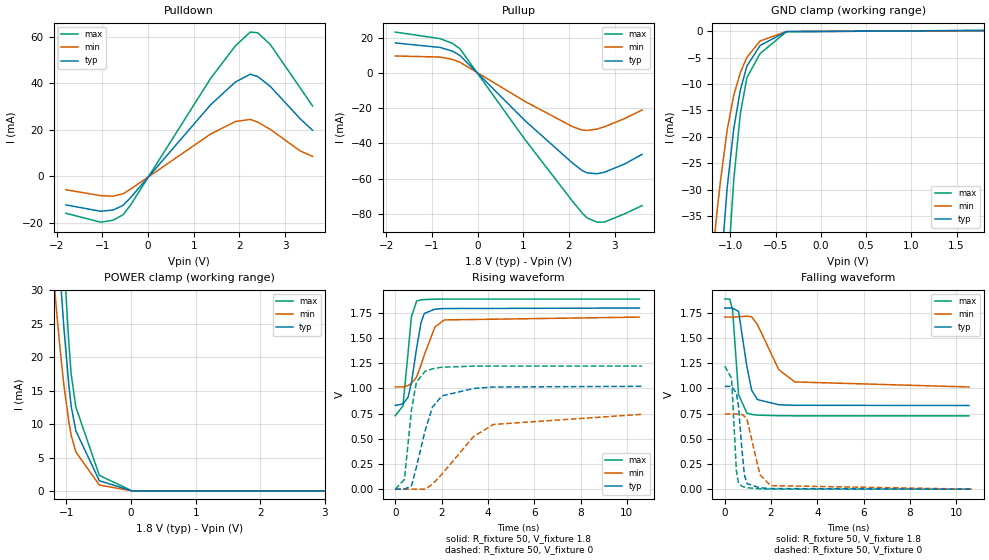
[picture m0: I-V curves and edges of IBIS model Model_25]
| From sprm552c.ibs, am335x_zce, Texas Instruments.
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| Model based on original model for BC1833DV50BPBFBP18LL_SSDHV
|   Sub model BC50B_V_PD_ON_5P_1P8
[model]   Model_25
|[Description]  [1.8V-I/O-PD-NORMAL, IND, 5%]
|   NORMAL,Weak internal pull-down,Industrial temperature range
|   (-40C to 125C, 25C nominal),5% power supply tolerance
|[Input Load]   PD
|[Output Drive] NORMAL
|Voltage   1.8V
|Mode   I/O
Model_type   I/O
Polarity   Non-Inverting
Enable   Active-Low
Vinl =  0.63
Vinh =  1.17
Cref =  15pF
Rref =  100.0000M
Vref =  0V
Vmeas =  0.9
C_comp   2.005358p   1.984241p   2.061175p
[Model Spec]
Vinl   0.63   0.5985   0.6615
Vinh   1.17   1.1115   1.2285
[Temperature Range]   25   125   -40
[Voltage Range]   1.8   1.71   1.89
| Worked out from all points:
|   slope of the pulldown table from 0 to 0.27 V, typ, clamps not added: 42.1 ohm
|   slope of the pullup table from 0 to 0.27 V, typ, clamps not added: 37.7 ohm
|   GND clamp passes 1 mA (typ) near -0.56 V on its own axis
|   POWER clamp passes 1 mA (typ) near -0.44 V on its own axis
|   rising waveform, R_fixture 50, V_fixture 1.8: 20-80 % time 395ps typ, 627ps min, 258ps max; typ from 0.832 V to 1.8 V
|   rising waveform, R_fixture 50, V_fixture 0: 20-80 % time 713ps typ, 1.77ns min, 337ps max; typ from 0 V to 1.02 V
|   falling waveform, R_fixture 50, V_fixture 1.8: 20-80 % time 386ps typ, 902ps min, 196ps max; typ from 1.8 V to 0.831 V
|   falling waveform, R_fixture 50, V_fixture 0: 20-80 % time 219ps typ, 405ps min, 146ps max; typ from 1.02 V to 0 V
[POWER_clamp]
-1.8V     154.2mA    109.7mA    213.5mA
-1.255V   57.34mA    38.41mA    81.27mA
-1.145V   39.68mA    26.05mA    56.64mA
-1.109V   34.21mA    22.34mA    48.88mA
-1.073V   28.97mA    18.84mA    41.38mA
-1.036V   23.97mA    15.54mA    34.15mA
-963.6mV  15.93mA    10.41mA    22.28mA
-927.3mV  12.7mA     8.361mA    17.51mA
-854.5mV  8.993mA    5.831mA    12.55mA
-490.9mV  1.518mA    881.5uA    2.323mA
18.18mV   0A         0A         0A
3.6V      0A         0A         0A
[Pulldown]
-1.8V     -12.34mA   -5.814mA   -15.95mA
-1.036V   -15.1mA    -8.371mA   -19.79mA
-763.6mV  -14.53mA   -8.588mA   -18.92mA
-545.5mV  -12.52mA   -7.542mA   -16.54mA
-381.8mV  -9.184mA   -5.536mA   -12.37mA
1.364V    30.65mA    18.1mA     41.95mA
1.909V    40.55mA    23.56mA    56.09mA
2.236V    43.94mA    24.46mA    62.06mA
2.4V      42.91mA    23.3mA     61.77mA
2.673V    38.72mA    20.2mA     56.76mA
3.327V    24.78mA    10.92mA    38.1mA
3.6V      19.79mA    8.54mA     30.25mA
[Pullup]
-1.8V     16.98mA    9.596mA    23.14mA
-818.2mV  14.42mA    8.972mA    19.42mA
-545.5mV  12.31mA    7.608mA    16.73mA
-381.8mV  9.817mA    6mA        13.58mA
1.036V    -27.01mA   -16.12mA   -37.74mA
2.073V    -50.99mA   -30.42mA   -72.57mA
2.291V    -55.4mA    -32.43mA   -79.49mA
2.4V      -56.69mA   -32.64mA   -82.28mA
2.618V    -57.2mA    -31.85mA   -84.68mA
2.782V    -56.31mA   -30.51mA   -84.57mA
3.218V    -51.71mA   -25.94mA   -79.96mA
3.6V      -46.22mA   -21.01mA   -75.3mA
[GND_clamp]
-1.8V     -258.3mA   -163.5mA   -409.7mA
-1.255V   -85.36mA   -52.4mA    -138.2mA
-1.218V   -74.87mA   -45.89mA   -121.3mA
-1.145V   -54.71mA   -33.55mA   -88.64mA
-1.109V   -45.65mA   -28.13mA   -73.71mA
-1.036V   -29.56mA   -18.62mA   -47.04mA
-963.6mV  -18.42mA   -12.15mA   -28.08mA
-890.9mV  -11.14mA   -7.842mA   -15.61mA
-818.2mV  -6.603mA   -4.95mA    -8.797mA
-672.7mV  -2.723mA   -1.864mA   -4.246mA
-381.8mV  -91.28uA   -77.78uA   -131.6uA
1.8V      101.9uA    59.08uA    150.8uA
[Ramp]
dV/dt_f 0.58661569/0.38804052n 0.42291055/0.91015207n 0.70087579/0.19761426n
dV/dt_r  0.6165227/0.71500223n 0.45171033/1.7983811n  0.7377871/0.33786098n
R_load = 50
[Rising Waveform]
R_fixture = 50
V_fixture = 1.8
V_fixture_min = 1.71
V_fixture_max = 1.89
0s        831.8mV    1.015V     729.1mV
329.1ps   845.7mV    1.015V     825.6mV
549.9ps   911.3mV    1.028V     1.35V
693.1ps   1.051V     1.049V     1.709V
918.4ps   1.397V     1.113V     1.867V
1.114ns   1.655V     1.233V     1.879V
1.252ns   1.744V     1.333V     1.882V
1.715ns   1.787V     1.611V     1.886V
2.116ns   1.793V     1.68V      1.887V
10.54ns   1.798V     1.708V     1.887V
[Rising Waveform]
R_fixture = 50
V_fixture = 0
V_fixture_min = 0
V_fixture_max = 0
0s        0V         0V         0V
393.3ps   0V         0V         96.87mV
700.1ps   34.49mV    0V         787.8mV
911.9ps   219.3mV    0V         1.064V
1.286ns   579.4mV    0V         1.17V
1.604ns   814mV      49.06mV    1.195V
2.013ns   926.1mV    149mV      1.211V
3.375ns   999.3mV    521.4mV    1.221V
4.229ns   1.014V     642.5mV    1.222V
10.65ns   1.021V     743mV      1.222V
[Falling Waveform]
R_fixture = 50
V_fixture = 1.8
V_fixture_min = 1.71
V_fixture_max = 1.89
0s        1.798V     1.709V     1.888V
215.8ps   1.798V     1.709V     1.888V
339.2ps   1.798V     1.709V     1.781V
597.2ps   1.765V     1.711V     939.9mV
955ps     1.219V     1.719V     756.3mV
1.159ns   984.5mV    1.712V     742.4mV
1.41ns    890mV      1.636V     735.5mV
2.332ns   838.2mV    1.187V     729.6mV
3.023ns   833.1mV    1.065V     728.5mV
10.54ns   830.9mV    1.015V     728.2mV
[Falling Waveform]
R_fixture = 50
V_fixture = 0
V_fixture_min = 0
V_fixture_max = 0
0s        1.021V     746.2mV    1.222V
296.1ps   1.021V     746.2mV    1.1V
502.9ps   954.9mV    746.2mV    183.6mV
592.6ps   825.1mV    746.2mV    62.68mV
743.2ps   391.4mV    740.8mV    29.14mV
848.4ps   140.6mV    724.6mV    20.23mV
964.9ps   54.51mV    689.3mV    14.64mV
1.518ns   13.33mV    144.2mV    2.753mV
1.984ns   6.194mV    35.12mV    0V
10.65ns   0V         0V         0V
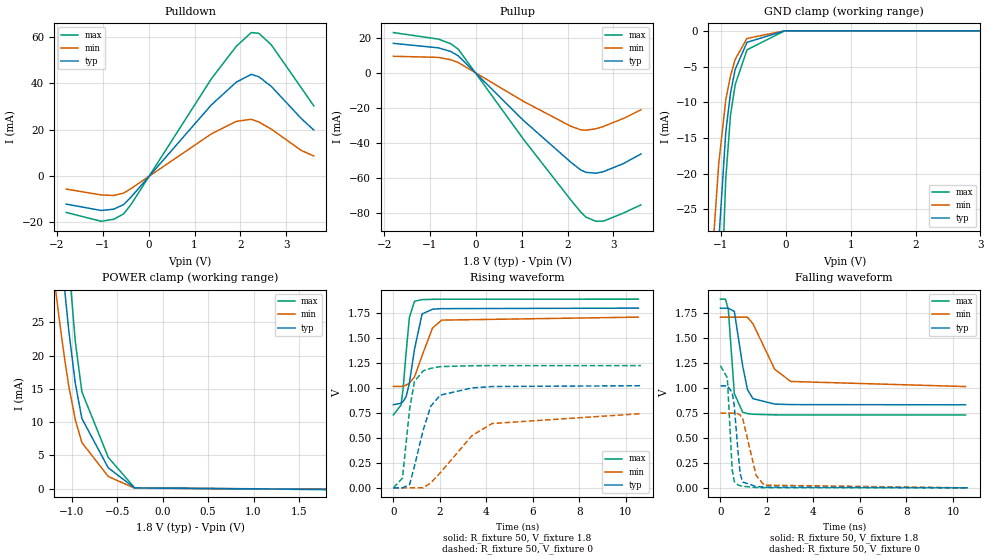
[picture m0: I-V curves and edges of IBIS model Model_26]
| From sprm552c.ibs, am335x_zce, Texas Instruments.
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| Model based on original model for BC1833DV50BPBFBP18LL_SSDHV
|   Sub model BC50B_V_PU_ON_5P_1P8
[model]   Model_26
|[Description]  [1.8V-I/O-PU-NORMAL, IND, 5%]
|   NORMAL,Weak internal pull-up,Industrial temperature range (-40C
|   to 125C, 25C nominal),5% power supply tolerance
|[Input Load]   PU
|[Output Drive] NORMAL
|Voltage   1.8V
|Mode   I/O
Model_type   I/O
Polarity   Non-Inverting
Enable   Active-Low
Vinl =  0.63
Vinh =  1.17
Cref =  15pF
Rref =  100.0000M
Vref =  0V
Vmeas =  0.9
C_comp   2.005358p   1.984241p   2.061175p
[Model Spec]
Vinl   0.63   0.5985   0.6615
Vinh   1.17   1.1115   1.2285
[Temperature Range]   25   125   -40
[Voltage Range]   1.8   1.71   1.89
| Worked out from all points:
|   slope of the pulldown table from 0 to 0.27 V, typ, clamps not added: 42.1 ohm
|   slope of the pullup table from 0 to 0.27 V, typ, clamps not added: 37.7 ohm
|   GND clamp passes 1 mA (typ) near -0.55 V on its own axis
|   POWER clamp passes 1 mA (typ) near -0.45 V on its own axis
|   rising waveform, R_fixture 50, V_fixture 1.8: 20-80 % time 395ps typ, 626ps min, 258ps max; typ from 0.834 V to 1.8 V
|   rising waveform, R_fixture 50, V_fixture 0: 20-80 % time 712ps typ, 1.77ns min, 336ps max; typ from 0.003 V to 1.02 V
|   falling waveform, R_fixture 50, V_fixture 1.8: 20-80 % time 386ps typ, 901ps min, 197ps max; typ from 1.8 V to 0.833 V
|   falling waveform, R_fixture 50, V_fixture 0: 20-80 % time 219ps typ, 395ps min, 146ps max; typ from 1.02 V to 0.002 V
[POWER_clamp]
-1.8V     154.2mA    109.7mA    213.4mA
-1.255V   57.27mA    38.37mA    81.14mA
-1.218V   51.28mA    34.14mA    72.81mA
-1.145V   39.6mA     26.02mA    56.5mA
-1.109V   34.13mA    22.3mA     48.74mA
-1.073V   28.89mA    18.8mA     41.24mA
-1.036V   23.89mA    15.5mA     34.01mA
-963.6mV  15.85mA    10.37mA    22.14mA
-890.9mV  10.56mA    6.932mA    14.57mA
-600mV    3.124mA    1.833mA    4.694mA
-309.1mV  105.7uA    71.68uA    124.2uA
1.8V      -99.94uA   -59.13uA   -145.1uA
[Pulldown]
-1.8V     -12.34mA   -5.814mA   -15.95mA
-1.036V   -15.1mA    -8.371mA   -19.79mA
-763.6mV  -14.53mA   -8.588mA   -18.92mA
-545.5mV  -12.52mA   -7.542mA   -16.54mA
-381.8mV  -9.184mA   -5.536mA   -12.37mA
1.364V    30.65mA    18.1mA     41.96mA
1.909V    40.55mA    23.56mA    56.09mA
2.236V    43.94mA    24.46mA    62.06mA
2.4V      42.91mA    23.3mA     61.77mA
2.673V    38.72mA    20.2mA     56.76mA
3.327V    24.78mA    10.92mA    38.1mA
3.6V      19.79mA    8.54mA     30.25mA
[Pullup]
-1.8V     16.98mA    9.596mA    23.14mA
-818.2mV  14.42mA    8.972mA    19.42mA
-545.5mV  12.31mA    7.608mA    16.73mA
-381.8mV  9.818mA    6mA        13.58mA
1.036V    -27.01mA   -16.12mA   -37.74mA
2.073V    -50.99mA   -30.42mA   -72.57mA
2.291V    -55.4mA    -32.43mA   -79.49mA
2.4V      -56.69mA   -32.64mA   -82.28mA
2.618V    -57.2mA    -31.85mA   -84.68mA
2.782V    -56.32mA   -30.51mA   -84.57mA
3.218V    -51.71mA   -25.94mA   -79.96mA
3.6V      -46.22mA   -21.01mA   -75.3mA
[GND_clamp]
-1.8V     -258.3mA   -163.5mA   -409.7mA
-1.255V   -85.38mA   -52.41mA   -138.2mA
-1.218V   -74.89mA   -45.91mA   -121.4mA
-1.145V   -54.74mA   -33.56mA   -88.68mA
-1.109V   -45.68mA   -28.15mA   -73.77mA
-1.036V   -29.6mA    -18.64mA   -47.12mA
-927.3mV  -14.18mA   -9.665mA   -20.7mA
-854.5mV  -8.721mA   -6.319mA   -11.82mA
-781.8mV  -5.401mA   -3.998mA   -7.533mA
-600mV    -1.607mA   -1.064mA   -2.664mA
-18.18mV  0A         0A         0A
3.6V      0A         0A         0A
[Ramp]
dV/dt_f 0.58648027/0.38861835n 0.42281124/0.91065008n 0.70069145/0.19805751n
dV/dt_r 0.61648384/0.71429874n 0.45165558/1.7976721n 0.73771723/0.33721891n
R_load = 50
[Rising Waveform]
R_fixture = 50
V_fixture = 1.8
V_fixture_min = 1.71
V_fixture_max = 1.89
0s        834.2mV    1.017V     732.2mV
329.1ps   848.3mV    1.017V     829.1mV
413ps     863.8mV    1.018V     977.4mV
548.7ps   913.6mV    1.03V      1.351V
689.9ps   1.05V      1.05V      1.707V
910.9ps   1.389V     1.112V     1.869V
1.237ns   1.742V     1.325V     1.885V
1.685ns   1.789V     1.601V     1.888V
2.079ns   1.795V     1.68V      1.889V
10.54ns   1.8V       1.71V      1.89V
[Rising Waveform]
R_fixture = 50
V_fixture = 0
V_fixture_min = 0
V_fixture_max = 0
0s        2.767mV    2.62mV     3.366mV
393.3ps   2.767mV    2.62mV     100.2mV
699.8ps   37.11mV    2.62mV     791.6mV
907.8ps   218.6mV    2.62mV     1.065V
1.281ns   578.4mV    2.662mV    1.173V
1.61ns    820mV      52.76mV    1.198V
2.021ns   930.1mV    153.8mV    1.215V
3.39ns    1.002V     526.9mV    1.224V
4.245ns   1.016V     645.7mV    1.225V
10.65ns   1.024V     744.6mV    1.225V
[Falling Waveform]
R_fixture = 50
V_fixture = 1.8
V_fixture_min = 1.71
V_fixture_max = 1.89
0s        1.8V       1.71V      1.891V
215.8ps   1.8V       1.71V      1.891V
339.2ps   1.8V       1.71V      1.784V
596.9ps   1.768V     1.71V      945mV
954.3ps   1.224V     1.71V      759.5mV
1.16ns    986.7mV    1.71V      745.4mV
1.398ns   894.9mV    1.645V     738.7mV
2.33ns    840.7mV    1.19V      732.7mV
3.019ns   835.5mV    1.067V     731.6mV
10.54ns   833.3mV    1.016V     731.3mV
[Falling Waveform]
R_fixture = 50
V_fixture = 0
V_fixture_min = 0
V_fixture_max = 0
0s        1.023V     749.7mV    1.224V
296.1ps   1.023V     749.7mV    1.103V
503.8ps   956.7mV    749.7mV    184.4mV
593.4ps   826.1mV    749.7mV    65.49mV
745ps     389.8mV    745.1mV    31.92mV
848.9ps   143mV      729.1mV    23.11mV
954.2ps   60.62mV    698.3mV    17.93mV
1.533ns   15.32mV    127.9mV    5.479mV
1.876ns   10.03mV    29.18mV    3.788mV
10.65ns   2.268mV    2.044mV    2.885mV
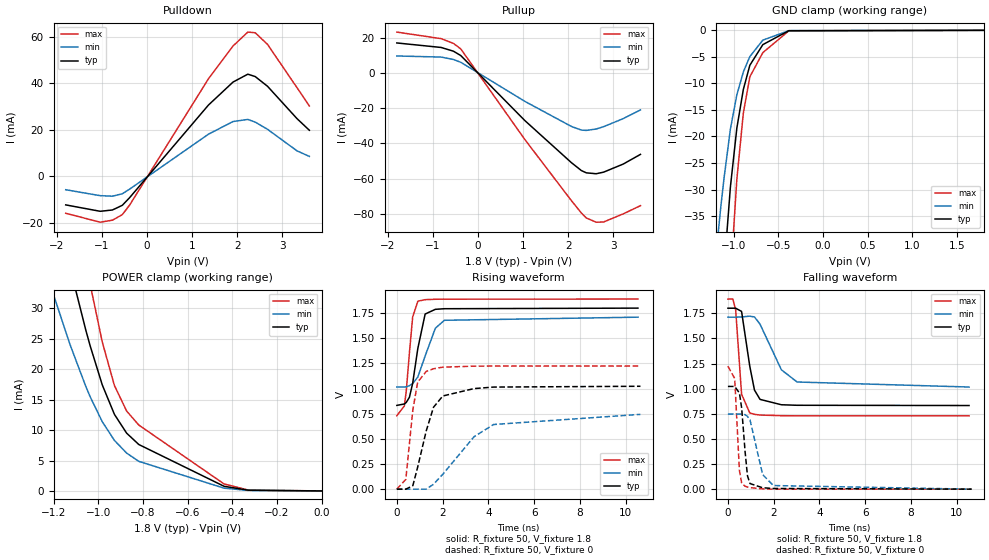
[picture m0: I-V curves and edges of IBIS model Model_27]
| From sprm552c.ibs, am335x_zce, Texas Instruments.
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| Model based on original model for BC1833DV50BPBFBP18LL_SSDHV
|   Sub model BC50B_V_PUPDOFF_5P_1P8
[model]   Model_27
|[Description]  [1.8V-I/O-PI-NORMAL, IND, 5%]
|   NORMAL,Weak pull up/down disabled,Industrial temperature range
|   (-40C to 125C, 25C nominal),5% power supply tolerance
|[Input Load]   PI
|[Output Drive] NORMAL
|Voltage   1.8V
|Mode   I/O
Model_type   I/O
Polarity   Non-Inverting
Enable   Active-Low
Vinl =  0.63
Vinh =  1.17
Cref =  15pF
Rref =  100.0000M
Vref =  0V
Vmeas =  0.9
C_comp   2.005358p   1.984241p   2.061175p
[Model Spec]
Vinl   0.63   0.5985   0.6615
Vinh   1.17   1.1115   1.2285
[Temperature Range]   25   125   -40
[Voltage Range]   1.8   1.71   1.89
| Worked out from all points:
|   slope of the pulldown table from 0 to 0.27 V, typ, clamps not added: 42.1 ohm
|   slope of the pullup table from 0 to 0.27 V, typ, clamps not added: 37.7 ohm
|   GND clamp passes 1 mA (typ) near -0.56 V on its own axis
|   POWER clamp passes 1 mA (typ) near -0.46 V on its own axis
|   rising waveform, R_fixture 50, V_fixture 1.8: 20-80 % time 396ps typ, 627ps min, 258ps max; typ from 0.833 V to 1.8 V
|   rising waveform, R_fixture 50, V_fixture 0: 20-80 % time 714ps typ, 1.77ns min, 337ps max; typ from 0 V to 1.02 V
|   falling waveform, R_fixture 50, V_fixture 1.8: 20-80 % time 387ps typ, 903ps min, 197ps max; typ from 1.8 V to 0.832 V
|   falling waveform, R_fixture 50, V_fixture 0: 20-80 % time 219ps typ, 406ps min, 146ps max; typ from 1.02 V to 0 V
[POWER_clamp]
-1.8V     154.2mA    109.6mA    213.3mA
-1.236V   54.24mA    36.24mA    76.93mA
-1.127V   36.83mA    24.14mA    52.57mA
-1.055V   26.36mA    17.13mA    37.58mA
-1.036V   23.85mA    15.48mA    33.96mA
-981.8mV  17.43mA    11.38mA    24.48mA
-927.3mV  12.58mA    8.299mA    17.32mA
-872.7mV  9.497mA    6.221mA    13.13mA
-818.2mV  7.629mA    4.86mA     10.83mA
-436.4mV  761.6uA    453.7uA    1.147mA
-327.3mV  115.1uA    79.02uA    133.5uA
0V        19.19nA    133nA      229.6nA
[Pulldown]
-1.8V     -12.34mA   -5.814mA   -15.95mA
-1.036V   -15.1mA    -8.371mA   -19.79mA
-763.6mV  -14.53mA   -8.588mA   -18.92mA
-545.5mV  -12.52mA   -7.542mA   -16.54mA
-381.8mV  -9.184mA   -5.536mA   -12.37mA
1.364V    30.65mA    18.1mA     41.96mA
1.909V    40.55mA    23.56mA    56.09mA
2.236V    43.94mA    24.46mA    62.06mA
2.4V      42.91mA    23.3mA     61.77mA
2.673V    38.72mA    20.2mA     56.76mA
3.327V    24.78mA    10.92mA    38.1mA
3.6V      19.79mA    8.54mA     30.25mA
[Pullup]
-1.8V     16.98mA    9.596mA    23.14mA
-818.2mV  14.42mA    8.972mA    19.42mA
-545.5mV  12.31mA    7.608mA    16.73mA
-381.8mV  9.818mA    6mA        13.58mA
1.036V    -27.01mA   -16.12mA   -37.74mA
2.073V    -50.99mA   -30.42mA   -72.58mA
2.291V    -55.4mA    -32.43mA   -79.49mA
2.4V      -56.69mA   -32.63mA   -82.28mA
2.618V    -57.2mA    -31.85mA   -84.68mA
2.782V    -56.31mA   -30.51mA   -84.57mA
3.218V    -51.71mA   -25.94mA   -79.96mA
3.6V      -46.22mA   -21.01mA   -75.3mA
[GND_clamp]
-1.8V     -258.3mA   -163.5mA   -409.7mA
-1.255V   -85.35mA   -52.4mA    -138.2mA
-1.218V   -74.87mA   -45.89mA   -121.3mA
-1.145V   -54.71mA   -33.55mA   -88.63mA
-1.109V   -45.64mA   -28.13mA   -73.71mA
-1.036V   -29.55mA   -18.62mA   -47.03mA
-963.6mV  -18.42mA   -12.14mA   -28.07mA
-890.9mV  -11.13mA   -7.836mA   -15.58mA
-818.2mV  -6.581mA   -4.941mA   -8.76mA
-672.7mV  -2.695mA   -1.849mA   -4.206mA
-381.8mV  -68.52uA   -64.5uA    -99.4uA
1.8V      19.19nA    313.7nA    215.2nA
[Ramp]
dV/dt_f 0.58726163/0.38922827n 0.42325164/0.9115308n 0.70180492/0.19847768n
dV/dt_r 0.61731887/0.71592513n 0.45216623/1.8000264n 0.73890303/0.3384294n
R_load = 50
[Rising Waveform]
R_fixture = 50
V_fixture = 1.8
V_fixture_min = 1.71
V_fixture_max = 1.89
0s        832.9mV    1.016V     730.4mV
329.1ps   846.9mV    1.016V     827mV
413ps     862.4mV    1.017V     975mV
550.6ps   913.1mV    1.029V     1.354V
693.3ps   1.053V     1.05V      1.712V
918.4ps   1.399V     1.115V     1.869V
1.238ns   1.741V     1.324V     1.884V
1.685ns   1.788V     1.6V       1.888V
2.079ns   1.794V     1.679V     1.889V
10.54ns   1.8V       1.71V      1.89V
[Rising Waveform]
R_fixture = 50
V_fixture = 0
V_fixture_min = 0
V_fixture_max = 0
0s        0V         0V         0V
393.3ps   0V         0V         96.88mV
700.1ps   34.49mV    0V         788.2mV
911.7ps   219.2mV    0V         1.064V
1.285ns   578.6mV    0V         1.171V
1.604ns   814.4mV    49mV       1.197V
2.011ns   926.6mV    148.6mV    1.213V
3.375ns   1V         521.6mV    1.223V
4.229ns   1.015V     642.9mV    1.224V
10.65ns   1.023V     743.7mV    1.224V
[Falling Waveform]
R_fixture = 50
V_fixture = 1.8
V_fixture_min = 1.71
V_fixture_max = 1.89
0s        1.8V       1.711V     1.891V
215.8ps   1.8V       1.711V     1.891V
339.2ps   1.8V       1.711V     1.784V
596.9ps   1.768V     1.713V     944.6mV
954.3ps   1.224V     1.721V     758.5mV
1.16ns    986.3mV    1.713V     744.2mV
1.404ns   893.1mV    1.641V     737.2mV
2.335ns   839.7mV    1.188V     730.9mV
3.023ns   834.5mV    1.066V     729.7mV
10.54ns   832mV      1.016V     729.5mV
[Falling Waveform]
R_fixture = 50
V_fixture = 0
V_fixture_min = 0
V_fixture_max = 0
0s        1.022V     747mV      1.223V
296.1ps   1.022V     747mV      1.102V
502.9ps   956.3mV    747mV      185.6mV
601.3ps   806.3mV    747mV      60.63mV
748.2ps   378.9mV    741.1mV    29.71mV
854.1ps   133.7mV    724.2mV    20.81mV
964.5ps   55.81mV    690.3mV    15.42mV
1.518ns   13.98mV    145.4mV    3.052mV
1.983ns   6.703mV    36.01mV    0V
10.65ns   0V         0V         0V
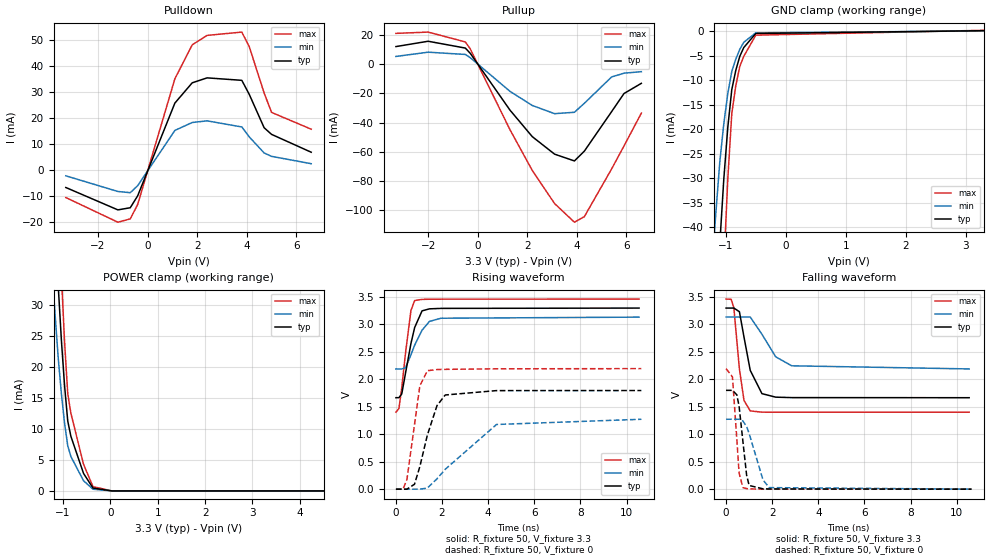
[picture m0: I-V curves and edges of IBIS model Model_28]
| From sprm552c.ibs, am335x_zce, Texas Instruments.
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| Model based on original model for BC1833DV50BPBFBP18LL_SSDHV
|   Sub model BC50B_V_PD_ON_5P_3P3
[model]   Model_28
|[Description]  [3.3V-I/O-PD-NORMAL, IND, 5%]
|   NORMAL,Weak internal pull-down,Industrial temperature range
|   (-40C to 125C, 25C nominal),5% power supply tolerance
|[Input Load]   PD
|[Output Drive] NORMAL
|Voltage   3.3V
|Mode   I/O
Model_type   I/O
Polarity   Non-Inverting
Enable   Active-Low
Vinl =  0.8V
Vinh =  2V
Cref =  15pF
Rref =  100.0000M
Vref =  0V
Vmeas =  1.65
C_comp   1.841028p   1.649962p   1.857641p
[Model Spec]
Vinl   0.8V   0.8V   0.8V
Vinh   2V   2V   2V
[Temperature Range]   25   125   -40
[Voltage Range]   3.3   3.135   3.465
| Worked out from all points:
|   slope of the pulldown table from 0 to 0.495 V, typ, clamps not added: 41.2 ohm
|   slope of the pullup table from 0 to 0.495 V, typ, clamps not added: 40 ohm
|   GND clamp passes 1 mA (typ) near -0.55 V on its own axis
|   POWER clamp passes 1 mA (typ) near -0.44 V on its own axis
|   rising waveform, R_fixture 50, V_fixture 3.3: 20-80 % time 461ps typ, 618ps min, 342ps max; typ from 1.67 V to 3.3 V
|   rising waveform, R_fixture 50, V_fixture 0: 20-80 % time 691ps typ, 1.76ns min, 392ps max; typ from 0 V to 1.8 V
|   falling waveform, R_fixture 50, V_fixture 3.3: 20-80 % time 462ps typ, 810ps min, 276ps max; typ from 3.3 V to 1.67 V
|   falling waveform, R_fixture 50, V_fixture 0: 20-80 % time 273ps typ, 532ps min, 196ps max; typ from 1.8 V to 0 V
[POWER_clamp]
-3.3V     437.1mA    430.8mA    590.9mA
-1.233V   54mA       35.95mA    76.74mA
-1.167V   43.32mA    28.48mA    61.85mA
-1.1V     33.01mA    21.39mA    47.35mA
-1.033V   24.22mA    15.63mA    34.6mA
-966.7mV  16.98mA    10.93mA    24.05mA
-900mV    11.29mA    7.299mA    15.71mA
-833.3mV  8.816mA    5.551mA    12.53mA
-566.7mV  2.833mA    1.651mA    4.306mA
-366.7mV  458.2uA    275.4uA    687.8uA
33.33mV   0A         0A         0A
6.6V      0A         0A         0A
[Pulldown]
-3.3V     -6.622mA   -2.126mA   -10.49mA
-1.2V     -15.24mA   -8.16mA    -19.98mA
-700mV    -14.42mA   -8.625mA   -18.71mA
-400mV    -9.821mA   -5.925mA   -13.15mA
1.1V      25.87mA    15.35mA    35.22mA
1.8V      33.67mA    18.39mA    48.29mA
2.4V      35.57mA    19.03mA    51.92mA
3.8V      34.62mA    16.67mA    53.19mA
4.1V      29.22mA    12.85mA    47.57mA
4.7V      16.38mA    6.671mA    29.75mA
5V        13.82mA    5.359mA    22.28mA
6.6V      6.944mA    2.531mA    15.81mA
[Pullup]
-3.3V     12.22mA    5.435mA    21.29mA
-2V       15.88mA    8.364mA    22.18mA
-500mV    11.19mA    6.809mA    15.42mA
-300mV    7.546mA    4.55mA     10.58mA
1.3V      -31.44mA   -18.55mA   -44.91mA
2.2V      -49.69mA   -28.25mA   -72.91mA
3.1V      -61.73mA   -33.9mA    -95.7mA
3.9V      -66.39mA   -32.95mA   -108.5mA
4.3V      -59.67mA   -26.77mA   -104.7mA
5.4V      -32.51mA   -8.662mA   -71.91mA
5.9V      -20.05mA   -6.072mA   -56.09mA
6.6V      -13.04mA   -5.016mA   -33.52mA
[GND_clamp]
-3.3V     -759.3mA   -612.7mA   -1.187A
-1.233V   -79.58mA   -48.75mA   -128.9mA
-1.167V   -61.06mA   -37.35mA   -98.95mA
-1.1V     -43.51mA   -26.72mA   -70.29mA
-1.033V   -30.2mA    -18.91mA   -48.08mA
-966.7mV  -19.68mA   -12.74mA   -30.27mA
-900mV    -11.93mA   -8.219mA   -16.86mA
-833.3mV  -8mA       -5.694mA   -11.13mA
-766.7mV  -5.133mA   -3.707mA   -7.22mA
-700mV    -3.33mA    -2.257mA   -5.131mA
-500mV    -463.9uA   -330.7uA   -807.4uA
3.3V      108.6uA    60.34uA    188uA
[Ramp]
dV/dt_f  0.9827697/0.46300896n  0.5700889/0.81423835n  1.2394706/0.2764349n
dV/dt_r  1.0808784/0.69221329n 0.76688601/1.7669954n  1.3212386/0.3933506n
R_load = 50
[Rising Waveform]
R_fixture = 50
V_fixture = 3.3
V_fixture_min = 3.135
V_fixture_max = 3.465
0s        1.666V     2.189V     1.402V
131.1ps   1.666V     2.189V     1.471V
252.3ps   1.733V     2.189V     1.845V
418.6ps   2.119V     2.213V     2.489V
652.8ps   2.656V     2.45V      3.258V
812.1ps   2.944V     2.622V     3.436V
1.132ns   3.247V     2.895V     3.456V
1.454ns   3.284V     3.055V     3.459V
1.95ns    3.292V     3.113V     3.46V
10.54ns   3.298V     3.133V     3.462V
[Rising Waveform]
R_fixture = 50
V_fixture = 0
V_fixture_min = 0
V_fixture_max = 0
0s        0V         0V         0V
306.4ps   0V         0V         0V
475.9ps   0V         0V         174.6mV
805.5ps   89.41mV    0V         1.174V
1.036ns   409.6mV    0V         1.88V
1.362ns   983.7mV    19.95mV    2.157V
1.781ns   1.522V     188.9mV    2.179V
2.137ns   1.715V     362mV      2.182V
4.361ns   1.795V     1.178V     2.192V
10.64ns   1.796V     1.273V     2.195V
[Falling Waveform]
R_fixture = 50
V_fixture = 3.3
V_fixture_min = 3.135
V_fixture_max = 3.465
0s        3.297V     3.134V     3.461V
221.2ps   3.297V     3.134V     3.457V
337.9ps   3.297V     3.134V     3.303V
579.4ps   3.231V     3.134V     2.19V
777.3ps   2.771V     3.134V     1.617V
1.049ns   2.163V     3.134V     1.425V
1.556ns   1.739V     2.82V      1.402V
2.154ns   1.675V     2.409V     1.401V
2.847ns   1.667V     2.246V     1.401V
10.54ns   1.665V     2.189V     1.401V
[Falling Waveform]
R_fixture = 50
V_fixture = 0
V_fixture_min = 0
V_fixture_max = 0
0s        1.799V     1.273V     2.195V
278ps     1.799V     1.273V     2.043V
467ps     1.718V     1.273V     910mV
565.7ps   1.51V      1.273V     291.3mV
733.4ps   858.8mV    1.239V     27.32mV
892ps     253.5mV    1.141V     9.691mV
1.001ns   67.36mV    1.014V     5.057mV
1.601ns   6.327mV    168.9mV    0V
1.871ns   4.231mV    28.19mV    0V
10.64ns   0V         0V         0V
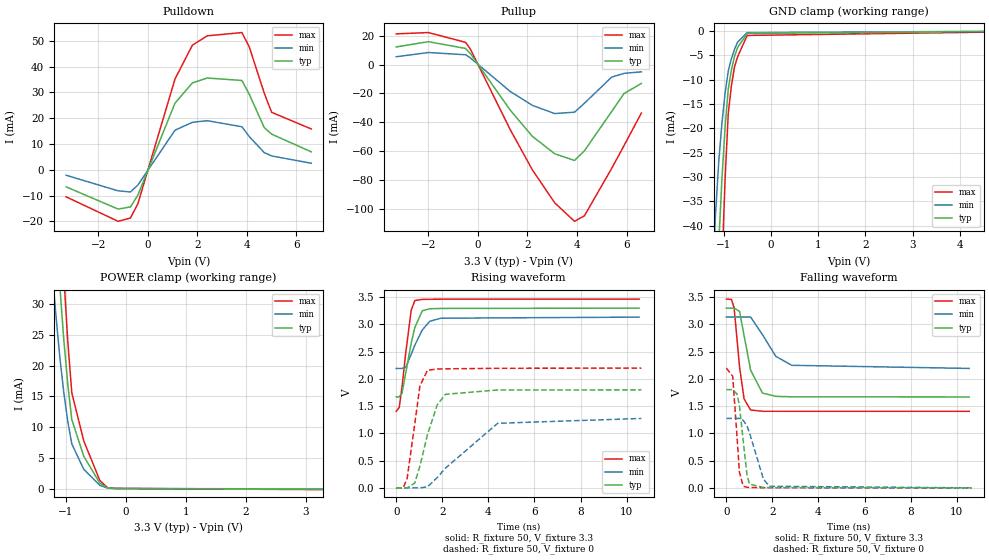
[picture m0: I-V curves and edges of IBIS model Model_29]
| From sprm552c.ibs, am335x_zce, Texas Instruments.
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| Model based on original model for BC1833DV50BPBFBP18LL_SSDHV
|   Sub model BC50B_V_PU_ON_5P_3P3
[model]   Model_29
|[Description]  [3.3V-I/O-PU-NORMAL, IND, 5%]
|   NORMAL,Weak internal pull-up,Industrial temperature range (-40C
|   to 125C, 25C nominal),5% power supply tolerance
|[Input Load]   PU
|[Output Drive] NORMAL
|Voltage   3.3V
|Mode   I/O
Model_type   I/O
Polarity   Non-Inverting
Enable   Active-Low
Vinl =  0.8V
Vinh =  2V
Cref =  15pF
Rref =  100.0000M
Vref =  0V
Vmeas =  1.65
C_comp   1.841028p   1.649962p   1.857641p
[Model Spec]
Vinl   0.8V   0.8V   0.8V
Vinh   2V   2V   2V
[Temperature Range]   25   125   -40
[Voltage Range]   3.3   3.135   3.465
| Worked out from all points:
|   slope of the pulldown table from 0 to 0.495 V, typ, clamps not added: 41.2 ohm
|   slope of the pullup table from 0 to 0.495 V, typ, clamps not added: 40 ohm
|   GND clamp passes 1 mA (typ) near -0.54 V on its own axis
|   POWER clamp passes 1 mA (typ) near -0.44 V on its own axis
|   rising waveform, R_fixture 50, V_fixture 3.3: 20-80 % time 460ps typ, 616ps min, 341ps max; typ from 1.67 V to 3.3 V
|   rising waveform, R_fixture 50, V_fixture 0: 20-80 % time 690ps typ, 1.76ns min, 392ps max; typ from 0.003 V to 1.8 V
|   falling waveform, R_fixture 50, V_fixture 3.3: 20-80 % time 463ps typ, 809ps min, 277ps max; typ from 3.3 V to 1.67 V
|   falling waveform, R_fixture 50, V_fixture 0: 20-80 % time 273ps typ, 533ps min, 196ps max; typ from 1.8 V to 0.002 V
[POWER_clamp]
-3.3V     437.1mA    430.8mA    590.9mA
-1.233V   53.96mA    35.93mA    76.64mA
-1.167V   43.27mA    28.46mA    61.75mA
-1.1V     32.96mA    21.36mA    47.25mA
-1.033V   24.17mA    15.61mA    34.49mA
-966.7mV  16.93mA    10.91mA    23.94mA
-900mV    11.23mA    7.269mA    15.59mA
-700mV    5.251mA    3.127mA    7.757mA
-433.3mV  893.2uA    531.5uA    1.34mA
-300mV    89.78uA    61.22uA    102uA
-166.7mV  17.36uA    10.91uA    23.37uA
3.3V      -100.3uA   -54.59uA   -173.1uA
[Pulldown]
-3.3V     -6.622mA   -2.126mA   -10.49mA
-1.2V     -15.24mA   -8.16mA    -19.98mA
-700mV    -14.42mA   -8.625mA   -18.71mA
-400mV    -9.821mA   -5.925mA   -13.15mA
1.1V      25.87mA    15.35mA    35.22mA
1.8V      33.67mA    18.39mA    48.29mA
2.4V      35.57mA    19.03mA    51.92mA
3.8V      34.62mA    16.67mA    53.19mA
4.1V      29.22mA    12.85mA    47.57mA
4.7V      16.38mA    6.671mA    29.75mA
5V        13.82mA    5.359mA    22.28mA
6.6V      6.944mA    2.531mA    15.81mA
[Pullup]
-3.3V     12.22mA    5.435mA    21.29mA
-2V       15.88mA    8.364mA    22.18mA
-500mV    11.19mA    6.809mA    15.42mA
-300mV    7.546mA    4.55mA     10.58mA
1.3V      -31.44mA   -18.55mA   -44.91mA
2.2V      -49.69mA   -28.25mA   -72.91mA
3.1V      -61.73mA   -33.9mA    -95.7mA
3.9V      -66.39mA   -32.95mA   -108.5mA
4.3V      -59.67mA   -26.77mA   -104.7mA
5.4V      -32.51mA   -8.662mA   -71.91mA
5.9V      -20.05mA   -6.072mA   -56.09mA
6.6V      -13.04mA   -5.016mA   -33.52mA
[GND_clamp]
-3.3V     -759.3mA   -612.7mA   -1.187A
-1.233V   -79.59mA   -48.75mA   -128.9mA
-1.167V   -61.07mA   -37.36mA   -98.97mA
-1.1V     -43.52mA   -26.73mA   -70.32mA
-1.033V   -30.22mA   -18.91mA   -48.13mA
-966.7mV  -19.71mA   -12.75mA   -30.35mA
-900mV    -11.97mA   -8.233mA   -16.96mA
-833.3mV  -8.054mA   -5.715mA   -11.24mA
-766.7mV  -5.195mA   -3.734mA   -7.343mA
-700mV    -3.396mA   -2.289mA   -5.259mA
-500mV    -540.4uA   -369.3uA   -948.8uA
6.6V      0A         0A         0A
[Ramp]
dV/dt_f 0.98117427/0.46331286n 0.56886158/0.8127625n  1.2383379/0.27717956n
dV/dt_r  1.0815937/0.69195258n 0.76748483/1.7675069n  1.3217618/0.39318679n
R_load = 50
[Rising Waveform]
R_fixture = 50
V_fixture = 3.3
V_fixture_min = 3.135
V_fixture_max = 3.465
0s        1.671V     2.193V     1.407V
131.1ps   1.671V     2.193V     1.477V
252.3ps   1.739V     2.193V     1.853V
418.1ps   2.124V     2.217V     2.495V
650.7ps   2.658V     2.452V     3.26V
808.3ps   2.945V     2.621V     3.44V
1.128ns   3.25V      2.896V     3.46V
1.453ns   3.288V     3.058V     3.462V
1.938ns   3.294V     3.115V     3.464V
10.54ns   3.3V       3.135V     3.465V
[Rising Waveform]
R_fixture = 50
V_fixture = 0
V_fixture_min = 0
V_fixture_max = 0
0s        2.898mV    2.506mV    3.526mV
306.4ps   2.898mV    2.506mV    3.526mV
475.9ps   2.898mV    2.506mV    178.2mV
801.2ps   88.78mV    2.506mV    1.164V
1.031ns   404.8mV    2.506mV    1.875V
1.354ns   975mV      20.34mV    2.159V
1.782ns   1.527V     191.6mV    2.183V
2.138ns   1.719V     364.8mV    2.186V
4.404ns   1.798V     1.187V     2.196V
10.64ns   1.8V       1.276V     2.2V
[Falling Waveform]
R_fixture = 50
V_fixture = 3.3
V_fixture_min = 3.135
V_fixture_max = 3.465
0s        3.299V     3.136V     3.464V
221.2ps   3.299V     3.136V     3.46V
337.8ps   3.299V     3.136V     3.306V
575ps     3.238V     3.136V     2.215V
771ps     2.793V     3.136V     1.634V
1.053ns   2.162V     3.136V     1.43V
1.568ns   1.741V     2.812V     1.407V
2.149ns   1.68V      2.414V     1.407V
2.84ns    1.672V     2.25V      1.406V
10.54ns   1.67V      2.193V     1.406V
[Falling Waveform]
R_fixture = 50
V_fixture = 0
V_fixture_min = 0
V_fixture_max = 0
0s        1.803V     1.276V     2.199V
278.1ps   1.803V     1.276V     2.048V
465ps     1.724V     1.276V     930.1mV
567.7ps   1.508V     1.276V     288mV
733.9ps   861.6mV    1.241V     31.65mV
893.3ps   254.4mV    1.143V     13.82mV
1.002ns   70.56mV    1.017V     9.121mV
1.605ns   9.234mV    167.8mV    3.92mV
1.865ns   7.106mV    31.25mV    3.612mV
10.64ns   2.247mV    2.033mV    3.273mV
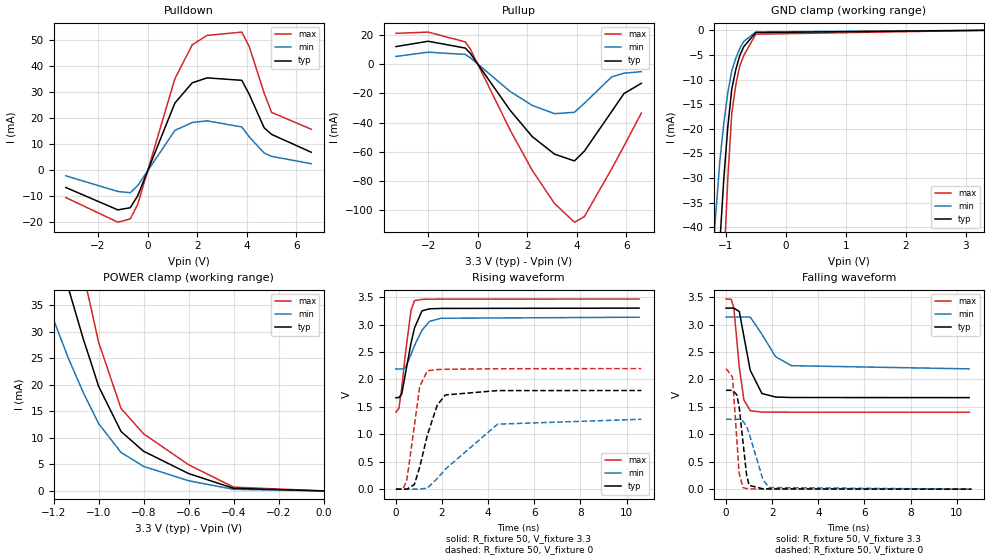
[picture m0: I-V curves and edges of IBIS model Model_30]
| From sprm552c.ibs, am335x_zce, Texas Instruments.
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| Model based on original model for BC1833DV50BPBFBP18LL_SSDHV
|   Sub model BC50B_V_PUPDOFF_5P_3P3
[model]   Model_30
|[Description]  [3.3V-I/O-PI-NORMAL, IND, 5%]
|   NORMAL,Weak pull up/down disabled,Industrial temperature range
|   (-40C to 125C, 25C nominal),5% power supply tolerance
|[Input Load]   PI
|[Output Drive] NORMAL
|Voltage   3.3V
|Mode   I/O
Model_type   I/O
Polarity   Non-Inverting
Enable   Active-Low
Vinl =  0.8V
Vinh =  2V
Cref =  15pF
Rref =  100.0000M
Vref =  0V
Vmeas =  1.65
C_comp   1.841028p   1.649962p   1.857641p
[Model Spec]
Vinl   0.8V   0.8V   0.8V
Vinh   2V   2V   2V
[Temperature Range]   25   125   -40
[Voltage Range]   3.3   3.135   3.465
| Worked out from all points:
|   slope of the pulldown table from 0 to 0.495 V, typ, clamps not added: 41.2 ohm
|   slope of the pullup table from 0 to 0.495 V, typ, clamps not added: 40 ohm
|   GND clamp passes 1 mA (typ) near -0.55 V on its own axis
|   POWER clamp passes 1 mA (typ) near -0.44 V on its own axis
|   rising waveform, R_fixture 50, V_fixture 3.3: 20-80 % time 461ps typ, 617ps min, 342ps max; typ from 1.67 V to 3.3 V
|   rising waveform, R_fixture 50, V_fixture 0: 20-80 % time 692ps typ, 1.76ns min, 392ps max; typ from 0 V to 1.8 V
|   falling waveform, R_fixture 50, V_fixture 3.3: 20-80 % time 463ps typ, 810ps min, 277ps max; typ from 3.3 V to 1.67 V
|   falling waveform, R_fixture 50, V_fixture 0: 20-80 % time 273ps typ, 533ps min, 196ps max; typ from 1.8 V to 0 V
[POWER_clamp]
-3.3V     437.1mA    430.8mA    590.9mA
-1.267V   59.46mA    39.85mA    84.25mA
-1.233V   53.93mA    35.92mA    76.61mA
-1.133V   38.09mA    24.9mA     54.46mA
-1.067V   28.54mA    18.47mA    40.83mA
-1.033V   24.14mA    15.59mA    34.45mA
-1V       19.75mA    12.71mA    28.07mA
-900mV    11.21mA    7.255mA    15.55mA
-800mV    7.487mA    4.63mA     10.78mA
-600mV    3.284mA    1.921mA    4.946mA
-400mV    494.5uA    304.1uA    718.2uA
0V        4.588uA    2.33uA     8.157uA
[Pulldown]
-3.3V     -6.622mA   -2.126mA   -10.49mA
-1.2V     -15.24mA   -8.16mA    -19.98mA
-700mV    -14.42mA   -8.625mA   -18.71mA
-400mV    -9.821mA   -5.925mA   -13.15mA
1.1V      25.87mA    15.35mA    35.22mA
1.8V      33.67mA    18.39mA    48.29mA
2.4V      35.57mA    19.03mA    51.92mA
3.8V      34.62mA    16.67mA    53.19mA
4.1V      29.22mA    12.85mA    47.57mA
4.7V      16.38mA    6.671mA    29.75mA
5V        13.82mA    5.359mA    22.28mA
6.6V      6.944mA    2.531mA    15.81mA
[Pullup]
-3.3V     12.22mA    5.435mA    21.29mA
-2V       15.88mA    8.364mA    22.18mA
-500mV    11.19mA    6.809mA    15.42mA
-300mV    7.546mA    4.55mA     10.58mA
1.3V      -31.44mA   -18.55mA   -44.91mA
2.2V      -49.69mA   -28.25mA   -72.91mA
3.1V      -61.73mA   -33.9mA    -95.7mA
3.9V      -66.39mA   -32.95mA   -108.5mA
4.3V      -59.67mA   -26.77mA   -104.7mA
5.4V      -32.51mA   -8.662mA   -71.91mA
5.9V      -20.05mA   -6.072mA   -56.09mA
6.6V      -13.04mA   -5.016mA   -33.52mA
[GND_clamp]
-3.3V     -759.3mA   -612.7mA   -1.187A
-1.233V   -79.57mA   -48.75mA   -128.9mA
-1.167V   -61.05mA   -37.35mA   -98.94mA
-1.1V     -43.5mA    -26.72mA   -70.28mA
-1.033V   -30.2mA    -18.91mA   -48.08mA
-966.7mV  -19.68mA   -12.74mA   -30.27mA
-900mV    -11.93mA   -8.216mA   -16.85mA
-833.3mV  -7.988mA   -5.69mA    -11.11mA
-766.7mV  -5.117mA   -3.701mA   -7.196mA
-700mV    -3.311mA   -2.248mA   -5.105mA
-500mV    -444.3uA   -319.5uA   -780.8uA
3.3V      4.588uA    4.848uA    6.316uA
[Ramp]
dV/dt_f 0.98264585/0.46419371n 0.56959382/0.81428n   1.2401638/0.27756877n
dV/dt_r  1.0820134/0.69294145n 0.76754947/1.7683231n  1.3228035/0.39374199n
R_load = 50
[Rising Waveform]
R_fixture = 50
V_fixture = 3.3
V_fixture_min = 3.135
V_fixture_max = 3.465
0s        1.668V     2.191V     1.404V
131.1ps   1.668V     2.191V     1.474V
252.3ps   1.736V     2.191V     1.848V
418.4ps   2.122V     2.216V     2.492V
652.2ps   2.658V     2.452V     3.261V
807.6ps   2.941V     2.62V      3.438V
1.131ns   3.25V      2.897V     3.459V
1.454ns   3.287V     3.057V     3.462V
1.948ns   3.294V     3.115V     3.464V
10.54ns   3.3V       3.134V     3.465V
[Rising Waveform]
R_fixture = 50
V_fixture = 0
V_fixture_min = 0
V_fixture_max = 0
0s        0V         0V         0V
306.4ps   0V         0V         0V
475.9ps   0V         0V         174.6mV
801.2ps   86.2mV     0V         1.159V
1.032ns   403.1mV    0V         1.872V
1.363ns   985.8mV    20.16mV    2.158V
1.79ns    1.531V     193.7mV    2.181V
2.142ns   1.717V     364.2mV    2.185V
4.409ns   1.797V     1.185V     2.195V
10.64ns   1.798V     1.274V     2.198V
[Falling Waveform]
R_fixture = 50
V_fixture = 3.3
V_fixture_min = 3.135
V_fixture_max = 3.465
0s        3.299V     3.136V     3.464V
221.2ps   3.299V     3.136V     3.46V
337.8ps   3.299V     3.136V     3.306V
575ps     3.238V     3.136V     2.214V
775.1ps   2.781V     3.136V     1.626V
1.049ns   2.166V     3.136V     1.429V
1.556ns   1.743V     2.822V     1.404V
2.149ns   1.679V     2.413V     1.404V
2.84ns    1.67V      2.25V      1.403V
10.54ns   1.668V     2.192V     1.403V
[Falling Waveform]
R_fixture = 50
V_fixture = 0
V_fixture_min = 0
V_fixture_max = 0
0s        1.801V     1.274V     2.197V
278.1ps   1.801V     1.274V     2.046V
466.2ps   1.721V     1.274V     919mV
565.4ps   1.513V     1.274V     295.7mV
733.4ps   861.2mV    1.24V      29.27mV
892.8ps   253.4mV    1.142V     11.17mV
1.001ns   69.16mV    1.016V     6.355mV
1.599ns   7.374mV    173.1mV    0V
1.867ns   5.111mV    29.58mV    0V
10.64ns   0V         0V         0V
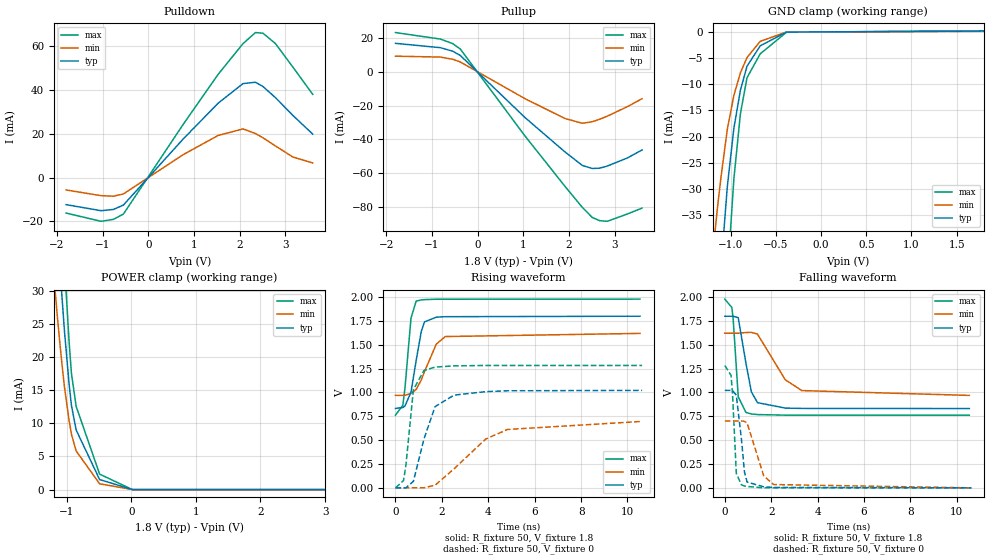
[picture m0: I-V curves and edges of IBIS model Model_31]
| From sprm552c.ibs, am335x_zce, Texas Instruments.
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| Model based on original model for BC1833DV50BPBFBP18LL_SSDHV
|   Sub model BC50B_V_PD_ON_10P_1P8
[model]   Model_31
|[Description]  [1.8V-I/O-PD-NORMAL, IND, 10%]
|   NORMAL,Weak internal pull-down,Industrial temperature range
|   (-40C to 125C, 25C nominal),10% power supply tolerance
|[Input Load]   PD
|[Output Drive] NORMAL
|Voltage   1.8V
|Mode   I/O
Model_type   I/O
Polarity   Non-Inverting
Enable   Active-Low
Vinl =  0.63
Vinh =  1.17
Cref =  15pF
Rref =  100.0000M
Vref =  0V
Vmeas =  0.9
C_comp   2.061175p   1.986339p   2.06195p
[Model Spec]
Vinl   0.63   0.567   0.693
Vinh   1.17   1.053   1.287
[Temperature Range]   25   125   -40
[Voltage Range]   1.8   1.62   1.98
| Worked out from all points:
|   slope of the pulldown table from 0 to 0.27 V, typ, clamps not added: 42.1 ohm
|   slope of the pullup table from 0 to 0.27 V, typ, clamps not added: 37.7 ohm
|   GND clamp passes 1 mA (typ) near -0.56 V on its own axis
|   POWER clamp passes 1 mA (typ) near -0.44 V on its own axis
|   rising waveform, R_fixture 50, V_fixture 1.8: 20-80 % time 396ps typ, 661ps min, 254ps max; typ from 0.832 V to 1.8 V
|   rising waveform, R_fixture 50, V_fixture 0: 20-80 % time 713ps typ, 1.93ns min, 313ps max; typ from 0 V to 1.02 V
|   falling waveform, R_fixture 50, V_fixture 1.8: 20-80 % time 386ps typ, 1ns min, 184ps max; typ from 1.8 V to 0.831 V
|   falling waveform, R_fixture 50, V_fixture 0: 20-80 % time 219ps typ, 427ps min, 142ps max; typ from 1.02 V to 0 V
[POWER_clamp]
-1.8V     154.2mA    109.7mA    213.5mA
-1.255V   57.34mA    38.4mA     81.27mA
-1.145V   39.68mA    26.05mA    56.64mA
-1.109V   34.21mA    22.34mA    48.88mA
-1.073V   28.97mA    18.83mA    41.38mA
-1.036V   23.97mA    15.54mA    34.15mA
-963.6mV  15.93mA    10.41mA    22.29mA
-927.3mV  12.7mA     8.357mA    17.52mA
-854.5mV  8.993mA    5.826mA    12.56mA
-490.9mV  1.518mA    876.6uA    2.331mA
18.18mV   0A         0A         0A
3.6V      0A         0A         0A
[Pulldown]
-1.8V     -12.34mA   -5.658mA   -16.19mA
-1.036V   -15.1mA    -8.245mA   -19.93mA
-763.6mV  -14.53mA   -8.482mA   -19.03mA
-545.5mV  -12.52mA   -7.458mA   -16.62mA
763.6mV   17.59mA    10.45mA    24.25mA
1.527V    33.86mA    19.17mA    47mA
2.073V    42.83mA    22.17mA    61.04mA
2.345V    43.43mA    20.07mA    66.07mA
2.509V    41.51mA    18.14mA    65.79mA
2.782V    36.44mA    14.42mA    61.08mA
3.164V    28.34mA    9.368mA    50.37mA
3.6V      19.79mA    6.648mA    37.91mA
[Pullup]
-1.8V     16.98mA    9.373mA    23.37mA
-818.2mV  14.42mA    8.845mA    19.53mA
-545.5mV  12.31mA    7.518mA    16.8mA
-381.8mV  9.817mA    5.934mA    13.63mA
1.036V    -27.01mA   -15.83mA   -37.94mA
1.909V    -47.35mA   -27.56mA   -67.71mA
2.291V    -55.4mA    -30.4mA    -80.26mA
2.509V    -57.21mA   -29.5mA    -86.26mA
2.673V    -57.02mA   -28.01mA   -88.15mA
2.836V    -55.79mA   -26.21mA   -88.52mA
3.273V    -51.04mA   -20.62mA   -84.23mA
3.6V      -46.22mA   -15.84mA   -80.68mA
[GND_clamp]
-1.8V     -258.3mA   -163.5mA   -409.7mA
-1.255V   -85.36mA   -52.4mA    -138.2mA
-1.218V   -74.87mA   -45.89mA   -121.3mA
-1.145V   -54.71mA   -33.55mA   -88.64mA
-1.109V   -45.65mA   -28.13mA   -73.71mA
-1.036V   -29.56mA   -18.62mA   -47.04mA
-963.6mV  -18.42mA   -12.15mA   -28.08mA
-890.9mV  -11.14mA   -7.842mA   -15.61mA
-818.2mV  -6.603mA   -4.949mA   -8.798mA
-672.7mV  -2.723mA   -1.863mA   -4.246mA
-381.8mV  -91.28uA   -77.52uA   -131.7uA
1.8V      101.9uA    59.34uA    152.6uA
[Ramp]
dV/dt_f 0.58661578/0.38804278n 0.39638832/1.0109925n 0.73531589/0.18527817n
dV/dt_r 0.61652374/0.71500447n 0.42465136/1.9737596n 0.77403027/0.31432708n
R_load = 50
[Rising Waveform]
R_fixture = 50
V_fixture = 1.8
V_fixture_min = 1.62
V_fixture_max = 1.98
0s        831.7mV    969mV      762mV
316ps     842.3mV    969mV      864.7mV
407.8ps   857.1mV    969mV      1.043V
668.1ps   1.002V     988.1mV    1.778V
890.2ps   1.333V     1.031V     1.956V
1.113ns   1.64V      1.131V     1.969V
1.252ns   1.739V     1.219V     1.972V
1.76ns    1.788V     1.506V     1.976V
2.147ns   1.793V     1.585V     1.976V
10.54ns   1.798V     1.618V     1.977V
[Rising Waveform]
R_fixture = 50
V_fixture = 0
V_fixture_min = 0
V_fixture_max = 0
0s        0V         0V         0V
346.2ps   0V         0V         77.12mV
446ps     0V         0V         230.4mV
772.4ps   68.57mV    0V         1.029V
1.225ns   511.2mV    0V         1.229V
1.708ns   851.7mV    27.58mV    1.265V
2.528ns   971.6mV    200.6mV    1.278V
3.886ns   1.008V     511.1mV    1.282V
4.827ns   1.017V     611.6mV    1.282V
10.63ns   1.021V     696.1mV    1.282V
[Falling Waveform]
R_fixture = 50
V_fixture = 1.8
V_fixture_min = 1.62
V_fixture_max = 1.98
0s        1.798V     1.62V      1.977V
301.1ps   1.798V     1.62V      1.89V
360.3ps   1.798V     1.62V      1.767V
577.5ps   1.782V     1.62V      954.9mV
909.6ps   1.307V     1.627V     790mV
1.144ns   1.006V     1.629V     774.2mV
1.407ns   892.9mV    1.611V     767.7mV
2.606ns   835.4mV    1.132V     761.7mV
3.32ns    832.3mV    1.019V     761.1mV
10.54ns   830.9mV    968.4mV    761mV
[Falling Waveform]
R_fixture = 50
V_fixture = 0
V_fixture_min = 0
V_fixture_max = 0
0s        1.021V     700.9mV    1.282V
266.5ps   1.021V     700.9mV    1.179V
329.9ps   1.021V     700.9mV    992.8mV
495.4ps   970.3mV    700.9mV    151.3mV
717.4ps   506.4mV    700.9mV    30.98mV
846.3ps   166.9mV    696.3mV    19.96mV
959.9ps   60.51mV    680mV      14.72mV
1.679ns   10.62mV    123.5mV    0V
2.108ns   4.767mV    34.55mV    0V
10.63ns   0V         0V         0V
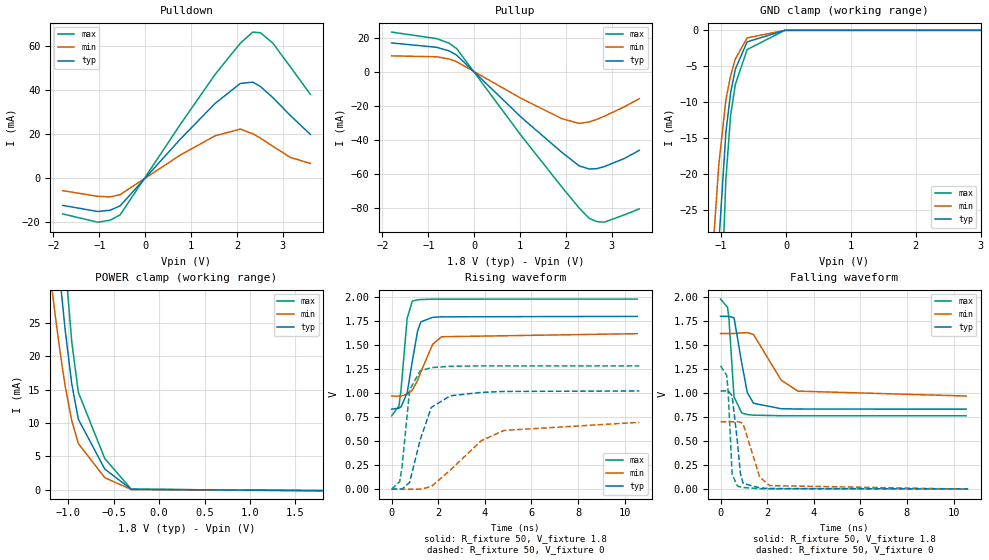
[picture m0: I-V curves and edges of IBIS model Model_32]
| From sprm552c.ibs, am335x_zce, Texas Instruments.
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| Model based on original model for BC1833DV50BPBFBP18LL_SSDHV
|   Sub model BC50B_V_PU_ON_10P_1P8
[model]   Model_32
|[Description]  [1.8V-I/O-PU-NORMAL, IND, 10%]
|   NORMAL,Weak internal pull-up,Industrial temperature range (-40C
|   to 125C, 25C nominal),10% power supply tolerance
|[Input Load]   PU
|[Output Drive] NORMAL
|Voltage   1.8V
|Mode   I/O
Model_type   I/O
Polarity   Non-Inverting
Enable   Active-Low
Vinl =  0.63
Vinh =  1.17
Cref =  15pF
Rref =  100.0000M
Vref =  0V
Vmeas =  0.9
C_comp   2.061175p   1.986339p   2.06195p
[Model Spec]
Vinl   0.63   0.567   0.693
Vinh   1.17   1.053   1.287
[Temperature Range]   25   125   -40
[Voltage Range]   1.8   1.62   1.98
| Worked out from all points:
|   slope of the pulldown table from 0 to 0.27 V, typ, clamps not added: 42.1 ohm
|   slope of the pullup table from 0 to 0.27 V, typ, clamps not added: 37.7 ohm
|   GND clamp passes 1 mA (typ) near -0.55 V on its own axis
|   POWER clamp passes 1 mA (typ) near -0.45 V on its own axis
|   rising waveform, R_fixture 50, V_fixture 1.8: 20-80 % time 395ps typ, 660ps min, 254ps max; typ from 0.834 V to 1.8 V
|   rising waveform, R_fixture 50, V_fixture 0: 20-80 % time 712ps typ, 1.93ns min, 312ps max; typ from 0.003 V to 1.02 V
|   falling waveform, R_fixture 50, V_fixture 1.8: 20-80 % time 386ps typ, 1ns min, 184ps max; typ from 1.8 V to 0.833 V
|   falling waveform, R_fixture 50, V_fixture 0: 20-80 % time 219ps typ, 430ps min, 142ps max; typ from 1.02 V to 0.002 V
[POWER_clamp]
-1.8V     154.2mA    109.7mA    213.3mA
-1.255V   57.27mA    38.38mA    81.13mA
-1.218V   51.28mA    34.15mA    72.8mA
-1.145V   39.6mA     26.02mA    56.49mA
-1.109V   34.13mA    22.31mA    48.73mA
-1.073V   28.89mA    18.8mA     41.23mA
-1.036V   23.89mA    15.51mA    34mA
-963.6mV  15.85mA    10.37mA    22.13mA
-890.9mV  10.56mA    6.934mA    14.57mA
-600mV    3.124mA    1.834mA    4.693mA
-309.1mV  105.7uA    71.53uA    124.5uA
1.8V      -99.94uA   -59.59uA   -146.8uA
[Pulldown]
-1.8V     -12.34mA   -5.658mA   -16.19mA
-1.036V   -15.1mA    -8.245mA   -19.94mA
-763.6mV  -14.53mA   -8.482mA   -19.03mA
-545.5mV  -12.52mA   -7.458mA   -16.62mA
763.6mV   17.59mA    10.43mA    24.25mA
1.527V    33.86mA    19.17mA    47mA
2.073V    42.83mA    22.17mA    61.04mA
2.345V    43.43mA    20.07mA    66.07mA
2.509V    41.51mA    18.14mA    65.79mA
2.782V    36.44mA    14.42mA    61.08mA
3.164V    28.34mA    9.368mA    50.37mA
3.6V      19.79mA    6.648mA    37.91mA
[Pullup]
-1.8V     16.98mA    9.373mA    23.37mA
-818.2mV  14.42mA    8.845mA    19.53mA
-545.5mV  12.31mA    7.518mA    16.8mA
-381.8mV  9.818mA    5.934mA    13.63mA
1.036V    -27.01mA   -15.83mA   -37.93mA
1.909V    -47.35mA   -27.56mA   -67.71mA
2.291V    -55.4mA    -30.4mA    -80.26mA
2.509V    -57.21mA   -29.5mA    -86.26mA
2.673V    -57.02mA   -28.01mA   -88.15mA
2.836V    -55.79mA   -26.21mA   -88.52mA
3.273V    -51.04mA   -20.62mA   -84.23mA
3.6V      -46.22mA   -15.84mA   -80.68mA
[GND_clamp]
-1.8V     -258.3mA   -163.5mA   -409.7mA
-1.255V   -85.38mA   -52.41mA   -138.2mA
-1.218V   -74.89mA   -45.9mA    -121.4mA
-1.145V   -54.74mA   -33.56mA   -88.69mA
-1.109V   -45.68mA   -28.14mA   -73.78mA
-1.036V   -29.6mA    -18.64mA   -47.14mA
-927.3mV  -14.18mA   -9.66mA    -20.72mA
-854.5mV  -8.721mA   -6.314mA   -11.83mA
-781.8mV  -5.401mA   -3.992mA   -7.544mA
-600mV    -1.607mA   -1.058mA   -2.674mA
-18.18mV  0A         0A         0A
3.6V      0A         0A         0A
[Ramp]
dV/dt_f 0.58648037/0.38862065n 0.39630022/1.011634n  0.73512162/0.18567021n
dV/dt_r 0.61648385/0.71430933n 0.42454297/1.9725709n 0.77395833/0.31377307n
R_load = 50
[Rising Waveform]
R_fixture = 50
V_fixture = 1.8
V_fixture_min = 1.62
V_fixture_max = 1.98
0s        834.2mV    970.7mV    765.2mV
316ps     844.9mV    970.7mV    868.4mV
407.8ps   859.8mV    970.7mV    1.047V
668ps     1.005V     989.9mV    1.782V
890.2ps   1.337V     1.033V     1.959V
1.113ns   1.644V     1.133V     1.972V
1.252ns   1.743V     1.221V     1.975V
1.76ns    1.79V      1.509V     1.979V
2.143ns   1.795V     1.588V     1.979V
10.54ns   1.8V       1.62V      1.98V
[Rising Waveform]
R_fixture = 50
V_fixture = 0
V_fixture_min = 0
V_fixture_max = 0
0s        2.797mV    2.27mV     2.927mV
346.5ps   2.797mV    2.27mV     80.72mV
446.8ps   2.797mV    2.27mV     236mV
772.8ps   71.85mV    2.27mV     1.034V
1.221ns   511.3mV    2.27mV     1.232V
1.702ns   852.4mV    28.89mV    1.267V
2.512ns   973.3mV    198.8mV    1.281V
3.852ns   1.009V     507.3mV    1.285V
4.826ns   1.019V     613.4mV    1.285V
10.63ns   1.024V     697.8mV    1.285V
[Falling Waveform]
R_fixture = 50
V_fixture = 1.8
V_fixture_min = 1.62
V_fixture_max = 1.98
0s        1.8V       1.621V     1.98V
301.1ps   1.8V       1.621V     1.894V
360.3ps   1.8V       1.621V     1.77V
576.9ps   1.785V     1.621V     960.4mV
909.4ps   1.311V     1.628V     793.3mV
1.147ns   1.007V     1.63V      777.2mV
1.411ns   894.9mV    1.612V     770.8mV
2.599ns   837.9mV    1.136V     765mV
3.319ns   834.7mV    1.021V     764.4mV
10.54ns   833.3mV    970.1mV    764.3mV
[Falling Waveform]
R_fixture = 50
V_fixture = 0
V_fixture_min = 0
V_fixture_max = 0
0s        1.023V     702.5mV    1.285V
266.5ps   1.023V     702.5mV    1.182V
330ps     1.023V     702.5mV    996.1mV
495.8ps   972.5mV    702.5mV    153.8mV
722.2ps   495.2mV    702.5mV    33.52mV
850.4ps   162.8mV    697.5mV    22.77mV
967.6ps   60.53mV    680mV      17.46mV
1.679ns   12.9mV     126.1mV    4.683mV
2.108ns   7.005mV    37.17mV    3.486mV
10.63ns   2.268mV    0V         3.044mV
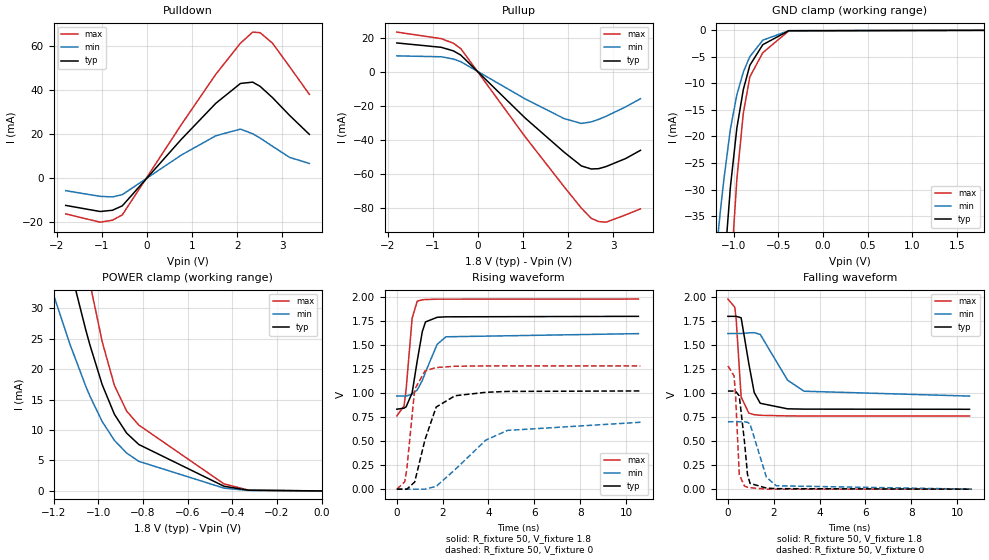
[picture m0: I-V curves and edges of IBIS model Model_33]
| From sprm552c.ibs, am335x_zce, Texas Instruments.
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| Model based on original model for BC1833DV50BPBFBP18LL_SSDHV
|   Sub model BC50B_V_PUPDOFF_10P_1P8
[model]   Model_33
|[Description]  [1.8V-I/O-PI-NORMAL, IND, 10%]
|   NORMAL,Weak pull up/down disabled,Industrial temperature range
|   (-40C to 125C, 25C nominal),10% power supply tolerance
|[Input Load]   PI
|[Output Drive] NORMAL
|Voltage   1.8V
|Mode   I/O
Model_type   I/O
Polarity   Non-Inverting
Enable   Active-Low
Vinl =  0.63
Vinh =  1.17
Cref =  15pF
Rref =  100.0000M
Vref =  0V
Vmeas =  0.9
C_comp   2.061175p   1.986339p   2.06195p
[Model Spec]
Vinl   0.63   0.567   0.693
Vinh   1.17   1.053   1.287
[Temperature Range]   25   125   -40
[Voltage Range]   1.8   1.62   1.98
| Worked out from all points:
|   slope of the pulldown table from 0 to 0.27 V, typ, clamps not added: 42.1 ohm
|   slope of the pullup table from 0 to 0.27 V, typ, clamps not added: 37.7 ohm
|   GND clamp passes 1 mA (typ) near -0.56 V on its own axis
|   POWER clamp passes 1 mA (typ) near -0.46 V on its own axis
|   rising waveform, R_fixture 50, V_fixture 1.8: 20-80 % time 396ps typ, 661ps min, 254ps max; typ from 0.833 V to 1.8 V
|   rising waveform, R_fixture 50, V_fixture 0: 20-80 % time 714ps typ, 1.93ns min, 314ps max; typ from 0 V to 1.02 V
|   falling waveform, R_fixture 50, V_fixture 1.8: 20-80 % time 387ps typ, 1ns min, 185ps max; typ from 1.8 V to 0.832 V
|   falling waveform, R_fixture 50, V_fixture 0: 20-80 % time 219ps typ, 428ps min, 142ps max; typ from 1.02 V to 0 V
[POWER_clamp]
-1.8V     154.2mA    109.7mA    213.3mA
-1.236V   54.24mA    36.25mA    76.91mA
-1.127V   36.83mA    24.15mA    52.56mA
-1.055V   26.36mA    17.14mA    37.57mA
-1.036V   23.85mA    15.49mA    33.95mA
-981.8mV  17.43mA    11.38mA    24.47mA
-927.3mV  12.58mA    8.302mA    17.32mA
-872.7mV  9.497mA    6.223mA    13.12mA
-818.2mV  7.629mA    4.862mA    10.82mA
-436.4mV  761.6uA    453.8uA    1.147mA
-327.3mV  115.1uA    79.01uA    133.6uA
0V        19.19nA    119.5nA    352.1nA
[Pulldown]
-1.8V     -12.34mA   -5.658mA   -16.19mA
-1.036V   -15.1mA    -8.245mA   -19.93mA
-763.6mV  -14.53mA   -8.482mA   -19.03mA
-545.5mV  -12.52mA   -7.458mA   -16.62mA
763.6mV   17.59mA    10.45mA    24.25mA
1.527V    33.86mA    19.17mA    47mA
2.073V    42.83mA    22.17mA    61.04mA
2.345V    43.43mA    20.07mA    66.07mA
2.509V    41.51mA    18.14mA    65.79mA
2.782V    36.44mA    14.42mA    61.08mA
3.164V    28.34mA    9.368mA    50.37mA
3.6V      19.79mA    6.648mA    37.91mA
[Pullup]
-1.8V     16.98mA    9.373mA    23.37mA
-818.2mV  14.42mA    8.845mA    19.53mA
-545.5mV  12.31mA    7.518mA    16.8mA
-381.8mV  9.818mA    5.934mA    13.63mA
1.036V    -27.01mA   -15.83mA   -37.94mA
1.909V    -47.35mA   -27.56mA   -67.71mA
2.291V    -55.4mA    -30.4mA    -80.26mA
2.509V    -57.21mA   -29.5mA    -86.26mA
2.673V    -57.02mA   -28.01mA   -88.15mA
2.836V    -55.79mA   -26.21mA   -88.52mA
3.273V    -51.04mA   -20.62mA   -84.23mA
3.6V      -46.22mA   -15.84mA   -80.68mA
[GND_clamp]
-1.8V     -258.3mA   -163.5mA   -409.7mA
-1.255V   -85.35mA   -52.4mA    -138.2mA
-1.218V   -74.87mA   -45.89mA   -121.3mA
-1.145V   -54.71mA   -33.55mA   -88.63mA
-1.109V   -45.64mA   -28.13mA   -73.71mA
-1.036V   -29.55mA   -18.62mA   -47.03mA
-963.6mV  -18.42mA   -12.14mA   -28.07mA
-890.9mV  -11.13mA   -7.836mA   -15.58mA
-818.2mV  -6.581mA   -4.941mA   -8.76mA
-672.7mV  -2.695mA   -1.849mA   -4.207mA
-381.8mV  -68.52uA   -64.39uA   -99.44uA
1.8V      19.19nA    2.616uA    309.8nA
[Ramp]
dV/dt_f 0.58726172/0.38923057n 0.39670756/1.0127404n 0.73629545/0.18607861n
dV/dt_r 0.61731976/0.71592437n 0.42507457/1.9754461n  0.7752052/0.31487132n
R_load = 50
[Rising Waveform]
R_fixture = 50
V_fixture = 1.8
V_fixture_min = 1.62
V_fixture_max = 1.98
0s        832.9mV    970mV      763.3mV
316ps     843.6mV    970mV      866.2mV
407.8ps   858.4mV    970mV      1.045V
668ps     1.003V     989.2mV    1.78V
890.2ps   1.335V     1.033V     1.958V
1.113ns   1.642V     1.132V     1.972V
1.252ns   1.742V     1.22V      1.975V
1.759ns   1.79V      1.508V     1.979V
2.143ns   1.795V     1.587V     1.979V
10.54ns   1.8V       1.62V      1.98V
[Rising Waveform]
R_fixture = 50
V_fixture = 0
V_fixture_min = 0
V_fixture_max = 0
0s        0V         0V         0V
346.2ps   0V         0V         77.13mV
438.2ps   0V         0V         213.1mV
780.3ps   74.58mV    0V         1.04V
1.23ns    516.1mV    0V         1.231V
1.717ns   855.2mV    28.8mV     1.267V
2.54ns    973.1mV    203.5mV    1.28V
3.886ns   1.009V     511.4mV    1.284V
4.828ns   1.018V     612mV      1.284V
10.63ns   1.023V     696.7mV    1.284V
[Falling Waveform]
R_fixture = 50
V_fixture = 1.8
V_fixture_min = 1.62
V_fixture_max = 1.98
0s        1.8V       1.621V     1.98V
301.1ps   1.8V       1.621V     1.894V
360.3ps   1.8V       1.621V     1.77V
576.8ps   1.785V     1.621V     960.1mV
912.2ps   1.307V     1.628V     791.9mV
1.147ns   1.007V     1.63V      775.9mV
1.411ns   894.4mV    1.612V     769.3mV
2.599ns   837mV      1.136V     763.1mV
3.319ns   833.6mV    1.02V      762.4mV
10.54ns   832mV      969.5mV    762.3mV
[Falling Waveform]
R_fixture = 50
V_fixture = 0
V_fixture_min = 0
V_fixture_max = 0
0s        1.022V     701.6mV    1.284V
266.5ps   1.022V     701.6mV    1.181V
330ps     1.022V     701.6mV    995mV
495.9ps   971.4mV    701.6mV    152.1mV
720.9ps   497.6mV    701.6mV    31.75mV
854.2ps   154.3mV    696.3mV    20.45mV
964.2ps   60.18mV    679.8mV    15.34mV
1.679ns   11.21mV    124.5mV    0V
2.108ns   5.21mV     35.35mV    0V
10.63ns   0V         0V         0V
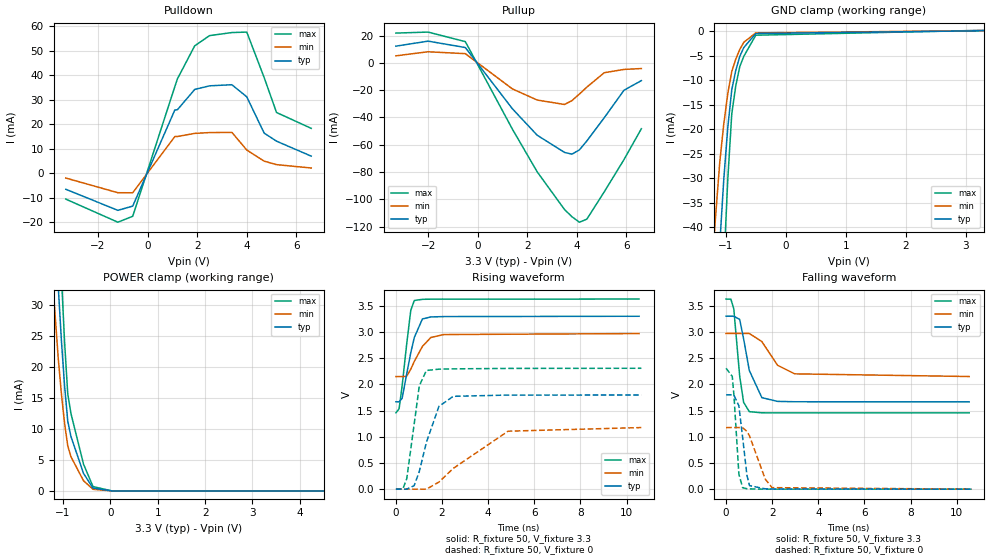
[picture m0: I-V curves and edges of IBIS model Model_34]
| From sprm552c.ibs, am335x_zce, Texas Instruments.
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| Model based on original model for BC1833DV50BPBFBP18LL_SSDHV
|   Sub model BC50B_V_PD_ON_10P_3P3
[model]   Model_34
|[Description]  [3.3V-I/O-PD-NORMAL, IND, 10%]
|   NORMAL,Weak internal pull-down,Industrial temperature range
|   (-40C to 125C, 25C nominal),10% power supply tolerance
|[Input Load]   PD
|[Output Drive] NORMAL
|Voltage   3.3V
|Mode   I/O
Model_type   I/O
Polarity   Non-Inverting
Enable   Active-Low
Vinl =  0.8V
Vinh =  2V
Cref =  15pF
Rref =  100.0000M
Vref =  0V
Vmeas =  1.65
C_comp   1.841028p   1.702526p   1.921952p
[Model Spec]
Vinl   0.8V   0.8V   0.8V
Vinh   2V   2V   2V
[Temperature Range]   25   125   -40
[Voltage Range]   3.3   2.97   3.63
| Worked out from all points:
|   slope of the pulldown table from 0 to 0.495 V, typ, clamps not added: 41.2 ohm
|   slope of the pullup table from 0 to 0.495 V, typ, clamps not added: 40 ohm
|   GND clamp passes 1 mA (typ) near -0.55 V on its own axis
|   POWER clamp passes 1 mA (typ) near -0.44 V on its own axis
|   rising waveform, R_fixture 50, V_fixture 3.3: 20-80 % time 461ps typ, 617ps min, 332ps max; typ from 1.67 V to 3.3 V
|   rising waveform, R_fixture 50, V_fixture 0: 20-80 % time 691ps typ, 1.86ns min, 386ps max; typ from 0 V to 1.8 V
|   falling waveform, R_fixture 50, V_fixture 3.3: 20-80 % time 462ps typ, 800ps min, 264ps max; typ from 3.3 V to 1.67 V
|   falling waveform, R_fixture 50, V_fixture 0: 20-80 % time 273ps typ, 570ps min, 190ps max; typ from 1.8 V to 0 V
[POWER_clamp]
-3.3V     437.1mA    413.2mA    590.8mA
-1.233V   54mA       35.96mA    76.75mA
-1.167V   43.32mA    28.48mA    61.85mA
-1.1V     33.01mA    21.39mA    47.35mA
-1.033V   24.22mA    15.63mA    34.6mA
-966.7mV  16.98mA    10.93mA    24.06mA
-900mV    11.29mA    7.296mA    15.71mA
-833.3mV  8.816mA    5.547mA    12.54mA
-566.7mV  2.833mA    1.645mA    4.322mA
-366.7mV  458.2uA    268.6uA    705.7uA
33.33mV   0A         0A         0A
6.6V      0A         0A         0A
[Pulldown]
-3.3V     -6.622mA   -2.021mA   -10.65mA
-1.2V     -15.24mA   -8.032mA   -20.09mA
-600mV    -13.5mA    -8.05mA    -17.67mA
1.1V      25.87mA    14.97mA    35.44mA
1.2V      25.89mA    14.97mA    38.5mA
1.9V      34.23mA    16.24mA    52.08mA
2.5V      35.71mA    16.58mA    56.26mA
3.4V      36.16mA    16.66mA    57.51mA
4V        31.21mA    9.437mA    57.7mA
4.7V      16.38mA    4.891mA    39.13mA
5.2V      13.06mA    3.458mA    24.8mA
6.6V      6.944mA    2.091mA    18.31mA
[Pullup]
-3.3V     12.22mA    5.124mA    21.79mA
-2V       15.88mA    8.101mA    22.51mA
-500mV    11.19mA    6.71mA     15.51mA
1.4V      -33.67mA   -19.12mA   -48.63mA
2.4V      -53.04mA   -27.26mA   -79.87mA
3.5V      -65.59mA   -30.5mA    -107.4mA
3.8V      -66.88mA   -27.67mA   -112.7mA
4.1V      -63.77mA   -22.88mA   -116.7mA
4.4V      -57.22mA   -17.81mA   -114.5mA
5.1V      -40.3mA    -7.267mA   -94.57mA
5.9V      -20.05mA   -4.823mA   -70.85mA
6.6V      -13.04mA   -4.182mA   -48.28mA
[GND_clamp]
-3.3V     -759.3mA   -592.9mA   -1.187A
-1.233V   -79.58mA   -48.75mA   -128.9mA
-1.167V   -61.06mA   -37.35mA   -98.95mA
-1.1V     -43.51mA   -26.72mA   -70.29mA
-1.033V   -30.2mA    -18.91mA   -48.09mA
-966.7mV  -19.68mA   -12.74mA   -30.28mA
-900mV    -11.93mA   -8.218mA   -16.86mA
-833.3mV  -8mA       -5.694mA   -11.13mA
-766.7mV  -5.133mA   -3.707mA   -7.221mA
-700mV    -3.33mA    -2.257mA   -5.131mA
-500mV    -463.9uA   -330.4uA   -807.7uA
3.3V      108.6uA    142.7uA    198.5uA
[Ramp]
dV/dt_f 0.98276977/0.46300853n 0.49602348/0.8054585n  1.3060174/0.26420663n
dV/dt_r  1.0808788/0.69218116n  0.7081959/1.8687097n  1.3875648/0.38704994n
R_load = 50
[Rising Waveform]
R_fixture = 50
V_fixture = 3.3
V_fixture_min = 2.97
V_fixture_max = 3.63
0s        1.666V     2.147V     1.456V
138ps     1.666V     2.147V     1.534V
268ps     1.732V     2.147V     1.965V
468.1ps   2.199V     2.154V     2.775V
644.9ps   2.605V     2.29V      3.413V
797.9ps   2.895V     2.438V     3.599V
1.149ns   3.247V     2.723V     3.621V
1.514ns   3.285V     2.893V     3.624V
2.078ns   3.292V     2.949V     3.625V
10.54ns   3.298V     2.968V     3.626V
[Rising Waveform]
R_fixture = 50
V_fixture = 0
V_fixture_min = 0
V_fixture_max = 0
0s        0V         0V         0V
300ps     0V         0V         3.304mV
470.7ps   0V         0V         202.7mV
791.3ps   67.95mV    0V         1.242V
1.013ns   336.7mV    0V         1.971V
1.321ns   892.5mV    0V         2.264V
1.864ns   1.579V     135.4mV    2.289V
2.487ns   1.771V     396.8mV    2.295V
4.862ns   1.795V     1.106V     2.303V
10.64ns   1.796V     1.175V     2.306V
[Falling Waveform]
R_fixture = 50
V_fixture = 3.3
V_fixture_min = 2.97
V_fixture_max = 3.63
0s        3.298V     2.969V     3.625V
210.4ps   3.298V     2.969V     3.622V
335.9ps   3.298V     2.969V     3.438V
590.5ps   3.237V     2.969V     2.159V
761.4ps   2.867V     2.969V     1.657V
1.008ns   2.264V     2.969V     1.478V
1.553ns   1.745V     2.814V     1.456V
2.232ns   1.674V     2.363V     1.455V
2.975ns   1.667V     2.199V     1.455V
10.54ns   1.665V     2.148V     1.455V
[Falling Waveform]
R_fixture = 50
V_fixture = 0
V_fixture_min = 0
V_fixture_max = 0
0s        1.799V     1.175V     2.305V
268.9ps   1.799V     1.175V     2.151V
340.8ps   1.793V     1.175V     1.799V
555.8ps   1.589V     1.175V     286.1mV
719.7ps   983.6mV    1.171V     28.02mV
905.5ps   263.5mV    1.102V     8.447mV
1.018ns   67.36mV    1.015V     5.379mV
1.701ns   6.493mV    189.9mV    0V
1.996ns   3.425mV    28.94mV    0V
10.64ns   0V         0V         0V
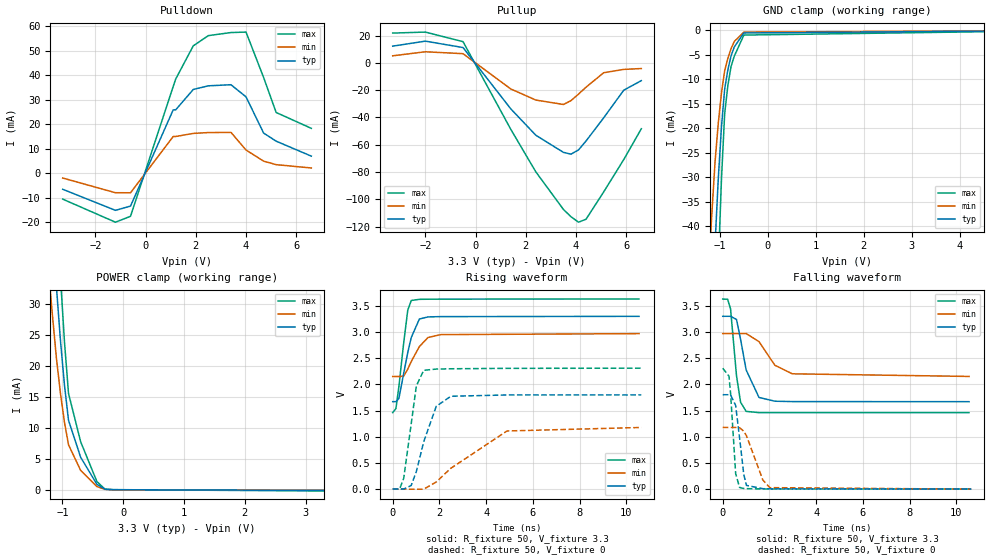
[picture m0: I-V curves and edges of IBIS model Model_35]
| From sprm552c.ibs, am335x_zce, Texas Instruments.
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| Model based on original model for BC1833DV50BPBFBP18LL_SSDHV
|   Sub model BC50B_V_PU_ON_10P_3P3
[model]   Model_35
|[Description]  [3.3V-I/O-PU-NORMAL, IND, 10%]
|   NORMAL,Weak internal pull-up,Industrial temperature range (-40C
|   to 125C, 25C nominal),10% power supply tolerance
|[Input Load]   PU
|[Output Drive] NORMAL
|Voltage   3.3V
|Mode   I/O
Model_type   I/O
Polarity   Non-Inverting
Enable   Active-Low
Vinl =  0.8V
Vinh =  2V
Cref =  15pF
Rref =  100.0000M
Vref =  0V
Vmeas =  1.65
C_comp   1.841028p   1.702526p   1.921952p
[Model Spec]
Vinl   0.8V   0.8V   0.8V
Vinh   2V   2V   2V
[Temperature Range]   25   125   -40
[Voltage Range]   3.3   2.97   3.63
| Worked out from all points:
|   slope of the pulldown table from 0 to 0.495 V, typ, clamps not added: 41.2 ohm
|   slope of the pullup table from 0 to 0.495 V, typ, clamps not added: 40 ohm
|   GND clamp passes 1 mA (typ) near -0.54 V on its own axis
|   POWER clamp passes 1 mA (typ) near -0.44 V on its own axis
|   rising waveform, R_fixture 50, V_fixture 3.3: 20-80 % time 460ps typ, 615ps min, 332ps max; typ from 1.67 V to 3.3 V
|   rising waveform, R_fixture 50, V_fixture 0: 20-80 % time 690ps typ, 1.86ns min, 386ps max; typ from 0.003 V to 1.8 V
|   falling waveform, R_fixture 50, V_fixture 3.3: 20-80 % time 463ps typ, 799ps min, 264ps max; typ from 3.3 V to 1.67 V
|   falling waveform, R_fixture 50, V_fixture 0: 20-80 % time 273ps typ, 572ps min, 191ps max; typ from 1.8 V to 0.002 V
[POWER_clamp]
-3.3V     437.1mA    413.2mA    590.8mA
-1.233V   53.96mA    35.94mA    76.63mA
-1.167V   43.27mA    28.47mA    61.73mA
-1.1V     32.96mA    21.37mA    47.23mA
-1.033V   24.17mA    15.61mA    34.48mA
-966.7mV  16.93mA    10.91mA    23.92mA
-900mV    11.23mA    7.273mA    15.58mA
-700mV    5.251mA    3.128mA    7.754mA
-433.3mV  893.2uA    531.1uA    1.34mA
-300mV    89.78uA    60.73uA    103.5uA
-166.7mV  17.36uA    10.48uA    24.7uA
3.3V      -100.3uA   -78.85uA   -188.3uA
[Pulldown]
-3.3V     -6.622mA   -2.021mA   -10.65mA
-1.2V     -15.24mA   -8.032mA   -20.09mA
-600mV    -13.5mA    -8.05mA    -17.67mA
1.1V      25.87mA    14.97mA    35.44mA
1.2V      25.9mA     14.98mA    38.5mA
1.9V      34.23mA    16.24mA    52.08mA
2.5V      35.71mA    16.58mA    56.26mA
3.4V      36.16mA    16.66mA    57.51mA
4V        31.2mA     9.437mA    57.7mA
4.7V      16.38mA    4.891mA    39.13mA
5.2V      13.06mA    3.458mA    24.8mA
6.6V      6.944mA    2.091mA    18.31mA
[Pullup]
-3.3V     12.22mA    5.124mA    21.79mA
-2V       15.88mA    8.101mA    22.51mA
-500mV    11.19mA    6.71mA     15.51mA
1.4V      -33.67mA   -19.12mA   -48.63mA
2.4V      -53.04mA   -27.26mA   -79.87mA
3.5V      -65.59mA   -30.5mA    -107.4mA
3.8V      -66.88mA   -27.67mA   -112.7mA
4.1V      -63.77mA   -22.88mA   -116.7mA
4.4V      -57.22mA   -17.81mA   -114.5mA
5.1V      -40.3mA    -7.267mA   -94.57mA
5.9V      -20.05mA   -4.823mA   -70.85mA
6.6V      -13.04mA   -4.182mA   -48.28mA
[GND_clamp]
-3.3V     -759.3mA   -592.9mA   -1.187A
-1.233V   -79.59mA   -48.75mA   -128.9mA
-1.167V   -61.07mA   -37.35mA   -98.98mA
-1.1V     -43.52mA   -26.72mA   -70.33mA
-1.033V   -30.22mA   -18.91mA   -48.15mA
-966.7mV  -19.71mA   -12.75mA   -30.37mA
-900mV    -11.97mA   -8.228mA   -16.98mA
-833.3mV  -8.054mA   -5.709mA   -11.26mA
-766.7mV  -5.195mA   -3.727mA   -7.362mA
-700mV    -3.396mA   -2.282mA   -5.277mA
-500mV    -540.4uA   -362.2uA   -967.3uA
6.6V      0A         0A         0A
[Ramp]
dV/dt_f 0.98117443/0.46331747n 0.49490279/0.80370825n  1.3049598/0.26489397n
dV/dt_r  1.0815938/0.69195668n 0.70882532/1.8695428n  1.3880273/0.3868746n
R_load = 50
[Rising Waveform]
R_fixture = 50
V_fixture = 3.3
V_fixture_min = 2.97
V_fixture_max = 3.63
0s        1.671V     2.151V     1.461V
138ps     1.671V     2.151V     1.54V
264.5ps   1.732V     2.151V     1.959V
468.4ps   2.206V     2.157V     2.785V
643.8ps   2.609V     2.292V     3.418V
793.9ps   2.895V     2.438V     3.603V
1.141ns   3.249V     2.722V     3.625V
1.51ns    3.289V     2.896V     3.627V
2.055ns   3.295V     2.951V     3.629V
10.54ns   3.3V       2.97V      3.63V
[Rising Waveform]
R_fixture = 50
V_fixture = 0
V_fixture_min = 0
V_fixture_max = 0
0s        2.876mV    0V         2.885mV
300ps     2.876mV    0V         6.961mV
470.7ps   2.876mV    0V         206.7mV
787.9ps   68.31mV    0V         1.235V
1.011ns   336mV      0V         1.971V
1.327ns   905.2mV    0V         2.27V
1.863ns   1.582V     137mV      2.293V
2.488ns   1.774V     399.1mV    2.299V
4.89ns    1.799V     1.111V     2.307V
10.64ns   1.8V       1.178V     2.31V
[Falling Waveform]
R_fixture = 50
V_fixture = 3.3
V_fixture_min = 2.97
V_fixture_max = 3.63
0s        3.3V       2.971V     3.629V
210ps     3.3V       2.971V     3.626V
335.8ps   3.3V       2.971V     3.442V
590.3ps   3.24V      2.971V     2.166V
765.2ps   2.859V     2.971V     1.659V
1.004ns   2.275V     2.971V     1.485V
1.553ns   1.751V     2.816V     1.461V
2.234ns   1.679V     2.365V     1.461V
2.979ns   1.672V     2.202V     1.461V
10.54ns   1.67V      2.152V     1.461V
[Falling Waveform]
R_fixture = 50
V_fixture = 0
V_fixture_min = 0
V_fixture_max = 0
0s        1.803V     1.178V     2.309V
268.9ps   1.803V     1.178V     2.156V
337.5ps   1.798V     1.178V     1.826V
554.9ps   1.596V     1.178V     296.2mV
720.3ps   985.8mV    1.173V     32.61mV
900.6ps   283.1mV    1.108V     13.16mV
1.018ns   71.17mV    1.018V     9.701mV
1.717ns   9.108mV    176.3mV    4.069mV
2.014ns   6.093mV    29.03mV    3.846mV
10.64ns   2.247mV    0V         3.602mV
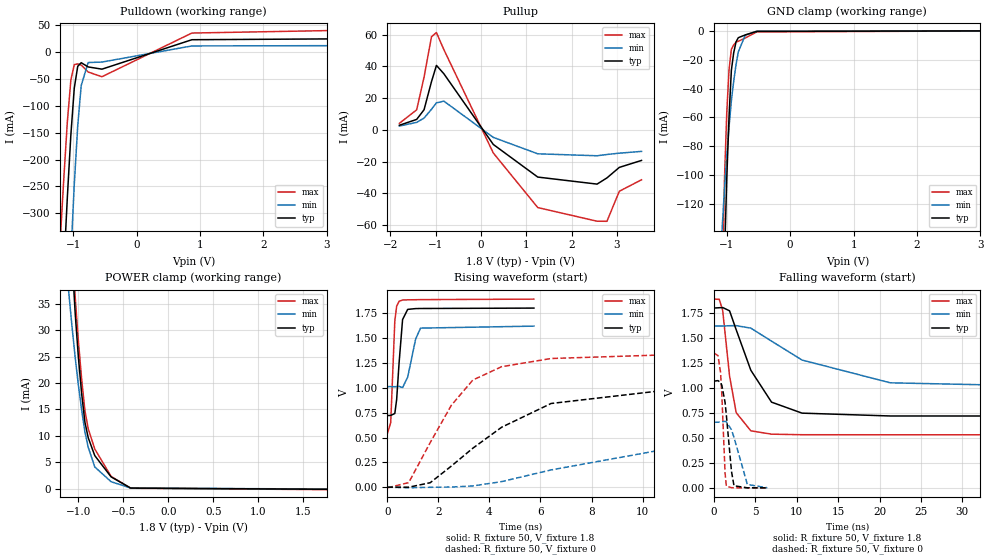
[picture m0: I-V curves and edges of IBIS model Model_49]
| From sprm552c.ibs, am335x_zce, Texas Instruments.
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| Model based on original model for OQ18SMART1FBPB_SSBHH
|   Sub model SBHH_HS00L01_PU1_1P8
[model]   Model_49
|[Description]  [1.8V-3-STATE-PU-S00:L01]
|   S00, L01,Weak internal pull-up, ,
|[Input Load]   PU
|[Output Drive] S00:L01
|Voltage   1.8V
|Mode   3-STATE
Model_type   3-state
Polarity   Non-Inverting
Enable   Active-Low
Cref =  15pF
Rref =  100.0000M
Vref =  0V
Vmeas =  0.9
C_comp   1.240965p   1.099743p   1.401226p
[Temperature Range]   25   125   -40
[Voltage Range]   1.8   1.62   1.89
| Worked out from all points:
|   slope of the pulldown table from 0 to 0.27 V, typ, clamps not added: 24.3 ohm
|   slope of the pullup table from 0 to 0.27 V, typ, clamps not added: 29.7 ohm
|   GND clamp passes 1 mA (typ) near -0.60 V on its own axis
|   POWER clamp passes 1 mA (typ) near -0.56 V on its own axis
|   rising waveform, R_fixture 50, V_fixture 1.8: 20-80 % time 171ps typ, 302ps min, 116ps max; typ from 0.72 V to 1.8 V
|   rising waveform, R_fixture 50, V_fixture 0: 20-80 % time 4.08ns typ, 9.5ns min, 2.05ns max; typ from 0.002 V to 1.07 V
|   falling waveform, R_fixture 50, V_fixture 1.8: 20-80 % time 3.38ns typ, 8.82ns min, 1.26ns max; typ from 1.8 V to 0.72 V
|   falling waveform, R_fixture 50, V_fixture 0: 20-80 % time 711ps typ, 1.21ns min, 410ps max; typ from 1.07 V to 0.002 V
[POWER_clamp]
-1.8V     360mA      189.8mA    409.4mA
-1.109V   56.23mA    37.39mA    59.78mA
-1.073V   44.23mA    30.96mA    47.33mA
-1.036V   33.16mA    24.83mA    36.25mA
-1V       24.78mA    19.56mA    27.84mA
-963.6mV  17.91mA    14.85mA    20.66mA
-927.3mV  12.54mA    10.7mA     14.72mA
-890.9mV  9.653mA    7.862mA    11.35mA
-818.2mV  6.273mA    4.126mA    7.524mA
-636.4mV  2.249mA    1.34mA     2.341mA
-418.2mV  128.7uA    129uA      104.8uA
1.764V    -96.73uA   -46.46uA   -163.5uA
[Pulldown]
-1.8V     -1.72A     -2.612A    -1.411A
-1.2V     -528.3mA   -845.3mA   -342.5mA
-1.145V   -396.8mA   -683.8mA   -231.2mA
-1.091V   -269.6mA   -527.2mA   -129mA
-1.036V   -154.1mA   -379.3mA   -51.85mA
-981.8mV  -66.54mA   -245.9mA   -22.8mA
-927.3mV  -26.05mA   -136.4mA   -21.6mA
-872.7mV  -19.36mA   -62.04mA   -23.73mA
-763.6mV  -27.2mA    -19.06mA   -36.72mA
-545.5mV  -31.39mA   -18.17mA   -45.46mA
872.7mV   23.46mA    11.88mA    35.92mA
3.545V    25.35mA    12.51mA    41.59mA
[Pullup]
-1.8V     2.903mA    2.423mA    4.111mA
-1.418V   6.594mA    4.711mA    12.64mA
-1.255V   12.69mA    7.42mA     33.23mA
-1.091V   30.4mA     13mA       58.71mA
-981.8mV  40.64mA    17.02mA    61.32mA
-818.2mV  35.38mA    18.12mA    50.59mA
272.7mV   -9.179mA   -4.728mA   -14.55mA
1.255V    -29.75mA   -15.09mA   -48.97mA
2.564V    -34.18mA   -16.32mA   -57.57mA
2.782V    -30.27mA   -15.51mA   -57.62mA
3.055V    -23.64mA   -14.69mA   -38.68mA
3.545V    -19.26mA   -13.56mA   -31.45mA
[GND_clamp]
-1.8V     -2.816A    -1.188A    -3.154A
-1.073V   -234.2mA   -137.3mA   -187.2mA
-1.036V   -158.1mA   -109.8mA   -103.1mA
-1V       -102.5mA   -86.97mA   -56.83mA
-963.6mV  -58.95mA   -66.55mA   -26.74mA
-927.3mV  -27.37mA   -48.49mA   -12.79mA
-890.9mV  -15.31mA   -35.02mA   -9.789mA
-854.5mV  -7.771mA   -23.73mA   -7.932mA
-818.2mV  -4.769mA   -14.63mA   -7.221mA
-709.1mV  -2.849mA   -3.058mA   -5.011mA
-527.3mV  -395.6uA   -259.7uA   -751.2uA
3.6V      0A         0A         0A
[Ramp]
dV/dt_f  0.6511569/3.384107n   0.3681818/8.889107n   0.8173119/1.258397n
dV/dt_r  0.6491532/4.093613n   0.3996933/9.575957n   0.8201219/2.050467n
R_load = 50
[Rising Waveform]
R_fixture = 50
V_fixture = 1.8
V_fixture_min = 1.62
V_fixture_max = 1.89
0s        720.1mV    1.011V     534.6mV
136ps     721.5mV    1.011V     650.4mV
296ps     741.2mV    1.01V      1.671V
368ps     882mV      1.011V     1.818V
464ps     1.252V     1.013V     1.868V
600ps     1.684V     1.001V     1.88V
800ps     1.786V     1.106V     1.882V
1.112ns   1.794V     1.489V     1.883V
1.304ns   1.795V     1.598V     1.884V
5.744ns   1.799V     1.618V     1.889V
[Rising Waveform]
R_fixture = 50
V_fixture = 0
V_fixture_min = 0
V_fixture_max = 0
0s        1.516mV    1.093mV    -5.369mV
840ps     1.212mV    -4.363mV   47.32mV
1.68ns    46.01mV    116.1uV    448.2mV
2.512ns   213.8mV    2.988mV    824.4mV
3.352ns   392.9mV    13.61mV    1.077V
4.48ns    603.2mV    57.42mV    1.211V
6.416ns   841.6mV    174.6mV    1.293V
12.64ns   1.026V     463.4mV    1.344V
20.97ns   1.062V     596.9mV    1.35V
61.08ns   1.069V     657.1mV    1.35V
[Falling Waveform]
R_fixture = 50
V_fixture = 1.8
V_fixture_min = 1.62
V_fixture_max = 1.89
0s        1.8V       1.62V      1.889V
624ps     1.803V     1.62V      1.887V
1.04ns    1.805V     1.62V      1.776V
1.872ns   1.772V     1.623V     1.121V
2.672ns   1.583V     1.624V     753.7mV
4.44ns    1.178V     1.599V     572.2mV
6.944ns   858.9mV    1.469V     538.6mV
10.63ns   748.9mV    1.28V      533mV
21.3ns    720.5mV    1.052V     532.6mV
44.27ns   720mV      1.012V     532.6mV
[Falling Waveform]
R_fixture = 50
V_fixture = 0
V_fixture_min = 0
V_fixture_max = 0
0s        1.069V     658.6mV    1.35V
472ps     1.074V     658.5mV    1.324V
784ps     1.056V     659.5mV    1.157V
936ps     1.027V     662.2mV    939.4mV
1.328ns   856.9mV    666.9mV    151.8mV
1.48ns    733.1mV    661.7mV    19.78mV
2.104ns   166.3mV    583mV      3.165mV
2.408ns   22.55mV    506.2mV    2.557mV
4.024ns   2.243mV    35.26mV    1.941mV
6.44ns    1.667mV    2.598mV    1.81mV
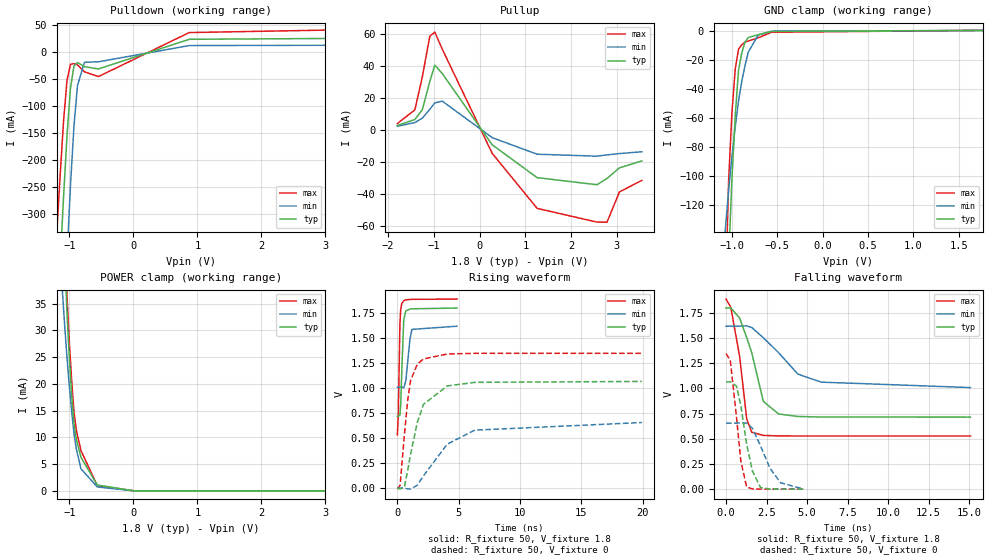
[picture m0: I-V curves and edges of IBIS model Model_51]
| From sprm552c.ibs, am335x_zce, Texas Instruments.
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| Model based on original model for OQ18SMART1FBPB_SSBHH
|   Sub model SBHH_HS01L10_PD1_1P8
[model]   Model_51
|[Description]  [1.8V-3-STATE-PD-S01:L10]
|   S01, L10,Weak internal pull-down, ,
|[Input Load]   PD
|[Output Drive] S01:L10
|Voltage   1.8V
|Mode   3-STATE
Model_type   3-state
Polarity   Non-Inverting
Enable   Active-Low
Cref =  15pF
Rref =  100.0000M
Vref =  0V
Vmeas =  0.9
C_comp   1.240965p   1.099743p   1.401226p
[Temperature Range]   25   125   -40
[Voltage Range]   1.8   1.62   1.89
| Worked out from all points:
|   slope of the pulldown table from 0 to 0.27 V, typ, clamps not added: 24.3 ohm
|   slope of the pullup table from 0 to 0.27 V, typ, clamps not added: 29.7 ohm
|   GND clamp passes 1 mA (typ) near -0.60 V on its own axis
|   POWER clamp passes 1 mA (typ) near -0.55 V on its own axis
|   rising waveform, R_fixture 50, V_fixture 1.8: 20-80 % time 170ps typ, 298ps min, 118ps max; typ from 0.716 V to 1.8 V
|   rising waveform, R_fixture 50, V_fixture 0: 20-80 % time 1.3ns typ, 2.91ns min, 689ps max; typ from 0 V to 1.06 V
|   falling waveform, R_fixture 50, V_fixture 1.8: 20-80 % time 1.09ns typ, 2.21ns min, 677ps max; typ from 1.8 V to 0.716 V
|   falling waveform, R_fixture 50, V_fixture 0: 20-80 % time 679ps typ, 1.12ns min, 498ps max; typ from 1.06 V to 0 V
[POWER_clamp]
-1.8V     360mA      189.8mA    409.4mA
-1.109V   56.22mA    37.38mA    59.76mA
-1.073V   44.22mA    30.95mA    47.31mA
-1.036V   33.15mA    24.83mA    36.24mA
-1V       24.78mA    19.56mA    27.83mA
-963.6mV  17.91mA    14.85mA    20.66mA
-927.3mV  12.54mA    10.7mA     14.72mA
-890.9mV  9.653mA    7.864mA    11.36mA
-818.2mV  6.28mA     4.131mA    7.54mA
-563.6mV  1.102mA    739.4uA    992.8uA
18.18mV   0A         0A         0A
3.6V      0A         0A         0A
[Pulldown]
-1.8V     -1.72A     -2.612A    -1.411A
-1.2V     -528.3mA   -845.3mA   -342.5mA
-1.145V   -396.8mA   -683.8mA   -231.2mA
-1.091V   -269.6mA   -527.2mA   -129mA
-1.036V   -154.1mA   -379.3mA   -51.85mA
-981.8mV  -66.54mA   -245.9mA   -22.8mA
-927.3mV  -26.05mA   -136.4mA   -21.6mA
-872.7mV  -19.36mA   -62.04mA   -23.73mA
-763.6mV  -27.2mA    -19.06mA   -36.72mA
-545.5mV  -31.39mA   -18.17mA   -45.46mA
872.7mV   23.46mA    11.88mA    35.92mA
3.545V    25.35mA    12.51mA    41.59mA
[Pullup]
-1.8V     2.903mA    2.423mA    4.111mA
-1.418V   6.594mA    4.711mA    12.64mA
-1.255V   12.69mA    7.42mA     33.23mA
-1.091V   30.4mA     13mA       58.71mA
-981.8mV  40.64mA    17.02mA    61.32mA
-818.2mV  35.38mA    18.12mA    50.59mA
272.7mV   -9.18mA    -4.728mA   -14.55mA
1.255V    -29.75mA   -15.09mA   -48.97mA
2.564V    -34.18mA   -16.32mA   -57.57mA
2.782V    -30.27mA   -15.51mA   -57.62mA
3.055V    -23.64mA   -14.69mA   -38.68mA
3.545V    -19.26mA   -13.56mA   -31.45mA
[GND_clamp]
-1.8V     -2.816A    -1.188A    -3.154A
-1.073V   -234.2mA   -137.3mA   -187.2mA
-1.036V   -158.1mA   -109.8mA   -103.1mA
-1V       -102.5mA   -86.97mA   -56.82mA
-963.6mV  -58.95mA   -66.55mA   -26.72mA
-927.3mV  -27.37mA   -48.49mA   -12.78mA
-890.9mV  -15.3mA    -35.02mA   -9.769mA
-854.5mV  -7.767mA   -23.73mA   -7.908mA
-818.2mV  -4.764mA   -14.63mA   -7.195mA
-709.1mV  -2.84mA    -3.059mA   -4.978mA
-563.6mV  -632.1uA   -435.2uA   -1.184mA
1.764V    97.78uA    55.01uA    156.4uA
[Ramp]
dV/dt_f  0.6516079/1.090402n   0.3683201/2.228018n   0.8181833/0.6790387n
dV/dt_r  0.6495269/1.304952n   0.3998648/2.938727n   0.8210111/0.6900853n
R_load = 50
[Rising Waveform]
R_fixture = 50
V_fixture = 1.8
V_fixture_min = 1.62
V_fixture_max = 1.89
0s        715.6mV    1.007V     531.2mV
72ps      717.2mV    1.007V     722.8mV
208ps     728mV      1.007V     1.639V
272ps     836.6mV    1.008V     1.787V
368ps     1.198V     1.009V     1.847V
520ps     1.681V     999mV      1.872V
688ps     1.77V      1.073V     1.88V
1.024ns   1.788V     1.486V     1.884V
1.184ns   1.791V     1.585V     1.885V
4.864ns   1.798V     1.617V     1.888V
[Rising Waveform]
R_fixture = 50
V_fixture = 0
V_fixture_min = 0
V_fixture_max = 0
0s        72.76uV    127.1uV    -11.21mV
224ps     -9.443mV   -95.44uV   26.94mV
576ps     12.38mV    -2.901mV   537.1mV
848ps     179.4mV    -8.004mV   883.8mV
1.072ns   334mV      -10.41mV   1.071V
1.624ns   653.6mV    27.58mV    1.238V
2.128ns   836.1mV    121.7mV    1.29V
4.064ns   1.02V      438.9mV    1.339V
6.32ns    1.056V     578.6mV    1.346V
19.93ns   1.065V     654.4mV    1.346V
[Falling Waveform]
R_fixture = 50
V_fixture = 1.8
V_fixture_min = 1.62
V_fixture_max = 1.89
0s        1.798V     1.618V     1.888V
296ps     1.8V       1.619V     1.808V
840ps     1.7V       1.619V     1.32V
1.28ns    1.505V     1.621V     696.9mV
1.584ns   1.358V     1.606V     565.5mV
2.304ns   872mV      1.504V     534mV
3.248ns   746.7mV    1.355V     528.8mV
4.432ns   722mV      1.143V     528.2mV
5.872ns   716.6mV    1.063V     528.2mV
15.09ns   715.5mV    1.009V     528.2mV
[Falling Waveform]
R_fixture = 50
V_fixture = 0
V_fixture_min = 0
V_fixture_max = 0
0s        1.065V     655.9mV    1.347V
264ps     1.067V     656.1mV    1.28V
648ps     1.023V     656.1mV    714.8mV
920ps     827.4mV    658.8mV    275.4mV
1.272ns   449.1mV    656.3mV    22.44mV
1.632ns   179.6mV    605.9mV    1.621mV
2.136ns   15.29mV    427.3mV    189.2uV
2.712ns   1.326mV    209mV      20.03uV
3.368ns   283.9uV    63.61mV    2.309uV
4.776ns   39.02uV    1.646mV    104.9nV
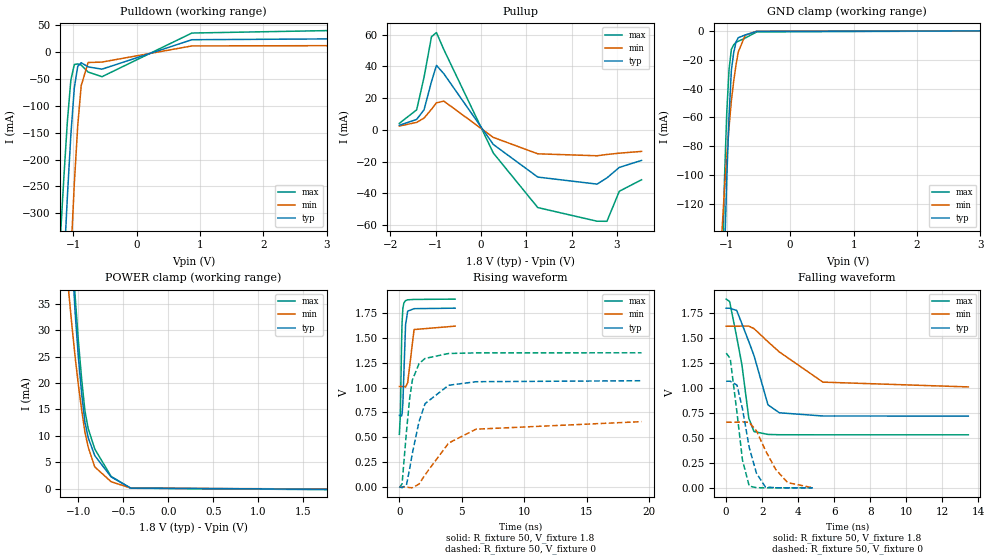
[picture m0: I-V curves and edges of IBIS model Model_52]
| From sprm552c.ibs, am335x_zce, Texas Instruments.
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| Model based on original model for OQ18SMART1FBPB_SSBHH
|   Sub model SBHH_HS11L11_PU1_1P8
[model]   Model_52
|[Description]  [1.8V-3-STATE-PU-S11:L11]
|   S11, L11,Weak internal pull-up, ,
|[Input Load]   PU
|[Output Drive] S11:L11
|Voltage   1.8V
|Mode   3-STATE
Model_type   3-state
Polarity   Non-Inverting
Enable   Active-Low
Cref =  15pF
Rref =  100.0000M
Vref =  0V
Vmeas =  0.9
C_comp   1.240965p   1.099743p   1.401226p
[Temperature Range]   25   125   -40
[Voltage Range]   1.8   1.62   1.89
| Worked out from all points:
|   slope of the pulldown table from 0 to 0.27 V, typ, clamps not added: 24.3 ohm
|   slope of the pullup table from 0 to 0.27 V, typ, clamps not added: 29.7 ohm
|   GND clamp passes 1 mA (typ) near -0.60 V on its own axis
|   POWER clamp passes 1 mA (typ) near -0.56 V on its own axis
|   rising waveform, R_fixture 50, V_fixture 1.8: 20-80 % time 168ps typ, 292ps min, 116ps max; typ from 0.72 V to 1.8 V
|   rising waveform, R_fixture 50, V_fixture 0: 20-80 % time 1.26ns typ, 2.83ns min, 668ps max; typ from 0.001 V to 1.07 V
|   falling waveform, R_fixture 50, V_fixture 1.8: 20-80 % time 1.12ns typ, 2.1ns min, 703ps max; typ from 1.8 V to 0.72 V
|   falling waveform, R_fixture 50, V_fixture 0: 20-80 % time 710ps typ, 1.16ns min, 519ps max; typ from 1.07 V to 0.001 V
[POWER_clamp]
-1.8V     360mA      189.8mA    409.4mA
-1.109V   56.23mA    37.39mA    59.78mA
-1.073V   44.23mA    30.96mA    47.33mA
-1.036V   33.16mA    24.83mA    36.25mA
-1V       24.78mA    19.56mA    27.84mA
-963.6mV  17.91mA    14.85mA    20.66mA
-927.3mV  12.54mA    10.7mA     14.72mA
-890.9mV  9.653mA    7.862mA    11.35mA
-818.2mV  6.273mA    4.126mA    7.524mA
-636.4mV  2.249mA    1.34mA     2.341mA
-418.2mV  128.7uA    129uA      104.8uA
1.764V    -96.73uA   -46.46uA   -163.5uA
[Pulldown]
-1.8V     -1.72A     -2.612A    -1.411A
-1.2V     -528.3mA   -845.3mA   -342.5mA
-1.145V   -396.8mA   -683.8mA   -231.2mA
-1.091V   -269.6mA   -527.2mA   -129mA
-1.036V   -154.1mA   -379.3mA   -51.85mA
-981.8mV  -66.54mA   -245.9mA   -22.8mA
-927.3mV  -26.05mA   -136.4mA   -21.6mA
-872.7mV  -19.36mA   -62.04mA   -23.73mA
-763.6mV  -27.2mA    -19.06mA   -36.72mA
-545.5mV  -31.39mA   -18.17mA   -45.46mA
872.7mV   23.46mA    11.88mA    35.92mA
3.545V    25.35mA    12.51mA    41.59mA
[Pullup]
-1.8V     2.903mA    2.423mA    4.111mA
-1.418V   6.594mA    4.711mA    12.64mA
-1.255V   12.69mA    7.42mA     33.23mA
-1.091V   30.4mA     13mA       58.71mA
-981.8mV  40.64mA    17.02mA    61.32mA
-818.2mV  35.38mA    18.12mA    50.59mA
272.7mV   -9.179mA   -4.728mA   -14.55mA
1.255V    -29.75mA   -15.09mA   -48.97mA
2.564V    -34.18mA   -16.32mA   -57.57mA
2.782V    -30.27mA   -15.51mA   -57.62mA
3.055V    -23.64mA   -14.69mA   -38.68mA
3.545V    -19.26mA   -13.56mA   -31.45mA
[GND_clamp]
-1.8V     -2.816A    -1.188A    -3.154A
-1.073V   -234.2mA   -137.3mA   -187.2mA
-1.036V   -158.1mA   -109.8mA   -103.1mA
-1V       -102.5mA   -86.97mA   -56.83mA
-963.6mV  -58.95mA   -66.55mA   -26.74mA
-927.3mV  -27.37mA   -48.49mA   -12.79mA
-890.9mV  -15.31mA   -35.02mA   -9.789mA
-854.5mV  -7.771mA   -23.73mA   -7.932mA
-818.2mV  -4.769mA   -14.63mA   -7.221mA
-709.1mV  -2.849mA   -3.058mA   -5.011mA
-527.3mV  -395.6uA   -259.7uA   -751.2uA
3.6V      0A         0A         0A
[Ramp]
dV/dt_f  0.6500365/1.124644n   0.3670724/2.115673n   0.8168397/0.7051882n
dV/dt_r  0.6492746/1.2639n   0.4002291/2.848392n   0.8195286/0.669243n
R_load = 50
[Rising Waveform]
R_fixture = 50
V_fixture = 1.8
V_fixture_min = 1.62
V_fixture_max = 1.89
0s        720mV      1.011V     529.8mV
80ps      721.5mV    1.011V     731.1mV
176ps     714.8mV    1.011V     1.446V
216ps     731.9mV    1.011V     1.653V
280ps     841.3mV    1.011V     1.798V
360ps     1.139V     1.012V     1.851V
496ps     1.632V     1.005V     1.875V
664ps     1.769V     1.048V     1.883V
1.176ns   1.794V     1.584V     1.887V
4.464ns   1.799V     1.618V     1.89V
[Rising Waveform]
R_fixture = 50
V_fixture = 0
V_fixture_min = 0
V_fixture_max = 0
0s        1.41mV     1.09mV     -9.186mV
216ps     -7.65mV    874.6uV    31.38mV
568ps     18.96mV    -1.49mV    557.5mV
824ps     184.3mV    -6.739mV   891.6mV
1.04ns    338.4mV    -8.206mV   1.076V
1.576ns   658.8mV    29.5mV     1.242V
2.056ns   838.1mV    122.3mV    1.293V
3.936ns   1.023V     441mV      1.343V
6.128ns   1.059V     581.2mV    1.349V
19.38ns   1.069V     657.1mV    1.35V
[Falling Waveform]
R_fixture = 50
V_fixture = 1.8
V_fixture_min = 1.62
V_fixture_max = 1.89
0s        1.8V       1.62V      1.891V
192ps     1.8V       1.62V      1.867V
584ps     1.778V     1.62V      1.512V
872ps     1.645V     1.621V     1.235V
1.256ns   1.466V     1.621V     697.9mV
1.544ns   1.326V     1.596V     564.9mV
2.32ns    832.7mV    1.464V     536.3mV
2.952ns   753.1mV    1.362V     533.3mV
5.368ns   721mV      1.06V      532.6mV
13.44ns   720mV      1.012V     532.6mV
[Falling Waveform]
R_fixture = 50
V_fixture = 0
V_fixture_min = 0
V_fixture_max = 0
0s        1.069V     658.6mV    1.35V
224ps     1.069V     658.8mV    1.298V
600ps     1.03V      658.7mV    754.2mV
904ps     792.7mV    661.2mV    279.2mV
1.28ns    405mV      657mV      18.8mV
1.68ns    147.8mV    572.8mV    3.066mV
2.176ns   10.89mV    377.2mV    1.921mV
2.744ns   2.599mV    186.9mV    1.787mV
3.416ns   1.629mV    53.34mV    1.774mV
4.8ns     1.422mV    2.597mV    1.773mV
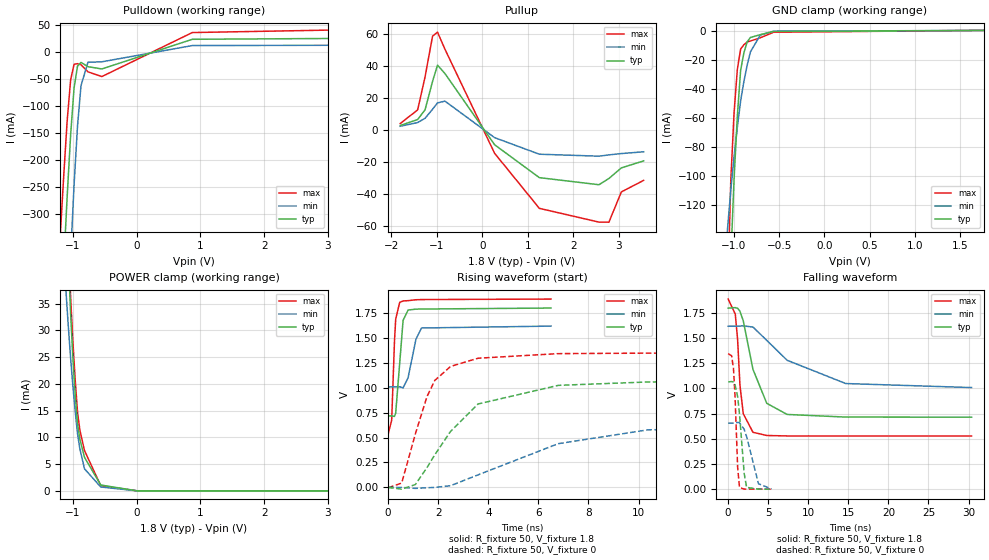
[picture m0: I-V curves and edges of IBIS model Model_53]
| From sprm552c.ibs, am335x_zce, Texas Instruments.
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| Model based on original model for OQ18SMART1FBPB_SSBHH
|   Sub model SBHH_HS00L11_PD1_1P8
[model]   Model_53
|[Description]  [1.8V-3-STATE-PD-S00:L11]
|   S00, L11,Weak internal pull-down, ,
|[Input Load]   PD
|[Output Drive] S00:L11
|Voltage   1.8V
|Mode   3-STATE
Model_type   3-state
Polarity   Non-Inverting
Enable   Active-Low
Cref =  15pF
Rref =  100.0000M
Vref =  0V
Vmeas =  0.9
C_comp   1.240965p   1.099743p   1.401226p
[Temperature Range]   25   125   -40
[Voltage Range]   1.8   1.62   1.89
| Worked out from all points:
|   slope of the pulldown table from 0 to 0.27 V, typ, clamps not added: 24.3 ohm
|   slope of the pullup table from 0 to 0.27 V, typ, clamps not added: 29.7 ohm
|   GND clamp passes 1 mA (typ) near -0.60 V on its own axis
|   POWER clamp passes 1 mA (typ) near -0.55 V on its own axis
|   rising waveform, R_fixture 50, V_fixture 1.8: 20-80 % time 172ps typ, 305ps min, 117ps max; typ from 0.716 V to 1.8 V
|   rising waveform, R_fixture 50, V_fixture 0: 20-80 % time 2.11ns typ, 4.83ns min, 1.08ns max; typ from 0 V to 1.06 V
|   falling waveform, R_fixture 50, V_fixture 1.8: 20-80 % time 2.08ns typ, 5.92ns min, 725ps max; typ from 1.8 V to 0.716 V
|   falling waveform, R_fixture 50, V_fixture 0: 20-80 % time 642ps typ, 1.17ns min, 381ps max; typ from 1.06 V to 0 V
[POWER_clamp]
-1.8V     360mA      189.8mA    409.4mA
-1.109V   56.22mA    37.38mA    59.76mA
-1.073V   44.22mA    30.95mA    47.31mA
-1.036V   33.15mA    24.83mA    36.24mA
-1V       24.78mA    19.56mA    27.83mA
-963.6mV  17.91mA    14.85mA    20.66mA
-927.3mV  12.54mA    10.7mA     14.72mA
-890.9mV  9.653mA    7.864mA    11.36mA
-818.2mV  6.28mA     4.131mA    7.54mA
-563.6mV  1.102mA    739.4uA    992.8uA
18.18mV   0A         0A         0A
3.6V      0A         0A         0A
[Pulldown]
-1.8V     -1.72A     -2.612A    -1.411A
-1.2V     -528.3mA   -845.3mA   -342.5mA
-1.145V   -396.8mA   -683.8mA   -231.2mA
-1.091V   -269.6mA   -527.2mA   -129mA
-1.036V   -154.1mA   -379.3mA   -51.85mA
-981.8mV  -66.54mA   -245.9mA   -22.8mA
-927.3mV  -26.05mA   -136.4mA   -21.6mA
-872.7mV  -19.36mA   -62.04mA   -23.73mA
-763.6mV  -27.2mA    -19.06mA   -36.72mA
-545.5mV  -31.39mA   -18.17mA   -45.46mA
872.7mV   23.46mA    11.88mA    35.92mA
3.545V    25.35mA    12.51mA    41.59mA
[Pullup]
-1.8V     2.903mA    2.423mA    4.111mA
-1.418V   6.594mA    4.711mA    12.64mA
-1.255V   12.69mA    7.42mA     33.23mA
-1.091V   30.4mA     13mA       58.71mA
-981.8mV  40.64mA    17.02mA    61.32mA
-818.2mV  35.38mA    18.12mA    50.59mA
272.7mV   -9.18mA    -4.728mA   -14.55mA
1.255V    -29.75mA   -15.09mA   -48.97mA
2.564V    -34.18mA   -16.32mA   -57.57mA
2.782V    -30.27mA   -15.51mA   -57.62mA
3.055V    -23.64mA   -14.69mA   -38.68mA
3.545V    -19.26mA   -13.56mA   -31.45mA
[GND_clamp]
-1.8V     -2.816A    -1.188A    -3.154A
-1.073V   -234.2mA   -137.3mA   -187.2mA
-1.036V   -158.1mA   -109.8mA   -103.1mA
-1V       -102.5mA   -86.97mA   -56.82mA
-963.6mV  -58.95mA   -66.55mA   -26.72mA
-927.3mV  -27.37mA   -48.49mA   -12.78mA
-890.9mV  -15.3mA    -35.02mA   -9.769mA
-854.5mV  -7.767mA   -23.73mA   -7.908mA
-818.2mV  -4.764mA   -14.63mA   -7.195mA
-709.1mV  -2.84mA    -3.059mA   -4.978mA
-563.6mV  -632.1uA   -435.2uA   -1.184mA
1.764V    97.78uA    55.01uA    156.4uA
[Ramp]
dV/dt_f  0.6523604/2.084058n   0.3691871/5.960818n   0.8184032/0.723861n
dV/dt_r  0.6505971/2.120816n   0.399992/4.872107n   0.8232723/1.082038n
R_load = 50
[Rising Waveform]
R_fixture = 50
V_fixture = 1.8
V_fixture_min = 1.62
V_fixture_max = 1.89
0s        715.7mV    1.007V     530.1mV
144ps     717.3mV    1.007V     673.4mV
256ps     711.8mV    1.007V     1.463V
304ps     744.2mV    1.007V     1.686V
464ps     1.245V     1.009V     1.855V
600ps     1.675V     997.8mV    1.869V
800ps     1.778V     1.1V       1.872V
1.112ns   1.787V     1.485V     1.881V
1.336ns   1.788V     1.598V     1.883V
6.504ns   1.798V     1.617V     1.888V
[Rising Waveform]
R_fixture = 50
V_fixture = 0
V_fixture_min = 0
V_fixture_max = 0
0s        -58.57uV   105uV      -3.805mV
544ps     -17.55mV   131.4uV    43.78mV
1.088ns   28.72mV    -9.774mV   534.9mV
1.552ns   198.1mV    -3.343mV   909.2mV
1.864ns   326.7mV    -435.1uV   1.072V
2.496ns   562.1mV    17.27mV    1.213V
3.592ns   836.3mV    125.9mV    1.295V
6.792ns   1.023V     438.5mV    1.341V
10.38ns   1.057V     577.4mV    1.346V
31.52ns   1.065V     654.4mV    1.346V
[Falling Waveform]
R_fixture = 50
V_fixture = 1.8
V_fixture_min = 1.62
V_fixture_max = 1.89
0s        1.798V     1.618V     1.888V
888ps     1.803V     1.618V     1.739V
1.176ns   1.797V     1.619V     1.491V
1.472ns   1.767V     1.62V      1.033V
1.888ns   1.672V     1.622V     749mV
3.096ns   1.19V      1.61V      564.8mV
4.816ns   852.7mV    1.478V     533.2mV
7.36ns    742.1mV    1.28V      528.5mV
14.68ns   715.9mV    1.049V     528.2mV
30.38ns   715.5mV    1.009V     528.2mV
[Falling Waveform]
R_fixture = 50
V_fixture = 0
V_fixture_min = 0
V_fixture_max = 0
0s        1.065V     655.9mV    1.346V
432ps     1.069V     655.9mV    1.325V
664ps     1.064V     655.9mV    1.199V
856ps     1.037V     657.7mV    932.4mV
1.184ns   920.4mV    663.1mV    214.4mV
1.416ns   745.3mV    659.5mV    16.81mV
2ns       155.7mV    594.1mV    851.2uV
2.304ns   17.87mV    522.3mV    361.8uV
3.784ns   400.6uV    53.8mV     44.09uV
5.424ns   131.7uV    1.634mV    9.454uV
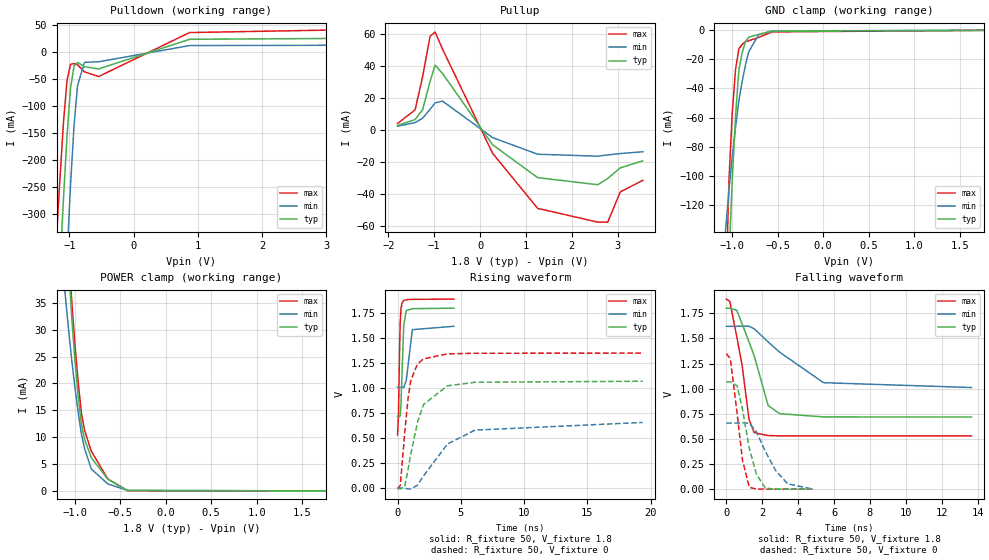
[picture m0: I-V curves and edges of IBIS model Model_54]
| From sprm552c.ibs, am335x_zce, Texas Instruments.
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| Model based on original model for OQ18SMART1FBPB_SSBHH
|   Sub model HH_HS11L10_PUPD0_1P8
[model]   Model_54
|[Description]  [1.8V-3-STATE-PI-S11:L10]
|   S11, L10,Weak pull up/down disabled, ,
|[Input Load]   PI
|[Output Drive] S11:L10
|Voltage   1.8V
|Mode   3-STATE
Model_type   3-state
Polarity   Non-Inverting
Enable   Active-Low
Cref =  15pF
Rref =  100.0000M
Vref =  0V
Vmeas =  0.9
C_comp   1.240965p   1.099743p   1.401226p
[Temperature Range]   25   125   -40
[Voltage Range]   1.8   1.62   1.89
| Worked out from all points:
|   slope of the pulldown table from 0 to 0.27 V, typ, clamps not added: 24.3 ohm
|   slope of the pullup table from 0 to 0.27 V, typ, clamps not added: 29.7 ohm
|   GND clamp passes 1 mA (typ) near -0.60 V on its own axis
|   POWER clamp passes 1 mA (typ) near -0.56 V on its own axis
|   rising waveform, R_fixture 50, V_fixture 1.8: 20-80 % time 169ps typ, 294ps min, 117ps max; typ from 0.718 V to 1.8 V
|   rising waveform, R_fixture 50, V_fixture 0: 20-80 % time 1.26ns typ, 2.83ns min, 670ps max; typ from 0 V to 1.07 V
|   falling waveform, R_fixture 50, V_fixture 1.8: 20-80 % time 1.12ns typ, 2.12ns min, 706ps max; typ from 1.8 V to 0.718 V
|   falling waveform, R_fixture 50, V_fixture 0: 20-80 % time 714ps typ, 1.17ns min, 523ps max; typ from 1.07 V to 0 V
[POWER_clamp]
-1.8V     360mA      189.8mA    409.4mA
-1.109V   56.16mA    37.36mA    59.65mA
-1.073V   44.16mA    30.93mA    47.2mA
-1.036V   33.09mA    24.8mA     36.11mA
-1V       24.71mA    19.53mA    27.71mA
-963.6mV  17.83mA    14.82mA    20.53mA
-927.3mV  12.46mA    10.66mA    14.59mA
-890.9mV  9.571mA    7.827mA    11.23mA
-818.2mV  6.195mA    4.088mA    7.402mA
-636.4mV  2.183mA    1.306mA    2.238mA
-418.2mV  83.85uA    105.2uA    35.14uA
1.764V    -1.213nA   -79.04nA   -1.357nA
[Pulldown]
-1.8V     -1.72A     -2.612A    -1.411A
-1.2V     -528.3mA   -845.3mA   -342.5mA
-1.145V   -396.8mA   -683.8mA   -231.2mA
-1.091V   -269.6mA   -527.2mA   -129mA
-1.036V   -154.1mA   -379.3mA   -51.86mA
-981.8mV  -66.54mA   -245.9mA   -22.8mA
-927.3mV  -26.05mA   -136.4mA   -21.6mA
-872.7mV  -19.36mA   -62.04mA   -23.73mA
-763.6mV  -27.2mA    -19.06mA   -36.72mA
-545.5mV  -31.39mA   -18.17mA   -45.46mA
872.7mV   23.46mA    11.88mA    35.92mA
3.545V    25.35mA    12.51mA    41.59mA
[Pullup]
-1.8V     2.903mA    2.423mA    4.111mA
-1.418V   6.594mA    4.711mA    12.64mA
-1.255V   12.68mA    7.42mA     33.22mA
-1.091V   30.4mA     13mA       58.7mA
-981.8mV  40.64mA    17.02mA    61.32mA
-818.2mV  35.38mA    18.12mA    50.59mA
272.7mV   -9.18mA    -4.728mA   -14.55mA
1.255V    -29.75mA   -15.09mA   -48.97mA
2.564V    -34.18mA   -16.32mA   -57.57mA
2.782V    -30.27mA   -15.51mA   -57.62mA
3.055V    -23.64mA   -14.69mA   -38.68mA
3.545V    -19.26mA   -13.56mA   -31.45mA
[GND_clamp]
-1.8V     -2.816A    -1.188A    -3.154A
-1.073V   -234.1mA   -137.3mA   -187.2mA
-1.036V   -158.1mA   -109.8mA   -103mA
-1V       -102.5mA   -86.96mA   -56.78mA
-963.6mV  -58.91mA   -66.54mA   -26.67mA
-927.3mV  -27.33mA   -48.47mA   -12.72mA
-890.9mV  -15.25mA   -35mA      -9.693mA
-854.5mV  -7.712mA   -23.72mA   -7.821mA
-818.2mV  -4.703mA   -14.61mA   -7.099mA
-709.1mV  -2.775mA   -3.029mA   -4.882mA
-563.6mV  -570.1uA   -403.1uA   -1.092mA
1.764V    -22.35pA   583.3nA    2.874nA
[Ramp]
dV/dt_f  0.6514816/1.127528n   0.3678387/2.128606n   0.8185518/0.7080754n
dV/dt_r   0.650199/1.266845n   0.400461/2.851714n   0.8213877/0.6707932n
R_load = 50
[Rising Waveform]
R_fixture = 50
V_fixture = 1.8
V_fixture_min = 1.62
V_fixture_max = 1.89
0s        717.7mV    1.009V     532.3mV
72ps      719.2mV    1.009V     728.2mV
168ps     712.2mV    1.009V     1.439V
208ps     729.8mV    1.009V     1.646V
272ps     840.8mV    1.01V      1.795V
352ps     1.137V     1.011V     1.849V
488ps     1.63V      1.004V     1.875V
688ps     1.774V     1.076V     1.884V
1.168ns   1.794V     1.584V     1.887V
4.456ns   1.799V     1.618V     1.89V
[Rising Waveform]
R_fixture = 50
V_fixture = 0
V_fixture_min = 0
V_fixture_max = 0
0s        20.29uV    125.7uV    -11.09mV
216ps     -9.217mV   -91.19uV   27.37mV
568ps     16.57mV    -2.685mV   554.6mV
824ps     183.4mV    -7.777mV   888.7mV
1.04ns    337.3mV    -9.818mV   1.074V
1.576ns   656.9mV    28.88mV    1.24V
2.056ns   836.2mV    122.4mV    1.292V
3.936ns   1.022V     439.9mV    1.342V
6.128ns   1.058V     579.8mV    1.348V
19.38ns   1.068V     655.8mV    1.349V
[Falling Waveform]
R_fixture = 50
V_fixture = 1.8
V_fixture_min = 1.62
V_fixture_max = 1.89
0s        1.8V       1.62V      1.891V
192ps     1.8V       1.62V      1.868V
584ps     1.779V     1.62V      1.515V
880ps     1.644V     1.621V     1.231V
1.264ns   1.466V     1.621V     694.8mV
1.552ns   1.327V     1.596V     562.1mV
2.328ns   832.2mV    1.465V     533.5mV
2.968ns   751.1mV    1.363V     530.5mV
5.416ns   718.6mV    1.059V     529.8mV
13.66ns   717.6mV    1.011V     529.8mV
[Falling Waveform]
R_fixture = 50
V_fixture = 0
V_fixture_min = 0
V_fixture_max = 0
0s        1.067V     657.2mV    1.349V
224ps     1.068V     657.5mV    1.297V
600ps     1.028V     657.3mV    754.9mV
904ps     791.6mV    659.9mV    282.3mV
1.28ns    406.1mV    655mV      18.82mV
1.68ns    148.5mV    569.9mV    1.307mV
2.176ns   10.08mV    375.2mV    148.1uV
2.744ns   1.211mV    186.7mV    13.96uV
3.416ns   241uV      53.27mV    1.191uV
4.8ns     35uV       1.633mV    65.04nV
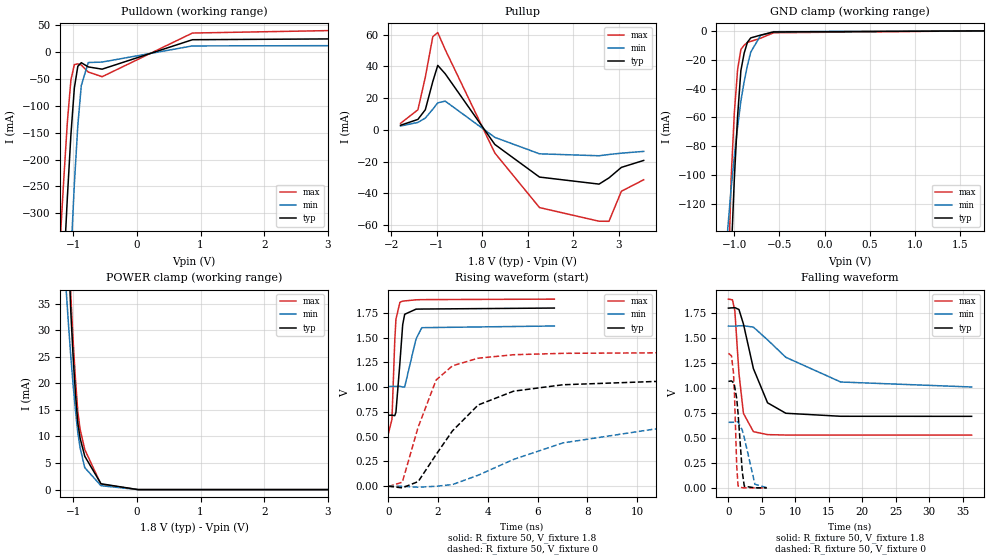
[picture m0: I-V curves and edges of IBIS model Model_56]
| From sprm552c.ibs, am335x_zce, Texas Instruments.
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| Model based on original model for OQ18SMART1FBPB_SSBHH
|   Sub model SBHH_HS00L10_PD1_1P8
[model]   Model_56
|[Description]  [1.8V-3-STATE-PD-S00:L10]
|   S00, L10,Weak internal pull-down, ,
|[Input Load]   PD
|[Output Drive] S00:L10
|Voltage   1.8V
|Mode   3-STATE
Model_type   3-state
Polarity   Non-Inverting
Enable   Active-Low
Cref =  15pF
Rref =  100.0000M
Vref =  0V
Vmeas =  0.9
C_comp   1.240965p   1.099743p   1.401226p
[Temperature Range]   25   125   -40
[Voltage Range]   1.8   1.62   1.89
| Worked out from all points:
|   slope of the pulldown table from 0 to 0.27 V, typ, clamps not added: 24.3 ohm
|   slope of the pullup table from 0 to 0.27 V, typ, clamps not added: 29.7 ohm
|   GND clamp passes 1 mA (typ) near -0.60 V on its own axis
|   POWER clamp passes 1 mA (typ) near -0.55 V on its own axis
|   rising waveform, R_fixture 50, V_fixture 1.8: 20-80 % time 172ps typ, 307ps min, 118ps max; typ from 0.716 V to 1.8 V
|   rising waveform, R_fixture 50, V_fixture 0: 20-80 % time 2.17ns typ, 4.97ns min, 1.1ns max; typ from 0 V to 1.06 V
|   falling waveform, R_fixture 50, V_fixture 1.8: 20-80 % time 2.7ns typ, 7.23ns min, 935ps max; typ from 1.8 V to 0.716 V
|   falling waveform, R_fixture 50, V_fixture 0: 20-80 % time 698ps typ, 1.22ns min, 394ps max; typ from 1.06 V to 0 V
[POWER_clamp]
-1.8V     360mA      189.8mA    409.4mA
-1.109V   56.22mA    37.38mA    59.76mA
-1.073V   44.22mA    30.95mA    47.31mA
-1.036V   33.15mA    24.83mA    36.24mA
-1V       24.78mA    19.56mA    27.83mA
-963.6mV  17.91mA    14.85mA    20.66mA
-927.3mV  12.54mA    10.7mA     14.72mA
-890.9mV  9.653mA    7.864mA    11.36mA
-818.2mV  6.28mA     4.131mA    7.54mA
-563.6mV  1.102mA    739.4uA    992.8uA
18.18mV   0A         0A         0A
3.6V      0A         0A         0A
[Pulldown]
-1.8V     -1.72A     -2.612A    -1.411A
-1.2V     -528.3mA   -845.3mA   -342.5mA
-1.145V   -396.8mA   -683.8mA   -231.2mA
-1.091V   -269.6mA   -527.2mA   -129mA
-1.036V   -154.1mA   -379.3mA   -51.85mA
-981.8mV  -66.54mA   -245.9mA   -22.8mA
-927.3mV  -26.05mA   -136.4mA   -21.6mA
-872.7mV  -19.36mA   -62.04mA   -23.73mA
-763.6mV  -27.2mA    -19.06mA   -36.72mA
-545.5mV  -31.39mA   -18.17mA   -45.46mA
872.7mV   23.46mA    11.88mA    35.92mA
3.545V    25.35mA    12.51mA    41.59mA
[Pullup]
-1.8V     2.903mA    2.423mA    4.111mA
-1.418V   6.594mA    4.711mA    12.64mA
-1.255V   12.69mA    7.42mA     33.23mA
-1.091V   30.4mA     13mA       58.71mA
-981.8mV  40.64mA    17.02mA    61.32mA
-818.2mV  35.38mA    18.12mA    50.59mA
272.7mV   -9.18mA    -4.728mA   -14.55mA
1.255V    -29.75mA   -15.09mA   -48.97mA
2.564V    -34.18mA   -16.32mA   -57.57mA
2.782V    -30.27mA   -15.51mA   -57.62mA
3.055V    -23.64mA   -14.69mA   -38.68mA
3.545V    -19.26mA   -13.56mA   -31.45mA
[GND_clamp]
-1.8V     -2.816A    -1.188A    -3.154A
-1.073V   -234.2mA   -137.3mA   -187.2mA
-1.036V   -158.1mA   -109.8mA   -103.1mA
-1V       -102.5mA   -86.97mA   -56.82mA
-963.6mV  -58.95mA   -66.55mA   -26.72mA
-927.3mV  -27.37mA   -48.49mA   -12.78mA
-890.9mV  -15.3mA    -35.02mA   -9.769mA
-854.5mV  -7.767mA   -23.73mA   -7.908mA
-818.2mV  -4.764mA   -14.63mA   -7.195mA
-709.1mV  -2.84mA    -3.059mA   -4.978mA
-563.6mV  -632.1uA   -435.2uA   -1.184mA
1.764V    97.78uA    55.01uA    156.4uA
[Ramp]
dV/dt_f  0.6525215/2.699249n   0.3692779/7.291983n   0.8186629/0.9305011n
dV/dt_r  0.6503966/2.181n   0.3998744/5.015367n   0.8230194/1.107344n
R_load = 50
[Rising Waveform]
R_fixture = 50
V_fixture = 1.8
V_fixture_min = 1.62
V_fixture_max = 1.89
0s        715.7mV    1.007V     530.2mV
144ps     717.3mV    1.007V     675mV
256ps     712mV      1.007V     1.461V
304ps     745.4mV    1.007V     1.685V
464ps     1.246V     1.009V     1.856V
576ps     1.63V      1V         1.868V
656ps     1.735V     1.003V     1.87V
1.112ns   1.787V     1.486V     1.881V
1.344ns   1.788V     1.6V       1.883V
6.672ns   1.798V     1.617V     1.888V
[Rising Waveform]
R_fixture = 50
V_fixture = 0
V_fixture_min = 0
V_fixture_max = 0
0s        -59.43uV   105.4uV    -3.93mV
560ps     -16.32mV   -308.9uV   41.17mV
1.2ns     47.19mV    -9.999mV   597.8mV
1.92ns    320.5mV    -225.1uV   1.072V
2.576ns   558.4mV    16.78mV    1.215V
3.608ns   819.7mV    111.1mV    1.292V
5.032ns   959.1mV    270.6mV    1.327V
7.016ns   1.024V     437.1mV    1.341V
10.7ns    1.057V     577.1mV    1.346V
32.32ns   1.065V     654.4mV    1.346V
[Falling Waveform]
R_fixture = 50
V_fixture = 1.8
V_fixture_min = 1.62
V_fixture_max = 1.89
0s        1.798V     1.618V     1.888V
608ps     1.801V     1.618V     1.881V
960ps     1.803V     1.618V     1.768V
1.568ns   1.784V     1.621V     1.146V
2.24ns    1.639V     1.622V     745.1mV
3.728ns   1.193V     1.608V     562.2mV
5.84ns    851mV      1.481V     532.5mV
8.568ns   746.3mV    1.306V     528.5mV
16.77ns   716.1mV    1.059V     528.2mV
36.31ns   715.5mV    1.009V     528.2mV
[Falling Waveform]
R_fixture = 50
V_fixture = 0
V_fixture_min = 0
V_fixture_max = 0
0s        1.065V     655.9mV    1.346V
448ps     1.07V      655.8mV    1.321V
752ps     1.052V     656.5mV    1.154V
904ps     1.023V     658.6mV    931.6mV
1.24ns    892.5mV    663mV      213.7mV
1.44ns    742.4mV    657.2mV    18.28mV
2.064ns   162mV      577.4mV    833.2uV
2.368ns   16.79mV    501.5mV    397.4uV
3.952ns   415.4uV    36.52mV    63.06uV
5.72ns    161.4uV    1.636mV    16uV
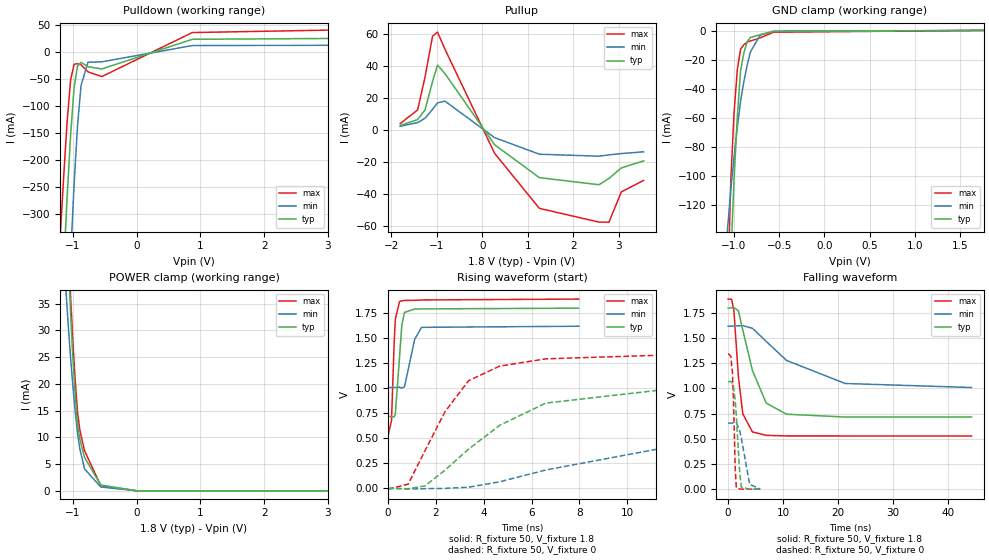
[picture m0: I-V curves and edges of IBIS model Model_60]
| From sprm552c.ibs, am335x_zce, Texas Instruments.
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| Model based on original model for OQ18SMART1FBPB_SSBHH
|   Sub model SBHH_HS00L01_PD1_1P8
[model]   Model_60
|[Description]  [1.8V-3-STATE-PD-S00:L01]
|   S00, L01,Weak internal pull-down, ,
|[Input Load]   PD
|[Output Drive] S00:L01
|Voltage   1.8V
|Mode   3-STATE
Model_type   3-state
Polarity   Non-Inverting
Enable   Active-Low
Cref =  15pF
Rref =  100.0000M
Vref =  0V
Vmeas =  0.9
C_comp   1.240965p   1.099743p   1.401226p
[Temperature Range]   25   125   -40
[Voltage Range]   1.8   1.62   1.89
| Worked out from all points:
|   slope of the pulldown table from 0 to 0.27 V, typ, clamps not added: 24.3 ohm
|   slope of the pullup table from 0 to 0.27 V, typ, clamps not added: 29.7 ohm
|   GND clamp passes 1 mA (typ) near -0.60 V on its own axis
|   POWER clamp passes 1 mA (typ) near -0.55 V on its own axis
|   rising waveform, R_fixture 50, V_fixture 1.8: 20-80 % time 172ps typ, 310ps min, 117ps max; typ from 0.716 V to 1.8 V
|   rising waveform, R_fixture 50, V_fixture 0: 20-80 % time 4.1ns typ, 9.51ns min, 2.06ns max; typ from 0 V to 1.06 V
|   falling waveform, R_fixture 50, V_fixture 1.8: 20-80 % time 3.37ns typ, 8.81ns min, 1.25ns max; typ from 1.8 V to 0.716 V
|   falling waveform, R_fixture 50, V_fixture 0: 20-80 % time 708ps typ, 1.2ns min, 409ps max; typ from 1.06 V to 0 V
[POWER_clamp]
-1.8V     360mA      189.8mA    409.4mA
-1.109V   56.22mA    37.38mA    59.76mA
-1.073V   44.22mA    30.95mA    47.31mA
-1.036V   33.15mA    24.83mA    36.24mA
-1V       24.78mA    19.56mA    27.83mA
-963.6mV  17.91mA    14.85mA    20.66mA
-927.3mV  12.54mA    10.7mA     14.72mA
-890.9mV  9.653mA    7.864mA    11.36mA
-818.2mV  6.28mA     4.131mA    7.54mA
-563.6mV  1.102mA    739.4uA    992.8uA
18.18mV   0A         0A         0A
3.6V      0A         0A         0A
[Pulldown]
-1.8V     -1.72A     -2.612A    -1.411A
-1.2V     -528.3mA   -845.3mA   -342.5mA
-1.145V   -396.8mA   -683.8mA   -231.2mA
-1.091V   -269.6mA   -527.2mA   -129mA
-1.036V   -154.1mA   -379.3mA   -51.85mA
-981.8mV  -66.54mA   -245.9mA   -22.8mA
-927.3mV  -26.05mA   -136.4mA   -21.6mA
-872.7mV  -19.36mA   -62.04mA   -23.73mA
-763.6mV  -27.2mA    -19.06mA   -36.72mA
-545.5mV  -31.39mA   -18.17mA   -45.46mA
872.7mV   23.46mA    11.88mA    35.92mA
3.545V    25.35mA    12.51mA    41.59mA
[Pullup]
-1.8V     2.903mA    2.423mA    4.111mA
-1.418V   6.594mA    4.711mA    12.64mA
-1.255V   12.69mA    7.42mA     33.23mA
-1.091V   30.4mA     13mA       58.71mA
-981.8mV  40.64mA    17.02mA    61.32mA
-818.2mV  35.38mA    18.12mA    50.59mA
272.7mV   -9.18mA    -4.728mA   -14.55mA
1.255V    -29.75mA   -15.09mA   -48.97mA
2.564V    -34.18mA   -16.32mA   -57.57mA
2.782V    -30.27mA   -15.51mA   -57.62mA
3.055V    -23.64mA   -14.69mA   -38.68mA
3.545V    -19.26mA   -13.56mA   -31.45mA
[GND_clamp]
-1.8V     -2.816A    -1.188A    -3.154A
-1.073V   -234.2mA   -137.3mA   -187.2mA
-1.036V   -158.1mA   -109.8mA   -103.1mA
-1V       -102.5mA   -86.97mA   -56.82mA
-963.6mV  -58.95mA   -66.55mA   -26.72mA
-927.3mV  -27.37mA   -48.49mA   -12.78mA
-890.9mV  -15.3mA    -35.02mA   -9.769mA
-854.5mV  -7.767mA   -23.73mA   -7.908mA
-818.2mV  -4.764mA   -14.63mA   -7.195mA
-709.1mV  -2.84mA    -3.059mA   -4.978mA
-563.6mV  -632.1uA   -435.2uA   -1.184mA
1.764V    97.78uA    55.01uA    156.4uA
[Ramp]
dV/dt_f  0.6526995/3.370388n   0.3693664/8.886454n   0.8187024/1.246644n
dV/dt_r  0.6492296/4.11059n   0.3992695/9.593531n   0.8214829/2.063188n
R_load = 50
[Rising Waveform]
R_fixture = 50
V_fixture = 1.8
V_fixture_min = 1.62
V_fixture_max = 1.89
0s        715.7mV    1.007V     530.2mV
144ps     717.4mV    1.007V     675.3mV
256ps     712.1mV    1.007V     1.461V
304ps     745.4mV    1.007V     1.688V
480ps     1.311V     1.009V     1.863V
576ps     1.631V     1V         1.871V
688ps     1.755V     1.014V     1.874V
1.112ns   1.789V     1.486V     1.876V
1.4ns     1.79V      1.606V     1.879V
7.976ns   1.797V     1.617V     1.888V
[Rising Waveform]
R_fixture = 50
V_fixture = 0
V_fixture_min = 0
V_fixture_max = 0
0s        244.8uV    127.9uV    -7.761mV
840ps     -3.458mV   -5.651mV   42.19mV
1.544ns   24.8mV     -2.907mV   376mV
2.384ns   182.3mV    116.9uV    765.5mV
3.368ns   392mV      11.92mV    1.074V
4.664ns   628.3mV    65.52mV    1.219V
6.6ns     850.8mV    183.8mV    1.292V
13.1ns    1.027V     473.6mV    1.341V
20.99ns   1.058V     594.3mV    1.346V
61.09ns   1.065V     654.4mV    1.346V
[Falling Waveform]
R_fixture = 50
V_fixture = 1.8
V_fixture_min = 1.62
V_fixture_max = 1.89
0s        1.798V     1.618V     1.887V
624ps     1.801V     1.618V     1.885V
1.04ns    1.803V     1.619V     1.773V
1.864ns   1.77V      1.622V     1.116V
2.664ns   1.579V     1.623V     747.3mV
4.416ns   1.177V     1.597V     567.8mV
6.92ns    854.4mV    1.467V     534.2mV
10.61ns   744.3mV    1.278V     528.6mV
21.28ns   716mV      1.049V     528.2mV
44.27ns   715.5mV    1.009V     528.2mV
[Falling Waveform]
R_fixture = 50
V_fixture = 0
V_fixture_min = 0
V_fixture_max = 0
0s        1.065V     655.9mV    1.346V
472ps     1.071V     655.8mV    1.32V
784ps     1.052V     656.8mV    1.151V
936ps     1.023V     659.5mV    930.8mV
1.288ns   877.8mV    664.7mV    207.7mV
1.48ns    726.2mV    659mV      15.22mV
2.096ns   165.6mV    581.6mV    861.3uV
2.4ns     19.16mV    505.1mV    427.8uV
3.912ns   478uV      47.99mV    100.2uV
5.84ns    181.4uV    1.637mV    31.21uV
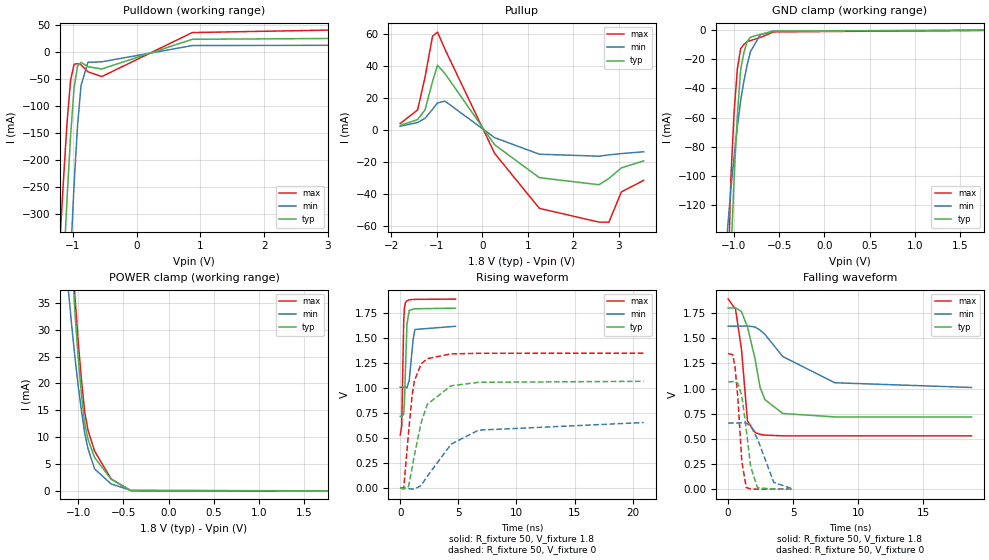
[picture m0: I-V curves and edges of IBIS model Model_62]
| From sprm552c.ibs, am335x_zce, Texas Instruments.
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| Model based on original model for OQ18SMART1FBPB_SSBHH
|   Sub model HH_HS10L00_PUPD0_1P8
[model]   Model_62
|[Description]  [1.8V-3-STATE-PI-S10:L00]
|   S10, L00,Weak pull up/down disabled, ,
|[Input Load]   PI
|[Output Drive] S10:L00
|Voltage   1.8V
|Mode   3-STATE
Model_type   3-state
Polarity   Non-Inverting
Enable   Active-Low
Cref =  15pF
Rref =  100.0000M
Vref =  0V
Vmeas =  0.9
C_comp   1.240965p   1.099743p   1.401226p
[Temperature Range]   25   125   -40
[Voltage Range]   1.8   1.62   1.89
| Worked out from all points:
|   slope of the pulldown table from 0 to 0.27 V, typ, clamps not added: 24.3 ohm
|   slope of the pullup table from 0 to 0.27 V, typ, clamps not added: 29.7 ohm
|   GND clamp passes 1 mA (typ) near -0.60 V on its own axis
|   POWER clamp passes 1 mA (typ) near -0.56 V on its own axis
|   rising waveform, R_fixture 50, V_fixture 1.8: 20-80 % time 172ps typ, 302ps min, 118ps max; typ from 0.718 V to 1.8 V
|   rising waveform, R_fixture 50, V_fixture 0: 20-80 % time 1.36ns typ, 3.05ns min, 715ps max; typ from 0 V to 1.07 V
|   falling waveform, R_fixture 50, V_fixture 1.8: 20-80 % time 1.1ns typ, 2.96ns min, 571ps max; typ from 1.8 V to 0.718 V
|   falling waveform, R_fixture 50, V_fixture 0: 20-80 % time 595ps typ, 1.04ns min, 412ps max; typ from 1.07 V to 0 V
[POWER_clamp]
-1.8V     360mA      189.8mA    409.4mA
-1.109V   56.16mA    37.36mA    59.65mA
-1.073V   44.16mA    30.93mA    47.2mA
-1.036V   33.09mA    24.8mA     36.11mA
-1V       24.71mA    19.53mA    27.71mA
-963.6mV  17.83mA    14.82mA    20.53mA
-927.3mV  12.46mA    10.66mA    14.59mA
-890.9mV  9.571mA    7.827mA    11.23mA
-818.2mV  6.195mA    4.088mA    7.402mA
-636.4mV  2.183mA    1.306mA    2.238mA
-418.2mV  83.85uA    105.2uA    35.14uA
1.764V    -1.213nA   -79.04nA   -1.357nA
[Pulldown]
-1.8V     -1.72A     -2.612A    -1.411A
-1.2V     -528.3mA   -845.3mA   -342.5mA
-1.145V   -396.8mA   -683.8mA   -231.2mA
-1.091V   -269.6mA   -527.2mA   -129mA
-1.036V   -154.1mA   -379.3mA   -51.86mA
-981.8mV  -66.54mA   -245.9mA   -22.8mA
-927.3mV  -26.05mA   -136.4mA   -21.6mA
-872.7mV  -19.36mA   -62.04mA   -23.73mA
-763.6mV  -27.2mA    -19.06mA   -36.72mA
-545.5mV  -31.39mA   -18.17mA   -45.46mA
872.7mV   23.46mA    11.88mA    35.92mA
3.545V    25.35mA    12.51mA    41.59mA
[Pullup]
-1.8V     2.903mA    2.423mA    4.111mA
-1.418V   6.594mA    4.711mA    12.64mA
-1.255V   12.68mA    7.42mA     33.22mA
-1.091V   30.4mA     13mA       58.7mA
-981.8mV  40.64mA    17.02mA    61.32mA
-818.2mV  35.38mA    18.12mA    50.59mA
272.7mV   -9.18mA    -4.728mA   -14.55mA
1.255V    -29.75mA   -15.09mA   -48.97mA
2.564V    -34.18mA   -16.32mA   -57.57mA
2.782V    -30.27mA   -15.51mA   -57.62mA
3.055V    -23.64mA   -14.69mA   -38.68mA
3.545V    -19.26mA   -13.56mA   -31.45mA
[GND_clamp]
-1.8V     -2.816A    -1.188A    -3.154A
-1.073V   -234.1mA   -137.3mA   -187.2mA
-1.036V   -158.1mA   -109.8mA   -103mA
-1V       -102.5mA   -86.96mA   -56.78mA
-963.6mV  -58.91mA   -66.54mA   -26.67mA
-927.3mV  -27.33mA   -48.47mA   -12.72mA
-890.9mV  -15.25mA   -35mA      -9.693mA
-854.5mV  -7.712mA   -23.72mA   -7.821mA
-818.2mV  -4.703mA   -14.61mA   -7.099mA
-709.1mV  -2.775mA   -3.029mA   -4.882mA
-563.6mV  -570.1uA   -403.1uA   -1.092mA
1.764V    -22.34pA   583.3nA    2.874nA
[Ramp]
dV/dt_f  0.6515392/1.103567n   0.3680899/2.983128n   0.8184389/0.5731588n
dV/dt_r  0.6513386/1.362011n   0.4008387/3.078163n   0.8234872/0.7180177n
R_load = 50
[Rising Waveform]
R_fixture = 50
V_fixture = 1.8
V_fixture_min = 1.62
V_fixture_max = 1.89
0s        717.8mV    1.009V     531.7mV
128ps     718.7mV    1.009V     618.9mV
296ps     737.6mV    1.009V     1.661V
360ps     856.6mV    1.01V      1.798V
440ps     1.152V     1.011V     1.852V
576ps     1.634V     1.002V     1.873V
768ps     1.774V     1.074V     1.883V
1.112ns   1.791V     1.489V     1.886V
1.264ns   1.793V     1.586V     1.887V
4.752ns   1.799V     1.618V     1.89V
[Rising Waveform]
R_fixture = 50
V_fixture = 0
V_fixture_min = 0
V_fixture_max = 0
0s        29.13uV    66.74uV    -433.4uV
304ps     -8.604mV   -106.7uV   4.729mV
712ps     17.41mV    -4.116mV   553.7mV
1.016ns   197.8mV    -8.66mV    919mV
1.216ns   329.6mV    -10.12mV   1.073V
1.8ns     655mV      26.45mV    1.242V
2.328ns   838.4mV    119mV      1.294V
4.368ns   1.023V     439.3mV    1.342V
6.728ns   1.058V     579.6mV    1.348V
20.94ns   1.068V     655.8mV    1.349V
[Falling Waveform]
R_fixture = 50
V_fixture = 1.8
V_fixture_min = 1.62
V_fixture_max = 1.89
0s        1.8V       1.62V      1.89V
568ps     1.803V     1.62V      1.789V
1.024ns   1.765V     1.621V     1.391V
1.488ns   1.613V     1.623V     677.2mV
2.072ns   1.293V     1.612V     563.4mV
2.456ns   1.012V     1.581V     545.1mV
2.824ns   891.3mV    1.54V      537.3mV
4.2ns     752.4mV    1.319V     530.4mV
8.2ns     718.3mV    1.058V     529.8mV
18.73ns   717.6mV    1.011V     529.8mV
[Falling Waveform]
R_fixture = 50
V_fixture = 0
V_fixture_min = 0
V_fixture_max = 0
0s        1.067V     657.3mV    1.349V
352ps     1.069V     657.4mV    1.336V
528ps     1.071V     657.2mV    1.218V
744ps     1.052V     657.6mV    913.3mV
1.048ns   931.3mV    660.5mV    279.2mV
1.392ns   594.6mV    657.1mV    15.96mV
1.736ns   221.1mV    626.5mV    1.766mV
2.256ns   14.22mV    500.4mV    233.5uV
3.512ns   354.1uV    67.45mV    8.689uV
5ns       62.09uV    1.641mV    745.9nV
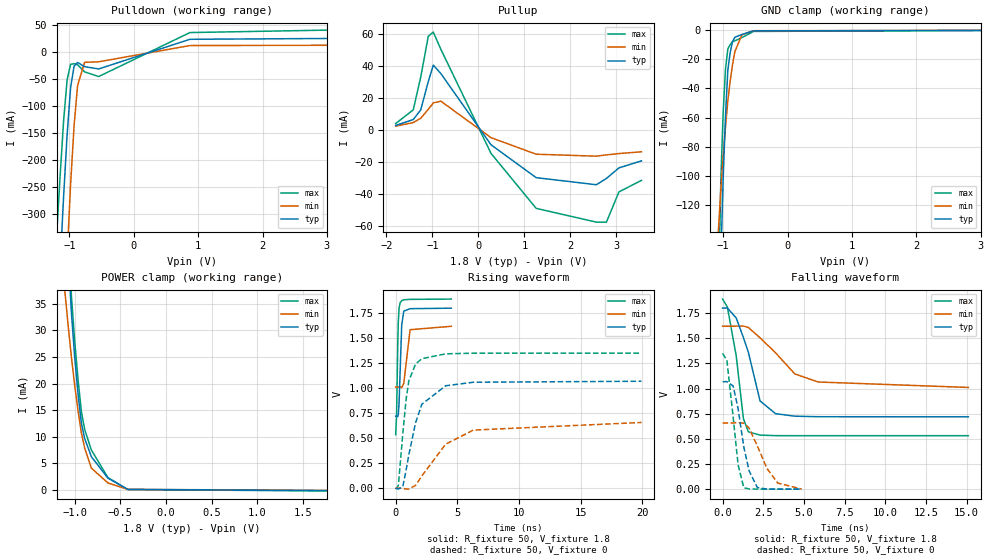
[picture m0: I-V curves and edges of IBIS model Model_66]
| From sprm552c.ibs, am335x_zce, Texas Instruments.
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| Model based on original model for OQ18SMART1FBPB_SSBHH
|   Sub model SBHH_HS01L10_PU1_1P8
[model]   Model_66
|[Description]  [1.8V-3-STATE-PU-S01:L10]
|   S01, L10,Weak internal pull-up, ,
|[Input Load]   PU
|[Output Drive] S01:L10
|Voltage   1.8V
|Mode   3-STATE
Model_type   3-state
Polarity   Non-Inverting
Enable   Active-Low
Cref =  15pF
Rref =  100.0000M
Vref =  0V
Vmeas =  0.9
C_comp   1.240965p   1.099743p   1.401226p
[Temperature Range]   25   125   -40
[Voltage Range]   1.8   1.62   1.89
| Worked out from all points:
|   slope of the pulldown table from 0 to 0.27 V, typ, clamps not added: 24.3 ohm
|   slope of the pullup table from 0 to 0.27 V, typ, clamps not added: 29.7 ohm
|   GND clamp passes 1 mA (typ) near -0.60 V on its own axis
|   POWER clamp passes 1 mA (typ) near -0.56 V on its own axis
|   rising waveform, R_fixture 50, V_fixture 1.8: 20-80 % time 169ps typ, 295ps min, 116ps max; typ from 0.72 V to 1.8 V
|   rising waveform, R_fixture 50, V_fixture 0: 20-80 % time 1.3ns typ, 2.91ns min, 686ps max; typ from 0.001 V to 1.07 V
|   falling waveform, R_fixture 50, V_fixture 1.8: 20-80 % time 1.09ns typ, 2.21ns min, 678ps max; typ from 1.8 V to 0.72 V
|   falling waveform, R_fixture 50, V_fixture 0: 20-80 % time 681ps typ, 1.12ns min, 499ps max; typ from 1.07 V to 0.001 V
[POWER_clamp]
-1.8V     360mA      189.8mA    409.4mA
-1.109V   56.23mA    37.39mA    59.78mA
-1.073V   44.23mA    30.96mA    47.33mA
-1.036V   33.16mA    24.83mA    36.25mA
-1V       24.78mA    19.56mA    27.84mA
-963.6mV  17.91mA    14.85mA    20.66mA
-927.3mV  12.54mA    10.7mA     14.72mA
-890.9mV  9.653mA    7.862mA    11.35mA
-818.2mV  6.273mA    4.126mA    7.524mA
-636.4mV  2.249mA    1.34mA     2.341mA
-418.2mV  128.7uA    129uA      104.8uA
1.764V    -96.73uA   -46.46uA   -163.5uA
[Pulldown]
-1.8V     -1.72A     -2.612A    -1.411A
-1.2V     -528.3mA   -845.3mA   -342.5mA
-1.145V   -396.8mA   -683.8mA   -231.2mA
-1.091V   -269.6mA   -527.2mA   -129mA
-1.036V   -154.1mA   -379.3mA   -51.85mA
-981.8mV  -66.54mA   -245.9mA   -22.8mA
-927.3mV  -26.05mA   -136.4mA   -21.6mA
-872.7mV  -19.36mA   -62.04mA   -23.73mA
-763.6mV  -27.2mA    -19.06mA   -36.72mA
-545.5mV  -31.39mA   -18.17mA   -45.46mA
872.7mV   23.46mA    11.88mA    35.92mA
3.545V    25.35mA    12.51mA    41.59mA
[Pullup]
-1.8V     2.903mA    2.423mA    4.111mA
-1.418V   6.594mA    4.711mA    12.64mA
-1.255V   12.69mA    7.42mA     33.23mA
-1.091V   30.4mA     13mA       58.71mA
-981.8mV  40.64mA    17.02mA    61.32mA
-818.2mV  35.38mA    18.12mA    50.59mA
272.7mV   -9.179mA   -4.728mA   -14.55mA
1.255V    -29.75mA   -15.09mA   -48.97mA
2.564V    -34.18mA   -16.32mA   -57.57mA
2.782V    -30.27mA   -15.51mA   -57.62mA
3.055V    -23.64mA   -14.69mA   -38.68mA
3.545V    -19.26mA   -13.56mA   -31.45mA
[GND_clamp]
-1.8V     -2.816A    -1.188A    -3.154A
-1.073V   -234.2mA   -137.3mA   -187.2mA
-1.036V   -158.1mA   -109.8mA   -103.1mA
-1V       -102.5mA   -86.97mA   -56.83mA
-963.6mV  -58.95mA   -66.55mA   -26.74mA
-927.3mV  -27.37mA   -48.49mA   -12.79mA
-890.9mV  -15.31mA   -35.02mA   -9.789mA
-854.5mV  -7.771mA   -23.73mA   -7.932mA
-818.2mV  -4.769mA   -14.63mA   -7.221mA
-709.1mV  -2.849mA   -3.058mA   -5.011mA
-527.3mV  -395.6uA   -259.7uA   -751.2uA
3.6V      0A         0A         0A
[Ramp]
dV/dt_f  0.6499665/1.093092n   0.3670268/2.232241n   0.8167434/0.6806234n
dV/dt_r  0.6496435/1.299567n   0.4003412/2.934147n   0.8201535/0.6868818n
R_load = 50
[Rising Waveform]
R_fixture = 50
V_fixture = 1.8
V_fixture_min = 1.62
V_fixture_max = 1.89
0s        720mV      1.011V     535.7mV
72ps      721.7mV    1.011V     729.8mV
168ps     714.8mV    1.011V     1.44V
208ps     732.7mV    1.011V     1.649V
272ps     842.3mV    1.011V     1.796V
352ps     1.137V     1.012V     1.851V
488ps     1.63V      1.005V     1.874V
656ps     1.769V     1.049V     1.883V
1.168ns   1.794V     1.584V     1.887V
4.512ns   1.799V     1.618V     1.89V
[Rising Waveform]
R_fixture = 50
V_fixture = 0
V_fixture_min = 0
V_fixture_max = 0
0s        1.461mV    1.092mV    -9.261mV
216ps     -7.617mV   867.7uV    25.89mV
576ps     16.79mV    -1.926mV   545.1mV
840ps     178.2mV    -6.762mV   883.5mV
1.064ns   333.6mV    -8.495mV   1.073V
1.616ns   655.5mV    28.71mV    1.242V
2.12ns    839.3mV    122.4mV    1.294V
4.056ns   1.024V     441mV      1.343V
6.312ns   1.059V     581.2mV    1.349V
19.93ns   1.069V     657.1mV    1.35V
[Falling Waveform]
R_fixture = 50
V_fixture = 1.8
V_fixture_min = 1.62
V_fixture_max = 1.89
0s        1.8V       1.62V      1.89V
296ps     1.801V     1.62V      1.811V
840ps     1.702V     1.621V     1.324V
1.28ns    1.508V     1.622V     702.8mV
1.584ns   1.362V     1.608V     570.7mV
2.304ns   877.6mV    1.505V     538.6mV
3.256ns   751.3mV    1.356V     533.2mV
4.44ns    726.5mV    1.146V     532.6mV
5.88ns    721.1mV    1.066V     532.6mV
15.1ns    720mV      1.012V     532.6mV
[Falling Waveform]
R_fixture = 50
V_fixture = 0
V_fixture_min = 0
V_fixture_max = 0
0s        1.069V     658.6mV    1.35V
264ps     1.07V      658.8mV    1.284V
648ps     1.027V     658.8mV    721.5mV
952ps     802.7mV    661.9mV    245.1mV
1.304ns   421.7mV    657.4mV    15.79mV
1.632ns   183mV      608.8mV    3.489mV
2.136ns   17.18mV    430.6mV    1.977mV
2.72ns    2.774mV    209.1mV    1.795mV
3.392ns   1.679mV    61.97mV    1.775mV
4.856ns   1.428mV    2.597mV    1.773mV
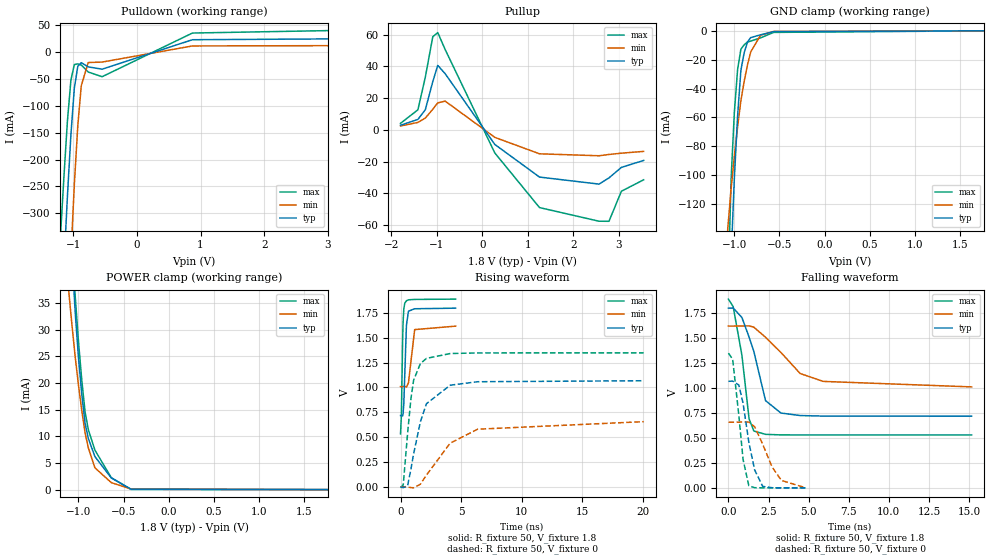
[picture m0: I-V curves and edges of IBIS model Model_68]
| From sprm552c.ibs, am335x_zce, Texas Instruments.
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| Model based on original model for OQ18SMART1FBPB_SSBHH
|   Sub model HH_HS01L01_PUPD0_1P8
[model]   Model_68
|[Description]  [1.8V-3-STATE-PI-S01:L01]
|   S01, L01,Weak pull up/down disabled, ,
|[Input Load]   PI
|[Output Drive] S01:L01
|Voltage   1.8V
|Mode   3-STATE
Model_type   3-state
Polarity   Non-Inverting
Enable   Active-Low
Cref =  15pF
Rref =  100.0000M
Vref =  0V
Vmeas =  0.9
C_comp   1.240965p   1.099743p   1.401226p
[Temperature Range]   25   125   -40
[Voltage Range]   1.8   1.62   1.89
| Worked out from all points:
|   slope of the pulldown table from 0 to 0.27 V, typ, clamps not added: 24.3 ohm
|   slope of the pullup table from 0 to 0.27 V, typ, clamps not added: 29.7 ohm
|   GND clamp passes 1 mA (typ) near -0.60 V on its own axis
|   POWER clamp passes 1 mA (typ) near -0.56 V on its own axis
|   rising waveform, R_fixture 50, V_fixture 1.8: 20-80 % time 169ps typ, 296ps min, 117ps max; typ from 0.718 V to 1.8 V
|   rising waveform, R_fixture 50, V_fixture 0: 20-80 % time 1.31ns typ, 2.93ns min, 691ps max; typ from 0 V to 1.07 V
|   falling waveform, R_fixture 50, V_fixture 1.8: 20-80 % time 1.08ns typ, 2.22ns min, 669ps max; typ from 1.8 V to 0.718 V
|   falling waveform, R_fixture 50, V_fixture 0: 20-80 % time 669ps typ, 1.1ns min, 490ps max; typ from 1.07 V to 0 V
[POWER_clamp]
-1.8V     360mA      189.8mA    409.4mA
-1.109V   56.16mA    37.36mA    59.65mA
-1.073V   44.16mA    30.93mA    47.2mA
-1.036V   33.09mA    24.8mA     36.11mA
-1V       24.71mA    19.53mA    27.71mA
-963.6mV  17.83mA    14.82mA    20.53mA
-927.3mV  12.46mA    10.66mA    14.59mA
-890.9mV  9.571mA    7.827mA    11.23mA
-818.2mV  6.195mA    4.088mA    7.402mA
-636.4mV  2.183mA    1.306mA    2.238mA
-418.2mV  83.85uA    105.2uA    35.14uA
1.764V    -1.213nA   -79.04nA   -1.357nA
[Pulldown]
-1.8V     -1.72A     -2.612A    -1.411A
-1.2V     -528.3mA   -845.3mA   -342.5mA
-1.145V   -396.8mA   -683.8mA   -231.2mA
-1.091V   -269.6mA   -527.2mA   -129mA
-1.036V   -154.1mA   -379.3mA   -51.86mA
-981.8mV  -66.54mA   -245.9mA   -22.8mA
-927.3mV  -26.05mA   -136.4mA   -21.6mA
-872.7mV  -19.36mA   -62.04mA   -23.73mA
-763.6mV  -27.2mA    -19.06mA   -36.72mA
-545.5mV  -31.39mA   -18.17mA   -45.46mA
872.7mV   23.46mA    11.88mA    35.92mA
3.545V    25.35mA    12.51mA    41.59mA
[Pullup]
-1.8V     2.903mA    2.423mA    4.111mA
-1.418V   6.594mA    4.711mA    12.64mA
-1.255V   12.68mA    7.42mA     33.22mA
-1.091V   30.4mA     13mA       58.7mA
-981.8mV  40.64mA    17.02mA    61.32mA
-818.2mV  35.38mA    18.12mA    50.59mA
272.7mV   -9.18mA    -4.728mA   -14.55mA
1.255V    -29.75mA   -15.09mA   -48.97mA
2.564V    -34.18mA   -16.32mA   -57.57mA
2.782V    -30.27mA   -15.51mA   -57.62mA
3.055V    -23.64mA   -14.69mA   -38.68mA
3.545V    -19.26mA   -13.56mA   -31.45mA
[GND_clamp]
-1.8V     -2.816A    -1.188A    -3.154A
-1.073V   -234.1mA   -137.3mA   -187.2mA
-1.036V   -158.1mA   -109.8mA   -103mA
-1V       -102.5mA   -86.96mA   -56.78mA
-963.6mV  -58.91mA   -66.54mA   -26.67mA
-927.3mV  -27.33mA   -48.47mA   -12.72mA
-890.9mV  -15.25mA   -35mA      -9.693mA
-854.5mV  -7.712mA   -23.72mA   -7.821mA
-818.2mV  -4.703mA   -14.61mA   -7.099mA
-709.1mV  -2.775mA   -3.029mA   -4.882mA
-563.6mV  -570.1uA   -403.1uA   -1.092mA
1.764V    -22.34pA   583.3nA    2.874nA
[Ramp]
dV/dt_f  0.6513095/1.083004n   0.3677232/2.242456n   0.8183488/0.6711868n
dV/dt_r  0.6511751/1.309891n   0.4008413/2.954045n   0.8230344/0.69226n
R_load = 50
[Rising Waveform]
R_fixture = 50
V_fixture = 1.8
V_fixture_min = 1.62
V_fixture_max = 1.89
0s        717.7mV    1.009V     533.1mV
72ps      719.3mV    1.009V     724.4mV
168ps     712.5mV    1.009V     1.434V
208ps     730.4mV    1.009V     1.644V
272ps     838.5mV    1.01V      1.793V
352ps     1.132V     1.011V     1.849V
488ps     1.627V     1.004V     1.873V
656ps     1.769V     1.048V     1.883V
1.168ns   1.793V     1.583V     1.887V
4.552ns   1.799V     1.618V     1.89V
[Rising Waveform]
R_fixture = 50
V_fixture = 0
V_fixture_min = 0
V_fixture_max = 0
0s        71.27uV    127.2uV    -11.1mV
224ps     -9.242mV   -96.64uV   19.97mV
584ps     11mV       -2.912mV   537.1mV
856ps     175.3mV    -8.163mV   884.1mV
1.08ns    330mV      -10.66mV   1.072V
1.64ns    654.6mV    25.95mV    1.241V
2.144ns   837.1mV    118.8mV    1.293V
4.104ns   1.023V     439.7mV    1.342V
6.376ns   1.058V     579.9mV    1.348V
20.08ns   1.068V     655.8mV    1.349V
[Falling Waveform]
R_fixture = 50
V_fixture = 1.8
V_fixture_min = 1.62
V_fixture_max = 1.89
0s        1.8V       1.62V      1.89V
296ps     1.801V     1.62V      1.815V
840ps     1.706V     1.621V     1.328V
1.288ns   1.509V     1.622V     690mV
1.584ns   1.366V     1.609V     569.1mV
2.312ns   873.9mV    1.508V     536mV
3.272ns   749.4mV    1.356V     530.4mV
4.472ns   724.2mV    1.145V     529.8mV
5.912ns   718.7mV    1.066V     529.8mV
15.16ns   717.6mV    1.011V     529.8mV
[Falling Waveform]
R_fixture = 50
V_fixture = 0
V_fixture_min = 0
V_fixture_max = 0
0s        1.067V     657.2mV    1.349V
264ps     1.069V     657.4mV    1.288V
648ps     1.03V      657.5mV    725.6mV
912ps     846.8mV    660.1mV    284.2mV
1.272ns   456.7mV    658.6mV    21.09mV
1.632ns   180.3mV    612.4mV    1.64mV
2.136ns   14.73mV    436.7mV    189.6uV
2.72ns    1.334mV    209.4mV    19.87uV
3.304ns   333.4uV    74.23mV    2.906uV
4.792ns   39.44uV    1.648mV    67.85nV
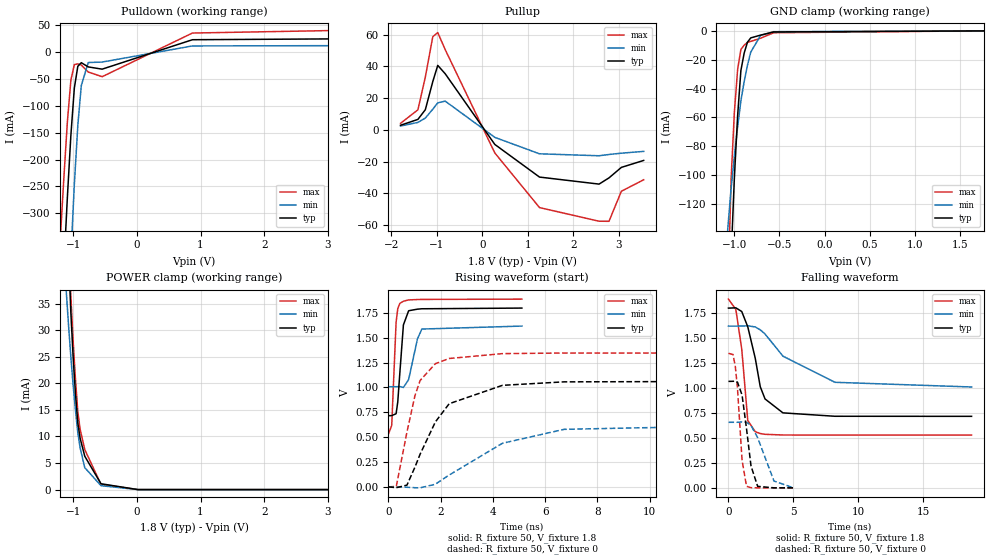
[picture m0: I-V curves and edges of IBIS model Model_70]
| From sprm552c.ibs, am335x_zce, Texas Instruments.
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| Model based on original model for OQ18SMART1FBPB_SSBHH
|   Sub model SBHH_HS10L00_PD1_1P8
[model]   Model_70
|[Description]  [1.8V-3-STATE-PD-S10:L00]
|   S10, L00,Weak internal pull-down, ,
|[Input Load]   PD
|[Output Drive] S10:L00
|Voltage   1.8V
|Mode   3-STATE
Model_type   3-state
Polarity   Non-Inverting
Enable   Active-Low
Cref =  15pF
Rref =  100.0000M
Vref =  0V
Vmeas =  0.9
C_comp   1.240965p   1.099743p   1.401226p
[Temperature Range]   25   125   -40
[Voltage Range]   1.8   1.62   1.89
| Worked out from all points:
|   slope of the pulldown table from 0 to 0.27 V, typ, clamps not added: 24.3 ohm
|   slope of the pullup table from 0 to 0.27 V, typ, clamps not added: 29.7 ohm
|   GND clamp passes 1 mA (typ) near -0.60 V on its own axis
|   POWER clamp passes 1 mA (typ) near -0.55 V on its own axis
|   rising waveform, R_fixture 50, V_fixture 1.8: 20-80 % time 172ps typ, 304ps min, 119ps max; typ from 0.716 V to 1.8 V
|   rising waveform, R_fixture 50, V_fixture 0: 20-80 % time 1.36ns typ, 3.05ns min, 717ps max; typ from 0 V to 1.06 V
|   falling waveform, R_fixture 50, V_fixture 1.8: 20-80 % time 1.1ns typ, 2.95ns min, 570ps max; typ from 1.8 V to 0.716 V
|   falling waveform, R_fixture 50, V_fixture 0: 20-80 % time 594ps typ, 1.04ns min, 411ps max; typ from 1.06 V to 0 V
[POWER_clamp]
-1.8V     360mA      189.8mA    409.4mA
-1.109V   56.22mA    37.38mA    59.76mA
-1.073V   44.22mA    30.95mA    47.31mA
-1.036V   33.15mA    24.83mA    36.24mA
-1V       24.78mA    19.56mA    27.83mA
-963.6mV  17.91mA    14.85mA    20.66mA
-927.3mV  12.54mA    10.7mA     14.72mA
-890.9mV  9.653mA    7.864mA    11.36mA
-818.2mV  6.28mA     4.131mA    7.54mA
-563.6mV  1.102mA    739.4uA    992.8uA
18.18mV   0A         0A         0A
3.6V      0A         0A         0A
[Pulldown]
-1.8V     -1.72A     -2.612A    -1.411A
-1.2V     -528.3mA   -845.3mA   -342.5mA
-1.145V   -396.8mA   -683.8mA   -231.2mA
-1.091V   -269.6mA   -527.2mA   -129mA
-1.036V   -154.1mA   -379.3mA   -51.85mA
-981.8mV  -66.54mA   -245.9mA   -22.8mA
-927.3mV  -26.05mA   -136.4mA   -21.6mA
-872.7mV  -19.36mA   -62.04mA   -23.73mA
-763.6mV  -27.2mA    -19.06mA   -36.72mA
-545.5mV  -31.39mA   -18.17mA   -45.46mA
872.7mV   23.46mA    11.88mA    35.92mA
3.545V    25.35mA    12.51mA    41.59mA
[Pullup]
-1.8V     2.903mA    2.423mA    4.111mA
-1.418V   6.594mA    4.711mA    12.64mA
-1.255V   12.69mA    7.42mA     33.23mA
-1.091V   30.4mA     13mA       58.71mA
-981.8mV  40.64mA    17.02mA    61.32mA
-818.2mV  35.38mA    18.12mA    50.59mA
272.7mV   -9.18mA    -4.728mA   -14.55mA
1.255V    -29.75mA   -15.09mA   -48.97mA
2.564V    -34.18mA   -16.32mA   -57.57mA
2.782V    -30.27mA   -15.51mA   -57.62mA
3.055V    -23.64mA   -14.69mA   -38.68mA
3.545V    -19.26mA   -13.56mA   -31.45mA
[GND_clamp]
-1.8V     -2.816A    -1.188A    -3.154A
-1.073V   -234.2mA   -137.3mA   -187.2mA
-1.036V   -158.1mA   -109.8mA   -103.1mA
-1V       -102.5mA   -86.97mA   -56.82mA
-963.6mV  -58.95mA   -66.55mA   -26.72mA
-927.3mV  -27.37mA   -48.49mA   -12.78mA
-890.9mV  -15.3mA    -35.02mA   -9.769mA
-854.5mV  -7.767mA   -23.73mA   -7.908mA
-818.2mV  -4.764mA   -14.63mA   -7.195mA
-709.1mV  -2.84mA    -3.059mA   -4.978mA
-563.6mV  -632.1uA   -435.2uA   -1.184mA
1.764V    97.78uA    55.01uA    156.4uA
[Ramp]
dV/dt_f  0.6517516/1.098596n   0.3686199/2.977707n   0.8181822/0.5720256n
dV/dt_r  0.6500072/1.364829n   0.4000087/3.079863n   0.8219744/0.7202411n
R_load = 50
[Rising Waveform]
R_fixture = 50
V_fixture = 1.8
V_fixture_min = 1.62
V_fixture_max = 1.89
0s        715.7mV    1.007V     530.1mV
128ps     716.6mV    1.007V     616.8mV
296ps     735.4mV    1.007V     1.656V
360ps     853.8mV    1.008V     1.792V
440ps     1.148V     1.009V     1.845V
576ps     1.629V     999.8mV    1.867V
776ps     1.771V     1.079V     1.88V
1.112ns   1.787V     1.486V     1.884V
1.28ns    1.791V     1.587V     1.885V
5.112ns   1.798V     1.617V     1.888V
[Rising Waveform]
R_fixture = 50
V_fixture = 0
V_fixture_min = 0
V_fixture_max = 0
0s        29.04uV    66.65uV    -433.9uV
304ps     -8.602mV   -106.8uV   4.828mV
712ps     17.46mV    -4.115mV   552mV
1.016ns   197.6mV    -8.654mV   915.8mV
1.216ns   328.9mV    -10.11mV   1.07V
1.8ns     653.1mV    26.45mV    1.239V
2.328ns   836.1mV    118.9mV    1.291V
4.368ns   1.021V     438.4mV    1.34V
6.728ns   1.056V     578.4mV    1.346V
20.94ns   1.065V     654.4mV    1.346V
[Falling Waveform]
R_fixture = 50
V_fixture = 1.8
V_fixture_min = 1.62
V_fixture_max = 1.89
0s        1.798V     1.618V     1.888V
568ps     1.801V     1.618V     1.786V
1.024ns   1.764V     1.619V     1.388V
1.488ns   1.611V     1.621V     673.7mV
2.064ns   1.296V     1.61V      561.9mV
2.448ns   1.012V     1.581V     543.5mV
2.816ns   889.4mV    1.539V     535.7mV
4.192ns   750.2mV    1.318V     528.8mV
8.192ns   716.2mV    1.056V     528.2mV
18.71ns   715.5mV    1.009V     528.2mV
[Falling Waveform]
R_fixture = 50
V_fixture = 0
V_fixture_min = 0
V_fixture_max = 0
0s        1.065V     655.9mV    1.346V
352ps     1.066V     656mV      1.334V
528ps     1.068V     655.9mV    1.215V
696ps     1.057V     656.1mV    995.9mV
1.048ns   928.7mV    659.2mV    276.3mV
1.392ns   591mV      655.7mV    15.34mV
1.736ns   219.1mV    625.1mV    1.707mV
2.248ns   15.01mV    501.5mV    235.5uV
3.504ns   350uV      68.36mV    8.828uV
4.968ns   63.21uV    1.643mV    783.5nV
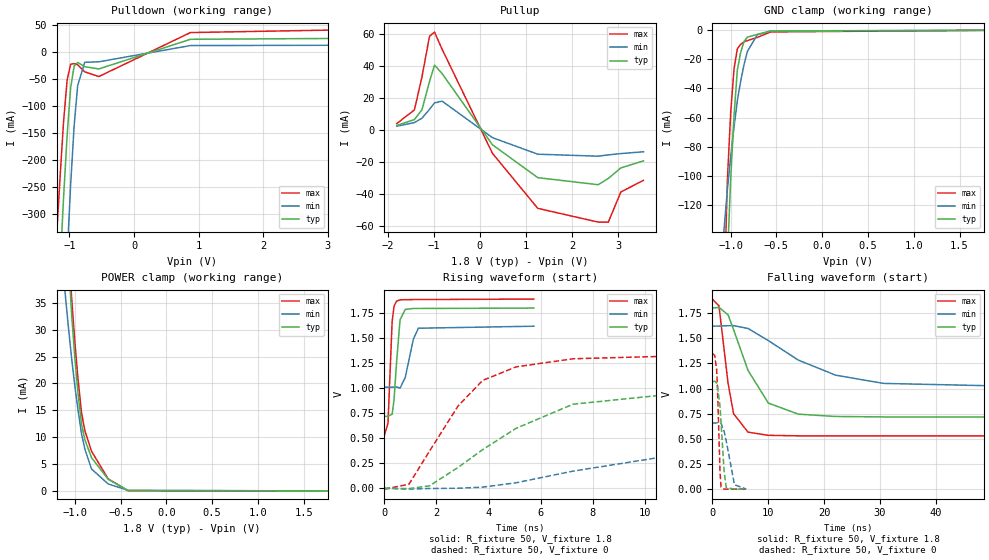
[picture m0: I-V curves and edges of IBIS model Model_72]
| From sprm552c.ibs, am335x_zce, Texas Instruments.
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| Model based on original model for OQ18SMART1FBPB_SSBHH
|   Sub model HH_HS00L00_PUPD0_1P8
[model]   Model_72
|[Description]  [1.8V-3-STATE-PI-S00:L00]
|   S00, L00,Weak pull up/down disabled, ,
|[Input Load]   PI
|[Output Drive] S00:L00
|Voltage   1.8V
|Mode   3-STATE
Model_type   3-state
Polarity   Non-Inverting
Enable   Active-Low
Cref =  15pF
Rref =  100.0000M
Vref =  0V
Vmeas =  0.9
C_comp   1.240965p   1.099743p   1.401226p
[Temperature Range]   25   125   -40
[Voltage Range]   1.8   1.62   1.89
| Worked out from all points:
|   slope of the pulldown table from 0 to 0.27 V, typ, clamps not added: 24.3 ohm
|   slope of the pullup table from 0 to 0.27 V, typ, clamps not added: 29.7 ohm
|   GND clamp passes 1 mA (typ) near -0.60 V on its own axis
|   POWER clamp passes 1 mA (typ) near -0.56 V on its own axis
|   rising waveform, R_fixture 50, V_fixture 1.8: 20-80 % time 172ps typ, 303ps min, 117ps max; typ from 0.718 V to 1.8 V
|   rising waveform, R_fixture 50, V_fixture 0: 20-80 % time 4.6ns typ, 10.7ns min, 2.29ns max; typ from 0.001 V to 1.07 V
|   falling waveform, R_fixture 50, V_fixture 1.8: 20-80 % time 4.9ns typ, 12.6ns min, 1.98ns max; typ from 1.8 V to 0.718 V
|   falling waveform, R_fixture 50, V_fixture 0: 20-80 % time 728ps typ, 1.23ns min, 442ps max; typ from 1.07 V to 0 V
[POWER_clamp]
-1.8V     360mA      189.8mA    409.4mA
-1.109V   56.16mA    37.36mA    59.65mA
-1.073V   44.16mA    30.93mA    47.2mA
-1.036V   33.09mA    24.8mA     36.11mA
-1V       24.71mA    19.53mA    27.71mA
-963.6mV  17.83mA    14.82mA    20.53mA
-927.3mV  12.46mA    10.66mA    14.59mA
-890.9mV  9.571mA    7.827mA    11.23mA
-818.2mV  6.195mA    4.088mA    7.402mA
-636.4mV  2.183mA    1.306mA    2.238mA
-418.2mV  83.85uA    105.2uA    35.14uA
1.764V    -1.213nA   -79.04nA   -1.357nA
[Pulldown]
-1.8V     -1.72A     -2.612A    -1.411A
-1.2V     -528.3mA   -845.3mA   -342.5mA
-1.145V   -396.8mA   -683.8mA   -231.2mA
-1.091V   -269.6mA   -527.2mA   -129mA
-1.036V   -154.1mA   -379.3mA   -51.86mA
-981.8mV  -66.54mA   -245.9mA   -22.8mA
-927.3mV  -26.05mA   -136.4mA   -21.6mA
-872.7mV  -19.36mA   -62.04mA   -23.73mA
-763.6mV  -27.2mA    -19.06mA   -36.72mA
-545.5mV  -31.39mA   -18.17mA   -45.46mA
872.7mV   23.46mA    11.88mA    35.92mA
3.545V    25.35mA    12.51mA    41.59mA
[Pullup]
-1.8V     2.903mA    2.423mA    4.111mA
-1.418V   6.594mA    4.711mA    12.64mA
-1.255V   12.68mA    7.42mA     33.22mA
-1.091V   30.4mA     13mA       58.7mA
-981.8mV  40.64mA    17.02mA    61.32mA
-818.2mV  35.38mA    18.12mA    50.59mA
272.7mV   -9.18mA    -4.728mA   -14.55mA
1.255V    -29.75mA   -15.09mA   -48.97mA
2.564V    -34.18mA   -16.32mA   -57.57mA
2.782V    -30.27mA   -15.51mA   -57.62mA
3.055V    -23.64mA   -14.69mA   -38.68mA
3.545V    -19.26mA   -13.56mA   -31.45mA
[GND_clamp]
-1.8V     -2.816A    -1.188A    -3.154A
-1.073V   -234.1mA   -137.3mA   -187.2mA
-1.036V   -158.1mA   -109.8mA   -103mA
-1V       -102.5mA   -86.96mA   -56.78mA
-963.6mV  -58.91mA   -66.54mA   -26.67mA
-927.3mV  -27.33mA   -48.47mA   -12.72mA
-890.9mV  -15.25mA   -35mA      -9.693mA
-854.5mV  -7.712mA   -23.72mA   -7.821mA
-818.2mV  -4.703mA   -14.61mA   -7.099mA
-709.1mV  -2.775mA   -3.029mA   -4.882mA
-563.6mV  -570.1uA   -403.1uA   -1.092mA
1.764V    -22.34pA   583.3nA    2.874nA
[Ramp]
dV/dt_f  0.6529391/4.911292n   0.3691418/12.68606n   0.8193858/1.986324n
dV/dt_r  0.6502119/4.615848n   0.3998409/10.80118n   0.8224416/2.294197n
R_load = 50
[Rising Waveform]
R_fixture = 50
V_fixture = 1.8
V_fixture_min = 1.62
V_fixture_max = 1.89
0s        717.8mV    1.009V     531.8mV
136ps     719.2mV    1.009V     648.3mV
296ps     739.8mV    1.009V     1.665V
368ps     881.4mV    1.01V      1.816V
464ps     1.25V      1.012V     1.868V
600ps     1.682V     1V         1.881V
800ps     1.786V     1.107V     1.883V
1.112ns   1.795V     1.489V     1.884V
1.304ns   1.795V     1.598V     1.884V
5.744ns   1.799V     1.618V     1.889V
[Rising Waveform]
R_fixture = 50
V_fixture = 0
V_fixture_min = 0
V_fixture_max = 0
0s        531.6uV    124.8uV    -8.341mV
944ps     -2.564mV   -7.279mV   41.36mV
1.728ns   24.35mV    -1.839mV   369.7mV
2.832ns   208.8mV    1.074mV    822.5mV
3.776ns   386.2mV    11.91mV    1.077V
5.056ns   598.4mV    55.41mV    1.212V
7.248ns   839.6mV    171.6mV    1.293V
14.3ns    1.026V     461.6mV    1.343V
23.62ns   1.061V     595.6mV    1.348V
68.25ns   1.067V     655.8mV    1.349V
[Falling Waveform]
R_fixture = 50
V_fixture = 1.8
V_fixture_min = 1.62
V_fixture_max = 1.89
0s        1.8V       1.62V      1.889V
1.184ns   1.806V     1.621V     1.822V
2.808ns   1.733V     1.624V     1.053V
3.8ns     1.585V     1.625V     749.3mV
6.376ns   1.181V     1.597V     566.9mV
10.02ns   855.5mV    1.476V     535mV
15.37ns   745.6mV    1.283V     530.1mV
22.05ns   722.3mV    1.133V     529.8mV
30.62ns   718.1mV    1.051V     529.8mV
63.2ns    717.6mV    1.011V     529.8mV
[Falling Waveform]
R_fixture = 50
V_fixture = 0
V_fixture_min = 0
V_fixture_max = 0
0s        1.068V     657.3mV    1.348V
432ps     1.072V     657.2mV    1.328V
760ps     1.055V     658mV      1.188V
920ps     1.024V     660.9mV    1.005V
1.376ns   816.6mV    663.2mV    167.5mV
1.56ns    654.9mV    652.9mV    19.77mV
2.112ns   169.1mV    574.5mV    1.282mV
2.488ns   16.04mV    476.2mV    527uV
3.96ns    685.1uV    43.54mV    169.8uV
6.072ns   248.8uV    1.631mV    67.25uV
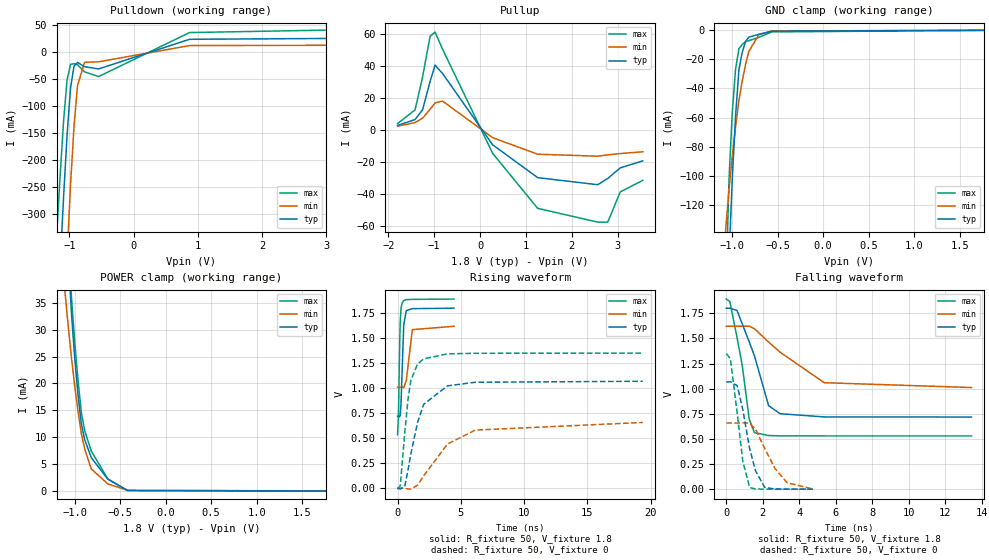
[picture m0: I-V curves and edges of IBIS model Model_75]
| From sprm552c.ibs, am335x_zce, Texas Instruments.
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| Model based on original model for OQ18SMART1FBPB_SSBHH
|   Sub model HH_HS11L11_PUPD0_1P8
[model]   Model_75
|[Description]  [1.8V-3-STATE-PI-S11:L11]
|   S11, L11,Weak pull up/down disabled, ,
|[Input Load]   PI
|[Output Drive] S11:L11
|Voltage   1.8V
|Mode   3-STATE
Model_type   3-state
Polarity   Non-Inverting
Enable   Active-Low
Cref =  15pF
Rref =  100.0000M
Vref =  0V
Vmeas =  0.9
C_comp   1.240965p   1.099743p   1.401226p
[Temperature Range]   25   125   -40
[Voltage Range]   1.8   1.62   1.89
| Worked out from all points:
|   slope of the pulldown table from 0 to 0.27 V, typ, clamps not added: 24.3 ohm
|   slope of the pullup table from 0 to 0.27 V, typ, clamps not added: 29.7 ohm
|   GND clamp passes 1 mA (typ) near -0.60 V on its own axis
|   POWER clamp passes 1 mA (typ) near -0.56 V on its own axis
|   rising waveform, R_fixture 50, V_fixture 1.8: 20-80 % time 168ps typ, 293ps min, 117ps max; typ from 0.718 V to 1.8 V
|   rising waveform, R_fixture 50, V_fixture 0: 20-80 % time 1.26ns typ, 2.83ns min, 670ps max; typ from 0 V to 1.07 V
|   falling waveform, R_fixture 50, V_fixture 1.8: 20-80 % time 1.12ns typ, 2.1ns min, 702ps max; typ from 1.8 V to 0.718 V
|   falling waveform, R_fixture 50, V_fixture 0: 20-80 % time 709ps typ, 1.16ns min, 518ps max; typ from 1.07 V to 0 V
[POWER_clamp]
-1.8V     360mA      189.8mA    409.4mA
-1.109V   56.16mA    37.36mA    59.65mA
-1.073V   44.16mA    30.93mA    47.2mA
-1.036V   33.09mA    24.8mA     36.11mA
-1V       24.71mA    19.53mA    27.71mA
-963.6mV  17.83mA    14.82mA    20.53mA
-927.3mV  12.46mA    10.66mA    14.59mA
-890.9mV  9.571mA    7.827mA    11.23mA
-818.2mV  6.195mA    4.088mA    7.402mA
-636.4mV  2.183mA    1.306mA    2.238mA
-418.2mV  83.85uA    105.2uA    35.14uA
1.764V    -1.213nA   -79.04nA   -1.357nA
[Pulldown]
-1.8V     -1.72A     -2.612A    -1.411A
-1.2V     -528.3mA   -845.3mA   -342.5mA
-1.145V   -396.8mA   -683.8mA   -231.2mA
-1.091V   -269.6mA   -527.2mA   -129mA
-1.036V   -154.1mA   -379.3mA   -51.86mA
-981.8mV  -66.54mA   -245.9mA   -22.8mA
-927.3mV  -26.05mA   -136.4mA   -21.6mA
-872.7mV  -19.36mA   -62.04mA   -23.73mA
-763.6mV  -27.2mA    -19.06mA   -36.72mA
-545.5mV  -31.39mA   -18.17mA   -45.46mA
872.7mV   23.46mA    11.88mA    35.92mA
3.545V    25.35mA    12.51mA    41.59mA
[Pullup]
-1.8V     2.903mA    2.423mA    4.111mA
-1.418V   6.594mA    4.711mA    12.64mA
-1.255V   12.68mA    7.42mA     33.22mA
-1.091V   30.4mA     13mA       58.7mA
-981.8mV  40.64mA    17.02mA    61.32mA
-818.2mV  35.38mA    18.12mA    50.59mA
272.7mV   -9.18mA    -4.728mA   -14.55mA
1.255V    -29.75mA   -15.09mA   -48.97mA
2.564V    -34.18mA   -16.32mA   -57.57mA
2.782V    -30.27mA   -15.51mA   -57.62mA
3.055V    -23.64mA   -14.69mA   -38.68mA
3.545V    -19.26mA   -13.56mA   -31.45mA
[GND_clamp]
-1.8V     -2.816A    -1.188A    -3.154A
-1.073V   -234.1mA   -137.3mA   -187.2mA
-1.036V   -158.1mA   -109.8mA   -103mA
-1V       -102.5mA   -86.96mA   -56.78mA
-963.6mV  -58.91mA   -66.54mA   -26.67mA
-927.3mV  -27.33mA   -48.47mA   -12.72mA
-890.9mV  -15.25mA   -35mA      -9.693mA
-854.5mV  -7.712mA   -23.72mA   -7.821mA
-818.2mV  -4.703mA   -14.61mA   -7.099mA
-709.1mV  -2.775mA   -3.029mA   -4.882mA
-563.6mV  -570.1uA   -403.1uA   -1.092mA
1.764V    -22.35pA   583.3nA    2.874nA
[Ramp]
dV/dt_f  0.6514556/1.124201n   0.3678248/2.115337n   0.818529/0.7048549n
dV/dt_r  0.6504374/1.266065n   0.4005687/2.851484n   0.8217685/0.6708961n
R_load = 50
[Rising Waveform]
R_fixture = 50
V_fixture = 1.8
V_fixture_min = 1.62
V_fixture_max = 1.89
0s        717.7mV    1.009V     532mV
72ps      719.1mV    1.009V     726.7mV
168ps     712.4mV    1.009V     1.441V
208ps     729.5mV    1.009V     1.647V
272ps     838.4mV    1.01V      1.795V
352ps     1.136V     1.011V     1.849V
488ps     1.63V      1.004V     1.875V
688ps     1.774V     1.074V     1.884V
1.168ns   1.794V     1.584V     1.887V
4.464ns   1.799V     1.618V     1.89V
[Rising Waveform]
R_fixture = 50
V_fixture = 0
V_fixture_min = 0
V_fixture_max = 0
0s        22.17uV    125.4uV    -11.1mV
216ps     -9.119mV   -90.2uV    24.66mV
568ps     14.57mV    -2.461mV   551.1mV
824ps     180mV      -7.899mV   886.1mV
1.04ns    334.2mV    -9.979mV   1.072V
1.576ns   654.9mV    27.28mV    1.24V
2.064ns   837.3mV    121.9mV    1.292V
3.944ns   1.022V     440mV      1.342V
6.136ns   1.058V     579.8mV    1.348V
19.38ns   1.068V     655.8mV    1.349V
[Falling Waveform]
R_fixture = 50
V_fixture = 1.8
V_fixture_min = 1.62
V_fixture_max = 1.89
0s        1.8V       1.62V      1.891V
192ps     1.8V       1.62V      1.867V
584ps     1.778V     1.62V      1.512V
872ps     1.645V     1.621V     1.233V
1.256ns   1.465V     1.621V     695.7mV
1.544ns   1.325V     1.596V     562mV
2.32ns    830.4mV    1.463V     533.4mV
2.952ns   750.7mV    1.362V     530.5mV
5.368ns   718.6mV    1.059V     529.8mV
13.45ns   717.6mV    1.011V     529.8mV
[Falling Waveform]
R_fixture = 50
V_fixture = 0
V_fixture_min = 0
V_fixture_max = 0
0s        1.067V     657.2mV    1.349V
224ps     1.068V     657.5mV    1.297V
600ps     1.029V     657.3mV    751.5mV
904ps     790.7mV    659.9mV    276.8mV
1.28ns    402.6mV    655.6mV    16.76mV
1.608ns   179.6mV    593.9mV    1.722mV
2.104ns   17.72mV    405.4mV    195uV
2.672ns   1.384mV    204.9mV    17.65uV
3.336ns   280.1uV    64.01mV    1.342uV
4.752ns   34.61uV    1.643mV    5.807nV
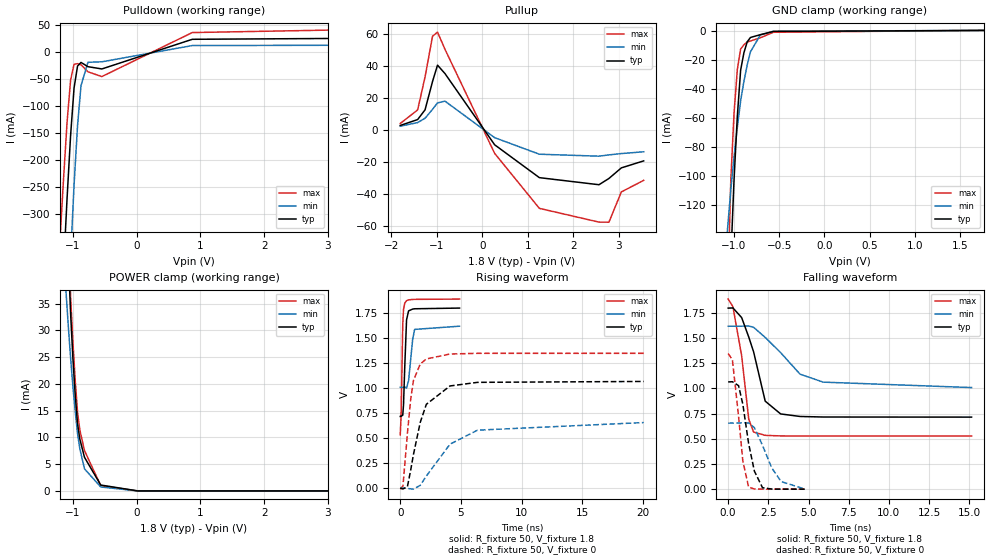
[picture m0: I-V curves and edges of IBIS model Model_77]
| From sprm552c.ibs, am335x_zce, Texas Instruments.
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| Model based on original model for OQ18SMART1FBPB_SSBHH
|   Sub model SBHH_HS01L01_PD1_1P8
[model]   Model_77
|[Description]  [1.8V-3-STATE-PD-S01:L01]
|   S01, L01,Weak internal pull-down, ,
|[Input Load]   PD
|[Output Drive] S01:L01
|Voltage   1.8V
|Mode   3-STATE
Model_type   3-state
Polarity   Non-Inverting
Enable   Active-Low
Cref =  15pF
Rref =  100.0000M
Vref =  0V
Vmeas =  0.9
C_comp   1.240965p   1.099743p   1.401226p
[Temperature Range]   25   125   -40
[Voltage Range]   1.8   1.62   1.89
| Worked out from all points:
|   slope of the pulldown table from 0 to 0.27 V, typ, clamps not added: 24.3 ohm
|   slope of the pullup table from 0 to 0.27 V, typ, clamps not added: 29.7 ohm
|   GND clamp passes 1 mA (typ) near -0.60 V on its own axis
|   POWER clamp passes 1 mA (typ) near -0.55 V on its own axis
|   rising waveform, R_fixture 50, V_fixture 1.8: 20-80 % time 170ps typ, 298ps min, 118ps max; typ from 0.716 V to 1.8 V
|   rising waveform, R_fixture 50, V_fixture 0: 20-80 % time 1.31ns typ, 2.93ns min, 693ps max; typ from 0 V to 1.06 V
|   falling waveform, R_fixture 50, V_fixture 1.8: 20-80 % time 1.08ns typ, 2.22ns min, 668ps max; typ from 1.8 V to 0.716 V
|   falling waveform, R_fixture 50, V_fixture 0: 20-80 % time 668ps typ, 1.1ns min, 489ps max; typ from 1.06 V to 0 V
[POWER_clamp]
-1.8V     360mA      189.8mA    409.4mA
-1.109V   56.22mA    37.38mA    59.76mA
-1.073V   44.22mA    30.95mA    47.31mA
-1.036V   33.15mA    24.83mA    36.24mA
-1V       24.78mA    19.56mA    27.83mA
-963.6mV  17.91mA    14.85mA    20.66mA
-927.3mV  12.54mA    10.7mA     14.72mA
-890.9mV  9.653mA    7.864mA    11.36mA
-818.2mV  6.28mA     4.131mA    7.54mA
-563.6mV  1.102mA    739.4uA    992.8uA
18.18mV   0A         0A         0A
3.6V      0A         0A         0A
[Pulldown]
-1.8V     -1.72A     -2.612A    -1.411A
-1.2V     -528.3mA   -845.3mA   -342.5mA
-1.145V   -396.8mA   -683.8mA   -231.2mA
-1.091V   -269.6mA   -527.2mA   -129mA
-1.036V   -154.1mA   -379.3mA   -51.85mA
-981.8mV  -66.54mA   -245.9mA   -22.8mA
-927.3mV  -26.05mA   -136.4mA   -21.6mA
-872.7mV  -19.36mA   -62.04mA   -23.73mA
-763.6mV  -27.2mA    -19.06mA   -36.72mA
-545.5mV  -31.39mA   -18.17mA   -45.46mA
872.7mV   23.46mA    11.88mA    35.92mA
3.545V    25.35mA    12.51mA    41.59mA
[Pullup]
-1.8V     2.903mA    2.423mA    4.111mA
-1.418V   6.594mA    4.711mA    12.64mA
-1.255V   12.69mA    7.42mA     33.23mA
-1.091V   30.4mA     13mA       58.71mA
-981.8mV  40.64mA    17.02mA    61.32mA
-818.2mV  35.38mA    18.12mA    50.59mA
272.7mV   -9.18mA    -4.728mA   -14.55mA
1.255V    -29.75mA   -15.09mA   -48.97mA
2.564V    -34.18mA   -16.32mA   -57.57mA
2.782V    -30.27mA   -15.51mA   -57.62mA
3.055V    -23.64mA   -14.69mA   -38.68mA
3.545V    -19.26mA   -13.56mA   -31.45mA
[GND_clamp]
-1.8V     -2.816A    -1.188A    -3.154A
-1.073V   -234.2mA   -137.3mA   -187.2mA
-1.036V   -158.1mA   -109.8mA   -103.1mA
-1V       -102.5mA   -86.97mA   -56.82mA
-963.6mV  -58.95mA   -66.55mA   -26.72mA
-927.3mV  -27.37mA   -48.49mA   -12.78mA
-890.9mV  -15.3mA    -35.02mA   -9.769mA
-854.5mV  -7.767mA   -23.73mA   -7.908mA
-818.2mV  -4.764mA   -14.63mA   -7.195mA
-709.1mV  -2.84mA    -3.059mA   -4.978mA
-563.6mV  -632.1uA   -435.2uA   -1.184mA
1.764V    97.78uA    55.01uA    156.4uA
[Ramp]
dV/dt_f  0.6515322/1.080995n   0.3682642/2.238455n   0.8181002/0.6698049n
dV/dt_r  0.6498438/1.312506n   0.4000114/2.954134n   0.8215221/0.6946024n
R_load = 50
[Rising Waveform]
R_fixture = 50
V_fixture = 1.8
V_fixture_min = 1.62
V_fixture_max = 1.89
0s        715.5mV    1.007V     531.4mV
72ps      717.2mV    1.007V     721.8mV
208ps     728.2mV    1.007V     1.639V
272ps     835.9mV    1.008V     1.786V
368ps     1.197V     1.009V     1.847V
520ps     1.68V      998.8mV    1.872V
688ps     1.77V      1.073V     1.88V
1.024ns   1.788V     1.485V     1.884V
1.184ns   1.791V     1.585V     1.885V
4.888ns   1.798V     1.617V     1.888V
[Rising Waveform]
R_fixture = 50
V_fixture = 0
V_fixture_min = 0
V_fixture_max = 0
0s        71.2uV     127.1uV    -11.1mV
224ps     -9.24mV    -96.74uV   20.06mV
592ps     14.11mV    -3.162mV   546.7mV
864ps     180.8mV    -8.222mV   889.3mV
1.088ns   334.6mV    -10.61mV   1.074V
1.648ns   656.4mV    27.06mV    1.239V
2.152ns   836.8mV    120.3mV    1.29V
4.104ns   1.02V      438.8mV    1.339V
6.368ns   1.056V     578.3mV    1.346V
20.06ns   1.065V     654.4mV    1.346V
[Falling Waveform]
R_fixture = 50
V_fixture = 1.8
V_fixture_min = 1.62
V_fixture_max = 1.89
0s        1.798V     1.618V     1.888V
296ps     1.8V       1.619V     1.812V
840ps     1.704V     1.619V     1.325V
1.28ns    1.511V     1.621V     694.7mV
1.584ns   1.363V     1.607V     566.7mV
2.304ns   874.1mV    1.507V     534.4mV
3.264ns   747.2mV    1.356V     528.8mV
4.472ns   722mV      1.142V     528.2mV
5.912ns   716.6mV    1.063V     528.2mV
15.14ns   715.5mV    1.009V     528.2mV
[Falling Waveform]
R_fixture = 50
V_fixture = 0
V_fixture_min = 0
V_fixture_max = 0
0s        1.065V     655.9mV    1.347V
264ps     1.067V     656.1mV    1.285V
648ps     1.028V     656.1mV    721.9mV
912ps     844.2mV    658.7mV    282mV
1.272ns   453.9mV    657.2mV    20.71mV
1.632ns   178.8mV    611mV      1.589mV
2.136ns   14.59mV    435.1mV    185.7uV
2.712ns   1.316mV    210.9mV    20.18uV
3.296ns   329.6uV    75.21mV    2.992uV
4.768ns   39.49uV    1.648mV    72.55nV
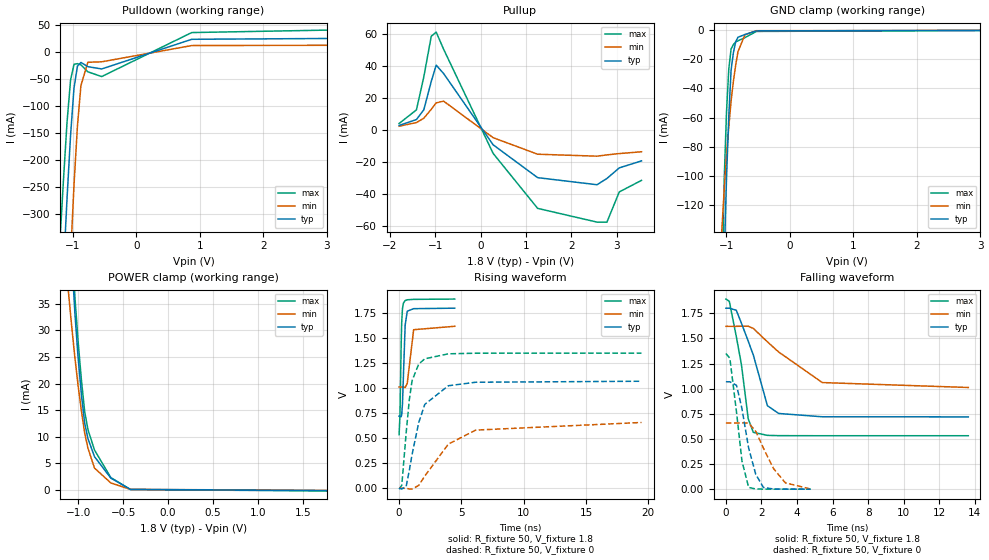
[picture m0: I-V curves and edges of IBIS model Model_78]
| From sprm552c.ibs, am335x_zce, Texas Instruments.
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| Model based on original model for OQ18SMART1FBPB_SSBHH
|   Sub model SBHH_HS11L01_PU1_1P8
[model]   Model_78
|[Description]  [1.8V-3-STATE-PU-S11:L01]
|   S11, L01,Weak internal pull-up, ,
|[Input Load]   PU
|[Output Drive] S11:L01
|Voltage   1.8V
|Mode   3-STATE
Model_type   3-state
Polarity   Non-Inverting
Enable   Active-Low
Cref =  15pF
Rref =  100.0000M
Vref =  0V
Vmeas =  0.9
C_comp   1.240965p   1.099743p   1.401226p
[Temperature Range]   25   125   -40
[Voltage Range]   1.8   1.62   1.89
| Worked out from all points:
|   slope of the pulldown table from 0 to 0.27 V, typ, clamps not added: 24.3 ohm
|   slope of the pullup table from 0 to 0.27 V, typ, clamps not added: 29.7 ohm
|   GND clamp passes 1 mA (typ) near -0.60 V on its own axis
|   POWER clamp passes 1 mA (typ) near -0.56 V on its own axis
|   rising waveform, R_fixture 50, V_fixture 1.8: 20-80 % time 168ps typ, 294ps min, 116ps max; typ from 0.72 V to 1.8 V
|   rising waveform, R_fixture 50, V_fixture 0: 20-80 % time 1.27ns typ, 2.83ns min, 670ps max; typ from 0.001 V to 1.07 V
|   falling waveform, R_fixture 50, V_fixture 1.8: 20-80 % time 1.11ns typ, 2.11ns min, 698ps max; typ from 1.8 V to 0.72 V
|   falling waveform, R_fixture 50, V_fixture 0: 20-80 % time 704ps typ, 1.15ns min, 515ps max; typ from 1.07 V to 0.001 V
[POWER_clamp]
-1.8V     360mA      189.8mA    409.4mA
-1.109V   56.23mA    37.39mA    59.78mA
-1.073V   44.23mA    30.96mA    47.33mA
-1.036V   33.16mA    24.83mA    36.25mA
-1V       24.78mA    19.56mA    27.84mA
-963.6mV  17.91mA    14.85mA    20.66mA
-927.3mV  12.54mA    10.7mA     14.72mA
-890.9mV  9.653mA    7.862mA    11.35mA
-818.2mV  6.273mA    4.126mA    7.524mA
-636.4mV  2.249mA    1.34mA     2.341mA
-418.2mV  128.7uA    129uA      104.8uA
1.764V    -96.73uA   -46.46uA   -163.5uA
[Pulldown]
-1.8V     -1.72A     -2.612A    -1.411A
-1.2V     -528.3mA   -845.3mA   -342.5mA
-1.145V   -396.8mA   -683.8mA   -231.2mA
-1.091V   -269.6mA   -527.2mA   -129mA
-1.036V   -154.1mA   -379.3mA   -51.85mA
-981.8mV  -66.54mA   -245.9mA   -22.8mA
-927.3mV  -26.05mA   -136.4mA   -21.6mA
-872.7mV  -19.36mA   -62.04mA   -23.73mA
-763.6mV  -27.2mA    -19.06mA   -36.72mA
-545.5mV  -31.39mA   -18.17mA   -45.46mA
872.7mV   23.46mA    11.88mA    35.92mA
3.545V    25.35mA    12.51mA    41.59mA
[Pullup]
-1.8V     2.903mA    2.423mA    4.111mA
-1.418V   6.594mA    4.711mA    12.64mA
-1.255V   12.69mA    7.42mA     33.23mA
-1.091V   30.4mA     13mA       58.71mA
-981.8mV  40.64mA    17.02mA    61.32mA
-818.2mV  35.38mA    18.12mA    50.59mA
272.7mV   -9.179mA   -4.728mA   -14.55mA
1.255V    -29.75mA   -15.09mA   -48.97mA
2.564V    -34.18mA   -16.32mA   -57.57mA
2.782V    -30.27mA   -15.51mA   -57.62mA
3.055V    -23.64mA   -14.69mA   -38.68mA
3.545V    -19.26mA   -13.56mA   -31.45mA
[GND_clamp]
-1.8V     -2.816A    -1.188A    -3.154A
-1.073V   -234.2mA   -137.3mA   -187.2mA
-1.036V   -158.1mA   -109.8mA   -103.1mA
-1V       -102.5mA   -86.97mA   -56.83mA
-963.6mV  -58.95mA   -66.55mA   -26.74mA
-927.3mV  -27.37mA   -48.49mA   -12.79mA
-890.9mV  -15.31mA   -35.02mA   -9.789mA
-854.5mV  -7.771mA   -23.73mA   -7.932mA
-818.2mV  -4.769mA   -14.63mA   -7.221mA
-709.1mV  -2.849mA   -3.058mA   -5.011mA
-527.3mV  -395.6uA   -259.7uA   -751.2uA
3.6V      0A         0A         0A
[Ramp]
dV/dt_f  0.6499967/1.118451n   0.3670422/2.119815n   0.8167892/0.7002342n
dV/dt_r  0.6493218/1.267411n   0.4002494/2.855724n   0.8196023/0.6709215n
R_load = 50
[Rising Waveform]
R_fixture = 50
V_fixture = 1.8
V_fixture_min = 1.62
V_fixture_max = 1.89
0s        720mV      1.011V     535.2mV
72ps      721.5mV    1.011V     731.4mV
168ps     714.8mV    1.011V     1.444V
208ps     732.5mV    1.011V     1.651V
272ps     842.7mV    1.011V     1.797V
352ps     1.139V     1.012V     1.85V
488ps     1.631V     1.005V     1.875V
656ps     1.769V     1.05V      1.883V
1.168ns   1.794V     1.584V     1.887V
4.464ns   1.799V     1.618V     1.89V
[Rising Waveform]
R_fixture = 50
V_fixture = 0
V_fixture_min = 0
V_fixture_max = 0
0s        1.407mV    1.09mV     -9.138mV
216ps     -7.59mV    872.7uV    29.46mV
568ps     17.72mV    -1.486mV   553.3mV
824ps     181.4mV    -6.732mV   887.7mV
1.04ns    335.3mV    -8.227mV   1.074V
1.576ns   655.9mV    28.48mV    1.241V
2.064ns   838.3mV    122.2mV    1.293V
3.952ns   1.024V     441.3mV    1.343V
6.144ns   1.059V     581mV      1.349V
19.45ns   1.069V     657.1mV    1.35V
[Falling Waveform]
R_fixture = 50
V_fixture = 1.8
V_fixture_min = 1.62
V_fixture_max = 1.89
0s        1.8V       1.62V      1.891V
192ps     1.8V       1.62V      1.869V
584ps     1.78V      1.62V      1.52V
872ps     1.652V     1.621V     1.242V
1.256ns   1.473V     1.621V     701.2mV
1.544ns   1.334V     1.599V     566.1mV
2.336ns   831.1mV    1.466V     536.3mV
2.968ns   753.9mV    1.365V     533.3mV
5.424ns   721mV      1.061V     532.6mV
13.64ns   720mV      1.012V     532.6mV
[Falling Waveform]
R_fixture = 50
V_fixture = 0
V_fixture_min = 0
V_fixture_max = 0
0s        1.069V     658.6mV    1.35V
224ps     1.069V     658.8mV    1.302V
600ps     1.033V     658.7mV    762.3mV
904ps     801.1mV    661.2mV    281.2mV
1.28ns    409.9mV    657.3mV    18.87mV
1.68ns    148.9mV    576.8mV    3.075mV
2.112ns   18.07mV    408.9mV    1.971mV
2.68ns    2.791mV    206.1mV    1.792mV
3.344ns   1.675mV    64.19mV    1.774mV
4.768ns   1.423mV    2.609mV    1.773mV
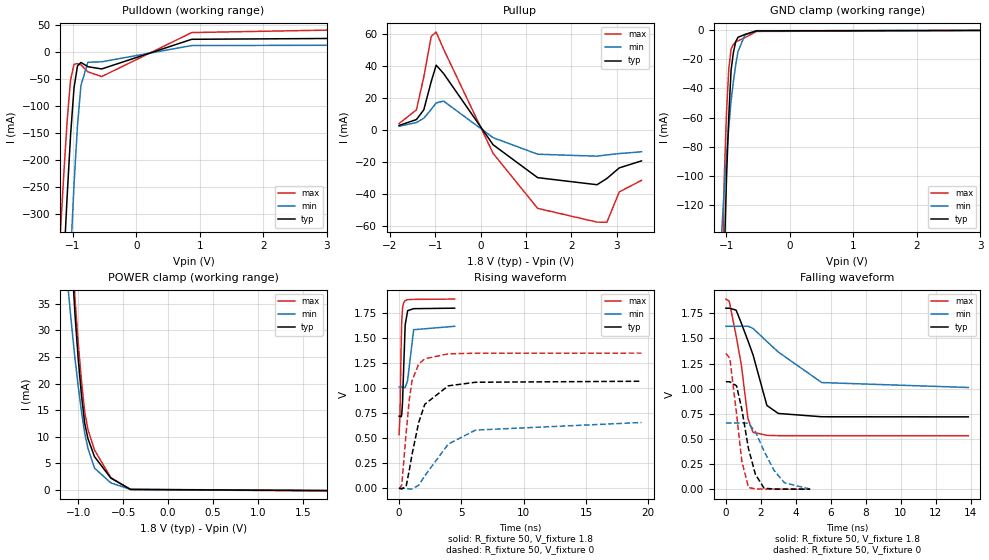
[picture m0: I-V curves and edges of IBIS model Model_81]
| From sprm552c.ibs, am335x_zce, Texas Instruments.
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| Model based on original model for OQ18SMART1FBPB_SSBHH
|   Sub model SBHH_HS11L00_PU1_1P8
[model]   Model_81
|[Description]  [1.8V-3-STATE-PU-S11:L00]
|   S11, L00,Weak internal pull-up, ,
|[Input Load]   PU
|[Output Drive] S11:L00
|Voltage   1.8V
|Mode   3-STATE
Model_type   3-state
Polarity   Non-Inverting
Enable   Active-Low
Cref =  15pF
Rref =  100.0000M
Vref =  0V
Vmeas =  0.9
C_comp   1.240965p   1.099743p   1.401226p
[Temperature Range]   25   125   -40
[Voltage Range]   1.8   1.62   1.89
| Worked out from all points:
|   slope of the pulldown table from 0 to 0.27 V, typ, clamps not added: 24.3 ohm
|   slope of the pullup table from 0 to 0.27 V, typ, clamps not added: 29.7 ohm
|   GND clamp passes 1 mA (typ) near -0.60 V on its own axis
|   POWER clamp passes 1 mA (typ) near -0.56 V on its own axis
|   rising waveform, R_fixture 50, V_fixture 1.8: 20-80 % time 169ps typ, 295ps min, 117ps max; typ from 0.72 V to 1.8 V
|   rising waveform, R_fixture 50, V_fixture 0: 20-80 % time 1.27ns typ, 2.84ns min, 670ps max; typ from 0.001 V to 1.07 V
|   falling waveform, R_fixture 50, V_fixture 1.8: 20-80 % time 1.12ns typ, 2.12ns min, 701ps max; typ from 1.8 V to 0.72 V
|   falling waveform, R_fixture 50, V_fixture 0: 20-80 % time 709ps typ, 1.16ns min, 518ps max; typ from 1.07 V to 0.001 V
[POWER_clamp]
-1.8V     360mA      189.8mA    409.4mA
-1.109V   56.23mA    37.39mA    59.78mA
-1.073V   44.23mA    30.96mA    47.33mA
-1.036V   33.16mA    24.83mA    36.25mA
-1V       24.78mA    19.56mA    27.84mA
-963.6mV  17.91mA    14.85mA    20.66mA
-927.3mV  12.54mA    10.7mA     14.72mA
-890.9mV  9.653mA    7.862mA    11.35mA
-818.2mV  6.273mA    4.126mA    7.524mA
-636.4mV  2.249mA    1.34mA     2.341mA
-418.2mV  128.7uA    129uA      104.8uA
1.764V    -96.73uA   -46.46uA   -163.5uA
[Pulldown]
-1.8V     -1.72A     -2.612A    -1.411A
-1.2V     -528.3mA   -845.3mA   -342.5mA
-1.145V   -396.8mA   -683.8mA   -231.2mA
-1.091V   -269.6mA   -527.2mA   -129mA
-1.036V   -154.1mA   -379.3mA   -51.85mA
-981.8mV  -66.54mA   -245.9mA   -22.8mA
-927.3mV  -26.05mA   -136.4mA   -21.6mA
-872.7mV  -19.36mA   -62.04mA   -23.73mA
-763.6mV  -27.2mA    -19.06mA   -36.72mA
-545.5mV  -31.39mA   -18.17mA   -45.46mA
872.7mV   23.46mA    11.88mA    35.92mA
3.545V    25.35mA    12.51mA    41.59mA
[Pullup]
-1.8V     2.903mA    2.423mA    4.111mA
-1.418V   6.594mA    4.711mA    12.64mA
-1.255V   12.69mA    7.42mA     33.23mA
-1.091V   30.4mA     13mA       58.71mA
-981.8mV  40.64mA    17.02mA    61.32mA
-818.2mV  35.38mA    18.12mA    50.59mA
272.7mV   -9.179mA   -4.728mA   -14.55mA
1.255V    -29.75mA   -15.09mA   -48.97mA
2.564V    -34.18mA   -16.32mA   -57.57mA
2.782V    -30.27mA   -15.51mA   -57.62mA
3.055V    -23.64mA   -14.69mA   -38.68mA
3.545V    -19.26mA   -13.56mA   -31.45mA
[GND_clamp]
-1.8V     -2.816A    -1.188A    -3.154A
-1.073V   -234.2mA   -137.3mA   -187.2mA
-1.036V   -158.1mA   -109.8mA   -103.1mA
-1V       -102.5mA   -86.97mA   -56.83mA
-963.6mV  -58.95mA   -66.55mA   -26.74mA
-927.3mV  -27.37mA   -48.49mA   -12.79mA
-890.9mV  -15.31mA   -35.02mA   -9.789mA
-854.5mV  -7.771mA   -23.73mA   -7.932mA
-818.2mV  -4.769mA   -14.63mA   -7.221mA
-709.1mV  -2.849mA   -3.058mA   -5.011mA
-527.3mV  -395.6uA   -259.7uA   -751.2uA
3.6V      0A         0A         0A
[Ramp]
dV/dt_f  0.6500189/1.121314n   0.3670576/2.134741n   0.8168113/0.7029603n
dV/dt_r  0.6491074/1.267747n   0.4001441/2.858085n   0.8192682/0.6711454n
R_load = 50
[Rising Waveform]
R_fixture = 50
V_fixture = 1.8
V_fixture_min = 1.62
V_fixture_max = 1.89
0s        720mV      1.011V     535.5mV
72ps      721.6mV    1.011V     733mV
168ps     714.6mV    1.011V     1.442V
208ps     732.8mV    1.011V     1.65V
272ps     845.2mV    1.011V     1.797V
352ps     1.141V     1.012V     1.85V
488ps     1.631V     1.005V     1.875V
688ps     1.774V     1.079V     1.884V
1.168ns   1.794V     1.584V     1.887V
4.456ns   1.799V     1.618V     1.89V
[Rising Waveform]
R_fixture = 50
V_fixture = 0
V_fixture_min = 0
V_fixture_max = 0
0s        1.405mV    1.091mV    -9.134mV
216ps     -7.694mV   871.7uV    32.11mV
568ps     19.67mV    -1.706mV   556.7mV
824ps     184.8mV    -6.612mV   890.2mV
1.04ns    338.4mV    -8.07mV    1.075V
1.576ns   657.8mV    30.06mV    1.241V
2.064ns   839.3mV    124.4mV    1.293V
3.944ns   1.023V     441.3mV    1.343V
6.136ns   1.059V     581mV      1.349V
19.45ns   1.069V     657.1mV    1.35V
[Falling Waveform]
R_fixture = 50
V_fixture = 1.8
V_fixture_min = 1.62
V_fixture_max = 1.89
0s        1.8V       1.62V      1.891V
192ps     1.8V       1.62V      1.87V
584ps     1.781V     1.62V      1.525V
880ps     1.652V     1.621V     1.24V
1.264ns   1.475V     1.621V     700.6mV
1.552ns   1.336V     1.599V     566.3mV
2.344ns   833.5mV    1.469V     536.4mV
2.992ns   754.1mV    1.365V     533.3mV
5.48ns    721mV      1.061V     532.6mV
13.86ns   720mV      1.012V     532.6mV
[Falling Waveform]
R_fixture = 50
V_fixture = 0
V_fixture_min = 0
V_fixture_max = 0
0s        1.069V     658.6mV    1.351V
224ps     1.069V     658.8mV    1.303V
608ps     1.029V     658.7mV    752.4mV
912ps     795.1mV    661.4mV    277.7mV
1.288ns   406.6mV    656.1mV    18.65mV
1.688ns   148.2mV    573mV      3.073mV
2.184ns   10.83mV    378.8mV    1.924mV
2.752ns   2.615mV    187.8mV    1.788mV
3.352ns   1.679mV    64.26mV    1.774mV
4.816ns   1.424mV    2.609mV    1.773mV
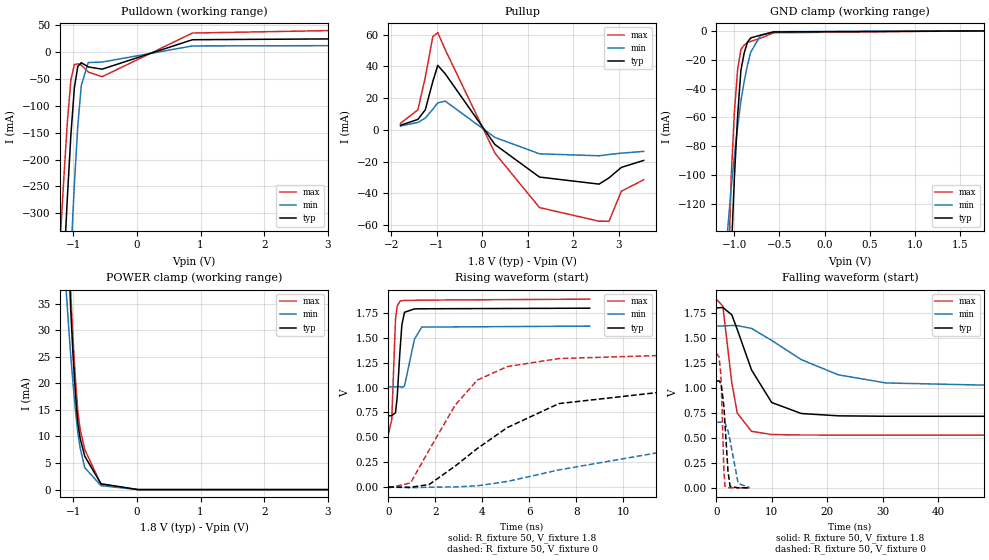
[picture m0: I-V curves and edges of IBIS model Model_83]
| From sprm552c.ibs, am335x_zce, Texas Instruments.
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| Model based on original model for OQ18SMART1FBPB_SSBHH
|   Sub model SBHH_HS00L00_PD1_1P8
[model]   Model_83
|[Description]  [1.8V-3-STATE-PD-S00:L00]
|   S00, L00,Weak internal pull-down, ,
|[Input Load]   PD
|[Output Drive] S00:L00
|Voltage   1.8V
|Mode   3-STATE
Model_type   3-state
Polarity   Non-Inverting
Enable   Active-Low
Cref =  15pF
Rref =  100.0000M
Vref =  0V
Vmeas =  0.9
C_comp   1.240965p   1.099743p   1.401226p
[Temperature Range]   25   125   -40
[Voltage Range]   1.8   1.62   1.89
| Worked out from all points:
|   slope of the pulldown table from 0 to 0.27 V, typ, clamps not added: 24.3 ohm
|   slope of the pullup table from 0 to 0.27 V, typ, clamps not added: 29.7 ohm
|   GND clamp passes 1 mA (typ) near -0.60 V on its own axis
|   POWER clamp passes 1 mA (typ) near -0.55 V on its own axis
|   rising waveform, R_fixture 50, V_fixture 1.8: 20-80 % time 173ps typ, 312ps min, 118ps max; typ from 0.716 V to 1.8 V
|   rising waveform, R_fixture 50, V_fixture 0: 20-80 % time 4.61ns typ, 10.7ns min, 2.3ns max; typ from 0.001 V to 1.06 V
|   falling waveform, R_fixture 50, V_fixture 1.8: 20-80 % time 4.9ns typ, 12.6ns min, 1.98ns max; typ from 1.8 V to 0.716 V
|   falling waveform, R_fixture 50, V_fixture 0: 20-80 % time 727ps typ, 1.23ns min, 441ps max; typ from 1.06 V to 0 V
[POWER_clamp]
-1.8V     360mA      189.8mA    409.4mA
-1.109V   56.22mA    37.38mA    59.76mA
-1.073V   44.22mA    30.95mA    47.31mA
-1.036V   33.15mA    24.83mA    36.24mA
-1V       24.78mA    19.56mA    27.83mA
-963.6mV  17.91mA    14.85mA    20.66mA
-927.3mV  12.54mA    10.7mA     14.72mA
-890.9mV  9.653mA    7.864mA    11.36mA
-818.2mV  6.28mA     4.131mA    7.54mA
-563.6mV  1.102mA    739.4uA    992.8uA
18.18mV   0A         0A         0A
3.6V      0A         0A         0A
[Pulldown]
-1.8V     -1.72A     -2.612A    -1.411A
-1.2V     -528.3mA   -845.3mA   -342.5mA
-1.145V   -396.8mA   -683.8mA   -231.2mA
-1.091V   -269.6mA   -527.2mA   -129mA
-1.036V   -154.1mA   -379.3mA   -51.85mA
-981.8mV  -66.54mA   -245.9mA   -22.8mA
-927.3mV  -26.05mA   -136.4mA   -21.6mA
-872.7mV  -19.36mA   -62.04mA   -23.73mA
-763.6mV  -27.2mA    -19.06mA   -36.72mA
-545.5mV  -31.39mA   -18.17mA   -45.46mA
872.7mV   23.46mA    11.88mA    35.92mA
3.545V    25.35mA    12.51mA    41.59mA
[Pullup]
-1.8V     2.903mA    2.423mA    4.111mA
-1.418V   6.594mA    4.711mA    12.64mA
-1.255V   12.69mA    7.42mA     33.23mA
-1.091V   30.4mA     13mA       58.71mA
-981.8mV  40.64mA    17.02mA    61.32mA
-818.2mV  35.38mA    18.12mA    50.59mA
272.7mV   -9.18mA    -4.728mA   -14.55mA
1.255V    -29.75mA   -15.09mA   -48.97mA
2.564V    -34.18mA   -16.32mA   -57.57mA
2.782V    -30.27mA   -15.51mA   -57.62mA
3.055V    -23.64mA   -14.69mA   -38.68mA
3.545V    -19.26mA   -13.56mA   -31.45mA
[GND_clamp]
-1.8V     -2.816A    -1.188A    -3.154A
-1.073V   -234.2mA   -137.3mA   -187.2mA
-1.036V   -158.1mA   -109.8mA   -103.1mA
-1V       -102.5mA   -86.97mA   -56.82mA
-963.6mV  -58.95mA   -66.55mA   -26.72mA
-927.3mV  -27.37mA   -48.49mA   -12.78mA
-890.9mV  -15.3mA    -35.02mA   -9.769mA
-854.5mV  -7.767mA   -23.73mA   -7.908mA
-818.2mV  -4.764mA   -14.63mA   -7.195mA
-709.1mV  -2.84mA    -3.059mA   -4.978mA
-563.6mV  -632.1uA   -435.2uA   -1.184mA
1.764V    97.78uA    55.01uA    156.4uA
[Ramp]
dV/dt_f  0.6529131/4.904962n   0.369366/12.68222n   0.8190077/1.984229n
dV/dt_r  0.6488842/4.630021n   0.399013/10.81121n   0.820932/2.30337n
R_load = 50
[Rising Waveform]
R_fixture = 50
V_fixture = 1.8
V_fixture_min = 1.62
V_fixture_max = 1.89
0s        715.7mV    1.007V     530.2mV
144ps     717.4mV    1.007V     677mV
304ps     746.7mV    1.007V     1.687V
376ps     903.3mV    1.008V     1.818V
488ps     1.344V     1.009V     1.865V
576ps     1.631V     999.9mV    1.872V
688ps     1.756V     1.015V     1.875V
1.112ns   1.79V      1.486V     1.876V
1.424ns   1.791V     1.607V     1.878V
8.576ns   1.797V     1.617V     1.888V
[Rising Waveform]
R_fixture = 50
V_fixture = 0
V_fixture_min = 0
V_fixture_max = 0
0s        531.5uV    124.7uV    -8.336mV
944ps     -2.527mV   -7.274mV   41.32mV
1.736ns   25.1mV     -1.799mV   371.5mV
2.84ns    209.6mV    1.113mV    821.6mV
3.784ns   386.1mV    12.05mV    1.074V
5.064ns   597.3mV    55.67mV    1.21V
7.264ns   838.4mV    172mV      1.291V
14.3ns    1.024V     460.6mV    1.341V
23.62ns   1.059V     594.2mV    1.346V
68.2ns    1.065V     654.4mV    1.346V
[Falling Waveform]
R_fixture = 50
V_fixture = 1.8
V_fixture_min = 1.62
V_fixture_max = 1.89
0s        1.798V     1.618V     1.887V
1.184ns   1.804V     1.619V     1.817V
2.8ns     1.73V      1.623V     1.05V
3.792ns   1.582V     1.622V     746.6mV
6.36ns    1.179V     1.594V     565.3mV
10ns      853.3mV    1.474V     533.4mV
15.34ns   743.3mV    1.282V     528.5mV
22.02ns   720.2mV    1.13V      528.2mV
30.6ns    716mV      1.049V     528.2mV
63.17ns   715.5mV    1.009V     528.2mV
[Falling Waveform]
R_fixture = 50
V_fixture = 0
V_fixture_min = 0
V_fixture_max = 0
0s        1.065V     655.9mV    1.346V
488ps     1.071V     655.7mV    1.312V
808ps     1.045V     657.3mV    1.143V
920ps     1.022V     659.6mV    999.8mV
1.368ns   819.2mV    662.1mV    174.2mV
1.56ns    651mV      651.6mV    17.68mV
2.112ns   166.7mV    573mV      1.23mV
2.488ns   14.96mV    474.5mV    519.8uV
3.952ns   676.4uV    43.93mV    169.9uV
6.032ns   251uV      1.639mV    68.49uV
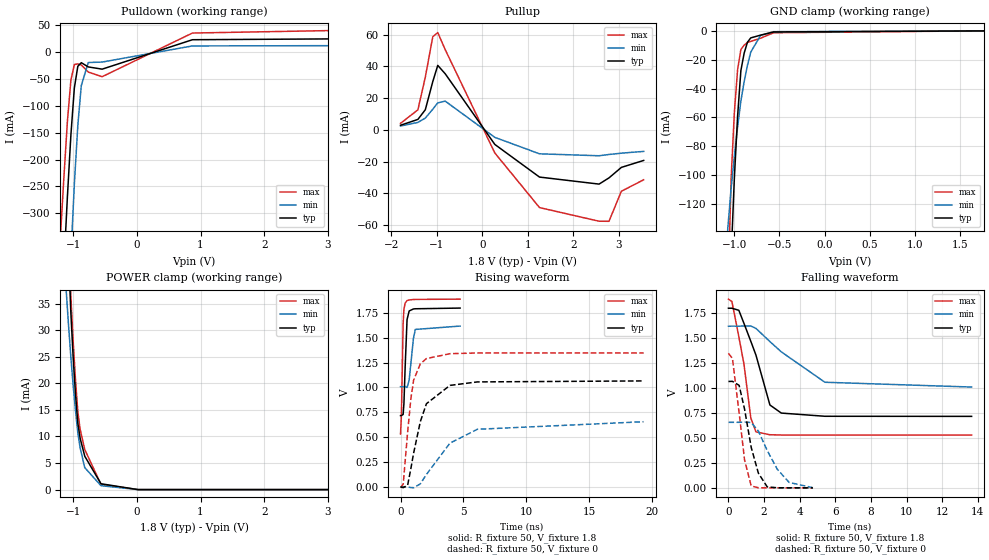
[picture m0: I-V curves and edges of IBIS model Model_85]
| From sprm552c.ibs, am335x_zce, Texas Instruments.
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| Model based on original model for OQ18SMART1FBPB_SSBHH
|   Sub model SBHH_HS11L10_PD1_1P8
[model]   Model_85
|[Description]  [1.8V-3-STATE-PD-S11:L10]
|   S11, L10,Weak internal pull-down, ,
|[Input Load]   PD
|[Output Drive] S11:L10
|Voltage   1.8V
|Mode   3-STATE
Model_type   3-state
Polarity   Non-Inverting
Enable   Active-Low
Cref =  15pF
Rref =  100.0000M
Vref =  0V
Vmeas =  0.9
C_comp   1.240965p   1.099743p   1.401226p
[Temperature Range]   25   125   -40
[Voltage Range]   1.8   1.62   1.89
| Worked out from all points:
|   slope of the pulldown table from 0 to 0.27 V, typ, clamps not added: 24.3 ohm
|   slope of the pullup table from 0 to 0.27 V, typ, clamps not added: 29.7 ohm
|   GND clamp passes 1 mA (typ) near -0.60 V on its own axis
|   POWER clamp passes 1 mA (typ) near -0.55 V on its own axis
|   rising waveform, R_fixture 50, V_fixture 1.8: 20-80 % time 170ps typ, 296ps min, 118ps max; typ from 0.716 V to 1.8 V
|   rising waveform, R_fixture 50, V_fixture 0: 20-80 % time 1.27ns typ, 2.83ns min, 672ps max; typ from 0 V to 1.06 V
|   falling waveform, R_fixture 50, V_fixture 1.8: 20-80 % time 1.12ns typ, 2.11ns min, 704ps max; typ from 1.8 V to 0.716 V
|   falling waveform, R_fixture 50, V_fixture 0: 20-80 % time 713ps typ, 1.17ns min, 522ps max; typ from 1.06 V to 0 V
[POWER_clamp]
-1.8V     360mA      189.8mA    409.4mA
-1.109V   56.22mA    37.38mA    59.76mA
-1.073V   44.22mA    30.95mA    47.31mA
-1.036V   33.15mA    24.83mA    36.24mA
-1V       24.78mA    19.56mA    27.83mA
-963.6mV  17.91mA    14.85mA    20.66mA
-927.3mV  12.54mA    10.7mA     14.72mA
-890.9mV  9.653mA    7.864mA    11.36mA
-818.2mV  6.28mA     4.131mA    7.54mA
-563.6mV  1.102mA    739.4uA    992.8uA
18.18mV   0A         0A         0A
3.6V      0A         0A         0A
[Pulldown]
-1.8V     -1.72A     -2.612A    -1.411A
-1.2V     -528.3mA   -845.3mA   -342.5mA
-1.145V   -396.8mA   -683.8mA   -231.2mA
-1.091V   -269.6mA   -527.2mA   -129mA
-1.036V   -154.1mA   -379.3mA   -51.85mA
-981.8mV  -66.54mA   -245.9mA   -22.8mA
-927.3mV  -26.05mA   -136.4mA   -21.6mA
-872.7mV  -19.36mA   -62.04mA   -23.73mA
-763.6mV  -27.2mA    -19.06mA   -36.72mA
-545.5mV  -31.39mA   -18.17mA   -45.46mA
872.7mV   23.46mA    11.88mA    35.92mA
3.545V    25.35mA    12.51mA    41.59mA
[Pullup]
-1.8V     2.903mA    2.423mA    4.111mA
-1.418V   6.594mA    4.711mA    12.64mA
-1.255V   12.69mA    7.42mA     33.23mA
-1.091V   30.4mA     13mA       58.71mA
-981.8mV  40.64mA    17.02mA    61.32mA
-818.2mV  35.38mA    18.12mA    50.59mA
272.7mV   -9.18mA    -4.728mA   -14.55mA
1.255V    -29.75mA   -15.09mA   -48.97mA
2.564V    -34.18mA   -16.32mA   -57.57mA
2.782V    -30.27mA   -15.51mA   -57.62mA
3.055V    -23.64mA   -14.69mA   -38.68mA
3.545V    -19.26mA   -13.56mA   -31.45mA
[GND_clamp]
-1.8V     -2.816A    -1.188A    -3.154A
-1.073V   -234.2mA   -137.3mA   -187.2mA
-1.036V   -158.1mA   -109.8mA   -103.1mA
-1V       -102.5mA   -86.97mA   -56.82mA
-963.6mV  -58.95mA   -66.55mA   -26.72mA
-927.3mV  -27.37mA   -48.49mA   -12.78mA
-890.9mV  -15.3mA    -35.02mA   -9.769mA
-854.5mV  -7.767mA   -23.73mA   -7.908mA
-818.2mV  -4.764mA   -14.63mA   -7.195mA
-709.1mV  -2.84mA    -3.059mA   -4.978mA
-563.6mV  -632.1uA   -435.2uA   -1.184mA
1.764V    97.78uA    55.01uA    156.4uA
[Ramp]
dV/dt_f  0.6517046/1.125619n   0.36838/2.126835n   0.8183031/0.7067854n
dV/dt_r  0.6488691/1.269419n   0.399631/2.853145n   0.8198795/0.6730091n
R_load = 50
[Rising Waveform]
R_fixture = 50
V_fixture = 1.8
V_fixture_min = 1.62
V_fixture_max = 1.89
0s        715.6mV    1.007V     530.6mV
72ps      717mV      1.007V     725.7mV
208ps     727.6mV    1.007V     1.641V
272ps     838.1mV    1.007V     1.788V
368ps     1.202V     1.008V     1.848V
520ps     1.682V     999.4mV    1.873V
688ps     1.769V     1.073V     1.88V
1.024ns   1.789V     1.488V     1.884V
1.176ns   1.791V     1.583V     1.885V
4.744ns   1.798V     1.617V     1.888V
[Rising Waveform]
R_fixture = 50
V_fixture = 0
V_fixture_min = 0
V_fixture_max = 0
0s        20.22uV    125.6uV    -11.09mV
216ps     -9.216mV   -91.29uV   27.44mV
568ps     16.62mV    -2.686mV   552.9mV
824ps     183.2mV    -7.773mV   885.7mV
1.04ns    336.6mV    -9.806mV   1.071V
1.576ns   655mV      28.88mV    1.237V
2.064ns   835.9mV    124mV      1.29V
3.936ns   1.02V      439mV      1.339V
6.12ns    1.055V     578.3mV    1.346V
19.36ns   1.065V     654.4mV    1.346V
[Falling Waveform]
R_fixture = 50
V_fixture = 1.8
V_fixture_min = 1.62
V_fixture_max = 1.89
0s        1.798V     1.618V     1.889V
192ps     1.798V     1.619V     1.866V
584ps     1.777V     1.618V     1.513V
872ps     1.646V     1.62V      1.237V
1.256ns   1.467V     1.62V      699.5mV
1.544ns   1.329V     1.596V     560.5mV
2.328ns   829.4mV    1.464V     531.8mV
2.968ns   748.6mV    1.361V     528.9mV
5.416ns   716.5mV    1.057V     528.2mV
13.65ns   715.5mV    1.009V     528.2mV
[Falling Waveform]
R_fixture = 50
V_fixture = 0
V_fixture_min = 0
V_fixture_max = 0
0s        1.065V     655.9mV    1.347V
224ps     1.066V     656.1mV    1.295V
600ps     1.026V     656mV      751.4mV
904ps     788.9mV    658.6mV    280.3mV
1.28ns    403.7mV    653.6mV    18.2mV
1.68ns    147.5mV    568.4mV    1.268mV
2.176ns   9.724mV    373.8mV    145.2uV
2.744ns   1.175mV    185.8mV    13.85uV
3.408ns   237.9uV    54.12mV    1.208uV
4.744ns   34.9uV     1.642mV    67.33nV
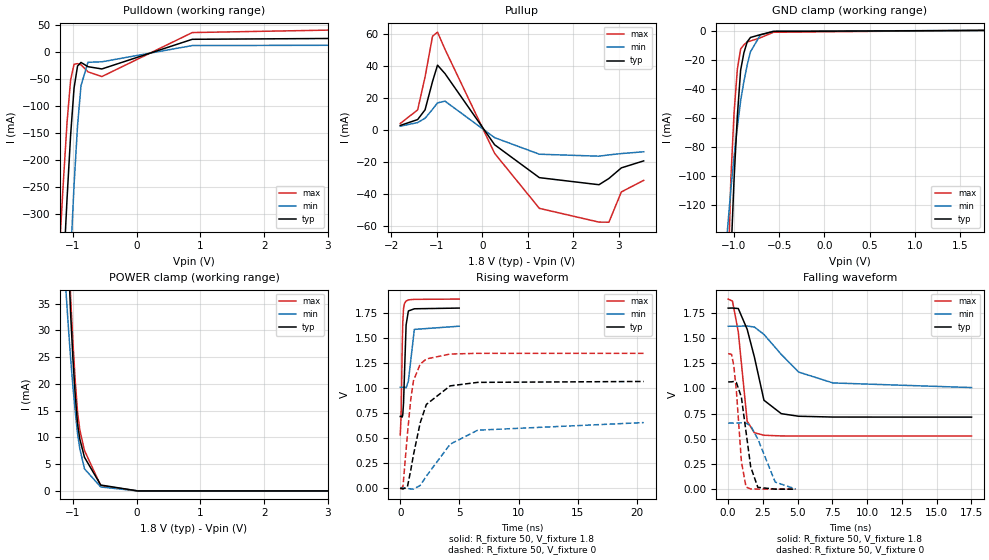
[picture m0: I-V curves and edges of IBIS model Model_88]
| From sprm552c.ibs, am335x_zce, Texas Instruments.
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| Model based on original model for OQ18SMART1FBPB_SSBHH
|   Sub model SBHH_HS10L10_PD1_1P8
[model]   Model_88
|[Description]  [1.8V-3-STATE-PD-S10:L10]
|   S10, L10,Weak internal pull-down, ,
|[Input Load]   PD
|[Output Drive] S10:L10
|Voltage   1.8V
|Mode   3-STATE
Model_type   3-state
Polarity   Non-Inverting
Enable   Active-Low
Cref =  15pF
Rref =  100.0000M
Vref =  0V
Vmeas =  0.9
C_comp   1.240965p   1.099743p   1.401226p
[Temperature Range]   25   125   -40
[Voltage Range]   1.8   1.62   1.89
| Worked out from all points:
|   slope of the pulldown table from 0 to 0.27 V, typ, clamps not added: 24.3 ohm
|   slope of the pullup table from 0 to 0.27 V, typ, clamps not added: 29.7 ohm
|   GND clamp passes 1 mA (typ) near -0.60 V on its own axis
|   POWER clamp passes 1 mA (typ) near -0.55 V on its own axis
|   rising waveform, R_fixture 50, V_fixture 1.8: 20-80 % time 172ps typ, 302ps min, 118ps max; typ from 0.716 V to 1.8 V
|   rising waveform, R_fixture 50, V_fixture 0: 20-80 % time 1.34ns typ, 3.01ns min, 709ps max; typ from 0 V to 1.06 V
|   falling waveform, R_fixture 50, V_fixture 1.8: 20-80 % time 1.04ns typ, 2.68ns min, 594ps max; typ from 1.8 V to 0.716 V
|   falling waveform, R_fixture 50, V_fixture 0: 20-80 % time 605ps typ, 1.04ns min, 430ps max; typ from 1.06 V to 0 V
[POWER_clamp]
-1.8V     360mA      189.8mA    409.4mA
-1.109V   56.22mA    37.38mA    59.76mA
-1.073V   44.22mA    30.95mA    47.31mA
-1.036V   33.15mA    24.83mA    36.24mA
-1V       24.78mA    19.56mA    27.83mA
-963.6mV  17.91mA    14.85mA    20.66mA
-927.3mV  12.54mA    10.7mA     14.72mA
-890.9mV  9.653mA    7.864mA    11.36mA
-818.2mV  6.28mA     4.131mA    7.54mA
-563.6mV  1.102mA    739.4uA    992.8uA
18.18mV   0A         0A         0A
3.6V      0A         0A         0A
[Pulldown]
-1.8V     -1.72A     -2.612A    -1.411A
-1.2V     -528.3mA   -845.3mA   -342.5mA
-1.145V   -396.8mA   -683.8mA   -231.2mA
-1.091V   -269.6mA   -527.2mA   -129mA
-1.036V   -154.1mA   -379.3mA   -51.85mA
-981.8mV  -66.54mA   -245.9mA   -22.8mA
-927.3mV  -26.05mA   -136.4mA   -21.6mA
-872.7mV  -19.36mA   -62.04mA   -23.73mA
-763.6mV  -27.2mA    -19.06mA   -36.72mA
-545.5mV  -31.39mA   -18.17mA   -45.46mA
872.7mV   23.46mA    11.88mA    35.92mA
3.545V    25.35mA    12.51mA    41.59mA
[Pullup]
-1.8V     2.903mA    2.423mA    4.111mA
-1.418V   6.594mA    4.711mA    12.64mA
-1.255V   12.69mA    7.42mA     33.23mA
-1.091V   30.4mA     13mA       58.71mA
-981.8mV  40.64mA    17.02mA    61.32mA
-818.2mV  35.38mA    18.12mA    50.59mA
272.7mV   -9.18mA    -4.728mA   -14.55mA
1.255V    -29.75mA   -15.09mA   -48.97mA
2.564V    -34.18mA   -16.32mA   -57.57mA
2.782V    -30.27mA   -15.51mA   -57.62mA
3.055V    -23.64mA   -14.69mA   -38.68mA
3.545V    -19.26mA   -13.56mA   -31.45mA
[GND_clamp]
-1.8V     -2.816A    -1.188A    -3.154A
-1.073V   -234.2mA   -137.3mA   -187.2mA
-1.036V   -158.1mA   -109.8mA   -103.1mA
-1V       -102.5mA   -86.97mA   -56.82mA
-963.6mV  -58.95mA   -66.55mA   -26.72mA
-927.3mV  -27.37mA   -48.49mA   -12.78mA
-890.9mV  -15.3mA    -35.02mA   -9.769mA
-854.5mV  -7.767mA   -23.73mA   -7.908mA
-818.2mV  -4.764mA   -14.63mA   -7.195mA
-709.1mV  -2.84mA    -3.059mA   -4.978mA
-563.6mV  -632.1uA   -435.2uA   -1.184mA
1.764V    97.78uA    55.01uA    156.4uA
[Ramp]
dV/dt_f   0.651717/1.04473n   0.368554/2.704587n   0.8181896/0.5961449n
dV/dt_r  0.6498626/1.34611n   0.3999595/3.035446n   0.8216817/0.7108189n
R_load = 50
[Rising Waveform]
R_fixture = 50
V_fixture = 1.8
V_fixture_min = 1.62
V_fixture_max = 1.89
0s        715.5mV    1.007V     531.5mV
72ps      717.4mV    1.007V     712.8mV
168ps     709.8mV    1.007V     1.412V
216ps     734.7mV    1.007V     1.658V
280ps     852.5mV    1.008V     1.793V
360ps     1.149V     1.009V     1.845V
496ps     1.63V      1V         1.868V
688ps     1.769V     1.07V      1.88V
1.192ns   1.791V     1.585V     1.885V
4.984ns   1.798V     1.617V     1.888V
[Rising Waveform]
R_fixture = 50
V_fixture = 0
V_fixture_min = 0
V_fixture_max = 0
0s        55.49uV    127.7uV    -10.62mV
232ps     -9.149mV   -100uV     17.76mV
608ps     13.76mV    -3.581mV   539.9mV
888ps     178.7mV    -8.167mV   886.1mV
1.12ns    333.7mV    -10.26mV   1.073V
1.688ns   652.8mV    26.75mV    1.239V
2.208ns   835.8mV    119.6mV    1.29V
4.216ns   1.021V     438.5mV    1.339V
6.544ns   1.056V     578.5mV    1.346V
20.57ns   1.065V     654.4mV    1.346V
[Falling Waveform]
R_fixture = 50
V_fixture = 1.8
V_fixture_min = 1.62
V_fixture_max = 1.89
0s        1.798V     1.618V     1.888V
312ps     1.799V     1.619V     1.867V
728ps     1.794V     1.618V     1.563V
1.368ns   1.588V     1.621V     675.3mV
1.888ns   1.312V     1.61V      560mV
2.576ns   883.2mV    1.537V     535.4mV
3.824ns   749.8mV    1.338V     528.8mV
5.072ns   724.2mV    1.163V     528.2mV
7.544ns   716.2mV    1.055V     528.2mV
17.52ns   715.5mV    1.009V     528.2mV
[Falling Waveform]
R_fixture = 50
V_fixture = 0
V_fixture_min = 0
V_fixture_max = 0
0s        1.065V     655.9mV    1.346V
240ps     1.066V     656.1mV    1.339V
400ps     1.069V     655.9mV    1.232V
592ps     1.059V     656mV      977.9mV
952ps     914.1mV    658.9mV    275.5mV
1.288ns   567.6mV    656.4mV    20.8mV
1.624ns   220.4mV    628mV      1.848mV
2.136ns   18.26mV    498.3mV    236.2uV
3.384ns   342uV      70.6mV     6.231uV
4.856ns   53.81uV    1.637mV    434.7nV
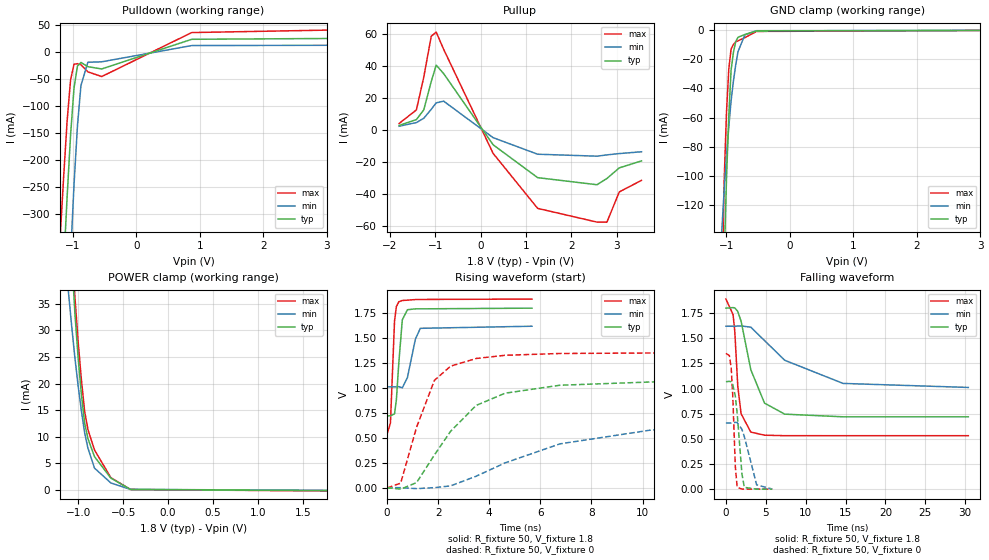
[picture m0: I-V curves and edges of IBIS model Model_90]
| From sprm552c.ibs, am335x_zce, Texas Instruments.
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| Model based on original model for OQ18SMART1FBPB_SSBHH
|   Sub model SBHH_HS00L11_PU1_1P8
[model]   Model_90
|[Description]  [1.8V-3-STATE-PU-S00:L11]
|   S00, L11,Weak internal pull-up, ,
|[Input Load]   PU
|[Output Drive] S00:L11
|Voltage   1.8V
|Mode   3-STATE
Model_type   3-state
Polarity   Non-Inverting
Enable   Active-Low
Cref =  15pF
Rref =  100.0000M
Vref =  0V
Vmeas =  0.9
C_comp   1.240965p   1.099743p   1.401226p
[Temperature Range]   25   125   -40
[Voltage Range]   1.8   1.62   1.89
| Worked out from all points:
|   slope of the pulldown table from 0 to 0.27 V, typ, clamps not added: 24.3 ohm
|   slope of the pullup table from 0 to 0.27 V, typ, clamps not added: 29.7 ohm
|   GND clamp passes 1 mA (typ) near -0.60 V on its own axis
|   POWER clamp passes 1 mA (typ) near -0.56 V on its own axis
|   rising waveform, R_fixture 50, V_fixture 1.8: 20-80 % time 170ps typ, 301ps min, 116ps max; typ from 0.72 V to 1.8 V
|   rising waveform, R_fixture 50, V_fixture 0: 20-80 % time 2.1ns typ, 4.82ns min, 1.07ns max; typ from 0.001 V to 1.07 V
|   falling waveform, R_fixture 50, V_fixture 1.8: 20-80 % time 2.1ns typ, 5.92ns min, 730ps max; typ from 1.8 V to 0.72 V
|   falling waveform, R_fixture 50, V_fixture 0: 20-80 % time 644ps typ, 1.17ns min, 382ps max; typ from 1.07 V to 0.002 V
[POWER_clamp]
-1.8V     360mA      189.8mA    409.4mA
-1.109V   56.23mA    37.39mA    59.78mA
-1.073V   44.23mA    30.96mA    47.33mA
-1.036V   33.16mA    24.83mA    36.25mA
-1V       24.78mA    19.56mA    27.84mA
-963.6mV  17.91mA    14.85mA    20.66mA
-927.3mV  12.54mA    10.7mA     14.72mA
-890.9mV  9.653mA    7.862mA    11.35mA
-818.2mV  6.273mA    4.126mA    7.524mA
-636.4mV  2.249mA    1.34mA     2.341mA
-418.2mV  128.7uA    129uA      104.8uA
1.764V    -96.73uA   -46.46uA   -163.5uA
[Pulldown]
-1.8V     -1.72A     -2.612A    -1.411A
-1.2V     -528.3mA   -845.3mA   -342.5mA
-1.145V   -396.8mA   -683.8mA   -231.2mA
-1.091V   -269.6mA   -527.2mA   -129mA
-1.036V   -154.1mA   -379.3mA   -51.85mA
-981.8mV  -66.54mA   -245.9mA   -22.8mA
-927.3mV  -26.05mA   -136.4mA   -21.6mA
-872.7mV  -19.36mA   -62.04mA   -23.73mA
-763.6mV  -27.2mA    -19.06mA   -36.72mA
-545.5mV  -31.39mA   -18.17mA   -45.46mA
872.7mV   23.46mA    11.88mA    35.92mA
3.545V    25.35mA    12.51mA    41.59mA
[Pullup]
-1.8V     2.903mA    2.423mA    4.111mA
-1.418V   6.594mA    4.711mA    12.64mA
-1.255V   12.69mA    7.42mA     33.23mA
-1.091V   30.4mA     13mA       58.71mA
-981.8mV  40.64mA    17.02mA    61.32mA
-818.2mV  35.38mA    18.12mA    50.59mA
272.7mV   -9.179mA   -4.728mA   -14.55mA
1.255V    -29.75mA   -15.09mA   -48.97mA
2.564V    -34.18mA   -16.32mA   -57.57mA
2.782V    -30.27mA   -15.51mA   -57.62mA
3.055V    -23.64mA   -14.69mA   -38.68mA
3.545V    -19.26mA   -13.56mA   -31.45mA
[GND_clamp]
-1.8V     -2.816A    -1.188A    -3.154A
-1.073V   -234.2mA   -137.3mA   -187.2mA
-1.036V   -158.1mA   -109.8mA   -103.1mA
-1V       -102.5mA   -86.97mA   -56.83mA
-963.6mV  -58.95mA   -66.55mA   -26.74mA
-927.3mV  -27.37mA   -48.49mA   -12.79mA
-890.9mV  -15.31mA   -35.02mA   -9.789mA
-854.5mV  -7.771mA   -23.73mA   -7.932mA
-818.2mV  -4.769mA   -14.63mA   -7.221mA
-709.1mV  -2.849mA   -3.058mA   -5.011mA
-527.3mV  -395.6uA   -259.7uA   -751.2uA
3.6V      0A         0A         0A
[Ramp]
dV/dt_f  0.6507616/2.0964n   0.3679481/5.965677n   0.8169867/0.7312189n
dV/dt_r  0.6505177/2.111557n   0.4004164/4.863319n   0.8219067/1.075858n
R_load = 50
[Rising Waveform]
R_fixture = 50
V_fixture = 1.8
V_fixture_min = 1.62
V_fixture_max = 1.89
0s        720.1mV    1.011V     534.5mV
136ps     721.5mV    1.011V     648.3mV
296ps     740.2mV    1.011V     1.67V
368ps     879.9mV    1.011V     1.814V
464ps     1.252V     1.013V     1.863V
600ps     1.682V     1.001V     1.876V
800ps     1.783V     1.104V     1.879V
1.112ns   1.792V     1.488V     1.885V
1.304ns   1.792V     1.597V     1.886V
5.672ns   1.799V     1.618V     1.89V
[Rising Waveform]
R_fixture = 50
V_fixture = 0
V_fixture_min = 0
V_fixture_max = 0
0s        1.329mV    1.07mV     -2.015mV
536ps     -13.76mV   1.275mV    46.46mV
1.16ns    52.33mV    -8.562mV   607.8mV
1.856ns   328.7mV    1.765mV    1.076V
2.488ns   565.3mV    19.07mV    1.218V
3.488ns   824.7mV    115.7mV    1.295V
4.624ns   947.6mV    249.7mV    1.327V
6.768ns   1.027V     440mV      1.345V
10.36ns   1.06V      579.7mV    1.35V
31.5ns    1.069V     657.1mV    1.35V
[Falling Waveform]
R_fixture = 50
V_fixture = 1.8
V_fixture_min = 1.62
V_fixture_max = 1.89
0s        1.8V       1.62V      1.89V
896ps     1.805V     1.62V      1.737V
1.112ns   1.802V     1.62V      1.572V
1.488ns   1.767V     1.622V     1.025V
1.904ns   1.67V      1.623V     750.7mV
3.12ns    1.189V     1.611V     568.8mV
4.84ns    856.4mV    1.478V     537.6mV
7.376ns   746.8mV    1.282V     532.9mV
14.69ns   720.4mV    1.052V     532.6mV
30.39ns   720mV      1.012V     532.6mV
[Falling Waveform]
R_fixture = 50
V_fixture = 0
V_fixture_min = 0
V_fixture_max = 0
0s        1.069V     658.6mV    1.35V
432ps     1.073V     658.6mV    1.329V
664ps     1.068V     658.6mV    1.204V
856ps     1.041V     660.4mV    940.4mV
1.184ns   925.3mV    665.8mV    221.7mV
1.416ns   752mV      662.2mV    20.18mV
2.008ns   155.7mV    595.6mV    2.852mV
2.312ns   19.73mV    523.5mV    2.276mV
3.856ns   1.938mV    44.44mV    1.833mV
5.808ns   1.549mV    2.597mV    1.782mV
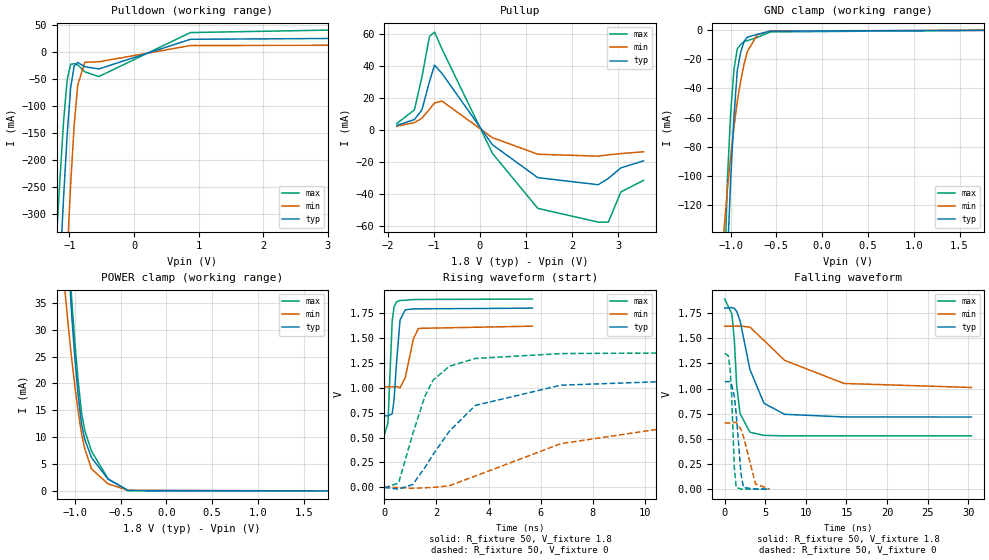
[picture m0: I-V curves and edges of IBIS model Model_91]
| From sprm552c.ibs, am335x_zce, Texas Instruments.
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| Model based on original model for OQ18SMART1FBPB_SSBHH
|   Sub model HH_HS00L11_PUPD0_1P8
[model]   Model_91
|[Description]  [1.8V-3-STATE-PI-S00:L11]
|   S00, L11,Weak pull up/down disabled, ,
|[Input Load]   PI
|[Output Drive] S00:L11
|Voltage   1.8V
|Mode   3-STATE
Model_type   3-state
Polarity   Non-Inverting
Enable   Active-Low
Cref =  15pF
Rref =  100.0000M
Vref =  0V
Vmeas =  0.9
C_comp   1.240965p   1.099743p   1.401226p
[Temperature Range]   25   125   -40
[Voltage Range]   1.8   1.62   1.89
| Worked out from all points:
|   slope of the pulldown table from 0 to 0.27 V, typ, clamps not added: 24.3 ohm
|   slope of the pullup table from 0 to 0.27 V, typ, clamps not added: 29.7 ohm
|   GND clamp passes 1 mA (typ) near -0.60 V on its own axis
|   POWER clamp passes 1 mA (typ) near -0.56 V on its own axis
|   rising waveform, R_fixture 50, V_fixture 1.8: 20-80 % time 171ps typ, 302ps min, 117ps max; typ from 0.718 V to 1.8 V
|   rising waveform, R_fixture 50, V_fixture 0: 20-80 % time 2.11ns typ, 4.82ns min, 1.07ns max; typ from 0 V to 1.07 V
|   falling waveform, R_fixture 50, V_fixture 1.8: 20-80 % time 2.09ns typ, 5.92ns min, 729ps max; typ from 1.8 V to 0.718 V
|   falling waveform, R_fixture 50, V_fixture 0: 20-80 % time 643ps typ, 1.17ns min, 382ps max; typ from 1.07 V to 0 V
[POWER_clamp]
-1.8V     360mA      189.8mA    409.4mA
-1.109V   56.16mA    37.36mA    59.65mA
-1.073V   44.16mA    30.93mA    47.2mA
-1.036V   33.09mA    24.8mA     36.11mA
-1V       24.71mA    19.53mA    27.71mA
-963.6mV  17.83mA    14.82mA    20.53mA
-927.3mV  12.46mA    10.66mA    14.59mA
-890.9mV  9.571mA    7.827mA    11.23mA
-818.2mV  6.195mA    4.088mA    7.402mA
-636.4mV  2.183mA    1.306mA    2.238mA
-418.2mV  83.85uA    105.2uA    35.14uA
1.764V    -1.213nA   -79.04nA   -1.357nA
[Pulldown]
-1.8V     -1.72A     -2.612A    -1.411A
-1.2V     -528.3mA   -845.3mA   -342.5mA
-1.145V   -396.8mA   -683.8mA   -231.2mA
-1.091V   -269.6mA   -527.2mA   -129mA
-1.036V   -154.1mA   -379.3mA   -51.86mA
-981.8mV  -66.54mA   -245.9mA   -22.8mA
-927.3mV  -26.05mA   -136.4mA   -21.6mA
-872.7mV  -19.36mA   -62.04mA   -23.73mA
-763.6mV  -27.2mA    -19.06mA   -36.72mA
-545.5mV  -31.39mA   -18.17mA   -45.46mA
872.7mV   23.46mA    11.88mA    35.92mA
3.545V    25.35mA    12.51mA    41.59mA
[Pullup]
-1.8V     2.903mA    2.423mA    4.111mA
-1.418V   6.594mA    4.711mA    12.64mA
-1.255V   12.68mA    7.42mA     33.22mA
-1.091V   30.4mA     13mA       58.7mA
-981.8mV  40.64mA    17.02mA    61.32mA
-818.2mV  35.38mA    18.12mA    50.59mA
272.7mV   -9.18mA    -4.728mA   -14.55mA
1.255V    -29.75mA   -15.09mA   -48.97mA
2.564V    -34.18mA   -16.32mA   -57.57mA
2.782V    -30.27mA   -15.51mA   -57.62mA
3.055V    -23.64mA   -14.69mA   -38.68mA
3.545V    -19.26mA   -13.56mA   -31.45mA
[GND_clamp]
-1.8V     -2.816A    -1.188A    -3.154A
-1.073V   -234.1mA   -137.3mA   -187.2mA
-1.036V   -158.1mA   -109.8mA   -103mA
-1V       -102.5mA   -86.96mA   -56.78mA
-963.6mV  -58.91mA   -66.54mA   -26.67mA
-927.3mV  -27.33mA   -48.47mA   -12.72mA
-890.9mV  -15.25mA   -35mA      -9.693mA
-854.5mV  -7.712mA   -23.72mA   -7.821mA
-818.2mV  -4.703mA   -14.61mA   -7.099mA
-709.1mV  -2.775mA   -3.029mA   -4.882mA
-563.6mV  -570.1uA   -403.1uA   -1.092mA
1.764V    -22.34pA   583.3nA    2.874nA
[Ramp]
dV/dt_f  0.6521826/2.092273n   0.3687018/5.964417n   0.8186761/0.7283263n
dV/dt_r  0.6519272/2.115817n   0.4008211/4.868605n   0.8247866/1.078351n
R_load = 50
[Rising Waveform]
R_fixture = 50
V_fixture = 1.8
V_fixture_min = 1.62
V_fixture_max = 1.89
0s        717.8mV    1.009V     531.7mV
136ps     719.1mV    1.009V     644.5mV
296ps     737.7mV    1.009V     1.665V
368ps     876.8mV    1.01V      1.812V
464ps     1.248V     1.012V     1.862V
600ps     1.68V      1V         1.876V
800ps     1.782V     1.103V     1.878V
1.112ns   1.791V     1.488V     1.885V
1.304ns   1.792V     1.596V     1.886V
5.688ns   1.799V     1.618V     1.89V
[Rising Waveform]
R_fixture = 50
V_fixture = 0
V_fixture_min = 0
V_fixture_max = 0
0s        -58.47uV   105.1uV    -3.804mV
544ps     -17.6mV    131.7uV    43.75mV
1.088ns   28.72mV    -9.782mV   537mV
1.552ns   198.6mV    -3.365mV   912.6mV
1.864ns   327.6mV    -449.9uV   1.075V
2.496ns   564mV      17.28mV    1.216V
3.496ns   823.1mV    114.5mV    1.294V
6.784ns   1.026V     439.1mV    1.343V
10.38ns   1.059V     578.7mV    1.348V
31.55ns   1.068V     655.8mV    1.349V
[Falling Waveform]
R_fixture = 50
V_fixture = 1.8
V_fixture_min = 1.62
V_fixture_max = 1.89
0s        1.8V       1.62V      1.89V
888ps     1.805V     1.62V      1.742V
1.184ns   1.798V     1.621V     1.486V
1.48ns    1.768V     1.622V     1.03V
1.896ns   1.673V     1.623V     750.1mV
3.112ns   1.189V     1.611V     566.1mV
4.832ns   854.6mV    1.479V     534.8mV
7.376ns   744.3mV    1.281V     530.1mV
14.69ns   718mV      1.051V     529.8mV
30.39ns   717.6mV    1.011V     529.8mV
[Falling Waveform]
R_fixture = 50
V_fixture = 0
V_fixture_min = 0
V_fixture_max = 0
0s        1.067V     657.3mV    1.349V
432ps     1.071V     657.3mV    1.328V
664ps     1.066V     657.3mV    1.202V
856ps     1.039V     659mV      937.5mV
1.184ns   923.3mV    664.5mV    217.9mV
1.416ns   749mV      660.9mV    17.58mV
2.008ns   152.3mV    594.1mV    853uV
2.312ns   17.31mV    521.7mV    360.1uV
3.8ns     401uV      51.68mV    43.43uV
5.512ns   127.9uV    1.626mV    8.861uV
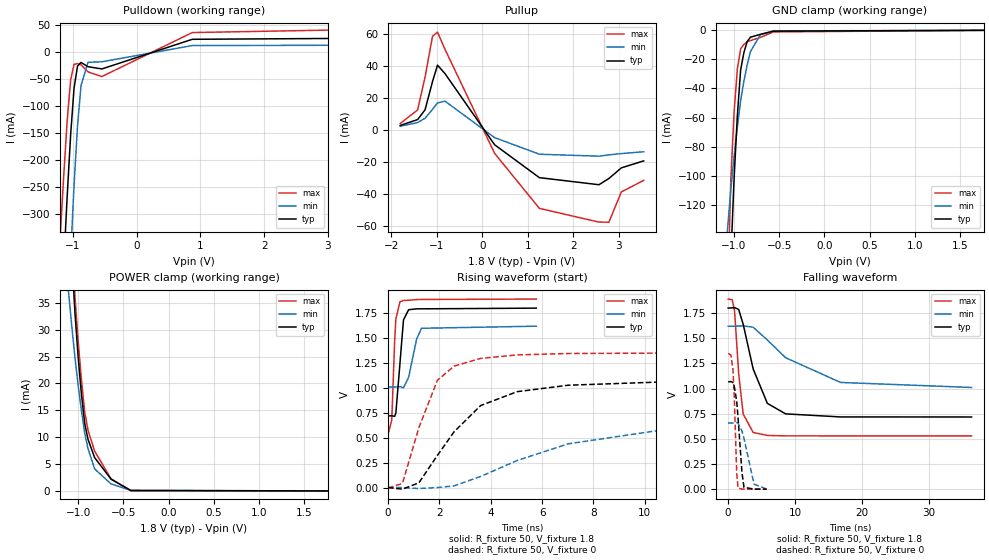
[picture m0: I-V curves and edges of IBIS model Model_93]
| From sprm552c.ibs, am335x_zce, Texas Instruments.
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| Model based on original model for OQ18SMART1FBPB_SSBHH
|   Sub model HH_HS00L10_PUPD0_1P8
[model]   Model_93
|[Description]  [1.8V-3-STATE-PI-S00:L10]
|   S00, L10,Weak pull up/down disabled, ,
|[Input Load]   PI
|[Output Drive] S00:L10
|Voltage   1.8V
|Mode   3-STATE
Model_type   3-state
Polarity   Non-Inverting
Enable   Active-Low
Cref =  15pF
Rref =  100.0000M
Vref =  0V
Vmeas =  0.9
C_comp   1.240965p   1.099743p   1.401226p
[Temperature Range]   25   125   -40
[Voltage Range]   1.8   1.62   1.89
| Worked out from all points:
|   slope of the pulldown table from 0 to 0.27 V, typ, clamps not added: 24.3 ohm
|   slope of the pullup table from 0 to 0.27 V, typ, clamps not added: 29.7 ohm
|   GND clamp passes 1 mA (typ) near -0.60 V on its own axis
|   POWER clamp passes 1 mA (typ) near -0.56 V on its own axis
|   rising waveform, R_fixture 50, V_fixture 1.8: 20-80 % time 171ps typ, 302ps min, 117ps max; typ from 0.718 V to 1.8 V
|   rising waveform, R_fixture 50, V_fixture 0: 20-80 % time 2.17ns typ, 4.97ns min, 1.1ns max; typ from 0 V to 1.07 V
|   falling waveform, R_fixture 50, V_fixture 1.8: 20-80 % time 2.71ns typ, 7.23ns min, 940ps max; typ from 1.8 V to 0.718 V
|   falling waveform, R_fixture 50, V_fixture 0: 20-80 % time 699ps typ, 1.22ns min, 394ps max; typ from 1.07 V to 0 V
[POWER_clamp]
-1.8V     360mA      189.8mA    409.4mA
-1.109V   56.16mA    37.36mA    59.65mA
-1.073V   44.16mA    30.93mA    47.2mA
-1.036V   33.09mA    24.8mA     36.11mA
-1V       24.71mA    19.53mA    27.71mA
-963.6mV  17.83mA    14.82mA    20.53mA
-927.3mV  12.46mA    10.66mA    14.59mA
-890.9mV  9.571mA    7.827mA    11.23mA
-818.2mV  6.195mA    4.088mA    7.402mA
-636.4mV  2.183mA    1.306mA    2.238mA
-418.2mV  83.85uA    105.2uA    35.14uA
1.764V    -1.213nA   -79.04nA   -1.357nA
[Pulldown]
-1.8V     -1.72A     -2.612A    -1.411A
-1.2V     -528.3mA   -845.3mA   -342.5mA
-1.145V   -396.8mA   -683.8mA   -231.2mA
-1.091V   -269.6mA   -527.2mA   -129mA
-1.036V   -154.1mA   -379.3mA   -51.86mA
-981.8mV  -66.54mA   -245.9mA   -22.8mA
-927.3mV  -26.05mA   -136.4mA   -21.6mA
-872.7mV  -19.36mA   -62.04mA   -23.73mA
-763.6mV  -27.2mA    -19.06mA   -36.72mA
-545.5mV  -31.39mA   -18.17mA   -45.46mA
872.7mV   23.46mA    11.88mA    35.92mA
3.545V    25.35mA    12.51mA    41.59mA
[Pullup]
-1.8V     2.903mA    2.423mA    4.111mA
-1.418V   6.594mA    4.711mA    12.64mA
-1.255V   12.68mA    7.42mA     33.22mA
-1.091V   30.4mA     13mA       58.7mA
-981.8mV  40.64mA    17.02mA    61.32mA
-818.2mV  35.38mA    18.12mA    50.59mA
272.7mV   -9.18mA    -4.728mA   -14.55mA
1.255V    -29.75mA   -15.09mA   -48.97mA
2.564V    -34.18mA   -16.32mA   -57.57mA
2.782V    -30.27mA   -15.51mA   -57.62mA
3.055V    -23.64mA   -14.69mA   -38.68mA
3.545V    -19.26mA   -13.56mA   -31.45mA
[GND_clamp]
-1.8V     -2.816A    -1.188A    -3.154A
-1.073V   -234.1mA   -137.3mA   -187.2mA
-1.036V   -158.1mA   -109.8mA   -103mA
-1V       -102.5mA   -86.96mA   -56.78mA
-963.6mV  -58.91mA   -66.54mA   -26.67mA
-927.3mV  -27.33mA   -48.47mA   -12.72mA
-890.9mV  -15.25mA   -35mA      -9.693mA
-854.5mV  -7.712mA   -23.72mA   -7.821mA
-818.2mV  -4.703mA   -14.61mA   -7.099mA
-709.1mV  -2.775mA   -3.029mA   -4.882mA
-563.6mV  -570.1uA   -403.1uA   -1.092mA
1.764V    -22.34pA   583.3nA    2.874nA
[Ramp]
dV/dt_f  0.6523811/2.706696n   0.3688294/7.293751n   0.8189524/0.9353702n
dV/dt_r  0.6517274/2.176217n   0.4007032/5.012941n   0.8245335/1.103873n
R_load = 50
[Rising Waveform]
R_fixture = 50
V_fixture = 1.8
V_fixture_min = 1.62
V_fixture_max = 1.89
0s        717.8mV    1.009V     531.8mV
144ps     719.4mV    1.009V     677.3mV
256ps     714.1mV    1.009V     1.465V
304ps     747.7mV    1.009V     1.691V
464ps     1.249V     1.012V     1.863V
600ps     1.68V      1V         1.876V
800ps     1.783V     1.105V     1.878V
1.112ns   1.792V     1.489V     1.885V
1.304ns   1.792V     1.597V     1.886V
5.776ns   1.799V     1.618V     1.89V
[Rising Waveform]
R_fixture = 50
V_fixture = 0
V_fixture_min = 0
V_fixture_max = 0
0s        -59.33uV   105.5uV    -3.93mV
560ps     -16.37mV   -308.6uV   41.14mV
1.2ns     47.23mV    -10.01mV   600.2mV
1.92ns    321.4mV    -238.7uV   1.075V
2.576ns   560.3mV    16.79mV    1.218V
3.608ns   822.2mV    111.3mV    1.295V
5.032ns   961.5mV    271.3mV    1.33V
7.016ns   1.026V     438.2mV    1.344V
10.71ns   1.059V     578.5mV    1.348V
32.34ns   1.068V     655.8mV    1.349V
[Falling Waveform]
R_fixture = 50
V_fixture = 1.8
V_fixture_min = 1.62
V_fixture_max = 1.89
0s        1.8V       1.62V      1.89V
608ps     1.803V     1.62V      1.883V
960ps     1.805V     1.62V      1.771V
1.568ns   1.787V     1.622V     1.152V
2.248ns   1.639V     1.624V     746.8mV
3.736ns   1.195V     1.61V      563.9mV
5.856ns   853mV      1.483V     534.1mV
8.584ns   748.6mV    1.307V     530.1mV
16.79ns   718.2mV    1.061V     529.8mV
36.37ns   717.6mV    1.011V     529.8mV
[Falling Waveform]
R_fixture = 50
V_fixture = 0
V_fixture_min = 0
V_fixture_max = 0
0s        1.067V     657.3mV    1.349V
400ps     1.07V      657.3mV    1.334V
704ps     1.061V     657.5mV    1.201V
904ps     1.025V     660mV      936.8mV
1.28ns    871mV      663.9mV    155.1mV
1.48ns    709.4mV    656.4mV    9.77mV
2.064ns   164.7mV    579mV      856uV
2.368ns   17.9mV     503.2mV    402.4uV
3.872ns   457.4uV    49.23mV    68.37uV
5.76ns    159uV      1.629mV    15.46uV
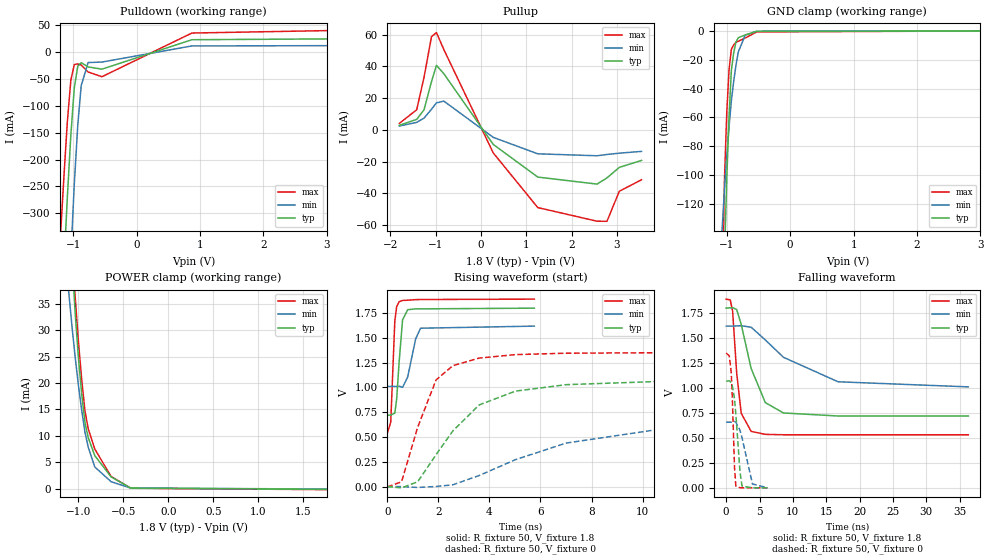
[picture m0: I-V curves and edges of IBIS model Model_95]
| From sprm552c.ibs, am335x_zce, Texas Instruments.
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| Model based on original model for OQ18SMART1FBPB_SSBHH
|   Sub model SBHH_HS00L10_PU1_1P8
[model]   Model_95
|[Description]  [1.8V-3-STATE-PU-S00:L10]
|   S00, L10,Weak internal pull-up, ,
|[Input Load]   PU
|[Output Drive] S00:L10
|Voltage   1.8V
|Mode   3-STATE
Model_type   3-state
Polarity   Non-Inverting
Enable   Active-Low
Cref =  15pF
Rref =  100.0000M
Vref =  0V
Vmeas =  0.9
C_comp   1.240965p   1.099743p   1.401226p
[Temperature Range]   25   125   -40
[Voltage Range]   1.8   1.62   1.89
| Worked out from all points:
|   slope of the pulldown table from 0 to 0.27 V, typ, clamps not added: 24.3 ohm
|   slope of the pullup table from 0 to 0.27 V, typ, clamps not added: 29.7 ohm
|   GND clamp passes 1 mA (typ) near -0.60 V on its own axis
|   POWER clamp passes 1 mA (typ) near -0.56 V on its own axis
|   rising waveform, R_fixture 50, V_fixture 1.8: 20-80 % time 171ps typ, 302ps min, 117ps max; typ from 0.72 V to 1.8 V
|   rising waveform, R_fixture 50, V_fixture 0: 20-80 % time 2.16ns typ, 4.96ns min, 1.1ns max; typ from 0.001 V to 1.07 V
|   falling waveform, R_fixture 50, V_fixture 1.8: 20-80 % time 2.71ns typ, 7.24ns min, 943ps max; typ from 1.8 V to 0.72 V
|   falling waveform, R_fixture 50, V_fixture 0: 20-80 % time 701ps typ, 1.22ns min, 395ps max; typ from 1.07 V to 0.002 V
[POWER_clamp]
-1.8V     360mA      189.8mA    409.4mA
-1.109V   56.23mA    37.39mA    59.78mA
-1.073V   44.23mA    30.96mA    47.33mA
-1.036V   33.16mA    24.83mA    36.25mA
-1V       24.78mA    19.56mA    27.84mA
-963.6mV  17.91mA    14.85mA    20.66mA
-927.3mV  12.54mA    10.7mA     14.72mA
-890.9mV  9.653mA    7.862mA    11.35mA
-818.2mV  6.273mA    4.126mA    7.524mA
-636.4mV  2.249mA    1.34mA     2.341mA
-418.2mV  128.7uA    129uA      104.8uA
1.764V    -96.73uA   -46.46uA   -163.5uA
[Pulldown]
-1.8V     -1.72A     -2.612A    -1.411A
-1.2V     -528.3mA   -845.3mA   -342.5mA
-1.145V   -396.8mA   -683.8mA   -231.2mA
-1.091V   -269.6mA   -527.2mA   -129mA
-1.036V   -154.1mA   -379.3mA   -51.85mA
-981.8mV  -66.54mA   -245.9mA   -22.8mA
-927.3mV  -26.05mA   -136.4mA   -21.6mA
-872.7mV  -19.36mA   -62.04mA   -23.73mA
-763.6mV  -27.2mA    -19.06mA   -36.72mA
-545.5mV  -31.39mA   -18.17mA   -45.46mA
872.7mV   23.46mA    11.88mA    35.92mA
3.545V    25.35mA    12.51mA    41.59mA
[Pullup]
-1.8V     2.903mA    2.423mA    4.111mA
-1.418V   6.594mA    4.711mA    12.64mA
-1.255V   12.69mA    7.42mA     33.23mA
-1.091V   30.4mA     13mA       58.71mA
-981.8mV  40.64mA    17.02mA    61.32mA
-818.2mV  35.38mA    18.12mA    50.59mA
272.7mV   -9.179mA   -4.728mA   -14.55mA
1.255V    -29.75mA   -15.09mA   -48.97mA
2.564V    -34.18mA   -16.32mA   -57.57mA
2.782V    -30.27mA   -15.51mA   -57.62mA
3.055V    -23.64mA   -14.69mA   -38.68mA
3.545V    -19.26mA   -13.56mA   -31.45mA
[GND_clamp]
-1.8V     -2.816A    -1.188A    -3.154A
-1.073V   -234.2mA   -137.3mA   -187.2mA
-1.036V   -158.1mA   -109.8mA   -103.1mA
-1V       -102.5mA   -86.97mA   -56.83mA
-963.6mV  -58.95mA   -66.55mA   -26.74mA
-927.3mV  -27.37mA   -48.49mA   -12.79mA
-890.9mV  -15.31mA   -35.02mA   -9.789mA
-854.5mV  -7.771mA   -23.73mA   -7.932mA
-818.2mV  -4.769mA   -14.63mA   -7.221mA
-709.1mV  -2.849mA   -3.058mA   -5.011mA
-527.3mV  -395.6uA   -259.7uA   -751.2uA
3.6V      0A         0A         0A
[Ramp]
dV/dt_f   0.65096/2.711299n   0.3680754/7.295202n   0.8172622/0.9395599n
dV/dt_r  0.6503146/2.171434n   0.4002966/5.00825n   0.8216514/1.101789n
R_load = 50
[Rising Waveform]
R_fixture = 50
V_fixture = 1.8
V_fixture_min = 1.62
V_fixture_max = 1.89
0s        720.1mV    1.011V     534.6mV
136ps     721.5mV    1.011V     649.8mV
296ps     741.3mV    1.01V      1.669V
368ps     882.2mV    1.011V     1.814V
464ps     1.253V     1.013V     1.864V
600ps     1.682V     1.001V     1.877V
800ps     1.783V     1.106V     1.879V
1.112ns   1.792V     1.489V     1.885V
1.304ns   1.792V     1.597V     1.886V
5.76ns    1.799V     1.618V     1.89V
[Rising Waveform]
R_fixture = 50
V_fixture = 0
V_fixture_min = 0
V_fixture_max = 0
0s        1.328mV    1.07mV     -2.139mV
560ps     -11.93mV   654.4uV    48.6mV
1.192ns   49.56mV    -7.983mV   599.8mV
1.912ns   322.6mV    1.98mV     1.076V
2.568ns   561.7mV    18.62mV    1.219V
3.6ns     823.9mV    112.6mV    1.296V
5.024ns   963.1mV    272.6mV    1.331V
7.008ns   1.028V     439.6mV    1.345V
10.7ns    1.061V     579.8mV    1.35V
32.3ns    1.069V     657.1mV    1.35V
[Falling Waveform]
R_fixture = 50
V_fixture = 1.8
V_fixture_min = 1.62
V_fixture_max = 1.89
0s        1.8V       1.62V      1.89V
616ps     1.803V     1.62V      1.882V
968ps     1.805V     1.62V      1.768V
1.576ns   1.786V     1.622V     1.149V
2.256ns   1.637V     1.624V     748.1mV
3.744ns   1.196V     1.609V     566.7mV
5.864ns   855mV      1.482V     536.9mV
8.592ns   750.9mV    1.308V     532.9mV
16.78ns   720.6mV    1.063V     532.6mV
36.32ns   720mV      1.012V     532.6mV
[Falling Waveform]
R_fixture = 50
V_fixture = 0
V_fixture_min = 0
V_fixture_max = 0
0s        1.069V     658.6mV    1.35V
456ps     1.073V     658.5mV    1.323V
752ps     1.056V     659.2mV    1.16V
904ps     1.027V     661.3mV    940.2mV
1.248ns   893.1mV    665.6mV    208.5mV
1.448ns   742mV      659.5mV    19.66mV
2.072ns   162.5mV    578.9mV    2.954mV
2.376ns   19.46mV    502.7mV    2.394mV
3.944ns   2.105mV    40.47mV    1.874mV
6.184ns   1.606mV    2.596mV    1.79mV
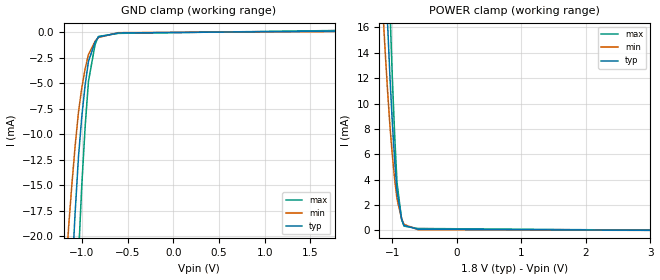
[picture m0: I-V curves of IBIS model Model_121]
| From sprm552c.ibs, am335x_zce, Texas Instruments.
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| Model based on original model for IQ18HYENPB_SSBHH
|   Sub model ENPB_SSBHH_PD_ON_1P8
[model]   Model_121
|[Description]  [1.8V-INPUT-PD-X]
|   Weak internal pull-down, ,
|[Input Load]   PD
|[Output Drive]
|Voltage   1.8V
|Mode   INPUT
Model_type   Input
Polarity   Non-Inverting
Vinl =  0.63
Vinh =  1.17
C_comp   0.9817759p   0.8451655p   1.124986p
[Model Spec]
Vinl   0.63   0.567   0.6615
Vinh   1.17   1.053   1.2285
[Temperature Range]   25   125   -40
[Voltage Range]   1.8   1.62   1.89
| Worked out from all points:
|   GND clamp passes 1 mA (typ) near -0.86 V on its own axis
|   POWER clamp passes 1 mA (typ) near -0.86 V on its own axis
[POWER_clamp]
-1.8V     125.4mA    90.82mA    173.9mA
-1.145V   25.45mA    17.22mA    36.75mA
-1.109V   20.77mA    14.02mA    30.04mA
-1.073V   16.31mA    11.01mA    23.6mA
-1.036V   12.08mA    8.211mA    17.41mA
-1V       8.561mA    5.963mA    12.11mA
-963.6mV  5.561mA    4.054mA    7.576mA
-927.3mV  3.082mA    2.484mA    3.8mA
-854.5mV  882.2uA    910.8uA    848uA
-818.2mV  394.4uA    481.1uA    343.2uA
-600mV    99.24uA    62.2uA     156.7uA
3.6V      0A         0A         0A
[GND_clamp]
-1.8V     -191.2mA   -126.8mA   -307.3mA
-1.145V   -30.73mA   -19.2mA    -53.51mA
-1.109V   -23.88mA   -14.96mA   -41.98mA
-1.073V   -17.69mA   -11.16mA   -31.45mA
-1.036V   -12.15mA   -7.796mA   -21.92mA
-1V       -8.264mA   -5.456mA   -14.96mA
-963.6mV  -5.172mA   -3.586mA   -9.262mA
-927.3mV  -2.87mA    -2.186mA   -4.822mA
-854.5mV  -961uA     -894.1uA   -1.196mA
-818.2mV  -479.5uA   -523.6uA   -426.9uA
-600mV    -82.87uA   -52.97uA   -121.2uA
1.764V    97.79uA    54.43uA    156.3uA
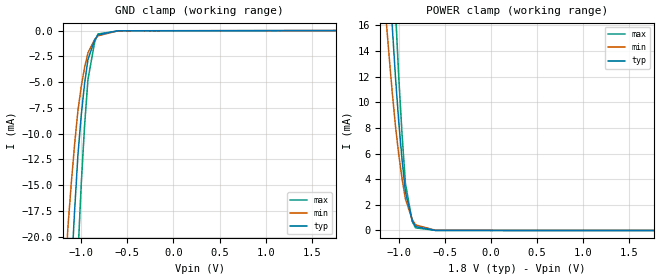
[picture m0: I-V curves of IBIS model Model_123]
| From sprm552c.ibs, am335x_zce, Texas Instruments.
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| Model based on original model for IQ18HYENPB_SSBHH
|   Sub model _SSBHH_PD_PU_OFF_1P8
[model]   Model_123
|[Description]  [1.8V-INPUT-PI-X]
|   Weak pull up/down disabled, ,
|[Input Load]   PI
|[Output Drive]
|Voltage   1.8V
|Mode   INPUT
Model_type   Input
Polarity   Non-Inverting
Vinl =  0.63
Vinh =  1.17
C_comp   0.9817759p   0.8451655p   1.124986p
[Model Spec]
Vinl   0.63   0.567   0.6615
Vinh   1.17   1.053   1.2285
[Temperature Range]   25   125   -40
[Voltage Range]   1.8   1.62   1.89
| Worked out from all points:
|   GND clamp passes 1 mA (typ) near -0.86 V on its own axis
|   POWER clamp passes 1 mA (typ) near -0.86 V on its own axis
[POWER_clamp]
-1.8V     125.4mA    90.81mA    173.8mA
-1.145V   25.41mA    17.2mA     36.65mA
-1.109V   20.72mA    14mA       29.94mA
-1.073V   16.25mA    10.99mA    23.48mA
-1.036V   12.02mA    8.186mA    17.29mA
-1V       8.489mA    5.935mA    11.99mA
-963.6mV  5.485mA    4.022mA    7.444mA
-927.3mV  3.001mA    2.449mA    3.666mA
-854.5mV  798.1uA    870uA      710.8uA
-818.2mV  309.1uA    437.6uA    204.4uA
-600mV    5.094uA    10.28uA    3.771uA
1.764V    -23.61pA   -18.02nA   -112.1pA
[GND_clamp]
-1.8V     -191.2mA   -126.8mA   -307.3mA
-1.145V   -30.71mA   -19.19mA   -53.48mA
-1.109V   -23.86mA   -14.96mA   -41.96mA
-1.073V   -17.66mA   -11.15mA   -31.42mA
-1.036V   -12.11mA   -7.787mA   -21.88mA
-1V       -8.229mA   -5.445mA   -14.92mA
-963.6mV  -5.132mA   -3.574mA   -9.211mA
-927.3mV  -2.825mA   -2.172mA   -4.761mA
-854.5mV  -904.9uA   -874.8uA   -1.109mA
-818.2mV  -418.1uA   -501.2uA   -332.1uA
-600mV    -19.58uA   -20.09uA   -28.61uA
1.764V    162.1pA    4.136nA    2.569nA
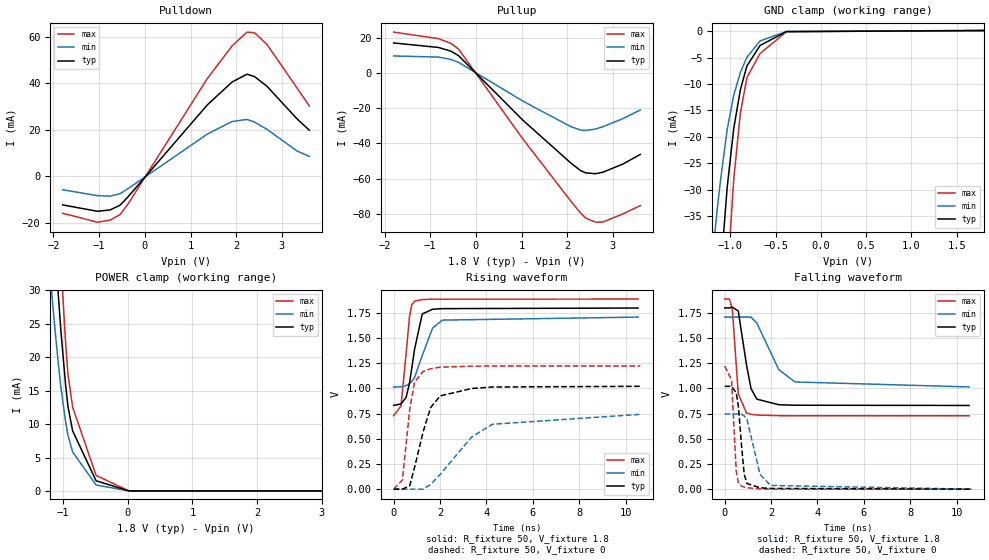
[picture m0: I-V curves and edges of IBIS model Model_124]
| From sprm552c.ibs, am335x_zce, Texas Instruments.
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| Model based on original model for BC1833DV50BPBFBP18LL_SSDLH
|   Sub model BC50B_H_PD_ON_5P_1P8
[model]   Model_124
|[Description]  [1.8V-I/O-WEAK_PD_ON-NORMAL, IND, 5%]
|   NORMAL,Weak internal pull-down,Industrial temperature range
|   (-40C to 125C, 25C nominal),5% power supply tolerance
|[Input Load]   WEAK_PD_ON
|[Output Drive] NORMAL
|Voltage   1.8V
|Mode   I/O
Model_type   I/O
Polarity   Non-Inverting
Enable   Active-Low
Vinl =  0.63
Vinh =  1.17
Cref =  15pF
Rref =  100.0000M
Vref =  0V
Vmeas =  0.9
C_comp   2.076488p   2.028274p   2.112293p
[Model Spec]
Vinl   0.63   0.5985   0.6615
Vinh   1.17   1.1115   1.2285
[Temperature Range]   25   125   -40
[Voltage Range]   1.8   1.71   1.89
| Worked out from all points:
|   slope of the pulldown table from 0 to 0.27 V, typ, clamps not added: 42.1 ohm
|   slope of the pullup table from 0 to 0.27 V, typ, clamps not added: 37.7 ohm
|   GND clamp passes 1 mA (typ) near -0.56 V on its own axis
|   POWER clamp passes 1 mA (typ) near -0.44 V on its own axis
|   rising waveform, R_fixture 50, V_fixture 1.8: 20-80 % time 398ps typ, 629ps min, 258ps max; typ from 0.832 V to 1.8 V
|   rising waveform, R_fixture 50, V_fixture 0: 20-80 % time 716ps typ, 1.77ns min, 340ps max; typ from 0 V to 1.02 V
|   falling waveform, R_fixture 50, V_fixture 1.8: 20-80 % time 386ps typ, 901ps min, 197ps max; typ from 1.8 V to 0.831 V
|   falling waveform, R_fixture 50, V_fixture 0: 20-80 % time 220ps typ, 409ps min, 147ps max; typ from 1.02 V to 0 V
[POWER_clamp]
-1.8V     154.2mA    109.7mA    213.5mA
-1.255V   57.34mA    38.41mA    81.27mA
-1.145V   39.68mA    26.05mA    56.64mA
-1.109V   34.21mA    22.34mA    48.88mA
-1.073V   28.97mA    18.84mA    41.38mA
-1.036V   23.97mA    15.54mA    34.15mA
-963.6mV  15.93mA    10.41mA    22.28mA
-927.3mV  12.7mA     8.361mA    17.51mA
-854.5mV  8.993mA    5.831mA    12.55mA
-490.9mV  1.518mA    881.5uA    2.323mA
18.18mV   0A         0A         0A
3.6V      0A         0A         0A
[Pulldown]
-1.8V     -12.34mA   -5.814mA   -15.95mA
-1.036V   -15.1mA    -8.371mA   -19.79mA
-763.6mV  -14.53mA   -8.588mA   -18.92mA
-545.5mV  -12.52mA   -7.542mA   -16.54mA
-381.8mV  -9.184mA   -5.536mA   -12.37mA
1.364V    30.65mA    18.1mA     41.95mA
1.909V    40.55mA    23.56mA    56.09mA
2.236V    43.94mA    24.46mA    62.06mA
2.4V      42.91mA    23.3mA     61.77mA
2.673V    38.72mA    20.2mA     56.76mA
3.327V    24.78mA    10.92mA    38.1mA
3.6V      19.79mA    8.54mA     30.25mA
[Pullup]
-1.8V     16.98mA    9.596mA    23.14mA
-818.2mV  14.42mA    8.972mA    19.42mA
-545.5mV  12.31mA    7.608mA    16.73mA
-381.8mV  9.817mA    6mA        13.58mA
1.036V    -27.01mA   -16.12mA   -37.74mA
2.073V    -50.99mA   -30.42mA   -72.57mA
2.291V    -55.4mA    -32.43mA   -79.49mA
2.4V      -56.69mA   -32.64mA   -82.28mA
2.618V    -57.2mA    -31.85mA   -84.68mA
2.782V    -56.31mA   -30.51mA   -84.57mA
3.218V    -51.71mA   -25.94mA   -79.96mA
3.6V      -46.22mA   -21.01mA   -75.3mA
[GND_clamp]
-1.8V     -258.3mA   -163.5mA   -409.7mA
-1.255V   -85.36mA   -52.4mA    -138.2mA
-1.218V   -74.87mA   -45.89mA   -121.3mA
-1.145V   -54.71mA   -33.55mA   -88.64mA
-1.109V   -45.65mA   -28.13mA   -73.71mA
-1.036V   -29.56mA   -18.62mA   -47.04mA
-963.6mV  -18.42mA   -12.15mA   -28.08mA
-890.9mV  -11.14mA   -7.842mA   -15.61mA
-818.2mV  -6.603mA   -4.95mA    -8.797mA
-672.7mV  -2.723mA   -1.864mA   -4.246mA
-381.8mV  -91.28uA   -77.78uA   -131.6uA
1.8V      101.9uA    59.08uA    150.8uA
[Ramp]
dV/dt_f 0.58661331/0.38842124n 0.42283999/0.9100058n 0.70088763/0.19779888n
dV/dt_r 0.61655985/0.71865516n 0.45176919/1.8009168n 0.73779729/0.34096125n
R_load = 50
[Rising Waveform]
R_fixture = 50
V_fixture = 1.8
V_fixture_min = 1.71
V_fixture_max = 1.89
0s        831.8mV    1.015V     729.2mV
318ps     846mV      1.016V     826.2mV
537.8ps   911.4mV    1.028V     1.348V
680.3ps   1.049V     1.048V     1.707V
780ps     1.199V     1.069V     1.83V
906.1ps   1.394V     1.112V     1.867V
1.234ns   1.739V     1.327V     1.882V
1.679ns   1.786V     1.599V     1.886V
2.097ns   1.792V     1.678V     1.886V
10.54ns   1.798V     1.708V     1.887V
[Rising Waveform]
R_fixture = 50
V_fixture = 0
V_fixture_min = 0
V_fixture_max = 0
0s        0V         0V         0V
378.3ps   0V         0V         91.67mV
692.4ps   34.24mV    0V         790.9mV
903.6ps   216.8mV    0V         1.063V
1.272ns   570.4mV    0V         1.169V
1.595ns   810.9mV    46.92mV    1.195V
2.01ns    926mV      147.8mV    1.211V
3.362ns   998.9mV    517.3mV    1.221V
4.256ns   1.014V     644.2mV    1.222V
10.64ns   1.021V     742.7mV    1.222V
[Falling Waveform]
R_fixture = 50
V_fixture = 1.8
V_fixture_min = 1.71
V_fixture_max = 1.89
0s        1.799V     1.708V     1.887V
206.5ps   1.799V     1.708V     1.887V
331.4ps   1.807V     1.708V     1.778V
585.1ps   1.768V     1.708V     946.6mV
937.8ps   1.237V     1.708V     757.3mV
1.136ns   998mV      1.708V     743.1mV
1.388ns   893.3mV    1.648V     735.7mV
2.332ns   838.2mV    1.187V     729.6mV
3.028ns   833.1mV    1.064V     728.5mV
10.54ns   830.9mV    1.015V     728.2mV
[Falling Waveform]
R_fixture = 50
V_fixture = 0
V_fixture_min = 0
V_fixture_max = 0
0s        1.021V     746.2mV    1.222V
294.8ps   1.021V     746.2mV    1.084V
495.8ps   957.9mV    746.2mV    183.2mV
591ps     821.4mV    746.2mV    60.83mV
735.2ps   407.4mV    742.6mV    29.46mV
842.6ps   146.9mV    727.5mV    20.29mV
956.9ps   56.82mV    695.2mV    14.76mV
1.525ns   13.26mV    146.6mV    2.712mV
1.975ns   7.389mV    36.98mV    0V
10.64ns   0V         0V         0V
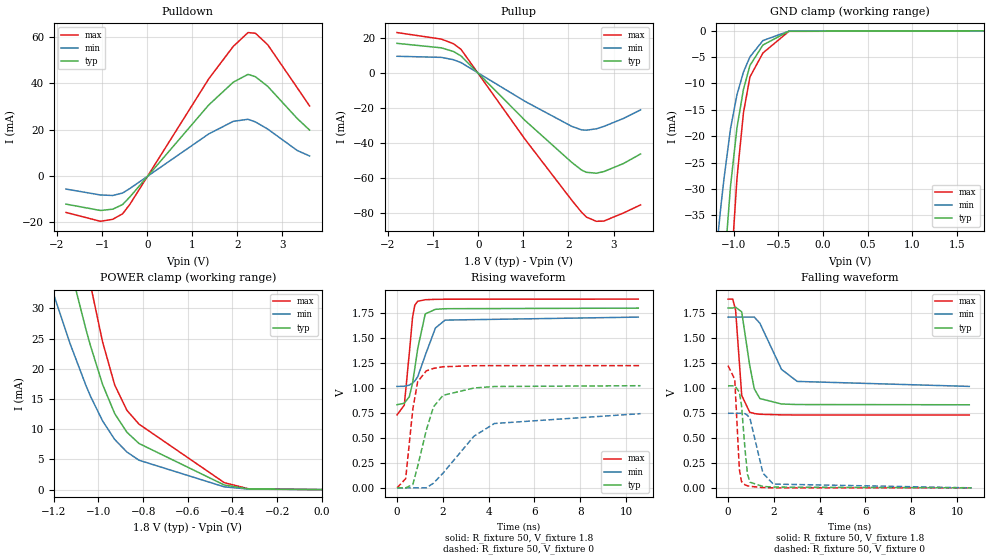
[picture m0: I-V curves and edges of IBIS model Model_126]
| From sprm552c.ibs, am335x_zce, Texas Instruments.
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| Model based on original model for BC1833DV50BPBFBP18LL_SSDLH
|   Sub model BC50B_H_PUPDOFF_5P_1P8
[model]   Model_126
|[Description]  [1.8V-I/O-WEAK_PUPDOFF-NORMAL, IND, 5%]
|   NORMAL,Weak pull up/down disabled,Industrial temperature range
|   (-40C to 125C, 25C nominal),5% power supply tolerance
|[Input Load]   WEAK_PUPDOFF
|[Output Drive] NORMAL
|Voltage   1.8V
|Mode   I/O
Model_type   I/O
Polarity   Non-Inverting
Enable   Active-Low
Vinl =  0.63
Vinh =  1.17
Cref =  15pF
Rref =  100.0000M
Vref =  0V
Vmeas =  0.9
C_comp   2.076488p   2.028274p   2.112293p
[Model Spec]
Vinl   0.63   0.5985   0.6615
Vinh   1.17   1.1115   1.2285
[Temperature Range]   25   125   -40
[Voltage Range]   1.8   1.71   1.89
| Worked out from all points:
|   slope of the pulldown table from 0 to 0.27 V, typ, clamps not added: 42.1 ohm
|   slope of the pullup table from 0 to 0.27 V, typ, clamps not added: 37.7 ohm
|   GND clamp passes 1 mA (typ) near -0.56 V on its own axis
|   POWER clamp passes 1 mA (typ) near -0.46 V on its own axis
|   rising waveform, R_fixture 50, V_fixture 1.8: 20-80 % time 398ps typ, 628ps min, 258ps max; typ from 0.833 V to 1.8 V
|   rising waveform, R_fixture 50, V_fixture 0: 20-80 % time 717ps typ, 1.77ns min, 340ps max; typ from 0 V to 1.02 V
|   falling waveform, R_fixture 50, V_fixture 1.8: 20-80 % time 387ps typ, 902ps min, 197ps max; typ from 1.8 V to 0.832 V
|   falling waveform, R_fixture 50, V_fixture 0: 20-80 % time 220ps typ, 410ps min, 147ps max; typ from 1.02 V to 0 V
[POWER_clamp]
-1.8V     154.2mA    109.6mA    213.3mA
-1.236V   54.24mA    36.24mA    76.93mA
-1.127V   36.83mA    24.14mA    52.57mA
-1.055V   26.36mA    17.13mA    37.58mA
-1.036V   23.85mA    15.48mA    33.96mA
-981.8mV  17.43mA    11.38mA    24.48mA
-927.3mV  12.58mA    8.299mA    17.32mA
-872.7mV  9.497mA    6.221mA    13.13mA
-818.2mV  7.629mA    4.86mA     10.83mA
-436.4mV  761.6uA    453.7uA    1.147mA
-327.3mV  115.1uA    79.02uA    133.5uA
0V        19.19nA    133nA      229.6nA
[Pulldown]
-1.8V     -12.34mA   -5.814mA   -15.95mA
-1.036V   -15.1mA    -8.371mA   -19.79mA
-763.6mV  -14.53mA   -8.588mA   -18.92mA
-545.5mV  -12.52mA   -7.542mA   -16.54mA
-381.8mV  -9.184mA   -5.536mA   -12.37mA
1.364V    30.65mA    18.1mA     41.96mA
1.909V    40.55mA    23.56mA    56.09mA
2.236V    43.94mA    24.46mA    62.06mA
2.4V      42.91mA    23.3mA     61.77mA
2.673V    38.72mA    20.2mA     56.76mA
3.327V    24.78mA    10.92mA    38.1mA
3.6V      19.79mA    8.54mA     30.25mA
[Pullup]
-1.8V     16.98mA    9.596mA    23.14mA
-818.2mV  14.42mA    8.972mA    19.42mA
-545.5mV  12.31mA    7.608mA    16.73mA
-381.8mV  9.818mA    6mA        13.58mA
1.036V    -27.01mA   -16.12mA   -37.74mA
2.073V    -50.99mA   -30.42mA   -72.58mA
2.291V    -55.4mA    -32.43mA   -79.49mA
2.4V      -56.69mA   -32.63mA   -82.28mA
2.618V    -57.2mA    -31.85mA   -84.68mA
2.782V    -56.31mA   -30.51mA   -84.57mA
3.218V    -51.71mA   -25.94mA   -79.96mA
3.6V      -46.22mA   -21.01mA   -75.3mA
[GND_clamp]
-1.8V     -258.3mA   -163.5mA   -409.7mA
-1.255V   -85.35mA   -52.4mA    -138.2mA
-1.218V   -74.87mA   -45.89mA   -121.3mA
-1.145V   -54.71mA   -33.55mA   -88.63mA
-1.109V   -45.64mA   -28.13mA   -73.71mA
-1.036V   -29.55mA   -18.62mA   -47.03mA
-963.6mV  -18.42mA   -12.14mA   -28.07mA
-890.9mV  -11.13mA   -7.836mA   -15.58mA
-818.2mV  -6.581mA   -4.941mA   -8.76mA
-672.7mV  -2.695mA   -1.849mA   -4.206mA
-381.8mV  -68.52uA   -64.5uA    -99.4uA
1.8V      19.19nA    313.7nA    215.2nA
[Ramp]
dV/dt_f 0.58725433/0.38964232n 0.42317647/0.91130497n 0.70181473/0.19867982n
dV/dt_r 0.61735584/0.719589n  0.45222506/1.802573n   0.7389132/0.34152056n
R_load = 50
[Rising Waveform]
R_fixture = 50
V_fixture = 1.8
V_fixture_min = 1.71
V_fixture_max = 1.89
0s        832.9mV    1.016V     730.4mV
318ps     847.2mV    1.017V     827.7mV
537.8ps   912.8mV    1.029V     1.35V
679.1ps   1.049V     1.049V     1.707V
776.5ps   1.195V     1.07V      1.829V
907.2ps   1.397V     1.114V     1.869V
1.234ns   1.742V     1.328V     1.884V
1.679ns   1.788V     1.601V     1.888V
2.098ns   1.794V     1.68V      1.889V
10.54ns   1.8V       1.71V      1.89V
[Rising Waveform]
R_fixture = 50
V_fixture = 0
V_fixture_min = 0
V_fixture_max = 0
0s        0V         0V         0V
378.3ps   0V         0V         91.68mV
692.4ps   34.24mV    0V         791.3mV
903.3ps   216.5mV    0V         1.064V
1.277ns   575.4mV    0V         1.171V
1.593ns   810.3mV    46.47mV    1.196V
2.01ns    926.7mV    147.7mV    1.213V
3.362ns   999.9mV    517.6mV    1.223V
4.256ns   1.015V     644.6mV    1.224V
10.64ns   1.023V     743.2mV    1.224V
[Falling Waveform]
R_fixture = 50
V_fixture = 1.8
V_fixture_min = 1.71
V_fixture_max = 1.89
0s        1.801V     1.71V      1.89V
206.5ps   1.801V     1.71V      1.89V
331.4ps   1.809V     1.71V      1.781V
598.9ps   1.762V     1.71V      925.4mV
946ps     1.228V     1.71V      758.5mV
1.15ns    990.7mV    1.71V      744.3mV
1.393ns   894.5mV    1.648V     737.2mV
2.339ns   839.7mV    1.186V     730.9mV
3.024ns   834.5mV    1.066V     729.7mV
10.54ns   832mV      1.016V     729.5mV
[Falling Waveform]
R_fixture = 50
V_fixture = 0
V_fixture_min = 0
V_fixture_max = 0
0s        1.022V     747mV      1.224V
294.8ps   1.022V     747mV      1.086V
495.8ps   959.3mV    747mV      185.3mV
588.9ps   828mV      747mV      63.26mV
744.5ps   382.6mV    742.5mV    29.54mV
851.4ps   134.9mV    726.4mV    20.69mV
961.8ps   56.5mV     694.1mV    15.35mV
1.525ns   13.91mV    147.8mV    3.013mV
1.975ns   7.886mV    37.88mV    0V
10.64ns   0V         0V         0V
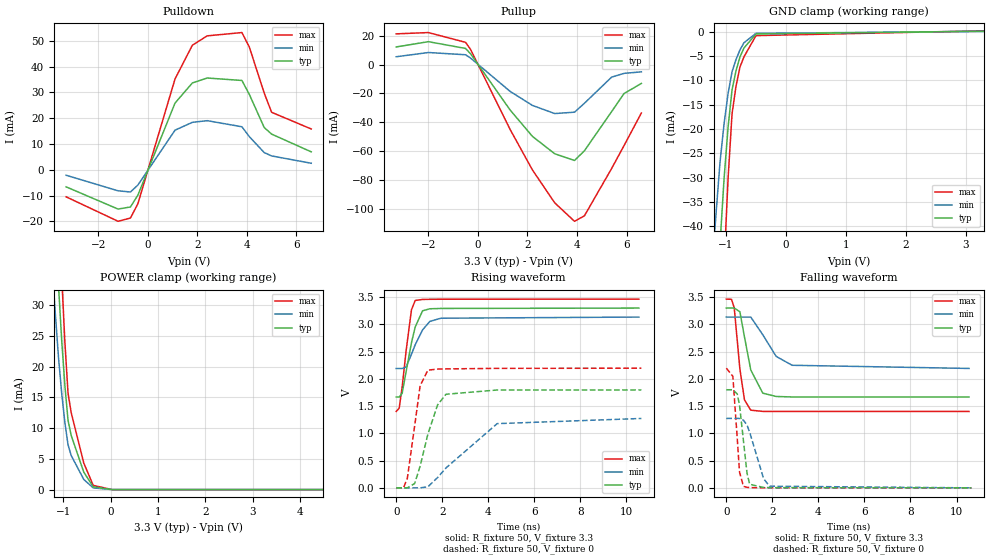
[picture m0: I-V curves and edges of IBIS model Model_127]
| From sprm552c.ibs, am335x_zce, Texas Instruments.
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| Model based on original model for BC1833DV50BPBFBP18LL_SSDLH
|   Sub model BC50B_H_PD_ON_5P_3P3
[model]   Model_127
|[Description]  [3.3V-I/O-WEAK_PD_ON-NORMAL, IND, 5%]
|   NORMAL,Weak internal pull-down,Industrial temperature range
|   (-40C to 125C, 25C nominal),5% power supply tolerance
|[Input Load]   WEAK_PD_ON
|[Output Drive] NORMAL
|Voltage   3.3V
|Mode   I/O
Model_type   I/O
Polarity   Non-Inverting
Enable   Active-Low
Vinl =  0.8V
Vinh =  2V
Cref =  15pF
Rref =  100.0000M
Vref =  0V
Vmeas =  1.65
C_comp   1.88955p   1.709236p   1.929482p
[Model Spec]
Vinl   0.8V   0.8V   0.8V
Vinh   2V   2V   2V
[Temperature Range]   25   125   -40
[Voltage Range]   3.3   3.135   3.465
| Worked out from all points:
|   slope of the pulldown table from 0 to 0.495 V, typ, clamps not added: 41.2 ohm
|   slope of the pullup table from 0 to 0.495 V, typ, clamps not added: 40 ohm
|   GND clamp passes 1 mA (typ) near -0.55 V on its own axis
|   POWER clamp passes 1 mA (typ) near -0.44 V on its own axis
|   rising waveform, R_fixture 50, V_fixture 3.3: 20-80 % time 464ps typ, 620ps min, 344ps max; typ from 1.67 V to 3.3 V
|   rising waveform, R_fixture 50, V_fixture 0: 20-80 % time 697ps typ, 1.76ns min, 393ps max; typ from 0 V to 1.8 V
|   falling waveform, R_fixture 50, V_fixture 3.3: 20-80 % time 466ps typ, 813ps min, 278ps max; typ from 3.3 V to 1.67 V
|   falling waveform, R_fixture 50, V_fixture 0: 20-80 % time 274ps typ, 532ps min, 196ps max; typ from 1.8 V to 0 V
[POWER_clamp]
-3.3V     437.1mA    430.8mA    590.9mA
-1.233V   54mA       35.95mA    76.74mA
-1.167V   43.32mA    28.48mA    61.85mA
-1.1V     33.01mA    21.39mA    47.35mA
-1.033V   24.22mA    15.63mA    34.6mA
-966.7mV  16.98mA    10.93mA    24.05mA
-900mV    11.29mA    7.299mA    15.71mA
-833.3mV  8.816mA    5.551mA    12.53mA
-566.7mV  2.833mA    1.651mA    4.306mA
-366.7mV  458.2uA    275.4uA    687.8uA
33.33mV   0A         0A         0A
6.6V      0A         0A         0A
[Pulldown]
-3.3V     -6.622mA   -2.126mA   -10.49mA
-1.2V     -15.24mA   -8.16mA    -19.98mA
-700mV    -14.42mA   -8.625mA   -18.71mA
-400mV    -9.821mA   -5.925mA   -13.15mA
1.1V      25.87mA    15.35mA    35.22mA
1.8V      33.67mA    18.39mA    48.29mA
2.4V      35.57mA    19.03mA    51.92mA
3.8V      34.62mA    16.67mA    53.19mA
4.1V      29.22mA    12.85mA    47.57mA
4.7V      16.38mA    6.671mA    29.75mA
5V        13.82mA    5.359mA    22.28mA
6.6V      6.944mA    2.531mA    15.81mA
[Pullup]
-3.3V     12.22mA    5.435mA    21.29mA
-2V       15.88mA    8.364mA    22.18mA
-500mV    11.19mA    6.809mA    15.42mA
-300mV    7.546mA    4.55mA     10.58mA
1.3V      -31.44mA   -18.55mA   -44.91mA
2.2V      -49.69mA   -28.25mA   -72.91mA
3.1V      -61.73mA   -33.9mA    -95.7mA
3.9V      -66.39mA   -32.95mA   -108.5mA
4.3V      -59.67mA   -26.77mA   -104.7mA
5.4V      -32.51mA   -8.662mA   -71.91mA
5.9V      -20.05mA   -6.072mA   -56.09mA
6.6V      -13.04mA   -5.016mA   -33.52mA
[GND_clamp]
-3.3V     -759.3mA   -612.7mA   -1.187A
-1.233V   -79.58mA   -48.75mA   -128.9mA
-1.167V   -61.06mA   -37.35mA   -98.95mA
-1.1V     -43.51mA   -26.72mA   -70.29mA
-1.033V   -30.2mA    -18.91mA   -48.08mA
-966.7mV  -19.68mA   -12.74mA   -30.27mA
-900mV    -11.93mA   -8.219mA   -16.86mA
-833.3mV  -8mA       -5.694mA   -11.13mA
-766.7mV  -5.133mA   -3.707mA   -7.22mA
-700mV    -3.33mA    -2.257mA   -5.131mA
-500mV    -463.9uA   -330.7uA   -807.4uA
3.3V      108.6uA    60.34uA    188uA
[Ramp]
dV/dt_f 0.98265995/0.46707892n 0.57005603/0.81798234n  1.2393724/0.27847773n
dV/dt_r   1.081086/0.69817509n 0.76711178/1.7713956n  1.3214884/0.3938549n
R_load = 50
[Rising Waveform]
R_fixture = 50
V_fixture = 3.3
V_fixture_min = 3.135
V_fixture_max = 3.465
0s        1.666V     2.189V     1.402V
130.4ps   1.666V     2.189V     1.462V
259ps     1.734V     2.189V     1.854V
431ps     2.134V     2.218V     2.516V
662.1ps   2.66V      2.45V      3.264V
824.8ps   2.951V     2.625V     3.438V
1.146ns   3.248V     2.898V     3.456V
1.46ns    3.285V     3.053V     3.459V
1.943ns   3.291V     3.112V     3.46V
10.54ns   3.298V     3.133V     3.462V
[Rising Waveform]
R_fixture = 50
V_fixture = 0
V_fixture_min = 0
V_fixture_max = 0
0s        0V         0V         0V
315.9ps   0V         0V         0V
482.1ps   0V         0V         172.4mV
803.3ps   80.07mV    0V         1.143V
1.039ns   398.6mV    0V         1.872V
1.375ns   984.7mV    19.62mV    2.159V
1.794ns   1.519V     187.2mV    2.179V
2.162ns   1.717V     365.2mV    2.182V
4.386ns   1.795V     1.178V     2.192V
10.65ns   1.796V     1.273V     2.195V
[Falling Waveform]
R_fixture = 50
V_fixture = 3.3
V_fixture_min = 3.135
V_fixture_max = 3.465
0s        3.297V     3.132V     3.461V
224.2ps   3.297V     3.132V     3.458V
343.3ps   3.297V     3.132V     3.302V
589.3ps   3.229V     3.132V     2.177V
789.2ps   2.765V     3.132V     1.612V
1.061ns   2.163V     3.132V     1.425V
1.582ns   1.737V     2.809V     1.402V
2.164ns   1.676V     2.411V     1.401V
2.857ns   1.667V     2.248V     1.401V
10.54ns   1.665V     2.19V      1.401V
[Falling Waveform]
R_fixture = 50
V_fixture = 0
V_fixture_min = 0
V_fixture_max = 0
0s        1.799V     1.273V     2.195V
282.9ps   1.799V     1.273V     2.045V
472.5ps   1.723V     1.273V     917.1mV
573.2ps   1.519V     1.273V     289.2mV
743.9ps   860.8mV    1.242V     26.98mV
900.1ps   264.2mV    1.15V      9.828mV
1.015ns   66.11mV    1.019V     5.629mV
1.618ns   6.996mV    169.1mV    0V
1.873ns   4.474mV    30.35mV    0V
10.65ns   0V         0V         0V
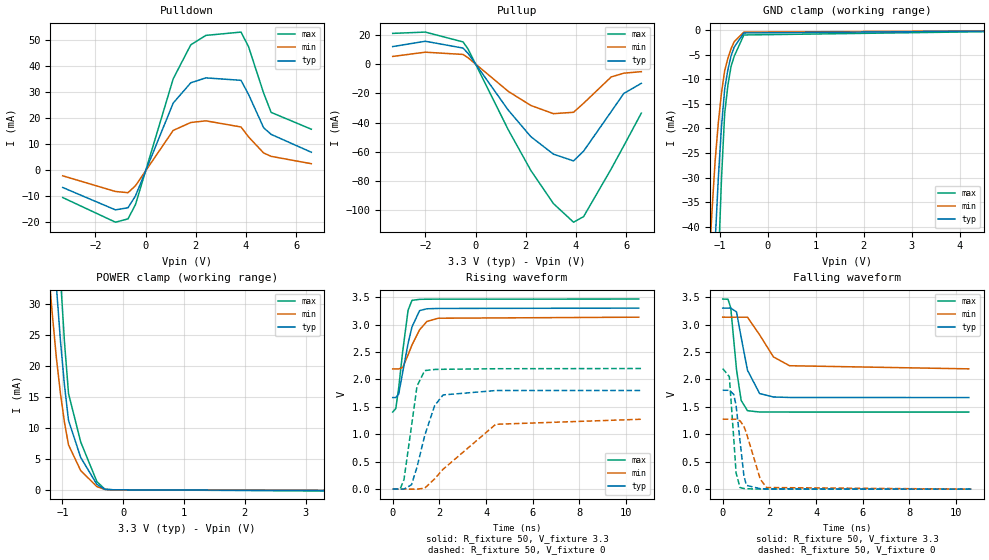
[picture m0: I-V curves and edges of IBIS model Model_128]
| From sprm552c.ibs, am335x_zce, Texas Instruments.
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| Model based on original model for BC1833DV50BPBFBP18LL_SSDLH
|   Sub model BC50B_H_PU_ON_5P_3P3
[model]   Model_128
|[Description]  [3.3V-I/O-WEAK_PU_ON-NORMAL, IND, 5%]
|   NORMAL,Weak internal pull-up,Industrial temperature range (-40C
|   to 125C, 25C nominal),5% power supply tolerance
|[Input Load]   WEAK_PU_ON
|[Output Drive] NORMAL
|Voltage   3.3V
|Mode   I/O
Model_type   I/O
Polarity   Non-Inverting
Enable   Active-Low
Vinl =  0.8V
Vinh =  2V
Cref =  15pF
Rref =  100.0000M
Vref =  0V
Vmeas =  1.65
C_comp   1.88955p   1.709236p   1.929482p
[Model Spec]
Vinl   0.8V   0.8V   0.8V
Vinh   2V   2V   2V
[Temperature Range]   25   125   -40
[Voltage Range]   3.3   3.135   3.465
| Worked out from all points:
|   slope of the pulldown table from 0 to 0.495 V, typ, clamps not added: 41.2 ohm
|   slope of the pullup table from 0 to 0.495 V, typ, clamps not added: 40 ohm
|   GND clamp passes 1 mA (typ) near -0.54 V on its own axis
|   POWER clamp passes 1 mA (typ) near -0.44 V on its own axis
|   rising waveform, R_fixture 50, V_fixture 3.3: 20-80 % time 462ps typ, 617ps min, 343ps max; typ from 1.67 V to 3.3 V
|   rising waveform, R_fixture 50, V_fixture 0: 20-80 % time 696ps typ, 1.76ns min, 392ps max; typ from 0.003 V to 1.8 V
|   falling waveform, R_fixture 50, V_fixture 3.3: 20-80 % time 467ps typ, 812ps min, 279ps max; typ from 3.3 V to 1.67 V
|   falling waveform, R_fixture 50, V_fixture 0: 20-80 % time 274ps typ, 532ps min, 197ps max; typ from 1.8 V to 0.002 V
[POWER_clamp]
-3.3V     437.1mA    430.8mA    590.9mA
-1.233V   53.96mA    35.93mA    76.64mA
-1.167V   43.27mA    28.46mA    61.75mA
-1.1V     32.96mA    21.36mA    47.25mA
-1.033V   24.17mA    15.61mA    34.49mA
-966.7mV  16.93mA    10.91mA    23.94mA
-900mV    11.23mA    7.269mA    15.59mA
-700mV    5.251mA    3.127mA    7.757mA
-433.3mV  893.2uA    531.5uA    1.34mA
-300mV    89.78uA    61.22uA    102uA
-166.7mV  17.36uA    10.91uA    23.37uA
3.3V      -100.3uA   -54.59uA   -173.1uA
[Pulldown]
-3.3V     -6.622mA   -2.126mA   -10.49mA
-1.2V     -15.24mA   -8.16mA    -19.98mA
-700mV    -14.42mA   -8.625mA   -18.71mA
-400mV    -9.821mA   -5.925mA   -13.15mA
1.1V      25.87mA    15.35mA    35.22mA
1.8V      33.67mA    18.39mA    48.29mA
2.4V      35.57mA    19.03mA    51.92mA
3.8V      34.62mA    16.67mA    53.19mA
4.1V      29.22mA    12.85mA    47.57mA
4.7V      16.38mA    6.671mA    29.75mA
5V        13.82mA    5.359mA    22.28mA
6.6V      6.944mA    2.531mA    15.81mA
[Pullup]
-3.3V     12.22mA    5.435mA    21.29mA
-2V       15.88mA    8.364mA    22.18mA
-500mV    11.19mA    6.809mA    15.42mA
-300mV    7.546mA    4.55mA     10.58mA
1.3V      -31.44mA   -18.55mA   -44.91mA
2.2V      -49.69mA   -28.25mA   -72.91mA
3.1V      -61.73mA   -33.9mA    -95.7mA
3.9V      -66.39mA   -32.95mA   -108.5mA
4.3V      -59.67mA   -26.77mA   -104.7mA
5.4V      -32.51mA   -8.662mA   -71.91mA
5.9V      -20.05mA   -6.072mA   -56.09mA
6.6V      -13.04mA   -5.016mA   -33.52mA
[GND_clamp]
-3.3V     -759.3mA   -612.7mA   -1.187A
-1.233V   -79.59mA   -48.75mA   -128.9mA
-1.167V   -61.07mA   -37.36mA   -98.97mA
-1.1V     -43.52mA   -26.73mA   -70.32mA
-1.033V   -30.22mA   -18.91mA   -48.13mA
-966.7mV  -19.71mA   -12.75mA   -30.35mA
-900mV    -11.97mA   -8.233mA   -16.96mA
-833.3mV  -8.054mA   -5.715mA   -11.24mA
-766.7mV  -5.195mA   -3.734mA   -7.343mA
-700mV    -3.396mA   -2.289mA   -5.259mA
-500mV    -540.4uA   -369.3uA   -948.8uA
6.6V      0A         0A         0A
[Ramp]
dV/dt_f 0.98106415/0.46736796n 0.56883051/0.81647778n  1.2382393/0.27921896n
dV/dt_r  1.0818009/0.69790544n 0.76775217/1.7722045n   1.322011/0.39369285n
R_load = 50
[Rising Waveform]
R_fixture = 50
V_fixture = 3.3
V_fixture_min = 3.135
V_fixture_max = 3.465
0s        1.671V     2.193V     1.407V
133.3ps   1.671V     2.193V     1.472V
257ps     1.736V     2.193V     1.851V
431.8ps   2.14V      2.222V     2.525V
659.9ps   2.66V      2.451V     3.264V
825.5ps   2.957V     2.628V     3.442V
1.15ns    3.254V     2.904V     3.46V
1.464ns   3.288V     3.057V     3.462V
1.951ns   3.294V     3.116V     3.464V
10.54ns   3.3V       3.135V     3.465V
[Rising Waveform]
R_fixture = 50
V_fixture = 0
V_fixture_min = 0
V_fixture_max = 0
0s        3.162mV    2.442mV    3.952mV
316.7ps   3.162mV    2.442mV    3.952mV
482.9ps   3.162mV    2.442mV    175.9mV
804.1ps   82.64mV    2.442mV    1.148V
1.041ns   403.7mV    2.442mV    1.879V
1.371ns   980.7mV    20.48mV    2.162V
1.796ns   1.524V     190.2mV    2.183V
2.158ns   1.719V     364.9mV    2.186V
4.413ns   1.799V     1.184V     2.196V
10.65ns   1.8V       1.276V     2.2V
[Falling Waveform]
R_fixture = 50
V_fixture = 3.3
V_fixture_min = 3.135
V_fixture_max = 3.465
0s        3.3V       3.134V     3.464V
225.1ps   3.3V       3.134V     3.461V
344ps     3.3V       3.134V     3.306V
591.7ps   3.23V      3.134V     2.177V
790.7ps   2.767V     3.134V     1.618V
1.061ns   2.168V     3.134V     1.431V
1.582ns   1.743V     2.812V     1.407V
2.172ns   1.681V     2.411V     1.407V
2.862ns   1.672V     2.25V      1.406V
10.54ns   1.67V      2.193V     1.406V
[Falling Waveform]
R_fixture = 50
V_fixture = 0
V_fixture_min = 0
V_fixture_max = 0
0s        1.803V     1.276V     2.199V
283.7ps   1.803V     1.276V     2.05V
472.3ps   1.728V     1.276V     929.9mV
573.6ps   1.525V     1.276V     296.7mV
743.1ps   872mV      1.245V     31.74mV
906.6ps   252.1mV    1.147V     13.69mV
1.013ns   71.9mV     1.026V     9.742mV
1.61ns    9.996mV    182.9mV    3.954mV
1.882ns   7.239mV    31.81mV    3.62mV
10.65ns   2.247mV    2.037mV    3.273mV
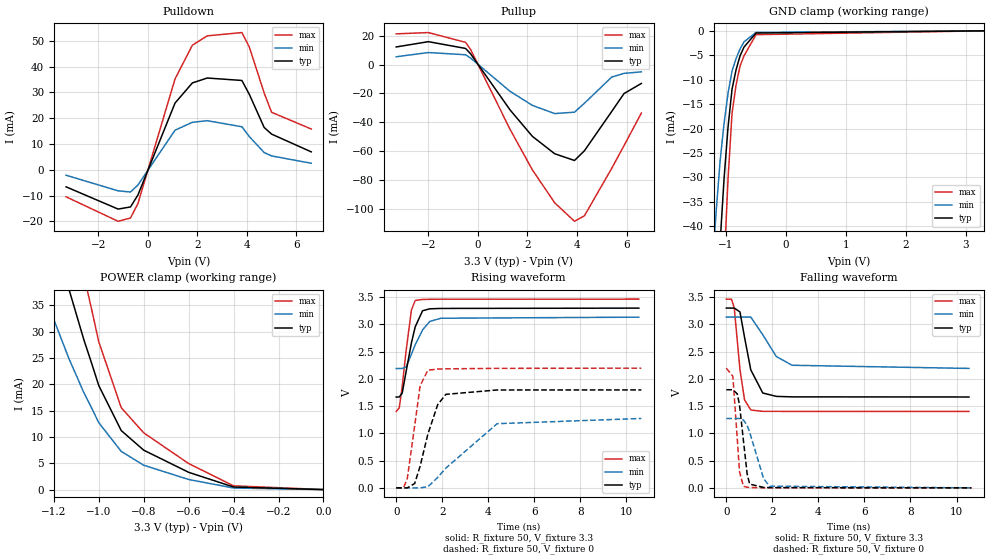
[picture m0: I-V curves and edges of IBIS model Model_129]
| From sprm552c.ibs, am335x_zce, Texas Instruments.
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| Model based on original model for BC1833DV50BPBFBP18LL_SSDLH
|   Sub model BC50B_H_PUPDOFF_5P_3P3
[model]   Model_129
|[Description]  [3.3V-I/O-WEAK_PUPDOFF-NORMAL, IND, 5%]
|   NORMAL,Weak pull up/down disabled,Industrial temperature range
|   (-40C to 125C, 25C nominal),5% power supply tolerance
|[Input Load]   WEAK_PUPDOFF
|[Output Drive] NORMAL
|Voltage   3.3V
|Mode   I/O
Model_type   I/O
Polarity   Non-Inverting
Enable   Active-Low
Vinl =  0.8V
Vinh =  2V
Cref =  15pF
Rref =  100.0000M
Vref =  0V
Vmeas =  1.65
C_comp   1.88955p   1.709236p   1.929482p
[Model Spec]
Vinl   0.8V   0.8V   0.8V
Vinh   2V   2V   2V
[Temperature Range]   25   125   -40
[Voltage Range]   3.3   3.135   3.465
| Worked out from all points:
|   slope of the pulldown table from 0 to 0.495 V, typ, clamps not added: 41.2 ohm
|   slope of the pullup table from 0 to 0.495 V, typ, clamps not added: 40 ohm
|   GND clamp passes 1 mA (typ) near -0.55 V on its own axis
|   POWER clamp passes 1 mA (typ) near -0.44 V on its own axis
|   rising waveform, R_fixture 50, V_fixture 3.3: 20-80 % time 463ps typ, 618ps min, 344ps max; typ from 1.67 V to 3.3 V
|   rising waveform, R_fixture 50, V_fixture 0: 20-80 % time 697ps typ, 1.77ns min, 393ps max; typ from 0 V to 1.8 V
|   falling waveform, R_fixture 50, V_fixture 3.3: 20-80 % time 468ps typ, 813ps min, 279ps max; typ from 3.3 V to 1.67 V
|   falling waveform, R_fixture 50, V_fixture 0: 20-80 % time 274ps typ, 533ps min, 197ps max; typ from 1.8 V to 0 V
[POWER_clamp]
-3.3V     437.1mA    430.8mA    590.9mA
-1.267V   59.46mA    39.85mA    84.25mA
-1.233V   53.93mA    35.92mA    76.61mA
-1.133V   38.09mA    24.9mA     54.46mA
-1.067V   28.54mA    18.47mA    40.83mA
-1.033V   24.14mA    15.59mA    34.45mA
-1V       19.75mA    12.71mA    28.07mA
-900mV    11.21mA    7.255mA    15.55mA
-800mV    7.487mA    4.63mA     10.78mA
-600mV    3.284mA    1.921mA    4.946mA
-400mV    494.5uA    304.1uA    718.2uA
0V        4.588uA    2.33uA     8.157uA
[Pulldown]
-3.3V     -6.622mA   -2.126mA   -10.49mA
-1.2V     -15.24mA   -8.16mA    -19.98mA
-700mV    -14.42mA   -8.625mA   -18.71mA
-400mV    -9.821mA   -5.925mA   -13.15mA
1.1V      25.87mA    15.35mA    35.22mA
1.8V      33.67mA    18.39mA    48.29mA
2.4V      35.57mA    19.03mA    51.92mA
3.8V      34.62mA    16.67mA    53.19mA
4.1V      29.22mA    12.85mA    47.57mA
4.7V      16.38mA    6.671mA    29.75mA
5V        13.82mA    5.359mA    22.28mA
6.6V      6.944mA    2.531mA    15.81mA
[Pullup]
-3.3V     12.22mA    5.435mA    21.29mA
-2V       15.88mA    8.364mA    22.18mA
-500mV    11.19mA    6.809mA    15.42mA
-300mV    7.546mA    4.55mA     10.58mA
1.3V      -31.44mA   -18.55mA   -44.91mA
2.2V      -49.69mA   -28.25mA   -72.91mA
3.1V      -61.73mA   -33.9mA    -95.7mA
3.9V      -66.39mA   -32.95mA   -108.5mA
4.3V      -59.67mA   -26.77mA   -104.7mA
5.4V      -32.51mA   -8.662mA   -71.91mA
5.9V      -20.05mA   -6.072mA   -56.09mA
6.6V      -13.04mA   -5.016mA   -33.52mA
[GND_clamp]
-3.3V     -759.3mA   -612.7mA   -1.187A
-1.233V   -79.57mA   -48.75mA   -128.9mA
-1.167V   -61.05mA   -37.35mA   -98.94mA
-1.1V     -43.5mA    -26.72mA   -70.28mA
-1.033V   -30.2mA    -18.91mA   -48.08mA
-966.7mV  -19.68mA   -12.74mA   -30.27mA
-900mV    -11.93mA   -8.216mA   -16.85mA
-833.3mV  -7.988mA   -5.69mA    -11.11mA
-766.7mV  -5.117mA   -3.701mA   -7.196mA
-700mV    -3.311mA   -2.248mA   -5.105mA
-500mV    -444.3uA   -319.5uA   -780.8uA
3.3V      4.588uA    4.848uA    6.316uA
[Ramp]
dV/dt_f 0.98253559/0.46829086n 0.56956259/0.81803926n  1.2400651/0.27961726n
dV/dt_r  1.0822206/0.6989037n 0.76777509/1.7728333n  1.3230535/0.39424641n
R_load = 50
[Rising Waveform]
R_fixture = 50
V_fixture = 3.3
V_fixture_min = 3.135
V_fixture_max = 3.465
0s        1.668V     2.191V     1.404V
133.4ps   1.668V     2.191V     1.47V
259ps     1.737V     2.191V     1.857V
433ps     2.142V     2.222V     2.527V
661.3ps   2.662V     2.452V     3.266V
825.5ps   2.956V     2.628V     3.441V
1.145ns   3.251V     2.9V       3.459V
1.457ns   3.287V     3.055V     3.462V
1.94ns    3.294V     3.114V     3.464V
10.54ns   3.3V       3.134V     3.465V
[Rising Waveform]
R_fixture = 50
V_fixture = 0
V_fixture_min = 0
V_fixture_max = 0
0s        0V         0V         0V
315.9ps   0V         0V         0V
482.1ps   0V         0V         172.4mV
803.3ps   80.07mV    0V         1.143V
1.039ns   398.6mV    0V         1.873V
1.375ns   984.6mV    19.6mV     2.16V
1.803ns   1.529V     192.1mV    2.181V
2.159ns   1.717V     363.8mV    2.185V
4.384ns   1.797V     1.178V     2.194V
10.65ns   1.798V     1.274V     2.198V
[Falling Waveform]
R_fixture = 50
V_fixture = 3.3
V_fixture_min = 3.135
V_fixture_max = 3.465
0s        3.3V       3.134V     3.464V
224.3ps   3.3V       3.134V     3.461V
343.3ps   3.3V       3.134V     3.306V
590.9ps   3.23V      3.134V     2.176V
789.7ps   2.767V     3.134V     1.617V
1.062ns   2.166V     3.134V     1.429V
1.583ns   1.741V     2.81V      1.404V
2.171ns   1.679V     2.411V     1.404V
2.857ns   1.67V      2.25V      1.403V
10.54ns   1.668V     2.192V     1.403V
[Falling Waveform]
R_fixture = 50
V_fixture = 0
V_fixture_min = 0
V_fixture_max = 0
0s        1.801V     1.274V     2.197V
282.9ps   1.801V     1.274V     2.048V
472.7ps   1.725V     1.274V     919.4mV
572.8ps   1.523V     1.274V     294.1mV
741.8ps   871.9mV    1.244V     29.38mV
904.2ps   254.4mV    1.147V     11.12mV
1.014ns   68.71mV    1.022V     6.942mV
1.62ns    7.992mV    169mV      0V
1.875ns   5.314mV    30.99mV    0V
10.65ns   0V         0V         0V
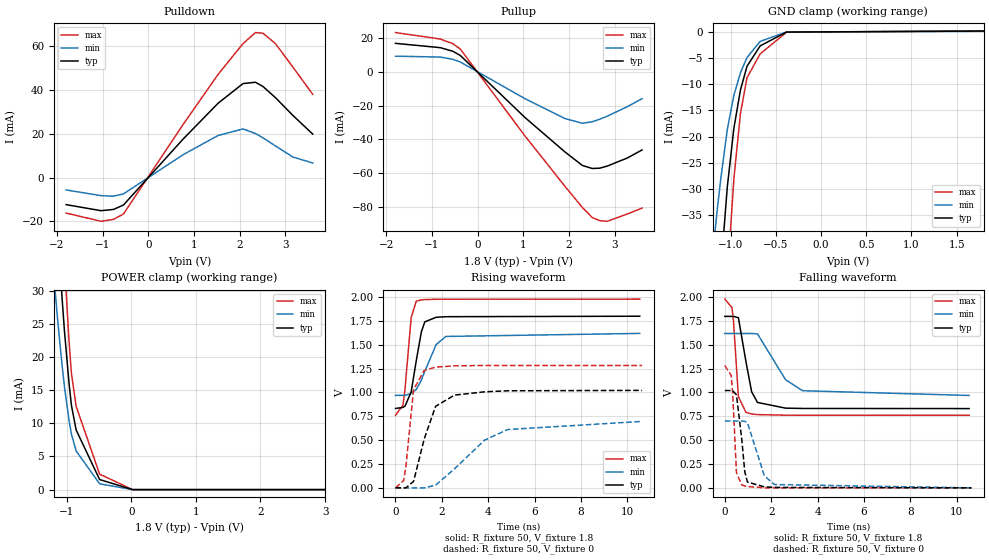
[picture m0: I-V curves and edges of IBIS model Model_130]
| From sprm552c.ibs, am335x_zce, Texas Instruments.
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| Model based on original model for BC1833DV50BPBFBP18LL_SSDLH
|   Sub model BC50B_H_PD_ON_10P_1P8
[model]   Model_130
|[Description]  [1.8V-I/O-WEAK_PD_ON-NORMAL, IND, 10%]
|   NORMAL,Weak internal pull-down,Industrial temperature range
|   (-40C to 125C, 25C nominal),10% power supply tolerance
|[Input Load]   WEAK_PD_ON
|[Output Drive] NORMAL
|Voltage   1.8V
|Mode   I/O
Model_type   I/O
Polarity   Non-Inverting
Enable   Active-Low
Vinl =  0.63
Vinh =  1.17
Cref =  15pF
Rref =  100.0000M
Vref =  0V
Vmeas =  0.9
C_comp   2.112293p   2.03043p   2.1213p
[Model Spec]
Vinl   0.63   0.567   0.693
Vinh   1.17   1.053   1.287
[Temperature Range]   25   125   -40
[Voltage Range]   1.8   1.62   1.98
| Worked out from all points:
|   slope of the pulldown table from 0 to 0.27 V, typ, clamps not added: 42.1 ohm
|   slope of the pullup table from 0 to 0.27 V, typ, clamps not added: 37.7 ohm
|   GND clamp passes 1 mA (typ) near -0.56 V on its own axis
|   POWER clamp passes 1 mA (typ) near -0.44 V on its own axis
|   rising waveform, R_fixture 50, V_fixture 1.8: 20-80 % time 398ps typ, 663ps min, 254ps max; typ from 0.832 V to 1.8 V
|   rising waveform, R_fixture 50, V_fixture 0: 20-80 % time 716ps typ, 1.93ns min, 316ps max; typ from 0 V to 1.02 V
|   falling waveform, R_fixture 50, V_fixture 1.8: 20-80 % time 386ps typ, 999ps min, 184ps max; typ from 1.8 V to 0.831 V
|   falling waveform, R_fixture 50, V_fixture 0: 20-80 % time 220ps typ, 431ps min, 143ps max; typ from 1.02 V to 0 V
[POWER_clamp]
-1.8V     154.2mA    109.7mA    213.5mA
-1.255V   57.34mA    38.4mA     81.27mA
-1.145V   39.68mA    26.05mA    56.64mA
-1.109V   34.21mA    22.34mA    48.88mA
-1.073V   28.97mA    18.83mA    41.38mA
-1.036V   23.97mA    15.54mA    34.15mA
-963.6mV  15.93mA    10.41mA    22.29mA
-927.3mV  12.7mA     8.357mA    17.52mA
-854.5mV  8.993mA    5.826mA    12.56mA
-490.9mV  1.518mA    876.6uA    2.331mA
18.18mV   0A         0A         0A
3.6V      0A         0A         0A
[Pulldown]
-1.8V     -12.34mA   -5.658mA   -16.19mA
-1.036V   -15.1mA    -8.245mA   -19.93mA
-763.6mV  -14.53mA   -8.482mA   -19.03mA
-545.5mV  -12.52mA   -7.458mA   -16.62mA
763.6mV   17.59mA    10.45mA    24.25mA
1.527V    33.86mA    19.17mA    47mA
2.073V    42.83mA    22.17mA    61.04mA
2.345V    43.43mA    20.07mA    66.07mA
2.509V    41.51mA    18.14mA    65.79mA
2.782V    36.44mA    14.42mA    61.08mA
3.164V    28.34mA    9.368mA    50.37mA
3.6V      19.79mA    6.648mA    37.91mA
[Pullup]
-1.8V     16.98mA    9.373mA    23.37mA
-818.2mV  14.42mA    8.845mA    19.53mA
-545.5mV  12.31mA    7.518mA    16.8mA
-381.8mV  9.817mA    5.934mA    13.63mA
1.036V    -27.01mA   -15.83mA   -37.94mA
1.909V    -47.35mA   -27.56mA   -67.71mA
2.291V    -55.4mA    -30.4mA    -80.26mA
2.509V    -57.21mA   -29.5mA    -86.26mA
2.673V    -57.02mA   -28.01mA   -88.15mA
2.836V    -55.79mA   -26.21mA   -88.52mA
3.273V    -51.04mA   -20.62mA   -84.23mA
3.6V      -46.22mA   -15.84mA   -80.68mA
[GND_clamp]
-1.8V     -258.3mA   -163.5mA   -409.7mA
-1.255V   -85.36mA   -52.4mA    -138.2mA
-1.218V   -74.87mA   -45.89mA   -121.3mA
-1.145V   -54.71mA   -33.55mA   -88.64mA
-1.109V   -45.65mA   -28.13mA   -73.71mA
-1.036V   -29.56mA   -18.62mA   -47.04mA
-963.6mV  -18.42mA   -12.15mA   -28.08mA
-890.9mV  -11.14mA   -7.842mA   -15.61mA
-818.2mV  -6.603mA   -4.949mA   -8.798mA
-672.7mV  -2.723mA   -1.863mA   -4.246mA
-381.8mV  -91.28uA   -77.52uA   -131.7uA
1.8V      101.9uA    59.34uA    152.6uA
[Ramp]
dV/dt_f 0.58661595/0.38845572n 0.39630329/1.0106703n 0.73533332/0.18564938n
dV/dt_r 0.61655876/0.71864717n 0.42473289/1.976743n  0.77403589/0.31704419n
R_load = 50
[Rising Waveform]
R_fixture = 50
V_fixture = 1.8
V_fixture_min = 1.62
V_fixture_max = 1.98
0s        831.8mV    969mV      762mV
322.7ps   842.7mV    969mV      866.4mV
413.1ps   857.3mV    969.4mV    1.043V
676.5ps   1.005V     988.3mV    1.784V
896.7ps   1.333V     1.031V     1.956V
1.117ns   1.635V     1.129V     1.969V
1.265ns   1.739V     1.221V     1.972V
1.756ns   1.787V     1.501V     1.976V
2.172ns   1.793V     1.586V     1.976V
10.54ns   1.798V     1.618V     1.977V
[Rising Waveform]
R_fixture = 50
V_fixture = 0
V_fixture_min = 0
V_fixture_max = 0
0s        0V         0V         0V
352.1ps   0V         0V         76.29mV
446.3ps   0V         0V         218.1mV
779.8ps   67.2mV     0V         1.028V
1.237ns   510mV      0V         1.229V
1.729ns   853.9mV    27.69mV    1.265V
2.546ns   971.7mV    199.5mV    1.278V
3.848ns   1.006V     500.3mV    1.282V
4.842ns   1.017V     611mV      1.282V
10.64ns   1.021V     696.2mV    1.282V
[Falling Waveform]
R_fixture = 50
V_fixture = 1.8
V_fixture_min = 1.62
V_fixture_max = 1.98
0s        1.797V     1.618V     1.978V
308.8ps   1.797V     1.618V     1.889V
373.3ps   1.797V     1.618V     1.749V
584.8ps   1.783V     1.618V     956.7mV
910ps     1.325V     1.618V     790.9mV
1.156ns   1.007V     1.618V     774mV
1.409ns   895.2mV    1.614V     767.8mV
2.617ns   835.5mV    1.134V     761.7mV
3.357ns   832.2mV    1.018V     761.1mV
10.54ns   830.9mV    968.4mV    761mV
[Falling Waveform]
R_fixture = 50
V_fixture = 0
V_fixture_min = 0
V_fixture_max = 0
0s        1.02V      700.8mV    1.282V
274.3ps   1.02V      700.8mV    1.178V
336.1ps   1.02V      700.8mV    1.003V
502.4ps   974.7mV    700.8mV    158.1mV
731.6ps   507.6mV    700.8mV    30.65mV
860.2ps   169.2mV    697.6mV    19.83mV
977ps     60.29mV    682mV      14.54mV
1.706ns   10.55mV    125.5mV    0V
2.142ns   4.824mV    34.7mV     0V
10.64ns   0V         0V         0V
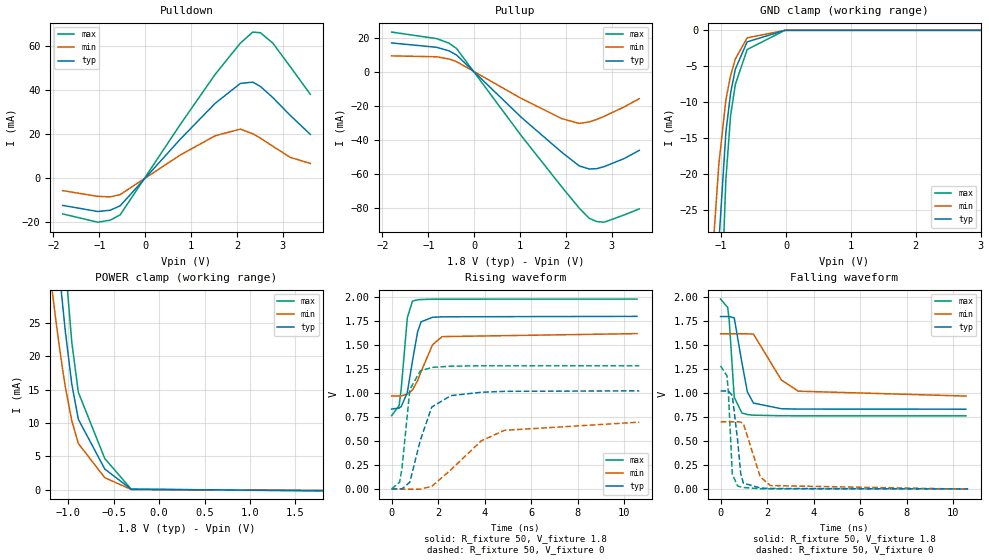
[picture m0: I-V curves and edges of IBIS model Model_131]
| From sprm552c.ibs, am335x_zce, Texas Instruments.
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| Model based on original model for BC1833DV50BPBFBP18LL_SSDLH
|   Sub model BC50B_H_PU_ON_10P_1P8
[model]   Model_131
|[Description]  [1.8V-I/O-WEAK_PU_ON-NORMAL, IND, 10%]
|   NORMAL,Weak internal pull-up,Industrial temperature range (-40C
|   to 125C, 25C nominal),10% power supply tolerance
|[Input Load]   WEAK_PU_ON
|[Output Drive] NORMAL
|Voltage   1.8V
|Mode   I/O
Model_type   I/O
Polarity   Non-Inverting
Enable   Active-Low
Vinl =  0.63
Vinh =  1.17
Cref =  15pF
Rref =  100.0000M
Vref =  0V
Vmeas =  0.9
C_comp   2.112293p   2.03043p   2.1213p
[Model Spec]
Vinl   0.63   0.567   0.693
Vinh   1.17   1.053   1.287
[Temperature Range]   25   125   -40
[Voltage Range]   1.8   1.62   1.98
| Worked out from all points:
|   slope of the pulldown table from 0 to 0.27 V, typ, clamps not added: 42.1 ohm
|   slope of the pullup table from 0 to 0.27 V, typ, clamps not added: 37.7 ohm
|   GND clamp passes 1 mA (typ) near -0.55 V on its own axis
|   POWER clamp passes 1 mA (typ) near -0.45 V on its own axis
|   rising waveform, R_fixture 50, V_fixture 1.8: 20-80 % time 397ps typ, 662ps min, 254ps max; typ from 0.834 V to 1.8 V
|   rising waveform, R_fixture 50, V_fixture 0: 20-80 % time 716ps typ, 1.94ns min, 315ps max; typ from 0.002 V to 1.02 V
|   falling waveform, R_fixture 50, V_fixture 1.8: 20-80 % time 387ps typ, 1ns min, 185ps max; typ from 1.8 V to 0.833 V
|   falling waveform, R_fixture 50, V_fixture 0: 20-80 % time 220ps typ, 433ps min, 143ps max; typ from 1.02 V to 0.002 V
[POWER_clamp]
-1.8V     154.2mA    109.7mA    213.3mA
-1.255V   57.27mA    38.38mA    81.13mA
-1.218V   51.28mA    34.15mA    72.8mA
-1.145V   39.6mA     26.02mA    56.49mA
-1.109V   34.13mA    22.31mA    48.73mA
-1.073V   28.89mA    18.8mA     41.23mA
-1.036V   23.89mA    15.51mA    34mA
-963.6mV  15.85mA    10.37mA    22.13mA
-890.9mV  10.56mA    6.934mA    14.57mA
-600mV    3.124mA    1.834mA    4.693mA
-309.1mV  105.7uA    71.53uA    124.5uA
1.8V      -99.94uA   -59.59uA   -146.8uA
[Pulldown]
-1.8V     -12.34mA   -5.658mA   -16.19mA
-1.036V   -15.1mA    -8.245mA   -19.94mA
-763.6mV  -14.53mA   -8.482mA   -19.03mA
-545.5mV  -12.52mA   -7.458mA   -16.62mA
763.6mV   17.59mA    10.45mA    24.25mA
1.527V    33.86mA    19.17mA    47mA
2.073V    42.83mA    22.17mA    61.04mA
2.345V    43.43mA    20.07mA    66.07mA
2.509V    41.51mA    18.14mA    65.79mA
2.782V    36.44mA    14.42mA    61.08mA
3.164V    28.34mA    9.368mA    50.37mA
3.6V      19.79mA    6.648mA    37.91mA
[Pullup]
-1.8V     16.98mA    9.373mA    23.37mA
-818.2mV  14.42mA    8.845mA    19.53mA
-545.5mV  12.31mA    7.518mA    16.8mA
-381.8mV  9.818mA    5.934mA    13.63mA
1.036V    -27.01mA   -15.83mA   -37.93mA
1.909V    -47.35mA   -27.56mA   -67.71mA
2.291V    -55.4mA    -30.4mA    -80.26mA
2.509V    -57.21mA   -29.5mA    -86.26mA
2.673V    -57.02mA   -28.01mA   -88.15mA
2.836V    -55.79mA   -26.21mA   -88.52mA
3.273V    -51.04mA   -20.62mA   -84.23mA
3.6V      -46.22mA   -15.84mA   -80.68mA
[GND_clamp]
-1.8V     -258.3mA   -163.5mA   -409.7mA
-1.255V   -85.38mA   -52.41mA   -138.2mA
-1.218V   -74.89mA   -45.9mA    -121.4mA
-1.145V   -54.74mA   -33.56mA   -88.69mA
-1.109V   -45.68mA   -28.14mA   -73.78mA
-1.036V   -29.6mA    -18.64mA   -47.14mA
-927.3mV  -14.18mA   -9.66mA    -20.72mA
-854.5mV  -8.721mA   -6.314mA   -11.83mA
-781.8mV  -5.401mA   -3.992mA   -7.544mA
-600mV    -1.607mA   -1.058mA   -2.674mA
-18.18mV  0A         0A         0A
3.6V      0A         0A         0A
[Ramp]
dV/dt_f 0.58647734/0.38898558n 0.39620589/1.0113235n 0.73513785/0.18604499n
dV/dt_r 0.61651775/0.71801853n 0.42461867/1.9757024n  0.7739627/0.31647946n
R_load = 50
[Rising Waveform]
R_fixture = 50
V_fixture = 1.8
V_fixture_min = 1.62
V_fixture_max = 1.98
0s        834.2mV    970.7mV    765.2mV
322.6ps   845.2mV    970.7mV    870.1mV
413ps     860mV      971.1mV    1.047V
674.1ps   1.006V     989.8mV    1.784V
896.6ps   1.337V     1.033V     1.959V
1.117ns   1.639V     1.131V     1.972V
1.264ns   1.743V     1.223V     1.975V
1.755ns   1.79V      1.503V     1.979V
2.173ns   1.795V     1.589V     1.979V
10.54ns   1.8V       1.62V      1.98V
[Rising Waveform]
R_fixture = 50
V_fixture = 0
V_fixture_min = 0
V_fixture_max = 0
0s        2.366mV    0V         3.342mV
345.9ps   2.366mV    0V         73.63mV
446.2ps   2.366mV    0V         222.1mV
783.7ps   73.22mV    0V         1.038V
1.228ns   505.2mV    0V         1.231V
1.724ns   855mV      29.21mV    1.268V
2.545ns   974.2mV    201.6mV    1.281V
3.851ns   1.009V     503.1mV    1.285V
4.841ns   1.019V     612.8mV    1.285V
10.64ns   1.024V     697.8mV    1.285V
[Falling Waveform]
R_fixture = 50
V_fixture = 1.8
V_fixture_min = 1.62
V_fixture_max = 1.98
0s        1.799V     1.619V     1.981V
308.6ps   1.799V     1.619V     1.892V
373.2ps   1.799V     1.619V     1.753V
586.4ps   1.785V     1.619V     958mV
915.5ps   1.32V      1.619V     793.6mV
1.152ns   1.013V     1.619V     777.4mV
1.414ns   896.8mV    1.615V     770.9mV
2.613ns   837.9mV    1.137V     765mV
3.341ns   834.7mV    1.021V     764.4mV
10.54ns   833.3mV    970.1mV    764.3mV
[Falling Waveform]
R_fixture = 50
V_fixture = 0
V_fixture_min = 0
V_fixture_max = 0
0s        1.023V     702.4mV    1.285V
274.3ps   1.023V     702.4mV    1.181V
336.1ps   1.023V     702.4mV    1.006V
504.2ps   976mV      702.4mV    156.8mV
731.8ps   509.9mV    702.4mV    33.73mV
863.9ps   165.5mV    698.9mV    22.67mV
978.2ps   62.56mV    683.4mV    17.51mV
1.706ns   12.81mV    127.7mV    4.651mV
2.142ns   7.057mV    37.23mV    3.471mV
10.64ns   2.268mV    0V         3.044mV
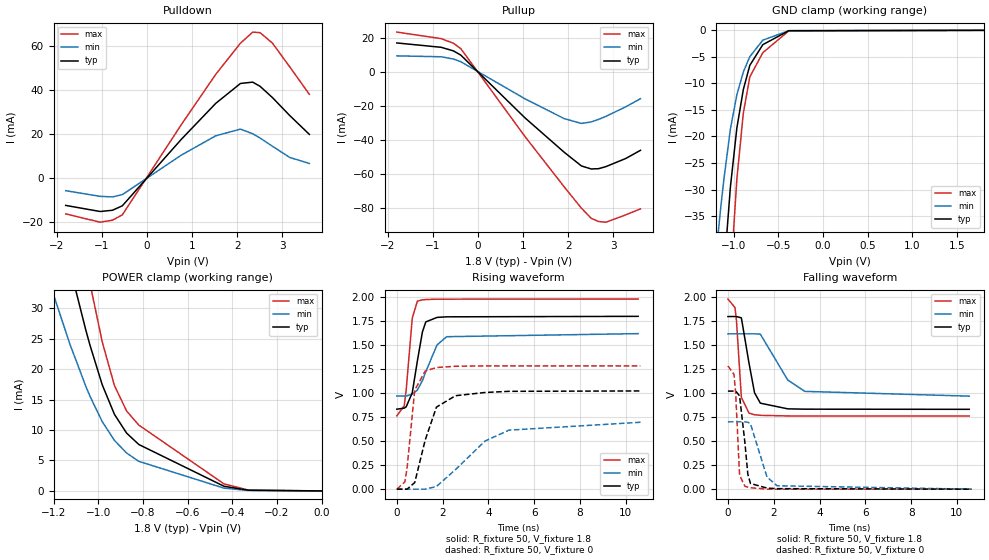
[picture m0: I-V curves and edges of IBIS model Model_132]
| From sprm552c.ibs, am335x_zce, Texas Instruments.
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| Model based on original model for BC1833DV50BPBFBP18LL_SSDLH
|   Sub model BC50B_H_PUPDOFF_10P_1P8
[model]   Model_132
|[Description]  [1.8V-I/O-WEAK_PUPDOFF-NORMAL, IND, 10%]
|   NORMAL,Weak pull up/down disabled,Industrial temperature range
|   (-40C to 125C, 25C nominal),10% power supply tolerance
|[Input Load]   WEAK_PUPDOFF
|[Output Drive] NORMAL
|Voltage   1.8V
|Mode   I/O
Model_type   I/O
Polarity   Non-Inverting
Enable   Active-Low
Vinl =  0.63
Vinh =  1.17
Cref =  15pF
Rref =  100.0000M
Vref =  0V
Vmeas =  0.9
C_comp   2.112293p   2.03043p   2.1213p
[Model Spec]
Vinl   0.63   0.567   0.693
Vinh   1.17   1.053   1.287
[Temperature Range]   25   125   -40
[Voltage Range]   1.8   1.62   1.98
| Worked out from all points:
|   slope of the pulldown table from 0 to 0.27 V, typ, clamps not added: 42.1 ohm
|   slope of the pullup table from 0 to 0.27 V, typ, clamps not added: 37.7 ohm
|   GND clamp passes 1 mA (typ) near -0.56 V on its own axis
|   POWER clamp passes 1 mA (typ) near -0.46 V on its own axis
|   rising waveform, R_fixture 50, V_fixture 1.8: 20-80 % time 398ps typ, 662ps min, 254ps max; typ from 0.833 V to 1.8 V
|   rising waveform, R_fixture 50, V_fixture 0: 20-80 % time 717ps typ, 1.93ns min, 316ps max; typ from 0 V to 1.02 V
|   falling waveform, R_fixture 50, V_fixture 1.8: 20-80 % time 387ps typ, 1ns min, 185ps max; typ from 1.8 V to 0.832 V
|   falling waveform, R_fixture 50, V_fixture 0: 20-80 % time 220ps typ, 431ps min, 143ps max; typ from 1.02 V to 0 V
[POWER_clamp]
-1.8V     154.2mA    109.7mA    213.3mA
-1.236V   54.24mA    36.25mA    76.91mA
-1.127V   36.83mA    24.15mA    52.56mA
-1.055V   26.36mA    17.14mA    37.57mA
-1.036V   23.85mA    15.49mA    33.95mA
-981.8mV  17.43mA    11.38mA    24.47mA
-927.3mV  12.58mA    8.302mA    17.32mA
-872.7mV  9.497mA    6.223mA    13.12mA
-818.2mV  7.629mA    4.862mA    10.82mA
-436.4mV  761.6uA    453.8uA    1.147mA
-327.3mV  115.1uA    79.01uA    133.6uA
0V        19.19nA    119.5nA    352.1nA
[Pulldown]
-1.8V     -12.34mA   -5.658mA   -16.19mA
-1.036V   -15.1mA    -8.245mA   -19.93mA
-763.6mV  -14.53mA   -8.482mA   -19.03mA
-545.5mV  -12.52mA   -7.458mA   -16.62mA
763.6mV   17.59mA    10.43mA    24.25mA
1.527V    33.86mA    19.17mA    47mA
2.073V    42.83mA    22.17mA    61.04mA
2.345V    43.43mA    20.07mA    66.07mA
2.509V    41.51mA    18.14mA    65.79mA
2.782V    36.44mA    14.42mA    61.08mA
3.164V    28.34mA    9.368mA    50.37mA
3.6V      19.79mA    6.648mA    37.91mA
[Pullup]
-1.8V     16.98mA    9.373mA    23.37mA
-818.2mV  14.42mA    8.845mA    19.53mA
-545.5mV  12.31mA    7.518mA    16.8mA
-381.8mV  9.818mA    5.934mA    13.63mA
1.036V    -27.01mA   -15.83mA   -37.94mA
1.909V    -47.35mA   -27.56mA   -67.71mA
2.291V    -55.4mA    -30.4mA    -80.26mA
2.509V    -57.21mA   -29.5mA    -86.26mA
2.673V    -57.02mA   -28.01mA   -88.15mA
2.836V    -55.79mA   -26.21mA   -88.52mA
3.273V    -51.04mA   -20.62mA   -84.23mA
3.6V      -46.22mA   -15.84mA   -80.68mA
[GND_clamp]
-1.8V     -258.3mA   -163.5mA   -409.7mA
-1.255V   -85.35mA   -52.4mA    -138.2mA
-1.218V   -74.87mA   -45.89mA   -121.3mA
-1.145V   -54.71mA   -33.55mA   -88.63mA
-1.109V   -45.64mA   -28.13mA   -73.71mA
-1.036V   -29.55mA   -18.62mA   -47.03mA
-963.6mV  -18.42mA   -12.14mA   -28.07mA
-890.9mV  -11.13mA   -7.836mA   -15.58mA
-818.2mV  -6.581mA   -4.941mA   -8.76mA
-672.7mV  -2.695mA   -1.849mA   -4.207mA
-381.8mV  -68.52uA   -64.39uA   -99.44uA
1.8V      19.19nA    2.616uA    309.8nA
[Ramp]
dV/dt_f 0.58725832/0.38963456n 0.39661289/1.0124709n 0.73631155/0.18645683n
dV/dt_r 0.61735473/0.71957153n 0.42515606/1.9784207n 0.77521081/0.31760074n
R_load = 50
[Rising Waveform]
R_fixture = 50
V_fixture = 1.8
V_fixture_min = 1.62
V_fixture_max = 1.98
0s        832.9mV    970mV      763.3mV
323.5ps   843.9mV    970mV      867.9mV
408.9ps   857.5mV    970.3mV    1.032V
675ps     1.004V     989.1mV    1.782V
897.5ps   1.335V     1.032V     1.958V
1.118ns   1.638V     1.13V      1.972V
1.265ns   1.742V     1.223V     1.975V
1.756ns   1.789V     1.502V     1.979V
2.174ns   1.795V     1.588V     1.979V
10.54ns   1.8V       1.62V      1.98V
[Rising Waveform]
R_fixture = 50
V_fixture = 0
V_fixture_min = 0
V_fixture_max = 0
0s        0V         0V         0V
352.9ps   0V         0V         76.3mV
447.1ps   0V         0V         218.2mV
782.3ps   68.45mV    0V         1.031V
1.238ns   510.2mV    0V         1.23V
1.73ns    854.3mV    27.62mV    1.267V
2.561ns   973.3mV    203.1mV    1.28V
3.849ns   1.007V     500.6mV    1.284V
4.894ns   1.019V     614.5mV    1.284V
10.64ns   1.023V     696.8mV    1.284V
[Falling Waveform]
R_fixture = 50
V_fixture = 1.8
V_fixture_min = 1.62
V_fixture_max = 1.98
0s        1.799V     1.619V     1.981V
309.5ps   1.799V     1.619V     1.892V
374.1ps   1.799V     1.619V     1.753V
587.3ps   1.785V     1.619V     957.6mV
920.4ps   1.314V     1.619V     792.1mV
1.162ns   1.005V     1.619V     775.7mV
1.416ns   896.2mV    1.615V     769.4mV
2.614ns   837mV      1.137V     763.1mV
3.358ns   833.6mV    1.019V     762.4mV
10.54ns   832mV      969.5mV    762.3mV
[Falling Waveform]
R_fixture = 50
V_fixture = 0
V_fixture_min = 0
V_fixture_max = 0
0s        1.022V     701.6mV    1.284V
267.1ps   1.022V     701.6mV    1.194V
337.4ps   1.022V     701.6mV    1.003V
507.9ps   973.3mV    701.6mV    148.7mV
736.5ps   497.2mV    701.6mV    31.36mV
869ps     156.5mV    697.7mV    20.33mV
984.5ps   59.17mV    681.4mV    15.07mV
1.707ns   11.13mV    126.4mV    0V
2.143ns   5.269mV    35.48mV    0V
10.64ns   0V         0V         0V
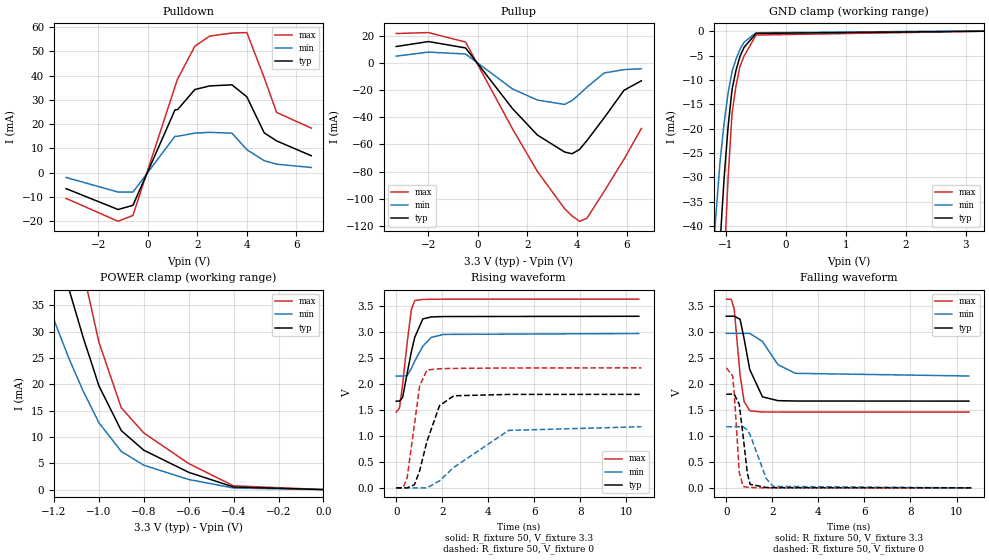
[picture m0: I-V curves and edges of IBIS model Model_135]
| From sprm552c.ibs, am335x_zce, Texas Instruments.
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| Model based on original model for BC1833DV50BPBFBP18LL_SSDLH
|   Sub model BC50B_H_PUPDOFF_10P_3P3
[model]   Model_135
|[Description]  [3.3V-I/O-WEAK_PUPDOFF-NORMAL, IND, 10%]
|   NORMAL,Weak pull up/down disabled,Industrial temperature range
|   (-40C to 125C, 25C nominal),10% power supply tolerance
|[Input Load]   WEAK_PUPDOFF
|[Output Drive] NORMAL
|Voltage   3.3V
|Mode   I/O
Model_type   I/O
Polarity   Non-Inverting
Enable   Active-Low
Vinl =  0.8V
Vinh =  2V
Cref =  15pF
Rref =  100.0000M
Vref =  0V
Vmeas =  1.65
C_comp   1.88955p   1.743536p   1.980111p
[Model Spec]
Vinl   0.8V   0.8V   0.8V
Vinh   2V   2V   2V
[Temperature Range]   25   125   -40
[Voltage Range]   3.3   2.97   3.63
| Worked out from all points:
|   slope of the pulldown table from 0 to 0.495 V, typ, clamps not added: 41.2 ohm
|   slope of the pullup table from 0 to 0.495 V, typ, clamps not added: 40 ohm
|   GND clamp passes 1 mA (typ) near -0.55 V on its own axis
|   POWER clamp passes 1 mA (typ) near -0.44 V on its own axis
|   rising waveform, R_fixture 50, V_fixture 3.3: 20-80 % time 463ps typ, 617ps min, 334ps max; typ from 1.67 V to 3.3 V
|   rising waveform, R_fixture 50, V_fixture 0: 20-80 % time 697ps typ, 1.87ns min, 386ps max; typ from 0 V to 1.8 V
|   falling waveform, R_fixture 50, V_fixture 3.3: 20-80 % time 468ps typ, 804ps min, 267ps max; typ from 3.3 V to 1.67 V
|   falling waveform, R_fixture 50, V_fixture 0: 20-80 % time 274ps typ, 570ps min, 191ps max; typ from 1.8 V to 0 V
[POWER_clamp]
-3.3V     437.1mA    413.2mA    590.8mA
-1.267V   59.46mA    39.86mA    84.25mA
-1.233V   53.93mA    35.93mA    76.6mA
-1.133V   38.09mA    24.91mA    54.45mA
-1.067V   28.54mA    18.48mA    40.82mA
-1.033V   24.14mA    15.6mA     34.44mA
-1V       19.75mA    12.72mA    28.06mA
-900mV    11.21mA    7.259mA    15.54mA
-800mV    7.487mA    4.633mA    10.77mA
-600mV    3.284mA    1.922mA    4.945mA
-400mV    494.5uA    303.8uA    719.2uA
0V        4.588uA    2.009uA    9.299uA
[Pulldown]
-3.3V     -6.622mA   -2.021mA   -10.65mA
-1.2V     -15.24mA   -8.032mA   -20.09mA
-600mV    -13.5mA    -8.05mA    -17.67mA
1.1V      25.87mA    14.97mA    35.44mA
1.2V      25.9mA     14.97mA    38.5mA
1.9V      34.23mA    16.24mA    52.08mA
2.5V      35.71mA    16.58mA    56.26mA
3.4V      36.16mA    16.23mA    57.51mA
4V        31.2mA     9.437mA    57.7mA
4.7V      16.38mA    4.891mA    39.13mA
5.2V      13.06mA    3.458mA    24.8mA
6.6V      6.944mA    2.091mA    18.31mA
[Pullup]
-3.3V     12.22mA    5.124mA    21.79mA
-2V       15.88mA    8.101mA    22.51mA
-500mV    11.19mA    6.71mA     15.51mA
1.4V      -33.67mA   -19.12mA   -48.63mA
2.4V      -53.04mA   -27.26mA   -79.87mA
3.5V      -65.59mA   -30.5mA    -107.4mA
3.8V      -66.88mA   -27.67mA   -112.7mA
4.1V      -63.77mA   -22.88mA   -116.7mA
4.4V      -57.22mA   -17.81mA   -114.5mA
5.1V      -40.3mA    -7.267mA   -94.57mA
5.9V      -20.05mA   -4.823mA   -70.85mA
6.6V      -13.04mA   -4.182mA   -48.28mA
[GND_clamp]
-3.3V     -759.3mA   -592.9mA   -1.187A
-1.233V   -79.57mA   -48.75mA   -128.9mA
-1.167V   -61.05mA   -37.35mA   -98.95mA
-1.1V     -43.5mA    -26.72mA   -70.29mA
-1.033V   -30.2mA    -18.9mA    -48.08mA
-966.7mV  -19.68mA   -12.74mA   -30.27mA
-900mV    -11.93mA   -8.215mA   -16.85mA
-833.3mV  -7.988mA   -5.689mA   -11.11mA
-766.7mV  -5.117mA   -3.7mA     -7.197mA
-700mV    -3.311mA   -2.248mA   -5.106mA
-500mV    -444.3uA   -319.3uA   -780.9uA
3.3V      4.588uA    93.88uA    5.606uA
[Ramp]
dV/dt_f 0.98253616/0.46828589n 0.49549526/0.80912849n   1.306759/0.26717999n
dV/dt_r  1.0822198/0.69887655n  0.7089986/1.874962n   1.3894948/0.38766844n
R_load = 50
[Rising Waveform]
R_fixture = 50
V_fixture = 3.3
V_fixture_min = 2.97
V_fixture_max = 3.63
0s        1.668V     2.15V      1.458V
141.1ps   1.668V     2.15V      1.532V
276.5ps   1.737V     2.15V      1.983V
474.2ps   2.199V     2.157V     2.779V
655.7ps   2.613V     2.292V     3.426V
808.6ps   2.901V     2.441V     3.604V
1.157ns   3.249V     2.724V     3.624V
1.525ns   3.288V     2.895V     3.627V
2.062ns   3.295V     2.951V     3.629V
10.54ns   3.3V       2.969V     3.63V
[Rising Waveform]
R_fixture = 50
V_fixture = 0
V_fixture_min = 0
V_fixture_max = 0
0s        0V         0V         0V
302.9ps   0V         0V         0V
475.5ps   0V         0V         196.7mV
793.1ps   61.67mV    0V         1.221V
1.015ns   321.5mV    0V         1.957V
1.335ns   894mV      0V         2.267V
1.881ns   1.58V      135.1mV    2.291V
2.5ns     1.771V     393.2mV    2.297V
4.883ns   1.797V     1.105V     2.306V
10.65ns   1.798V     1.176V     2.308V
[Falling Waveform]
R_fixture = 50
V_fixture = 3.3
V_fixture_min = 2.97
V_fixture_max = 3.63
0s        3.3V       2.97V      3.629V
214.6ps   3.3V       2.97V      3.626V
341.4ps   3.3V       2.97V      3.443V
597.1ps   3.242V     2.97V      2.171V
772.5ps   2.868V     2.97V      1.66V
1.016ns   2.277V     2.97V      1.483V
1.569ns   1.75V      2.816V     1.458V
2.245ns   1.677V     2.368V     1.458V
2.996ns   1.67V      2.202V     1.457V
10.54ns   1.668V     2.151V     1.457V
[Falling Waveform]
R_fixture = 50
V_fixture = 0
V_fixture_min = 0
V_fixture_max = 0
0s        1.801V     1.176V     2.308V
276.2ps   1.801V     1.176V     2.151V
346.1ps   1.798V     1.176V     1.812V
561.7ps   1.606V     1.176V     298.2mV
730.5ps   990.6mV    1.174V     29.84mV
913.6ps   279.8mV    1.111V     10.11mV
1.033ns   67.8mV     1.021V     7.074mV
1.732ns   7.371mV    179.2mV    0V
2.033ns   4.226mV    28.04mV    0V
10.65ns   0V         0V         0V
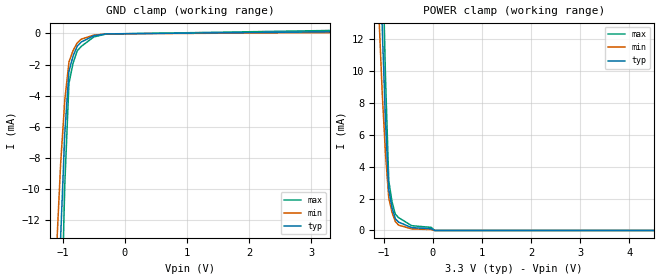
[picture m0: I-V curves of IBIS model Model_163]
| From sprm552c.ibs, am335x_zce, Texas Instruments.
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| Model based on original model for IQ1833DVTCKPBFBP18LL_SSDHH
|   Sub model IQ_SSDHH_PD_ON_5P_3P3
[model]   Model_163
|[Description]  [3.3V-INPUT-PD-X, IND, 5%]
|   Weak internal pull-down,Industrial temperature range (-40C to
|   125C, 25C nominal),5% power supply tolerance
|[Input Load]   PD
|[Output Drive]
|Voltage   3.3V
|Mode   INPUT
Model_type   Input
Polarity   Non-Inverting
Vinl =  0.8V
Vinh =  2V
C_comp   1.115166p   0.9969108p   1.462567p
[Model Spec]
Vinl   0.8V   0.8V   0.8V
Vinh   2V   2V   2V
[Temperature Range]   25   125   -40
[Voltage Range]   3.3   3.135   3.465
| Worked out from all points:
|   GND clamp passes 1 mA (typ) near -0.79 V on its own axis
|   POWER clamp passes 1 mA (typ) near -0.79 V on its own axis
[POWER_clamp]
-3.3V     372.1mA    388.5mA    506.4mA
-1.1V     20.15mA    13.5mA     29.25mA
-1.033V   12.75mA    8.643mA    18.36mA
-966.7mV  6.888mA    4.824mA    9.66mA
-900mV    2.553mA    2.049mA    3.133mA
-833.3mV  1.417mA    1.133mA    1.803mA
-766.7mV  741.6uA    562uA      1.028mA
-700mV    526.3uA    337.1uA    807.1uA
-433.3mV  180.1uA    100.4uA    302.7uA
-33.33mV  106.8uA    56.83uA    192.6uA
33.33mV   0A         0A         0A
6.6V      0A         0A         0A
[GND_clamp]
-3.3V     -586.5mA   -522.8mA   -870.7mA
-1.1V     -22.36mA   -13.96mA   -35.17mA
-1.033V   -13.08mA   -8.332mA   -20.39mA
-966.7mV  -6.437mA   -4.289mA   -9.733mA
-900mV    -2.44mA    -1.836mA   -3.204mA
-833.3mV  -1.448mA   -1.096mA   -1.908mA
-766.7mV  -816.1uA   -604.8uA   -1.115mA
-700mV    -544.2uA   -363.1uA   -825.5uA
-500mV    -150.1uA   -107.5uA   -223uA
-300mV    -26.95uA   -27.31uA   -36.29uA
3.3V      106.8uA    57uA       191.6uA
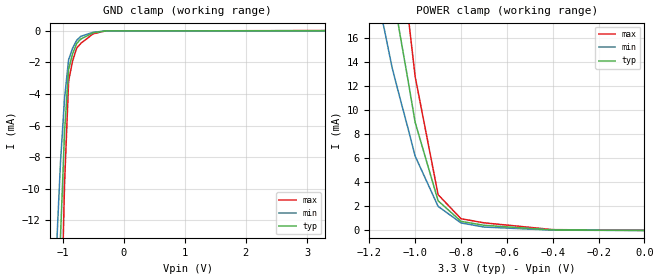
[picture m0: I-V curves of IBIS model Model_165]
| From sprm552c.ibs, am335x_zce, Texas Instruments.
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| Model based on original model for IQ1833DVTCKPBFBP18LL_SSDHH
|   Sub model IQ_SSDHH_PUPDOFF_5P_3P3
[model]   Model_165
|[Description]  [3.3V-INPUT-PI-X, IND, 5%]
|   Weak pull up/down disabled,Industrial temperature range (-40C to
|   125C, 25C nominal),5% power supply tolerance
|[Input Load]   PI
|[Output Drive]
|Voltage   3.3V
|Mode   INPUT
Model_type   Input
Polarity   Non-Inverting
Vinl =  0.8V
Vinh =  2V
C_comp   1.115166p   0.9969108p   1.462567p
[Model Spec]
Vinl   0.8V   0.8V   0.8V
Vinh   2V   2V   2V
[Temperature Range]   25   125   -40
[Voltage Range]   3.3   3.135   3.465
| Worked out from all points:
|   GND clamp passes 1 mA (typ) near -0.79 V on its own axis
|   POWER clamp passes 1 mA (typ) near -0.81 V on its own axis
[POWER_clamp]
-3.3V     372.1mA    388.5mA    506.4mA
-1.167V   28.96mA    19.64mA    41.69mA
-1.133V   24.52mA    16.55mA    35.4mA
-1.1V     20.07mA    13.47mA    29.1mA
-1.067V   16.37mA    11.04mA    23.66mA
-1.033V   12.67mA    8.604mA    18.22mA
-1V       8.974mA    6.172mA    12.77mA
-900mV    2.467mA    2.005mA    2.976mA
-800mV    758.8uA    627.7uA    975.2uA
-700mV    431.9uA    287.6uA    638.1uA
-400mV    45.5uA     27.56uA    71.51uA
0V        2.776uA    1.329uA    10.14uA
[GND_clamp]
-3.3V     -586.5mA   -522.8mA   -870.7mA
-1.1V     -22.35mA   -13.96mA   -35.17mA
-1.033V   -13.07mA   -8.33mA    -20.38mA
-966.7mV  -6.432mA   -4.287mA   -9.725mA
-900mV    -2.433mA   -1.833mA   -3.193mA
-833.3mV  -1.436mA   -1.091mA   -1.888mA
-766.7mV  -800.1uA   -598.2uA   -1.091mA
-700mV    -525.1uA   -354.1uA   -799.7uA
-500mV    -130.5uA   -96.22uA   -196.4uA
-300mV    -12.45uA   -18.78uA   -15.7uA
3.3V      2.776uA    1.506uA    9.929uA
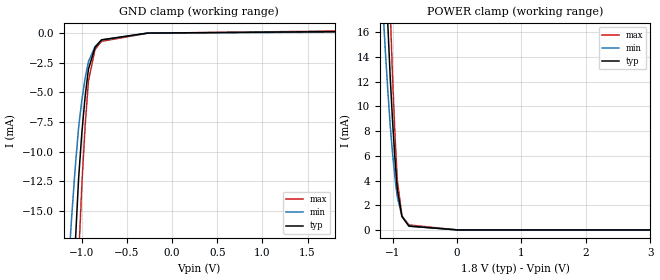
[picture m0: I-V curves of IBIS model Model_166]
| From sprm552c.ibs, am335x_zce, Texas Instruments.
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| Model based on original model for IQ1833DVTCKPBFBP18LL_SSDHH
|   Sub model IQ_SSDHH_PD_ON_10P_1P8
[model]   Model_166
|[Description]  [1.8V-INPUT-PD-X, IND, 10%]
|   Weak internal pull-down,Industrial temperature range (-40C to
|   125C, 25C nominal),10% power supply tolerance
|[Input Load]   PD
|[Output Drive]
|Voltage   1.8V
|Mode   INPUT
Model_type   Input
Polarity   Non-Inverting
Vinl =  0.63
Vinh =  1.17
C_comp   1.313442p   1.243821p   1.333527p
[Model Spec]
Vinl   0.63   0.567   0.693
Vinh   1.17   1.053   1.287
[Temperature Range]   25   125   -40
[Voltage Range]   1.8   1.62   1.98
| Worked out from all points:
|   GND clamp passes 1 mA (typ) near -0.84 V on its own axis
|   POWER clamp passes 1 mA (typ) near -0.85 V on its own axis
[POWER_clamp]
-1.8V     125.7mA    90.96mA    174.4mA
-1.145V   25.72mA    17.45mA    37.06mA
-1.109V   21.03mA    14.24mA    30.34mA
-1.073V   16.56mA    11.24mA    23.88mA
-1.036V   12.33mA    8.44mA     17.69mA
-1V       8.805mA    6.19mA     12.38mA
-963.6mV  5.801mA    4.276mA    7.842mA
-927.3mV  3.317mA    2.7mA      4.07mA
-854.5mV  1.094mA    1.101mA    1.124mA
-745.5mV  311.3uA    306.4uA    405.5uA
18.18mV   0A         0A         0A
3.6V      0A         0A         0A
[GND_clamp]
-1.8V     -190.2mA   -126mA     -287.6mA
-1.145V   -30.72mA   -19.26mA   -48.25mA
-1.109V   -23.91mA   -15.06mA   -37.51mA
-1.073V   -17.75mA   -11.3mA    -27.76mA
-1.036V   -12.25mA   -7.962mA   -18.99mA
-1V       -8.398mA   -5.649mA   -12.78mA
-963.6mV  -5.338mA   -3.804mA   -7.807mA
-927.3mV  -3.068mA   -2.426mA   -4.067mA
-854.5mV  -1.224mA   -1.16mA    -1.4mA
-781.8mV  -588.9uA   -602.1uA   -714.5uA
-272.7mV  -23.46uA   -23.05uA   -31.84uA
1.8V      101.9uA    56.84uA    152.6uA
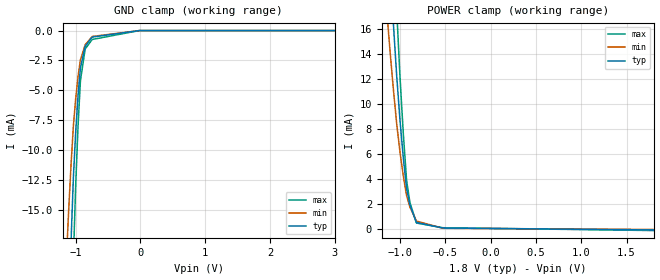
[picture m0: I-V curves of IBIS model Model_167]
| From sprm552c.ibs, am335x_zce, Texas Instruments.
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| Model based on original model for IQ1833DVTCKPBFBP18LL_SSDHH
|   Sub model IQ_SSDHH_PU_ON_10P_1P8
[model]   Model_167
|[Description]  [1.8V-INPUT-PU-X, IND, 10%]
|   Weak internal pull-up,Industrial temperature range (-40C to
|   125C, 25C nominal),10% power supply tolerance
|[Input Load]   PU
|[Output Drive]
|Voltage   1.8V
|Mode   INPUT
Model_type   Input
Polarity   Non-Inverting
Vinl =  0.63
Vinh =  1.17
C_comp   1.313442p   1.243821p   1.333527p
[Model Spec]
Vinl   0.63   0.567   0.693
Vinh   1.17   1.053   1.287
[Temperature Range]   25   125   -40
[Voltage Range]   1.8   1.62   1.98
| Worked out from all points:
|   GND clamp passes 1 mA (typ) near -0.83 V on its own axis
|   POWER clamp passes 1 mA (typ) near -0.85 V on its own axis
[POWER_clamp]
-1.8V     125.7mA    90.96mA    174.2mA
-1.145V   25.64mA    17.42mA    36.91mA
-1.109V   20.95mA    14.21mA    30.19mA
-1.073V   16.48mA    11.21mA    23.74mA
-1.036V   12.25mA    8.407mA    17.54mA
-1V       8.723mA    6.156mA    12.23mA
-963.6mV  5.718mA    4.241mA    7.69mA
-927.3mV  3.233mA    2.664mA    3.916mA
-890.9mV  1.918mA    1.746mA    2.122mA
-818.2mV  499.9uA    613.2uA    455.2uA
-527.3mV  56.53uA    33.9uA     79.5uA
1.8V      -99.93uA   -59.39uA   -146.8uA
[GND_clamp]
-1.8V     -190.2mA   -126mA     -287.6mA
-1.145V   -30.74mA   -19.27mA   -48.3mA
-1.109V   -23.94mA   -15.07mA   -37.57mA
-1.073V   -17.79mA   -11.31mA   -27.84mA
-1.036V   -12.29mA   -7.978mA   -19.09mA
-1V       -8.448mA   -5.667mA   -12.89mA
-963.6mV  -5.397mA   -3.825mA   -7.93mA
-927.3mV  -3.136mA   -2.451mA   -4.202mA
-854.5mV  -1.305mA   -1.193mA   -1.545mA
-745.5mV  -545.3uA   -493.3uA   -747.1uA
-18.18mV  0A         0A         0A
3.6V      0A         0A         0A
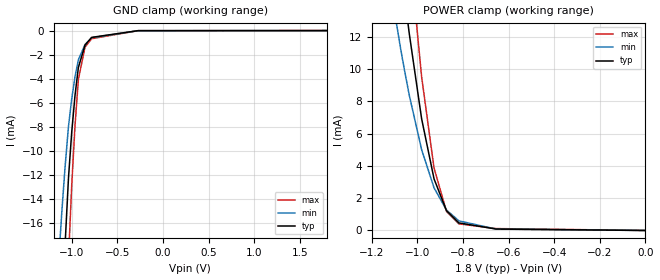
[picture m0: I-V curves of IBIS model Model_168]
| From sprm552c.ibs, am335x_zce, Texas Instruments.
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| Model based on original model for IQ1833DVTCKPBFBP18LL_SSDHH
|   Sub model IQ_SSDHH_PUPDOFF_10P_1P8
[model]   Model_168
|[Description]  [1.8V-INPUT-PI-X, IND, 10%]
|   Weak pull up/down disabled,Industrial temperature range (-40C to
|   125C, 25C nominal),10% power supply tolerance
|[Input Load]   PI
|[Output Drive]
|Voltage   1.8V
|Mode   INPUT
Model_type   Input
Polarity   Non-Inverting
Vinl =  0.63
Vinh =  1.17
C_comp   1.313442p   1.243821p   1.333527p
[Model Spec]
Vinl   0.63   0.567   0.693
Vinh   1.17   1.053   1.287
[Temperature Range]   25   125   -40
[Voltage Range]   1.8   1.62   1.98
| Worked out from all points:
|   GND clamp passes 1 mA (typ) near -0.84 V on its own axis
|   POWER clamp passes 1 mA (typ) near -0.86 V on its own axis
[POWER_clamp]
-1.8V     125.7mA    90.95mA    174.2mA
-1.127V   23.26mA    15.8mA     33.5mA
-1.073V   16.45mA    11.19mA    23.69mA
-1.055V   14.33mA    9.79mA     20.59mA
-1.036V   12.21mA    8.389mA    17.49mA
-1.018V   10.45mA    7.263mA    14.84mA
-981.8mV  6.927mA    5.011mA    9.53mA
-927.3mV  3.2mA      2.645mA    3.869mA
-872.7mV  1.228mA    1.268mA    1.178mA
-818.2mV  468.1uA    594.8uA    409.6uA
-654.5mV  88.28uA    84.32uA    116.8uA
0V        19.84nA    93.74nA    330.9nA
[GND_clamp]
-1.8V     -190.2mA   -126mA     -287.6mA
-1.145V   -30.71mA   -19.26mA   -48.24mA
-1.109V   -23.91mA   -15.06mA   -37.5mA
-1.073V   -17.75mA   -11.29mA   -27.75mA
-1.036V   -12.24mA   -7.958mA   -18.98mA
-1V       -8.39mA    -5.645mA   -12.77mA
-963.6mV  -5.329mA   -3.799mA   -7.793mA
-927.3mV  -3.057mA   -2.421mA   -4.049mA
-854.5mV  -1.206mA   -1.153mA   -1.368mA
-781.8mV  -563.5uA   -591.9uA   -675.2uA
-272.7mV  -6.512uA   -13.18uA   -7.456uA
1.8V      19.84nA    109.4nA    308nA
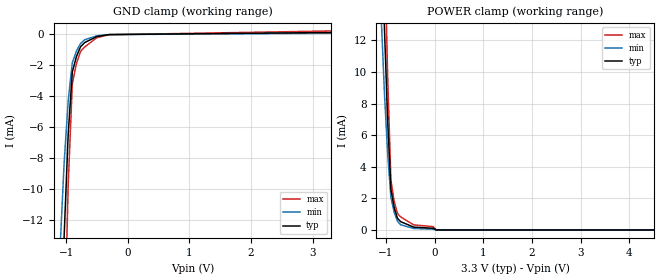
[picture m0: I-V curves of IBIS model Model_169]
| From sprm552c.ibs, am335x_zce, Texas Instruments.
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| Model based on original model for IQ1833DVTCKPBFBP18LL_SSDHH
|   Sub model IQ_SSDHH_PD_ON_10P_3P3
[model]   Model_169
|[Description]  [3.3V-INPUT-PD-X, IND, 10%]
|   Weak internal pull-down,Industrial temperature range (-40C to
|   125C, 25C nominal),10% power supply tolerance
|[Input Load]   PD
|[Output Drive]
|Voltage   3.3V
|Mode   INPUT
Model_type   Input
Polarity   Non-Inverting
Vinl =  0.8V
Vinh =  2V
C_comp   1.115166p   0.9908539p   1.211879p
[Model Spec]
Vinl   0.8V   0.8V   0.8V
Vinh   2V   2V   2V
[Temperature Range]   25   125   -40
[Voltage Range]   3.3   2.97   3.63
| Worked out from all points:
|   GND clamp passes 1 mA (typ) near -0.79 V on its own axis
|   POWER clamp passes 1 mA (typ) near -0.79 V on its own axis
[POWER_clamp]
-3.3V     372.1mA    370.8mA    506.4mA
-1.1V     20.15mA    13.5mA     29.27mA
-1.033V   12.75mA    8.635mA    18.39mA
-966.7mV  6.888mA    4.816mA    9.68mA
-900mV    2.553mA    2.041mA    3.153mA
-833.3mV  1.417mA    1.125mA    1.824mA
-766.7mV  741.6uA    554.2uA    1.049mA
-700mV    526.3uA    329.4uA    827.6uA
-433.3mV  180.1uA    93.5uA     322.4uA
-33.33mV  106.8uA    49.98uA    212.5uA
33.33mV   0A         0A         0A
6.6V      0A         0A         0A
[GND_clamp]
-3.3V     -586.5mA   -502.8mA   -870.7mA
-1.1V     -22.36mA   -13.96mA   -35.17mA
-1.033V   -13.08mA   -8.331mA   -20.39mA
-966.7mV  -6.437mA   -4.289mA   -9.734mA
-900mV    -2.44mA    -1.835mA   -3.206mA
-833.3mV  -1.448mA   -1.095mA   -1.909mA
-766.7mV  -816.1uA   -604.4uA   -1.116mA
-700mV    -544.2uA   -362.7uA   -826.1uA
-500mV    -150.1uA   -107.1uA   -223.3uA
-300mV    -26.95uA   -27.16uA   -36.41uA
3.3V      106.8uA    57.87uA    205.8uA
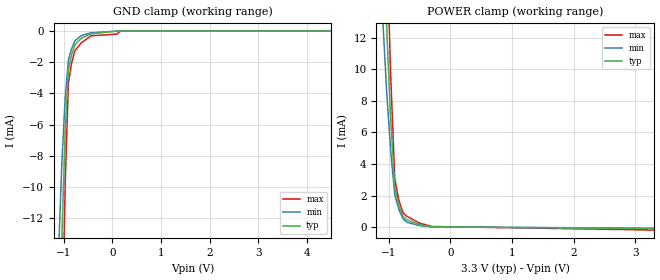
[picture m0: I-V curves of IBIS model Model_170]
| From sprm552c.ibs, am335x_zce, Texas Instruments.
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| Model based on original model for IQ1833DVTCKPBFBP18LL_SSDHH
|   Sub model IQ_SSDHH_PU_ON_10P_3P3
[model]   Model_170
|[Description]  [3.3V-INPUT-PU-X, IND, 10%]
|   Weak internal pull-up,Industrial temperature range (-40C to
|   125C, 25C nominal),10% power supply tolerance
|[Input Load]   PU
|[Output Drive]
|Voltage   3.3V
|Mode   INPUT
Model_type   Input
Polarity   Non-Inverting
Vinl =  0.8V
Vinh =  2V
C_comp   1.115166p   0.9908539p   1.211879p
[Model Spec]
Vinl   0.8V   0.8V   0.8V
Vinh   2V   2V   2V
[Temperature Range]   25   125   -40
[Voltage Range]   3.3   2.97   3.63
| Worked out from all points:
|   GND clamp passes 1 mA (typ) near -0.78 V on its own axis
|   POWER clamp passes 1 mA (typ) near -0.80 V on its own axis
[POWER_clamp]
-3.3V     372.1mA    370.8mA    506.4mA
-1.1V     20.1mA     13.48mA    29.15mA
-1.033V   12.7mA     8.616mA    18.26mA
-966.7mV  6.831mA    4.795mA    9.55mA
-900mV    2.493mA    2.018mA    3.017mA
-833.3mV  1.353mA    1.1mA      1.682mA
-766.7mV  674.6uA    527uA      902.2uA
-700mV    455.9uA    300.1uA    676.5uA
-500mV    162.9uA    94.19uA    256.6uA
-300mV    23.19uA    13.64uA    40.43uA
3.3V      -100.3uA   -71.77uA   -188.2uA
[GND_clamp]
-3.3V     -586.5mA   -502.8mA   -870.8mA
-1.1V     -22.37mA   -13.97mA   -35.21mA
-1.033V   -13.09mA   -8.337mA   -20.45mA
-966.7mV  -6.465mA   -4.296mA   -9.826mA
-900mV    -2.481mA   -1.845mA   -3.327mA
-833.3mV  -1.501mA   -1.111mA   -2.042mA
-766.7mV  -878uA     -624.8uA   -1.257mA
-633.3mV  -455.6uA   -282uA     -746.2uA
-433.3mV  -176.8uA   -107.8uA   -303.6uA
100mV     0A         0A         -191.2uA
166.7mV   0A         0A         0A
6.6V      0A         0A         0A
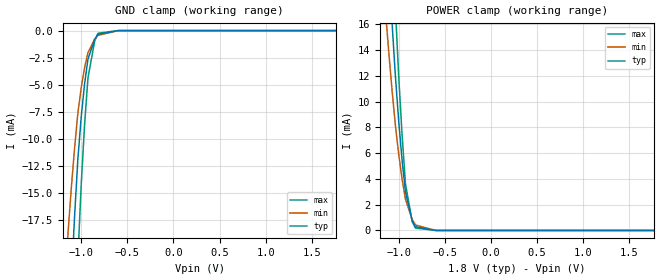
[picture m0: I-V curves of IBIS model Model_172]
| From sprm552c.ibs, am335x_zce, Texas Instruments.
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| Model based on original model for IQ18GLFHY_SSBHH
|   Sub model IQ18GLFHY_SSBHH
[model]   Model_172
|[Description]  [1.8V-INPUT-X-X]
|   , ,
|[Input Load]
|[Output Drive]
|Voltage   1.8V
|Mode   INPUT
Model_type   Input
Polarity   Non-Inverting
Vinl =  0.63
Vinh =  1.17
C_comp   1.035615p   0.8997247p   1.178454p
[Model Spec]
Vinl   0.63   0.567   0.6615
Vinh   1.17   1.053   1.2285
[Temperature Range]   25   125   -40
[Voltage Range]   1.8   1.62   1.89
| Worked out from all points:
|   GND clamp passes 1 mA (typ) near -0.86 V on its own axis
|   POWER clamp passes 1 mA (typ) near -0.86 V on its own axis
[POWER_clamp]
-1.8V     125.1mA    90.63mA    173.4mA
-1.145V   25.33mA    17.15mA    36.56mA
-1.109V   20.65mA    13.94mA    29.86mA
-1.073V   16.2mA     10.94mA    23.42mA
-1.036V   11.97mA    8.145mA    17.24mA
-1V       8.45mA     5.899mA    11.94mA
-963.6mV  5.452mA    3.992mA    7.408mA
-927.3mV  2.975mA    2.424mA    3.634mA
-854.5mV  779.1uA    853.1uA    686.6uA
-818.2mV  292.8uA    424.3uA    183.6uA
-600mV    1.304uA    7.605uA    175.4nA
1.764V    -20.05pA   -586.2pA   -149.6pA
[GND_clamp]
-1.8V     -189.8mA   -126.1mA   -302.4mA
-1.145V   -30.27mA   -18.93mA   -52.04mA
-1.109V   -23.46mA   -14.72mA   -40.7mA
-1.073V   -17.31mA   -10.94mA   -30.35mA
-1.036V   -11.81mA   -7.596mA   -20.99mA
-1V       -7.972mA   -5.278mA   -14.21mA
-963.6mV  -4.92mA    -3.43mA    -8.677mA
-927.3mV  -2.657mA   -2.051mA   -4.393mA
-854.5mV  -808.7uA   -794.4uA   -965uA
-818.2mV  -350.6uA   -438.9uA   -248.4uA
-600mV    -612.5nA   -5.16uA    -65.45nA
1.764V    15.58pA    1.6nA      229pA
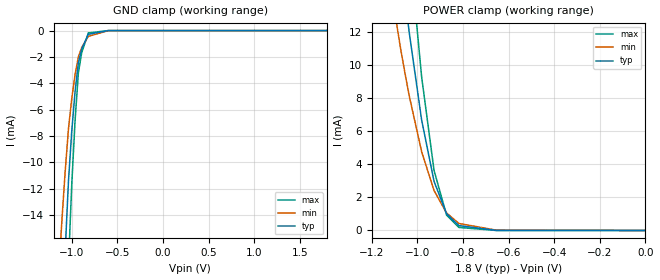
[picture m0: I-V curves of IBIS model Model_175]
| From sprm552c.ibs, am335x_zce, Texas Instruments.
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| Model based on original model for IHHV1833DVHYP18LL_SSDHH
|   Sub model IHHV_NORAML_10P_1P8
[model]   Model_175
|[Description]  [1.8V-INPUT-NORMAL-X, IND, 10%]
|   NORMAL,Industrial temperature range (-40C to 125C, 25C
|   nominal),10% power supply tolerance
|[Input Load]   NORMAL
|[Output Drive]
|Voltage   1.8V
|Mode   INPUT
Model_type   Input
Polarity   Non-Inverting
Vinl =  0.45
Vinh =  1.35
C_comp   0.8445658p   0.7268351p   0.9672201p
[Model Spec]
Vinl   0.45   0.45   0.45
Vinh   1.35   1.35   1.35
[Temperature Range]   25   125   -40
[Voltage Range]   1.8   1.62   1.98
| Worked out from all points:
|   GND clamp passes 1 mA (typ) near -0.87 V on its own axis
|   POWER clamp passes 1 mA (typ) near -0.87 V on its own axis
[POWER_clamp]
-1.8V     125.2mA    90.57mA    173.6mA
-1.127V   23mA       15.53mA    33.25mA
-1.073V   16.2mA     10.93mA    23.45mA
-1.055V   14.09mA    9.536mA    20.36mA
-1.036V   11.97mA    8.138mA    17.26mA
-1.018V   10.21mA    7.016mA    14.61mA
-981.8mV  6.693mA    4.772mA    9.305mA
-927.3mV  2.976mA    2.421mA    3.638mA
-872.7mV  1.022mA    1.067mA    939uA
-818.2mV  292.9uA    424.1uA    183.7uA
-654.5mV  5.109uA    21.1uA     1.004uA
0V        63.92pA    161.8pA    246pA
[GND_clamp]
-1.8V     -188.2mA   -124.9mA   -283.5mA
-1.145V   -29.69mA   -18.67mA   -46.57mA
-1.109V   -22.95mA   -14.5mA    -35.97mA
-1.073V   -16.85mA   -10.76mA   -26.36mA
-1.036V   -11.41mA   -7.446mA   -17.74mA
-1V       -7.622mA   -5.159mA   -11.67mA
-963.6mV  -4.626mA   -3.338mA   -6.817mA
-927.3mV  -2.419mA   -1.986mA   -3.194mA
-890.9mV  -1.398mA   -1.289mA   -1.668mA
-818.2mV  -282uA     -434uA     -178.9uA
-600mV    -574.5nA   -6.687uA   -68.67nA
1.8V      0A         0A         0A
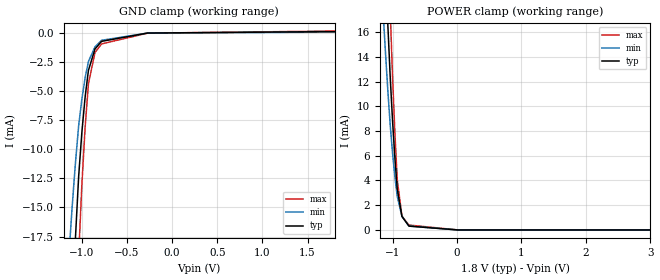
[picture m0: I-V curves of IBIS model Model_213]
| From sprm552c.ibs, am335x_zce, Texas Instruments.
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| Model based on original model for IC1833DVPBFBP18LL_SSDHH
|   Sub model IC_SSDHH_PD_ON_5P_1P8
[model]   Model_213
|[Description]  [1.8V-INPUT-PD-X, IND, 5%]
|   Weak internal pull-down,Industrial temperature range (-40C to
|   125C, 25C nominal),5% power supply tolerance
|[Input Load]   PD
|[Output Drive]
|Voltage   1.8V
|Mode   INPUT
Model_type   Input
Polarity   Non-Inverting
Vinl =  0.63
Vinh =  1.17
C_comp   1.250844p   1.183731p   2.048667p
[Model Spec]
Vinl   0.63   0.5985   0.6615
Vinh   1.17   1.1115   1.2285
[Temperature Range]   25   125   -40
[Voltage Range]   1.8   1.71   1.89
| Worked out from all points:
|   GND clamp passes 1 mA (typ) near -0.82 V on its own axis
|   POWER clamp passes 1 mA (typ) near -0.85 V on its own axis
[POWER_clamp]
-1.8V     125.7mA    90.97mA    174.4mA
-1.145V   25.72mA    17.46mA    37.04mA
-1.109V   21.03mA    14.25mA    30.33mA
-1.073V   16.56mA    11.25mA    23.87mA
-1.036V   12.33mA    8.449mA    17.68mA
-1V       8.806mA    6.198mA    12.37mA
-963.6mV  5.802mA    4.285mA    7.833mA
-927.3mV  3.318mA    2.708mA    4.06mA
-854.5mV  1.094mA    1.108mA    1.114mA
-745.5mV  311.8uA    313uA      396.1uA
18.18mV   0A         0A         0A
3.6V      0A         0A         0A
[GND_clamp]
-1.8V     -190.4mA   -126mA     -287.8mA
-1.145V   -30.84mA   -19.3mA    -48.44mA
-1.109V   -24.03mA   -15.1mA    -37.71mA
-1.073V   -17.88mA   -11.34mA   -27.96mA
-1.036V   -12.38mA   -8.004mA   -19.21mA
-1V       -8.538mA   -5.691mA   -13.03mA
-963.6mV  -5.487mA   -3.847mA   -8.079mA
-927.3mV  -3.226mA   -2.469mA   -4.369mA
-854.5mV  -1.391mA   -1.204mA   -1.695mA
-781.8mV  -738.1uA   -646.1uA   -955.4uA
-272.7mV  -23.59uA   -23.39uA   -31.84uA
1.8V      101.9uA    58.9uA     150.8uA
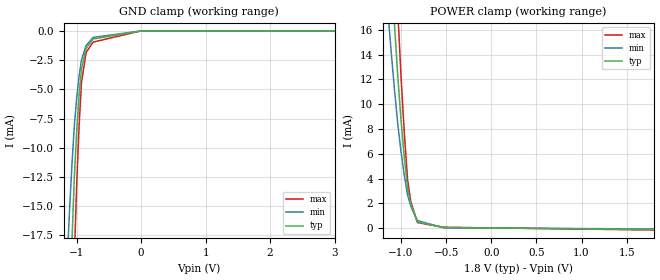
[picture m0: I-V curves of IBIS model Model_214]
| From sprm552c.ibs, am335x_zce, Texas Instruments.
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| Model based on original model for IC1833DVPBFBP18LL_SSDHH
|   Sub model IC_SSDHH_PU_ON_5P_1P8
[model]   Model_214
|[Description]  [1.8V-INPUT-PU-X, IND, 5%]
|   Weak internal pull-up,Industrial temperature range (-40C to
|   125C, 25C nominal),5% power supply tolerance
|[Input Load]   PU
|[Output Drive]
|Voltage   1.8V
|Mode   INPUT
Model_type   Input
Polarity   Non-Inverting
Vinl =  0.63
Vinh =  1.17
C_comp   1.250844p   1.183731p   2.048667p
[Model Spec]
Vinl   0.63   0.5985   0.6615
Vinh   1.17   1.1115   1.2285
[Temperature Range]   25   125   -40
[Voltage Range]   1.8   1.71   1.89
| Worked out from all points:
|   GND clamp passes 1 mA (typ) near -0.81 V on its own axis
|   POWER clamp passes 1 mA (typ) near -0.85 V on its own axis
[POWER_clamp]
-1.8V     125.7mA    90.96mA    174.2mA
-1.145V   25.64mA    17.42mA    36.91mA
-1.109V   20.95mA    14.21mA    30.19mA
-1.073V   16.49mA    11.21mA    23.74mA
-1.036V   12.25mA    8.409mA    17.54mA
-1V       8.723mA    6.157mA    12.23mA
-963.6mV  5.718mA    4.243mA    7.691mA
-927.3mV  3.233mA    2.665mA    3.917mA
-890.9mV  1.918mA    1.747mA    2.123mA
-818.2mV  500.5uA    614.2uA    455.8uA
-527.3mV  56.69uA    34.2uA     79.4uA
1.8V      -99.93uA   -59.09uA   -145.1uA
[GND_clamp]
-1.8V     -190.4mA   -126mA     -287.8mA
-1.145V   -30.86mA   -19.32mA   -48.48mA
-1.109V   -24.06mA   -15.12mA   -37.76mA
-1.073V   -17.91mA   -11.35mA   -28.03mA
-1.036V   -12.42mA   -8.023mA   -19.29mA
-1V       -8.587mA   -5.714mA   -13.12mA
-963.6mV  -5.546mA   -3.872mA   -8.191mA
-927.3mV  -3.294mA   -2.499mA   -4.493mA
-854.5mV  -1.472mA   -1.243mA   -1.83mA
-745.5mV  -677.6uA   -541.6uA   -947.1uA
-18.18mV  0A         0A         0A
3.6V      0A         0A         0A
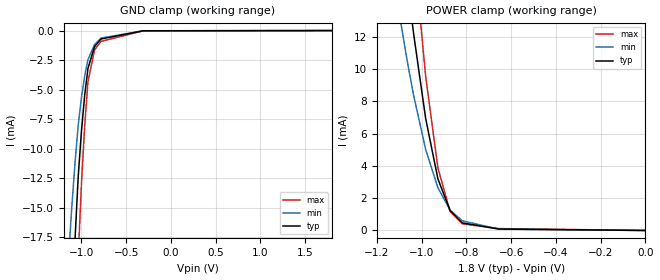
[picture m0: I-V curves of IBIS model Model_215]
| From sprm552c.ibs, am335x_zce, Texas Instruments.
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| Model based on original model for IC1833DVPBFBP18LL_SSDHH
|   Sub model IC_SSDHH_PUPDOFF_5P_1P8
[model]   Model_215
|[Description]  [1.8V-INPUT-PI-X, IND, 5%]
|   Weak pull up/down disabled,Industrial temperature range (-40C to
|   125C, 25C nominal),5% power supply tolerance
|[Input Load]   PI
|[Output Drive]
|Voltage   1.8V
|Mode   INPUT
Model_type   Input
Polarity   Non-Inverting
Vinl =  0.63
Vinh =  1.17
C_comp   1.250844p   1.183731p   2.048667p
[Model Spec]
Vinl   0.63   0.5985   0.6615
Vinh   1.17   1.1115   1.2285
[Temperature Range]   25   125   -40
[Voltage Range]   1.8   1.71   1.89
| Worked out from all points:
|   GND clamp passes 1 mA (typ) near -0.82 V on its own axis
|   POWER clamp passes 1 mA (typ) near -0.86 V on its own axis
[POWER_clamp]
-1.8V     125.7mA    90.95mA    174.2mA
-1.127V   23.26mA    15.8mA     33.5mA
-1.073V   16.45mA    11.19mA    23.69mA
-1.055V   14.33mA    9.791mA    20.59mA
-1.036V   12.22mA    8.39mA     17.49mA
-1.018V   10.45mA    7.264mA    14.84mA
-981.8mV  6.927mA    5.013mA    9.531mA
-927.3mV  3.2mA      2.646mA    3.87mA
-872.7mV  1.228mA    1.269mA    1.179mA
-818.2mV  468.6uA    595.5uA    410.6uA
-654.5mV  88.61uA    84.55uA    117.3uA
0V        18.96nA    131.4nA    228.5nA
[GND_clamp]
-1.8V     -190.4mA   -126mA     -287.8mA
-1.145V   -30.83mA   -19.3mA    -48.43mA
-1.109V   -24.03mA   -15.1mA    -37.7mA
-1.073V   -17.88mA   -11.33mA   -27.96mA
-1.036V   -12.37mA   -8mA       -19.2mA
-1V       -8.53mA    -5.688mA   -13.02mA
-963.6mV  -5.478mA   -3.842mA   -8.065mA
-927.3mV  -3.215mA   -2.464mA   -4.35mA
-854.5mV  -1.373mA   -1.197mA   -1.663mA
-781.8mV  -712.8uA   -635.6uA   -916.4uA
-309.1mV  -16.02uA   -21.61uA   -20.28uA
1.8V      18.96nA    136.3nA    214.7nA
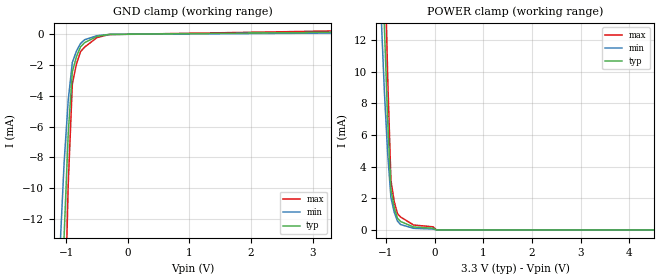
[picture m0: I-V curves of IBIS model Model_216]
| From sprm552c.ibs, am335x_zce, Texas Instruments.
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| Model based on original model for IC1833DVPBFBP18LL_SSDHH
|   Sub model IC_SSDHH_PD_ON_5P_3P3
[model]   Model_216
|[Description]  [3.3V-INPUT-PD-X, IND, 5%]
|   Weak internal pull-down,Industrial temperature range (-40C to
|   125C, 25C nominal),5% power supply tolerance
|[Input Load]   PD
|[Output Drive]
|Voltage   3.3V
|Mode   INPUT
Model_type   Input
Polarity   Non-Inverting
Vinl =  0.8V
Vinh =  2V
C_comp   1.052412p   0.9366192p   1.577996p
[Model Spec]
Vinl   0.8V   0.8V   0.8V
Vinh   2V   2V   2V
[Temperature Range]   25   125   -40
[Voltage Range]   3.3   3.135   3.465
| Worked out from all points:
|   GND clamp passes 1 mA (typ) near -0.78 V on its own axis
|   POWER clamp passes 1 mA (typ) near -0.79 V on its own axis
[POWER_clamp]
-3.3V     372.1mA    388.5mA    506.4mA
-1.1V     20.16mA    13.51mA    29.25mA
-1.033V   12.76mA    8.646mA    18.37mA
-966.7mV  6.895mA    4.827mA    9.669mA
-900mV    2.56mA     2.052mA    3.141mA
-833.3mV  1.424mA    1.136mA    1.812mA
-766.7mV  748.5uA    565.5uA    1.037mA
-700mV    533.2uA    340.6uA    815.6uA
-433.3mV  187.1uA    103.9uA    311uA
-33.33mV  112.3uA    59.37uA    198.3uA
33.33mV   0A         0A         0A
6.6V      0A         0A         0A
[GND_clamp]
-3.3V     -586.6mA   -522.8mA   -870.9mA
-1.1V     -22.4mA    -13.98mA   -35.23mA
-1.033V   -13.11mA   -8.346mA   -20.44mA
-966.7mV  -6.47mA    -4.303mA   -9.782mA
-900mV    -2.469mA   -1.848mA   -3.248mA
-833.3mV  -1.471mA   -1.107mA   -1.946mA
-766.7mV  -835.1uA   -615uA     -1.146mA
-700mV    -559.4uA   -372.1uA   -849uA
-500mV    -155.1uA   -110.7uA   -231.3uA
-300mV    -27.67uA   -27.56uA   -37.82uA
3.3V      112uA      60.1uA     195.2uA
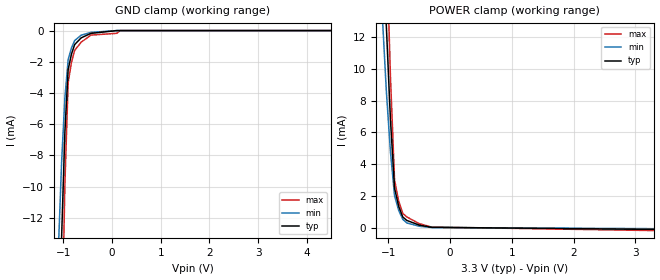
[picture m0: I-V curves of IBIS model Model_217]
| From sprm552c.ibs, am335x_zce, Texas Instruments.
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| Model based on original model for IC1833DVPBFBP18LL_SSDHH
|   Sub model IC_SSDHH_PU_ON_5P_3P3
[model]   Model_217
|[Description]  [3.3V-INPUT-PU-X, IND, 5%]
|   Weak internal pull-up,Industrial temperature range (-40C to
|   125C, 25C nominal),5% power supply tolerance
|[Input Load]   PU
|[Output Drive]
|Voltage   3.3V
|Mode   INPUT
Model_type   Input
Polarity   Non-Inverting
Vinl =  0.8V
Vinh =  2V
C_comp   1.052412p   0.9366192p   1.577996p
[Model Spec]
Vinl   0.8V   0.8V   0.8V
Vinh   2V   2V   2V
[Temperature Range]   25   125   -40
[Voltage Range]   3.3   3.135   3.465
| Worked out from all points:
|   GND clamp passes 1 mA (typ) near -0.78 V on its own axis
|   POWER clamp passes 1 mA (typ) near -0.80 V on its own axis
[POWER_clamp]
-3.3V     372.1mA    388.5mA    506.4mA
-1.1V     20.11mA    13.48mA    29.15mA
-1.033V   12.71mA    8.621mA    18.26mA
-966.7mV  6.838mA    4.8mA      9.554mA
-900mV    2.5mA      2.023mA    3.021mA
-833.3mV  1.36mA     1.105mA    1.687mA
-766.7mV  681.5uA    532uA      906.8uA
-700mV    462.9uA    305.1uA    681uA
-500mV    169.7uA    98.28uA    261.5uA
-300mV    30.53uA    17.74uA    45.58uA
3.3V      -101uA     -54.6uA    -174.5uA
[GND_clamp]
-3.3V     -586.6mA   -522.8mA   -870.9mA
-1.1V     -22.41mA   -13.98mA   -35.26mA
-1.033V   -13.13mA   -8.354mA   -20.49mA
-966.7mV  -6.497mA   -4.313mA   -9.856mA
-900mV    -2.509mA   -1.862mA   -3.351mA
-833.3mV  -1.525mA   -1.128mA   -2.06mA
-766.7mV  -897uA     -641.7uA   -1.269mA
-633.3mV  -467.6uA   -296.5uA   -745.8uA
-433.3mV  -179.4uA   -116.4uA   -289.6uA
100mV     0A         0A         -175uA
166.7mV   0A         0A         0A
6.6V      0A         0A         0A
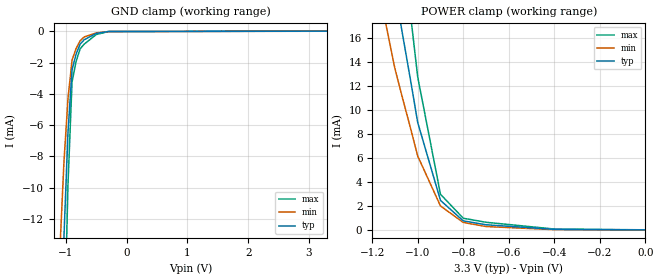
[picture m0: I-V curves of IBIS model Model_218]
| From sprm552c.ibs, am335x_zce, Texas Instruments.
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| Model based on original model for IC1833DVPBFBP18LL_SSDHH
|   Sub model IC_SSDHH_PUPDOFF_5P_3P3
[model]   Model_218
|[Description]  [3.3V-INPUT-PI-X, IND, 5%]
|   Weak pull up/down disabled,Industrial temperature range (-40C to
|   125C, 25C nominal),5% power supply tolerance
|[Input Load]   PI
|[Output Drive]
|Voltage   3.3V
|Mode   INPUT
Model_type   Input
Polarity   Non-Inverting
Vinl =  0.8V
Vinh =  2V
C_comp   1.052412p   0.9366192p   1.577996p
[Model Spec]
Vinl   0.8V   0.8V   0.8V
Vinh   2V   2V   2V
[Temperature Range]   25   125   -40
[Voltage Range]   3.3   3.135   3.465
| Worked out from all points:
|   GND clamp passes 1 mA (typ) near -0.79 V on its own axis
|   POWER clamp passes 1 mA (typ) near -0.81 V on its own axis
[POWER_clamp]
-3.3V     372.1mA    388.5mA    506.4mA
-1.167V   28.96mA    19.64mA    41.7mA
-1.133V   24.52mA    16.56mA    35.4mA
-1.1V     20.08mA    13.47mA    29.11mA
-1.067V   16.38mA    11.04mA    23.67mA
-1.033V   12.68mA    8.608mA    18.23mA
-1V       8.981mA    6.175mA    12.78mA
-900mV    2.474mA    2.009mA    2.985mA
-800mV    765.7uA    631.1uA    983.9uA
-700mV    438.8uA    291uA      646.6uA
-400mV    52.67uA    31.16uA    79.92uA
0V        7.989uA    3.726uA    15.44uA
[GND_clamp]
-3.3V     -586.6mA   -522.8mA   -870.9mA
-1.1V     -22.39mA   -13.98mA   -35.23mA
-1.033V   -13.11mA   -8.344mA   -20.44mA
-966.7mV  -6.465mA   -4.3mA     -9.774mA
-900mV    -2.462mA   -1.845mA   -3.237mA
-833.3mV  -1.46mA    -1.102mA   -1.926mA
-766.7mV  -819.1uA   -608.5uA   -1.122mA
-700mV    -540.3uA   -363.2uA   -823.3uA
-500mV    -135.4uA   -99.48uA   -204.6uA
-300mV    -13.18uA   -19.03uA   -17.22uA
3.3V      7.989uA    4.608uA    13.54uA
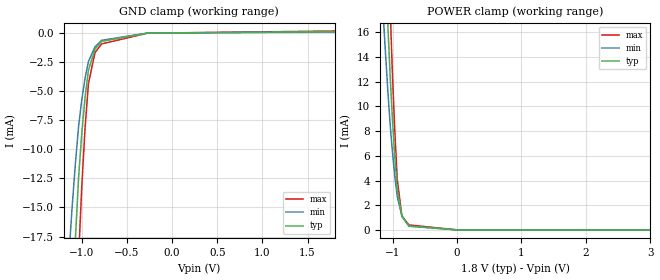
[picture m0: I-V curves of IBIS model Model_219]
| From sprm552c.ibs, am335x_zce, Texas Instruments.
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| Model based on original model for IC1833DVPBFBP18LL_SSDHH
|   Sub model IC_SSDHH_PD_ON_10P_1P8
[model]   Model_219
|[Description]  [1.8V-INPUT-PD-X, IND, 10%]
|   Weak internal pull-down,Industrial temperature range (-40C to
|   125C, 25C nominal),10% power supply tolerance
|[Input Load]   PD
|[Output Drive]
|Voltage   1.8V
|Mode   INPUT
Model_type   Input
Polarity   Non-Inverting
Vinl =  0.63
Vinh =  1.17
C_comp   1.250844p   1.18576p   1.277785p
[Model Spec]
Vinl   0.63   0.567   0.693
Vinh   1.17   1.053   1.287
[Temperature Range]   25   125   -40
[Voltage Range]   1.8   1.62   1.98
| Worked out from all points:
|   GND clamp passes 1 mA (typ) near -0.82 V on its own axis
|   POWER clamp passes 1 mA (typ) near -0.85 V on its own axis
[POWER_clamp]
-1.8V     125.7mA    90.96mA    174.4mA
-1.145V   25.72mA    17.45mA    37.06mA
-1.109V   21.03mA    14.24mA    30.34mA
-1.073V   16.56mA    11.24mA    23.88mA
-1.036V   12.33mA    8.44mA     17.69mA
-1V       8.806mA    6.19mA     12.38mA
-963.6mV  5.802mA    4.277mA    7.843mA
-927.3mV  3.318mA    2.701mA    4.071mA
-854.5mV  1.094mA    1.101mA    1.125mA
-745.5mV  311.8uA    306.6uA    406.4uA
18.18mV   0A         0A         0A
3.6V      0A         0A         0A
[GND_clamp]
-1.8V     -190.4mA   -126mA     -287.8mA
-1.145V   -30.84mA   -19.3mA    -48.44mA
-1.109V   -24.03mA   -15.1mA    -37.71mA
-1.073V   -17.88mA   -11.34mA   -27.96mA
-1.036V   -12.38mA   -8.003mA   -19.21mA
-1V       -8.538mA   -5.691mA   -13.03mA
-963.6mV  -5.487mA   -3.846mA   -8.08mA
-927.3mV  -3.226mA   -2.469mA   -4.369mA
-854.5mV  -1.391mA   -1.203mA   -1.695mA
-781.8mV  -738.1uA   -645.6uA   -956uA
-272.7mV  -23.59uA   -23.25uA   -31.96uA
1.8V      101.9uA    56.86uA    152.6uA
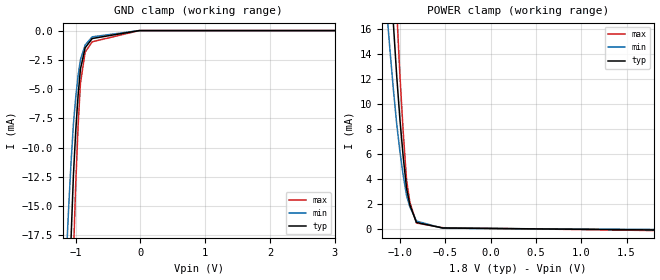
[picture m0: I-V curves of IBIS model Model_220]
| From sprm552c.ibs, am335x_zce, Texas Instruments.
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| Model based on original model for IC1833DVPBFBP18LL_SSDHH
|   Sub model IC_SSDHH_PU_ON_10P_1P8
[model]   Model_220
|[Description]  [1.8V-INPUT-PU-X, IND, 10%]
|   Weak internal pull-up,Industrial temperature range (-40C to
|   125C, 25C nominal),10% power supply tolerance
|[Input Load]   PU
|[Output Drive]
|Voltage   1.8V
|Mode   INPUT
Model_type   Input
Polarity   Non-Inverting
Vinl =  0.63
Vinh =  1.17
C_comp   1.250844p   1.18576p   1.277785p
[Model Spec]
Vinl   0.63   0.567   0.693
Vinh   1.17   1.053   1.287
[Temperature Range]   25   125   -40
[Voltage Range]   1.8   1.62   1.98
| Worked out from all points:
|   GND clamp passes 1 mA (typ) near -0.81 V on its own axis
|   POWER clamp passes 1 mA (typ) near -0.85 V on its own axis
[POWER_clamp]
-1.8V     125.7mA    90.96mA    174.2mA
-1.145V   25.64mA    17.42mA    36.91mA
-1.109V   20.95mA    14.21mA    30.19mA
-1.073V   16.49mA    11.21mA    23.74mA
-1.036V   12.25mA    8.408mA    17.54mA
-1V       8.723mA    6.156mA    12.23mA
-963.6mV  5.718mA    4.241mA    7.691mA
-927.3mV  3.233mA    2.664mA    3.917mA
-890.9mV  1.918mA    1.746mA    2.123mA
-818.2mV  500.5uA    613.3uA    456.2uA
-527.3mV  56.69uA    33.96uA    79.77uA
1.8V      -99.93uA   -59.41uA   -146.8uA
[GND_clamp]
-1.8V     -190.4mA   -126mA     -287.8mA
-1.145V   -30.86mA   -19.31mA   -48.49mA
-1.109V   -24.06mA   -15.12mA   -37.77mA
-1.073V   -17.91mA   -11.35mA   -28.04mA
-1.036V   -12.42mA   -8.019mA   -19.3mA
-1V       -8.587mA   -5.71mA    -13.14mA
-963.6mV  -5.546mA   -3.868mA   -8.202mA
-927.3mV  -3.294mA   -2.494mA   -4.504mA
-854.5mV  -1.472mA   -1.237mA   -1.841mA
-745.5mV  -677.6uA   -535.9uA   -957.4uA
-18.18mV  0A         0A         0A
3.6V      0A         0A         0A
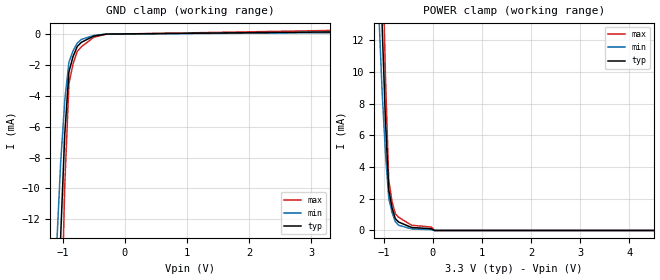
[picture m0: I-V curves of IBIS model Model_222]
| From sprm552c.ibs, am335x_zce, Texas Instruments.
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| Model based on original model for IC1833DVPBFBP18LL_SSDHH
|   Sub model IC_SSDHH_PD_ON_10P_3P3
[model]   Model_222
|[Description]  [3.3V-INPUT-PD-X, IND, 10%]
|   Weak internal pull-down,Industrial temperature range (-40C to
|   125C, 25C nominal),10% power supply tolerance
|[Input Load]   PD
|[Output Drive]
|Voltage   3.3V
|Mode   INPUT
Model_type   Input
Polarity   Non-Inverting
Vinl =  0.8V
Vinh =  2V
C_comp   1.052412p   0.9359002p   1.145133p
[Model Spec]
Vinl   0.8V   0.8V   0.8V
Vinh   2V   2V   2V
[Temperature Range]   25   125   -40
[Voltage Range]   3.3   2.97   3.63
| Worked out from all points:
|   GND clamp passes 1 mA (typ) near -0.78 V on its own axis
|   POWER clamp passes 1 mA (typ) near -0.79 V on its own axis
[POWER_clamp]
-3.3V     372.1mA    370.8mA    506.4mA
-1.1V     20.16mA    13.5mA     29.28mA
-1.033V   12.76mA    8.638mA    18.39mA
-966.7mV  6.895mA    4.819mA    9.689mA
-900mV    2.56mA     2.044mA    3.162mA
-833.3mV  1.424mA    1.128mA    1.832mA
-766.7mV  748.5uA    557.5uA    1.057mA
-700mV    533.2uA    332.6uA    835.6uA
-433.3mV  187.1uA    96.78uA    330uA
-33.33mV  112.3uA    52.27uA    217.2uA
33.33mV   0A         0A         0A
6.6V      0A         0A         0A
[GND_clamp]
-3.3V     -586.6mA   -502.8mA   -870.9mA
-1.1V     -22.4mA    -13.98mA   -35.24mA
-1.033V   -13.11mA   -8.345mA   -20.45mA
-966.7mV  -6.47mA    -4.302mA   -9.784mA
-900mV    -2.469mA   -1.847mA   -3.25mA
-833.3mV  -1.471mA   -1.106mA   -1.947mA
-766.7mV  -835.1uA   -614.6uA   -1.147mA
-700mV    -559.4uA   -371.7uA   -849.8uA
-500mV    -155.1uA   -110.3uA   -231.8uA
-300mV    -27.67uA   -27.36uA   -38.44uA
3.3V      112uA      61.24uA    206.8uA
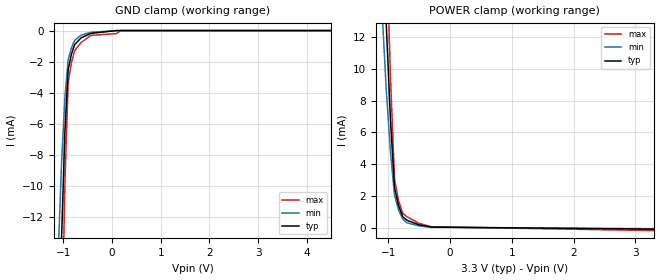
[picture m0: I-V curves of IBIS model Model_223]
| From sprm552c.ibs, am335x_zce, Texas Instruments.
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| Model based on original model for IC1833DVPBFBP18LL_SSDHH
|   Sub model IC_SSDHH_PU_ON_10P_3P3
[model]   Model_223
|[Description]  [3.3V-INPUT-PU-X, IND, 10%]
|   Weak internal pull-up,Industrial temperature range (-40C to
|   125C, 25C nominal),10% power supply tolerance
|[Input Load]   PU
|[Output Drive]
|Voltage   3.3V
|Mode   INPUT
Model_type   Input
Polarity   Non-Inverting
Vinl =  0.8V
Vinh =  2V
C_comp   1.052412p   0.9359002p   1.145133p
[Model Spec]
Vinl   0.8V   0.8V   0.8V
Vinh   2V   2V   2V
[Temperature Range]   25   125   -40
[Voltage Range]   3.3   2.97   3.63
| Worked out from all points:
|   GND clamp passes 1 mA (typ) near -0.78 V on its own axis
|   POWER clamp passes 1 mA (typ) near -0.80 V on its own axis
[POWER_clamp]
-3.3V     372.1mA    370.8mA    506.4mA
-1.1V     20.11mA    13.48mA    29.15mA
-1.033V   12.71mA    8.619mA    18.27mA
-966.7mV  6.838mA    4.798mA    9.558mA
-900mV    2.5mA      2.021mA    3.025mA
-833.3mV  1.36mA     1.103mA    1.691mA
-766.7mV  681.5uA    530.2uA    910.3uA
-700mV    462.9uA    303.4uA    684.4uA
-500mV    169.7uA    97.37uA    264.1uA
-300mV    30.53uA    16.96uA    48.13uA
3.3V      -101uA     -72.06uA   -190.1uA
[GND_clamp]
-3.3V     -586.6mA   -502.8mA   -870.9mA
-1.1V     -22.41mA   -13.98mA   -35.27mA
-1.033V   -13.13mA   -8.351mA   -20.51mA
-966.7mV  -6.497mA   -4.309mA   -9.876mA
-900mV    -2.509mA   -1.858mA   -3.371mA
-833.3mV  -1.525mA   -1.122mA   -2.08mA
-766.7mV  -897uA     -635uA     -1.289mA
-633.3mV  -467.6uA   -289.5uA   -764.7uA
-433.3mV  -179.4uA   -109.4uA   -308.5uA
100mV     0A         0A         -193.2uA
166.7mV   0A         0A         0A
6.6V      0A         0A         0A
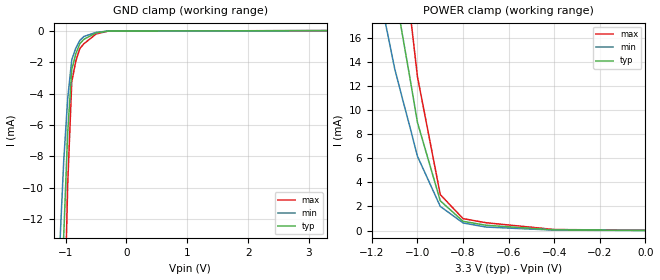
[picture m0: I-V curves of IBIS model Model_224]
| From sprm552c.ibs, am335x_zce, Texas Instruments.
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| Model based on original model for IC1833DVPBFBP18LL_SSDHH
|   Sub model IC_SSDHH_PUPDOFF_10P_3P3
[model]   Model_224
|[Description]  [3.3V-INPUT-PI-X, IND, 10%]
|   Weak pull up/down disabled,Industrial temperature range (-40C to
|   125C, 25C nominal),10% power supply tolerance
|[Input Load]   PI
|[Output Drive]
|Voltage   3.3V
|Mode   INPUT
Model_type   Input
Polarity   Non-Inverting
Vinl =  0.8V
Vinh =  2V
C_comp   1.052412p   0.9359002p   1.145133p
[Model Spec]
Vinl   0.8V   0.8V   0.8V
Vinh   2V   2V   2V
[Temperature Range]   25   125   -40
[Voltage Range]   3.3   2.97   3.63
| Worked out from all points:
|   GND clamp passes 1 mA (typ) near -0.79 V on its own axis
|   POWER clamp passes 1 mA (typ) near -0.81 V on its own axis
[POWER_clamp]
-3.3V     372.1mA    370.8mA    506.4mA
-1.167V   28.96mA    19.64mA    41.7mA
-1.133V   24.52mA    16.56mA    35.41mA
-1.1V     20.08mA    13.47mA    29.12mA
-1.067V   16.38mA    11.04mA    23.67mA
-1.033V   12.68mA    8.606mA    18.23mA
-1V       8.981mA    6.173mA    12.79mA
-900mV    2.474mA    2.007mA    2.988mA
-800mV    765.7uA    629.6uA    987.1uA
-700mV    438.8uA    289.6uA    649.6uA
-400mV    52.67uA    30.55uA    82.05uA
0V        7.989uA    3.113uA    17.77uA
[GND_clamp]
-3.3V     -586.6mA   -502.8mA   -870.9mA
-1.1V     -22.39mA   -13.97mA   -35.23mA
-1.033V   -13.11mA   -8.343mA   -20.44mA
-966.7mV  -6.465mA   -4.3mA     -9.776mA
-900mV    -2.462mA   -1.844mA   -3.238mA
-833.3mV  -1.46mA    -1.102mA   -1.928mA
-766.7mV  -819.1uA   -608.2uA   -1.123mA
-700mV    -540.3uA   -363uA     -823.8uA
-500mV    -135.4uA   -99.24uA   -205uA
-300mV    -13.18uA   -18.93uA   -17.74uA
3.3V      7.989uA    12.38uA    13.97uA
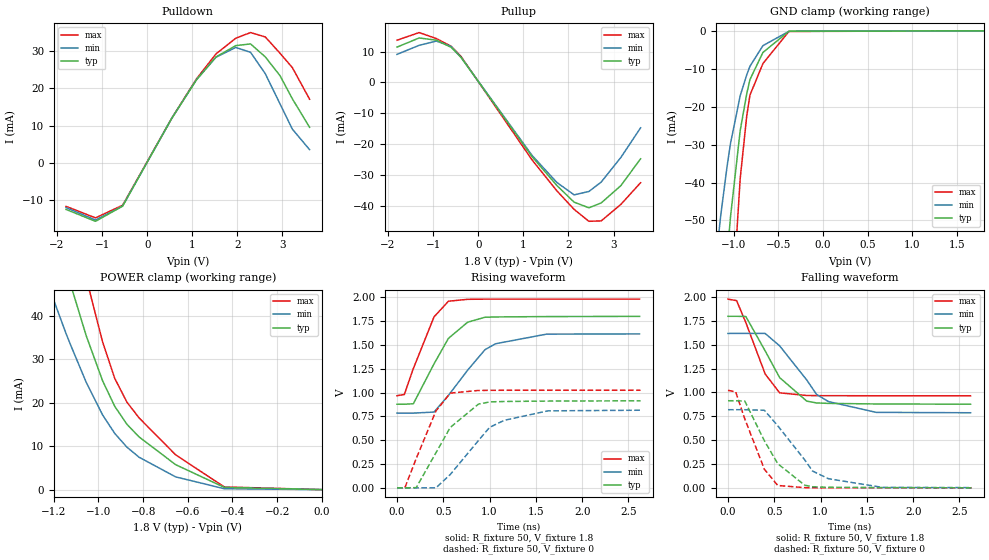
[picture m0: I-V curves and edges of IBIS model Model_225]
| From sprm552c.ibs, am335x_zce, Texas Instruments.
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| Model based on original model for BCSHTLTCSCDVPBFZ_SSDHV
|   Sub model SR11_8MA_10PER_1P8
[model]   Model_225
|[Description]  [1.8V-3-STATE-NOTERM-SR11:8MA, IND, 10%]
|   Slowest slew rate (SR[1:0] = "11"), 1.00 * RExt = 1.000 * Iout
|   (I[2:0] = "011"), 8mA nominal with Rext = 50R,ODT off (ODT[1:0]
|   = "00") CMOS mode,Industrial temperature range (-40C to 125C,
|   25C nominal),10% power supply tolerance
|[Input Load]   NOTERM
|[Output Drive] SR11:8MA
|Voltage   1.8V
|Mode   3-STATE
Model_type   3-state
Polarity   Non-Inverting
Enable   Active-Low
Cref =  15pF
Rref =  100.0000M
Vref =  0V
Vmeas =  0.9
C_comp   1.851324p   1.663768p   1.973575p
[Temperature Range]   25   125   -40
[Voltage Range]   1.8   1.62   1.98
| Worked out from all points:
|   slope of the pulldown table from 0 to 0.27 V, typ, clamps not added: 44.4 ohm
|   slope of the pullup table from 0 to 0.27 V, typ, clamps not added: 47 ohm
|   GND clamp passes 1 mA (typ) near -0.49 V on its own axis
|   POWER clamp passes 1 mA (typ) near -0.47 V on its own axis
|   rising waveform, R_fixture 50, V_fixture 1.8: 20-80 % time 320ps typ, 411ps min, 242ps max; typ from 0.877 V to 1.8 V
|   rising waveform, R_fixture 50, V_fixture 0: 20-80 % time 343ps typ, 419ps min, 259ps max; typ from 0 V to 0.913 V
|   falling waveform, R_fixture 50, V_fixture 1.8: 20-80 % time 337ps typ, 411ps min, 241ps max; typ from 1.8 V to 0.877 V
|   falling waveform, R_fixture 50, V_fixture 0: 20-80 % time 323ps typ, 397ps min, 238ps max; typ from 0.914 V to 0 V
[POWER_clamp]
-1.8V     194.9mA    137.1mA    262.8mA
-1.236V   68.49mA    48.51mA    92.67mA
-1.145V   50.76mA    35.86mA    69.65mA
-1.127V   47.56mA    33.54mA    65.34mA
-1.055V   35.4mA     24.69mA    48.69mA
-981.8mV  25.06mA    17.2mA     34.01mA
-927.3mV  19.17mA    12.93mA    25.61mA
-872.7mV  15.03mA    9.767mA    20.12mA
-818.2mV  12.12mA    7.45mA     16.5mA
-654.5mV  5.738mA    2.93mA     8.003mA
-436.4mV  508.2uA    199.4uA    613uA
0V        2.273nA    15.95nA    16.67nA
[Pulldown]
-1.8V     -12.51mA   -12.01mA   -11.68mA
-1.145V   -15.69mA   -15.35mA   -14.77mA
-545.5mV  -11.63mA   -11.6mA    -11.38mA
545.5mV   11.95mA    11.95mA    12mA
1.091V    22.23mA    22.28mA    22.49mA
1.527V    28.41mA    28.35mA    29.24mA
1.964V    31.44mA    30.94mA    33.42mA
2.291V    31.9mA     29.65mA    34.94mA
2.618V    28.42mA    23.91mA    33.77mA
2.945V    23.37mA    15.81mA    29.39mA
3.218V    17.19mA    9.044mA    25.55mA
3.6V      9.513mA    3.534mA    17.07mA
[Pullup]
-1.8V     11.43mA    9.077mA    13.67mA
-1.309V   14.4mA     12.01mA    16.15mA
-927.3mV  13.68mA    13.39mA    14.2mA
-600mV    11.36mA    11.67mA    11.72mA
-381.8mV  8.135mA    8.127mA    8.423mA
1.2V      -24.2mA    -23.8mA    -25.27mA
1.745V    -33.47mA   -32.48mA   -35.2mA
2.127V    -38.87mA   -36.49mA   -41.21mA
2.455V    -40.69mA   -35.39mA   -45.07mA
2.727V    -39.11mA   -32.35mA   -44.94mA
3.164V    -33.5mA    -24.34mA   -39.58mA
3.6V      -24.8mA    -14.75mA   -32.56mA
[GND_clamp]
-1.8V     -346.1mA   -209.3mA   -568.3mA
-1.327V   -149.7mA   -89.03mA   -250.9mA
-1.291V   -135.6mA   -80.47mA   -227.5mA
-1.145V   -82.35mA   -48.67mA   -137.7mA
-1.073V   -59.44mA   -35.55mA   -97.96mA
-1.036V   -49.1mA    -29.72mA   -79.9mA
-927.3mV  -26.31mA   -17.11mA   -38.99mA
-854.5mV  -16.67mA   -11.64mA   -22.56mA
-818.2mV  -12.86mA   -9.351mA   -16.98mA
-672.7mV  -5.705mA   -3.913mA   -8.624mA
-381.8mV  -120.4uA   -129uA     -167.4uA
1.8V      2.273nA    454nA      6.646nA
[Ramp]
dV/dt_f 0.55561205/0.33793227n 0.50361405/0.41285853n  0.6096418/0.24197304n
dV/dt_r 0.55057597/0.34548258n  0.4943015/0.42267756n 0.61576318/0.25968866n
R_load = 50
[Rising Waveform]
R_fixture = 50
V_fixture = 1.8
V_fixture_min = 1.62
V_fixture_max = 1.98
0s        877.3mV    784.2mV    966.6mV
79.1ps    877.3mV    784.2mV    979.6mV
176.6ps   882.1mV    784.2mV    1.253V
399.3ps   1.3V       795.2mV    1.793V
555.4ps   1.568V     969.3mV    1.958V
763.1ps   1.738V     1.235V     1.978V
950.9ps   1.79V      1.45V      1.98V
1.065ns   1.793V     1.512V     1.98V
1.617ns   1.797V     1.613V     1.98V
2.62ns    1.799V     1.615V     1.98V
[Rising Waveform]
R_fixture = 50
V_fixture = 0
V_fixture_min = 0
V_fixture_max = 0
0s        0V         0V         0V
84.2ps    0V         0V         0V
207.6ps   2.504mV    0V         307.6mV
420.6ps   367.7mV    0V         806.9mV
575.7ps   634.7mV    140.6mV    994mV
880ps     878.7mV    496.9mV    1.022V
1.001ns   901.9mV    635.7mV    1.023V
1.159ns   906.2mV    708.6mV    1.024V
1.63ns    910.4mV    807.9mV    1.024V
2.631ns   913.4mV    814.5mV    1.024V
[Falling Waveform]
R_fixture = 50
V_fixture = 1.8
V_fixture_min = 1.62
V_fixture_max = 1.98
0s        1.799V     1.619V     1.979V
93.2ps    1.799V     1.619V     1.963V
192.4ps   1.797V     1.619V     1.733V
401.5ps   1.436V     1.619V     1.194V
557.8ps   1.156V     1.489V     996.4mV
850.5ps   909.7mV    1.131V     968.5mV
956.7ps   890.3mV    979.6mV    967.1mV
1.085ns   885.8mV    904.7mV    966.6mV
1.601ns   879.7mV    791.6mV    965.7mV
2.62ns    877.2mV    787.5mV    965.6mV
[Falling Waveform]
R_fixture = 50
V_fixture = 0
V_fixture_min = 0
V_fixture_max = 0
0s        913.5mV    819.5mV    1.023V
82.9ps    913.5mV    819.5mV    1.006V
180.9ps   910.5mV    819.5mV    724.4mV
392.8ps   494.1mV    813.5mV    194.9mV
537.3ps   253.1mV    650.8mV    24.85mV
828.3ps   28.34mV    294.1mV    2.297mV
912.9ps   11.38mV    176.6mV    0V
1.084ns   6.509mV    96.09mV    0V
1.67ns    3.025mV    4.504mV    0V
2.631ns   0V         3.163mV    0V
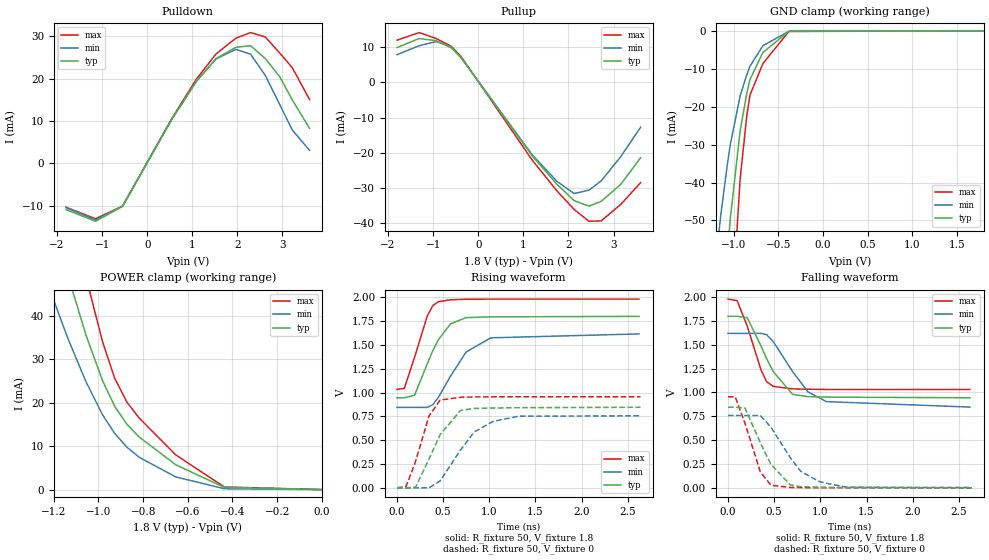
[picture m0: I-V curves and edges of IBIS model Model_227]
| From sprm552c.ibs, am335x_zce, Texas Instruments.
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| Model based on original model for BCSHTLTCSCDVPBFZ_SSDHV
|   Sub model SR10_7MA_10PER_1P8
[model]   Model_227
|[Description]  [1.8V-3-STATE-NOTERM-SR10:7MA, IND, 10%]
|   Fast slew rate (SR[1:0] = "10"), 1.14 * RExt = 0.875 * Iout
|   (I[2:0] = "010"), 7mA nominal with Rext = 50R,ODT off (ODT[1:0]
|   = "00") CMOS mode,Industrial temperature range (-40C to 125C,
|   25C nominal),10% power supply tolerance
|[Input Load]   NOTERM
|[Output Drive] SR10:7MA
|Voltage   1.8V
|Mode   3-STATE
Model_type   3-state
Polarity   Non-Inverting
Enable   Active-Low
Cref =  15pF
Rref =  100.0000M
Vref =  0V
Vmeas =  0.9
C_comp   1.851324p   1.663768p   1.973575p
[Temperature Range]   25   125   -40
[Voltage Range]   1.8   1.62   1.98
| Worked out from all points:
|   slope of the pulldown table from 0 to 0.27 V, typ, clamps not added: 51.1 ohm
|   slope of the pullup table from 0 to 0.27 V, typ, clamps not added: 54.4 ohm
|   GND clamp passes 1 mA (typ) near -0.49 V on its own axis
|   POWER clamp passes 1 mA (typ) near -0.47 V on its own axis
|   rising waveform, R_fixture 50, V_fixture 1.8: 20-80 % time 242ps typ, 306ps min, 177ps max; typ from 0.944 V to 1.8 V
|   rising waveform, R_fixture 50, V_fixture 0: 20-80 % time 257ps typ, 331ps min, 178ps max; typ from 0 V to 0.846 V
|   falling waveform, R_fixture 50, V_fixture 1.8: 20-80 % time 262ps typ, 332ps min, 189ps max; typ from 1.8 V to 0.944 V
|   falling waveform, R_fixture 50, V_fixture 0: 20-80 % time 258ps typ, 326ps min, 184ps max; typ from 0.846 V to 0 V
[POWER_clamp]
-1.8V     194.9mA    137.1mA    262.8mA
-1.236V   68.49mA    48.51mA    92.67mA
-1.145V   50.76mA    35.86mA    69.65mA
-1.127V   47.56mA    33.54mA    65.34mA
-1.055V   35.4mA     24.69mA    48.69mA
-981.8mV  25.06mA    17.2mA     34.01mA
-927.3mV  19.17mA    12.93mA    25.61mA
-872.7mV  15.03mA    9.767mA    20.12mA
-818.2mV  12.12mA    7.45mA     16.5mA
-654.5mV  5.738mA    2.93mA     8.003mA
-436.4mV  508.2uA    199.4uA    613uA
0V        2.273nA    15.95nA    16.67nA
[Pulldown]
-1.8V     -10.87mA   -10.42mA   -10.31mA
-1.145V   -13.64mA   -13.33mA   -13.03mA
-545.5mV  -10.12mA   -10.08mA   -10.04mA
545.5mV   10.39mA    10.38mA    10.59mA
1.091V    19.34mA    19.35mA    19.85mA
1.527V    24.71mA    24.62mA    25.8mA
1.964V    27.34mA    26.87mA    29.49mA
2.291V    27.74mA    25.74mA    30.83mA
2.618V    24.71mA    20.75mA    29.8mA
2.945V    20.32mA    13.73mA    25.93mA
3.218V    14.95mA    7.852mA    22.54mA
3.6V      8.27mA     3.068mA    15.06mA
[Pullup]
-1.8V     9.872mA    7.849mA    11.96mA
-1.309V   12.43mA    10.38mA    14.13mA
-927.3mV  11.82mA    11.58mA    12.42mA
-600mV    9.811mA    10.09mA    10.26mA
-381.8mV  7.028mA    7.03mA     7.372mA
1.2V      -20.91mA   -20.59mA   -22.11mA
1.745V    -28.92mA   -28.09mA   -30.81mA
2.127V    -33.58mA   -31.56mA   -36.06mA
2.455V    -35.14mA   -30.6mA    -39.44mA
2.727V    -33.77mA   -27.97mA   -39.32mA
3.164V    -28.92mA   -21.05mA   -34.62mA
3.6V      -21.41mA   -12.75mA   -28.48mA
[GND_clamp]
-1.8V     -346.1mA   -209.3mA   -568.3mA
-1.327V   -149.7mA   -89.03mA   -250.9mA
-1.291V   -135.6mA   -80.47mA   -227.5mA
-1.145V   -82.35mA   -48.67mA   -137.7mA
-1.073V   -59.44mA   -35.55mA   -97.96mA
-1.036V   -49.1mA    -29.72mA   -79.9mA
-927.3mV  -26.31mA   -17.11mA   -38.99mA
-854.5mV  -16.67mA   -11.64mA   -22.56mA
-818.2mV  -12.86mA   -9.351mA   -16.98mA
-672.7mV  -5.705mA   -3.913mA   -8.624mA
-381.8mV  -120.4uA   -129uA     -167.4uA
1.8V      2.273nA    454nA      6.646nA
[Ramp]
dV/dt_f 0.51515743/0.26330317n 0.46692682/0.33383948n   0.569435/0.18928896n
dV/dt_r 0.50927861/0.25769671n 0.45712894/0.33267481n 0.57447976/0.17799161n
R_load = 50
[Rising Waveform]
R_fixture = 50
V_fixture = 1.8
V_fixture_min = 1.62
V_fixture_max = 1.98
0s        944.4mV    844.3mV    1.033V
79.3ps    944.4mV    844.3mV    1.044V
190.1ps   971.6mV    844.3mV    1.37V
329.3ps   1.305V     844.6mV    1.807V
388.7ps   1.441V     872.5mV    1.913V
448.9ps   1.556V     951.1mV    1.953V
579.2ps   1.72V      1.171V     1.973V
747.3ps   1.786V     1.424V     1.979V
1.016ns   1.794V     1.574V     1.98V
2.62ns    1.799V     1.615V     1.98V
[Rising Waveform]
R_fixture = 50
V_fixture = 0
V_fixture_min = 0
V_fixture_max = 0
0s        0V         0V         0V
99.5ps    0V         0V         16.6mV
200.7ps   6.709mV    0V         276.5mV
345.6ps   301.2mV    0V         752mV
467.1ps   558mV      72.44mV    921.1mV
687.3ps   812.1mV    396.3mV    950mV
834.9ps   833.3mV    584.8mV    953.7mV
1.039ns   838.1mV    697.1mV    955.4mV
1.317ns   841mV      751.6mV    955.8mV
2.638ns   845.6mV    755.5mV    955.9mV
[Falling Waveform]
R_fixture = 50
V_fixture = 1.8
V_fixture_min = 1.62
V_fixture_max = 1.98
0s        1.799V     1.62V      1.979V
98.7ps    1.799V     1.62V      1.964V
208.3ps   1.783V     1.62V      1.696V
357.7ps   1.487V     1.62V      1.235V
419ps     1.354V     1.606V     1.112V
490.3ps   1.219V     1.533V     1.064V
699.8ps   980.9mV    1.219V     1.038V
865.1ps   956.5mV    1.007V     1.034V
1.066ns   951.6mV    904.2mV    1.032V
2.62ns    944.3mV    847.1mV    1.032V
[Falling Waveform]
R_fixture = 50
V_fixture = 0
V_fixture_min = 0
V_fixture_max = 0
0s        845.6mV    759mV      955.1mV
78ps      845.6mV    759mV      955.1mV
184.4ps   837mV      759mV      675.3mV
349.7ps   473.8mV    759mV      168mV
465.4ps   246.4mV    634.9mV    26.8mV
673.7ps   31.28mV    318.4mV    4.649mV
788.3ps   11.75mV    172.1mV    2.38mV
998.1ps   6.803mV    61.67mV    0V
1.286ns   4.633mV    6.817mV    0V
2.638ns   0V         4.502mV    0V
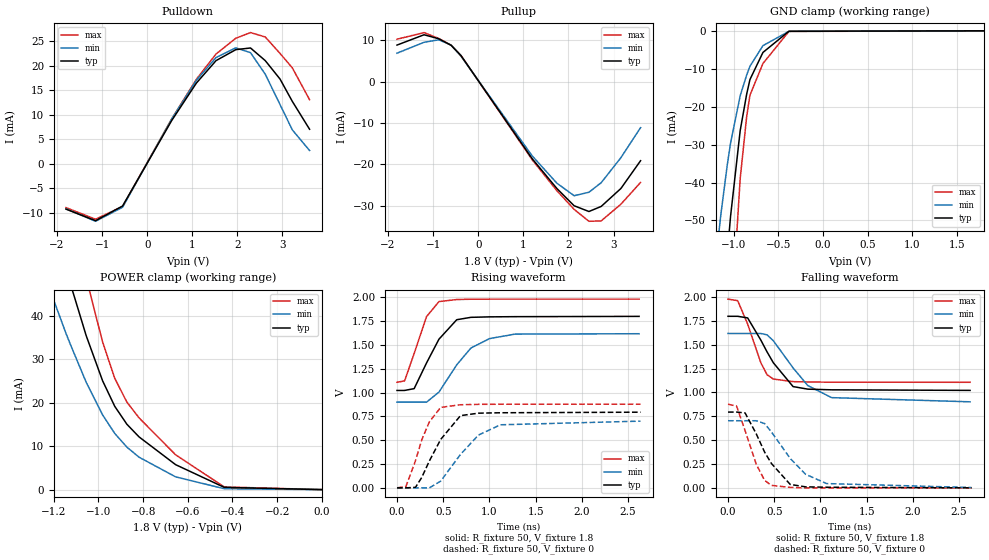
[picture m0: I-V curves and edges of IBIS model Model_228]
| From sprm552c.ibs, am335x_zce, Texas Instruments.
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| Model based on original model for BCSHTLTCSCDVPBFZ_SSDHV
|   Sub model SR10_6MA_10PER_1P8
[model]   Model_228
|[Description]  [1.8V-3-STATE-NOTERM-SR10:6MA, IND, 10%]
|   Fast slew rate (SR[1:0] = "10"), 1.33 * RExt = 0.750 * Iout
|   (I[2:0] = "001"), 6mA nominal with Rext = 50R,ODT off (ODT[1:0]
|   = "00") CMOS mode,Industrial temperature range (-40C to 125C,
|   25C nominal),10% power supply tolerance
|[Input Load]   NOTERM
|[Output Drive] SR10:6MA
|Voltage   1.8V
|Mode   3-STATE
Model_type   3-state
Polarity   Non-Inverting
Enable   Active-Low
Cref =  15pF
Rref =  100.0000M
Vref =  0V
Vmeas =  0.9
C_comp   1.851324p   1.663768p   1.973575p
[Temperature Range]   25   125   -40
[Voltage Range]   1.8   1.62   1.98
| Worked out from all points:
|   slope of the pulldown table from 0 to 0.27 V, typ, clamps not added: 60.1 ohm
|   slope of the pullup table from 0 to 0.27 V, typ, clamps not added: 60.8 ohm
|   GND clamp passes 1 mA (typ) near -0.49 V on its own axis
|   POWER clamp passes 1 mA (typ) near -0.47 V on its own axis
|   rising waveform, R_fixture 50, V_fixture 1.8: 20-80 % time 249ps typ, 330ps min, 178ps max; typ from 1.02 V to 1.8 V
|   rising waveform, R_fixture 50, V_fixture 0: 20-80 % time 263ps typ, 356ps min, 190ps max; typ from 0 V to 0.794 V
|   falling waveform, R_fixture 50, V_fixture 1.8: 20-80 % time 270ps typ, 359ps min, 189ps max; typ from 1.8 V to 1.02 V
|   falling waveform, R_fixture 50, V_fixture 0: 20-80 % time 266ps typ, 350ps min, 188ps max; typ from 0.794 V to 0 V
[POWER_clamp]
-1.8V     194.9mA    137.1mA    262.8mA
-1.236V   68.49mA    48.51mA    92.67mA
-1.145V   50.76mA    35.86mA    69.65mA
-1.127V   47.56mA    33.54mA    65.34mA
-1.055V   35.4mA     24.69mA    48.69mA
-981.8mV  25.06mA    17.2mA     34.01mA
-927.3mV  19.17mA    12.93mA    25.61mA
-872.7mV  15.03mA    9.767mA    20.12mA
-818.2mV  12.12mA    7.45mA     16.5mA
-654.5mV  5.738mA    2.93mA     8.003mA
-436.4mV  508.2uA    199.4uA    613uA
0V        2.273nA    15.95nA    16.67nA
[Pulldown]
-1.8V     -9.241mA   -9.161mA   -8.932mA
-1.145V   -11.6mA    -11.72mA   -11.3mA
-545.5mV  -8.602mA   -8.855mA   -8.702mA
545.5mV   8.836mA    9.123mA    9.182mA
1.091V    16.44mA    17.01mA    17.21mA
1.527V    21.01mA    21.64mA    22.36mA
1.964V    23.24mA    23.61mA    25.56mA
2.291V    23.58mA    22.62mA    26.72mA
2.618V    21mA       18.23mA    25.82mA
2.945V    17.26mA    12.06mA    22.47mA
3.218V    12.7mA     6.898mA    19.53mA
3.6V      7.029mA    2.696mA    13.05mA
[Pullup]
-1.8V     8.832mA    6.868mA    10.25mA
-1.2V     11.33mA    9.506mA    11.86mA
-872.7mV  10.35mA    10.11mA    10.42mA
-600mV    8.779mA    8.832mA    8.794mA
-381.8mV  6.289mA    6.153mA    6.32mA
1.2V      -18.71mA   -18.02mA   -18.96mA
1.745V    -25.88mA   -24.59mA   -26.41mA
2.127V    -30.05mA   -27.62mA   -30.92mA
2.455V    -31.44mA   -26.78mA   -33.81mA
2.727V    -30.21mA   -24.47mA   -33.71mA
3.164V    -25.87mA   -18.41mA   -29.67mA
3.6V      -19.15mA   -11.15mA   -24.41mA
[GND_clamp]
-1.8V     -346.1mA   -209.3mA   -568.3mA
-1.327V   -149.7mA   -89.03mA   -250.9mA
-1.291V   -135.6mA   -80.47mA   -227.5mA
-1.145V   -82.35mA   -48.67mA   -137.7mA
-1.073V   -59.44mA   -35.55mA   -97.96mA
-1.036V   -49.1mA    -29.72mA   -79.9mA
-927.3mV  -26.31mA   -17.11mA   -38.99mA
-854.5mV  -16.67mA   -11.64mA   -22.56mA
-818.2mV  -12.86mA   -9.351mA   -16.98mA
-672.7mV  -5.705mA   -3.913mA   -8.624mA
-381.8mV  -120.4uA   -129uA     -167.4uA
1.8V      2.273nA    454nA      6.646nA
[Ramp]
dV/dt_f 0.46820047/0.27171957n 0.43368679/0.36238562n  0.5240471/0.189045n
dV/dt_r 0.47824453/0.26449451n 0.42365487/0.35963101n 0.52733497/0.18994534n
R_load = 50
[Rising Waveform]
R_fixture = 50
V_fixture = 1.8
V_fixture_min = 1.62
V_fixture_max = 1.98
0s        1.022V     899.3mV    1.108V
81.9ps    1.022V     899.3mV    1.122V
185.5ps   1.041V     899.3mV    1.41V
319.9ps   1.311V     899.3mV    1.797V
454.2ps   1.56V      1.005V     1.954V
646.6ps   1.764V     1.291V     1.976V
799.9ps   1.789V     1.467V     1.979V
1.002ns   1.794V     1.566V     1.98V
1.277ns   1.796V     1.613V     1.98V
2.62ns    1.799V     1.617V     1.98V
[Rising Waveform]
R_fixture = 50
V_fixture = 0
V_fixture_min = 0
V_fixture_max = 0
0s        0V         0V         0V
96.8ps    0V         0V         15.2mV
200ps     5.397mV    0V         284.8mV
267.3ps   108.5mV    0V         503mV
350.5ps   282.7mV    0V         693mV
472.3ps   507.4mV    70.24mV    843.9mV
686.9ps   757.7mV    350.7mV    871.8mV
881.3ps   783.5mV    553.7mV    876mV
1.119ns   787.9mV    661.6mV    877.3mV
2.636ns   793.9mV    700mV      877.7mV
[Falling Waveform]
R_fixture = 50
V_fixture = 1.8
V_fixture_min = 1.62
V_fixture_max = 1.98
0s        1.799V     1.619V     1.979V
104.4ps   1.799V     1.619V     1.963V
212.4ps   1.782V     1.619V     1.718V
355.4ps   1.549V     1.619V     1.311V
423ps     1.425V     1.604V     1.186V
490.4ps   1.312V     1.543V     1.141V
704ps     1.062V     1.258V     1.114V
864ps     1.035V     1.072V     1.11V
1.122ns   1.028V     946.1mV    1.108V
2.62ns    1.022V     902.2mV    1.107V
[Falling Waveform]
R_fixture = 50
V_fixture = 0
V_fixture_min = 0
V_fixture_max = 0
0s        794.5mV    703.8mV    876.7mV
92.5ps    794.5mV    703.8mV    858.1mV
184.7ps   785.7mV    703.8mV    600.6mV
305.7ps   566.4mV    703.8mV    247.3mV
396.4ps   374.3mV    673.9mV    77.73mV
470.6ps   254.7mV    585.1mV    25.83mV
673ps     36.08mV    308.8mV    4.8mV
839.4ps   10.57mV    142.6mV    0V
1.067ns   6.554mV    44.94mV    0V
2.636ns   0V         3.587mV    0V
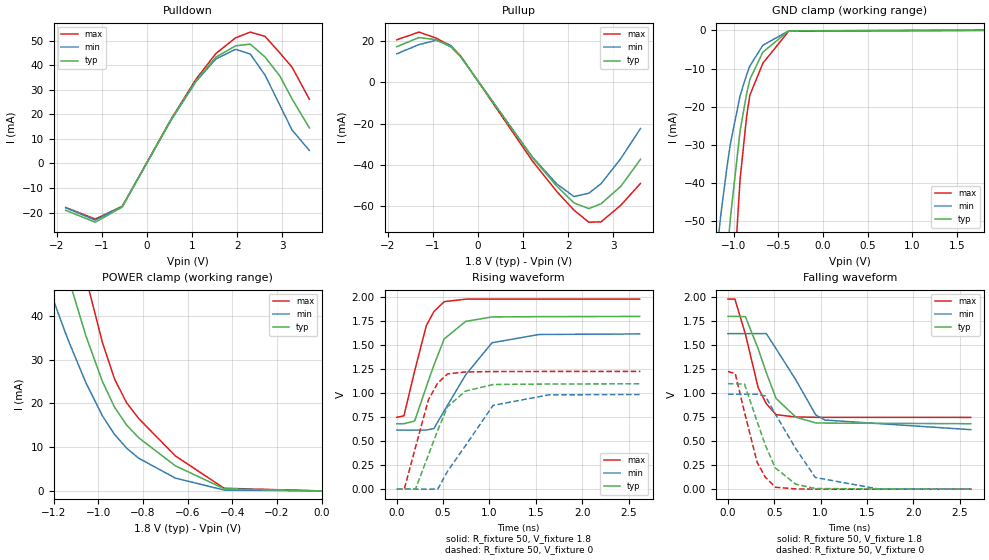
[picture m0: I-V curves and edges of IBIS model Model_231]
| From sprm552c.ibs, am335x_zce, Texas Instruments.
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| Model based on original model for BCSHTLTCSCDVPBFZ_SSDHV
|   Sub model SR11_12MA_10PER_1P8
[model]   Model_231
|[Description]  [1.8V-3-STATE-NOTERM-SR11:12MA, IND, 10%]
|   Slowest slew rate (SR[1:0] = "11"), 0.67 * RExt = 1.500 * Iout
|   (I[2:0] = "111"), 12mA nominal with Rext = 50R,ODT off (ODT[1:0]
|   = "00") CMOS mode,Industrial temperature range (-40C to 125C,
|   25C nominal),10% power supply tolerance
|[Input Load]   NOTERM
|[Output Drive] SR11:12MA
|Voltage   1.8V
|Mode   3-STATE
Model_type   3-state
Polarity   Non-Inverting
Enable   Active-Low
Cref =  15pF
Rref =  100.0000M
Vref =  0V
Vmeas =  0.9
C_comp   1.851324p   1.663768p   1.973575p
[Temperature Range]   25   125   -40
[Voltage Range]   1.8   1.62   1.98
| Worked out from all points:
|   slope of the pulldown table from 0 to 0.27 V, typ, clamps not added: 29.2 ohm
|   slope of the pullup table from 0 to 0.27 V, typ, clamps not added: 31.3 ohm
|   GND clamp passes 1 mA (typ) near -0.49 V on its own axis
|   POWER clamp passes 1 mA (typ) near -0.47 V on its own axis
|   rising waveform, R_fixture 50, V_fixture 1.8: 20-80 % time 253ps typ, 384ps min, 194ps max; typ from 0.682 V to 1.8 V
|   rising waveform, R_fixture 50, V_fixture 0: 20-80 % time 264ps typ, 383ps min, 215ps max; typ from 0 V to 1.1 V
|   falling waveform, R_fixture 50, V_fixture 1.8: 20-80 % time 258ps typ, 354ps min, 203ps max; typ from 1.8 V to 0.681 V
|   falling waveform, R_fixture 50, V_fixture 0: 20-80 % time 251ps typ, 389ps min, 196ps max; typ from 1.1 V to 0 V
[POWER_clamp]
-1.8V     194.9mA    137.1mA    262.8mA
-1.236V   68.49mA    48.51mA    92.67mA
-1.145V   50.76mA    35.86mA    69.65mA
-1.127V   47.56mA    33.54mA    65.34mA
-1.055V   35.4mA     24.69mA    48.69mA
-981.8mV  25.06mA    17.2mA     34.01mA
-927.3mV  19.17mA    12.93mA    25.61mA
-872.7mV  15.03mA    9.767mA    20.12mA
-818.2mV  12.12mA    7.45mA     16.5mA
-654.5mV  5.738mA    2.93mA     8.003mA
-436.4mV  508.2uA    199.4uA    613uA
0V        2.273nA    15.95nA    16.67nA
[Pulldown]
-1.8V     -19.04mA   -18.02mA   -17.88mA
-1.145V   -23.87mA   -23.03mA   -22.59mA
-545.5mV  -17.69mA   -17.39mA   -17.39mA
545.5mV   18.16mA    17.9mA     18.33mA
1.091V    33.8mA     33.39mA    34.37mA
1.527V    43.21mA    42.5mA     44.68mA
1.964V    47.83mA    46.41mA    51.1mA
2.291V    48.55mA    44.5mA     53.43mA
2.618V    43.28mA    35.9mA     51.68mA
2.945V    35.6mA     23.75mA    44.98mA
3.218V    26.2mA     13.58mA    39.11mA
3.6V      14.49mA    5.303mA    26.15mA
[Pullup]
-1.8V     17.15mA    13.74mA    20.51mA
-1.309V   21.6mA     18.18mA    24.22mA
-927.3mV  20.52mA    20.27mA    21.29mA
-600mV    17.03mA    17.65mA    17.57mA
-381.8mV  12.19mA    12.29mA    12.62mA
1.2V      -36.27mA   -35.99mA   -37.86mA
1.745V    -50.17mA   -49.12mA   -52.76mA
2.127V    -58.27mA   -55.22mA   -61.77mA
2.455V    -61.03mA   -53.58mA   -67.59mA
2.727V    -58.68mA   -48.99mA   -67.43mA
3.164V    -50.29mA   -36.88mA   -59.41mA
3.6V      -37.24mA   -22.35mA   -48.89mA
[GND_clamp]
-1.8V     -346.1mA   -209.3mA   -568.3mA
-1.327V   -149.7mA   -89.03mA   -250.9mA
-1.291V   -135.6mA   -80.47mA   -227.5mA
-1.145V   -82.35mA   -48.67mA   -137.7mA
-1.073V   -59.44mA   -35.55mA   -97.96mA
-1.036V   -49.1mA    -29.72mA   -79.9mA
-927.3mV  -26.31mA   -17.11mA   -38.99mA
-854.5mV  -16.67mA   -11.64mA   -22.56mA
-818.2mV  -12.86mA   -9.351mA   -16.98mA
-672.7mV  -5.705mA   -3.913mA   -8.624mA
-381.8mV  -120.4uA   -129uA     -167.4uA
1.8V      2.273nA    454nA      6.646nA
[Ramp]
dV/dt_f 0.67402644/0.25891513n 0.60590184/0.35543908n 0.74137451/0.20398073n
dV/dt_r 0.66213478/0.26504916n 0.59792513/0.39506211n 0.73754947/0.21508946n
R_load = 50
[Rising Waveform]
R_fixture = 50
V_fixture = 1.8
V_fixture_min = 1.62
V_fixture_max = 1.98
0s        681.6mV    615.9mV    748.2mV
77ps      681.6mV    615.9mV    764.5mV
192.4ps   709.6mV    615.9mV    1.231V
318.9ps   1.068V     615.9mV    1.705V
400.6ps   1.293V     631.7mV    1.85V
511.3ps   1.565V     815.9mV    1.953V
743.4ps   1.748V     1.191V     1.979V
1.027ns   1.794V     1.525V     1.98V
1.535ns   1.797V     1.611V     1.98V
2.62ns    1.799V     1.617V     1.98V
[Rising Waveform]
R_fixture = 50
V_fixture = 0
V_fixture_min = 0
V_fixture_max = 0
0s        0V         0V         0V
80.3ps    0V         0V         0V
202.3ps   3.199mV    0V         439.1mV
340ps     354.4mV    0V         928.7mV
441.2ps   611.4mV    0V         1.105V
546.8ps   858.5mV    185.1mV    1.2V
739.8ps   1.021V     451.9mV    1.221V
1.039ns   1.09V      872.7mV    1.225V
1.64ns    1.095V     982.4mV    1.226V
2.629ns   1.098V     985.9mV    1.226V
[Falling Waveform]
R_fixture = 50
V_fixture = 1.8
V_fixture_min = 1.62
V_fixture_max = 1.98
0s        1.799V     1.619V     1.979V
75.2ps    1.799V     1.619V     1.979V
189.2ps   1.796V     1.619V     1.612V
326.4ps   1.461V     1.619V     1.056V
414.3ps   1.213V     1.619V     889.3mV
519.8ps   943.9mV    1.462V     775.6mV
735.1ps   748.3mV    1.134V     751.3mV
948.5ps   690mV      771.3mV    748.1mV
1.049ns   687.8mV    719.5mV    747.7mV
2.62ns    681.3mV    619.4mV    747.2mV
[Falling Waveform]
R_fixture = 50
V_fixture = 0
V_fixture_min = 0
V_fixture_max = 0
0s        1.098V     988.6mV    1.225V
79.5ps    1.098V     988.6mV    1.203V
179.4ps   1.093V     988.6mV    797.7mV
315.6ps   702mV      988.6mV    278.5mV
403.8ps   457.9mV    969.4mV    125.1mV
511.3ps   221.4mV    781.6mV    20.47mV
730.7ps   52.19mV    425.3mV    2.548mV
942.4ps   6.824mV    121.7mV    0V
1.612ns   2.556mV    3.777mV    0V
2.629ns   0V         3.628mV    0V
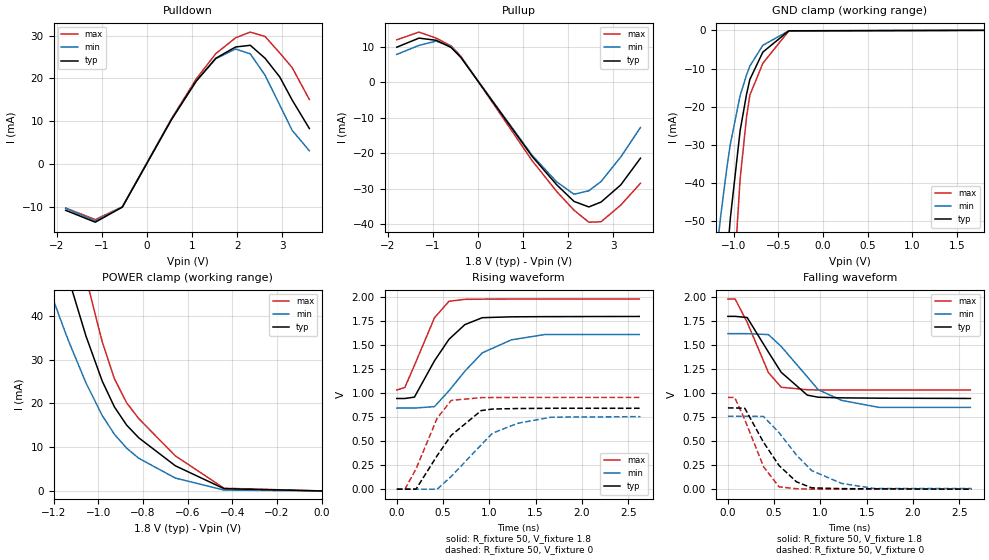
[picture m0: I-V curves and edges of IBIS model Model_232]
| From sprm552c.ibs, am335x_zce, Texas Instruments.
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| Model based on original model for BCSHTLTCSCDVPBFZ_SSDHV
|   Sub model SR11_7MA_10PER_1P8
[model]   Model_232
|[Description]  [1.8V-3-STATE-NOTERM-SR11:7MA, IND, 10%]
|   Slowest slew rate (SR[1:0] = "11"), 1.14 * RExt = 0.875 * Iout
|   (I[2:0] = "010"), 7mA nominal with Rext = 50R,ODT off (ODT[1:0]
|   = "00") CMOS mode,Industrial temperature range (-40C to 125C,
|   25C nominal),10% power supply tolerance
|[Input Load]   NOTERM
|[Output Drive] SR11:7MA
|Voltage   1.8V
|Mode   3-STATE
Model_type   3-state
Polarity   Non-Inverting
Enable   Active-Low
Cref =  15pF
Rref =  100.0000M
Vref =  0V
Vmeas =  0.9
C_comp   1.851324p   1.663768p   1.973575p
[Temperature Range]   25   125   -40
[Voltage Range]   1.8   1.62   1.98
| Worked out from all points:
|   slope of the pulldown table from 0 to 0.27 V, typ, clamps not added: 51.1 ohm
|   slope of the pullup table from 0 to 0.27 V, typ, clamps not added: 54.4 ohm
|   GND clamp passes 1 mA (typ) near -0.49 V on its own axis
|   POWER clamp passes 1 mA (typ) near -0.47 V on its own axis
|   rising waveform, R_fixture 50, V_fixture 1.8: 20-80 % time 351ps typ, 440ps min, 251ps max; typ from 0.944 V to 1.8 V
|   rising waveform, R_fixture 50, V_fixture 0: 20-80 % time 374ps typ, 470ps min, 253ps max; typ from 0 V to 0.843 V
|   falling waveform, R_fixture 50, V_fixture 1.8: 20-80 % time 356ps typ, 444ps min, 251ps max; typ from 1.8 V to 0.944 V
|   falling waveform, R_fixture 50, V_fixture 0: 20-80 % time 352ps typ, 429ps min, 247ps max; typ from 0.846 V to 0 V
[POWER_clamp]
-1.8V     194.9mA    137.1mA    262.8mA
-1.236V   68.49mA    48.51mA    92.67mA
-1.145V   50.76mA    35.86mA    69.65mA
-1.127V   47.56mA    33.54mA    65.34mA
-1.055V   35.4mA     24.69mA    48.69mA
-981.8mV  25.06mA    17.2mA     34.01mA
-927.3mV  19.17mA    12.93mA    25.61mA
-872.7mV  15.03mA    9.767mA    20.12mA
-818.2mV  12.12mA    7.45mA     16.5mA
-654.5mV  5.738mA    2.93mA     8.003mA
-436.4mV  508.2uA    199.4uA    613uA
0V        2.273nA    15.95nA    16.67nA
[Pulldown]
-1.8V     -10.87mA   -10.42mA   -10.31mA
-1.145V   -13.64mA   -13.33mA   -13.03mA
-545.5mV  -10.12mA   -10.08mA   -10.04mA
545.5mV   10.39mA    10.38mA    10.59mA
1.091V    19.34mA    19.35mA    19.85mA
1.527V    24.71mA    24.62mA    25.8mA
1.964V    27.34mA    26.87mA    29.49mA
2.291V    27.74mA    25.74mA    30.83mA
2.618V    24.71mA    20.75mA    29.8mA
2.945V    20.32mA    13.73mA    25.93mA
3.218V    14.95mA    7.852mA    22.54mA
3.6V      8.27mA     3.068mA    15.06mA
[Pullup]
-1.8V     9.872mA    7.849mA    11.96mA
-1.309V   12.43mA    10.38mA    14.13mA
-927.3mV  11.82mA    11.58mA    12.42mA
-600mV    9.811mA    10.09mA    10.26mA
-381.8mV  7.028mA    7.03mA     7.372mA
1.2V      -20.91mA   -20.59mA   -22.11mA
1.745V    -28.92mA   -28.09mA   -30.81mA
2.127V    -33.58mA   -31.56mA   -36.06mA
2.455V    -35.14mA   -30.6mA    -39.44mA
2.727V    -33.77mA   -27.97mA   -39.32mA
3.164V    -28.92mA   -21.05mA   -34.62mA
3.6V      -21.41mA   -12.75mA   -28.48mA
[GND_clamp]
-1.8V     -346.1mA   -209.3mA   -568.3mA
-1.327V   -149.7mA   -89.03mA   -250.9mA
-1.291V   -135.6mA   -80.47mA   -227.5mA
-1.145V   -82.35mA   -48.67mA   -137.7mA
-1.073V   -59.44mA   -35.55mA   -97.96mA
-1.036V   -49.1mA    -29.72mA   -79.9mA
-927.3mV  -26.31mA   -17.11mA   -38.99mA
-854.5mV  -16.67mA   -11.64mA   -22.56mA
-818.2mV  -12.86mA   -9.351mA   -16.98mA
-672.7mV  -5.705mA   -3.913mA   -8.624mA
-381.8mV  -120.4uA   -129uA     -167.4uA
1.8V      2.273nA    454nA      6.646nA
[Ramp]
dV/dt_f 0.51532893/0.35473106n  0.4672059/0.45222075n 0.56957022/0.25249562n
dV/dt_r 0.50961786/0.3766102n 0.45759785/0.47691896n 0.57467949/0.25502601n
R_load = 50
[Rising Waveform]
R_fixture = 50
V_fixture = 1.8
V_fixture_min = 1.62
V_fixture_max = 1.98
0s        944.4mV    844.4mV    1.033V
86.4ps    944.4mV    844.4mV    1.059V
190.2ps   958.5mV    844.4mV    1.289V
407ps     1.337V     859.8mV    1.785V
563.9ps   1.561V     1.025V     1.957V
735.7ps   1.714V     1.229V     1.977V
923.8ps   1.786V     1.42V      1.979V
1.237ns   1.795V     1.555V     1.98V
1.601ns   1.797V     1.611V     1.98V
2.62ns    1.799V     1.611V     1.98V
[Rising Waveform]
R_fixture = 50
V_fixture = 0
V_fixture_min = 0
V_fixture_max = 0
0s        0V         0V         0V
87.7ps    0V         0V         0V
207.3ps   0V         0V         210.7mV
437ps     351.1mV    0V         741.6mV
588.3ps   561.1mV    133.1mV    924.6mV
912.6ps   818.8mV    462.5mV    953.5mV
1.036ns   834.6mV    584.2mV    954.9mV
1.309ns   839.9mV    686.6mV    955.8mV
1.667ns   842.6mV    749.7mV    955.9mV
2.633ns   842.6mV    755.4mV    955.9mV
[Falling Waveform]
R_fixture = 50
V_fixture = 1.8
V_fixture_min = 1.62
V_fixture_max = 1.98
0s        1.799V     1.619V     1.979V
78.5ps    1.799V     1.619V     1.979V
207.7ps   1.787V     1.619V     1.738V
437.7ps   1.427V     1.609V     1.214V
575.4ps   1.217V     1.486V     1.061V
858.3ps   978.7mV    1.169V     1.035V
976.6ps   957.2mV    1.035V     1.033V
1.231ns   950.6mV    923.8mV    1.032V
1.634ns   947mV      851.2mV    1.032V
2.62ns    944.3mV    851.2mV    1.032V
[Falling Waveform]
R_fixture = 50
V_fixture = 0
V_fixture_min = 0
V_fixture_max = 0
0s        845.7mV    759.1mV    955mV
72.8ps    845.7mV    759.1mV    955mV
182.4ps   842.2mV    759.1mV    724.3mV
384.6ps   488.4mV    757.2mV    234.1mV
552.6ps   246.2mV    588.1mV    24.25mV
740.3ps   76.84mV    355.6mV    4.531mV
904.6ps   13.72mV    193.8mV    0V
1.229ns   5.487mV    59.66mV    0V
1.585ns   3.51mV     6.713mV    0V
2.633ns   0V         6.713mV    0V
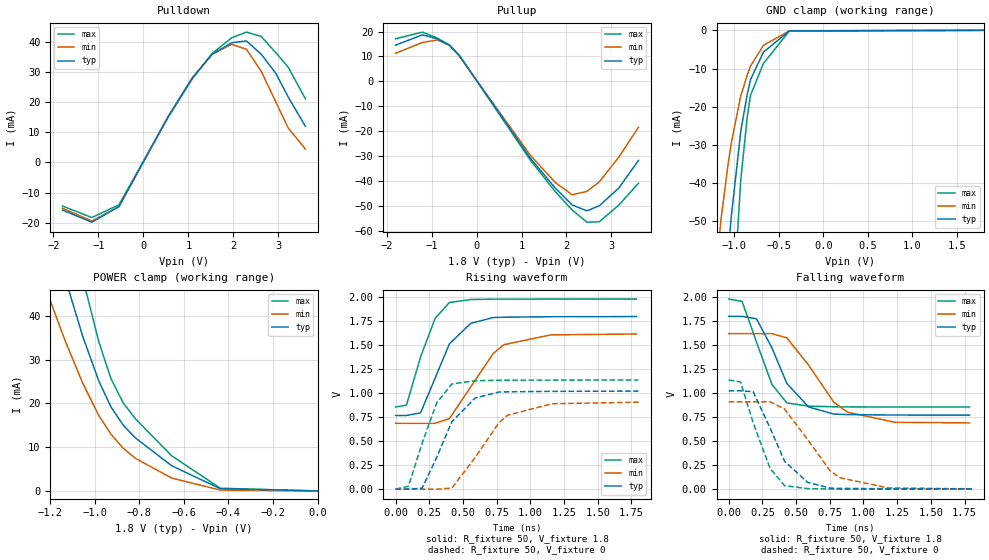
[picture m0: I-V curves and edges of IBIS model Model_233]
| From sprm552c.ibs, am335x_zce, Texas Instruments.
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| Model based on original model for BCSHTLTCSCDVPBFZ_SSDHV
|   Sub model SR10_10MA_10PER_1P8
[model]   Model_233
|[Description]  [1.8V-3-STATE-NOTERM-SR10:10MA, IND, 10%]
|   Fast slew rate (SR[1:0] = "10"), 0.80 * RExt = 1.250 * Iout
|   (I[2:0] = "101"), 10mA nominal with Rext = 50R,ODT off (ODT[1:0]
|   = "00") CMOS mode,Industrial temperature range (-40C to 125C,
|   25C nominal),10% power supply tolerance
|[Input Load]   NOTERM
|[Output Drive] SR10:10MA
|Voltage   1.8V
|Mode   3-STATE
Model_type   3-state
Polarity   Non-Inverting
Enable   Active-Low
Cref =  15pF
Rref =  100.0000M
Vref =  0V
Vmeas =  0.9
C_comp   1.851324p   1.663768p   1.973575p
[Temperature Range]   25   125   -40
[Voltage Range]   1.8   1.62   1.98
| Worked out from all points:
|   slope of the pulldown table from 0 to 0.27 V, typ, clamps not added: 35.3 ohm
|   slope of the pullup table from 0 to 0.27 V, typ, clamps not added: 36.9 ohm
|   GND clamp passes 1 mA (typ) near -0.49 V on its own axis
|   POWER clamp passes 1 mA (typ) near -0.47 V on its own axis
|   rising waveform, R_fixture 50, V_fixture 1.8: 20-80 % time 192ps typ, 266ps min, 156ps max; typ from 0.767 V to 1.8 V
|   rising waveform, R_fixture 50, V_fixture 0: 20-80 % time 208ps typ, 267ps min, 165ps max; typ from 0 V to 1.02 V
|   falling waveform, R_fixture 50, V_fixture 1.8: 20-80 % time 216ps typ, 278ps min, 166ps max; typ from 1.8 V to 0.77 V
|   falling waveform, R_fixture 50, V_fixture 0: 20-80 % time 205ps typ, 280ps min, 165ps max; typ from 1.02 V to 0.004 V
[POWER_clamp]
-1.8V     194.9mA    137.1mA    262.8mA
-1.236V   68.49mA    48.51mA    92.67mA
-1.145V   50.76mA    35.86mA    69.65mA
-1.127V   47.56mA    33.54mA    65.34mA
-1.055V   35.4mA     24.69mA    48.69mA
-981.8mV  25.06mA    17.2mA     34.01mA
-927.3mV  19.17mA    12.93mA    25.61mA
-872.7mV  15.03mA    9.767mA    20.12mA
-818.2mV  12.12mA    7.45mA     16.5mA
-654.5mV  5.738mA    2.93mA     8.003mA
-436.4mV  508.2uA    199.4uA    613uA
0V        2.273nA    15.95nA    16.67nA
[Pulldown]
-1.8V     -15.77mA   -15.17mA   -14.43mA
-1.145V   -19.78mA   -19.39mA   -18.25mA
-545.5mV  -14.66mA   -14.65mA   -14.05mA
545.5mV   15.06mA    15.08mA    14.82mA
1.091V    28.02mA    28.13mA    27.77mA
1.527V    35.81mA    35.8mA     36.1mA
1.964V    39.64mA    39.08mA    41.28mA
2.291V    40.23mA    37.46mA    43.16mA
2.618V    35.85mA    30.21mA    41.73mA
2.945V    29.48mA    19.99mA    36.31mA
3.218V    21.69mA    11.43mA    31.57mA
3.6V      12mA       4.465mA    21.1mA
[Pullup]
-1.8V     14.55mA    11.29mA    17.09mA
-1.2V     18.67mA    15.62mA    19.77mA
-872.7mV  17.03mA    16.61mA    17.36mA
-600mV    14.45mA    14.5mA     14.65mA
-381.8mV  10.35mA    10.1mA     10.52mA
1.2V      -30.78mA   -29.58mA   -31.57mA
1.745V    -42.59mA   -40.36mA   -43.98mA
2.127V    -49.46mA   -45.37mA   -51.49mA
2.455V    -51.78mA   -44mA      -56.34mA
2.727V    -49.78mA   -40.23mA   -56.19mA
3.164V    -42.65mA   -30.28mA   -49.49mA
3.6V      -31.58mA   -18.34mA   -40.72mA
[GND_clamp]
-1.8V     -346.1mA   -209.3mA   -568.3mA
-1.327V   -149.7mA   -89.03mA   -250.9mA
-1.291V   -135.6mA   -80.47mA   -227.5mA
-1.145V   -82.35mA   -48.67mA   -137.7mA
-1.073V   -59.44mA   -35.55mA   -97.96mA
-1.036V   -49.1mA    -29.72mA   -79.9mA
-927.3mV  -26.31mA   -17.11mA   -38.99mA
-854.5mV  -16.67mA   -11.64mA   -22.56mA
-818.2mV  -12.86mA   -9.351mA   -16.98mA
-672.7mV  -5.705mA   -3.913mA   -8.624mA
-381.8mV  -120.4uA   -129uA     -167.4uA
1.8V      2.273nA    454nA      6.646nA
[Ramp]
dV/dt_f 0.62165463/0.21773292n 0.56217342/0.27942897n 0.67608772/0.16663014n
dV/dt_r 0.61683792/0.20999883n 0.54771861/0.2669752n 0.68335849/0.1648639n
R_load = 50
[Rising Waveform]
R_fixture = 50
V_fixture = 1.8
V_fixture_min = 1.62
V_fixture_max = 1.98
0s        767.5mV    685.8mV    856mV
81ps      767.5mV    685.8mV    875mV
185.7ps   795.3mV    685.8mV    1.378V
293.5ps   1.156V     685.8mV    1.779V
399.5ps   1.514V     735.1mV    1.944V
558.1ps   1.727V     1.066V     1.975V
725.1ps   1.788V     1.414V     1.979V
803.8ps   1.791V     1.505V     1.979V
1.151ns   1.796V     1.607V     1.98V
1.787ns   1.798V     1.616V     1.98V
[Rising Waveform]
R_fixture = 50
V_fixture = 0
V_fixture_min = 0
V_fixture_max = 0
0s        0V         0V         0V
95.6ps    0V         0V         30.55mV
197.5ps   10.82mV    0V         478.8mV
305ps     330.7mV    0V         898.8mV
417.9ps   702.6mV    11.57mV    1.096V
589.6ps   949mV      327.9mV    1.129V
766.5ps   1.012V     690.7mV    1.134V
830.1ps   1.014V     770.1mV    1.135V
1.162ns   1.019V     889.9mV    1.136V
1.802ns   1.021V     905.5mV    1.137V
[Falling Waveform]
R_fixture = 50
V_fixture = 1.8
V_fixture_min = 1.62
V_fixture_max = 1.98
0s        1.799V     1.619V     1.979V
99.6ps    1.799V     1.619V     1.955V
206ps     1.774V     1.619V     1.533V
321.1ps   1.471V     1.619V     1.09V
431.6ps   1.1V       1.575V     898.1mV
592.9ps   856mV      1.291V     864mV
780.5ps   781.3mV    904.2mV    857.9mV
882.3ps   776.5mV    800.6mV    856.4mV
1.236ns   771.7mV    695.8mV    855.2mV
1.787ns   770.3mV    689.9mV    855mV
[Falling Waveform]
R_fixture = 50
V_fixture = 0
V_fixture_min = 0
V_fixture_max = 0
0s        1.024V     909.4mV    1.136V
88.2ps    1.024V     909.4mV    1.116V
181.9ps   1.015V     909.4mV    690.5mV
307.3ps   636mV      909.4mV    216mV
415ps     290.3mV    834.2mV    36.55mV
586.9ps   69.54mV    514.2mV    5.859mV
754.6ps   10.66mV    187.3mV    2.102mV
827ps     8.119mV    119mV      0V
1.181ns   4.579mV    13.05mV    0V
1.802ns   3.903mV    3.479mV    0V
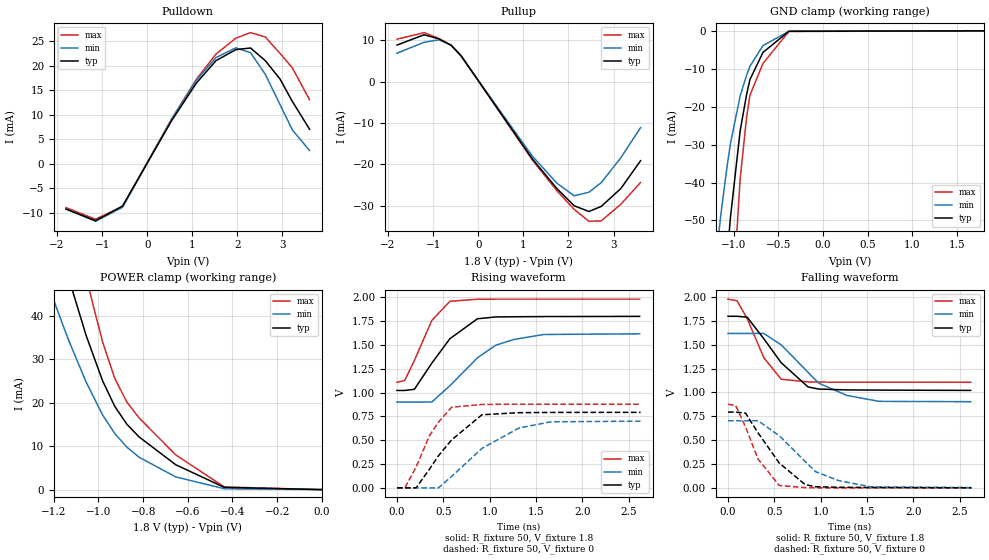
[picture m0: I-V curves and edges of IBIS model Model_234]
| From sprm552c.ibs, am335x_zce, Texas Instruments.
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| Model based on original model for BCSHTLTCSCDVPBFZ_SSDHV
|   Sub model SR11_6MA_10PER_1P8
[model]   Model_234
|[Description]  [1.8V-3-STATE-NOTERM-SR11:6MA, IND, 10%]
|   Slowest slew rate (SR[1:0] = "11"), 1.33 * RExt = 0.750 * Iout
|   (I[2:0] = "001"), 6mA nominal with Rext = 50R,ODT off (ODT[1:0]
|   = "00") CMOS mode,Industrial temperature range (-40C to 125C,
|   25C nominal),10% power supply tolerance
|[Input Load]   NOTERM
|[Output Drive] SR11:6MA
|Voltage   1.8V
|Mode   3-STATE
Model_type   3-state
Polarity   Non-Inverting
Enable   Active-Low
Cref =  15pF
Rref =  100.0000M
Vref =  0V
Vmeas =  0.9
C_comp   1.851324p   1.663768p   1.973575p
[Temperature Range]   25   125   -40
[Voltage Range]   1.8   1.62   1.98
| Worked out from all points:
|   slope of the pulldown table from 0 to 0.27 V, typ, clamps not added: 60.1 ohm
|   slope of the pullup table from 0 to 0.27 V, typ, clamps not added: 60.8 ohm
|   GND clamp passes 1 mA (typ) near -0.49 V on its own axis
|   POWER clamp passes 1 mA (typ) near -0.47 V on its own axis
|   rising waveform, R_fixture 50, V_fixture 1.8: 20-80 % time 360ps typ, 476ps min, 250ps max; typ from 1.02 V to 1.8 V
|   rising waveform, R_fixture 50, V_fixture 0: 20-80 % time 382ps typ, 515ps min, 274ps max; typ from 0 V to 0.792 V
|   falling waveform, R_fixture 50, V_fixture 1.8: 20-80 % time 368ps typ, 476ps min, 246ps max; typ from 1.8 V to 1.02 V
|   falling waveform, R_fixture 50, V_fixture 0: 20-80 % time 360ps typ, 478ps min, 252ps max; typ from 0.794 V to 0 V
[POWER_clamp]
-1.8V     194.9mA    137.1mA    262.8mA
-1.236V   68.49mA    48.51mA    92.67mA
-1.145V   50.76mA    35.86mA    69.65mA
-1.127V   47.56mA    33.54mA    65.34mA
-1.055V   35.4mA     24.69mA    48.69mA
-981.8mV  25.06mA    17.2mA     34.01mA
-927.3mV  19.17mA    12.93mA    25.61mA
-872.7mV  15.03mA    9.767mA    20.12mA
-818.2mV  12.12mA    7.45mA     16.5mA
-654.5mV  5.738mA    2.93mA     8.003mA
-436.4mV  508.2uA    199.4uA    613uA
0V        2.273nA    15.95nA    16.67nA
[Pulldown]
-1.8V     -9.241mA   -9.161mA   -8.932mA
-1.145V   -11.6mA    -11.72mA   -11.3mA
-545.5mV  -8.602mA   -8.855mA   -8.702mA
545.5mV   8.836mA    9.123mA    9.182mA
1.091V    16.44mA    17.01mA    17.21mA
1.527V    21.01mA    21.64mA    22.36mA
1.964V    23.24mA    23.61mA    25.56mA
2.291V    23.58mA    22.62mA    26.72mA
2.618V    21mA       18.23mA    25.82mA
2.945V    17.26mA    12.06mA    22.47mA
3.218V    12.7mA     6.898mA    19.53mA
3.6V      7.029mA    2.696mA    13.05mA
[Pullup]
-1.8V     8.832mA    6.868mA    10.25mA
-1.2V     11.33mA    9.506mA    11.86mA
-872.7mV  10.35mA    10.11mA    10.42mA
-600mV    8.779mA    8.832mA    8.794mA
-381.8mV  6.289mA    6.153mA    6.32mA
1.2V      -18.71mA   -18.02mA   -18.96mA
1.745V    -25.88mA   -24.59mA   -26.41mA
2.127V    -30.05mA   -27.62mA   -30.92mA
2.455V    -31.44mA   -26.78mA   -33.81mA
2.727V    -30.21mA   -24.47mA   -33.71mA
3.164V    -25.87mA   -18.41mA   -29.67mA
3.6V      -19.15mA   -11.15mA   -24.41mA
[GND_clamp]
-1.8V     -346.1mA   -209.3mA   -568.3mA
-1.327V   -149.7mA   -89.03mA   -250.9mA
-1.291V   -135.6mA   -80.47mA   -227.5mA
-1.145V   -82.35mA   -48.67mA   -137.7mA
-1.073V   -59.44mA   -35.55mA   -97.96mA
-1.036V   -49.1mA    -29.72mA   -79.9mA
-927.3mV  -26.31mA   -17.11mA   -38.99mA
-854.5mV  -16.67mA   -11.64mA   -22.56mA
-818.2mV  -12.86mA   -9.351mA   -16.98mA
-672.7mV  -5.705mA   -3.913mA   -8.624mA
-381.8mV  -120.4uA   -129uA     -167.4uA
1.8V      2.273nA    454nA      6.646nA
[Ramp]
dV/dt_f 0.46836108/0.36972062n 0.43392825/0.48185397n  0.5242108/0.24654864n
dV/dt_r  0.4785225/0.38486951n 0.42404972/0.51871726n 0.52751868/0.2747359n
R_load = 50
[Rising Waveform]
R_fixture = 50
V_fixture = 1.8
V_fixture_min = 1.62
V_fixture_max = 1.98
0s        1.022V     899.3mV    1.108V
84ps      1.022V     899.3mV    1.127V
187.2ps   1.034V     899.3mV    1.336V
376.4ps   1.309V     900.9mV    1.757V
570.5ps   1.564V     1.071V     1.957V
868.9ps   1.774V     1.365V     1.979V
1.065ns   1.793V     1.496V     1.98V
1.262ns   1.795V     1.557V     1.98V
1.584ns   1.797V     1.609V     1.98V
2.62ns    1.799V     1.616V     1.98V
[Rising Waveform]
R_fixture = 50
V_fixture = 0
V_fixture_min = 0
V_fixture_max = 0
0s        0V         0V         0V
84.5ps    0V         0V         0V
206.3ps   0V         0V         217.8mV
349.7ps   194.7mV    0V         546.1mV
447.4ps   336.3mV    0V         689mV
590.1ps   503.4mV    120mV      845.6mV
917.7ps   767.1mV    414.4mV    875.3mV
1.317ns   788.7mV    628mV      877.5mV
1.662ns   791.3mV    692.9mV    877.7mV
2.63ns    792.2mV    699.8mV    877.7mV
[Falling Waveform]
R_fixture = 50
V_fixture = 1.8
V_fixture_min = 1.62
V_fixture_max = 1.98
0s        1.799V     1.619V     1.979V
97.8ps    1.799V     1.619V     1.962V
206.3ps   1.79V      1.619V     1.776V
386.7ps   1.564V     1.619V     1.365V
574.1ps   1.312V     1.5V       1.139V
864.7ps   1.058V     1.211V     1.111V
978.8ps   1.036V     1.098V     1.109V
1.282ns   1.027V     970.1mV    1.108V
1.629ns   1.025V     907mV      1.108V
2.62ns    1.022V     903.5mV    1.107V
[Falling Waveform]
R_fixture = 50
V_fixture = 0
V_fixture_min = 0
V_fixture_max = 0
0s        794.5mV    703.9mV    876.7mV
83.4ps    794.5mV    703.9mV    862.8mV
189.1ps   783.9mV    703.9mV    639.1mV
324.7ps   576.4mV    703.9mV    301.2mV
553.4ps   260mV      546.2mV    25.01mV
833.5ps   34.11mV    276.3mV    2.633mV
944.4ps   12.04mV    170.4mV    0V
1.195ns   6.174mV    75.81mV    0V
1.546ns   3.938mV    9.901mV    0V
2.63ns    0V         3.716mV    0V
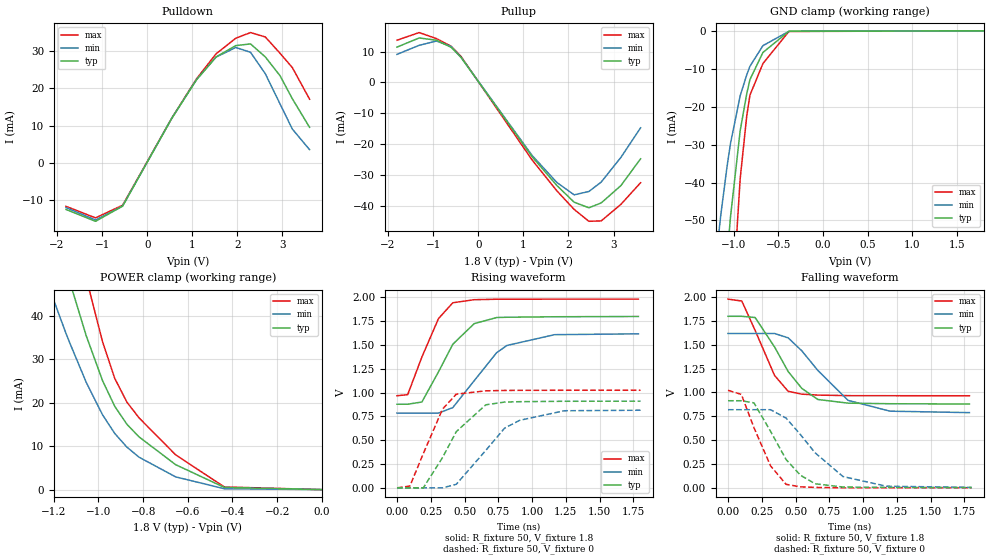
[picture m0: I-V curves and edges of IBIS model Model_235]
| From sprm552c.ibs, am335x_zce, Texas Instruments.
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| Model based on original model for BCSHTLTCSCDVPBFZ_SSDHV
|   Sub model SR10_8MA_10PER_1P8
[model]   Model_235
|[Description]  [1.8V-3-STATE-NOTERM-SR10:8MA, IND, 10%]
|   Fast slew rate (SR[1:0] = "10"), 1.00 * RExt = 1.000 * Iout
|   (I[2:0] = "011"), 8mA nominal with Rext = 50R,ODT off (ODT[1:0]
|   = "00") CMOS mode,Industrial temperature range (-40C to 125C,
|   25C nominal),10% power supply tolerance
|[Input Load]   NOTERM
|[Output Drive] SR10:8MA
|Voltage   1.8V
|Mode   3-STATE
Model_type   3-state
Polarity   Non-Inverting
Enable   Active-Low
Cref =  15pF
Rref =  100.0000M
Vref =  0V
Vmeas =  0.9
C_comp   1.851324p   1.663768p   1.973575p
[Temperature Range]   25   125   -40
[Voltage Range]   1.8   1.62   1.98
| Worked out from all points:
|   slope of the pulldown table from 0 to 0.27 V, typ, clamps not added: 44.4 ohm
|   slope of the pullup table from 0 to 0.27 V, typ, clamps not added: 47 ohm
|   GND clamp passes 1 mA (typ) near -0.49 V on its own axis
|   POWER clamp passes 1 mA (typ) near -0.47 V on its own axis
|   rising waveform, R_fixture 50, V_fixture 1.8: 20-80 % time 223ps typ, 287ps min, 171ps max; typ from 0.877 V to 1.8 V
|   rising waveform, R_fixture 50, V_fixture 0: 20-80 % time 233ps typ, 297ps min, 181ps max; typ from 0 V to 0.909 V
|   falling waveform, R_fixture 50, V_fixture 1.8: 20-80 % time 245ps typ, 306ps min, 181ps max; typ from 1.8 V to 0.879 V
|   falling waveform, R_fixture 50, V_fixture 0: 20-80 % time 239ps typ, 299ps min, 181ps max; typ from 0.914 V to 0.003 V
[POWER_clamp]
-1.8V     194.9mA    137.1mA    262.8mA
-1.236V   68.49mA    48.51mA    92.67mA
-1.145V   50.76mA    35.86mA    69.65mA
-1.127V   47.56mA    33.54mA    65.34mA
-1.055V   35.4mA     24.69mA    48.69mA
-981.8mV  25.06mA    17.2mA     34.01mA
-927.3mV  19.17mA    12.93mA    25.61mA
-872.7mV  15.03mA    9.767mA    20.12mA
-818.2mV  12.12mA    7.45mA     16.5mA
-654.5mV  5.738mA    2.93mA     8.003mA
-436.4mV  508.2uA    199.4uA    613uA
0V        2.273nA    15.95nA    16.67nA
[Pulldown]
-1.8V     -12.51mA   -12.01mA   -11.68mA
-1.145V   -15.69mA   -15.35mA   -14.77mA
-545.5mV  -11.63mA   -11.6mA    -11.38mA
545.5mV   11.95mA    11.95mA    12mA
1.091V    22.23mA    22.28mA    22.49mA
1.527V    28.41mA    28.35mA    29.24mA
1.964V    31.44mA    30.94mA    33.42mA
2.291V    31.9mA     29.65mA    34.94mA
2.618V    28.42mA    23.91mA    33.77mA
2.945V    23.37mA    15.81mA    29.39mA
3.218V    17.19mA    9.044mA    25.55mA
3.6V      9.513mA    3.534mA    17.07mA
[Pullup]
-1.8V     11.43mA    9.077mA    13.67mA
-1.309V   14.4mA     12.01mA    16.15mA
-927.3mV  13.68mA    13.39mA    14.2mA
-600mV    11.36mA    11.67mA    11.72mA
-381.8mV  8.135mA    8.127mA    8.423mA
1.2V      -24.2mA    -23.8mA    -25.27mA
1.745V    -33.47mA   -32.48mA   -35.2mA
2.127V    -38.87mA   -36.49mA   -41.21mA
2.455V    -40.69mA   -35.39mA   -45.07mA
2.727V    -39.11mA   -32.35mA   -44.94mA
3.164V    -33.5mA    -24.34mA   -39.58mA
3.6V      -24.8mA    -14.75mA   -32.56mA
[GND_clamp]
-1.8V     -346.1mA   -209.3mA   -568.3mA
-1.327V   -149.7mA   -89.03mA   -250.9mA
-1.291V   -135.6mA   -80.47mA   -227.5mA
-1.145V   -82.35mA   -48.67mA   -137.7mA
-1.073V   -59.44mA   -35.55mA   -97.96mA
-1.036V   -49.1mA    -29.72mA   -79.9mA
-927.3mV  -26.31mA   -17.11mA   -38.99mA
-854.5mV  -16.67mA   -11.64mA   -22.56mA
-818.2mV  -12.86mA   -9.351mA   -16.98mA
-672.7mV  -5.705mA   -3.913mA   -8.624mA
-381.8mV  -120.4uA   -129uA     -167.4uA
1.8V      2.273nA    454nA      6.646nA
[Ramp]
dV/dt_f 0.55522578/0.24618505n 0.50263847/0.30874562n 0.60941029/0.18077204n
dV/dt_r 0.54995642/0.23525898n 0.49302498/0.29816955n 0.61549038/0.18155172n
R_load = 50
[Rising Waveform]
R_fixture = 50
V_fixture = 1.8
V_fixture_min = 1.62
V_fixture_max = 1.98
0s        877.3mV    784.2mV    966.6mV
79ps      877.3mV    784.2mV    977.7mV
184.2ps   900.8mV    784.2mV    1.373V
307.1ps   1.217V     784.2mV    1.776V
413.2ps   1.507V     842.2mV    1.942V
571.3ps   1.723V     1.124V     1.974V
738.1ps   1.787V     1.419V     1.979V
814.2ps   1.79V      1.494V     1.979V
1.166ns   1.795V     1.607V     1.98V
1.787ns   1.798V     1.616V     1.98V
[Rising Waveform]
R_fixture = 50
V_fixture = 0
V_fixture_min = 0
V_fixture_max = 0
0s        0V         0V         0V
95.5ps    0V         0V         19.09mV
194.6ps   0V         0V         359.2mV
336.9ps   317.6mV    0V         826.1mV
438.9ps   590.1mV    37.51mV    983.1mV
657.1ps   871.3mV    393.2mV    1.018V
797.1ps   900.3mV    627.3mV    1.022V
908.4ps   904.1mV    708.7mV    1.023V
1.239ns   908.4mV    808.9mV    1.024V
1.803ns   909.2mV    814.5mV    1.024V
[Falling Waveform]
R_fixture = 50
V_fixture = 1.8
V_fixture_min = 1.62
V_fixture_max = 1.98
0s        1.799V     1.619V     1.979V
102.1ps   1.799V     1.619V     1.959V
200.7ps   1.786V     1.619V     1.651V
344.4ps   1.478V     1.619V     1.179V
445.3ps   1.22V      1.573V     1.012V
546.2ps   1.043V     1.437V     982.7mV
665.2ps   926.7mV    1.231V     972.7mV
889ps     888.2mV    917.3mV    967.1mV
1.199ns   882.1mV    804.1mV    966.3mV
1.787ns   879.2mV    788.8mV    965.7mV
[Falling Waveform]
R_fixture = 50
V_fixture = 0
V_fixture_min = 0
V_fixture_max = 0
0s        913.5mV    819.5mV    1.023V
98.6ps    913.5mV    819.5mV    980.1mV
192ps     891.1mV    819.5mV    631.1mV
315.3ps   592.5mV    819.5mV    229.8mV
430.2ps   296.6mV    731.5mV    36.65mV
535.7ps   132.7mV    559.3mV    10.85mV
644.3ps   43.07mV    368.1mV    4.896mV
851.3ps   8.647mV    118.4mV    0V
1.172ns   5.129mV    17.24mV    0V
1.803ns   3.27mV     5.156mV    0V
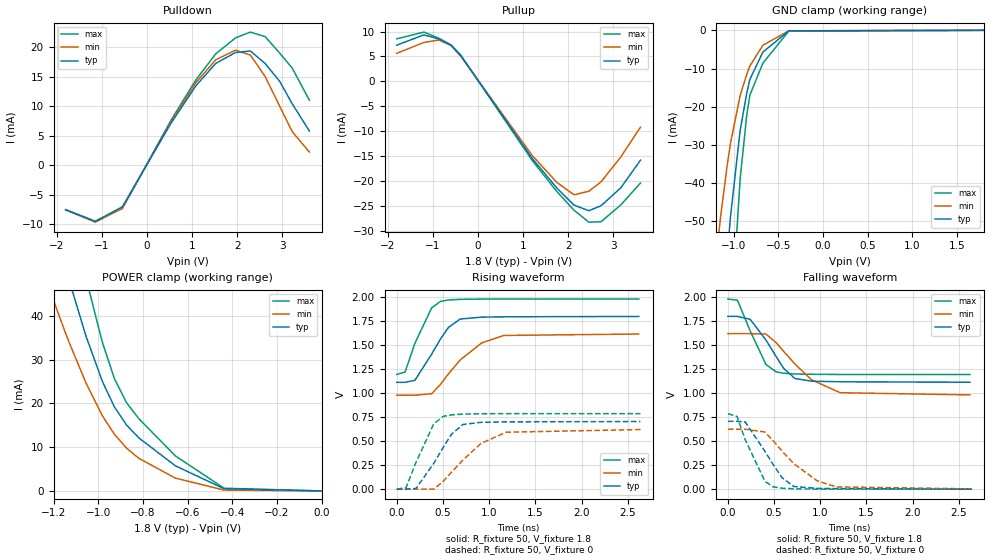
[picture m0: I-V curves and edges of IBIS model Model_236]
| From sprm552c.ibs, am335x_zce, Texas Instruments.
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| Model based on original model for BCSHTLTCSCDVPBFZ_SSDHV
|   Sub model SR10_5MA_10PER_1P8
[model]   Model_236
|[Description]  [1.8V-3-STATE-NOTERM-SR10:5MA, IND, 10%]
|   Fast slew rate (SR[1:0] = "10"), 1.60 * RExt = 0.625 * Iout
|   (I[2:0] = "000"), 5mA nominal with Rext = 50R,ODT off (ODT[1:0]
|   = "00") CMOS mode,Industrial temperature range (-40C to 125C,
|   25C nominal),10% power supply tolerance
|[Input Load]   NOTERM
|[Output Drive] SR10:5MA
|Voltage   1.8V
|Mode   3-STATE
Model_type   3-state
Polarity   Non-Inverting
Enable   Active-Low
Cref =  15pF
Rref =  100.0000M
Vref =  0V
Vmeas =  0.9
C_comp   1.851324p   1.663768p   1.973575p
[Temperature Range]   25   125   -40
[Voltage Range]   1.8   1.62   1.98
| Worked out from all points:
|   slope of the pulldown table from 0 to 0.27 V, typ, clamps not added: 72.9 ohm
|   slope of the pullup table from 0 to 0.27 V, typ, clamps not added: 73.8 ohm
|   GND clamp passes 1 mA (typ) near -0.49 V on its own axis
|   POWER clamp passes 1 mA (typ) near -0.47 V on its own axis
|   rising waveform, R_fixture 50, V_fixture 1.8: 20-80 % time 257ps typ, 374ps min, 198ps max; typ from 1.11 V to 1.8 V
|   rising waveform, R_fixture 50, V_fixture 0: 20-80 % time 266ps typ, 406ps min, 215ps max; typ from 0 V to 0.705 V
|   falling waveform, R_fixture 50, V_fixture 1.8: 20-80 % time 276ps typ, 406ps min, 210ps max; typ from 1.8 V to 1.11 V
|   falling waveform, R_fixture 50, V_fixture 0: 20-80 % time 274ps typ, 398ps min, 212ps max; typ from 0.707 V to 0 V
[POWER_clamp]
-1.8V     194.9mA    137.1mA    262.8mA
-1.236V   68.49mA    48.51mA    92.67mA
-1.145V   50.76mA    35.86mA    69.65mA
-1.127V   47.56mA    33.54mA    65.34mA
-1.055V   35.4mA     24.69mA    48.69mA
-981.8mV  25.06mA    17.2mA     34.01mA
-927.3mV  19.17mA    12.93mA    25.61mA
-872.7mV  15.03mA    9.767mA    20.12mA
-818.2mV  12.12mA    7.45mA     16.5mA
-654.5mV  5.738mA    2.93mA     8.003mA
-436.4mV  508.2uA    199.4uA    613uA
0V        2.273nA    15.95nA    16.67nA
[Pulldown]
-1.8V     -7.609mA   -7.58mA    -7.557mA
-1.145V   -9.551mA   -9.696mA   -9.558mA
-545.5mV  -7.085mA   -7.33mA    -7.364mA
545.5mV   7.279mA    7.552mA    7.771mA
1.091V    13.54mA    14.08mA    14.56mA
1.527V    17.3mA     17.91mA    18.93mA
1.964V    19.14mA    19.54mA    21.63mA
2.291V    19.41mA    18.72mA    22.61mA
2.618V    17.29mA    15.09mA    21.85mA
2.945V    14.21mA    9.977mA    19.01mA
3.218V    10.46mA    5.707mA    16.52mA
3.6V      5.787mA    2.231mA    11.04mA
[Pullup]
-1.8V     7.273mA    5.641mA    8.54mA
-1.2V     9.332mA    7.808mA    9.888mA
-872.7mV  8.52mA     8.305mA    8.682mA
-600mV    7.23mA     7.256mA    7.329mA
-381.8mV  5.181mA    5.056mA    5.268mA
1.2V      -15.41mA   -14.81mA   -15.8mA
1.745V    -21.31mA   -20.2mA    -22.02mA
2.127V    -24.75mA   -22.69mA   -25.77mA
2.455V    -25.89mA   -21.99mA   -28.18mA
2.727V    -24.88mA   -20.1mA    -28.09mA
3.164V    -21.3mA    -15.12mA   -24.72mA
3.6V      -15.77mA   -9.16mA    -20.34mA
[GND_clamp]
-1.8V     -346.1mA   -209.3mA   -568.3mA
-1.327V   -149.7mA   -89.03mA   -250.9mA
-1.291V   -135.6mA   -80.47mA   -227.5mA
-1.145V   -82.35mA   -48.67mA   -137.7mA
-1.073V   -59.44mA   -35.55mA   -97.96mA
-1.036V   -49.1mA    -29.72mA   -79.9mA
-927.3mV  -26.31mA   -17.11mA   -38.99mA
-854.5mV  -16.67mA   -11.64mA   -22.56mA
-818.2mV  -12.86mA   -9.351mA   -16.98mA
-672.7mV  -5.705mA   -3.913mA   -8.624mA
-381.8mV  -120.4uA   -129uA     -167.4uA
1.8V      2.273nA    454nA      6.646nA
[Ramp]
dV/dt_f 0.41354561/0.27672366n 0.38602695/0.409565n  0.47205584/0.21033162n
dV/dt_r 0.42533433/0.26789438n 0.37563772/0.40987177n 0.47288958/0.2154271n
R_load = 50
[Rising Waveform]
R_fixture = 50
V_fixture = 1.8
V_fixture_min = 1.62
V_fixture_max = 1.98
0s        1.113V     978.4mV    1.195V
89.8ps    1.113V     978.4mV    1.22V
196.1ps   1.134V     978.4mV    1.52V
377ps     1.406V     994.4mV    1.888V
473.4ps   1.565V     1.092V     1.956V
558.7ps   1.684V     1.2V       1.97V
685.8ps   1.772V     1.346V     1.977V
918.4ps   1.792V     1.523V     1.98V
1.16ns    1.795V     1.601V     1.98V
2.62ns    1.799V     1.616V     1.98V
[Rising Waveform]
R_fixture = 50
V_fixture = 0
V_fixture_min = 0
V_fixture_max = 0
0s        0V         0V         0V
99.7ps    0V         0V         15.83mV
207.8ps   7.598mV    0V         279.5mV
400.1ps   269.4mV    0V         680.9mV
503.8ps   437.7mV    83.04mV    758.8mV
593.2ps   573.7mV    178.3mV    773.9mV
716ps     674mV      303.1mV    781.5mV
911.7ps   696.2mV    476.9mV    785.4mV
1.184ns   700.7mV    593.3mV    786.6mV
2.638ns   704.5mV    620.9mV    786.9mV
[Falling Waveform]
R_fixture = 50
V_fixture = 1.8
V_fixture_min = 1.62
V_fixture_max = 1.98
0s        1.799V     1.619V     1.979V
103.6ps   1.799V     1.619V     1.967V
241.1ps   1.768V     1.619V     1.647V
411.4ps   1.553V     1.615V     1.299V
521.1ps   1.382V     1.526V     1.221V
605ps     1.256V     1.433V     1.207V
725.1ps   1.152V     1.303V     1.199V
905.7ps   1.124V     1.138V     1.196V
1.216ns   1.118V     1.004V     1.194V
2.62ns    1.113V     981.2mV    1.194V
[Falling Waveform]
R_fixture = 50
V_fixture = 0
V_fixture_min = 0
V_fixture_max = 0
0s        706.8mV    624.3mV    786mV
98.8ps    706.8mV    624.3mV    757.4mV
186.7ps   700.6mV    624.3mV    515.2mV
400.3ps   394.9mV    595.1mV    83.08mV
488.1ps   258.9mV    505.1mV    24.4mV
587.1ps   118mV      395.8mV    9.692mV
712.3ps   27.93mV    266.6mV    4.154mV
964.8ps   8.185mV    87.52mV    0V
1.174ns   5.917mV    23.45mV    0V
2.638ns   0V         3.068mV    0V
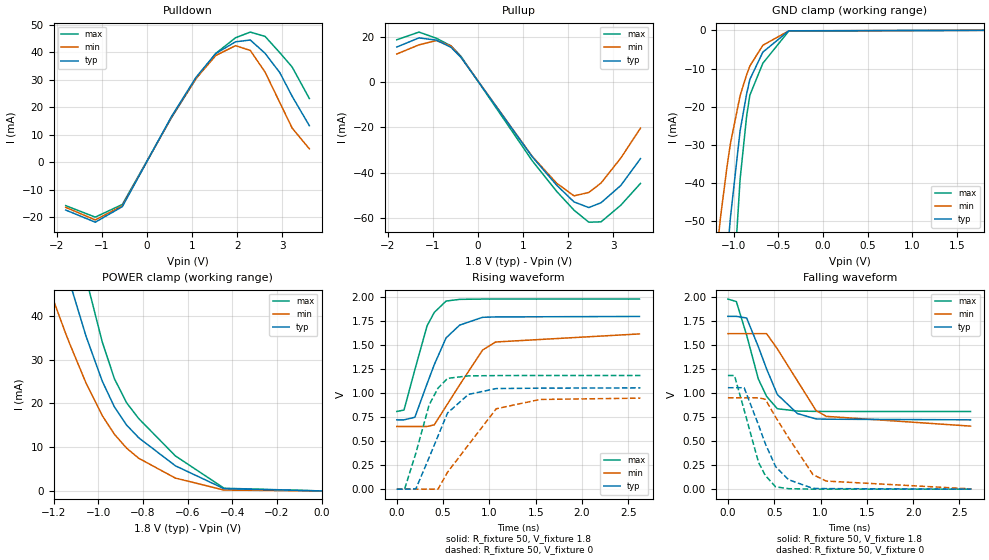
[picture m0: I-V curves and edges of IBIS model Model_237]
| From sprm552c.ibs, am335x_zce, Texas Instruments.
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| Model based on original model for BCSHTLTCSCDVPBFZ_SSDHV
|   Sub model SR11_11MA_10PER_1P8
[model]   Model_237
|[Description]  [1.8V-3-STATE-NOTERM-SR11:11MA, IND, 10%]
|   Slowest slew rate (SR[1:0] = "11"), 0.73 * RExt = 1.325 * Iout
|   (I[2:0] = "110"), 11mA nominal with Rext = 50R,ODT off (ODT[1:0]
|   = "00") CMOS mode,Industrial temperature range (-40C to 125C,
|   25C nominal),10% power supply tolerance
|[Input Load]   NOTERM
|[Output Drive] SR11:11MA
|Voltage   1.8V
|Mode   3-STATE
Model_type   3-state
Polarity   Non-Inverting
Enable   Active-Low
Cref =  15pF
Rref =  100.0000M
Vref =  0V
Vmeas =  0.9
C_comp   1.851324p   1.663768p   1.973575p
[Temperature Range]   25   125   -40
[Voltage Range]   1.8   1.62   1.98
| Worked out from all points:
|   slope of the pulldown table from 0 to 0.27 V, typ, clamps not added: 32 ohm
|   slope of the pullup table from 0 to 0.27 V, typ, clamps not added: 34.5 ohm
|   GND clamp passes 1 mA (typ) near -0.49 V on its own axis
|   POWER clamp passes 1 mA (typ) near -0.47 V on its own axis
|   rising waveform, R_fixture 50, V_fixture 1.8: 20-80 % time 264ps typ, 394ps min, 209ps max; typ from 0.722 V to 1.8 V
|   rising waveform, R_fixture 50, V_fixture 0: 20-80 % time 280ps typ, 395ps min, 222ps max; typ from 0 V to 1.05 V
|   falling waveform, R_fixture 50, V_fixture 1.8: 20-80 % time 269ps typ, 365ps min, 217ps max; typ from 1.8 V to 0.722 V
|   falling waveform, R_fixture 50, V_fixture 0: 20-80 % time 261ps typ, 395ps min, 211ps max; typ from 1.06 V to 0 V
[POWER_clamp]
-1.8V     194.9mA    137.1mA    262.8mA
-1.236V   68.49mA    48.51mA    92.67mA
-1.145V   50.76mA    35.86mA    69.65mA
-1.127V   47.56mA    33.54mA    65.34mA
-1.055V   35.4mA     24.69mA    48.69mA
-981.8mV  25.06mA    17.2mA     34.01mA
-927.3mV  19.17mA    12.93mA    25.61mA
-872.7mV  15.03mA    9.767mA    20.12mA
-818.2mV  12.12mA    7.45mA     16.5mA
-654.5mV  5.738mA    2.93mA     8.003mA
-436.4mV  508.2uA    199.4uA    613uA
0V        2.273nA    15.95nA    16.67nA
[Pulldown]
-1.8V     -17.41mA   -16.43mA   -15.81mA
-1.145V   -21.83mA   -21.01mA   -19.99mA
-545.5mV  -16.18mA   -15.87mA   -15.39mA
545.5mV   16.61mA    16.34mA    16.22mA
1.091V    30.91mA    30.47mA    30.41mA
1.527V    39.51mA    38.78mA    39.54mA
1.964V    43.74mA    42.34mA    45.21mA
2.291V    44.39mA    40.59mA    47.27mA
2.618V    39.56mA    32.74mA    45.71mA
2.945V    32.54mA    21.66mA    39.78mA
3.218V    23.95mA    12.39mA    34.58mA
3.6V      13.24mA    4.837mA    23.12mA
[Pullup]
-1.8V     15.59mA    12.51mA    18.8mA
-1.309V   19.63mA    16.55mA    22.2mA
-927.3mV  18.65mA    18.46mA    19.52mA
-600mV    15.48mA    16.08mA    16.11mA
-381.8mV  11.09mA    11.19mA    11.57mA
1.2V      -32.98mA   -32.79mA   -34.72mA
1.745V    -45.62mA   -44.74mA   -48.37mA
2.127V    -52.98mA   -50.3mA    -56.63mA
2.455V    -55.48mA   -48.79mA   -61.96mA
2.727V    -53.34mA   -44.61mA   -61.81mA
3.164V    -45.71mA   -33.58mA   -54.45mA
3.6V      -33.84mA   -20.34mA   -44.81mA
[GND_clamp]
-1.8V     -346.1mA   -209.3mA   -568.3mA
-1.327V   -149.7mA   -89.03mA   -250.9mA
-1.291V   -135.6mA   -80.47mA   -227.5mA
-1.145V   -82.35mA   -48.67mA   -137.7mA
-1.073V   -59.44mA   -35.55mA   -97.96mA
-1.036V   -49.1mA    -29.72mA   -79.9mA
-927.3mV  -26.31mA   -17.11mA   -38.99mA
-854.5mV  -16.67mA   -11.64mA   -22.56mA
-818.2mV  -12.86mA   -9.351mA   -16.98mA
-672.7mV  -5.705mA   -3.913mA   -8.624mA
-381.8mV  -120.4uA   -129uA     -167.4uA
1.8V      2.273nA    454nA      6.646nA
[Ramp]
dV/dt_f 0.64948398/0.27004967n 0.58346209/0.36447398n 0.70436213/0.21794224n
dV/dt_r 0.63643688/0.28121778n 0.57514668/0.40454785n 0.71210457/0.22278816n
R_load = 50
[Rising Waveform]
R_fixture = 50
V_fixture = 1.8
V_fixture_min = 1.62
V_fixture_max = 1.98
0s        722mV      652.9mV    809.4mV
77.7ps    722mV      652.9mV    823.9mV
195.3ps   749.3mV    652.9mV    1.246V
326.8ps   1.098V     652.9mV    1.701V
404.6ps   1.297V     670.4mV    1.841V
532.1ps   1.576V     863.9mV    1.959V
679.1ps   1.709V     1.087V     1.977V
926.4ps   1.79V      1.449V     1.98V
1.067ns   1.794V     1.533V     1.98V
2.62ns    1.799V     1.617V     1.98V
[Rising Waveform]
R_fixture = 50
V_fixture = 0
V_fixture_min = 0
V_fixture_max = 0
0s        0V         0V         0V
83.7ps    0V         0V         0V
205.1ps   2.34mV     0V         373.5mV
348.6ps   328.6mV    0V         876.8mV
444.6ps   553.4mV    0V         1.052V
547.6ps   793.1mV    175.9mV    1.154V
773ps     986.8mV    460.9mV    1.18V
1.074ns   1.048V     837.7mV    1.183V
1.546ns   1.052V     934.2mV    1.184V
2.631ns   1.055V     948.2mV    1.184V
[Falling Waveform]
R_fixture = 50
V_fixture = 1.8
V_fixture_min = 1.62
V_fixture_max = 1.98
0s        1.799V     1.619V     1.979V
91ps      1.799V     1.619V     1.953V
202.1ps   1.782V     1.619V     1.603V
328.8ps   1.482V     1.619V     1.146V
417.5ps   1.252V     1.619V     966.1mV
533.4ps   985.4mV    1.461V     837.5mV
751.4ps   786.9mV    1.126V     812.9mV
950.4ps   731.4mV    819.8mV    809.6mV
1.062ns   728.4mV    757.9mV    809mV
2.62ns    721.8mV    656.4mV    808.4mV
[Falling Waveform]
R_fixture = 50
V_fixture = 0
V_fixture_min = 0
V_fixture_max = 0
0s        1.056V     951.4mV    1.183V
71ps      1.056V     951.4mV    1.183V
175.4ps   1.056V     951.4mV    823.7mV
330.4ps   668mV      951.4mV    279.1mV
403.3ps   474.8mV    935.9mV    143.5mV
515.2ps   234.6mV    750.4mV    24.15mV
654.8ps   98.59mV    534.2mV    5.005mV
918.4ps   8.185mV    151.2mV    0V
1.061ns   5.603mV    84.34mV    0V
2.631ns   0V         2.591mV    0V
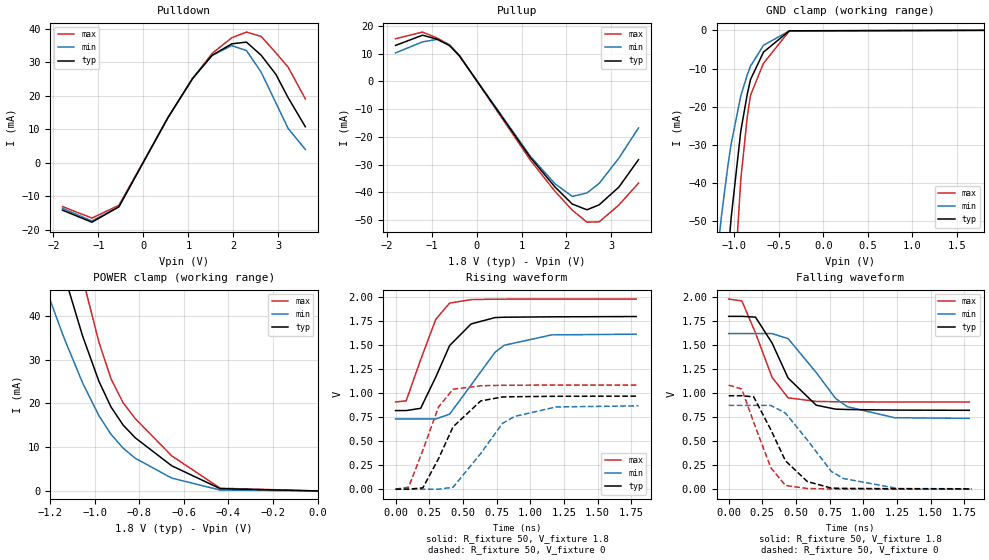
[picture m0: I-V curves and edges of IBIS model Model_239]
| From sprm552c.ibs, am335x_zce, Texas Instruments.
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| Model based on original model for BCSHTLTCSCDVPBFZ_SSDHV
|   Sub model SR10_9MA_10PER_1P8
[model]   Model_239
|[Description]  [1.8V-3-STATE-NOTERM-SR10:9MA, IND, 10%]
|   Fast slew rate (SR[1:0] = "10"), 0.88 * RExt = 1.125 * Iout
|   (I[2:0] = "100"), 9mA nominal with Rext = 50R,ODT off (ODT[1:0]
|   = "00") CMOS mode,Industrial temperature range (-40C to 125C,
|   25C nominal),10% power supply tolerance
|[Input Load]   NOTERM
|[Output Drive] SR10:9MA
|Voltage   1.8V
|Mode   3-STATE
Model_type   3-state
Polarity   Non-Inverting
Enable   Active-Low
Cref =  15pF
Rref =  100.0000M
Vref =  0V
Vmeas =  0.9
C_comp   1.851324p   1.663768p   1.973575p
[Temperature Range]   25   125   -40
[Voltage Range]   1.8   1.62   1.98
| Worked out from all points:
|   slope of the pulldown table from 0 to 0.27 V, typ, clamps not added: 39.3 ohm
|   slope of the pullup table from 0 to 0.27 V, typ, clamps not added: 41.3 ohm
|   GND clamp passes 1 mA (typ) near -0.49 V on its own axis
|   POWER clamp passes 1 mA (typ) near -0.47 V on its own axis
|   rising waveform, R_fixture 50, V_fixture 1.8: 20-80 % time 205ps typ, 275ps min, 162ps max; typ from 0.819 V to 1.8 V
|   rising waveform, R_fixture 50, V_fixture 0: 20-80 % time 221ps typ, 277ps min, 165ps max; typ from 0 V to 0.969 V
|   falling waveform, R_fixture 50, V_fixture 1.8: 20-80 % time 226ps typ, 293ps min, 175ps max; typ from 1.8 V to 0.821 V
|   falling waveform, R_fixture 50, V_fixture 0: 20-80 % time 220ps typ, 287ps min, 171ps max; typ from 0.973 V to 0.003 V
[POWER_clamp]
-1.8V     194.9mA    137.1mA    262.8mA
-1.236V   68.49mA    48.51mA    92.67mA
-1.145V   50.76mA    35.86mA    69.65mA
-1.127V   47.56mA    33.54mA    65.34mA
-1.055V   35.4mA     24.69mA    48.69mA
-981.8mV  25.06mA    17.2mA     34.01mA
-927.3mV  19.17mA    12.93mA    25.61mA
-872.7mV  15.03mA    9.767mA    20.12mA
-818.2mV  12.12mA    7.45mA     16.5mA
-654.5mV  5.738mA    2.93mA     8.003mA
-436.4mV  508.2uA    199.4uA    613uA
0V        2.273nA    15.95nA    16.67nA
[Pulldown]
-1.8V     -14.14mA   -13.59mA   -13.06mA
-1.145V   -17.74mA   -17.37mA   -16.51mA
-545.5mV  -13.15mA   -13.12mA   -12.71mA
545.5mV   13.5mA     13.52mA    13.41mA
1.091V    25.12mA    25.21mA    25.13mA
1.527V    32.11mA    32.07mA    32.67mA
1.964V    35.54mA    35.01mA    37.35mA
2.291V    36.06mA    33.55mA    39.05mA
2.618V    32.13mA    27.06mA    37.75mA
2.945V    26.42mA    17.9mA     32.85mA
3.218V    19.44mA    10.24mA    28.56mA
3.6V      10.76mA    3.999mA    19.09mA
[Pullup]
-1.8V     12.99mA    10.3mA     15.38mA
-1.2V     16.67mA    14.26mA    17.79mA
-872.7mV  15.21mA    15.17mA    15.62mA
-600mV    12.91mA    13.24mA    13.19mA
-381.8mV  9.242mA    9.222mA    9.473mA
1.2V      -27.49mA   -27.01mA   -28.42mA
1.745V    -38.03mA   -36.86mA   -39.59mA
2.127V    -44.16mA   -41.42mA   -46.35mA
2.455V    -46.24mA   -40.18mA   -50.71mA
2.727V    -44.44mA   -36.72mA   -50.57mA
3.164V    -38.07mA   -27.64mA   -44.53mA
3.6V      -28.19mA   -16.75mA   -36.64mA
[GND_clamp]
-1.8V     -346.1mA   -209.3mA   -568.3mA
-1.327V   -149.7mA   -89.03mA   -250.9mA
-1.291V   -135.6mA   -80.47mA   -227.5mA
-1.145V   -82.35mA   -48.67mA   -137.7mA
-1.073V   -59.44mA   -35.55mA   -97.96mA
-1.036V   -49.1mA    -29.72mA   -79.9mA
-927.3mV  -26.31mA   -17.11mA   -38.99mA
-854.5mV  -16.67mA   -11.64mA   -22.56mA
-818.2mV  -12.86mA   -9.351mA   -16.98mA
-672.7mV  -5.705mA   -3.913mA   -8.624mA
-381.8mV  -120.4uA   -129uA     -167.4uA
1.8V      2.273nA    454nA      6.646nA
[Ramp]
dV/dt_f 0.59054759/0.22782826n 0.53446276/0.29596672n 0.64468056/0.17582947n
dV/dt_r 0.58548182/0.22328266n 0.52524472/0.2777954n 0.65155097/0.16561989n
R_load = 50
[Rising Waveform]
R_fixture = 50
V_fixture = 1.8
V_fixture_min = 1.62
V_fixture_max = 1.98
0s        818.8mV    731.8mV    908mV
79.1ps    818.8mV    731.8mV    920.5mV
186.4ps   842mV      731.8mV    1.348V
299.1ps   1.169V     731.8mV    1.77V
401.7ps   1.496V     781.1mV    1.938V
561ps     1.721V     1.085V     1.974V
738.8ps   1.787V     1.426V     1.979V
807.4ps   1.791V     1.499V     1.979V
1.16ns    1.795V     1.607V     1.98V
1.787ns   1.798V     1.614V     1.98V
[Rising Waveform]
R_fixture = 50
V_fixture = 0
V_fixture_min = 0
V_fixture_max = 0
0s        0V         0V         0V
97.1ps    0V         0V         20.8mV
202.7ps   13.89mV    0V         404.5mV
319.1ps   317.4mV    0V         856.3mV
426.8ps   648.9mV    19.69mV    1.041V
632.2ps   918.9mV    370.5mV    1.077V
793ps     960.1mV    683.9mV    1.082V
883.9ps   963mV      757.6mV    1.083V
1.192ns   967.4mV    856.4mV    1.084V
1.804ns   968.9mV    867.7mV    1.084V
[Falling Waveform]
R_fixture = 50
V_fixture = 1.8
V_fixture_min = 1.62
V_fixture_max = 1.98
0s        1.799V     1.62V      1.979V
97.8ps    1.799V     1.62V      1.96V
199ps     1.791V     1.62V      1.627V
322ps     1.522V     1.62V      1.165V
441.4ps   1.157V     1.567V     950.8mV
650.2ps   874.2mV    1.214V     913.7mV
794ps     833.1mV    944mV      910mV
881.8ps   829.2mV    858.2mV    909mV
1.232ns   823mV      743.8mV    907.2mV
1.787ns   821.1mV    737mV      907.1mV
[Falling Waveform]
R_fixture = 50
V_fixture = 0
V_fixture_min = 0
V_fixture_max = 0
0s        972.5mV    872.1mV    1.083V
97ps      972.5mV    872.1mV    1.043V
185.7ps   960.9mV    872.1mV    696.1mV
312.1ps   621.8mV    872.1mV    225.8mV
421.4ps   295.7mV    792.3mV    38.46mV
584.1ps   79.33mV    512.2mV    6.773mV
762.2ps   11.26mV    184.5mV    2.247mV
852.7ps   8.13mV     110.4mV    0V
1.258ns   4.389mV    6.439mV    0V
1.804ns   2.877mV    4.132mV    0V
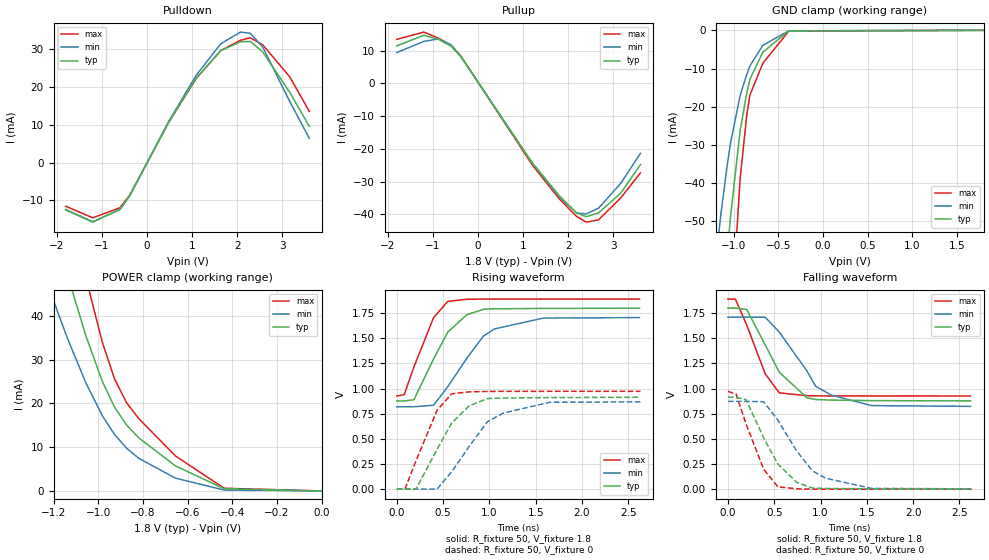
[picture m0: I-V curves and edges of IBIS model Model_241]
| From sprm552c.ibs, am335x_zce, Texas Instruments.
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| Model based on original model for BCSHTLTCSCDVPBFZ_SSDHV
|   Sub model SR11_8MA_5PER_1P8
[model]   Model_241
|[Description]  [1.8V-3-STATE-NOTERM-SR11:8MA, IND, 5%]
|   Slowest slew rate (SR[1:0] = "11"), 1.00 * RExt = 1.000 * Iout
|   (I[2:0] = "011"), 8mA nominal with Rext = 50R,ODT off (ODT[1:0]
|   = "00") CMOS mode,Industrial temperature range (-40C to 125C,
|   25C nominal),5% power supply tolerance
|[Input Load]   NOTERM
|[Output Drive] SR11:8MA
|Voltage   1.8V
|Mode   3-STATE
Model_type   3-state
Polarity   Non-Inverting
Enable   Active-Low
Cref =  15pF
Rref =  100.0000M
Vref =  0V
Vmeas =  0.9
C_comp   1.851324p   1.667199p   1.973575p
[Temperature Range]   25   125   -40
[Voltage Range]   1.8   1.71   1.89
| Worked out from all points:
|   slope of the pulldown table from 0 to 0.27 V, typ, clamps not added: 44.4 ohm
|   slope of the pullup table from 0 to 0.27 V, typ, clamps not added: 47 ohm
|   GND clamp passes 1 mA (typ) near -0.49 V on its own axis
|   POWER clamp passes 1 mA (typ) near -0.47 V on its own axis
|   rising waveform, R_fixture 50, V_fixture 1.8: 20-80 % time 319ps typ, 414ps min, 241ps max; typ from 0.877 V to 1.8 V
|   rising waveform, R_fixture 50, V_fixture 0: 20-80 % time 343ps typ, 417ps min, 259ps max; typ from 0 V to 0.913 V
|   falling waveform, R_fixture 50, V_fixture 1.8: 20-80 % time 337ps typ, 404ps min, 240ps max; typ from 1.8 V to 0.877 V
|   falling waveform, R_fixture 50, V_fixture 0: 20-80 % time 324ps typ, 395ps min, 238ps max; typ from 0.914 V to 0 V
[POWER_clamp]
-1.8V     194.9mA    137mA      262.9mA
-1.236V   68.49mA    48.49mA    92.7mA
-1.145V   50.76mA    35.84mA    69.67mA
-1.127V   47.56mA    33.52mA    65.35mA
-1.055V   35.4mA     24.68mA    48.7mA
-981.8mV  25.06mA    17.19mA    34.02mA
-927.3mV  19.17mA    12.92mA    25.62mA
-872.7mV  15.03mA    9.76mA     20.13mA
-818.2mV  12.12mA    7.445mA    16.51mA
-654.5mV  5.738mA    2.929mA    8.007mA
-436.4mV  508.2uA    199.4uA    613uA
0V        2.273nA    16.6nA     10.58nA
[Pulldown]
-1.8V     -12.51mA   -12.38mA   -11.51mA
-1.2V     -15.72mA   -15.57mA   -14.57mA
-600mV    -12.32mA   -12.45mA   -11.92mA
-381.8mV  -8.686mA   -8.794mA   -8.605mA
490.9mV   10.82mA    11.01mA    10.76mA
1.091V    22.23mA    22.98mA    22.12mA
1.636V    29.48mA    31.29mA    29.5mA
2.073V    31.82mA    34.37mA    32.21mA
2.291V    31.9mA     34.04mA    32.88mA
2.564V    29.16mA    30.5mA     31.05mA
3.164V    18.55mA    16.11mA    22.6mA
3.6V      9.513mA    6.35mA     13.45mA
[Pullup]
-1.8V     11.43mA    9.39mA     13.42mA
-1.2V     14.67mA    12.8mA     15.64mA
-872.7mV  13.39mA    13.55mA    13.76mA
-600mV    11.36mA    11.8mA     11.63mA
-381.8mV  8.135mA    8.218mA    8.363mA
1.2V      -24.2mA    -24.42mA   -24.89mA
1.8V      -34.31mA   -34.68mA   -35.27mA
2.182V    -39.52mA   -39.59mA   -40.61mA
2.4V      -40.73mA   -39.88mA   -42.4mA
2.673V    -39.55mA   -38.08mA   -41.67mA
3.164V    -33.5mA    -30.53mA   -34.96mA
3.6V      -24.8mA    -21.38mA   -27.34mA
[GND_clamp]
-1.8V     -346.1mA   -209.3mA   -568.3mA
-1.327V   -149.7mA   -89.03mA   -250.9mA
-1.291V   -135.6mA   -80.47mA   -227.5mA
-1.145V   -82.35mA   -48.67mA   -137.7mA
-1.073V   -59.44mA   -35.55mA   -97.96mA
-1.036V   -49.1mA    -29.72mA   -79.9mA
-927.3mV  -26.31mA   -17.11mA   -38.99mA
-854.5mV  -16.67mA   -11.64mA   -22.56mA
-818.2mV  -12.86mA   -9.351mA   -16.98mA
-672.7mV  -5.705mA   -3.913mA   -8.623mA
-381.8mV  -120.4uA   -129uA     -167.2uA
1.8V      2.273nA    51.44nA    6.654nA
[Ramp]
dV/dt_f 0.55561201/0.33799142n  0.5364774/0.40792544n 0.57945619/0.24153227n
dV/dt_r 0.55057634/0.34553504n 0.52614016/0.42161621n 0.58492851/0.25945573n
R_load = 50
[Rising Waveform]
R_fixture = 50
V_fixture = 1.8
V_fixture_min = 1.71
V_fixture_max = 1.89
0s        877.3mV    819.4mV    926.9mV
79.9ps    877.3mV    819.4mV    939mV
184.6ps   888.9mV    819.4mV    1.215V
397.4ps   1.296V     834.2mV    1.706V
550.3ps   1.561V     1.019V     1.867V
755.6ps   1.734V     1.301V     1.888V
936.6ps   1.789V     1.523V     1.89V
1.054ns   1.793V     1.593V     1.89V
1.583ns   1.797V     1.701V     1.89V
2.62ns    1.799V     1.706V     1.89V
[Rising Waveform]
R_fixture = 50
V_fixture = 0
V_fixture_min = 0
V_fixture_max = 0
0s        0V         0V         0V
87.3ps    0V         0V         0V
206.7ps   0V         0V         280.5mV
433.6ps   393.9mV    0V         783.1mV
592.2ps   657.9mV    172.1mV    948.4mV
783ps     830mV      427.3mV    967.7mV
978.7ps   900.5mV    670.9mV    971.4mV
1.15ns    906mV      756.4mV    972.3mV
1.652ns   910.6mV    863.9mV    972.6mV
2.631ns   913.4mV    868.1mV    972.7mV
[Falling Waveform]
R_fixture = 50
V_fixture = 1.8
V_fixture_min = 1.71
V_fixture_max = 1.89
0s        1.799V     1.709V     1.889V
80.7ps    1.799V     1.709V     1.889V
203.4ps   1.785V     1.709V     1.63V
402.5ps   1.434V     1.709V     1.146V
554.4ps   1.162V     1.561V     957.4mV
853.1ps   908.5mV    1.175V     928.8mV
947.1ps   890.9mV    1.023V     927.4mV
1.115ns   885.1mV    934.9mV    926.6mV
1.553ns   880mV      830.2mV    926.2mV
2.62ns    877.2mV    822.7mV    926mV
[Falling Waveform]
R_fixture = 50
V_fixture = 0
V_fixture_min = 0
V_fixture_max = 0
0s        913.5mV    872.6mV    971.7mV
88.3ps    913.5mV    872.6mV    944.3mV
195.3ps   889.2mV    872.6mV    649mV
385.3ps   510.9mV    868.9mV    199.3mV
538.6ps   250.8mV    686.6mV    23.58mV
742ps     67.86mV    380.4mV    3.712mV
911.8ps   11.46mV    182mV      0V
1.052ns   6.924mV    110mV      0V
1.55ns    3.494mV    7.546mV    0V
2.631ns   0V         3.423mV    0V
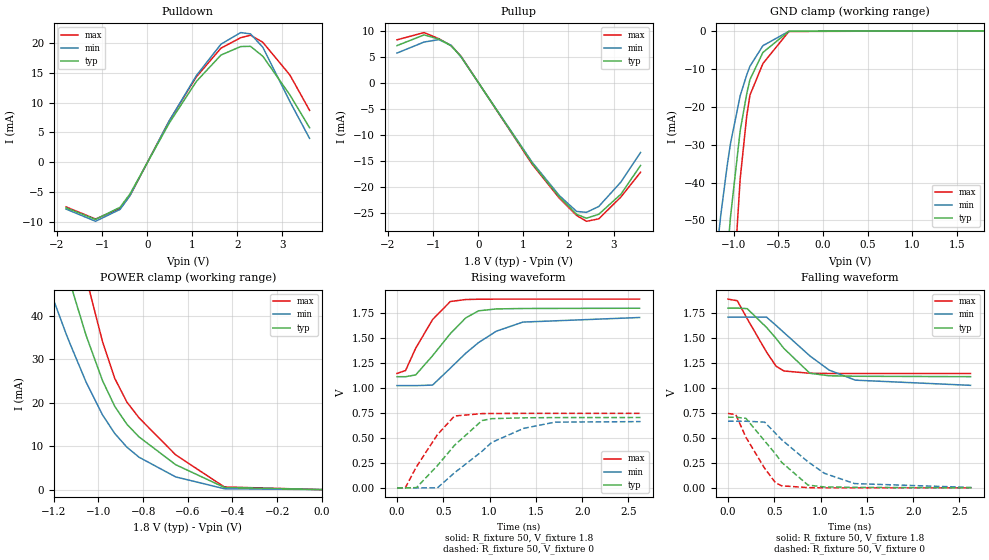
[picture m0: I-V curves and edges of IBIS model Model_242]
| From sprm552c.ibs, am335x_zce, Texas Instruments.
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| Model based on original model for BCSHTLTCSCDVPBFZ_SSDHV
|   Sub model SR11_5MA_5PER_1P8
[model]   Model_242
|[Description]  [1.8V-3-STATE-NOTERM-SR11:5MA, IND, 5%]
|   Slowest slew rate (SR[1:0] = "11"), 1.60 * RExt = 0.625 * Iout
|   (I[2:0] = "000"), 5mA nominal with Rext = 50R,ODT off (ODT[1:0]
|   = "00") CMOS mode,Industrial temperature range (-40C to 125C,
|   25C nominal),5% power supply tolerance
|[Input Load]   NOTERM
|[Output Drive] SR11:5MA
|Voltage   1.8V
|Mode   3-STATE
Model_type   3-state
Polarity   Non-Inverting
Enable   Active-Low
Cref =  15pF
Rref =  100.0000M
Vref =  0V
Vmeas =  0.9
C_comp   1.851324p   1.667199p   1.973575p
[Temperature Range]   25   125   -40
[Voltage Range]   1.8   1.71   1.89
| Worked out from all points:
|   slope of the pulldown table from 0 to 0.27 V, typ, clamps not added: 72.9 ohm
|   slope of the pullup table from 0 to 0.27 V, typ, clamps not added: 73.8 ohm
|   GND clamp passes 1 mA (typ) near -0.49 V on its own axis
|   POWER clamp passes 1 mA (typ) near -0.47 V on its own axis
|   rising waveform, R_fixture 50, V_fixture 1.8: 20-80 % time 377ps typ, 535ps min, 277ps max; typ from 1.11 V to 1.8 V
|   rising waveform, R_fixture 50, V_fixture 0: 20-80 % time 393ps typ, 591ps min, 309ps max; typ from 0 V to 0.705 V
|   falling waveform, R_fixture 50, V_fixture 1.8: 20-80 % time 368ps typ, 559ps min, 279ps max; typ from 1.8 V to 1.11 V
|   falling waveform, R_fixture 50, V_fixture 0: 20-80 % time 375ps typ, 535ps min, 281ps max; typ from 0.707 V to 0 V
[POWER_clamp]
-1.8V     194.9mA    137mA      262.9mA
-1.236V   68.49mA    48.49mA    92.7mA
-1.145V   50.76mA    35.84mA    69.67mA
-1.127V   47.56mA    33.52mA    65.35mA
-1.055V   35.4mA     24.68mA    48.7mA
-981.8mV  25.06mA    17.19mA    34.02mA
-927.3mV  19.17mA    12.92mA    25.62mA
-872.7mV  15.03mA    9.76mA     20.13mA
-818.2mV  12.12mA    7.445mA    16.51mA
-654.5mV  5.738mA    2.929mA    8.007mA
-436.4mV  508.2uA    199.4uA    613uA
0V        2.273nA    16.6nA     10.58nA
[Pulldown]
-1.8V     -7.609mA   -7.815mA   -7.446mA
-1.145V   -9.551mA   -9.863mA   -9.487mA
-600mV    -7.505mA   -7.866mA   -7.717mA
-381.8mV  -5.292mA   -5.559mA   -5.572mA
490.9mV   6.589mA    6.96mA     6.97mA
1.091V    13.54mA    14.52mA    14.32mA
1.636V    17.95mA    19.77mA    19.1mA
2.073V    19.37mA    21.71mA    20.85mA
2.291V    19.41mA    21.49mA    21.27mA
2.564V    17.74mA    19.25mA    20.08mA
3.164V    11.28mA    10.17mA    14.61mA
3.6V      5.787mA    4.008mA    8.697mA
[Pullup]
-1.8V     7.273mA    5.836mA    8.384mA
-1.2V     9.332mA    7.957mA    9.779mA
-872.7mV  8.52mA     8.421mA    8.6mA
-600mV    7.23mA     7.34mA     7.272mA
-381.8mV  5.181mA    5.112mA    5.231mA
1.2V      -15.41mA   -15.19mA   -15.57mA
1.8V      -21.85mA   -21.57mA   -22.06mA
2.182V    -25.16mA   -24.61mA   -25.39mA
2.4V      -25.92mA   -24.79mA   -26.51mA
2.673V    -25.16mA   -23.66mA   -26.04mA
3.164V    -21.3mA    -18.96mA   -21.84mA
3.6V      -15.77mA   -13.28mA   -17.07mA
[GND_clamp]
-1.8V     -346.1mA   -209.3mA   -568.3mA
-1.327V   -149.7mA   -89.03mA   -250.9mA
-1.291V   -135.6mA   -80.47mA   -227.5mA
-1.145V   -82.35mA   -48.67mA   -137.7mA
-1.073V   -59.44mA   -35.55mA   -97.96mA
-1.036V   -49.1mA    -29.72mA   -79.9mA
-927.3mV  -26.31mA   -17.11mA   -38.99mA
-854.5mV  -16.67mA   -11.64mA   -22.56mA
-818.2mV  -12.86mA   -9.351mA   -16.98mA
-672.7mV  -5.705mA   -3.913mA   -8.623mA
-381.8mV  -120.4uA   -129uA     -167.2uA
1.8V      2.273nA    51.44nA    6.654nA
[Ramp]
dV/dt_f 0.41366634/0.36832495n 0.41299696/0.56460614n 0.44792638/0.27934853n
dV/dt_r 0.42551259/0.39655788n 0.40142835/0.59227702n 0.44855619/0.30931456n
R_load = 50
[Rising Waveform]
R_fixture = 50
V_fixture = 1.8
V_fixture_min = 1.71
V_fixture_max = 1.89
0s        1.113V     1.024V     1.146V
92.5ps    1.113V     1.024V     1.175V
201.8ps   1.131V     1.024V     1.398V
384ps     1.323V     1.029V     1.685V
575.4ps   1.544V     1.198V     1.866V
742.2ps   1.702V     1.348V     1.886V
881.4ps   1.773V     1.455V     1.889V
1.073ns   1.792V     1.569V     1.89V
1.36ns    1.796V     1.66V      1.89V
2.62ns    1.799V     1.706V     1.89V
[Rising Waveform]
R_fixture = 50
V_fixture = 0
V_fixture_min = 0
V_fixture_max = 0
0s        0V         0V         0V
89.1ps    0V         0V         0V
210.6ps   2.297mV    0V         212.6mV
436.6ps   222.9mV    0V         532.8mV
621.4ps   426.3mV    151.1mV    719.8mV
918.1ps   673.9mV    366mV      743.5mV
1.022ns   692.9mV    454.6mV    744.7mV
1.365ns   701.3mV    594.9mV    745.9mV
1.707ns   703.7mV    658.3mV    746mV
2.631ns   704.6mV    663.3mV    746.1mV
[Falling Waveform]
R_fixture = 50
V_fixture = 1.8
V_fixture_min = 1.71
V_fixture_max = 1.89
0s        1.799V     1.709V     1.889V
100.5ps   1.799V     1.709V     1.873V
207ps     1.794V     1.709V     1.693V
415.7ps   1.606V     1.709V     1.36V
518.8ps   1.496V     1.626V     1.218V
603.3ps   1.396V     1.555V     1.17V
884ps     1.147V     1.321V     1.147V
1.092ns   1.122V     1.179V     1.145V
1.375ns   1.117V     1.078V     1.145V
2.62ns    1.113V     1.026V     1.145V
[Falling Waveform]
R_fixture = 50
V_fixture = 0
V_fixture_min = 0
V_fixture_max = 0
0s        706.9mV    666.9mV    745.1mV
84.1ps    706.9mV    666.9mV    733mV
193.6ps   695.8mV    666.9mV    505.8mV
395ps     470.2mV    657.9mV    196.9mV
512ps     340.6mV    546.8mV    52.32mV
580.2ps   254.7mV    481.2mV    20.3mV
864.6ps   27.57mV    260.3mV    2.352mV
1.042ns   9.049mV    145.3mV    0V
1.367ns   5.159mV    42.7mV     0V
2.631ns   0V         3.889mV    0V
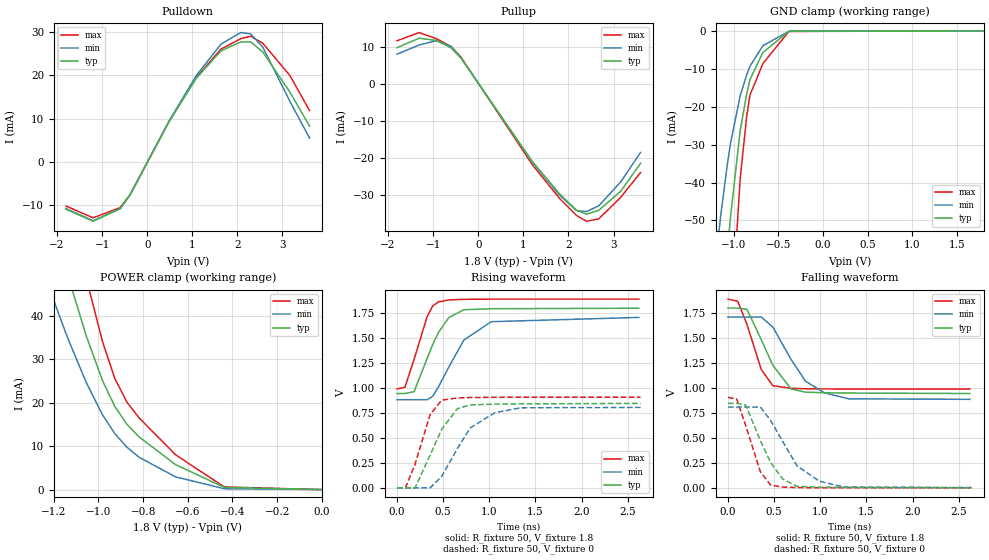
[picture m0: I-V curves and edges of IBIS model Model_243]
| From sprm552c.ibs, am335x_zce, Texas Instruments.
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| Model based on original model for BCSHTLTCSCDVPBFZ_SSDHV
|   Sub model SR10_7MA_5PER_1P8
[model]   Model_243
|[Description]  [1.8V-3-STATE-NOTERM-SR10:7MA, IND, 5%]
|   Fast slew rate (SR[1:0] = "10"), 1.14 * RExt = 0.875 * Iout
|   (I[2:0] = "010"), 7mA nominal with Rext = 50R,ODT off (ODT[1:0]
|   = "00") CMOS mode,Industrial temperature range (-40C to 125C,
|   25C nominal),5% power supply tolerance
|[Input Load]   NOTERM
|[Output Drive] SR10:7MA
|Voltage   1.8V
|Mode   3-STATE
Model_type   3-state
Polarity   Non-Inverting
Enable   Active-Low
Cref =  15pF
Rref =  100.0000M
Vref =  0V
Vmeas =  0.9
C_comp   1.851324p   1.667199p   1.973575p
[Temperature Range]   25   125   -40
[Voltage Range]   1.8   1.71   1.89
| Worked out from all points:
|   slope of the pulldown table from 0 to 0.27 V, typ, clamps not added: 51.1 ohm
|   slope of the pullup table from 0 to 0.27 V, typ, clamps not added: 54.4 ohm
|   GND clamp passes 1 mA (typ) near -0.49 V on its own axis
|   POWER clamp passes 1 mA (typ) near -0.47 V on its own axis
|   rising waveform, R_fixture 50, V_fixture 1.8: 20-80 % time 242ps typ, 310ps min, 177ps max; typ from 0.944 V to 1.8 V
|   rising waveform, R_fixture 50, V_fixture 0: 20-80 % time 257ps typ, 330ps min, 178ps max; typ from 0 V to 0.846 V
|   falling waveform, R_fixture 50, V_fixture 1.8: 20-80 % time 262ps typ, 330ps min, 189ps max; typ from 1.8 V to 0.944 V
|   falling waveform, R_fixture 50, V_fixture 0: 20-80 % time 258ps typ, 327ps min, 184ps max; typ from 0.846 V to 0 V
[POWER_clamp]
-1.8V     194.9mA    137mA      262.9mA
-1.236V   68.49mA    48.49mA    92.7mA
-1.145V   50.76mA    35.84mA    69.67mA
-1.127V   47.56mA    33.52mA    65.35mA
-1.055V   35.4mA     24.68mA    48.7mA
-981.8mV  25.06mA    17.19mA    34.02mA
-927.3mV  19.17mA    12.92mA    25.62mA
-872.7mV  15.03mA    9.76mA     20.13mA
-818.2mV  12.12mA    7.445mA    16.51mA
-654.5mV  5.738mA    2.929mA    8.007mA
-436.4mV  508.2uA    199.4uA    613uA
0V        2.273nA    16.6nA     10.58nA
[Pulldown]
-1.8V     -10.87mA   -10.75mA   -10.16mA
-1.2V     -13.67mA   -13.52mA   -12.86mA
-600mV    -10.72mA   -10.81mA   -10.52mA
-381.8mV  -7.555mA   -7.639mA   -7.594mA
490.9mV   9.408mA    9.565mA    9.5mA
1.091V    19.34mA    19.96mA    19.52mA
1.636V    25.64mA    27.18mA    26.04mA
2.073V    27.67mA    29.85mA    28.42mA
2.291V    27.74mA    29.56mA    29.01mA
2.564V    25.35mA    26.48mA    27.39mA
3.164V    16.12mA    13.99mA    19.94mA
3.6V      8.27mA     5.513mA    11.86mA
[Pullup]
-1.8V     9.872mA    8.121mA    11.74mA
-1.309V   12.43mA    10.6mA     13.96mA
-927.3mV  11.82mA    11.75mA    12.3mA
-600mV    9.811mA    10.21mA    10.18mA
-381.8mV  7.028mA    7.109mA    7.32mA
1.2V      -20.91mA   -21.13mA   -21.78mA
1.8V      -29.64mA   -30mA      -30.87mA
2.182V    -34.13mA   -34.24mA   -35.54mA
2.4V      -35.18mA   -34.49mA   -37.11mA
2.673V    -34.15mA   -32.93mA   -36.46mA
3.164V    -28.92mA   -26.39mA   -30.58mA
3.6V      -21.41mA   -18.48mA   -23.91mA
[GND_clamp]
-1.8V     -346.1mA   -209.3mA   -568.3mA
-1.327V   -149.7mA   -89.03mA   -250.9mA
-1.291V   -135.6mA   -80.47mA   -227.5mA
-1.145V   -82.35mA   -48.67mA   -137.7mA
-1.073V   -59.44mA   -35.55mA   -97.96mA
-1.036V   -49.1mA    -29.72mA   -79.9mA
-927.3mV  -26.31mA   -17.11mA   -38.99mA
-854.5mV  -16.67mA   -11.64mA   -22.56mA
-818.2mV  -12.86mA   -9.351mA   -16.98mA
-672.7mV  -5.705mA   -3.913mA   -8.623mA
-381.8mV  -120.4uA   -129uA     -167.2uA
1.8V      2.273nA    51.44nA    6.654nA
[Ramp]
dV/dt_f 0.51515773/0.26334461n 0.49806379/0.33234771n 0.54092151/0.18947232n
dV/dt_r 0.50927859/0.25773805n 0.48696777/0.33204236n 0.54545149/0.17811555n
R_load = 50
[Rising Waveform]
R_fixture = 50
V_fixture = 1.8
V_fixture_min = 1.71
V_fixture_max = 1.89
0s        944.4mV    882.6mV    990.4mV
85.8ps    944.4mV    882.6mV    1.008V
184.6ps   963.1mV    882.6mV    1.286V
325.9ps   1.295V     882.8mV    1.713V
385.9ps   1.434V     915.5mV    1.82V
449.6ps   1.556V     1.012V     1.863V
560.8ps   1.705V     1.209V     1.882V
724.6ps   1.784V     1.481V     1.888V
1.021ns   1.794V     1.664V     1.89V
2.62ns    1.799V     1.707V     1.89V
[Rising Waveform]
R_fixture = 50
V_fixture = 0
V_fixture_min = 0
V_fixture_max = 0
0s        0V         0V         0V
90.5ps    0V         0V         0V
195ps     0V         0V         234.9mV
358.1ps   326.8mV    0V         732.7mV
484.5ps   586.4mV    114.3mV    878.7mV
653.9ps   792.8mV    392.9mV    900.2mV
794.6ps   831mV      600.7mV    904.5mV
1.061ns   838.4mV    753.8mV    907mV
1.345ns   841.2mV    802.1mV    907.4mV
2.639ns   845.6mV    805.4mV    907.5mV
[Falling Waveform]
R_fixture = 50
V_fixture = 1.8
V_fixture_min = 1.71
V_fixture_max = 1.89
0s        1.799V     1.71V      1.889V
105.3ps   1.799V     1.71V      1.868V
204.8ps   1.788V     1.71V      1.638V
359.9ps   1.484V     1.71V      1.185V
486.3ps   1.226V     1.609V     1.022V
683.4ps   989.7mV    1.285V     996.6mV
839.2ps   957.8mV    1.068V     992.1mV
1.045ns   951.9mV    950.8mV    990.1mV
1.308ns   948.8mV    891.1mV    989.6mV
2.62ns    944.3mV    885.9mV    989.4mV
[Falling Waveform]
R_fixture = 50
V_fixture = 0
V_fixture_min = 0
V_fixture_max = 0
0s        845.6mV    808.8mV    906.7mV
95.1ps    845.6mV    808.8mV    887.3mV
190.5ps   829.3mV    808.8mV    627.8mV
350.8ps   472.9mV    808.8mV    160.5mV
461.1ps   254.3mV    674.7mV    27.65mV
593.4ps   87.87mV    463.2mV    7.748mV
747.5ps   14.99mV    219.7mV    2.908mV
989ps     6.909mV    66.89mV    0V
1.254ns   4.828mV    8.313mV    0V
2.639ns   0V         4.014mV    0V
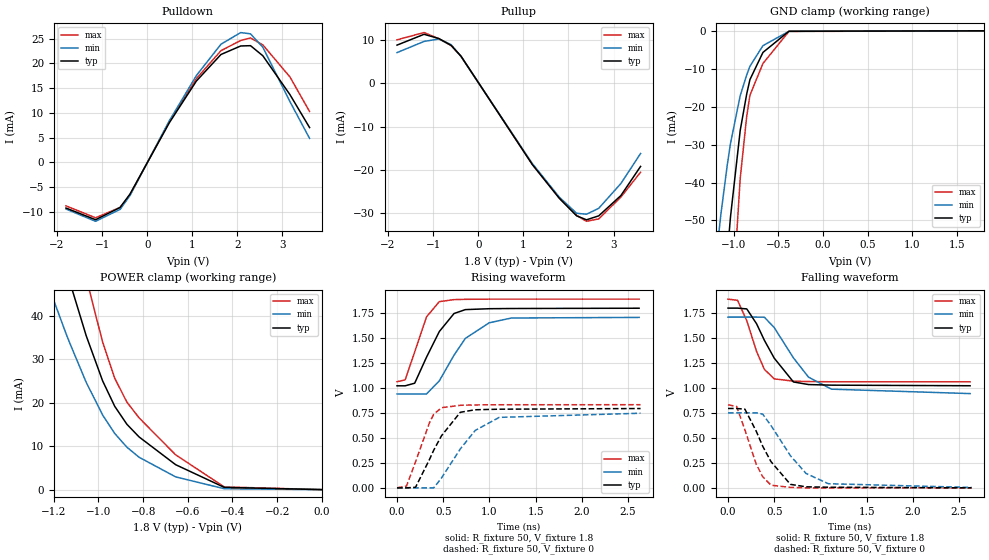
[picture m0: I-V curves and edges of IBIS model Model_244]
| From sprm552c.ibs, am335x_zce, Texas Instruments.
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| Model based on original model for BCSHTLTCSCDVPBFZ_SSDHV
|   Sub model SR10_6MA_5PER_1P8
[model]   Model_244
|[Description]  [1.8V-3-STATE-NOTERM-SR10:6MA, IND, 5%]
|   Fast slew rate (SR[1:0] = "10"), 1.33 * RExt = 0.750 * Iout
|   (I[2:0] = "001"), 6mA nominal with Rext = 50R,ODT off (ODT[1:0]
|   = "00") CMOS mode,Industrial temperature range (-40C to 125C,
|   25C nominal),5% power supply tolerance
|[Input Load]   NOTERM
|[Output Drive] SR10:6MA
|Voltage   1.8V
|Mode   3-STATE
Model_type   3-state
Polarity   Non-Inverting
Enable   Active-Low
Cref =  15pF
Rref =  100.0000M
Vref =  0V
Vmeas =  0.9
C_comp   1.851324p   1.667199p   1.973575p
[Temperature Range]   25   125   -40
[Voltage Range]   1.8   1.71   1.89
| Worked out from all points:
|   slope of the pulldown table from 0 to 0.27 V, typ, clamps not added: 60.1 ohm
|   slope of the pullup table from 0 to 0.27 V, typ, clamps not added: 60.8 ohm
|   GND clamp passes 1 mA (typ) near -0.49 V on its own axis
|   POWER clamp passes 1 mA (typ) near -0.47 V on its own axis
|   rising waveform, R_fixture 50, V_fixture 1.8: 20-80 % time 249ps typ, 329ps min, 177ps max; typ from 1.02 V to 1.8 V
|   rising waveform, R_fixture 50, V_fixture 0: 20-80 % time 264ps typ, 358ps min, 190ps max; typ from 0 V to 0.794 V
|   falling waveform, R_fixture 50, V_fixture 1.8: 20-80 % time 271ps typ, 357ps min, 189ps max; typ from 1.8 V to 1.02 V
|   falling waveform, R_fixture 50, V_fixture 0: 20-80 % time 267ps typ, 350ps min, 188ps max; typ from 0.794 V to 0 V
[POWER_clamp]
-1.8V     194.9mA    137mA      262.9mA
-1.236V   68.49mA    48.49mA    92.7mA
-1.145V   50.76mA    35.84mA    69.67mA
-1.127V   47.56mA    33.52mA    65.35mA
-1.055V   35.4mA     24.68mA    48.7mA
-981.8mV  25.06mA    17.19mA    34.02mA
-927.3mV  19.17mA    12.92mA    25.62mA
-872.7mV  15.03mA    9.76mA     20.13mA
-818.2mV  12.12mA    7.445mA    16.51mA
-654.5mV  5.738mA    2.929mA    8.007mA
-436.4mV  508.2uA    199.4uA    613uA
0V        2.273nA    16.6nA     10.58nA
[Pulldown]
-1.8V     -9.241mA   -9.444mA   -8.801mA
-1.145V   -11.6mA    -11.92mA   -11.21mA
-600mV    -9.112mA   -9.503mA   -9.119mA
-381.8mV  -6.424mA   -6.715mA   -6.584mA
490.9mV   7.999mA    8.408mA    8.235mA
1.091V    16.44mA    17.54mA    16.92mA
1.636V    21.8mA     23.88mA    22.57mA
2.073V    23.52mA    26.23mA    24.63mA
2.291V    23.58mA    25.97mA    25.14mA
2.564V    21.54mA    23.27mA    23.74mA
3.164V    13.7mA     12.29mA    17.27mA
3.6V      7.029mA    4.844mA    10.28mA
[Pullup]
-1.8V     8.832mA    7.105mA    10.06mA
-1.2V     11.33mA    9.687mA    11.73mA
-872.7mV  10.35mA    10.25mA    10.32mA
-600mV    8.779mA    8.934mA    8.725mA
-381.8mV  6.289mA    6.222mA    6.276mA
1.2V      -18.71mA   -18.49mA   -18.68mA
1.8V      -26.52mA   -26.26mA   -26.46mA
2.182V    -30.54mA   -29.96mA   -30.46mA
2.4V      -31.47mA   -30.18mA   -31.81mA
2.673V    -30.55mA   -28.81mA   -31.25mA
3.164V    -25.87mA   -23.09mA   -26.21mA
3.6V      -19.15mA   -16.17mA   -20.49mA
[GND_clamp]
-1.8V     -346.1mA   -209.3mA   -568.3mA
-1.327V   -149.7mA   -89.03mA   -250.9mA
-1.291V   -135.6mA   -80.47mA   -227.5mA
-1.145V   -82.35mA   -48.67mA   -137.7mA
-1.073V   -59.44mA   -35.55mA   -97.96mA
-1.036V   -49.1mA    -29.72mA   -79.9mA
-927.3mV  -26.31mA   -17.11mA   -38.99mA
-854.5mV  -16.67mA   -11.64mA   -22.56mA
-818.2mV  -12.86mA   -9.351mA   -16.98mA
-672.7mV  -5.705mA   -3.913mA   -8.623mA
-381.8mV  -120.4uA   -129uA     -167.2uA
1.8V      2.273nA    51.44nA    6.654nA
[Ramp]
dV/dt_f 0.46820065/0.27176358n 0.46310667/0.35962215n 0.49747855/0.18943493n
dV/dt_r 0.47824464/0.26453606n 0.45172579/0.35933057n  0.5003815/0.19002681n
R_load = 50
[Rising Waveform]
R_fixture = 50
V_fixture = 1.8
V_fixture_min = 1.71
V_fixture_max = 1.89
0s        1.022V     940.4mV    1.063V
88.3ps    1.022V     940.4mV    1.082V
191.4ps   1.048V     940.4mV    1.361V
319.1ps   1.308V     940.4mV    1.712V
457.5ps   1.565V     1.071V     1.865V
617.2ps   1.746V     1.329V     1.885V
739.9ps   1.785V     1.497V     1.888V
998ps     1.794V     1.653V     1.89V
1.238ns   1.796V     1.701V     1.89V
2.62ns    1.799V     1.707V     1.89V
[Rising Waveform]
R_fixture = 50
V_fixture = 0
V_fixture_min = 0
V_fixture_max = 0
0s        0V         0V         0V
102.9ps   0V         0V         19.15mV
200.7ps   5.939mV    0V         261.2mV
350.6ps   282.9mV    0V         650.6mV
397.6ps   377.8mV    0V         737.8mV
482ps     522.4mV    99.65mV    802.5mV
684.9ps   756.7mV    389.6mV    826.8mV
846ps     782.1mV    574.8mV    830.6mV
1.106ns   787.7mV    705.8mV    832.3mV
2.636ns   794.4mV    747.4mV    832.7mV
[Falling Waveform]
R_fixture = 50
V_fixture = 1.8
V_fixture_min = 1.71
V_fixture_max = 1.89
0s        1.799V     1.709V     1.889V
103.2ps   1.799V     1.709V     1.877V
203.2ps   1.791V     1.709V     1.673V
310ps     1.641V     1.709V     1.363V
393.6ps   1.477V     1.708V     1.186V
500.3ps   1.298V     1.604V     1.091V
707.9ps   1.06V      1.301V     1.068V
871.1ps   1.034V     1.108V     1.064V
1.12ns    1.028V     987.8mV    1.062V
2.62ns    1.022V     943.5mV    1.062V
[Falling Waveform]
R_fixture = 50
V_fixture = 0
V_fixture_min = 0
V_fixture_max = 0
0s        794.4mV    750.6mV    831.8mV
93.1ps    794.4mV    750.6mV    814.8mV
182.6ps   787.8mV    750.6mV    580.7mV
306ps     565.9mV    750.6mV    235.9mV
374.9ps   417.7mV    738.3mV    112.2mV
465.1ps   262.5mV    624.1mV    26.75mV
675.2ps   35.16mV    321.9mV    4.571mV
845.1ps   10.36mV    143.7mV    0V
1.087ns   6.373mV    41.42mV    0V
2.636ns   0V         4.018mV    0V
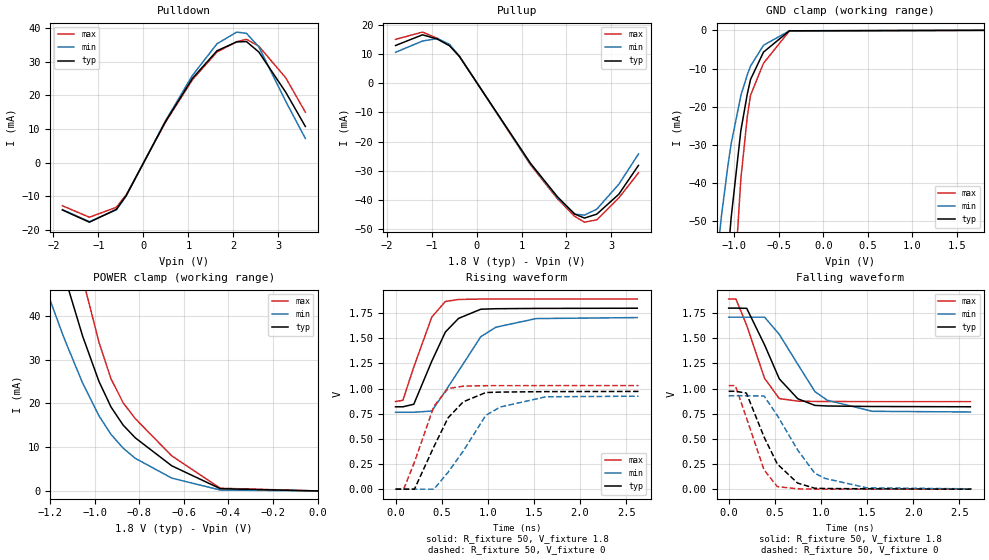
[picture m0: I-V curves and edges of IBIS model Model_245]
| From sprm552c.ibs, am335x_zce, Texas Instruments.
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| Model based on original model for BCSHTLTCSCDVPBFZ_SSDHV
|   Sub model SR11_9MA_5PER_1P8
[model]   Model_245
|[Description]  [1.8V-3-STATE-NOTERM-SR11:9MA, IND, 5%]
|   Slowest slew rate (SR[1:0] = "11"), 0.88 * RExt = 1.125 * Iout
|   (I[2:0] = "100"), 9mA nominal with Rext = 50R,ODT off (ODT[1:0]
|   = "00") CMOS mode,Industrial temperature range (-40C to 125C,
|   25C nominal),5% power supply tolerance
|[Input Load]   NOTERM
|[Output Drive] SR11:9MA
|Voltage   1.8V
|Mode   3-STATE
Model_type   3-state
Polarity   Non-Inverting
Enable   Active-Low
Cref =  15pF
Rref =  100.0000M
Vref =  0V
Vmeas =  0.9
C_comp   1.851324p   1.667199p   1.973575p
[Temperature Range]   25   125   -40
[Voltage Range]   1.8   1.71   1.89
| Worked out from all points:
|   slope of the pulldown table from 0 to 0.27 V, typ, clamps not added: 39.3 ohm
|   slope of the pullup table from 0 to 0.27 V, typ, clamps not added: 41.3 ohm
|   GND clamp passes 1 mA (typ) near -0.49 V on its own axis
|   POWER clamp passes 1 mA (typ) near -0.47 V on its own axis
|   rising waveform, R_fixture 50, V_fixture 1.8: 20-80 % time 291ps typ, 409ps min, 230ps max; typ from 0.819 V to 1.8 V
|   rising waveform, R_fixture 50, V_fixture 0: 20-80 % time 319ps typ, 402ps min, 238ps max; typ from 0 V to 0.972 V
|   falling waveform, R_fixture 50, V_fixture 1.8: 20-80 % time 309ps typ, 391ps min, 233ps max; typ from 1.8 V to 0.819 V
|   falling waveform, R_fixture 50, V_fixture 0: 20-80 % time 288ps typ, 400ps min, 226ps max; typ from 0.973 V to 0 V
[POWER_clamp]
-1.8V     194.9mA    137mA      262.9mA
-1.236V   68.49mA    48.49mA    92.7mA
-1.145V   50.76mA    35.84mA    69.67mA
-1.127V   47.56mA    33.52mA    65.35mA
-1.055V   35.4mA     24.68mA    48.7mA
-981.8mV  25.06mA    17.19mA    34.02mA
-927.3mV  19.17mA    12.92mA    25.62mA
-872.7mV  15.03mA    9.76mA     20.13mA
-818.2mV  12.12mA    7.445mA    16.51mA
-654.5mV  5.738mA    2.929mA    8.007mA
-436.4mV  508.2uA    199.4uA    613uA
0V        2.273nA    16.6nA     10.58nA
[Pulldown]
-1.8V     -14.14mA   -14.01mA   -12.87mA
-1.2V     -17.77mA   -17.62mA   -16.29mA
-600mV    -13.93mA   -14.08mA   -13.32mA
-381.8mV  -9.817mA   -9.949mA   -9.615mA
490.9mV   12.22mA    12.46mA    12.03mA
1.091V    25.12mA    25.99mA    24.71mA
1.636V    33.32mA    35.4mA     32.97mA
2.073V    35.97mA    38.89mA    36mA
2.291V    36.06mA    38.52mA    36.74mA
2.564V    32.97mA    34.52mA    34.71mA
3.164V    20.97mA    18.24mA    25.26mA
3.6V      10.76mA    7.187mA    15.03mA
[Pullup]
-1.8V     12.99mA    10.66mA    15.1mA
-1.2V     16.67mA    14.53mA    17.6mA
-872.7mV  15.21mA    15.38mA    15.47mA
-600mV    12.91mA    13.4mA     13.08mA
-381.8mV  9.242mA    9.325mA    9.406mA
1.2V      -27.49mA   -27.72mA   -27.99mA
1.8V      -38.98mA   -39.36mA   -39.67mA
2.182V    -44.9mA    -44.93mA   -45.68mA
2.4V      -46.28mA   -45.27mA   -47.7mA
2.673V    -44.94mA   -43.23mA   -46.89mA
3.164V    -38.07mA   -34.66mA   -39.34mA
3.6V      -28.19mA   -24.27mA   -30.76mA
[GND_clamp]
-1.8V     -346.1mA   -209.3mA   -568.3mA
-1.327V   -149.7mA   -89.03mA   -250.9mA
-1.291V   -135.6mA   -80.47mA   -227.5mA
-1.145V   -82.35mA   -48.67mA   -137.7mA
-1.073V   -59.44mA   -35.55mA   -97.96mA
-1.036V   -49.1mA    -29.72mA   -79.9mA
-927.3mV  -26.31mA   -17.11mA   -38.99mA
-854.5mV  -16.67mA   -11.64mA   -22.56mA
-818.2mV  -12.86mA   -9.351mA   -16.98mA
-672.7mV  -5.705mA   -3.913mA   -8.623mA
-381.8mV  -120.4uA   -129uA     -167.2uA
1.8V      2.273nA    51.44nA    6.654nA
[Ramp]
dV/dt_f 0.59100207/0.31189696n 0.56981247/0.38633851n 0.61322347/0.23418889n
dV/dt_r 0.58616031/0.32022973n 0.56002361/0.3967542n 0.61945873/0.23883391n
R_load = 50
[Rising Waveform]
R_fixture = 50
V_fixture = 1.8
V_fixture_min = 1.71
V_fixture_max = 1.89
0s        818.8mV    764.5mV    870.9mV
79.1ps    818.8mV    764.5mV    883.3mV
197.7ps   844.2mV    764.5mV    1.214V
392.6ps   1.272V     776.6mV    1.711V
539.9ps   1.562V     975.2mV    1.866V
683.1ps   1.698V     1.175V     1.886V
924ps     1.789V     1.516V     1.89V
1.087ns   1.794V     1.61V      1.89V
1.523ns   1.797V     1.696V     1.89V
2.62ns    1.799V     1.706V     1.89V
[Rising Waveform]
R_fixture = 50
V_fixture = 0
V_fixture_min = 0
V_fixture_max = 0
0s        0V         0V         0V
88.4ps    0V         0V         0V
204.7ps   0V         0V         268.5mV
416ps     422.9mV    0V         825.2mV
569.2ps   709.2mV    167.6mV    1.001V
733.9ps   868.6mV    378.7mV    1.024V
978.1ps   960.7mV    734mV      1.029V
1.135ns   965.1mV    816.6mV    1.029V
1.629ns   969.8mV    918.5mV    1.03V
2.633ns   971.7mV    924.3mV    1.03V
[Falling Waveform]
R_fixture = 50
V_fixture = 1.8
V_fixture_min = 1.71
V_fixture_max = 1.89
0s        1.799V     1.709V     1.889V
78.9ps    1.799V     1.709V     1.889V
195.5ps   1.797V     1.709V     1.627V
389.4ps   1.433V     1.709V     1.101V
548.7ps   1.096V     1.538V     900mV
749.2ps   898.2mV    1.241V     875mV
934.8ps   832.3mV    969.4mV    871.9mV
1.069ns   826.6mV    883.5mV    870.9mV
1.558ns   821.4mV    773.6mV    869.9mV
2.62ns    818.7mV    767.1mV    869.9mV
[Falling Waveform]
R_fixture = 50
V_fixture = 0
V_fixture_min = 0
V_fixture_max = 0
0s        972.6mV    927.7mV    1.029V
72.5ps    972.6mV    927.7mV    1.029V
191.8ps   955mV      927.7mV    710.4mV
383.6ps   518.5mV    926mV      191.3mV
527.1ps   250.2mV    732mV      25.1mV
747ps     60.27mV    390.7mV    3.27mV
932.3ps   9.262mV    158.7mV    0V
1.044ns   6.61mV     106.7mV    0V
1.497ns   3.533mV    13.09mV    0V
2.633ns   0V         3.373mV    0V
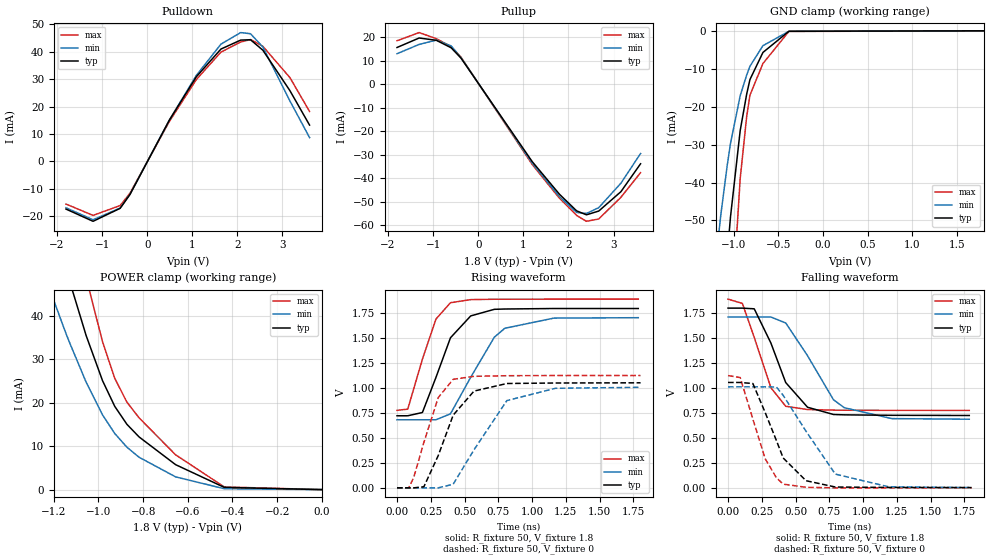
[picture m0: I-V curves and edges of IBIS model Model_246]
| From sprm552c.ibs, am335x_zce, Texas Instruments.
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| Model based on original model for BCSHTLTCSCDVPBFZ_SSDHV
|   Sub model SR10_11MA_5PER_1P8
[model]   Model_246
|[Description]  [1.8V-3-STATE-NOTERM-SR10:11MA, IND, 5%]
|   Fast slew rate (SR[1:0] = "10"), 0.73 * RExt = 1.325 * Iout
|   (I[2:0] = "110"), 11mA nominal with Rext = 50R,ODT off (ODT[1:0]
|   = "00") CMOS mode,Industrial temperature range (-40C to 125C,
|   25C nominal),5% power supply tolerance
|[Input Load]   NOTERM
|[Output Drive] SR10:11MA
|Voltage   1.8V
|Mode   3-STATE
Model_type   3-state
Polarity   Non-Inverting
Enable   Active-Low
Cref =  15pF
Rref =  100.0000M
Vref =  0V
Vmeas =  0.9
C_comp   1.851324p   1.667199p   1.973575p
[Temperature Range]   25   125   -40
[Voltage Range]   1.8   1.71   1.89
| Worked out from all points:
|   slope of the pulldown table from 0 to 0.27 V, typ, clamps not added: 32 ohm
|   slope of the pullup table from 0 to 0.27 V, typ, clamps not added: 34.5 ohm
|   GND clamp passes 1 mA (typ) near -0.49 V on its own axis
|   POWER clamp passes 1 mA (typ) near -0.47 V on its own axis
|   rising waveform, R_fixture 50, V_fixture 1.8: 20-80 % time 183ps typ, 262ps min, 147ps max; typ from 0.722 V to 1.8 V
|   rising waveform, R_fixture 50, V_fixture 0: 20-80 % time 197ps typ, 262ps min, 153ps max; typ from 0 V to 1.05 V
|   falling waveform, R_fixture 50, V_fixture 1.8: 20-80 % time 204ps typ, 268ps min, 161ps max; typ from 1.8 V to 0.724 V
|   falling waveform, R_fixture 50, V_fixture 0: 20-80 % time 196ps typ, 279ps min, 158ps max; typ from 1.05 V to 0.003 V
[POWER_clamp]
-1.8V     194.9mA    137mA      262.9mA
-1.236V   68.49mA    48.49mA    92.7mA
-1.145V   50.76mA    35.84mA    69.67mA
-1.127V   47.56mA    33.52mA    65.35mA
-1.055V   35.4mA     24.68mA    48.7mA
-981.8mV  25.06mA    17.19mA    34.02mA
-927.3mV  19.17mA    12.92mA    25.62mA
-872.7mV  15.03mA    9.76mA     20.13mA
-818.2mV  12.12mA    7.445mA    16.51mA
-654.5mV  5.738mA    2.929mA    8.007mA
-436.4mV  508.2uA    199.4uA    613uA
0V        2.273nA    16.6nA     10.58nA
[Pulldown]
-1.8V     -17.41mA   -16.94mA   -15.58mA
-1.2V     -21.87mA   -21.31mA   -19.71mA
-600mV    -17.14mA   -17.03mA   -16.12mA
-381.8mV  -12.08mA   -12.02mA   -11.63mA
490.9mV   15.04mA    15.06mA    14.55mA
1.091V    30.91mA    31.42mA    29.9mA
1.636V    41.01mA    42.8mA     39.9mA
2.073V    44.27mA    47.02mA    43.57mA
2.291V    44.39mA    46.59mA    44.48mA
2.564V    40.59mA    41.76mA    42.02mA
3.164V    25.83mA    22.07mA    30.59mA
3.6V      13.24mA    8.694mA    18.21mA
[Pullup]
-1.8V     15.59mA    12.95mA    18.46mA
-1.309V   19.63mA    16.9mA     21.94mA
-927.3mV  18.65mA    18.73mA    19.33mA
-600mV    15.48mA    16.26mA    15.99mA
-381.8mV  11.09mA    11.32mA    11.49mA
1.2V      -32.98mA   -33.64mA   -34.2mA
1.8V      -46.76mA   -47.78mA   -48.47mA
2.182V    -53.86mA   -54.55mA   -55.81mA
2.4V      -55.54mA   -54.98mA   -58.3mA
2.673V    -53.94mA   -52.5mA    -57.31mA
3.164V    -45.71mA   -42.11mA   -48.1mA
3.6V      -33.84mA   -29.49mA   -37.62mA
[GND_clamp]
-1.8V     -346.1mA   -209.3mA   -568.3mA
-1.327V   -149.7mA   -89.03mA   -250.9mA
-1.291V   -135.6mA   -80.47mA   -227.5mA
-1.145V   -82.35mA   -48.67mA   -137.7mA
-1.073V   -59.44mA   -35.55mA   -97.96mA
-1.036V   -49.1mA    -29.72mA   -79.9mA
-927.3mV  -26.31mA   -17.11mA   -38.99mA
-854.5mV  -16.67mA   -11.64mA   -22.56mA
-818.2mV  -12.86mA   -9.351mA   -16.98mA
-672.7mV  -5.705mA   -3.913mA   -8.623mA
-381.8mV  -120.4uA   -129uA     -167.2uA
1.8V      2.273nA    51.44nA    6.654nA
[Ramp]
dV/dt_f 0.64902301/0.20514601n 0.61937015/0.27017876n 0.66990517/0.1616526n
dV/dt_r 0.63564955/0.19804983n 0.60941804/0.26435511n 0.67686347/0.15312539n
R_load = 50
[Rising Waveform]
R_fixture = 50
V_fixture = 1.8
V_fixture_min = 1.71
V_fixture_max = 1.89
0s        722mV      681.8mV    776.3mV
79.6ps    722mV      681.8mV    788.3mV
188.2ps   754.7mV    681.8mV    1.289V
288.2ps   1.105V     681.8mV    1.69V
396ps     1.503V     741.5mV    1.854V
546.1ps   1.722V     1.108V     1.885V
721ps     1.788V     1.509V     1.889V
798.3ps   1.791V     1.598V     1.889V
1.162ns   1.796V     1.7V       1.89V
1.787ns   1.796V     1.704V     1.89V
[Rising Waveform]
R_fixture = 50
V_fixture = 0
V_fixture_min = 0
V_fixture_max = 0
0s        0V         0V         0V
86.8ps    0V         0V         0V
123.8ps   0V         0V         103.6mV
199.1ps   11.27mV    0V         455.9mV
305.2ps   323mV      0V         903.4mV
415.9ps   728mV      36.34mV    1.087V
570.3ps   969.2mV    381.4mV    1.117V
813.7ps   1.045V     873.9mV    1.123V
1.174ns   1.05V      997.1mV    1.125V
1.804ns   1.052V     1.007V     1.125V
[Falling Waveform]
R_fixture = 50
V_fixture = 1.8
V_fixture_min = 1.71
V_fixture_max = 1.89
0s        1.799V     1.71V      1.889V
106.3ps   1.799V     1.71V      1.846V
194.3ps   1.792V     1.71V      1.506V
317.8ps   1.449V     1.71V      1.002V
427.4ps   1.054V     1.65V      816.7mV
589.2ps   806.8mV    1.322V     783.7mV
781.1ps   734.4mV    881.7mV    778mV
861.4ps   730.8mV    802mV      777mV
1.213ns   726.3mV    693.1mV    775.5mV
1.787ns   724.3mV    687mV      775.4mV
[Falling Waveform]
R_fixture = 50
V_fixture = 0
V_fixture_min = 0
V_fixture_max = 0
0s        1.055V     1.011V     1.124V
90.3ps    1.055V     1.011V     1.104V
184.2ps   1.044V     1.011V     688.2mV
275.4ps   753.9mV    1.011V     291.2mV
357.6ps   476.7mV    1.01V      102.8mV
408.5ps   299.4mV    926mV      37.33mV
577.7ps   71.53mV    566.9mV    5.65mV
794.8ps   8.35mV     137.5mV    0V
1.192ns   4.253mV    9.837mV    0V
1.804ns   2.873mV    3.479mV    0V
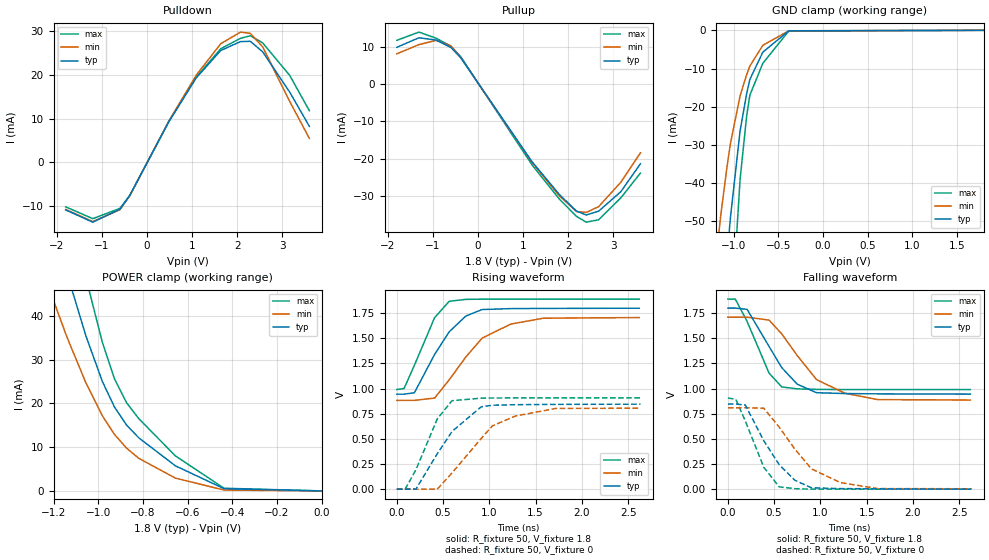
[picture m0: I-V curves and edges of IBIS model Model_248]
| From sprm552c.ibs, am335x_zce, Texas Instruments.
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| Model based on original model for BCSHTLTCSCDVPBFZ_SSDHV
|   Sub model SR11_7MA_5PER_1P8
[model]   Model_248
|[Description]  [1.8V-3-STATE-NOTERM-SR11:7MA, IND, 5%]
|   Slowest slew rate (SR[1:0] = "11"), 1.14 * RExt = 0.875 * Iout
|   (I[2:0] = "010"), 7mA nominal with Rext = 50R,ODT off (ODT[1:0]
|   = "00") CMOS mode,Industrial temperature range (-40C to 125C,
|   25C nominal),5% power supply tolerance
|[Input Load]   NOTERM
|[Output Drive] SR11:7MA
|Voltage   1.8V
|Mode   3-STATE
Model_type   3-state
Polarity   Non-Inverting
Enable   Active-Low
Cref =  15pF
Rref =  100.0000M
Vref =  0V
Vmeas =  0.9
C_comp   1.851324p   1.667199p   1.973575p
[Temperature Range]   25   125   -40
[Voltage Range]   1.8   1.71   1.89
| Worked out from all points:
|   slope of the pulldown table from 0 to 0.27 V, typ, clamps not added: 51.1 ohm
|   slope of the pullup table from 0 to 0.27 V, typ, clamps not added: 54.4 ohm
|   GND clamp passes 1 mA (typ) near -0.49 V on its own axis
|   POWER clamp passes 1 mA (typ) near -0.47 V on its own axis
|   rising waveform, R_fixture 50, V_fixture 1.8: 20-80 % time 350ps typ, 446ps min, 251ps max; typ from 0.944 V to 1.8 V
|   rising waveform, R_fixture 50, V_fixture 0: 20-80 % time 375ps typ, 469ps min, 253ps max; typ from 0 V to 0.845 V
|   falling waveform, R_fixture 50, V_fixture 1.8: 20-80 % time 353ps typ, 449ps min, 251ps max; typ from 1.8 V to 0.944 V
|   falling waveform, R_fixture 50, V_fixture 0: 20-80 % time 352ps typ, 435ps min, 246ps max; typ from 0.846 V to 0 V
[POWER_clamp]
-1.8V     194.9mA    137mA      262.9mA
-1.236V   68.49mA    48.49mA    92.7mA
-1.145V   50.76mA    35.84mA    69.67mA
-1.127V   47.56mA    33.52mA    65.35mA
-1.055V   35.4mA     24.68mA    48.7mA
-981.8mV  25.06mA    17.19mA    34.02mA
-927.3mV  19.17mA    12.92mA    25.62mA
-872.7mV  15.03mA    9.76mA     20.13mA
-818.2mV  12.12mA    7.445mA    16.51mA
-654.5mV  5.738mA    2.929mA    8.007mA
-436.4mV  508.2uA    199.4uA    613uA
0V        2.273nA    16.6nA     10.58nA
[Pulldown]
-1.8V     -10.87mA   -10.75mA   -10.16mA
-1.2V     -13.67mA   -13.52mA   -12.86mA
-600mV    -10.72mA   -10.81mA   -10.52mA
-381.8mV  -7.555mA   -7.639mA   -7.594mA
490.9mV   9.408mA    9.565mA    9.5mA
1.091V    19.34mA    19.96mA    19.52mA
1.636V    25.64mA    27.18mA    26.04mA
2.073V    27.67mA    29.85mA    28.42mA
2.291V    27.74mA    29.56mA    29.01mA
2.564V    25.35mA    26.48mA    27.39mA
3.164V    16.12mA    13.99mA    19.94mA
3.6V      8.27mA     5.513mA    11.86mA
[Pullup]
-1.8V     9.872mA    8.121mA    11.74mA
-1.309V   12.43mA    10.6mA     13.96mA
-927.3mV  11.82mA    11.75mA    12.3mA
-600mV    9.811mA    10.21mA    10.18mA
-381.8mV  7.028mA    7.109mA    7.32mA
1.2V      -20.91mA   -21.13mA   -21.78mA
1.8V      -29.64mA   -30mA      -30.87mA
2.182V    -34.13mA   -34.24mA   -35.54mA
2.4V      -35.18mA   -34.49mA   -37.11mA
2.673V    -34.15mA   -32.93mA   -36.46mA
3.164V    -28.92mA   -26.39mA   -30.58mA
3.6V      -21.41mA   -18.48mA   -23.91mA
[GND_clamp]
-1.8V     -346.1mA   -209.3mA   -568.3mA
-1.327V   -149.7mA   -89.03mA   -250.9mA
-1.291V   -135.6mA   -80.47mA   -227.5mA
-1.145V   -82.35mA   -48.67mA   -137.7mA
-1.073V   -59.44mA   -35.55mA   -97.96mA
-1.036V   -49.1mA    -29.72mA   -79.9mA
-927.3mV  -26.31mA   -17.11mA   -38.99mA
-854.5mV  -16.67mA   -11.64mA   -22.56mA
-818.2mV  -12.86mA   -9.351mA   -16.98mA
-672.7mV  -5.705mA   -3.913mA   -8.623mA
-381.8mV  -120.4uA   -129uA     -167.2uA
1.8V      2.273nA    51.44nA    6.654nA
[Ramp]
dV/dt_f 0.51532878/0.3547918n 0.49824081/0.45165173n 0.54107643/0.25170231n
dV/dt_r 0.50961724/0.37667564n 0.48751727/0.47563592n 0.54562862/0.25433132n
R_load = 50
[Rising Waveform]
R_fixture = 50
V_fixture = 1.8
V_fixture_min = 1.71
V_fixture_max = 1.89
0s        944.4mV    882.6mV    990.4mV
78.6ps    944.4mV    882.6mV    1.001V
189.8ps   958.7mV    882.6mV    1.231V
408.2ps   1.339V     905.7mV    1.705V
566.2ps   1.565V     1.087V     1.868V
745.7ps   1.721V     1.314V     1.887V
922.1ps   1.786V     1.502V     1.889V
1.231ns   1.795V     1.641V     1.89V
1.586ns   1.797V     1.7V       1.89V
2.62ns    1.799V     1.706V     1.89V
[Rising Waveform]
R_fixture = 50
V_fixture = 0
V_fixture_min = 0
V_fixture_max = 0
0s        0V         0V         0V
89.4ps    0V         0V         0V
206.2ps   0V         0V         191.6mV
437.4ps   352.5mV    0V         699.5mV
596.6ps   573.7mV    161.6mV    879.5mV
911.8ps   818.7mV    504mV      905mV
1.034ns   834.5mV    630mV      906.4mV
1.282ns   839.6mV    727.3mV    907.3mV
1.717ns   842.9mV    802.3mV    907.5mV
2.633ns   845.2mV    805.4mV    907.5mV
[Falling Waveform]
R_fixture = 50
V_fixture = 1.8
V_fixture_min = 1.71
V_fixture_max = 1.89
0s        1.799V     1.709V     1.889V
79.6ps    1.799V     1.709V     1.889V
207.2ps   1.787V     1.709V     1.667V
444.7ps   1.418V     1.68V      1.153V
581.5ps   1.208V     1.543V     1.016V
748.9ps   1.043V     1.328V     996.6mV
958.4ps   958.4mV    1.088V     991.3mV
1.264ns   950.2mV    953.2mV    989.7mV
1.62ns    947mV      890mV      989.5mV
2.62ns    944.3mV    885.5mV    989.4mV
[Falling Waveform]
R_fixture = 50
V_fixture = 0
V_fixture_min = 0
V_fixture_max = 0
0s        845.6mV    808.8mV    906.6mV
85.5ps    845.6mV    808.8mV    891.9mV
188ps     836.1mV    808.8mV    678.2mV
387.2ps   481.9mV    804.7mV    217.5mV
554.8ps   242.1mV    616.1mV    22.65mV
723.9ps   88.3mV     397.4mV    4.854mV
902.2ps   13.94mV    201.7mV    0V
1.217ns   5.568mV    64.99mV    0V
1.616ns   3.383mV    5.9mV      0V
2.633ns   0V         3.866mV    0V
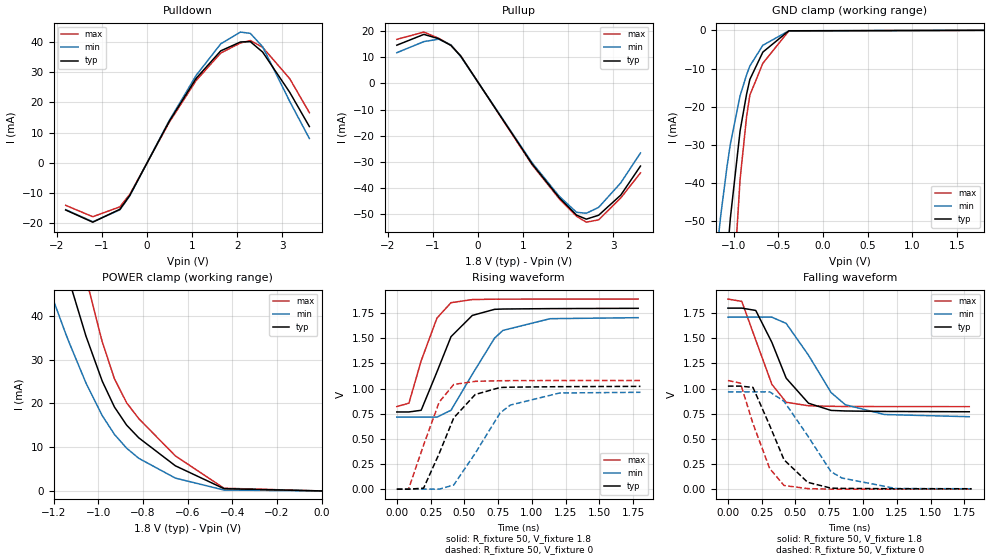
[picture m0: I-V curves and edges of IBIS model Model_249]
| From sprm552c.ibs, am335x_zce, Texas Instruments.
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| Model based on original model for BCSHTLTCSCDVPBFZ_SSDHV
|   Sub model SR10_10MA_5PER_1P8
[model]   Model_249
|[Description]  [1.8V-3-STATE-NOTERM-SR10:10MA, IND, 5%]
|   Fast slew rate (SR[1:0] = "10"), 0.80 * RExt = 1.250 * Iout
|   (I[2:0] = "101"), 10mA nominal with Rext = 50R,ODT off (ODT[1:0]
|   = "00") CMOS mode,Industrial temperature range (-40C to 125C,
|   25C nominal),5% power supply tolerance
|[Input Load]   NOTERM
|[Output Drive] SR10:10MA
|Voltage   1.8V
|Mode   3-STATE
Model_type   3-state
Polarity   Non-Inverting
Enable   Active-Low
Cref =  15pF
Rref =  100.0000M
Vref =  0V
Vmeas =  0.9
C_comp   1.851324p   1.667199p   1.973575p
[Temperature Range]   25   125   -40
[Voltage Range]   1.8   1.71   1.89
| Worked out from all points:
|   slope of the pulldown table from 0 to 0.27 V, typ, clamps not added: 35.3 ohm
|   slope of the pullup table from 0 to 0.27 V, typ, clamps not added: 36.9 ohm
|   GND clamp passes 1 mA (typ) near -0.49 V on its own axis
|   POWER clamp passes 1 mA (typ) near -0.47 V on its own axis
|   rising waveform, R_fixture 50, V_fixture 1.8: 20-80 % time 192ps typ, 267ps min, 155ps max; typ from 0.767 V to 1.8 V
|   rising waveform, R_fixture 50, V_fixture 0: 20-80 % time 209ps typ, 266ps min, 164ps max; typ from 0 V to 1.02 V
|   falling waveform, R_fixture 50, V_fixture 1.8: 20-80 % time 216ps typ, 277ps min, 166ps max; typ from 1.8 V to 0.769 V
|   falling waveform, R_fixture 50, V_fixture 0: 20-80 % time 205ps typ, 281ps min, 164ps max; typ from 1.02 V to 0.004 V
[POWER_clamp]
-1.8V     194.9mA    137mA      262.9mA
-1.236V   68.49mA    48.49mA    92.7mA
-1.145V   50.76mA    35.84mA    69.67mA
-1.127V   47.56mA    33.52mA    65.35mA
-1.055V   35.4mA     24.68mA    48.7mA
-981.8mV  25.06mA    17.19mA    34.02mA
-927.3mV  19.17mA    12.92mA    25.62mA
-872.7mV  15.03mA    9.76mA     20.13mA
-818.2mV  12.12mA    7.445mA    16.51mA
-654.5mV  5.738mA    2.929mA    8.007mA
-436.4mV  508.2uA    199.4uA    613uA
0V        2.273nA    16.6nA     10.58nA
[Pulldown]
-1.8V     -15.77mA   -15.64mA   -14.22mA
-1.2V     -19.82mA   -19.67mA   -18mA
-600mV    -15.53mA   -15.72mA   -14.72mA
-381.8mV  -10.95mA   -11.1mA    -10.62mA
490.9mV   13.63mA    13.9mA     13.29mA
1.091V    28.02mA    29.01mA    27.31mA
1.636V    37.17mA    39.51mA    36.44mA
2.073V    40.12mA    43.41mA    39.79mA
2.291V    40.23mA    43mA       40.61mA
2.564V    36.78mA    38.54mA    38.36mA
3.164V    23.4mA     20.37mA    27.93mA
3.6V      12mA       8.024mA    16.62mA
[Pullup]
-1.8V     14.55mA    11.68mA    16.78mA
-1.2V     18.67mA    15.92mA    19.55mA
-872.7mV  17.03mA    16.84mA    17.19mA
-600mV    14.45mA    14.67mA    14.53mA
-381.8mV  10.35mA    10.21mA    10.45mA
1.2V      -30.78mA   -30.35mA   -31.1mA
1.8V      -43.65mA   -43.1mA    -44.07mA
2.182V    -50.28mA   -49.21mA   -50.74mA
2.4V      -51.84mA   -49.59mA   -53mA
2.673V    -50.34mA   -47.35mA   -52.1mA
3.164V    -42.65mA   -37.97mA   -43.72mA
3.6V      -31.58mA   -26.59mA   -34.19mA
[GND_clamp]
-1.8V     -346.1mA   -209.3mA   -568.3mA
-1.327V   -149.7mA   -89.03mA   -250.9mA
-1.291V   -135.6mA   -80.47mA   -227.5mA
-1.145V   -82.35mA   -48.67mA   -137.7mA
-1.073V   -59.44mA   -35.55mA   -97.96mA
-1.036V   -49.1mA    -29.72mA   -79.9mA
-927.3mV  -26.31mA   -17.11mA   -38.99mA
-854.5mV  -16.67mA   -11.64mA   -22.56mA
-818.2mV  -12.86mA   -9.351mA   -16.98mA
-672.7mV  -5.705mA   -3.913mA   -8.623mA
-381.8mV  -120.4uA   -129uA     -167.2uA
1.8V      2.273nA    51.44nA    6.654nA
[Ramp]
dV/dt_f 0.62165498/0.21776281n 0.59817442/0.27746816n 0.64307379/0.16659714n
dV/dt_r 0.61683844/0.21002964n 0.58230182/0.2668494n 0.64967366/0.16468496n
R_load = 50
[Rising Waveform]
R_fixture = 50
V_fixture = 1.8
V_fixture_min = 1.71
V_fixture_max = 1.89
0s        767.5mV    716.3mV    820.9mV
89.6ps    767.5mV    716.3mV    854.9mV
180.3ps   784.4mV    716.3mV    1.276V
297.2ps   1.166V     716.3mV    1.701V
401.3ps   1.516V     784.4mV    1.854V
558.5ps   1.727V     1.141V     1.885V
723.9ps   1.788V     1.502V     1.889V
785.3ps   1.791V     1.578V     1.889V
1.135ns   1.795V     1.695V     1.89V
1.787ns   1.798V     1.705V     1.89V
[Rising Waveform]
R_fixture = 50
V_fixture = 0
V_fixture_min = 0
V_fixture_max = 0
0s        0V         0V         0V
86.6ps    0V         0V         0V
198.3ps   10.1mV     0V         438.7mV
313.6ps   353.7mV    0V         865.3mV
421.4ps   708.5mV    41.38mV    1.041V
580.4ps   941.1mV    356.4mV    1.072V
764.8ps   1.011V     757.4mV    1.078V
841.4ps   1.014V     836.5mV    1.079V
1.206ns   1.019V     956.4mV    1.08V
1.804ns   1.022V     963mV      1.08V
[Falling Waveform]
R_fixture = 50
V_fixture = 1.8
V_fixture_min = 1.71
V_fixture_max = 1.89
0s        1.799V     1.709V     1.889V
102.7ps   1.799V     1.709V     1.866V
206ps     1.776V     1.709V     1.482V
325.3ps   1.459V     1.709V     1.042V
431.4ps   1.103V     1.647V     863.5mV
596.6ps   853.9mV    1.331V     828.8mV
763.9ps   782.6mV    960mV      823.3mV
869.9ps   777mV      838.5mV    821.7mV
1.159ns   772.2mV    741.7mV    820.3mV
1.787ns   769.1mV    719.9mV    820mV
[Falling Waveform]
R_fixture = 50
V_fixture = 0
V_fixture_min = 0
V_fixture_max = 0
0s        1.024V     967.1mV    1.08V
92.7ps    1.024V     967.1mV    1.054V
185.4ps   1.011V     967.1mV    651.3mV
309.2ps   633.3mV    967.1mV    205.9mV
415.5ps   291.7mV    873.1mV    36.23mV
590.5ps   68.02mV    531.1mV    5.6mV
763.4ps   10.26mV    173.4mV    0V
844.7ps   7.774mV    110.2mV    0V
1.245ns   4.224mV    6.493mV    0V
1.804ns   4.224mV    4.006mV    0V
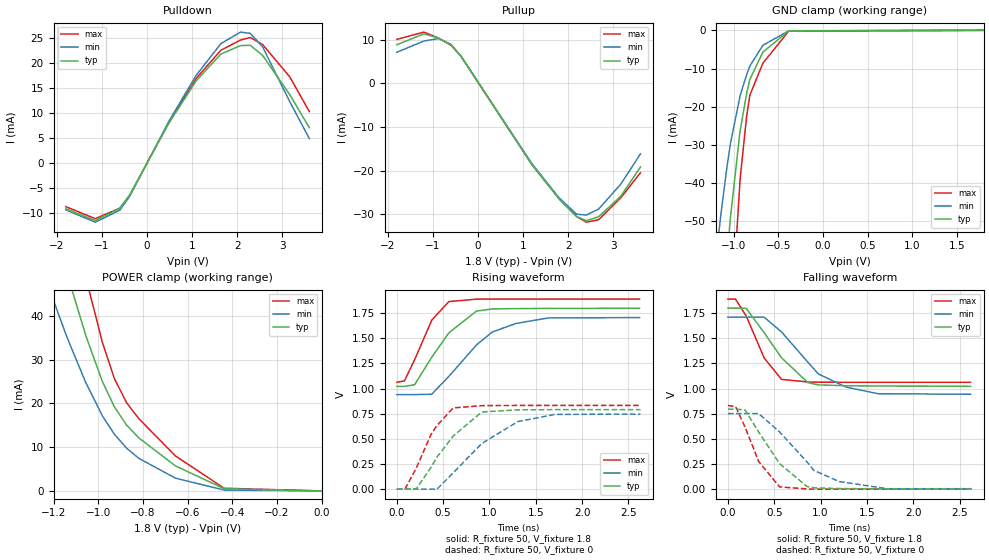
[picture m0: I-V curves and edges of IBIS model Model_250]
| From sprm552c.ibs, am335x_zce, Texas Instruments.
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| Model based on original model for BCSHTLTCSCDVPBFZ_SSDHV
|   Sub model SR11_6MA_5PER_1P8
[model]   Model_250
|[Description]  [1.8V-3-STATE-NOTERM-SR11:6MA, IND, 5%]
|   Slowest slew rate (SR[1:0] = "11"), 1.33 * RExt = 0.750 * Iout
|   (I[2:0] = "001"), 6mA nominal with Rext = 50R,ODT off (ODT[1:0]
|   = "00") CMOS mode,Industrial temperature range (-40C to 125C,
|   25C nominal),5% power supply tolerance
|[Input Load]   NOTERM
|[Output Drive] SR11:6MA
|Voltage   1.8V
|Mode   3-STATE
Model_type   3-state
Polarity   Non-Inverting
Enable   Active-Low
Cref =  15pF
Rref =  100.0000M
Vref =  0V
Vmeas =  0.9
C_comp   1.851324p   1.667199p   1.973575p
[Temperature Range]   25   125   -40
[Voltage Range]   1.8   1.71   1.89
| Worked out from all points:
|   slope of the pulldown table from 0 to 0.27 V, typ, clamps not added: 60.1 ohm
|   slope of the pullup table from 0 to 0.27 V, typ, clamps not added: 60.8 ohm
|   GND clamp passes 1 mA (typ) near -0.49 V on its own axis
|   POWER clamp passes 1 mA (typ) near -0.47 V on its own axis
|   rising waveform, R_fixture 50, V_fixture 1.8: 20-80 % time 360ps typ, 476ps min, 249ps max; typ from 1.02 V to 1.8 V
|   rising waveform, R_fixture 50, V_fixture 0: 20-80 % time 382ps typ, 514ps min, 273ps max; typ from 0 V to 0.791 V
|   falling waveform, R_fixture 50, V_fixture 1.8: 20-80 % time 367ps typ, 477ps min, 246ps max; typ from 1.8 V to 1.02 V
|   falling waveform, R_fixture 50, V_fixture 0: 20-80 % time 359ps typ, 477ps min, 251ps max; typ from 0.794 V to 0 V
[POWER_clamp]
-1.8V     194.9mA    137mA      262.9mA
-1.236V   68.49mA    48.49mA    92.7mA
-1.145V   50.76mA    35.84mA    69.67mA
-1.127V   47.56mA    33.52mA    65.35mA
-1.055V   35.4mA     24.68mA    48.7mA
-981.8mV  25.06mA    17.19mA    34.02mA
-927.3mV  19.17mA    12.92mA    25.62mA
-872.7mV  15.03mA    9.76mA     20.13mA
-818.2mV  12.12mA    7.445mA    16.51mA
-654.5mV  5.738mA    2.929mA    8.007mA
-436.4mV  508.2uA    199.4uA    613uA
0V        2.273nA    16.6nA     10.58nA
[Pulldown]
-1.8V     -9.241mA   -9.444mA   -8.801mA
-1.145V   -11.6mA    -11.92mA   -11.21mA
-600mV    -9.112mA   -9.503mA   -9.119mA
-381.8mV  -6.424mA   -6.715mA   -6.584mA
490.9mV   7.999mA    8.408mA    8.235mA
1.091V    16.44mA    17.54mA    16.92mA
1.636V    21.8mA     23.88mA    22.57mA
2.073V    23.52mA    26.23mA    24.63mA
2.291V    23.58mA    25.97mA    25.14mA
2.564V    21.54mA    23.27mA    23.74mA
3.164V    13.7mA     12.29mA    17.27mA
3.6V      7.029mA    4.844mA    10.28mA
[Pullup]
-1.8V     8.832mA    7.105mA    10.06mA
-1.2V     11.33mA    9.687mA    11.73mA
-872.7mV  10.35mA    10.25mA    10.32mA
-600mV    8.779mA    8.934mA    8.725mA
-381.8mV  6.289mA    6.222mA    6.276mA
1.2V      -18.71mA   -18.49mA   -18.68mA
1.8V      -26.52mA   -26.26mA   -26.46mA
2.182V    -30.54mA   -29.96mA   -30.46mA
2.4V      -31.47mA   -30.18mA   -31.81mA
2.673V    -30.55mA   -28.81mA   -31.25mA
3.164V    -25.87mA   -23.09mA   -26.21mA
3.6V      -19.15mA   -16.17mA   -20.49mA
[GND_clamp]
-1.8V     -346.1mA   -209.3mA   -568.3mA
-1.327V   -149.7mA   -89.03mA   -250.9mA
-1.291V   -135.6mA   -80.47mA   -227.5mA
-1.145V   -82.35mA   -48.67mA   -137.7mA
-1.073V   -59.44mA   -35.55mA   -97.96mA
-1.036V   -49.1mA    -29.72mA   -79.9mA
-927.3mV  -26.31mA   -17.11mA   -38.99mA
-854.5mV  -16.67mA   -11.64mA   -22.56mA
-818.2mV  -12.86mA   -9.351mA   -16.98mA
-672.7mV  -5.705mA   -3.913mA   -8.623mA
-381.8mV  -120.4uA   -129uA     -167.2uA
1.8V      2.273nA    51.44nA    6.654nA
[Ramp]
dV/dt_f   0.468361/0.36978137n 0.46325919/0.4797466n 0.49765847/0.2465133n
dV/dt_r 0.47852287/0.38493002n 0.45218566/0.5170422n 0.50054423/0.27422032n
R_load = 50
[Rising Waveform]
R_fixture = 50
V_fixture = 1.8
V_fixture_min = 1.71
V_fixture_max = 1.89
0s        1.022V     940.4mV    1.063V
81.9ps    1.022V     940.4mV    1.076V
191.8ps   1.038V     940.4mV    1.286V
377.3ps   1.312V     943.9mV    1.68V
561.3ps   1.554V     1.121V     1.865V
860.2ps   1.771V     1.434V     1.889V
1.03ns    1.792V     1.562V     1.89V
1.284ns   1.795V     1.647V     1.89V
1.632ns   1.797V     1.702V     1.89V
2.62ns    1.799V     1.706V     1.89V
[Rising Waveform]
R_fixture = 50
V_fixture = 0
V_fixture_min = 0
V_fixture_max = 0
0s        0V         0V         0V
87ps      0V         0V         0V
211.5ps   5.502mV    0V         211.6mV
367.3ps   213.9mV    0V         540.6mV
433.5ps   318.2mV    0V         633.6mV
608.5ps   528.1mV    161.8mV    807.3mV
917ps     767.1mV    454.2mV    830.4mV
1.306ns   788.6mV    671.6mV    832.5mV
1.706ns   790.5mV    743.2mV    832.7mV
2.63ns    790.5mV    746.7mV    832.7mV
[Falling Waveform]
R_fixture = 50
V_fixture = 1.8
V_fixture_min = 1.71
V_fixture_max = 1.89
0s        1.799V     1.709V     1.889V
81.2ps    1.799V     1.709V     1.889V
197.1ps   1.797V     1.709V     1.722V
391ps     1.555V     1.709V     1.304V
578.3ps   1.306V     1.563V     1.091V
863.9ps   1.058V     1.261V     1.065V
975.9ps   1.036V     1.145V     1.063V
1.273ns   1.028V     1.015V     1.062V
1.621ns   1.025V     948.4mV    1.062V
2.62ns    1.022V     943.2mV    1.062V
[Falling Waveform]
R_fixture = 50
V_fixture = 0
V_fixture_min = 0
V_fixture_max = 0
0s        794.5mV    750.8mV    831.7mV
83.4ps    794.5mV    750.8mV    818.7mV
184.7ps   787.9mV    750.8mV    617.4mV
332.2ps   567.4mV    750.8mV    274.3mV
557.2ps   253.8mV    569.7mV    22.8mV
854.5ps   25.68mV    269.7mV    2.242mV
926.7ps   13.35mV    187.4mV    0V
1.2ns     6.12mV     75.64mV    0V
1.718ns   3.203mV    4.867mV    0V
2.63ns    0V         4.82mV     0V
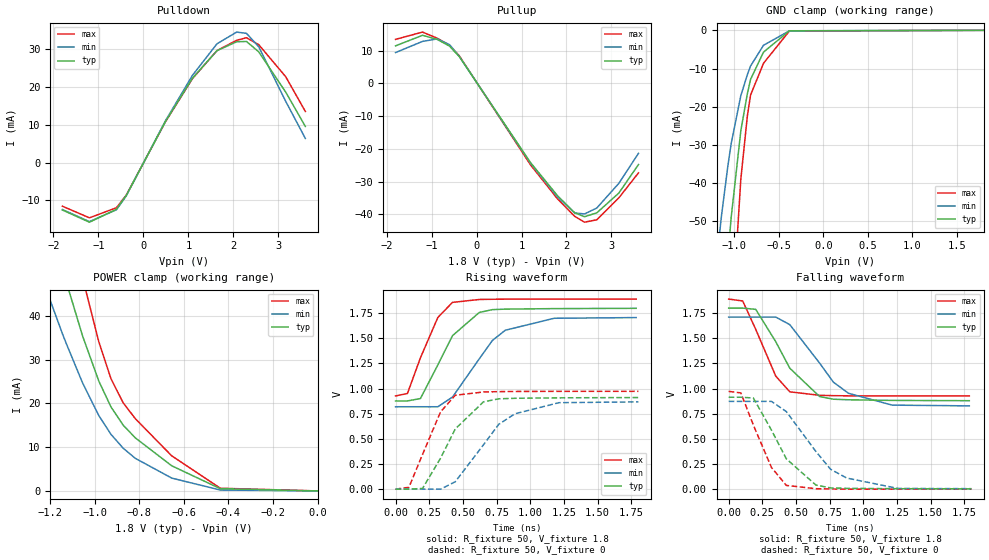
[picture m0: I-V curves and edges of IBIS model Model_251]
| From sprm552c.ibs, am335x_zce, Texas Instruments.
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| Model based on original model for BCSHTLTCSCDVPBFZ_SSDHV
|   Sub model SR10_8MA_5PER_1P8
[model]   Model_251
|[Description]  [1.8V-3-STATE-NOTERM-SR10:8MA, IND, 5%]
|   Fast slew rate (SR[1:0] = "10"), 1.00 * RExt = 1.000 * Iout
|   (I[2:0] = "011"), 8mA nominal with Rext = 50R,ODT off (ODT[1:0]
|   = "00") CMOS mode,Industrial temperature range (-40C to 125C,
|   25C nominal),5% power supply tolerance
|[Input Load]   NOTERM
|[Output Drive] SR10:8MA
|Voltage   1.8V
|Mode   3-STATE
Model_type   3-state
Polarity   Non-Inverting
Enable   Active-Low
Cref =  15pF
Rref =  100.0000M
Vref =  0V
Vmeas =  0.9
C_comp   1.851324p   1.667199p   1.973575p
[Temperature Range]   25   125   -40
[Voltage Range]   1.8   1.71   1.89
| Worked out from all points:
|   slope of the pulldown table from 0 to 0.27 V, typ, clamps not added: 44.4 ohm
|   slope of the pullup table from 0 to 0.27 V, typ, clamps not added: 47 ohm
|   GND clamp passes 1 mA (typ) near -0.49 V on its own axis
|   POWER clamp passes 1 mA (typ) near -0.47 V on its own axis
|   rising waveform, R_fixture 50, V_fixture 1.8: 20-80 % time 223ps typ, 288ps min, 171ps max; typ from 0.877 V to 1.8 V
|   rising waveform, R_fixture 50, V_fixture 0: 20-80 % time 234ps typ, 296ps min, 181ps max; typ from 0 V to 0.911 V
|   falling waveform, R_fixture 50, V_fixture 1.8: 20-80 % time 245ps typ, 302ps min, 181ps max; typ from 1.8 V to 0.879 V
|   falling waveform, R_fixture 50, V_fixture 0: 20-80 % time 240ps typ, 298ps min, 180ps max; typ from 0.914 V to 0.003 V
[POWER_clamp]
-1.8V     194.9mA    137mA      262.9mA
-1.236V   68.49mA    48.49mA    92.7mA
-1.145V   50.76mA    35.84mA    69.67mA
-1.127V   47.56mA    33.52mA    65.35mA
-1.055V   35.4mA     24.68mA    48.7mA
-981.8mV  25.06mA    17.19mA    34.02mA
-927.3mV  19.17mA    12.92mA    25.62mA
-872.7mV  15.03mA    9.76mA     20.13mA
-818.2mV  12.12mA    7.445mA    16.51mA
-654.5mV  5.738mA    2.929mA    8.007mA
-436.4mV  508.2uA    199.4uA    613uA
0V        2.273nA    16.6nA     10.58nA
[Pulldown]
-1.8V     -12.51mA   -12.38mA   -11.51mA
-1.2V     -15.72mA   -15.57mA   -14.57mA
-600mV    -12.32mA   -12.45mA   -11.92mA
-381.8mV  -8.686mA   -8.794mA   -8.605mA
490.9mV   10.82mA    11.01mA    10.76mA
1.091V    22.23mA    22.98mA    22.12mA
1.636V    29.48mA    31.29mA    29.5mA
2.073V    31.82mA    34.37mA    32.21mA
2.291V    31.9mA     34.04mA    32.88mA
2.564V    29.16mA    30.5mA     31.05mA
3.164V    18.55mA    16.11mA    22.6mA
3.6V      9.513mA    6.35mA     13.45mA
[Pullup]
-1.8V     11.43mA    9.39mA     13.42mA
-1.2V     14.67mA    12.8mA     15.64mA
-872.7mV  13.39mA    13.55mA    13.76mA
-600mV    11.36mA    11.8mA     11.63mA
-381.8mV  8.135mA    8.218mA    8.363mA
1.2V      -24.2mA    -24.42mA   -24.89mA
1.8V      -34.31mA   -34.68mA   -35.27mA
2.182V    -39.52mA   -39.59mA   -40.61mA
2.4V      -40.73mA   -39.88mA   -42.4mA
2.673V    -39.55mA   -38.08mA   -41.67mA
3.164V    -33.5mA    -30.53mA   -34.96mA
3.6V      -24.8mA    -21.38mA   -27.34mA
[GND_clamp]
-1.8V     -346.1mA   -209.3mA   -568.3mA
-1.327V   -149.7mA   -89.03mA   -250.9mA
-1.291V   -135.6mA   -80.47mA   -227.5mA
-1.145V   -82.35mA   -48.67mA   -137.7mA
-1.073V   -59.44mA   -35.55mA   -97.96mA
-1.036V   -49.1mA    -29.72mA   -79.9mA
-927.3mV  -26.31mA   -17.11mA   -38.99mA
-854.5mV  -16.67mA   -11.64mA   -22.56mA
-818.2mV  -12.86mA   -9.351mA   -16.98mA
-672.7mV  -5.705mA   -3.913mA   -8.623mA
-381.8mV  -120.4uA   -129uA     -167.2uA
1.8V      2.273nA    51.44nA    6.654nA
[Ramp]
dV/dt_f 0.55522611/0.24622488n 0.53560309/0.30766057n 0.57920009/0.18077981n
dV/dt_r 0.54995656/0.23529675n  0.5247575/0.29759031n 0.58468736/0.18133789n
R_load = 50
[Rising Waveform]
R_fixture = 50
V_fixture = 1.8
V_fixture_min = 1.71
V_fixture_max = 1.89
0s        877.3mV    819.4mV    926.9mV
88.4ps    877.3mV    819.4mV    951.4mV
184.8ps   901mV      819.4mV    1.306V
314ps     1.235V     819.4mV    1.707V
422.9ps   1.526V     915.8mV    1.857V
621.9ps   1.757V     1.296V     1.886V
719.6ps   1.785V     1.479V     1.888V
814.8ps   1.79V      1.58V      1.889V
1.178ns   1.795V     1.699V     1.89V
1.787ns   1.798V     1.706V     1.89V
[Rising Waveform]
R_fixture = 50
V_fixture = 0
V_fixture_min = 0
V_fixture_max = 0
0s        0V         0V         0V
99.4ps    0V         0V         18.89mV
200.3ps   7.169mV    0V         344.9mV
334ps     307.3mV    0V         767.8mV
443.4ps   598.6mV    73.77mV    933.8mV
653.1ps   868.4mV    441.3mV    966.1mV
766.5ps   898.2mV    645.1mV    969.7mV
887.2ps   903.5mV    749.8mV    971.4mV
1.213ns   908.1mV    859.8mV    972.5mV
1.804ns   910.9mV    867.8mV    972.6mV
[Falling Waveform]
R_fixture = 50
V_fixture = 1.8
V_fixture_min = 1.71
V_fixture_max = 1.89
0s        1.799V     1.71V      1.889V
104.1ps   1.799V     1.71V      1.87V
200.7ps   1.787V     1.71V      1.589V
349.4ps   1.466V     1.71V      1.124V
453.8ps   1.202V     1.635V     967.3mV
675ps     920.5mV    1.253V     932.7mV
777.8ps   893.8mV    1.063V     929.1mV
889.5ps   888.2mV    953.1mV    927.4mV
1.214ns   882mV      835.1mV    926.6mV
1.787ns   879.1mV    827.7mV    926mV
[Falling Waveform]
R_fixture = 50
V_fixture = 0
V_fixture_min = 0
V_fixture_max = 0
0s        913.5mV    872.5mV    971.8mV
90.5ps    913.5mV    872.5mV    956.4mV
183.2ps   905.8mV    872.5mV    637.3mV
317.6ps   587.1mV    872.5mV    216.4mV
428.3ps   301.2mV    770.8mV    37.03mV
647.8ps   40.92mV    374.4mV    4.656mV
757.1ps   12.57mV    197.5mV    2.426mV
876.4ps   8.132mV    110.7mV    0V
1.257ns   4.613mV    7.217mV    0V
1.804ns   3.395mV    4.903mV    0V
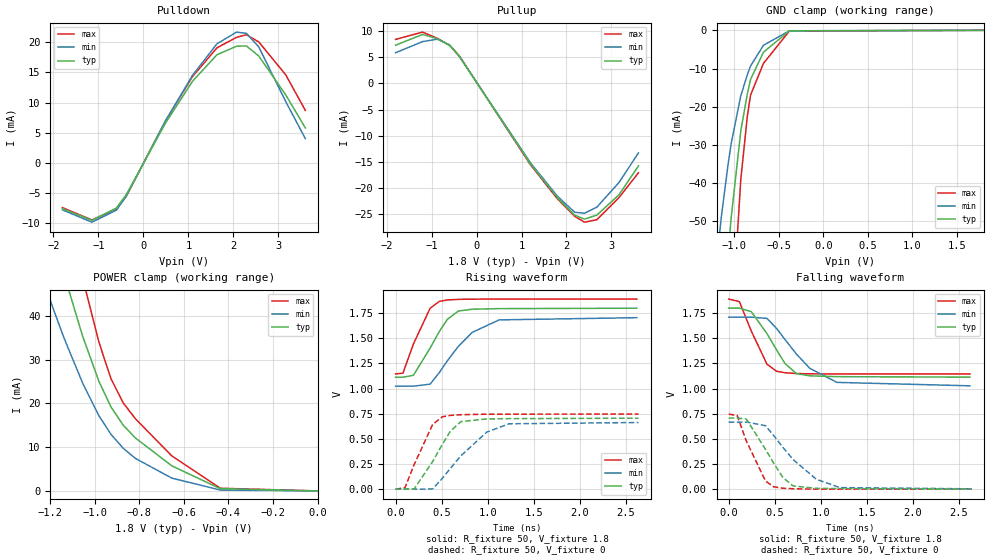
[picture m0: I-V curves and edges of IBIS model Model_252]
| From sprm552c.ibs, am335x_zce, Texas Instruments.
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| Model based on original model for BCSHTLTCSCDVPBFZ_SSDHV
|   Sub model SR10_5MA_5PER_1P8
[model]   Model_252
|[Description]  [1.8V-3-STATE-NOTERM-SR10:5MA, IND, 5%]
|   Fast slew rate (SR[1:0] = "10"), 1.60 * RExt = 0.625 * Iout
|   (I[2:0] = "000"), 5mA nominal with Rext = 50R,ODT off (ODT[1:0]
|   = "00") CMOS mode,Industrial temperature range (-40C to 125C,
|   25C nominal),5% power supply tolerance
|[Input Load]   NOTERM
|[Output Drive] SR10:5MA
|Voltage   1.8V
|Mode   3-STATE
Model_type   3-state
Polarity   Non-Inverting
Enable   Active-Low
Cref =  15pF
Rref =  100.0000M
Vref =  0V
Vmeas =  0.9
C_comp   1.851324p   1.667199p   1.973575p
[Temperature Range]   25   125   -40
[Voltage Range]   1.8   1.71   1.89
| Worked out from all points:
|   slope of the pulldown table from 0 to 0.27 V, typ, clamps not added: 72.9 ohm
|   slope of the pullup table from 0 to 0.27 V, typ, clamps not added: 73.8 ohm
|   GND clamp passes 1 mA (typ) near -0.49 V on its own axis
|   POWER clamp passes 1 mA (typ) near -0.47 V on its own axis
|   rising waveform, R_fixture 50, V_fixture 1.8: 20-80 % time 258ps typ, 375ps min, 197ps max; typ from 1.11 V to 1.8 V
|   rising waveform, R_fixture 50, V_fixture 0: 20-80 % time 267ps typ, 406ps min, 215ps max; typ from 0 V to 0.706 V
|   falling waveform, R_fixture 50, V_fixture 1.8: 20-80 % time 276ps typ, 406ps min, 210ps max; typ from 1.8 V to 1.11 V
|   falling waveform, R_fixture 50, V_fixture 0: 20-80 % time 274ps typ, 399ps min, 211ps max; typ from 0.707 V to 0 V
[POWER_clamp]
-1.8V     194.9mA    137mA      262.9mA
-1.236V   68.49mA    48.49mA    92.7mA
-1.145V   50.76mA    35.84mA    69.67mA
-1.127V   47.56mA    33.52mA    65.35mA
-1.055V   35.4mA     24.68mA    48.7mA
-981.8mV  25.06mA    17.19mA    34.02mA
-927.3mV  19.17mA    12.92mA    25.62mA
-872.7mV  15.03mA    9.76mA     20.13mA
-818.2mV  12.12mA    7.445mA    16.51mA
-654.5mV  5.738mA    2.929mA    8.007mA
-436.4mV  508.2uA    199.4uA    613uA
0V        2.273nA    16.6nA     10.58nA
[Pulldown]
-1.8V     -7.609mA   -7.815mA   -7.446mA
-1.145V   -9.551mA   -9.863mA   -9.487mA
-600mV    -7.505mA   -7.866mA   -7.717mA
-381.8mV  -5.292mA   -5.559mA   -5.572mA
490.9mV   6.589mA    6.96mA     6.97mA
1.091V    13.54mA    14.52mA    14.32mA
1.636V    17.95mA    19.77mA    19.1mA
2.073V    19.37mA    21.71mA    20.85mA
2.291V    19.41mA    21.49mA    21.27mA
2.564V    17.74mA    19.25mA    20.08mA
3.164V    11.28mA    10.17mA    14.61mA
3.6V      5.787mA    4.008mA    8.697mA
[Pullup]
-1.8V     7.273mA    5.836mA    8.384mA
-1.2V     9.332mA    7.957mA    9.779mA
-872.7mV  8.52mA     8.421mA    8.6mA
-600mV    7.23mA     7.34mA     7.272mA
-381.8mV  5.181mA    5.112mA    5.231mA
1.2V      -15.41mA   -15.19mA   -15.57mA
1.8V      -21.85mA   -21.57mA   -22.06mA
2.182V    -25.16mA   -24.61mA   -25.39mA
2.4V      -25.92mA   -24.79mA   -26.51mA
2.673V    -25.16mA   -23.66mA   -26.04mA
3.164V    -21.3mA    -18.96mA   -21.84mA
3.6V      -15.77mA   -13.28mA   -17.07mA
[GND_clamp]
-1.8V     -346.1mA   -209.3mA   -568.3mA
-1.327V   -149.7mA   -89.03mA   -250.9mA
-1.291V   -135.6mA   -80.47mA   -227.5mA
-1.145V   -82.35mA   -48.67mA   -137.7mA
-1.073V   -59.44mA   -35.55mA   -97.96mA
-1.036V   -49.1mA    -29.72mA   -79.9mA
-927.3mV  -26.31mA   -17.11mA   -38.99mA
-854.5mV  -16.67mA   -11.64mA   -22.56mA
-818.2mV  -12.86mA   -9.351mA   -16.98mA
-672.7mV  -5.705mA   -3.913mA   -8.623mA
-381.8mV  -120.4uA   -129uA     -167.2uA
1.8V      2.273nA    51.44nA    6.654nA
[Ramp]
dV/dt_f 0.41354576/0.27676229n 0.41291431/0.40991903n 0.44774482/0.21043547n
dV/dt_r 0.42533446/0.26793504n 0.40108135/0.4100088n 0.44838914/0.21524887n
R_load = 50
[Rising Waveform]
R_fixture = 50
V_fixture = 1.8
V_fixture_min = 1.71
V_fixture_max = 1.89
0s        1.113V     1.024V     1.146V
80.2ps    1.113V     1.024V     1.153V
193.8ps   1.132V     1.024V     1.443V
375.1ps   1.402V     1.044V     1.798V
475.7ps   1.568V     1.16V      1.867V
562.5ps   1.688V     1.276V     1.881V
681.1ps   1.771V     1.419V     1.887V
833.2ps   1.789V     1.559V     1.889V
1.125ns   1.795V     1.683V     1.89V
2.62ns    1.799V     1.705V     1.89V
[Rising Waveform]
R_fixture = 50
V_fixture = 0
V_fixture_min = 0
V_fixture_max = 0
0s        0V         0V         0V
102.5ps   0V         0V         14.61mV
203.5ps   4.42mV     0V         247.5mV
403ps     274.5mV    2.259mV    644.1mV
508.7ps   445.8mV    108.1mV    719.5mV
593.3ps   573.7mV    204mV      733.3mV
709.3ps   671.6mV    331.7mV    740.5mV
989.9ps   698.1mV    566.7mV    745.1mV
1.232ns   701.2mV    649.9mV    745.9mV
2.638ns   705.7mV    662.7mV    746.1mV
[Falling Waveform]
R_fixture = 50
V_fixture = 1.8
V_fixture_min = 1.71
V_fixture_max = 1.89
0s        1.799V     1.709V     1.889V
115.8ps   1.799V     1.709V     1.864V
245.7ps   1.764V     1.709V     1.571V
415.7ps   1.546V     1.697V     1.242V
518.4ps   1.387V     1.599V     1.172V
610.3ps   1.25V      1.489V     1.157V
736.1ps   1.148V     1.342V     1.149V
882.3ps   1.126V     1.2V       1.146V
1.176ns   1.118V     1.061V     1.145V
2.62ns    1.113V     1.027V     1.145V
[Falling Waveform]
R_fixture = 50
V_fixture = 0
V_fixture_min = 0
V_fixture_max = 0
0s        706.8mV    666.8mV    745.1mV
92.2ps    706.8mV    666.8mV    732.5mV
192.6ps   695.6mV    666.8mV    476.9mV
400.1ps   395.4mV    630.7mV    80.53mV
489.5ps   257.2mV    532mV      23.19mV
589.2ps   115.9mV    415mV      9.193mV
699.7ps   31.97mV    294.3mV    4.32mV
952.2ps   8.408mV    98.01mV    0V
1.21ns    5.65mV     15.39mV    0V
2.638ns   0V         3.53mV     0V
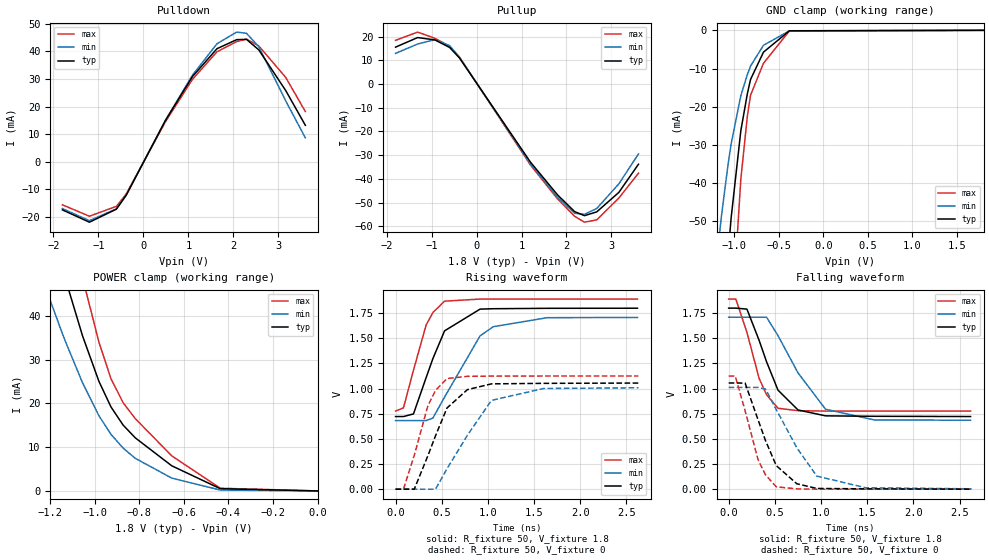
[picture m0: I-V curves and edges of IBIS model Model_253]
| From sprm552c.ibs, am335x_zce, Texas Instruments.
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| Model based on original model for BCSHTLTCSCDVPBFZ_SSDHV
|   Sub model SR11_11MA_5PER_1P8
[model]   Model_253
|[Description]  [1.8V-3-STATE-NOTERM-SR11:11MA, IND, 5%]
|   Slowest slew rate (SR[1:0] = "11"), 0.73 * RExt = 1.325 * Iout
|   (I[2:0] = "110"), 11mA nominal with Rext = 50R,ODT off (ODT[1:0]
|   = "00") CMOS mode,Industrial temperature range (-40C to 125C,
|   25C nominal),5% power supply tolerance
|[Input Load]   NOTERM
|[Output Drive] SR11:11MA
|Voltage   1.8V
|Mode   3-STATE
Model_type   3-state
Polarity   Non-Inverting
Enable   Active-Low
Cref =  15pF
Rref =  100.0000M
Vref =  0V
Vmeas =  0.9
C_comp   1.851324p   1.667199p   1.973575p
[Temperature Range]   25   125   -40
[Voltage Range]   1.8   1.71   1.89
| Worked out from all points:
|   slope of the pulldown table from 0 to 0.27 V, typ, clamps not added: 32 ohm
|   slope of the pullup table from 0 to 0.27 V, typ, clamps not added: 34.5 ohm
|   GND clamp passes 1 mA (typ) near -0.49 V on its own axis
|   POWER clamp passes 1 mA (typ) near -0.47 V on its own axis
|   rising waveform, R_fixture 50, V_fixture 1.8: 20-80 % time 265ps typ, 400ps min, 208ps max; typ from 0.722 V to 1.8 V
|   rising waveform, R_fixture 50, V_fixture 0: 20-80 % time 280ps typ, 398ps min, 221ps max; typ from 0 V to 1.05 V
|   falling waveform, R_fixture 50, V_fixture 1.8: 20-80 % time 270ps typ, 364ps min, 217ps max; typ from 1.8 V to 0.722 V
|   falling waveform, R_fixture 50, V_fixture 0: 20-80 % time 263ps typ, 398ps min, 212ps max; typ from 1.05 V to 0 V
[POWER_clamp]
-1.8V     194.9mA    137mA      262.9mA
-1.236V   68.49mA    48.49mA    92.7mA
-1.145V   50.76mA    35.84mA    69.67mA
-1.127V   47.56mA    33.52mA    65.35mA
-1.055V   35.4mA     24.68mA    48.7mA
-981.8mV  25.06mA    17.19mA    34.02mA
-927.3mV  19.17mA    12.92mA    25.62mA
-872.7mV  15.03mA    9.76mA     20.13mA
-818.2mV  12.12mA    7.445mA    16.51mA
-654.5mV  5.738mA    2.929mA    8.007mA
-436.4mV  508.2uA    199.4uA    613uA
0V        2.273nA    16.6nA     10.58nA
[Pulldown]
-1.8V     -17.41mA   -16.94mA   -15.58mA
-1.2V     -21.87mA   -21.31mA   -19.71mA
-600mV    -17.14mA   -17.03mA   -16.12mA
-381.8mV  -12.08mA   -12.02mA   -11.63mA
490.9mV   15.04mA    15.06mA    14.55mA
1.091V    30.91mA    31.42mA    29.9mA
1.636V    41.01mA    42.8mA     39.9mA
2.073V    44.27mA    47.02mA    43.57mA
2.291V    44.39mA    46.59mA    44.48mA
2.564V    40.59mA    41.76mA    42.02mA
3.164V    25.83mA    22.07mA    30.59mA
3.6V      13.24mA    8.694mA    18.21mA
[Pullup]
-1.8V     15.59mA    12.95mA    18.46mA
-1.309V   19.63mA    16.9mA     21.94mA
-927.3mV  18.65mA    18.73mA    19.33mA
-600mV    15.48mA    16.26mA    15.99mA
-381.8mV  11.09mA    11.32mA    11.49mA
1.2V      -32.98mA   -33.64mA   -34.2mA
1.8V      -46.76mA   -47.78mA   -48.47mA
2.182V    -53.86mA   -54.55mA   -55.81mA
2.4V      -55.54mA   -54.98mA   -58.3mA
2.673V    -53.94mA   -52.5mA    -57.31mA
3.164V    -45.71mA   -42.11mA   -48.1mA
3.6V      -33.84mA   -29.49mA   -37.62mA
[GND_clamp]
-1.8V     -346.1mA   -209.3mA   -568.3mA
-1.327V   -149.7mA   -89.03mA   -250.9mA
-1.291V   -135.6mA   -80.47mA   -227.5mA
-1.145V   -82.35mA   -48.67mA   -137.7mA
-1.073V   -59.44mA   -35.55mA   -97.96mA
-1.036V   -49.1mA    -29.72mA   -79.9mA
-927.3mV  -26.31mA   -17.11mA   -38.99mA
-854.5mV  -16.67mA   -11.64mA   -22.56mA
-818.2mV  -12.86mA   -9.351mA   -16.98mA
-672.7mV  -5.705mA   -3.913mA   -8.623mA
-381.8mV  -120.4uA   -129uA     -167.2uA
1.8V      2.273nA    51.44nA    6.654nA
[Ramp]
dV/dt_f 0.64948361/0.27009355n 0.62019697/0.36437834n 0.67021294/0.21742176n
dV/dt_r  0.6364372/0.28125901n 0.61103401/0.40955671n 0.67718262/0.22220442n
R_load = 50
[Rising Waveform]
R_fixture = 50
V_fixture = 1.8
V_fixture_min = 1.71
V_fixture_max = 1.89
0s        722mV      681.8mV    776.4mV
85.8ps    722mV      681.8mV    808.5mV
194.2ps   748mV      681.8mV    1.183V
330.5ps   1.107V     681.8mV    1.63V
404.4ps   1.298V     706.7mV    1.756V
530.9ps   1.574V     915.4mV    1.869V
915.3ps   1.79V      1.524V     1.89V
1.058ns   1.794V     1.615V     1.89V
1.642ns   1.798V     1.705V     1.89V
2.62ns    1.799V     1.707V     1.89V
[Rising Waveform]
R_fixture = 50
V_fixture = 0
V_fixture_min = 0
V_fixture_max = 0
0s        0V         0V         0V
85.7ps    0V         0V         0V
202.7ps   0V         0V         336.5mV
350.2ps   332.2mV    0V         830.1mV
432.5ps   530.1mV    0V         981.4mV
557.1ps   806.9mV    202.2mV    1.1V
777.9ps   989.4mV    535.5mV    1.122V
1.039ns   1.047V     882.9mV    1.124V
1.605ns   1.052V     1.001V     1.125V
2.631ns   1.055V     1.008V     1.125V
[Falling Waveform]
R_fixture = 50
V_fixture = 1.8
V_fixture_min = 1.71
V_fixture_max = 1.89
0s        1.799V     1.709V     1.889V
77.4ps    1.799V     1.709V     1.889V
197.9ps   1.789V     1.709V     1.557V
329.6ps   1.479V     1.709V     1.101V
409.9ps   1.267V     1.709V     938.8mV
534ps     984.1mV    1.526V     803.9mV
751.3ps   786.8mV    1.155V     779.8mV
1.049ns   728.6mV    794.3mV    776mV
1.576ns   724.2mV    688.1mV    775.4mV
2.62ns    721.8mV    684.9mV    775.4mV
[Falling Waveform]
R_fixture = 50
V_fixture = 0
V_fixture_min = 0
V_fixture_max = 0
0s        1.055V     1.011V     1.124V
71.3ps    1.055V     1.011V     1.124V
178.1ps   1.054V     1.011V     779.1mV
318.3ps   689.4mV    1.011V     292.5mV
398.9ps   483.1mV    994.9mV    142.2mV
515.5ps   233.9mV    791.1mV    23.31mV
738.2ps   53.83mV    410.9mV    2.789mV
954.5ps   7.119mV    129.9mV    0V
1.484ns   3.176mV    13.79mV    0V
2.631ns   0V         3.597mV    0V
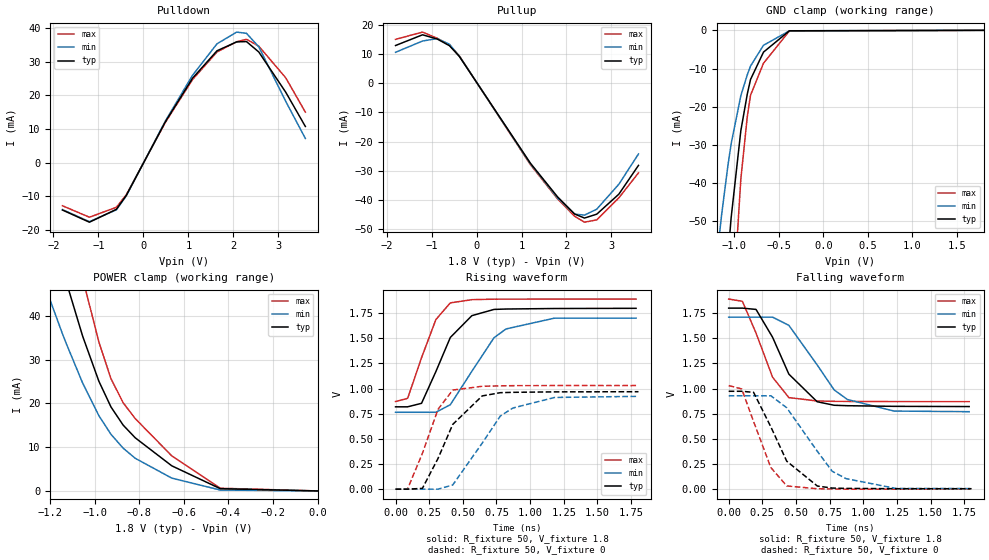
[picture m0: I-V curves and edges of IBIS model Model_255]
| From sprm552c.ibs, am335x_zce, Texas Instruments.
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| Model based on original model for BCSHTLTCSCDVPBFZ_SSDHV
|   Sub model SR10_9MA_5PER_1P8
[model]   Model_255
|[Description]  [1.8V-3-STATE-NOTERM-SR10:9MA, IND, 5%]
|   Fast slew rate (SR[1:0] = "10"), 0.88 * RExt = 1.125 * Iout
|   (I[2:0] = "100"), 9mA nominal with Rext = 50R,ODT off (ODT[1:0]
|   = "00") CMOS mode,Industrial temperature range (-40C to 125C,
|   25C nominal),5% power supply tolerance
|[Input Load]   NOTERM
|[Output Drive] SR10:9MA
|Voltage   1.8V
|Mode   3-STATE
Model_type   3-state
Polarity   Non-Inverting
Enable   Active-Low
Cref =  15pF
Rref =  100.0000M
Vref =  0V
Vmeas =  0.9
C_comp   1.851324p   1.667199p   1.973575p
[Temperature Range]   25   125   -40
[Voltage Range]   1.8   1.71   1.89
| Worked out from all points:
|   slope of the pulldown table from 0 to 0.27 V, typ, clamps not added: 39.3 ohm
|   slope of the pullup table from 0 to 0.27 V, typ, clamps not added: 41.3 ohm
|   GND clamp passes 1 mA (typ) near -0.49 V on its own axis
|   POWER clamp passes 1 mA (typ) near -0.47 V on its own axis
|   rising waveform, R_fixture 50, V_fixture 1.8: 20-80 % time 205ps typ, 274ps min, 161ps max; typ from 0.819 V to 1.8 V
|   rising waveform, R_fixture 50, V_fixture 0: 20-80 % time 221ps typ, 277ps min, 165ps max; typ from 0 V to 0.969 V
|   falling waveform, R_fixture 50, V_fixture 1.8: 20-80 % time 226ps typ, 290ps min, 175ps max; typ from 1.8 V to 0.821 V
|   falling waveform, R_fixture 50, V_fixture 0: 20-80 % time 219ps typ, 288ps min, 170ps max; typ from 0.973 V to 0.004 V
[POWER_clamp]
-1.8V     194.9mA    137mA      262.9mA
-1.236V   68.49mA    48.49mA    92.7mA
-1.145V   50.76mA    35.84mA    69.67mA
-1.127V   47.56mA    33.52mA    65.35mA
-1.055V   35.4mA     24.68mA    48.7mA
-981.8mV  25.06mA    17.19mA    34.02mA
-927.3mV  19.17mA    12.92mA    25.62mA
-872.7mV  15.03mA    9.76mA     20.13mA
-818.2mV  12.12mA    7.445mA    16.51mA
-654.5mV  5.738mA    2.929mA    8.007mA
-436.4mV  508.2uA    199.4uA    613uA
0V        2.273nA    16.6nA     10.58nA
[Pulldown]
-1.8V     -14.14mA   -14.01mA   -12.87mA
-1.2V     -17.77mA   -17.62mA   -16.29mA
-600mV    -13.93mA   -14.08mA   -13.32mA
-381.8mV  -9.817mA   -9.949mA   -9.615mA
490.9mV   12.22mA    12.46mA    12.03mA
1.091V    25.12mA    25.99mA    24.71mA
1.636V    33.32mA    35.4mA     32.97mA
2.073V    35.97mA    38.89mA    36mA
2.291V    36.06mA    38.52mA    36.74mA
2.564V    32.97mA    34.52mA    34.71mA
3.164V    20.97mA    18.24mA    25.26mA
3.6V      10.76mA    7.187mA    15.03mA
[Pullup]
-1.8V     12.99mA    10.66mA    15.1mA
-1.2V     16.67mA    14.53mA    17.6mA
-872.7mV  15.21mA    15.38mA    15.47mA
-600mV    12.91mA    13.4mA     13.08mA
-381.8mV  9.242mA    9.325mA    9.406mA
1.2V      -27.49mA   -27.72mA   -27.99mA
1.8V      -38.98mA   -39.36mA   -39.67mA
2.182V    -44.9mA    -44.93mA   -45.68mA
2.4V      -46.28mA   -45.27mA   -47.7mA
2.673V    -44.94mA   -43.23mA   -46.89mA
3.164V    -38.07mA   -34.66mA   -39.34mA
3.6V      -28.19mA   -24.27mA   -30.76mA
[GND_clamp]
-1.8V     -346.1mA   -209.3mA   -568.3mA
-1.327V   -149.7mA   -89.03mA   -250.9mA
-1.291V   -135.6mA   -80.47mA   -227.5mA
-1.145V   -82.35mA   -48.67mA   -137.7mA
-1.073V   -59.44mA   -35.55mA   -97.96mA
-1.036V   -49.1mA    -29.72mA   -79.9mA
-927.3mV  -26.31mA   -17.11mA   -38.99mA
-854.5mV  -16.67mA   -11.64mA   -22.56mA
-818.2mV  -12.86mA   -9.351mA   -16.98mA
-672.7mV  -5.705mA   -3.913mA   -8.623mA
-381.8mV  -120.4uA   -129uA     -167.2uA
1.8V      2.273nA    51.44nA    6.654nA
[Ramp]
dV/dt_f  0.5905478/0.22786447n 0.56878614/0.29348901n 0.61298459/0.17558351n
dV/dt_r 0.58548191/0.22331679n  0.5585707/0.27752503n  0.6192059/0.16530848n
R_load = 50
[Rising Waveform]
R_fixture = 50
V_fixture = 1.8
V_fixture_min = 1.71
V_fixture_max = 1.89
0s        818.8mV    764.4mV    870.8mV
90ps      818.8mV    764.4mV    903.2mV
193.1ps   853.5mV    764.4mV    1.307V
299.6ps   1.169V     764.4mV    1.686V
406.9ps   1.508V     839.6mV    1.852V
567ps     1.725V     1.172V     1.884V
731.6ps   1.787V     1.506V     1.889V
821.2ps   1.791V     1.593V     1.889V
1.18ns    1.796V     1.7V       1.89V
1.787ns   1.798V     1.7V       1.89V
[Rising Waveform]
R_fixture = 50
V_fixture = 0
V_fixture_min = 0
V_fixture_max = 0
0s        0V         0V         0V
88.7ps    0V         0V         0V
199.3ps   7.906mV    0V         355.8mV
315.7ps   305.7mV    0V         794.1mV
425ps     644mV      41.91mV    985.3mV
643.7ps   927mV      457.5mV    1.023V
778.8ps   959.3mV    727.3mV    1.027V
871.4ps   962.7mV    806.6mV    1.029V
1.182ns   967.3mV    911.8mV    1.03V
1.805ns   968.9mV    922.7mV    1.03V
[Falling Waveform]
R_fixture = 50
V_fixture = 1.8
V_fixture_min = 1.71
V_fixture_max = 1.89
0s        1.799V     1.709V     1.889V
101.9ps   1.799V     1.709V     1.867V
203.3ps   1.786V     1.709V     1.551V
326.4ps   1.509V     1.709V     1.112V
447.2ps   1.143V     1.628V     910mV
657.3ps   868.8mV    1.235V     876.3mV
783.5ps   833.8mV    986.7mV    872.7mV
882.2ps   829.3mV    890.8mV    871.9mV
1.229ns   823mV      776.2mV    870.1mV
1.787ns   820.8mV    769.8mV    869.9mV
[Falling Waveform]
R_fixture = 50
V_fixture = 0
V_fixture_min = 0
V_fixture_max = 0
0s        972.6mV    927.7mV    1.029V
97ps      972.6mV    927.7mV    996mV
185.2ps   962.2mV    927.7mV    671mV
313.4ps   618.9mV    927.7mV    214.8mV
431.5ps   277.8mV    808.8mV    32.09mV
658.8ps   30.95mV    375.8mV    4.007mV
769.6ps   10.88mV    177.6mV    2.094mV
871.8ps   7.775mV    105mV      0V
1.242ns   4.476mV    7.398mV    0V
1.805ns   4.476mV    5.889mV    0V
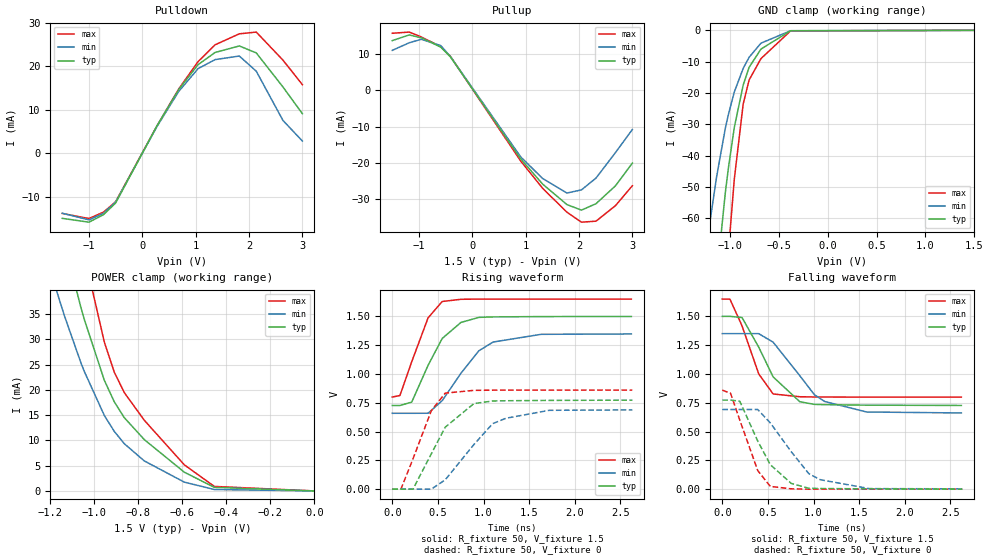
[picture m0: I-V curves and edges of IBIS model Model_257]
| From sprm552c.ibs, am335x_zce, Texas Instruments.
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| Model based on original model for BCSHTLTCSCDVPBFZ_SSDHV
|   Sub model SR11_8MA_10PER_1P5
[model]   Model_257
|[Description]  [1.5V-3-STATE-NOTERM-SR11:8MA, IND, 10%]
|   Slowest slew rate (SR[1:0] = "11"), 1.00 * RExt = 1.000 * Iout
|   (I[2:0] = "011"), 8mA nominal with Rext = 50R,ODT off (ODT[1:0]
|   = "00") CMOS mode,Industrial temperature range (-40C to 125C,
|   25C nominal),10% power supply tolerance
|[Input Load]   NOTERM
|[Output Drive] SR11:8MA
|Voltage   1.5V
|Mode   3-STATE
Model_type   3-state
Polarity   Non-Inverting
Enable   Active-Low
Cref =  15pF
Rref =  100.0000M
Vref =  0V
Vmeas =  0.75
C_comp   1.865048p   1.676829p   1.989968p
[Temperature Range]   25   125   -40
[Voltage Range]   1.5   1.35   1.65
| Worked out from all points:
|   slope of the pulldown table from 0 to 0.225 V, typ, clamps not added: 43 ohm
|   slope of the pullup table from 0 to 0.225 V, typ, clamps not added: 45 ohm
|   GND clamp passes 1 mA (typ) near -0.49 V on its own axis
|   POWER clamp passes 1 mA (typ) near -0.47 V on its own axis
|   rising waveform, R_fixture 50, V_fixture 1.5: 20-80 % time 291ps typ, 390ps min, 228ps max; typ from 0.726 V to 1.5 V
|   rising waveform, R_fixture 50, V_fixture 0: 20-80 % time 330ps typ, 412ps min, 246ps max; typ from 0 V to 0.773 V
|   falling waveform, R_fixture 50, V_fixture 1.5: 20-80 % time 320ps typ, 408ps min, 228ps max; typ from 1.5 V to 0.726 V
|   falling waveform, R_fixture 50, V_fixture 0: 20-80 % time 300ps typ, 389ps min, 228ps max; typ from 0.773 V to 0 V
[POWER_clamp]
-1.5V     126mA      88.79mA    168.7mA
-1.242V   69.8mA     49.45mA    94.34mA
-1.136V   49.16mA    34.72mA    67.51mA
-1.061V   36.35mA    25.4mA     50.03mA
-1.045V   33.92mA    23.63mA    46.66mA
-954.5mV  21.93mA    14.95mA    29.5mA
-909.1mV  17.64mA    11.79mA    23.52mA
-863.6mV  14.51mA    9.351mA    19.47mA
-772.7mV  10.16mA    5.94mA     13.99mA
-590.9mV  3.705mA    1.741mA    5.166mA
-454.5mV  710.5uA    279.1uA    892.1uA
0V        1.424nA    14.34nA    3.127nA
[Pulldown]
-1.5V     -14.94mA   -13.76mA   -13.81mA
-1V       -15.82mA   -15.28mA   -14.98mA
-727.3mV  -14.09mA   -13.78mA   -13.5mA
-500mV    -11.41mA   -11.18mA   -11.11mA
272.7mV   6.297mA    6.143mA    6.286mA
681.8mV   14.68mA    14.25mA    14.82mA
1.045V    20.42mA    19.5mA     21.11mA
1.364V    23.22mA    21.58mA    24.99mA
1.818V    24.72mA    22.4mA     27.51mA
2.136V    23.12mA    18.91mA    27.91mA
2.636V    15.29mA    7.59mA     21.46mA
3V        9.139mA    2.855mA    15.82mA
[Pullup]
-1.5V     13.59mA    10.91mA    15.61mA
-1.182V   15.15mA    13mA       15.93mA
-954.5mV  14.35mA    13.95mA    14.59mA
-590.9mV  11.8mA     12.22mA    11.93mA
-409.1mV  9.103mA    9.176mA    9.241mA
909.1mV   -18.93mA   -18.37mA   -19.52mA
1.318V    -25.81mA   -24.27mA   -26.97mA
1.773V    -31.43mA   -28.26mA   -33.52mA
2.045V    -32.96mA   -27.41mA   -36.27mA
2.318V    -31.2mA    -24.16mA   -35.99mA
2.682V    -26.3mA    -17.18mA   -31.75mA
3V        -20.05mA   -10.81mA   -26.25mA
[GND_clamp]
-1.5V     -219.3mA   -131.6mA   -364.3mA
-1.288V   -134.4mA   -79.74mA   -225.6mA
-1.258V   -122.9mA   -72.77mA   -206.3mA
-1.136V   -79.27mA   -46.88mA   -132.4mA
-1.045V   -51.5mA    -31.06mA   -84.11mA
-1.015V   -44.02mA   -26.9mA    -70.91mA
-954.5mV  -31.01mA   -19.7mA    -47.55mA
-863.6mV  -17.48mA   -12.16mA   -23.55mA
-803mV    -11.81mA   -8.597mA   -15.85mA
-681.8mV  -5.986mA   -4.096mA   -9.026mA
-378.8mV  -126.2uA   -131.8uA   -179.7uA
1.5V      1.424nA    207.1nA    1.498nA
[Ramp]
dV/dt_f 0.46642421/0.32239162n 0.41682387/0.41187152n  0.5118498/0.22909364n
dV/dt_r 0.46615487/0.33013842n  0.4172947/0.40687147n 0.51722816/0.24678649n
R_load = 50
[Rising Waveform]
R_fixture = 50
V_fixture = 1.5
V_fixture_min = 1.35
V_fixture_max = 1.65
0s        726.3mV    658.6mV    799.6mV
83.8ps    726.3mV    658.6mV    812.8mV
213ps     755.5mV    658.6mV    1.106V
392.4ps   1.075V     659mV      1.487V
547.1ps   1.308V     768.3mV    1.629V
752.4ps   1.447V     1.006V     1.648V
948.5ps   1.491V     1.201V     1.65V
1.105ns   1.495V     1.277V     1.65V
1.631ns   1.498V     1.344V     1.65V
2.62ns    1.499V     1.347V     1.65V
[Rising Waveform]
R_fixture = 50
V_fixture = 0
V_fixture_min = 0
V_fixture_max = 0
0s        0V         0V         0V
94.1ps    0V         0V         0V
226.4ps   0V         0V         262.3mV
427.1ps   305.6mV    0V         680.2mV
580.1ps   538mV      80.66mV    833.6mV
893.8ps   742.5mV    386.9mV    857.5mV
1.1ns     765.4mV    568.8mV    859.3mV
1.245ns   767.4mV    615.3mV    859.7mV
1.72ns    770.4mV    684.4mV    859.9mV
2.631ns   772.6mV    688mV      859.9mV
[Falling Waveform]
R_fixture = 50
V_fixture = 1.5
V_fixture_min = 1.35
V_fixture_max = 1.65
0s        1.499V     1.349V     1.649V
83.2ps    1.499V     1.349V     1.649V
216.2ps   1.489V     1.349V     1.417V
399.2ps   1.232V     1.349V     1V
557.3ps   973.8mV    1.275V     825.8mV
849.6ps   758.5mV    984.1mV    801.7mV
1.01ns    735.3mV    818.8mV    799.6mV
1.122ns   732.9mV    760.6mV    799.1mV
1.582ns   728.7mV    669.4mV    798.8mV
2.62ns    726.1mV    661mV      798.6mV
[Falling Waveform]
R_fixture = 50
V_fixture = 0
V_fixture_min = 0
V_fixture_max = 0
0s        772.7mV    691.2mV    858.9mV
90.7ps    772.7mV    691.2mV    832mV
191.5ps   763.1mV    691.2mV    599.4mV
388.3ps   417.8mV    691.2mV    161.4mV
526.2ps   212.4mV    574.9mV    23.8mV
756.4ps   49.54mV    324.2mV    2.896mV
948.7ps   7.833mV    133.9mV    0V
1.074ns   5.537mV    82.01mV    0V
1.612ns   2.728mV    4.853mV    0V
2.631ns   0V         3.074mV    0V
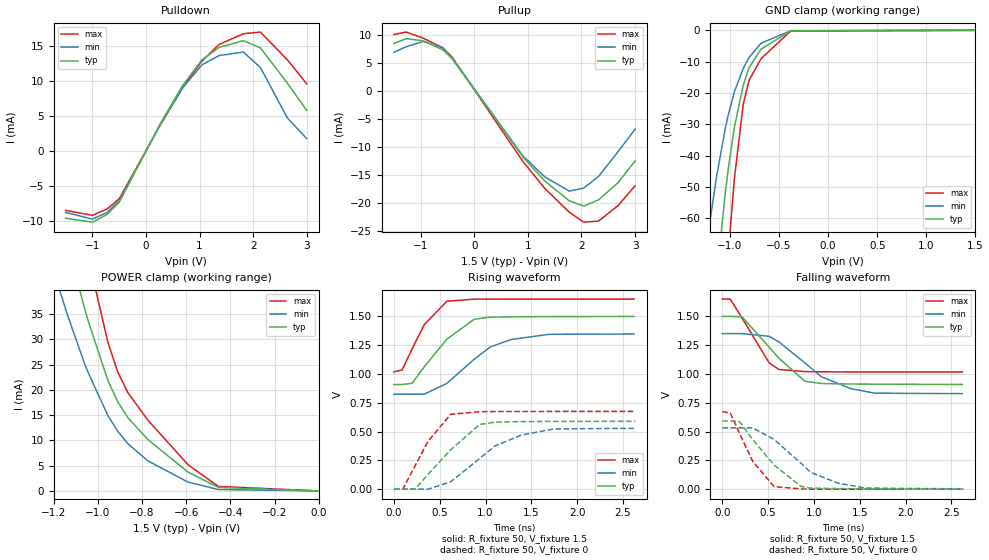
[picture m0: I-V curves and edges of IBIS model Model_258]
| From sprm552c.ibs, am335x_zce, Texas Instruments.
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| Model based on original model for BCSHTLTCSCDVPBFZ_SSDHV
|   Sub model SR11_5MA_10PER_1P5
[model]   Model_258
|[Description]  [1.5V-3-STATE-NOTERM-SR11:5MA, IND, 10%]
|   Slowest slew rate (SR[1:0] = "11"), 1.60 * RExt = 0.625 * Iout
|   (I[2:0] = "000"), 5mA nominal with Rext = 50R,ODT off (ODT[1:0]
|   = "00") CMOS mode,Industrial temperature range (-40C to 125C,
|   25C nominal),10% power supply tolerance
|[Input Load]   NOTERM
|[Output Drive] SR11:5MA
|Voltage   1.5V
|Mode   3-STATE
Model_type   3-state
Polarity   Non-Inverting
Enable   Active-Low
Cref =  15pF
Rref =  100.0000M
Vref =  0V
Vmeas =  0.75
C_comp   1.865048p   1.676829p   1.989968p
[Temperature Range]   25   125   -40
[Voltage Range]   1.5   1.35   1.65
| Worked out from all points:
|   slope of the pulldown table from 0 to 0.225 V, typ, clamps not added: 67.2 ohm
|   slope of the pullup table from 0 to 0.225 V, typ, clamps not added: 72 ohm
|   GND clamp passes 1 mA (typ) near -0.49 V on its own axis
|   POWER clamp passes 1 mA (typ) near -0.47 V on its own axis
|   rising waveform, R_fixture 50, V_fixture 1.5: 20-80 % time 376ps typ, 481ps min, 267ps max; typ from 0.908 V to 1.5 V
|   rising waveform, R_fixture 50, V_fixture 0: 20-80 % time 409ps typ, 534ps min, 291ps max; typ from 0 V to 0.589 V
|   falling waveform, R_fixture 50, V_fixture 1.5: 20-80 % time 390ps typ, 529ps min, 278ps max; typ from 1.5 V to 0.908 V
|   falling waveform, R_fixture 50, V_fixture 0: 20-80 % time 377ps typ, 486ps min, 269ps max; typ from 0.591 V to 0 V
[POWER_clamp]
-1.5V     126mA      88.79mA    168.7mA
-1.242V   69.8mA     49.45mA    94.34mA
-1.136V   49.16mA    34.72mA    67.51mA
-1.061V   36.35mA    25.4mA     50.03mA
-1.045V   33.92mA    23.63mA    46.66mA
-954.5mV  21.93mA    14.95mA    29.5mA
-909.1mV  17.64mA    11.79mA    23.52mA
-863.6mV  14.51mA    9.351mA    19.47mA
-772.7mV  10.16mA    5.94mA     13.99mA
-590.9mV  3.705mA    1.741mA    5.166mA
-454.5mV  710.5uA    279.1uA    892.1uA
0V        1.424nA    14.34nA    3.127nA
[Pulldown]
-1.5V     -9.559mA   -8.721mA   -8.435mA
-1V       -10.13mA   -9.69mA    -9.153mA
-727.3mV  -9.021mA   -8.741mA   -8.25mA
-500mV    -7.306mA   -7.092mA   -6.791mA
272.7mV   4.034mA    3.899mA    3.845mA
681.8mV   9.399mA    9.044mA    9.061mA
1.045V    13.08mA    12.37mA    12.91mA
1.364V    14.86mA    13.69mA    15.28mA
1.818V    15.82mA    14.2mA     16.81mA
2.136V    14.79mA    11.98mA    17.05mA
2.636V    9.781mA    4.81mA     13.11mA
3V        5.846mA    1.81mA     9.659mA
[Pullup]
-1.5V     8.494mA    6.914mA    10.1mA
-1.273V   9.331mA    7.894mA    10.52mA
-954.5mV  8.972mA    8.846mA    9.444mA
-590.9mV  7.379mA    7.751mA    7.725mA
-409.1mV  5.694mA    5.824mA    5.984mA
909.1mV   -11.84mA   -11.65mA   -12.64mA
1.318V    -16.14mA   -15.4mA    -17.46mA
1.773V    -19.65mA   -17.92mA   -21.7mA
2.045V    -20.6mA    -17.37mA   -23.48mA
2.318V    -19.49mA   -15.31mA   -23.28mA
2.682V    -16.43mA   -10.88mA   -20.53mA
3V        -12.52mA   -6.85mA    -16.98mA
[GND_clamp]
-1.5V     -219.3mA   -131.6mA   -364.3mA
-1.288V   -134.4mA   -79.74mA   -225.6mA
-1.258V   -122.9mA   -72.77mA   -206.3mA
-1.136V   -79.27mA   -46.88mA   -132.4mA
-1.045V   -51.5mA    -31.06mA   -84.11mA
-1.015V   -44.02mA   -26.9mA    -70.91mA
-954.5mV  -31.01mA   -19.7mA    -47.55mA
-863.6mV  -17.48mA   -12.16mA   -23.55mA
-803mV    -11.81mA   -8.597mA   -15.85mA
-681.8mV  -5.986mA   -4.096mA   -9.026mA
-378.8mV  -126.2uA   -131.8uA   -179.7uA
1.5V      1.424nA    207.1nA    1.498nA
[Ramp]
dV/dt_f 0.35665226/0.39279758n  0.3165705/0.53822428n 0.38037005/0.27920528n
dV/dt_r 0.35640593/0.41037818n 0.32019437/0.53916036n 0.40558555/0.29169217n
R_load = 50
[Rising Waveform]
R_fixture = 50
V_fixture = 1.5
V_fixture_min = 1.35
V_fixture_max = 1.65
0s        908.2mV    824mV      1.018V
88.5ps    908.2mV    824mV      1.034V
198ps     919mV      824mV      1.217V
329.3ps   1.06V      824mV      1.426V
576.8ps   1.301V     917.7mV    1.631V
876.4ps   1.475V     1.128V     1.649V
1.051ns   1.493V     1.234V     1.65V
1.279ns   1.496V     1.299V     1.65V
1.694ns   1.498V     1.344V     1.65V
2.62ns    1.499V     1.347V     1.65V
[Rising Waveform]
R_fixture = 50
V_fixture = 0
V_fixture_min = 0
V_fixture_max = 0
0s        0V         0V         0V
96.8ps    0V         0V         0V
231.2ps   0V         0V         203.5mV
372.7ps   129.9mV    0V         415.5mV
620.1ps   341.7mV    64.53mV    650.4mV
935.1ps   561.7mV    265.9mV    672.4mV
1.104ns   582.2mV    375.9mV    673.8mV
1.392ns   586.5mV    469.8mV    674.4mV
1.749ns   588.5mV    523.2mV    674.5mV
2.631ns   588.9mV    528.2mV    674.5mV
[Falling Waveform]
R_fixture = 50
V_fixture = 1.5
V_fixture_min = 1.35
V_fixture_max = 1.65
0s        1.499V     1.349V     1.649V
86.9ps    1.499V     1.349V     1.649V
215.8ps   1.495V     1.349V     1.485V
512.3ps   1.232V     1.326V     1.095V
618ps     1.136V     1.277V     1.038V
900.7ps   936.5mV    1.096V     1.02V
1.083ns   916.7mV    974.5mV    1.018V
1.405ns   911.9mV    871.4mV    1.017V
1.665ns   910.4mV    832.7mV    1.017V
2.62ns    908.1mV    828.4mV    1.017V
[Falling Waveform]
R_fixture = 50
V_fixture = 0
V_fixture_min = 0
V_fixture_max = 0
0s        591.1mV    531.7mV    673.5mV
87.4ps    591.1mV    531.7mV    660mV
189.3ps   585.7mV    531.7mV    483mV
332ps     431.2mV    531.7mV    241.9mV
566.4ps   208.3mV    431.1mV    21.6mV
859.8ps   23.23mV    224.5mV    2.216mV
964.6ps   9.723mV    145.6mV    0V
1.269ns   4.676mV    50.92mV    0V
1.571ns   3.22mV     9.005mV    0V
2.631ns   0V         3.002mV    0V
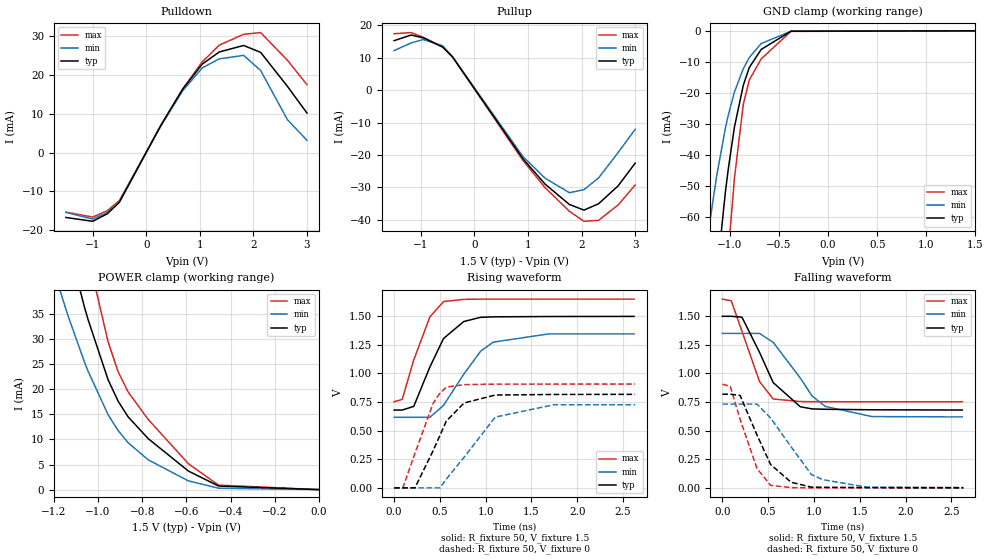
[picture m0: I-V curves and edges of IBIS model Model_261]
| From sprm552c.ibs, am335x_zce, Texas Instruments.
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| Model based on original model for BCSHTLTCSCDVPBFZ_SSDHV
|   Sub model SR11_9MA_10PER_1P5
[model]   Model_261
|[Description]  [1.5V-3-STATE-NOTERM-SR11:9MA, IND, 10%]
|   Slowest slew rate (SR[1:0] = "11"), 0.88 * RExt = 1.125 * Iout
|   (I[2:0] = "100"), 9mA nominal with Rext = 50R,ODT off (ODT[1:0]
|   = "00") CMOS mode,Industrial temperature range (-40C to 125C,
|   25C nominal),10% power supply tolerance
|[Input Load]   NOTERM
|[Output Drive] SR11:9MA
|Voltage   1.5V
|Mode   3-STATE
Model_type   3-state
Polarity   Non-Inverting
Enable   Active-Low
Cref =  15pF
Rref =  100.0000M
Vref =  0V
Vmeas =  0.75
C_comp   1.865048p   1.676829p   1.989968p
[Temperature Range]   25   125   -40
[Voltage Range]   1.5   1.35   1.65
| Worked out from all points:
|   slope of the pulldown table from 0 to 0.225 V, typ, clamps not added: 38.4 ohm
|   slope of the pullup table from 0 to 0.225 V, typ, clamps not added: 40.1 ohm
|   GND clamp passes 1 mA (typ) near -0.49 V on its own axis
|   POWER clamp passes 1 mA (typ) near -0.47 V on its own axis
|   rising waveform, R_fixture 50, V_fixture 1.5: 20-80 % time 278ps typ, 379ps min, 226ps max; typ from 0.68 V to 1.5 V
|   rising waveform, R_fixture 50, V_fixture 0: 20-80 % time 308ps typ, 389ps min, 242ps max; typ from 0 V to 0.818 V
|   falling waveform, R_fixture 50, V_fixture 1.5: 20-80 % time 306ps typ, 386ps min, 231ps max; typ from 1.5 V to 0.68 V
|   falling waveform, R_fixture 50, V_fixture 0: 20-80 % time 282ps typ, 381ps min, 225ps max; typ from 0.818 V to 0 V
[POWER_clamp]
-1.5V     126mA      88.79mA    168.7mA
-1.242V   69.8mA     49.45mA    94.34mA
-1.136V   49.16mA    34.72mA    67.51mA
-1.061V   36.35mA    25.4mA     50.03mA
-1.045V   33.92mA    23.63mA    46.66mA
-954.5mV  21.93mA    14.95mA    29.5mA
-909.1mV  17.64mA    11.79mA    23.52mA
-863.6mV  14.51mA    9.351mA    19.47mA
-772.7mV  10.16mA    5.94mA     13.99mA
-590.9mV  3.705mA    1.741mA    5.166mA
-454.5mV  710.5uA    279.1uA    892.1uA
0V        1.424nA    14.34nA    3.127nA
[Pulldown]
-1.5V     -16.73mA   -15.43mA   -15.34mA
-1V       -17.72mA   -17.14mA   -16.64mA
-727.3mV  -15.78mA   -15.46mA   -14.99mA
-500mV    -12.78mA   -12.54mA   -12.34mA
272.7mV   7.051mA    6.89mA     6.983mA
681.8mV   16.43mA    15.99mA    16.46mA
1.045V    22.87mA    21.88mA    23.45mA
1.364V    26mA       24.22mA    27.76mA
1.818V    27.68mA    25.13mA    30.56mA
2.136V    25.9mA     21.22mA    31.01mA
2.636V    17.13mA    8.517mA    23.85mA
3V        10.24mA    3.203mA    17.58mA
[Pullup]
-1.5V     15.3mA     12.24mA    17.45mA
-1.182V   17.04mA    14.59mA    17.8mA
-954.5mV  16.15mA    15.65mA    16.31mA
-590.9mV  13.28mA    13.71mA    13.34mA
-409.1mV  10.24mA    10.29mA    10.33mA
909.1mV   -21.29mA   -20.6mA    -21.82mA
1.318V    -29.04mA   -27.22mA   -30.13mA
1.773V    -35.35mA   -31.7mA    -37.46mA
2.045V    -37.08mA   -30.75mA   -40.54mA
2.318V    -35.11mA   -27.11mA   -40.23mA
2.682V    -29.59mA   -19.28mA   -35.49mA
3V        -22.57mA   -12.13mA   -29.35mA
[GND_clamp]
-1.5V     -219.3mA   -131.6mA   -364.3mA
-1.288V   -134.4mA   -79.74mA   -225.6mA
-1.258V   -122.9mA   -72.77mA   -206.3mA
-1.136V   -79.27mA   -46.88mA   -132.4mA
-1.045V   -51.5mA    -31.06mA   -84.11mA
-1.015V   -44.02mA   -26.9mA    -70.91mA
-954.5mV  -31.01mA   -19.7mA    -47.55mA
-863.6mV  -17.48mA   -12.16mA   -23.55mA
-803mV    -11.81mA   -8.597mA   -15.85mA
-681.8mV  -5.986mA   -4.096mA   -9.026mA
-378.8mV  -126.2uA   -131.8uA   -179.7uA
1.5V      1.424nA    207.1nA    1.498nA
[Ramp]
dV/dt_f 0.49433559/0.30744054n 0.44211495/0.38815234n 0.54031907/0.23092509n
dV/dt_r 0.49395046/0.30968147n 0.44192825/0.39087456n 0.54605791/0.24203492n
R_load = 50
[Rising Waveform]
R_fixture = 50
V_fixture = 1.5
V_fixture_min = 1.35
V_fixture_max = 1.65
0s        680.3mV    616.8mV    752.7mV
88.6ps    680.3mV    616.8mV    773.6mV
214.6ps   712.5mV    616.8mV    1.119V
390.5ps   1.057V     616.8mV    1.495V
540ps     1.306V     721.4mV    1.629V
760.1ps   1.454V     993.5mV    1.648V
943.9ps   1.491V     1.194V     1.65V
1.083ns   1.495V     1.274V     1.65V
1.688ns   1.498V     1.346V     1.65V
2.62ns    1.499V     1.346V     1.65V
[Rising Waveform]
R_fixture = 50
V_fixture = 0
V_fixture_min = 0
V_fixture_max = 0
0s        0V         0V         0V
95.3ps    0V         0V         0V
227.3ps   0V         0V         300.9mV
425.6ps   324.5mV    0V         738.5mV
501.9ps   460.5mV    0V         829.3mV
570.4ps   584.5mV    76.73mV    880.5mV
764.6ps   742.3mV    267.9mV    902.5mV
1.105ns   811.6mV    619mV      906.8mV
1.743ns   816.5mV    726.4mV    907mV
2.632ns   817.6mV    726.4mV    907.3mV
[Falling Waveform]
R_fixture = 50
V_fixture = 1.5
V_fixture_min = 1.35
V_fixture_max = 1.65
0s        1.499V     1.349V     1.649V
97.4ps    1.499V     1.349V     1.634V
214.3ps   1.491V     1.349V     1.368V
405.9ps   1.184V     1.349V     928.6mV
555.4ps   919.4mV    1.271V     776.6mV
851.4ps   708.7mV    959.7mV    754.2mV
979.3ps   689.8mV    803mV      753mV
1.124ns   686.7mV    711.4mV    752.8mV
1.634ns   682.1mV    622.8mV    751.9mV
2.62ns    680.1mV    619.7mV    751.8mV
[Falling Waveform]
R_fixture = 50
V_fixture = 0
V_fixture_min = 0
V_fixture_max = 0
0s        818.4mV    731.6mV    906.3mV
87.2ps    818.4mV    731.6mV    885.7mV
193.5ps   807.8mV    731.6mV    600.1mV
378.8ps   461.1mV    731.6mV    169.2mV
527.1ps   203.8mV    610.1mV    21.35mV
751.4ps   48.67mV    358mV      2.717mV
971.1ps   6.786mV    117.7mV    0V
1.096ns   5.087mV    71.88mV    0V
1.578ns   2.715mV    5.552mV    0V
2.632ns   0V         2.971mV    0V
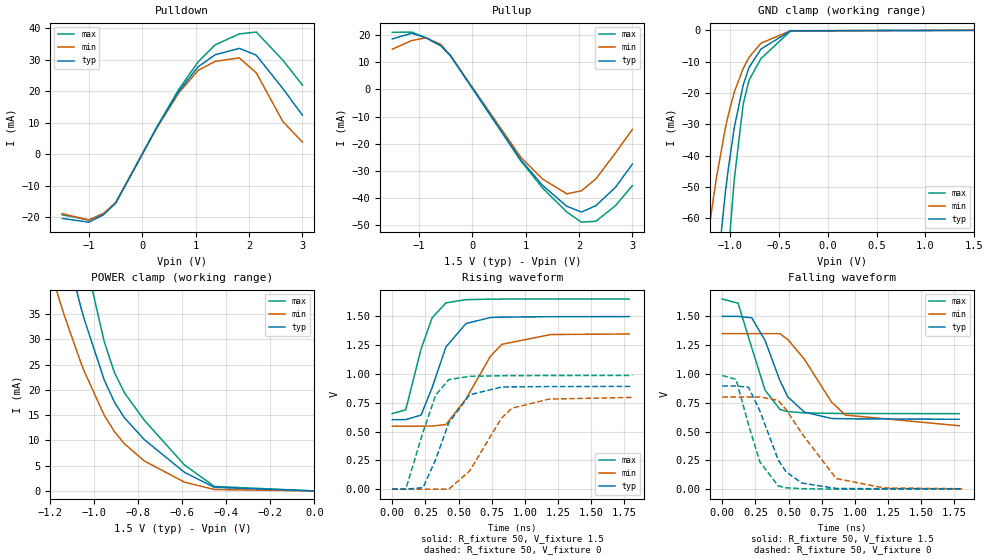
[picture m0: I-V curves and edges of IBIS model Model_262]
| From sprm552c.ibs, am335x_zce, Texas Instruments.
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| Model based on original model for BCSHTLTCSCDVPBFZ_SSDHV
|   Sub model SR10_11MA_10PER_1P5
[model]   Model_262
|[Description]  [1.5V-3-STATE-NOTERM-SR10:11MA, IND, 10%]
|   Fast slew rate (SR[1:0] = "10"), 0.73 * RExt = 1.325 * Iout
|   (I[2:0] = "110"), 11mA nominal with Rext = 50R,ODT off (ODT[1:0]
|   = "00") CMOS mode,Industrial temperature range (-40C to 125C,
|   25C nominal),10% power supply tolerance
|[Input Load]   NOTERM
|[Output Drive] SR10:11MA
|Voltage   1.5V
|Mode   3-STATE
Model_type   3-state
Polarity   Non-Inverting
Enable   Active-Low
Cref =  15pF
Rref =  100.0000M
Vref =  0V
Vmeas =  0.75
C_comp   1.865048p   1.676829p   1.989968p
[Temperature Range]   25   125   -40
[Voltage Range]   1.5   1.35   1.65
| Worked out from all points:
|   slope of the pulldown table from 0 to 0.225 V, typ, clamps not added: 31.7 ohm
|   slope of the pullup table from 0 to 0.225 V, typ, clamps not added: 32.8 ohm
|   GND clamp passes 1 mA (typ) near -0.49 V on its own axis
|   POWER clamp passes 1 mA (typ) near -0.47 V on its own axis
|   rising waveform, R_fixture 50, V_fixture 1.5: 20-80 % time 170ps typ, 245ps min, 141ps max; typ from 0.603 V to 1.5 V
|   rising waveform, R_fixture 50, V_fixture 0: 20-80 % time 185ps typ, 252ps min, 153ps max; typ from 0 V to 0.892 V
|   falling waveform, R_fixture 50, V_fixture 1.5: 20-80 % time 196ps typ, 274ps min, 154ps max; typ from 1.5 V to 0.606 V
|   falling waveform, R_fixture 50, V_fixture 0: 20-80 % time 188ps typ, 276ps min, 153ps max; typ from 0.895 V to 0.003 V
[POWER_clamp]
-1.5V     126mA      88.79mA    168.7mA
-1.242V   69.8mA     49.45mA    94.34mA
-1.136V   49.16mA    34.72mA    67.51mA
-1.061V   36.35mA    25.4mA     50.03mA
-1.045V   33.92mA    23.63mA    46.66mA
-954.5mV  21.93mA    14.95mA    29.5mA
-909.1mV  17.64mA    11.79mA    23.52mA
-863.6mV  14.51mA    9.351mA    19.47mA
-772.7mV  10.16mA    5.94mA     13.99mA
-590.9mV  3.705mA    1.741mA    5.166mA
-454.5mV  710.5uA    279.1uA    892.1uA
0V        1.424nA    14.34nA    3.127nA
[Pulldown]
-1.5V     -20.32mA   -18.79mA   -19.18mA
-1V       -21.51mA   -20.87mA   -20.79mA
-727.3mV  -19.16mA   -18.81mA   -18.74mA
-500mV    -15.51mA   -15.26mA   -15.42mA
272.7mV   8.558mA    8.384mA    8.723mA
681.8mV   19.95mA    19.45mA    20.56mA
1.045V    27.76mA    26.62mA    29.3mA
1.364V    31.57mA    29.48mA    34.69mA
1.818V    33.61mA    30.59mA    38.2mA
2.136V    31.45mA    25.84mA    38.77mA
2.636V    20.81mA    10.37mA    29.82mA
3V        12.44mA    3.9mA      21.98mA
[Pullup]
-1.5V     18.7mA     14.9mA     21.12mA
-1.136V   20.8mA     18.1mA     21.22mA
-863.6mV  19.07mA    19.09mA    19.07mA
-590.9mV  16.22mA    16.68mA    16.14mA
-409.1mV  12.51mA    12.52mA    12.49mA
909.1mV   -26.01mA   -25.07mA   -26.4mA
1.318V    -35.47mA   -33.13mA   -36.46mA
1.773V    -43.2mA    -38.59mA   -45.33mA
2.045V    -45.32mA   -37.44mA   -49.06mA
2.318V    -42.92mA   -33.02mA   -48.71mA
2.682V    -36.18mA   -23.48mA   -42.98mA
3V        -27.6mA    -14.77mA   -35.54mA
[GND_clamp]
-1.5V     -219.3mA   -131.6mA   -364.3mA
-1.288V   -134.4mA   -79.74mA   -225.6mA
-1.258V   -122.9mA   -72.77mA   -206.3mA
-1.136V   -79.27mA   -46.88mA   -132.4mA
-1.045V   -51.5mA    -31.06mA   -84.11mA
-1.015V   -44.02mA   -26.9mA    -70.91mA
-954.5mV  -31.01mA   -19.7mA    -47.55mA
-863.6mV  -17.48mA   -12.16mA   -23.55mA
-803mV    -11.81mA   -8.597mA   -15.85mA
-681.8mV  -5.986mA   -4.096mA   -9.026mA
-378.8mV  -126.2uA   -131.8uA   -179.7uA
1.5V      1.424nA    207.1nA    1.498nA
[Ramp]
dV/dt_f 0.54019538/0.19832414n 0.48389907/0.27544445n 0.59827145/0.15432078n
dV/dt_r 0.53992293/0.1871055n 0.48332895/0.25366792n 0.59423359/0.15324926n
R_load = 50
[Rising Waveform]
R_fixture = 50
V_fixture = 1.5
V_fixture_min = 1.35
V_fixture_max = 1.65
0s        603.4mV    547.1mV    656.1mV
101ps     603.4mV    547.1mV    687.6mV
217.4ps   643.1mV    547.1mV    1.217V
300.3ps   880.2mV    547.7mV    1.487V
404.4ps   1.234V     560.6mV    1.617V
556ps     1.438V     783.6mV    1.645V
742ps     1.49V      1.157V     1.649V
828.3ps   1.493V     1.258V     1.65V
1.196ns   1.497V     1.342V     1.65V
1.787ns   1.498V     1.347V     1.65V
[Rising Waveform]
R_fixture = 50
V_fixture = 0
V_fixture_min = 0
V_fixture_max = 0
0s        0V         0V         0V
101.6ps   0V         0V         0V
232.2ps   13.76mV    0V         496.6mV
327.4ps   257mV      0V         816.4mV
425.7ps   574.9mV    0V         951.3mV
583.2ps   819.2mV    157.1mV    979.1mV
823.2ps   885.9mV    616.2mV    984.7mV
902.4ps   887.5mV    702.3mV    985mV
1.182ns   890.6mV    782.1mV    986.7mV
1.811ns   891.7mV    796.3mV    987.1mV
[Falling Waveform]
R_fixture = 50
V_fixture = 1.5
V_fixture_min = 1.35
V_fixture_max = 1.65
0s        1.499V     1.349V     1.649V
119.1ps   1.499V     1.349V     1.613V
222ps     1.487V     1.349V     1.228V
322.2ps   1.291V     1.349V     860.2mV
435.1ps   940.6mV    1.349V     690.7mV
495ps     799.6mV    1.297V     672.8mV
619.4ps   668.3mV    1.127V     661.4mV
823.6ps   613.3mV    756.1mV    657.3mV
928.7ps   610.5mV    643mV      656.3mV
1.787ns   606.1mV    550.1mV    655.1mV
[Falling Waveform]
R_fixture = 50
V_fixture = 0
V_fixture_min = 0
V_fixture_max = 0
0s        894.9mV    799.5mV    986.3mV
104.3ps   894.9mV    799.5mV    951.7mV
198ps     884.2mV    799.5mV    558.7mV
283.3ps   679.7mV    799.5mV    238mV
421.6ps   254.8mV    770.4mV    27.84mV
481.2ps   150.6mV    691.3mV    11.96mV
599.7ps   53.23mV    483.9mV    4.257mV
858.5ps   6.416mV    92.9mV     0V
1.22ns    3.589mV    10.26mV    0V
1.811ns   3.113mV    4.057mV    0V
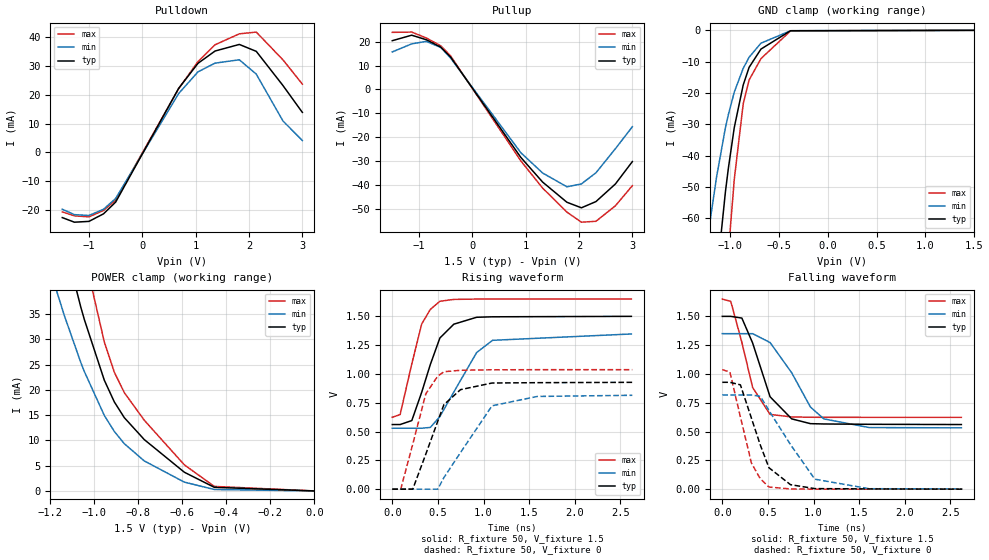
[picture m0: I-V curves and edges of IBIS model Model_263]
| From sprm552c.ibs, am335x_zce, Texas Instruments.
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| Model based on original model for BCSHTLTCSCDVPBFZ_SSDHV
|   Sub model SR11_12MA_10PER_1P5
[model]   Model_263
|[Description]  [1.5V-3-STATE-NOTERM-SR11:12MA, IND, 10%]
|   Slowest slew rate (SR[1:0] = "11"), 0.67 * RExt = 1.500 * Iout
|   (I[2:0] = "111"), 12mA nominal with Rext = 50R,ODT off (ODT[1:0]
|   = "00") CMOS mode,Industrial temperature range (-40C to 125C,
|   25C nominal),10% power supply tolerance
|[Input Load]   NOTERM
|[Output Drive] SR11:12MA
|Voltage   1.5V
|Mode   3-STATE
Model_type   3-state
Polarity   Non-Inverting
Enable   Active-Low
Cref =  15pF
Rref =  100.0000M
Vref =  0V
Vmeas =  0.75
C_comp   1.865048p   1.676829p   1.989968p
[Temperature Range]   25   125   -40
[Voltage Range]   1.5   1.35   1.65
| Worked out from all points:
|   slope of the pulldown table from 0 to 0.225 V, typ, clamps not added: 28.3 ohm
|   slope of the pullup table from 0 to 0.225 V, typ, clamps not added: 30.1 ohm
|   GND clamp passes 1 mA (typ) near -0.49 V on its own axis
|   POWER clamp passes 1 mA (typ) near -0.47 V on its own axis
|   rising waveform, R_fixture 50, V_fixture 1.5: 20-80 % time 238ps typ, 362ps min, 185ps max; typ from 0.561 V to 1.5 V
|   rising waveform, R_fixture 50, V_fixture 0: 20-80 % time 250ps typ, 378ps min, 199ps max; typ from 0 V to 0.927 V
|   falling waveform, R_fixture 50, V_fixture 1.5: 20-80 % time 245ps typ, 364ps min, 202ps max; typ from 1.5 V to 0.561 V
|   falling waveform, R_fixture 50, V_fixture 0: 20-80 % time 235ps typ, 386ps min, 188ps max; typ from 0.927 V to 0 V
[POWER_clamp]
-1.5V     126mA      88.79mA    168.7mA
-1.242V   69.8mA     49.45mA    94.34mA
-1.136V   49.16mA    34.72mA    67.51mA
-1.061V   36.35mA    25.4mA     50.03mA
-1.045V   33.92mA    23.63mA    46.66mA
-954.5mV  21.93mA    14.95mA    29.5mA
-909.1mV  17.64mA    11.79mA    23.52mA
-863.6mV  14.51mA    9.351mA    19.47mA
-772.7mV  10.16mA    5.94mA     13.99mA
-590.9mV  3.705mA    1.741mA    5.166mA
-454.5mV  710.5uA    279.1uA    892.1uA
0V        1.424nA    14.34nA    3.127nA
[Pulldown]
-1.5V     -22.72mA   -19.8mA    -20.72mA
-1.273V   -24.32mA   -21.69mA   -22.12mA
-1V       -24.04mA   -21.98mA   -22.46mA
-727.3mV  -21.41mA   -19.82mA   -20.23mA
-500mV    -17.33mA   -16.07mA   -16.65mA
681.8mV   22.29mA    20.49mA    22.2mA
1.045V    31.02mA    28.05mA    31.64mA
1.364V    35.28mA    31.06mA    37.46mA
1.818V    37.57mA    32.23mA    41.26mA
2.136V    35.16mA    27.23mA    41.87mA
2.636V    23.27mA    10.93mA    32.21mA
3V        13.9mA     4.109mA    23.75mA
[Pullup]
-1.5V     20.4mA     15.7mA     23.88mA
-1.136V   22.69mA    19.07mA    23.99mA
-863.6mV  20.8mA     20.11mA    21.55mA
-590.9mV  17.69mA    17.57mA    18.24mA
-409.1mV  13.64mA    13.19mA    14.12mA
909.1mV   -28.37mA   -26.41mA   -29.83mA
1.318V    -38.69mA   -34.9mA    -41.21mA
1.773V    -47.12mA   -40.66mA   -51.24mA
2.045V    -49.44mA   -39.45mA   -55.45mA
2.318V    -46.83mA   -34.79mA   -55.07mA
2.682V    -39.48mA   -24.74mA   -48.59mA
3V        -30.12mA   -15.56mA   -40.19mA
[GND_clamp]
-1.5V     -219.3mA   -131.6mA   -364.3mA
-1.288V   -134.4mA   -79.74mA   -225.6mA
-1.258V   -122.9mA   -72.77mA   -206.3mA
-1.136V   -79.27mA   -46.88mA   -132.4mA
-1.045V   -51.5mA    -31.06mA   -84.11mA
-1.015V   -44.02mA   -26.9mA    -70.91mA
-954.5mV  -31.01mA   -19.7mA    -47.55mA
-863.6mV  -17.48mA   -12.16mA   -23.55mA
-803mV    -11.81mA   -8.597mA   -15.85mA
-681.8mV  -5.986mA   -4.096mA   -9.026mA
-378.8mV  -126.2uA   -131.8uA   -179.7uA
1.5V      1.424nA    207.1nA    1.498nA
[Ramp]
dV/dt_f  0.5664649/0.24642468n 0.49563872/0.36386262n   0.61803/0.20253839n
dV/dt_r 0.55976735/0.25053292n 0.49455025/0.38680224n 0.62424717/0.19942691n
R_load = 50
[Rising Waveform]
R_fixture = 50
V_fixture = 1.5
V_fixture_min = 1.35
V_fixture_max = 1.65
0s        560.9mV    529mV      623.9mV
85.9ps    560.9mV    529mV      647.2mV
214ps     595.5mV    529mV      1.088V
323ps     842.8mV    529mV      1.435V
416.9ps   1.082V     535.9mV    1.56V
521.6ps   1.312V     630mV      1.631V
674.5ps   1.432V     843.4mV    1.647V
924.6ps   1.492V     1.186V     1.65V
1.099ns   1.496V     1.292V     1.65V
2.62ns    1.5V       1.347V     1.65V
[Rising Waveform]
R_fixture = 50
V_fixture = 0
V_fixture_min = 0
V_fixture_max = 0
0s        0V         0V         0V
92.6ps    0V         0V         0V
224.4ps   0V         0V         390.9mV
367.4ps   304.3mV    0V         827.3mV
498.5ps   589.8mV    0V         981.2mV
565.3ps   732.9mV    99.78mV    1.019V
747.9ps   863.8mV    317.9mV    1.032V
1.093ns   921.3mV    723.6mV    1.036V
1.588ns   924.3mV    804.7mV    1.037V
2.631ns   927.2mV    814.9mV    1.037V
[Falling Waveform]
R_fixture = 50
V_fixture = 1.5
V_fixture_min = 1.35
V_fixture_max = 1.65
0s        1.499V     1.349V     1.649V
93ps      1.499V     1.349V     1.629V
214.7ps   1.484V     1.349V     1.273V
332.5ps   1.268V     1.349V     881.9mV
523.7ps   801.5mV    1.272V     648.4mV
760.6ps   609.8mV    1.01V      626.4mV
965.6ps   568.3mV    712.8mV    623.9mV
1.113ns   565.5mV    609.5mV    623.2mV
1.61ns    562.7mV    534.4mV    622.9mV
2.62ns    560.6mV    531.7mV    622.9mV
[Falling Waveform]
R_fixture = 50
V_fixture = 0
V_fixture_min = 0
V_fixture_max = 0
0s        927mV      817.1mV    1.036V
83.4ps    927mV      817.1mV    1.017V
198.4ps   905mV      817.1mV    627.2mV
319.4ps   615.8mV    817.1mV    226.3mV
416.5ps   383.3mV    805.4mV    90.4mV
511.5ps   185.8mV    682mV      18.39mV
747.3ps   38.91mV    387mV      2.014mV
1.014ns   4.868mV    86.62mV    0V
1.61ns    2.18mV     3.877mV    0V
2.631ns   0V         2.594mV    0V
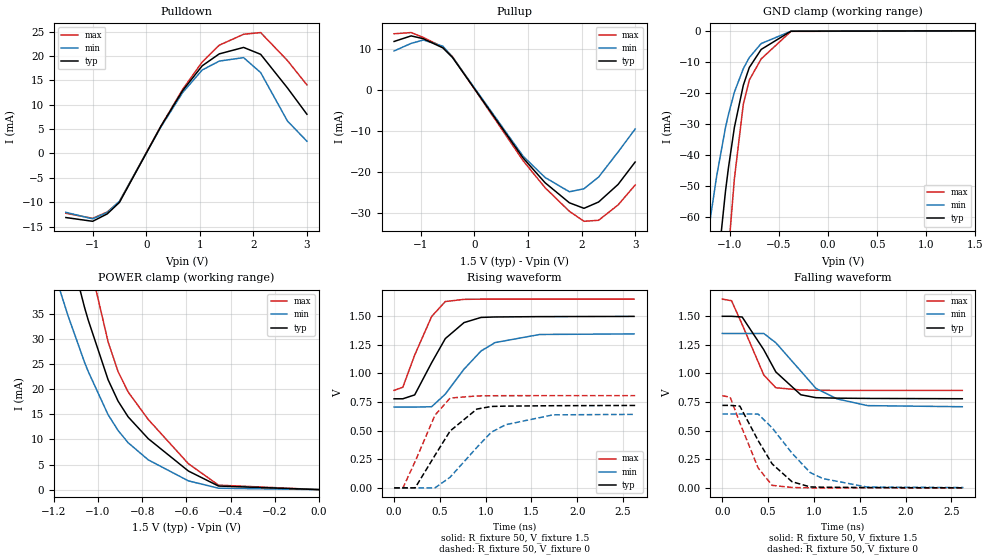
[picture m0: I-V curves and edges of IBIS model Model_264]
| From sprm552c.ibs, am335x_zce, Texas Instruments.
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| Model based on original model for BCSHTLTCSCDVPBFZ_SSDHV
|   Sub model SR11_7MA_10PER_1P5
[model]   Model_264
|[Description]  [1.5V-3-STATE-NOTERM-SR11:7MA, IND, 10%]
|   Slowest slew rate (SR[1:0] = "11"), 1.14 * RExt = 0.875 * Iout
|   (I[2:0] = "010"), 7mA nominal with Rext = 50R,ODT off (ODT[1:0]
|   = "00") CMOS mode,Industrial temperature range (-40C to 125C,
|   25C nominal),10% power supply tolerance
|[Input Load]   NOTERM
|[Output Drive] SR11:7MA
|Voltage   1.5V
|Mode   3-STATE
Model_type   3-state
Polarity   Non-Inverting
Enable   Active-Low
Cref =  15pF
Rref =  100.0000M
Vref =  0V
Vmeas =  0.75
C_comp   1.865048p   1.676829p   1.989968p
[Temperature Range]   25   125   -40
[Voltage Range]   1.5   1.35   1.65
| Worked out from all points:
|   slope of the pulldown table from 0 to 0.225 V, typ, clamps not added: 48.9 ohm
|   slope of the pullup table from 0 to 0.225 V, typ, clamps not added: 51.5 ohm
|   GND clamp passes 1 mA (typ) near -0.49 V on its own axis
|   POWER clamp passes 1 mA (typ) near -0.47 V on its own axis
|   rising waveform, R_fixture 50, V_fixture 1.5: 20-80 % time 319ps typ, 414ps min, 249ps max; typ from 0.779 V to 1.5 V
|   rising waveform, R_fixture 50, V_fixture 0: 20-80 % time 353ps typ, 445ps min, 265ps max; typ from 0 V to 0.72 V
|   falling waveform, R_fixture 50, V_fixture 1.5: 20-80 % time 330ps typ, 441ps min, 252ps max; typ from 1.5 V to 0.779 V
|   falling waveform, R_fixture 50, V_fixture 0: 20-80 % time 327ps typ, 411ps min, 246ps max; typ from 0.72 V to 0 V
[POWER_clamp]
-1.5V     126mA      88.79mA    168.7mA
-1.242V   69.8mA     49.45mA    94.34mA
-1.136V   49.16mA    34.72mA    67.51mA
-1.061V   36.35mA    25.4mA     50.03mA
-1.045V   33.92mA    23.63mA    46.66mA
-954.5mV  21.93mA    14.95mA    29.5mA
-909.1mV  17.64mA    11.79mA    23.52mA
-863.6mV  14.51mA    9.351mA    19.47mA
-772.7mV  10.16mA    5.94mA     13.99mA
-590.9mV  3.705mA    1.741mA    5.166mA
-454.5mV  710.5uA    279.1uA    892.1uA
0V        1.424nA    14.34nA    3.127nA
[Pulldown]
-1.5V     -13.15mA   -12.08mA   -12.27mA
-1V       -13.92mA   -13.42mA   -13.31mA
-727.3mV  -12.4mA    -12.1mA    -12mA
-500mV    -10.04mA   -9.816mA   -9.874mA
272.7mV   5.543mA    5.395mA    5.589mA
681.8mV   12.92mA    12.52mA    13.17mA
1.045V    17.98mA    17.12mA    18.77mA
1.364V    20.43mA    18.95mA    22.21mA
1.818V    21.75mA    19.66mA    24.45mA
2.136V    20.34mA    16.6mA     24.8mA
2.636V    13.45mA    6.663mA    19.07mA
3V        8.041mA    2.506mA    14.06mA
[Pullup]
-1.5V     11.89mA    9.575mA    13.77mA
-1.182V   13.25mA    11.42mA    14.06mA
-954.5mV  12.56mA    12.25mA    12.88mA
-590.9mV  10.33mA    10.73mA    10.53mA
-409.1mV  7.967mA    8.059mA    8.155mA
909.1mV   -16.57mA   -16.13mA   -17.23mA
1.318V    -22.59mA   -21.31mA   -23.8mA
1.773V    -27.5mA    -24.81mA   -29.58mA
2.045V    -28.84mA   -24.06mA   -32.01mA
2.318V    -27.3mA    -21.21mA   -31.76mA
2.682V    -23mA      -15.08mA   -28.01mA
3V        -17.54mA   -9.488mA   -23.16mA
[GND_clamp]
-1.5V     -219.3mA   -131.6mA   -364.3mA
-1.288V   -134.4mA   -79.74mA   -225.6mA
-1.258V   -122.9mA   -72.77mA   -206.3mA
-1.136V   -79.27mA   -46.88mA   -132.4mA
-1.045V   -51.5mA    -31.06mA   -84.11mA
-1.015V   -44.02mA   -26.9mA    -70.91mA
-954.5mV  -31.01mA   -19.7mA    -47.55mA
-863.6mV  -17.48mA   -12.16mA   -23.55mA
-803mV    -11.81mA   -8.597mA   -15.85mA
-681.8mV  -5.986mA   -4.096mA   -9.026mA
-378.8mV  -126.2uA   -131.8uA   -179.7uA
1.5V      1.424nA    207.1nA    1.498nA
[Ramp]
dV/dt_f 0.43467886/0.33184691n 0.38804631/0.44524356n  0.4801956/0.25229343n
dV/dt_r 0.43449216/0.3549009n 0.38934264/0.44154566n  0.4850054/0.26545626n
R_load = 50
[Rising Waveform]
R_fixture = 50
V_fixture = 1.5
V_fixture_min = 1.35
V_fixture_max = 1.65
0s        778.7mV    706.2mV    852.4mV
95.1ps    778.7mV    706.2mV    879.8mV
224.6ps   812.7mV    706.2mV    1.161V
409.7ps   1.094V     709.3mV    1.498V
559.1ps   1.305V     819.6mV    1.629V
763.7ps   1.445V     1.038V     1.648V
949.7ps   1.49V      1.197V     1.65V
1.102ns   1.494V     1.27V      1.65V
1.59ns    1.497V     1.341V     1.65V
2.62ns    1.499V     1.346V     1.65V
[Rising Waveform]
R_fixture = 50
V_fixture = 0
V_fixture_min = 0
V_fixture_max = 0
0s        0V         0V         0V
96.7ps    0V         0V         0V
229.6ps   0V         0V         230.9mV
447ps     285.8mV    0V         636mV
611.4ps   497.1mV    93mV       784.8mV
902.9ps   688.7mV    353mV      803.8mV
1.061ns   711.7mV    486.6mV    805.2mV
1.219ns   714.6mV    552.2mV    805.8mV
1.735ns   718.2mV    638.2mV    806.2mV
2.632ns   720.4mV    642.4mV    806.2mV
[Falling Waveform]
R_fixture = 50
V_fixture = 1.5
V_fixture_min = 1.35
V_fixture_max = 1.65
0s        1.499V     1.349V     1.649V
100.4ps   1.499V     1.349V     1.635V
216.2ps   1.493V     1.349V     1.428V
452.1ps   1.207V     1.349V     986.7mV
583.8ps   1.013V     1.268V     874.7mV
857ps     813.3mV    1.02V      854.9mV
1.022ns   788mV      869.1mV    852.8mV
1.253ns   783.8mV    777.2mV    851.7mV
1.585ns   781.4mV    718.6mV    851.4mV
2.62ns    778.6mV    708.8mV    851.4mV
[Falling Waveform]
R_fixture = 50
V_fixture = 0
V_fixture_min = 0
V_fixture_max = 0
0s        720.5mV    645.2mV    805.2mV
85.7ps    720.5mV    645.2mV    791.9mV
191.4ps   714.2mV    645.2mV    567.9mV
390.8ps   413.3mV    644.9mV    174.2mV
543.4ps   209.7mV    524.6mV    21.85mV
760.6ps   53.64mV    303.1mV    3.198mV
958.9ps   8.27mV     133.6mV    0V
1.098ns   5.63mV     81.12mV    0V
1.584ns   2.968mV    6.479mV    0V
2.632ns   0V         2.845mV    0V
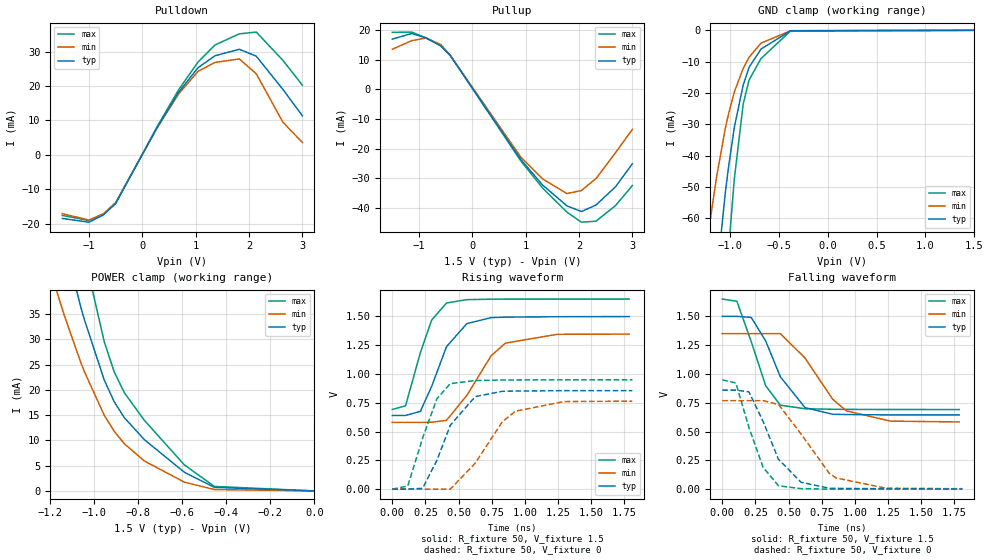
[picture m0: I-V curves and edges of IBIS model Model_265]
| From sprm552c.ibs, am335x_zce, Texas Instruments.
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| Model based on original model for BCSHTLTCSCDVPBFZ_SSDHV
|   Sub model SR10_10MA_10PER_1P5
[model]   Model_265
|[Description]  [1.5V-3-STATE-NOTERM-SR10:10MA, IND, 10%]
|   Fast slew rate (SR[1:0] = "10"), 0.80 * RExt = 1.250 * Iout
|   (I[2:0] = "101"), 10mA nominal with Rext = 50R,ODT off (ODT[1:0]
|   = "00") CMOS mode,Industrial temperature range (-40C to 125C,
|   25C nominal),10% power supply tolerance
|[Input Load]   NOTERM
|[Output Drive] SR10:10MA
|Voltage   1.5V
|Mode   3-STATE
Model_type   3-state
Polarity   Non-Inverting
Enable   Active-Low
Cref =  15pF
Rref =  100.0000M
Vref =  0V
Vmeas =  0.75
C_comp   1.865048p   1.676829p   1.989968p
[Temperature Range]   25   125   -40
[Voltage Range]   1.5   1.35   1.65
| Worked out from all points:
|   slope of the pulldown table from 0 to 0.225 V, typ, clamps not added: 34.7 ohm
|   slope of the pullup table from 0 to 0.225 V, typ, clamps not added: 36.1 ohm
|   GND clamp passes 1 mA (typ) near -0.49 V on its own axis
|   POWER clamp passes 1 mA (typ) near -0.47 V on its own axis
|   rising waveform, R_fixture 50, V_fixture 1.5: 20-80 % time 182ps typ, 253ps min, 148ps max; typ from 0.64 V to 1.5 V
|   rising waveform, R_fixture 50, V_fixture 0: 20-80 % time 195ps typ, 264ps min, 157ps max; typ from 0 V to 0.855 V
|   falling waveform, R_fixture 50, V_fixture 1.5: 20-80 % time 212ps typ, 285ps min, 162ps max; typ from 1.5 V to 0.644 V
|   falling waveform, R_fixture 50, V_fixture 0: 20-80 % time 200ps typ, 283ps min, 159ps max; typ from 0.859 V to 0.002 V
[POWER_clamp]
-1.5V     126mA      88.79mA    168.7mA
-1.242V   69.8mA     49.45mA    94.34mA
-1.136V   49.16mA    34.72mA    67.51mA
-1.061V   36.35mA    25.4mA     50.03mA
-1.045V   33.92mA    23.63mA    46.66mA
-954.5mV  21.93mA    14.95mA    29.5mA
-909.1mV  17.64mA    11.79mA    23.52mA
-863.6mV  14.51mA    9.351mA    19.47mA
-772.7mV  10.16mA    5.94mA     13.99mA
-590.9mV  3.705mA    1.741mA    5.166mA
-454.5mV  710.5uA    279.1uA    892.1uA
0V        1.424nA    14.34nA    3.127nA
[Pulldown]
-1.5V     -18.53mA   -17.11mA   -17.64mA
-1V       -19.61mA   -19mA      -19.13mA
-727.3mV  -17.47mA   -17.14mA   -17.24mA
-500mV    -14.14mA   -13.9mA    -14.19mA
272.7mV   7.805mA    7.637mA    8.027mA
681.8mV   18.19mA    17.72mA    18.92mA
1.045V    25.32mA    24.25mA    26.96mA
1.364V    28.79mA    26.85mA    31.92mA
1.818V    30.65mA    27.86mA    35.15mA
2.136V    28.67mA    23.53mA    35.66mA
2.636V    18.97mA    9.445mA    27.43mA
3V        11.34mA    3.552mA    20.22mA
[Pullup]
-1.5V     17mA       13.57mA    19.29mA
-1.136V   18.91mA    16.49mA    19.38mA
-863.6mV  17.34mA    17.39mA    17.41mA
-590.9mV  14.75mA    15.19mA    14.74mA
-409.1mV  11.37mA    11.41mA    11.41mA
909.1mV   -23.65mA   -22.84mA   -24.11mA
1.318V    -32.26mA   -30.18mA   -33.3mA
1.773V    -39.28mA   -35.15mA   -41.4mA
2.045V    -41.2mA    -34.1mA    -44.8mA
2.318V    -39.01mA   -30.07mA   -44.47mA
2.682V    -32.88mA   -21.38mA   -39.23mA
3V        -25.08mA   -13.45mA   -32.44mA
[GND_clamp]
-1.5V     -219.3mA   -131.6mA   -364.3mA
-1.288V   -134.4mA   -79.74mA   -225.6mA
-1.258V   -122.9mA   -72.77mA   -206.3mA
-1.136V   -79.27mA   -46.88mA   -132.4mA
-1.045V   -51.5mA    -31.06mA   -84.11mA
-1.015V   -44.02mA   -26.9mA    -70.91mA
-954.5mV  -31.01mA   -19.7mA    -47.55mA
-863.6mV  -17.48mA   -12.16mA   -23.55mA
-803mV    -11.81mA   -8.597mA   -15.85mA
-681.8mV  -5.986mA   -4.096mA   -9.026mA
-378.8mV  -126.2uA   -131.8uA   -179.7uA
1.5V      1.424nA    207.1nA    1.498nA
[Ramp]
dV/dt_f 0.51831139/0.2149802n  0.4639986/0.28589163n 0.57667479/0.16240049n
dV/dt_r 0.51818555/0.1973951n 0.46379221/0.26365759n 0.57148433/0.15730739n
R_load = 50
[Rising Waveform]
R_fixture = 50
V_fixture = 1.5
V_fixture_min = 1.35
V_fixture_max = 1.65
0s        639.6mV    579.9mV    691.7mV
100.2ps   639.6mV    579.9mV    723.9mV
211.9ps   675mV      579.9mV    1.185V
297.2ps   892.6mV    580.6mV    1.468V
409.1ps   1.237V     597.2mV    1.616V
562.9ps   1.437V     814.9mV    1.645V
746.1ps   1.489V     1.159V     1.649V
854.2ps   1.493V     1.268V     1.65V
1.244ns   1.497V     1.344V     1.65V
1.787ns   1.498V     1.346V     1.65V
[Rising Waveform]
R_fixture = 50
V_fixture = 0
V_fixture_min = 0
V_fixture_max = 0
0s        0V         0V         0V
117.2ps   0V         0V         28.18mV
229ps     7.386mV    0V         445mV
336.8ps   251.1mV    0V         785.1mV
437.3ps   554mV      0V         916mV
625.2ps   803.4mV    224.8mV    942.9mV
830.6ps   849.5mV    585.9mV    947.6mV
928.8ps   851.6mV    676.8mV    948mV
1.297ns   855.2mV    760.4mV    948.9mV
1.811ns   855.2mV    763.9mV    949.4mV
[Falling Waveform]
R_fixture = 50
V_fixture = 1.5
V_fixture_min = 1.35
V_fixture_max = 1.65
0s        1.499V     1.349V     1.649V
110.1ps   1.499V     1.349V     1.63V
218.2ps   1.49V      1.349V     1.28V
327.6ps   1.285V     1.349V     896.6mV
438.2ps   974.3mV    1.349V     728.5mV
624.2ps   707.5mV    1.137V     697.6mV
832.9ps   649.7mV    780mV      692.9mV
935.8ps   647.3mV    679.2mV    692.1mV
1.27ns    644mV      590.1mV    690.9mV
1.787ns   644mV      583.1mV    690.7mV
[Falling Waveform]
R_fixture = 50
V_fixture = 0
V_fixture_min = 0
V_fixture_max = 0
0s        858.8mV    767.4mV    948.5mV
102.3ps   858.8mV    767.4mV    921mV
201.1ps   844.3mV    767.4mV    534.9mV
307.9ps   587.2mV    767.4mV    189.4mV
423.6ps   259.5mV    735.2mV    29.35mV
594.5ps   60.03mV    477.8mV    4.765mV
805.8ps   8.081mV    139.1mV    0V
857.8ps   6.79mV     97.15mV    0V
1.235ns   3.696mV    8.188mV    0V
1.811ns   2.022mV    4.058mV    0V
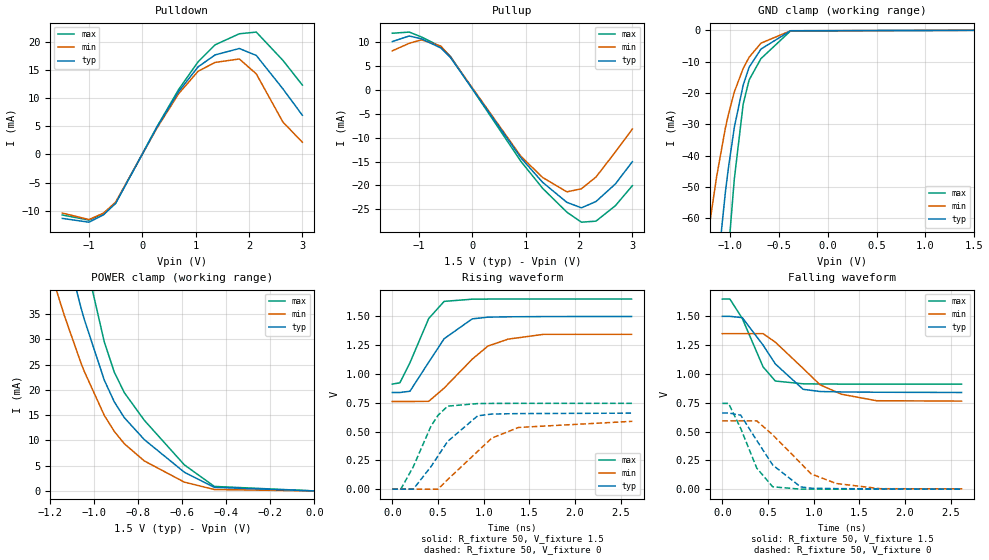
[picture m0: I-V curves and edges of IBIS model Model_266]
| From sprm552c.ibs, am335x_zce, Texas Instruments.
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| Model based on original model for BCSHTLTCSCDVPBFZ_SSDHV
|   Sub model SR11_6MA_10PER_1P5
[model]   Model_266
|[Description]  [1.5V-3-STATE-NOTERM-SR11:6MA, IND, 10%]
|   Slowest slew rate (SR[1:0] = "11"), 1.33 * RExt = 0.750 * Iout
|   (I[2:0] = "001"), 6mA nominal with Rext = 50R,ODT off (ODT[1:0]
|   = "00") CMOS mode,Industrial temperature range (-40C to 125C,
|   25C nominal),10% power supply tolerance
|[Input Load]   NOTERM
|[Output Drive] SR11:6MA
|Voltage   1.5V
|Mode   3-STATE
Model_type   3-state
Polarity   Non-Inverting
Enable   Active-Low
Cref =  15pF
Rref =  100.0000M
Vref =  0V
Vmeas =  0.75
C_comp   1.865048p   1.676829p   1.989968p
[Temperature Range]   25   125   -40
[Voltage Range]   1.5   1.35   1.65
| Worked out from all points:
|   slope of the pulldown table from 0 to 0.225 V, typ, clamps not added: 56.6 ohm
|   slope of the pullup table from 0 to 0.225 V, typ, clamps not added: 60 ohm
|   GND clamp passes 1 mA (typ) near -0.49 V on its own axis
|   POWER clamp passes 1 mA (typ) near -0.47 V on its own axis
|   rising waveform, R_fixture 50, V_fixture 1.5: 20-80 % time 345ps typ, 448ps min, 242ps max; typ from 0.839 V to 1.5 V
|   rising waveform, R_fixture 50, V_fixture 0: 20-80 % time 368ps typ, 497ps min, 259ps max; typ from 0 V to 0.66 V
|   falling waveform, R_fixture 50, V_fixture 1.5: 20-80 % time 363ps typ, 485ps min, 241ps max; typ from 1.5 V to 0.839 V
|   falling waveform, R_fixture 50, V_fixture 0: 20-80 % time 349ps typ, 456ps min, 240ps max; typ from 0.661 V to 0 V
[POWER_clamp]
-1.5V     126mA      88.79mA    168.7mA
-1.242V   69.8mA     49.45mA    94.34mA
-1.136V   49.16mA    34.72mA    67.51mA
-1.061V   36.35mA    25.4mA     50.03mA
-1.045V   33.92mA    23.63mA    46.66mA
-954.5mV  21.93mA    14.95mA    29.5mA
-909.1mV  17.64mA    11.79mA    23.52mA
-863.6mV  14.51mA    9.351mA    19.47mA
-772.7mV  10.16mA    5.94mA     13.99mA
-590.9mV  3.705mA    1.741mA    5.166mA
-454.5mV  710.5uA    279.1uA    892.1uA
0V        1.424nA    14.34nA    3.127nA
[Pulldown]
-1.5V     -11.35mA   -10.4mA    -10.74mA
-1V       -12.02mA   -11.55mA   -11.65mA
-727.3mV  -10.71mA   -10.42mA   -10.5mA
-500mV    -8.674mA   -8.454mA   -8.641mA
272.7mV   4.789mA    4.647mA    4.892mA
681.8mV   11.16mA    10.78mA    11.53mA
1.045V    15.53mA    14.75mA    16.42mA
1.364V    17.65mA    16.32mA    19.44mA
1.818V    18.79mA    16.93mA    21.4mA
2.136V    17.56mA    14.29mA    21.7mA
2.636V    11.62mA    5.736mA    16.68mA
3V        6.943mA    2.158mA    12.3mA
[Pullup]
-1.5V     10.19mA    8.245mA    11.94mA
-1.182V   11.36mA    9.829mA    12.18mA
-954.5mV  10.77mA    10.55mA    11.16mA
-590.9mV  8.854mA    9.241mA    9.128mA
-409.1mV  6.831mA    6.942mA    7.07mA
909.1mV   -14.2mA    -13.89mA   -14.94mA
1.318V    -19.37mA   -18.35mA   -20.63mA
1.773V    -23.58mA   -21.37mA   -25.64mA
2.045V    -24.72mA   -20.72mA   -27.74mA
2.318V    -23.4mA    -18.26mA   -27.52mA
2.682V    -19.71mA   -12.98mA   -24.27mA
3V        -15.03mA   -8.169mA   -20.07mA
[GND_clamp]
-1.5V     -219.3mA   -131.6mA   -364.3mA
-1.288V   -134.4mA   -79.74mA   -225.6mA
-1.258V   -122.9mA   -72.77mA   -206.3mA
-1.136V   -79.27mA   -46.88mA   -132.4mA
-1.045V   -51.5mA    -31.06mA   -84.11mA
-1.015V   -44.02mA   -26.9mA    -70.91mA
-954.5mV  -31.01mA   -19.7mA    -47.55mA
-863.6mV  -17.48mA   -12.16mA   -23.55mA
-803mV    -11.81mA   -8.597mA   -15.85mA
-681.8mV  -5.986mA   -4.096mA   -9.026mA
-378.8mV  -126.2uA   -131.8uA   -179.7uA
1.5V      1.424nA    207.1nA    1.498nA
[Ramp]
dV/dt_f 0.39839072/0.36494881n 0.35504781/0.48855766n 0.44396096/0.24123721n
dV/dt_r  0.3983591/0.36991678n 0.35741261/0.50286052n 0.44784275/0.25901506n
R_load = 50
[Rising Waveform]
R_fixture = 50
V_fixture = 1.5
V_fixture_min = 1.35
V_fixture_max = 1.65
0s        838.8mV    760.9mV    912.2mV
82.6ps    838.8mV    760.9mV    922.8mV
193.3ps   849.9mV    760.9mV    1.097V
399ps     1.102V     762.5mV    1.481V
568ps     1.306V     877.5mV    1.63V
875.1ps   1.478V     1.128V     1.649V
1.047ns   1.493V     1.242V     1.65V
1.267ns   1.496V     1.302V     1.65V
1.657ns   1.498V     1.344V     1.65V
2.62ns    1.499V     1.344V     1.65V
[Rising Waveform]
R_fixture = 50
V_fixture = 0
V_fixture_min = 0
V_fixture_max = 0
0s        0V         0V         0V
93.4ps    0V         0V         0V
230ps     0V         0V         194.7mV
424.1ps   196mV      0V         548.1mV
500.8ps   288.1mV    0V         640.9mV
606.2ps   414.2mV    83.24mV    720.5mV
935.2ps   636.8mV    328.4mV    742.9mV
1.09ns    652mV      443.3mV    744.2mV
1.382ns   656mV      535.6mV    744.8mV
2.629ns   659.8mV    588.9mV    745mV
[Falling Waveform]
R_fixture = 50
V_fixture = 1.5
V_fixture_min = 1.35
V_fixture_max = 1.65
0s        1.499V     1.349V     1.649V
83.4ps    1.499V     1.349V     1.649V
218.3ps   1.488V     1.349V     1.482V
446.6ps   1.25V      1.349V     1.061V
581ps     1.086V     1.275V     937.9mV
885.7ps   866mV      1.047V     913.9mV
1.071ns   847mV      905.2mV    912.2mV
1.306ns   843.3mV    823.4mV    911.5mV
1.689ns   840.8mV    767.1mV    911.3mV
2.62ns    838.7mV    763.9mV    911.2mV
[Falling Waveform]
R_fixture = 50
V_fixture = 0
V_fixture_min = 0
V_fixture_max = 0
0s        660.5mV    592.6mV    744mV
68.9ps    660.5mV    592.6mV    744mV
202.1ps   641.9mV    592.6mV    526.5mV
377.6ps   422.2mV    592.6mV    182.4mV
552.6ps   208.9mV    471.1mV    20.43mV
858.3ps   19.89mV    225.6mV    0V
973ps     8.396mV    132.4mV    0V
1.248ns   4.668mV    49.26mV    0V
1.73ns    2.592mV    3.994mV    0V
2.629ns   0V         2.846mV    0V
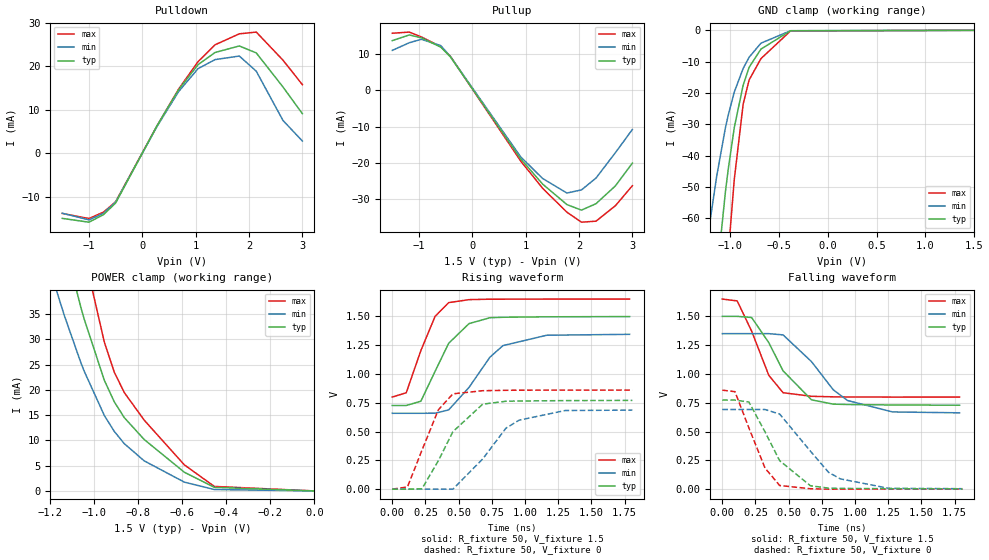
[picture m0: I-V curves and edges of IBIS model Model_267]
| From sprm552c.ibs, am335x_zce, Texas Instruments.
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| Model based on original model for BCSHTLTCSCDVPBFZ_SSDHV
|   Sub model SR10_8MA_10PER_1P5
[model]   Model_267
|[Description]  [1.5V-3-STATE-NOTERM-SR10:8MA, IND, 10%]
|   Fast slew rate (SR[1:0] = "10"), 1.00 * RExt = 1.000 * Iout
|   (I[2:0] = "011"), 8mA nominal with Rext = 50R,ODT off (ODT[1:0]
|   = "00") CMOS mode,Industrial temperature range (-40C to 125C,
|   25C nominal),10% power supply tolerance
|[Input Load]   NOTERM
|[Output Drive] SR10:8MA
|Voltage   1.5V
|Mode   3-STATE
Model_type   3-state
Polarity   Non-Inverting
Enable   Active-Low
Cref =  15pF
Rref =  100.0000M
Vref =  0V
Vmeas =  0.75
C_comp   1.865048p   1.676829p   1.989968p
[Temperature Range]   25   125   -40
[Voltage Range]   1.5   1.35   1.65
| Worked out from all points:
|   slope of the pulldown table from 0 to 0.225 V, typ, clamps not added: 43 ohm
|   slope of the pullup table from 0 to 0.225 V, typ, clamps not added: 45 ohm
|   GND clamp passes 1 mA (typ) near -0.49 V on its own axis
|   POWER clamp passes 1 mA (typ) near -0.47 V on its own axis
|   rising waveform, R_fixture 50, V_fixture 1.5: 20-80 % time 207ps typ, 270ps min, 161ps max; typ from 0.726 V to 1.5 V
|   rising waveform, R_fixture 50, V_fixture 0: 20-80 % time 228ps typ, 283ps min, 172ps max; typ from 0 V to 0.77 V
|   falling waveform, R_fixture 50, V_fixture 1.5: 20-80 % time 234ps typ, 306ps min, 173ps max; typ from 1.5 V to 0.728 V
|   falling waveform, R_fixture 50, V_fixture 0: 20-80 % time 228ps typ, 291ps min, 172ps max; typ from 0.773 V to 0.002 V
[POWER_clamp]
-1.5V     126mA      88.79mA    168.7mA
-1.242V   69.8mA     49.45mA    94.34mA
-1.136V   49.16mA    34.72mA    67.51mA
-1.061V   36.35mA    25.4mA     50.03mA
-1.045V   33.92mA    23.63mA    46.66mA
-954.5mV  21.93mA    14.95mA    29.5mA
-909.1mV  17.64mA    11.79mA    23.52mA
-863.6mV  14.51mA    9.351mA    19.47mA
-772.7mV  10.16mA    5.94mA     13.99mA
-590.9mV  3.705mA    1.741mA    5.166mA
-454.5mV  710.5uA    279.1uA    892.1uA
0V        1.424nA    14.34nA    3.127nA
[Pulldown]
-1.5V     -14.94mA   -13.76mA   -13.81mA
-1V       -15.82mA   -15.28mA   -14.98mA
-727.3mV  -14.09mA   -13.78mA   -13.5mA
-500mV    -11.41mA   -11.18mA   -11.11mA
272.7mV   6.297mA    6.143mA    6.286mA
681.8mV   14.68mA    14.25mA    14.82mA
1.045V    20.42mA    19.5mA     21.11mA
1.364V    23.22mA    21.58mA    24.99mA
1.818V    24.72mA    22.4mA     27.51mA
2.136V    23.12mA    18.91mA    27.91mA
2.636V    15.29mA    7.59mA     21.46mA
3V        9.139mA    2.855mA    15.82mA
[Pullup]
-1.5V     13.59mA    10.91mA    15.61mA
-1.182V   15.15mA    13mA       15.93mA
-954.5mV  14.35mA    13.95mA    14.59mA
-590.9mV  11.8mA     12.22mA    11.93mA
-409.1mV  9.103mA    9.176mA    9.241mA
909.1mV   -18.93mA   -18.37mA   -19.52mA
1.318V    -25.81mA   -24.27mA   -26.97mA
1.773V    -31.43mA   -28.26mA   -33.52mA
2.045V    -32.96mA   -27.41mA   -36.27mA
2.318V    -31.2mA    -24.16mA   -35.99mA
2.682V    -26.3mA    -17.18mA   -31.75mA
3V        -20.05mA   -10.81mA   -26.25mA
[GND_clamp]
-1.5V     -219.3mA   -131.6mA   -364.3mA
-1.288V   -134.4mA   -79.74mA   -225.6mA
-1.258V   -122.9mA   -72.77mA   -206.3mA
-1.136V   -79.27mA   -46.88mA   -132.4mA
-1.045V   -51.5mA    -31.06mA   -84.11mA
-1.015V   -44.02mA   -26.9mA    -70.91mA
-954.5mV  -31.01mA   -19.7mA    -47.55mA
-863.6mV  -17.48mA   -12.16mA   -23.55mA
-803mV    -11.81mA   -8.597mA   -15.85mA
-681.8mV  -5.986mA   -4.096mA   -9.026mA
-378.8mV  -126.2uA   -131.8uA   -179.7uA
1.5V      1.424nA    207.1nA    1.498nA
[Ramp]
dV/dt_f   0.465956/0.23612352n 0.41603565/0.30839346n 0.51159653/0.17354852n
dV/dt_r 0.46586951/0.23027501n 0.41683749/0.2857454n 0.51719658/0.17192146n
R_load = 50
[Rising Waveform]
R_fixture = 50
V_fixture = 1.5
V_fixture_min = 1.35
V_fixture_max = 1.65
0s        726.3mV    658.6mV    799.6mV
105ps     726.3mV    658.6mV    836.5mV
215.3ps   763.3mV    658.6mV    1.203V
322ps     1.022V     659.1mV    1.499V
424.5ps   1.266V     687.9mV    1.619V
577.9ps   1.437V     883.2mV    1.645V
735.6ps   1.488V     1.146V     1.649V
833.5ps   1.492V     1.246V     1.649V
1.163ns   1.496V     1.336V     1.65V
1.787ns   1.498V     1.344V     1.65V
[Rising Waveform]
R_fixture = 50
V_fixture = 0
V_fixture_min = 0
V_fixture_max = 0
0s        0V         0V         0V
114.2ps   0V         0V         19.73mV
223.4ps   3.073mV    0V         337.3mV
347.2ps   247.6mV    0V         689.2mV
456.5ps   498.9mV    0V         827.4mV
680.8ps   737.8mV    262.1mV    854.6mV
856.2ps   763.1mV    529.6mV    858.1mV
955.3ps   765.2mV    598.9mV    859mV
1.302ns   768.7mV    682.7mV    859.8mV
1.808ns   770.4mV    686.1mV    859.9mV
[Falling Waveform]
R_fixture = 50
V_fixture = 1.5
V_fixture_min = 1.35
V_fixture_max = 1.65
0s        1.499V     1.349V     1.649V
112.3ps   1.499V     1.349V     1.633V
221ps     1.489V     1.349V     1.371V
350.2ps   1.271V     1.349V     987.5mV
458ps     1.026V     1.338V     836.6mV
672.2ps   774.6mV    1.106V     805.5mV
835.6ps   737.6mV    862mV      800.9mV
943.2ps   734.4mV    769mV      799.7mV
1.282ns   730.3mV    669.9mV    798.8mV
1.787ns   728.1mV    662.2mV    799mV
[Falling Waveform]
R_fixture = 50
V_fixture = 0
V_fixture_min = 0
V_fixture_max = 0
0s        772.6mV    691.1mV    859mV
95.8ps    772.6mV    691.1mV    845.6mV
200.5ps   755.8mV    691.1mV    530.5mV
321.6ps   497.2mV    691.1mV    183.3mV
432.2ps   246.7mV    651.5mV    31.68mV
663.7ps   29.7mV     329.4mV    3.75mV
800.8ps   8.753mV    145.6mV    0V
888.8ps   6.715mV    89.51mV    0V
1.252ns   3.93mV     7.681mV    0V
1.808ns   2.336mV    4.115mV    0V
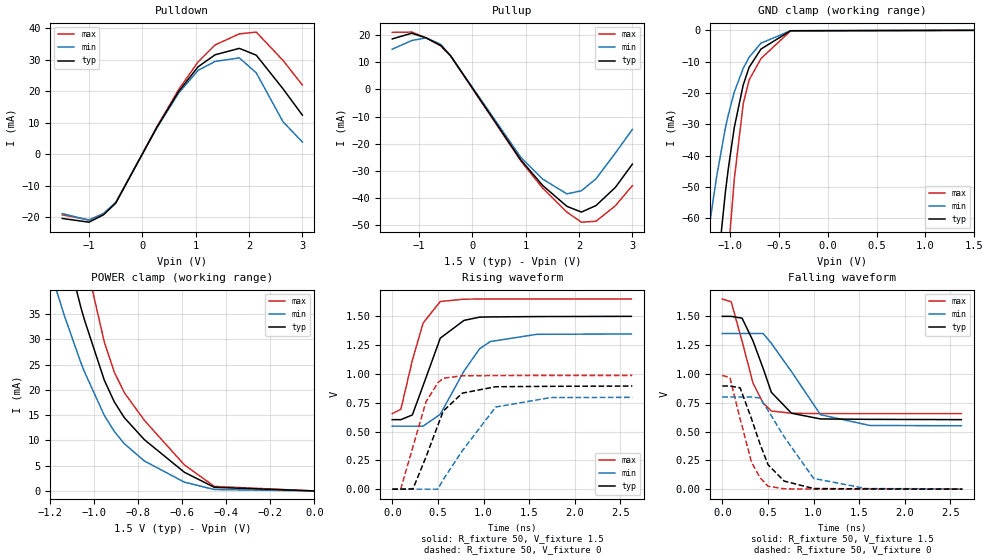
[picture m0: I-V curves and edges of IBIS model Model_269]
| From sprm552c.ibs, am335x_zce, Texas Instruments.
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| Model based on original model for BCSHTLTCSCDVPBFZ_SSDHV
|   Sub model SR11_11MA_10PER_1P5
[model]   Model_269
|[Description]  [1.5V-3-STATE-NOTERM-SR11:11MA, IND, 10%]
|   Slowest slew rate (SR[1:0] = "11"), 0.73 * RExt = 1.325 * Iout
|   (I[2:0] = "110"), 11mA nominal with Rext = 50R,ODT off (ODT[1:0]
|   = "00") CMOS mode,Industrial temperature range (-40C to 125C,
|   25C nominal),10% power supply tolerance
|[Input Load]   NOTERM
|[Output Drive] SR11:11MA
|Voltage   1.5V
|Mode   3-STATE
Model_type   3-state
Polarity   Non-Inverting
Enable   Active-Low
Cref =  15pF
Rref =  100.0000M
Vref =  0V
Vmeas =  0.75
C_comp   1.865048p   1.676829p   1.989968p
[Temperature Range]   25   125   -40
[Voltage Range]   1.5   1.35   1.65
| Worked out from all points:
|   slope of the pulldown table from 0 to 0.225 V, typ, clamps not added: 31.7 ohm
|   slope of the pullup table from 0 to 0.225 V, typ, clamps not added: 32.8 ohm
|   GND clamp passes 1 mA (typ) near -0.49 V on its own axis
|   POWER clamp passes 1 mA (typ) near -0.47 V on its own axis
|   rising waveform, R_fixture 50, V_fixture 1.5: 20-80 % time 247ps typ, 364ps min, 199ps max; typ from 0.603 V to 1.5 V
|   rising waveform, R_fixture 50, V_fixture 0: 20-80 % time 264ps typ, 378ps min, 220ps max; typ from 0 V to 0.895 V
|   falling waveform, R_fixture 50, V_fixture 1.5: 20-80 % time 259ps typ, 363ps min, 207ps max; typ from 1.5 V to 0.603 V
|   falling waveform, R_fixture 50, V_fixture 0: 20-80 % time 250ps typ, 382ps min, 202ps max; typ from 0.895 V to 0 V
[POWER_clamp]
-1.5V     126mA      88.79mA    168.7mA
-1.242V   69.8mA     49.45mA    94.34mA
-1.136V   49.16mA    34.72mA    67.51mA
-1.061V   36.35mA    25.4mA     50.03mA
-1.045V   33.92mA    23.63mA    46.66mA
-954.5mV  21.93mA    14.95mA    29.5mA
-909.1mV  17.64mA    11.79mA    23.52mA
-863.6mV  14.51mA    9.351mA    19.47mA
-772.7mV  10.16mA    5.94mA     13.99mA
-590.9mV  3.705mA    1.741mA    5.166mA
-454.5mV  710.5uA    279.1uA    892.1uA
0V        1.424nA    14.34nA    3.127nA
[Pulldown]
-1.5V     -20.32mA   -18.79mA   -19.18mA
-1V       -21.51mA   -20.87mA   -20.79mA
-727.3mV  -19.16mA   -18.81mA   -18.74mA
-500mV    -15.51mA   -15.26mA   -15.42mA
272.7mV   8.558mA    8.384mA    8.723mA
681.8mV   19.95mA    19.45mA    20.56mA
1.045V    27.76mA    26.62mA    29.3mA
1.364V    31.57mA    29.48mA    34.69mA
1.818V    33.61mA    30.59mA    38.2mA
2.136V    31.45mA    25.84mA    38.77mA
2.636V    20.81mA    10.37mA    29.82mA
3V        12.44mA    3.9mA      21.98mA
[Pullup]
-1.5V     18.7mA     14.9mA     21.12mA
-1.136V   20.8mA     18.1mA     21.22mA
-863.6mV  19.07mA    19.09mA    19.07mA
-590.9mV  16.22mA    16.68mA    16.14mA
-409.1mV  12.51mA    12.52mA    12.49mA
909.1mV   -26.01mA   -25.07mA   -26.4mA
1.318V    -35.47mA   -33.13mA   -36.46mA
1.773V    -43.2mA    -38.59mA   -45.33mA
2.045V    -45.32mA   -37.44mA   -49.06mA
2.318V    -42.92mA   -33.02mA   -48.71mA
2.682V    -36.18mA   -23.48mA   -42.98mA
3V        -27.6mA    -14.77mA   -35.54mA
[GND_clamp]
-1.5V     -219.3mA   -131.6mA   -364.3mA
-1.288V   -134.4mA   -79.74mA   -225.6mA
-1.258V   -122.9mA   -72.77mA   -206.3mA
-1.136V   -79.27mA   -46.88mA   -132.4mA
-1.045V   -51.5mA    -31.06mA   -84.11mA
-1.015V   -44.02mA   -26.9mA    -70.91mA
-954.5mV  -31.01mA   -19.7mA    -47.55mA
-863.6mV  -17.48mA   -12.16mA   -23.55mA
-803mV    -11.81mA   -8.597mA   -15.85mA
-681.8mV  -5.986mA   -4.096mA   -9.026mA
-378.8mV  -126.2uA   -131.8uA   -179.7uA
1.5V      1.424nA    207.1nA    1.498nA
[Ramp]
dV/dt_f 0.54073359/0.26011762n 0.48461622/0.36504503n 0.59863021/0.20787128n
dV/dt_r 0.54012848/0.26498917n  0.4834845/0.38207132n 0.59428293/0.22015224n
R_load = 50
[Rising Waveform]
R_fixture = 50
V_fixture = 1.5
V_fixture_min = 1.35
V_fixture_max = 1.65
0s        603.4mV    547mV      656.1mV
93.7ps    603.4mV    547mV      692.7mV
220.1ps   644.4mV    547mV      1.119V
338ps     899.6mV    547mV      1.442V
526.2ps   1.311V     650.4mV    1.629V
786ps     1.465V     1.025V     1.649V
956ps     1.493V     1.218V     1.65V
1.073ns   1.495V     1.281V     1.65V
1.584ns   1.498V     1.344V     1.65V
2.62ns    1.5V       1.347V     1.65V
[Rising Waveform]
R_fixture = 50
V_fixture = 0
V_fixture_min = 0
V_fixture_max = 0
0s        0V         0V         0V
92.5ps    0V         0V         0V
226.5ps   2.263mV    0V         368.7mV
369.6ps   279.8mV    0V         758.3mV
499.1ps   553.8mV    0V         923.2mV
559.2ps   678.6mV    84.23mV    963.5mV
768ps     833.6mV    333.9mV    983.4mV
1.133ns   889.1mV    712.9mV    986.1mV
1.737ns   892.5mV    795.2mV    987.1mV
2.631ns   895mV      796.9mV    987.1mV
[Falling Waveform]
R_fixture = 50
V_fixture = 1.5
V_fixture_min = 1.35
V_fixture_max = 1.65
0s        1.499V     1.35V      1.649V
98ps      1.499V     1.35V      1.625V
217.1ps   1.483V     1.35V      1.283V
337.2ps   1.285V     1.35V      918.9mV
448ps     1.047V     1.35V      746.7mV
538.4ps   839.4mV    1.264V     678mV
759ps     658.6mV    1.019V     658.7mV
1.076ns   609.2mV    646.1mV    655.7mV
1.617ns   605.5mV    552.4mV    655.1mV
2.62ns    603.1mV    550.2mV    655.1mV
[Falling Waveform]
R_fixture = 50
V_fixture = 0
V_fixture_min = 0
V_fixture_max = 0
0s        894.8mV    799.5mV    986.2mV
83.6ps    894.8mV    799.5mV    968mV
195.8ps   879.1mV    799.5mV    609.5mV
320.4ps   609.9mV    799.5mV    234.3mV
412.4ps   393.8mV    790.9mV    101.2mV
501.1ps   212.7mV    683.2mV    25.5mV
677.9ps   70.12mV    454.2mV    3.352mV
1.001ns   5.484mV    93.19mV    0V
1.578ns   2.455mV    4.923mV    0V
2.631ns   0V         2.873mV    0V
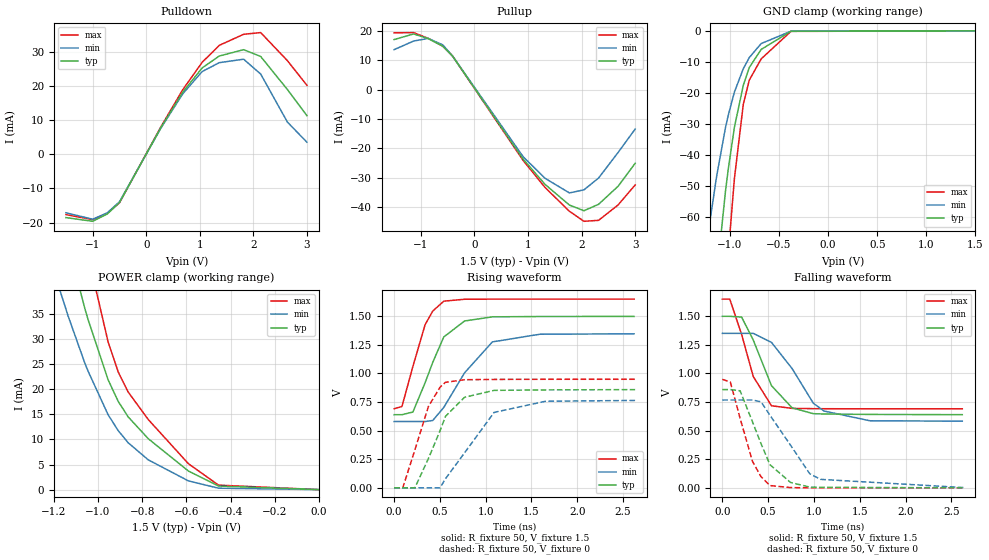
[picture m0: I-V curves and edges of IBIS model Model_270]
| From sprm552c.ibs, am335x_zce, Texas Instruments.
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| Model based on original model for BCSHTLTCSCDVPBFZ_SSDHV
|   Sub model SR11_10MA_10PER_1P5
[model]   Model_270
|[Description]  [1.5V-3-STATE-NOTERM-SR11:10MA, IND, 10%]
|   Slowest slew rate (SR[1:0] = "11"), 0.80 * RExt = 1.250 * Iout
|   (I[2:0] = "101"), 10mA nominal with Rext = 50R,ODT off (ODT[1:0]
|   = "00") CMOS mode,Industrial temperature range (-40C to 125C,
|   25C nominal),10% power supply tolerance
|[Input Load]   NOTERM
|[Output Drive] SR11:10MA
|Voltage   1.5V
|Mode   3-STATE
Model_type   3-state
Polarity   Non-Inverting
Enable   Active-Low
Cref =  15pF
Rref =  100.0000M
Vref =  0V
Vmeas =  0.75
C_comp   1.865048p   1.676829p   1.989968p
[Temperature Range]   25   125   -40
[Voltage Range]   1.5   1.35   1.65
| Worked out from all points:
|   slope of the pulldown table from 0 to 0.225 V, typ, clamps not added: 34.7 ohm
|   slope of the pullup table from 0 to 0.225 V, typ, clamps not added: 36.1 ohm
|   GND clamp passes 1 mA (typ) near -0.49 V on its own axis
|   POWER clamp passes 1 mA (typ) near -0.47 V on its own axis
|   rising waveform, R_fixture 50, V_fixture 1.5: 20-80 % time 262ps typ, 374ps min, 210ps max; typ from 0.64 V to 1.5 V
|   rising waveform, R_fixture 50, V_fixture 0: 20-80 % time 282ps typ, 387ps min, 227ps max; typ from 0 V to 0.859 V
|   falling waveform, R_fixture 50, V_fixture 1.5: 20-80 % time 281ps typ, 374ps min, 216ps max; typ from 1.5 V to 0.639 V
|   falling waveform, R_fixture 50, V_fixture 0: 20-80 % time 266ps typ, 389ps min, 213ps max; typ from 0.859 V to 0 V
[POWER_clamp]
-1.5V     126mA      88.79mA    168.7mA
-1.242V   69.8mA     49.45mA    94.34mA
-1.136V   49.16mA    34.72mA    67.51mA
-1.061V   36.35mA    25.4mA     50.03mA
-1.045V   33.92mA    23.63mA    46.66mA
-954.5mV  21.93mA    14.95mA    29.5mA
-909.1mV  17.64mA    11.79mA    23.52mA
-863.6mV  14.51mA    9.351mA    19.47mA
-772.7mV  10.16mA    5.94mA     13.99mA
-590.9mV  3.705mA    1.741mA    5.166mA
-454.5mV  710.5uA    279.1uA    892.1uA
0V        1.424nA    14.34nA    3.127nA
[Pulldown]
-1.5V     -18.53mA   -17.11mA   -17.64mA
-1V       -19.61mA   -19mA      -19.13mA
-727.3mV  -17.47mA   -17.14mA   -17.24mA
-500mV    -14.14mA   -13.9mA    -14.19mA
272.7mV   7.805mA    7.637mA    8.027mA
681.8mV   18.19mA    17.72mA    18.92mA
1.045V    25.32mA    24.25mA    26.96mA
1.364V    28.79mA    26.85mA    31.92mA
1.818V    30.65mA    27.86mA    35.15mA
2.136V    28.67mA    23.53mA    35.66mA
2.636V    18.97mA    9.445mA    27.43mA
3V        11.34mA    3.552mA    20.22mA
[Pullup]
-1.5V     17mA       13.57mA    19.29mA
-1.136V   18.91mA    16.49mA    19.38mA
-863.6mV  17.34mA    17.39mA    17.41mA
-590.9mV  14.75mA    15.19mA    14.74mA
-409.1mV  11.37mA    11.41mA    11.41mA
909.1mV   -23.65mA   -22.84mA   -24.11mA
1.318V    -32.26mA   -30.18mA   -33.3mA
1.773V    -39.28mA   -35.15mA   -41.4mA
2.045V    -41.2mA    -34.1mA    -44.8mA
2.318V    -39.01mA   -30.07mA   -44.47mA
2.682V    -32.88mA   -21.38mA   -39.23mA
3V        -25.08mA   -13.45mA   -32.44mA
[GND_clamp]
-1.5V     -219.3mA   -131.6mA   -364.3mA
-1.288V   -134.4mA   -79.74mA   -225.6mA
-1.258V   -122.9mA   -72.77mA   -206.3mA
-1.136V   -79.27mA   -46.88mA   -132.4mA
-1.045V   -51.5mA    -31.06mA   -84.11mA
-1.015V   -44.02mA   -26.9mA    -70.91mA
-954.5mV  -31.01mA   -19.7mA    -47.55mA
-863.6mV  -17.48mA   -12.16mA   -23.55mA
-803mV    -11.81mA   -8.597mA   -15.85mA
-681.8mV  -5.986mA   -4.096mA   -9.026mA
-378.8mV  -126.2uA   -131.8uA   -179.7uA
1.5V      1.424nA    207.1nA    1.498nA
[Ramp]
dV/dt_f 0.51882363/0.28244273n 0.46474107/0.37775387n 0.57700827/0.21687848n
dV/dt_r 0.51841795/0.28282684n 0.46416832/0.39345528n 0.57152709/0.2276092n
R_load = 50
[Rising Waveform]
R_fixture = 50
V_fixture = 1.5
V_fixture_min = 1.35
V_fixture_max = 1.65
0s        639.6mV    579.9mV    691.7mV
85.8ps    639.6mV    579.9mV    711.5mV
205ps     662.9mV    579.9mV    1.061V
338.1ps   918.6mV    579.9mV    1.426V
422.4ps   1.098V     589mV      1.546V
542.2ps   1.319V     703.3mV    1.632V
769.6ps   1.459V     1.006V     1.649V
1.073ns   1.495V     1.276V     1.65V
1.59ns    1.498V     1.343V     1.65V
2.62ns    1.499V     1.347V     1.65V
[Rising Waveform]
R_fixture = 50
V_fixture = 0
V_fixture_min = 0
V_fixture_max = 0
0s        0V         0V         0V
94.5ps    0V         0V         0V
226.3ps   0V         0V         329.9mV
374.3ps   255.8mV    0V         710.9mV
501.5ps   499.3mV    0V         879.9mV
560.8ps   624.4mV    79.71mV    922.8mV
769.7ps   792mV      306.5mV    945.4mV
1.092ns   852.3mV    659.7mV    948mV
1.654ns   856.5mV    757.2mV    949.3mV
2.632ns   858.9mV    764.4mV    949.4mV
[Falling Waveform]
R_fixture = 50
V_fixture = 1.5
V_fixture_min = 1.35
V_fixture_max = 1.65
0s        1.499V     1.35V      1.649V
81.1ps    1.499V     1.35V      1.649V
210.2ps   1.492V     1.35V      1.342V
337.3ps   1.292V     1.35V      973mV
536.4ps   893mV      1.271V     717.3mV
762ps     698.9mV    1.042V     694.4mV
993.2ps   648.1mV    739.5mV    692.1mV
1.11ns    645.5mV    671.3mV    691.4mV
1.612ns   641.5mV    586.2mV    690.7mV
2.62ns    639.5mV    582.6mV    690.7mV
[Falling Waveform]
R_fixture = 50
V_fixture = 0
V_fixture_min = 0
V_fixture_max = 0
0s        858.9mV    767.6mV    948.4mV
87ps      858.9mV    767.6mV    925.3mV
193.9ps   847.9mV    767.6mV    607.7mV
328.9ps   577mV      767.6mV    231.6mV
421.7ps   387.5mV    751.9mV    98.11mV
519.9ps   202.2mV    634.5mV    19.71mV
745.6ps   46.96mV    371.5mV    2.389mV
954.2ps   6.737mV    123.7mV    0V
1.073ns   5.034mV    74.21mV    0V
2.632ns   0V         2.629mV    0V
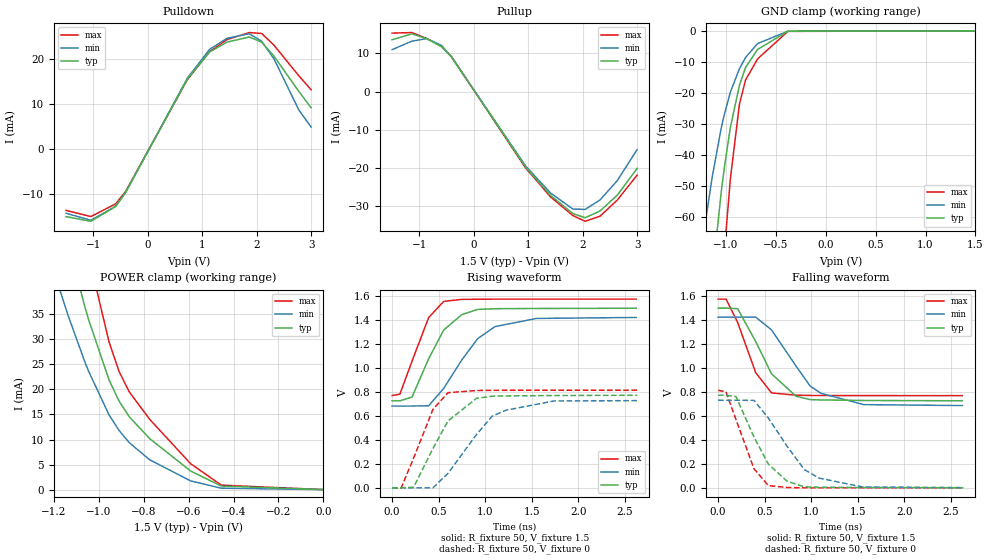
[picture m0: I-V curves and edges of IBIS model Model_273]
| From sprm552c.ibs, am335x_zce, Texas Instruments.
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| Model based on original model for BCSHTLTCSCDVPBFZ_SSDHV
|   Sub model SR11_8MA_5PER_1P5
[model]   Model_273
|[Description]  [1.5V-3-STATE-NOTERM-SR11:8MA, IND, 5%]
|   Slowest slew rate (SR[1:0] = "11"), 1.00 * RExt = 1.000 * Iout
|   (I[2:0] = "011"), 8mA nominal with Rext = 50R,ODT off (ODT[1:0]
|   = "00") CMOS mode,Industrial temperature range (-40C to 125C,
|   25C nominal),5% power supply tolerance
|[Input Load]   NOTERM
|[Output Drive] SR11:8MA
|Voltage   1.5V
|Mode   3-STATE
Model_type   3-state
Polarity   Non-Inverting
Enable   Active-Low
Cref =  15pF
Rref =  100.0000M
Vref =  0V
Vmeas =  0.75
C_comp   1.865048p   1.679967p   1.989968p
[Temperature Range]   25   125   -40
[Voltage Range]   1.5   1.425   1.575
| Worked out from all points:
|   slope of the pulldown table from 0 to 0.225 V, typ, clamps not added: 43 ohm
|   slope of the pullup table from 0 to 0.225 V, typ, clamps not added: 45 ohm
|   GND clamp passes 1 mA (typ) near -0.49 V on its own axis
|   POWER clamp passes 1 mA (typ) near -0.47 V on its own axis
|   rising waveform, R_fixture 50, V_fixture 1.5: 20-80 % time 291ps typ, 400ps min, 226ps max; typ from 0.726 V to 1.5 V
|   rising waveform, R_fixture 50, V_fixture 0: 20-80 % time 329ps typ, 414ps min, 245ps max; typ from 0 V to 0.773 V
|   falling waveform, R_fixture 50, V_fixture 1.5: 20-80 % time 320ps typ, 401ps min, 229ps max; typ from 1.5 V to 0.726 V
|   falling waveform, R_fixture 50, V_fixture 0: 20-80 % time 299ps typ, 394ps min, 227ps max; typ from 0.773 V to 0 V
[POWER_clamp]
-1.5V     126mA      88.76mA    168.8mA
-1.242V   69.8mA     49.43mA    94.36mA
-1.136V   49.16mA    34.7mA     67.53mA
-1.061V   36.35mA    25.39mA    50.04mA
-1.045V   33.92mA    23.62mA    46.67mA
-954.5mV  21.93mA    14.94mA    29.52mA
-909.1mV  17.64mA    11.78mA    23.53mA
-863.6mV  14.51mA    9.346mA    19.48mA
-772.7mV  10.16mA    5.937mA    14mA
-590.9mV  3.705mA    1.741mA    5.168mA
-454.5mV  710.5uA    279.1uA    892.2uA
0V        1.424nA    14.75nA    2.169nA
[Pulldown]
-1.5V     -14.94mA   -14.2mA    -13.55mA
-1.045V   -15.97mA   -15.73mA   -14.92mA
-590.9mV  -12.7mA    -12.67mA   -12.12mA
-409.1mV  -9.652mA   -9.646mA   -9.411mA
727.3mV   15.5mA     15.69mA    15.34mA
1.136V    21.47mA    22.05mA    21.55mA
1.455V    23.65mA    24.5mA     24.21mA
1.864V    24.78mA    25.5mA     25.76mA
2.091V    23.65mA    23.85mA    25.56mA
2.318V    20.55mA    19.94mA    22.97mA
2.773V    12.75mA    8.663mA    16.22mA
3V        9.139mA    4.878mA    13.11mA
[Pullup]
-1.5V     13.59mA    11mA       15.33mA
-1.136V   15.13mA    13.23mA    15.47mA
-863.6mV  13.87mA    13.89mA    13.92mA
-590.9mV  11.8mA     12.11mA    11.81mA
-409.1mV  9.103mA    9.093mA    9.151mA
954.5mV   -19.76mA   -19.47mA   -19.97mA
1.409V    -27.12mA   -26.48mA   -27.5mA
1.818V    -31.86mA   -30.68mA   -32.37mA
2.045V    -32.96mA   -30.78mA   -33.89mA
2.318V    -31.2mA    -28.31mA   -32.55mA
2.636V    -27.04mA   -23.24mA   -28.32mA
3V        -20.05mA   -15.12mA   -21.81mA
[GND_clamp]
-1.5V     -219.3mA   -131.6mA   -364.3mA
-1.288V   -134.4mA   -79.74mA   -225.6mA
-1.258V   -122.9mA   -72.77mA   -206.3mA
-1.136V   -79.27mA   -46.88mA   -132.4mA
-1.045V   -51.5mA    -31.06mA   -84.11mA
-1.015V   -44.02mA   -26.9mA    -70.91mA
-954.5mV  -31.01mA   -19.7mA    -47.55mA
-863.6mV  -17.48mA   -12.16mA   -23.55mA
-803mV    -11.81mA   -8.597mA   -15.85mA
-681.8mV  -5.986mA   -4.096mA   -9.026mA
-378.8mV  -126.2uA   -131.8uA   -179.7uA
1.5V      1.424nA    36.56nA    1.506nA
[Ramp]
dV/dt_f  0.4664244/0.32244704n 0.44743938/0.40560128n  0.4843797/0.22933598n
dV/dt_r 0.46615575/0.33019109n 0.44111504/0.41439245n 0.49014099/0.24632072n
R_load = 50
[Rising Waveform]
R_fixture = 50
V_fixture = 1.5
V_fixture_min = 1.425
V_fixture_max = 1.575
0s        726.3mV    682.9mV    770.3mV
83.7ps    726.3mV    682.9mV    782.1mV
213.7ps   757.6mV    682.9mV    1.057V
392.2ps   1.077V     685mV      1.421V
553.7ps   1.317V     829.9mV    1.556V
746.9ps   1.445V     1.066V     1.573V
918.1ps   1.489V     1.245V     1.574V
1.105ns   1.495V     1.346V     1.575V
1.551ns   1.497V     1.414V     1.575V
2.62ns    1.499V     1.422V     1.575V
[Rising Waveform]
R_fixture = 50
V_fixture = 0
V_fixture_min = 0
V_fixture_max = 0
0s        0V         0V         0V
97.5ps    0V         0V         0V
231.3ps   5.816mV    0V         248.8mV
437.8ps   328mV      0V         654.1mV
600.3ps   558.5mV    121.5mV    794.3mV
905.7ps   747.4mV    445mV      812.5mV
1.073ns   764.9mV    597.9mV    813.9mV
1.221ns   767.2mV    647.8mV    814.5mV
1.737ns   770.5mV    725.1mV    814.8mV
2.63ns    772.6mV    727.9mV    814.8mV
[Falling Waveform]
R_fixture = 50
V_fixture = 1.5
V_fixture_min = 1.425
V_fixture_max = 1.575
0s        1.499V     1.424V     1.574V
84.8ps    1.499V     1.424V     1.574V
209.3ps   1.494V     1.424V     1.38V
403.1ps   1.221V     1.424V     960.7mV
573.4ps   950.5mV    1.317V     791.7mV
836ps     764.5mV    1.016V     773mV
986.1ps   736.1mV    850.6mV    770.7mV
1.102ns   733.2mV    788.6mV    770mV
1.563ns   728.8mV    694.1mV    769.4mV
2.62ns    726.1mV    686.4mV    769.3mV
[Falling Waveform]
R_fixture = 50
V_fixture = 0
V_fixture_min = 0
V_fixture_max = 0
0s        772.7mV    730.6mV    813.8mV
84.2ps    772.7mV    730.6mV    801.1mV
191.8ps   761.5mV    730.6mV    569.5mV
384.3ps   424mV      730mV      160.2mV
538.8ps   198.4mV    582.9mV    18.95mV
738.9ps   55.7mV     347.8mV    3.122mV
924.6ps   8.784mV    152.7mV    0V
1.083ns   5.431mV    81.23mV    0V
1.556ns   2.91mV     6.781mV    0V
2.63ns    0V         2.795mV    0V
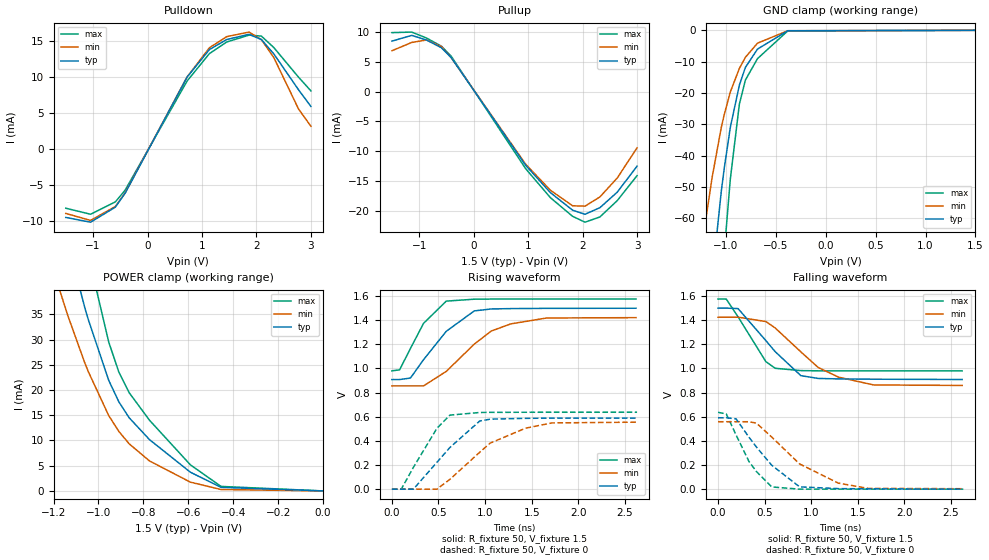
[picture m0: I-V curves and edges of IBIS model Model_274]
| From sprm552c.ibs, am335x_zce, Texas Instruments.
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| Model based on original model for BCSHTLTCSCDVPBFZ_SSDHV
|   Sub model SR11_5MA_5PER_1P5
[model]   Model_274
|[Description]  [1.5V-3-STATE-NOTERM-SR11:5MA, IND, 5%]
|   Slowest slew rate (SR[1:0] = "11"), 1.60 * RExt = 0.625 * Iout
|   (I[2:0] = "000"), 5mA nominal with Rext = 50R,ODT off (ODT[1:0]
|   = "00") CMOS mode,Industrial temperature range (-40C to 125C,
|   25C nominal),5% power supply tolerance
|[Input Load]   NOTERM
|[Output Drive] SR11:5MA
|Voltage   1.5V
|Mode   3-STATE
Model_type   3-state
Polarity   Non-Inverting
Enable   Active-Low
Cref =  15pF
Rref =  100.0000M
Vref =  0V
Vmeas =  0.75
C_comp   1.865048p   1.679967p   1.989968p
[Temperature Range]   25   125   -40
[Voltage Range]   1.5   1.425   1.575
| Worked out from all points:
|   slope of the pulldown table from 0 to 0.225 V, typ, clamps not added: 67.2 ohm
|   slope of the pullup table from 0 to 0.225 V, typ, clamps not added: 72 ohm
|   GND clamp passes 1 mA (typ) near -0.49 V on its own axis
|   POWER clamp passes 1 mA (typ) near -0.47 V on its own axis
|   rising waveform, R_fixture 50, V_fixture 1.5: 20-80 % time 375ps typ, 486ps min, 266ps max; typ from 0.908 V to 1.5 V
|   rising waveform, R_fixture 50, V_fixture 0: 20-80 % time 406ps typ, 550ps min, 291ps max; typ from 0 V to 0.589 V
|   falling waveform, R_fixture 50, V_fixture 1.5: 20-80 % time 391ps typ, 525ps min, 280ps max; typ from 1.5 V to 0.908 V
|   falling waveform, R_fixture 50, V_fixture 0: 20-80 % time 377ps typ, 494ps min, 268ps max; typ from 0.591 V to 0 V
[POWER_clamp]
-1.5V     126mA      88.76mA    168.8mA
-1.242V   69.8mA     49.43mA    94.36mA
-1.136V   49.16mA    34.7mA     67.53mA
-1.061V   36.35mA    25.39mA    50.04mA
-1.045V   33.92mA    23.62mA    46.67mA
-954.5mV  21.93mA    14.94mA    29.52mA
-909.1mV  17.64mA    11.78mA    23.53mA
-863.6mV  14.51mA    9.346mA    19.48mA
-772.7mV  10.16mA    5.937mA    14mA
-590.9mV  3.705mA    1.741mA    5.168mA
-454.5mV  710.5uA    279.1uA    892.2uA
0V        1.424nA    14.75nA    2.169nA
[Pulldown]
-1.5V     -9.559mA   -9.005mA   -8.281mA
-1.045V   -10.22mA   -9.975mA   -9.117mA
-590.9mV  -8.133mA   -8.04mA    -7.408mA
-409.1mV  -6.182mA   -6.122mA   -5.755mA
727.3mV   9.928mA    9.954mA    9.38mA
1.136V    13.74mA    13.99mA    13.18mA
1.455V    15.14mA    15.54mA    14.8mA
1.864V    15.86mA    16.17mA    15.75mA
2.091V    15.13mA    15.12mA    15.61mA
2.318V    13.15mA    12.64mA    14.03mA
2.773V    8.157mA    5.489mA    9.905mA
3V        5.846mA    3.092mA    8.007mA
[Pullup]
-1.5V     8.494mA    6.876mA    9.92mA
-1.136V   9.455mA    8.27mA     10.01mA
-863.6mV  8.671mA    8.683mA    9.007mA
-590.9mV  7.379mA    7.572mA    7.643mA
-409.1mV  5.694mA    5.688mA    5.925mA
954.5mV   -12.36mA   -12.18mA   -12.93mA
1.409V    -16.96mA   -16.56mA   -17.81mA
1.818V    -19.92mA   -19.18mA   -20.95mA
2.045V    -20.6mA    -19.23mA   -21.93mA
2.318V    -19.49mA   -17.69mA   -21.05mA
2.636V    -16.89mA   -14.51mA   -18.31mA
3V        -12.52mA   -9.441mA   -14.11mA
[GND_clamp]
-1.5V     -219.3mA   -131.6mA   -364.3mA
-1.288V   -134.4mA   -79.74mA   -225.6mA
-1.258V   -122.9mA   -72.77mA   -206.3mA
-1.136V   -79.27mA   -46.88mA   -132.4mA
-1.045V   -51.5mA    -31.06mA   -84.11mA
-1.015V   -44.02mA   -26.9mA    -70.91mA
-954.5mV  -31.01mA   -19.7mA    -47.55mA
-863.6mV  -17.48mA   -12.16mA   -23.55mA
-803mV    -11.81mA   -8.597mA   -15.85mA
-681.8mV  -5.986mA   -4.096mA   -9.026mA
-378.8mV  -126.2uA   -131.8uA   -179.7uA
1.5V      1.424nA    36.56nA    1.506nA
[Ramp]
dV/dt_f 0.35665234/0.39286668n 0.34267847/0.53455518n 0.35818299/0.28037473n
dV/dt_r 0.35640575/0.41044153n 0.33626123/0.55336262n 0.38326516/0.29165976n
R_load = 50
[Rising Waveform]
R_fixture = 50
V_fixture = 1.5
V_fixture_min = 1.425
V_fixture_max = 1.575
0s        908.2mV    855.7mV    980.1mV
82.5ps    908.2mV    855.7mV    988.8mV
199.2ps   920.7mV    855.7mV    1.166V
339.8ps   1.073V     855.7mV    1.374V
583.5ps   1.308V     975.8mV    1.558V
884.3ps   1.477V     1.202V     1.574V
1.066ns   1.493V     1.31V      1.575V
1.274ns   1.496V     1.369V     1.575V
1.658ns   1.498V     1.418V     1.575V
2.62ns    1.499V     1.421V     1.575V
[Rising Waveform]
R_fixture = 50
V_fixture = 0
V_fixture_min = 0
V_fixture_max = 0
0s        0V         0V         0V
100.4ps   0V         0V         0V
230.1ps   0V         0V         180mV
482.9ps   222.1mV    0V         503.8mV
622ps     344.9mV    81.06mV    613.4mV
941.7ps   564.1mV    305.5mV    635.3mV
1.054ns   580.1mV    381.3mV    636.3mV
1.434ns   586.8mV    505.1mV    637.2mV
1.717ns   588.4mV    548.8mV    637.3mV
2.631ns   588.9mV    555.3mV    637.3mV
[Falling Waveform]
R_fixture = 50
V_fixture = 1.5
V_fixture_min = 1.425
V_fixture_max = 1.575
0s        1.499V     1.424V     1.574V
88.3ps    1.499V     1.424V     1.574V
214.9ps   1.495V     1.424V     1.427V
513.3ps   1.23V      1.388V     1.056V
612.8ps   1.139V     1.335V     1.001V
888.8ps   939.9mV    1.137V     981.6mV
1.074ns   916.9mV    1.008V     979.9mV
1.293ns   912.9mV    927.5mV    979.3mV
1.669ns   910.4mV    863.1mV    979.2mV
2.62ns    908.1mV    858.8mV    979.1mV
[Falling Waveform]
R_fixture = 50
V_fixture = 0
V_fixture_min = 0
V_fixture_max = 0
0s        591.1mV    558.4mV    636.3mV
88.2ps    591.1mV    558.4mV    623.1mV
192.9ps   582.4mV    558.4mV    450.3mV
332.5ps   429.8mV    558.4mV    228.5mV
412ps     348.9mV    546.9mV    145.9mV
576.4ps   197.9mV    431.4mV    18.42mV
875.4ps   19.23mV    208.7mV    0V
1.29ns    4.544mV    50.4mV     0V
1.61ns    3.07mV     6.546mV    0V
2.631ns   0V         3.746mV    0V
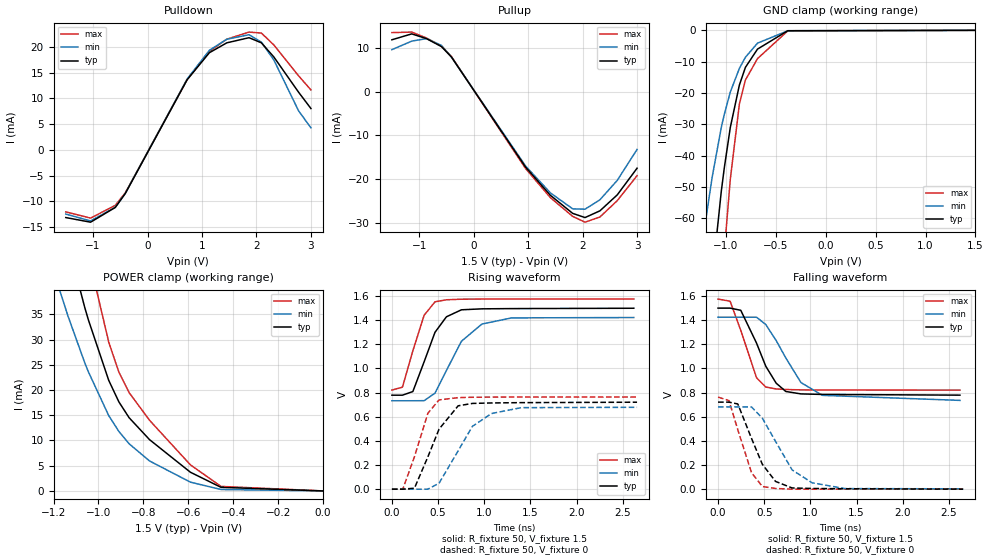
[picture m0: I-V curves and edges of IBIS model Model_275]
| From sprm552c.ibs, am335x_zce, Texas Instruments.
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| Model based on original model for BCSHTLTCSCDVPBFZ_SSDHV
|   Sub model SR10_7MA_5PER_1P5
[model]   Model_275
|[Description]  [1.5V-3-STATE-NOTERM-SR10:7MA, IND, 5%]
|   Fast slew rate (SR[1:0] = "10"), 1.14 * RExt = 0.875 * Iout
|   (I[2:0] = "010"), 7mA nominal with Rext = 50R,ODT off (ODT[1:0]
|   = "00") CMOS mode,Industrial temperature range (-40C to 125C,
|   25C nominal),5% power supply tolerance
|[Input Load]   NOTERM
|[Output Drive] SR10:7MA
|Voltage   1.5V
|Mode   3-STATE
Model_type   3-state
Polarity   Non-Inverting
Enable   Active-Low
Cref =  15pF
Rref =  100.0000M
Vref =  0V
Vmeas =  0.75
C_comp   1.865048p   1.679967p   1.989968p
[Temperature Range]   25   125   -40
[Voltage Range]   1.5   1.425   1.575
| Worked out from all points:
|   slope of the pulldown table from 0 to 0.225 V, typ, clamps not added: 48.9 ohm
|   slope of the pullup table from 0 to 0.225 V, typ, clamps not added: 51.5 ohm
|   GND clamp passes 1 mA (typ) near -0.49 V on its own axis
|   POWER clamp passes 1 mA (typ) near -0.47 V on its own axis
|   rising waveform, R_fixture 50, V_fixture 1.5: 20-80 % time 219ps typ, 295ps min, 176ps max; typ from 0.779 V to 1.5 V
|   rising waveform, R_fixture 50, V_fixture 0: 20-80 % time 241ps typ, 317ps min, 183ps max; typ from 0 V to 0.721 V
|   falling waveform, R_fixture 50, V_fixture 1.5: 20-80 % time 245ps typ, 326ps min, 191ps max; typ from 1.5 V to 0.779 V
|   falling waveform, R_fixture 50, V_fixture 0: 20-80 % time 242ps typ, 315ps min, 185ps max; typ from 0.721 V to 0 V
[POWER_clamp]
-1.5V     126mA      88.76mA    168.8mA
-1.242V   69.8mA     49.43mA    94.36mA
-1.136V   49.16mA    34.7mA     67.53mA
-1.061V   36.35mA    25.39mA    50.04mA
-1.045V   33.92mA    23.62mA    46.67mA
-954.5mV  21.93mA    14.94mA    29.52mA
-909.1mV  17.64mA    11.78mA    23.53mA
-863.6mV  14.51mA    9.346mA    19.48mA
-772.7mV  10.16mA    5.937mA    14mA
-590.9mV  3.705mA    1.741mA    5.168mA
-454.5mV  710.5uA    279.1uA    892.2uA
0V        1.424nA    14.75nA    2.169nA
[Pulldown]
-1.5V     -13.15mA   -12.47mA   -12.05mA
-1.045V   -14.05mA   -13.81mA   -13.26mA
-590.9mV  -11.18mA   -11.13mA   -10.77mA
-409.1mV  -8.496mA   -8.472mA   -8.367mA
727.3mV   13.64mA    13.78mA    13.64mA
1.136V    18.89mA    19.36mA    19.16mA
1.455V    20.81mA    21.51mA    21.52mA
1.864V    21.81mA    22.39mA    22.9mA
2.091V    20.81mA    20.94mA    22.71mA
2.318V    18.08mA    17.5mA     20.41mA
2.773V    11.22mA    7.604mA    14.41mA
3V        8.041mA    4.283mA    11.65mA
[Pullup]
-1.5V     11.89mA    9.627mA    13.53mA
-1.136V   13.24mA    11.58mA    13.65mA
-863.6mV  12.14mA    12.16mA    12.28mA
-590.9mV  10.33mA    10.6mA     10.42mA
-409.1mV  7.967mA    7.959mA    8.076mA
954.5mV   -17.3mA    -17.04mA   -17.63mA
1.409V    -23.74mA   -23.18mA   -24.27mA
1.818V    -27.88mA   -26.84mA   -28.57mA
2.045V    -28.84mA   -26.93mA   -29.9mA
2.318V    -27.3mA    -24.77mA   -28.71mA
2.636V    -23.65mA   -20.33mA   -24.98mA
3V        -17.54mA   -13.23mA   -19.24mA
[GND_clamp]
-1.5V     -219.3mA   -131.6mA   -364.3mA
-1.288V   -134.4mA   -79.74mA   -225.6mA
-1.258V   -122.9mA   -72.77mA   -206.3mA
-1.136V   -79.27mA   -46.88mA   -132.4mA
-1.045V   -51.5mA    -31.06mA   -84.11mA
-1.015V   -44.02mA   -26.9mA    -70.91mA
-954.5mV  -31.01mA   -19.7mA    -47.55mA
-863.6mV  -17.48mA   -12.16mA   -23.55mA
-803mV    -11.81mA   -8.597mA   -15.85mA
-681.8mV  -5.986mA   -4.096mA   -9.026mA
-378.8mV  -126.2uA   -131.8uA   -179.7uA
1.5V      1.424nA    36.56nA    1.506nA
[Ramp]
dV/dt_f 0.43445766/0.24635465n 0.41715146/0.32914125n  0.4537865/0.19128488n
dV/dt_r 0.43447857/0.24151591n 0.41105531/0.32041234n 0.45924901/0.18381137n
R_load = 50
[Rising Waveform]
R_fixture = 50
V_fixture = 1.5
V_fixture_min = 1.425
V_fixture_max = 1.575
0s        778.7mV    732.5mV    821mV
114.2ps   778.7mV    732.5mV    845.2mV
226.8ps   808.7mV    732.5mV    1.146V
348.4ps   1.054V     733mV      1.44V
466.2ps   1.299V     795.2mV    1.552V
590.2ps   1.428V     983.1mV    1.569V
752.6ps   1.486V     1.225V     1.574V
974.5ps   1.494V     1.368V     1.575V
1.297ns   1.496V     1.419V     1.575V
2.62ns    1.499V     1.422V     1.575V
[Rising Waveform]
R_fixture = 50
V_fixture = 0
V_fixture_min = 0
V_fixture_max = 0
0s        0V         0V         0V
118ps     0V         0V         0V
244.2ps   8.111mV    0V         269mV
389.9ps   268.5mV    0V         629.4mV
510.8ps   497.7mV    49.52mV    739.4mV
717.5ps   690.6mV    318mV      758.4mV
871ps     710.3mV    519.8mV    761.4mV
1.078ns   714.3mV    626.5mV    762.7mV
1.401ns   716.9mV    675.5mV    763.2mV
2.655ns   720.5mV    678.2mV    763.3mV
[Falling Waveform]
R_fixture = 50
V_fixture = 1.5
V_fixture_min = 1.425
V_fixture_max = 1.575
0s        1.499V     1.424V     1.574V
131ps     1.499V     1.424V     1.556V
246.1ps   1.481V     1.424V     1.315V
416.6ps   1.21V      1.424V     923mV
517ps     1.018V     1.363V     845.6mV
629.4ps   877.8mV    1.231V     829.9mV
734.3ps   808.8mV    1.086V     825.1mV
898ps     788.7mV    882.6mV    822.2mV
1.131ns   784.3mV    776.7mV    820.7mV
2.62ns    778.5mV    735mV      820mV
[Falling Waveform]
R_fixture = 50
V_fixture = 0
V_fixture_min = 0
V_fixture_max = 0
0s        720.5mV    681.1mV    762.3mV
118.9ps   720.5mV    681.1mV    733.4mV
214.2ps   705.5mV    681.1mV    491.3mV
362ps     421.6mV    681.1mV    138.1mV
479.7ps   206.3mV    588.1mV    21.77mV
623ps     64.02mV    395.5mV    5.762mV
802.2ps   10.01mV    159.5mV    0V
1.019ns   5.694mV    52.7mV     0V
1.376ns   3.581mV    4.767mV    0V
2.655ns   0V         2.831mV    0V
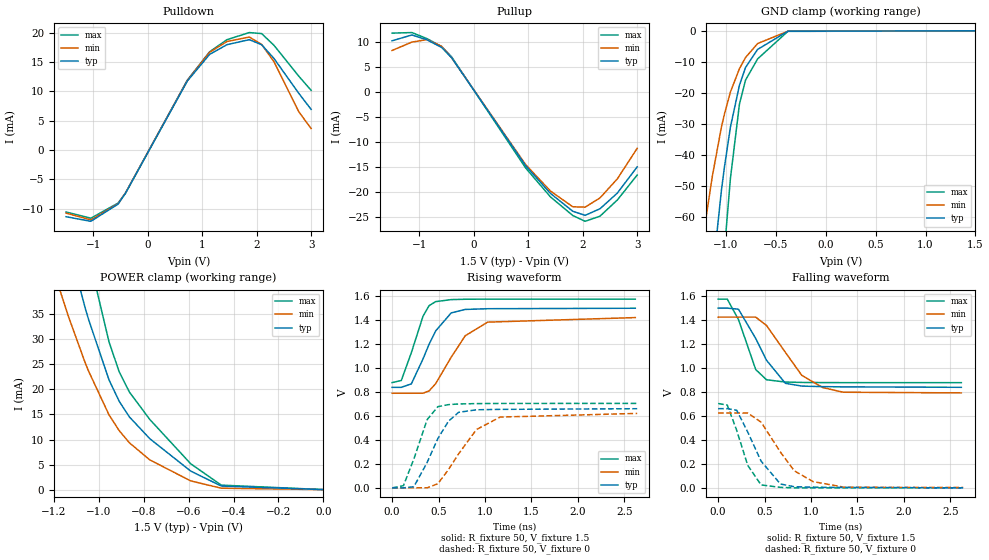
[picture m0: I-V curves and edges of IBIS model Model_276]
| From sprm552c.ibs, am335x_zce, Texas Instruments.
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| Model based on original model for BCSHTLTCSCDVPBFZ_SSDHV
|   Sub model SR10_6MA_5PER_1P5
[model]   Model_276
|[Description]  [1.5V-3-STATE-NOTERM-SR10:6MA, IND, 5%]
|   Fast slew rate (SR[1:0] = "10"), 1.33 * RExt = 0.750 * Iout
|   (I[2:0] = "001"), 6mA nominal with Rext = 50R,ODT off (ODT[1:0]
|   = "00") CMOS mode,Industrial temperature range (-40C to 125C,
|   25C nominal),5% power supply tolerance
|[Input Load]   NOTERM
|[Output Drive] SR10:6MA
|Voltage   1.5V
|Mode   3-STATE
Model_type   3-state
Polarity   Non-Inverting
Enable   Active-Low
Cref =  15pF
Rref =  100.0000M
Vref =  0V
Vmeas =  0.75
C_comp   1.865048p   1.679967p   1.989968p
[Temperature Range]   25   125   -40
[Voltage Range]   1.5   1.425   1.575
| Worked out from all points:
|   slope of the pulldown table from 0 to 0.225 V, typ, clamps not added: 56.6 ohm
|   slope of the pullup table from 0 to 0.225 V, typ, clamps not added: 60 ohm
|   GND clamp passes 1 mA (typ) near -0.49 V on its own axis
|   POWER clamp passes 1 mA (typ) near -0.47 V on its own axis
|   rising waveform, R_fixture 50, V_fixture 1.5: 20-80 % time 237ps typ, 315ps min, 172ps max; typ from 0.839 V to 1.5 V
|   rising waveform, R_fixture 50, V_fixture 0: 20-80 % time 251ps typ, 339ps min, 182ps max; typ from 0 V to 0.661 V
|   falling waveform, R_fixture 50, V_fixture 1.5: 20-80 % time 268ps typ, 358ps min, 186ps max; typ from 1.5 V to 0.839 V
|   falling waveform, R_fixture 50, V_fixture 0: 20-80 % time 256ps typ, 338ps min, 180ps max; typ from 0.661 V to 0 V
[POWER_clamp]
-1.5V     126mA      88.76mA    168.8mA
-1.242V   69.8mA     49.43mA    94.36mA
-1.136V   49.16mA    34.7mA     67.53mA
-1.061V   36.35mA    25.39mA    50.04mA
-1.045V   33.92mA    23.62mA    46.67mA
-954.5mV  21.93mA    14.94mA    29.52mA
-909.1mV  17.64mA    11.78mA    23.53mA
-863.6mV  14.51mA    9.346mA    19.48mA
-772.7mV  10.16mA    5.937mA    14mA
-590.9mV  3.705mA    1.741mA    5.168mA
-454.5mV  710.5uA    279.1uA    892.2uA
0V        1.424nA    14.75nA    2.169nA
[Pulldown]
-1.5V     -11.35mA   -10.74mA   -10.54mA
-1.045V   -12.13mA   -11.89mA   -11.6mA
-545.5mV  -9.204mA   -9.133mA   -9.027mA
-409.1mV  -7.34mA    -7.297mA   -7.323mA
727.3mV   11.79mA    11.87mA    11.94mA
1.136V    16.32mA    16.68mA    16.77mA
1.455V    17.98mA    18.52mA    18.83mA
1.864V    18.83mA    19.28mA    20.04mA
2.091V    17.97mA    18.02mA    19.87mA
2.318V    15.62mA    15.07mA    17.86mA
2.773V    9.688mA    6.547mA    12.61mA
3V        6.943mA    3.687mA    10.19mA
[Pullup]
-1.5V     10.19mA    8.251mA    11.72mA
-1.136V   11.35mA    9.924mA    11.83mA
-863.6mV  10.4mA     10.42mA    10.64mA
-590.9mV  8.854mA    9.085mA    9.032mA
-409.1mV  6.831mA    6.824mA    7.001mA
954.5mV   -14.83mA   -14.61mA   -15.28mA
1.409V    -20.35mA   -19.87mA   -21.04mA
1.818V    -23.9mA    -23.01mA   -24.76mA
2.045V    -24.72mA   -23.08mA   -25.91mA
2.318V    -23.4mA    -21.23mA   -24.88mA
2.636V    -20.27mA   -17.42mA   -21.65mA
3V        -15.03mA   -11.33mA   -16.67mA
[GND_clamp]
-1.5V     -219.3mA   -131.6mA   -364.3mA
-1.288V   -134.4mA   -79.74mA   -225.6mA
-1.258V   -122.9mA   -72.77mA   -206.3mA
-1.136V   -79.27mA   -46.88mA   -132.4mA
-1.045V   -51.5mA    -31.06mA   -84.11mA
-1.015V   -44.02mA   -26.9mA    -70.91mA
-954.5mV  -31.01mA   -19.7mA    -47.55mA
-863.6mV  -17.48mA   -12.16mA   -23.55mA
-803mV    -11.81mA   -8.597mA   -15.85mA
-681.8mV  -5.986mA   -4.096mA   -9.026mA
-378.8mV  -126.2uA   -131.8uA   -179.7uA
1.5V      1.424nA    36.56nA    1.506nA
[Ramp]
dV/dt_f  0.3982109/0.26986331n 0.38248694/0.36173489n 0.41902323/0.1861179n
dV/dt_r 0.39834005/0.25179488n 0.37638409/0.34246573n 0.42367301/0.18251467n
R_load = 50
[Rising Waveform]
R_fixture = 50
V_fixture = 1.5
V_fixture_min = 1.425
V_fixture_max = 1.575
0s        838.8mV    789.6mV    878.5mV
98.9ps    838.8mV    789.6mV    895.9mV
207.3ps   867.7mV    789.6mV    1.128V
332.9ps   1.076V     790mV      1.432V
397.7ps   1.197V     808.7mV    1.52V
468.7ps   1.309V     868.7mV    1.554V
636.4ps   1.46V      1.09V      1.571V
787.5ps   1.489V     1.269V     1.574V
1.029ns   1.495V     1.383V     1.575V
2.62ns    1.499V     1.421V     1.575V
[Rising Waveform]
R_fixture = 50
V_fixture = 0
V_fixture_min = 0
V_fixture_max = 0
0s        0V         0V         0V
122.4ps   0V         0V         18.37mV
234.6ps   9.653mV    0V         241.4mV
377.2ps   211.7mV    0V         568.9mV
492.3ps   410.8mV    34.44mV    677.3mV
607.2ps   556.1mV    152.5mV    694.7mV
716.3ps   630.5mV    283.6mV    699.9mV
907.9ps   651.4mV    486.3mV    703.2mV
1.164ns   655.1mV    590.7mV    704.4mV
2.64ns    660.5mV    621.1mV    704.7mV
[Falling Waveform]
R_fixture = 50
V_fixture = 1.5
V_fixture_min = 1.425
V_fixture_max = 1.575
0s        1.499V     1.424V     1.574V
98.5ps    1.499V     1.424V     1.574V
219.1ps   1.49V      1.424V     1.404V
404.8ps   1.246V     1.424V     986.9mV
521.4ps   1.064V     1.354V     901.5mV
724.7ps   871.8mV    1.13V      882.5mV
901.5ps   848.7mV    938.1mV    879.2mV
1.126ns   844.3mV    836.6mV    878mV
1.347ns   842.3mV    797.6mV    877.7mV
2.62ns    838.6mV    791.9mV    877.5mV
[Falling Waveform]
R_fixture = 50
V_fixture = 0
V_fixture_min = 0
V_fixture_max = 0
0s        660.5mV    624.2mV    703.7mV
98.5ps    660.5mV    624.2mV    690.4mV
199.8ps   647.2mV    624.2mV    480.4mV
318.9ps   465.6mV    624.2mV    187.9mV
462.6ps   222.9mV    548.1mV    24.48mV
671.1ps   32.34mV    298.7mV    4.115mV
820.5ps   9.374mV    142.1mV    0V
1.022ns   5.76mV     52.48mV    0V
1.359ns   3.718mV    5.144mV    0V
2.64ns    0V         3.22mV     0V
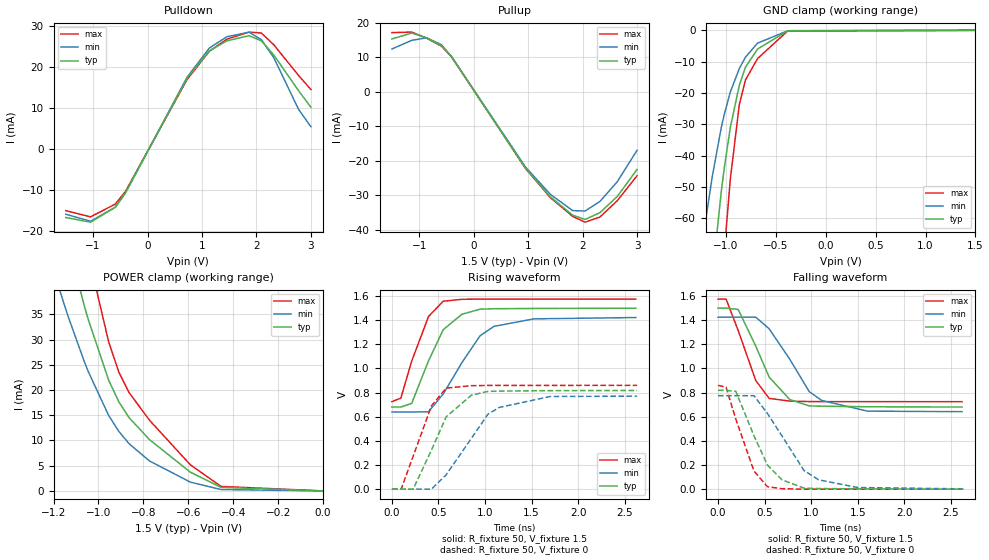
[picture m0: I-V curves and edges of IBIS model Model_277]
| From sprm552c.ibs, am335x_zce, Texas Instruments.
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| Model based on original model for BCSHTLTCSCDVPBFZ_SSDHV
|   Sub model SR11_9MA_5PER_1P5
[model]   Model_277
|[Description]  [1.5V-3-STATE-NOTERM-SR11:9MA, IND, 5%]
|   Slowest slew rate (SR[1:0] = "11"), 0.88 * RExt = 1.125 * Iout
|   (I[2:0] = "100"), 9mA nominal with Rext = 50R,ODT off (ODT[1:0]
|   = "00") CMOS mode,Industrial temperature range (-40C to 125C,
|   25C nominal),5% power supply tolerance
|[Input Load]   NOTERM
|[Output Drive] SR11:9MA
|Voltage   1.5V
|Mode   3-STATE
Model_type   3-state
Polarity   Non-Inverting
Enable   Active-Low
Cref =  15pF
Rref =  100.0000M
Vref =  0V
Vmeas =  0.75
C_comp   1.865048p   1.679967p   1.989968p
[Temperature Range]   25   125   -40
[Voltage Range]   1.5   1.425   1.575
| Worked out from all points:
|   slope of the pulldown table from 0 to 0.225 V, typ, clamps not added: 38.4 ohm
|   slope of the pullup table from 0 to 0.225 V, typ, clamps not added: 40.1 ohm
|   GND clamp passes 1 mA (typ) near -0.49 V on its own axis
|   POWER clamp passes 1 mA (typ) near -0.47 V on its own axis
|   rising waveform, R_fixture 50, V_fixture 1.5: 20-80 % time 277ps typ, 385ps min, 225ps max; typ from 0.68 V to 1.5 V
|   rising waveform, R_fixture 50, V_fixture 0: 20-80 % time 308ps typ, 388ps min, 241ps max; typ from 0 V to 0.818 V
|   falling waveform, R_fixture 50, V_fixture 1.5: 20-80 % time 306ps typ, 379ps min, 231ps max; typ from 1.5 V to 0.68 V
|   falling waveform, R_fixture 50, V_fixture 0: 20-80 % time 282ps typ, 381ps min, 224ps max; typ from 0.818 V to 0 V
[POWER_clamp]
-1.5V     126mA      88.76mA    168.8mA
-1.242V   69.8mA     49.43mA    94.36mA
-1.136V   49.16mA    34.7mA     67.53mA
-1.061V   36.35mA    25.39mA    50.04mA
-1.045V   33.92mA    23.62mA    46.67mA
-954.5mV  21.93mA    14.94mA    29.52mA
-909.1mV  17.64mA    11.78mA    23.53mA
-863.6mV  14.51mA    9.346mA    19.48mA
-772.7mV  10.16mA    5.937mA    14mA
-590.9mV  3.705mA    1.741mA    5.168mA
-454.5mV  710.5uA    279.1uA    892.2uA
0V        1.424nA    14.75nA    2.169nA
[Pulldown]
-1.5V     -16.73mA   -15.94mA   -15.06mA
-1.045V   -17.88mA   -17.65mA   -16.57mA
-590.9mV  -14.22mA   -14.22mA   -13.46mA
-409.1mV  -10.81mA   -10.82mA   -10.45mA
727.3mV   17.36mA    17.6mA     17.04mA
1.136V    24.04mA    24.73mA    23.94mA
1.455V    26.49mA    27.48mA    26.9mA
1.864V    27.75mA    28.61mA    28.63mA
2.091V    26.49mA    26.76mA    28.4mA
2.318V    23.02mA    22.38mA    25.53mA
2.773V    14.29mA    9.722mA    18.02mA
3V        10.24mA    5.474mA    14.57mA
[Pullup]
-1.5V     15.3mA     12.38mA    17.14mA
-1.136V   17.02mA    14.89mA    17.29mA
-863.6mV  15.6mA     15.63mA    15.55mA
-590.9mV  13.28mA    13.62mA    13.2mA
-409.1mV  10.24mA    10.23mA    10.22mA
954.5mV   -22.23mA   -21.9mA    -22.32mA
1.409V    -30.51mA   -29.79mA   -30.74mA
1.818V    -35.84mA   -34.51mA   -36.18mA
2.045V    -37.08mA   -34.63mA   -37.87mA
2.318V    -35.11mA   -31.86mA   -36.38mA
2.636V    -30.42mA   -26.15mA   -31.65mA
3V        -22.57mA   -17.01mA   -24.39mA
[GND_clamp]
-1.5V     -219.3mA   -131.6mA   -364.3mA
-1.288V   -134.4mA   -79.74mA   -225.6mA
-1.258V   -122.9mA   -72.77mA   -206.3mA
-1.136V   -79.27mA   -46.88mA   -132.4mA
-1.045V   -51.5mA    -31.06mA   -84.11mA
-1.015V   -44.02mA   -26.9mA    -70.91mA
-954.5mV  -31.01mA   -19.7mA    -47.55mA
-863.6mV  -17.48mA   -12.16mA   -23.55mA
-803mV    -11.81mA   -8.597mA   -15.85mA
-681.8mV  -5.986mA   -4.096mA   -9.026mA
-378.8mV  -126.2uA   -131.8uA   -179.7uA
1.5V      1.424nA    36.56nA    1.506nA
[Ramp]
dV/dt_f 0.49433585/0.307482n  0.47381069/0.38100069n 0.51176209/0.23146953n
dV/dt_r 0.49395031/0.30973124n 0.46754254/0.39229807n 0.51780796/0.24177089n
R_load = 50
[Rising Waveform]
R_fixture = 50
V_fixture = 1.5
V_fixture_min = 1.425
V_fixture_max = 1.575
0s        680.3mV    639.4mV    725.3mV
95.9ps    680.3mV    639.4mV    754mV
212.6ps   710.9mV    639.4mV    1.061V
392.8ps   1.062V     641.1mV    1.43V
550.7ps   1.321V     788.6mV    1.557V
751.6ps   1.449V     1.048V     1.573V
946.9ps   1.491V     1.271V     1.575V
1.097ns   1.495V     1.349V     1.575V
1.525ns   1.497V     1.411V     1.575V
2.62ns    1.499V     1.422V     1.575V
[Rising Waveform]
R_fixture = 50
V_fixture = 0
V_fixture_min = 0
V_fixture_max = 0
0s        0V         0V         0V
99.2ps    0V         0V         0V
227.9ps   0V         0V         272.3mV
424.4ps   323.1mV    0V         689.8mV
582.9ps   599.3mV    119.3mV    837.3mV
852.7ps   778.2mV    420mV      857.4mV
1.032ns   810mV      621.9mV    859.4mV
1.153ns   812.4mV    677.1mV    859.8mV
1.7ns     816.3mV    767.8mV    859.6mV
2.633ns   817.6mV    770.6mV    860.2mV
[Falling Waveform]
R_fixture = 50
V_fixture = 1.5
V_fixture_min = 1.425
V_fixture_max = 1.575
0s        1.499V     1.424V     1.574V
86.7ps    1.499V     1.424V     1.574V
216.3ps   1.488V     1.424V     1.314V
405.4ps   1.184V     1.424V     899.5mV
548.8ps   928mV      1.328V     751.5mV
771.3ps   741.5mV    1.075V     729mV
980.2ps   689.7mV    807.1mV    725.4mV
1.115ns   686.8mV    734mV      724.9mV
1.605ns   682.3mV    646.1mV    724.6mV
2.62ns    680.1mV    641.6mV    724.3mV
[Falling Waveform]
R_fixture = 50
V_fixture = 0
V_fixture_min = 0
V_fixture_max = 0
0s        818.4mV    773.9mV    859.3mV
85.8ps    818.4mV    773.9mV    844.8mV
191.3ps   809.6mV    773.9mV    579.2mV
385.6ps   442.8mV    773.9mV    151mV
530.6ps   199.7mV    627.2mV    19.9mV
686ps     78.13mV    441.3mV    4.057mV
923ps     8.352mV    154.6mV    0V
1.08ns    5.23mV     77.72mV    0V
1.499ns   2.985mV    13.68mV    0V
2.633ns   0V         2.561mV    0V
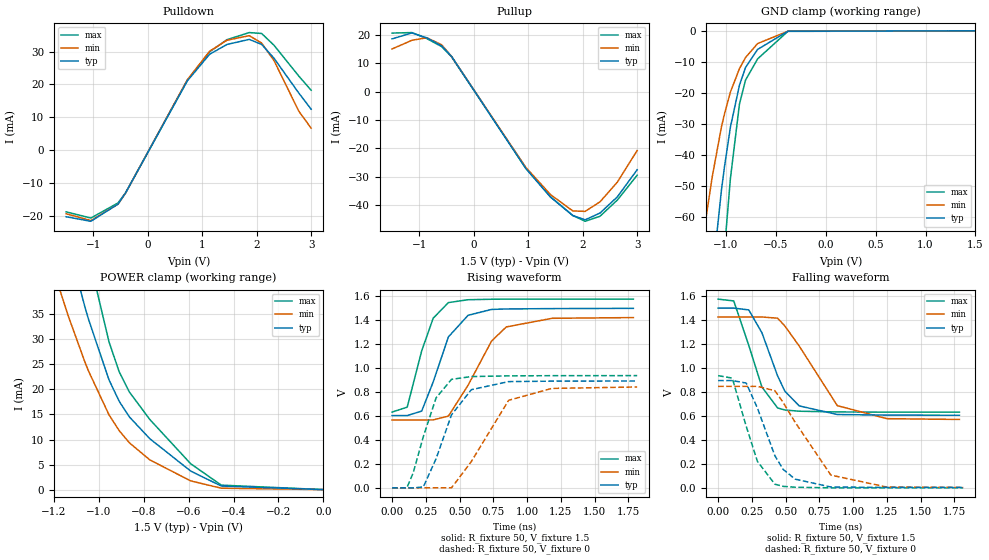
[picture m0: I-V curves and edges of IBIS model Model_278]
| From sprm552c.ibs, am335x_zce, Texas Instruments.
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| Model based on original model for BCSHTLTCSCDVPBFZ_SSDHV
|   Sub model SR10_11MA_5PER_1P5
[model]   Model_278
|[Description]  [1.5V-3-STATE-NOTERM-SR10:11MA, IND, 5%]
|   Fast slew rate (SR[1:0] = "10"), 0.73 * RExt = 1.325 * Iout
|   (I[2:0] = "110"), 11mA nominal with Rext = 50R,ODT off (ODT[1:0]
|   = "00") CMOS mode,Industrial temperature range (-40C to 125C,
|   25C nominal),5% power supply tolerance
|[Input Load]   NOTERM
|[Output Drive] SR10:11MA
|Voltage   1.5V
|Mode   3-STATE
Model_type   3-state
Polarity   Non-Inverting
Enable   Active-Low
Cref =  15pF
Rref =  100.0000M
Vref =  0V
Vmeas =  0.75
C_comp   1.865048p   1.679967p   1.989968p
[Temperature Range]   25   125   -40
[Voltage Range]   1.5   1.425   1.575
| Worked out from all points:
|   slope of the pulldown table from 0 to 0.225 V, typ, clamps not added: 31.7 ohm
|   slope of the pullup table from 0 to 0.225 V, typ, clamps not added: 32.8 ohm
|   GND clamp passes 1 mA (typ) near -0.49 V on its own axis
|   POWER clamp passes 1 mA (typ) near -0.47 V on its own axis
|   rising waveform, R_fixture 50, V_fixture 1.5: 20-80 % time 170ps typ, 249ps min, 141ps max; typ from 0.603 V to 1.5 V
|   rising waveform, R_fixture 50, V_fixture 0: 20-80 % time 185ps typ, 254ps min, 153ps max; typ from 0 V to 0.892 V
|   falling waveform, R_fixture 50, V_fixture 1.5: 20-80 % time 197ps typ, 271ps min, 155ps max; typ from 1.5 V to 0.606 V
|   falling waveform, R_fixture 50, V_fixture 0: 20-80 % time 187ps typ, 277ps min, 153ps max; typ from 0.895 V to 0.004 V
[POWER_clamp]
-1.5V     126mA      88.76mA    168.8mA
-1.242V   69.8mA     49.43mA    94.36mA
-1.136V   49.16mA    34.7mA     67.53mA
-1.061V   36.35mA    25.39mA    50.04mA
-1.045V   33.92mA    23.62mA    46.67mA
-954.5mV  21.93mA    14.94mA    29.52mA
-909.1mV  17.64mA    11.78mA    23.53mA
-863.6mV  14.51mA    9.346mA    19.48mA
-772.7mV  10.16mA    5.937mA    14mA
-590.9mV  3.705mA    1.741mA    5.168mA
-454.5mV  710.5uA    279.1uA    892.2uA
0V        1.424nA    14.75nA    2.169nA
[Pulldown]
-1.5V     -20.32mA   -19.41mA   -18.83mA
-1.045V   -21.71mA   -21.48mA   -20.72mA
-545.5mV  -16.46mA   -16.48mA   -16.11mA
-409.1mV  -13.12mA   -13.16mA   -13.06mA
727.3mV   21.07mA    21.41mA    21.29mA
1.136V    29.18mA    30.1mA     29.92mA
1.455V    32.16mA    33.45mA    33.62mA
1.864V    33.7mA     34.83mA    35.78mA
2.091V    32.17mA    32.59mA    35.5mA
2.318V    27.97mA    27.26mA    31.92mA
2.773V    17.36mA    11.84mA    22.54mA
3V        12.44mA    6.666mA    18.22mA
[Pullup]
-1.5V     18.7mA     15.13mA    20.75mA
-1.136V   20.8mA     18.2mA     20.93mA
-863.6mV  19.07mA    19.1mA     18.82mA
-590.9mV  16.22mA    16.64mA    15.97mA
-409.1mV  12.51mA    12.49mA    12.37mA
954.5mV   -27.15mA   -26.75mA   -27.01mA
1.409V    -37.28mA   -36.4mA    -37.19mA
1.818V    -43.8mA    -42.17mA   -43.78mA
2.045V    -45.32mA   -42.33mA   -45.84mA
2.318V    -42.92mA   -38.95mA   -44.05mA
2.636V    -37.2mA    -31.98mA   -38.33mA
3V        -27.6mA    -20.81mA   -29.54mA
[GND_clamp]
-1.5V     -219.3mA   -131.6mA   -364.3mA
-1.288V   -134.4mA   -79.74mA   -225.6mA
-1.258V   -122.9mA   -72.77mA   -206.3mA
-1.136V   -79.27mA   -46.88mA   -132.4mA
-1.045V   -51.5mA    -31.06mA   -84.11mA
-1.015V   -44.02mA   -26.9mA    -70.91mA
-954.5mV  -31.01mA   -19.7mA    -47.55mA
-863.6mV  -17.48mA   -12.16mA   -23.55mA
-803mV    -11.81mA   -8.597mA   -15.85mA
-681.8mV  -5.986mA   -4.096mA   -9.026mA
-378.8mV  -126.2uA   -131.8uA   -179.7uA
1.5V      1.424nA    36.56nA    1.506nA
[Ramp]
dV/dt_f 0.54019537/0.19835187n 0.51710806/0.27160528n 0.56754992/0.15467831n
dV/dt_r 0.53992277/0.18713271n 0.51130485/0.2572712n 0.56411555/0.15299972n
R_load = 50
[Rising Waveform]
R_fixture = 50
V_fixture = 1.5
V_fixture_min = 1.425
V_fixture_max = 1.575
0s        603.4mV    566.9mV    632.3mV
111.9ps   603.4mV    566.9mV    673.7mV
219.1ps   640.7mV    566.9mV    1.143V
304.4ps   883.9mV    567.2mV    1.416V
417.1ps   1.26V      598.7mV    1.546V
562.9ps   1.44V      856.9mV    1.57V
736.5ps   1.489V     1.225V     1.574V
845.7ps   1.493V     1.343V     1.575V
1.185ns   1.496V     1.415V     1.575V
1.787ns   1.498V     1.421V     1.575V
[Rising Waveform]
R_fixture = 50
V_fixture = 0
V_fixture_min = 0
V_fixture_max = 0
0s        0V         0V         0V
109.1ps   0V         0V         0V
156ps     0V         0V         124.6mV
231.2ps   7.613mV    0V         427.3mV
325.9ps   243.7mV    0V         751.1mV
439.7ps   608.9mV    0V         905.4mV
586.5ps   819.2mV    219.5mV    928.7mV
862.8ps   886.7mV    730.5mV    934.7mV
1.183ns   890.5mV    829.9mV    936.2mV
1.815ns   891.7mV    841.9mV    936.8mV
[Falling Waveform]
R_fixture = 50
V_fixture = 1.5
V_fixture_min = 1.425
V_fixture_max = 1.575
0s        1.499V     1.425V     1.574V
115.8ps   1.499V     1.425V     1.559V
227ps     1.484V     1.425V     1.188V
324.1ps   1.294V     1.425V     841.5mV
440.4ps   933.9mV    1.415V     666.6mV
495ps     804.9mV    1.349V     649.4mV
601ps     683.4mV    1.182V     639.1mV
882.8ps   611.7mV    685.5mV    633.1mV
1.25ns    606.7mV    577mV      631.5mV
1.787ns   605.6mV    570.5mV    631.3mV
[Falling Waveform]
R_fixture = 50
V_fixture = 0
V_fixture_min = 0
V_fixture_max = 0
0s        894.9mV    846.5mV    935.9mV
104.9ps   894.9mV    846.5mV    915.3mV
208.3ps   873.9mV    846.5mV    512.3mV
291.1ps   664.9mV    846.5mV    220.8mV
420.1ps   268.3mV    810.4mV    30.51mV
481.2ps   154.5mV    712.8mV    12.56mV
570ps     72.72mV    547.4mV    5.404mV
835.2ps   6.94mV     106.2mV    0V
1.249ns   3.919mV    6.796mV    0V
1.815ns   3.919mV    3.666mV    0V
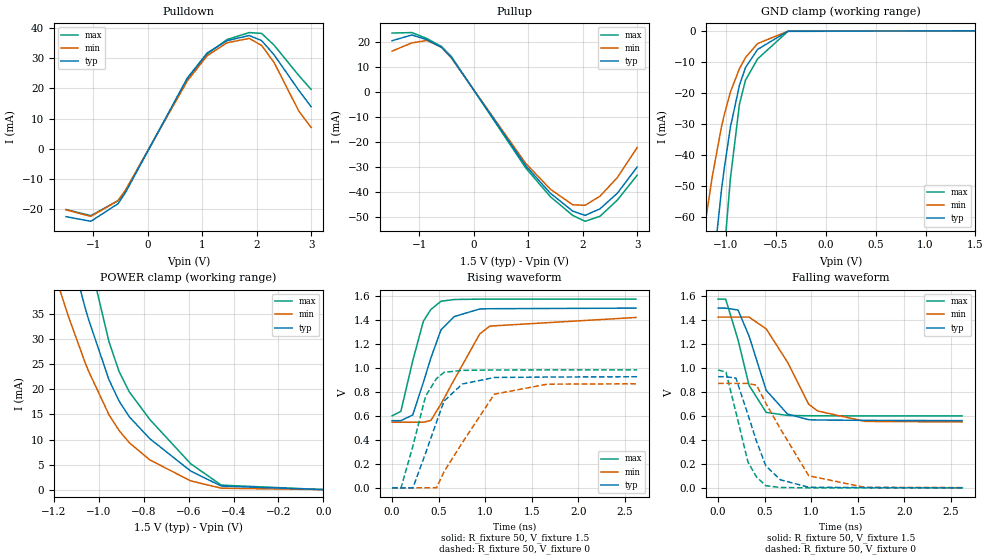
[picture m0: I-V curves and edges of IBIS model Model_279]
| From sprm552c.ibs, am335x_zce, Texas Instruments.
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| Model based on original model for BCSHTLTCSCDVPBFZ_SSDHV
|   Sub model SR11_12MA_5PER_1P5
[model]   Model_279
|[Description]  [1.5V-3-STATE-NOTERM-SR11:12MA, IND, 5%]
|   Slowest slew rate (SR[1:0] = "11"), 0.67 * RExt = 1.500 * Iout
|   (I[2:0] = "111"), 12mA nominal with Rext = 50R,ODT off (ODT[1:0]
|   = "00") CMOS mode,Industrial temperature range (-40C to 125C,
|   25C nominal),5% power supply tolerance
|[Input Load]   NOTERM
|[Output Drive] SR11:12MA
|Voltage   1.5V
|Mode   3-STATE
Model_type   3-state
Polarity   Non-Inverting
Enable   Active-Low
Cref =  15pF
Rref =  100.0000M
Vref =  0V
Vmeas =  0.75
C_comp   1.865048p   1.679967p   1.989968p
[Temperature Range]   25   125   -40
[Voltage Range]   1.5   1.425   1.575
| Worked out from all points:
|   slope of the pulldown table from 0 to 0.225 V, typ, clamps not added: 28.3 ohm
|   slope of the pullup table from 0 to 0.225 V, typ, clamps not added: 30.1 ohm
|   GND clamp passes 1 mA (typ) near -0.49 V on its own axis
|   POWER clamp passes 1 mA (typ) near -0.47 V on its own axis
|   rising waveform, R_fixture 50, V_fixture 1.5: 20-80 % time 238ps typ, 375ps min, 183ps max; typ from 0.561 V to 1.5 V
|   rising waveform, R_fixture 50, V_fixture 0: 20-80 % time 250ps typ, 383ps min, 199ps max; typ from 0 V to 0.927 V
|   falling waveform, R_fixture 50, V_fixture 1.5: 20-80 % time 245ps typ, 360ps min, 200ps max; typ from 1.5 V to 0.561 V
|   falling waveform, R_fixture 50, V_fixture 0: 20-80 % time 235ps typ, 388ps min, 187ps max; typ from 0.927 V to 0 V
[POWER_clamp]
-1.5V     126mA      88.76mA    168.8mA
-1.242V   69.8mA     49.43mA    94.36mA
-1.136V   49.16mA    34.7mA     67.53mA
-1.061V   36.35mA    25.39mA    50.04mA
-1.045V   33.92mA    23.62mA    46.67mA
-954.5mV  21.93mA    14.94mA    29.52mA
-909.1mV  17.64mA    11.78mA    23.53mA
-863.6mV  14.51mA    9.346mA    19.48mA
-772.7mV  10.16mA    5.937mA    14mA
-590.9mV  3.705mA    1.741mA    5.168mA
-454.5mV  710.5uA    279.1uA    892.2uA
0V        1.424nA    14.75nA    2.169nA
[Pulldown]
-1.5V     -22.72mA   -20.45mA   -20.34mA
-1.045V   -24.26mA   -22.63mA   -22.37mA
-545.5mV  -18.39mA   -17.36mA   -17.39mA
-409.1mV  -14.66mA   -13.87mA   -14.1mA
727.3mV   23.54mA    22.55mA    22.99mA
1.091V    31.85mA    30.92mA    31.48mA
1.455V    35.94mA    35.24mA    36.31mA
1.864V    37.66mA    36.7mA     38.64mA
2.091V    35.96mA    34.34mA    38.35mA
2.318V    31.27mA    28.72mA    34.48mA
2.773V    19.4mA     12.48mA    24.34mA
3V        13.9mA     7.024mA    19.68mA
[Pullup]
-1.5V     20.4mA     16.24mA    23.46mA
-1.136V   22.69mA    19.53mA    23.65mA
-863.6mV  20.8mA     20.49mA    21.28mA
-590.9mV  17.69mA    17.85mA    18.05mA
-409.1mV  13.64mA    13.4mA     13.98mA
954.5mV   -29.62mA   -28.69mA   -30.52mA
1.409V    -40.66mA   -39.04mA   -42.03mA
1.818V    -47.77mA   -45.23mA   -49.49mA
2.045V    -49.44mA   -45.41mA   -51.82mA
2.318V    -46.83mA   -41.78mA   -49.8mA
2.636V    -40.59mA   -34.31mA   -43.34mA
3V        -30.12mA   -22.33mA   -33.4mA
[GND_clamp]
-1.5V     -219.3mA   -131.6mA   -364.3mA
-1.288V   -134.4mA   -79.74mA   -225.6mA
-1.258V   -122.9mA   -72.77mA   -206.3mA
-1.136V   -79.27mA   -46.88mA   -132.4mA
-1.045V   -51.5mA    -31.06mA   -84.11mA
-1.015V   -44.02mA   -26.9mA    -70.91mA
-954.5mV  -31.01mA   -19.7mA    -47.55mA
-863.6mV  -17.48mA   -12.16mA   -23.55mA
-803mV    -11.81mA   -8.597mA   -15.85mA
-681.8mV  -5.986mA   -4.096mA   -9.026mA
-378.8mV  -126.2uA   -131.8uA   -179.7uA
1.5V      1.424nA    36.56nA    1.506nA
[Ramp]
dV/dt_f 0.56646521/0.2464644n 0.52949152/0.3614563n 0.58652301/0.20224947n
dV/dt_r 0.55976653/0.2505666n 0.52736917/0.39284703n 0.59288498/0.19892362n
R_load = 50
[Rising Waveform]
R_fixture = 50
V_fixture = 1.5
V_fixture_min = 1.425
V_fixture_max = 1.575
0s        560.9mV    548.2mV    601.3mV
94.2ps    560.9mV    548.2mV    638.5mV
221ps     607.6mV    548.2mV    1.059V
336ps     880.7mV    548.2mV    1.391V
415.7ps   1.082V     561.8mV    1.488V
524.6ps   1.318V     699.7mV    1.557V
669ps     1.43V      905.4mV    1.572V
941.7ps   1.493V     1.285V     1.575V
1.049ns   1.495V     1.35V      1.575V
2.62ns    1.5V       1.422V     1.575V
[Rising Waveform]
R_fixture = 50
V_fixture = 0
V_fixture_min = 0
V_fixture_max = 0
0s        0V         0V         0V
95.9ps    0V         0V         0V
223.2ps   0V         0V         349mV
359.8ps   290mV      0V         765.5mV
476.7ps   548.6mV    0V         912mV
558ps     723.9mV    135.6mV    963.9mV
753.6ps   866.6mV    376.4mV    980.5mV
1.098ns   921.3mV    781.7mV    983.7mV
1.667ns   924.8mV    865.4mV    984.4mV
2.632ns   927.2mV    868.5mV    984.4mV
[Falling Waveform]
R_fixture = 50
V_fixture = 1.5
V_fixture_min = 1.425
V_fixture_max = 1.575
0s        1.499V     1.424V     1.574V
80.9ps    1.499V     1.424V     1.574V
214ps     1.483V     1.424V     1.234V
332.2ps   1.266V     1.424V     855.1mV
516.1ps   813.8mV    1.326V     629.4mV
744.6ps   616mV      1.049V     603.9mV
973.2ps   568mV      697.3mV    601.5mV
1.071ns   566mV      640.6mV    600.9mV
1.58ns    562.9mV    554.2mV    600.3mV
2.62ns    560.6mV    549.8mV    600.3mV
[Falling Waveform]
R_fixture = 50
V_fixture = 0
V_fixture_min = 0
V_fixture_max = 0
0s        927mV      871.3mV    983.4mV
84ps      927mV      871.3mV    965.6mV
191.2ps   915.2mV    871.3mV    629.7mV
320.6ps   609.7mV    871.3mV    214.5mV
412.3ps   388.7mV    855.9mV    90.64mV
512.8ps   183mV      705.6mV    17.75mV
669.2ps   66.8mV     491.3mV    3.231mV
973.2ps   5.345mV    100.9mV    0V
1.575ns   2.27mV     4.329mV    0V
2.632ns   0V         2.332mV    0V
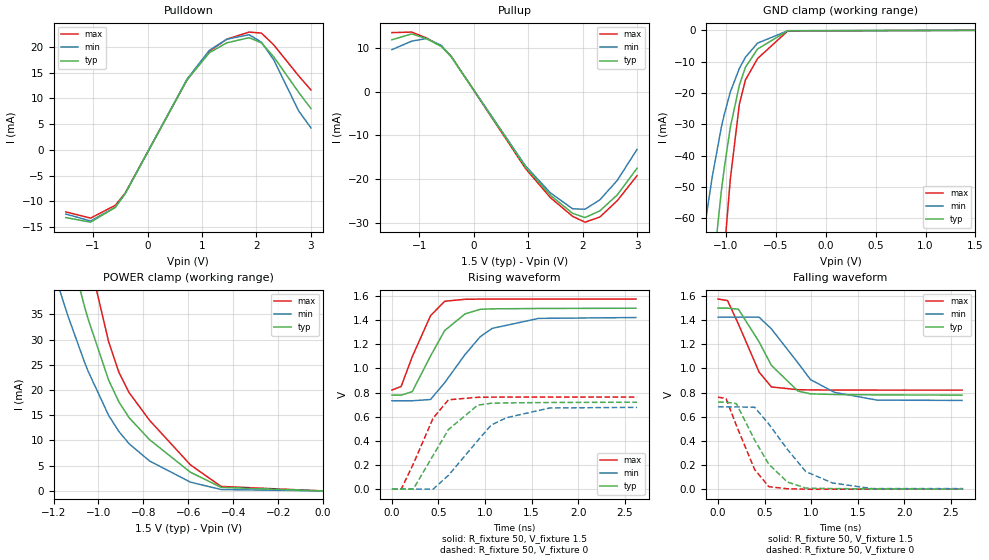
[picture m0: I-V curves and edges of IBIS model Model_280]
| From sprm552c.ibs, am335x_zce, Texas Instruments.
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| Model based on original model for BCSHTLTCSCDVPBFZ_SSDHV
|   Sub model SR11_7MA_5PER_1P5
[model]   Model_280
|[Description]  [1.5V-3-STATE-NOTERM-SR11:7MA, IND, 5%]
|   Slowest slew rate (SR[1:0] = "11"), 1.14 * RExt = 0.875 * Iout
|   (I[2:0] = "010"), 7mA nominal with Rext = 50R,ODT off (ODT[1:0]
|   = "00") CMOS mode,Industrial temperature range (-40C to 125C,
|   25C nominal),5% power supply tolerance
|[Input Load]   NOTERM
|[Output Drive] SR11:7MA
|Voltage   1.5V
|Mode   3-STATE
Model_type   3-state
Polarity   Non-Inverting
Enable   Active-Low
Cref =  15pF
Rref =  100.0000M
Vref =  0V
Vmeas =  0.75
C_comp   1.865048p   1.679967p   1.989968p
[Temperature Range]   25   125   -40
[Voltage Range]   1.5   1.425   1.575
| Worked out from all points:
|   slope of the pulldown table from 0 to 0.225 V, typ, clamps not added: 48.9 ohm
|   slope of the pullup table from 0 to 0.225 V, typ, clamps not added: 51.5 ohm
|   GND clamp passes 1 mA (typ) near -0.49 V on its own axis
|   POWER clamp passes 1 mA (typ) near -0.47 V on its own axis
|   rising waveform, R_fixture 50, V_fixture 1.5: 20-80 % time 317ps typ, 425ps min, 247ps max; typ from 0.779 V to 1.5 V
|   rising waveform, R_fixture 50, V_fixture 0: 20-80 % time 353ps typ, 451ps min, 264ps max; typ from 0 V to 0.72 V
|   falling waveform, R_fixture 50, V_fixture 1.5: 20-80 % time 330ps typ, 438ps min, 252ps max; typ from 1.5 V to 0.779 V
|   falling waveform, R_fixture 50, V_fixture 0: 20-80 % time 324ps typ, 416ps min, 245ps max; typ from 0.72 V to 0 V
[POWER_clamp]
-1.5V     126mA      88.76mA    168.8mA
-1.242V   69.8mA     49.43mA    94.36mA
-1.136V   49.16mA    34.7mA     67.53mA
-1.061V   36.35mA    25.39mA    50.04mA
-1.045V   33.92mA    23.62mA    46.67mA
-954.5mV  21.93mA    14.94mA    29.52mA
-909.1mV  17.64mA    11.78mA    23.53mA
-863.6mV  14.51mA    9.346mA    19.48mA
-772.7mV  10.16mA    5.937mA    14mA
-590.9mV  3.705mA    1.741mA    5.168mA
-454.5mV  710.5uA    279.1uA    892.2uA
0V        1.424nA    14.75nA    2.169nA
[Pulldown]
-1.5V     -13.15mA   -12.47mA   -12.05mA
-1.045V   -14.05mA   -13.81mA   -13.26mA
-590.9mV  -11.18mA   -11.13mA   -10.77mA
-409.1mV  -8.496mA   -8.472mA   -8.367mA
727.3mV   13.64mA    13.78mA    13.64mA
1.136V    18.89mA    19.36mA    19.16mA
1.455V    20.81mA    21.51mA    21.52mA
1.864V    21.81mA    22.39mA    22.9mA
2.091V    20.81mA    20.94mA    22.71mA
2.318V    18.08mA    17.5mA     20.41mA
2.773V    11.22mA    7.604mA    14.41mA
3V        8.041mA    4.283mA    11.65mA
[Pullup]
-1.5V     11.89mA    9.627mA    13.53mA
-1.136V   13.24mA    11.58mA    13.65mA
-863.6mV  12.14mA    12.16mA    12.28mA
-590.9mV  10.33mA    10.6mA     10.42mA
-409.1mV  7.967mA    7.959mA    8.076mA
954.5mV   -17.3mA    -17.04mA   -17.63mA
1.409V    -23.74mA   -23.18mA   -24.27mA
1.818V    -27.88mA   -26.84mA   -28.57mA
2.045V    -28.84mA   -26.93mA   -29.9mA
2.318V    -27.3mA    -24.77mA   -28.71mA
2.636V    -23.65mA   -20.33mA   -24.98mA
3V        -17.54mA   -13.23mA   -19.24mA
[GND_clamp]
-1.5V     -219.3mA   -131.6mA   -364.3mA
-1.288V   -134.4mA   -79.74mA   -225.6mA
-1.258V   -122.9mA   -72.77mA   -206.3mA
-1.136V   -79.27mA   -46.88mA   -132.4mA
-1.045V   -51.5mA    -31.06mA   -84.11mA
-1.015V   -44.02mA   -26.9mA    -70.91mA
-954.5mV  -31.01mA   -19.7mA    -47.55mA
-863.6mV  -17.48mA   -12.16mA   -23.55mA
-803mV    -11.81mA   -8.597mA   -15.85mA
-681.8mV  -5.986mA   -4.096mA   -9.026mA
-378.8mV  -126.2uA   -131.8uA   -179.7uA
1.5V      1.424nA    36.56nA    1.506nA
[Ramp]
dV/dt_f 0.43467898/0.33190558n 0.41742748/0.44152757n  0.4539743/0.25238145n
dV/dt_r 0.43449339/0.35495972n 0.41103221/0.45255374n 0.45927225/0.2652286n
R_load = 50
[Rising Waveform]
R_fixture = 50
V_fixture = 1.5
V_fixture_min = 1.425
V_fixture_max = 1.575
0s        778.7mV    732.5mV    821mV
99.1ps    778.7mV    732.5mV    850.8mV
218.2ps   807.9mV    732.5mV    1.097V
414.6ps   1.103V     742.7mV    1.437V
566.5ps   1.314V     882.1mV    1.557V
784.8ps   1.452V     1.115V     1.573V
948.1ps   1.49V      1.263V     1.575V
1.076ns   1.494V     1.332V     1.575V
1.576ns   1.497V     1.415V     1.575V
2.62ns    1.499V     1.422V     1.575V
[Rising Waveform]
R_fixture = 50
V_fixture = 0
V_fixture_min = 0
V_fixture_max = 0
0s        0V         0V         0V
100ps     0V         0V         0V
229ps     0V         0V         207.8mV
441.8ps   278.9mV    0V         587.5mV
606.2ps   493mV      113.7mV    740.3mV
920.4ps   695.6mV    401.8mV    761.2mV
1.066ns   711.9mV    531.2mV    762.4mV
1.229ns   714.8mV    591.6mV    762.9mV
1.694ns   718mV      672.6mV    763.3mV
2.632ns   720.4mV    677.8mV    763.3mV
[Falling Waveform]
R_fixture = 50
V_fixture = 1.5
V_fixture_min = 1.425
V_fixture_max = 1.575
0s        1.499V     1.424V     1.574V
101.7ps   1.499V     1.424V     1.562V
218.9ps   1.49V      1.424V     1.367V
440.4ps   1.22V      1.424V     970mV
572.9ps   1.025V     1.327V     846.5mV
857.7ps   812.5mV    1.046V     823.4mV
993.1ps   789.2mV    907mV      821.8mV
1.251ns   783.8mV    801.2mV    820.5mV
1.706ns   780.8mV    737.4mV    820.1mV
2.62ns    778.6mV    734.9mV    820mV
[Falling Waveform]
R_fixture = 50
V_fixture = 0
V_fixture_min = 0
V_fixture_max = 0
0s        720.5mV    681.1mV    762.4mV
85.7ps    720.5mV    681.1mV    750mV
196.5ps   708.3mV    681.1mV    528.3mV
392.7ps   406.9mV    678.3mV    163mV
545.1ps   206.2mV    539.4mV    20.57mV
745.8ps   58.75mV    328mV      3.392mV
942.5ps   8.9mV      145.3mV    0V
1.229ns   4.598mV    51.06mV    0V
1.66ns    2.705mV    4.41mV     0V
2.632ns   0V         4.41mV     0V
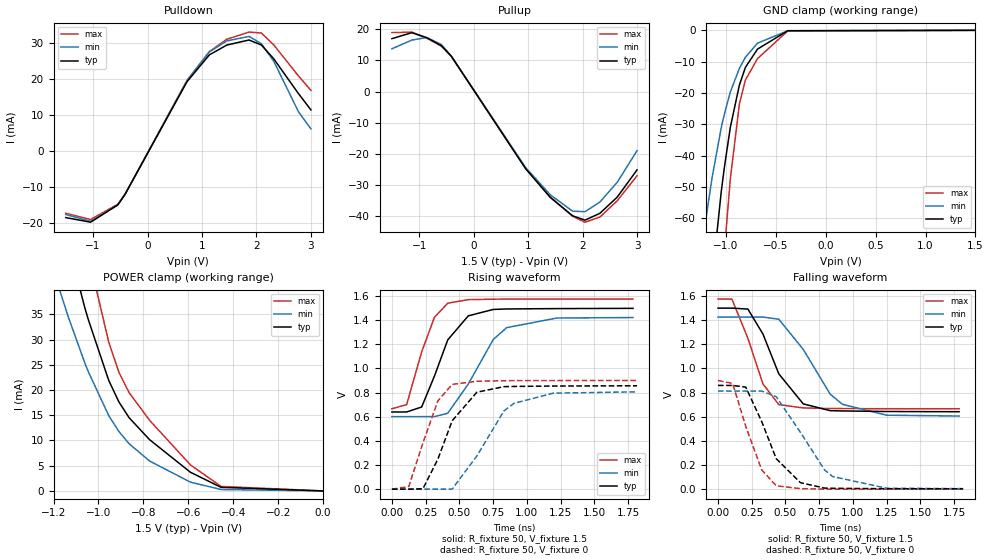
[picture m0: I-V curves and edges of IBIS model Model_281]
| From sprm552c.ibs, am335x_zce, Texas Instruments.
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| Model based on original model for BCSHTLTCSCDVPBFZ_SSDHV
|   Sub model SR10_10MA_5PER_1P5
[model]   Model_281
|[Description]  [1.5V-3-STATE-NOTERM-SR10:10MA, IND, 5%]
|   Fast slew rate (SR[1:0] = "10"), 0.80 * RExt = 1.250 * Iout
|   (I[2:0] = "101"), 10mA nominal with Rext = 50R,ODT off (ODT[1:0]
|   = "00") CMOS mode,Industrial temperature range (-40C to 125C,
|   25C nominal),5% power supply tolerance
|[Input Load]   NOTERM
|[Output Drive] SR10:10MA
|Voltage   1.5V
|Mode   3-STATE
Model_type   3-state
Polarity   Non-Inverting
Enable   Active-Low
Cref =  15pF
Rref =  100.0000M
Vref =  0V
Vmeas =  0.75
C_comp   1.865048p   1.679967p   1.989968p
[Temperature Range]   25   125   -40
[Voltage Range]   1.5   1.425   1.575
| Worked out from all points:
|   slope of the pulldown table from 0 to 0.225 V, typ, clamps not added: 34.7 ohm
|   slope of the pullup table from 0 to 0.225 V, typ, clamps not added: 36.1 ohm
|   GND clamp passes 1 mA (typ) near -0.49 V on its own axis
|   POWER clamp passes 1 mA (typ) near -0.47 V on its own axis
|   rising waveform, R_fixture 50, V_fixture 1.5: 20-80 % time 182ps typ, 257ps min, 147ps max; typ from 0.64 V to 1.5 V
|   rising waveform, R_fixture 50, V_fixture 0: 20-80 % time 196ps typ, 257ps min, 157ps max; typ from 0 V to 0.856 V
|   falling waveform, R_fixture 50, V_fixture 1.5: 20-80 % time 213ps typ, 281ps min, 162ps max; typ from 1.5 V to 0.641 V
|   falling waveform, R_fixture 50, V_fixture 0: 20-80 % time 200ps typ, 279ps min, 159ps max; typ from 0.859 V to 0.003 V
[POWER_clamp]
-1.5V     126mA      88.76mA    168.8mA
-1.242V   69.8mA     49.43mA    94.36mA
-1.136V   49.16mA    34.7mA     67.53mA
-1.061V   36.35mA    25.39mA    50.04mA
-1.045V   33.92mA    23.62mA    46.67mA
-954.5mV  21.93mA    14.94mA    29.52mA
-909.1mV  17.64mA    11.78mA    23.53mA
-863.6mV  14.51mA    9.346mA    19.48mA
-772.7mV  10.16mA    5.937mA    14mA
-590.9mV  3.705mA    1.741mA    5.168mA
-454.5mV  710.5uA    279.1uA    892.2uA
0V        1.424nA    14.75nA    2.169nA
[Pulldown]
-1.5V     -18.53mA   -17.67mA   -17.32mA
-1.045V   -19.8mA    -19.56mA   -19.06mA
-545.5mV  -15.01mA   -15.01mA   -14.82mA
-409.1mV  -11.96mA   -11.99mA   -12.02mA
727.3mV   19.21mA    19.5mA     19.59mA
1.136V    26.61mA    27.42mA    27.53mA
1.455V    29.32mA    30.47mA    30.93mA
1.864V    30.73mA    31.72mA    32.92mA
2.091V    29.33mA    29.67mA    32.66mA
2.318V    25.5mA     24.82mA    29.36mA
2.773V    15.82mA    10.78mA    20.73mA
3V        11.34mA    6.07mA     16.76mA
[Pullup]
-1.5V     17mA       13.76mA    18.94mA
-1.136V   18.91mA    16.54mA    19.11mA
-863.6mV  17.34mA    17.36mA    17.19mA
-590.9mV  14.75mA    15.13mA    14.58mA
-409.1mV  11.37mA    11.36mA    11.3mA
954.5mV   -24.69mA   -24.32mA   -24.66mA
1.409V    -33.89mA   -33.1mA    -33.96mA
1.818V    -39.82mA   -38.34mA   -39.98mA
2.045V    -41.2mA    -38.48mA   -41.86mA
2.318V    -39.01mA   -35.4mA    -40.21mA
2.636V    -33.81mA   -29.06mA   -34.99mA
3V        -25.08mA   -18.91mA   -26.96mA
[GND_clamp]
-1.5V     -219.3mA   -131.6mA   -364.3mA
-1.288V   -134.4mA   -79.74mA   -225.6mA
-1.258V   -122.9mA   -72.77mA   -206.3mA
-1.136V   -79.27mA   -46.88mA   -132.4mA
-1.045V   -51.5mA    -31.06mA   -84.11mA
-1.015V   -44.02mA   -26.9mA    -70.91mA
-954.5mV  -31.01mA   -19.7mA    -47.55mA
-863.6mV  -17.48mA   -12.16mA   -23.55mA
-803mV    -11.81mA   -8.597mA   -15.85mA
-681.8mV  -5.986mA   -4.096mA   -9.026mA
-378.8mV  -126.2uA   -131.8uA   -179.7uA
1.5V      1.424nA    36.56nA    1.506nA
[Ramp]
dV/dt_f 0.51831157/0.21501262n 0.49622046/0.28144733n 0.54676271/0.1629003n
dV/dt_r 0.51818543/0.19742249n 0.49057988/0.26056051n 0.54226049/0.15704603n
R_load = 50
[Rising Waveform]
R_fixture = 50
V_fixture = 1.5
V_fixture_min = 1.425
V_fixture_max = 1.575
0s        639.6mV    601mV      666.5mV
109.3ps   639.6mV    601mV      700.7mV
220.5ps   680.6mV    601mV      1.137V
315.2ps   936.6mV    601.3mV    1.424V
413.9ps   1.237V     629.1mV    1.541V
566.2ps   1.436V     871.2mV    1.57V
751.3ps   1.489V     1.24V      1.574V
850.4ps   1.493V     1.338V     1.575V
1.223ns   1.496V     1.418V     1.575V
1.787ns   1.498V     1.422V     1.575V
[Rising Waveform]
R_fixture = 50
V_fixture = 0
V_fixture_min = 0
V_fixture_max = 0
0s        0V         0V         0V
124.7ps   0V         0V         21.61mV
229.9ps   3.16mV     0V         382.6mV
340.9ps   249.4mV    0V         731.8mV
446.4ps   566.3mV    0V         867.9mV
629.6ps   803.1mV    275.3mV    894mV
830.8ps   849.4mV    648.8mV    898.8mV
905ps     851.1mV    711.2mV    899.3mV
1.196ns   854.4mV    795.3mV    899.6mV
1.817ns   856.5mV    806.5mV    900.6mV
[Falling Waveform]
R_fixture = 50
V_fixture = 1.5
V_fixture_min = 1.425
V_fixture_max = 1.575
0s        1.499V     1.425V     1.574V
102.7ps   1.499V     1.425V     1.574V
221.6ps   1.491V     1.425V     1.248V
333ps     1.284V     1.425V     871.1mV
450.4ps   954.7mV    1.407V     700.2mV
631.7ps   705.9mV    1.157V     672.6mV
831.4ps   649.9mV    786.4mV    667.6mV
922.3ps   647.6mV    702.6mV    667.2mV
1.249ns   643.1mV    612.5mV    665.9mV
1.787ns   641.2mV    605.4mV    665.6mV
[Falling Waveform]
R_fixture = 50
V_fixture = 0
V_fixture_min = 0
V_fixture_max = 0
0s        858.8mV    812.4mV    899.8mV
108.4ps   858.8mV    812.4mV    875.5mV
205.3ps   845.2mV    812.4mV    519.9mV
323.9ps   559.3mV    812.4mV    159.1mV
431.3ps   252.6mV    765.5mV    28.05mV
610.4ps   53.89mV    471mV      4.363mV
789.2ps   8.865mV    159.7mV    0V
849.3ps   7.061mV    104.7mV    0V
1.252ns   3.64mV     7.253mV    0V
1.817ns   2.634mV    4.552mV    0V
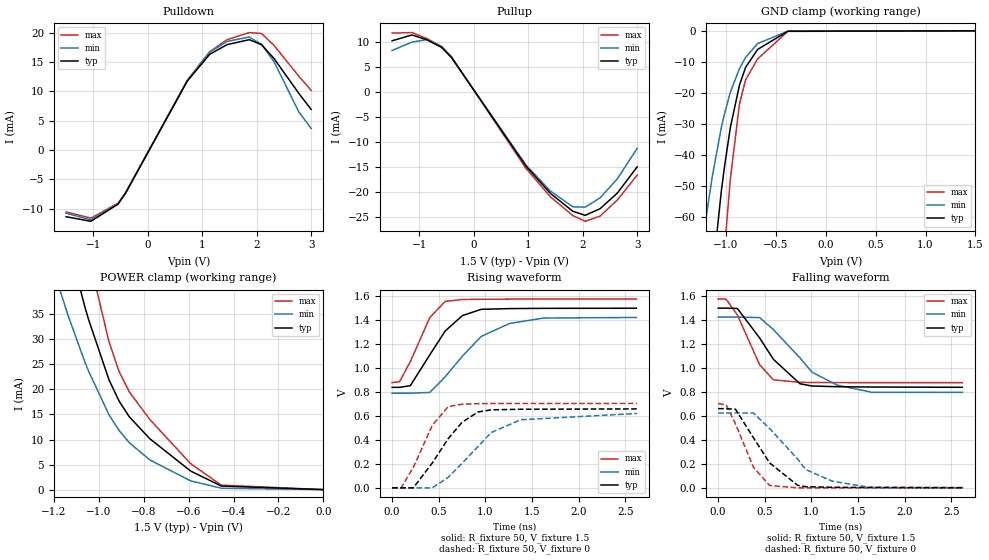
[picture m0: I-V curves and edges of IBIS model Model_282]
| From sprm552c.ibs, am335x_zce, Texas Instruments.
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| Model based on original model for BCSHTLTCSCDVPBFZ_SSDHV
|   Sub model SR11_6MA_5PER_1P5
[model]   Model_282
|[Description]  [1.5V-3-STATE-NOTERM-SR11:6MA, IND, 5%]
|   Slowest slew rate (SR[1:0] = "11"), 1.33 * RExt = 0.750 * Iout
|   (I[2:0] = "001"), 6mA nominal with Rext = 50R,ODT off (ODT[1:0]
|   = "00") CMOS mode,Industrial temperature range (-40C to 125C,
|   25C nominal),5% power supply tolerance
|[Input Load]   NOTERM
|[Output Drive] SR11:6MA
|Voltage   1.5V
|Mode   3-STATE
Model_type   3-state
Polarity   Non-Inverting
Enable   Active-Low
Cref =  15pF
Rref =  100.0000M
Vref =  0V
Vmeas =  0.75
C_comp   1.865048p   1.679967p   1.989968p
[Temperature Range]   25   125   -40
[Voltage Range]   1.5   1.425   1.575
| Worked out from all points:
|   slope of the pulldown table from 0 to 0.225 V, typ, clamps not added: 56.6 ohm
|   slope of the pullup table from 0 to 0.225 V, typ, clamps not added: 60 ohm
|   GND clamp passes 1 mA (typ) near -0.49 V on its own axis
|   POWER clamp passes 1 mA (typ) near -0.47 V on its own axis
|   rising waveform, R_fixture 50, V_fixture 1.5: 20-80 % time 345ps typ, 458ps min, 241ps max; typ from 0.839 V to 1.5 V
|   rising waveform, R_fixture 50, V_fixture 0: 20-80 % time 368ps typ, 490ps min, 259ps max; typ from 0 V to 0.659 V
|   falling waveform, R_fixture 50, V_fixture 1.5: 20-80 % time 363ps typ, 470ps min, 242ps max; typ from 1.5 V to 0.839 V
|   falling waveform, R_fixture 50, V_fixture 0: 20-80 % time 349ps typ, 455ps min, 239ps max; typ from 0.661 V to 0 V
[POWER_clamp]
-1.5V     126mA      88.76mA    168.8mA
-1.242V   69.8mA     49.43mA    94.36mA
-1.136V   49.16mA    34.7mA     67.53mA
-1.061V   36.35mA    25.39mA    50.04mA
-1.045V   33.92mA    23.62mA    46.67mA
-954.5mV  21.93mA    14.94mA    29.52mA
-909.1mV  17.64mA    11.78mA    23.53mA
-863.6mV  14.51mA    9.346mA    19.48mA
-772.7mV  10.16mA    5.937mA    14mA
-590.9mV  3.705mA    1.741mA    5.168mA
-454.5mV  710.5uA    279.1uA    892.2uA
0V        1.424nA    14.75nA    2.169nA
[Pulldown]
-1.5V     -11.35mA   -10.74mA   -10.54mA
-1.045V   -12.13mA   -11.89mA   -11.6mA
-545.5mV  -9.204mA   -9.133mA   -9.027mA
-409.1mV  -7.34mA    -7.297mA   -7.323mA
727.3mV   11.79mA    11.87mA    11.94mA
1.136V    16.32mA    16.68mA    16.77mA
1.455V    17.98mA    18.52mA    18.83mA
1.864V    18.83mA    19.28mA    20.04mA
2.091V    17.97mA    18.02mA    19.87mA
2.318V    15.62mA    15.07mA    17.86mA
2.773V    9.688mA    6.547mA    12.61mA
3V        6.943mA    3.687mA    10.19mA
[Pullup]
-1.5V     10.19mA    8.251mA    11.72mA
-1.136V   11.35mA    9.924mA    11.83mA
-863.6mV  10.4mA     10.42mA    10.64mA
-590.9mV  8.854mA    9.085mA    9.032mA
-409.1mV  6.831mA    6.824mA    7.001mA
954.5mV   -14.83mA   -14.61mA   -15.28mA
1.409V    -20.35mA   -19.87mA   -21.04mA
1.818V    -23.9mA    -23.01mA   -24.76mA
2.045V    -24.72mA   -23.08mA   -25.91mA
2.318V    -23.4mA    -21.23mA   -24.88mA
2.636V    -20.27mA   -17.42mA   -21.65mA
3V        -15.03mA   -11.33mA   -16.67mA
[GND_clamp]
-1.5V     -219.3mA   -131.6mA   -364.3mA
-1.288V   -134.4mA   -79.74mA   -225.6mA
-1.258V   -122.9mA   -72.77mA   -206.3mA
-1.136V   -79.27mA   -46.88mA   -132.4mA
-1.045V   -51.5mA    -31.06mA   -84.11mA
-1.015V   -44.02mA   -26.9mA    -70.91mA
-954.5mV  -31.01mA   -19.7mA    -47.55mA
-863.6mV  -17.48mA   -12.16mA   -23.55mA
-803mV    -11.81mA   -8.597mA   -15.85mA
-681.8mV  -5.986mA   -4.096mA   -9.026mA
-378.8mV  -126.2uA   -131.8uA   -179.7uA
1.5V      1.424nA    36.56nA    1.506nA
[Ramp]
dV/dt_f 0.39839086/0.36501216n  0.3827214/0.48037104n  0.4191673/0.24272641n
dV/dt_r  0.3983593/0.36997824n  0.3763551/0.4968292n 0.42367058/0.25875292n
R_load = 50
[Rising Waveform]
R_fixture = 50
V_fixture = 1.5
V_fixture_min = 1.425
V_fixture_max = 1.575
0s        838.8mV    789.6mV    878.5mV
80.7ps    838.8mV    789.6mV    886.6mV
195.7ps   853.1mV    789.6mV    1.054V
405.1ps   1.111V     796.6mV    1.422V
569.6ps   1.309V     927.2mV    1.556V
755ps     1.438V     1.1V       1.572V
956.4ps   1.49V      1.264V     1.574V
1.26ns    1.496V     1.372V     1.575V
1.625ns   1.498V     1.417V     1.575V
2.62ns    1.499V     1.422V     1.575V
[Rising Waveform]
R_fixture = 50
V_fixture = 0
V_fixture_min = 0
V_fixture_max = 0
0s        0V         0V         0V
96.8ps    0V         0V         0V
227.3ps   0V         0V         169.8mV
431.1ps   207.6mV    0V         521.2mV
602.2ps   411.2mV    87.95mV    678.7mV
751.8ps   548.2mV    205.9mV    698mV
922ps     633.1mV    344.9mV    702.5mV
1.063ns   651.2mV    461.6mV    703.8mV
1.38ns    656mV      568.4mV    704.5mV
2.629ns   658.9mV    620.8mV    704.7mV
[Falling Waveform]
R_fixture = 50
V_fixture = 1.5
V_fixture_min = 1.425
V_fixture_max = 1.575
0s        1.499V     1.424V     1.574V
84.8ps    1.499V     1.424V     1.574V
206.4ps   1.496V     1.424V     1.442V
445.4ps   1.25V      1.42V      1.027V
593ps     1.072V     1.32V      900.9mV
877.5ps   868.2mV    1.084V     880.3mV
1.007ns   849.4mV    965.2mV    878.8mV
1.276ns   843.6mV    857.1mV    877.8mV
1.653ns   841mV      796.5mV    877.6mV
2.62ns    838.7mV    796.5mV    877.5mV
[Falling Waveform]
R_fixture = 50
V_fixture = 0
V_fixture_min = 0
V_fixture_max = 0
0s        660.5mV    624.3mV    703.7mV
85.8ps    660.5mV    624.3mV    690.4mV
186.2ps   655.5mV    624.3mV    533.4mV
378.7ps   418.3mV    624.3mV    171.9mV
552.2ps   207.9mV    495.6mV    19.79mV
854.2ps   20.63mV    238.5mV    0V
940.3ps   9.803mV    152.5mV    0V
1.226ns   4.8mV      55.37mV    0V
1.614ns   2.969mV    5.642mV    0V
2.629ns   0V         3.187mV    0V
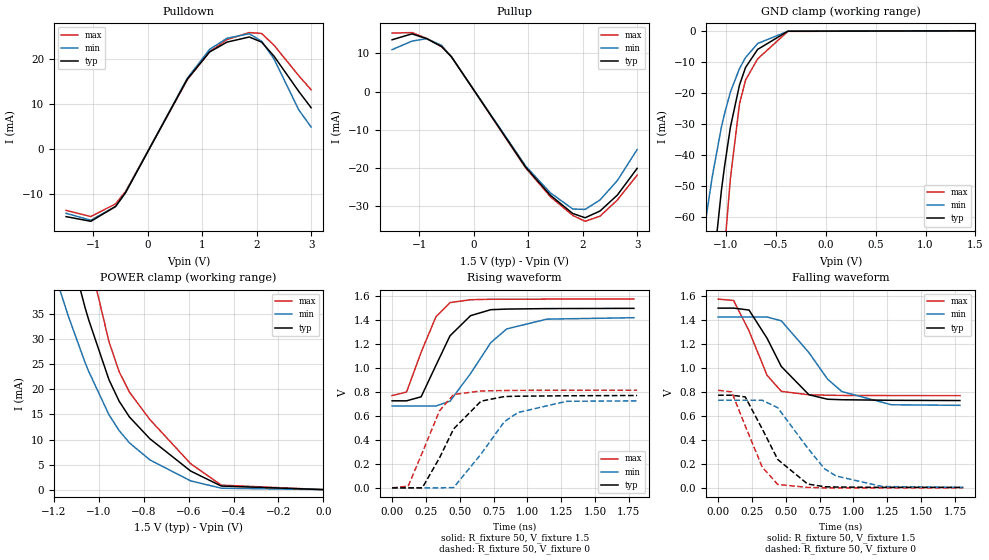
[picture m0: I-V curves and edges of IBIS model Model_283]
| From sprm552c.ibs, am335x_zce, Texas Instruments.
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| Model based on original model for BCSHTLTCSCDVPBFZ_SSDHV
|   Sub model SR10_8MA_5PER_1P5
[model]   Model_283
|[Description]  [1.5V-3-STATE-NOTERM-SR10:8MA, IND, 5%]
|   Fast slew rate (SR[1:0] = "10"), 1.00 * RExt = 1.000 * Iout
|   (I[2:0] = "011"), 8mA nominal with Rext = 50R,ODT off (ODT[1:0]
|   = "00") CMOS mode,Industrial temperature range (-40C to 125C,
|   25C nominal),5% power supply tolerance
|[Input Load]   NOTERM
|[Output Drive] SR10:8MA
|Voltage   1.5V
|Mode   3-STATE
Model_type   3-state
Polarity   Non-Inverting
Enable   Active-Low
Cref =  15pF
Rref =  100.0000M
Vref =  0V
Vmeas =  0.75
C_comp   1.865048p   1.679967p   1.989968p
[Temperature Range]   25   125   -40
[Voltage Range]   1.5   1.425   1.575
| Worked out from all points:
|   slope of the pulldown table from 0 to 0.225 V, typ, clamps not added: 43 ohm
|   slope of the pullup table from 0 to 0.225 V, typ, clamps not added: 45 ohm
|   GND clamp passes 1 mA (typ) near -0.49 V on its own axis
|   POWER clamp passes 1 mA (typ) near -0.47 V on its own axis
|   rising waveform, R_fixture 50, V_fixture 1.5: 20-80 % time 207ps typ, 274ps min, 161ps max; typ from 0.726 V to 1.5 V
|   rising waveform, R_fixture 50, V_fixture 0: 20-80 % time 228ps typ, 288ps min, 172ps max; typ from 0 V to 0.771 V
|   falling waveform, R_fixture 50, V_fixture 1.5: 20-80 % time 234ps typ, 300ps min, 175ps max; typ from 1.5 V to 0.728 V
|   falling waveform, R_fixture 50, V_fixture 0: 20-80 % time 226ps typ, 293ps min, 171ps max; typ from 0.773 V to 0.004 V
[POWER_clamp]
-1.5V     126mA      88.76mA    168.8mA
-1.242V   69.8mA     49.43mA    94.36mA
-1.136V   49.16mA    34.7mA     67.53mA
-1.061V   36.35mA    25.39mA    50.04mA
-1.045V   33.92mA    23.62mA    46.67mA
-954.5mV  21.93mA    14.94mA    29.52mA
-909.1mV  17.64mA    11.78mA    23.53mA
-863.6mV  14.51mA    9.346mA    19.48mA
-772.7mV  10.16mA    5.937mA    14mA
-590.9mV  3.705mA    1.741mA    5.168mA
-454.5mV  710.5uA    279.1uA    892.2uA
0V        1.424nA    14.75nA    2.169nA
[Pulldown]
-1.5V     -14.94mA   -14.2mA    -13.55mA
-1.045V   -15.97mA   -15.73mA   -14.92mA
-590.9mV  -12.7mA    -12.67mA   -12.12mA
-409.1mV  -9.652mA   -9.646mA   -9.411mA
727.3mV   15.5mA     15.69mA    15.34mA
1.136V    21.47mA    22.05mA    21.55mA
1.455V    23.65mA    24.5mA     24.21mA
1.864V    24.78mA    25.5mA     25.76mA
2.091V    23.65mA    23.85mA    25.56mA
2.318V    20.55mA    19.94mA    22.97mA
2.773V    12.75mA    8.663mA    16.22mA
3V        9.139mA    4.878mA    13.11mA
[Pullup]
-1.5V     13.59mA    11mA       15.33mA
-1.136V   15.13mA    13.23mA    15.47mA
-863.6mV  13.87mA    13.89mA    13.92mA
-590.9mV  11.8mA     12.11mA    11.81mA
-409.1mV  9.103mA    9.093mA    9.151mA
954.5mV   -19.76mA   -19.47mA   -19.97mA
1.409V    -27.12mA   -26.48mA   -27.5mA
1.818V    -31.86mA   -30.68mA   -32.37mA
2.045V    -32.96mA   -30.78mA   -33.89mA
2.318V    -31.2mA    -28.31mA   -32.55mA
2.636V    -27.04mA   -23.24mA   -28.32mA
3V        -20.05mA   -15.12mA   -21.81mA
[GND_clamp]
-1.5V     -219.3mA   -131.6mA   -364.3mA
-1.288V   -134.4mA   -79.74mA   -225.6mA
-1.258V   -122.9mA   -72.77mA   -206.3mA
-1.136V   -79.27mA   -46.88mA   -132.4mA
-1.045V   -51.5mA    -31.06mA   -84.11mA
-1.015V   -44.02mA   -26.9mA    -70.91mA
-954.5mV  -31.01mA   -19.7mA    -47.55mA
-863.6mV  -17.48mA   -12.16mA   -23.55mA
-803mV    -11.81mA   -8.597mA   -15.85mA
-681.8mV  -5.986mA   -4.096mA   -9.026mA
-378.8mV  -126.2uA   -131.8uA   -179.7uA
1.5V      1.424nA    36.56nA    1.506nA
[Ramp]
dV/dt_f 0.46595609/0.23615928n 0.44645889/0.30398913n 0.48416799/0.17458142n
dV/dt_r 0.46586958/0.23030937n 0.44047875/0.28975427n 0.49015073/0.1720539n
R_load = 50
[Rising Waveform]
R_fixture = 50
V_fixture = 1.5
V_fixture_min = 1.425
V_fixture_max = 1.575
0s        726.3mV    682.9mV    770.3mV
106.8ps   726.3mV    682.9mV    799.3mV
214.6ps   760mV      682.9mV    1.132V
324.3ps   1.023V     683.1mV    1.428V
427.9ps   1.269V     723.7mV    1.546V
579.8ps   1.437V     954mV      1.57V
729.5ps   1.487V     1.212V     1.574V
846.5ps   1.492V     1.326V     1.574V
1.143ns   1.496V     1.408V     1.575V
1.787ns   1.498V     1.42V      1.575V
[Rising Waveform]
R_fixture = 50
V_fixture = 0
V_fixture_min = 0
V_fixture_max = 0
0s        0V         0V         0V
118.5ps   0V         0V         14.36mV
223ps     0V         0V         292.8mV
349.6ps   248.5mV    0V         641.9mV
454.8ps   492.2mV    2.379mV    779.5mV
657.1ps   723.5mV    282mV      808.6mV
830ps     762.1mV    553mV      812.5mV
930.6ps   764.8mV    629.1mV    813.5mV
1.29ns    768.6mV    722.3mV    814.6mV
1.811ns   770.7mV    726.1mV    814.8mV
[Falling Waveform]
R_fixture = 50
V_fixture = 1.5
V_fixture_min = 1.425
V_fixture_max = 1.575
0s        1.499V     1.425V     1.574V
114.3ps   1.499V     1.425V     1.563V
228.3ps   1.483V     1.425V     1.309V
361.4ps   1.248V     1.425V     939.3mV
467.1ps   1.012V     1.393V     804.7mV
670.9ps   776.8mV    1.128V     776.2mV
808.4ps   739.2mV    907.1mV    772.5mV
914.8ps   735mV      802.9mV    770.9mV
1.281ns   730.3mV    692.9mV    769.5mV
1.787ns   728.1mV    688.3mV    769.3mV
[Falling Waveform]
R_fixture = 50
V_fixture = 0
V_fixture_min = 0
V_fixture_max = 0
0s        772.7mV    730.6mV    813.8mV
99.8ps    772.7mV    730.6mV    800.6mV
200.1ps   758.8mV    730.6mV    517.7mV
325.9ps   491.5mV    730.6mV    173.3mV
440.4ps   236.7mV    668.7mV    28.48mV
661.4ps   31.95mV    332.4mV    3.768mV
786.7ps   9.402mV    158.6mV    0V
872.1ps   7.02mV     98.87mV    0V
1.213ns   4.139mV    11.14mV    0V
1.811ns   3.594mV    4.422mV    0V
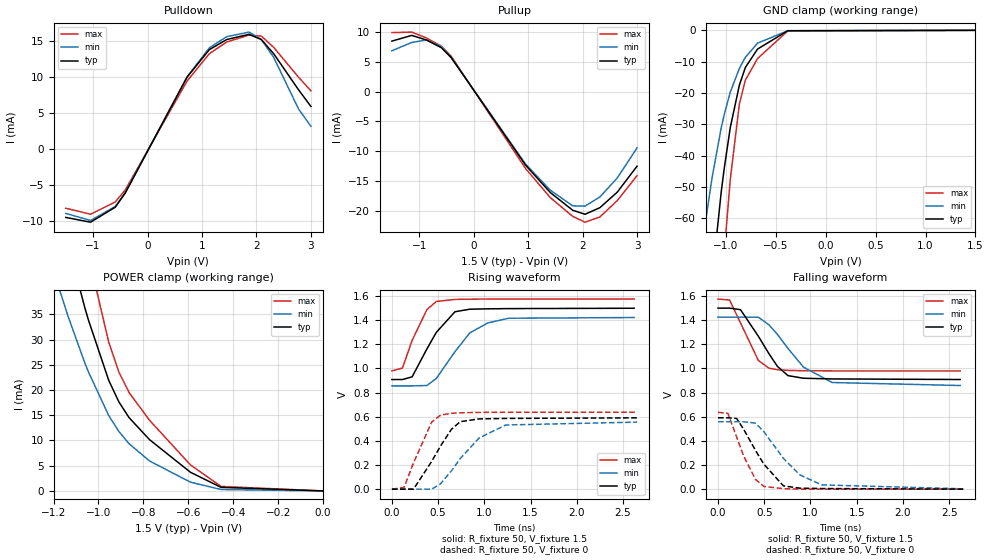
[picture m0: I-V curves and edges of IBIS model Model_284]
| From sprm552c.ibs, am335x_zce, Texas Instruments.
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| Model based on original model for BCSHTLTCSCDVPBFZ_SSDHV
|   Sub model SR10_5MA_5PER_1P5
[model]   Model_284
|[Description]  [1.5V-3-STATE-NOTERM-SR10:5MA, IND, 5%]
|   Fast slew rate (SR[1:0] = "10"), 1.60 * RExt = 0.625 * Iout
|   (I[2:0] = "000"), 5mA nominal with Rext = 50R,ODT off (ODT[1:0]
|   = "00") CMOS mode,Industrial temperature range (-40C to 125C,
|   25C nominal),5% power supply tolerance
|[Input Load]   NOTERM
|[Output Drive] SR10:5MA
|Voltage   1.5V
|Mode   3-STATE
Model_type   3-state
Polarity   Non-Inverting
Enable   Active-Low
Cref =  15pF
Rref =  100.0000M
Vref =  0V
Vmeas =  0.75
C_comp   1.865048p   1.679967p   1.989968p
[Temperature Range]   25   125   -40
[Voltage Range]   1.5   1.425   1.575
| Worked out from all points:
|   slope of the pulldown table from 0 to 0.225 V, typ, clamps not added: 67.2 ohm
|   slope of the pullup table from 0 to 0.225 V, typ, clamps not added: 72 ohm
|   GND clamp passes 1 mA (typ) near -0.49 V on its own axis
|   POWER clamp passes 1 mA (typ) near -0.47 V on its own axis
|   rising waveform, R_fixture 50, V_fixture 1.5: 20-80 % time 261ps typ, 341ps min, 189ps max; typ from 0.908 V to 1.5 V
|   rising waveform, R_fixture 50, V_fixture 0: 20-80 % time 279ps typ, 381ps min, 203ps max; typ from 0 V to 0.591 V
|   falling waveform, R_fixture 50, V_fixture 1.5: 20-80 % time 290ps typ, 383ps min, 211ps max; typ from 1.5 V to 0.908 V
|   falling waveform, R_fixture 50, V_fixture 0: 20-80 % time 281ps typ, 371ps min, 202ps max; typ from 0.591 V to 0 V
[POWER_clamp]
-1.5V     126mA      88.76mA    168.8mA
-1.242V   69.8mA     49.43mA    94.36mA
-1.136V   49.16mA    34.7mA     67.53mA
-1.061V   36.35mA    25.39mA    50.04mA
-1.045V   33.92mA    23.62mA    46.67mA
-954.5mV  21.93mA    14.94mA    29.52mA
-909.1mV  17.64mA    11.78mA    23.53mA
-863.6mV  14.51mA    9.346mA    19.48mA
-772.7mV  10.16mA    5.937mA    14mA
-590.9mV  3.705mA    1.741mA    5.168mA
-454.5mV  710.5uA    279.1uA    892.2uA
0V        1.424nA    14.75nA    2.169nA
[Pulldown]
-1.5V     -9.559mA   -9.005mA   -8.281mA
-1.045V   -10.22mA   -9.975mA   -9.117mA
-590.9mV  -8.133mA   -8.04mA    -7.408mA
-409.1mV  -6.182mA   -6.122mA   -5.755mA
727.3mV   9.928mA    9.954mA    9.38mA
1.136V    13.74mA    13.99mA    13.18mA
1.455V    15.14mA    15.54mA    14.8mA
1.864V    15.86mA    16.17mA    15.75mA
2.091V    15.13mA    15.12mA    15.61mA
2.318V    13.15mA    12.64mA    14.03mA
2.773V    8.157mA    5.489mA    9.905mA
3V        5.846mA    3.092mA    8.007mA
[Pullup]
-1.5V     8.494mA    6.876mA    9.92mA
-1.136V   9.455mA    8.27mA     10.01mA
-863.6mV  8.671mA    8.683mA    9.007mA
-590.9mV  7.379mA    7.572mA    7.643mA
-409.1mV  5.694mA    5.688mA    5.925mA
954.5mV   -12.36mA   -12.18mA   -12.93mA
1.409V    -16.96mA   -16.56mA   -17.81mA
1.818V    -19.92mA   -19.18mA   -20.95mA
2.045V    -20.6mA    -19.23mA   -21.93mA
2.318V    -19.49mA   -17.69mA   -21.05mA
2.636V    -16.89mA   -14.51mA   -18.31mA
3V        -12.52mA   -9.441mA   -14.11mA
[GND_clamp]
-1.5V     -219.3mA   -131.6mA   -364.3mA
-1.288V   -134.4mA   -79.74mA   -225.6mA
-1.258V   -122.9mA   -72.77mA   -206.3mA
-1.136V   -79.27mA   -46.88mA   -132.4mA
-1.045V   -51.5mA    -31.06mA   -84.11mA
-1.015V   -44.02mA   -26.9mA    -70.91mA
-954.5mV  -31.01mA   -19.7mA    -47.55mA
-863.6mV  -17.48mA   -12.16mA   -23.55mA
-803mV    -11.81mA   -8.597mA   -15.85mA
-681.8mV  -5.986mA   -4.096mA   -9.026mA
-378.8mV  -126.2uA   -131.8uA   -179.7uA
1.5V      1.424nA    36.56nA    1.506nA
[Ramp]
dV/dt_f 0.35651032/0.29130026n 0.34249676/0.38688717n 0.35803754/0.21127771n
dV/dt_r 0.35637086/0.28008364n 0.33629286/0.38486053n 0.38326633/0.20280172n
R_load = 50
[Rising Waveform]
R_fixture = 50
V_fixture = 1.5
V_fixture_min = 1.425
V_fixture_max = 1.575
0s        908.2mV    855.7mV    980.1mV
113.8ps   908.2mV    855.7mV    1.003V
218.9ps   930.9mV    855.7mV    1.233V
378.7ps   1.162V     858.8mV    1.488V
480.4ps   1.299V     917.5mV    1.555V
682ps     1.47V      1.139V     1.572V
842.8ps   1.491V     1.295V     1.574V
1.037ns   1.494V     1.377V     1.575V
1.262ns   1.496V     1.416V     1.575V
2.62ns    1.499V     1.422V     1.575V
[Rising Waveform]
R_fixture = 50
V_fixture = 0
V_fixture_min = 0
V_fixture_max = 0
0s        0V         0V         0V
131.3ps   0V         0V         13.77mV
234.1ps   0V         0V         218.8mV
430.1ps   230mV      0V         555.7mV
527ps     358.9mV    45.52mV    613.8mV
644.8ps   496.9mV    152.9mV    628.6mV
739.7ps   559.3mV    253.9mV    632.8mV
943.8ps   582.1mV    424.7mV    636mV
1.232ns   586mV      531.8mV    637.1mV
2.652ns   591mV      555.5mV    637.3mV
[Falling Waveform]
R_fixture = 50
V_fixture = 1.5
V_fixture_min = 1.425
V_fixture_max = 1.575
0s        1.499V     1.424V     1.574V
124.9ps   1.499V     1.424V     1.566V
243.1ps   1.486V     1.424V     1.376V
436.2ps   1.266V     1.424V     1.066V
550.3ps   1.122V     1.361V     1.002V
642.2ps   1.017V     1.282V     989.1mV
756.1ps   940.2mV    1.166V     983.4mV
924.6ps   918.4mV    1.01V      980.5mV
1.235ns   912.7mV    883mV      979.4mV
2.62ns    908mV      858.2mV    979.1mV
[Falling Waveform]
R_fixture = 50
V_fixture = 0
V_fixture_min = 0
V_fixture_max = 0
0s        591mV      558.3mV    636.4mV
106.9ps   591mV      558.3mV    627.3mV
201.3ps   585.4mV    558.3mV    431.4mV
279.2ps   492.9mV    558.3mV    270.2mV
405.4ps   320.8mV    546.6mV    80.73mV
494.7ps   207.9mV    476.4mV    22.65mV
707.3ps   27.19mV    254.9mV    4.024mV
884.8ps   8.28mV     118.3mV    0V
1.122ns   5.184mV    35.4mV     0V
2.652ns   0V         2.712mV    0V
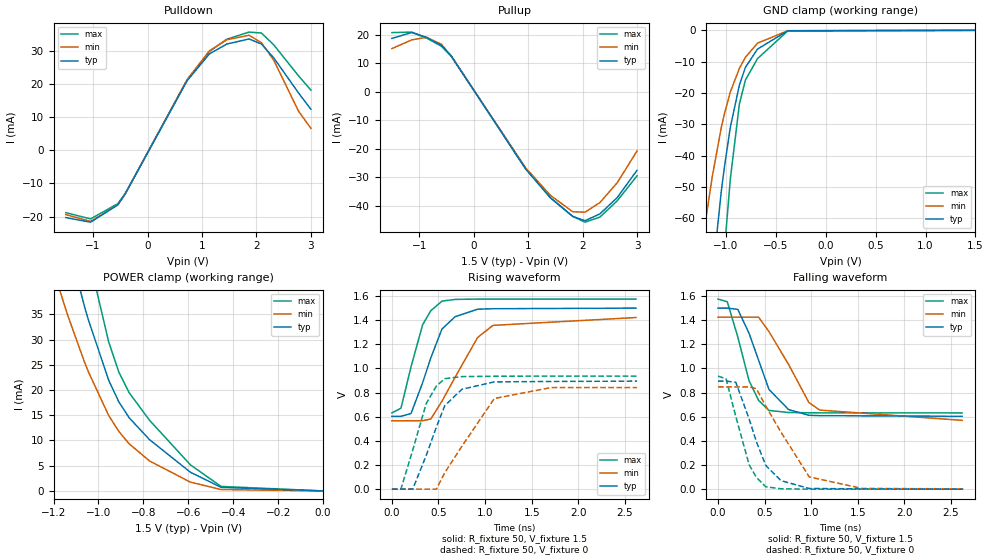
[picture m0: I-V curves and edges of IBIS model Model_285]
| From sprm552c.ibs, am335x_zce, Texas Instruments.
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| Model based on original model for BCSHTLTCSCDVPBFZ_SSDHV
|   Sub model SR11_11MA_5PER_1P5
[model]   Model_285
|[Description]  [1.5V-3-STATE-NOTERM-SR11:11MA, IND, 5%]
|   Slowest slew rate (SR[1:0] = "11"), 0.73 * RExt = 1.325 * Iout
|   (I[2:0] = "110"), 11mA nominal with Rext = 50R,ODT off (ODT[1:0]
|   = "00") CMOS mode,Industrial temperature range (-40C to 125C,
|   25C nominal),5% power supply tolerance
|[Input Load]   NOTERM
|[Output Drive] SR11:11MA
|Voltage   1.5V
|Mode   3-STATE
Model_type   3-state
Polarity   Non-Inverting
Enable   Active-Low
Cref =  15pF
Rref =  100.0000M
Vref =  0V
Vmeas =  0.75
C_comp   1.865048p   1.679967p   1.989968p
[Temperature Range]   25   125   -40
[Voltage Range]   1.5   1.425   1.575
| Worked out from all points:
|   slope of the pulldown table from 0 to 0.225 V, typ, clamps not added: 31.7 ohm
|   slope of the pullup table from 0 to 0.225 V, typ, clamps not added: 32.8 ohm
|   GND clamp passes 1 mA (typ) near -0.49 V on its own axis
|   POWER clamp passes 1 mA (typ) near -0.47 V on its own axis
|   rising waveform, R_fixture 50, V_fixture 1.5: 20-80 % time 247ps typ, 372ps min, 198ps max; typ from 0.603 V to 1.5 V
|   rising waveform, R_fixture 50, V_fixture 0: 20-80 % time 265ps typ, 383ps min, 219ps max; typ from 0 V to 0.895 V
|   falling waveform, R_fixture 50, V_fixture 1.5: 20-80 % time 259ps typ, 360ps min, 207ps max; typ from 1.5 V to 0.603 V
|   falling waveform, R_fixture 50, V_fixture 0: 20-80 % time 249ps typ, 387ps min, 201ps max; typ from 0.895 V to 0 V
[POWER_clamp]
-1.5V     126mA      88.76mA    168.8mA
-1.242V   69.8mA     49.43mA    94.36mA
-1.136V   49.16mA    34.7mA     67.53mA
-1.061V   36.35mA    25.39mA    50.04mA
-1.045V   33.92mA    23.62mA    46.67mA
-954.5mV  21.93mA    14.94mA    29.52mA
-909.1mV  17.64mA    11.78mA    23.53mA
-863.6mV  14.51mA    9.346mA    19.48mA
-772.7mV  10.16mA    5.937mA    14mA
-590.9mV  3.705mA    1.741mA    5.168mA
-454.5mV  710.5uA    279.1uA    892.2uA
0V        1.424nA    14.75nA    2.169nA
[Pulldown]
-1.5V     -20.32mA   -19.41mA   -18.83mA
-1.045V   -21.71mA   -21.48mA   -20.72mA
-545.5mV  -16.46mA   -16.48mA   -16.11mA
-409.1mV  -13.12mA   -13.16mA   -13.06mA
727.3mV   21.07mA    21.41mA    21.29mA
1.136V    29.18mA    30.1mA     29.92mA
1.455V    32.16mA    33.45mA    33.62mA
1.864V    33.7mA     34.83mA    35.78mA
2.091V    32.17mA    32.59mA    35.5mA
2.318V    27.97mA    27.26mA    31.92mA
2.773V    17.36mA    11.84mA    22.54mA
3V        12.44mA    6.666mA    18.22mA
[Pullup]
-1.5V     18.7mA     15.13mA    20.75mA
-1.136V   20.8mA     18.2mA     20.93mA
-863.6mV  19.07mA    19.1mA     18.82mA
-590.9mV  16.22mA    16.64mA    15.97mA
-409.1mV  12.51mA    12.49mA    12.37mA
954.5mV   -27.15mA   -26.75mA   -27.01mA
1.409V    -37.28mA   -36.4mA    -37.19mA
1.818V    -43.8mA    -42.17mA   -43.78mA
2.045V    -45.32mA   -42.33mA   -45.84mA
2.318V    -42.92mA   -38.95mA   -44.05mA
2.636V    -37.2mA    -31.98mA   -38.33mA
3V        -27.6mA    -20.81mA   -29.54mA
[GND_clamp]
-1.5V     -219.3mA   -131.6mA   -364.3mA
-1.288V   -134.4mA   -79.74mA   -225.6mA
-1.258V   -122.9mA   -72.77mA   -206.3mA
-1.136V   -79.27mA   -46.88mA   -132.4mA
-1.045V   -51.5mA    -31.06mA   -84.11mA
-1.015V   -44.02mA   -26.9mA    -70.91mA
-954.5mV  -31.01mA   -19.7mA    -47.55mA
-863.6mV  -17.48mA   -12.16mA   -23.55mA
-803mV    -11.81mA   -8.597mA   -15.85mA
-681.8mV  -5.986mA   -4.096mA   -9.026mA
-378.8mV  -126.2uA   -131.8uA   -179.7uA
1.5V      1.424nA    36.56nA    1.506nA
[Ramp]
dV/dt_f 0.54073381/0.26015202n 0.51801992/0.36271113n 0.56785658/0.20739983n
dV/dt_r 0.54012758/0.2650287n  0.5121522/0.39280256n 0.56410241/0.2196475n
R_load = 50
[Rising Waveform]
R_fixture = 50
V_fixture = 1.5
V_fixture_min = 1.425
V_fixture_max = 1.575
0s        603.4mV    566.9mV    632.3mV
97.3ps    603.4mV    566.9mV    670.6mV
205.1ps   626.8mV    566.9mV    1.013V
329.4ps   881.6mV    566.9mV    1.362V
417.1ps   1.087V     581.1mV    1.478V
537.1ps   1.327V     728.7mV    1.558V
678.7ps   1.429V     928.1mV    1.572V
919.3ps   1.491V     1.256V     1.575V
1.084ns   1.495V     1.357V     1.575V
2.62ns    1.5V       1.422V     1.575V
[Rising Waveform]
R_fixture = 50
V_fixture = 0
V_fixture_min = 0
V_fixture_max = 0
0s        0V         0V         0V
96.4ps    0V         0V         0V
223.3ps   0V         0V         323.2mV
367.8ps   278.6mV    0V         708.9mV
477.1ps   514.3mV    0V         854.1mV
566.8ps   691mV      135.8mV    915.4mV
751.7ps   827.9mV    356.1mV    932.7mV
1.099ns   888.7mV    751.2mV    935.4mV
1.711ns   892.4mV    842mV      936.8mV
2.631ns   895mV      842mV      936.8mV
[Falling Waveform]
R_fixture = 50
V_fixture = 1.5
V_fixture_min = 1.425
V_fixture_max = 1.575
0s        1.499V     1.424V     1.574V
99.4ps    1.499V     1.424V     1.552V
211.7ps   1.489V     1.424V     1.261V
332.7ps   1.291V     1.424V     898.7mV
435.2ps   1.068V     1.424V     735.4mV
546.3ps   826.1mV    1.305V     651.8mV
756.1ps   659.4mV    1.034V     634.9mV
974.8ps   611.7mV    718.2mV    632.7mV
1.09ns    608.9mV    655mV      632mV
2.62ns    603.1mV    570mV      631.3mV
[Falling Waveform]
R_fixture = 50
V_fixture = 0
V_fixture_min = 0
V_fixture_max = 0
0s        894.8mV    846.5mV    935.9mV
86.3ps    894.8mV    846.5mV    913.5mV
190.4ps   885.1mV    846.5mV    602.3mV
334.4ps   579.7mV    846.5mV    201mV
411.1ps   394mV      832.4mV    97.91mV
512.7ps   196.2mV    687.5mV    19.67mV
675.9ps   70.48mV    471.5mV    3.318mV
978.9ps   5.782mV    101.7mV    0V
1.544ns   2.553mV    6.06mV     0V
2.631ns   0V         2.767mV    0V
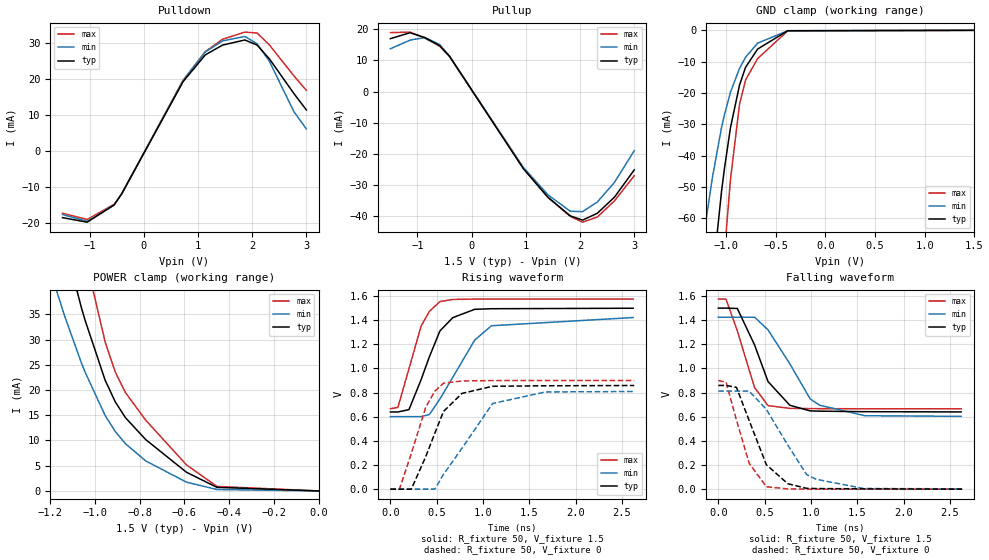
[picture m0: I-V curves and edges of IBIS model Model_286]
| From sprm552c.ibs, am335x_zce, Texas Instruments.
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| Model based on original model for BCSHTLTCSCDVPBFZ_SSDHV
|   Sub model SR11_10MA_5PER_1P5
[model]   Model_286
|[Description]  [1.5V-3-STATE-NOTERM-SR11:10MA, IND, 5%]
|   Slowest slew rate (SR[1:0] = "11"), 0.80 * RExt = 1.250 * Iout
|   (I[2:0] = "101"), 10mA nominal with Rext = 50R,ODT off (ODT[1:0]
|   = "00") CMOS mode,Industrial temperature range (-40C to 125C,
|   25C nominal),5% power supply tolerance
|[Input Load]   NOTERM
|[Output Drive] SR11:10MA
|Voltage   1.5V
|Mode   3-STATE
Model_type   3-state
Polarity   Non-Inverting
Enable   Active-Low
Cref =  15pF
Rref =  100.0000M
Vref =  0V
Vmeas =  0.75
C_comp   1.865048p   1.679967p   1.989968p
[Temperature Range]   25   125   -40
[Voltage Range]   1.5   1.425   1.575
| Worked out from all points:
|   slope of the pulldown table from 0 to 0.225 V, typ, clamps not added: 34.7 ohm
|   slope of the pullup table from 0 to 0.225 V, typ, clamps not added: 36.1 ohm
|   GND clamp passes 1 mA (typ) near -0.49 V on its own axis
|   POWER clamp passes 1 mA (typ) near -0.47 V on its own axis
|   rising waveform, R_fixture 50, V_fixture 1.5: 20-80 % time 262ps typ, 382ps min, 209ps max; typ from 0.64 V to 1.5 V
|   rising waveform, R_fixture 50, V_fixture 0: 20-80 % time 282ps typ, 378ps min, 227ps max; typ from 0 V to 0.859 V
|   falling waveform, R_fixture 50, V_fixture 1.5: 20-80 % time 282ps typ, 377ps min, 216ps max; typ from 1.5 V to 0.639 V
|   falling waveform, R_fixture 50, V_fixture 0: 20-80 % time 266ps typ, 385ps min, 212ps max; typ from 0.859 V to 0 V
[POWER_clamp]
-1.5V     126mA      88.76mA    168.8mA
-1.242V   69.8mA     49.43mA    94.36mA
-1.136V   49.16mA    34.7mA     67.53mA
-1.061V   36.35mA    25.39mA    50.04mA
-1.045V   33.92mA    23.62mA    46.67mA
-954.5mV  21.93mA    14.94mA    29.52mA
-909.1mV  17.64mA    11.78mA    23.53mA
-863.6mV  14.51mA    9.346mA    19.48mA
-772.7mV  10.16mA    5.937mA    14mA
-590.9mV  3.705mA    1.741mA    5.168mA
-454.5mV  710.5uA    279.1uA    892.2uA
0V        1.424nA    14.75nA    2.169nA
[Pulldown]
-1.5V     -18.53mA   -17.67mA   -17.32mA
-1.045V   -19.8mA    -19.56mA   -19.06mA
-545.5mV  -15.01mA   -15.01mA   -14.82mA
-409.1mV  -11.96mA   -11.99mA   -12.02mA
727.3mV   19.21mA    19.5mA     19.59mA
1.136V    26.61mA    27.42mA    27.53mA
1.455V    29.32mA    30.47mA    30.93mA
1.864V    30.73mA    31.72mA    32.92mA
2.091V    29.33mA    29.67mA    32.66mA
2.318V    25.5mA     24.82mA    29.36mA
2.773V    15.82mA    10.78mA    20.73mA
3V        11.34mA    6.07mA     16.76mA
[Pullup]
-1.5V     17mA       13.76mA    18.94mA
-1.136V   18.91mA    16.54mA    19.11mA
-863.6mV  17.34mA    17.36mA    17.19mA
-590.9mV  14.75mA    15.13mA    14.58mA
-409.1mV  11.37mA    11.36mA    11.3mA
954.5mV   -24.69mA   -24.32mA   -24.66mA
1.409V    -33.89mA   -33.1mA    -33.96mA
1.818V    -39.82mA   -38.34mA   -39.98mA
2.045V    -41.2mA    -38.48mA   -41.86mA
2.318V    -39.01mA   -35.4mA    -40.21mA
2.636V    -33.81mA   -29.06mA   -34.99mA
3V        -25.08mA   -18.91mA   -26.96mA
[GND_clamp]
-1.5V     -219.3mA   -131.6mA   -364.3mA
-1.288V   -134.4mA   -79.74mA   -225.6mA
-1.258V   -122.9mA   -72.77mA   -206.3mA
-1.136V   -79.27mA   -46.88mA   -132.4mA
-1.045V   -51.5mA    -31.06mA   -84.11mA
-1.015V   -44.02mA   -26.9mA    -70.91mA
-954.5mV  -31.01mA   -19.7mA    -47.55mA
-863.6mV  -17.48mA   -12.16mA   -23.55mA
-803mV    -11.81mA   -8.597mA   -15.85mA
-681.8mV  -5.986mA   -4.096mA   -9.026mA
-378.8mV  -126.2uA   -131.8uA   -179.7uA
1.5V      1.424nA    36.56nA    1.506nA
[Ramp]
dV/dt_f  0.5188239/0.28248293n 0.49715082/0.37320997n 0.54704779/0.21666283n
dV/dt_r 0.51841848/0.28287n   0.4910354/0.38269293n 0.54224772/0.22717038n
R_load = 50
[Rising Waveform]
R_fixture = 50
V_fixture = 1.5
V_fixture_min = 1.425
V_fixture_max = 1.575
0s        639.6mV    601mV      666.5mV
80.9ps    639.6mV    601mV      677.5mV
200.6ps   659.1mV    601mV      997.7mV
331.1ps   906.4mV    601mV      1.35V
420.9ps   1.097V     618mV      1.473V
534.6ps   1.311V     748mV      1.554V
673.6ps   1.421V     926.8mV    1.572V
909.7ps   1.49V      1.235V     1.575V
1.091ns   1.495V     1.354V     1.575V
2.62ns    1.499V     1.422V     1.575V
[Rising Waveform]
R_fixture = 50
V_fixture = 0
V_fixture_min = 0
V_fixture_max = 0
0s        0V         0V         0V
97.6ps    0V         0V         0V
225.5ps   0V         0V         295.3mV
382ps     270.2mV    0V         680.2mV
479.1ps   462.9mV    0V         810.9mV
572.9ps   643.5mV    122.1mV    878.1mV
772.9ps   793.5mV    339.4mV    896.6mV
1.103ns   852.5mV    709.5mV    899.5mV
1.671ns   856.5mV    805.3mV    900.5mV
2.632ns   858.9mV    809.3mV    900.6mV
[Falling Waveform]
R_fixture = 50
V_fixture = 1.5
V_fixture_min = 1.425
V_fixture_max = 1.575
0s        1.499V     1.424V     1.574V
82.6ps    1.499V     1.424V     1.574V
205.2ps   1.496V     1.424V     1.311V
391.5ps   1.194V     1.424V     840.5mV
536.5ps   891mV      1.319V     692mV
771.7ps   694.8mV    1.038V     669.1mV
991.5ps   648.1mV    747.6mV    667mV
1.093ns   645.8mV    695.1mV    666.6mV
1.583ns   641.6mV    608.1mV    665.6mV
2.62ns    639.5mV    602.9mV    665.6mV
[Falling Waveform]
R_fixture = 50
V_fixture = 0
V_fixture_min = 0
V_fixture_max = 0
0s        858.9mV    812.4mV    899.7mV
84.6ps    858.9mV    812.4mV    884.3mV
196.3ps   842.6mV    812.4mV    570.8mV
332.9ps   568.2mV    812.4mV    214.9mV
518.4ps   202.4mV    661.1mV    19.84mV
750.2ps   44.98mV    364.5mV    2.256mV
953.1ps   6.731mV    121.1mV    0V
1.051ns   5.226mV    83.29mV    0V
1.566ns   2.624mV    5.371mV    0V
2.632ns   0V         2.935mV    0V
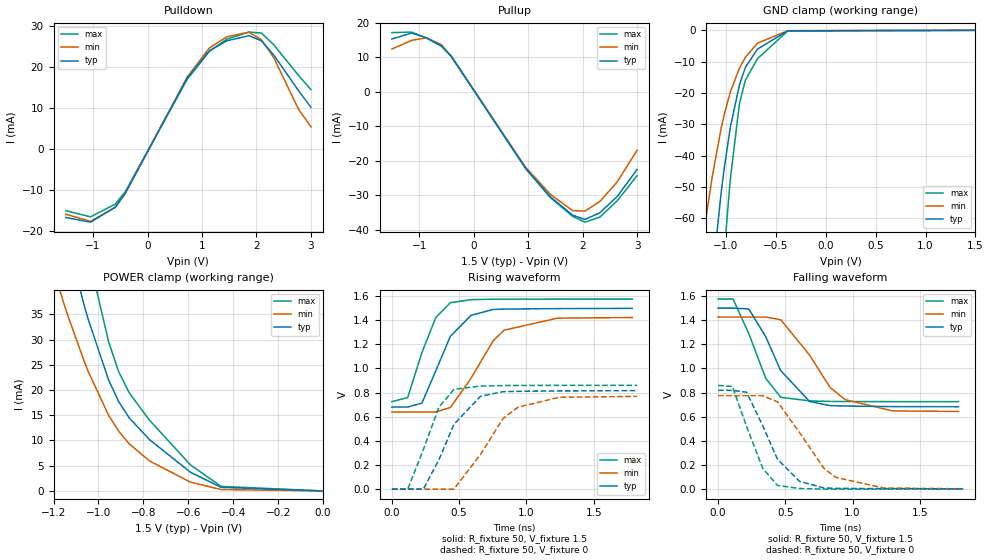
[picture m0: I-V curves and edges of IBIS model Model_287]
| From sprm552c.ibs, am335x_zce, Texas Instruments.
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| Model based on original model for BCSHTLTCSCDVPBFZ_SSDHV
|   Sub model SR10_9MA_5PER_1P5
[model]   Model_287
|[Description]  [1.5V-3-STATE-NOTERM-SR10:9MA, IND, 5%]
|   Fast slew rate (SR[1:0] = "10"), 0.88 * RExt = 1.125 * Iout
|   (I[2:0] = "100"), 9mA nominal with Rext = 50R,ODT off (ODT[1:0]
|   = "00") CMOS mode,Industrial temperature range (-40C to 125C,
|   25C nominal),5% power supply tolerance
|[Input Load]   NOTERM
|[Output Drive] SR10:9MA
|Voltage   1.5V
|Mode   3-STATE
Model_type   3-state
Polarity   Non-Inverting
Enable   Active-Low
Cref =  15pF
Rref =  100.0000M
Vref =  0V
Vmeas =  0.75
C_comp   1.865048p   1.679967p   1.989968p
[Temperature Range]   25   125   -40
[Voltage Range]   1.5   1.425   1.575
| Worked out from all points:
|   slope of the pulldown table from 0 to 0.225 V, typ, clamps not added: 38.4 ohm
|   slope of the pullup table from 0 to 0.225 V, typ, clamps not added: 40.1 ohm
|   GND clamp passes 1 mA (typ) near -0.49 V on its own axis
|   POWER clamp passes 1 mA (typ) near -0.47 V on its own axis
|   rising waveform, R_fixture 50, V_fixture 1.5: 20-80 % time 196ps typ, 264ps min, 158ps max; typ from 0.68 V to 1.5 V
|   rising waveform, R_fixture 50, V_fixture 0: 20-80 % time 213ps typ, 268ps min, 167ps max; typ from 0 V to 0.816 V
|   falling waveform, R_fixture 50, V_fixture 1.5: 20-80 % time 226ps typ, 286ps min, 174ps max; typ from 1.5 V to 0.682 V
|   falling waveform, R_fixture 50, V_fixture 0: 20-80 % time 212ps typ, 282ps min, 168ps max; typ from 0.818 V to 0.003 V
[POWER_clamp]
-1.5V     126mA      88.76mA    168.8mA
-1.242V   69.8mA     49.43mA    94.36mA
-1.136V   49.16mA    34.7mA     67.53mA
-1.061V   36.35mA    25.39mA    50.04mA
-1.045V   33.92mA    23.62mA    46.67mA
-954.5mV  21.93mA    14.94mA    29.52mA
-909.1mV  17.64mA    11.78mA    23.53mA
-863.6mV  14.51mA    9.346mA    19.48mA
-772.7mV  10.16mA    5.937mA    14mA
-590.9mV  3.705mA    1.741mA    5.168mA
-454.5mV  710.5uA    279.1uA    892.2uA
0V        1.424nA    14.75nA    2.169nA
[Pulldown]
-1.5V     -16.73mA   -15.94mA   -15.06mA
-1.045V   -17.88mA   -17.65mA   -16.57mA
-590.9mV  -14.22mA   -14.22mA   -13.46mA
-409.1mV  -10.81mA   -10.82mA   -10.45mA
727.3mV   17.36mA    17.6mA     17.04mA
1.136V    24.04mA    24.73mA    23.94mA
1.455V    26.49mA    27.48mA    26.9mA
1.864V    27.75mA    28.61mA    28.63mA
2.091V    26.49mA    26.76mA    28.4mA
2.318V    23.02mA    22.38mA    25.53mA
2.773V    14.29mA    9.722mA    18.02mA
3V        10.24mA    5.474mA    14.57mA
[Pullup]
-1.5V     15.3mA     12.38mA    17.14mA
-1.136V   17.02mA    14.89mA    17.29mA
-863.6mV  15.6mA     15.63mA    15.55mA
-590.9mV  13.28mA    13.62mA    13.2mA
-409.1mV  10.24mA    10.23mA    10.22mA
954.5mV   -22.23mA   -21.9mA    -22.32mA
1.409V    -30.51mA   -29.79mA   -30.74mA
1.818V    -35.84mA   -34.51mA   -36.18mA
2.045V    -37.08mA   -34.63mA   -37.87mA
2.318V    -35.11mA   -31.86mA   -36.38mA
2.636V    -30.42mA   -26.15mA   -31.65mA
3V        -22.57mA   -17.01mA   -24.39mA
[GND_clamp]
-1.5V     -219.3mA   -131.6mA   -364.3mA
-1.288V   -134.4mA   -79.74mA   -225.6mA
-1.258V   -122.9mA   -72.77mA   -206.3mA
-1.136V   -79.27mA   -46.88mA   -132.4mA
-1.045V   -51.5mA    -31.06mA   -84.11mA
-1.015V   -44.02mA   -26.9mA    -70.91mA
-954.5mV  -31.01mA   -19.7mA    -47.55mA
-863.6mV  -17.48mA   -12.16mA   -23.55mA
-803mV    -11.81mA   -8.597mA   -15.85mA
-681.8mV  -5.986mA   -4.096mA   -9.026mA
-378.8mV  -126.2uA   -131.8uA   -179.7uA
1.5V      1.424nA    36.56nA    1.506nA
[Ramp]
dV/dt_f 0.49384899/0.22739462n 0.47285938/0.28847369n  0.5115105/0.17463209n
dV/dt_r 0.49361868/0.21533483n 0.46695631/0.27014751n 0.51779375/0.16762283n
R_load = 50
[Rising Waveform]
R_fixture = 50
V_fixture = 1.5
V_fixture_min = 1.425
V_fixture_max = 1.575
0s        680.2mV    639.4mV    725.3mV
117.1ps   680.2mV    639.4mV    758.6mV
223.1ps   713.3mV    639.4mV    1.132V
326.1ps   980.9mV    639.6mV    1.422V
434.5ps   1.266V     676.6mV    1.545V
587.8ps   1.44V      918.1mV    1.57V
752ps     1.489V     1.228V     1.574V
833ps     1.492V     1.317V     1.574V
1.231ns   1.496V     1.417V     1.575V
1.787ns   1.498V     1.422V     1.575V
[Rising Waveform]
R_fixture = 50
V_fixture = 0
V_fixture_min = 0
V_fixture_max = 0
0s        0V         0V         0V
117.6ps   0V         0V         0V
233.6ps   0V         0V         327.5mV
349.7ps   244.4mV    0V         679.8mV
460.9ps   537.3mV    0V         827mV
658.1ps   769.6mV    287.2mV    854.1mV
825.5ps   807.9mV    584.4mV    858.1mV
936ps     810.7mV    678.6mV    859.2mV
1.242ns   814mV      760.8mV    859.9mV
1.822ns   816.1mV    768.9mV    859.8mV
[Falling Waveform]
R_fixture = 50
V_fixture = 1.5
V_fixture_min = 1.425
V_fixture_max = 1.575
0s        1.499V     1.425V     1.574V
111.6ps   1.499V     1.425V     1.574V
228.7ps   1.492V     1.425V     1.288V
354.2ps   1.262V     1.425V     918.2mV
465.8ps   981.5mV    1.403V     760.8mV
680.5ps   726.2mV    1.11V      730.8mV
833.6ps   691.5mV    840.6mV    726.5mV
946.7ps   688.3mV    740.6mV    725.4mV
1.299ns   683.7mV    647.7mV    724.9mV
1.787ns   682.2mV    643.4mV    724.4mV
[Falling Waveform]
R_fixture = 50
V_fixture = 0
V_fixture_min = 0
V_fixture_max = 0
0s        818.4mV    774mV      859.3mV
107.2ps   818.4mV    774mV      850mV
212ps     802.8mV    774mV      520.3mV
331.9ps   526.4mV    774mV      172.9mV
441.5ps   248.5mV    723.7mV    31.12mV
605.3ps   64.7mV     469.6mV    5.478mV
788.2ps   9.722mV    170.4mV    0V
876.7ps   6.959mV    97.21mV    0V
1.231ns   3.935mV    9.45mV     0V
1.822ns   2.676mV    3.352mV    0V
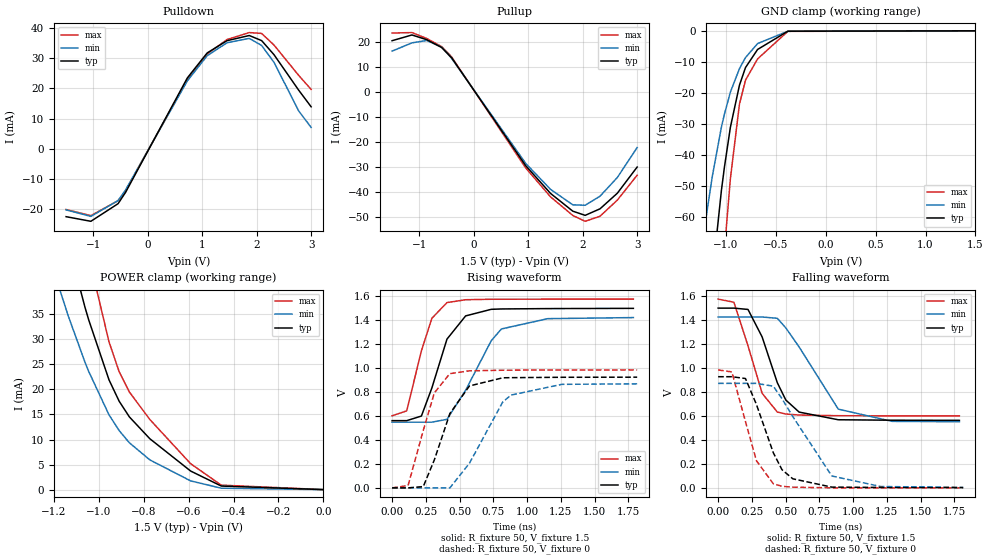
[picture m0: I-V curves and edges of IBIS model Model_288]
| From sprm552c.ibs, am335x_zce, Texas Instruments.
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| Model based on original model for BCSHTLTCSCDVPBFZ_SSDHV
|   Sub model SR10_12MA_5PER_1P5
[model]   Model_288
|[Description]  [1.5V-3-STATE-NOTERM-SR10:12MA, IND, 5%]
|   Fast slew rate (SR[1:0] = "10"), 0.67 * RExt = 1.500 * Iout
|   (I[2:0] = "111"), 12mA nominal with Rext = 50R,ODT off (ODT[1:0]
|   = "00") CMOS mode,Industrial temperature range (-40C to 125C,
|   25C nominal),5% power supply tolerance
|[Input Load]   NOTERM
|[Output Drive] SR10:12MA
|Voltage   1.5V
|Mode   3-STATE
Model_type   3-state
Polarity   Non-Inverting
Enable   Active-Low
Cref =  15pF
Rref =  100.0000M
Vref =  0V
Vmeas =  0.75
C_comp   1.865048p   1.679967p   1.989968p
[Temperature Range]   25   125   -40
[Voltage Range]   1.5   1.425   1.575
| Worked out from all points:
|   slope of the pulldown table from 0 to 0.225 V, typ, clamps not added: 28.3 ohm
|   slope of the pullup table from 0 to 0.225 V, typ, clamps not added: 30.1 ohm
|   GND clamp passes 1 mA (typ) near -0.49 V on its own axis
|   POWER clamp passes 1 mA (typ) near -0.47 V on its own axis
|   rising waveform, R_fixture 50, V_fixture 1.5: 20-80 % time 163ps typ, 245ps min, 131ps max; typ from 0.561 V to 1.5 V
|   rising waveform, R_fixture 50, V_fixture 0: 20-80 % time 177ps typ, 250ps min, 140ps max; typ from 0 V to 0.924 V
|   falling waveform, R_fixture 50, V_fixture 1.5: 20-80 % time 184ps typ, 269ps min, 150ps max; typ from 1.5 V to 0.563 V
|   falling waveform, R_fixture 50, V_fixture 0: 20-80 % time 180ps typ, 277ps min, 145ps max; typ from 0.927 V to 0.003 V
[POWER_clamp]
-1.5V     126mA      88.76mA    168.8mA
-1.242V   69.8mA     49.43mA    94.36mA
-1.136V   49.16mA    34.7mA     67.53mA
-1.061V   36.35mA    25.39mA    50.04mA
-1.045V   33.92mA    23.62mA    46.67mA
-954.5mV  21.93mA    14.94mA    29.52mA
-909.1mV  17.64mA    11.78mA    23.53mA
-863.6mV  14.51mA    9.346mA    19.48mA
-772.7mV  10.16mA    5.937mA    14mA
-590.9mV  3.705mA    1.741mA    5.168mA
-454.5mV  710.5uA    279.1uA    892.2uA
0V        1.424nA    14.75nA    2.169nA
[Pulldown]
-1.5V     -22.72mA   -20.45mA   -20.34mA
-1.045V   -24.26mA   -22.63mA   -22.37mA
-545.5mV  -18.39mA   -17.36mA   -17.39mA
-409.1mV  -14.66mA   -13.87mA   -14.1mA
727.3mV   23.54mA    22.55mA    22.99mA
1.091V    31.85mA    30.92mA    31.48mA
1.455V    35.94mA    35.24mA    36.31mA
1.864V    37.66mA    36.7mA     38.64mA
2.091V    35.96mA    34.34mA    38.35mA
2.318V    31.27mA    28.72mA    34.48mA
2.773V    19.4mA     12.48mA    24.34mA
3V        13.9mA     7.024mA    19.68mA
[Pullup]
-1.5V     20.4mA     16.24mA    23.46mA
-1.136V   22.69mA    19.53mA    23.65mA
-863.6mV  20.8mA     20.49mA    21.28mA
-590.9mV  17.69mA    17.85mA    18.05mA
-409.1mV  13.64mA    13.4mA     13.98mA
954.5mV   -29.62mA   -28.69mA   -30.52mA
1.409V    -40.66mA   -39.04mA   -42.03mA
1.818V    -47.77mA   -45.23mA   -49.49mA
2.045V    -49.44mA   -45.41mA   -51.82mA
2.318V    -46.83mA   -41.78mA   -49.8mA
2.636V    -40.59mA   -34.31mA   -43.34mA
3V        -30.12mA   -22.33mA   -33.4mA
[GND_clamp]
-1.5V     -219.3mA   -131.6mA   -364.3mA
-1.288V   -134.4mA   -79.74mA   -225.6mA
-1.258V   -122.9mA   -72.77mA   -206.3mA
-1.136V   -79.27mA   -46.88mA   -132.4mA
-1.045V   -51.5mA    -31.06mA   -84.11mA
-1.015V   -44.02mA   -26.9mA    -70.91mA
-954.5mV  -31.01mA   -19.7mA    -47.55mA
-863.6mV  -17.48mA   -12.16mA   -23.55mA
-803mV    -11.81mA   -8.597mA   -15.85mA
-681.8mV  -5.986mA   -4.096mA   -9.026mA
-378.8mV  -126.2uA   -131.8uA   -179.7uA
1.5V      1.424nA    36.56nA    1.506nA
[Ramp]
dV/dt_f 0.56589434/0.18591263n 0.52840037/0.26941912n 0.58618677/0.15022392n
dV/dt_r 0.55954959/0.17890593n 0.52678251/0.25332231n 0.59291047/0.14023083n
R_load = 50
[Rising Waveform]
R_fixture = 50
V_fixture = 1.5
V_fixture_min = 1.425
V_fixture_max = 1.575
0s        560.9mV    548.2mV    601.3mV
108.3ps   560.9mV    548.2mV    642.6mV
217.1ps   599.4mV    548.2mV    1.144V
294.5ps   833.4mV    548.2mV    1.415V
406.3ps   1.241V     571.8mV    1.546V
544.5ps   1.435V     814.2mV    1.57V
734.2ps   1.49V      1.228V     1.574V
809.6ps   1.493V     1.326V     1.574V
1.153ns   1.496V     1.412V     1.575V
1.787ns   1.498V     1.421V     1.575V
[Rising Waveform]
R_fixture = 50
V_fixture = 0
V_fixture_min = 0
V_fixture_max = 0
0s        0V         0V         0V
118.3ps   0V         0V         19.1mV
230.7ps   10.64mV    0V         478.6mV
313ps     233.8mV    0V         793mV
427.7ps   619.7mV    0V         953.1mV
572.5ps   850.4mV    204.6mV    976.7mV
819.9ps   918.5mV    717.3mV    981.6mV
880.8ps   919.6mV    774.3mV    982.3mV
1.257ns   922.8mV    863.9mV    984.3mV
1.815ns   923.6mV    868.1mV    984.4mV
[Falling Waveform]
R_fixture = 50
V_fixture = 1.5
V_fixture_min = 1.425
V_fixture_max = 1.575
0s        1.499V     1.425V     1.574V
116.8ps   1.499V     1.425V     1.548V
221.2ps   1.488V     1.425V     1.185V
325.8ps   1.259V     1.425V     788.9mV
438.4ps   876.7mV    1.414V     632.3mV
501.4ps   732.3mV    1.334V     615.9mV
599.9ps   631.9mV    1.175V     607.2mV
889.8ps   568mV      656.5mV    601.8mV
1.289ns   564.1mV    554.5mV    600.4mV
1.787ns   563mV      551.6mV    600.3mV
[Falling Waveform]
R_fixture = 50
V_fixture = 0
V_fixture_min = 0
V_fixture_max = 0
0s        927mV      871.3mV    983.4mV
101.6ps   927mV      871.3mV    967mV
202.5ps   911.8mV    871.3mV    553.4mV
283.6ps   695.8mV    871.3mV    226.5mV
408.6ps   293mV      847.9mV    34.2mV
473.1ps   151mV      743.8mV    12.66mV
553.3ps   75.46mV    594.1mV    5.761mV
842ps     6.198mV    98.94mV    0V
1.203ns   3.402mV    11.35mV    0V
1.815ns   2.56mV     3.268mV    0V
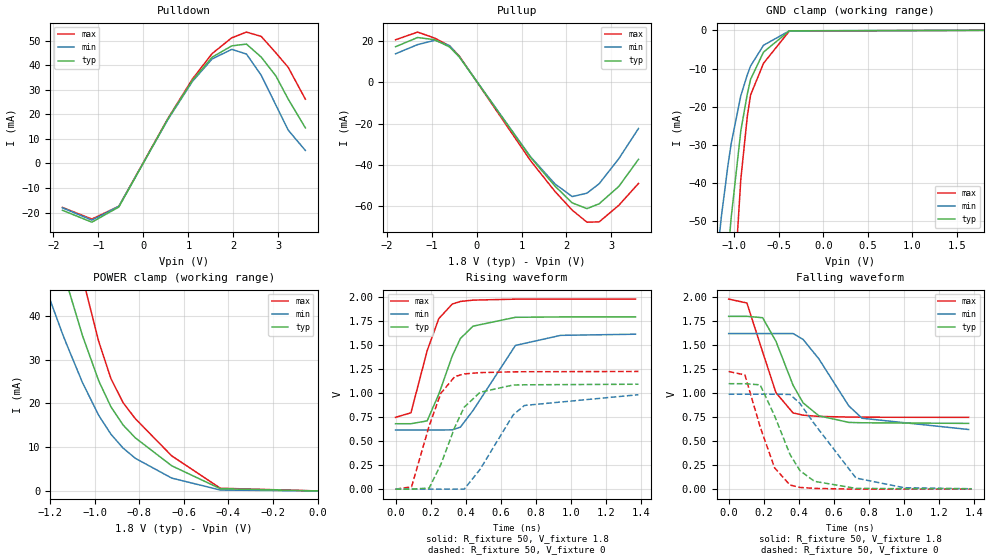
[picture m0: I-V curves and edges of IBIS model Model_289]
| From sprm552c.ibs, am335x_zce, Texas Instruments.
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| Model based on original model for BCSHTLTCSCDVPBFZ_SSDHV
|   Sub model SR01_12MA_10PER_1P8
[model]   Model_289
|[Description]  [1.8V-3-STATE-NOTERM-SR01:12MA, IND, 10%]
|   Slow slew rate (SR[1:0] = "01"), 0.67 * RExt = 1.500 * Iout
|   (I[2:0] = "111"), 12mA nominal with Rext = 50R,ODT off (ODT[1:0]
|   = "00") CMOS mode,Industrial temperature range (-40C to 125C,
|   25C nominal),10% power supply tolerance
|[Input Load]   NOTERM
|[Output Drive] SR01:12MA
|Voltage   1.8V
|Mode   3-STATE
Model_type   3-state
Polarity   Non-Inverting
Enable   Active-Low
Cref =  15pF
Rref =  100.0000M
Vref =  0V
Vmeas =  0.9
C_comp   1.851324p   1.663768p   1.973575p
[Temperature Range]   25   125   -40
[Voltage Range]   1.8   1.62   1.98
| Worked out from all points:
|   slope of the pulldown table from 0 to 0.27 V, typ, clamps not added: 29.2 ohm
|   slope of the pullup table from 0 to 0.27 V, typ, clamps not added: 31.3 ohm
|   GND clamp passes 1 mA (typ) near -0.49 V on its own axis
|   POWER clamp passes 1 mA (typ) near -0.47 V on its own axis
|   rising waveform, R_fixture 50, V_fixture 1.8: 20-80 % time 141ps typ, 196ps min, 114ps max; typ from 0.682 V to 1.79 V
|   rising waveform, R_fixture 50, V_fixture 0: 20-80 % time 150ps typ, 198ps min, 121ps max; typ from 0 V to 1.09 V
|   falling waveform, R_fixture 50, V_fixture 1.8: 20-80 % time 160ps typ, 213ps min, 125ps max; typ from 1.8 V to 0.685 V
|   falling waveform, R_fixture 50, V_fixture 0: 20-80 % time 155ps typ, 219ps min, 125ps max; typ from 1.1 V to 0.005 V
[POWER_clamp]
-1.8V     194.9mA    137.1mA    262.8mA
-1.236V   68.49mA    48.51mA    92.67mA
-1.145V   50.76mA    35.86mA    69.65mA
-1.127V   47.56mA    33.54mA    65.34mA
-1.055V   35.4mA     24.69mA    48.69mA
-981.8mV  25.06mA    17.2mA     34.01mA
-927.3mV  19.17mA    12.93mA    25.61mA
-872.7mV  15.03mA    9.767mA    20.12mA
-818.2mV  12.12mA    7.45mA     16.5mA
-654.5mV  5.738mA    2.93mA     8.003mA
-436.4mV  508.2uA    199.4uA    613uA
0V        2.273nA    15.95nA    16.67nA
[Pulldown]
-1.8V     -19.04mA   -18.02mA   -17.88mA
-1.145V   -23.87mA   -23.03mA   -22.59mA
-545.5mV  -17.69mA   -17.39mA   -17.39mA
545.5mV   18.16mA    17.9mA     18.33mA
1.091V    33.8mA     33.39mA    34.37mA
1.527V    43.21mA    42.5mA     44.68mA
1.964V    47.83mA    46.41mA    51.1mA
2.291V    48.55mA    44.5mA     53.43mA
2.618V    43.28mA    35.9mA     51.68mA
2.945V    35.6mA     23.75mA    44.98mA
3.218V    26.2mA     13.58mA    39.11mA
3.6V      14.49mA    5.303mA    26.15mA
[Pullup]
-1.8V     17.15mA    13.74mA    20.51mA
-1.309V   21.6mA     18.18mA    24.22mA
-927.3mV  20.52mA    20.27mA    21.29mA
-600mV    17.03mA    17.65mA    17.57mA
-381.8mV  12.19mA    12.29mA    12.62mA
1.2V      -36.27mA   -35.99mA   -37.86mA
1.745V    -50.17mA   -49.12mA   -52.76mA
2.127V    -58.27mA   -55.22mA   -61.77mA
2.455V    -61.03mA   -53.58mA   -67.59mA
2.727V    -58.68mA   -48.99mA   -67.43mA
3.164V    -50.29mA   -36.88mA   -59.41mA
3.6V      -37.24mA   -22.35mA   -48.89mA
[GND_clamp]
-1.8V     -346.1mA   -209.3mA   -568.3mA
-1.327V   -149.7mA   -89.03mA   -250.9mA
-1.291V   -135.6mA   -80.47mA   -227.5mA
-1.145V   -82.35mA   -48.67mA   -137.7mA
-1.073V   -59.44mA   -35.55mA   -97.96mA
-1.036V   -49.1mA    -29.72mA   -79.9mA
-927.3mV  -26.31mA   -17.11mA   -38.99mA
-854.5mV  -16.67mA   -11.64mA   -22.56mA
-818.2mV  -12.86mA   -9.351mA   -16.98mA
-672.7mV  -5.705mA   -3.913mA   -8.624mA
-381.8mV  -120.4uA   -129uA     -167.4uA
1.8V      2.273nA    454nA      6.646nA
[Ramp]
dV/dt_f 0.67303502/0.16130227n 0.60434183/0.21447386n 0.74092762/0.1245004n
dV/dt_r 0.66106991/0.15148608n  0.5960643/0.19969033n 0.73722553/0.12097496n
R_load = 50
[Rising Waveform]
R_fixture = 50
V_fixture = 1.8
V_fixture_min = 1.62
V_fixture_max = 1.98
0s        681.6mV    616mV      748.2mV
87.9ps    681.6mV    616mV      795.4mV
180.5ps   711.2mV    616mV      1.442V
246.8ps   989mV      616mV      1.776V
323.7ps   1.387V     617.7mV    1.928V
370.1ps   1.569V     645.9mV    1.955V
442.7ps   1.698V     820.1mV    1.969V
684.5ps   1.79V      1.497V     1.979V
943ps     1.794V     1.602V     1.98V
1.37ns    1.794V     1.614V     1.98V
[Rising Waveform]
R_fixture = 50
V_fixture = 0
V_fixture_min = 0
V_fixture_max = 0
0s        0V         0V         0V
91.5ps    0V         0V         24.53mV
192.2ps   12.09mV    0V         660.9mV
258.6ps   257.3mV    0V         998.2mV
338.2ps   645.4mV    0V         1.173V
391.9ps   853.6mV    0V         1.2V
482.3ps   1.009V     205.6mV    1.214V
671.9ps   1.085V     774.4mV    1.222V
736ps     1.087V     871.9mV    1.223V
1.387ns   1.093V     983.8mV    1.226V
[Falling Waveform]
R_fixture = 50
V_fixture = 1.8
V_fixture_min = 1.62
V_fixture_max = 1.98
0s        1.799V     1.62V      1.979V
104.1ps   1.799V     1.62V      1.938V
193.8ps   1.785V     1.62V      1.429V
270ps     1.539V     1.62V      1.004V
367.6ps   1.082V     1.62V      793.6mV
424.8ps   898.6mV    1.559V     770.3mV
514.7ps   763.8mV    1.357V     757.4mV
685.8ps   695mV      866.8mV    750.5mV
761.5ps   691.2mV    738.4mV    749.1mV
1.37ns    684.7mV    621.1mV    747.3mV
[Falling Waveform]
R_fixture = 50
V_fixture = 0
V_fixture_min = 0
V_fixture_max = 0
0s        1.098V     988.6mV    1.225V
92.9ps    1.098V     988.6mV    1.189V
179.7ps   1.086V     988.6mV    648.3mV
262.2ps   763.1mV    988.6mV    221.8mV
350.3ps   360.7mV    985.9mV    43.01mV
406.9ps   193.3mV    892.8mV    17.97mV
489.7ps   81.49mV    678.7mV    7.863mV
726.9ps   8.288mV    115.8mV    0V
1.002ns   4.952mV    15.05mV    0V
1.387ns   4.624mV    4.087mV    0V
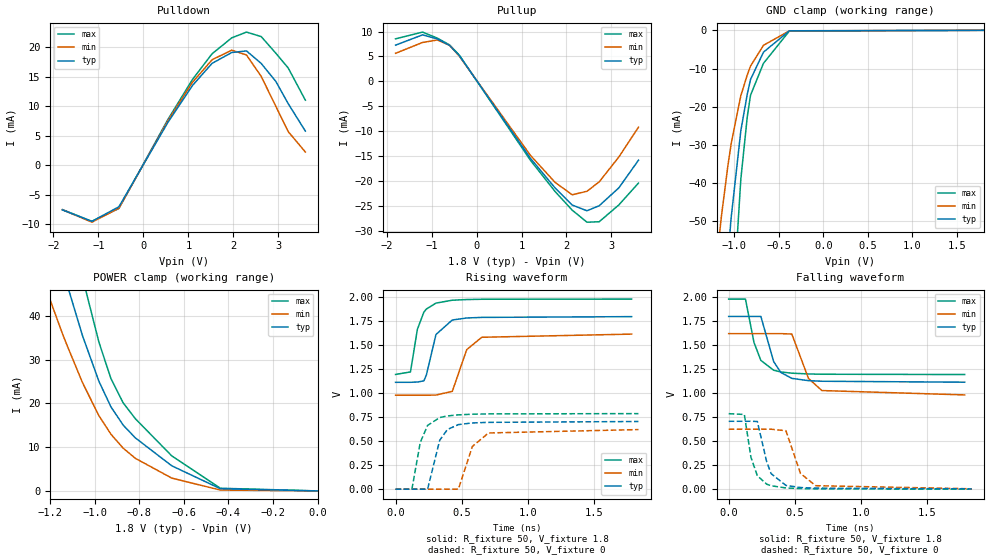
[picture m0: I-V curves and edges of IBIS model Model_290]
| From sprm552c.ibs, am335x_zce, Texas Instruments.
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| Model based on original model for BCSHTLTCSCDVPBFZ_SSDHV
|   Sub model SR00_5MA_10PER_1P8
[model]   Model_290
|[Description]  [1.8V-3-STATE-NOTERM-SR00:5MA, IND, 10%]
|   Fastest slew rate (SR[1:0] = "00"), 1.60 * RExt = 0.625 * Iout
|   (I[2:0] = "000"), 5mA nominal with Rext = 50R,ODT off (ODT[1:0]
|   = "00") CMOS mode,Industrial temperature range (-40C to 125C,
|   25C nominal),10% power supply tolerance
|[Input Load]   NOTERM
|[Output Drive] SR00:5MA
|Voltage   1.8V
|Mode   3-STATE
Model_type   3-state
Polarity   Non-Inverting
Enable   Active-Low
Cref =  15pF
Rref =  100.0000M
Vref =  0V
Vmeas =  0.9
C_comp   1.851324p   1.663768p   1.973575p
[Temperature Range]   25   125   -40
[Voltage Range]   1.8   1.62   1.98
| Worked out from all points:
|   slope of the pulldown table from 0 to 0.27 V, typ, clamps not added: 72.9 ohm
|   slope of the pullup table from 0 to 0.27 V, typ, clamps not added: 73.8 ohm
|   GND clamp passes 1 mA (typ) near -0.49 V on its own axis
|   POWER clamp passes 1 mA (typ) near -0.47 V on its own axis
|   rising waveform, R_fixture 50, V_fixture 1.8: 20-80 % time 81.6ps typ, 98.5ps min, 75.1ps max; typ from 1.11 V to 1.8 V
|   rising waveform, R_fixture 50, V_fixture 0: 20-80 % time 86.5ps typ, 97.1ps min, 79.9ps max; typ from 0 V to 0.705 V
|   falling waveform, R_fixture 50, V_fixture 1.8: 20-80 % time 97.7ps typ, 109ps min, 86.2ps max; typ from 1.8 V to 1.11 V
|   falling waveform, R_fixture 50, V_fixture 0: 20-80 % time 80.6ps typ, 90.8ps min, 71.7ps max; typ from 0.707 V to 0.003 V
[POWER_clamp]
-1.8V     194.9mA    137.1mA    262.8mA
-1.236V   68.49mA    48.51mA    92.67mA
-1.145V   50.76mA    35.86mA    69.65mA
-1.127V   47.56mA    33.54mA    65.34mA
-1.055V   35.4mA     24.69mA    48.69mA
-981.8mV  25.06mA    17.2mA     34.01mA
-927.3mV  19.17mA    12.93mA    25.61mA
-872.7mV  15.03mA    9.767mA    20.12mA
-818.2mV  12.12mA    7.45mA     16.5mA
-654.5mV  5.738mA    2.93mA     8.003mA
-436.4mV  508.2uA    199.4uA    613uA
0V        2.273nA    15.95nA    16.67nA
[Pulldown]
-1.8V     -7.609mA   -7.58mA    -7.557mA
-1.145V   -9.551mA   -9.696mA   -9.558mA
-545.5mV  -7.085mA   -7.33mA    -7.364mA
545.5mV   7.279mA    7.552mA    7.771mA
1.091V    13.54mA    14.08mA    14.56mA
1.527V    17.3mA     17.91mA    18.93mA
1.964V    19.14mA    19.54mA    21.63mA
2.291V    19.41mA    18.72mA    22.61mA
2.618V    17.29mA    15.09mA    21.85mA
2.945V    14.21mA    9.977mA    19.01mA
3.218V    10.46mA    5.707mA    16.52mA
3.6V      5.787mA    2.231mA    11.04mA
[Pullup]
-1.8V     7.273mA    5.641mA    8.54mA
-1.2V     9.332mA    7.808mA    9.888mA
-872.7mV  8.52mA     8.305mA    8.682mA
-600mV    7.23mA     7.256mA    7.329mA
-381.8mV  5.181mA    5.056mA    5.268mA
1.2V      -15.41mA   -14.81mA   -15.8mA
1.745V    -21.31mA   -20.2mA    -22.02mA
2.127V    -24.75mA   -22.69mA   -25.77mA
2.455V    -25.89mA   -21.99mA   -28.18mA
2.727V    -24.88mA   -20.1mA    -28.09mA
3.164V    -21.3mA    -15.12mA   -24.72mA
3.6V      -15.77mA   -9.16mA    -20.34mA
[GND_clamp]
-1.8V     -346.1mA   -209.3mA   -568.3mA
-1.327V   -149.7mA   -89.03mA   -250.9mA
-1.291V   -135.6mA   -80.47mA   -227.5mA
-1.145V   -82.35mA   -48.67mA   -137.7mA
-1.073V   -59.44mA   -35.55mA   -97.96mA
-1.036V   -49.1mA    -29.72mA   -79.9mA
-927.3mV  -26.31mA   -17.11mA   -38.99mA
-854.5mV  -16.67mA   -11.64mA   -22.56mA
-818.2mV  -12.86mA   -9.351mA   -16.98mA
-672.7mV  -5.705mA   -3.913mA   -8.624mA
-381.8mV  -120.4uA   -129uA     -167.4uA
1.8V      2.273nA    454nA      6.646nA
[Ramp]
dV/dt_f 0.41860083/98.719039p 0.39230721/0.11012704n 0.47544294/86.205327p
dV/dt_r 0.42891309/87.264868p 0.38134991/97.700896p 0.47561185/79.797039p
R_load = 50
[Rising Waveform]
R_fixture = 50
V_fixture = 1.8
V_fixture_min = 1.62
V_fixture_max = 1.98
0s        1.113V     978.3mV    1.195V
112.9ps   1.113V     978.3mV    1.221V
165.5ps   1.116V     978.3mV    1.666V
214.2ps   1.128V     978.3mV    1.843V
233.1ps   1.188V     978.3mV    1.876V
306.1ps   1.611V     980.3mV    1.938V
429.7ps   1.762V     1.019V     1.968V
538.7ps   1.783V     1.453V     1.975V
652.4ps   1.789V     1.582V     1.978V
1.787ns   1.797V     1.615V     1.98V
[Rising Waveform]
R_fixture = 50
V_fixture = 0
V_fixture_min = 0
V_fixture_max = 0
0s        0V         0V         0V
123.8ps   0V         0V         0V
187.2ps   0V         0V         487.7mV
242.6ps   0V         0V         663.9mV
334.4ps   509.5mV    0V         746.1mV
392.7ps   621.3mV    0V         762.6mV
475.7ps   672.5mV    0V         774mV
581.2ps   689.9mV    444.5mV    780.6mV
703.9ps   695.8mV    585.4mV    784.1mV
1.839ns   704.8mV    620.7mV    786.9mV
[Falling Waveform]
R_fixture = 50
V_fixture = 1.8
V_fixture_min = 1.62
V_fixture_max = 1.98
0s        1.799V     1.62V      1.98V
127ps     1.799V     1.62V      1.98V
191.6ps   1.799V     1.62V      1.528V
243.7ps   1.799V     1.62V      1.341V
340.2ps   1.33V      1.62V      1.239V
394.5ps   1.216V     1.62V      1.221V
477.9ps   1.154V     1.616V     1.208V
604.3ps   1.13V      1.153V     1.2V
705.7ps   1.124V     1.027V     1.197V
1.787ns   1.114V     981.6mV    1.194V
[Falling Waveform]
R_fixture = 50
V_fixture = 0
V_fixture_min = 0
V_fixture_max = 0
0s        707mV      624.6mV    786.4mV
118.6ps   707mV      624.6mV    778mV
168.7ps   707mV      624.6mV    331.4mV
217ps     705.1mV    624.6mV    139.6mV
288ps     284.3mV    624.6mV    52.12mV
321.4ps   161.7mV    624.6mV    35.46mV
433.5ps   38.9mV     608.7mV    12.77mV
543.5ps   16.92mV    163.8mV    6.03mV
658.4ps   10.72mV    36.3mV     3.088mV
1.839ns   2.894mV    3.845mV    0V
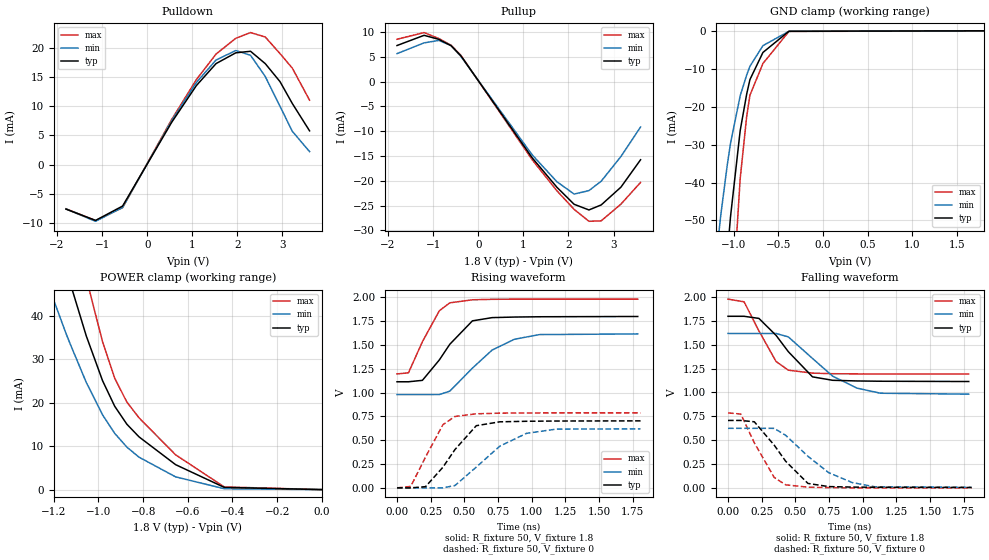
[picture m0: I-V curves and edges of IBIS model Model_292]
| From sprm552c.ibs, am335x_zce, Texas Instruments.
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| Model based on original model for BCSHTLTCSCDVPBFZ_SSDHV
|   Sub model SR01_5MA_10PER_1P8
[model]   Model_292
|[Description]  [1.8V-3-STATE-NOTERM-SR01:5MA, IND, 10%]
|   Slow slew rate (SR[1:0] = "01"), 1.60 * RExt = 0.625 * Iout
|   (I[2:0] = "000"), 5mA nominal with Rext = 50R,ODT off (ODT[1:0]
|   = "00") CMOS mode,Industrial temperature range (-40C to 125C,
|   25C nominal),10% power supply tolerance
|[Input Load]   NOTERM
|[Output Drive] SR01:5MA
|Voltage   1.8V
|Mode   3-STATE
Model_type   3-state
Polarity   Non-Inverting
Enable   Active-Low
Cref =  15pF
Rref =  100.0000M
Vref =  0V
Vmeas =  0.9
C_comp   1.851324p   1.663768p   1.973575p
[Temperature Range]   25   125   -40
[Voltage Range]   1.8   1.62   1.98
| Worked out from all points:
|   slope of the pulldown table from 0 to 0.27 V, typ, clamps not added: 72.9 ohm
|   slope of the pullup table from 0 to 0.27 V, typ, clamps not added: 73.8 ohm
|   GND clamp passes 1 mA (typ) near -0.49 V on its own axis
|   POWER clamp passes 1 mA (typ) near -0.47 V on its own axis
|   rising waveform, R_fixture 50, V_fixture 1.8: 20-80 % time 206ps typ, 296ps min, 161ps max; typ from 1.11 V to 1.8 V
|   rising waveform, R_fixture 50, V_fixture 0: 20-80 % time 212ps typ, 317ps min, 171ps max; typ from 0 V to 0.703 V
|   falling waveform, R_fixture 50, V_fixture 1.8: 20-80 % time 227ps typ, 324ps min, 175ps max; typ from 1.8 V to 1.11 V
|   falling waveform, R_fixture 50, V_fixture 0: 20-80 % time 222ps typ, 320ps min, 176ps max; typ from 0.707 V to 0.004 V
[POWER_clamp]
-1.8V     194.9mA    137.1mA    262.8mA
-1.236V   68.49mA    48.51mA    92.67mA
-1.145V   50.76mA    35.86mA    69.65mA
-1.127V   47.56mA    33.54mA    65.34mA
-1.055V   35.4mA     24.69mA    48.69mA
-981.8mV  25.06mA    17.2mA     34.01mA
-927.3mV  19.17mA    12.93mA    25.61mA
-872.7mV  15.03mA    9.767mA    20.12mA
-818.2mV  12.12mA    7.45mA     16.5mA
-654.5mV  5.738mA    2.93mA     8.003mA
-436.4mV  508.2uA    199.4uA    613uA
0V        2.273nA    15.95nA    16.67nA
[Pulldown]
-1.8V     -7.609mA   -7.58mA    -7.557mA
-1.145V   -9.551mA   -9.696mA   -9.558mA
-545.5mV  -7.085mA   -7.33mA    -7.364mA
545.5mV   7.279mA    7.552mA    7.771mA
1.091V    13.54mA    14.08mA    14.56mA
1.527V    17.3mA     17.91mA    18.93mA
1.964V    19.14mA    19.54mA    21.63mA
2.291V    19.41mA    18.72mA    22.61mA
2.618V    17.29mA    15.09mA    21.85mA
2.945V    14.21mA    9.977mA    19.01mA
3.218V    10.46mA    5.707mA    16.52mA
3.6V      5.787mA    2.231mA    11.04mA
[Pullup]
-1.8V     7.273mA    5.641mA    8.54mA
-1.2V     9.332mA    7.808mA    9.888mA
-872.7mV  8.52mA     8.305mA    8.682mA
-600mV    7.23mA     7.256mA    7.329mA
-381.8mV  5.181mA    5.056mA    5.268mA
1.2V      -15.41mA   -14.81mA   -15.8mA
1.745V    -21.31mA   -20.2mA    -22.02mA
2.127V    -24.75mA   -22.69mA   -25.77mA
2.455V    -25.89mA   -21.99mA   -28.18mA
2.727V    -24.88mA   -20.1mA    -28.09mA
3.164V    -21.3mA    -15.12mA   -24.72mA
3.6V      -15.77mA   -9.16mA    -20.34mA
[GND_clamp]
-1.8V     -346.1mA   -209.3mA   -568.3mA
-1.327V   -149.7mA   -89.03mA   -250.9mA
-1.291V   -135.6mA   -80.47mA   -227.5mA
-1.145V   -82.35mA   -48.67mA   -137.7mA
-1.073V   -59.44mA   -35.55mA   -97.96mA
-1.036V   -49.1mA    -29.72mA   -79.9mA
-927.3mV  -26.31mA   -17.11mA   -38.99mA
-854.5mV  -16.67mA   -11.64mA   -22.56mA
-818.2mV  -12.86mA   -9.351mA   -16.98mA
-672.7mV  -5.705mA   -3.913mA   -8.624mA
-381.8mV  -120.4uA   -129uA     -167.4uA
1.8V      2.273nA    454nA      6.646nA
[Ramp]
dV/dt_f  0.4133209/0.22944922n 0.38531911/0.32739304n 0.47201226/0.17493554n
dV/dt_r 0.42511617/0.21442698n 0.37500571/0.32048232n 0.47290222/0.17120275n
R_load = 50
[Rising Waveform]
R_fixture = 50
V_fixture = 1.8
V_fixture_min = 1.62
V_fixture_max = 1.98
0s        1.113V     978.4mV    1.195V
85.1ps    1.113V     978.4mV    1.207V
188.7ps   1.128V     978.4mV    1.534V
314.2ps   1.342V     979mV      1.858V
391.6ps   1.506V     1.014V     1.941V
559.7ps   1.752V     1.256V     1.973V
706.2ps   1.786V     1.446V     1.978V
872ps     1.792V     1.559V     1.98V
1.057ns   1.795V     1.608V     1.98V
1.787ns   1.798V     1.615V     1.98V
[Rising Waveform]
R_fixture = 50
V_fixture = 0
V_fixture_min = 0
V_fixture_max = 0
0s        0V         0V         0V
102.2ps   0V         0V         15.15mV
211.9ps   12.53mV    0V         324mV
341ps     216.7mV    0V         663.2mV
430.3ps   402.2mV    24.45mV    749mV
588.6ps   652.3mV    217.8mV    776.9mV
762.8ps   692.8mV    437.5mV    783.8mV
961.6ps   698.6mV    572mV      786mV
1.182ns   701.2mV    616.1mV    786.7mV
1.808ns   702.8mV    619.2mV    786.9mV
[Falling Waveform]
R_fixture = 50
V_fixture = 1.8
V_fixture_min = 1.62
V_fixture_max = 1.98
0s        1.799V     1.619V     1.979V
119.3ps   1.799V     1.619V     1.951V
229.3ps   1.777V     1.619V     1.646V
356.7ps   1.599V     1.619V     1.325V
447.7ps   1.428V     1.583V     1.234V
627.2ps   1.164V     1.357V     1.203V
776.1ps   1.128V     1.172V     1.197V
957.1ps   1.121V     1.046V     1.195V
1.131ns   1.118V     992.3mV    1.194V
1.787ns   1.115V     982.5mV    1.194V
[Falling Waveform]
R_fixture = 50
V_fixture = 0
V_fixture_min = 0
V_fixture_max = 0
0s        706.9mV    624.3mV    786.1mV
94.9ps    706.9mV    624.3mV    774.1mV
195.2ps   692.9mV    624.3mV    472.9mV
343.2ps   447.3mV    623.9mV    108.7mV
427.8ps   279.4mV    551.3mV    31.83mV
593.5ps   46.3mV     330.9mV    7.346mV
747.3ps   13.28mV    159.3mV    2.871mV
923ps     8.018mV    55.03mV    0V
1.088ns   6.256mV    11.66mV    0V
1.808ns   3.808mV    6.355mV    0V
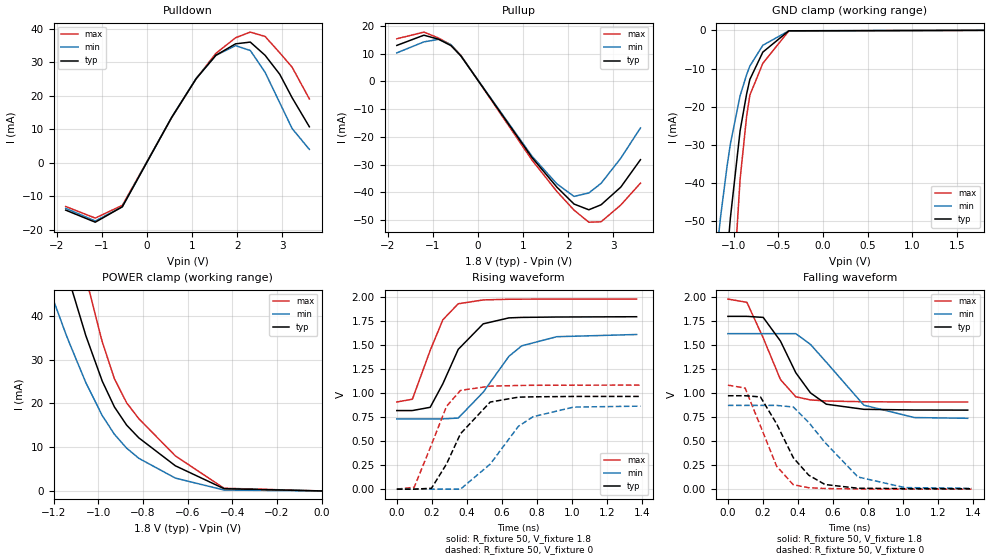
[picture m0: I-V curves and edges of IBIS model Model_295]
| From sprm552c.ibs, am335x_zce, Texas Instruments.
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| Model based on original model for BCSHTLTCSCDVPBFZ_SSDHV
|   Sub model SR01_9MA_10PER_1P8
[model]   Model_295
|[Description]  [1.8V-3-STATE-NOTERM-SR01:9MA, IND, 10%]
|   Slow slew rate (SR[1:0] = "01"), 0.88 * RExt = 1.125 * Iout
|   (I[2:0] = "100"), 9mA nominal with Rext = 50R,ODT off (ODT[1:0]
|   = "00") CMOS mode,Industrial temperature range (-40C to 125C,
|   25C nominal),10% power supply tolerance
|[Input Load]   NOTERM
|[Output Drive] SR01:9MA
|Voltage   1.8V
|Mode   3-STATE
Model_type   3-state
Polarity   Non-Inverting
Enable   Active-Low
Cref =  15pF
Rref =  100.0000M
Vref =  0V
Vmeas =  0.9
C_comp   1.851324p   1.663768p   1.973575p
[Temperature Range]   25   125   -40
[Voltage Range]   1.8   1.62   1.98
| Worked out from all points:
|   slope of the pulldown table from 0 to 0.27 V, typ, clamps not added: 39.3 ohm
|   slope of the pullup table from 0 to 0.27 V, typ, clamps not added: 41.3 ohm
|   GND clamp passes 1 mA (typ) near -0.49 V on its own axis
|   POWER clamp passes 1 mA (typ) near -0.47 V on its own axis
|   rising waveform, R_fixture 50, V_fixture 1.8: 20-80 % time 164ps typ, 217ps min, 131ps max; typ from 0.819 V to 1.8 V
|   rising waveform, R_fixture 50, V_fixture 0: 20-80 % time 175ps typ, 222ps min, 134ps max; typ from 0 V to 0.966 V
|   falling waveform, R_fixture 50, V_fixture 1.8: 20-80 % time 183ps typ, 240ps min, 146ps max; typ from 1.8 V to 0.823 V
|   falling waveform, R_fixture 50, V_fixture 0: 20-80 % time 182ps typ, 233ps min, 142ps max; typ from 0.973 V to 0.004 V
[POWER_clamp]
-1.8V     194.9mA    137.1mA    262.8mA
-1.236V   68.49mA    48.51mA    92.67mA
-1.145V   50.76mA    35.86mA    69.65mA
-1.127V   47.56mA    33.54mA    65.34mA
-1.055V   35.4mA     24.69mA    48.69mA
-981.8mV  25.06mA    17.2mA     34.01mA
-927.3mV  19.17mA    12.93mA    25.61mA
-872.7mV  15.03mA    9.767mA    20.12mA
-818.2mV  12.12mA    7.45mA     16.5mA
-654.5mV  5.738mA    2.93mA     8.003mA
-436.4mV  508.2uA    199.4uA    613uA
0V        2.273nA    15.95nA    16.67nA
[Pulldown]
-1.8V     -14.14mA   -13.59mA   -13.06mA
-1.145V   -17.74mA   -17.37mA   -16.51mA
-545.5mV  -13.15mA   -13.12mA   -12.71mA
545.5mV   13.5mA     13.52mA    13.41mA
1.091V    25.12mA    25.21mA    25.13mA
1.527V    32.11mA    32.07mA    32.67mA
1.964V    35.54mA    35.01mA    37.35mA
2.291V    36.06mA    33.55mA    39.05mA
2.618V    32.13mA    27.06mA    37.75mA
2.945V    26.42mA    17.9mA     32.85mA
3.218V    19.44mA    10.24mA    28.56mA
3.6V      10.76mA    3.999mA    19.09mA
[Pullup]
-1.8V     12.99mA    10.3mA     15.38mA
-1.2V     16.67mA    14.26mA    17.79mA
-872.7mV  15.21mA    15.17mA    15.62mA
-600mV    12.91mA    13.24mA    13.19mA
-381.8mV  9.242mA    9.222mA    9.473mA
1.2V      -27.49mA   -27.01mA   -28.42mA
1.745V    -38.03mA   -36.86mA   -39.59mA
2.127V    -44.16mA   -41.42mA   -46.35mA
2.455V    -46.24mA   -40.18mA   -50.71mA
2.727V    -44.44mA   -36.72mA   -50.57mA
3.164V    -38.07mA   -27.64mA   -44.53mA
3.6V      -28.19mA   -16.75mA   -36.64mA
[GND_clamp]
-1.8V     -346.1mA   -209.3mA   -568.3mA
-1.327V   -149.7mA   -89.03mA   -250.9mA
-1.291V   -135.6mA   -80.47mA   -227.5mA
-1.145V   -82.35mA   -48.67mA   -137.7mA
-1.073V   -59.44mA   -35.55mA   -97.96mA
-1.036V   -49.1mA    -29.72mA   -79.9mA
-927.3mV  -26.31mA   -17.11mA   -38.99mA
-854.5mV  -16.67mA   -11.64mA   -22.56mA
-818.2mV  -12.86mA   -9.351mA   -16.98mA
-672.7mV  -5.705mA   -3.913mA   -8.624mA
-381.8mV  -120.4uA   -129uA     -167.4uA
1.8V      2.273nA    454nA      6.646nA
[Ramp]
dV/dt_f 0.59000281/0.18474363n 0.53393203/0.24225658n 0.64459577/0.14609454n
dV/dt_r 0.58502125/0.17762335n 0.52494896/0.22419717n 0.65164147/0.13345265n
R_load = 50
[Rising Waveform]
R_fixture = 50
V_fixture = 1.8
V_fixture_min = 1.62
V_fixture_max = 1.98
0s        818.8mV    731.8mV    908.1mV
88.9ps    818.8mV    731.8mV    936.7mV
190.7ps   852.6mV    731.8mV    1.445V
263ps     1.098V     732mV      1.764V
350.9ps   1.456V     740.5mV    1.931V
493.6ps   1.722V     1.01V      1.971V
640.6ps   1.784V     1.384V     1.978V
713.7ps   1.789V     1.493V     1.979V
913.8ps   1.793V     1.588V     1.98V
1.37ns    1.796V     1.611V     1.98V
[Rising Waveform]
R_fixture = 50
V_fixture = 0
V_fixture_min = 0
V_fixture_max = 0
0s        0V         0V         0V
99.5ps    0V         0V         19.96mV
198.1ps   9.406mV    0V         464.9mV
284.2ps   262.7mV    0V         863.1mV
363.8ps   577.4mV    0V         1.029V
533.6ps   907.4mV    261.2mV    1.073V
694.7ps   958.4mV    654.2mV    1.08V
777.9ps   961.7mV    754.3mV    1.082V
1.011ns   965.8mV    855.2mV    1.083V
1.392ns   965.8mV    864.7mV    1.084V
[Falling Waveform]
R_fixture = 50
V_fixture = 1.8
V_fixture_min = 1.62
V_fixture_max = 1.98
0s        1.799V     1.619V     1.979V
108.4ps   1.799V     1.619V     1.945V
201.7ps   1.788V     1.619V     1.574V
300.1ps   1.542V     1.619V     1.141V
387.8ps   1.212V     1.619V     961.7mV
471.2ps   1.003V     1.508V     929.4mV
562.5ps   884.3mV    1.321V     917.8mV
776.6ps   831.3mV    874.7mV    909.9mV
1.065ns   824.2mV    745.5mV    907.5mV
1.37ns    823mV      737.7mV    907.2mV
[Falling Waveform]
R_fixture = 50
V_fixture = 0
V_fixture_min = 0
V_fixture_max = 0
0s        972.6mV    872mV      1.083V
98.3ps    972.6mV    872mV      1.052V
185.8ps   960.3mV    872mV      657.4mV
278ps     680.8mV    872mV      240.1mV
373.7ps   326.9mV    855.2mV    45.48mV
461.9ps   145.3mV    694mV      14.92mV
554.8ps   48.26mV    485.8mV    6.9mV
742.6ps   9.712mV    126.9mV    2.192mV
1.011ns   5.795mV    16.36mV    0V
1.392ns   4.379mV    9.121mV    0V
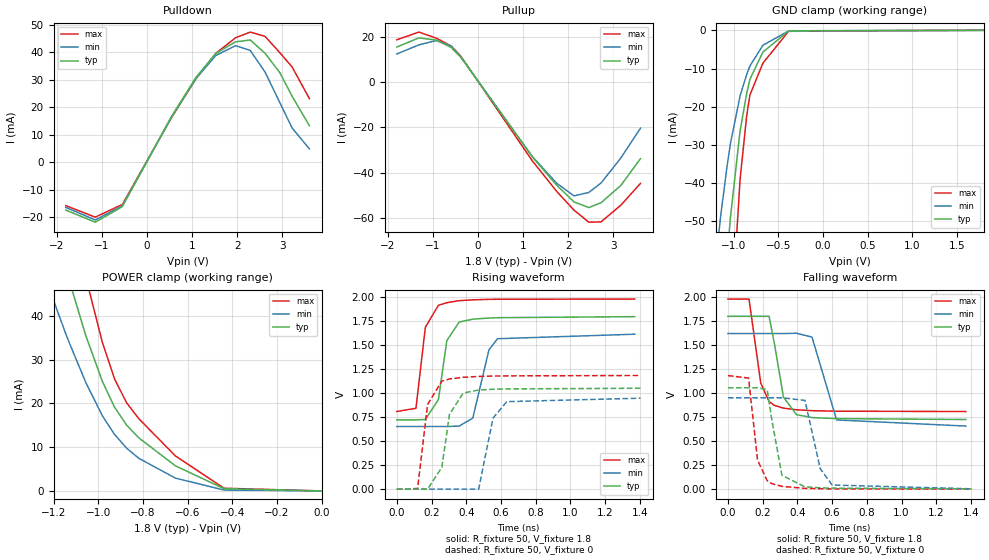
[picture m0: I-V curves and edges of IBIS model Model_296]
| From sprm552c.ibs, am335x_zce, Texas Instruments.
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| Model based on original model for BCSHTLTCSCDVPBFZ_SSDHV
|   Sub model SR00_11MA_10PER_1P8
[model]   Model_296
|[Description]  [1.8V-3-STATE-NOTERM-SR00:11MA, IND, 10%]
|   Fastest slew rate (SR[1:0] = "00"), 0.73 * RExt = 1.325 * Iout
|   (I[2:0] = "110"), 11mA nominal with Rext = 50R,ODT off (ODT[1:0]
|   = "00") CMOS mode,Industrial temperature range (-40C to 125C,
|   25C nominal),10% power supply tolerance
|[Input Load]   NOTERM
|[Output Drive] SR00:11MA
|Voltage   1.8V
|Mode   3-STATE
Model_type   3-state
Polarity   Non-Inverting
Enable   Active-Low
Cref =  15pF
Rref =  100.0000M
Vref =  0V
Vmeas =  0.9
C_comp   1.851324p   1.663768p   1.973575p
[Temperature Range]   25   125   -40
[Voltage Range]   1.8   1.62   1.98
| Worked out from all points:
|   slope of the pulldown table from 0 to 0.27 V, typ, clamps not added: 32 ohm
|   slope of the pullup table from 0 to 0.27 V, typ, clamps not added: 34.5 ohm
|   GND clamp passes 1 mA (typ) near -0.49 V on its own axis
|   POWER clamp passes 1 mA (typ) near -0.47 V on its own axis
|   rising waveform, R_fixture 50, V_fixture 1.8: 20-80 % time 53.8ps typ, 68.5ps min, 47.2ps max; typ from 0.722 V to 1.8 V
|   rising waveform, R_fixture 50, V_fixture 0: 20-80 % time 55.8ps typ, 60.7ps min, 50.3ps max; typ from 0 V to 1.05 V
|   falling waveform, R_fixture 50, V_fixture 1.8: 20-80 % time 61.2ps typ, 72.9ps min, 55.9ps max; typ from 1.8 V to 0.725 V
|   falling waveform, R_fixture 50, V_fixture 0: 20-80 % time 50.6ps typ, 61.7ps min, 46.8ps max; typ from 1.06 V to 0.003 V
[POWER_clamp]
-1.8V     194.9mA    137.1mA    262.8mA
-1.236V   68.49mA    48.51mA    92.67mA
-1.145V   50.76mA    35.86mA    69.65mA
-1.127V   47.56mA    33.54mA    65.34mA
-1.055V   35.4mA     24.69mA    48.69mA
-981.8mV  25.06mA    17.2mA     34.01mA
-927.3mV  19.17mA    12.93mA    25.61mA
-872.7mV  15.03mA    9.767mA    20.12mA
-818.2mV  12.12mA    7.45mA     16.5mA
-654.5mV  5.738mA    2.93mA     8.003mA
-436.4mV  508.2uA    199.4uA    613uA
0V        2.273nA    15.95nA    16.67nA
[Pulldown]
-1.8V     -17.41mA   -16.43mA   -15.81mA
-1.145V   -21.83mA   -21.01mA   -19.99mA
-545.5mV  -16.18mA   -15.87mA   -15.39mA
545.5mV   16.61mA    16.34mA    16.22mA
1.091V    30.91mA    30.47mA    30.41mA
1.527V    39.51mA    38.78mA    39.54mA
1.964V    43.74mA    42.34mA    45.21mA
2.291V    44.39mA    40.59mA    47.27mA
2.618V    39.56mA    32.74mA    45.71mA
2.945V    32.54mA    21.66mA    39.78mA
3.218V    23.95mA    12.39mA    34.58mA
3.6V      13.24mA    4.837mA    23.12mA
[Pullup]
-1.8V     15.59mA    12.51mA    18.8mA
-1.309V   19.63mA    16.55mA    22.2mA
-927.3mV  18.65mA    18.46mA    19.52mA
-600mV    15.48mA    16.08mA    16.11mA
-381.8mV  11.09mA    11.19mA    11.57mA
1.2V      -32.98mA   -32.79mA   -34.72mA
1.745V    -45.62mA   -44.74mA   -48.37mA
2.127V    -52.98mA   -50.3mA    -56.63mA
2.455V    -55.48mA   -48.79mA   -61.96mA
2.727V    -53.34mA   -44.61mA   -61.81mA
3.164V    -45.71mA   -33.58mA   -54.45mA
3.6V      -33.84mA   -20.34mA   -44.81mA
[GND_clamp]
-1.8V     -346.1mA   -209.3mA   -568.3mA
-1.327V   -149.7mA   -89.03mA   -250.9mA
-1.291V   -135.6mA   -80.47mA   -227.5mA
-1.145V   -82.35mA   -48.67mA   -137.7mA
-1.073V   -59.44mA   -35.55mA   -97.96mA
-1.036V   -49.1mA    -29.72mA   -79.9mA
-927.3mV  -26.31mA   -17.11mA   -38.99mA
-854.5mV  -16.67mA   -11.64mA   -22.56mA
-818.2mV  -12.86mA   -9.351mA   -16.98mA
-672.7mV  -5.705mA   -3.913mA   -8.624mA
-381.8mV  -120.4uA   -129uA     -167.4uA
1.8V      2.273nA    454nA      6.646nA
[Ramp]
dV/dt_f 0.65802986/61.714479p 0.59418998/72.887838p  0.7108246/55.654148p
dV/dt_r 0.64242304/56.227349p 0.58621712/61.635892p 0.71741652/50.394925p
R_load = 50
[Rising Waveform]
R_fixture = 50
V_fixture = 1.8
V_fixture_min = 1.62
V_fixture_max = 1.98
0s        722mV      652.8mV    809.4mV
110.2ps   722mV      652.8mV    842.3mV
164.3ps   725.6mV    652.8mV    1.686V
239.5ps   932.9mV    652.8mV    1.915V
288.1ps   1.548V     652.8mV    1.942V
358.9ps   1.74V      656.9mV    1.963V
437.6ps   1.771V     739.9mV    1.972V
530.5ps   1.782V     1.451V     1.977V
579.8ps   1.786V     1.567V     1.978V
1.37ns    1.797V     1.614V     1.98V
[Rising Waveform]
R_fixture = 50
V_fixture = 0
V_fixture_min = 0
V_fixture_max = 0
0s        0V         0V         0V
119.5ps   0V         0V         6.638mV
177.2ps   0V         0V         882.1mV
259.2ps   227mV      0V         1.125V
303.2ps   777.7mV    0V         1.148V
382ps     1.001V     0V         1.165V
471.1ps   1.033V     0V         1.174V
554.1ps   1.04V      740.7mV    1.178V
633.3ps   1.044V     911.6mV    1.18V
1.403ns   1.051V     947.3mV    1.184V
[Falling Waveform]
R_fixture = 50
V_fixture = 1.8
V_fixture_min = 1.62
V_fixture_max = 1.98
0s        1.8V       1.621V     1.98V
121.4ps   1.8V       1.621V     1.98V
189ps     1.8V       1.621V     1.106V
237ps     1.8V       1.621V     912.5mV
268ps     1.513V     1.621V     872.3mV
319.9ps   958.4mV    1.621V     844mV
394.9ps   776.1mV    1.624V     827mV
484.2ps   745.5mV    1.584V     817.4mV
625.9ps   734.7mV    721mV      812.2mV
1.37ns    725.4mV    657.3mV    808.5mV
[Falling Waveform]
R_fixture = 50
V_fixture = 0
V_fixture_min = 0
V_fixture_max = 0
0s        1.056V     951.9mV    1.183V
118.9ps   1.056V     951.9mV    1.157V
170.6ps   1.056V     951.9mV    303.1mV
226.1ps   1.035V     951.9mV    88.07mV
253.8ps   712mV      951.9mV    57.13mV
310.8ps   145.6mV    951.9mV    29.18mV
443.6ps   23.87mV    924.4mV    8.319mV
531.8ps   14.43mV    212.8mV    4.518mV
600.2ps   10.57mV    42.94mV    2.993mV
1.403ns   3.284mV    3.738mV    0V
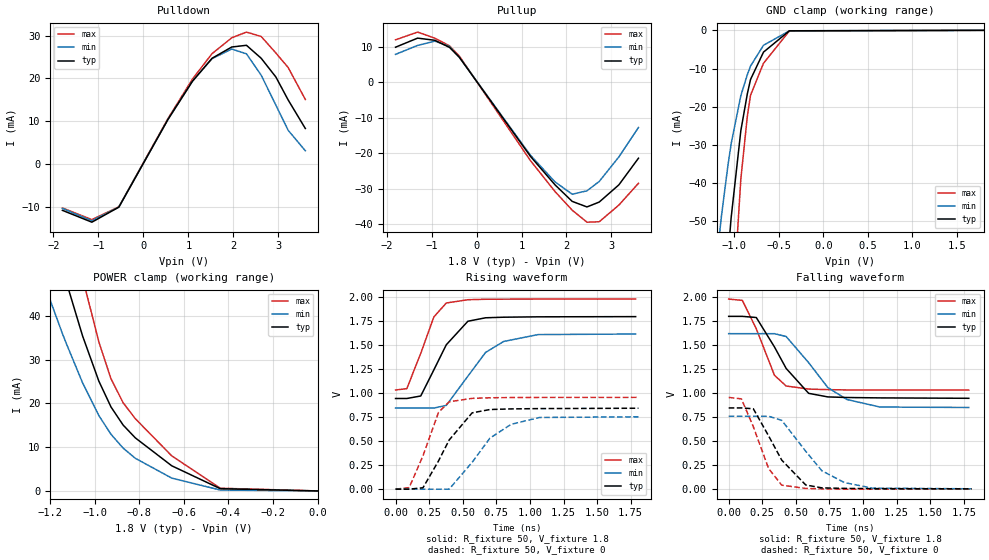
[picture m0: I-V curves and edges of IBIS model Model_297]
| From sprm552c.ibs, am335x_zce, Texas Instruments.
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| Model based on original model for BCSHTLTCSCDVPBFZ_SSDHV
|   Sub model SR01_7MA_10PER_1P8
[model]   Model_297
|[Description]  [1.8V-3-STATE-NOTERM-SR01:7MA, IND, 10%]
|   Slow slew rate (SR[1:0] = "01"), 1.14 * RExt = 0.875 * Iout
|   (I[2:0] = "010"), 7mA nominal with Rext = 50R,ODT off (ODT[1:0]
|   = "00") CMOS mode,Industrial temperature range (-40C to 125C,
|   25C nominal),10% power supply tolerance
|[Input Load]   NOTERM
|[Output Drive] SR01:7MA
|Voltage   1.8V
|Mode   3-STATE
Model_type   3-state
Polarity   Non-Inverting
Enable   Active-Low
Cref =  15pF
Rref =  100.0000M
Vref =  0V
Vmeas =  0.9
C_comp   1.851324p   1.663768p   1.973575p
[Temperature Range]   25   125   -40
[Voltage Range]   1.8   1.62   1.98
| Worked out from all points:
|   slope of the pulldown table from 0 to 0.27 V, typ, clamps not added: 51.1 ohm
|   slope of the pullup table from 0 to 0.27 V, typ, clamps not added: 54.4 ohm
|   GND clamp passes 1 mA (typ) near -0.49 V on its own axis
|   POWER clamp passes 1 mA (typ) near -0.47 V on its own axis
|   rising waveform, R_fixture 50, V_fixture 1.8: 20-80 % time 194ps typ, 246ps min, 144ps max; typ from 0.944 V to 1.8 V
|   rising waveform, R_fixture 50, V_fixture 0: 20-80 % time 203ps typ, 262ps min, 144ps max; typ from 0 V to 0.843 V
|   falling waveform, R_fixture 50, V_fixture 1.8: 20-80 % time 214ps typ, 269ps min, 158ps max; typ from 1.8 V to 0.946 V
|   falling waveform, R_fixture 50, V_fixture 0: 20-80 % time 210ps typ, 267ps min, 153ps max; typ from 0.846 V to 0.003 V
[POWER_clamp]
-1.8V     194.9mA    137.1mA    262.8mA
-1.236V   68.49mA    48.51mA    92.67mA
-1.145V   50.76mA    35.86mA    69.65mA
-1.127V   47.56mA    33.54mA    65.34mA
-1.055V   35.4mA     24.69mA    48.69mA
-981.8mV  25.06mA    17.2mA     34.01mA
-927.3mV  19.17mA    12.93mA    25.61mA
-872.7mV  15.03mA    9.767mA    20.12mA
-818.2mV  12.12mA    7.45mA     16.5mA
-654.5mV  5.738mA    2.93mA     8.003mA
-436.4mV  508.2uA    199.4uA    613uA
0V        2.273nA    15.95nA    16.67nA
[Pulldown]
-1.8V     -10.87mA   -10.42mA   -10.31mA
-1.145V   -13.64mA   -13.33mA   -13.03mA
-545.5mV  -10.12mA   -10.08mA   -10.04mA
545.5mV   10.39mA    10.38mA    10.59mA
1.091V    19.34mA    19.35mA    19.85mA
1.527V    24.71mA    24.62mA    25.8mA
1.964V    27.34mA    26.87mA    29.49mA
2.291V    27.74mA    25.74mA    30.83mA
2.618V    24.71mA    20.75mA    29.8mA
2.945V    20.32mA    13.73mA    25.93mA
3.218V    14.95mA    7.852mA    22.54mA
3.6V      8.27mA     3.068mA    15.06mA
[Pullup]
-1.8V     9.872mA    7.849mA    11.96mA
-1.309V   12.43mA    10.38mA    14.13mA
-927.3mV  11.82mA    11.58mA    12.42mA
-600mV    9.811mA    10.09mA    10.26mA
-381.8mV  7.028mA    7.03mA     7.372mA
1.2V      -20.91mA   -20.59mA   -22.11mA
1.745V    -28.92mA   -28.09mA   -30.81mA
2.127V    -33.58mA   -31.56mA   -36.06mA
2.455V    -35.14mA   -30.6mA    -39.44mA
2.727V    -33.77mA   -27.97mA   -39.32mA
3.164V    -28.92mA   -21.05mA   -34.62mA
3.6V      -21.41mA   -12.75mA   -28.48mA
[GND_clamp]
-1.8V     -346.1mA   -209.3mA   -568.3mA
-1.327V   -149.7mA   -89.03mA   -250.9mA
-1.291V   -135.6mA   -80.47mA   -227.5mA
-1.145V   -82.35mA   -48.67mA   -137.7mA
-1.073V   -59.44mA   -35.55mA   -97.96mA
-1.036V   -49.1mA    -29.72mA   -79.9mA
-927.3mV  -26.31mA   -17.11mA   -38.99mA
-854.5mV  -16.67mA   -11.64mA   -22.56mA
-818.2mV  -12.86mA   -9.351mA   -16.98mA
-672.7mV  -5.705mA   -3.913mA   -8.624mA
-381.8mV  -120.4uA   -129uA     -167.4uA
1.8V      2.273nA    454nA      6.646nA
[Ramp]
dV/dt_f 0.51489206/0.21571361n 0.46624592/0.27344601n 0.56936654/0.15851697n
dV/dt_r 0.50910715/0.20470951n 0.45651494/0.26500134n 0.57454212/0.14437397n
R_load = 50
[Rising Waveform]
R_fixture = 50
V_fixture = 1.8
V_fixture_min = 1.62
V_fixture_max = 1.98
0s        944.4mV    844.3mV    1.033V
83.9ps    944.4mV    844.3mV    1.047V
187.6ps   970.6mV    844.3mV    1.415V
285.2ps   1.243V     844.5mV    1.794V
377.7ps   1.504V     872.8mV    1.939V
538.4ps   1.749V     1.177V     1.973V
670ps     1.785V     1.424V     1.978V
803.9ps   1.791V     1.538V     1.979V
1.06ns    1.795V     1.61V      1.98V
1.787ns   1.797V     1.616V     1.98V
[Rising Waveform]
R_fixture = 50
V_fixture = 0
V_fixture_min = 0
V_fixture_max = 0
0s        0V         0V         0V
101.4ps   0V         0V         16.03mV
204.2ps   14.69mV    0V         347.8mV
319.6ps   293.8mV    0V         799.3mV
398.9ps   511.6mV    0V         910.1mV
569.8ps   794.8mV    279.3mV    945.6mV
702.4ps   829.6mV    531.4mV    951.7mV
859.6ps   835.9mV    675.1mV    954.4mV
1.071ns   839.2mV    746.7mV    955.6mV
1.808ns   843mV      753.4mV    955.9mV
[Falling Waveform]
R_fixture = 50
V_fixture = 1.8
V_fixture_min = 1.62
V_fixture_max = 1.98
0s        1.799V     1.619V     1.979V
101.7ps   1.799V     1.619V     1.965V
205.5ps   1.787V     1.619V     1.67V
340.6ps   1.481V     1.619V     1.186V
427.7ps   1.257V     1.589V     1.074V
595.2ps   997.7mV    1.317V     1.042V
738.3ps   960.3mV    1.057V     1.036V
881.1ps   954.2mV    933mV      1.033V
1.126ns   950.2mV    855.1mV    1.032V
1.787ns   946mV      850.3mV    1.032V
[Falling Waveform]
R_fixture = 50
V_fixture = 0
V_fixture_min = 0
V_fixture_max = 0
0s        845.6mV    758.9mV    955.1mV
94.6ps    845.6mV    758.9mV    940.1mV
183.4ps   837mV      758.9mV    650.3mV
297.4ps   554.1mV    758.9mV    214.3mV
394.9ps   302.3mV    716.7mV    41.83mV
573.4ps   43.59mV    394.5mV    7.416mV
693.9ps   13.67mV    191mV      3.482mV
861.6ps   7.969mV    68.67mV    0V
1.071ns   5.808mV    10.33mV    0V
1.808ns   3.224mV    3.991mV    0V
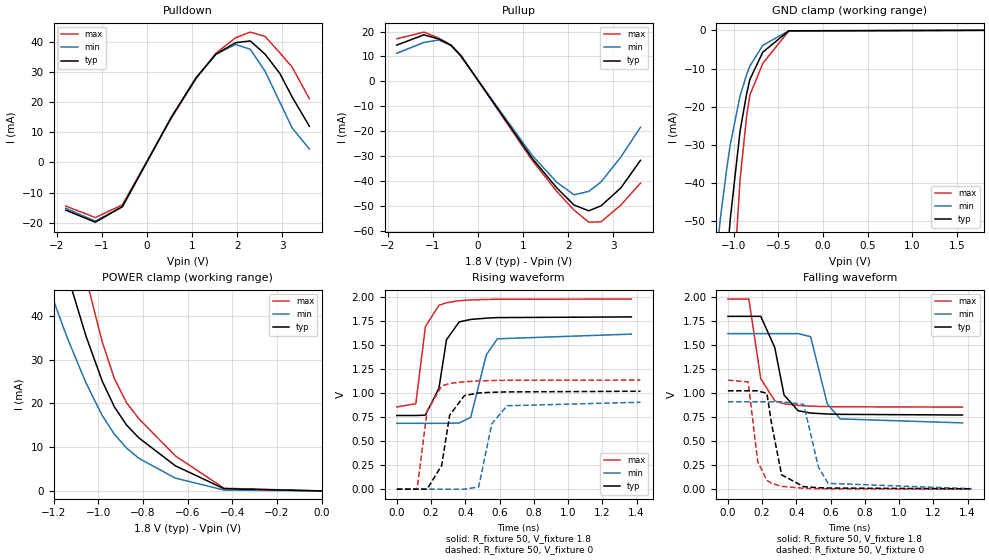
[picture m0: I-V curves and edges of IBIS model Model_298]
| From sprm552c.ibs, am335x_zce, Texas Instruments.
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| Model based on original model for BCSHTLTCSCDVPBFZ_SSDHV
|   Sub model SR00_10MA_10PER_1P8
[model]   Model_298
|[Description]  [1.8V-3-STATE-NOTERM-SR00:10MA, IND, 10%]
|   Fastest slew rate (SR[1:0] = "00"), 0.80 * RExt = 1.250 * Iout
|   (I[2:0] = "101"), 10mA nominal with Rext = 50R,ODT off (ODT[1:0]
|   = "00") CMOS mode,Industrial temperature range (-40C to 125C,
|   25C nominal),10% power supply tolerance
|[Input Load]   NOTERM
|[Output Drive] SR00:10MA
|Voltage   1.8V
|Mode   3-STATE
Model_type   3-state
Polarity   Non-Inverting
Enable   Active-Low
Cref =  15pF
Rref =  100.0000M
Vref =  0V
Vmeas =  0.9
C_comp   1.851324p   1.663768p   1.973575p
[Temperature Range]   25   125   -40
[Voltage Range]   1.8   1.62   1.98
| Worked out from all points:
|   slope of the pulldown table from 0 to 0.27 V, typ, clamps not added: 35.3 ohm
|   slope of the pullup table from 0 to 0.27 V, typ, clamps not added: 36.9 ohm
|   GND clamp passes 1 mA (typ) near -0.49 V on its own axis
|   POWER clamp passes 1 mA (typ) near -0.47 V on its own axis
|   rising waveform, R_fixture 50, V_fixture 1.8: 20-80 % time 55.9ps typ, 72.1ps min, 50.3ps max; typ from 0.767 V to 1.79 V
|   rising waveform, R_fixture 50, V_fixture 0: 20-80 % time 58ps typ, 65.2ps min, 54.1ps max; typ from 0 V to 1.02 V
|   falling waveform, R_fixture 50, V_fixture 1.8: 20-80 % time 64.8ps typ, 74.8ps min, 59.2ps max; typ from 1.8 V to 0.772 V
|   falling waveform, R_fixture 50, V_fixture 0: 20-80 % time 53.5ps typ, 63.7ps min, 49.8ps max; typ from 1.02 V to 0.004 V
[POWER_clamp]
-1.8V     194.9mA    137.1mA    262.8mA
-1.236V   68.49mA    48.51mA    92.67mA
-1.145V   50.76mA    35.86mA    69.65mA
-1.127V   47.56mA    33.54mA    65.34mA
-1.055V   35.4mA     24.69mA    48.69mA
-981.8mV  25.06mA    17.2mA     34.01mA
-927.3mV  19.17mA    12.93mA    25.61mA
-872.7mV  15.03mA    9.767mA    20.12mA
-818.2mV  12.12mA    7.45mA     16.5mA
-654.5mV  5.738mA    2.93mA     8.003mA
-436.4mV  508.2uA    199.4uA    613uA
0V        2.273nA    15.95nA    16.67nA
[Pulldown]
-1.8V     -15.77mA   -15.17mA   -14.43mA
-1.145V   -19.78mA   -19.39mA   -18.25mA
-545.5mV  -14.66mA   -14.65mA   -14.05mA
545.5mV   15.06mA    15.08mA    14.82mA
1.091V    28.02mA    28.13mA    27.77mA
1.527V    35.81mA    35.8mA     36.1mA
1.964V    39.64mA    39.08mA    41.28mA
2.291V    40.23mA    37.46mA    43.16mA
2.618V    35.85mA    30.21mA    41.73mA
2.945V    29.48mA    19.99mA    36.31mA
3.218V    21.69mA    11.43mA    31.57mA
3.6V      12mA       4.465mA    21.1mA
[Pullup]
-1.8V     14.55mA    11.29mA    17.09mA
-1.2V     18.67mA    15.62mA    19.77mA
-872.7mV  17.03mA    16.61mA    17.36mA
-600mV    14.45mA    14.5mA     14.65mA
-381.8mV  10.35mA    10.1mA     10.52mA
1.2V      -30.78mA   -29.58mA   -31.57mA
1.745V    -42.59mA   -40.36mA   -43.98mA
2.127V    -49.46mA   -45.37mA   -51.49mA
2.455V    -51.78mA   -44mA      -56.34mA
2.727V    -49.78mA   -40.23mA   -56.19mA
3.164V    -42.65mA   -30.28mA   -49.49mA
3.6V      -31.58mA   -18.34mA   -40.72mA
[GND_clamp]
-1.8V     -346.1mA   -209.3mA   -568.3mA
-1.327V   -149.7mA   -89.03mA   -250.9mA
-1.291V   -135.6mA   -80.47mA   -227.5mA
-1.145V   -82.35mA   -48.67mA   -137.7mA
-1.073V   -59.44mA   -35.55mA   -97.96mA
-1.036V   -49.1mA    -29.72mA   -79.9mA
-927.3mV  -26.31mA   -17.11mA   -38.99mA
-854.5mV  -16.67mA   -11.64mA   -22.56mA
-818.2mV  -12.86mA   -9.351mA   -16.98mA
-672.7mV  -5.705mA   -3.913mA   -8.624mA
-381.8mV  -120.4uA   -129uA     -167.4uA
1.8V      2.273nA    454nA      6.646nA
[Ramp]
dV/dt_f 0.63020852/65.88847p  0.57339844/76.522282p 0.68254637/59.302004p
dV/dt_r 0.62290163/58.895995p 0.55991922/66.050068p 0.68851667/53.801272p
R_load = 50
[Rising Waveform]
R_fixture = 50
V_fixture = 1.8
V_fixture_min = 1.62
V_fixture_max = 1.98
0s        767.4mV    685.7mV    855.9mV
111.1ps   767.4mV    685.7mV    890.3mV
166.9ps   771.1mV    685.7mV    1.694V
246ps     1.051V     685.7mV    1.915V
290.1ps   1.556V     685.7mV    1.941V
364.2ps   1.742V     689.6mV    1.963V
431.8ps   1.768V     748.5mV    1.971V
523ps     1.781V     1.4V       1.976V
587.5ps   1.787V     1.566V     1.978V
1.37ns    1.794V     1.615V     1.98V
[Rising Waveform]
R_fixture = 50
V_fixture = 0
V_fixture_min = 0
V_fixture_max = 0
0s        0V         0V         0V
118.4ps   0V         0V         0V
176.8ps   0V         0V         813.5mV
262ps     246.5mV    0V         1.075V
308.6ps   770.1mV    0V         1.101V
394.4ps   974.4mV    0V         1.119V
478ps     1.002V     23.5mV     1.127V
554.8ps   1.009V     680.8mV    1.131V
644ps     1.013V     869mV      1.134V
1.423ns   1.02V      905.2mV    1.136V
[Falling Waveform]
R_fixture = 50
V_fixture = 1.8
V_fixture_min = 1.62
V_fixture_max = 1.98
0s        1.801V     1.621V     1.981V
122.3ps   1.801V     1.621V     1.981V
191.8ps   1.801V     1.621V     1.151V
273.7ps   1.476V     1.621V     919.9mV
327.8ps   981.3mV    1.621V     890.5mV
410ps     817.3mV    1.621V     872.9mV
483ps     792.9mV    1.589V     864.8mV
580.7ps   783.5mV    886.9mV    860.3mV
655.5ps   779.7mV    732.1mV    858.5mV
1.37ns    772.5mV    690.6mV    855.1mV
[Falling Waveform]
R_fixture = 50
V_fixture = 0
V_fixture_min = 0
V_fixture_max = 0
0s        1.025V     910.3mV    1.136V
118.3ps   1.025V     910.3mV    1.118V
174.1ps   1.025V     910.3mV    287.6mV
227.8ps   997.2mV    910.3mV    91.6mV
255.2ps   679.5mV    910.3mV    60.01mV
313.6ps   149.4mV    910.3mV    30.09mV
442.4ps   25.99mV    883.7mV    8.936mV
528.8ps   15.56mV    229.1mV    4.905mV
585.4ps   11.89mV    60.45mV    3.478mV
1.423ns   3.658mV    4.858mV    0V
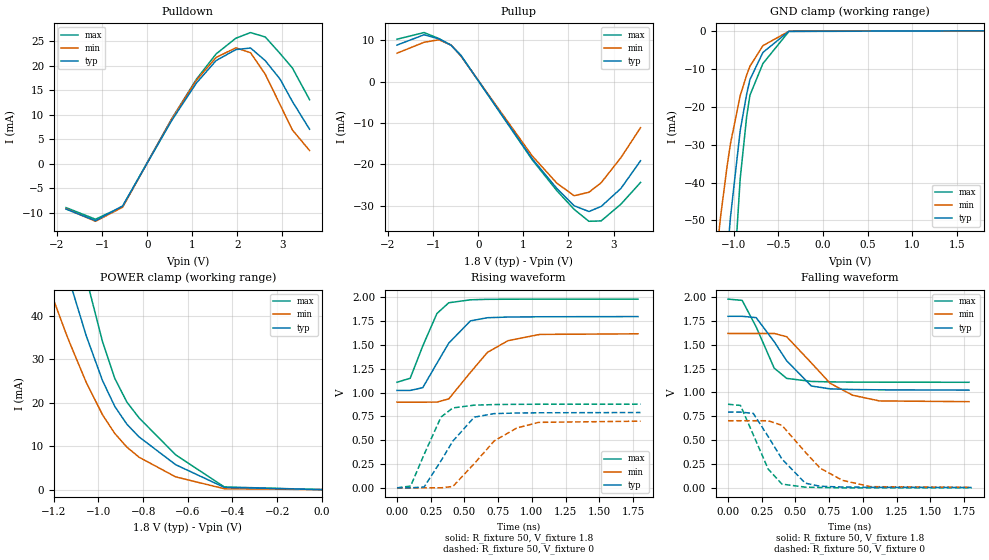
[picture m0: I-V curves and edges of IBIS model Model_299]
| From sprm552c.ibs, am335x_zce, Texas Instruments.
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| Model based on original model for BCSHTLTCSCDVPBFZ_SSDHV
|   Sub model SR01_6MA_10PER_1P8
[model]   Model_299
|[Description]  [1.8V-3-STATE-NOTERM-SR01:6MA, IND, 10%]
|   Slow slew rate (SR[1:0] = "01"), 1.33 * RExt = 0.750 * Iout
|   (I[2:0] = "001"), 6mA nominal with Rext = 50R,ODT off (ODT[1:0]
|   = "00") CMOS mode,Industrial temperature range (-40C to 125C,
|   25C nominal),10% power supply tolerance
|[Input Load]   NOTERM
|[Output Drive] SR01:6MA
|Voltage   1.8V
|Mode   3-STATE
Model_type   3-state
Polarity   Non-Inverting
Enable   Active-Low
Cref =  15pF
Rref =  100.0000M
Vref =  0V
Vmeas =  0.9
C_comp   1.851324p   1.663768p   1.973575p
[Temperature Range]   25   125   -40
[Voltage Range]   1.8   1.62   1.98
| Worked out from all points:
|   slope of the pulldown table from 0 to 0.27 V, typ, clamps not added: 60.1 ohm
|   slope of the pullup table from 0 to 0.27 V, typ, clamps not added: 60.8 ohm
|   GND clamp passes 1 mA (typ) near -0.49 V on its own axis
|   POWER clamp passes 1 mA (typ) near -0.47 V on its own axis
|   rising waveform, R_fixture 50, V_fixture 1.8: 20-80 % time 199ps typ, 263ps min, 146ps max; typ from 1.02 V to 1.8 V
|   rising waveform, R_fixture 50, V_fixture 0: 20-80 % time 207ps typ, 285ps min, 154ps max; typ from 0 V to 0.79 V
|   falling waveform, R_fixture 50, V_fixture 1.8: 20-80 % time 222ps typ, 292ps min, 158ps max; typ from 1.8 V to 1.02 V
|   falling waveform, R_fixture 50, V_fixture 0: 20-80 % time 217ps typ, 285ps min, 157ps max; typ from 0.795 V to 0.003 V
[POWER_clamp]
-1.8V     194.9mA    137.1mA    262.8mA
-1.236V   68.49mA    48.51mA    92.67mA
-1.145V   50.76mA    35.86mA    69.65mA
-1.127V   47.56mA    33.54mA    65.34mA
-1.055V   35.4mA     24.69mA    48.69mA
-981.8mV  25.06mA    17.2mA     34.01mA
-927.3mV  19.17mA    12.93mA    25.61mA
-872.7mV  15.03mA    9.767mA    20.12mA
-818.2mV  12.12mA    7.45mA     16.5mA
-654.5mV  5.738mA    2.93mA     8.003mA
-436.4mV  508.2uA    199.4uA    613uA
0V        2.273nA    15.95nA    16.67nA
[Pulldown]
-1.8V     -9.241mA   -9.161mA   -8.932mA
-1.145V   -11.6mA    -11.72mA   -11.3mA
-545.5mV  -8.602mA   -8.855mA   -8.702mA
545.5mV   8.836mA    9.123mA    9.182mA
1.091V    16.44mA    17.01mA    17.21mA
1.527V    21.01mA    21.64mA    22.36mA
1.964V    23.24mA    23.61mA    25.56mA
2.291V    23.58mA    22.62mA    26.72mA
2.618V    21mA       18.23mA    25.82mA
2.945V    17.26mA    12.06mA    22.47mA
3.218V    12.7mA     6.898mA    19.53mA
3.6V      7.029mA    2.696mA    13.05mA
[Pullup]
-1.8V     8.832mA    6.868mA    10.25mA
-1.2V     11.33mA    9.506mA    11.86mA
-872.7mV  10.35mA    10.11mA    10.42mA
-600mV    8.779mA    8.832mA    8.794mA
-381.8mV  6.289mA    6.153mA    6.32mA
1.2V      -18.71mA   -18.02mA   -18.96mA
1.745V    -25.88mA   -24.59mA   -26.41mA
2.127V    -30.05mA   -27.62mA   -30.92mA
2.455V    -31.44mA   -26.78mA   -33.81mA
2.727V    -30.21mA   -24.47mA   -33.71mA
3.164V    -25.87mA   -18.41mA   -29.67mA
3.6V      -19.15mA   -11.15mA   -24.41mA
[GND_clamp]
-1.8V     -346.1mA   -209.3mA   -568.3mA
-1.327V   -149.7mA   -89.03mA   -250.9mA
-1.291V   -135.6mA   -80.47mA   -227.5mA
-1.145V   -82.35mA   -48.67mA   -137.7mA
-1.073V   -59.44mA   -35.55mA   -97.96mA
-1.036V   -49.1mA    -29.72mA   -79.9mA
-927.3mV  -26.31mA   -17.11mA   -38.99mA
-854.5mV  -16.67mA   -11.64mA   -22.56mA
-818.2mV  -12.86mA   -9.351mA   -16.98mA
-672.7mV  -5.705mA   -3.913mA   -8.624mA
-381.8mV  -120.4uA   -129uA     -167.4uA
1.8V      2.273nA    454nA      6.646nA
[Ramp]
dV/dt_f 0.46795461/0.22297643n 0.43300226/0.2948734n 0.52400316/0.15803217n
dV/dt_r 0.47806744/0.20932482n 0.42301818/0.28677804n 0.52740554/0.15365254n
R_load = 50
[Rising Waveform]
R_fixture = 50
V_fixture = 1.8
V_fixture_min = 1.62
V_fixture_max = 1.98
0s        1.022V     899.3mV    1.108V
97.8ps    1.022V     899.3mV    1.15V
190.8ps   1.051V     899.3mV    1.488V
295.9ps   1.307V     899.6mV    1.829V
384ps     1.519V     933.6mV    1.942V
544.8ps   1.752V     1.212V     1.973V
670.2ps   1.785V     1.421V     1.978V
822.9ps   1.792V     1.544V     1.979V
1.06ns    1.795V     1.61V      1.98V
1.787ns   1.797V     1.616V     1.98V
[Rising Waveform]
R_fixture = 50
V_fixture = 0
V_fixture_min = 0
V_fixture_max = 0
0s        0V         0V         0V
101.1ps   0V         0V         19.36mV
201.3ps   9.64mV     0V         351.6mV
326.4ps   284.1mV    0V         743.2mV
414.3ps   490.7mV    14.73mV    838.7mV
573.2ps   741.8mV    254.6mV    867.6mV
721.1ps   779.1mV    492.9mV    873.9mV
888.5ps   785.2mV    628mV      876.4mV
1.05ns    787.6mV    687.1mV    877.2mV
1.806ns   790.3mV    699.7mV    877.7mV
[Falling Waveform]
R_fixture = 50
V_fixture = 1.8
V_fixture_min = 1.62
V_fixture_max = 1.98
0s        1.799V     1.619V     1.979V
104.9ps   1.799V     1.619V     1.966V
209ps     1.785V     1.619V     1.687V
342.2ps   1.533V     1.619V     1.256V
434.8ps   1.333V     1.585V     1.148V
618ps     1.068V     1.31V      1.116V
757.6ps   1.038V     1.096V     1.111V
923.9ps   1.031V     971.6mV    1.109V
1.122ns   1.028V     911.6mV    1.108V
1.787ns   1.025V     903.7mV    1.107V
[Falling Waveform]
R_fixture = 50
V_fixture = 0
V_fixture_min = 0
V_fixture_max = 0
0s        794.5mV    703.8mV    876.8mV
92.4ps    794.5mV    703.8mV    864.1mV
187.9ps   780.5mV    703.8mV    555.4mV
297.7ps   538.4mV    703.8mV    197.4mV
399.9ps   302.5mV    655.6mV    39.2mV
572.7ps   49.52mV    375.1mV    7.642mV
683.1ps   16.41mV    206.7mV    3.801mV
848.7ps   8.776mV    78.89mV    0V
1.057ns   6.281mV    12.69mV    0V
1.806ns   3.353mV    5.545mV    0V
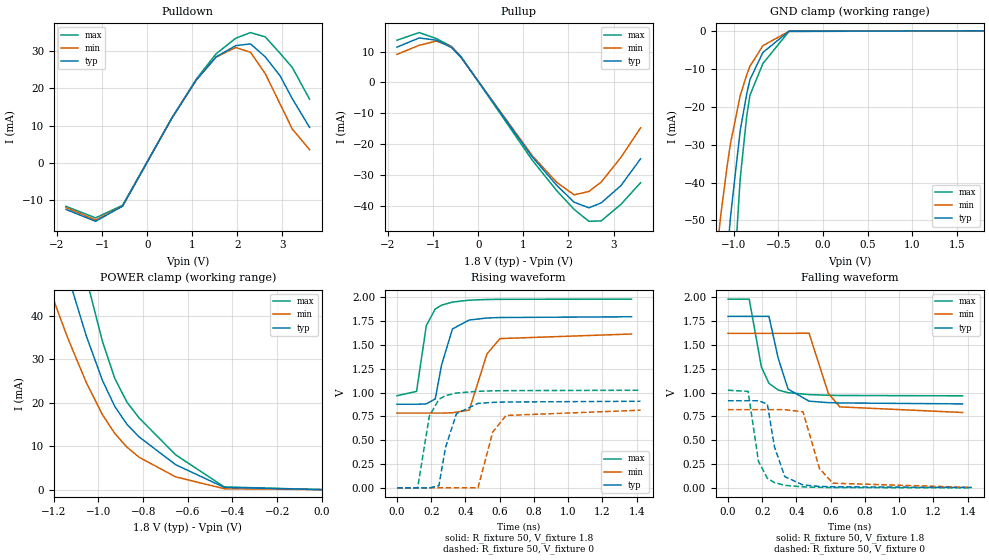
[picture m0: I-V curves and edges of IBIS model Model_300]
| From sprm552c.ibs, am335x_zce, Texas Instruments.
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| Model based on original model for BCSHTLTCSCDVPBFZ_SSDHV
|   Sub model SR00_8MA_10PER_1P8
[model]   Model_300
|[Description]  [1.8V-3-STATE-NOTERM-SR00:8MA, IND, 10%]
|   Fastest slew rate (SR[1:0] = "00"), 1.00 * RExt = 1.000 * Iout
|   (I[2:0] = "011"), 8mA nominal with Rext = 50R,ODT off (ODT[1:0]
|   = "00") CMOS mode,Industrial temperature range (-40C to 125C,
|   25C nominal),10% power supply tolerance
|[Input Load]   NOTERM
|[Output Drive] SR00:8MA
|Voltage   1.8V
|Mode   3-STATE
Model_type   3-state
Polarity   Non-Inverting
Enable   Active-Low
Cref =  15pF
Rref =  100.0000M
Vref =  0V
Vmeas =  0.9
C_comp   1.851324p   1.663768p   1.973575p
[Temperature Range]   25   125   -40
[Voltage Range]   1.8   1.62   1.98
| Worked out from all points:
|   slope of the pulldown table from 0 to 0.27 V, typ, clamps not added: 44.4 ohm
|   slope of the pullup table from 0 to 0.27 V, typ, clamps not added: 47 ohm
|   GND clamp passes 1 mA (typ) near -0.49 V on its own axis
|   POWER clamp passes 1 mA (typ) near -0.47 V on its own axis
|   rising waveform, R_fixture 50, V_fixture 1.8: 20-80 % time 67.4ps typ, 79.6ps min, 58.1ps max; typ from 0.877 V to 1.79 V
|   rising waveform, R_fixture 50, V_fixture 0: 20-80 % time 67.5ps typ, 74.9ps min, 62ps max; typ from 0 V to 0.909 V
|   falling waveform, R_fixture 50, V_fixture 1.8: 20-80 % time 75.2ps typ, 86.1ps min, 68ps max; typ from 1.8 V to 0.881 V
|   falling waveform, R_fixture 50, V_fixture 0: 20-80 % time 61.4ps typ, 72.5ps min, 57.4ps max; typ from 0.914 V to 0.004 V
[POWER_clamp]
-1.8V     194.9mA    137.1mA    262.8mA
-1.236V   68.49mA    48.51mA    92.67mA
-1.145V   50.76mA    35.86mA    69.65mA
-1.127V   47.56mA    33.54mA    65.34mA
-1.055V   35.4mA     24.69mA    48.69mA
-981.8mV  25.06mA    17.2mA     34.01mA
-927.3mV  19.17mA    12.93mA    25.61mA
-872.7mV  15.03mA    9.767mA    20.12mA
-818.2mV  12.12mA    7.45mA     16.5mA
-654.5mV  5.738mA    2.93mA     8.003mA
-436.4mV  508.2uA    199.4uA    613uA
0V        2.273nA    15.95nA    16.67nA
[Pulldown]
-1.8V     -12.51mA   -12.01mA   -11.68mA
-1.145V   -15.69mA   -15.35mA   -14.77mA
-545.5mV  -11.63mA   -11.6mA    -11.38mA
545.5mV   11.95mA    11.95mA    12mA
1.091V    22.23mA    22.28mA    22.49mA
1.527V    28.41mA    28.35mA    29.24mA
1.964V    31.44mA    30.94mA    33.42mA
2.291V    31.9mA     29.65mA    34.94mA
2.618V    28.42mA    23.91mA    33.77mA
2.945V    23.37mA    15.81mA    29.39mA
3.218V    17.19mA    9.044mA    25.55mA
3.6V      9.513mA    3.534mA    17.07mA
[Pullup]
-1.8V     11.43mA    9.077mA    13.67mA
-1.309V   14.4mA     12.01mA    16.15mA
-927.3mV  13.68mA    13.39mA    14.2mA
-600mV    11.36mA    11.67mA    11.72mA
-381.8mV  8.135mA    8.127mA    8.423mA
1.2V      -24.2mA    -23.8mA    -25.27mA
1.745V    -33.47mA   -32.48mA   -35.2mA
2.127V    -38.87mA   -36.49mA   -41.21mA
2.455V    -40.69mA   -35.39mA   -45.07mA
2.727V    -39.11mA   -32.35mA   -44.94mA
3.164V    -33.5mA    -24.34mA   -39.58mA
3.6V      -24.8mA    -14.75mA   -32.56mA
[GND_clamp]
-1.8V     -346.1mA   -209.3mA   -568.3mA
-1.327V   -149.7mA   -89.03mA   -250.9mA
-1.291V   -135.6mA   -80.47mA   -227.5mA
-1.145V   -82.35mA   -48.67mA   -137.7mA
-1.073V   -59.44mA   -35.55mA   -97.96mA
-1.036V   -49.1mA    -29.72mA   -79.9mA
-927.3mV  -26.31mA   -17.11mA   -38.99mA
-854.5mV  -16.67mA   -11.64mA   -22.56mA
-818.2mV  -12.86mA   -9.351mA   -16.98mA
-672.7mV  -5.705mA   -3.913mA   -8.624mA
-381.8mV  -120.4uA   -129uA     -167.4uA
1.8V      2.273nA    454nA      6.646nA
[Ramp]
dV/dt_f 0.56203759/76.199199p 0.51241544/87.469564p 0.61472302/68.033787p
dV/dt_r 0.55501725/68.51697p  0.50259787/75.720086p 0.61986372/62.006013p
R_load = 50
[Rising Waveform]
R_fixture = 50
V_fixture = 1.8
V_fixture_min = 1.62
V_fixture_max = 1.98
0s        877.2mV    784.1mV    966.6mV
114.2ps   877.2mV    784.1mV    1.012V
171.3ps   881.1mV    784.1mV    1.703V
223.3ps   932.4mV    784.1mV    1.876V
260.5ps   1.29V      784.1mV    1.917V
323.8ps   1.667V     788.1mV    1.949V
422.1ps   1.761V     815.7mV    1.969V
525.6ps   1.782V     1.405V     1.976V
601.6ps   1.787V     1.566V     1.978V
1.37ns    1.795V     1.614V     1.98V
[Rising Waveform]
R_fixture = 50
V_fixture = 0
V_fixture_min = 0
V_fixture_max = 0
0s        0V         0V         0V
120.5ps   0V         0V         0V
188.8ps   0V         0V         752.8mV
244.5ps   22.13mV    0V         928mV
283.2ps   422.1mV    0V         967.6mV
347.3ps   778.4mV    0V         994.7mV
473.1ps   886mV      0V         1.013V
559.3ps   896.7mV    585.5mV    1.018V
637ps     900.7mV    759.6mV    1.02V
1.423ns   908.6mV    814.8mV    1.024V
[Falling Waveform]
R_fixture = 50
V_fixture = 1.8
V_fixture_min = 1.62
V_fixture_max = 1.98
0s        1.799V     1.621V     1.98V
123.9ps   1.799V     1.621V     1.98V
194.7ps   1.799V     1.621V     1.27V
239.1ps   1.799V     1.621V     1.097V
293ps     1.361V     1.621V     1.026V
350.9ps   1.036V     1.621V     998.7mV
473.4ps   909.6mV    1.622V     978.6mV
586.4ps   894.1mV    990.8mV    971.2mV
653.2ps   890.7mV    849.5mV    969.1mV
1.37ns    880.8mV    790.8mV    965.8mV
[Falling Waveform]
R_fixture = 50
V_fixture = 0
V_fixture_min = 0
V_fixture_max = 0
0s        913.8mV    820.5mV    1.024V
117.5ps   913.8mV    820.5mV    1.012V
177.9ps   913.8mV    820.5mV    277.7mV
229.9ps   878.7mV    820.5mV    100.3mV
270.8ps   434.3mV    820.5mV    55.26mV
331.5ps   117.8mV    820.5mV    26.8mV
438.2ps   30.05mV    797.5mV    10.23mV
534.7ps   15.3mV     201.6mV    5.317mV
612.7ps   10.98mV    48.83mV    3.339mV
1.423ns   3.908mV    4.358mV    0V
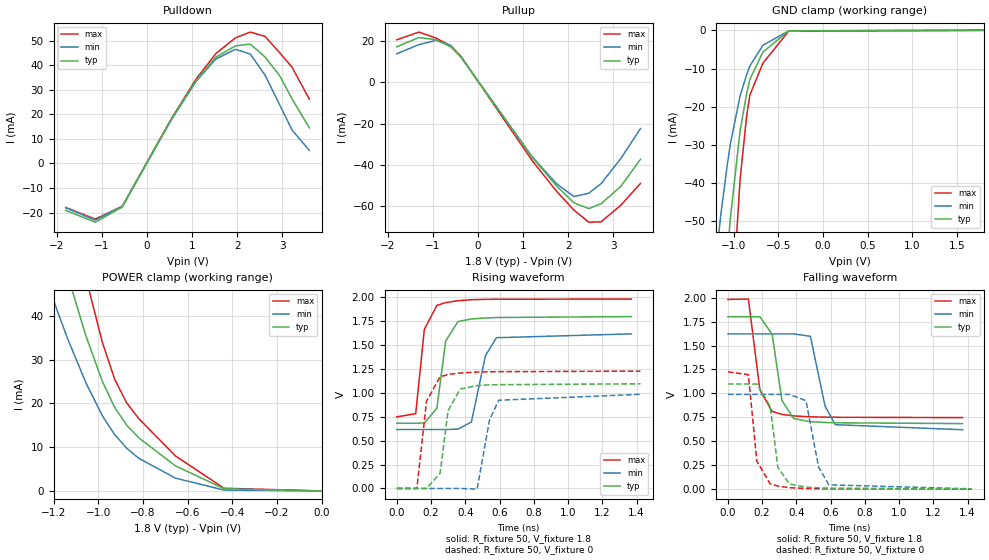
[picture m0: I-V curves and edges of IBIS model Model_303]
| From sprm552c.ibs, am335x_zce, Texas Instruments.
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| Model based on original model for BCSHTLTCSCDVPBFZ_SSDHV
|   Sub model SR00_12MA_10PER_1P8
[model]   Model_303
|[Description]  [1.8V-3-STATE-NOTERM-SR00:12MA, IND, 10%]
|   Fastest slew rate (SR[1:0] = "00"), 0.67 * RExt = 1.500 * Iout
|   (I[2:0] = "111"), 12mA nominal with Rext = 50R,ODT off (ODT[1:0]
|   = "00") CMOS mode,Industrial temperature range (-40C to 125C,
|   25C nominal),10% power supply tolerance
|[Input Load]   NOTERM
|[Output Drive] SR00:12MA
|Voltage   1.8V
|Mode   3-STATE
Model_type   3-state
Polarity   Non-Inverting
Enable   Active-Low
Cref =  15pF
Rref =  100.0000M
Vref =  0V
Vmeas =  0.9
C_comp   1.851324p   1.663768p   1.973575p
[Temperature Range]   25   125   -40
[Voltage Range]   1.8   1.62   1.98
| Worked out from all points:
|   slope of the pulldown table from 0 to 0.27 V, typ, clamps not added: 29.2 ohm
|   slope of the pullup table from 0 to 0.27 V, typ, clamps not added: 31.3 ohm
|   GND clamp passes 1 mA (typ) near -0.49 V on its own axis
|   POWER clamp passes 1 mA (typ) near -0.47 V on its own axis
|   rising waveform, R_fixture 50, V_fixture 1.8: 20-80 % time 51ps typ, 65.2ps min, 44.4ps max; typ from 0.682 V to 1.8 V
|   rising waveform, R_fixture 50, V_fixture 0: 20-80 % time 52.3ps typ, 57.1ps min, 48ps max; typ from 0 V to 1.09 V
|   falling waveform, R_fixture 50, V_fixture 1.8: 20-80 % time 57.3ps typ, 67.6ps min, 50.8ps max; typ from 1.8 V to 0.685 V
|   falling waveform, R_fixture 50, V_fixture 0: 20-80 % time 47.2ps typ, 59.3ps min, 42.8ps max; typ from 1.1 V to 0.004 V
[POWER_clamp]
-1.8V     194.9mA    137.1mA    262.8mA
-1.236V   68.49mA    48.51mA    92.67mA
-1.145V   50.76mA    35.86mA    69.65mA
-1.127V   47.56mA    33.54mA    65.34mA
-1.055V   35.4mA     24.69mA    48.69mA
-981.8mV  25.06mA    17.2mA     34.01mA
-927.3mV  19.17mA    12.93mA    25.61mA
-872.7mV  15.03mA    9.767mA    20.12mA
-818.2mV  12.12mA    7.45mA     16.5mA
-654.5mV  5.738mA    2.93mA     8.003mA
-436.4mV  508.2uA    199.4uA    613uA
0V        2.273nA    15.95nA    16.67nA
[Pulldown]
-1.8V     -19.04mA   -18.02mA   -17.88mA
-1.145V   -23.87mA   -23.03mA   -22.59mA
-545.5mV  -17.69mA   -17.39mA   -17.39mA
545.5mV   18.16mA    17.9mA     18.33mA
1.091V    33.8mA     33.39mA    34.37mA
1.527V    43.21mA    42.5mA     44.68mA
1.964V    47.83mA    46.41mA    51.1mA
2.291V    48.55mA    44.5mA     53.43mA
2.618V    43.28mA    35.9mA     51.68mA
2.945V    35.6mA     23.75mA    44.98mA
3.218V    26.2mA     13.58mA    39.11mA
3.6V      14.49mA    5.303mA    26.15mA
[Pullup]
-1.8V     17.15mA    13.74mA    20.51mA
-1.309V   21.6mA     18.18mA    24.22mA
-927.3mV  20.52mA    20.27mA    21.29mA
-600mV    17.03mA    17.65mA    17.57mA
-381.8mV  12.19mA    12.29mA    12.62mA
1.2V      -36.27mA   -35.99mA   -37.86mA
1.745V    -50.17mA   -49.12mA   -52.76mA
2.127V    -58.27mA   -55.22mA   -61.77mA
2.455V    -61.03mA   -53.58mA   -67.59mA
2.727V    -58.68mA   -48.99mA   -67.43mA
3.164V    -50.29mA   -36.88mA   -59.41mA
3.6V      -37.24mA   -22.35mA   -48.89mA
[GND_clamp]
-1.8V     -346.1mA   -209.3mA   -568.3mA
-1.327V   -149.7mA   -89.03mA   -250.9mA
-1.291V   -135.6mA   -80.47mA   -227.5mA
-1.145V   -82.35mA   -48.67mA   -137.7mA
-1.073V   -59.44mA   -35.55mA   -97.96mA
-1.036V   -49.1mA    -29.72mA   -79.9mA
-927.3mV  -26.31mA   -17.11mA   -38.99mA
-854.5mV  -16.67mA   -11.64mA   -22.56mA
-818.2mV  -12.86mA   -9.351mA   -16.98mA
-672.7mV  -5.705mA   -3.913mA   -8.624mA
-381.8mV  -120.4uA   -129uA     -167.4uA
1.8V      2.273nA    454nA      6.646nA
[Ramp]
dV/dt_f 0.68310345/57.97757p  0.61753258/68.961588p 0.74858513/50.903624p
dV/dt_r 0.66841113/52.675263p 0.61035443/57.876654p 0.74327022/47.386914p
R_load = 50
[Rising Waveform]
R_fixture = 50
V_fixture = 1.8
V_fixture_min = 1.62
V_fixture_max = 1.98
0s        681.6mV    616mV      748.2mV
110.3ps   681.6mV    616mV      781.2mV
160.9ps   684.9mV    616mV      1.664V
234.1ps   838.8mV    616mV      1.914V
285.3ps   1.541V     616mV      1.943V
357.4ps   1.745V     620mV      1.963V
435.7ps   1.772V     695.4mV    1.973V
517.6ps   1.782V     1.387V     1.977V
581.3ps   1.787V     1.576V     1.978V
1.37ns    1.797V     1.616V     1.98V
[Rising Waveform]
R_fixture = 50
V_fixture = 0
V_fixture_min = 0
V_fixture_max = 0
0s        0V         0V         0V
117.1ps   0V         0V         0V
173.5ps   0V         0V         912.5mV
252.7ps   157.8mV    0V         1.167V
299.6ps   813.2mV    0V         1.192V
370ps     1.039V     0V         1.207V
468.8ps   1.076V     -7.595mV   1.217V
541.6ps   1.083V     716.7mV    1.22V
595.3ps   1.085V     922.1mV    1.221V
1.423ns   1.094V     984.3mV    1.226V
[Falling Waveform]
R_fixture = 50
V_fixture = 1.8
V_fixture_min = 1.62
V_fixture_max = 1.98
0s        1.801V     1.621V     1.981V
119.6ps   1.801V     1.621V     1.985V
186.5ps   1.801V     1.621V     1.038V
258.3ps   1.617V     1.621V     811.5mV
315.6ps   925.3mV    1.621V     780.7mV
384.5ps   737.6mV    1.621V     765.1mV
481.7ps   703.8mV    1.596V     755.7mV
567.5ps   696.6mV    866.3mV    752.1mV
627ps     693.1mV    673.3mV    750.5mV
1.37ns    684.7mV    620.7mV    747.3mV
[Falling Waveform]
R_fixture = 50
V_fixture = 0
V_fixture_min = 0
V_fixture_max = 0
0s        1.098V     989.3mV    1.225V
119.2ps   1.098V     989.3mV    1.196V
169.1ps   1.098V     989.3mV    292.9mV
246.3ps   867mV      989.3mV    56.31mV
292.2ps   225.6mV    989.3mV    31.81mV
359.4ps   53.18mV    989.3mV    15.75mV
456ps     20.68mV    924.2mV    6.778mV
529.5ps   13.95mV    229.9mV    4.114mV
589.9ps   10.55mV    45.47mV    2.857mV
1.423ns   3.789mV    3.467mV    0V
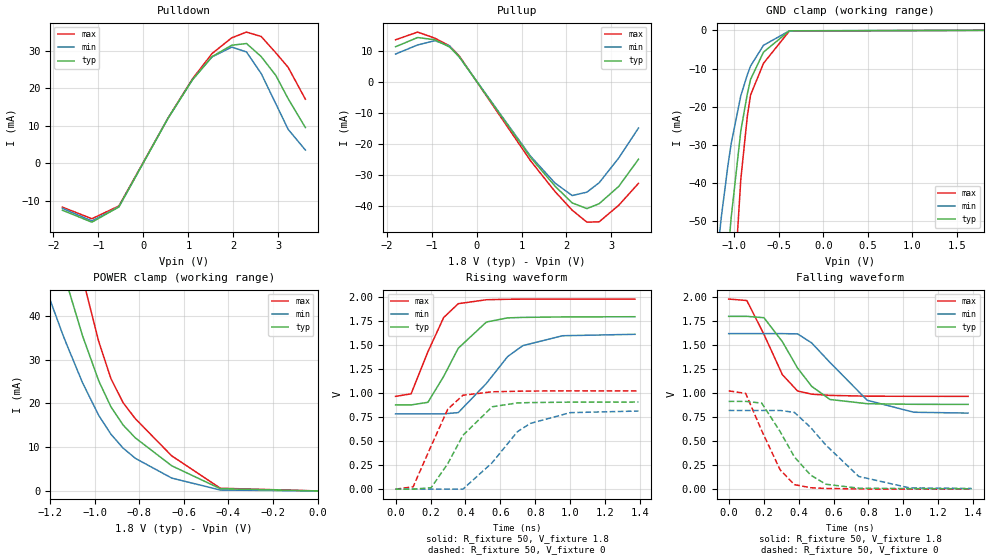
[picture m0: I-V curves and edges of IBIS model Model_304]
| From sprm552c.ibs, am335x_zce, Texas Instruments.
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| Model based on original model for BCSHTLTCSCDVPBFZ_SSDHV
|   Sub model SR01_8MA_10PER_1P8
[model]   Model_304
|[Description]  [1.8V-3-STATE-NOTERM-SR01:8MA, IND, 10%]
|   Slow slew rate (SR[1:0] = "01"), 1.00 * RExt = 1.000 * Iout
|   (I[2:0] = "011"), 8mA nominal with Rext = 50R,ODT off (ODT[1:0]
|   = "00") CMOS mode,Industrial temperature range (-40C to 125C,
|   25C nominal),10% power supply tolerance
|[Input Load]   NOTERM
|[Output Drive] SR01:8MA
|Voltage   1.8V
|Mode   3-STATE
Model_type   3-state
Polarity   Non-Inverting
Enable   Active-Low
Cref =  15pF
Rref =  100.0000M
Vref =  0V
Vmeas =  0.9
C_comp   1.851324p   1.663768p   1.973575p
[Temperature Range]   25   125   -40
[Voltage Range]   1.8   1.62   1.98
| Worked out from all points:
|   slope of the pulldown table from 0 to 0.27 V, typ, clamps not added: 44.4 ohm
|   slope of the pullup table from 0 to 0.27 V, typ, clamps not added: 47 ohm
|   GND clamp passes 1 mA (typ) near -0.49 V on its own axis
|   POWER clamp passes 1 mA (typ) near -0.47 V on its own axis
|   rising waveform, R_fixture 50, V_fixture 1.8: 20-80 % time 178ps typ, 227ps min, 139ps max; typ from 0.877 V to 1.8 V
|   rising waveform, R_fixture 50, V_fixture 0: 20-80 % time 183ps typ, 239ps min, 146ps max; typ from 0 V to 0.907 V
|   falling waveform, R_fixture 50, V_fixture 1.8: 20-80 % time 199ps typ, 249ps min, 152ps max; typ from 1.8 V to 0.882 V
|   falling waveform, R_fixture 50, V_fixture 0: 20-80 % time 195ps typ, 244ps min, 150ps max; typ from 0.914 V to 0.004 V
[POWER_clamp]
-1.8V     194.9mA    137.1mA    262.8mA
-1.236V   68.49mA    48.51mA    92.67mA
-1.145V   50.76mA    35.86mA    69.65mA
-1.127V   47.56mA    33.54mA    65.34mA
-1.055V   35.4mA     24.69mA    48.69mA
-981.8mV  25.06mA    17.2mA     34.01mA
-927.3mV  19.17mA    12.93mA    25.61mA
-872.7mV  15.03mA    9.767mA    20.12mA
-818.2mV  12.12mA    7.45mA     16.5mA
-654.5mV  5.738mA    2.93mA     8.003mA
-436.4mV  508.2uA    199.4uA    613uA
0V        2.273nA    15.95nA    16.67nA
[Pulldown]
-1.8V     -12.51mA   -12.01mA   -11.68mA
-1.145V   -15.69mA   -15.35mA   -14.77mA
-545.5mV  -11.63mA   -11.6mA    -11.38mA
545.5mV   11.95mA    11.95mA    12mA
1.091V    22.23mA    22.28mA    22.49mA
1.527V    28.41mA    28.35mA    29.24mA
1.964V    31.44mA    30.94mA    33.42mA
2.291V    31.9mA     29.65mA    34.94mA
2.618V    28.42mA    23.91mA    33.77mA
2.945V    23.37mA    15.81mA    29.39mA
3.218V    17.19mA    9.044mA    25.55mA
3.6V      9.513mA    3.534mA    17.07mA
[Pullup]
-1.8V     11.43mA    9.077mA    13.67mA
-1.309V   14.4mA     12.01mA    16.15mA
-927.3mV  13.68mA    13.39mA    14.2mA
-600mV    11.36mA    11.67mA    11.72mA
-381.8mV  8.135mA    8.127mA    8.423mA
1.2V      -24.2mA    -23.8mA    -25.27mA
1.745V    -33.47mA   -32.48mA   -35.2mA
2.127V    -38.87mA   -36.49mA   -41.21mA
2.455V    -40.69mA   -35.39mA   -45.07mA
2.727V    -39.11mA   -32.35mA   -44.94mA
3.164V    -33.5mA    -24.34mA   -39.58mA
3.6V      -24.8mA    -14.75mA   -32.56mA
[GND_clamp]
-1.8V     -346.1mA   -209.3mA   -568.3mA
-1.327V   -149.7mA   -89.03mA   -250.9mA
-1.291V   -135.6mA   -80.47mA   -227.5mA
-1.145V   -82.35mA   -48.67mA   -137.7mA
-1.073V   -59.44mA   -35.55mA   -97.96mA
-1.036V   -49.1mA    -29.72mA   -79.9mA
-927.3mV  -26.31mA   -17.11mA   -38.99mA
-854.5mV  -16.67mA   -11.64mA   -22.56mA
-818.2mV  -12.86mA   -9.351mA   -16.98mA
-672.7mV  -5.705mA   -3.913mA   -8.624mA
-381.8mV  -120.4uA   -129uA     -167.4uA
1.8V      2.273nA    454nA      6.646nA
[Ramp]
dV/dt_f 0.55469004/0.20106905n 0.50202418/0.25166312n 0.60934671/0.15178101n
dV/dt_r 0.54951818/0.18589275n 0.49267917/0.24070999n 0.61553421/0.14574344n
R_load = 50
[Rising Waveform]
R_fixture = 50
V_fixture = 1.8
V_fixture_min = 1.62
V_fixture_max = 1.98
0s        877.3mV    784.2mV    966.6mV
89ps      877.3mV    784.2mV    992.7mV
185.3ps   904.7mV    784.2mV    1.432V
275.5ps   1.175V     784.3mV    1.788V
358.9ps   1.468V     797.5mV    1.932V
520ps     1.741V     1.102V     1.973V
641.2ps   1.784V     1.381V     1.978V
728.2ps   1.789V     1.495V     1.979V
955.2ps   1.794V     1.598V     1.98V
1.37ns    1.796V     1.613V     1.98V
[Rising Waveform]
R_fixture = 50
V_fixture = 0
V_fixture_min = 0
V_fixture_max = 0
0s        0V         0V         0V
100.6ps   0V         0V         24.54mV
203.5ps   15.09mV    0V         449.4mV
299.1ps   266.6mV    0V         833.6mV
385.5ps   560.7mV    0V         978.3mV
552.6ps   858.1mV    275.3mV    1.014V
697ps     898.3mV    598.1mV    1.02V
770.5ps   901.9mV    684.3mV    1.022V
999ps     906.3mV    797mV      1.024V
1.39ns    907.3mV    813.7mV    1.024V
[Falling Waveform]
R_fixture = 50
V_fixture = 1.8
V_fixture_min = 1.62
V_fixture_max = 1.98
0s        1.799V     1.619V     1.979V
103.7ps   1.799V     1.619V     1.964V
201.7ps   1.785V     1.619V     1.612V
307.3ps   1.535V     1.619V     1.192V
394.1ps   1.261V     1.617V     1.022V
475.2ps   1.07V      1.522V     989mV
580.2ps   933.5mV    1.318V     976.3mV
793.1ps   889.6mV    925.2mV    967.9mV
1.059ns   883.4mV    800.8mV    966.7mV
1.37ns    882.2mV    792mV      965.9mV
[Falling Waveform]
R_fixture = 50
V_fixture = 0
V_fixture_min = 0
V_fixture_max = 0
0s        913.6mV    819.4mV    1.023V
97.3ps    913.6mV    819.4mV    996.8mV
189.1ps   896mV      819.4mV    608.7mV
294.4ps   599.7mV    819.4mV    201.5mV
376ps     335.8mV    799.3mV    47.34mV
468.5ps   147.3mV    643.5mV    15.11mV
555.6ps   51.47mV    459.7mV    7.405mV
744.1ps   10.15mV    132.7mV    2.337mV
1.036ns   5.857mV    12.84mV    0V
1.39ns    4.123mV    7.605mV    0V
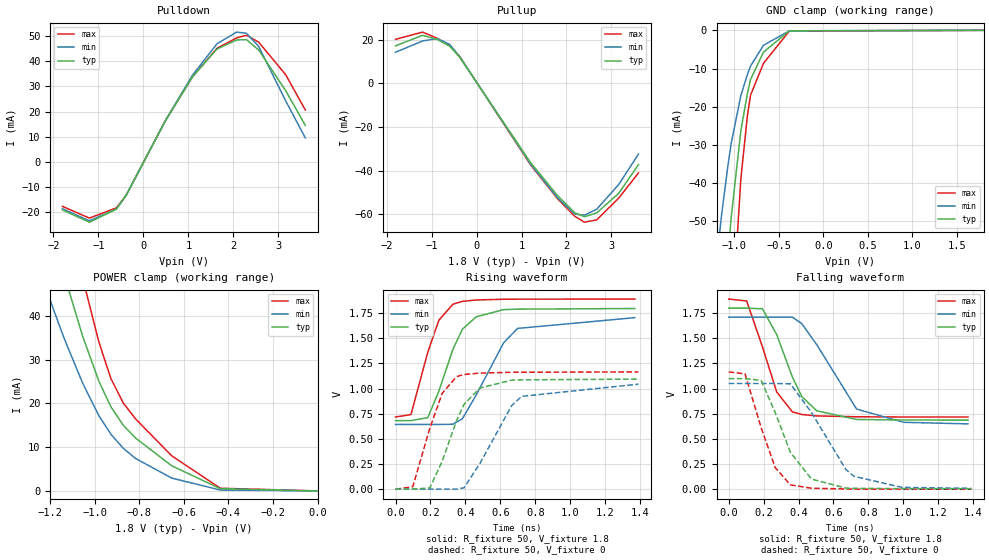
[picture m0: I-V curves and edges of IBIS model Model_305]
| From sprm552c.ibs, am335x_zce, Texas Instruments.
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| Model based on original model for BCSHTLTCSCDVPBFZ_SSDHV
|   Sub model SR01_12MA_5PER_1P8
[model]   Model_305
|[Description]  [1.8V-3-STATE-NOTERM-SR01:12MA, IND, 5%]
|   Slow slew rate (SR[1:0] = "01"), 0.67 * RExt = 1.500 * Iout
|   (I[2:0] = "111"), 12mA nominal with Rext = 50R,ODT off (ODT[1:0]
|   = "00") CMOS mode,Industrial temperature range (-40C to 125C,
|   25C nominal),5% power supply tolerance
|[Input Load]   NOTERM
|[Output Drive] SR01:12MA
|Voltage   1.8V
|Mode   3-STATE
Model_type   3-state
Polarity   Non-Inverting
Enable   Active-Low
Cref =  15pF
Rref =  100.0000M
Vref =  0V
Vmeas =  0.9
C_comp   1.851324p   1.667199p   1.973575p
[Temperature Range]   25   125   -40
[Voltage Range]   1.8   1.71   1.89
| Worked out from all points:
|   slope of the pulldown table from 0 to 0.27 V, typ, clamps not added: 29.2 ohm
|   slope of the pullup table from 0 to 0.27 V, typ, clamps not added: 31.3 ohm
|   GND clamp passes 1 mA (typ) near -0.49 V on its own axis
|   POWER clamp passes 1 mA (typ) near -0.47 V on its own axis
|   rising waveform, R_fixture 50, V_fixture 1.8: 20-80 % time 142ps typ, 198ps min, 113ps max; typ from 0.682 V to 1.8 V
|   rising waveform, R_fixture 50, V_fixture 0: 20-80 % time 150ps typ, 198ps min, 121ps max; typ from 0 V to 1.09 V
|   falling waveform, R_fixture 50, V_fixture 1.8: 20-80 % time 159ps typ, 211ps min, 124ps max; typ from 1.8 V to 0.686 V
|   falling waveform, R_fixture 50, V_fixture 0: 20-80 % time 156ps typ, 217ps min, 125ps max; typ from 1.1 V to 0.004 V
[POWER_clamp]
-1.8V     194.9mA    137mA      262.9mA
-1.236V   68.49mA    48.49mA    92.7mA
-1.145V   50.76mA    35.84mA    69.67mA
-1.127V   47.56mA    33.52mA    65.35mA
-1.055V   35.4mA     24.68mA    48.7mA
-981.8mV  25.06mA    17.19mA    34.02mA
-927.3mV  19.17mA    12.92mA    25.62mA
-872.7mV  15.03mA    9.76mA     20.13mA
-818.2mV  12.12mA    7.445mA    16.51mA
-654.5mV  5.738mA    2.929mA    8.007mA
-436.4mV  508.2uA    199.4uA    613uA
0V        2.273nA    16.6nA     10.58nA
[Pulldown]
-1.8V     -19.04mA   -18.57mA   -17.62mA
-1.2V     -23.91mA   -23.36mA   -22.29mA
-600mV    -18.74mA   -18.66mA   -18.22mA
-381.8mV  -13.2mA    -13.18mA   -13.15mA
490.9mV   16.44mA    16.5mA     16.44mA
1.091V    33.8mA     34.43mA    33.8mA
1.636V    44.84mA    46.91mA    45.1mA
2.073V    48.42mA    51.54mA    49.25mA
2.291V    48.55mA    51.08mA    50.28mA
2.564V    44.4mA     45.79mA    47.52mA
3.164V    28.26mA    24.2mA     34.59mA
3.6V      14.49mA    9.532mA    20.59mA
[Pullup]
-1.8V     17.15mA    14.22mA    20.14mA
-1.2V     22mA       19.38mA    23.46mA
-872.7mV  20.07mA    20.5mA     20.63mA
-600mV    17.03mA    17.85mA    17.44mA
-381.8mV  12.19mA    12.42mA    12.53mA
1.2V      -36.27mA   -36.93mA   -37.3mA
1.8V      -51.43mA   -52.45mA   -52.86mA
2.182V    -59.24mA   -59.89mA   -60.87mA
2.4V      -61.1mA    -60.37mA   -63.6mA
2.673V    -59.34mA   -57.66mA   -62.53mA
3.164V    -50.29mA   -46.25mA   -52.48mA
3.6V      -37.24mA   -32.39mA   -41.05mA
[GND_clamp]
-1.8V     -346.1mA   -209.3mA   -568.3mA
-1.327V   -149.7mA   -89.03mA   -250.9mA
-1.291V   -135.6mA   -80.47mA   -227.5mA
-1.145V   -82.35mA   -48.67mA   -137.7mA
-1.073V   -59.44mA   -35.55mA   -97.96mA
-1.036V   -49.1mA    -29.72mA   -79.9mA
-927.3mV  -26.31mA   -17.11mA   -38.99mA
-854.5mV  -16.67mA   -11.64mA   -22.56mA
-818.2mV  -12.86mA   -9.351mA   -16.98mA
-672.7mV  -5.705mA   -3.913mA   -8.623mA
-381.8mV  -120.4uA   -129uA     -167.2uA
1.8V      2.273nA    51.44nA    6.654nA
[Ramp]
dV/dt_f 0.67303609/0.16132248n 0.64218928/0.21289664n 0.70526523/0.12451412n
dV/dt_r 0.66107017/0.15150687n  0.6329406/0.20004215n 0.70125996/0.12080094n
R_load = 50
[Rising Waveform]
R_fixture = 50
V_fixture = 1.8
V_fixture_min = 1.71
V_fixture_max = 1.89
0s        681.6mV    643.1mV    717.7mV
88.3ps    681.6mV    643.1mV    741.8mV
184.5ps   711.3mV    643.1mV    1.361V
248ps     974.1mV    643.1mV    1.68V
328.8ps   1.392V     645.7mV    1.839V
382.9ps   1.591V     700.6mV    1.867V
462.2ps   1.714V     937.5mV    1.881V
618.7ps   1.785V     1.455V     1.888V
698.5ps   1.79V      1.598V     1.889V
1.37ns    1.796V     1.705V     1.89V
[Rising Waveform]
R_fixture = 50
V_fixture = 0
V_fixture_min = 0
V_fixture_max = 0
0s        0V         0V         0V
98.6ps    0V         0V         23.7mV
196.1ps   12.07mV    0V         604.6mV
267.2ps   277.8mV    0V         953.5mV
349.2ps   681.5mV    0V         1.119V
392.1ps   843.4mV    13.64mV    1.14V
482.5ps   1.005V     253.7mV    1.154V
665.2ps   1.084V     831.5mV    1.162V
722.1ps   1.087V     922.7mV    1.162V
1.391ns   1.094V     1.044V     1.166V
[Falling Waveform]
R_fixture = 50
V_fixture = 1.8
V_fixture_min = 1.71
V_fixture_max = 1.89
0s        1.799V     1.709V     1.889V
103ps     1.799V     1.709V     1.87V
193.3ps   1.792V     1.709V     1.415V
275.2ps   1.535V     1.709V     965.5mV
364.7ps   1.115V     1.709V     768.3mV
418.6ps   920.5mV    1.645V     742.2mV
504.4ps   778.6mV    1.436V     728mV
732.6ps   692.5mV    795.4mV    719.3mV
1.003ns   687.2mV    664.2mV    717.1mV
1.37ns    686mV      648.8mV    716.8mV
[Falling Waveform]
R_fixture = 50
V_fixture = 0
V_fixture_min = 0
V_fixture_max = 0
0s        1.098V     1.05V      1.165V
93.6ps    1.098V     1.05V      1.146V
185.9ps   1.081V     1.05V      611.4mV
266.2ps   763mV      1.05V      215.1mV
353.2ps   366mV      1.047V     43.17mV
474.4ps   100.2mV    760.5mV    9.111mV
671.6ps   10.54mV    194.1mV    2.365mV
717.1ps   8.687mV    128.1mV    0V
991.9ps   5.046mV    17.67mV    0V
1.391ns   4.151mV    8.2mV      0V
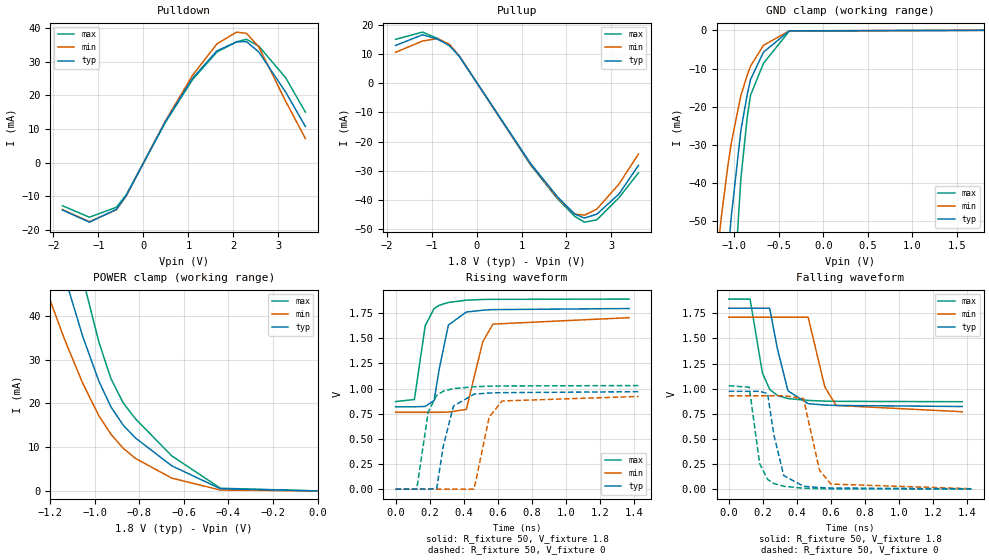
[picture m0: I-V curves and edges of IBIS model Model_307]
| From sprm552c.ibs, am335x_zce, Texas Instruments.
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| Model based on original model for BCSHTLTCSCDVPBFZ_SSDHV
|   Sub model SR00_9MA_5PER_1P8
[model]   Model_307
|[Description]  [1.8V-3-STATE-NOTERM-SR00:9MA, IND, 5%]
|   Fastest slew rate (SR[1:0] = "00"), 0.88 * RExt = 1.125 * Iout
|   (I[2:0] = "100"), 9mA nominal with Rext = 50R,ODT off (ODT[1:0]
|   = "00") CMOS mode,Industrial temperature range (-40C to 125C,
|   25C nominal),5% power supply tolerance
|[Input Load]   NOTERM
|[Output Drive] SR00:9MA
|Voltage   1.8V
|Mode   3-STATE
Model_type   3-state
Polarity   Non-Inverting
Enable   Active-Low
Cref =  15pF
Rref =  100.0000M
Vref =  0V
Vmeas =  0.9
C_comp   1.851324p   1.667199p   1.973575p
[Temperature Range]   25   125   -40
[Voltage Range]   1.8   1.71   1.89
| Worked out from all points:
|   slope of the pulldown table from 0 to 0.27 V, typ, clamps not added: 39.3 ohm
|   slope of the pullup table from 0 to 0.27 V, typ, clamps not added: 41.3 ohm
|   GND clamp passes 1 mA (typ) near -0.49 V on its own axis
|   POWER clamp passes 1 mA (typ) near -0.47 V on its own axis
|   rising waveform, R_fixture 50, V_fixture 1.8: 20-80 % time 60.6ps typ, 70.2ps min, 55.2ps max; typ from 0.819 V to 1.8 V
|   rising waveform, R_fixture 50, V_fixture 0: 20-80 % time 62.8ps typ, 65.9ps min, 58.6ps max; typ from 0 V to 0.969 V
|   falling waveform, R_fixture 50, V_fixture 1.8: 20-80 % time 69.7ps typ, 76.1ps min, 65ps max; typ from 1.8 V to 0.822 V
|   falling waveform, R_fixture 50, V_fixture 0: 20-80 % time 57.6ps typ, 64.6ps min, 53.6ps max; typ from 0.973 V to 0.004 V
[POWER_clamp]
-1.8V     194.9mA    137mA      262.9mA
-1.236V   68.49mA    48.49mA    92.7mA
-1.145V   50.76mA    35.84mA    69.67mA
-1.127V   47.56mA    33.52mA    65.35mA
-1.055V   35.4mA     24.68mA    48.7mA
-981.8mV  25.06mA    17.19mA    34.02mA
-927.3mV  19.17mA    12.92mA    25.62mA
-872.7mV  15.03mA    9.76mA     20.13mA
-818.2mV  12.12mA    7.445mA    16.51mA
-654.5mV  5.738mA    2.929mA    8.007mA
-436.4mV  508.2uA    199.4uA    613uA
0V        2.273nA    16.6nA     10.58nA
[Pulldown]
-1.8V     -14.14mA   -14.01mA   -12.87mA
-1.2V     -17.77mA   -17.62mA   -16.29mA
-600mV    -13.93mA   -14.08mA   -13.32mA
-381.8mV  -9.817mA   -9.949mA   -9.615mA
490.9mV   12.22mA    12.46mA    12.03mA
1.091V    25.12mA    25.99mA    24.71mA
1.636V    33.32mA    35.4mA     32.97mA
2.073V    35.97mA    38.89mA    36mA
2.291V    36.06mA    38.52mA    36.74mA
2.564V    32.97mA    34.52mA    34.71mA
3.164V    20.97mA    18.24mA    25.26mA
3.6V      10.76mA    7.187mA    15.03mA
[Pullup]
-1.8V     12.99mA    10.66mA    15.1mA
-1.2V     16.67mA    14.53mA    17.6mA
-872.7mV  15.21mA    15.38mA    15.47mA
-600mV    12.91mA    13.4mA     13.08mA
-381.8mV  9.242mA    9.325mA    9.406mA
1.2V      -27.49mA   -27.72mA   -27.99mA
1.8V      -38.98mA   -39.36mA   -39.67mA
2.182V    -44.9mA    -44.93mA   -45.68mA
2.4V      -46.28mA   -45.27mA   -47.7mA
2.673V    -44.94mA   -43.23mA   -46.89mA
3.164V    -38.07mA   -34.66mA   -39.34mA
3.6V      -28.19mA   -24.27mA   -30.76mA
[GND_clamp]
-1.8V     -346.1mA   -209.3mA   -568.3mA
-1.327V   -149.7mA   -89.03mA   -250.9mA
-1.291V   -135.6mA   -80.47mA   -227.5mA
-1.145V   -82.35mA   -48.67mA   -137.7mA
-1.073V   -59.44mA   -35.55mA   -97.96mA
-1.036V   -49.1mA    -29.72mA   -79.9mA
-927.3mV  -26.31mA   -17.11mA   -38.99mA
-854.5mV  -16.67mA   -11.64mA   -22.56mA
-818.2mV  -12.86mA   -9.351mA   -16.98mA
-672.7mV  -5.705mA   -3.913mA   -8.623mA
-381.8mV  -120.4uA   -129uA     -167.2uA
1.8V      2.273nA    51.44nA    6.654nA
[Ramp]
dV/dt_f 0.59844114/70.639324p 0.57942528/77.268647p 0.61870816/64.706247p
dV/dt_r 0.59103689/63.385046p   0.568473/67.168275p 0.62430025/58.58355p
R_load = 50
[Rising Waveform]
R_fixture = 50
V_fixture = 1.8
V_fixture_min = 1.71
V_fixture_max = 1.89
0s        818.8mV    764.4mV    870.8mV
110.5ps   818.8mV    764.4mV    891.1mV
174.1ps   822.7mV    764.4mV    1.626V
226.2ps   881.2mV    764.4mV    1.796V
256.2ps   1.194V     764.4mV    1.828V
309.9ps   1.631V     766.2mV    1.856V
414.9ps   1.761V     793.1mV    1.879V
511.7ps   1.779V     1.466V     1.886V
571.1ps   1.785V     1.641V     1.887V
1.37ns    1.796V     1.705V     1.89V
[Rising Waveform]
R_fixture = 50
V_fixture = 0
V_fixture_min = 0
V_fixture_max = 0
0s        0V         0V         0V
124.3ps   0V         0V         0V
191.8ps   0V         0V         769.4mV
241.4ps   7.382mV    0V         932.9mV
279.9ps   426.5mV    0V         974.5mV
339.5ps   825.9mV    0V         1V
460.9ps   944.5mV    0V         1.018V
549.2ps   955.7mV    716.9mV    1.024V
624.8ps   959.7mV    876.9mV    1.026V
1.425ns   969mV      921.7mV    1.03V
[Falling Waveform]
R_fixture = 50
V_fixture = 1.8
V_fixture_min = 1.71
V_fixture_max = 1.89
0s        1.8V       1.711V     1.891V
125.5ps   1.8V       1.711V     1.891V
197.7ps   1.8V       1.711V     1.157V
240.5ps   1.8V       1.711V     992.5mV
286.4ps   1.392V     1.711V     931mV
347.5ps   979mV      1.711V     901.5mV
466.1ps   850.5mV    1.711V     882.6mV
564.1ps   836.7mV    1.016V     875.8mV
630.1ps   833mV      832.9mV    873.7mV
1.37ns    822.1mV    770.2mV    869.9mV
[Falling Waveform]
R_fixture = 50
V_fixture = 0
V_fixture_min = 0
V_fixture_max = 0
0s        973.2mV    929.1mV    1.029V
120.7ps   973.2mV    929.1mV    1.014V
181.5ps   973.2mV    929.1mV    255mV
228.2ps   951mV      929.1mV    97.63mV
264.6ps   543.9mV    929.1mV    56.35mV
322.9ps   135.5mV    929.1mV    28.74mV
438.7ps   28.66mV    902.3mV    9.705mV
532.9ps   15.87mV    187.3mV    5.015mV
599.9ps   11.64mV    50.77mV    3.344mV
1.425ns   3.584mV    4.224mV    0V
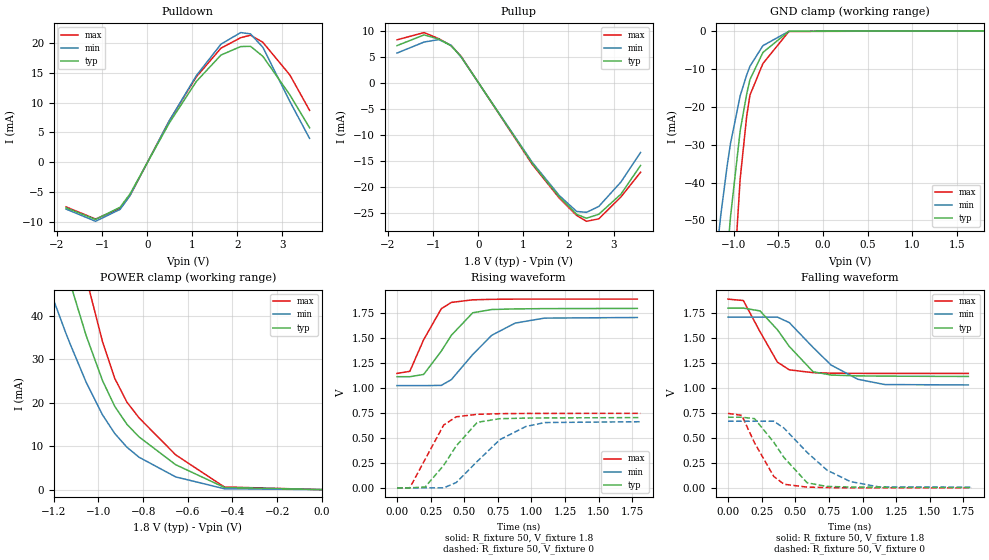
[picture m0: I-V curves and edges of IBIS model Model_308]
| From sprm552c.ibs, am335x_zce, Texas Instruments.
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| Model based on original model for BCSHTLTCSCDVPBFZ_SSDHV
|   Sub model SR01_5MA_5PER_1P8
[model]   Model_308
|[Description]  [1.8V-3-STATE-NOTERM-SR01:5MA, IND, 5%]
|   Slow slew rate (SR[1:0] = "01"), 1.60 * RExt = 0.625 * Iout
|   (I[2:0] = "000"), 5mA nominal with Rext = 50R,ODT off (ODT[1:0]
|   = "00") CMOS mode,Industrial temperature range (-40C to 125C,
|   25C nominal),5% power supply tolerance
|[Input Load]   NOTERM
|[Output Drive] SR01:5MA
|Voltage   1.8V
|Mode   3-STATE
Model_type   3-state
Polarity   Non-Inverting
Enable   Active-Low
Cref =  15pF
Rref =  100.0000M
Vref =  0V
Vmeas =  0.9
C_comp   1.851324p   1.667199p   1.973575p
[Temperature Range]   25   125   -40
[Voltage Range]   1.8   1.71   1.89
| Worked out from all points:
|   slope of the pulldown table from 0 to 0.27 V, typ, clamps not added: 72.9 ohm
|   slope of the pullup table from 0 to 0.27 V, typ, clamps not added: 73.8 ohm
|   GND clamp passes 1 mA (typ) near -0.49 V on its own axis
|   POWER clamp passes 1 mA (typ) near -0.47 V on its own axis
|   rising waveform, R_fixture 50, V_fixture 1.8: 20-80 % time 206ps typ, 299ps min, 161ps max; typ from 1.11 V to 1.8 V
|   rising waveform, R_fixture 50, V_fixture 0: 20-80 % time 213ps typ, 318ps min, 171ps max; typ from 0 V to 0.704 V
|   falling waveform, R_fixture 50, V_fixture 1.8: 20-80 % time 227ps typ, 323ps min, 175ps max; typ from 1.8 V to 1.11 V
|   falling waveform, R_fixture 50, V_fixture 0: 20-80 % time 223ps typ, 322ps min, 175ps max; typ from 0.707 V to 0.003 V
[POWER_clamp]
-1.8V     194.9mA    137mA      262.9mA
-1.236V   68.49mA    48.49mA    92.7mA
-1.145V   50.76mA    35.84mA    69.67mA
-1.127V   47.56mA    33.52mA    65.35mA
-1.055V   35.4mA     24.68mA    48.7mA
-981.8mV  25.06mA    17.19mA    34.02mA
-927.3mV  19.17mA    12.92mA    25.62mA
-872.7mV  15.03mA    9.76mA     20.13mA
-818.2mV  12.12mA    7.445mA    16.51mA
-654.5mV  5.738mA    2.929mA    8.007mA
-436.4mV  508.2uA    199.4uA    613uA
0V        2.273nA    16.6nA     10.58nA
[Pulldown]
-1.8V     -7.609mA   -7.815mA   -7.446mA
-1.145V   -9.551mA   -9.863mA   -9.487mA
-600mV    -7.505mA   -7.866mA   -7.717mA
-381.8mV  -5.292mA   -5.559mA   -5.572mA
490.9mV   6.589mA    6.96mA     6.97mA
1.091V    13.54mA    14.52mA    14.32mA
1.636V    17.95mA    19.77mA    19.1mA
2.073V    19.37mA    21.71mA    20.85mA
2.291V    19.41mA    21.49mA    21.27mA
2.564V    17.74mA    19.25mA    20.08mA
3.164V    11.28mA    10.17mA    14.61mA
3.6V      5.787mA    4.008mA    8.697mA
[Pullup]
-1.8V     7.273mA    5.836mA    8.384mA
-1.2V     9.332mA    7.957mA    9.779mA
-872.7mV  8.52mA     8.421mA    8.6mA
-600mV    7.23mA     7.34mA     7.272mA
-381.8mV  5.181mA    5.112mA    5.231mA
1.2V      -15.41mA   -15.19mA   -15.57mA
1.8V      -21.85mA   -21.57mA   -22.06mA
2.182V    -25.16mA   -24.61mA   -25.39mA
2.4V      -25.92mA   -24.79mA   -26.51mA
2.673V    -25.16mA   -23.66mA   -26.04mA
3.164V    -21.3mA    -18.96mA   -21.84mA
3.6V      -15.77mA   -13.28mA   -17.07mA
[GND_clamp]
-1.8V     -346.1mA   -209.3mA   -568.3mA
-1.327V   -149.7mA   -89.03mA   -250.9mA
-1.291V   -135.6mA   -80.47mA   -227.5mA
-1.145V   -82.35mA   -48.67mA   -137.7mA
-1.073V   -59.44mA   -35.55mA   -97.96mA
-1.036V   -49.1mA    -29.72mA   -79.9mA
-927.3mV  -26.31mA   -17.11mA   -38.99mA
-854.5mV  -16.67mA   -11.64mA   -22.56mA
-818.2mV  -12.86mA   -9.351mA   -16.98mA
-672.7mV  -5.705mA   -3.913mA   -8.623mA
-381.8mV  -120.4uA   -129uA     -167.2uA
1.8V      2.273nA    51.44nA    6.654nA
[Ramp]
dV/dt_f 0.41332087/0.22947956n  0.4121048/0.3268164n 0.44772412/0.17531366n
dV/dt_r 0.42511619/0.21445646n 0.40038508/0.32062451n 0.44838931/0.17135297n
R_load = 50
[Rising Waveform]
R_fixture = 50
V_fixture = 1.8
V_fixture_min = 1.71
V_fixture_max = 1.89
0s        1.113V     1.024V     1.146V
95.2ps    1.113V     1.024V     1.167V
198.3ps   1.136V     1.024V     1.484V
329.2ps   1.369V     1.026V     1.794V
404.2ps   1.528V     1.084V     1.857V
562.7ps   1.753V     1.335V     1.883V
704.6ps   1.786V     1.528V     1.888V
878.4ps   1.792V     1.65V      1.89V
1.097ns   1.795V     1.7V       1.89V
1.787ns   1.797V     1.706V     1.89V
[Rising Waveform]
R_fixture = 50
V_fixture = 0
V_fixture_min = 0
V_fixture_max = 0
0s        0V         0V         0V
94.9ps    0V         0V         0V
209.6ps   8.884mV    0V         286.9mV
347ps     225.3mV    0V         629.2mV
440.4ps   420.1mV    53.12mV    711.5mV
596.5ps   656.1mV    265.1mV    736.6mV
764.5ps   692.8mV    482.4mV    743mV
958.2ps   698.6mV    614.9mV    745.1mV
1.101ns   700.4mV    654.1mV    745.7mV
1.811ns   703.6mV    662.5mV    746.1mV
[Falling Waveform]
R_fixture = 50
V_fixture = 1.8
V_fixture_min = 1.71
V_fixture_max = 1.89
0s        1.799V     1.709V     1.889V
114.1ps   1.799V     1.709V     1.875V
238ps     1.771V     1.709V     1.563V
367.1ps   1.583V     1.709V     1.259V
455.8ps   1.415V     1.654V     1.181V
632.8ps   1.162V     1.405V     1.153V
766.6ps   1.129V     1.229V     1.148V
965.2ps   1.121V     1.087V     1.146V
1.166ns   1.118V     1.034V     1.145V
1.787ns   1.115V     1.03V      1.145V
[Falling Waveform]
R_fixture = 50
V_fixture = 0
V_fixture_min = 0
V_fixture_max = 0
0s        706.9mV    666.8mV    745.2mV
101.9ps   706.9mV    666.8mV    726.1mV
197ps     692.9mV    666.8mV    451.4mV
340.2ps   457.1mV    666.8mV    114.5mV
416.6ps   302.9mV    597.9mV    35.99mV
588.6ps   50.49mV    354.2mV    7.427mV
736.1ps   14.15mV    177.1mV    2.979mV
910ps     8.245mV    62.92mV    0V
1.121ns   6.009mV    9.675mV    0V
1.811ns   3.306mV    5.391mV    0V
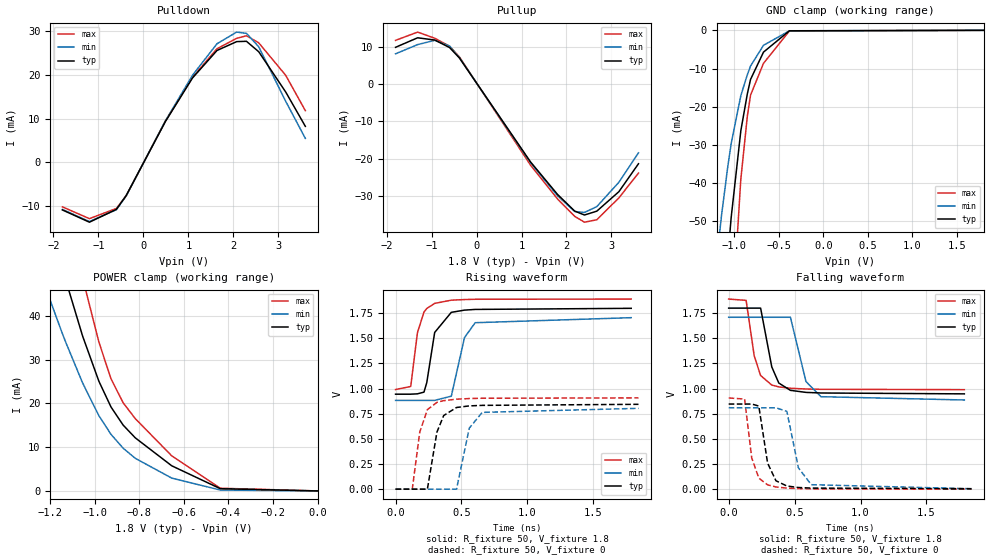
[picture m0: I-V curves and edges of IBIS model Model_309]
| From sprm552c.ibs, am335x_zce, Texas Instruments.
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| Model based on original model for BCSHTLTCSCDVPBFZ_SSDHV
|   Sub model SR00_7MA_5PER_1P8
[model]   Model_309
|[Description]  [1.8V-3-STATE-NOTERM-SR00:7MA, IND, 5%]
|   Fastest slew rate (SR[1:0] = "00"), 1.14 * RExt = 0.875 * Iout
|   (I[2:0] = "010"), 7mA nominal with Rext = 50R,ODT off (ODT[1:0]
|   = "00") CMOS mode,Industrial temperature range (-40C to 125C,
|   25C nominal),5% power supply tolerance
|[Input Load]   NOTERM
|[Output Drive] SR00:7MA
|Voltage   1.8V
|Mode   3-STATE
Model_type   3-state
Polarity   Non-Inverting
Enable   Active-Low
Cref =  15pF
Rref =  100.0000M
Vref =  0V
Vmeas =  0.9
C_comp   1.851324p   1.667199p   1.973575p
[Temperature Range]   25   125   -40
[Voltage Range]   1.8   1.71   1.89
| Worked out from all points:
|   slope of the pulldown table from 0 to 0.27 V, typ, clamps not added: 51.1 ohm
|   slope of the pullup table from 0 to 0.27 V, typ, clamps not added: 54.4 ohm
|   GND clamp passes 1 mA (typ) near -0.49 V on its own axis
|   POWER clamp passes 1 mA (typ) near -0.47 V on its own axis
|   rising waveform, R_fixture 50, V_fixture 1.8: 20-80 % time 70.9ps typ, 80.5ps min, 64ps max; typ from 0.944 V to 1.8 V
|   rising waveform, R_fixture 50, V_fixture 0: 20-80 % time 74.2ps typ, 78.3ps min, 68.1ps max; typ from 0 V to 0.844 V
|   falling waveform, R_fixture 50, V_fixture 1.8: 20-80 % time 81.6ps typ, 88.7ps min, 74.6ps max; typ from 1.8 V to 0.947 V
|   falling waveform, R_fixture 50, V_fixture 0: 20-80 % time 66.5ps typ, 74.9ps min, 61.4ps max; typ from 0.846 V to 0.005 V
[POWER_clamp]
-1.8V     194.9mA    137mA      262.9mA
-1.236V   68.49mA    48.49mA    92.7mA
-1.145V   50.76mA    35.84mA    69.67mA
-1.127V   47.56mA    33.52mA    65.35mA
-1.055V   35.4mA     24.68mA    48.7mA
-981.8mV  25.06mA    17.19mA    34.02mA
-927.3mV  19.17mA    12.92mA    25.62mA
-872.7mV  15.03mA    9.76mA     20.13mA
-818.2mV  12.12mA    7.445mA    16.51mA
-654.5mV  5.738mA    2.929mA    8.007mA
-436.4mV  508.2uA    199.4uA    613uA
0V        2.273nA    16.6nA     10.58nA
[Pulldown]
-1.8V     -10.87mA   -10.75mA   -10.16mA
-1.2V     -13.67mA   -13.52mA   -12.86mA
-600mV    -10.72mA   -10.81mA   -10.52mA
-381.8mV  -7.555mA   -7.639mA   -7.594mA
490.9mV   9.408mA    9.565mA    9.5mA
1.091V    19.34mA    19.96mA    19.52mA
1.636V    25.64mA    27.18mA    26.04mA
2.073V    27.67mA    29.85mA    28.42mA
2.291V    27.74mA    29.56mA    29.01mA
2.564V    25.35mA    26.48mA    27.39mA
3.164V    16.12mA    13.99mA    19.94mA
3.6V      8.27mA     5.513mA    11.86mA
[Pullup]
-1.8V     9.872mA    8.121mA    11.74mA
-1.309V   12.43mA    10.6mA     13.96mA
-927.3mV  11.82mA    11.75mA    12.3mA
-600mV    9.811mA    10.21mA    10.18mA
-381.8mV  7.028mA    7.109mA    7.32mA
1.2V      -20.91mA   -21.13mA   -21.78mA
1.8V      -29.64mA   -30mA      -30.87mA
2.182V    -34.13mA   -34.24mA   -35.54mA
2.4V      -35.18mA   -34.49mA   -37.11mA
2.673V    -34.15mA   -32.93mA   -36.46mA
3.164V    -28.92mA   -26.39mA   -30.58mA
3.6V      -21.41mA   -18.48mA   -23.91mA
[GND_clamp]
-1.8V     -346.1mA   -209.3mA   -568.3mA
-1.327V   -149.7mA   -89.03mA   -250.9mA
-1.291V   -135.6mA   -80.47mA   -227.5mA
-1.145V   -82.35mA   -48.67mA   -137.7mA
-1.073V   -59.44mA   -35.55mA   -97.96mA
-1.036V   -49.1mA    -29.72mA   -79.9mA
-927.3mV  -26.31mA   -17.11mA   -38.99mA
-854.5mV  -16.67mA   -11.64mA   -22.56mA
-818.2mV  -12.86mA   -9.351mA   -16.98mA
-672.7mV  -5.705mA   -3.913mA   -8.623mA
-381.8mV  -120.4uA   -129uA     -167.2uA
1.8V      2.273nA    51.44nA    6.654nA
[Ramp]
dV/dt_f 0.52133517/82.682619p 0.50657894/89.866163p 0.54551644/74.767907p
dV/dt_r 0.51387916/74.786342p 0.49426214/79.547412p 0.54959986/68.118919p
R_load = 50
[Rising Waveform]
R_fixture = 50
V_fixture = 1.8
V_fixture_min = 1.71
V_fixture_max = 1.89
0s        944.4mV    882.6mV    990.4mV
115.2ps   944.4mV    882.6mV    1.021V
165.7ps   947.7mV    882.6mV    1.554V
215.5ps   964.7mV    882.6mV    1.761V
236.7ps   1.059V     882.6mV    1.796V
296.7ps   1.558V     882.8mV    1.847V
422.7ps   1.758V     924.4mV    1.879V
522.7ps   1.78V      1.507V     1.885V
603.9ps   1.787V     1.655V     1.888V
1.787ns   1.798V     1.705V     1.89V
[Rising Waveform]
R_fixture = 50
V_fixture = 0
V_fixture_min = 0
V_fixture_max = 0
0s        0V         0V         0V
126.8ps   0V         0V         0V
183.4ps   0V         0V         566.2mV
241.3ps   0V         0V         791.1mV
314ps     568.3mV    0V         863mV
365.1ps   732.1mV    0V         880.2mV
462.4ps   812mV      0V         894.7mV
558.9ps   827.8mV    606.1mV    900.8mV
657ps     833.1mV    763.4mV    903.9mV
1.842ns   843.6mV    803.6mV    907.5mV
[Falling Waveform]
R_fixture = 50
V_fixture = 1.8
V_fixture_min = 1.71
V_fixture_max = 1.89
0s        1.8V       1.709V     1.89V
132.3ps   1.8V       1.709V     1.877V
193.7ps   1.8V       1.709V     1.325V
242.2ps   1.8V       1.709V     1.13V
326.9ps   1.215V     1.709V     1.035V
380.1ps   1.055V     1.709V     1.017V
468.1ps   982.5mV    1.709V     1.003V
586.2ps   962.1mV    1.07V      995.9mV
699.7ps   956.2mV    919.4mV    992.6mV
1.787ns   947.4mV    886.6mV    989.5mV
[Falling Waveform]
R_fixture = 50
V_fixture = 0
V_fixture_min = 0
V_fixture_max = 0
0s        846.3mV    809mV      906.9mV
120.9ps   846.3mV    809mV      895.7mV
174.7ps   846.3mV    809mV      311.9mV
228.4ps   826.3mV    809mV      110mV
295.2ps   258.8mV    809mV      43.2mV
358.5ps   83.45mV    809mV      21.59mV
441.4ps   31.39mV    773.5mV    10.55mV
528.7ps   16.48mV    212.9mV    5.785mV
625.7ps   10.9mV     44.47mV    3.242mV
1.842ns   4.699mV    4.039mV    0V
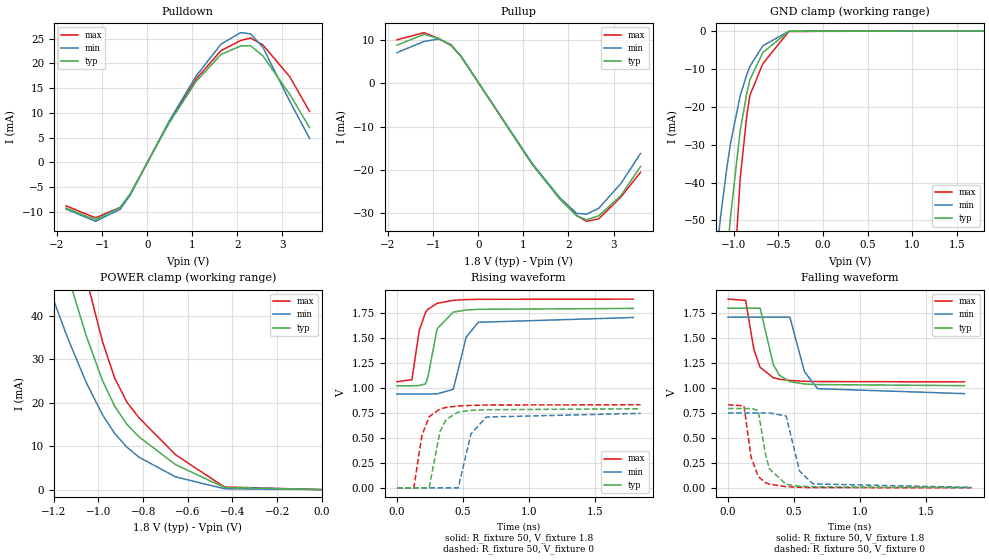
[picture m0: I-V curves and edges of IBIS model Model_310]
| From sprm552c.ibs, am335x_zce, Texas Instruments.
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| Model based on original model for BCSHTLTCSCDVPBFZ_SSDHV
|   Sub model SR00_6MA_5PER_1P8
[model]   Model_310
|[Description]  [1.8V-3-STATE-NOTERM-SR00:6MA, IND, 5%]
|   Fastest slew rate (SR[1:0] = "00"), 1.33 * RExt = 0.750 * Iout
|   (I[2:0] = "001"), 6mA nominal with Rext = 50R,ODT off (ODT[1:0]
|   = "00") CMOS mode,Industrial temperature range (-40C to 125C,
|   25C nominal),5% power supply tolerance
|[Input Load]   NOTERM
|[Output Drive] SR00:6MA
|Voltage   1.8V
|Mode   3-STATE
Model_type   3-state
Polarity   Non-Inverting
Enable   Active-Low
Cref =  15pF
Rref =  100.0000M
Vref =  0V
Vmeas =  0.9
C_comp   1.851324p   1.667199p   1.973575p
[Temperature Range]   25   125   -40
[Voltage Range]   1.8   1.71   1.89
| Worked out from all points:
|   slope of the pulldown table from 0 to 0.27 V, typ, clamps not added: 60.1 ohm
|   slope of the pullup table from 0 to 0.27 V, typ, clamps not added: 60.8 ohm
|   GND clamp passes 1 mA (typ) near -0.49 V on its own axis
|   POWER clamp passes 1 mA (typ) near -0.47 V on its own axis
|   rising waveform, R_fixture 50, V_fixture 1.8: 20-80 % time 74.8ps typ, 86.2ps min, 69.5ps max; typ from 1.02 V to 1.8 V
|   rising waveform, R_fixture 50, V_fixture 0: 20-80 % time 78.4ps typ, 84.7ps min, 74ps max; typ from 0 V to 0.792 V
|   falling waveform, R_fixture 50, V_fixture 1.8: 20-80 % time 89ps typ, 94.7ps min, 80.8ps max; typ from 1.8 V to 1.02 V
|   falling waveform, R_fixture 50, V_fixture 0: 20-80 % time 72.8ps typ, 79.9ps min, 66.4ps max; typ from 0.795 V to 0.003 V
[POWER_clamp]
-1.8V     194.9mA    137mA      262.9mA
-1.236V   68.49mA    48.49mA    92.7mA
-1.145V   50.76mA    35.84mA    69.67mA
-1.127V   47.56mA    33.52mA    65.35mA
-1.055V   35.4mA     24.68mA    48.7mA
-981.8mV  25.06mA    17.19mA    34.02mA
-927.3mV  19.17mA    12.92mA    25.62mA
-872.7mV  15.03mA    9.76mA     20.13mA
-818.2mV  12.12mA    7.445mA    16.51mA
-654.5mV  5.738mA    2.929mA    8.007mA
-436.4mV  508.2uA    199.4uA    613uA
0V        2.273nA    16.6nA     10.58nA
[Pulldown]
-1.8V     -9.241mA   -9.444mA   -8.801mA
-1.145V   -11.6mA    -11.92mA   -11.21mA
-600mV    -9.112mA   -9.503mA   -9.119mA
-381.8mV  -6.424mA   -6.715mA   -6.584mA
490.9mV   7.999mA    8.408mA    8.235mA
1.091V    16.44mA    17.54mA    16.92mA
1.636V    21.8mA     23.88mA    22.57mA
2.073V    23.52mA    26.23mA    24.63mA
2.291V    23.58mA    25.97mA    25.14mA
2.564V    21.54mA    23.27mA    23.74mA
3.164V    13.7mA     12.29mA    17.27mA
3.6V      7.029mA    4.844mA    10.28mA
[Pullup]
-1.8V     8.832mA    7.105mA    10.06mA
-1.2V     11.33mA    9.687mA    11.73mA
-872.7mV  10.35mA    10.25mA    10.32mA
-600mV    8.779mA    8.934mA    8.725mA
-381.8mV  6.289mA    6.222mA    6.276mA
1.2V      -18.71mA   -18.49mA   -18.68mA
1.8V      -26.52mA   -26.26mA   -26.46mA
2.182V    -30.54mA   -29.96mA   -30.46mA
2.4V      -31.47mA   -30.18mA   -31.81mA
2.673V    -30.55mA   -28.81mA   -31.25mA
3.164V    -25.87mA   -23.09mA   -26.21mA
3.6V      -19.15mA   -16.17mA   -20.49mA
[GND_clamp]
-1.8V     -346.1mA   -209.3mA   -568.3mA
-1.327V   -149.7mA   -89.03mA   -250.9mA
-1.291V   -135.6mA   -80.47mA   -227.5mA
-1.145V   -82.35mA   -48.67mA   -137.7mA
-1.073V   -59.44mA   -35.55mA   -97.96mA
-1.036V   -49.1mA    -29.72mA   -79.9mA
-927.3mV  -26.31mA   -17.11mA   -38.99mA
-854.5mV  -16.67mA   -11.64mA   -22.56mA
-818.2mV  -12.86mA   -9.351mA   -16.98mA
-672.7mV  -5.705mA   -3.913mA   -8.623mA
-381.8mV  -120.4uA   -129uA     -167.2uA
1.8V      2.273nA    51.44nA    6.654nA
[Ramp]
dV/dt_f 0.47394429/90.071268p 0.47075111/96.070111p 0.50175903/80.844814p
dV/dt_r 0.48238907/79.354908p 0.45809896/85.668729p 0.50395392/74.019798p
R_load = 50
[Rising Waveform]
R_fixture = 50
V_fixture = 1.8
V_fixture_min = 1.71
V_fixture_max = 1.89
0s        1.022V     940.3mV    1.063V
112.8ps   1.022V     940.3mV    1.083V
168ps     1.025V     940.3mV    1.576V
215.7ps   1.041V     940.3mV    1.757V
234.1ps   1.11V      940.3mV    1.789V
302.9ps   1.592V     941.4mV    1.848V
424.9ps   1.76V      986.1mV    1.878V
522.8ps   1.781V     1.508V     1.885V
613.9ps   1.788V     1.658V     1.888V
1.787ns   1.797V     1.706V     1.89V
[Rising Waveform]
R_fixture = 50
V_fixture = 0
V_fixture_min = 0
V_fixture_max = 0
0s        0V         0V         0V
127ps     0V         0V         0V
188.1ps   0V         0V         523.1mV
242.6ps   0V         0V         711.7mV
324.9ps   562.9mV    0V         790.2mV
371.6ps   685.9mV    0V         805.3mV
462.9ps   758.7mV    0V         819.3mV
559.1ps   776.1mV    541.7mV    825.8mV
674.8ps   782.4mV    709.3mV    829.4mV
1.841ns   792.2mV    745.9mV    832.7mV
[Falling Waveform]
R_fixture = 50
V_fixture = 1.8
V_fixture_min = 1.71
V_fixture_max = 1.89
0s        1.8V       1.71V      1.891V
133.3ps   1.8V       1.71V      1.879V
195.7ps   1.8V       1.71V      1.386V
242.9ps   1.8V       1.71V      1.208V
342.6ps   1.234V     1.71V      1.103V
387.3ps   1.13V      1.71V      1.089V
467.7ps   1.064V     1.71V      1.076V
577.7ps   1.041V     1.165V     1.068V
677.1ps   1.035V     993.7mV    1.065V
1.787ns   1.024V     944.1mV    1.062V
[Falling Waveform]
R_fixture = 50
V_fixture = 0
V_fixture_min = 0
V_fixture_max = 0
0s        795mV      750.6mV    832mV
120.8ps   795mV      750.6mV    821.8mV
173.9ps   795mV      750.6mV    309.7mV
228.4ps   775.4mV    750.6mV    113.6mV
281ps     348.7mV    750.6mV    53.89mV
312.9ps   190.3mV    750.6mV    36.63mV
439.3ps   35.12mV    719.8mV    11.3mV
540.9ps   16.58mV    168.2mV    5.67mV
642.4ps   11.01mV    39.52mV    3.122mV
1.841ns   2.85mV     4.704mV    0V
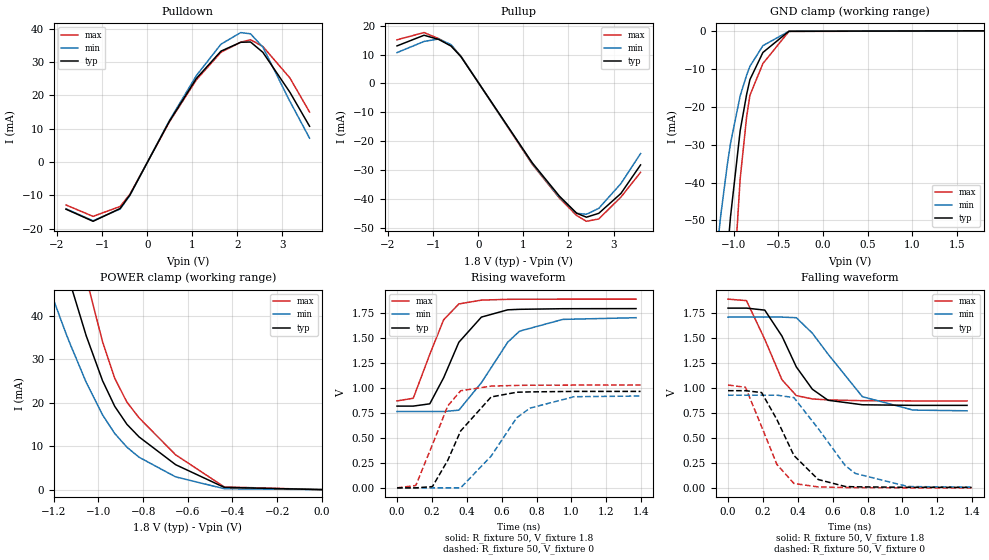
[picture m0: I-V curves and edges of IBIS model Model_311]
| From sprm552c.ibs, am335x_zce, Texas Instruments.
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| Model based on original model for BCSHTLTCSCDVPBFZ_SSDHV
|   Sub model SR01_9MA_5PER_1P8
[model]   Model_311
|[Description]  [1.8V-3-STATE-NOTERM-SR01:9MA, IND, 5%]
|   Slow slew rate (SR[1:0] = "01"), 0.88 * RExt = 1.125 * Iout
|   (I[2:0] = "100"), 9mA nominal with Rext = 50R,ODT off (ODT[1:0]
|   = "00") CMOS mode,Industrial temperature range (-40C to 125C,
|   25C nominal),5% power supply tolerance
|[Input Load]   NOTERM
|[Output Drive] SR01:9MA
|Voltage   1.8V
|Mode   3-STATE
Model_type   3-state
Polarity   Non-Inverting
Enable   Active-Low
Cref =  15pF
Rref =  100.0000M
Vref =  0V
Vmeas =  0.9
C_comp   1.851324p   1.667199p   1.973575p
[Temperature Range]   25   125   -40
[Voltage Range]   1.8   1.71   1.89
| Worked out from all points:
|   slope of the pulldown table from 0 to 0.27 V, typ, clamps not added: 39.3 ohm
|   slope of the pullup table from 0 to 0.27 V, typ, clamps not added: 41.3 ohm
|   GND clamp passes 1 mA (typ) near -0.49 V on its own axis
|   POWER clamp passes 1 mA (typ) near -0.47 V on its own axis
|   rising waveform, R_fixture 50, V_fixture 1.8: 20-80 % time 164ps typ, 219ps min, 131ps max; typ from 0.819 V to 1.79 V
|   rising waveform, R_fixture 50, V_fixture 0: 20-80 % time 175ps typ, 221ps min, 133ps max; typ from 0 V to 0.966 V
|   falling waveform, R_fixture 50, V_fixture 1.8: 20-80 % time 182ps typ, 239ps min, 146ps max; typ from 1.8 V to 0.826 V
|   falling waveform, R_fixture 50, V_fixture 0: 20-80 % time 182ps typ, 234ps min, 142ps max; typ from 0.973 V to 0.004 V
[POWER_clamp]
-1.8V     194.9mA    137mA      262.9mA
-1.236V   68.49mA    48.49mA    92.7mA
-1.145V   50.76mA    35.84mA    69.67mA
-1.127V   47.56mA    33.52mA    65.35mA
-1.055V   35.4mA     24.68mA    48.7mA
-981.8mV  25.06mA    17.19mA    34.02mA
-927.3mV  19.17mA    12.92mA    25.62mA
-872.7mV  15.03mA    9.76mA     20.13mA
-818.2mV  12.12mA    7.445mA    16.51mA
-654.5mV  5.738mA    2.929mA    8.007mA
-436.4mV  508.2uA    199.4uA    613uA
0V        2.273nA    16.6nA     10.58nA
[Pulldown]
-1.8V     -14.14mA   -14.01mA   -12.87mA
-1.2V     -17.77mA   -17.62mA   -16.29mA
-600mV    -13.93mA   -14.08mA   -13.32mA
-381.8mV  -9.817mA   -9.949mA   -9.615mA
490.9mV   12.22mA    12.46mA    12.03mA
1.091V    25.12mA    25.99mA    24.71mA
1.636V    33.32mA    35.4mA     32.97mA
2.073V    35.97mA    38.89mA    36mA
2.291V    36.06mA    38.52mA    36.74mA
2.564V    32.97mA    34.52mA    34.71mA
3.164V    20.97mA    18.24mA    25.26mA
3.6V      10.76mA    7.187mA    15.03mA
[Pullup]
-1.8V     12.99mA    10.66mA    15.1mA
-1.2V     16.67mA    14.53mA    17.6mA
-872.7mV  15.21mA    15.38mA    15.47mA
-600mV    12.91mA    13.4mA     13.08mA
-381.8mV  9.242mA    9.325mA    9.406mA
1.2V      -27.49mA   -27.72mA   -27.99mA
1.8V      -38.98mA   -39.36mA   -39.67mA
2.182V    -44.9mA    -44.93mA   -45.68mA
2.4V      -46.28mA   -45.27mA   -47.7mA
2.673V    -44.94mA   -43.23mA   -46.89mA
3.164V    -38.07mA   -34.66mA   -39.34mA
3.6V      -28.19mA   -24.27mA   -30.76mA
[GND_clamp]
-1.8V     -346.1mA   -209.3mA   -568.3mA
-1.327V   -149.7mA   -89.03mA   -250.9mA
-1.291V   -135.6mA   -80.47mA   -227.5mA
-1.145V   -82.35mA   -48.67mA   -137.7mA
-1.073V   -59.44mA   -35.55mA   -97.96mA
-1.036V   -49.1mA    -29.72mA   -79.9mA
-927.3mV  -26.31mA   -17.11mA   -38.99mA
-854.5mV  -16.67mA   -11.64mA   -22.56mA
-818.2mV  -12.86mA   -9.351mA   -16.98mA
-672.7mV  -5.705mA   -3.913mA   -8.623mA
-381.8mV  -120.4uA   -129uA     -167.2uA
1.8V      2.273nA    51.44nA    6.654nA
[Ramp]
dV/dt_f 0.59000275/0.18477015n 0.56830378/0.24081075n 0.61293525/0.14619027n
dV/dt_r 0.58502137/0.17765027n 0.55823881/0.22363945n 0.61927013/0.13351855n
R_load = 50
[Rising Waveform]
R_fixture = 50
V_fixture = 1.8
V_fixture_min = 1.71
V_fixture_max = 1.89
0s        818.8mV    764.5mV    870.9mV
93.1ps    818.8mV    764.5mV    896.9mV
187.8ps   841.6mV    764.5mV    1.337V
267.4ps   1.103V     764.5mV    1.683V
354.5ps   1.458V     778mV      1.842V
483.7ps   1.71V      1.053V     1.88V
634.7ps   1.783V     1.459V     1.888V
702ps     1.788V     1.569V     1.889V
950.3ps   1.794V     1.687V     1.89V
1.37ns    1.795V     1.704V     1.89V
[Rising Waveform]
R_fixture = 50
V_fixture = 0
V_fixture_min = 0
V_fixture_max = 0
0s        0V         0V         0V
107.9ps   0V         0V         23.96mV
203.2ps   12.8mV     0V         433.6mV
291.1ps   276.7mV    0V         821.1mV
364.8ps   570.1mV    0V         972.4mV
539.6ps   910.4mV    318mV      1.019V
686.3ps   957.7mV    702.5mV    1.026V
762.1ps   961.1mV    798.4mV    1.028V
1.014ns   965.8mV    912.6mV    1.029V
1.396ns   965.8mV    919.8mV    1.03V
[Falling Waveform]
R_fixture = 50
V_fixture = 1.8
V_fixture_min = 1.71
V_fixture_max = 1.89
0s        1.799V     1.709V     1.889V
105.7ps   1.799V     1.709V     1.874V
210.6ps   1.779V     1.709V     1.487V
309.2ps   1.519V     1.709V     1.082V
391.4ps   1.211V     1.703V     923.6mV
483.4ps   987.2mV    1.548V     890.1mV
573.2ps   876.9mV    1.339V     880.1mV
770.2ps   831.7mV    912.5mV    872.5mV
1.06ns    825.7mV    778.6mV    870.4mV
1.37ns    825.7mV    771.3mV    870mV
[Falling Waveform]
R_fixture = 50
V_fixture = 0
V_fixture_min = 0
V_fixture_max = 0
0s        972.6mV    927.8mV    1.029V
100ps     972.6mV    927.8mV    1.007V
192.6ps   953.9mV    927.8mV    612.7mV
279.8ps   685mV      927.8mV    235.5mV
377.9ps   323.8mV    903mV      43.63mV
517.1ps   83.47mV    592.8mV    9.135mV
671.7ps   13.6mV     223.1mV    3.245mV
730ps     10.27mV    144mV      2.322mV
1.032ns   5.657mV    13.2mV     0V
1.396ns   4.431mV    7.019mV    0V
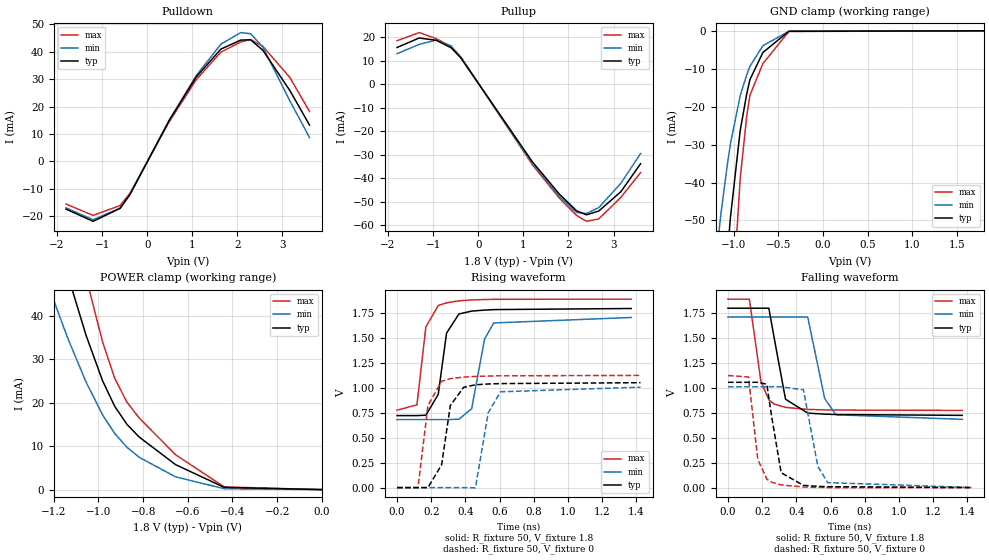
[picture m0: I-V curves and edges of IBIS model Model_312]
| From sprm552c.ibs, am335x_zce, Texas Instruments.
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| Model based on original model for BCSHTLTCSCDVPBFZ_SSDHV
|   Sub model SR00_11MA_5PER_1P8
[model]   Model_312
|[Description]  [1.8V-3-STATE-NOTERM-SR00:11MA, IND, 5%]
|   Fastest slew rate (SR[1:0] = "00"), 0.73 * RExt = 1.325 * Iout
|   (I[2:0] = "110"), 11mA nominal with Rext = 50R,ODT off (ODT[1:0]
|   = "00") CMOS mode,Industrial temperature range (-40C to 125C,
|   25C nominal),5% power supply tolerance
|[Input Load]   NOTERM
|[Output Drive] SR00:11MA
|Voltage   1.8V
|Mode   3-STATE
Model_type   3-state
Polarity   Non-Inverting
Enable   Active-Low
Cref =  15pF
Rref =  100.0000M
Vref =  0V
Vmeas =  0.9
C_comp   1.851324p   1.667199p   1.973575p
[Temperature Range]   25   125   -40
[Voltage Range]   1.8   1.71   1.89
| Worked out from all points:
|   slope of the pulldown table from 0 to 0.27 V, typ, clamps not added: 32 ohm
|   slope of the pullup table from 0 to 0.27 V, typ, clamps not added: 34.5 ohm
|   GND clamp passes 1 mA (typ) near -0.49 V on its own axis
|   POWER clamp passes 1 mA (typ) near -0.47 V on its own axis
|   rising waveform, R_fixture 50, V_fixture 1.8: 20-80 % time 53.7ps typ, 63ps min, 48ps max; typ from 0.722 V to 1.8 V
|   rising waveform, R_fixture 50, V_fixture 0: 20-80 % time 55.8ps typ, 58ps min, 51.4ps max; typ from 0 V to 1.05 V
|   falling waveform, R_fixture 50, V_fixture 1.8: 20-80 % time 60.8ps typ, 67.4ps min, 57ps max; typ from 1.8 V to 0.726 V
|   falling waveform, R_fixture 50, V_fixture 0: 20-80 % time 50.7ps typ, 58.2ps min, 47.4ps max; typ from 1.06 V to 0.004 V
[POWER_clamp]
-1.8V     194.9mA    137mA      262.9mA
-1.236V   68.49mA    48.49mA    92.7mA
-1.145V   50.76mA    35.84mA    69.67mA
-1.127V   47.56mA    33.52mA    65.35mA
-1.055V   35.4mA     24.68mA    48.7mA
-981.8mV  25.06mA    17.19mA    34.02mA
-927.3mV  19.17mA    12.92mA    25.62mA
-872.7mV  15.03mA    9.76mA     20.13mA
-818.2mV  12.12mA    7.445mA    16.51mA
-654.5mV  5.738mA    2.929mA    8.007mA
-436.4mV  508.2uA    199.4uA    613uA
0V        2.273nA    16.6nA     10.58nA
[Pulldown]
-1.8V     -17.41mA   -16.94mA   -15.58mA
-1.2V     -21.87mA   -21.31mA   -19.71mA
-600mV    -17.14mA   -17.03mA   -16.12mA
-381.8mV  -12.08mA   -12.02mA   -11.63mA
490.9mV   15.04mA    15.06mA    14.55mA
1.091V    30.91mA    31.42mA    29.9mA
1.636V    41.01mA    42.8mA     39.9mA
2.073V    44.27mA    47.02mA    43.57mA
2.291V    44.39mA    46.59mA    44.48mA
2.564V    40.59mA    41.76mA    42.02mA
3.164V    25.83mA    22.07mA    30.59mA
3.6V      13.24mA    8.694mA    18.21mA
[Pullup]
-1.8V     15.59mA    12.95mA    18.46mA
-1.309V   19.63mA    16.9mA     21.94mA
-927.3mV  18.65mA    18.73mA    19.33mA
-600mV    15.48mA    16.26mA    15.99mA
-381.8mV  11.09mA    11.32mA    11.49mA
1.2V      -32.98mA   -33.64mA   -34.2mA
1.8V      -46.76mA   -47.78mA   -48.47mA
2.182V    -53.86mA   -54.55mA   -55.81mA
2.4V      -55.54mA   -54.98mA   -58.3mA
2.673V    -53.94mA   -52.5mA    -57.31mA
3.164V    -45.71mA   -42.11mA   -48.1mA
3.6V      -33.84mA   -29.49mA   -37.62mA
[GND_clamp]
-1.8V     -346.1mA   -209.3mA   -568.3mA
-1.327V   -149.7mA   -89.03mA   -250.9mA
-1.291V   -135.6mA   -80.47mA   -227.5mA
-1.145V   -82.35mA   -48.67mA   -137.7mA
-1.073V   -59.44mA   -35.55mA   -97.96mA
-1.036V   -49.1mA    -29.72mA   -79.9mA
-927.3mV  -26.31mA   -17.11mA   -38.99mA
-854.5mV  -16.67mA   -11.64mA   -22.56mA
-818.2mV  -12.86mA   -9.351mA   -16.98mA
-672.7mV  -5.705mA   -3.913mA   -8.623mA
-381.8mV  -120.4uA   -129uA     -167.2uA
1.8V      2.273nA    51.44nA    6.654nA
[Ramp]
dV/dt_f 0.65802855/61.715456p 0.63132193/68.836503p 0.67669294/56.884028p
dV/dt_r 0.64242416/56.229315p 0.62099628/58.938476p 0.68277154/51.298743p
R_load = 50
[Rising Waveform]
R_fixture = 50
V_fixture = 1.8
V_fixture_min = 1.71
V_fixture_max = 1.89
0s        722mV      681.8mV    776.3mV
116.6ps   722mV      681.8mV    830.3mV
168.8ps   725.8mV    681.8mV    1.611V
241.2ps   934.1mV    681.8mV    1.826V
289.9ps   1.549V     681.8mV    1.853V
362ps     1.741V     685.6mV    1.873V
436.8ps   1.77V      791.2mV    1.882V
512.2ps   1.78V      1.489V     1.886V
565.9ps   1.785V     1.651V     1.888V
1.37ns    1.796V     1.706V     1.89V
[Rising Waveform]
R_fixture = 50
V_fixture = 0
V_fixture_min = 0
V_fixture_max = 0
0s        0V         0V         0V
122.8ps   0V         0V         0V
181ps     0V         0V         823.8mV
261ps     228.4mV    0V         1.066V
311.8ps   822.2mV    0V         1.093V
389.5ps   1.005V     0V         1.108V
458.7ps   1.031V     -2.637mV   1.115V
533.6ps   1.039V     750.3mV    1.119V
605.9ps   1.043V     961mV      1.121V
1.425ns   1.052V     1.007V     1.125V
[Falling Waveform]
R_fixture = 50
V_fixture = 1.8
V_fixture_min = 1.71
V_fixture_max = 1.89
0s        1.799V     1.71V      1.89V
124.9ps   1.799V     1.71V      1.89V
192.3ps   1.799V     1.71V      1.068V
239ps     1.799V     1.71V      880.2mV
271.6ps   1.487V     1.71V      837.5mV
336.4ps   887.9mV    1.71V      805.8mV
466.4ps   748.7mV    1.71V      785.7mV
565.5ps   738.3mV    894.3mV    780.9mV
631.2ps   734.5mV    731.9mV    779.1mV
1.37ns    726mV      686.5mV    775.4mV
[Falling Waveform]
R_fixture = 50
V_fixture = 0
V_fixture_min = 0
V_fixture_max = 0
0s        1.057V     1.012V     1.125V
119.7ps   1.057V     1.012V     1.11V
174.3ps   1.057V     1.012V     285.9mV
227ps     1.038V     1.012V     87.83mV
255.4ps   713.4mV    1.012V     56.08mV
310.8ps   151.9mV    1.012V     29.11mV
441.3ps   24.6mV     981.9mV    8.454mV
525.3ps   15.04mV    216.9mV    4.65mV
583.2ps   11.42mV    52.58mV    3.256mV
1.425ns   3.919mV    3.644mV    0V
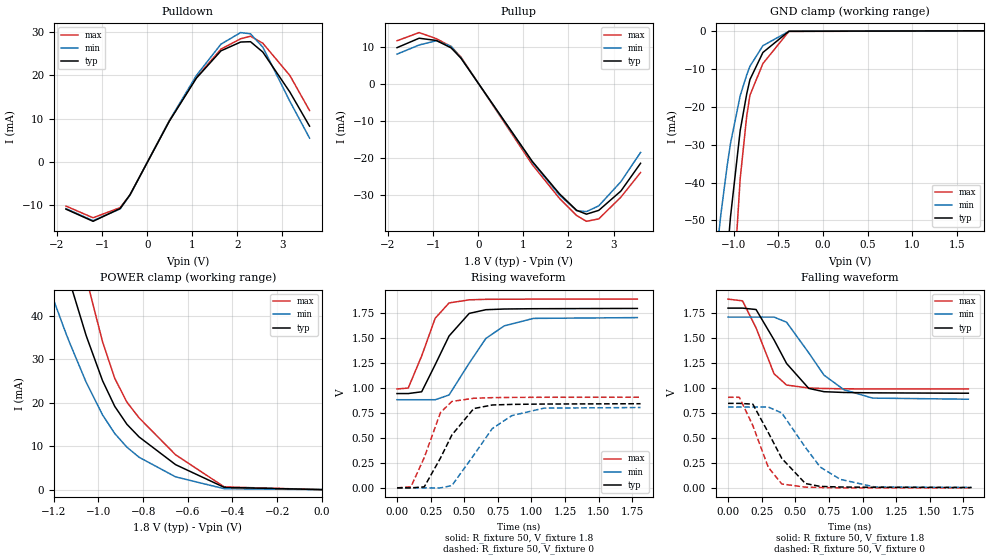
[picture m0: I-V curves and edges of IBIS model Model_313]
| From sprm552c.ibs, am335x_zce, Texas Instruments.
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| Model based on original model for BCSHTLTCSCDVPBFZ_SSDHV
|   Sub model SR01_7MA_5PER_1P8
[model]   Model_313
|[Description]  [1.8V-3-STATE-NOTERM-SR01:7MA, IND, 5%]
|   Slow slew rate (SR[1:0] = "01"), 1.14 * RExt = 0.875 * Iout
|   (I[2:0] = "010"), 7mA nominal with Rext = 50R,ODT off (ODT[1:0]
|   = "00") CMOS mode,Industrial temperature range (-40C to 125C,
|   25C nominal),5% power supply tolerance
|[Input Load]   NOTERM
|[Output Drive] SR01:7MA
|Voltage   1.8V
|Mode   3-STATE
Model_type   3-state
Polarity   Non-Inverting
Enable   Active-Low
Cref =  15pF
Rref =  100.0000M
Vref =  0V
Vmeas =  0.9
C_comp   1.851324p   1.667199p   1.973575p
[Temperature Range]   25   125   -40
[Voltage Range]   1.8   1.71   1.89
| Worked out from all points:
|   slope of the pulldown table from 0 to 0.27 V, typ, clamps not added: 51.1 ohm
|   slope of the pullup table from 0 to 0.27 V, typ, clamps not added: 54.4 ohm
|   GND clamp passes 1 mA (typ) near -0.49 V on its own axis
|   POWER clamp passes 1 mA (typ) near -0.47 V on its own axis
|   rising waveform, R_fixture 50, V_fixture 1.8: 20-80 % time 194ps typ, 247ps min, 144ps max; typ from 0.944 V to 1.8 V
|   rising waveform, R_fixture 50, V_fixture 0: 20-80 % time 203ps typ, 263ps min, 144ps max; typ from 0 V to 0.843 V
|   falling waveform, R_fixture 50, V_fixture 1.8: 20-80 % time 214ps typ, 269ps min, 158ps max; typ from 1.8 V to 0.947 V
|   falling waveform, R_fixture 50, V_fixture 0: 20-80 % time 210ps typ, 267ps min, 153ps max; typ from 0.846 V to 0.003 V
[POWER_clamp]
-1.8V     194.9mA    137mA      262.9mA
-1.236V   68.49mA    48.49mA    92.7mA
-1.145V   50.76mA    35.84mA    69.67mA
-1.127V   47.56mA    33.52mA    65.35mA
-1.055V   35.4mA     24.68mA    48.7mA
-981.8mV  25.06mA    17.19mA    34.02mA
-927.3mV  19.17mA    12.92mA    25.62mA
-872.7mV  15.03mA    9.76mA     20.13mA
-818.2mV  12.12mA    7.445mA    16.51mA
-654.5mV  5.738mA    2.929mA    8.007mA
-436.4mV  508.2uA    199.4uA    613uA
0V        2.273nA    16.6nA     10.58nA
[Pulldown]
-1.8V     -10.87mA   -10.75mA   -10.16mA
-1.2V     -13.67mA   -13.52mA   -12.86mA
-600mV    -10.72mA   -10.81mA   -10.52mA
-381.8mV  -7.555mA   -7.639mA   -7.594mA
490.9mV   9.408mA    9.565mA    9.5mA
1.091V    19.34mA    19.96mA    19.52mA
1.636V    25.64mA    27.18mA    26.04mA
2.073V    27.67mA    29.85mA    28.42mA
2.291V    27.74mA    29.56mA    29.01mA
2.564V    25.35mA    26.48mA    27.39mA
3.164V    16.12mA    13.99mA    19.94mA
3.6V      8.27mA     5.513mA    11.86mA
[Pullup]
-1.8V     9.872mA    8.121mA    11.74mA
-1.309V   12.43mA    10.6mA     13.96mA
-927.3mV  11.82mA    11.75mA    12.3mA
-600mV    9.811mA    10.21mA    10.18mA
-381.8mV  7.028mA    7.109mA    7.32mA
1.2V      -20.91mA   -21.13mA   -21.78mA
1.8V      -29.64mA   -30mA      -30.87mA
2.182V    -34.13mA   -34.24mA   -35.54mA
2.4V      -35.18mA   -34.49mA   -37.11mA
2.673V    -34.15mA   -32.93mA   -36.46mA
3.164V    -28.92mA   -26.39mA   -30.58mA
3.6V      -21.41mA   -18.48mA   -23.91mA
[GND_clamp]
-1.8V     -346.1mA   -209.3mA   -568.3mA
-1.327V   -149.7mA   -89.03mA   -250.9mA
-1.291V   -135.6mA   -80.47mA   -227.5mA
-1.145V   -82.35mA   -48.67mA   -137.7mA
-1.073V   -59.44mA   -35.55mA   -97.96mA
-1.036V   -49.1mA    -29.72mA   -79.9mA
-927.3mV  -26.31mA   -17.11mA   -38.99mA
-854.5mV  -16.67mA   -11.64mA   -22.56mA
-818.2mV  -12.86mA   -9.351mA   -16.98mA
-672.7mV  -5.705mA   -3.913mA   -8.623mA
-381.8mV  -120.4uA   -129uA     -167.2uA
1.8V      2.273nA    51.44nA    6.654nA
[Ramp]
dV/dt_f 0.51489214/0.21574593n 0.49722935/0.27132502n 0.54087725/0.15867781n
dV/dt_r 0.50910609/0.20473829n 0.48629296/0.26469723n 0.54549517/0.14433784n
R_load = 50
[Rising Waveform]
R_fixture = 50
V_fixture = 1.8
V_fixture_min = 1.71
V_fixture_max = 1.89
0s        944.4mV    882.6mV    990.4mV
83.4ps    944.4mV    882.6mV    999.4mV
183.4ps   962.2mV    882.6mV    1.321V
283.7ps   1.233V     882.7mV    1.698V
387.1ps   1.521V     930mV      1.852V
536.9ps   1.747V     1.249V     1.883V
660.5ps   1.784V     1.496V     1.888V
796.8ps   1.791V     1.622V     1.889V
1.014ns   1.794V     1.697V     1.89V
1.787ns   1.797V     1.705V     1.89V
[Rising Waveform]
R_fixture = 50
V_fixture = 0
V_fixture_min = 0
V_fixture_max = 0
0s        0V         0V         0V
103.6ps   0V         0V         11.17mV
202.6ps   9.843mV    0V         303.4mV
323.1ps   298.4mV    0V         753.7mV
407.9ps   529.3mV    22.75mV    865.5mV
570.6ps   794mV      327.5mV    897.3mV
708.2ps   829.9mV    593.5mV    903.4mV
853.1ps   835.8mV    723.2mV    905.9mV
1.094ns   839.4mV    798.7mV    907.2mV
1.811ns   842.6mV    804.5mV    907.5mV
[Falling Waveform]
R_fixture = 50
V_fixture = 1.8
V_fixture_min = 1.71
V_fixture_max = 1.89
0s        1.799V     1.709V     1.889V
107.8ps   1.799V     1.709V     1.872V
208.5ps   1.785V     1.709V     1.601V
342.4ps   1.481V     1.709V     1.142V
435.4ps   1.245V     1.658V     1.029V
600.2ps   995.5mV    1.352V     999.4mV
713.7ps   962.6mV    1.128V     994.4mV
862.3ps   954.7mV    981.9mV    991.3mV
1.075ns   950.9mV    898.5mV    989.9mV
1.787ns   947.2mV    887.1mV    989.5mV
[Falling Waveform]
R_fixture = 50
V_fixture = 0
V_fixture_min = 0
V_fixture_max = 0
0s        845.6mV    808.8mV    906.6mV
84.3ps    845.6mV    808.8mV    906.6mV
184.5ps   837.8mV    808.8mV    623.7mV
299.4ps   553.5mV    808.8mV    206mV
399.7ps   295.1mV    750mV      38.84mV
575.3ps   43.52mV    405.4mV    7.163mV
685.5ps   14.52mV    208mV      3.571mV
835.2ps   8.441mV    84.84mV    0V
1.09ns    5.679mV    9.23mV     0V
1.811ns   3.167mV    4.858mV    0V
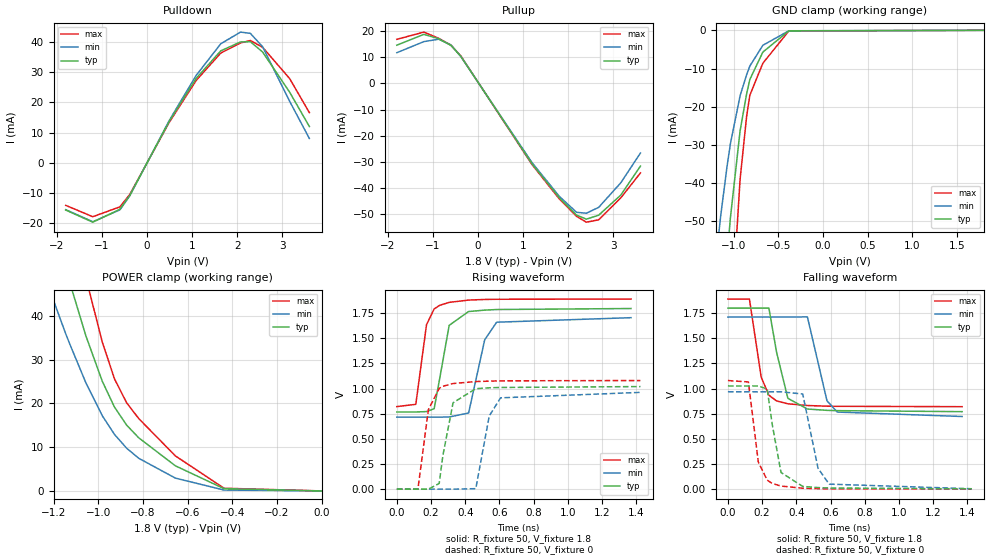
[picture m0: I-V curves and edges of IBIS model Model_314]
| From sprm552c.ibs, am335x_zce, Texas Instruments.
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| Model based on original model for BCSHTLTCSCDVPBFZ_SSDHV
|   Sub model SR00_10MA_5PER_1P8
[model]   Model_314
|[Description]  [1.8V-3-STATE-NOTERM-SR00:10MA, IND, 5%]
|   Fastest slew rate (SR[1:0] = "00"), 0.80 * RExt = 1.250 * Iout
|   (I[2:0] = "101"), 10mA nominal with Rext = 50R,ODT off (ODT[1:0]
|   = "00") CMOS mode,Industrial temperature range (-40C to 125C,
|   25C nominal),5% power supply tolerance
|[Input Load]   NOTERM
|[Output Drive] SR00:10MA
|Voltage   1.8V
|Mode   3-STATE
Model_type   3-state
Polarity   Non-Inverting
Enable   Active-Low
Cref =  15pF
Rref =  100.0000M
Vref =  0V
Vmeas =  0.9
C_comp   1.851324p   1.667199p   1.973575p
[Temperature Range]   25   125   -40
[Voltage Range]   1.8   1.71   1.89
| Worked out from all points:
|   slope of the pulldown table from 0 to 0.27 V, typ, clamps not added: 35.3 ohm
|   slope of the pullup table from 0 to 0.27 V, typ, clamps not added: 36.9 ohm
|   GND clamp passes 1 mA (typ) near -0.49 V on its own axis
|   POWER clamp passes 1 mA (typ) near -0.47 V on its own axis
|   rising waveform, R_fixture 50, V_fixture 1.8: 20-80 % time 56ps typ, 66.7ps min, 51.1ps max; typ from 0.767 V to 1.8 V
|   rising waveform, R_fixture 50, V_fixture 0: 20-80 % time 58.1ps typ, 62.1ps min, 54.7ps max; typ from 0 V to 1.02 V
|   falling waveform, R_fixture 50, V_fixture 1.8: 20-80 % time 65.3ps typ, 72.6ps min, 60.4ps max; typ from 1.8 V to 0.771 V
|   falling waveform, R_fixture 50, V_fixture 0: 20-80 % time 53.7ps typ, 60.7ps min, 50.7ps max; typ from 1.03 V to 0.003 V
[POWER_clamp]
-1.8V     194.9mA    137mA      262.9mA
-1.236V   68.49mA    48.49mA    92.7mA
-1.145V   50.76mA    35.84mA    69.67mA
-1.127V   47.56mA    33.52mA    65.35mA
-1.055V   35.4mA     24.68mA    48.7mA
-981.8mV  25.06mA    17.19mA    34.02mA
-927.3mV  19.17mA    12.92mA    25.62mA
-872.7mV  15.03mA    9.76mA     20.13mA
-818.2mV  12.12mA    7.445mA    16.51mA
-654.5mV  5.738mA    2.929mA    8.007mA
-436.4mV  508.2uA    199.4uA    613uA
0V        2.273nA    16.6nA     10.58nA
[Pulldown]
-1.8V     -15.77mA   -15.64mA   -14.22mA
-1.2V     -19.82mA   -19.67mA   -18mA
-600mV    -15.53mA   -15.72mA   -14.72mA
-381.8mV  -10.95mA   -11.1mA    -10.62mA
490.9mV   13.63mA    13.9mA     13.29mA
1.091V    28.02mA    29.01mA    27.31mA
1.636V    37.17mA    39.51mA    36.44mA
2.073V    40.12mA    43.41mA    39.79mA
2.291V    40.23mA    43mA       40.61mA
2.564V    36.78mA    38.54mA    38.36mA
3.164V    23.4mA     20.37mA    27.93mA
3.6V      12mA       8.024mA    16.62mA
[Pullup]
-1.8V     14.55mA    11.68mA    16.78mA
-1.2V     18.67mA    15.92mA    19.55mA
-872.7mV  17.03mA    16.84mA    17.19mA
-600mV    14.45mA    14.67mA    14.53mA
-381.8mV  10.35mA    10.21mA    10.45mA
1.2V      -30.78mA   -30.35mA   -31.1mA
1.8V      -43.65mA   -43.1mA    -44.07mA
2.182V    -50.28mA   -49.21mA   -50.74mA
2.4V      -51.84mA   -49.59mA   -53mA
2.673V    -50.34mA   -47.35mA   -52.1mA
3.164V    -42.65mA   -37.97mA   -43.72mA
3.6V      -31.58mA   -26.59mA   -34.19mA
[GND_clamp]
-1.8V     -346.1mA   -209.3mA   -568.3mA
-1.327V   -149.7mA   -89.03mA   -250.9mA
-1.291V   -135.6mA   -80.47mA   -227.5mA
-1.145V   -82.35mA   -48.67mA   -137.7mA
-1.073V   -59.44mA   -35.55mA   -97.96mA
-1.036V   -49.1mA    -29.72mA   -79.9mA
-927.3mV  -26.31mA   -17.11mA   -38.99mA
-854.5mV  -16.67mA   -11.64mA   -22.56mA
-818.2mV  -12.86mA   -9.351mA   -16.98mA
-672.7mV  -5.705mA   -3.913mA   -8.623mA
-381.8mV  -120.4uA   -129uA     -167.2uA
1.8V      2.273nA    51.44nA    6.654nA
[Ramp]
dV/dt_f 0.63020863/65.894257p 0.60930928/72.31277p  0.64957869/60.559749p
dV/dt_r 0.62290519/58.89045p  0.59318123/63.199798p  0.6550369/54.712361p
R_load = 50
[Rising Waveform]
R_fixture = 50
V_fixture = 1.8
V_fixture_min = 1.71
V_fixture_max = 1.89
0s        767.4mV    716.1mV    820.9mV
111.1ps   767.4mV    716.1mV    843.3mV
173.7ps   771.3mV    716.1mV    1.635V
218.5ps   800mV      716.1mV    1.792V
250.9ps   1.101V     716.1mV    1.828V
306.3ps   1.629V     717.6mV    1.857V
419.8ps   1.766V     757.1mV    1.88V
514ps     1.78V      1.485V     1.886V
584ps     1.786V     1.66V      1.888V
1.37ns    1.796V     1.705V     1.89V
[Rising Waveform]
R_fixture = 50
V_fixture = 0
V_fixture_min = 0
V_fixture_max = 0
0s        0V         0V         0V
123.4ps   0V         0V         0V
184.5ps   0V         0V         789.5mV
247.9ps   56.96mV    0V         1.002V
269.3ps   333.2mV    0V         1.023V
329ps     859.3mV    0V         1.05V
461.8ps   998.8mV    5.109mV    1.07V
540.7ps   1.008V     727.9mV    1.074V
606.8ps   1.011V     907.9mV    1.077V
1.425ns   1.02V      962.3mV    1.08V
[Falling Waveform]
R_fixture = 50
V_fixture = 1.8
V_fixture_min = 1.71
V_fixture_max = 1.89
0s        1.8V       1.711V     1.89V
125.8ps   1.8V       1.711V     1.89V
194.7ps   1.8V       1.711V     1.113V
239.7ps   1.8V       1.711V     933.8mV
284.6ps   1.361V     1.711V     877.3mV
350.6ps   903.3mV    1.711V     848.8mV
464.8ps   796.7mV    1.713V     831.6mV
579.3ps   783.6mV    879.3mV    825.1mV
639ps     780.6mV    766.6mV    823.8mV
1.37ns    770.6mV    722.5mV    820.1mV
[Falling Waveform]
R_fixture = 50
V_fixture = 0
V_fixture_min = 0
V_fixture_max = 0
0s        1.026V     968mV      1.08V
119.8ps   1.026V     968mV      1.066V
177.6ps   1.026V     968mV      271.1mV
229.7ps   995.6mV    968mV      89.49mV
258.8ps   647.2mV    968mV      57.06mV
310.6ps   165.5mV    968mV      30.94mV
437.6ps   27.33mV    945.8mV    9.233mV
527ps     15.84mV    208.1mV    4.893mV
591.8ps   11.66mV    49.97mV    3.294mV
1.425ns   3.472mV    4.306mV    0V
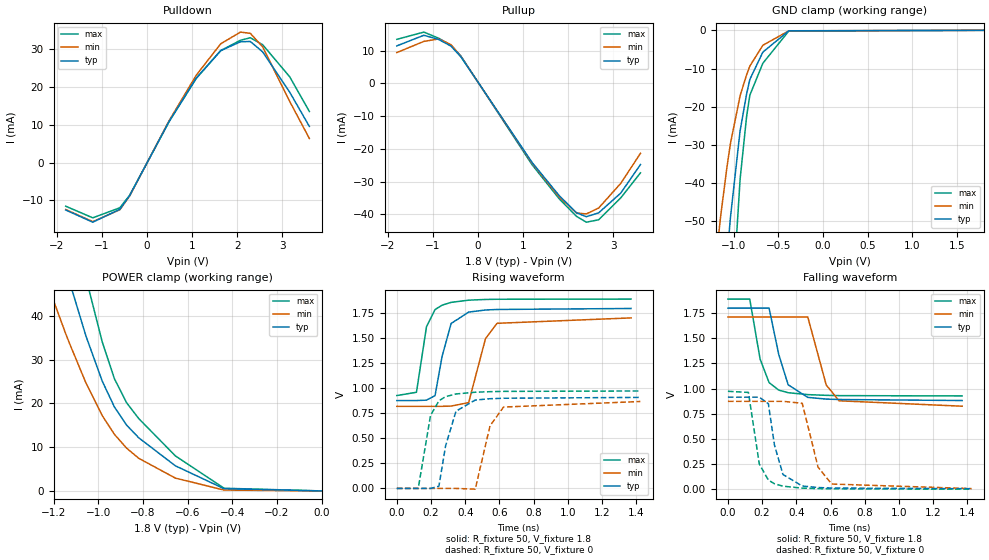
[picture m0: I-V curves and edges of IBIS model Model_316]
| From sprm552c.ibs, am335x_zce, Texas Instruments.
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| Model based on original model for BCSHTLTCSCDVPBFZ_SSDHV
|   Sub model SR00_8MA_5PER_1P8
[model]   Model_316
|[Description]  [1.8V-3-STATE-NOTERM-SR00:8MA, IND, 5%]
|   Fastest slew rate (SR[1:0] = "00"), 1.00 * RExt = 1.000 * Iout
|   (I[2:0] = "011"), 8mA nominal with Rext = 50R,ODT off (ODT[1:0]
|   = "00") CMOS mode,Industrial temperature range (-40C to 125C,
|   25C nominal),5% power supply tolerance
|[Input Load]   NOTERM
|[Output Drive] SR00:8MA
|Voltage   1.8V
|Mode   3-STATE
Model_type   3-state
Polarity   Non-Inverting
Enable   Active-Low
Cref =  15pF
Rref =  100.0000M
Vref =  0V
Vmeas =  0.9
C_comp   1.851324p   1.667199p   1.973575p
[Temperature Range]   25   125   -40
[Voltage Range]   1.8   1.71   1.89
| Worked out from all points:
|   slope of the pulldown table from 0 to 0.27 V, typ, clamps not added: 44.4 ohm
|   slope of the pullup table from 0 to 0.27 V, typ, clamps not added: 47 ohm
|   GND clamp passes 1 mA (typ) near -0.49 V on its own axis
|   POWER clamp passes 1 mA (typ) near -0.47 V on its own axis
|   rising waveform, R_fixture 50, V_fixture 1.8: 20-80 % time 66.4ps typ, 74.3ps min, 58.7ps max; typ from 0.877 V to 1.8 V
|   rising waveform, R_fixture 50, V_fixture 0: 20-80 % time 67.5ps typ, 72ps min, 63ps max; typ from 0 V to 0.909 V
|   falling waveform, R_fixture 50, V_fixture 1.8: 20-80 % time 75.1ps typ, 82.2ps min, 69.2ps max; typ from 1.8 V to 0.881 V
|   falling waveform, R_fixture 50, V_fixture 0: 20-80 % time 62.3ps typ, 69.6ps min, 57.2ps max; typ from 0.914 V to 0.005 V
[POWER_clamp]
-1.8V     194.9mA    137mA      262.9mA
-1.236V   68.49mA    48.49mA    92.7mA
-1.145V   50.76mA    35.84mA    69.67mA
-1.127V   47.56mA    33.52mA    65.35mA
-1.055V   35.4mA     24.68mA    48.7mA
-981.8mV  25.06mA    17.19mA    34.02mA
-927.3mV  19.17mA    12.92mA    25.62mA
-872.7mV  15.03mA    9.76mA     20.13mA
-818.2mV  12.12mA    7.445mA    16.51mA
-654.5mV  5.738mA    2.929mA    8.007mA
-436.4mV  508.2uA    199.4uA    613uA
0V        2.273nA    16.6nA     10.58nA
[Pulldown]
-1.8V     -12.51mA   -12.38mA   -11.51mA
-1.2V     -15.72mA   -15.57mA   -14.57mA
-600mV    -12.32mA   -12.45mA   -11.92mA
-381.8mV  -8.686mA   -8.794mA   -8.605mA
490.9mV   10.82mA    11.01mA    10.76mA
1.091V    22.23mA    22.98mA    22.12mA
1.636V    29.48mA    31.29mA    29.5mA
2.073V    31.82mA    34.37mA    32.21mA
2.291V    31.9mA     34.04mA    32.88mA
2.564V    29.16mA    30.5mA     31.05mA
3.164V    18.55mA    16.11mA    22.6mA
3.6V      9.513mA    6.35mA     13.45mA
[Pullup]
-1.8V     11.43mA    9.39mA     13.42mA
-1.2V     14.67mA    12.8mA     15.64mA
-872.7mV  13.39mA    13.55mA    13.76mA
-600mV    11.36mA    11.8mA     11.63mA
-381.8mV  8.135mA    8.218mA    8.363mA
1.2V      -24.2mA    -24.42mA   -24.89mA
1.8V      -34.31mA   -34.68mA   -35.27mA
2.182V    -39.52mA   -39.59mA   -40.61mA
2.4V      -40.73mA   -39.88mA   -42.4mA
2.673V    -39.55mA   -38.08mA   -41.67mA
3.164V    -33.5mA    -30.53mA   -34.96mA
3.6V      -24.8mA    -21.38mA   -27.34mA
[GND_clamp]
-1.8V     -346.1mA   -209.3mA   -568.3mA
-1.327V   -149.7mA   -89.03mA   -250.9mA
-1.291V   -135.6mA   -80.47mA   -227.5mA
-1.145V   -82.35mA   -48.67mA   -137.7mA
-1.073V   -59.44mA   -35.55mA   -97.96mA
-1.036V   -49.1mA    -29.72mA   -79.9mA
-927.3mV  -26.31mA   -17.11mA   -38.99mA
-854.5mV  -16.67mA   -11.64mA   -22.56mA
-818.2mV  -12.86mA   -9.351mA   -16.98mA
-672.7mV  -5.705mA   -3.913mA   -8.623mA
-381.8mV  -120.4uA   -129uA     -167.2uA
1.8V      2.273nA    51.44nA    6.654nA
[Ramp]
dV/dt_f 0.56202931/76.190908p  0.5454617/82.962618p 0.58456073/69.386054p
dV/dt_r 0.55501712/68.517395p 0.53354148/72.802924p 0.58922853/63.019733p
R_load = 50
[Rising Waveform]
R_fixture = 50
V_fixture = 1.8
V_fixture_min = 1.71
V_fixture_max = 1.89
0s        877.2mV    819.4mV    926.9mV
114.9ps   877.2mV    819.4mV    959.9mV
173.5ps   881.1mV    819.4mV    1.613V
223.6ps   926mV      819.4mV    1.785V
264.7ps   1.317V     819.4mV    1.829V
317.6ps   1.646V     822mV      1.857V
420.1ps   1.76V      856.5mV    1.879V
518.6ps   1.781V     1.495V     1.886V
586.4ps   1.786V     1.648V     1.888V
1.37ns    1.796V     1.702V     1.89V
[Rising Waveform]
R_fixture = 50
V_fixture = 0
V_fixture_min = 0
V_fixture_max = 0
0s        0V         0V         0V
125.3ps   0V         0V         0V
197ps     0V         0V         727.9mV
246.2ps   22.1mV     0V         874.6mV
284.9ps   422.2mV    0V         915.9mV
346.1ps   771mV      0V         942.8mV
458.7ps   882mV      -7.298mV   960.2mV
545.1ps   895.5mV    624.4mV    965.7mV
624.3ps   900.1mV    812.2mV    968.6mV
1.425ns   908.6mV    867.7mV    972.6mV
[Falling Waveform]
R_fixture = 50
V_fixture = 1.8
V_fixture_min = 1.71
V_fixture_max = 1.89
0s        1.799V     1.711V     1.889V
127.6ps   1.799V     1.711V     1.889V
188.3ps   1.799V     1.711V     1.292V
240.8ps   1.799V     1.711V     1.059V
297.2ps   1.339V     1.711V     984.5mV
352.3ps   1.037V     1.711V     958.5mV
467ps     911.9mV    1.711V     939.5mV
575.1ps   895.1mV    1.035V     932.3mV
650.1ps   890.9mV    878.2mV    929.6mV
1.37ns    880.8mV    824.4mV    926.3mV
[Falling Waveform]
R_fixture = 50
V_fixture = 0
V_fixture_min = 0
V_fixture_max = 0
0s        914mV      872.8mV    972.4mV
119.9ps   914mV      872.8mV    961.4mV
183.7ps   914mV      872.8mV    249mV
236.6ps   849.2mV    872.8mV    90.48mV
272ps     439.6mV    872.8mV    54.2mV
322ps     145.7mV    872.8mV    29.59mV
434.7ps   31.54mV    853.3mV    10.37mV
527.2ps   16.1mV     218.6mV    5.468mV
606.7ps   11.27mV    51mV       3.393mV
1.425ns   4.56mV     5.741mV    0V
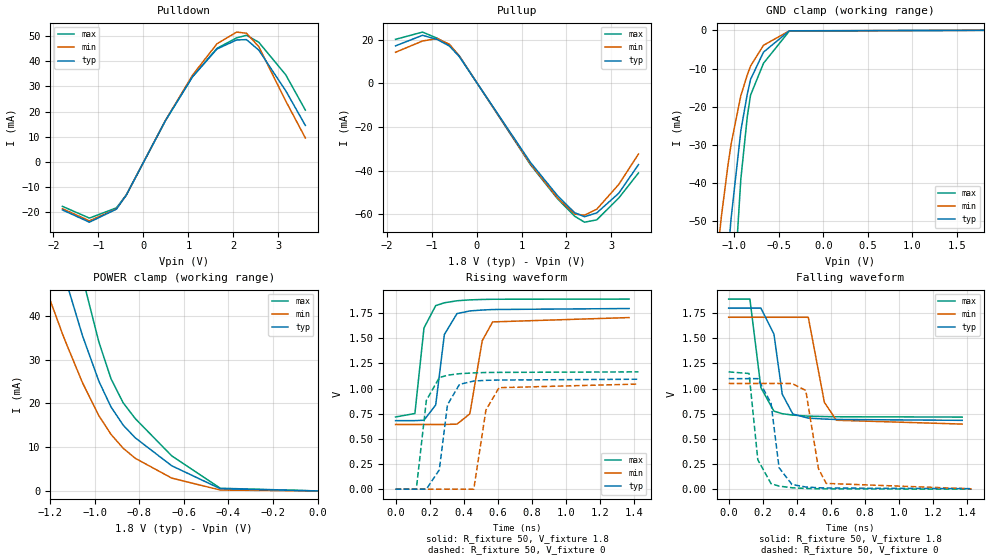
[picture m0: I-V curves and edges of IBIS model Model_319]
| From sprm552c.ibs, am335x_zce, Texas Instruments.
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| Model based on original model for BCSHTLTCSCDVPBFZ_SSDHV
|   Sub model SR00_12MA_5PER_1P8
[model]   Model_319
|[Description]  [1.8V-3-STATE-NOTERM-SR00:12MA, IND, 5%]
|   Fastest slew rate (SR[1:0] = "00"), 0.67 * RExt = 1.500 * Iout
|   (I[2:0] = "111"), 12mA nominal with Rext = 50R,ODT off (ODT[1:0]
|   = "00") CMOS mode,Industrial temperature range (-40C to 125C,
|   25C nominal),5% power supply tolerance
|[Input Load]   NOTERM
|[Output Drive] SR00:12MA
|Voltage   1.8V
|Mode   3-STATE
Model_type   3-state
Polarity   Non-Inverting
Enable   Active-Low
Cref =  15pF
Rref =  100.0000M
Vref =  0V
Vmeas =  0.9
C_comp   1.851324p   1.667199p   1.973575p
[Temperature Range]   25   125   -40
[Voltage Range]   1.8   1.71   1.89
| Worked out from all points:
|   slope of the pulldown table from 0 to 0.27 V, typ, clamps not added: 29.2 ohm
|   slope of the pullup table from 0 to 0.27 V, typ, clamps not added: 31.3 ohm
|   GND clamp passes 1 mA (typ) near -0.49 V on its own axis
|   POWER clamp passes 1 mA (typ) near -0.47 V on its own axis
|   rising waveform, R_fixture 50, V_fixture 1.8: 20-80 % time 50.7ps typ, 59.9ps min, 45.2ps max; typ from 0.682 V to 1.8 V
|   rising waveform, R_fixture 50, V_fixture 0: 20-80 % time 52.1ps typ, 54.5ps min, 48.2ps max; typ from 0 V to 1.09 V
|   falling waveform, R_fixture 50, V_fixture 1.8: 20-80 % time 57.7ps typ, 63.4ps min, 52.1ps max; typ from 1.8 V to 0.684 V
|   falling waveform, R_fixture 50, V_fixture 0: 20-80 % time 47.4ps typ, 55.4ps min, 43.4ps max; typ from 1.1 V to 0.005 V
[POWER_clamp]
-1.8V     194.9mA    137mA      262.9mA
-1.236V   68.49mA    48.49mA    92.7mA
-1.145V   50.76mA    35.84mA    69.67mA
-1.127V   47.56mA    33.52mA    65.35mA
-1.055V   35.4mA     24.68mA    48.7mA
-981.8mV  25.06mA    17.19mA    34.02mA
-927.3mV  19.17mA    12.92mA    25.62mA
-872.7mV  15.03mA    9.76mA     20.13mA
-818.2mV  12.12mA    7.445mA    16.51mA
-654.5mV  5.738mA    2.929mA    8.007mA
-436.4mV  508.2uA    199.4uA    613uA
0V        2.273nA    16.6nA     10.58nA
[Pulldown]
-1.8V     -19.04mA   -18.57mA   -17.62mA
-1.2V     -23.91mA   -23.36mA   -22.29mA
-600mV    -18.74mA   -18.66mA   -18.22mA
-381.8mV  -13.2mA    -13.18mA   -13.15mA
490.9mV   16.44mA    16.5mA     16.44mA
1.091V    33.8mA     34.43mA    33.8mA
1.636V    44.84mA    46.91mA    45.1mA
2.073V    48.42mA    51.54mA    49.25mA
2.291V    48.55mA    51.08mA    50.28mA
2.564V    44.4mA     45.79mA    47.52mA
3.164V    28.26mA    24.2mA     34.59mA
3.6V      14.49mA    9.532mA    20.59mA
[Pullup]
-1.8V     17.15mA    14.22mA    20.14mA
-1.2V     22mA       19.38mA    23.46mA
-872.7mV  20.07mA    20.5mA     20.63mA
-600mV    17.03mA    17.85mA    17.44mA
-381.8mV  12.19mA    12.42mA    12.53mA
1.2V      -36.27mA   -36.93mA   -37.3mA
1.8V      -51.43mA   -52.45mA   -52.86mA
2.182V    -59.24mA   -59.89mA   -60.87mA
2.4V      -61.1mA    -60.37mA   -63.6mA
2.673V    -59.34mA   -57.66mA   -62.53mA
3.164V    -50.29mA   -46.25mA   -52.48mA
3.6V      -37.24mA   -32.39mA   -41.05mA
[GND_clamp]
-1.8V     -346.1mA   -209.3mA   -568.3mA
-1.327V   -149.7mA   -89.03mA   -250.9mA
-1.291V   -135.6mA   -80.47mA   -227.5mA
-1.145V   -82.35mA   -48.67mA   -137.7mA
-1.073V   -59.44mA   -35.55mA   -97.96mA
-1.036V   -49.1mA    -29.72mA   -79.9mA
-927.3mV  -26.31mA   -17.11mA   -38.99mA
-854.5mV  -16.67mA   -11.64mA   -22.56mA
-818.2mV  -12.86mA   -9.351mA   -16.98mA
-672.7mV  -5.705mA   -3.913mA   -8.623mA
-381.8mV  -120.4uA   -129uA     -167.2uA
1.8V      2.273nA    51.44nA    6.654nA
[Ramp]
dV/dt_f 0.68310594/57.971902p 0.65571928/65.034985p 0.71290741/52.078576p
dV/dt_r 0.66840919/52.682562p 0.64600483/55.254542p 0.70759111/48.269147p
R_load = 50
[Rising Waveform]
R_fixture = 50
V_fixture = 1.8
V_fixture_min = 1.71
V_fixture_max = 1.89
0s        681.5mV    643mV      717.7mV
113.5ps   681.5mV    643mV      752.4mV
166.8ps   685.3mV    643mV      1.603V
235.6ps   837.7mV    643mV      1.825V
286.4ps   1.538V     643mV      1.853V
360.7ps   1.746V     646.9mV    1.873V
435.9ps   1.772V     749.1mV    1.882V
508.5ps   1.781V     1.476V     1.886V
569.6ps   1.786V     1.663V     1.888V
1.37ns    1.796V     1.706V     1.89V
[Rising Waveform]
R_fixture = 50
V_fixture = 0
V_fixture_min = 0
V_fixture_max = 0
0s        0V         0V         0V
121.7ps   0V         0V         0V
180.7ps   0V         0V         881.9mV
256.5ps   191.1mV    0V         1.109V
304.8ps   839.9mV    0V         1.133V
375.2ps   1.042V     0V         1.148V
458.9ps   1.075V     0V         1.156V
530.1ps   1.082V     786mV      1.16V
606.9ps   1.085V     1.009V     1.161V
1.425ns   1.093V     1.045V     1.166V
[Falling Waveform]
R_fixture = 50
V_fixture = 1.8
V_fixture_min = 1.71
V_fixture_max = 1.89
0s        1.8V       1.709V     1.89V
124.5ps   1.8V       1.709V     1.89V
188.9ps   1.8V       1.709V     1.01V
265.5ps   1.542V     1.709V     776mV
314.4ps   944.1mV    1.709V     750.4mV
376.4ps   747mV      1.709V     736.2mV
467.1ps   706.1mV    1.709V     726mV
561.5ps   697.1mV    862.6mV    721.9mV
632ps     693mV      685.2mV    720mV
1.37ns    684.2mV    647.1mV    716.7mV
[Falling Waveform]
R_fixture = 50
V_fixture = 0
V_fixture_min = 0
V_fixture_max = 0
0s        1.099V     1.051V     1.166V
119.6ps   1.099V     1.051V     1.15V
170.9ps   1.099V     1.051V     292.6mV
248.6ps   853.5mV    1.051V     54.68mV
295.7ps   212.7mV    1.051V     30.37mV
371.3ps   46.19mV    1.051V     14.11mV
452.4ps   21.42mV    981.3mV    6.943mV
526.8ps   14.24mV    203.4mV    4.135mV
572.1ps   11.48mV    57.27mV    3.126mV
1.425ns   4.775mV    3.545mV    0V
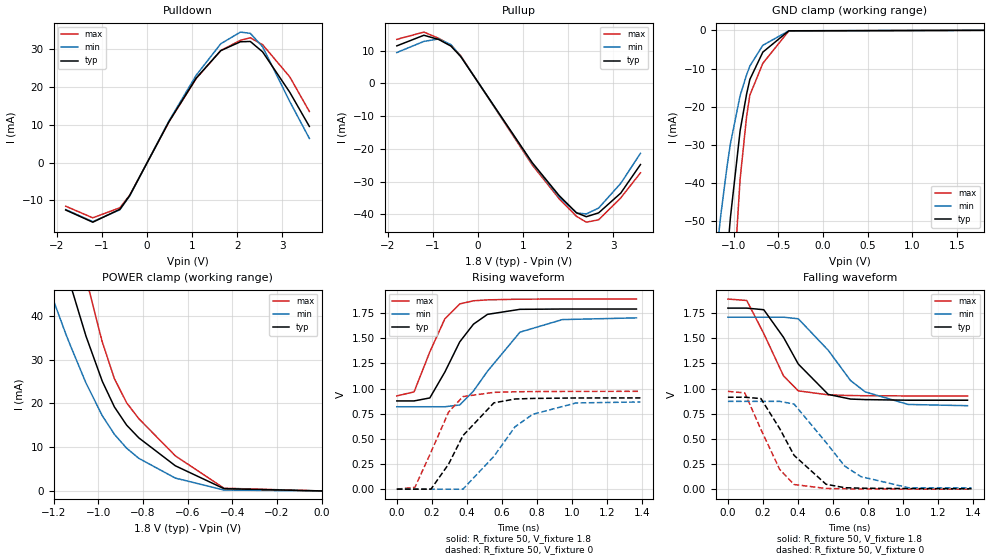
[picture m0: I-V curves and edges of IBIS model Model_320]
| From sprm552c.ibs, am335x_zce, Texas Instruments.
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| Model based on original model for BCSHTLTCSCDVPBFZ_SSDHV
|   Sub model SR01_8MA_5PER_1P8
[model]   Model_320
|[Description]  [1.8V-3-STATE-NOTERM-SR01:8MA, IND, 5%]
|   Slow slew rate (SR[1:0] = "01"), 1.00 * RExt = 1.000 * Iout
|   (I[2:0] = "011"), 8mA nominal with Rext = 50R,ODT off (ODT[1:0]
|   = "00") CMOS mode,Industrial temperature range (-40C to 125C,
|   25C nominal),5% power supply tolerance
|[Input Load]   NOTERM
|[Output Drive] SR01:8MA
|Voltage   1.8V
|Mode   3-STATE
Model_type   3-state
Polarity   Non-Inverting
Enable   Active-Low
Cref =  15pF
Rref =  100.0000M
Vref =  0V
Vmeas =  0.9
C_comp   1.851324p   1.667199p   1.973575p
[Temperature Range]   25   125   -40
[Voltage Range]   1.8   1.71   1.89
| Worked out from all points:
|   slope of the pulldown table from 0 to 0.27 V, typ, clamps not added: 44.4 ohm
|   slope of the pullup table from 0 to 0.27 V, typ, clamps not added: 47 ohm
|   GND clamp passes 1 mA (typ) near -0.49 V on its own axis
|   POWER clamp passes 1 mA (typ) near -0.47 V on its own axis
|   rising waveform, R_fixture 50, V_fixture 1.8: 20-80 % time 177ps typ, 228ps min, 139ps max; typ from 0.877 V to 1.79 V
|   rising waveform, R_fixture 50, V_fixture 0: 20-80 % time 183ps typ, 240ps min, 146ps max; typ from 0 V to 0.907 V
|   falling waveform, R_fixture 50, V_fixture 1.8: 20-80 % time 198ps typ, 246ps min, 152ps max; typ from 1.8 V to 0.884 V
|   falling waveform, R_fixture 50, V_fixture 0: 20-80 % time 195ps typ, 240ps min, 150ps max; typ from 0.914 V to 0.004 V
[POWER_clamp]
-1.8V     194.9mA    137mA      262.9mA
-1.236V   68.49mA    48.49mA    92.7mA
-1.145V   50.76mA    35.84mA    69.67mA
-1.127V   47.56mA    33.52mA    65.35mA
-1.055V   35.4mA     24.68mA    48.7mA
-981.8mV  25.06mA    17.19mA    34.02mA
-927.3mV  19.17mA    12.92mA    25.62mA
-872.7mV  15.03mA    9.76mA     20.13mA
-818.2mV  12.12mA    7.445mA    16.51mA
-654.5mV  5.738mA    2.929mA    8.007mA
-436.4mV  508.2uA    199.4uA    613uA
0V        2.273nA    16.6nA     10.58nA
[Pulldown]
-1.8V     -12.51mA   -12.38mA   -11.51mA
-1.2V     -15.72mA   -15.57mA   -14.57mA
-600mV    -12.32mA   -12.45mA   -11.92mA
-381.8mV  -8.686mA   -8.794mA   -8.605mA
490.9mV   10.82mA    11.01mA    10.76mA
1.091V    22.23mA    22.98mA    22.12mA
1.636V    29.48mA    31.29mA    29.5mA
2.073V    31.82mA    34.37mA    32.21mA
2.291V    31.9mA     34.04mA    32.88mA
2.564V    29.16mA    30.5mA     31.05mA
3.164V    18.55mA    16.11mA    22.6mA
3.6V      9.513mA    6.35mA     13.45mA
[Pullup]
-1.8V     11.43mA    9.39mA     13.42mA
-1.2V     14.67mA    12.8mA     15.64mA
-872.7mV  13.39mA    13.55mA    13.76mA
-600mV    11.36mA    11.8mA     11.63mA
-381.8mV  8.135mA    8.218mA    8.363mA
1.2V      -24.2mA    -24.42mA   -24.89mA
1.8V      -34.31mA   -34.68mA   -35.27mA
2.182V    -39.52mA   -39.59mA   -40.61mA
2.4V      -40.73mA   -39.88mA   -42.4mA
2.673V    -39.55mA   -38.08mA   -41.67mA
3.164V    -33.5mA    -30.53mA   -34.96mA
3.6V      -24.8mA    -21.38mA   -27.34mA
[GND_clamp]
-1.8V     -346.1mA   -209.3mA   -568.3mA
-1.327V   -149.7mA   -89.03mA   -250.9mA
-1.291V   -135.6mA   -80.47mA   -227.5mA
-1.145V   -82.35mA   -48.67mA   -137.7mA
-1.073V   -59.44mA   -35.55mA   -97.96mA
-1.036V   -49.1mA    -29.72mA   -79.9mA
-927.3mV  -26.31mA   -17.11mA   -38.99mA
-854.5mV  -16.67mA   -11.64mA   -22.56mA
-818.2mV  -12.86mA   -9.351mA   -16.98mA
-672.7mV  -5.705mA   -3.913mA   -8.623mA
-381.8mV  -120.4uA   -129uA     -167.2uA
1.8V      2.273nA    51.44nA    6.654nA
[Ramp]
dV/dt_f 0.55469013/0.20109594n 0.53490887/0.25022189n 0.57917204/0.15209661n
dV/dt_r 0.54951798/0.18591931n 0.52435283/0.24027281n 0.58470967/0.14578496n
R_load = 50
[Rising Waveform]
R_fixture = 50
V_fixture = 1.8
V_fixture_min = 1.71
V_fixture_max = 1.89
0s        877.3mV    819.4mV    927mV
98.8ps    877.3mV    819.4mV    967.4mV
188.7ps   906.9mV    819.4mV    1.365V
274.8ps   1.165V     819.4mV    1.694V
360ps     1.465V     837.2mV    1.842V
438.6ps   1.641V     976.2mV    1.873V
518.6ps   1.738V     1.173V     1.882V
704.1ps   1.788V     1.561V     1.889V
946.4ps   1.791V     1.686V     1.89V
1.37ns    1.791V     1.703V     1.89V
[Rising Waveform]
R_fixture = 50
V_fixture = 0
V_fixture_min = 0
V_fixture_max = 0
0s        0V         0V         0V
103.4ps   0V         0V         17.86mV
195.1ps   0V         0V         367.5mV
296.1ps   249.1mV    0V         766.7mV
378.1ps   532.3mV    0V         920.5mV
554.9ps   858.1mV    325.8mV    962.4mV
676.1ps   896.5mV    620.6mV    968.1mV
776.8ps   902mV      744.1mV    970.4mV
1.025ns   906.6mV    857.2mV    972.2mV
1.393ns   907.3mV    866.9mV    972.6mV
[Falling Waveform]
R_fixture = 50
V_fixture = 1.8
V_fixture_min = 1.71
V_fixture_max = 1.89
0s        1.799V     1.709V     1.889V
107.6ps   1.799V     1.709V     1.875V
205.1ps   1.783V     1.709V     1.546V
318ps     1.508V     1.709V     1.125V
402.4ps   1.243V     1.693V     976.9mV
573.6ps   941.5mV    1.38V      937.2mV
701.2ps   895.2mV    1.079V     930.4mV
784.9ps   890mV      966.7mV    928.4mV
1.031ns   883.9mV    841.7mV    926.6mV
1.37ns    883.9mV    829.4mV    926.6mV
[Falling Waveform]
R_fixture = 50
V_fixture = 0
V_fixture_min = 0
V_fixture_max = 0
0s        913.6mV    872.4mV    971.7mV
96.2ps    913.6mV    872.4mV    956.8mV
188.8ps   900.2mV    872.4mV    593.2mV
295.9ps   602.2mV    872.4mV    196.4mV
378.3ps   335.8mV    845.7mV    46.03mV
561ps     48.68mV    464.4mV    7.012mV
667.2ps   14.79mV    230.2mV    3.558mV
759.6ps   9.722mV    125.3mV    2.1mV
1.035ns   5.884mV    13.03mV    0V
1.393ns   4.119mV    13.03mV    0V
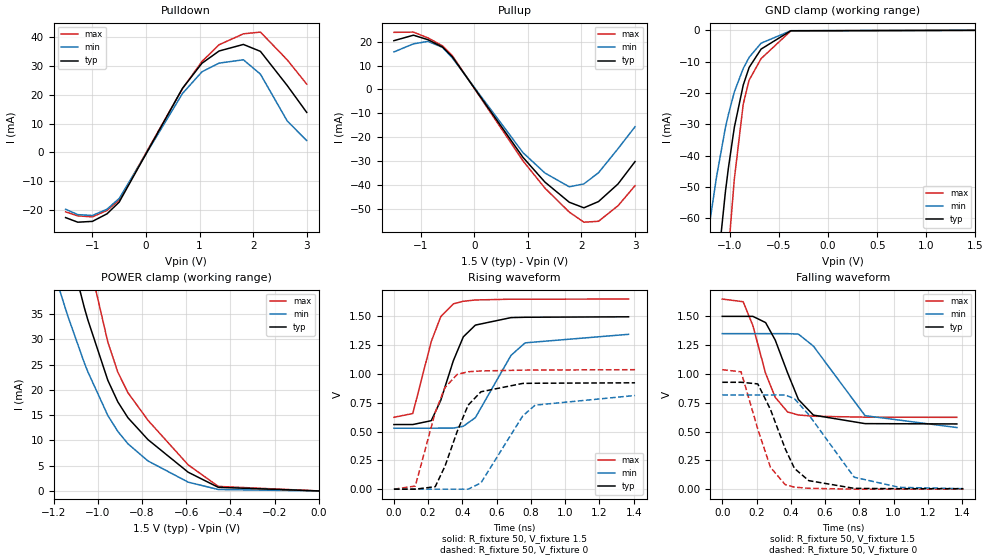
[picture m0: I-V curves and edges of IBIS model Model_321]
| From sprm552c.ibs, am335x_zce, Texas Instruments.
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| Model based on original model for BCSHTLTCSCDVPBFZ_SSDHV
|   Sub model SR01_12MA_10PER_1P5
[model]   Model_321
|[Description]  [1.5V-3-STATE-NOTERM-SR01:12MA, IND, 10%]
|   Slow slew rate (SR[1:0] = "01"), 0.67 * RExt = 1.500 * Iout
|   (I[2:0] = "111"), 12mA nominal with Rext = 50R,ODT off (ODT[1:0]
|   = "00") CMOS mode,Industrial temperature range (-40C to 125C,
|   25C nominal),10% power supply tolerance
|[Input Load]   NOTERM
|[Output Drive] SR01:12MA
|Voltage   1.5V
|Mode   3-STATE
Model_type   3-state
Polarity   Non-Inverting
Enable   Active-Low
Cref =  15pF
Rref =  100.0000M
Vref =  0V
Vmeas =  0.75
C_comp   1.865048p   1.676829p   1.989968p
[Temperature Range]   25   125   -40
[Voltage Range]   1.5   1.35   1.65
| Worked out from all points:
|   slope of the pulldown table from 0 to 0.225 V, typ, clamps not added: 28.3 ohm
|   slope of the pullup table from 0 to 0.225 V, typ, clamps not added: 30.1 ohm
|   GND clamp passes 1 mA (typ) near -0.49 V on its own axis
|   POWER clamp passes 1 mA (typ) near -0.47 V on its own axis
|   rising waveform, R_fixture 50, V_fixture 1.5: 20-80 % time 133ps typ, 190ps min, 108ps max; typ from 0.561 V to 1.5 V
|   rising waveform, R_fixture 50, V_fixture 0: 20-80 % time 143ps typ, 197ps min, 113ps max; typ from 0 V to 0.923 V
|   falling waveform, R_fixture 50, V_fixture 1.5: 20-80 % time 154ps typ, 223ps min, 125ps max; typ from 1.5 V to 0.566 V
|   falling waveform, R_fixture 50, V_fixture 0: 20-80 % time 149ps typ, 226ps min, 121ps max; typ from 0.927 V to 0.004 V
[POWER_clamp]
-1.5V     126mA      88.79mA    168.7mA
-1.242V   69.8mA     49.45mA    94.34mA
-1.136V   49.16mA    34.72mA    67.51mA
-1.061V   36.35mA    25.4mA     50.03mA
-1.045V   33.92mA    23.63mA    46.66mA
-954.5mV  21.93mA    14.95mA    29.5mA
-909.1mV  17.64mA    11.79mA    23.52mA
-863.6mV  14.51mA    9.351mA    19.47mA
-772.7mV  10.16mA    5.94mA     13.99mA
-590.9mV  3.705mA    1.741mA    5.166mA
-454.5mV  710.5uA    279.1uA    892.1uA
0V        1.424nA    14.34nA    3.127nA
[Pulldown]
-1.5V     -22.72mA   -19.8mA    -20.72mA
-1.273V   -24.32mA   -21.69mA   -22.12mA
-1V       -24.04mA   -21.98mA   -22.46mA
-727.3mV  -21.41mA   -19.82mA   -20.23mA
-500mV    -17.33mA   -16.07mA   -16.65mA
681.8mV   22.29mA    20.49mA    22.2mA
1.045V    31.02mA    28.05mA    31.64mA
1.364V    35.28mA    31.06mA    37.46mA
1.818V    37.57mA    32.23mA    41.26mA
2.136V    35.16mA    27.23mA    41.87mA
2.636V    23.27mA    10.93mA    32.21mA
3V        13.9mA     4.109mA    23.75mA
[Pullup]
-1.5V     20.4mA     15.7mA     23.88mA
-1.136V   22.69mA    19.07mA    23.99mA
-863.6mV  20.8mA     20.11mA    21.55mA
-590.9mV  17.69mA    17.57mA    18.24mA
-409.1mV  13.64mA    13.19mA    14.12mA
909.1mV   -28.37mA   -26.41mA   -29.83mA
1.318V    -38.69mA   -34.9mA    -41.21mA
1.773V    -47.12mA   -40.66mA   -51.24mA
2.045V    -49.44mA   -39.45mA   -55.45mA
2.318V    -46.83mA   -34.79mA   -55.07mA
2.682V    -39.48mA   -24.74mA   -48.59mA
3V        -30.12mA   -15.56mA   -40.19mA
[GND_clamp]
-1.5V     -219.3mA   -131.6mA   -364.3mA
-1.288V   -134.4mA   -79.74mA   -225.6mA
-1.258V   -122.9mA   -72.77mA   -206.3mA
-1.136V   -79.27mA   -46.88mA   -132.4mA
-1.045V   -51.5mA    -31.06mA   -84.11mA
-1.015V   -44.02mA   -26.9mA    -70.91mA
-954.5mV  -31.01mA   -19.7mA    -47.55mA
-863.6mV  -17.48mA   -12.16mA   -23.55mA
-803mV    -11.81mA   -8.597mA   -15.85mA
-681.8mV  -5.986mA   -4.096mA   -9.026mA
-378.8mV  -126.2uA   -131.8uA   -179.7uA
1.5V      1.424nA    207.1nA    1.498nA
[Ramp]
dV/dt_f  0.5657327/0.15571846n 0.49484053/0.22600341n 0.61771145/0.12522652n
dV/dt_r 0.55903158/0.14462588n 0.49407466/0.19848659n 0.62405663/0.11305203n
R_load = 50
[Rising Waveform]
R_fixture = 50
V_fixture = 1.5
V_fixture_min = 1.35
V_fixture_max = 1.65
0s        560.9mV    529.1mV    623.9mV
110.2ps   560.9mV    529.1mV    656.5mV
218.1ps   594.5mV    529.1mV    1.282V
273.5ps   771.4mV    529.9mV    1.497V
347ps     1.115V     530mV      1.608V
405.2ps   1.322V     545.9mV    1.631V
475.6ps   1.424V     620.6mV    1.642V
683.6ps   1.489V     1.161V     1.649V
765.9ps   1.492V     1.27V      1.649V
1.37ns    1.496V     1.344V     1.65V
[Rising Waveform]
R_fixture = 50
V_fixture = 0
V_fixture_min = 0
V_fixture_max = 0
0s        0V         0V         0V
125.1ps   0V         0V         27.09mV
241.2ps   21.37mV    0V         666.9mV
297.8ps   198mV      0V         881.1mV
369.7ps   501.8mV    0V         996.3mV
433.5ps   729.6mV    0V         1.019V
508.3ps   845.5mV    54.78mV    1.026V
752ps     917.9mV    635.6mV    1.033V
824.5ps   919.4mV    729.3mV    1.034V
1.408ns   923.1mV    813mV      1.037V
[Falling Waveform]
R_fixture = 50
V_fixture = 1.5
V_fixture_min = 1.35
V_fixture_max = 1.65
0s        1.499V     1.349V     1.649V
122.1ps   1.499V     1.349V     1.626V
178.8ps   1.499V     1.349V     1.419V
253.2ps   1.445V     1.349V     1.004V
309.4ps   1.293V     1.349V     796.7mV
381.7ps   1.008V     1.349V     669.5mV
444.8ps   777.7mV    1.345V     643.7mV
532.2ps   642.5mV    1.241V     632.7mV
833.8ps   568.5mV    637.5mV    624.6mV
1.37ns    565.7mV    534.5mV    623mV
[Falling Waveform]
R_fixture = 50
V_fixture = 0
V_fixture_min = 0
V_fixture_max = 0
0s        927.1mV    817.1mV    1.036V
110.1ps   927.1mV    817.1mV    1.018V
207.5ps   913.1mV    817.1mV    521.5mV
281.4ps   691.7mV    817.1mV    189.5mV
368ps     349.5mV    817.1mV    38.57mV
421.7ps   179.8mV    784.7mV    17.56mV
505ps     73.94mV    646.1mV    7.512mV
770.5ps   7.029mV    103.5mV    0V
1.034ns   4.132mV    15.75mV    0V
1.408ns   4.132mV    3.871mV    0V
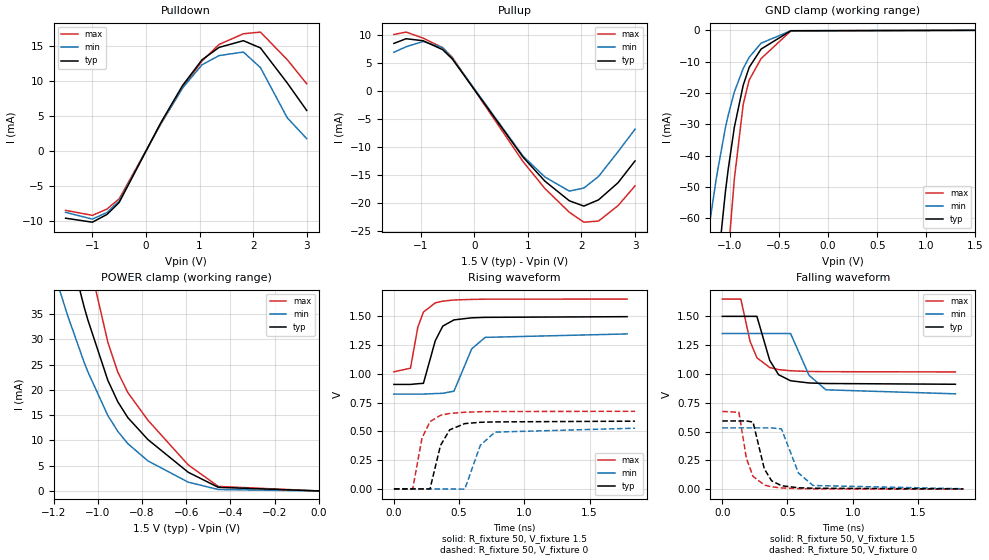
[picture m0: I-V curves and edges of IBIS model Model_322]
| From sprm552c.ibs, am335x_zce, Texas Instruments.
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| Model based on original model for BCSHTLTCSCDVPBFZ_SSDHV
|   Sub model SR00_5MA_10PER_1P5
[model]   Model_322
|[Description]  [1.5V-3-STATE-NOTERM-SR00:5MA, IND, 10%]
|   Fastest slew rate (SR[1:0] = "00"), 1.60 * RExt = 0.625 * Iout
|   (I[2:0] = "000"), 5mA nominal with Rext = 50R,ODT off (ODT[1:0]
|   = "00") CMOS mode,Industrial temperature range (-40C to 125C,
|   25C nominal),10% power supply tolerance
|[Input Load]   NOTERM
|[Output Drive] SR00:5MA
|Voltage   1.5V
|Mode   3-STATE
Model_type   3-state
Polarity   Non-Inverting
Enable   Active-Low
Cref =  15pF
Rref =  100.0000M
Vref =  0V
Vmeas =  0.75
C_comp   1.865048p   1.676829p   1.989968p
[Temperature Range]   25   125   -40
[Voltage Range]   1.5   1.35   1.65
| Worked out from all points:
|   slope of the pulldown table from 0 to 0.225 V, typ, clamps not added: 67.2 ohm
|   slope of the pullup table from 0 to 0.225 V, typ, clamps not added: 72 ohm
|   GND clamp passes 1 mA (typ) near -0.49 V on its own axis
|   POWER clamp passes 1 mA (typ) near -0.47 V on its own axis
|   rising waveform, R_fixture 50, V_fixture 1.5: 20-80 % time 87.5ps typ, 116ps min, 74.6ps max; typ from 0.908 V to 1.5 V
|   rising waveform, R_fixture 50, V_fixture 0: 20-80 % time 91.1ps typ, 106ps min, 81.4ps max; typ from 0 V to 0.589 V
|   falling waveform, R_fixture 50, V_fixture 1.5: 20-80 % time 106ps typ, 130ps min, 93.8ps max; typ from 1.5 V to 0.91 V
|   falling waveform, R_fixture 50, V_fixture 0: 20-80 % time 80ps typ, 103ps min, 74ps max; typ from 0.592 V to 0.002 V
[POWER_clamp]
-1.5V     126mA      88.79mA    168.7mA
-1.242V   69.8mA     49.45mA    94.34mA
-1.136V   49.16mA    34.72mA    67.51mA
-1.061V   36.35mA    25.4mA     50.03mA
-1.045V   33.92mA    23.63mA    46.66mA
-954.5mV  21.93mA    14.95mA    29.5mA
-909.1mV  17.64mA    11.79mA    23.52mA
-863.6mV  14.51mA    9.351mA    19.47mA
-772.7mV  10.16mA    5.94mA     13.99mA
-590.9mV  3.705mA    1.741mA    5.166mA
-454.5mV  710.5uA    279.1uA    892.1uA
0V        1.424nA    14.34nA    3.127nA
[Pulldown]
-1.5V     -9.559mA   -8.721mA   -8.435mA
-1V       -10.13mA   -9.69mA    -9.153mA
-727.3mV  -9.021mA   -8.741mA   -8.25mA
-500mV    -7.306mA   -7.092mA   -6.791mA
272.7mV   4.034mA    3.899mA    3.845mA
681.8mV   9.399mA    9.044mA    9.061mA
1.045V    13.08mA    12.37mA    12.91mA
1.364V    14.86mA    13.69mA    15.28mA
1.818V    15.82mA    14.2mA     16.81mA
2.136V    14.79mA    11.98mA    17.05mA
2.636V    9.781mA    4.81mA     13.11mA
3V        5.846mA    1.81mA     9.659mA
[Pullup]
-1.5V     8.494mA    6.914mA    10.1mA
-1.273V   9.331mA    7.894mA    10.52mA
-954.5mV  8.972mA    8.846mA    9.444mA
-590.9mV  7.379mA    7.751mA    7.725mA
-409.1mV  5.694mA    5.824mA    5.984mA
909.1mV   -11.84mA   -11.65mA   -12.64mA
1.318V    -16.14mA   -15.4mA    -17.46mA
1.773V    -19.65mA   -17.92mA   -21.7mA
2.045V    -20.6mA    -17.37mA   -23.48mA
2.318V    -19.49mA   -15.31mA   -23.28mA
2.682V    -16.43mA   -10.88mA   -20.53mA
3V        -12.52mA   -6.85mA    -16.98mA
[GND_clamp]
-1.5V     -219.3mA   -131.6mA   -364.3mA
-1.288V   -134.4mA   -79.74mA   -225.6mA
-1.258V   -122.9mA   -72.77mA   -206.3mA
-1.136V   -79.27mA   -46.88mA   -132.4mA
-1.045V   -51.5mA    -31.06mA   -84.11mA
-1.015V   -44.02mA   -26.9mA    -70.91mA
-954.5mV  -31.01mA   -19.7mA    -47.55mA
-863.6mV  -17.48mA   -12.16mA   -23.55mA
-803mV    -11.81mA   -8.597mA   -15.85mA
-681.8mV  -5.986mA   -4.096mA   -9.026mA
-378.8mV  -126.2uA   -131.8uA   -179.7uA
1.5V      1.424nA    207.1nA    1.498nA
[Ramp]
dV/dt_f 0.36155451/0.10708702n 0.32335176/0.1321113n 0.38398982/93.959036p
dV/dt_r 0.36102539/92.401519p 0.32805477/0.10803152n 0.40887495/81.357591p
R_load = 50
[Rising Waveform]
R_fixture = 50
V_fixture = 1.5
V_fixture_min = 1.35
V_fixture_max = 1.65
0s        908.2mV    824mV      1.018V
126.9ps   908.2mV    824mV      1.049V
183ps     914.2mV    824mV      1.405V
226.2ps   917.6mV    824mV      1.537V
317ps     1.288V     828.8mV    1.617V
374.5ps   1.415V     831.1mV    1.632V
460.3ps   1.469V     849.4mV    1.642V
595.8ps   1.487V     1.217V     1.647V
699.4ps   1.491V     1.317V     1.649V
1.787ns   1.497V     1.347V     1.65V
[Rising Waveform]
R_fixture = 50
V_fixture = 0
V_fixture_min = 0
V_fixture_max = 0
0s        0V         0V         0V
143.9ps   0V         0V         0V
215.2ps   0V         0V         441.3mV
276.5ps   0V         0V         584.5mV
356.9ps   377.5mV    0V         639.8mV
427.3ps   513.5mV    0V         656mV
543.1ps   567.6mV    -2.17mV    666.4mV
662.5ps   579mV      379.8mV    670.8mV
775.1ps   582.4mV    493.7mV    672.6mV
1.848ns   588.9mV    527.6mV    674.5mV
[Falling Waveform]
R_fixture = 50
V_fixture = 1.5
V_fixture_min = 1.35
V_fixture_max = 1.65
0s        1.499V     1.35V      1.649V
142.6ps   1.499V     1.35V      1.649V
213.2ps   1.499V     1.35V      1.282V
265.6ps   1.499V     1.35V      1.14V
363.5ps   1.118V     1.35V      1.055V
431.6ps   993mV      1.35V      1.037V
523.6ps   940.3mV    1.35V      1.027V
665.4ps   921.2mV    987.3mV    1.021V
794.4ps   916.5mV    861.8mV    1.019V
1.787ns   910mV      827mV      1.017V
[Falling Waveform]
R_fixture = 50
V_fixture = 0
V_fixture_min = 0
V_fixture_max = 0
0s        591.6mV    531.8mV    674.3mV
127.6ps   591.6mV    531.8mV    666.8mV
184.9ps   591.6mV    531.8mV    268.7mV
235.7ps   582.4mV    531.8mV    111.3mV
322.3ps   176.1mV    531.8mV    35.86mV
378ps     72.94mV    531.8mV    20.32mV
454ps     29.77mV    522.2mV    10.79mV
584.1ps   12.01mV    139.8mV    4.567mV
695.8ps   8.201mV    31.76mV    2.411mV
1.848ns   2.167mV    3.572mV    0V
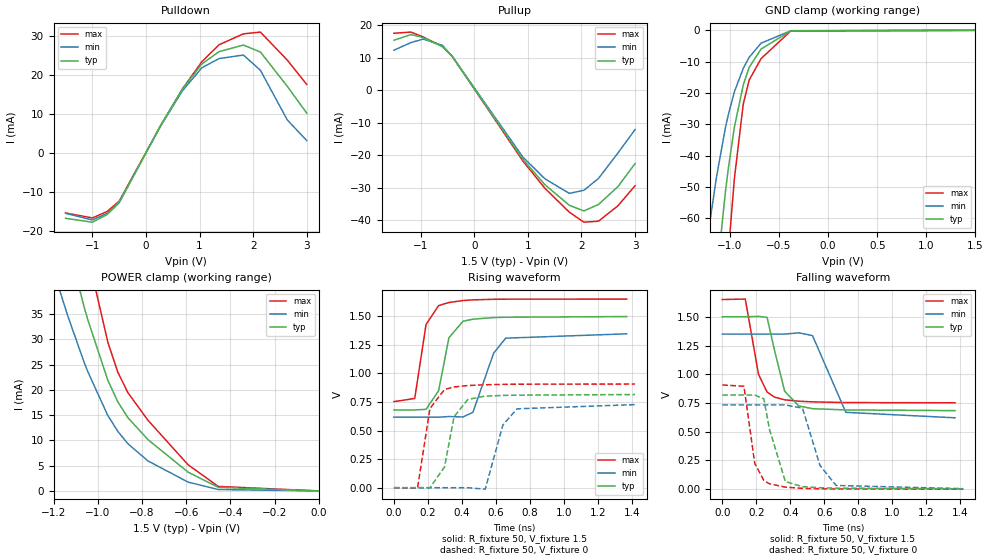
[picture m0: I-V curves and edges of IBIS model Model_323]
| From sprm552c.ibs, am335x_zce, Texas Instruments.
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| Model based on original model for BCSHTLTCSCDVPBFZ_SSDHV
|   Sub model SR00_9MA_10PER_1P5
[model]   Model_323
|[Description]  [1.5V-3-STATE-NOTERM-SR00:9MA, IND, 10%]
|   Fastest slew rate (SR[1:0] = "00"), 0.88 * RExt = 1.125 * Iout
|   (I[2:0] = "100"), 9mA nominal with Rext = 50R,ODT off (ODT[1:0]
|   = "00") CMOS mode,Industrial temperature range (-40C to 125C,
|   25C nominal),10% power supply tolerance
|[Input Load]   NOTERM
|[Output Drive] SR00:9MA
|Voltage   1.5V
|Mode   3-STATE
Model_type   3-state
Polarity   Non-Inverting
Enable   Active-Low
Cref =  15pF
Rref =  100.0000M
Vref =  0V
Vmeas =  0.75
C_comp   1.865048p   1.676829p   1.989968p
[Temperature Range]   25   125   -40
[Voltage Range]   1.5   1.35   1.65
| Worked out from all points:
|   slope of the pulldown table from 0 to 0.225 V, typ, clamps not added: 38.4 ohm
|   slope of the pullup table from 0 to 0.225 V, typ, clamps not added: 40.1 ohm
|   GND clamp passes 1 mA (typ) near -0.49 V on its own axis
|   POWER clamp passes 1 mA (typ) near -0.47 V on its own axis
|   rising waveform, R_fixture 50, V_fixture 1.5: 20-80 % time 67.1ps typ, 99.3ps min, 56.1ps max; typ from 0.68 V to 1.5 V
|   rising waveform, R_fixture 50, V_fixture 0: 20-80 % time 66.6ps typ, 79.6ps min, 60ps max; typ from 0 V to 0.815 V
|   falling waveform, R_fixture 50, V_fixture 1.5: 20-80 % time 77.5ps typ, 97.8ps min, 67.4ps max; typ from 1.5 V to 0.684 V
|   falling waveform, R_fixture 50, V_fixture 0: 20-80 % time 60.6ps typ, 85.2ps min, 54.2ps max; typ from 0.819 V to 0.003 V
[POWER_clamp]
-1.5V     126mA      88.79mA    168.7mA
-1.242V   69.8mA     49.45mA    94.34mA
-1.136V   49.16mA    34.72mA    67.51mA
-1.061V   36.35mA    25.4mA     50.03mA
-1.045V   33.92mA    23.63mA    46.66mA
-954.5mV  21.93mA    14.95mA    29.5mA
-909.1mV  17.64mA    11.79mA    23.52mA
-863.6mV  14.51mA    9.351mA    19.47mA
-772.7mV  10.16mA    5.94mA     13.99mA
-590.9mV  3.705mA    1.741mA    5.166mA
-454.5mV  710.5uA    279.1uA    892.1uA
0V        1.424nA    14.34nA    3.127nA
[Pulldown]
-1.5V     -16.73mA   -15.43mA   -15.34mA
-1V       -17.72mA   -17.14mA   -16.64mA
-727.3mV  -15.78mA   -15.46mA   -14.99mA
-500mV    -12.78mA   -12.54mA   -12.34mA
272.7mV   7.051mA    6.89mA     6.983mA
681.8mV   16.43mA    15.99mA    16.46mA
1.045V    22.87mA    21.88mA    23.45mA
1.364V    26mA       24.22mA    27.76mA
1.818V    27.68mA    25.13mA    30.56mA
2.136V    25.9mA     21.22mA    31.01mA
2.636V    17.13mA    8.517mA    23.85mA
3V        10.24mA    3.203mA    17.58mA
[Pullup]
-1.5V     15.3mA     12.24mA    17.45mA
-1.182V   17.04mA    14.59mA    17.8mA
-954.5mV  16.15mA    15.65mA    16.31mA
-590.9mV  13.28mA    13.71mA    13.34mA
-409.1mV  10.24mA    10.29mA    10.33mA
909.1mV   -21.29mA   -20.6mA    -21.82mA
1.318V    -29.04mA   -27.22mA   -30.13mA
1.773V    -35.35mA   -31.7mA    -37.46mA
2.045V    -37.08mA   -30.75mA   -40.54mA
2.318V    -35.11mA   -27.11mA   -40.23mA
2.682V    -29.59mA   -19.28mA   -35.49mA
3V        -22.57mA   -12.13mA   -29.35mA
[GND_clamp]
-1.5V     -219.3mA   -131.6mA   -364.3mA
-1.288V   -134.4mA   -79.74mA   -225.6mA
-1.258V   -122.9mA   -72.77mA   -206.3mA
-1.136V   -79.27mA   -46.88mA   -132.4mA
-1.045V   -51.5mA    -31.06mA   -84.11mA
-1.015V   -44.02mA   -26.9mA    -70.91mA
-954.5mV  -31.01mA   -19.7mA    -47.55mA
-863.6mV  -17.48mA   -12.16mA   -23.55mA
-803mV    -11.81mA   -8.597mA   -15.85mA
-681.8mV  -5.986mA   -4.096mA   -9.026mA
-378.8mV  -126.2uA   -131.8uA   -179.7uA
1.5V      1.424nA    207.1nA    1.498nA
[Ramp]
dV/dt_f 0.50180044/79.005958p 0.45162287/99.793354p 0.54615162/67.591724p
dV/dt_r 0.50090925/67.314438p 0.45546525/80.383391p 0.55173261/60.152299p
R_load = 50
[Rising Waveform]
R_fixture = 50
V_fixture = 1.5
V_fixture_min = 1.35
V_fixture_max = 1.65
0s        680.3mV    616.8mV    752.7mV
122.5ps   680.3mV    616.8mV    780.7mV
189.1ps   685.3mV    616.8mV    1.428V
263.3ps   849.3mV    616.8mV    1.593V
323.9ps   1.312V     622.6mV    1.62V
406.5ps   1.456V     618.6mV    1.637V
465ps     1.474V     659.6mV    1.643V
586.9ps   1.488V     1.177V     1.648V
657.8ps   1.491V     1.308V     1.649V
1.37ns    1.497V     1.346V     1.65V
[Rising Waveform]
R_fixture = 50
V_fixture = 0
V_fixture_min = 0
V_fixture_max = 0
0s        0V         0V         0V
138.8ps   0V         0V         -3.242mV
212.1ps   0V         0V         692.3mV
297.6ps   180.7mV    0V         859.4mV
353.8ps   620.6mV    0V         881mV
435ps     772.2mV    0V         893.5mV
537.4ps   801mV      -12.9mV    900.3mV
641.4ps   807.1mV    548.9mV    903.7mV
724.3ps   809.3mV    689.9mV    905.3mV
1.419ns   815.1mV    726.9mV    906.7mV
[Falling Waveform]
R_fixture = 50
V_fixture = 1.5
V_fixture_min = 1.35
V_fixture_max = 1.65
0s        1.501V     1.35V      1.651V
135.5ps   1.501V     1.35V      1.655V
213.6ps   1.504V     1.35V      998.8mV
263.8ps   1.496V     1.35V      845.3mV
307.7ps   1.208V     1.35V      800.9mV
367.1ps   853.4mV    1.35V      777.9mV
450.2ps   724.5mV    1.361V     765.8mV
531.1ps   700.7mV    1.337V     760.1mV
727.1ps   689.8mV    668.9mV    753.9mV
1.37ns    683.8mV    621.2mV    752mV
[Falling Waveform]
R_fixture = 50
V_fixture = 0
V_fixture_min = 0
V_fixture_max = 0
0s        818.9mV    733.3mV    907.3mV
127.6ps   818.9mV    733.3mV    895.5mV
191.3ps   818.9mV    733.3mV    224.8mV
245.1ps   785.8mV    733.3mV    75.33mV
277.8ps   521.5mV    733.3mV    46.64mV
371.3ps   66.24mV    733.3mV    17.58mV
472.4ps   21.58mV    705mV      7.319mV
575.2ps   12.54mV    205.9mV    3.637mV
670.2ps   8.831mV    32.16mV    2.086mV
1.419ns   3.309mV    4.36mV     0V
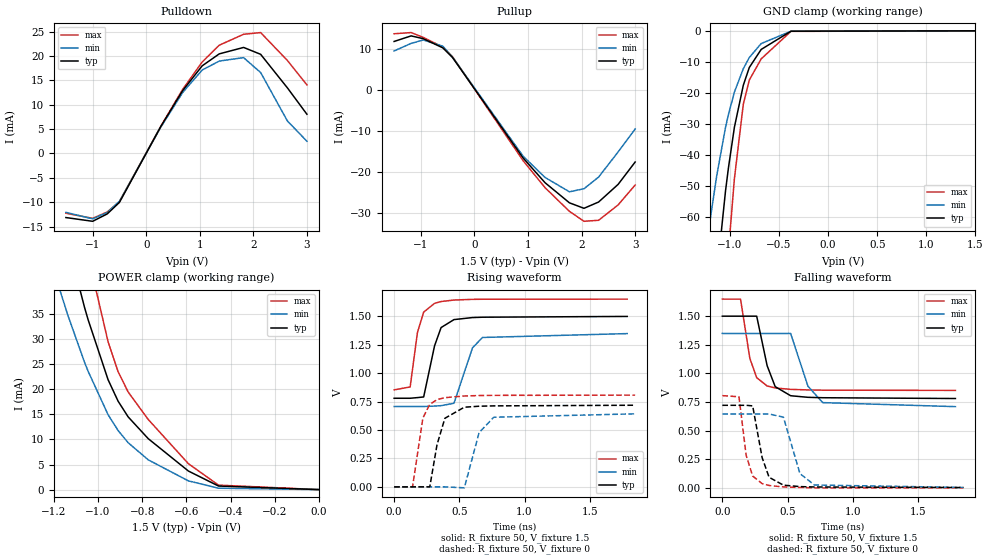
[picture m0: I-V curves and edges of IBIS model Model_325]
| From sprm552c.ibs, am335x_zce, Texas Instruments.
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| Model based on original model for BCSHTLTCSCDVPBFZ_SSDHV
|   Sub model SR00_7MA_10PER_1P5
[model]   Model_325
|[Description]  [1.5V-3-STATE-NOTERM-SR00:7MA, IND, 10%]
|   Fastest slew rate (SR[1:0] = "00"), 1.14 * RExt = 0.875 * Iout
|   (I[2:0] = "010"), 7mA nominal with Rext = 50R,ODT off (ODT[1:0]
|   = "00") CMOS mode,Industrial temperature range (-40C to 125C,
|   25C nominal),10% power supply tolerance
|[Input Load]   NOTERM
|[Output Drive] SR00:7MA
|Voltage   1.5V
|Mode   3-STATE
Model_type   3-state
Polarity   Non-Inverting
Enable   Active-Low
Cref =  15pF
Rref =  100.0000M
Vref =  0V
Vmeas =  0.75
C_comp   1.865048p   1.676829p   1.989968p
[Temperature Range]   25   125   -40
[Voltage Range]   1.5   1.35   1.65
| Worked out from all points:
|   slope of the pulldown table from 0 to 0.225 V, typ, clamps not added: 48.9 ohm
|   slope of the pullup table from 0 to 0.225 V, typ, clamps not added: 51.5 ohm
|   GND clamp passes 1 mA (typ) near -0.49 V on its own axis
|   POWER clamp passes 1 mA (typ) near -0.47 V on its own axis
|   rising waveform, R_fixture 50, V_fixture 1.5: 20-80 % time 76.7ps typ, 106ps min, 64.3ps max; typ from 0.779 V to 1.5 V
|   rising waveform, R_fixture 50, V_fixture 0: 20-80 % time 76.9ps typ, 91.4ps min, 69.2ps max; typ from 0 V to 0.717 V
|   falling waveform, R_fixture 50, V_fixture 1.5: 20-80 % time 90.3ps typ, 114ps min, 77.3ps max; typ from 1.5 V to 0.781 V
|   falling waveform, R_fixture 50, V_fixture 0: 20-80 % time 68.7ps typ, 90.4ps min, 61.1ps max; typ from 0.721 V to 0.003 V
[POWER_clamp]
-1.5V     126mA      88.79mA    168.7mA
-1.242V   69.8mA     49.45mA    94.34mA
-1.136V   49.16mA    34.72mA    67.51mA
-1.061V   36.35mA    25.4mA     50.03mA
-1.045V   33.92mA    23.63mA    46.66mA
-954.5mV  21.93mA    14.95mA    29.5mA
-909.1mV  17.64mA    11.79mA    23.52mA
-863.6mV  14.51mA    9.351mA    19.47mA
-772.7mV  10.16mA    5.94mA     13.99mA
-590.9mV  3.705mA    1.741mA    5.166mA
-454.5mV  710.5uA    279.1uA    892.1uA
0V        1.424nA    14.34nA    3.127nA
[Pulldown]
-1.5V     -13.15mA   -12.08mA   -12.27mA
-1V       -13.92mA   -13.42mA   -13.31mA
-727.3mV  -12.4mA    -12.1mA    -12mA
-500mV    -10.04mA   -9.816mA   -9.874mA
272.7mV   5.543mA    5.395mA    5.589mA
681.8mV   12.92mA    12.52mA    13.17mA
1.045V    17.98mA    17.12mA    18.77mA
1.364V    20.43mA    18.95mA    22.21mA
1.818V    21.75mA    19.66mA    24.45mA
2.136V    20.34mA    16.6mA     24.8mA
2.636V    13.45mA    6.663mA    19.07mA
3V        8.041mA    2.506mA    14.06mA
[Pullup]
-1.5V     11.89mA    9.575mA    13.77mA
-1.182V   13.25mA    11.42mA    14.06mA
-954.5mV  12.56mA    12.25mA    12.88mA
-590.9mV  10.33mA    10.73mA    10.53mA
-409.1mV  7.967mA    8.059mA    8.155mA
909.1mV   -16.57mA   -16.13mA   -17.23mA
1.318V    -22.59mA   -21.31mA   -23.8mA
1.773V    -27.5mA    -24.81mA   -29.58mA
2.045V    -28.84mA   -24.06mA   -32.01mA
2.318V    -27.3mA    -21.21mA   -31.76mA
2.682V    -23mA      -15.08mA   -28.01mA
3V        -17.54mA   -9.488mA   -23.16mA
[GND_clamp]
-1.5V     -219.3mA   -131.6mA   -364.3mA
-1.288V   -134.4mA   -79.74mA   -225.6mA
-1.258V   -122.9mA   -72.77mA   -206.3mA
-1.136V   -79.27mA   -46.88mA   -132.4mA
-1.045V   -51.5mA    -31.06mA   -84.11mA
-1.015V   -44.02mA   -26.9mA    -70.91mA
-954.5mV  -31.01mA   -19.7mA    -47.55mA
-863.6mV  -17.48mA   -12.16mA   -23.55mA
-803mV    -11.81mA   -8.597mA   -15.85mA
-681.8mV  -5.986mA   -4.096mA   -9.026mA
-378.8mV  -126.2uA   -131.8uA   -179.7uA
1.5V      1.424nA    207.1nA    1.498nA
[Ramp]
dV/dt_f 0.44135505/91.219022p 0.39651504/0.11390669n  0.4850437/77.4631p
dV/dt_r 0.44086081/78.148535p 0.40003107/92.379656p 0.48974152/69.281267p
R_load = 50
[Rising Waveform]
R_fixture = 50
V_fixture = 1.5
V_fixture_min = 1.35
V_fixture_max = 1.65
0s        778.7mV    706.2mV    852.4mV
123ps     778.7mV    706.2mV    878.2mV
178.9ps   784.5mV    706.2mV    1.357V
226.6ps   790.1mV    706.2mV    1.536V
310.2ps   1.24V      710.1mV    1.613V
360.1ps   1.4V       713.6mV    1.629V
459ps     1.47V      734.7mV    1.642V
601ps     1.488V     1.222V     1.648V
677.8ps   1.491V     1.313V     1.649V
1.787ns   1.498V     1.347V     1.65V
[Rising Waveform]
R_fixture = 50
V_fixture = 0
V_fixture_min = 0
V_fixture_max = 0
0s        0V         0V         0V
141.4ps   0V         0V         0V
220.6ps   0V         0V         605.6mV
273.4ps   0V         0V         725.1mV
329.1ps   371mV      0V         766.7mV
389.3ps   602.9mV    0V         783.9mV
538.3ps   700.1mV    -8.833mV   798.6mV
651.7ps   708.7mV    476.9mV    802.5mV
763.8ps   711.7mV    611.8mV    804.3mV
1.848ns   717.4mV    641.8mV    806.2mV
[Falling Waveform]
R_fixture = 50
V_fixture = 1.5
V_fixture_min = 1.35
V_fixture_max = 1.65
0s        1.5V       1.349V     1.649V
139.5ps   1.5V       1.349V     1.649V
210.7ps   1.5V       1.349V     1.132V
263.3ps   1.5V       1.349V     963mV
343.5ps   1.067V     1.349V     890.1mV
405.2ps   884.4mV    1.349V     872.9mV
523.6ps   805mV      1.349V     860.5mV
656.4ps   791.1mV    888mV      855.7mV
769.6ps   787.5mV    744.8mV    853.7mV
1.787ns   780.6mV    709.7mV    851.4mV
[Falling Waveform]
R_fixture = 50
V_fixture = 0
V_fixture_min = 0
V_fixture_max = 0
0s        721.3mV    645.5mV    805.8mV
127.6ps   721.3mV    645.5mV    795.8mV
182.4ps   721.3mV    645.5mV    284.8mV
232.5ps   716.3mV    645.5mV    103.2mV
304.7ps   265.7mV    645.5mV    37.15mV
358.3ps   92.4mV     645.5mV    20.63mV
468.1ps   23.79mV    618mV      8.08mV
595ps     10.87mV    124.9mV    3.563mV
705.8ps   7.76mV     25.06mV    0V
1.848ns   2.842mV    3.594mV    0V
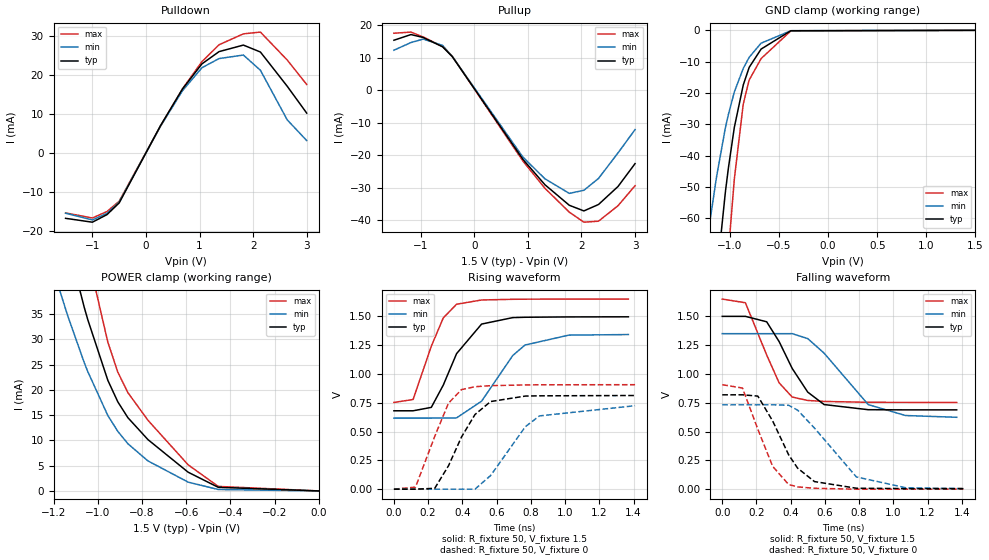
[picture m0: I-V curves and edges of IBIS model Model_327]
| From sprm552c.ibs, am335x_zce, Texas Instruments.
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| Model based on original model for BCSHTLTCSCDVPBFZ_SSDHV
|   Sub model SR01_9MA_10PER_1P5
[model]   Model_327
|[Description]  [1.5V-3-STATE-NOTERM-SR01:9MA, IND, 10%]
|   Slow slew rate (SR[1:0] = "01"), 0.88 * RExt = 1.125 * Iout
|   (I[2:0] = "100"), 9mA nominal with Rext = 50R,ODT off (ODT[1:0]
|   = "00") CMOS mode,Industrial temperature range (-40C to 125C,
|   25C nominal),10% power supply tolerance
|[Input Load]   NOTERM
|[Output Drive] SR01:9MA
|Voltage   1.5V
|Mode   3-STATE
Model_type   3-state
Polarity   Non-Inverting
Enable   Active-Low
Cref =  15pF
Rref =  100.0000M
Vref =  0V
Vmeas =  0.75
C_comp   1.865048p   1.676829p   1.989968p
[Temperature Range]   25   125   -40
[Voltage Range]   1.5   1.35   1.65
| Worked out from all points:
|   slope of the pulldown table from 0 to 0.225 V, typ, clamps not added: 38.4 ohm
|   slope of the pullup table from 0 to 0.225 V, typ, clamps not added: 40.1 ohm
|   GND clamp passes 1 mA (typ) near -0.49 V on its own axis
|   POWER clamp passes 1 mA (typ) near -0.47 V on its own axis
|   rising waveform, R_fixture 50, V_fixture 1.5: 20-80 % time 159ps typ, 207ps min, 129ps max; typ from 0.68 V to 1.5 V
|   rising waveform, R_fixture 50, V_fixture 0: 20-80 % time 170ps typ, 214ps min, 135ps max; typ from 0 V to 0.813 V
|   falling waveform, R_fixture 50, V_fixture 1.5: 20-80 % time 183ps typ, 239ps min, 146ps max; typ from 1.5 V to 0.688 V
|   falling waveform, R_fixture 50, V_fixture 0: 20-80 % time 176ps typ, 234ps min, 141ps max; typ from 0.818 V to 0.005 V
[POWER_clamp]
-1.5V     126mA      88.79mA    168.7mA
-1.242V   69.8mA     49.45mA    94.34mA
-1.136V   49.16mA    34.72mA    67.51mA
-1.061V   36.35mA    25.4mA     50.03mA
-1.045V   33.92mA    23.63mA    46.66mA
-954.5mV  21.93mA    14.95mA    29.5mA
-909.1mV  17.64mA    11.79mA    23.52mA
-863.6mV  14.51mA    9.351mA    19.47mA
-772.7mV  10.16mA    5.94mA     13.99mA
-590.9mV  3.705mA    1.741mA    5.166mA
-454.5mV  710.5uA    279.1uA    892.1uA
0V        1.424nA    14.34nA    3.127nA
[Pulldown]
-1.5V     -16.73mA   -15.43mA   -15.34mA
-1V       -17.72mA   -17.14mA   -16.64mA
-727.3mV  -15.78mA   -15.46mA   -14.99mA
-500mV    -12.78mA   -12.54mA   -12.34mA
272.7mV   7.051mA    6.89mA     6.983mA
681.8mV   16.43mA    15.99mA    16.46mA
1.045V    22.87mA    21.88mA    23.45mA
1.364V    26mA       24.22mA    27.76mA
1.818V    27.68mA    25.13mA    30.56mA
2.136V    25.9mA     21.22mA    31.01mA
2.636V    17.13mA    8.517mA    23.85mA
3V        10.24mA    3.203mA    17.58mA
[Pullup]
-1.5V     15.3mA     12.24mA    17.45mA
-1.182V   17.04mA    14.59mA    17.8mA
-954.5mV  16.15mA    15.65mA    16.31mA
-590.9mV  13.28mA    13.71mA    13.34mA
-409.1mV  10.24mA    10.29mA    10.33mA
909.1mV   -21.29mA   -20.6mA    -21.82mA
1.318V    -29.04mA   -27.22mA   -30.13mA
1.773V    -35.35mA   -31.7mA    -37.46mA
2.045V    -37.08mA   -30.75mA   -40.54mA
2.318V    -35.11mA   -27.11mA   -40.23mA
2.682V    -29.59mA   -19.28mA   -35.49mA
3V        -22.57mA   -12.13mA   -29.35mA
[GND_clamp]
-1.5V     -219.3mA   -131.6mA   -364.3mA
-1.288V   -134.4mA   -79.74mA   -225.6mA
-1.258V   -122.9mA   -72.77mA   -206.3mA
-1.136V   -79.27mA   -46.88mA   -132.4mA
-1.045V   -51.5mA    -31.06mA   -84.11mA
-1.015V   -44.02mA   -26.9mA    -70.91mA
-954.5mV  -31.01mA   -19.7mA    -47.55mA
-863.6mV  -17.48mA   -12.16mA   -23.55mA
-803mV    -11.81mA   -8.597mA   -15.85mA
-681.8mV  -5.986mA   -4.096mA   -9.026mA
-378.8mV  -126.2uA   -131.8uA   -179.7uA
1.5V      1.424nA    207.1nA    1.498nA
[Ramp]
dV/dt_f 0.49355403/0.18678189n 0.44115839/0.24246319n 0.54007066/0.14579603n
dV/dt_r 0.49296506/0.17269892n  0.4412097/0.21805424n 0.54591176/0.13525562n
R_load = 50
[Rising Waveform]
R_fixture = 50
V_fixture = 1.5
V_fixture_min = 1.35
V_fixture_max = 1.65
0s        680.3mV    616.8mV    752.8mV
112.1ps   680.3mV    616.8mV    778.1mV
218.5ps   710mV      616.8mV    1.241V
288.3ps   902.8mV    617.6mV    1.486V
366ps     1.176V     618.6mV    1.605V
512.3ps   1.433V     763.7mV    1.642V
694.4ps   1.489V     1.16V      1.648V
765.9ps   1.492V     1.251V     1.649V
1.022ns   1.495V     1.337V     1.65V
1.37ns    1.496V     1.342V     1.65V
[Rising Waveform]
R_fixture = 50
V_fixture = 0
V_fixture_min = 0
V_fixture_max = 0
0s        0V         0V         0V
126.3ps   0V         0V         17.87mV
238.5ps   7.502mV    0V         458.3mV
319ps     203.2mV    0V         746.8mV
395ps     453mV      0V         864.3mV
473.7ps   647.9mV    0V         889.3mV
565ps     760.5mV    118.3mV    898.2mV
768ps     808.1mV    542.1mV    904.9mV
850.2ps   810.1mV    635.8mV    905.9mV
1.409ns   812.9mV    724.3mV    906.7mV
[Falling Waveform]
R_fixture = 50
V_fixture = 1.5
V_fixture_min = 1.35
V_fixture_max = 1.65
0s        1.499V     1.349V     1.649V
135.3ps   1.499V     1.349V     1.617V
259.5ps   1.452V     1.349V     1.164V
332.4ps   1.28V      1.349V     922.4mV
408.8ps   1.047V     1.349V     798.8mV
499.6ps   841.7mV    1.306V     769.5mV
595.1ps   734mV      1.18V      761.1mV
852.9ps   689.3mV    733.6mV    753.4mV
1.071ns   687.9mV    638.8mV    752.7mV
1.37ns    687.9mV    623.5mV    752.1mV
[Falling Waveform]
R_fixture = 50
V_fixture = 0
V_fixture_min = 0
V_fixture_max = 0
0s        818.5mV    731.7mV    906.4mV
118.3ps   818.5mV    731.7mV    876.9mV
207.9ps   807.3mV    731.7mV    520mV
294.8ps   591.1mV    731.7mV    197.6mV
387.9ps   298.1mV    727.7mV    40.25mV
440.4ps   182.3mV    685.6mV    19.64mV
538.9ps   65.83mV    529.8mV    7.569mV
783.6ps   8.101mV    106.2mV    0V
1.078ns   5.048mV    10.44mV    0V
1.409ns   5.048mV    4.745mV    0V
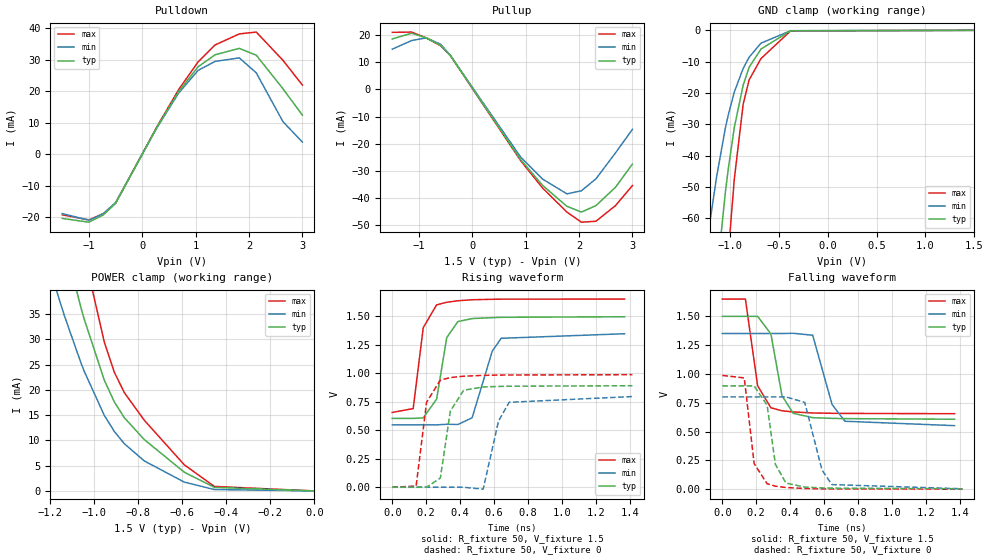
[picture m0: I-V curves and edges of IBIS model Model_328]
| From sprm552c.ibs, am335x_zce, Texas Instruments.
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| Model based on original model for BCSHTLTCSCDVPBFZ_SSDHV
|   Sub model SR00_11MA_10PER_1P5
[model]   Model_328
|[Description]  [1.5V-3-STATE-NOTERM-SR00:11MA, IND, 10%]
|   Fastest slew rate (SR[1:0] = "00"), 0.73 * RExt = 1.325 * Iout
|   (I[2:0] = "110"), 11mA nominal with Rext = 50R,ODT off (ODT[1:0]
|   = "00") CMOS mode,Industrial temperature range (-40C to 125C,
|   25C nominal),10% power supply tolerance
|[Input Load]   NOTERM
|[Output Drive] SR00:11MA
|Voltage   1.5V
|Mode   3-STATE
Model_type   3-state
Polarity   Non-Inverting
Enable   Active-Low
Cref =  15pF
Rref =  100.0000M
Vref =  0V
Vmeas =  0.75
C_comp   1.865048p   1.676829p   1.989968p
[Temperature Range]   25   125   -40
[Voltage Range]   1.5   1.35   1.65
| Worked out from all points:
|   slope of the pulldown table from 0 to 0.225 V, typ, clamps not added: 31.7 ohm
|   slope of the pullup table from 0 to 0.225 V, typ, clamps not added: 32.8 ohm
|   GND clamp passes 1 mA (typ) near -0.49 V on its own axis
|   POWER clamp passes 1 mA (typ) near -0.47 V on its own axis
|   rising waveform, R_fixture 50, V_fixture 1.5: 20-80 % time 59.9ps typ, 92.3ps min, 49.5ps max; typ from 0.603 V to 1.5 V
|   rising waveform, R_fixture 50, V_fixture 0: 20-80 % time 58.4ps typ, 72.8ps min, 52.9ps max; typ from 0 V to 0.89 V
|   falling waveform, R_fixture 50, V_fixture 1.5: 20-80 % time 68.6ps typ, 86.8ps min, 58.2ps max; typ from 1.5 V to 0.607 V
|   falling waveform, R_fixture 50, V_fixture 0: 20-80 % time 54.5ps typ, 75.8ps min, 47ps max; typ from 0.896 V to 0.003 V
[POWER_clamp]
-1.5V     126mA      88.79mA    168.7mA
-1.242V   69.8mA     49.45mA    94.34mA
-1.136V   49.16mA    34.72mA    67.51mA
-1.061V   36.35mA    25.4mA     50.03mA
-1.045V   33.92mA    23.63mA    46.66mA
-954.5mV  21.93mA    14.95mA    29.5mA
-909.1mV  17.64mA    11.79mA    23.52mA
-863.6mV  14.51mA    9.351mA    19.47mA
-772.7mV  10.16mA    5.94mA     13.99mA
-590.9mV  3.705mA    1.741mA    5.166mA
-454.5mV  710.5uA    279.1uA    892.1uA
0V        1.424nA    14.34nA    3.127nA
[Pulldown]
-1.5V     -20.32mA   -18.79mA   -19.18mA
-1V       -21.51mA   -20.87mA   -20.79mA
-727.3mV  -19.16mA   -18.81mA   -18.74mA
-500mV    -15.51mA   -15.26mA   -15.42mA
272.7mV   8.558mA    8.384mA    8.723mA
681.8mV   19.95mA    19.45mA    20.56mA
1.045V    27.76mA    26.62mA    29.3mA
1.364V    31.57mA    29.48mA    34.69mA
1.818V    33.61mA    30.59mA    38.2mA
2.136V    31.45mA    25.84mA    38.77mA
2.636V    20.81mA    10.37mA    29.82mA
3V        12.44mA    3.9mA      21.98mA
[Pullup]
-1.5V     18.7mA     14.9mA     21.12mA
-1.136V   20.8mA     18.1mA     21.22mA
-863.6mV  19.07mA    19.09mA    19.07mA
-590.9mV  16.22mA    16.68mA    16.14mA
-409.1mV  12.51mA    12.52mA    12.49mA
909.1mV   -26.01mA   -25.07mA   -26.4mA
1.318V    -35.47mA   -33.13mA   -36.46mA
1.773V    -43.2mA    -38.59mA   -45.33mA
2.045V    -45.32mA   -37.44mA   -49.06mA
2.318V    -42.92mA   -33.02mA   -48.71mA
2.682V    -36.18mA   -23.48mA   -42.98mA
3V        -27.6mA    -14.77mA   -35.54mA
[GND_clamp]
-1.5V     -219.3mA   -131.6mA   -364.3mA
-1.288V   -134.4mA   -79.74mA   -225.6mA
-1.258V   -122.9mA   -72.77mA   -206.3mA
-1.136V   -79.27mA   -46.88mA   -132.4mA
-1.045V   -51.5mA    -31.06mA   -84.11mA
-1.015V   -44.02mA   -26.9mA    -70.91mA
-954.5mV  -31.01mA   -19.7mA    -47.55mA
-863.6mV  -17.48mA   -12.16mA   -23.55mA
-803mV    -11.81mA   -8.597mA   -15.85mA
-681.8mV  -5.986mA   -4.096mA   -9.026mA
-378.8mV  -126.2uA   -131.8uA   -179.7uA
1.5V      1.424nA    207.1nA    1.498nA
[Ramp]
dV/dt_f 0.54960421/69.800026p 0.49497313/89.300742p 0.60548176/58.154275p
dV/dt_r 0.54895706/59.336589p 0.50010477/71.399866p 0.60111978/53.056326p
R_load = 50
[Rising Waveform]
R_fixture = 50
V_fixture = 1.5
V_fixture_min = 1.35
V_fixture_max = 1.65
0s        603.4mV    547mV      656mV
123.4ps   603.4mV    547mV      689.8mV
182.5ps   608.6mV    547mV      1.399V
261.4ps   772.4mV    547mV      1.599V
321.3ps   1.312V     552.4mV    1.622V
387.2ps   1.453V     550.5mV    1.635V
470.9ps   1.479V     609.2mV    1.644V
589.7ps   1.487V     1.193V     1.648V
642ps     1.49V      1.306V     1.649V
1.37ns    1.495V     1.346V     1.65V
[Rising Waveform]
R_fixture = 50
V_fixture = 0
V_fixture_min = 0
V_fixture_max = 0
0s        0V         0V         0V
140.7ps   0V         0V         10.72mV
202.2ps   0V         0V         745.4mV
283.5ps   80.81mV    0V         939.1mV
342.3ps   667.4mV    0V         961.9mV
420.9ps   850.2mV    0V         973.5mV
536ps     879.4mV    -16.75mV   980.9mV
626.6ps   883.9mV    580.2mV    983.5mV
689.1ps   885.6mV    744.9mV    984.3mV
1.416ns   890.3mV    795.2mV    987mV
[Falling Waveform]
R_fixture = 50
V_fixture = 1.5
V_fixture_min = 1.35
V_fixture_max = 1.65
0s        1.5V       1.351V     1.65V
136.3ps   1.5V       1.351V     1.65V
208.4ps   1.5V       1.351V     898.1mV
286.6ps   1.348V     1.351V     706.7mV
352.2ps   811.3mV    1.351V     680.2mV
418.3ps   658.3mV    1.353V     670.3mV
533.2ps   620.7mV    1.336V     661.4mV
647.6ps   614.3mV    734.5mV    658.5mV
723.4ps   612.4mV    589.5mV    657.5mV
1.37ns    606.7mV    551.3mV    655.1mV
[Falling Waveform]
R_fixture = 50
V_fixture = 0
V_fixture_min = 0
V_fixture_max = 0
0s        896.2mV    800.5mV    987.4mV
129.7ps   896.2mV    800.5mV    965.5mV
187.8ps   896.2mV    800.5mV    222.6mV
264.2ps   729.6mV    800.5mV    47.38mV
313.6ps   214.1mV    800.5mV    25.94mV
375.7ps   52.98mV    800.5mV    14.64mV
486.4ps   17.92mV    753mV      5.647mV
587.6ps   11.05mV    168.1mV    2.869mV
646.3ps   9.001mV    39.59mV    2.03mV
1.416ns   3.385mV    3.462mV    0V
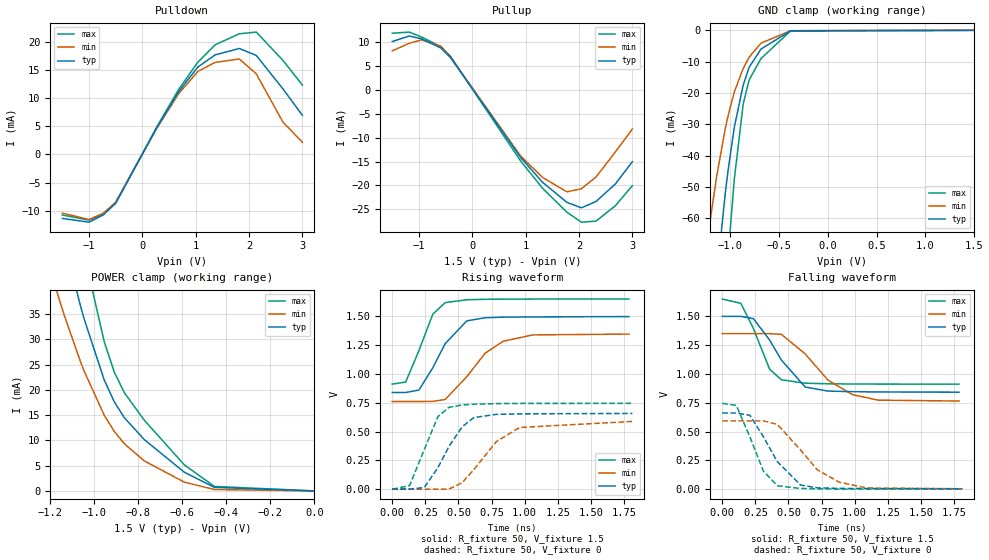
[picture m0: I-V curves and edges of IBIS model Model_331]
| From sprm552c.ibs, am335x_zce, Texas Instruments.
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| Model based on original model for BCSHTLTCSCDVPBFZ_SSDHV
|   Sub model SR01_6MA_10PER_1P5
[model]   Model_331
|[Description]  [1.5V-3-STATE-NOTERM-SR01:6MA, IND, 10%]
|   Slow slew rate (SR[1:0] = "01"), 1.33 * RExt = 0.750 * Iout
|   (I[2:0] = "001"), 6mA nominal with Rext = 50R,ODT off (ODT[1:0]
|   = "00") CMOS mode,Industrial temperature range (-40C to 125C,
|   25C nominal),10% power supply tolerance
|[Input Load]   NOTERM
|[Output Drive] SR01:6MA
|Voltage   1.5V
|Mode   3-STATE
Model_type   3-state
Polarity   Non-Inverting
Enable   Active-Low
Cref =  15pF
Rref =  100.0000M
Vref =  0V
Vmeas =  0.75
C_comp   1.865048p   1.676829p   1.989968p
[Temperature Range]   25   125   -40
[Voltage Range]   1.5   1.35   1.65
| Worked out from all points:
|   slope of the pulldown table from 0 to 0.225 V, typ, clamps not added: 56.6 ohm
|   slope of the pullup table from 0 to 0.225 V, typ, clamps not added: 60 ohm
|   GND clamp passes 1 mA (typ) near -0.49 V on its own axis
|   POWER clamp passes 1 mA (typ) near -0.47 V on its own axis
|   rising waveform, R_fixture 50, V_fixture 1.5: 20-80 % time 191ps typ, 251ps min, 142ps max; typ from 0.839 V to 1.5 V
|   rising waveform, R_fixture 50, V_fixture 0: 20-80 % time 199ps typ, 271ps min, 148ps max; typ from 0 V to 0.657 V
|   falling waveform, R_fixture 50, V_fixture 1.5: 20-80 % time 221ps typ, 295ps min, 155ps max; typ from 1.5 V to 0.841 V
|   falling waveform, R_fixture 50, V_fixture 0: 20-80 % time 208ps typ, 279ps min, 151ps max; typ from 0.661 V to 0.004 V
[POWER_clamp]
-1.5V     126mA      88.79mA    168.7mA
-1.242V   69.8mA     49.45mA    94.34mA
-1.136V   49.16mA    34.72mA    67.51mA
-1.061V   36.35mA    25.4mA     50.03mA
-1.045V   33.92mA    23.63mA    46.66mA
-954.5mV  21.93mA    14.95mA    29.5mA
-909.1mV  17.64mA    11.79mA    23.52mA
-863.6mV  14.51mA    9.351mA    19.47mA
-772.7mV  10.16mA    5.94mA     13.99mA
-590.9mV  3.705mA    1.741mA    5.166mA
-454.5mV  710.5uA    279.1uA    892.1uA
0V        1.424nA    14.34nA    3.127nA
[Pulldown]
-1.5V     -11.35mA   -10.4mA    -10.74mA
-1V       -12.02mA   -11.55mA   -11.65mA
-727.3mV  -10.71mA   -10.42mA   -10.5mA
-500mV    -8.674mA   -8.454mA   -8.641mA
272.7mV   4.789mA    4.647mA    4.892mA
681.8mV   11.16mA    10.78mA    11.53mA
1.045V    15.53mA    14.75mA    16.42mA
1.364V    17.65mA    16.32mA    19.44mA
1.818V    18.79mA    16.93mA    21.4mA
2.136V    17.56mA    14.29mA    21.7mA
2.636V    11.62mA    5.736mA    16.68mA
3V        6.943mA    2.158mA    12.3mA
[Pullup]
-1.5V     10.19mA    8.245mA    11.94mA
-1.182V   11.36mA    9.829mA    12.18mA
-954.5mV  10.77mA    10.55mA    11.16mA
-590.9mV  8.854mA    9.241mA    9.128mA
-409.1mV  6.831mA    6.942mA    7.07mA
909.1mV   -14.2mA    -13.89mA   -14.94mA
1.318V    -19.37mA   -18.35mA   -20.63mA
1.773V    -23.58mA   -21.37mA   -25.64mA
2.045V    -24.72mA   -20.72mA   -27.74mA
2.318V    -23.4mA    -18.26mA   -27.52mA
2.682V    -19.71mA   -12.98mA   -24.27mA
3V        -15.03mA   -8.169mA   -20.07mA
[GND_clamp]
-1.5V     -219.3mA   -131.6mA   -364.3mA
-1.288V   -134.4mA   -79.74mA   -225.6mA
-1.258V   -122.9mA   -72.77mA   -206.3mA
-1.136V   -79.27mA   -46.88mA   -132.4mA
-1.045V   -51.5mA    -31.06mA   -84.11mA
-1.015V   -44.02mA   -26.9mA    -70.91mA
-954.5mV  -31.01mA   -19.7mA    -47.55mA
-863.6mV  -17.48mA   -12.16mA   -23.55mA
-803mV    -11.81mA   -8.597mA   -15.85mA
-681.8mV  -5.986mA   -4.096mA   -9.026mA
-378.8mV  -126.2uA   -131.8uA   -179.7uA
1.5V      1.424nA    207.1nA    1.498nA
[Ramp]
dV/dt_f  0.3980673/0.223328n  0.35457321/0.29879311n 0.44382528/0.15478419n
dV/dt_r 0.39804757/0.20112959n 0.35696709/0.27503938n 0.44776071/0.14789001n
R_load = 50
[Rising Waveform]
R_fixture = 50
V_fixture = 1.5
V_fixture_min = 1.35
V_fixture_max = 1.65
0s        838.8mV    760.8mV    912.2mV
100.9ps   838.8mV    760.8mV    929.3mV
201.6ps   860.4mV    760.8mV    1.204V
306.1ps   1.054V     762.2mV    1.519V
399.4ps   1.263V     778.4mV    1.619V
563.2ps   1.461V     976.6mV    1.644V
702.6ps   1.488V     1.182V     1.648V
837.5ps   1.493V     1.284V     1.649V
1.062ns   1.495V     1.339V     1.65V
1.787ns   1.498V     1.346V     1.65V
[Rising Waveform]
R_fixture = 50
V_fixture = 0
V_fixture_min = 0
V_fixture_max = 0
0s        0V         0V         0V
131ps     0V         0V         30.93mV
241.6ps   14.4mV     0V         344.1mV
344.4ps   186.1mV    0V         629.9mV
427.3ps   369mV      0V         709.8mV
526.3ps   539.7mV    55.06mV    730.8mV
615.5ps   621.6mV    169.2mV    737.5mV
785.4ps   649.3mV    413.1mV    742.5mV
962.5ps   653.4mV    535.5mV    744.1mV
1.813ns   657.5mV    587.9mV    744.9mV
[Falling Waveform]
R_fixture = 50
V_fixture = 1.5
V_fixture_min = 1.35
V_fixture_max = 1.65
0s        1.499V     1.349V     1.649V
140.1ps   1.499V     1.349V     1.612V
235.1ps   1.479V     1.349V     1.393V
357.2ps   1.294V     1.349V     1.041V
446.4ps   1.12V      1.343V     948.5mV
626.3ps   885.7mV    1.173V     919.3mV
797.7ps   850.9mV    946.4mV    914mV
980.9ps   845.6mV    820.8mV    912.2mV
1.177ns   843.3mV    772mV      911.6mV
1.787ns   841mV      764.4mV    911.2mV
[Falling Waveform]
R_fixture = 50
V_fixture = 0
V_fixture_min = 0
V_fixture_max = 0
0s        660.6mV    592.5mV    744mV
105.9ps   660.6mV    592.5mV    726.9mV
208.3ps   640.8mV    592.5mV    453.8mV
310.3ps   455.3mV    592.5mV    157.2mV
415.7ps   238mV      561.9mV    29.75mV
591.8ps   35.41mV    338.5mV    6.018mV
718.4ps   11.42mV    167mV      2.76mV
882.7ps   6.805mV    60.85mV    0V
1.09ns    4.979mV    10.34mV    0V
1.813ns   3.911mV    3.318mV    0V
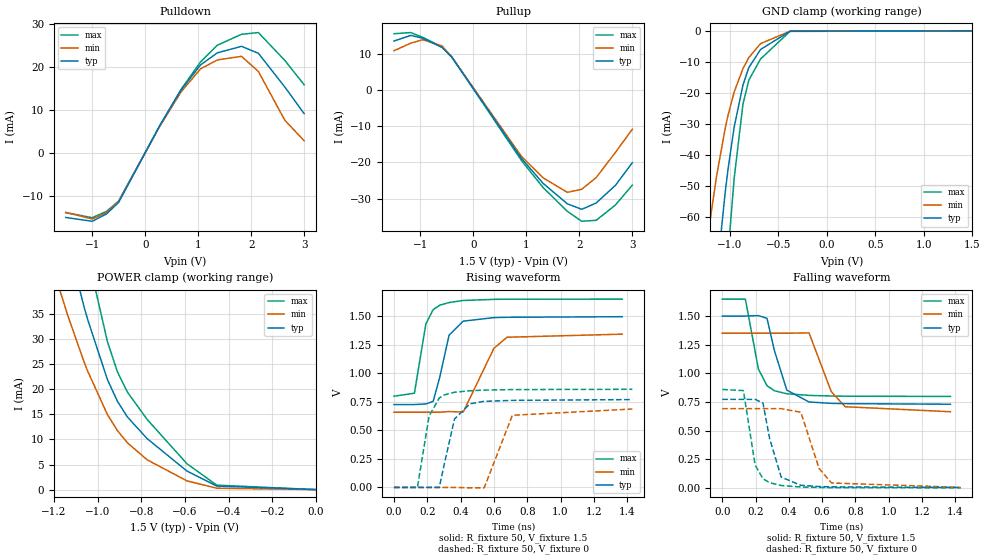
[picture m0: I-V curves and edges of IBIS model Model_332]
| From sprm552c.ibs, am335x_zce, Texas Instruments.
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| Model based on original model for BCSHTLTCSCDVPBFZ_SSDHV
|   Sub model SR00_8MA_10PER_1P5
[model]   Model_332
|[Description]  [1.5V-3-STATE-NOTERM-SR00:8MA, IND, 10%]
|   Fastest slew rate (SR[1:0] = "00"), 1.00 * RExt = 1.000 * Iout
|   (I[2:0] = "011"), 8mA nominal with Rext = 50R,ODT off (ODT[1:0]
|   = "00") CMOS mode,Industrial temperature range (-40C to 125C,
|   25C nominal),10% power supply tolerance
|[Input Load]   NOTERM
|[Output Drive] SR00:8MA
|Voltage   1.5V
|Mode   3-STATE
Model_type   3-state
Polarity   Non-Inverting
Enable   Active-Low
Cref =  15pF
Rref =  100.0000M
Vref =  0V
Vmeas =  0.75
C_comp   1.865048p   1.676829p   1.989968p
[Temperature Range]   25   125   -40
[Voltage Range]   1.5   1.35   1.65
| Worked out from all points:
|   slope of the pulldown table from 0 to 0.225 V, typ, clamps not added: 43 ohm
|   slope of the pullup table from 0 to 0.225 V, typ, clamps not added: 45 ohm
|   GND clamp passes 1 mA (typ) near -0.49 V on its own axis
|   POWER clamp passes 1 mA (typ) near -0.47 V on its own axis
|   rising waveform, R_fixture 50, V_fixture 1.5: 20-80 % time 71ps typ, 101ps min, 60.1ps max; typ from 0.726 V to 1.5 V
|   rising waveform, R_fixture 50, V_fixture 0: 20-80 % time 71.5ps typ, 88.3ps min, 64.2ps max; typ from 0 V to 0.77 V
|   falling waveform, R_fixture 50, V_fixture 1.5: 20-80 % time 83.4ps typ, 104ps min, 71.9ps max; typ from 1.5 V to 0.731 V
|   falling waveform, R_fixture 50, V_fixture 0: 20-80 % time 64.5ps typ, 85.2ps min, 57.3ps max; typ from 0.773 V to 0.003 V
[POWER_clamp]
-1.5V     126mA      88.79mA    168.7mA
-1.242V   69.8mA     49.45mA    94.34mA
-1.136V   49.16mA    34.72mA    67.51mA
-1.061V   36.35mA    25.4mA     50.03mA
-1.045V   33.92mA    23.63mA    46.66mA
-954.5mV  21.93mA    14.95mA    29.5mA
-909.1mV  17.64mA    11.79mA    23.52mA
-863.6mV  14.51mA    9.351mA    19.47mA
-772.7mV  10.16mA    5.94mA     13.99mA
-590.9mV  3.705mA    1.741mA    5.166mA
-454.5mV  710.5uA    279.1uA    892.1uA
0V        1.424nA    14.34nA    3.127nA
[Pulldown]
-1.5V     -14.94mA   -13.76mA   -13.81mA
-1V       -15.82mA   -15.28mA   -14.98mA
-727.3mV  -14.09mA   -13.78mA   -13.5mA
-500mV    -11.41mA   -11.18mA   -11.11mA
272.7mV   6.297mA    6.143mA    6.286mA
681.8mV   14.68mA    14.25mA    14.82mA
1.045V    20.42mA    19.5mA     21.11mA
1.364V    23.22mA    21.58mA    24.99mA
1.818V    24.72mA    22.4mA     27.51mA
2.136V    23.12mA    18.91mA    27.91mA
2.636V    15.29mA    7.59mA     21.46mA
3V        9.139mA    2.855mA    15.82mA
[Pullup]
-1.5V     13.59mA    10.91mA    15.61mA
-1.182V   15.15mA    13mA       15.93mA
-954.5mV  14.35mA    13.95mA    14.59mA
-590.9mV  11.8mA     12.22mA    11.93mA
-409.1mV  9.103mA    9.176mA    9.241mA
909.1mV   -18.93mA   -18.37mA   -19.52mA
1.318V    -25.81mA   -24.27mA   -26.97mA
1.773V    -31.43mA   -28.26mA   -33.52mA
2.045V    -32.96mA   -27.41mA   -36.27mA
2.318V    -31.2mA    -24.16mA   -35.99mA
2.682V    -26.3mA    -17.18mA   -31.75mA
3V        -20.05mA   -10.81mA   -26.25mA
[GND_clamp]
-1.5V     -219.3mA   -131.6mA   -364.3mA
-1.288V   -134.4mA   -79.74mA   -225.6mA
-1.258V   -122.9mA   -72.77mA   -206.3mA
-1.136V   -79.27mA   -46.88mA   -132.4mA
-1.045V   -51.5mA    -31.06mA   -84.11mA
-1.015V   -44.02mA   -26.9mA    -70.91mA
-954.5mV  -31.01mA   -19.7mA    -47.55mA
-863.6mV  -17.48mA   -12.16mA   -23.55mA
-803mV    -11.81mA   -8.597mA   -15.85mA
-681.8mV  -5.986mA   -4.096mA   -9.026mA
-378.8mV  -126.2uA   -131.8uA   -179.7uA
1.5V      1.424nA    207.1nA    1.498nA
[Ramp]
dV/dt_f 0.47328777/84.563802p 0.42559792/0.10617662n  0.5173857/72.159086p
dV/dt_r 0.47258236/72.258465p 0.42918405/85.891771p 0.52263201/64.390552p
R_load = 50
[Rising Waveform]
R_fixture = 50
V_fixture = 1.5
V_fixture_min = 1.35
V_fixture_max = 1.65
0s        726.3mV    658.6mV    799.5mV
122.6ps   726.3mV    658.6mV    825.6mV
191.6ps   731.3mV    658.6mV    1.433V
235.3ps   754.5mV    658.6mV    1.558V
274.8ps   965.7mV    658.6mV    1.597V
330.5ps   1.333V     665.1mV    1.62V
415.7ps   1.457V     660.2mV    1.638V
600ps     1.488V     1.219V     1.648V
678.7ps   1.491V     1.316V     1.649V
1.37ns    1.496V     1.343V     1.65V
[Rising Waveform]
R_fixture = 50
V_fixture = 0
V_fixture_min = 0
V_fixture_max = 0
0s        0V         0V         0V
140.6ps   0V         0V         0V
210.9ps   0V         0V         625.9mV
271.9ps   0V         0V         783.9mV
305ps     223.5mV    0V         812mV
363.3ps   599mV      0V         833.9mV
455.8ps   733mV      -3.802mV   847.3mV
541.7ps   754.4mV    -2.849mV   852.8mV
710.6ps   763mV      632.1mV    857.4mV
1.431ns   769.7mV    687.1mV    859.9mV
[Falling Waveform]
R_fixture = 50
V_fixture = 1.5
V_fixture_min = 1.35
V_fixture_max = 1.65
0s        1.501V     1.351V     1.649V
139ps     1.501V     1.351V     1.649V
217.4ps   1.505V     1.351V     1.038V
268.9ps   1.481V     1.351V     892.9mV
313.2ps   1.2V       1.351V     848.9mV
387.8ps   854.2mV    1.351V     822mV
521.2ps   750.4mV    1.354V     807.9mV
654.6ps   738.3mV    841mV      802.6mV
738.3ps   735.7mV    708.9mV    800.8mV
1.37ns    730.7mV    665mV      798.7mV
[Falling Waveform]
R_fixture = 50
V_fixture = 0
V_fixture_min = 0
V_fixture_max = 0
0s        773.4mV    692mV      859.9mV
127.3ps   773.4mV    692mV      849.8mV
197.7ps   773.4mV    692mV      198.5mV
244.6ps   741.2mV    692mV      80.05mV
284.2ps   433.5mV    692mV      45.3mV
354.2ps   94.19mV    692mV      20.4mV
472ps     22.22mV    660.8mV    7.419mV
581.5ps   11.4mV     169.9mV    3.642mV
655.9ps   8.663mV    42.59mV    2.367mV
1.431ns   3.433mV    4.132mV    0V
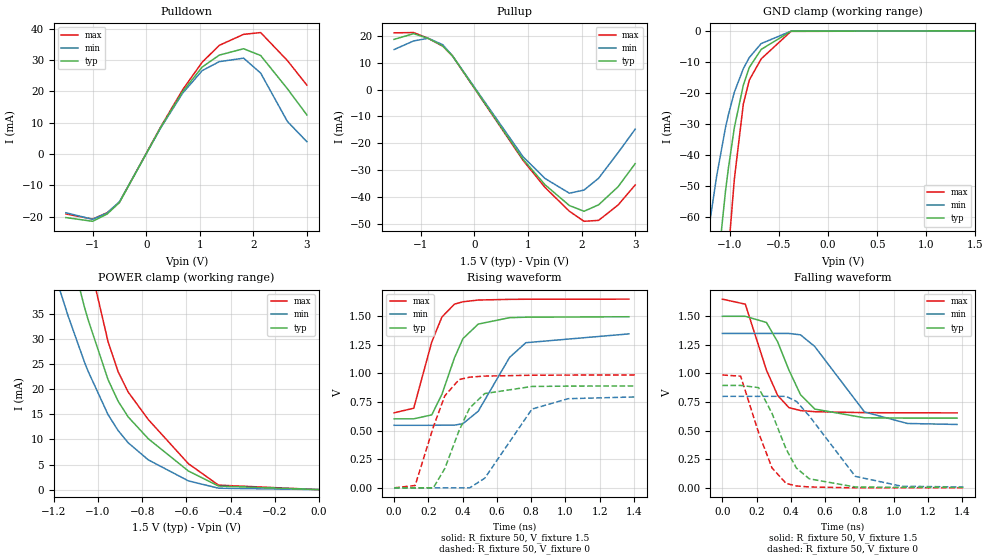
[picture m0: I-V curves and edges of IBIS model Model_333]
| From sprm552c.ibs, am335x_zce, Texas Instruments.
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| Model based on original model for BCSHTLTCSCDVPBFZ_SSDHV
|   Sub model SR01_11MA_10PER_1P5
[model]   Model_333
|[Description]  [1.5V-3-STATE-NOTERM-SR01:11MA, IND, 10%]
|   Slow slew rate (SR[1:0] = "01"), 0.73 * RExt = 1.325 * Iout
|   (I[2:0] = "110"), 11mA nominal with Rext = 50R,ODT off (ODT[1:0]
|   = "00") CMOS mode,Industrial temperature range (-40C to 125C,
|   25C nominal),10% power supply tolerance
|[Input Load]   NOTERM
|[Output Drive] SR01:11MA
|Voltage   1.5V
|Mode   3-STATE
Model_type   3-state
Polarity   Non-Inverting
Enable   Active-Low
Cref =  15pF
Rref =  100.0000M
Vref =  0V
Vmeas =  0.75
C_comp   1.865048p   1.676829p   1.989968p
[Temperature Range]   25   125   -40
[Voltage Range]   1.5   1.35   1.65
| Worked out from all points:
|   slope of the pulldown table from 0 to 0.225 V, typ, clamps not added: 31.7 ohm
|   slope of the pullup table from 0 to 0.225 V, typ, clamps not added: 32.8 ohm
|   GND clamp passes 1 mA (typ) near -0.49 V on its own axis
|   POWER clamp passes 1 mA (typ) near -0.47 V on its own axis
|   rising waveform, R_fixture 50, V_fixture 1.5: 20-80 % time 139ps typ, 193ps min, 115ps max; typ from 0.603 V to 1.5 V
|   rising waveform, R_fixture 50, V_fixture 0: 20-80 % time 149ps typ, 199ps min, 123ps max; typ from 0 V to 0.891 V
|   falling waveform, R_fixture 50, V_fixture 1.5: 20-80 % time 162ps typ, 225ps min, 129ps max; typ from 1.5 V to 0.609 V
|   falling waveform, R_fixture 50, V_fixture 0: 20-80 % time 156ps typ, 224ps min, 127ps max; typ from 0.895 V to 0.004 V
[POWER_clamp]
-1.5V     126mA      88.79mA    168.7mA
-1.242V   69.8mA     49.45mA    94.34mA
-1.136V   49.16mA    34.72mA    67.51mA
-1.061V   36.35mA    25.4mA     50.03mA
-1.045V   33.92mA    23.63mA    46.66mA
-954.5mV  21.93mA    14.95mA    29.5mA
-909.1mV  17.64mA    11.79mA    23.52mA
-863.6mV  14.51mA    9.351mA    19.47mA
-772.7mV  10.16mA    5.94mA     13.99mA
-590.9mV  3.705mA    1.741mA    5.166mA
-454.5mV  710.5uA    279.1uA    892.1uA
0V        1.424nA    14.34nA    3.127nA
[Pulldown]
-1.5V     -20.32mA   -18.79mA   -19.18mA
-1V       -21.51mA   -20.87mA   -20.79mA
-727.3mV  -19.16mA   -18.81mA   -18.74mA
-500mV    -15.51mA   -15.26mA   -15.42mA
272.7mV   8.558mA    8.384mA    8.723mA
681.8mV   19.95mA    19.45mA    20.56mA
1.045V    27.76mA    26.62mA    29.3mA
1.364V    31.57mA    29.48mA    34.69mA
1.818V    33.61mA    30.59mA    38.2mA
2.136V    31.45mA    25.84mA    38.77mA
2.636V    20.81mA    10.37mA    29.82mA
3V        12.44mA    3.9mA      21.98mA
[Pullup]
-1.5V     18.7mA     14.9mA     21.12mA
-1.136V   20.8mA     18.1mA     21.22mA
-863.6mV  19.07mA    19.09mA    19.07mA
-590.9mV  16.22mA    16.68mA    16.14mA
-409.1mV  12.51mA    12.52mA    12.49mA
909.1mV   -26.01mA   -25.07mA   -26.4mA
1.318V    -35.47mA   -33.13mA   -36.46mA
1.773V    -43.2mA    -38.59mA   -45.33mA
2.045V    -45.32mA   -37.44mA   -49.06mA
2.318V    -42.92mA   -33.02mA   -48.71mA
2.682V    -36.18mA   -23.48mA   -42.98mA
3V        -27.6mA    -14.77mA   -35.54mA
[GND_clamp]
-1.5V     -219.3mA   -131.6mA   -364.3mA
-1.288V   -134.4mA   -79.74mA   -225.6mA
-1.258V   -122.9mA   -72.77mA   -206.3mA
-1.136V   -79.27mA   -46.88mA   -132.4mA
-1.045V   -51.5mA    -31.06mA   -84.11mA
-1.015V   -44.02mA   -26.9mA    -70.91mA
-954.5mV  -31.01mA   -19.7mA    -47.55mA
-863.6mV  -17.48mA   -12.16mA   -23.55mA
-803mV    -11.81mA   -8.597mA   -15.85mA
-681.8mV  -5.986mA   -4.096mA   -9.026mA
-378.8mV  -126.2uA   -131.8uA   -179.7uA
1.5V      1.424nA    207.1nA    1.498nA
[Ramp]
dV/dt_f 0.53998522/0.16495045n 0.48373431/0.22816167n 0.59833807/0.12954874n
dV/dt_r 0.53937068/0.15079153n 0.48315294/0.2006678n 0.59411416/0.12307069n
R_load = 50
[Rising Waveform]
R_fixture = 50
V_fixture = 1.5
V_fixture_min = 1.35
V_fixture_max = 1.65
0s        603.4mV    547.1mV    656.1mV
114.5ps   603.4mV    547.1mV    696.3mV
219.7ps   638mV      547.1mV    1.275V
279.2ps   818.5mV    547.9mV    1.494V
352.1ps   1.136V     548.2mV    1.606V
402ps     1.305V     561.3mV    1.627V
491.2ps   1.432V     670.6mV    1.642V
674.2ps   1.488V     1.141V     1.648V
769.1ps   1.492V     1.269V     1.649V
1.37ns    1.496V     1.346V     1.65V
[Rising Waveform]
R_fixture = 50
V_fixture = 0
V_fixture_min = 0
V_fixture_max = 0
0s        0V         0V         0V
122.8ps   0V         0V         20.82mV
228.9ps   0V         0V         531.7mV
295.9ps   169mV      0V         804.8mV
378.9ps   499.3mV    0V         946mV
441.2ps   699.4mV    0V         967.8mV
529.3ps   824.5mV    84.74mV    977.2mV
804.9ps   886.5mV    689.1mV    984.7mV
1.016ns   889.4mV    779.6mV    986mV
1.407ns   891.1mV    794.9mV    987mV
[Falling Waveform]
R_fixture = 50
V_fixture = 1.5
V_fixture_min = 1.35
V_fixture_max = 1.65
0s        1.499V     1.349V     1.649V
134ps     1.499V     1.349V     1.605V
257.3ps   1.445V     1.349V     1.029V
323ps     1.275V     1.349V     807.1mV
388.7ps   1.029V     1.349V     701.1mV
456.3ps   814.3mV    1.337V     675.4mV
539.4ps   688.4mV    1.235V     665.4mV
829.8ps   612mV      663mV      657.1mV
1.08ns    609.4mV    562.6mV    655.5mV
1.37ns    609.4mV    553.9mV    655.2mV
[Falling Waveform]
R_fixture = 50
V_fixture = 0
V_fixture_min = 0
V_fixture_max = 0
0s        894.9mV    799.6mV    986.2mV
106.9ps   894.9mV    799.6mV    975.6mV
211.4ps   875.9mV    799.6mV    483.1mV
289.8ps   651.1mV    799.6mV    174.1mV
372.6ps   337.6mV    799.6mV    38.47mV
432.5ps   172.6mV    755.2mV    16.5mV
507.6ps   79.07mV    628.1mV    7.759mV
776ps     7.507mV    100.6mV    0V
1.047ns   4.471mV    13.97mV    0V
1.407ns   4.471mV    7.796mV    0V
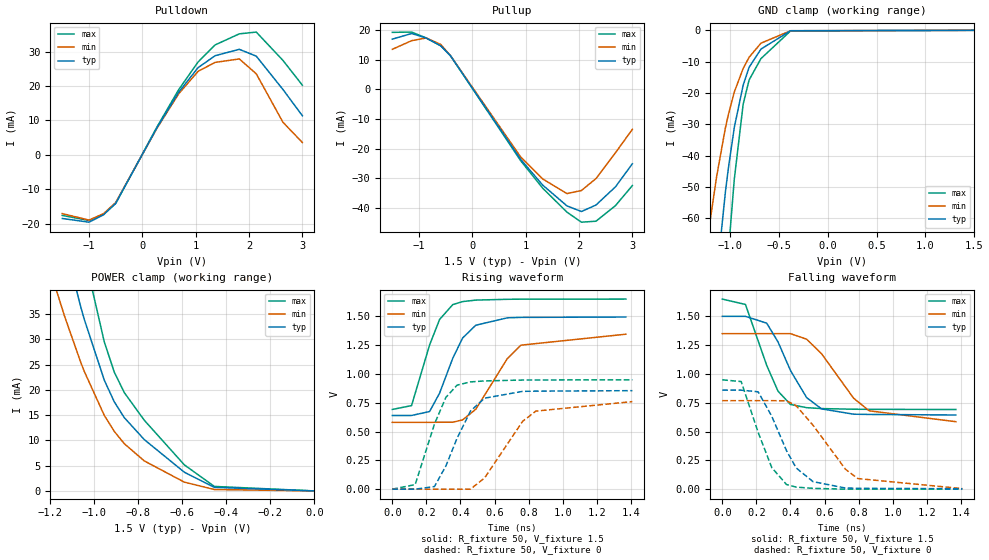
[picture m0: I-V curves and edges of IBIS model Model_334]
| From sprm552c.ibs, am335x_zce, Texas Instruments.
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| Model based on original model for BCSHTLTCSCDVPBFZ_SSDHV
|   Sub model SR01_10MA_10PER_1P5
[model]   Model_334
|[Description]  [1.5V-3-STATE-NOTERM-SR01:10MA, IND, 10%]
|   Slow slew rate (SR[1:0] = "01"), 0.80 * RExt = 1.250 * Iout
|   (I[2:0] = "101"), 10mA nominal with Rext = 50R,ODT off (ODT[1:0]
|   = "00") CMOS mode,Industrial temperature range (-40C to 125C,
|   25C nominal),10% power supply tolerance
|[Input Load]   NOTERM
|[Output Drive] SR01:10MA
|Voltage   1.5V
|Mode   3-STATE
Model_type   3-state
Polarity   Non-Inverting
Enable   Active-Low
Cref =  15pF
Rref =  100.0000M
Vref =  0V
Vmeas =  0.75
C_comp   1.865048p   1.676829p   1.989968p
[Temperature Range]   25   125   -40
[Voltage Range]   1.5   1.35   1.65
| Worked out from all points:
|   slope of the pulldown table from 0 to 0.225 V, typ, clamps not added: 34.7 ohm
|   slope of the pullup table from 0 to 0.225 V, typ, clamps not added: 36.1 ohm
|   GND clamp passes 1 mA (typ) near -0.49 V on its own axis
|   POWER clamp passes 1 mA (typ) near -0.47 V on its own axis
|   rising waveform, R_fixture 50, V_fixture 1.5: 20-80 % time 147ps typ, 201ps min, 120ps max; typ from 0.64 V to 1.49 V
|   rising waveform, R_fixture 50, V_fixture 0: 20-80 % time 157ps typ, 207ps min, 127ps max; typ from 0 V to 0.855 V
|   falling waveform, R_fixture 50, V_fixture 1.5: 20-80 % time 175ps typ, 233ps min, 136ps max; typ from 1.5 V to 0.643 V
|   falling waveform, R_fixture 50, V_fixture 0: 20-80 % time 166ps typ, 231ps min, 132ps max; typ from 0.859 V to 0.004 V
[POWER_clamp]
-1.5V     126mA      88.79mA    168.7mA
-1.242V   69.8mA     49.45mA    94.34mA
-1.136V   49.16mA    34.72mA    67.51mA
-1.061V   36.35mA    25.4mA     50.03mA
-1.045V   33.92mA    23.63mA    46.66mA
-954.5mV  21.93mA    14.95mA    29.5mA
-909.1mV  17.64mA    11.79mA    23.52mA
-863.6mV  14.51mA    9.351mA    19.47mA
-772.7mV  10.16mA    5.94mA     13.99mA
-590.9mV  3.705mA    1.741mA    5.166mA
-454.5mV  710.5uA    279.1uA    892.1uA
0V        1.424nA    14.34nA    3.127nA
[Pulldown]
-1.5V     -18.53mA   -17.11mA   -17.64mA
-1V       -19.61mA   -19mA      -19.13mA
-727.3mV  -17.47mA   -17.14mA   -17.24mA
-500mV    -14.14mA   -13.9mA    -14.19mA
272.7mV   7.805mA    7.637mA    8.027mA
681.8mV   18.19mA    17.72mA    18.92mA
1.045V    25.32mA    24.25mA    26.96mA
1.364V    28.79mA    26.85mA    31.92mA
1.818V    30.65mA    27.86mA    35.15mA
2.136V    28.67mA    23.53mA    35.66mA
2.636V    18.97mA    9.445mA    27.43mA
3V        11.34mA    3.552mA    20.22mA
[Pullup]
-1.5V     17mA       13.57mA    19.29mA
-1.136V   18.91mA    16.49mA    19.38mA
-863.6mV  17.34mA    17.39mA    17.41mA
-590.9mV  14.75mA    15.19mA    14.74mA
-409.1mV  11.37mA    11.41mA    11.41mA
909.1mV   -23.65mA   -22.84mA   -24.11mA
1.318V    -32.26mA   -30.18mA   -33.3mA
1.773V    -39.28mA   -35.15mA   -41.4mA
2.045V    -41.2mA    -34.1mA    -44.8mA
2.318V    -39.01mA   -30.07mA   -44.47mA
2.682V    -32.88mA   -21.38mA   -39.23mA
3V        -25.08mA   -13.45mA   -32.44mA
[GND_clamp]
-1.5V     -219.3mA   -131.6mA   -364.3mA
-1.288V   -134.4mA   -79.74mA   -225.6mA
-1.258V   -122.9mA   -72.77mA   -206.3mA
-1.136V   -79.27mA   -46.88mA   -132.4mA
-1.045V   -51.5mA    -31.06mA   -84.11mA
-1.015V   -44.02mA   -26.9mA    -70.91mA
-954.5mV  -31.01mA   -19.7mA    -47.55mA
-863.6mV  -17.48mA   -12.16mA   -23.55mA
-803mV    -11.81mA   -8.597mA   -15.85mA
-681.8mV  -5.986mA   -4.096mA   -9.026mA
-378.8mV  -126.2uA   -131.8uA   -179.7uA
1.5V      1.424nA    207.1nA    1.498nA
[Ramp]
dV/dt_f 0.51788125/0.17656881n 0.46376265/0.2363281n 0.57672943/0.13598919n
dV/dt_r  0.5175504/0.15921164n 0.46347504/0.21031469n 0.57136509/0.12702002n
R_load = 50
[Rising Waveform]
R_fixture = 50
V_fixture = 1.5
V_fixture_min = 1.35
V_fixture_max = 1.65
0s        639.6mV    579.9mV    691.7mV
112.9ps   639.6mV    579.9mV    725.3mV
218.7ps   673.7mV    579.9mV    1.251V
277.5ps   833.9mV    580.8mV    1.473V
354.7ps   1.136V     581.1mV    1.602V
412.4ps   1.312V     601.2mV    1.628V
489.9ps   1.423V     693.9mV    1.641V
674.2ps   1.487V     1.132V     1.648V
754.8ps   1.491V     1.25V      1.649V
1.37ns    1.494V     1.345V     1.65V
[Rising Waveform]
R_fixture = 50
V_fixture = 0
V_fixture_min = 0
V_fixture_max = 0
0s        0V         0V         0V
134.2ps   0V         0V         39.47mV
247.3ps   22.64mV    0V         564.7mV
314.4ps   201.6mV    0V         797mV
380.3ps   443.1mV    0V         903.2mV
458.5ps   677.5mV    0V         931mV
541.3ps   789.9mV    97.29mV    939.6mV
764.4ps   848.9mV    589.1mV    947.1mV
842.3ps   850.8mV    677.6mV    947.8mV
1.408ns   855mV      760.1mV    949.1mV
[Falling Waveform]
R_fixture = 50
V_fixture = 1.5
V_fixture_min = 1.35
V_fixture_max = 1.65
0s        1.499V     1.349V     1.649V
136ps     1.499V     1.349V     1.602V
260.5ps   1.44V      1.349V     1.074V
326.9ps   1.277V     1.349V     850mV
400.1ps   1.029V     1.349V     734.6mV
494.6ps   794.1mV    1.301V     707mV
582.1ps   696.2mV    1.175V     699.1mV
769.8ps   650.4mV    789.6mV    693.4mV
861.7ps   648.1mV    679.6mV    692.5mV
1.37ns    643.4mV    585.2mV    690.8mV
[Falling Waveform]
R_fixture = 50
V_fixture = 0
V_fixture_min = 0
V_fixture_max = 0
0s        858.8mV    767.6mV    948.5mV
111ps     858.8mV    767.6mV    933.3mV
210.2ps   844.6mV    767.6mV    493.5mV
290.1ps   632.8mV    767.6mV    187.4mV
376.9ps   333.3mV    766.7mV    40.05mV
433.6ps   183.7mV    723.2mV    17.98mV
532.4ps   65.15mV    554.3mV    6.856mV
722.6ps   9.839mV    172.7mV    0V
795.4ps   7.459mV    91.84mV    0V
1.408ns   3.52mV     4.82mV     0V
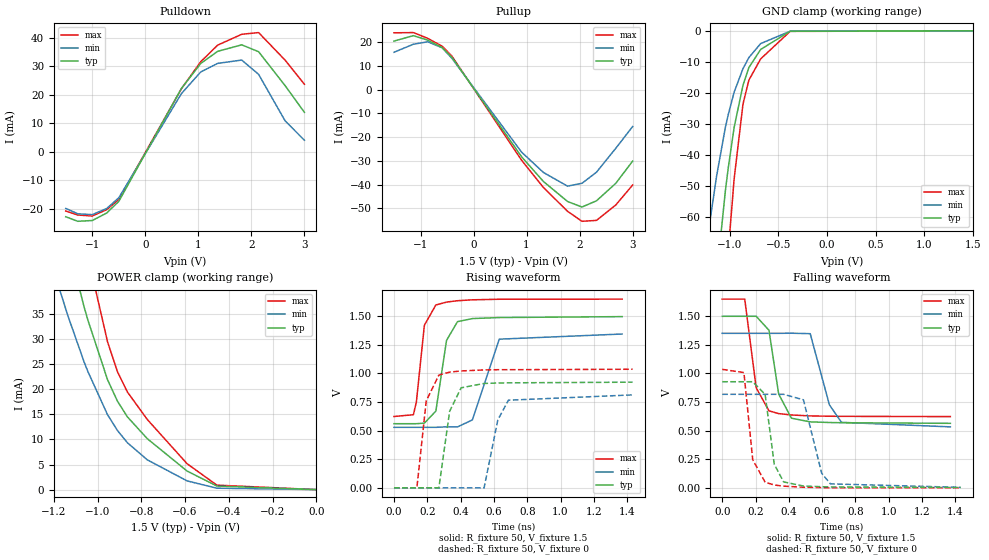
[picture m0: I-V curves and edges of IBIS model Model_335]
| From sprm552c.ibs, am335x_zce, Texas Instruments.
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| Model based on original model for BCSHTLTCSCDVPBFZ_SSDHV
|   Sub model SR00_12MA_10PER_1P5
[model]   Model_335
|[Description]  [1.5V-3-STATE-NOTERM-SR00:12MA, IND, 10%]
|   Fastest slew rate (SR[1:0] = "00"), 0.67 * RExt = 1.500 * Iout
|   (I[2:0] = "111"), 12mA nominal with Rext = 50R,ODT off (ODT[1:0]
|   = "00") CMOS mode,Industrial temperature range (-40C to 125C,
|   25C nominal),10% power supply tolerance
|[Input Load]   NOTERM
|[Output Drive] SR00:12MA
|Voltage   1.5V
|Mode   3-STATE
Model_type   3-state
Polarity   Non-Inverting
Enable   Active-Low
Cref =  15pF
Rref =  100.0000M
Vref =  0V
Vmeas =  0.75
C_comp   1.865048p   1.676829p   1.989968p
[Temperature Range]   25   125   -40
[Voltage Range]   1.5   1.35   1.65
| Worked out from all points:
|   slope of the pulldown table from 0 to 0.225 V, typ, clamps not added: 28.3 ohm
|   slope of the pullup table from 0 to 0.225 V, typ, clamps not added: 30.1 ohm
|   GND clamp passes 1 mA (typ) near -0.49 V on its own axis
|   POWER clamp passes 1 mA (typ) near -0.47 V on its own axis
|   rising waveform, R_fixture 50, V_fixture 1.5: 20-80 % time 57.5ps typ, 90.7ps min, 45.7ps max; typ from 0.561 V to 1.5 V
|   rising waveform, R_fixture 50, V_fixture 0: 20-80 % time 55.1ps typ, 68.8ps min, 48.7ps max; typ from 0 V to 0.924 V
|   falling waveform, R_fixture 50, V_fixture 1.5: 20-80 % time 65.6ps typ, 87.5ps min, 55ps max; typ from 1.5 V to 0.564 V
|   falling waveform, R_fixture 50, V_fixture 0: 20-80 % time 50.9ps typ, 73.3ps min, 45.4ps max; typ from 0.928 V to 0.004 V
[POWER_clamp]
-1.5V     126mA      88.79mA    168.7mA
-1.242V   69.8mA     49.45mA    94.34mA
-1.136V   49.16mA    34.72mA    67.51mA
-1.061V   36.35mA    25.4mA     50.03mA
-1.045V   33.92mA    23.63mA    46.66mA
-954.5mV  21.93mA    14.95mA    29.5mA
-909.1mV  17.64mA    11.79mA    23.52mA
-863.6mV  14.51mA    9.351mA    19.47mA
-772.7mV  10.16mA    5.94mA     13.99mA
-590.9mV  3.705mA    1.741mA    5.166mA
-454.5mV  710.5uA    279.1uA    892.1uA
0V        1.424nA    14.34nA    3.127nA
[Pulldown]
-1.5V     -22.72mA   -19.8mA    -20.72mA
-1.273V   -24.32mA   -21.69mA   -22.12mA
-1V       -24.04mA   -21.98mA   -22.46mA
-727.3mV  -21.41mA   -19.82mA   -20.23mA
-500mV    -17.33mA   -16.07mA   -16.65mA
681.8mV   22.29mA    20.49mA    22.2mA
1.045V    31.02mA    28.05mA    31.64mA
1.364V    35.28mA    31.06mA    37.46mA
1.818V    37.57mA    32.23mA    41.26mA
2.136V    35.16mA    27.23mA    41.87mA
2.636V    23.27mA    10.93mA    32.21mA
3V        13.9mA     4.109mA    23.75mA
[Pullup]
-1.5V     20.4mA     15.7mA     23.88mA
-1.136V   22.69mA    19.07mA    23.99mA
-863.6mV  20.8mA     20.11mA    21.55mA
-590.9mV  17.69mA    17.57mA    18.24mA
-409.1mV  13.64mA    13.19mA    14.12mA
909.1mV   -28.37mA   -26.41mA   -29.83mA
1.318V    -38.69mA   -34.9mA    -41.21mA
1.773V    -47.12mA   -40.66mA   -51.24mA
2.045V    -49.44mA   -39.45mA   -55.45mA
2.318V    -46.83mA   -34.79mA   -55.07mA
2.682V    -39.48mA   -24.74mA   -48.59mA
3V        -30.12mA   -15.56mA   -40.19mA
[GND_clamp]
-1.5V     -219.3mA   -131.6mA   -364.3mA
-1.288V   -134.4mA   -79.74mA   -225.6mA
-1.258V   -122.9mA   -72.77mA   -206.3mA
-1.136V   -79.27mA   -46.88mA   -132.4mA
-1.045V   -51.5mA    -31.06mA   -84.11mA
-1.015V   -44.02mA   -26.9mA    -70.91mA
-954.5mV  -31.01mA   -19.7mA    -47.55mA
-863.6mV  -17.48mA   -12.16mA   -23.55mA
-803mV    -11.81mA   -8.597mA   -15.85mA
-681.8mV  -5.986mA   -4.096mA   -9.026mA
-378.8mV  -126.2uA   -131.8uA   -179.7uA
1.5V      1.424nA    207.1nA    1.498nA
[Ramp]
dV/dt_f 0.57592486/64.834496p 0.50610763/86.599843p 0.62537393/55.014792p
dV/dt_r 0.56955111/55.985489p 0.51187118/69.136151p 0.63177174/48.711441p
R_load = 50
[Rising Waveform]
R_fixture = 50
V_fixture = 1.5
V_fixture_min = 1.35
V_fixture_max = 1.65
0s        560.9mV    529mV      623.9mV
116.3ps   560.9mV    529mV      639.4mV
134.2ps   560.9mV    529mV      747.7mV
182.5ps   565.9mV    529mV      1.422V
251.5ps   671.3mV    529mV      1.599V
315.5ps   1.289V     533.7mV    1.624V
381.3ps   1.453V     532.9mV    1.636V
470.7ps   1.48V      594mV      1.644V
631.9ps   1.489V     1.3V       1.649V
1.37ns    1.497V     1.345V     1.65V
[Rising Waveform]
R_fixture = 50
V_fixture = 0
V_fixture_min = 0
V_fixture_max = 0
0s        0V         0V         0V
137.4ps   0V         0V         0V
193.7ps   0V         0V         760.8mV
269.5ps   0V         0V         985.8mV
334.2ps   669.3mV    0V         1.012V
403.1ps   874.6mV    0V         1.022V
541.1ps   912.8mV    0V         1.031V
623.6ps   916.5mV    594.5mV    1.033V
687ps     918.2mV    766.2mV    1.033V
1.433ns   923.9mV    812.9mV    1.037V
[Falling Waveform]
R_fixture = 50
V_fixture = 1.5
V_fixture_min = 1.35
V_fixture_max = 1.65
0s        1.5V       1.351V     1.65V
135.2ps   1.5V       1.351V     1.65V
203.9ps   1.5V       1.351V     874.9mV
280.7ps   1.378V     1.351V     673.7mV
339ps     820.1mV    1.351V     649.1mV
415.6ps   609.1mV    1.352V     637.2mV
528.4ps   577mV      1.348V     629mV
643.6ps   571.4mV    725.7mV    626.3mV
716ps     569.2mV    572.9mV    625.2mV
1.37ns    564.2mV    533.2mV    623mV
[Falling Waveform]
R_fixture = 50
V_fixture = 0
V_fixture_min = 0
V_fixture_max = 0
0s        927.8mV    817.8mV    1.036V
130.3ps   927.8mV    817.8mV    1.008V
183.1ps   927.8mV    817.8mV    246.6mV
257.7ps   816.6mV    817.8mV    49.21mV
312.5ps   206.4mV    817.8mV    24.97mV
368.6ps   52.01mV    817.8mV    14.96mV
487.7ps   16.3mV     769.9mV    5.351mV
597.3ps   9.909mV    127.5mV    2.583mV
649.6ps   8.272mV    34.9mV     0V
1.433ns   3.641mV    4.311mV    0V
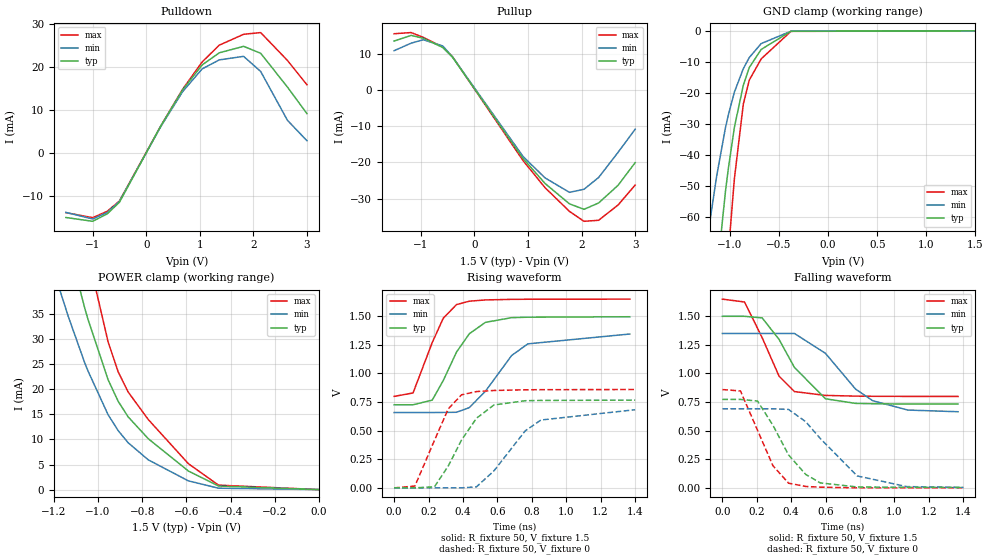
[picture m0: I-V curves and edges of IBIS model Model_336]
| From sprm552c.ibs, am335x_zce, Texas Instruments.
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| Model based on original model for BCSHTLTCSCDVPBFZ_SSDHV
|   Sub model SR01_8MA_10PER_1P5
[model]   Model_336
|[Description]  [1.5V-3-STATE-NOTERM-SR01:8MA, IND, 10%]
|   Slow slew rate (SR[1:0] = "01"), 1.00 * RExt = 1.000 * Iout
|   (I[2:0] = "011"), 8mA nominal with Rext = 50R,ODT off (ODT[1:0]
|   = "00") CMOS mode,Industrial temperature range (-40C to 125C,
|   25C nominal),10% power supply tolerance
|[Input Load]   NOTERM
|[Output Drive] SR01:8MA
|Voltage   1.5V
|Mode   3-STATE
Model_type   3-state
Polarity   Non-Inverting
Enable   Active-Low
Cref =  15pF
Rref =  100.0000M
Vref =  0V
Vmeas =  0.75
C_comp   1.865048p   1.676829p   1.989968p
[Temperature Range]   25   125   -40
[Voltage Range]   1.5   1.35   1.65
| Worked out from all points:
|   slope of the pulldown table from 0 to 0.225 V, typ, clamps not added: 43 ohm
|   slope of the pullup table from 0 to 0.225 V, typ, clamps not added: 45 ohm
|   GND clamp passes 1 mA (typ) near -0.49 V on its own axis
|   POWER clamp passes 1 mA (typ) near -0.47 V on its own axis
|   rising waveform, R_fixture 50, V_fixture 1.5: 20-80 % time 166ps typ, 217ps min, 131ps max; typ from 0.726 V to 1.5 V
|   rising waveform, R_fixture 50, V_fixture 0: 20-80 % time 181ps typ, 226ps min, 139ps max; typ from 0 V to 0.767 V
|   falling waveform, R_fixture 50, V_fixture 1.5: 20-80 % time 192ps typ, 252ps min, 146ps max; typ from 1.5 V to 0.732 V
|   falling waveform, R_fixture 50, V_fixture 0: 20-80 % time 187ps typ, 242ps min, 143ps max; typ from 0.773 V to 0.004 V
[POWER_clamp]
-1.5V     126mA      88.79mA    168.7mA
-1.242V   69.8mA     49.45mA    94.34mA
-1.136V   49.16mA    34.72mA    67.51mA
-1.061V   36.35mA    25.4mA     50.03mA
-1.045V   33.92mA    23.63mA    46.66mA
-954.5mV  21.93mA    14.95mA    29.5mA
-909.1mV  17.64mA    11.79mA    23.52mA
-863.6mV  14.51mA    9.351mA    19.47mA
-772.7mV  10.16mA    5.94mA     13.99mA
-590.9mV  3.705mA    1.741mA    5.166mA
-454.5mV  710.5uA    279.1uA    892.1uA
0V        1.424nA    14.34nA    3.127nA
[Pulldown]
-1.5V     -14.94mA   -13.76mA   -13.81mA
-1V       -15.82mA   -15.28mA   -14.98mA
-727.3mV  -14.09mA   -13.78mA   -13.5mA
-500mV    -11.41mA   -11.18mA   -11.11mA
272.7mV   6.297mA    6.143mA    6.286mA
681.8mV   14.68mA    14.25mA    14.82mA
1.045V    20.42mA    19.5mA     21.11mA
1.364V    23.22mA    21.58mA    24.99mA
1.818V    24.72mA    22.4mA     27.51mA
2.136V    23.12mA    18.91mA    27.91mA
2.636V    15.29mA    7.59mA     21.46mA
3V        9.139mA    2.855mA    15.82mA
[Pullup]
-1.5V     13.59mA    10.91mA    15.61mA
-1.182V   15.15mA    13mA       15.93mA
-954.5mV  14.35mA    13.95mA    14.59mA
-590.9mV  11.8mA     12.22mA    11.93mA
-409.1mV  9.103mA    9.176mA    9.241mA
909.1mV   -18.93mA   -18.37mA   -19.52mA
1.318V    -25.81mA   -24.27mA   -26.97mA
1.773V    -31.43mA   -28.26mA   -33.52mA
2.045V    -32.96mA   -27.41mA   -36.27mA
2.318V    -31.2mA    -24.16mA   -35.99mA
2.682V    -26.3mA    -17.18mA   -31.75mA
3V        -20.05mA   -10.81mA   -26.25mA
[GND_clamp]
-1.5V     -219.3mA   -131.6mA   -364.3mA
-1.288V   -134.4mA   -79.74mA   -225.6mA
-1.258V   -122.9mA   -72.77mA   -206.3mA
-1.136V   -79.27mA   -46.88mA   -132.4mA
-1.045V   -51.5mA    -31.06mA   -84.11mA
-1.015V   -44.02mA   -26.9mA    -70.91mA
-954.5mV  -31.01mA   -19.7mA    -47.55mA
-863.6mV  -17.48mA   -12.16mA   -23.55mA
-803mV    -11.81mA   -8.597mA   -15.85mA
-681.8mV  -5.986mA   -4.096mA   -9.026mA
-378.8mV  -126.2uA   -131.8uA   -179.7uA
1.5V      1.424nA    207.1nA    1.498nA
[Ramp]
dV/dt_f 0.46566036/0.19520379n 0.41586596/0.25546786n 0.51163194/0.14684747n
dV/dt_r 0.46529289/0.18315367n 0.41651036/0.2307305n 0.51710949/0.13931922n
R_load = 50
[Rising Waveform]
R_fixture = 50
V_fixture = 1.5
V_fixture_min = 1.35
V_fixture_max = 1.65
0s        726.3mV    658.6mV    799.6mV
110ps     726.3mV    658.6mV    829.6mV
221.7ps   767.2mV    658.6mV    1.271V
285.7ps   938.7mV    659.6mV    1.483V
362.7ps   1.187V     660.9mV    1.602V
436.9ps   1.347V     701.3mV    1.632V
530.8ps   1.447V     844.6mV    1.643V
683.1ps   1.488V     1.157V     1.648V
777.4ps   1.492V     1.259V     1.649V
1.37ns    1.496V     1.345V     1.65V
[Rising Waveform]
R_fixture = 50
V_fixture = 0
V_fixture_min = 0
V_fixture_max = 0
0s        0V         0V         0V
120.8ps   0V         0V         15.76mV
234.7ps   9.782mV    0V         416.3mV
314.9ps   191.3mV    0V         690.7mV
391.8ps   417.8mV    0V         813.6mV
478.7ps   608.5mV    8.877mV    841.9mV
580.2ps   724.7mV    148.5mV    851.5mV
762.1ps   761.8mV    498.6mV    857.2mV
853.3ps   764.2mV    593.1mV    858.4mV
1.401ns   767mV      683.1mV    859.8mV
[Falling Waveform]
R_fixture = 50
V_fixture = 1.5
V_fixture_min = 1.35
V_fixture_max = 1.65
0s        1.499V     1.349V     1.649V
128.8ps   1.499V     1.349V     1.624V
231.5ps   1.485V     1.349V     1.312V
329.6ps   1.297V     1.349V     976mV
419.1ps   1.052V     1.349V     841.1mV
599.6ps   778.2mV    1.175V     807.8mV
774.3ps   738mV      862.8mV    801.6mV
874.7ps   734.9mV    761mV      800.1mV
1.078ns   732.4mV    679.8mV    799mV
1.37ns    732.4mV    665.1mV    798.8mV
[Falling Waveform]
R_fixture = 50
V_fixture = 0
V_fixture_min = 0
V_fixture_max = 0
0s        772.8mV    691.1mV    859mV
105.3ps   772.8mV    691.1mV    846.7mV
204.4ps   758.3mV    691.1mV    503.6mV
293.9ps   547.5mV    691.1mV    193.8mV
384.9ps   287.7mV    685.1mV    40.79mV
484.6ps   117.3mV    578mV      12.11mV
569.5ps   43.34mV    431mV      6.111mV
783.2ps   7.89mV     104.7mV    0V
1.071ns   4.787mV    11mV       0V
1.401ns   3.61mV     4.323mV    0V
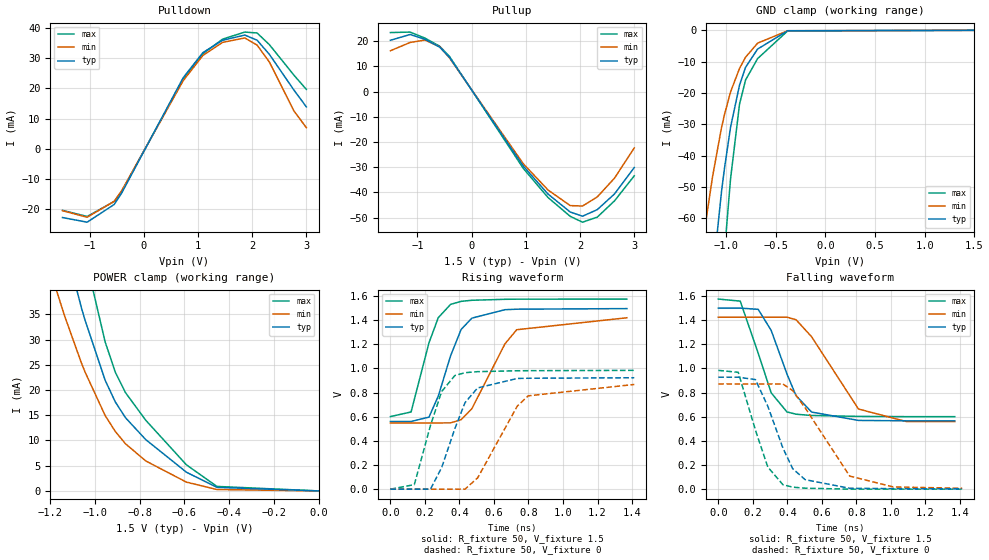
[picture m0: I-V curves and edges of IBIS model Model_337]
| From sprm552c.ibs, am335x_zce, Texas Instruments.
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| Model based on original model for BCSHTLTCSCDVPBFZ_SSDHV
|   Sub model SR01_12MA_5PER_1P5
[model]   Model_337
|[Description]  [1.5V-3-STATE-NOTERM-SR01:12MA, IND, 5%]
|   Slow slew rate (SR[1:0] = "01"), 0.67 * RExt = 1.500 * Iout
|   (I[2:0] = "111"), 12mA nominal with Rext = 50R,ODT off (ODT[1:0]
|   = "00") CMOS mode,Industrial temperature range (-40C to 125C,
|   25C nominal),5% power supply tolerance
|[Input Load]   NOTERM
|[Output Drive] SR01:12MA
|Voltage   1.5V
|Mode   3-STATE
Model_type   3-state
Polarity   Non-Inverting
Enable   Active-Low
Cref =  15pF
Rref =  100.0000M
Vref =  0V
Vmeas =  0.75
C_comp   1.865048p   1.679967p   1.989968p
[Temperature Range]   25   125   -40
[Voltage Range]   1.5   1.425   1.575
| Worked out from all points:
|   slope of the pulldown table from 0 to 0.225 V, typ, clamps not added: 28.3 ohm
|   slope of the pullup table from 0 to 0.225 V, typ, clamps not added: 30.1 ohm
|   GND clamp passes 1 mA (typ) near -0.49 V on its own axis
|   POWER clamp passes 1 mA (typ) near -0.47 V on its own axis
|   rising waveform, R_fixture 50, V_fixture 1.5: 20-80 % time 133ps typ, 192ps min, 108ps max; typ from 0.561 V to 1.5 V
|   rising waveform, R_fixture 50, V_fixture 0: 20-80 % time 143ps typ, 196ps min, 113ps max; typ from 0 V to 0.923 V
|   falling waveform, R_fixture 50, V_fixture 1.5: 20-80 % time 154ps typ, 217ps min, 125ps max; typ from 1.5 V to 0.566 V
|   falling waveform, R_fixture 50, V_fixture 0: 20-80 % time 150ps typ, 222ps min, 121ps max; typ from 0.927 V to 0.003 V
[POWER_clamp]
-1.5V     126mA      88.76mA    168.8mA
-1.242V   69.8mA     49.43mA    94.36mA
-1.136V   49.16mA    34.7mA     67.53mA
-1.061V   36.35mA    25.39mA    50.04mA
-1.045V   33.92mA    23.62mA    46.67mA
-954.5mV  21.93mA    14.94mA    29.52mA
-909.1mV  17.64mA    11.78mA    23.53mA
-863.6mV  14.51mA    9.346mA    19.48mA
-772.7mV  10.16mA    5.937mA    14mA
-590.9mV  3.705mA    1.741mA    5.168mA
-454.5mV  710.5uA    279.1uA    892.2uA
0V        1.424nA    14.75nA    2.169nA
[Pulldown]
-1.5V     -22.72mA   -20.45mA   -20.34mA
-1.045V   -24.26mA   -22.63mA   -22.37mA
-545.5mV  -18.39mA   -17.36mA   -17.39mA
-409.1mV  -14.66mA   -13.87mA   -14.1mA
727.3mV   23.54mA    22.55mA    22.99mA
1.091V    31.85mA    30.92mA    31.48mA
1.455V    35.94mA    35.24mA    36.31mA
1.864V    37.66mA    36.7mA     38.64mA
2.091V    35.96mA    34.34mA    38.35mA
2.318V    31.27mA    28.72mA    34.48mA
2.773V    19.4mA     12.48mA    24.34mA
3V        13.9mA     7.024mA    19.68mA
[Pullup]
-1.5V     20.4mA     16.24mA    23.46mA
-1.136V   22.69mA    19.53mA    23.65mA
-863.6mV  20.8mA     20.49mA    21.28mA
-590.9mV  17.69mA    17.85mA    18.05mA
-409.1mV  13.64mA    13.4mA     13.98mA
954.5mV   -29.62mA   -28.69mA   -30.52mA
1.409V    -40.66mA   -39.04mA   -42.03mA
1.818V    -47.77mA   -45.23mA   -49.49mA
2.045V    -49.44mA   -45.41mA   -51.82mA
2.318V    -46.83mA   -41.78mA   -49.8mA
2.636V    -40.59mA   -34.31mA   -43.34mA
3V        -30.12mA   -22.33mA   -33.4mA
[GND_clamp]
-1.5V     -219.3mA   -131.6mA   -364.3mA
-1.288V   -134.4mA   -79.74mA   -225.6mA
-1.258V   -122.9mA   -72.77mA   -206.3mA
-1.136V   -79.27mA   -46.88mA   -132.4mA
-1.045V   -51.5mA    -31.06mA   -84.11mA
-1.015V   -44.02mA   -26.9mA    -70.91mA
-954.5mV  -31.01mA   -19.7mA    -47.55mA
-863.6mV  -17.48mA   -12.16mA   -23.55mA
-803mV    -11.81mA   -8.597mA   -15.85mA
-681.8mV  -5.986mA   -4.096mA   -9.026mA
-378.8mV  -126.2uA   -131.8uA   -179.7uA
1.5V      1.424nA    36.56nA    1.506nA
[Ramp]
dV/dt_f 0.56573268/0.15573725n 0.52845464/0.22176099n 0.58630102/0.12582057n
dV/dt_r 0.55903131/0.14464527n  0.5261645/0.19793888n 0.59282459/0.11307323n
R_load = 50
[Rising Waveform]
R_fixture = 50
V_fixture = 1.5
V_fixture_min = 1.425
V_fixture_max = 1.575
0s        560.9mV    548.2mV    601.3mV
119.9ps   560.9mV    548.2mV    639.7mV
223.6ps   596.8mV    548.2mV    1.213V
277.5ps   771.1mV    548.7mV    1.421V
348.8ps   1.105V     549.2mV    1.531V
409.7ps   1.323V     575.9mV    1.556V
472.2ps   1.417V     667mV      1.565V
663.8ps   1.487V     1.204V     1.573V
731.9ps   1.491V     1.321V     1.574V
1.37ns    1.496V     1.42V      1.575V
[Rising Waveform]
R_fixture = 50
V_fixture = 0
V_fixture_min = 0
V_fixture_max = 0
0s        0V         0V         0V
138.7ps   0V         0V         37.54mV
232.2ps   0V         0V         527.4mV
296.7ps   177.8mV    0V         808.5mV
373.9ps   502.8mV    0V         942mV
432.4ps   716.9mV    0V         965mV
505.5ps   838.8mV    93.3mV     973.6mV
735.2ps   917.3mV    688.2mV    981.1mV
798.3ps   918.9mV    773.4mV    981.6mV
1.413ns   923.1mV    867.4mV    984.3mV
[Falling Waveform]
R_fixture = 50
V_fixture = 1.5
V_fixture_min = 1.425
V_fixture_max = 1.575
0s        1.499V     1.424V     1.574V
127ps     1.499V     1.424V     1.557V
230.9ps   1.489V     1.424V     1.127V
306.3ps   1.315V     1.424V     797.7mV
397.7ps   954mV      1.424V     639.5mV
450.5ps   773.9mV    1.403V     620.7mV
540.5ps   638.5mV    1.262V     610.1mV
812.1ps   569.2mV    663.5mV    602.5mV
1.091ns   565.8mV    559.3mV    600.6mV
1.37ns    565.8mV    559.3mV    600.4mV
[Falling Waveform]
R_fixture = 50
V_fixture = 0
V_fixture_min = 0
V_fixture_max = 0
0s        927.1mV    871.4mV    983.5mV
115.5ps   927.1mV    871.4mV    967.7mV
215ps     907.3mV    871.4mV    489.6mV
286.7ps   686.8mV    871.4mV    183.4mV
374.3ps   340.6mV    870.7mV    37.05mV
431ps     169.6mV    815.9mV    16.6mV
503.2ps   78.73mV    672.8mV    8.027mV
761.4ps   7.36mV     108.1mV    0V
1.014ns   4.271mV    18.48mV    0V
1.413ns   3.06mV     7.41mV     0V
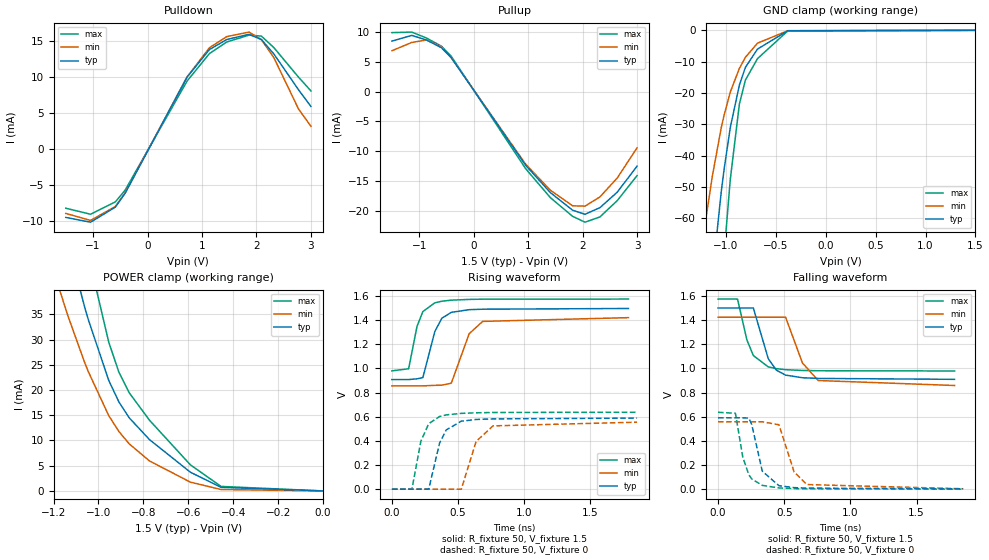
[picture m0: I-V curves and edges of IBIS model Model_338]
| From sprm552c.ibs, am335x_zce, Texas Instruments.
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| Model based on original model for BCSHTLTCSCDVPBFZ_SSDHV
|   Sub model SR00_5MA_5PER_1P5
[model]   Model_338
|[Description]  [1.5V-3-STATE-NOTERM-SR00:5MA, IND, 5%]
|   Fastest slew rate (SR[1:0] = "00"), 1.60 * RExt = 0.625 * Iout
|   (I[2:0] = "000"), 5mA nominal with Rext = 50R,ODT off (ODT[1:0]
|   = "00") CMOS mode,Industrial temperature range (-40C to 125C,
|   25C nominal),5% power supply tolerance
|[Input Load]   NOTERM
|[Output Drive] SR00:5MA
|Voltage   1.5V
|Mode   3-STATE
Model_type   3-state
Polarity   Non-Inverting
Enable   Active-Low
Cref =  15pF
Rref =  100.0000M
Vref =  0V
Vmeas =  0.75
C_comp   1.865048p   1.679967p   1.989968p
[Temperature Range]   25   125   -40
[Voltage Range]   1.5   1.425   1.575
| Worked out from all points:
|   slope of the pulldown table from 0 to 0.225 V, typ, clamps not added: 67.2 ohm
|   slope of the pullup table from 0 to 0.225 V, typ, clamps not added: 72 ohm
|   GND clamp passes 1 mA (typ) near -0.49 V on its own axis
|   POWER clamp passes 1 mA (typ) near -0.47 V on its own axis
|   rising waveform, R_fixture 50, V_fixture 1.5: 20-80 % time 87.4ps typ, 109ps min, 75.9ps max; typ from 0.908 V to 1.5 V
|   rising waveform, R_fixture 50, V_fixture 0: 20-80 % time 91.1ps typ, 103ps min, 83.2ps max; typ from 0 V to 0.589 V
|   falling waveform, R_fixture 50, V_fixture 1.5: 20-80 % time 106ps typ, 121ps min, 96.7ps max; typ from 1.5 V to 0.91 V
|   falling waveform, R_fixture 50, V_fixture 0: 20-80 % time 79.8ps typ, 96.9ps min, 74.8ps max; typ from 0.591 V to 0.003 V
[POWER_clamp]
-1.5V     126mA      88.76mA    168.8mA
-1.242V   69.8mA     49.43mA    94.36mA
-1.136V   49.16mA    34.7mA     67.53mA
-1.061V   36.35mA    25.39mA    50.04mA
-1.045V   33.92mA    23.62mA    46.67mA
-954.5mV  21.93mA    14.94mA    29.52mA
-909.1mV  17.64mA    11.78mA    23.53mA
-863.6mV  14.51mA    9.346mA    19.48mA
-772.7mV  10.16mA    5.937mA    14mA
-590.9mV  3.705mA    1.741mA    5.168mA
-454.5mV  710.5uA    279.1uA    892.2uA
0V        1.424nA    14.75nA    2.169nA
[Pulldown]
-1.5V     -9.559mA   -9.005mA   -8.281mA
-1.045V   -10.22mA   -9.975mA   -9.117mA
-590.9mV  -8.133mA   -8.04mA    -7.408mA
-409.1mV  -6.182mA   -6.122mA   -5.755mA
727.3mV   9.928mA    9.954mA    9.38mA
1.136V    13.74mA    13.99mA    13.18mA
1.455V    15.14mA    15.54mA    14.8mA
1.864V    15.86mA    16.17mA    15.75mA
2.091V    15.13mA    15.12mA    15.61mA
2.318V    13.15mA    12.64mA    14.03mA
2.773V    8.157mA    5.489mA    9.905mA
3V        5.846mA    3.092mA    8.007mA
[Pullup]
-1.5V     8.494mA    6.876mA    9.92mA
-1.136V   9.455mA    8.27mA     10.01mA
-863.6mV  8.671mA    8.683mA    9.007mA
-590.9mV  7.379mA    7.572mA    7.643mA
-409.1mV  5.694mA    5.688mA    5.925mA
954.5mV   -12.36mA   -12.18mA   -12.93mA
1.409V    -16.96mA   -16.56mA   -17.81mA
1.818V    -19.92mA   -19.18mA   -20.95mA
2.045V    -20.6mA    -19.23mA   -21.93mA
2.318V    -19.49mA   -17.69mA   -21.05mA
2.636V    -16.89mA   -14.51mA   -18.31mA
3V        -12.52mA   -9.441mA   -14.11mA
[GND_clamp]
-1.5V     -219.3mA   -131.6mA   -364.3mA
-1.288V   -134.4mA   -79.74mA   -225.6mA
-1.258V   -122.9mA   -72.77mA   -206.3mA
-1.136V   -79.27mA   -46.88mA   -132.4mA
-1.045V   -51.5mA    -31.06mA   -84.11mA
-1.015V   -44.02mA   -26.9mA    -70.91mA
-954.5mV  -31.01mA   -19.7mA    -47.55mA
-863.6mV  -17.48mA   -12.16mA   -23.55mA
-803mV    -11.81mA   -8.597mA   -15.85mA
-681.8mV  -5.986mA   -4.096mA   -9.026mA
-378.8mV  -126.2uA   -131.8uA   -179.7uA
1.5V      1.424nA    36.56nA    1.506nA
[Ramp]
dV/dt_f  0.3615589/0.1070874n 0.34928769/0.12262165n  0.3618378/96.783786p
dV/dt_r 0.36102943/92.365688p 0.34357677/0.10401399n 0.38673517/83.207823p
R_load = 50
[Rising Waveform]
R_fixture = 50
V_fixture = 1.5
V_fixture_min = 1.425
V_fixture_max = 1.575
0s        908.2mV    855.7mV    980.1mV
126.3ps   908.2mV    855.7mV    997.5mV
189.8ps   914.1mV    855.7mV    1.349V
233.8ps   923.7mV    855.7mV    1.471V
324.2ps   1.306V     860.3mV    1.544V
377.2ps   1.416V     861.3mV    1.557V
448.7ps   1.465V     878mV      1.566V
583.7ps   1.487V     1.288V     1.572V
685.7ps   1.491V     1.39V      1.574V
1.787ns   1.497V     1.421V     1.575V
[Rising Waveform]
R_fixture = 50
V_fixture = 0
V_fixture_min = 0
V_fixture_max = 0
0s        0V         0V         0V
151.1ps   0V         0V         0V
218.5ps   0V         0V         396.3mV
278ps     0V         0V         542.2mV
360.1ps   381.4mV    0V         602mV
409.6ps   490mV      0V         615.1mV
524.1ps   563.2mV    0V         628mV
636.5ps   577.5mV    395.7mV    632.8mV
764ps     582.2mV    524.3mV    635.3mV
1.852ns   588.9mV    554.9mV    637.3mV
[Falling Waveform]
R_fixture = 50
V_fixture = 1.5
V_fixture_min = 1.425
V_fixture_max = 1.575
0s        1.501V     1.425V     1.575V
147.2ps   1.501V     1.425V     1.575V
217.7ps   1.501V     1.425V     1.238V
266.7ps   1.501V     1.425V     1.107V
379.5ps   1.081V     1.425V     1.013V
440.1ps   986.5mV    1.425V     998.3mV
510.2ps   945.1mV    1.425V     990mV
637.9ps   923.1mV    1.045V     983.5mV
756.7ps   917.5mV    900.1mV    981.1mV
1.787ns   909.9mV    858.9mV    979.2mV
[Falling Waveform]
R_fixture = 50
V_fixture = 0
V_fixture_min = 0
V_fixture_max = 0
0s        591.2mV    558.3mV    636.8mV
131.3ps   591.2mV    558.3mV    628.8mV
186.9ps   591.2mV    558.3mV    265.8mV
232.7ps   588.5mV    558.3mV    118.6mV
255.1ps   534.7mV    558.3mV    84.4mV
333.9ps   149.4mV    558.3mV    31.58mV
460ps     28.65mV    533.6mV    10.22mV
575ps     12.67mV    142mV      4.745mV
670.7ps   8.815mV    38.14mV    2.724mV
1.852ns   3.054mV    3.4mV      0V
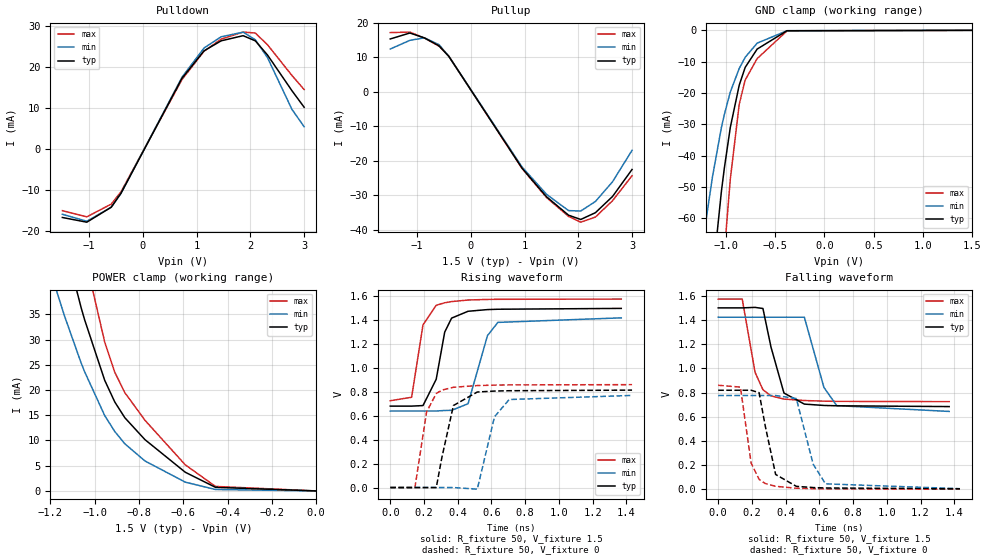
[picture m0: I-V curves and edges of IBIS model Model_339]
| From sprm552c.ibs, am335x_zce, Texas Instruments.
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| Model based on original model for BCSHTLTCSCDVPBFZ_SSDHV
|   Sub model SR00_9MA_5PER_1P5
[model]   Model_339
|[Description]  [1.5V-3-STATE-NOTERM-SR00:9MA, IND, 5%]
|   Fastest slew rate (SR[1:0] = "00"), 0.88 * RExt = 1.125 * Iout
|   (I[2:0] = "100"), 9mA nominal with Rext = 50R,ODT off (ODT[1:0]
|   = "00") CMOS mode,Industrial temperature range (-40C to 125C,
|   25C nominal),5% power supply tolerance
|[Input Load]   NOTERM
|[Output Drive] SR00:9MA
|Voltage   1.5V
|Mode   3-STATE
Model_type   3-state
Polarity   Non-Inverting
Enable   Active-Low
Cref =  15pF
Rref =  100.0000M
Vref =  0V
Vmeas =  0.75
C_comp   1.865048p   1.679967p   1.989968p
[Temperature Range]   25   125   -40
[Voltage Range]   1.5   1.425   1.575
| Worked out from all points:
|   slope of the pulldown table from 0 to 0.225 V, typ, clamps not added: 38.4 ohm
|   slope of the pullup table from 0 to 0.225 V, typ, clamps not added: 40.1 ohm
|   GND clamp passes 1 mA (typ) near -0.49 V on its own axis
|   POWER clamp passes 1 mA (typ) near -0.47 V on its own axis
|   rising waveform, R_fixture 50, V_fixture 1.5: 20-80 % time 67.6ps typ, 89.2ps min, 57.3ps max; typ from 0.68 V to 1.5 V
|   rising waveform, R_fixture 50, V_fixture 0: 20-80 % time 66.3ps typ, 74.9ps min, 61.4ps max; typ from 0 V to 0.814 V
|   falling waveform, R_fixture 50, V_fixture 1.5: 20-80 % time 77.7ps typ, 93.7ps min, 69.6ps max; typ from 1.5 V to 0.684 V
|   falling waveform, R_fixture 50, V_fixture 0: 20-80 % time 60.6ps typ, 78.3ps min, 55.7ps max; typ from 0.819 V to 0.003 V
[POWER_clamp]
-1.5V     126mA      88.76mA    168.8mA
-1.242V   69.8mA     49.43mA    94.36mA
-1.136V   49.16mA    34.7mA     67.53mA
-1.061V   36.35mA    25.39mA    50.04mA
-1.045V   33.92mA    23.62mA    46.67mA
-954.5mV  21.93mA    14.94mA    29.52mA
-909.1mV  17.64mA    11.78mA    23.53mA
-863.6mV  14.51mA    9.346mA    19.48mA
-772.7mV  10.16mA    5.937mA    14mA
-590.9mV  3.705mA    1.741mA    5.168mA
-454.5mV  710.5uA    279.1uA    892.2uA
0V        1.424nA    14.75nA    2.169nA
[Pulldown]
-1.5V     -16.73mA   -15.94mA   -15.06mA
-1.045V   -17.88mA   -17.65mA   -16.57mA
-590.9mV  -14.22mA   -14.22mA   -13.46mA
-409.1mV  -10.81mA   -10.82mA   -10.45mA
727.3mV   17.36mA    17.6mA     17.04mA
1.136V    24.04mA    24.73mA    23.94mA
1.455V    26.49mA    27.48mA    26.9mA
1.864V    27.75mA    28.61mA    28.63mA
2.091V    26.49mA    26.76mA    28.4mA
2.318V    23.02mA    22.38mA    25.53mA
2.773V    14.29mA    9.722mA    18.02mA
3V        10.24mA    5.474mA    14.57mA
[Pullup]
-1.5V     15.3mA     12.38mA    17.14mA
-1.136V   17.02mA    14.89mA    17.29mA
-863.6mV  15.6mA     15.63mA    15.55mA
-590.9mV  13.28mA    13.62mA    13.2mA
-409.1mV  10.24mA    10.23mA    10.22mA
954.5mV   -22.23mA   -21.9mA    -22.32mA
1.409V    -30.51mA   -29.79mA   -30.74mA
1.818V    -35.84mA   -34.51mA   -36.18mA
2.045V    -37.08mA   -34.63mA   -37.87mA
2.318V    -35.11mA   -31.86mA   -36.38mA
2.636V    -30.42mA   -26.15mA   -31.65mA
3V        -22.57mA   -17.01mA   -24.39mA
[GND_clamp]
-1.5V     -219.3mA   -131.6mA   -364.3mA
-1.288V   -134.4mA   -79.74mA   -225.6mA
-1.258V   -122.9mA   -72.77mA   -206.3mA
-1.136V   -79.27mA   -46.88mA   -132.4mA
-1.045V   -51.5mA    -31.06mA   -84.11mA
-1.015V   -44.02mA   -26.9mA    -70.91mA
-954.5mV  -31.01mA   -19.7mA    -47.55mA
-863.6mV  -17.48mA   -12.16mA   -23.55mA
-803mV    -11.81mA   -8.597mA   -15.85mA
-681.8mV  -5.986mA   -4.096mA   -9.026mA
-378.8mV  -126.2uA   -131.8uA   -179.7uA
1.5V      1.424nA    36.56nA    1.506nA
[Ramp]
dV/dt_f 0.50180043/79.006105p 0.48336644/91.964446p 0.51761813/69.869738p
dV/dt_r 0.50091734/67.299002p 0.48017573/76.157106p 0.52378521/61.694058p
R_load = 50
[Rising Waveform]
R_fixture = 50
V_fixture = 1.5
V_fixture_min = 1.425
V_fixture_max = 1.575
0s        680.3mV    639.4mV    725.3mV
126.6ps   680.3mV    639.4mV    754.5mV
194.1ps   685mV      639.4mV    1.36V
272.5ps   905.5mV    639.4mV    1.523V
322.8ps   1.299V     644mV      1.544V
363.9ps   1.416V     645.1mV    1.554V
461.3ps   1.473V     700.3mV    1.567V
576.3ps   1.487V     1.269V     1.572V
637.9ps   1.49V      1.38V      1.573V
1.37ns    1.497V     1.418V     1.575V
[Rising Waveform]
R_fixture = 50
V_fixture = 0
V_fixture_min = 0
V_fixture_max = 0
0s        0V         0V         0V
146.2ps   0V         0V         0V
215.2ps   0V         0V         631.8mV
272.8ps   0V         0V         785.9mV
306.1ps   251.8mV    0V         814.4mV
374.5ps   685.3mV    0V         837.7mV
516.1ps   798.2mV    -13.66mV   852.1mV
618.1ps   806.2mV    591.4mV    855.8mV
705.4ps   808.9mV    735.4mV    857.7mV
1.434ns   814mV      769.7mV    859.8mV
[Falling Waveform]
R_fixture = 50
V_fixture = 1.5
V_fixture_min = 1.425
V_fixture_max = 1.575
0s        1.501V     1.424V     1.574V
142.5ps   1.501V     1.424V     1.574V
218.5ps   1.505V     1.424V     968.4mV
265.3ps   1.496V     1.424V     823.1mV
313ps     1.177V     1.424V     772.6mV
390ps     796mV      1.424V     746.1mV
510.9ps   704.3mV    1.424V     733.9mV
627.2ps   693.1mV    842mV      728.8mV
702.9ps   690.4mV    691.6mV    726.9mV
1.37ns    683.8mV    643.6mV    724.7mV
[Falling Waveform]
R_fixture = 50
V_fixture = 0
V_fixture_min = 0
V_fixture_max = 0
0s        818.9mV    775.3mV    860.2mV
131.7ps   818.9mV    775.3mV    845mV
195.2ps   818.9mV    775.3mV    216.8mV
242.7ps   798.8mV    775.3mV    80.79mV
279.3ps   521.4mV    775.3mV    46.45mV
340.6ps   121.7mV    775.3mV    23.59mV
463.3ps   23.44mV    750.5mV    7.987mV
563.4ps   13.21mV    206.3mV    3.911mV
636.6ps   10mV       44.01mV    2.508mV
1.434ns   3.309mV    3.863mV    0V
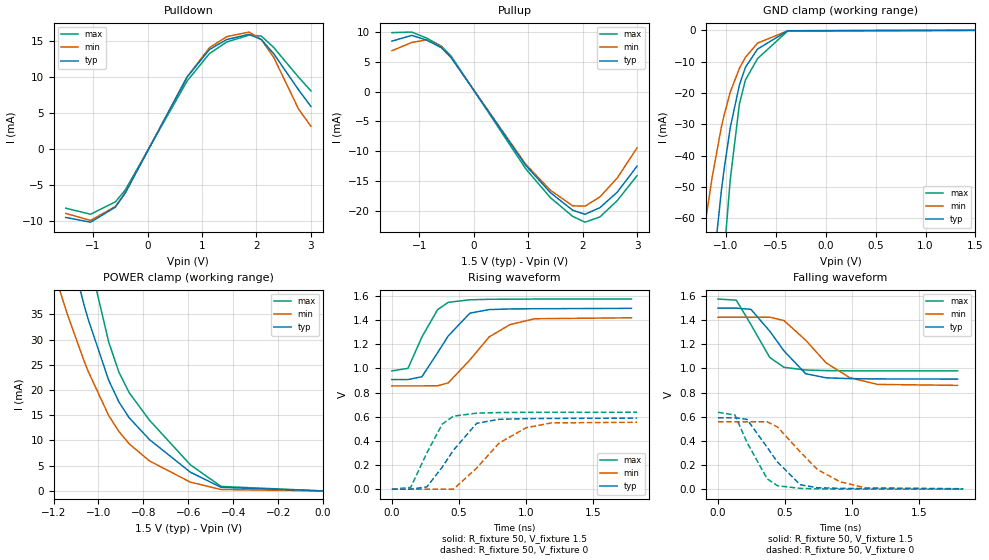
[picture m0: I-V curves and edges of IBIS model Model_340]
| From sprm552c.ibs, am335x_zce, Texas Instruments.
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| Model based on original model for BCSHTLTCSCDVPBFZ_SSDHV
|   Sub model SR01_5MA_5PER_1P5
[model]   Model_340
|[Description]  [1.5V-3-STATE-NOTERM-SR01:5MA, IND, 5%]
|   Slow slew rate (SR[1:0] = "01"), 1.60 * RExt = 0.625 * Iout
|   (I[2:0] = "000"), 5mA nominal with Rext = 50R,ODT off (ODT[1:0]
|   = "00") CMOS mode,Industrial temperature range (-40C to 125C,
|   25C nominal),5% power supply tolerance
|[Input Load]   NOTERM
|[Output Drive] SR01:5MA
|Voltage   1.5V
|Mode   3-STATE
Model_type   3-state
Polarity   Non-Inverting
Enable   Active-Low
Cref =  15pF
Rref =  100.0000M
Vref =  0V
Vmeas =  0.75
C_comp   1.865048p   1.679967p   1.989968p
[Temperature Range]   25   125   -40
[Voltage Range]   1.5   1.425   1.575
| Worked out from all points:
|   slope of the pulldown table from 0 to 0.225 V, typ, clamps not added: 67.2 ohm
|   slope of the pullup table from 0 to 0.225 V, typ, clamps not added: 72 ohm
|   GND clamp passes 1 mA (typ) near -0.49 V on its own axis
|   POWER clamp passes 1 mA (typ) near -0.47 V on its own axis
|   rising waveform, R_fixture 50, V_fixture 1.5: 20-80 % time 209ps typ, 273ps min, 155ps max; typ from 0.908 V to 1.5 V
|   rising waveform, R_fixture 50, V_fixture 0: 20-80 % time 219ps typ, 300ps min, 164ps max; typ from 0 V to 0.588 V
|   falling waveform, R_fixture 50, V_fixture 1.5: 20-80 % time 238ps typ, 308ps min, 177ps max; typ from 1.5 V to 0.911 V
|   falling waveform, R_fixture 50, V_fixture 0: 20-80 % time 228ps typ, 303ps min, 169ps max; typ from 0.591 V to 0.003 V
[POWER_clamp]
-1.5V     126mA      88.76mA    168.8mA
-1.242V   69.8mA     49.43mA    94.36mA
-1.136V   49.16mA    34.7mA     67.53mA
-1.061V   36.35mA    25.39mA    50.04mA
-1.045V   33.92mA    23.62mA    46.67mA
-954.5mV  21.93mA    14.94mA    29.52mA
-909.1mV  17.64mA    11.78mA    23.53mA
-863.6mV  14.51mA    9.346mA    19.48mA
-772.7mV  10.16mA    5.937mA    14mA
-590.9mV  3.705mA    1.741mA    5.168mA
-454.5mV  710.5uA    279.1uA    892.2uA
0V        1.424nA    14.75nA    2.169nA
[Pulldown]
-1.5V     -9.559mA   -9.005mA   -8.281mA
-1.045V   -10.22mA   -9.975mA   -9.117mA
-590.9mV  -8.133mA   -8.04mA    -7.408mA
-409.1mV  -6.182mA   -6.122mA   -5.755mA
727.3mV   9.928mA    9.954mA    9.38mA
1.136V    13.74mA    13.99mA    13.18mA
1.455V    15.14mA    15.54mA    14.8mA
1.864V    15.86mA    16.17mA    15.75mA
2.091V    15.13mA    15.12mA    15.61mA
2.318V    13.15mA    12.64mA    14.03mA
2.773V    8.157mA    5.489mA    9.905mA
3V        5.846mA    3.092mA    8.007mA
[Pullup]
-1.5V     8.494mA    6.876mA    9.92mA
-1.136V   9.455mA    8.27mA     10.01mA
-863.6mV  8.671mA    8.683mA    9.007mA
-590.9mV  7.379mA    7.572mA    7.643mA
-409.1mV  5.694mA    5.688mA    5.925mA
954.5mV   -12.36mA   -12.18mA   -12.93mA
1.409V    -16.96mA   -16.56mA   -17.81mA
1.818V    -19.92mA   -19.18mA   -20.95mA
2.045V    -20.6mA    -19.23mA   -21.93mA
2.318V    -19.49mA   -17.69mA   -21.05mA
2.636V    -16.89mA   -14.51mA   -18.31mA
3V        -12.52mA   -9.441mA   -14.11mA
[GND_clamp]
-1.5V     -219.3mA   -131.6mA   -364.3mA
-1.288V   -134.4mA   -79.74mA   -225.6mA
-1.258V   -122.9mA   -72.77mA   -206.3mA
-1.136V   -79.27mA   -46.88mA   -132.4mA
-1.045V   -51.5mA    -31.06mA   -84.11mA
-1.015V   -44.02mA   -26.9mA    -70.91mA
-954.5mV  -31.01mA   -19.7mA    -47.55mA
-863.6mV  -17.48mA   -12.16mA   -23.55mA
-803mV    -11.81mA   -8.597mA   -15.85mA
-681.8mV  -5.986mA   -4.096mA   -9.026mA
-378.8mV  -126.2uA   -131.8uA   -179.7uA
1.5V      1.424nA    36.56nA    1.506nA
[Ramp]
dV/dt_f 0.35636285/0.24125508n 0.34201623/0.31186814n 0.35808986/0.17786593n
dV/dt_r 0.35610784/0.22165732n 0.33559475/0.30317755n 0.38320771/0.16366975n
R_load = 50
[Rising Waveform]
R_fixture = 50
V_fixture = 1.5
V_fixture_min = 1.425
V_fixture_max = 1.575
0s        908.2mV    855.7mV    980.1mV
120.1ps   908.2mV    855.7mV    1.001V
223.6ps   931.4mV    855.7mV    1.26V
340.6ps   1.13V      856.7mV    1.487V
420.2ps   1.269V     880.4mV    1.548V
581.3ps   1.458V     1.07V      1.569V
725.2ps   1.488V     1.261V     1.573V
880ps     1.493V     1.363V     1.574V
1.065ns   1.495V     1.412V     1.575V
1.787ns   1.498V     1.42V      1.575V
[Rising Waveform]
R_fixture = 50
V_fixture = 0
V_fixture_min = 0
V_fixture_max = 0
0s        0V         0V         0V
140.1ps   0V         0V         13.95mV
260.9ps   18.62mV    0V         300.8mV
376.3ps   183.9mV    0V         540.2mV
459.3ps   323.3mV    0V         605mV
632.3ps   545.6mV    174.9mV    629.7mV
800.1ps   579mV      382.3mV    634.7mV
1.001ns   584.2mV    508.9mV    636.5mV
1.191ns   586.1mV    549mV      637mV
1.829ns   588.3mV    554.3mV    637.3mV
[Falling Waveform]
R_fixture = 50
V_fixture = 1.5
V_fixture_min = 1.425
V_fixture_max = 1.575
0s        1.499V     1.424V     1.574V
136ps     1.499V     1.424V     1.565V
245.2ps   1.489V     1.424V     1.363V
386ps     1.308V     1.424V     1.09V
492ps     1.145V     1.396V     1.009V
653.3ps   956.2mV    1.234V     986.6mV
806.3ps   921.9mV    1.046V     981.7mV
981.7ps   915.4mV    924mV      980mV
1.191ns   912.7mV    867.3mV    979.4mV
1.787ns   911.4mV    859.4mV    979.2mV
[Falling Waveform]
R_fixture = 50
V_fixture = 0
V_fixture_min = 0
V_fixture_max = 0
0s        591mV      558.4mV    636.3mV
126.3ps   591mV      558.4mV    614mV
215.2ps   578.9mV    558.4mV    389.2mV
366.4ps   346.7mV    558.4mV    85.6mV
443.8ps   224mV      514.9mV    28.49mV
614.1ps   36.56mV    307.3mV    6.341mV
741.9ps   11.89mV    162.4mV    2.866mV
910.1ps   6.834mV    61.33mV    0V
1.098ns   5.104mV    11.8mV     0V
1.829ns   2.737mV    3.623mV    0V
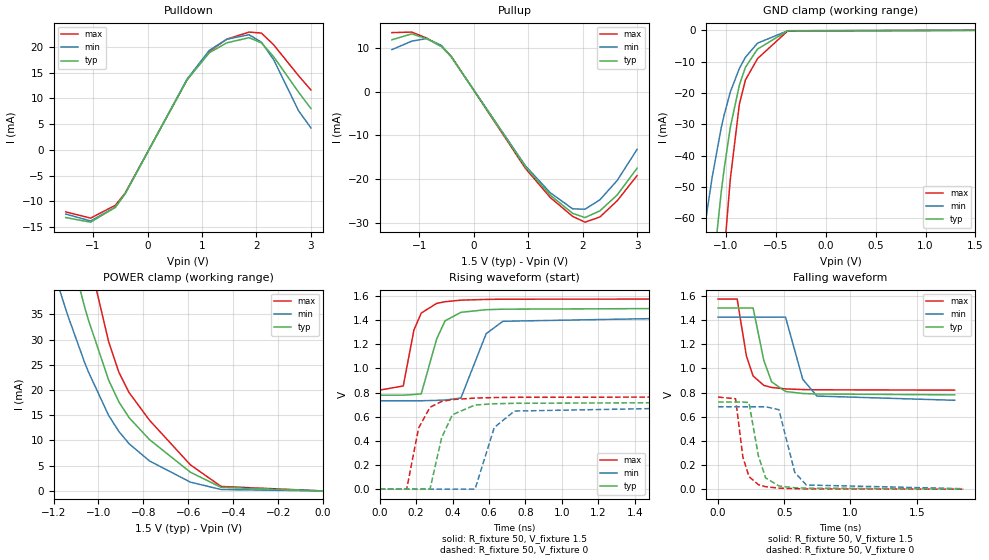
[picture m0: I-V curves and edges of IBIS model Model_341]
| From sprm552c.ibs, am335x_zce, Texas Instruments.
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| Model based on original model for BCSHTLTCSCDVPBFZ_SSDHV
|   Sub model SR00_7MA_5PER_1P5
[model]   Model_341
|[Description]  [1.5V-3-STATE-NOTERM-SR00:7MA, IND, 5%]
|   Fastest slew rate (SR[1:0] = "00"), 1.14 * RExt = 0.875 * Iout
|   (I[2:0] = "010"), 7mA nominal with Rext = 50R,ODT off (ODT[1:0]
|   = "00") CMOS mode,Industrial temperature range (-40C to 125C,
|   25C nominal),5% power supply tolerance
|[Input Load]   NOTERM
|[Output Drive] SR00:7MA
|Voltage   1.5V
|Mode   3-STATE
Model_type   3-state
Polarity   Non-Inverting
Enable   Active-Low
Cref =  15pF
Rref =  100.0000M
Vref =  0V
Vmeas =  0.75
C_comp   1.865048p   1.679967p   1.989968p
[Temperature Range]   25   125   -40
[Voltage Range]   1.5   1.425   1.575
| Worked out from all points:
|   slope of the pulldown table from 0 to 0.225 V, typ, clamps not added: 48.9 ohm
|   slope of the pullup table from 0 to 0.225 V, typ, clamps not added: 51.5 ohm
|   GND clamp passes 1 mA (typ) near -0.49 V on its own axis
|   POWER clamp passes 1 mA (typ) near -0.47 V on its own axis
|   rising waveform, R_fixture 50, V_fixture 1.5: 20-80 % time 76.4ps typ, 97.9ps min, 65.8ps max; typ from 0.779 V to 1.5 V
|   rising waveform, R_fixture 50, V_fixture 0: 20-80 % time 77.3ps typ, 87ps min, 70.9ps max; typ from 0 V to 0.718 V
|   falling waveform, R_fixture 50, V_fixture 1.5: 20-80 % time 90.1ps typ, 107ps min, 79.8ps max; typ from 1.5 V to 0.781 V
|   falling waveform, R_fixture 50, V_fixture 0: 20-80 % time 69ps typ, 84.5ps min, 62.1ps max; typ from 0.721 V to 0.002 V
[POWER_clamp]
-1.5V     126mA      88.76mA    168.8mA
-1.242V   69.8mA     49.43mA    94.36mA
-1.136V   49.16mA    34.7mA     67.53mA
-1.061V   36.35mA    25.39mA    50.04mA
-1.045V   33.92mA    23.62mA    46.67mA
-954.5mV  21.93mA    14.94mA    29.52mA
-909.1mV  17.64mA    11.78mA    23.53mA
-863.6mV  14.51mA    9.346mA    19.48mA
-772.7mV  10.16mA    5.937mA    14mA
-590.9mV  3.705mA    1.741mA    5.168mA
-454.5mV  710.5uA    279.1uA    892.2uA
0V        1.424nA    14.75nA    2.169nA
[Pulldown]
-1.5V     -13.15mA   -12.47mA   -12.05mA
-1.045V   -14.05mA   -13.81mA   -13.26mA
-590.9mV  -11.18mA   -11.13mA   -10.77mA
-409.1mV  -8.496mA   -8.472mA   -8.367mA
727.3mV   13.64mA    13.78mA    13.64mA
1.136V    18.89mA    19.36mA    19.16mA
1.455V    20.81mA    21.51mA    21.52mA
1.864V    21.81mA    22.39mA    22.9mA
2.091V    20.81mA    20.94mA    22.71mA
2.318V    18.08mA    17.5mA     20.41mA
2.773V    11.22mA    7.604mA    14.41mA
3V        8.041mA    4.283mA    11.65mA
[Pullup]
-1.5V     11.89mA    9.627mA    13.53mA
-1.136V   13.24mA    11.58mA    13.65mA
-863.6mV  12.14mA    12.16mA    12.28mA
-590.9mV  10.33mA    10.6mA     10.42mA
-409.1mV  7.967mA    7.959mA    8.076mA
954.5mV   -17.3mA    -17.04mA   -17.63mA
1.409V    -23.74mA   -23.18mA   -24.27mA
1.818V    -27.88mA   -26.84mA   -28.57mA
2.045V    -28.84mA   -26.93mA   -29.9mA
2.318V    -27.3mA    -24.77mA   -28.71mA
2.636V    -23.65mA   -20.33mA   -24.98mA
3V        -17.54mA   -13.23mA   -19.24mA
[GND_clamp]
-1.5V     -219.3mA   -131.6mA   -364.3mA
-1.288V   -134.4mA   -79.74mA   -225.6mA
-1.258V   -122.9mA   -72.77mA   -206.3mA
-1.136V   -79.27mA   -46.88mA   -132.4mA
-1.045V   -51.5mA    -31.06mA   -84.11mA
-1.015V   -44.02mA   -26.9mA    -70.91mA
-954.5mV  -31.01mA   -19.7mA    -47.55mA
-863.6mV  -17.48mA   -12.16mA   -23.55mA
-803mV    -11.81mA   -8.597mA   -15.85mA
-681.8mV  -5.986mA   -4.096mA   -9.026mA
-378.8mV  -126.2uA   -131.8uA   -179.7uA
1.5V      1.424nA    36.56nA    1.506nA
[Ramp]
dV/dt_f 0.44135267/91.226498p 0.42583267/0.10521335n 0.45884276/79.969184p
dV/dt_r 0.44086514/78.141828p 0.42113937/88.127294p 0.46424842/70.94302p
R_load = 50
[Rising Waveform]
R_fixture = 50
V_fixture = 1.5
V_fixture_min = 1.425
V_fixture_max = 1.575
0s        778.7mV    732.5mV    821mV
129.5ps   778.7mV    732.5mV    854.9mV
188ps     784.3mV    732.5mV    1.318V
228.1ps   789.7mV    732.5mV    1.459V
312.6ps   1.244V     735.8mV    1.539V
359ps     1.395V     738.8mV    1.553V
445.6ps   1.465V     755.1mV    1.566V
584.2ps   1.487V     1.288V     1.572V
675.8ps   1.491V     1.391V     1.574V
1.787ns   1.498V     1.421V     1.575V
[Rising Waveform]
R_fixture = 50
V_fixture = 0
V_fixture_min = 0
V_fixture_max = 0
0s        0V         0V         0V
148.2ps   0V         0V         0V
213.8ps   0V         0V         507mV
276.1ps   0V         0V         678.4mV
339.8ps   425mV      0V         726.3mV
398.6ps   616.5mV    0V         742.1mV
523.3ps   697.4mV    0V         754.8mV
628.7ps   707.7mV    511.2mV    759mV
739.6ps   711.2mV    647.2mV    761.1mV
1.851ns   718.3mV    677.4mV    763.3mV
[Falling Waveform]
R_fixture = 50
V_fixture = 1.5
V_fixture_min = 1.425
V_fixture_max = 1.575
0s        1.5V       1.424V     1.574V
144.4ps   1.5V       1.424V     1.574V
214ps     1.5V       1.424V     1.104V
265ps     1.5V       1.424V     937.1mV
345.3ps   1.067V     1.424V     859.7mV
404.7ps   888.1mV    1.424V     842.2mV
509.6ps   808.9mV    1.424V     830mV
639.8ps   792.1mV    909.5mV    824.6mV
746.6ps   788.1mV    770.9mV    822.7mV
1.787ns   780.9mV    735.9mV    820.1mV
[Falling Waveform]
R_fixture = 50
V_fixture = 0
V_fixture_min = 0
V_fixture_max = 0
0s        721.4mV    682.4mV    762.7mV
132.5ps   721.4mV    682.4mV    748.3mV
187.4ps   721.4mV    682.4mV    266.6mV
233.5ps   717.2mV    682.4mV    104.2mV
304.6ps   276.5mV    682.4mV    37.41mV
359.2ps   93.77mV    682.4mV    20.47mV
459.6ps   26.11mV    658.1mV    8.557mV
578.9ps   11.76mV    139.6mV    3.875mV
666.7ps   8.585mV    34.52mV    2.331mV
1.851ns   2.458mV    4.085mV    0V
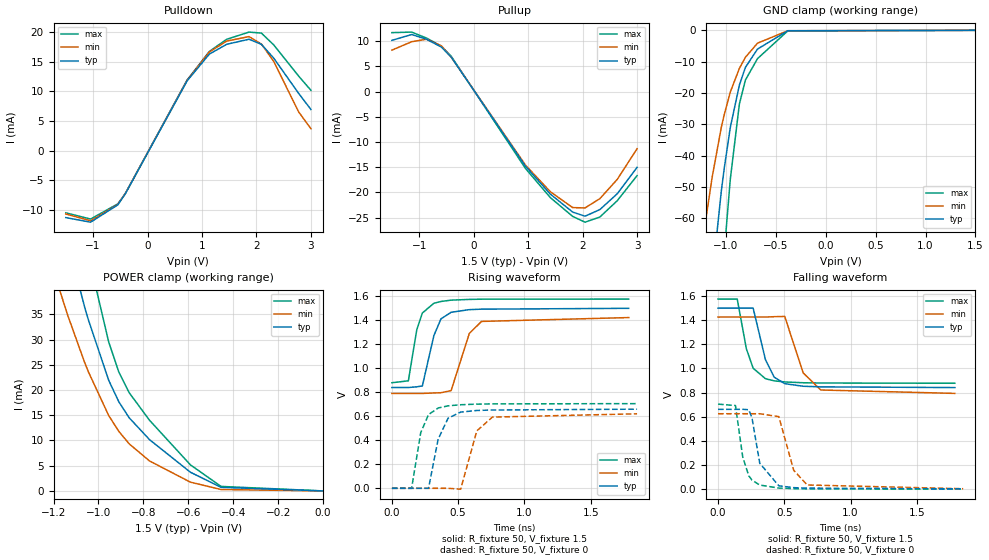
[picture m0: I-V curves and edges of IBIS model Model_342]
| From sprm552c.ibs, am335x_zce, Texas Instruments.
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| Model based on original model for BCSHTLTCSCDVPBFZ_SSDHV
|   Sub model SR00_6MA_5PER_1P5
[model]   Model_342
|[Description]  [1.5V-3-STATE-NOTERM-SR00:6MA, IND, 5%]
|   Fastest slew rate (SR[1:0] = "00"), 1.33 * RExt = 0.750 * Iout
|   (I[2:0] = "001"), 6mA nominal with Rext = 50R,ODT off (ODT[1:0]
|   = "00") CMOS mode,Industrial temperature range (-40C to 125C,
|   25C nominal),5% power supply tolerance
|[Input Load]   NOTERM
|[Output Drive] SR00:6MA
|Voltage   1.5V
|Mode   3-STATE
Model_type   3-state
Polarity   Non-Inverting
Enable   Active-Low
Cref =  15pF
Rref =  100.0000M
Vref =  0V
Vmeas =  0.75
C_comp   1.865048p   1.679967p   1.989968p
[Temperature Range]   25   125   -40
[Voltage Range]   1.5   1.425   1.575
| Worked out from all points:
|   slope of the pulldown table from 0 to 0.225 V, typ, clamps not added: 56.6 ohm
|   slope of the pullup table from 0 to 0.225 V, typ, clamps not added: 60 ohm
|   GND clamp passes 1 mA (typ) near -0.49 V on its own axis
|   POWER clamp passes 1 mA (typ) near -0.47 V on its own axis
|   rising waveform, R_fixture 50, V_fixture 1.5: 20-80 % time 82.2ps typ, 103ps min, 70.7ps max; typ from 0.839 V to 1.5 V
|   rising waveform, R_fixture 50, V_fixture 0: 20-80 % time 84.6ps typ, 93.6ps min, 76.5ps max; typ from 0 V to 0.659 V
|   falling waveform, R_fixture 50, V_fixture 1.5: 20-80 % time 97.8ps typ, 113ps min, 85.9ps max; typ from 1.5 V to 0.842 V
|   falling waveform, R_fixture 50, V_fixture 0: 20-80 % time 74.1ps typ, 90.1ps min, 66.6ps max; typ from 0.661 V to 0.003 V
[POWER_clamp]
-1.5V     126mA      88.76mA    168.8mA
-1.242V   69.8mA     49.43mA    94.36mA
-1.136V   49.16mA    34.7mA     67.53mA
-1.061V   36.35mA    25.39mA    50.04mA
-1.045V   33.92mA    23.62mA    46.67mA
-954.5mV  21.93mA    14.94mA    29.52mA
-909.1mV  17.64mA    11.78mA    23.53mA
-863.6mV  14.51mA    9.346mA    19.48mA
-772.7mV  10.16mA    5.937mA    14mA
-590.9mV  3.705mA    1.741mA    5.168mA
-454.5mV  710.5uA    279.1uA    892.2uA
0V        1.424nA    14.75nA    2.169nA
[Pulldown]
-1.5V     -11.35mA   -10.74mA   -10.54mA
-1.045V   -12.13mA   -11.89mA   -11.6mA
-545.5mV  -9.204mA   -9.133mA   -9.027mA
-409.1mV  -7.34mA    -7.297mA   -7.323mA
727.3mV   11.79mA    11.87mA    11.94mA
1.136V    16.32mA    16.68mA    16.77mA
1.455V    17.98mA    18.52mA    18.83mA
1.864V    18.83mA    19.28mA    20.04mA
2.091V    17.97mA    18.02mA    19.87mA
2.318V    15.62mA    15.07mA    17.86mA
2.773V    9.688mA    6.547mA    12.61mA
3V        6.943mA    3.687mA    10.19mA
[Pullup]
-1.5V     10.19mA    8.251mA    11.72mA
-1.136V   11.35mA    9.924mA    11.83mA
-863.6mV  10.4mA     10.42mA    10.64mA
-590.9mV  8.854mA    9.085mA    9.032mA
-409.1mV  6.831mA    6.824mA    7.001mA
954.5mV   -14.83mA   -14.61mA   -15.28mA
1.409V    -20.35mA   -19.87mA   -21.04mA
1.818V    -23.9mA    -23.01mA   -24.76mA
2.045V    -24.72mA   -23.08mA   -25.91mA
2.318V    -23.4mA    -21.23mA   -24.88mA
2.636V    -20.27mA   -17.42mA   -21.65mA
3V        -15.03mA   -11.33mA   -16.67mA
[GND_clamp]
-1.5V     -219.3mA   -131.6mA   -364.3mA
-1.288V   -134.4mA   -79.74mA   -225.6mA
-1.258V   -122.9mA   -72.77mA   -206.3mA
-1.136V   -79.27mA   -46.88mA   -132.4mA
-1.045V   -51.5mA    -31.06mA   -84.11mA
-1.015V   -44.02mA   -26.9mA    -70.91mA
-954.5mV  -31.01mA   -19.7mA    -47.55mA
-863.6mV  -17.48mA   -12.16mA   -23.55mA
-803mV    -11.81mA   -8.597mA   -15.85mA
-681.8mV  -5.986mA   -4.096mA   -9.026mA
-378.8mV  -126.2uA   -131.8uA   -179.7uA
1.5V      1.424nA    36.56nA    1.506nA
[Ramp]
dV/dt_f 0.40407941/98.603596p 0.39022027/0.11333133n 0.42375971/86.116457p
dV/dt_r  0.4039332/84.643953p 0.38504121/95.450503p 0.42822413/76.616015p
R_load = 50
[Rising Waveform]
R_fixture = 50
V_fixture = 1.5
V_fixture_min = 1.425
V_fixture_max = 1.575
0s        838.8mV    789.6mV    878.5mV
124.2ps   838.8mV    789.6mV    894.6mV
187.5ps   844.5mV    789.6mV    1.319V
229.8ps   852.1mV    789.6mV    1.459V
316.7ps   1.271V     793.5mV    1.54V
370.2ps   1.41V      795.4mV    1.555V
446.9ps   1.465V     813.4mV    1.566V
583.9ps   1.487V     1.288V     1.572V
676ps     1.491V     1.389V     1.574V
1.787ns   1.498V     1.421V     1.575V
[Rising Waveform]
R_fixture = 50
V_fixture = 0
V_fixture_min = 0
V_fixture_max = 0
0s        0V         0V         0V
148.7ps   0V         0V         0V
217.4ps   0V         0V         462.5mV
276.3ps   0V         0V         613.6mV
349.1ps   409.5mV    0V         668.4mV
424ps     583.4mV    0V         686.4mV
518.8ps   634.1mV    -7.194mV   695.5mV
640.7ps   647.8mV    477.5mV    700.5mV
758.2ps   651.6mV    592.6mV    702.7mV
1.85ns    658.6mV    620mV      704.7mV
[Falling Waveform]
R_fixture = 50
V_fixture = 1.5
V_fixture_min = 1.425
V_fixture_max = 1.575
0s        1.5V       1.426V     1.575V
145ps     1.5V       1.426V     1.575V
213.6ps   1.5V       1.426V     1.164V
265ps     1.5V       1.426V     1.002V
358ps     1.072V     1.426V     915.1mV
423.5ps   928.1mV    1.429V     897.6mV
503.4ps   874.1mV    1.431V     888.3mV
642.6ps   852.6mV    963.3mV    881.7mV
775.2ps   847.6mV    821.6mV    879.4mV
1.787ns   841.7mV    793.4mV    877.5mV
[Falling Waveform]
R_fixture = 50
V_fixture = 0
V_fixture_min = 0
V_fixture_max = 0
0s        661.4mV    624.9mV    704.6mV
131.5ps   661.4mV    624.9mV    692.8mV
186.6ps   661.4mV    624.9mV    265.5mV
232ps     658.3mV    624.9mV    110.3mV
256.5ps   588.8mV    624.9mV    74.57mV
314.8ps   215.1mV    624.9mV    34.33mV
458.7ps   27.56mV    600.9mV    8.991mV
571.1ps   12.52mV    156.3mV    4.272mV
673ps     8.623mV    34.6mV     2.371mV
1.85ns    2.881mV    3.708mV    0V
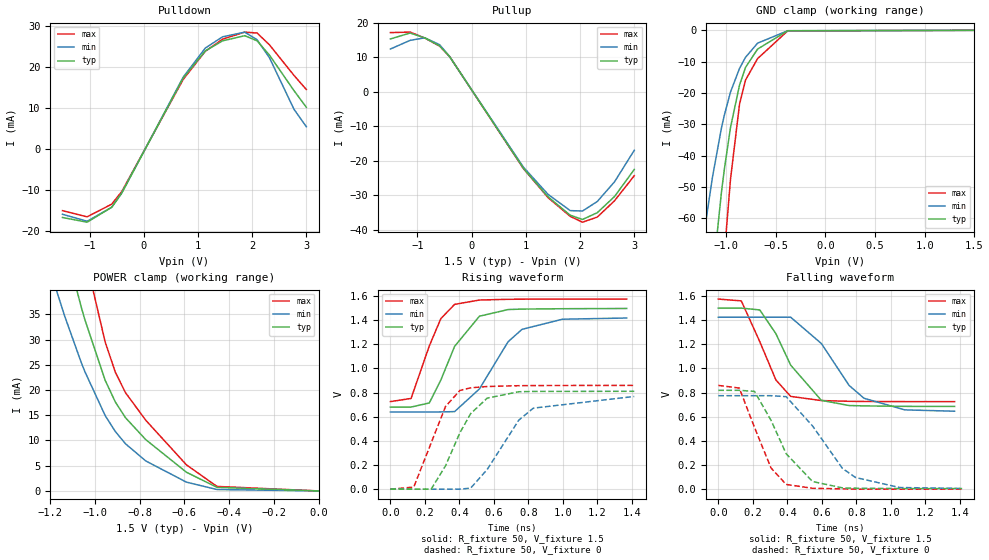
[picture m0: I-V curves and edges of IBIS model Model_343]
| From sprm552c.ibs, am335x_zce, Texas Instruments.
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| Model based on original model for BCSHTLTCSCDVPBFZ_SSDHV
|   Sub model SR01_9MA_5PER_1P5
[model]   Model_343
|[Description]  [1.5V-3-STATE-NOTERM-SR01:9MA, IND, 5%]
|   Slow slew rate (SR[1:0] = "01"), 0.88 * RExt = 1.125 * Iout
|   (I[2:0] = "100"), 9mA nominal with Rext = 50R,ODT off (ODT[1:0]
|   = "00") CMOS mode,Industrial temperature range (-40C to 125C,
|   25C nominal),5% power supply tolerance
|[Input Load]   NOTERM
|[Output Drive] SR01:9MA
|Voltage   1.5V
|Mode   3-STATE
Model_type   3-state
Polarity   Non-Inverting
Enable   Active-Low
Cref =  15pF
Rref =  100.0000M
Vref =  0V
Vmeas =  0.75
C_comp   1.865048p   1.679967p   1.989968p
[Temperature Range]   25   125   -40
[Voltage Range]   1.5   1.425   1.575
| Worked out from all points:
|   slope of the pulldown table from 0 to 0.225 V, typ, clamps not added: 38.4 ohm
|   slope of the pullup table from 0 to 0.225 V, typ, clamps not added: 40.1 ohm
|   GND clamp passes 1 mA (typ) near -0.49 V on its own axis
|   POWER clamp passes 1 mA (typ) near -0.47 V on its own axis
|   rising waveform, R_fixture 50, V_fixture 1.5: 20-80 % time 159ps typ, 210ps min, 129ps max; typ from 0.68 V to 1.5 V
|   rising waveform, R_fixture 50, V_fixture 0: 20-80 % time 169ps typ, 216ps min, 135ps max; typ from 0 V to 0.811 V
|   falling waveform, R_fixture 50, V_fixture 1.5: 20-80 % time 184ps typ, 234ps min, 146ps max; typ from 1.5 V to 0.685 V
|   falling waveform, R_fixture 50, V_fixture 0: 20-80 % time 176ps typ, 231ps min, 140ps max; typ from 0.818 V to 0.005 V
[POWER_clamp]
-1.5V     126mA      88.76mA    168.8mA
-1.242V   69.8mA     49.43mA    94.36mA
-1.136V   49.16mA    34.7mA     67.53mA
-1.061V   36.35mA    25.39mA    50.04mA
-1.045V   33.92mA    23.62mA    46.67mA
-954.5mV  21.93mA    14.94mA    29.52mA
-909.1mV  17.64mA    11.78mA    23.53mA
-863.6mV  14.51mA    9.346mA    19.48mA
-772.7mV  10.16mA    5.937mA    14mA
-590.9mV  3.705mA    1.741mA    5.168mA
-454.5mV  710.5uA    279.1uA    892.2uA
0V        1.424nA    14.75nA    2.169nA
[Pulldown]
-1.5V     -16.73mA   -15.94mA   -15.06mA
-1.045V   -17.88mA   -17.65mA   -16.57mA
-590.9mV  -14.22mA   -14.22mA   -13.46mA
-409.1mV  -10.81mA   -10.82mA   -10.45mA
727.3mV   17.36mA    17.6mA     17.04mA
1.136V    24.04mA    24.73mA    23.94mA
1.455V    26.49mA    27.48mA    26.9mA
1.864V    27.75mA    28.61mA    28.63mA
2.091V    26.49mA    26.76mA    28.4mA
2.318V    23.02mA    22.38mA    25.53mA
2.773V    14.29mA    9.722mA    18.02mA
3V        10.24mA    5.474mA    14.57mA
[Pullup]
-1.5V     15.3mA     12.38mA    17.14mA
-1.136V   17.02mA    14.89mA    17.29mA
-863.6mV  15.6mA     15.63mA    15.55mA
-590.9mV  13.28mA    13.62mA    13.2mA
-409.1mV  10.24mA    10.23mA    10.22mA
954.5mV   -22.23mA   -21.9mA    -22.32mA
1.409V    -30.51mA   -29.79mA   -30.74mA
1.818V    -35.84mA   -34.51mA   -36.18mA
2.045V    -37.08mA   -34.63mA   -37.87mA
2.318V    -35.11mA   -31.86mA   -36.38mA
2.636V    -30.42mA   -26.15mA   -31.65mA
3V        -22.57mA   -17.01mA   -24.39mA
[GND_clamp]
-1.5V     -219.3mA   -131.6mA   -364.3mA
-1.288V   -134.4mA   -79.74mA   -225.6mA
-1.258V   -122.9mA   -72.77mA   -206.3mA
-1.136V   -79.27mA   -46.88mA   -132.4mA
-1.045V   -51.5mA    -31.06mA   -84.11mA
-1.015V   -44.02mA   -26.9mA    -70.91mA
-954.5mV  -31.01mA   -19.7mA    -47.55mA
-863.6mV  -17.48mA   -12.16mA   -23.55mA
-803mV    -11.81mA   -8.597mA   -15.85mA
-681.8mV  -5.986mA   -4.096mA   -9.026mA
-378.8mV  -126.2uA   -131.8uA   -179.7uA
1.5V      1.424nA    36.56nA    1.506nA
[Ramp]
dV/dt_f 0.49355356/0.18680775n 0.47252411/0.23737663n 0.51158067/0.14672791n
dV/dt_r 0.49296482/0.17272264n 0.46637719/0.21765524n  0.5177395/0.13542822n
R_load = 50
[Rising Waveform]
R_fixture = 50
V_fixture = 1.5
V_fixture_min = 1.425
V_fixture_max = 1.575
0s        680.3mV    639.4mV    725.3mV
120ps     680.3mV    639.4mV    751.7mV
225.7ps   714.4mV    639.4mV    1.187V
292.7ps   904.6mV    640mV      1.413V
372.3ps   1.183V     642.6mV    1.531V
516.3ps   1.433V     830.6mV    1.567V
682.2ps   1.488V     1.221V     1.573V
763ps     1.492V     1.324V     1.574V
997.3ps   1.495V     1.408V     1.575V
1.37ns    1.497V     1.418V     1.575V
[Rising Waveform]
R_fixture = 50
V_fixture = 0
V_fixture_min = 0
V_fixture_max = 0
0s        0V         0V         0V
135.4ps   0V         0V         17.13mV
236.5ps   0V         0V         383.6mV
319.4ps   193mV      0V         684.1mV
403.2ps   467.7mV    0V         818.1mV
465.4ps   625.8mV    8.755mV    839.8mV
561.4ps   754.3mV    163.2mV    850.6mV
744.6ps   807.1mV    572.3mV    857.2mV
829.1ps   809.6mV    671.4mV    858.5mV
1.414ns   810.9mV    768.2mV    859.9mV
[Falling Waveform]
R_fixture = 50
V_fixture = 1.5
V_fixture_min = 1.425
V_fixture_max = 1.575
0s        1.499V     1.424V     1.574V
133.3ps   1.499V     1.424V     1.559V
240.5ps   1.484V     1.424V     1.221V
334ps     1.287V     1.424V     904mV
419.6ps   1.027V     1.424V     768.2mV
597.5ps   735.3mV    1.206V     733.6mV
758.3ps   692.5mV    859.1mV    727.4mV
844.6ps   689.5mV    752.7mV    726mV
1.081ns   685.6mV    656.6mV    724.9mV
1.37ns    684.9mV    645.4mV    724.9mV
[Falling Waveform]
R_fixture = 50
V_fixture = 0
V_fixture_min = 0
V_fixture_max = 0
0s        818.4mV    773.9mV    859.3mV
121.8ps   818.4mV    773.9mV    836.9mV
209.5ps   809.8mV    773.9mV    512.2mV
305.9ps   569.6mV    773.9mV    175mV
393.5ps   293.2mV    765.9mV    38.93mV
546.4ps   63.21mV    523.5mV    7.329mV
719.6ps   10.73mV    172.1mV    2.329mV
795.9ps   7.881mV    96.44mV    0V
1.051ns   5.04mV     13.7mV     0V
1.414ns   5.04mV     5.831mV    0V
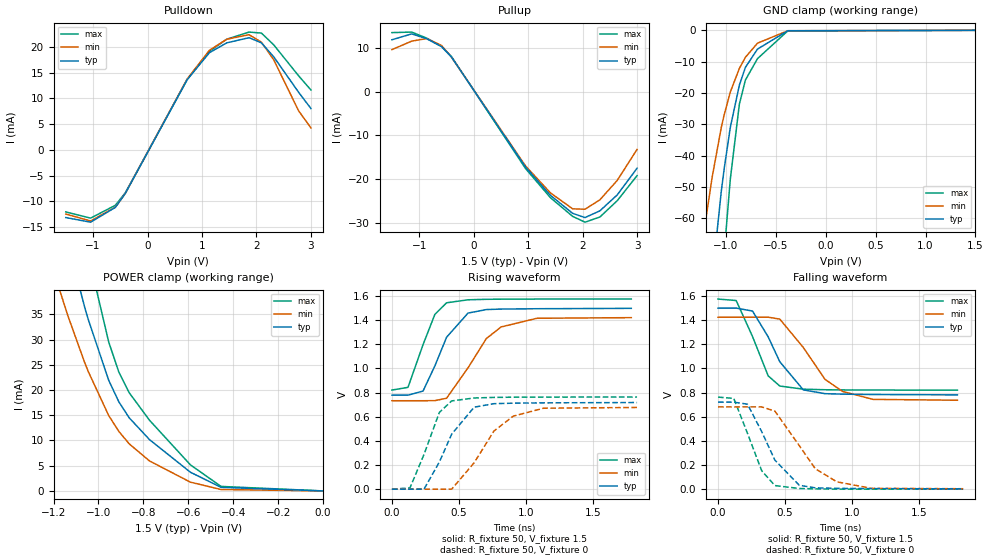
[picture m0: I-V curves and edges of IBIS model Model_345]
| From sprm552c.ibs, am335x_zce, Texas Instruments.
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| Model based on original model for BCSHTLTCSCDVPBFZ_SSDHV
|   Sub model SR01_7MA_5PER_1P5
[model]   Model_345
|[Description]  [1.5V-3-STATE-NOTERM-SR01:7MA, IND, 5%]
|   Slow slew rate (SR[1:0] = "01"), 1.14 * RExt = 0.875 * Iout
|   (I[2:0] = "010"), 7mA nominal with Rext = 50R,ODT off (ODT[1:0]
|   = "00") CMOS mode,Industrial temperature range (-40C to 125C,
|   25C nominal),5% power supply tolerance
|[Input Load]   NOTERM
|[Output Drive] SR01:7MA
|Voltage   1.5V
|Mode   3-STATE
Model_type   3-state
Polarity   Non-Inverting
Enable   Active-Low
Cref =  15pF
Rref =  100.0000M
Vref =  0V
Vmeas =  0.75
C_comp   1.865048p   1.679967p   1.989968p
[Temperature Range]   25   125   -40
[Voltage Range]   1.5   1.425   1.575
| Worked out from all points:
|   slope of the pulldown table from 0 to 0.225 V, typ, clamps not added: 48.9 ohm
|   slope of the pullup table from 0 to 0.225 V, typ, clamps not added: 51.5 ohm
|   GND clamp passes 1 mA (typ) near -0.49 V on its own axis
|   POWER clamp passes 1 mA (typ) near -0.47 V on its own axis
|   rising waveform, R_fixture 50, V_fixture 1.5: 20-80 % time 176ps typ, 236ps min, 144ps max; typ from 0.779 V to 1.5 V
|   rising waveform, R_fixture 50, V_fixture 0: 20-80 % time 190ps typ, 254ps min, 148ps max; typ from 0 V to 0.718 V
|   falling waveform, R_fixture 50, V_fixture 1.5: 20-80 % time 203ps typ, 269ps min, 160ps max; typ from 1.5 V to 0.781 V
|   falling waveform, R_fixture 50, V_fixture 0: 20-80 % time 196ps typ, 258ps min, 154ps max; typ from 0.721 V to 0.003 V
[POWER_clamp]
-1.5V     126mA      88.76mA    168.8mA
-1.242V   69.8mA     49.43mA    94.36mA
-1.136V   49.16mA    34.7mA     67.53mA
-1.061V   36.35mA    25.39mA    50.04mA
-1.045V   33.92mA    23.62mA    46.67mA
-954.5mV  21.93mA    14.94mA    29.52mA
-909.1mV  17.64mA    11.78mA    23.53mA
-863.6mV  14.51mA    9.346mA    19.48mA
-772.7mV  10.16mA    5.937mA    14mA
-590.9mV  3.705mA    1.741mA    5.168mA
-454.5mV  710.5uA    279.1uA    892.2uA
0V        1.424nA    14.75nA    2.169nA
[Pulldown]
-1.5V     -13.15mA   -12.47mA   -12.05mA
-1.045V   -14.05mA   -13.81mA   -13.26mA
-590.9mV  -11.18mA   -11.13mA   -10.77mA
-409.1mV  -8.496mA   -8.472mA   -8.367mA
727.3mV   13.64mA    13.78mA    13.64mA
1.136V    18.89mA    19.36mA    19.16mA
1.455V    20.81mA    21.51mA    21.52mA
1.864V    21.81mA    22.39mA    22.9mA
2.091V    20.81mA    20.94mA    22.71mA
2.318V    18.08mA    17.5mA     20.41mA
2.773V    11.22mA    7.604mA    14.41mA
3V        8.041mA    4.283mA    11.65mA
[Pullup]
-1.5V     11.89mA    9.627mA    13.53mA
-1.136V   13.24mA    11.58mA    13.65mA
-863.6mV  12.14mA    12.16mA    12.28mA
-590.9mV  10.33mA    10.6mA     10.42mA
-409.1mV  7.967mA    7.959mA    8.076mA
954.5mV   -17.3mA    -17.04mA   -17.63mA
1.409V    -23.74mA   -23.18mA   -24.27mA
1.818V    -27.88mA   -26.84mA   -28.57mA
2.045V    -28.84mA   -26.93mA   -29.9mA
2.318V    -27.3mA    -24.77mA   -28.71mA
2.636V    -23.65mA   -20.33mA   -24.98mA
3V        -17.54mA   -13.23mA   -19.24mA
[GND_clamp]
-1.5V     -219.3mA   -131.6mA   -364.3mA
-1.288V   -134.4mA   -79.74mA   -225.6mA
-1.258V   -122.9mA   -72.77mA   -206.3mA
-1.136V   -79.27mA   -46.88mA   -132.4mA
-1.045V   -51.5mA    -31.06mA   -84.11mA
-1.015V   -44.02mA   -26.9mA    -70.91mA
-954.5mV  -31.01mA   -19.7mA    -47.55mA
-863.6mV  -17.48mA   -12.16mA   -23.55mA
-803mV    -11.81mA   -8.597mA   -15.85mA
-681.8mV  -5.986mA   -4.096mA   -9.026mA
-378.8mV  -126.2uA   -131.8uA   -179.7uA
1.5V      1.424nA    36.56nA    1.506nA
[Ramp]
dV/dt_f 0.43436419/0.20452847n 0.41670941/0.27157096n 0.45383468/0.16040708n
dV/dt_r  0.4341809/0.19207268n 0.41035896/0.25478629n 0.45924333/0.14828804n
R_load = 50
[Rising Waveform]
R_fixture = 50
V_fixture = 1.5
V_fixture_min = 1.425
V_fixture_max = 1.575
0s        778.7mV    732.6mV    821mV
120.1ps   778.7mV    732.6mV    843.6mV
232.4ps   812.8mV    732.6mV    1.197V
320.6ps   1.021V     733.5mV    1.448V
408.2ps   1.259V     753.4mV    1.544V
568.5ps   1.459V     1.006V     1.569V
705.3ps   1.488V     1.248V     1.573V
814.9ps   1.492V     1.344V     1.574V
1.084ns   1.495V     1.416V     1.575V
1.787ns   1.498V     1.421V     1.575V
[Rising Waveform]
R_fixture = 50
V_fixture = 0
V_fixture_min = 0
V_fixture_max = 0
0s        0V         0V         0V
134.9ps   0V         0V         10.69mV
239.6ps   0V         0V         287.6mV
354.1ps   224.6mV    0V         635.8mV
446ps     455.1mV    0V         731.2mV
613.8ps   679.2mV    218.4mV    755.4mV
761.7ps   708.3mV    481.8mV    760.2mV
906ps     712.5mV    605.1mV    762mV
1.133ns   715.2mV    670.9mV    762.9mV
1.83ns    717.8mV    676.8mV    763.3mV
[Falling Waveform]
R_fixture = 50
V_fixture = 1.5
V_fixture_min = 1.425
V_fixture_max = 1.575
0s        1.499V     1.424V     1.574V
135.3ps   1.499V     1.424V     1.562V
257.4ps   1.475V     1.424V     1.264V
374.4ps   1.261V     1.424V     938.1mV
461ps     1.055V     1.408V     853.9mV
636.6ps   822mV      1.173V     827.9mV
799ps     790.7mV    908.6mV    823.2mV
929.6ps   786.7mV    809.3mV    821.7mV
1.157ns   783.7mV    743.4mV    820.6mV
1.787ns   780.7mV    736.3mV    820.1mV
[Falling Waveform]
R_fixture = 50
V_fixture = 0
V_fixture_min = 0
V_fixture_max = 0
0s        720.5mV    681.1mV    762.4mV
117.5ps   720.5mV    681.1mV    751.3mV
219.9ps   703.6mV    681.1mV    462mV
326.2ps   476mV      681.1mV    152mV
424.1ps   240.8mV    646.6mV    29.97mV
606.2ps   32.3mV     361mV      5.51mV
726.2ps   10.95mV    169.1mV    2.625mV
886.8ps   6.686mV    60.79mV    0V
1.145ns   4.594mV    6.952mV    0V
1.83ns    2.732mV    3.595mV    0V
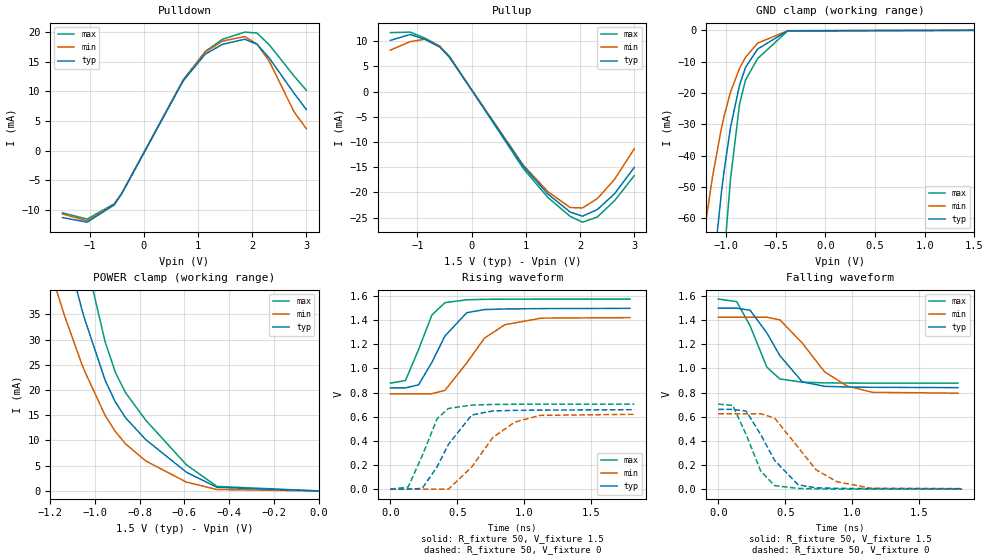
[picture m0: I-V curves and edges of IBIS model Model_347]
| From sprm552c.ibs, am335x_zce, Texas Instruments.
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| Model based on original model for BCSHTLTCSCDVPBFZ_SSDHV
|   Sub model SR01_6MA_5PER_1P5
[model]   Model_347
|[Description]  [1.5V-3-STATE-NOTERM-SR01:6MA, IND, 5%]
|   Slow slew rate (SR[1:0] = "01"), 1.33 * RExt = 0.750 * Iout
|   (I[2:0] = "001"), 6mA nominal with Rext = 50R,ODT off (ODT[1:0]
|   = "00") CMOS mode,Industrial temperature range (-40C to 125C,
|   25C nominal),5% power supply tolerance
|[Input Load]   NOTERM
|[Output Drive] SR01:6MA
|Voltage   1.5V
|Mode   3-STATE
Model_type   3-state
Polarity   Non-Inverting
Enable   Active-Low
Cref =  15pF
Rref =  100.0000M
Vref =  0V
Vmeas =  0.75
C_comp   1.865048p   1.679967p   1.989968p
[Temperature Range]   25   125   -40
[Voltage Range]   1.5   1.425   1.575
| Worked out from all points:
|   slope of the pulldown table from 0 to 0.225 V, typ, clamps not added: 56.6 ohm
|   slope of the pullup table from 0 to 0.225 V, typ, clamps not added: 60 ohm
|   GND clamp passes 1 mA (typ) near -0.49 V on its own axis
|   POWER clamp passes 1 mA (typ) near -0.47 V on its own axis
|   rising waveform, R_fixture 50, V_fixture 1.5: 20-80 % time 191ps typ, 255ps min, 141ps max; typ from 0.839 V to 1.5 V
|   rising waveform, R_fixture 50, V_fixture 0: 20-80 % time 199ps typ, 270ps min, 148ps max; typ from 0 V to 0.658 V
|   falling waveform, R_fixture 50, V_fixture 1.5: 20-80 % time 222ps typ, 290ps min, 155ps max; typ from 1.5 V to 0.841 V
|   falling waveform, R_fixture 50, V_fixture 0: 20-80 % time 208ps typ, 276ps min, 151ps max; typ from 0.661 V to 0.004 V
[POWER_clamp]
-1.5V     126mA      88.76mA    168.8mA
-1.242V   69.8mA     49.43mA    94.36mA
-1.136V   49.16mA    34.7mA     67.53mA
-1.061V   36.35mA    25.39mA    50.04mA
-1.045V   33.92mA    23.62mA    46.67mA
-954.5mV  21.93mA    14.94mA    29.52mA
-909.1mV  17.64mA    11.78mA    23.53mA
-863.6mV  14.51mA    9.346mA    19.48mA
-772.7mV  10.16mA    5.937mA    14mA
-590.9mV  3.705mA    1.741mA    5.168mA
-454.5mV  710.5uA    279.1uA    892.2uA
0V        1.424nA    14.75nA    2.169nA
[Pulldown]
-1.5V     -11.35mA   -10.74mA   -10.54mA
-1.045V   -12.13mA   -11.89mA   -11.6mA
-545.5mV  -9.204mA   -9.133mA   -9.027mA
-409.1mV  -7.34mA    -7.297mA   -7.323mA
727.3mV   11.79mA    11.87mA    11.94mA
1.136V    16.32mA    16.68mA    16.77mA
1.455V    17.98mA    18.52mA    18.83mA
1.864V    18.83mA    19.28mA    20.04mA
2.091V    17.97mA    18.02mA    19.87mA
2.318V    15.62mA    15.07mA    17.86mA
2.773V    9.688mA    6.547mA    12.61mA
3V        6.943mA    3.687mA    10.19mA
[Pullup]
-1.5V     10.19mA    8.251mA    11.72mA
-1.136V   11.35mA    9.924mA    11.83mA
-863.6mV  10.4mA     10.42mA    10.64mA
-590.9mV  8.854mA    9.085mA    9.032mA
-409.1mV  6.831mA    6.824mA    7.001mA
954.5mV   -14.83mA   -14.61mA   -15.28mA
1.409V    -20.35mA   -19.87mA   -21.04mA
1.818V    -23.9mA    -23.01mA   -24.76mA
2.045V    -24.72mA   -23.08mA   -25.91mA
2.318V    -23.4mA    -21.23mA   -24.88mA
2.636V    -20.27mA   -17.42mA   -21.65mA
3V        -15.03mA   -11.33mA   -16.67mA
[GND_clamp]
-1.5V     -219.3mA   -131.6mA   -364.3mA
-1.288V   -134.4mA   -79.74mA   -225.6mA
-1.258V   -122.9mA   -72.77mA   -206.3mA
-1.136V   -79.27mA   -46.88mA   -132.4mA
-1.045V   -51.5mA    -31.06mA   -84.11mA
-1.015V   -44.02mA   -26.9mA    -70.91mA
-954.5mV  -31.01mA   -19.7mA    -47.55mA
-863.6mV  -17.48mA   -12.16mA   -23.55mA
-803mV    -11.81mA   -8.597mA   -15.85mA
-681.8mV  -5.986mA   -4.096mA   -9.026mA
-378.8mV  -126.2uA   -131.8uA   -179.7uA
1.5V      1.424nA    36.56nA    1.506nA
[Ramp]
dV/dt_f 0.39806731/0.22335852n 0.38200162/0.29424935n 0.41907591/0.15567727n
dV/dt_r  0.3980475/0.20115729n 0.37566753/0.27265618n  0.4236348/0.14812368n
R_load = 50
[Rising Waveform]
R_fixture = 50
V_fixture = 1.5
V_fixture_min = 1.425
V_fixture_max = 1.575
0s        838.8mV    789.6mV    878.5mV
112.5ps   839mV      789.6mV    900.2mV
210.3ps   864.6mV    789.6mV    1.157V
309.6ps   1.051V     790.5mV    1.443V
406.9ps   1.269V     818.5mV    1.545V
569.6ps   1.462V     1.046V     1.569V
701.6ps   1.488V     1.251V     1.573V
852.6ps   1.493V     1.362V     1.574V
1.125ns   1.496V     1.417V     1.575V
1.787ns   1.498V     1.421V     1.575V
[Rising Waveform]
R_fixture = 50
V_fixture = 0
V_fixture_min = 0
V_fixture_max = 0
0s        0V         0V         0V
132.2ps   0V         0V         17.57mV
237.5ps   6.764mV    0V         277.4mV
348.7ps   185.6mV    0V         583.6mV
432.7ps   370.8mV    0V         668.8mV
606.5ps   614.2mV    183.3mV    696.5mV
763.5ps   648.1mV    428.1mV    701.7mV
927.4ps   652.8mV    555.3mV    703.6mV
1.116ns   655.1mV    611.6mV    704.3mV
1.819ns   658.3mV    620.2mV    704.7mV
[Falling Waveform]
R_fixture = 50
V_fixture = 1.5
V_fixture_min = 1.425
V_fixture_max = 1.575
0s        1.499V     1.424V     1.574V
137.1ps   1.499V     1.424V     1.553V
237.4ps   1.481V     1.424V     1.352V
362ps     1.294V     1.424V     1.01V
460ps     1.104V     1.401V     912mV
626.5ps   888.2mV    1.209V     885.7mV
792.2ps   851.4mV    972.1mV    880.3mV
959ps     846.1mV    854.7mV    878.6mV
1.149ns   843.6mV    801.9mV    877.9mV
1.787ns   840.6mV    794.5mV    877.5mV
[Falling Waveform]
R_fixture = 50
V_fixture = 0
V_fixture_min = 0
V_fixture_max = 0
0s        660.6mV    624.3mV    703.7mV
107.4ps   660.6mV    624.3mV    693.8mV
207.7ps   646.5mV    624.3mV    452.3mV
316.3ps   452.2mV    624.3mV    150.1mV
419.8ps   238.7mV    588.6mV    29.35mV
595.2ps   35.98mV    346.9mV    5.909mV
727.6ps   11.14mV    161.8mV    2.616mV
884.4ps   6.845mV    61.81mV    0V
1.141ns   4.692mV    7.293mV    0V
1.819ns   4.072mV    3.71mV     0V
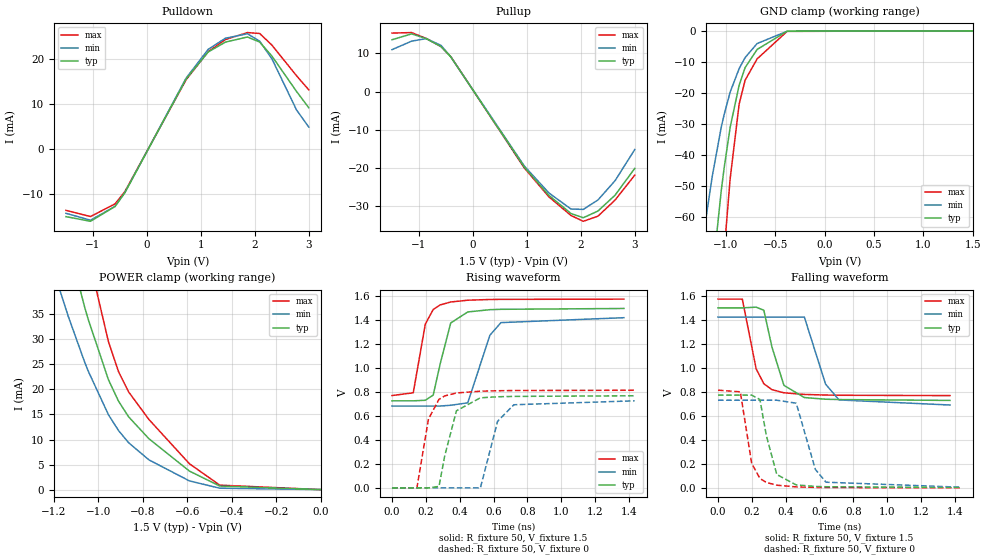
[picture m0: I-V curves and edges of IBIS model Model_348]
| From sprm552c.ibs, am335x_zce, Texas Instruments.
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| Model based on original model for BCSHTLTCSCDVPBFZ_SSDHV
|   Sub model SR00_8MA_5PER_1P5
[model]   Model_348
|[Description]  [1.5V-3-STATE-NOTERM-SR00:8MA, IND, 5%]
|   Fastest slew rate (SR[1:0] = "00"), 1.00 * RExt = 1.000 * Iout
|   (I[2:0] = "011"), 8mA nominal with Rext = 50R,ODT off (ODT[1:0]
|   = "00") CMOS mode,Industrial temperature range (-40C to 125C,
|   25C nominal),5% power supply tolerance
|[Input Load]   NOTERM
|[Output Drive] SR00:8MA
|Voltage   1.5V
|Mode   3-STATE
Model_type   3-state
Polarity   Non-Inverting
Enable   Active-Low
Cref =  15pF
Rref =  100.0000M
Vref =  0V
Vmeas =  0.75
C_comp   1.865048p   1.679967p   1.989968p
[Temperature Range]   25   125   -40
[Voltage Range]   1.5   1.425   1.575
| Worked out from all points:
|   slope of the pulldown table from 0 to 0.225 V, typ, clamps not added: 43 ohm
|   slope of the pullup table from 0 to 0.225 V, typ, clamps not added: 45 ohm
|   GND clamp passes 1 mA (typ) near -0.49 V on its own axis
|   POWER clamp passes 1 mA (typ) near -0.47 V on its own axis
|   rising waveform, R_fixture 50, V_fixture 1.5: 20-80 % time 70.9ps typ, 93ps min, 61.4ps max; typ from 0.726 V to 1.5 V
|   rising waveform, R_fixture 50, V_fixture 0: 20-80 % time 71.2ps typ, 80.8ps min, 65.9ps max; typ from 0 V to 0.768 V
|   falling waveform, R_fixture 50, V_fixture 1.5: 20-80 % time 83.3ps typ, 94.7ps min, 74.3ps max; typ from 1.5 V to 0.729 V
|   falling waveform, R_fixture 50, V_fixture 0: 20-80 % time 65.2ps typ, 79.5ps min, 58.3ps max; typ from 0.773 V to 0.003 V
[POWER_clamp]
-1.5V     126mA      88.76mA    168.8mA
-1.242V   69.8mA     49.43mA    94.36mA
-1.136V   49.16mA    34.7mA     67.53mA
-1.061V   36.35mA    25.39mA    50.04mA
-1.045V   33.92mA    23.62mA    46.67mA
-954.5mV  21.93mA    14.94mA    29.52mA
-909.1mV  17.64mA    11.78mA    23.53mA
-863.6mV  14.51mA    9.346mA    19.48mA
-772.7mV  10.16mA    5.937mA    14mA
-590.9mV  3.705mA    1.741mA    5.168mA
-454.5mV  710.5uA    279.1uA    892.2uA
0V        1.424nA    14.75nA    2.169nA
[Pulldown]
-1.5V     -14.94mA   -14.2mA    -13.55mA
-1.045V   -15.97mA   -15.73mA   -14.92mA
-590.9mV  -12.7mA    -12.67mA   -12.12mA
-409.1mV  -9.652mA   -9.646mA   -9.411mA
727.3mV   15.5mA     15.69mA    15.34mA
1.136V    21.47mA    22.05mA    21.55mA
1.455V    23.65mA    24.5mA     24.21mA
1.864V    24.78mA    25.5mA     25.76mA
2.091V    23.65mA    23.85mA    25.56mA
2.318V    20.55mA    19.94mA    22.97mA
2.773V    12.75mA    8.663mA    16.22mA
3V        9.139mA    4.878mA    13.11mA
[Pullup]
-1.5V     13.59mA    11mA       15.33mA
-1.136V   15.13mA    13.23mA    15.47mA
-863.6mV  13.87mA    13.89mA    13.92mA
-590.9mV  11.8mA     12.11mA    11.81mA
-409.1mV  9.103mA    9.093mA    9.151mA
954.5mV   -19.76mA   -19.47mA   -19.97mA
1.409V    -27.12mA   -26.48mA   -27.5mA
1.818V    -31.86mA   -30.68mA   -32.37mA
2.045V    -32.96mA   -30.78mA   -33.89mA
2.318V    -31.2mA    -28.31mA   -32.55mA
2.636V    -27.04mA   -23.24mA   -28.32mA
3V        -20.05mA   -15.12mA   -21.81mA
[GND_clamp]
-1.5V     -219.3mA   -131.6mA   -364.3mA
-1.288V   -134.4mA   -79.74mA   -225.6mA
-1.258V   -122.9mA   -72.77mA   -206.3mA
-1.136V   -79.27mA   -46.88mA   -132.4mA
-1.045V   -51.5mA    -31.06mA   -84.11mA
-1.015V   -44.02mA   -26.9mA    -70.91mA
-954.5mV  -31.01mA   -19.7mA    -47.55mA
-863.6mV  -17.48mA   -12.16mA   -23.55mA
-803mV    -11.81mA   -8.597mA   -15.85mA
-681.8mV  -5.986mA   -4.096mA   -9.026mA
-378.8mV  -126.2uA   -131.8uA   -179.7uA
1.5V      1.424nA    36.56nA    1.506nA
[Ramp]
dV/dt_f 0.47328803/84.567536p  0.4562043/97.980472p 0.48995944/74.576546p
dV/dt_r 0.47258641/72.270835p 0.45224397/81.582788p 0.49584157/66.017204p
R_load = 50
[Rising Waveform]
R_fixture = 50
V_fixture = 1.5
V_fixture_min = 1.425
V_fixture_max = 1.575
0s        726.3mV    682.9mV    770.3mV
125.6ps   726.3mV    682.9mV    793.4mV
196.8ps   730.9mV    682.9mV    1.366V
243.5ps   774.3mV    682.9mV    1.489V
285.4ps   1.039V     682.9mV    1.527V
346.9ps   1.376V     689.3mV    1.551V
447.4ps   1.468V     709.5mV    1.566V
578.5ps   1.487V     1.274V     1.572V
643.5ps   1.49V      1.379V     1.573V
1.37ns    1.497V     1.42V      1.575V
[Rising Waveform]
R_fixture = 50
V_fixture = 0
V_fixture_min = 0
V_fixture_max = 0
0s        0V         0V         0V
147.2ps   0V         0V         0V
215.4ps   0V         0V         574.5mV
277.6ps   12.06mV    0V         738.7mV
311.1ps   264.6mV    0V         767.4mV
380.6ps   643.4mV    0V         791.7mV
522.2ps   751.5mV    0V         806.6mV
623.7ps   760.1mV    555.4mV    810.4mV
719.7ps   763.2mV    693.5mV    812.3mV
1.434ns   768.5mV    726.4mV    814.7mV
[Falling Waveform]
R_fixture = 50
V_fixture = 1.5
V_fixture_min = 1.425
V_fixture_max = 1.575
0s        1.501V     1.424V     1.574V
143.5ps   1.501V     1.424V     1.574V
225.1ps   1.507V     1.424V     993.4mV
270.6ps   1.481V     1.424V     868.3mV
318.8ps   1.173V     1.424V     818.8mV
389.3ps   854.8mV    1.424V     792.9mV
510.1ps   753.2mV    1.424V     779.1mV
635.2ps   739.3mV    865.5mV    774.2mV
714.5ps   736.4mV    733.3mV    772.3mV
1.37ns    729.2mV    690.9mV    769.4mV
[Falling Waveform]
R_fixture = 50
V_fixture = 0
V_fixture_min = 0
V_fixture_max = 0
0s        773.4mV    730.8mV    814.7mV
131.8ps   773.4mV    730.8mV    800.9mV
198.6ps   773.4mV    730.8mV    205.1mV
247.4ps   737.2mV    730.8mV    78.47mV
285.9ps   433.3mV    730.8mV    44.92mV
347.3ps   111.1mV    730.8mV    22.09mV
461.8ps   24.5mV     706.2mV    8.001mV
574.6ps   11.86mV    155mV      3.769mV
637.6ps   9.23mV     47.22mV    2.6mV
1.434ns   3.426mV    5.364mV    0V
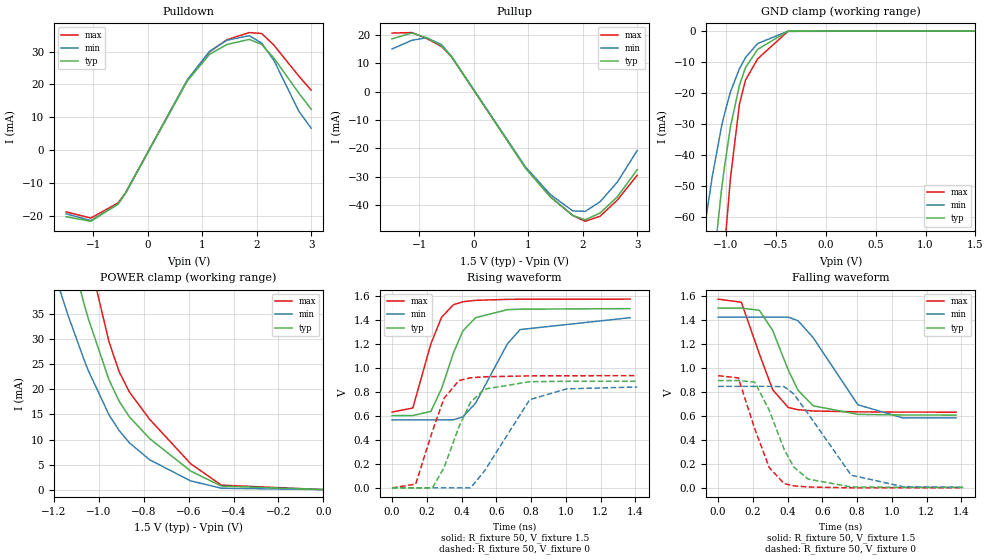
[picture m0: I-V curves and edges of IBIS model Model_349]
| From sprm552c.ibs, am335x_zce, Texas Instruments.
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| Model based on original model for BCSHTLTCSCDVPBFZ_SSDHV
|   Sub model SR01_11MA_5PER_1P5
[model]   Model_349
|[Description]  [1.5V-3-STATE-NOTERM-SR01:11MA, IND, 5%]
|   Slow slew rate (SR[1:0] = "01"), 0.73 * RExt = 1.325 * Iout
|   (I[2:0] = "110"), 11mA nominal with Rext = 50R,ODT off (ODT[1:0]
|   = "00") CMOS mode,Industrial temperature range (-40C to 125C,
|   25C nominal),5% power supply tolerance
|[Input Load]   NOTERM
|[Output Drive] SR01:11MA
|Voltage   1.5V
|Mode   3-STATE
Model_type   3-state
Polarity   Non-Inverting
Enable   Active-Low
Cref =  15pF
Rref =  100.0000M
Vref =  0V
Vmeas =  0.75
C_comp   1.865048p   1.679967p   1.989968p
[Temperature Range]   25   125   -40
[Voltage Range]   1.5   1.425   1.575
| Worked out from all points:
|   slope of the pulldown table from 0 to 0.225 V, typ, clamps not added: 31.7 ohm
|   slope of the pullup table from 0 to 0.225 V, typ, clamps not added: 32.8 ohm
|   GND clamp passes 1 mA (typ) near -0.49 V on its own axis
|   POWER clamp passes 1 mA (typ) near -0.47 V on its own axis
|   rising waveform, R_fixture 50, V_fixture 1.5: 20-80 % time 139ps typ, 196ps min, 115ps max; typ from 0.603 V to 1.5 V
|   rising waveform, R_fixture 50, V_fixture 0: 20-80 % time 149ps typ, 200ps min, 123ps max; typ from 0 V to 0.889 V
|   falling waveform, R_fixture 50, V_fixture 1.5: 20-80 % time 163ps typ, 217ps min, 130ps max; typ from 1.5 V to 0.607 V
|   falling waveform, R_fixture 50, V_fixture 0: 20-80 % time 156ps typ, 226ps min, 127ps max; typ from 0.895 V to 0.004 V
[POWER_clamp]
-1.5V     126mA      88.76mA    168.8mA
-1.242V   69.8mA     49.43mA    94.36mA
-1.136V   49.16mA    34.7mA     67.53mA
-1.061V   36.35mA    25.39mA    50.04mA
-1.045V   33.92mA    23.62mA    46.67mA
-954.5mV  21.93mA    14.94mA    29.52mA
-909.1mV  17.64mA    11.78mA    23.53mA
-863.6mV  14.51mA    9.346mA    19.48mA
-772.7mV  10.16mA    5.937mA    14mA
-590.9mV  3.705mA    1.741mA    5.168mA
-454.5mV  710.5uA    279.1uA    892.2uA
0V        1.424nA    14.75nA    2.169nA
[Pulldown]
-1.5V     -20.32mA   -19.41mA   -18.83mA
-1.045V   -21.71mA   -21.48mA   -20.72mA
-545.5mV  -16.46mA   -16.48mA   -16.11mA
-409.1mV  -13.12mA   -13.16mA   -13.06mA
727.3mV   21.07mA    21.41mA    21.29mA
1.136V    29.18mA    30.1mA     29.92mA
1.455V    32.16mA    33.45mA    33.62mA
1.864V    33.7mA     34.83mA    35.78mA
2.091V    32.17mA    32.59mA    35.5mA
2.318V    27.97mA    27.26mA    31.92mA
2.773V    17.36mA    11.84mA    22.54mA
3V        12.44mA    6.666mA    18.22mA
[Pullup]
-1.5V     18.7mA     15.13mA    20.75mA
-1.136V   20.8mA     18.2mA     20.93mA
-863.6mV  19.07mA    19.1mA     18.82mA
-590.9mV  16.22mA    16.64mA    15.97mA
-409.1mV  12.51mA    12.49mA    12.37mA
954.5mV   -27.15mA   -26.75mA   -27.01mA
1.409V    -37.28mA   -36.4mA    -37.19mA
1.818V    -43.8mA    -42.17mA   -43.78mA
2.045V    -45.32mA   -42.33mA   -45.84mA
2.318V    -42.92mA   -38.95mA   -44.05mA
2.636V    -37.2mA    -31.98mA   -38.33mA
3V        -27.6mA    -20.81mA   -29.54mA
[GND_clamp]
-1.5V     -219.3mA   -131.6mA   -364.3mA
-1.288V   -134.4mA   -79.74mA   -225.6mA
-1.258V   -122.9mA   -72.77mA   -206.3mA
-1.136V   -79.27mA   -46.88mA   -132.4mA
-1.045V   -51.5mA    -31.06mA   -84.11mA
-1.015V   -44.02mA   -26.9mA    -70.91mA
-954.5mV  -31.01mA   -19.7mA    -47.55mA
-863.6mV  -17.48mA   -12.16mA   -23.55mA
-803mV    -11.81mA   -8.597mA   -15.85mA
-681.8mV  -5.986mA   -4.096mA   -9.026mA
-378.8mV  -126.2uA   -131.8uA   -179.7uA
1.5V      1.424nA    36.56nA    1.506nA
[Ramp]
dV/dt_f 0.53998534/0.16497257n 0.51695758/0.22394698n 0.56765358/0.13026744n
dV/dt_r 0.53937076/0.15081073n 0.51113284/0.20262396n 0.56404192/0.1231602n
R_load = 50
[Rising Waveform]
R_fixture = 50
V_fixture = 1.5
V_fixture_min = 1.425
V_fixture_max = 1.575
0s        603.4mV    566.8mV    632.3mV
119.3ps   603.4mV    566.8mV    666.2mV
223.1ps   637.9mV    566.8mV    1.201V
285ps     828.5mV    567.4mV    1.424V
352.6ps   1.124V     568.2mV    1.528V
407.5ps   1.31V      592.5mV    1.553V
480.9ps   1.42V      707.4mV    1.565V
663.5ps   1.487V     1.201V     1.573V
737.2ps   1.491V     1.321V     1.574V
1.37ns    1.496V     1.42V      1.575V
[Rising Waveform]
R_fixture = 50
V_fixture = 0
V_fixture_min = 0
V_fixture_max = 0
0s        0V         0V         0V
135.7ps   0V         0V         30.98mV
232ps     0V         0V         472.9mV
299.2ps   168.9mV    0V         747.6mV
384.5ps   508.7mV    0V         895.3mV
451.9ps   714.9mV    0V         918.5mV
531.8ps   823.7mV    140.2mV    926.9mV
792ps     886.1mV    735.7mV    934.5mV
1.006ns   889.2mV    826.3mV    935.4mV
1.411ns   889.4mV    841.5mV    936.6mV
[Falling Waveform]
R_fixture = 50
V_fixture = 1.5
V_fixture_min = 1.425
V_fixture_max = 1.575
0s        1.499V     1.424V     1.574V
133.7ps   1.499V     1.424V     1.548V
237.2ps   1.481V     1.424V     1.118V
313.9ps   1.313V     1.424V     818.7mV
403.8ps   982.3mV    1.424V     670.5mV
459.5ps   814.7mV    1.394V     651.5mV
547.4ps   684mV      1.253V     641.6mV
805ps     612.7mV    692.6mV    633.6mV
1.064ns   607.9mV    583.3mV    631.8mV
1.37ns    606.9mV    583.3mV    631.4mV
[Falling Waveform]
R_fixture = 50
V_fixture = 0
V_fixture_min = 0
V_fixture_max = 0
0s        894.9mV    846.6mV    935.9mV
116.3ps   894.9mV    846.6mV    916.6mV
210.6ps   882.1mV    846.6mV    493.2mV
294.4ps   646.7mV    846.6mV    168.3mV
380.2ps   321.1mV    843.8mV    35.51mV
436.1ps   172.2mV    783.2mV    16.58mV
519ps     72.5mV     616mV      7.302mV
766.3ps   7.857mV    105.5mV    0V
1.064ns   4.46mV     10.25mV    0V
1.411ns   4.46mV     4.638mV    0V
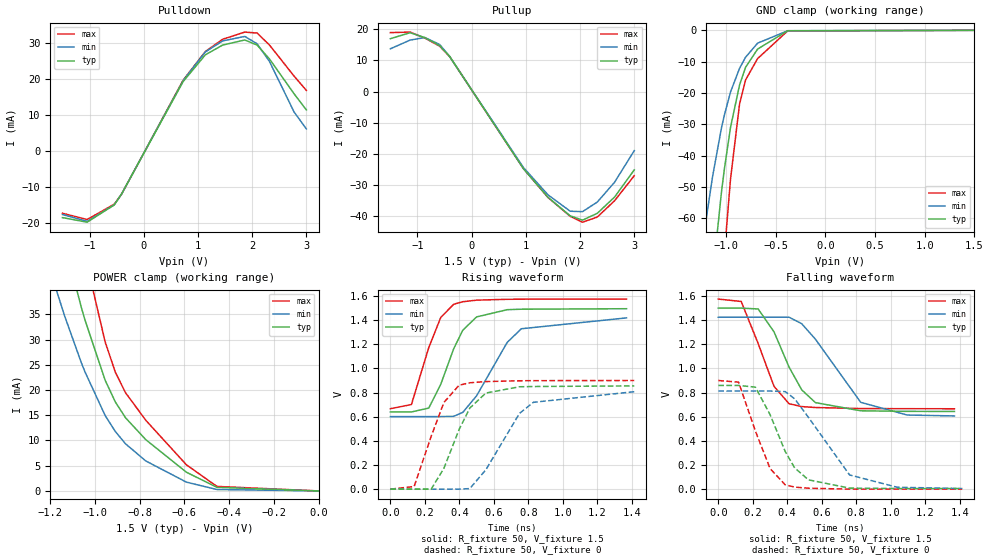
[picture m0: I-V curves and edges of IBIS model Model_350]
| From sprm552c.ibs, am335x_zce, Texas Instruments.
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| Model based on original model for BCSHTLTCSCDVPBFZ_SSDHV
|   Sub model SR01_10MA_5PER_1P5
[model]   Model_350
|[Description]  [1.5V-3-STATE-NOTERM-SR01:10MA, IND, 5%]
|   Slow slew rate (SR[1:0] = "01"), 0.80 * RExt = 1.250 * Iout
|   (I[2:0] = "101"), 10mA nominal with Rext = 50R,ODT off (ODT[1:0]
|   = "00") CMOS mode,Industrial temperature range (-40C to 125C,
|   25C nominal),5% power supply tolerance
|[Input Load]   NOTERM
|[Output Drive] SR01:10MA
|Voltage   1.5V
|Mode   3-STATE
Model_type   3-state
Polarity   Non-Inverting
Enable   Active-Low
Cref =  15pF
Rref =  100.0000M
Vref =  0V
Vmeas =  0.75
C_comp   1.865048p   1.679967p   1.989968p
[Temperature Range]   25   125   -40
[Voltage Range]   1.5   1.425   1.575
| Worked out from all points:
|   slope of the pulldown table from 0 to 0.225 V, typ, clamps not added: 34.7 ohm
|   slope of the pullup table from 0 to 0.225 V, typ, clamps not added: 36.1 ohm
|   GND clamp passes 1 mA (typ) near -0.49 V on its own axis
|   POWER clamp passes 1 mA (typ) near -0.47 V on its own axis
|   rising waveform, R_fixture 50, V_fixture 1.5: 20-80 % time 148ps typ, 203ps min, 120ps max; typ from 0.64 V to 1.5 V
|   rising waveform, R_fixture 50, V_fixture 0: 20-80 % time 157ps typ, 205ps min, 127ps max; typ from 0 V to 0.856 V
|   falling waveform, R_fixture 50, V_fixture 1.5: 20-80 % time 175ps typ, 229ps min, 136ps max; typ from 1.5 V to 0.643 V
|   falling waveform, R_fixture 50, V_fixture 0: 20-80 % time 165ps typ, 227ps min, 132ps max; typ from 0.859 V to 0.005 V
[POWER_clamp]
-1.5V     126mA      88.76mA    168.8mA
-1.242V   69.8mA     49.43mA    94.36mA
-1.136V   49.16mA    34.7mA     67.53mA
-1.061V   36.35mA    25.39mA    50.04mA
-1.045V   33.92mA    23.62mA    46.67mA
-954.5mV  21.93mA    14.94mA    29.52mA
-909.1mV  17.64mA    11.78mA    23.53mA
-863.6mV  14.51mA    9.346mA    19.48mA
-772.7mV  10.16mA    5.937mA    14mA
-590.9mV  3.705mA    1.741mA    5.168mA
-454.5mV  710.5uA    279.1uA    892.2uA
0V        1.424nA    14.75nA    2.169nA
[Pulldown]
-1.5V     -18.53mA   -17.67mA   -17.32mA
-1.045V   -19.8mA    -19.56mA   -19.06mA
-545.5mV  -15.01mA   -15.01mA   -14.82mA
-409.1mV  -11.96mA   -11.99mA   -12.02mA
727.3mV   19.21mA    19.5mA     19.59mA
1.136V    26.61mA    27.42mA    27.53mA
1.455V    29.32mA    30.47mA    30.93mA
1.864V    30.73mA    31.72mA    32.92mA
2.091V    29.33mA    29.67mA    32.66mA
2.318V    25.5mA     24.82mA    29.36mA
2.773V    15.82mA    10.78mA    20.73mA
3V        11.34mA    6.07mA     16.76mA
[Pullup]
-1.5V     17mA       13.76mA    18.94mA
-1.136V   18.91mA    16.54mA    19.11mA
-863.6mV  17.34mA    17.36mA    17.19mA
-590.9mV  14.75mA    15.13mA    14.58mA
-409.1mV  11.37mA    11.36mA    11.3mA
954.5mV   -24.69mA   -24.32mA   -24.66mA
1.409V    -33.89mA   -33.1mA    -33.96mA
1.818V    -39.82mA   -38.34mA   -39.98mA
2.045V    -41.2mA    -38.48mA   -41.86mA
2.318V    -39.01mA   -35.4mA    -40.21mA
2.636V    -33.81mA   -29.06mA   -34.99mA
3V        -25.08mA   -18.91mA   -26.96mA
[GND_clamp]
-1.5V     -219.3mA   -131.6mA   -364.3mA
-1.288V   -134.4mA   -79.74mA   -225.6mA
-1.258V   -122.9mA   -72.77mA   -206.3mA
-1.136V   -79.27mA   -46.88mA   -132.4mA
-1.045V   -51.5mA    -31.06mA   -84.11mA
-1.015V   -44.02mA   -26.9mA    -70.91mA
-954.5mV  -31.01mA   -19.7mA    -47.55mA
-863.6mV  -17.48mA   -12.16mA   -23.55mA
-803mV    -11.81mA   -8.597mA   -15.85mA
-681.8mV  -5.986mA   -4.096mA   -9.026mA
-378.8mV  -126.2uA   -131.8uA   -179.7uA
1.5V      1.424nA    36.56nA    1.506nA
[Ramp]
dV/dt_f 0.51788123/0.17659376n 0.49595814/0.2319464n 0.54684737/0.13670804n
dV/dt_r 0.51755045/0.15923174n 0.49005389/0.20782652n 0.54218417/0.12721343n
R_load = 50
[Rising Waveform]
R_fixture = 50
V_fixture = 1.5
V_fixture_min = 1.425
V_fixture_max = 1.575
0s        639.6mV    601mV      666.5mV
122.1ps   639.7mV    601mV      701.2mV
222.7ps   671.9mV    601mV      1.173V
291.9ps   867.6mV    601.6mV    1.422V
367.2ps   1.163V     603.4mV    1.532V
420.1ps   1.317V     636.1mV    1.553V
500.1ps   1.427V     773.5mV    1.566V
677.8ps   1.487V     1.216V     1.573V
759.7ps   1.491V     1.329V     1.574V
1.37ns    1.495V     1.419V     1.575V
[Rising Waveform]
R_fixture = 50
V_fixture = 0
V_fixture_min = 0
V_fixture_max = 0
0s        0V         0V         0V
137.8ps   0V         0V         21.92mV
236.8ps   0V         0V         438.6mV
310.7ps   173.4mV    0V         718.8mV
398.5ps   493.9mV    0V         861mV
460.8ps   671.9mV    4.923mV    881.5mV
553.8ps   796.2mV    160.4mV    891.3mV
748.9ps   848.3mV    627.5mV    898mV
829.9ps   850.4mV    719.8mV    899mV
1.415ns   855.6mV    807.5mV    900.2mV
[Falling Waveform]
R_fixture = 50
V_fixture = 1.5
V_fixture_min = 1.425
V_fixture_max = 1.575
0s        1.499V     1.424V     1.574V
133ps     1.499V     1.424V     1.554V
231.1ps   1.492V     1.424V     1.206V
323.1ps   1.303V     1.424V     851.7mV
410.4ps   1.011V     1.424V     707.5mV
483.9ps   822.6mV    1.37V      683.8mV
563.3ps   716.7mV    1.242V     676mV
826.2ps   648.9mV    719.1mV    667.5mV
1.096ns   644.2mV    613.8mV    666.3mV
1.37ns    643.3mV    606.3mV    665.7mV
[Falling Waveform]
R_fixture = 50
V_fixture = 0
V_fixture_min = 0
V_fixture_max = 0
0s        858.8mV    812.4mV    899.8mV
117.7ps   858.8mV    812.4mV    886mV
215.4ps   844.7mV    812.4mV    480.1mV
300.7ps   616.2mV    812.4mV    170.3mV
388.1ps   312.2mV    807.9mV    36.06mV
443.2ps   176.1mV    748mV      17.2mV
523ps     77.19mV    594.5mV    7.788mV
761.8ps   8.538mV    117.5mV    0V
1.038ns   5.41mV     15.94mV    0V
1.415ns   5.41mV     5.232mV    0V
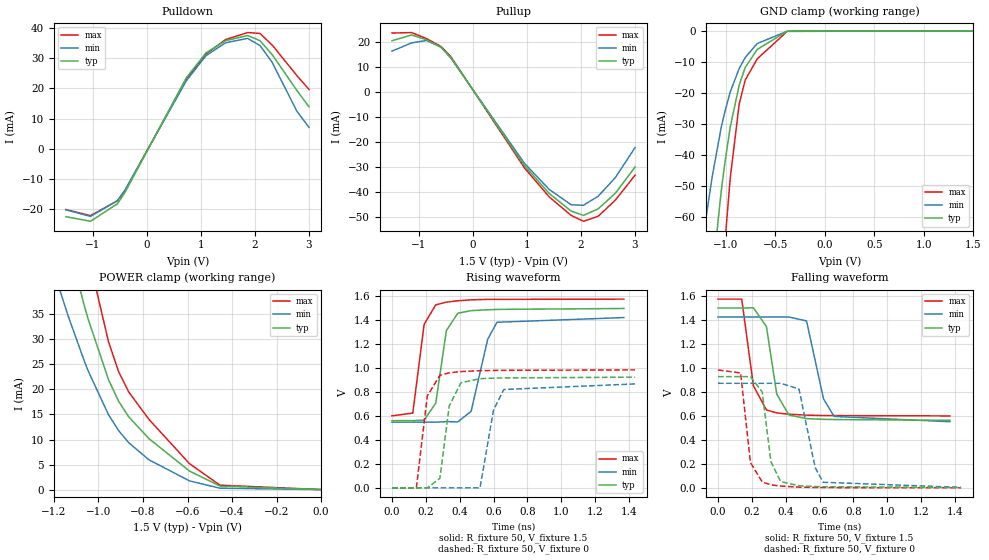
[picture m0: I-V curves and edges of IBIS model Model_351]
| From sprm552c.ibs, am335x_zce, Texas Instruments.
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| Model based on original model for BCSHTLTCSCDVPBFZ_SSDHV
|   Sub model SR00_12MA_5PER_1P5
[model]   Model_351
|[Description]  [1.5V-3-STATE-NOTERM-SR00:12MA, IND, 5%]
|   Fastest slew rate (SR[1:0] = "00"), 0.67 * RExt = 1.500 * Iout
|   (I[2:0] = "111"), 12mA nominal with Rext = 50R,ODT off (ODT[1:0]
|   = "00") CMOS mode,Industrial temperature range (-40C to 125C,
|   25C nominal),5% power supply tolerance
|[Input Load]   NOTERM
|[Output Drive] SR00:12MA
|Voltage   1.5V
|Mode   3-STATE
Model_type   3-state
Polarity   Non-Inverting
Enable   Active-Low
Cref =  15pF
Rref =  100.0000M
Vref =  0V
Vmeas =  0.75
C_comp   1.865048p   1.679967p   1.989968p
[Temperature Range]   25   125   -40
[Voltage Range]   1.5   1.425   1.575
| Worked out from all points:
|   slope of the pulldown table from 0 to 0.225 V, typ, clamps not added: 28.3 ohm
|   slope of the pullup table from 0 to 0.225 V, typ, clamps not added: 30.1 ohm
|   GND clamp passes 1 mA (typ) near -0.49 V on its own axis
|   POWER clamp passes 1 mA (typ) near -0.47 V on its own axis
|   rising waveform, R_fixture 50, V_fixture 1.5: 20-80 % time 57.3ps typ, 80.8ps min, 47.3ps max; typ from 0.561 V to 1.5 V
|   rising waveform, R_fixture 50, V_fixture 0: 20-80 % time 55.4ps typ, 62.6ps min, 50.1ps max; typ from 0 V to 0.924 V
|   falling waveform, R_fixture 50, V_fixture 1.5: 20-80 % time 64.9ps typ, 77.5ps min, 56.6ps max; typ from 1.5 V to 0.564 V
|   falling waveform, R_fixture 50, V_fixture 0: 20-80 % time 50.8ps typ, 67.4ps min, 45.9ps max; typ from 0.928 V to 0.004 V
[POWER_clamp]
-1.5V     126mA      88.76mA    168.8mA
-1.242V   69.8mA     49.43mA    94.36mA
-1.136V   49.16mA    34.7mA     67.53mA
-1.061V   36.35mA    25.39mA    50.04mA
-1.045V   33.92mA    23.62mA    46.67mA
-954.5mV  21.93mA    14.94mA    29.52mA
-909.1mV  17.64mA    11.78mA    23.53mA
-863.6mV  14.51mA    9.346mA    19.48mA
-772.7mV  10.16mA    5.937mA    14mA
-590.9mV  3.705mA    1.741mA    5.168mA
-454.5mV  710.5uA    279.1uA    892.2uA
0V        1.424nA    14.75nA    2.169nA
[Pulldown]
-1.5V     -22.72mA   -20.45mA   -20.34mA
-1.045V   -24.26mA   -22.63mA   -22.37mA
-545.5mV  -18.39mA   -17.36mA   -17.39mA
-409.1mV  -14.66mA   -13.87mA   -14.1mA
727.3mV   23.54mA    22.55mA    22.99mA
1.091V    31.85mA    30.92mA    31.48mA
1.455V    35.94mA    35.24mA    36.31mA
1.864V    37.66mA    36.7mA     38.64mA
2.091V    35.96mA    34.34mA    38.35mA
2.318V    31.27mA    28.72mA    34.48mA
2.773V    19.4mA     12.48mA    24.34mA
3V        13.9mA     7.024mA    19.68mA
[Pullup]
-1.5V     20.4mA     16.24mA    23.46mA
-1.136V   22.69mA    19.53mA    23.65mA
-863.6mV  20.8mA     20.49mA    21.28mA
-590.9mV  17.69mA    17.85mA    18.05mA
-409.1mV  13.64mA    13.4mA     13.98mA
954.5mV   -29.62mA   -28.69mA   -30.52mA
1.409V    -40.66mA   -39.04mA   -42.03mA
1.818V    -47.77mA   -45.23mA   -49.49mA
2.045V    -49.44mA   -45.41mA   -51.82mA
2.318V    -46.83mA   -41.78mA   -49.8mA
2.636V    -40.59mA   -34.31mA   -43.34mA
3V        -30.12mA   -22.33mA   -33.4mA
[GND_clamp]
-1.5V     -219.3mA   -131.6mA   -364.3mA
-1.288V   -134.4mA   -79.74mA   -225.6mA
-1.258V   -122.9mA   -72.77mA   -206.3mA
-1.136V   -79.27mA   -46.88mA   -132.4mA
-1.045V   -51.5mA    -31.06mA   -84.11mA
-1.015V   -44.02mA   -26.9mA    -70.91mA
-954.5mV  -31.01mA   -19.7mA    -47.55mA
-863.6mV  -17.48mA   -12.16mA   -23.55mA
-803mV    -11.81mA   -8.597mA   -15.85mA
-681.8mV  -5.986mA   -4.096mA   -9.026mA
-378.8mV  -126.2uA   -131.8uA   -179.7uA
1.5V      1.424nA    36.56nA    1.506nA
[Ramp]
dV/dt_f 0.57592986/64.821406p 0.54037054/79.668258p  0.5938944/56.990809p
dV/dt_r 0.56954446/55.971005p  0.5434676/64.175462p 0.60086433/50.080229p
R_load = 50
[Rising Waveform]
R_fixture = 50
V_fixture = 1.5
V_fixture_min = 1.425
V_fixture_max = 1.575
0s        560.9mV    548.1mV    601.2mV
122.8ps   560.9mV    548.1mV    623.8mV
189.8ps   565.5mV    548.1mV    1.365V
258.4ps   706.7mV    548.1mV    1.527V
321.3ps   1.313V     552.7mV    1.55V
388.6ps   1.457V     550.7mV    1.561V
467.5ps   1.479V     639.2mV    1.569V
565.5ps   1.486V     1.241V     1.573V
620.3ps   1.489V     1.382V     1.573V
1.37ns    1.497V     1.421V     1.575V
[Rising Waveform]
R_fixture = 50
V_fixture = 0
V_fixture_min = 0
V_fixture_max = 0
0s        0V         0V         0V
143.9ps   0V         0V         0V
208.5ps   0V         0V         767.4mV
283.1ps   79.58mV    0V         939.2mV
337.9ps   682.6mV    0V         960.1mV
407ps     876.7mV    0V         970.5mV
519.9ps   911.1mV    0V         977.8mV
599.7ps   915.6mV    649mV      980.1mV
660.6ps   917.5mV    820.8mV    980.9mV
1.436ns   923.6mV    867.5mV    984.4mV
[Falling Waveform]
R_fixture = 50
V_fixture = 1.5
V_fixture_min = 1.425
V_fixture_max = 1.575
0s        1.501V     1.426V     1.575V
140ps     1.501V     1.426V     1.575V
209ps     1.503V     1.426V     852mV
286ps     1.346V     1.426V     650.4mV
346.9ps   782.3mV    1.426V     625.2mV
418.7ps   608.1mV    1.426V     614.7mV
522.9ps   577.7mV    1.393V     606.8mV
623.4ps   572mV      741.5mV    603.9mV
686.1ps   570.1mV    596mV      603.1mV
1.37ns    563.8mV    551.9mV    600.4mV
[Falling Waveform]
R_fixture = 50
V_fixture = 0
V_fixture_min = 0
V_fixture_max = 0
0s        928.4mV    872.6mV    983.7mV
133.4ps   928.4mV    872.6mV    958.9mV
191.5ps   928.4mV    872.6mV    211.6mV
261.2ps   799.9mV    872.6mV    48.17mV
312.5ps   217.7mV    872.6mV    25.34mV
370.4ps   51.94mV    872.6mV    14.93mV
478.3ps   17.56mV    825.1mV    5.901mV
573.9ps   10.78mV    169.1mV    2.995mV
621ps     9.2mV      46.65mV    2.244mV
1.436ns   3.641mV    3.881mV    0V
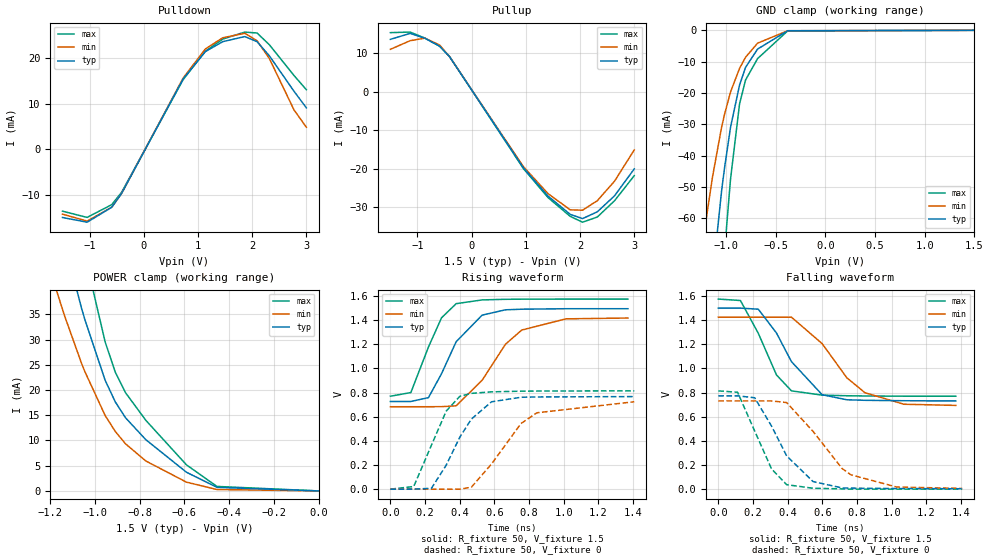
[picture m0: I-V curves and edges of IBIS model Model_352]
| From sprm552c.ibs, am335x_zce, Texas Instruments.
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| Model based on original model for BCSHTLTCSCDVPBFZ_SSDHV
|   Sub model SR01_8MA_5PER_1P5
[model]   Model_352
|[Description]  [1.5V-3-STATE-NOTERM-SR01:8MA, IND, 5%]
|   Slow slew rate (SR[1:0] = "01"), 1.00 * RExt = 1.000 * Iout
|   (I[2:0] = "011"), 8mA nominal with Rext = 50R,ODT off (ODT[1:0]
|   = "00") CMOS mode,Industrial temperature range (-40C to 125C,
|   25C nominal),5% power supply tolerance
|[Input Load]   NOTERM
|[Output Drive] SR01:8MA
|Voltage   1.5V
|Mode   3-STATE
Model_type   3-state
Polarity   Non-Inverting
Enable   Active-Low
Cref =  15pF
Rref =  100.0000M
Vref =  0V
Vmeas =  0.75
C_comp   1.865048p   1.679967p   1.989968p
[Temperature Range]   25   125   -40
[Voltage Range]   1.5   1.425   1.575
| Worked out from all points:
|   slope of the pulldown table from 0 to 0.225 V, typ, clamps not added: 43 ohm
|   slope of the pullup table from 0 to 0.225 V, typ, clamps not added: 45 ohm
|   GND clamp passes 1 mA (typ) near -0.49 V on its own axis
|   POWER clamp passes 1 mA (typ) near -0.47 V on its own axis
|   rising waveform, R_fixture 50, V_fixture 1.5: 20-80 % time 166ps typ, 218ps min, 132ps max; typ from 0.726 V to 1.5 V
|   rising waveform, R_fixture 50, V_fixture 0: 20-80 % time 181ps typ, 231ps min, 139ps max; typ from 0 V to 0.767 V
|   falling waveform, R_fixture 50, V_fixture 1.5: 20-80 % time 193ps typ, 244ps min, 148ps max; typ from 1.5 V to 0.731 V
|   falling waveform, R_fixture 50, V_fixture 0: 20-80 % time 187ps typ, 241ps min, 143ps max; typ from 0.773 V to 0.004 V
[POWER_clamp]
-1.5V     126mA      88.76mA    168.8mA
-1.242V   69.8mA     49.43mA    94.36mA
-1.136V   49.16mA    34.7mA     67.53mA
-1.061V   36.35mA    25.39mA    50.04mA
-1.045V   33.92mA    23.62mA    46.67mA
-954.5mV  21.93mA    14.94mA    29.52mA
-909.1mV  17.64mA    11.78mA    23.53mA
-863.6mV  14.51mA    9.346mA    19.48mA
-772.7mV  10.16mA    5.937mA    14mA
-590.9mV  3.705mA    1.741mA    5.168mA
-454.5mV  710.5uA    279.1uA    892.2uA
0V        1.424nA    14.75nA    2.169nA
[Pulldown]
-1.5V     -14.94mA   -14.2mA    -13.55mA
-1.045V   -15.97mA   -15.73mA   -14.92mA
-590.9mV  -12.7mA    -12.67mA   -12.12mA
-409.1mV  -9.652mA   -9.646mA   -9.411mA
727.3mV   15.5mA     15.69mA    15.34mA
1.136V    21.47mA    22.05mA    21.55mA
1.455V    23.65mA    24.5mA     24.21mA
1.864V    24.78mA    25.5mA     25.76mA
2.091V    23.65mA    23.85mA    25.56mA
2.318V    20.55mA    19.94mA    22.97mA
2.773V    12.75mA    8.663mA    16.22mA
3V        9.139mA    4.878mA    13.11mA
[Pullup]
-1.5V     13.59mA    11mA       15.33mA
-1.136V   15.13mA    13.23mA    15.47mA
-863.6mV  13.87mA    13.89mA    13.92mA
-590.9mV  11.8mA     12.11mA    11.81mA
-409.1mV  9.103mA    9.093mA    9.151mA
954.5mV   -19.76mA   -19.47mA   -19.97mA
1.409V    -27.12mA   -26.48mA   -27.5mA
1.818V    -31.86mA   -30.68mA   -32.37mA
2.045V    -32.96mA   -30.78mA   -33.89mA
2.318V    -31.2mA    -28.31mA   -32.55mA
2.636V    -27.04mA   -23.24mA   -28.32mA
3V        -20.05mA   -15.12mA   -21.81mA
[GND_clamp]
-1.5V     -219.3mA   -131.6mA   -364.3mA
-1.288V   -134.4mA   -79.74mA   -225.6mA
-1.258V   -122.9mA   -72.77mA   -206.3mA
-1.136V   -79.27mA   -46.88mA   -132.4mA
-1.045V   -51.5mA    -31.06mA   -84.11mA
-1.015V   -44.02mA   -26.9mA    -70.91mA
-954.5mV  -31.01mA   -19.7mA    -47.55mA
-863.6mV  -17.48mA   -12.16mA   -23.55mA
-803mV    -11.81mA   -8.597mA   -15.85mA
-681.8mV  -5.986mA   -4.096mA   -9.026mA
-378.8mV  -126.2uA   -131.8uA   -179.7uA
1.5V      1.424nA    36.56nA    1.506nA
[Ramp]
dV/dt_f 0.46566022/0.19523019n  0.4461972/0.25029333n 0.48424665/0.14785949n
dV/dt_r 0.46529293/0.18318135n 0.43995794/0.23413202n 0.49009669/0.13956772n
R_load = 50
[Rising Waveform]
R_fixture = 50
V_fixture = 1.5
V_fixture_min = 1.425
V_fixture_max = 1.575
0s        726.3mV    682.9mV    770.3mV
118ps     726.4mV    682.9mV    800.3mV
219.7ps   758.5mV    682.9mV    1.178V
295.2ps   957mV      683.6mV    1.42V
379.6ps   1.222V     690.5mV    1.537V
529.5ps   1.442V     902.8mV    1.568V
664ps     1.486V     1.201V     1.573V
757.5ps   1.491V     1.318V     1.574V
1.012ns   1.495V     1.411V     1.575V
1.37ns    1.495V     1.418V     1.575V
[Rising Waveform]
R_fixture = 50
V_fixture = 0
V_fixture_min = 0
V_fixture_max = 0
0s        0V         0V         0V
134.8ps   0V         0V         22.16mV
237ps     7.498mV    0V         364.8mV
322ps     199mV      0V         646.5mV
400.6ps   430.8mV    0V         769.5mV
467.1ps   580.5mV    16.19mV    793.7mV
583.5ps   723.9mV    208.5mV    806.2mV
753.2ps   761.3mV    543.3mV    811.8mV
845ps     764mV      632.7mV    813mV
1.407ns   767.1mV    724.2mV    814.7mV
[Falling Waveform]
R_fixture = 50
V_fixture = 1.5
V_fixture_min = 1.425
V_fixture_max = 1.575
0s        1.499V     1.424V     1.574V
127.6ps   1.499V     1.424V     1.562V
230.9ps   1.49V      1.424V     1.29V
335.6ps   1.293V     1.424V     945.9mV
422ps     1.056V     1.424V     813.9mV
599.1ps   781.9mV    1.205V     778.6mV
741.5ps   740.2mV    922.3mV    773.5mV
846ps     735.7mV    798.5mV    771.5mV
1.071ns   732.2mV    703.1mV    769.8mV
1.37ns    730.6mV    693.6mV    769.4mV
[Falling Waveform]
R_fixture = 50
V_fixture = 0
V_fixture_min = 0
V_fixture_max = 0
0s        772.8mV    730.5mV    813.8mV
111.1ps   772.8mV    730.5mV    802.4mV
209.7ps   757mV      730.5mV    482.3mV
307ps     522.8mV    730.5mV    167.9mV
394.3ps   275.7mV    717mV      37.38mV
547ps     62.56mV    477.7mV    7.309mV
714.1ps   10.43mV    171.1mV    2.489mV
765.3ps   8.456mV    118.7mV    0V
1.028ns   5.098mV    17.95mV    0V
1.407ns   3.564mV    6.262mV    0V
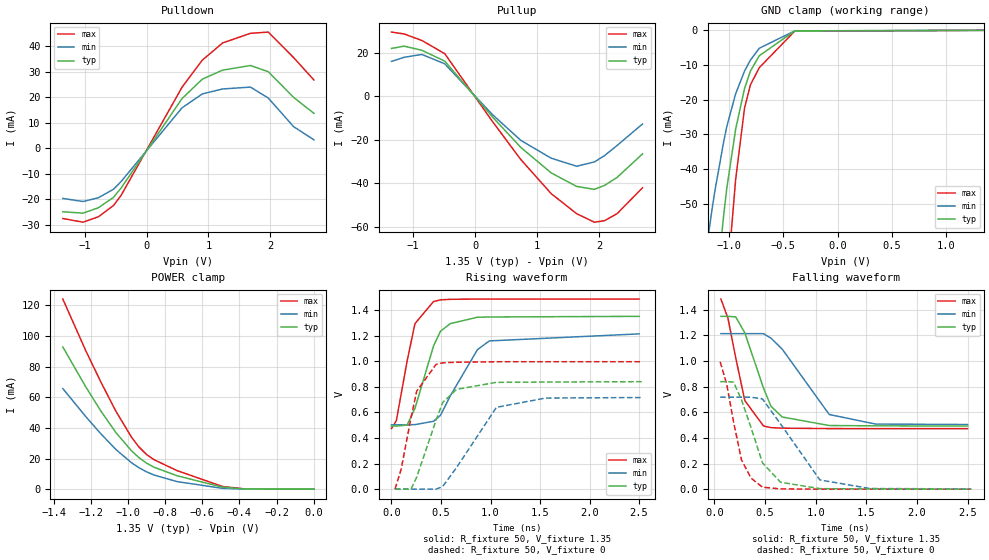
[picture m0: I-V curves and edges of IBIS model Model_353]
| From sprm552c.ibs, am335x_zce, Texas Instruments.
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| Model based on original model for BCSHTLTCSCDVPBFZ_SSDHV
|   Sub model SR11_12MA_10PER_1P35
[model]   Model_353
|[Description]  [1.35V-3-STATE-NOTERM-SR11:12MA, IND, 10%]
|   Slowest slew rate (SR[1:0] = "11"), 0.67 * RExt = 1.500 * Iout
|   (I[2:0] = "111"), 12mA nominal with Rext = 50R,ODT off (ODT[1:0]
|   = "00") CMOS mode,Industrial temperature range (-40C to 125C,
|   25C nominal),10% power supply tolerance
|[Input Load]   NOTERM
|[Output Drive] SR11:12MA
|Voltage   1.35V
|Mode   3-STATE
Model_type   3-state
Polarity   Non-Inverting
Enable   Active-Low
Cref =  15pF
Rref =  100.0000M
Vref =  0V
Vmeas =  0.675
C_comp   1.865048p   1.676829p   1.989968p
[Temperature Range]   25   125   -40
[Voltage Range]   1.35   1.215   1.485
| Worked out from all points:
|   slope of the pulldown table from 0 to 0.203 V, typ, clamps not added: 27 ohm
|   slope of the pullup table from 0 to 0.203 V, typ, clamps not added: 29.4 ohm
|   GND clamp passes 1 mA (typ) near -0.49 V on its own axis
|   POWER clamp passes 1 mA (typ) near -0.47 V on its own axis
|   rising waveform, R_fixture 50, V_fixture 1.35: 20-80 % time 204ps typ, 310ps min, 147ps max; typ from 0.493 V to 1.35 V
|   rising waveform, R_fixture 50, V_fixture 0: 20-80 % time 217ps typ, 330ps min, 161ps max; typ from 0 V to 0.84 V
|   falling waveform, R_fixture 50, V_fixture 1.35: 20-80 % time 226ps typ, 345ps min, 161ps max; typ from 1.35 V to 0.492 V
|   falling waveform, R_fixture 50, V_fixture 0: 20-80 % time 212ps typ, 352ps min, 154ps max; typ from 0.839 V to 0 V
[POWER_clamp]
-1.35V    92.75mA    65.6mA     124mA
-1.227V   66.81mA    47.39mA    90.41mA
-1.145V   50.92mA    36.05mA    69.79mA
-1.064V   36.83mA    25.81mA    50.69mA
-981.8mV  25.17mA    17.34mA    34.13mA
-940.9mV  20.58mA    14.01mA    27.55mA
-900mV    17mA       11.33mA    22.63mA
-859.1mV  14.3mA     9.219mA    19.19mA
-736.4mV  8.769mA    4.944mA    12.14mA
-490.9mV  1.299mA    528.4uA    1.73mA
-368.2mV  117.2uA    50.88uA    117.5uA
0V        1.028nA    11.64nA    1.384nA
[Pulldown]
-1.35V    -24.93mA   -19.69mA   -27.57mA
-1.023V   -25.45mA   -20.89mA   -29.01mA
-777.3mV  -23.35mA   -19.43mA   -26.89mA
-531.8mV  -19.26mA   -16.07mA   -22.46mA
-409.1mV  -15.58mA   -13.03mA   -18.44mA
572.7mV   19.5mA     15.88mA    23.95mA
900mV     27.13mA    21.33mA    34.58mA
1.227V    30.67mA    23.28mA    41.33mA
1.677V    32.49mA    24.02mA    45.13mA
1.964V    30.06mA    19.73mA    45.61mA
2.373V    19.99mA    8.498mA    35.6mA
2.7V      13.72mA    3.331mA    26.83mA
[Pullup]
-1.35V    22.07mA    16.11mA    29.58mA
-1.145V   23.11mA    18.01mA    28.71mA
-859.1mV  21.2mA     19.3mA     25.71mA
-490.9mV  16.24mA    14.99mA    19.65mA
286.4mV   -9.66mA    -8.557mA   -11.82mA
736.4mV   -23.44mA   -20.2mA    -29.01mA
1.227V    -35.16mA   -28.4mA    -44.7mA
1.636V    -41.36mA   -32.08mA   -53.88mA
1.923V    -42.72mA   -30.12mA   -57.81mA
2.086V    -40.91mA   -27.22mA   -57.13mA
2.291V    -37.19mA   -22.51mA   -53.86mA
2.7V      -26.4mA    -12.65mA   -41.97mA
[GND_clamp]
-1.35V    -159.1mA   -94.77mA   -266.2mA
-1.295V   -137.7mA   -81.77mA   -230.9mA
-1.159V   -87.19mA   -51.56mA   -145.9mA
-1.132V   -77.89mA   -46.14mA   -129.9mA
-1.05V    -52.83mA   -31.83mA   -86.44mA
-1.023V   -45.55mA   -27.75mA   -73.68mA
-940.9mV  -28.44mA   -18.28mA   -42.92mA
-859.1mV  -16.79mA   -11.75mA   -22.47mA
-804.5mV  -11.72mA   -8.559mA   -15.69mA
-722.7mV  -7.324mA   -5.161mA   -10.76mA
-395.5mV  -159.1uA   -161.1uA   -232.4uA
1.35V     1.028nA    146.6nA    745.7pA
[Ramp]
dV/dt_f 0.51681914/0.22714405n 0.43014425/0.34888543n 0.60923318/0.16107951n
dV/dt_r 0.50684085/0.21802178n 0.43456411/0.33465324n 0.59966789/0.16084365n
R_load = 50
[Rising Waveform]
R_fixture = 50
V_fixture = 1.35
V_fixture_min = 1.215
V_fixture_max = 1.485
0s        492.8mV    502.6mV    473.6mV
48.98ps   492.8mV    502.6mV    534.8mV
157.9ps   501.3mV    502.6mV    1.001V
236.9ps   630.4mV    504.1mV    1.293V
424.6ps   1.119V     530.2mV    1.466V
495ps     1.234V     577.1mV    1.479V
593.3ps   1.293V     728.4mV    1.483V
867.2ps   1.343V     1.089V     1.485V
987.8ps   1.345V     1.158V     1.485V
2.5ns     1.35V      1.213V     1.485V
[Rising Waveform]
R_fixture = 50
V_fixture = 0
V_fixture_min = 0
V_fixture_max = 0
35.18ps   0V         0V         0V
97.25ps   0V         0V         154.7mV
196.9ps   0V         0V         556.1mV
254.9ps   94.98mV    0V         766.1mV
449.9ps   538.1mV    0V         974.4mV
516.6ps   676.5mV    20.45mV    987mV
657ps     779.7mV    168.7mV    991.5mV
1.06ns    834.4mV    639.4mV    995.3mV
1.557ns   836.9mV    711.8mV    995.5mV
2.535ns   839.7mV    715.8mV    995.5mV
[Falling Waveform]
R_fixture = 50
V_fixture = 1.35
V_fixture_min = 1.215
V_fixture_max = 1.485
64.91ps   1.349V     1.214V     1.484V
134.3ps   1.349V     1.214V     1.335V
210.4ps   1.345V     1.214V     1.028V
300.9ps   1.22V      1.214V     691.4mV
484.9ps   789.6mV    1.214V     493.4mV
558.8ps   647.2mV    1.179V     480.3mV
670.1ps   563.4mV    1.093V     476.2mV
1.134ns   496.8mV    582.8mV    472.8mV
1.59ns    494.4mV    508.5mV    472.6mV
2.5ns     492.5mV    504.5mV    472.6mV
[Falling Waveform]
R_fixture = 50
V_fixture = 0
V_fixture_min = 0
V_fixture_max = 0
57.39ps   839.4mV    717.8mV    994.5mV
122.2ps   839.4mV    717.8mV    818.9mV
189.6ps   835.5mV    717.8mV    525.6mV
268.1ps   697.1mV    717.8mV    228.6mV
361.5ps   482mV      717.8mV    86.79mV
474.8ps   206mV      704.6mV    15.32mV
652.9ps   54.33mV    509.7mV    2.161mV
1.042ns   3.982mV    71.84mV    0V
1.536ns   2.058mV    5.109mV    0V
2.535ns   0V         2.031mV    0V
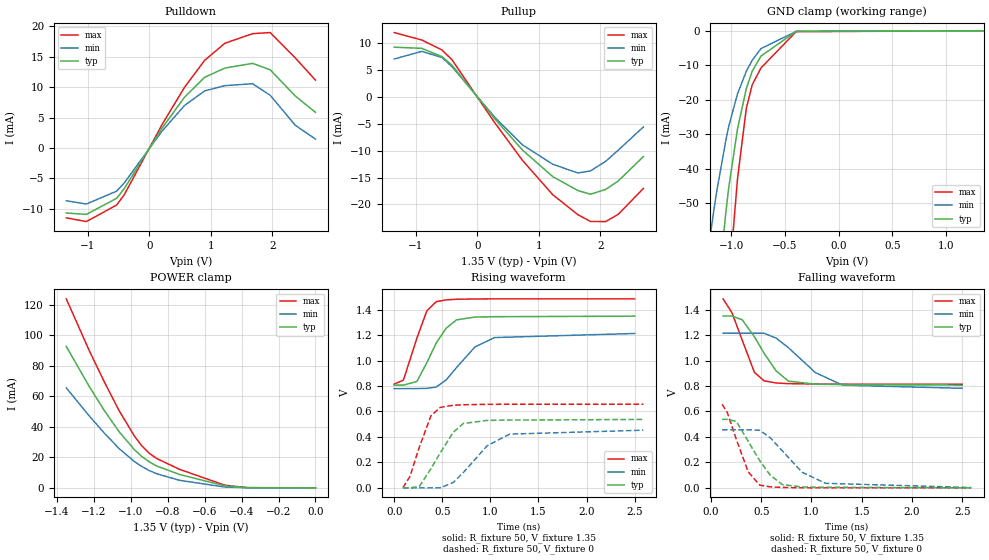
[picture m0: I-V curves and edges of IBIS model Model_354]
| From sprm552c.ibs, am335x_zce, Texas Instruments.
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| Model based on original model for BCSHTLTCSCDVPBFZ_SSDHV
|   Sub model SR10_5MA_10PER_1P35
[model]   Model_354
|[Description]  [1.35V-3-STATE-NOTERM-SR10:5MA, IND, 10%]
|   Fast slew rate (SR[1:0] = "10"), 1.60 * RExt = 0.625 * Iout
|   (I[2:0] = "000"), 5mA nominal with Rext = 50R,ODT off (ODT[1:0]
|   = "00") CMOS mode,Industrial temperature range (-40C to 125C,
|   25C nominal),10% power supply tolerance
|[Input Load]   NOTERM
|[Output Drive] SR10:5MA
|Voltage   1.35V
|Mode   3-STATE
Model_type   3-state
Polarity   Non-Inverting
Enable   Active-Low
Cref =  15pF
Rref =  100.0000M
Vref =  0V
Vmeas =  0.675
C_comp   1.865048p   1.676829p   1.989968p
[Temperature Range]   25   125   -40
[Voltage Range]   1.35   1.215   1.485
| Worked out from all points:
|   slope of the pulldown table from 0 to 0.203 V, typ, clamps not added: 62.9 ohm
|   slope of the pullup table from 0 to 0.203 V, typ, clamps not added: 69.7 ohm
|   GND clamp passes 1 mA (typ) near -0.49 V on its own axis
|   POWER clamp passes 1 mA (typ) near -0.47 V on its own axis
|   rising waveform, R_fixture 50, V_fixture 1.35: 20-80 % time 227ps typ, 316ps min, 167ps max; typ from 0.807 V to 1.35 V
|   rising waveform, R_fixture 50, V_fixture 0: 20-80 % time 258ps typ, 349ps min, 173ps max; typ from 0 V to 0.537 V
|   falling waveform, R_fixture 50, V_fixture 1.35: 20-80 % time 264ps typ, 382ps min, 186ps max; typ from 1.35 V to 0.807 V
|   falling waveform, R_fixture 50, V_fixture 0: 20-80 % time 255ps typ, 340ps min, 174ps max; typ from 0.537 V to 0 V
[POWER_clamp]
-1.35V    92.75mA    65.6mA     124mA
-1.227V   66.81mA    47.39mA    90.41mA
-1.145V   50.92mA    36.05mA    69.79mA
-1.064V   36.83mA    25.81mA    50.69mA
-981.8mV  25.17mA    17.34mA    34.13mA
-940.9mV  20.58mA    14.01mA    27.55mA
-900mV    17mA       11.33mA    22.63mA
-859.1mV  14.3mA     9.219mA    19.19mA
-736.4mV  8.769mA    4.944mA    12.14mA
-490.9mV  1.299mA    528.4uA    1.73mA
-368.2mV  117.2uA    50.88uA    117.5uA
0V        1.028nA    11.64nA    1.384nA
[Pulldown]
-1.35V    -10.68mA   -8.671mA   -11.48mA
-1.023V   -10.91mA   -9.206mA   -12.09mA
-531.8mV  -8.266mA   -7.092mA   -9.372mA
-409.1mV  -6.689mA   -5.75mA    -7.702mA
204.5mV   3.253mA    2.759mA    3.817mA
572.7mV   8.37mA     7.007mA    10mA
900mV     11.64mA    9.405mA    14.43mA
1.227V    13.15mA    10.26mA    17.23mA
1.677V    13.93mA    10.58mA    18.81mA
1.964V    12.87mA    8.684mA    18.99mA
2.373V    8.556mA    3.74mA     14.81mA
2.7V      5.873mA    1.467mA    11.17mA
[Pullup]
-1.35V    9.289mA    7.093mA    12.01mA
-900mV    9.073mA    8.512mA    10.62mA
-572.7mV  7.523mA    7.357mA    8.764mA
-409.1mV  5.918mA    5.637mA    6.921mA
286.4mV   -4.075mA   -3.777mA   -4.815mA
736.4mV   -9.883mA   -8.912mA   -11.81mA
1.227V    -14.82mA   -12.52mA   -18.19mA
1.636V    -17.42mA   -14.14mA   -21.91mA
1.841V    -18.1mA    -13.75mA   -23.18mA
2.086V    -17.21mA   -11.98mA   -23.19mA
2.291V    -15.64mA   -9.903mA   -21.85mA
2.7V      -11.09mA   -5.569mA   -17.02mA
[GND_clamp]
-1.35V    -159.1mA   -94.77mA   -266.2mA
-1.295V   -137.7mA   -81.77mA   -230.9mA
-1.159V   -87.19mA   -51.56mA   -145.9mA
-1.132V   -77.89mA   -46.14mA   -129.9mA
-1.05V    -52.83mA   -31.83mA   -86.44mA
-1.023V   -45.55mA   -27.75mA   -73.68mA
-940.9mV  -28.44mA   -18.28mA   -42.92mA
-859.1mV  -16.79mA   -11.75mA   -22.47mA
-804.5mV  -11.72mA   -8.559mA   -15.69mA
-722.7mV  -7.324mA   -5.161mA   -10.76mA
-395.5mV  -159.1uA   -161.1uA   -232.4uA
1.35V     1.028nA    146.6nA    745.7pA
[Ramp]
dV/dt_f 0.32717816/0.26575132n 0.26300817/0.38920578n 0.40302115/0.18629518n
dV/dt_r 0.32408924/0.25917751n  0.2755794/0.35521105n 0.39518813/0.17340615n
R_load = 50
[Rising Waveform]
R_fixture = 50
V_fixture = 1.35
V_fixture_min = 1.215
V_fixture_max = 1.485
0s        806.9mV    779.4mV    815.2mV
95.96ps   807.1mV    779.4mV    846.2mV
236.3ps   836mV      780.2mV    1.177V
339ps     983.3mV    781.8mV    1.39V
437.2ps   1.138V     792mV      1.463V
539.7ps   1.254V     847.7mV    1.477V
647.5ps   1.32V      944.6mV    1.482V
839.4ps   1.342V     1.107V     1.484V
1.044ns   1.345V     1.181V     1.485V
2.5ns     1.349V     1.213V     1.485V
[Rising Waveform]
R_fixture = 50
V_fixture = 0
V_fixture_min = 0
V_fixture_max = 0
91.09ps   0V         0V         0V
164.3ps   0V         0V         91.31mV
261.3ps   10.38mV    0V         319.8mV
381.5ps   150.2mV    0V         565.1mV
478.2ps   274.5mV    0V         632.2mV
614.3ps   436.7mV    42.24mV    649mV
718.6ps   505.6mV    119.7mV    653mV
965.1ps   529.8mV    329.7mV    656.2mV
1.199ns   532.6mV    422.1mV    656.8mV
2.591ns   537.5mV    453.3mV    657mV
[Falling Waveform]
R_fixture = 50
V_fixture = 1.35
V_fixture_min = 1.215
V_fixture_max = 1.485
120.3ps   1.349V     1.214V     1.484V
209.1ps   1.349V     1.214V     1.374V
309.8ps   1.32V      1.214V     1.161V
432ps     1.186V     1.214V     907.2mV
528.4ps   1.057V     1.214V     840.2mV
647.8ps   918.7mV    1.176V     823.5mV
770.1ps   838mV      1.101V     818.3mV
1.039ns   814.1mV    905mV      815.1mV
1.309ns   810.9mV    806.2mV    814.4mV
2.5ns     806.8mV    781.8mV    814.2mV
[Falling Waveform]
R_fixture = 50
V_fixture = 0
V_fixture_min = 0
V_fixture_max = 0
110.4ps   537.5mV    455.9mV    656.1mV
162.2ps   537.5mV    455.9mV    591.5mV
251.3ps   522.5mV    455.9mV    381.7mV
369.7ps   365.7mV    455.9mV    126.2mV
484.6ps   214mV      451.9mV    21.59mV
590.1ps   99.16mV    392.9mV    7.656mV
710.2ps   25.39mV    290.2mV    3.363mV
906.9ps   7.067mV    122.3mV    0V
1.141ns   4.574mV    35.46mV    0V
2.591ns   0V         2.473mV    0V
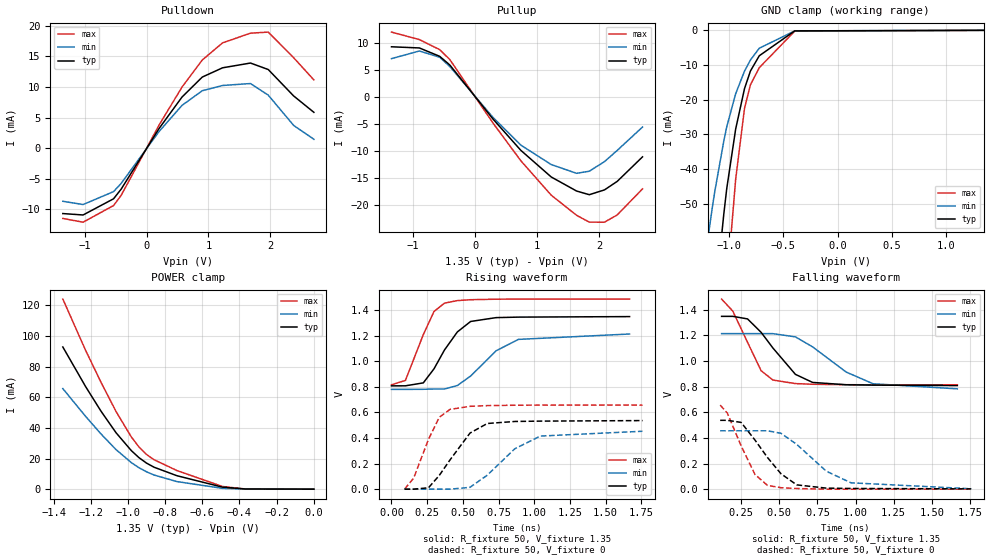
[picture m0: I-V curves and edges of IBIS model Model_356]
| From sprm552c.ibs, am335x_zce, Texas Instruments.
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| Model based on original model for BCSHTLTCSCDVPBFZ_SSDHV
|   Sub model SR01_5MA_10PER_1P35
[model]   Model_356
|[Description]  [1.35V-3-STATE-NOTERM-SR01:5MA, IND, 10%]
|   Slow slew rate (SR[1:0] = "01"), 1.60 * RExt = 0.625 * Iout
|   (I[2:0] = "000"), 5mA nominal with Rext = 50R,ODT off (ODT[1:0]
|   = "00") CMOS mode,Industrial temperature range (-40C to 125C,
|   25C nominal),10% power supply tolerance
|[Input Load]   NOTERM
|[Output Drive] SR01:5MA
|Voltage   1.35V
|Mode   3-STATE
Model_type   3-state
Polarity   Non-Inverting
Enable   Active-Low
Cref =  15pF
Rref =  100.0000M
Vref =  0V
Vmeas =  0.675
C_comp   1.865048p   1.676829p   1.989968p
[Temperature Range]   25   125   -40
[Voltage Range]   1.35   1.215   1.485
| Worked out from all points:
|   slope of the pulldown table from 0 to 0.203 V, typ, clamps not added: 62.9 ohm
|   slope of the pullup table from 0 to 0.203 V, typ, clamps not added: 69.7 ohm
|   GND clamp passes 1 mA (typ) near -0.49 V on its own axis
|   POWER clamp passes 1 mA (typ) near -0.47 V on its own axis
|   rising waveform, R_fixture 50, V_fixture 1.35: 20-80 % time 186ps typ, 258ps min, 138ps max; typ from 0.807 V to 1.35 V
|   rising waveform, R_fixture 50, V_fixture 0: 20-80 % time 207ps typ, 278ps min, 141ps max; typ from 0 V to 0.536 V
|   falling waveform, R_fixture 50, V_fixture 1.35: 20-80 % time 218ps typ, 312ps min, 155ps max; typ from 1.35 V to 0.809 V
|   falling waveform, R_fixture 50, V_fixture 0: 20-80 % time 208ps typ, 276ps min, 145ps max; typ from 0.537 V to 0.002 V
[POWER_clamp]
-1.35V    92.75mA    65.6mA     124mA
-1.227V   66.81mA    47.39mA    90.41mA
-1.145V   50.92mA    36.05mA    69.79mA
-1.064V   36.83mA    25.81mA    50.69mA
-981.8mV  25.17mA    17.34mA    34.13mA
-940.9mV  20.58mA    14.01mA    27.55mA
-900mV    17mA       11.33mA    22.63mA
-859.1mV  14.3mA     9.219mA    19.19mA
-736.4mV  8.769mA    4.944mA    12.14mA
-490.9mV  1.299mA    528.4uA    1.73mA
-368.2mV  117.2uA    50.88uA    117.5uA
0V        1.028nA    11.64nA    1.384nA
[Pulldown]
-1.35V    -10.68mA   -8.671mA   -11.48mA
-1.023V   -10.91mA   -9.206mA   -12.09mA
-531.8mV  -8.266mA   -7.092mA   -9.372mA
-409.1mV  -6.689mA   -5.75mA    -7.702mA
204.5mV   3.253mA    2.759mA    3.817mA
572.7mV   8.37mA     7.007mA    10mA
900mV     11.64mA    9.405mA    14.43mA
1.227V    13.15mA    10.26mA    17.23mA
1.677V    13.93mA    10.58mA    18.81mA
1.964V    12.87mA    8.684mA    18.99mA
2.373V    8.556mA    3.74mA     14.81mA
2.7V      5.873mA    1.467mA    11.17mA
[Pullup]
-1.35V    9.289mA    7.093mA    12.01mA
-900mV    9.073mA    8.512mA    10.62mA
-572.7mV  7.523mA    7.357mA    8.764mA
-409.1mV  5.918mA    5.637mA    6.921mA
286.4mV   -4.075mA   -3.777mA   -4.815mA
736.4mV   -9.883mA   -8.912mA   -11.81mA
1.227V    -14.82mA   -12.52mA   -18.19mA
1.636V    -17.42mA   -14.14mA   -21.91mA
1.841V    -18.1mA    -13.75mA   -23.18mA
2.086V    -17.21mA   -11.98mA   -23.19mA
2.291V    -15.64mA   -9.903mA   -21.85mA
2.7V      -11.09mA   -5.569mA   -17.02mA
[GND_clamp]
-1.35V    -159.1mA   -94.77mA   -266.2mA
-1.295V   -137.7mA   -81.77mA   -230.9mA
-1.159V   -87.19mA   -51.56mA   -145.9mA
-1.132V   -77.89mA   -46.14mA   -129.9mA
-1.05V    -52.83mA   -31.83mA   -86.44mA
-1.023V   -45.55mA   -27.75mA   -73.68mA
-940.9mV  -28.44mA   -18.28mA   -42.92mA
-859.1mV  -16.79mA   -11.75mA   -22.47mA
-804.5mV  -11.72mA   -8.559mA   -15.69mA
-722.7mV  -7.324mA   -5.161mA   -10.76mA
-395.5mV  -159.1uA   -161.1uA   -232.4uA
1.35V     1.028nA    146.6nA    745.7pA
[Ramp]
dV/dt_f 0.32725832/0.22054724n   0.263067/0.31957297n 0.40304007/0.15531615n
dV/dt_r 0.32418354/0.20886528n 0.27557178/0.28360386n  0.3952587/0.14177707n
R_load = 50
[Rising Waveform]
R_fixture = 50
V_fixture = 1.35
V_fixture_min = 1.215
V_fixture_max = 1.485
0s        806.9mV    779.4mV    815.2mV
97.58ps   807.3mV    779.4mV    849.5mV
222.7ps   830.3mV    780.2mV    1.207V
297.7ps   940.1mV    782.5mV    1.388V
371ps     1.087V     782.3mV    1.453V
461ps     1.228V     809.6mV    1.473V
554.2ps   1.31V      883.7mV    1.48V
732.7ps   1.34V      1.081V     1.484V
888.9ps   1.344V     1.17V      1.485V
1.667ns   1.348V     1.212V     1.485V
[Rising Waveform]
R_fixture = 50
V_fixture = 0
V_fixture_min = 0
V_fixture_max = 0
91.53ps   0V         0V         0V
155.3ps   0V         0V         86.4mV
259ps     10.77mV    0V         389.4mV
334.6ps   107.3mV    0V         561.2mV
410ps     228.8mV    0V         623.4mV
549.7ps   438.2mV    14.23mV    647.1mV
670.7ps   513mV      109.4mV    652.6mV
863.4ps   528.8mV    315.5mV    655.7mV
1.043ns   531.6mV    414.9mV    656.6mV
1.758ns   535.7mV    452.4mV    657mV
[Falling Waveform]
R_fixture = 50
V_fixture = 1.35
V_fixture_min = 1.215
V_fixture_max = 1.485
122.1ps   1.349V     1.214V     1.484V
195.6ps   1.349V     1.214V     1.39V
292.3ps   1.329V     1.214V     1.146V
381.4ps   1.224V     1.214V     924.3mV
458.4ps   1.102V     1.214V     851.8mV
605.8ps   896.4mV    1.189V     824.2mV
718.2ps   833.4mV    1.111V     818.9mV
938.4ps   815.1mV    914.2mV    815.5mV
1.115ns   812.2mV    822.8mV    814.7mV
1.667ns   808.7mV    783.2mV    814.3mV
[Falling Waveform]
R_fixture = 50
V_fixture = 0
V_fixture_min = 0
V_fixture_max = 0
112.7ps   537.4mV    455.7mV    656.1mV
159.5ps   537.4mV    455.7mV    594.2mV
249.9ps   521.3mV    455.7mV    338.7mV
340.8ps   383.6mV    455.7mV    114.7mV
422.1ps   248.3mV    455.7mV    29.77mV
511.1ps   120.6mV    436.4mV    11.32mV
614.4ps   33.5mV     349.8mV    5.163mV
808.8ps   8.03mV     139.9mV    0V
970.2ps   5.529mV    49.65mV    0V
1.758ns   2.163mV    3.106mV    0V
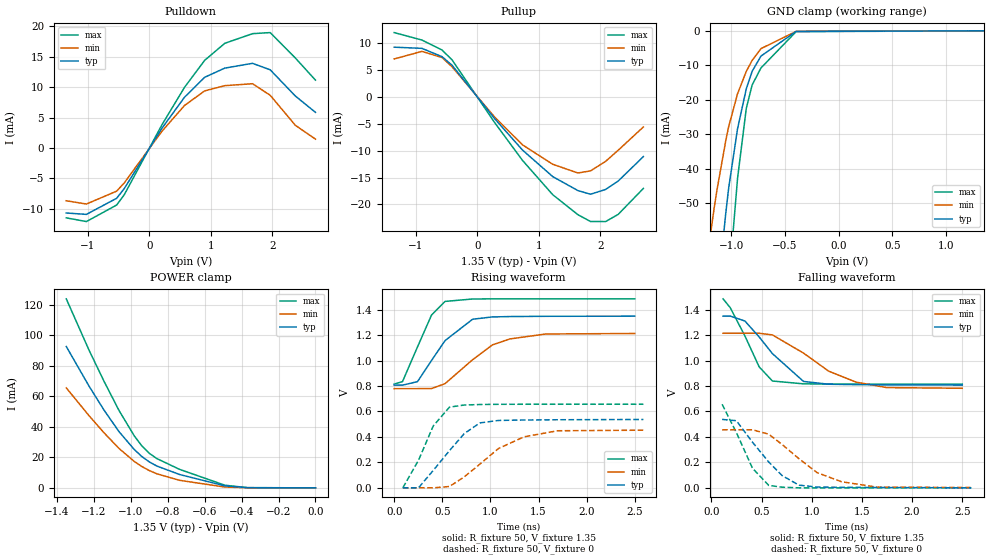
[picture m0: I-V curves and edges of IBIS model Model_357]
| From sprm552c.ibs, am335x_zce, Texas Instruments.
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| Model based on original model for BCSHTLTCSCDVPBFZ_SSDHV
|   Sub model SR11_5MA_10PER_1P35
[model]   Model_357
|[Description]  [1.35V-3-STATE-NOTERM-SR11:5MA, IND, 10%]
|   Slowest slew rate (SR[1:0] = "11"), 1.60 * RExt = 0.625 * Iout
|   (I[2:0] = "000"), 5mA nominal with Rext = 50R,ODT off (ODT[1:0]
|   = "00") CMOS mode,Industrial temperature range (-40C to 125C,
|   25C nominal),10% power supply tolerance
|[Input Load]   NOTERM
|[Output Drive] SR11:5MA
|Voltage   1.35V
|Mode   3-STATE
Model_type   3-state
Polarity   Non-Inverting
Enable   Active-Low
Cref =  15pF
Rref =  100.0000M
Vref =  0V
Vmeas =  0.675
C_comp   1.865048p   1.676829p   1.989968p
[Temperature Range]   25   125   -40
[Voltage Range]   1.35   1.215   1.485
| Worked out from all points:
|   slope of the pulldown table from 0 to 0.203 V, typ, clamps not added: 62.9 ohm
|   slope of the pullup table from 0 to 0.203 V, typ, clamps not added: 69.7 ohm
|   GND clamp passes 1 mA (typ) near -0.49 V on its own axis
|   POWER clamp passes 1 mA (typ) near -0.47 V on its own axis
|   rising waveform, R_fixture 50, V_fixture 1.35: 20-80 % time 311ps typ, 424ps min, 226ps max; typ from 0.807 V to 1.35 V
|   rising waveform, R_fixture 50, V_fixture 0: 20-80 % time 358ps typ, 480ps min, 236ps max; typ from 0 V to 0.537 V
|   falling waveform, R_fixture 50, V_fixture 1.35: 20-80 % time 348ps typ, 518ps min, 242ps max; typ from 1.35 V to 0.807 V
|   falling waveform, R_fixture 50, V_fixture 0: 20-80 % time 343ps typ, 451ps min, 231ps max; typ from 0.537 V to 0 V
[POWER_clamp]
-1.35V    92.75mA    65.6mA     124mA
-1.227V   66.81mA    47.39mA    90.41mA
-1.145V   50.92mA    36.05mA    69.79mA
-1.064V   36.83mA    25.81mA    50.69mA
-981.8mV  25.17mA    17.34mA    34.13mA
-940.9mV  20.58mA    14.01mA    27.55mA
-900mV    17mA       11.33mA    22.63mA
-859.1mV  14.3mA     9.219mA    19.19mA
-736.4mV  8.769mA    4.944mA    12.14mA
-490.9mV  1.299mA    528.4uA    1.73mA
-368.2mV  117.2uA    50.88uA    117.5uA
0V        1.028nA    11.64nA    1.384nA
[Pulldown]
-1.35V    -10.68mA   -8.671mA   -11.48mA
-1.023V   -10.91mA   -9.206mA   -12.09mA
-531.8mV  -8.266mA   -7.092mA   -9.372mA
-409.1mV  -6.689mA   -5.75mA    -7.702mA
204.5mV   3.253mA    2.759mA    3.817mA
572.7mV   8.37mA     7.007mA    10mA
900mV     11.64mA    9.405mA    14.43mA
1.227V    13.15mA    10.26mA    17.23mA
1.677V    13.93mA    10.58mA    18.81mA
1.964V    12.87mA    8.684mA    18.99mA
2.373V    8.556mA    3.74mA     14.81mA
2.7V      5.873mA    1.467mA    11.17mA
[Pullup]
-1.35V    9.289mA    7.093mA    12.01mA
-900mV    9.073mA    8.512mA    10.62mA
-572.7mV  7.523mA    7.357mA    8.764mA
-409.1mV  5.918mA    5.637mA    6.921mA
286.4mV   -4.075mA   -3.777mA   -4.815mA
736.4mV   -9.883mA   -8.912mA   -11.81mA
1.227V    -14.82mA   -12.52mA   -18.19mA
1.636V    -17.42mA   -14.14mA   -21.91mA
1.841V    -18.1mA    -13.75mA   -23.18mA
2.086V    -17.21mA   -11.98mA   -23.19mA
2.291V    -15.64mA   -9.903mA   -21.85mA
2.7V      -11.09mA   -5.569mA   -17.02mA
[GND_clamp]
-1.35V    -159.1mA   -94.77mA   -266.2mA
-1.295V   -137.7mA   -81.77mA   -230.9mA
-1.159V   -87.19mA   -51.56mA   -145.9mA
-1.132V   -77.89mA   -46.14mA   -129.9mA
-1.05V    -52.83mA   -31.83mA   -86.44mA
-1.023V   -45.55mA   -27.75mA   -73.68mA
-940.9mV  -28.44mA   -18.28mA   -42.92mA
-859.1mV  -16.79mA   -11.75mA   -22.47mA
-804.5mV  -11.72mA   -8.559mA   -15.69mA
-722.7mV  -7.324mA   -5.161mA   -10.76mA
-395.5mV  -159.1uA   -161.1uA   -232.4uA
1.35V     1.028nA    146.6nA    745.7pA
[Ramp]
dV/dt_f  0.3272389/0.35078475n 0.26296863/0.52719953n 0.40311251/0.24317375n
dV/dt_r 0.32408652/0.35966191n 0.27549481/0.48985154n 0.39519991/0.23629073n
R_load = 50
[Rising Waveform]
R_fixture = 50
V_fixture = 1.35
V_fixture_min = 1.215
V_fixture_max = 1.485
0s        806.9mV    779.4mV    815.2mV
86.4ps    806.9mV    779.4mV    835.1mV
242.5ps   834.8mV    779.6mV    1.108V
388.2ps   1.001V     780.3mV    1.358V
528.5ps   1.157V     818.7mV    1.465V
815.1ps   1.325V     1.007V     1.484V
1.02ns    1.343V     1.123V     1.485V
1.202ns   1.346V     1.17V      1.485V
1.574ns   1.348V     1.209V     1.485V
2.5ns     1.349V     1.213V     1.485V
[Rising Waveform]
R_fixture = 50
V_fixture = 0
V_fixture_min = 0
V_fixture_max = 0
89.61ps   0V         0V         0V
252.6ps   0V         0V         216.6mV
405.6ps   136.6mV    0V         486.1mV
574.3ps   292.2mV    10.57mV    634.2mV
728.2ps   426.5mV    86.07mV    650.9mV
891ps     510.3mV    186.6mV    654.9mV
1.084ns   529.7mV    309.2mV    656.4mV
1.351ns   533.1mV    401.4mV    656.9mV
1.7ns     535.1mV    448.6mV    657mV
2.59ns    537.3mV    453.2mV    657mV
[Falling Waveform]
R_fixture = 50
V_fixture = 1.35
V_fixture_min = 1.215
V_fixture_max = 1.485
116ps     1.349V     1.214V     1.484V
186.7ps   1.349V     1.214V     1.416V
333.9ps   1.31V      1.214V     1.193V
475.9ps   1.185V     1.214V     950mV
608.1ps   1.054V     1.201V     838.9mV
918.1ps   835.5mV    1.058V     816.7mV
1.169ns   813.7mV    916.2mV    814.8mV
1.442ns   810.5mV    830.1mV    814.4mV
1.748ns   808.9mV    787.2mV    814.3mV
2.5ns     807mV      781.9mV    814.2mV
[Falling Waveform]
R_fixture = 50
V_fixture = 0
V_fixture_min = 0
V_fixture_max = 0
106.7ps   537.4mV    455.8mV    656.1mV
249.2ps   527.2mV    455.8mV    433.4mV
409.3ps   358.4mV    455.8mV    154.1mV
571.5ps   202.9mV    421.2mV    19.22mV
704.5ps   96.34mV    340.4mV    5.223mV
872.9ps   21.06mV    228.7mV    0V
1.053ns   6.439mV    119.5mV    0V
1.297ns   4.12mV     47.8mV     0V
1.646ns   2.687mV    6.035mV    0V
2.59ns    0V         2.593mV    0V
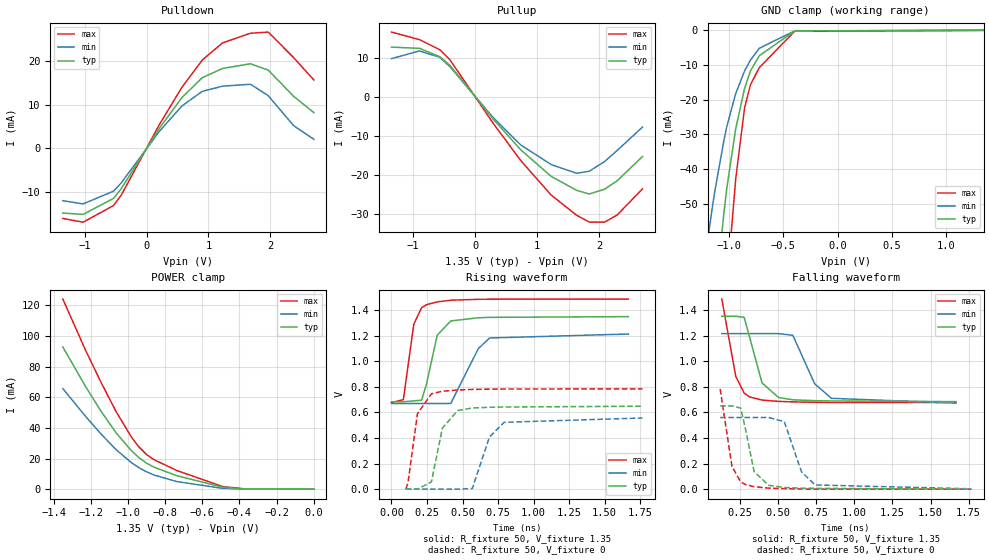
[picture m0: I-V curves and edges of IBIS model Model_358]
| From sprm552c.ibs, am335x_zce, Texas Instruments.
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| Model based on original model for BCSHTLTCSCDVPBFZ_SSDHV
|   Sub model SR00_7MA_10PER_1P35
[model]   Model_358
|[Description]  [1.35V-3-STATE-NOTERM-SR00:7MA, IND, 10%]
|   Fastest slew rate (SR[1:0] = "00"), 1.14 * RExt = 0.875 * Iout
|   (I[2:0] = "010"), 7mA nominal with Rext = 50R,ODT off (ODT[1:0]
|   = "00") CMOS mode,Industrial temperature range (-40C to 125C,
|   25C nominal),10% power supply tolerance
|[Input Load]   NOTERM
|[Output Drive] SR00:7MA
|Voltage   1.35V
|Mode   3-STATE
Model_type   3-state
Polarity   Non-Inverting
Enable   Active-Low
Cref =  15pF
Rref =  100.0000M
Vref =  0V
Vmeas =  0.675
C_comp   1.865048p   1.676829p   1.989968p
[Temperature Range]   25   125   -40
[Voltage Range]   1.35   1.215   1.485
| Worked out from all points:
|   slope of the pulldown table from 0 to 0.203 V, typ, clamps not added: 45.3 ohm
|   slope of the pullup table from 0 to 0.203 V, typ, clamps not added: 50.7 ohm
|   GND clamp passes 1 mA (typ) near -0.49 V on its own axis
|   POWER clamp passes 1 mA (typ) near -0.47 V on its own axis
|   rising waveform, R_fixture 50, V_fixture 1.35: 20-80 % time 81.3ps typ, 124ps min, 59.7ps max; typ from 0.682 V to 1.35 V
|   rising waveform, R_fixture 50, V_fixture 0: 20-80 % time 80.7ps typ, 103ps min, 65ps max; typ from 0 V to 0.648 V
|   falling waveform, R_fixture 50, V_fixture 1.35: 20-80 % time 92.5ps typ, 128ps min, 69.5ps max; typ from 1.35 V to 0.684 V
|   falling waveform, R_fixture 50, V_fixture 0: 20-80 % time 66.2ps typ, 92.1ps min, 52.9ps max; typ from 0.65 V to 0 V
[POWER_clamp]
-1.35V    92.75mA    65.6mA     124mA
-1.227V   66.81mA    47.39mA    90.41mA
-1.145V   50.92mA    36.05mA    69.79mA
-1.064V   36.83mA    25.81mA    50.69mA
-981.8mV  25.17mA    17.34mA    34.13mA
-940.9mV  20.58mA    14.01mA    27.55mA
-900mV    17mA       11.33mA    22.63mA
-859.1mV  14.3mA     9.219mA    19.19mA
-736.4mV  8.769mA    4.944mA    12.14mA
-490.9mV  1.299mA    528.4uA    1.73mA
-368.2mV  117.2uA    50.88uA    117.5uA
0V        1.028nA    11.64nA    1.384nA
[Pulldown]
-1.35V    -14.84mA   -12.01mA   -16.08mA
-1.023V   -15.15mA   -12.75mA   -16.93mA
-531.8mV  -11.48mA   -9.816mA   -13.12mA
-409.1mV  -9.285mA   -7.958mA   -10.78mA
204.5mV   4.516mA    3.818mA    5.34mA
572.7mV   11.62mA    9.698mA    13.99mA
900mV     16.16mA    13.02mA    20.2mA
1.227V    18.26mA    14.21mA    24.12mA
1.677V    19.34mA    14.65mA    26.33mA
1.964V    17.88mA    12.03mA    26.59mA
2.373V    11.89mA    5.181mA    20.74mA
2.7V      8.16mA     2.032mA    15.64mA
[Pullup]
-1.35V    12.77mA    9.823mA    16.63mA
-900mV    12.47mA    11.79mA    14.7mA
-572.7mV  10.34mA    10.18mA    12.13mA
-409.1mV  8.134mA    7.802mA    9.577mA
286.4mV   -5.6mA     -5.227mA   -6.662mA
736.4mV   -13.58mA   -12.33mA   -16.35mA
1.227V    -20.37mA   -17.34mA   -25.17mA
1.636V    -23.95mA   -19.58mA   -30.33mA
1.841V    -24.89mA   -19.04mA   -32.09mA
2.086V    -23.67mA   -16.6mA    -32.12mA
2.291V    -21.51mA   -13.72mA   -30.27mA
2.7V      -15.26mA   -7.714mA   -23.57mA
[GND_clamp]
-1.35V    -159.1mA   -94.77mA   -266.2mA
-1.295V   -137.7mA   -81.77mA   -230.9mA
-1.159V   -87.19mA   -51.56mA   -145.9mA
-1.132V   -77.89mA   -46.14mA   -129.9mA
-1.05V    -52.83mA   -31.83mA   -86.44mA
-1.023V   -45.55mA   -27.75mA   -73.68mA
-940.9mV  -28.44mA   -18.28mA   -42.92mA
-859.1mV  -16.79mA   -11.75mA   -22.47mA
-804.5mV  -11.72mA   -8.559mA   -15.69mA
-722.7mV  -7.324mA   -5.161mA   -10.76mA
-395.5mV  -159.1uA   -161.1uA   -232.4uA
1.35V     1.028nA    146.6nA    745.7pA
[Ramp]
dV/dt_f 0.40696797/93.848763p 0.33417944/0.13116899n 0.49002658/69.752619p
dV/dt_r 0.39811695/81.910563p 0.34678823/0.10640667n 0.47706533/65.217015p
R_load = 50
[Rising Waveform]
R_fixture = 50
V_fixture = 1.35
V_fixture_min = 1.215
V_fixture_max = 1.485
0s        682mV      669.3mV    677.3mV
83.66ps   682mV      669.3mV    699.1mV
156.8ps   689.7mV    669.3mV    1.288V
211.8ps   694.8mV    669.3mV    1.417V
245.8ps   818.8mV    669.3mV    1.441V
321.7ps   1.202V     669.3mV    1.463V
417.1ps   1.314V     669.3mV    1.476V
611.3ps   1.339V     1.098V     1.483V
690.5ps   1.342V     1.181V     1.484V
1.667ns   1.348V     1.212V     1.485V
[Rising Waveform]
R_fixture = 50
V_fixture = 0
V_fixture_min = 0
V_fixture_max = 0
100.6ps   0V         0V         0V
116.2ps   0V         0V         50.37mV
182.5ps   0V         0V         588.9mV
280.9ps   56.83mV    0V         744.8mV
358.1ps   476.1mV    0V         764.9mV
465.8ps   614.2mV    0V         774.8mV
569ps     634.1mV    5.431mV    779mV
689.9ps   639.7mV    408.1mV    781.2mV
792.6ps   641.7mV    522.3mV    782.2mV
1.767ns   648mV      556.1mV    783.5mV
[Falling Waveform]
R_fixture = 50
V_fixture = 1.35
V_fixture_min = 1.215
V_fixture_max = 1.485
130.7ps   1.351V     1.215V     1.485V
222.2ps   1.351V     1.215V     881.1mV
277.3ps   1.342V     1.215V     750mV
313.5ps   1.185V     1.215V     720.3mV
394.6ps   830.2mV    1.215V     695.8mV
502.9ps   715.9mV    1.215V     685.8mV
596.6ps   698.2mV    1.202V     681.9mV
740ps     691.2mV    822.9mV    678.4mV
849.8ps   689.1mV    709.6mV    677.4mV
1.667ns   683.7mV    672.7mV    676.6mV
[Falling Waveform]
R_fixture = 50
V_fixture = 0
V_fixture_min = 0
V_fixture_max = 0
119.8ps   650.5mV    559.6mV    783mV
197.1ps   650.5mV    559.6mV    178.5mV
254.5ps   633.7mV    559.6mV    56.33mV
285.4ps   472.7mV    559.6mV    36.67mV
342.7ps   137.2mV    559.6mV    19.35mV
437.7ps   30.3mV     559.6mV    8.21mV
540.7ps   13.14mV    527.6mV    3.961mV
653.3ps   8.033mV    136.4mV    2.009mV
742ps     6.423mV    32.85mV    0V
1.767ns   0V         2.908mV    0V
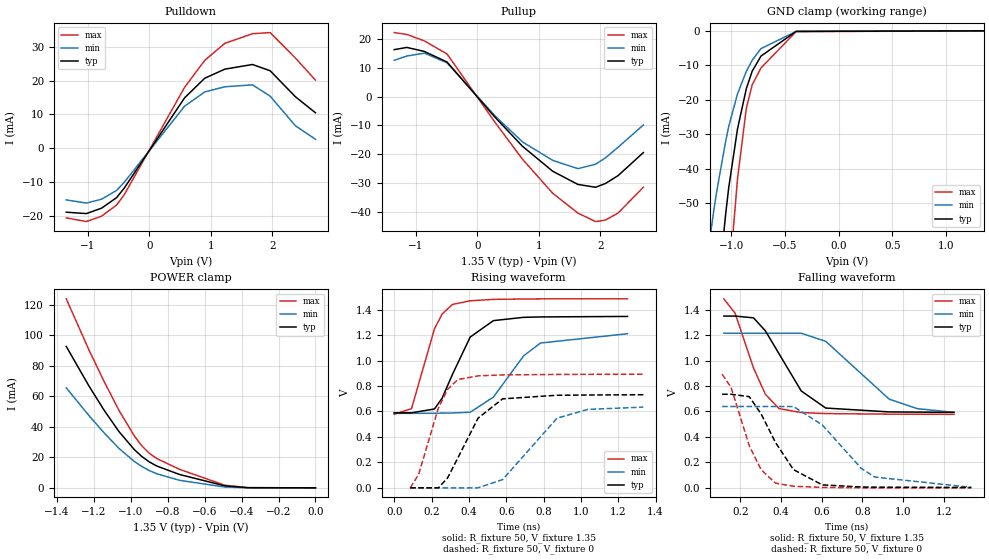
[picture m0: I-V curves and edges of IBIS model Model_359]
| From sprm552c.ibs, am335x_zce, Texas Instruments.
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| Model based on original model for BCSHTLTCSCDVPBFZ_SSDHV
|   Sub model SR01_9MA_10PER_1P35
[model]   Model_359
|[Description]  [1.35V-3-STATE-NOTERM-SR01:9MA, IND, 10%]
|   Slow slew rate (SR[1:0] = "01"), 0.88 * RExt = 1.125 * Iout
|   (I[2:0] = "100"), 9mA nominal with Rext = 50R,ODT off (ODT[1:0]
|   = "00") CMOS mode,Industrial temperature range (-40C to 125C,
|   25C nominal),10% power supply tolerance
|[Input Load]   NOTERM
|[Output Drive] SR01:9MA
|Voltage   1.35V
|Mode   3-STATE
Model_type   3-state
Polarity   Non-Inverting
Enable   Active-Low
Cref =  15pF
Rref =  100.0000M
Vref =  0V
Vmeas =  0.675
C_comp   1.865048p   1.676829p   1.989968p
[Temperature Range]   25   125   -40
[Voltage Range]   1.35   1.215   1.485
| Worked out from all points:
|   slope of the pulldown table from 0 to 0.203 V, typ, clamps not added: 35.4 ohm
|   slope of the pullup table from 0 to 0.203 V, typ, clamps not added: 39.9 ohm
|   GND clamp passes 1 mA (typ) near -0.49 V on its own axis
|   POWER clamp passes 1 mA (typ) near -0.47 V on its own axis
|   rising waveform, R_fixture 50, V_fixture 1.35: 20-80 % time 144ps typ, 197ps min, 106ps max; typ from 0.589 V to 1.35 V
|   rising waveform, R_fixture 50, V_fixture 0: 20-80 % time 158ps typ, 208ps min, 115ps max; typ from 0 V to 0.732 V
|   falling waveform, R_fixture 50, V_fixture 1.35: 20-80 % time 171ps typ, 238ps min, 122ps max; typ from 1.35 V to 0.593 V
|   falling waveform, R_fixture 50, V_fixture 0: 20-80 % time 157ps typ, 218ps min, 118ps max; typ from 0.735 V to 0.003 V
[POWER_clamp]
-1.35V    92.75mA    65.6mA     124mA
-1.227V   66.81mA    47.39mA    90.41mA
-1.145V   50.92mA    36.05mA    69.79mA
-1.064V   36.83mA    25.81mA    50.69mA
-981.8mV  25.17mA    17.34mA    34.13mA
-940.9mV  20.58mA    14.01mA    27.55mA
-900mV    17mA       11.33mA    22.63mA
-859.1mV  14.3mA     9.219mA    19.19mA
-736.4mV  8.769mA    4.944mA    12.14mA
-490.9mV  1.299mA    528.4uA    1.73mA
-368.2mV  117.2uA    50.88uA    117.5uA
0V        1.028nA    11.64nA    1.384nA
[Pulldown]
-1.35V    -18.99mA   -15.35mA   -20.67mA
-1.023V   -19.4mA    -16.29mA   -21.76mA
-777.3mV  -17.8mA    -15.15mA   -20.17mA
-531.8mV  -14.68mA   -12.54mA   -16.86mA
-409.1mV  -11.88mA   -10.16mA   -13.84mA
572.7mV   14.87mA    12.39mA    17.98mA
900mV     20.68mA    16.63mA    25.96mA
1.227V    23.37mA    18.15mA    31.01mA
1.677V    24.75mA    18.72mA    33.86mA
1.964V    22.89mA    15.38mA    34.2mA
2.373V    15.22mA    6.623mA    26.68mA
2.7V      10.45mA    2.596mA    20.12mA
[Pullup]
-1.35V    16.26mA    12.55mA    22.18mA
-1.145V   17.03mA    14.04mA    21.54mA
-859.1mV  15.63mA    15.05mA    19.29mA
-490.9mV  11.97mA    11.69mA    14.75mA
286.4mV   -7.124mA   -6.675mA   -8.876mA
736.4mV   -17.28mA   -15.75mA   -21.78mA
1.227V    -25.92mA   -22.15mA   -33.55mA
1.636V    -30.48mA   -25.01mA   -40.42mA
1.923V    -31.47mA   -23.48mA   -43.36mA
2.086V    -30.13mA   -21.22mA   -42.83mA
2.291V    -27.39mA   -17.54mA   -40.37mA
2.7V      -19.43mA   -9.86mA    -31.45mA
[GND_clamp]
-1.35V    -159.1mA   -94.77mA   -266.2mA
-1.295V   -137.7mA   -81.77mA   -230.9mA
-1.159V   -87.19mA   -51.56mA   -145.9mA
-1.132V   -77.89mA   -46.14mA   -129.9mA
-1.05V    -52.83mA   -31.83mA   -86.44mA
-1.023V   -45.55mA   -27.75mA   -73.68mA
-940.9mV  -28.44mA   -18.28mA   -42.92mA
-859.1mV  -16.79mA   -11.75mA   -22.47mA
-804.5mV  -11.72mA   -8.559mA   -15.69mA
-722.7mV  -7.324mA   -5.161mA   -10.76mA
-395.5mV  -159.1uA   -161.1uA   -232.4uA
1.35V     1.028nA    146.6nA    745.7pA
[Ramp]
dV/dt_f 0.45854827/0.17317413n 0.37995975/0.24503837n 0.54590974/0.1228887n
dV/dt_r 0.44384387/0.16057565n 0.38648652/0.21244418n 0.53785673/0.11545203n
R_load = 50
[Rising Waveform]
R_fixture = 50
V_fixture = 1.35
V_fixture_min = 1.215
V_fixture_max = 1.485
0s        589.3mV    585.5mV    578.3mV
92.95ps   589.8mV    585.5mV    622.5mV
215.8ps   619.8mV    586.2mV    1.25V
257.1ps   705.5mV    587.3mV    1.366V
311.8ps   890.6mV    588.4mV    1.441V
407.2ps   1.185V     594mV      1.47V
531.6ps   1.314V     713.2mV    1.481V
693.9ps   1.34V      1.038V     1.484V
784ps     1.343V     1.138V     1.485V
1.25ns    1.347V     1.211V     1.485V
[Rising Waveform]
R_fixture = 50
V_fixture = 0
V_fixture_min = 0
V_fixture_max = 0
85.46ps   0V         0V         0V
130.7ps   0V         0V         104.4mV
236.6ps   0V         0V         627.7mV
286.3ps   78.58mV    0V         774.2mV
341.5ps   236.7mV    0V         851.2mV
449.1ps   547.5mV    0V         879.9mV
580.9ps   699.5mV    65.02mV    887.5mV
872.6ps   727.6mV    547.6mV    891.1mV
1.037ns   729.5mV    616.3mV    891.9mV
1.335ns   731.7mV    634.4mV    892.9mV
[Falling Waveform]
R_fixture = 50
V_fixture = 1.35
V_fixture_min = 1.215
V_fixture_max = 1.485
118.3ps   1.349V     1.214V     1.484V
173.1ps   1.349V     1.214V     1.373V
264.1ps   1.335V     1.214V     941.2mV
322.6ps   1.233V     1.214V     734.5mV
389.6ps   1.053V     1.214V     622.5mV
498.8ps   760.9mV    1.214V     591.1mV
619ps     626.7mV    1.151V     583.1mV
931.3ps   596.2mV    696.6mV    578.7mV
1.069ns   594.7mV    622mV      577.9mV
1.25ns    593.1mV    593mV      577.4mV
[Falling Waveform]
R_fixture = 50
V_fixture = 0
V_fixture_min = 0
V_fixture_max = 0
109.8ps   734.8mV    638.8mV    892.1mV
153.5ps   734.8mV    638.8mV    790.4mV
243.5ps   715.9mV    638.8mV    329.5mV
301.8ps   579.9mV    638.8mV    142.1mV
372.3ps   356.2mV    638.8mV    37.04mV
460.6ps   143.1mV    638.5mV    12.29mV
602.2ps   23.45mV    494.2mV    3.711mV
793.5ps   6.592mV    153.9mV    0V
860.5ps   5.605mV    84.61mV    0V
1.335ns   3.056mV    4.036mV    0V
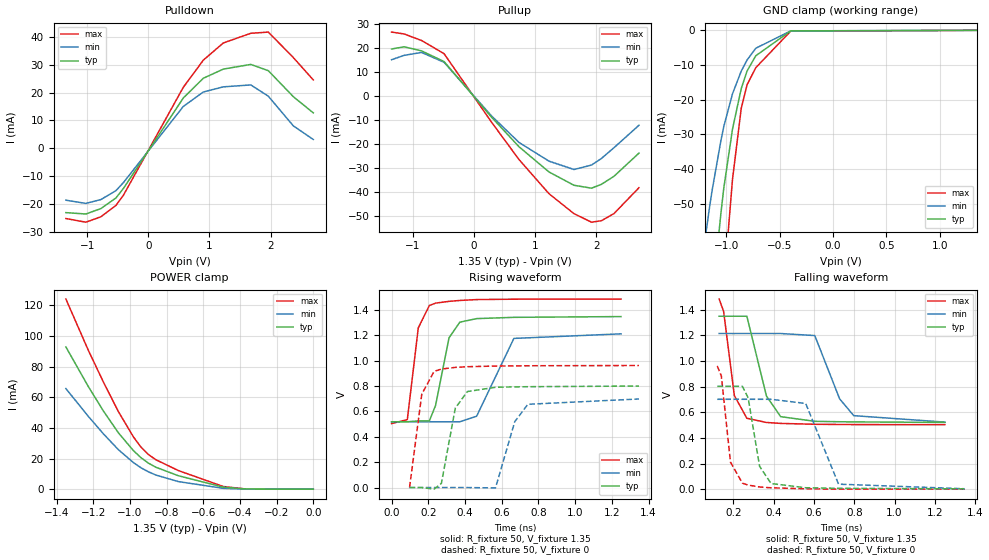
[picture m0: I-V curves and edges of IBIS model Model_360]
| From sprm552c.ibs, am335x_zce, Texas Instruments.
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| Model based on original model for BCSHTLTCSCDVPBFZ_SSDHV
|   Sub model SR00_11MA_10PER_1P35
[model]   Model_360
|[Description]  [1.35V-3-STATE-NOTERM-SR00:11MA, IND, 10%]
|   Fastest slew rate (SR[1:0] = "00"), 0.73 * RExt = 1.325 * Iout
|   (I[2:0] = "110"), 11mA nominal with Rext = 50R,ODT off (ODT[1:0]
|   = "00") CMOS mode,Industrial temperature range (-40C to 125C,
|   25C nominal),10% power supply tolerance
|[Input Load]   NOTERM
|[Output Drive] SR00:11MA
|Voltage   1.35V
|Mode   3-STATE
Model_type   3-state
Polarity   Non-Inverting
Enable   Active-Low
Cref =  15pF
Rref =  100.0000M
Vref =  0V
Vmeas =  0.675
C_comp   1.865048p   1.676829p   1.989968p
[Temperature Range]   25   125   -40
[Voltage Range]   1.35   1.215   1.485
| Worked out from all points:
|   slope of the pulldown table from 0 to 0.203 V, typ, clamps not added: 29.1 ohm
|   slope of the pullup table from 0 to 0.203 V, typ, clamps not added: 32.8 ohm
|   GND clamp passes 1 mA (typ) near -0.49 V on its own axis
|   POWER clamp passes 1 mA (typ) near -0.47 V on its own axis
|   rising waveform, R_fixture 50, V_fixture 1.35: 20-80 % time 67.7ps typ, 116ps min, 45.1ps max; typ from 0.518 V to 1.35 V
|   rising waveform, R_fixture 50, V_fixture 0: 20-80 % time 62.3ps typ, 80.8ps min, 47.6ps max; typ from 0 V to 0.8 V
|   falling waveform, R_fixture 50, V_fixture 1.35: 20-80 % time 69.4ps typ, 100ps min, 50.3ps max; typ from 1.35 V to 0.521 V
|   falling waveform, R_fixture 50, V_fixture 0: 20-80 % time 51.5ps typ, 75ps min, 39.8ps max; typ from 0.803 V to 0.002 V
[POWER_clamp]
-1.35V    92.75mA    65.6mA     124mA
-1.227V   66.81mA    47.39mA    90.41mA
-1.145V   50.92mA    36.05mA    69.79mA
-1.064V   36.83mA    25.81mA    50.69mA
-981.8mV  25.17mA    17.34mA    34.13mA
-940.9mV  20.58mA    14.01mA    27.55mA
-900mV    17mA       11.33mA    22.63mA
-859.1mV  14.3mA     9.219mA    19.19mA
-736.4mV  8.769mA    4.944mA    12.14mA
-490.9mV  1.299mA    528.4uA    1.73mA
-368.2mV  117.2uA    50.88uA    117.5uA
0V        1.028nA    11.64nA    1.384nA
[Pulldown]
-1.35V    -23.15mA   -18.68mA   -25.27mA
-1.023V   -23.64mA   -19.83mA   -26.59mA
-777.3mV  -21.69mA   -18.45mA   -24.65mA
-531.8mV  -17.89mA   -15.26mA   -20.59mA
-409.1mV  -14.47mA   -12.37mA   -16.91mA
572.7mV   18.11mA    15.07mA    21.96mA
900mV     25.2mA     20.25mA    31.71mA
1.227V    28.48mA    22.1mA     37.89mA
1.677V    30.17mA    22.79mA    41.37mA
1.964V    27.91mA    18.73mA    41.8mA
2.373V    18.56mA    8.065mA    32.63mA
2.7V      12.74mA    3.161mA    24.59mA
[Pullup]
-1.35V    19.75mA    15.29mA    26.8mA
-1.145V   20.68mA    17.1mA     26.02mA
-859.1mV  18.97mA    18.32mA    23.3mA
-490.9mV  14.53mA    14.23mA    17.81mA
286.4mV   -8.646mA   -8.123mA   -10.72mA
736.4mV   -20.97mA   -19.17mA   -26.3mA
1.227V    -31.47mA   -26.96mA   -40.52mA
1.636V    -37.01mA   -30.45mA   -48.83mA
1.923V    -38.22mA   -28.59mA   -52.39mA
2.086V    -36.6mA    -25.84mA   -51.77mA
2.291V    -33.27mA   -21.36mA   -48.8mA
2.7V      -23.61mA   -12.01mA   -38.03mA
[GND_clamp]
-1.35V    -159.1mA   -94.77mA   -266.2mA
-1.295V   -137.7mA   -81.77mA   -230.9mA
-1.159V   -87.19mA   -51.56mA   -145.9mA
-1.132V   -77.89mA   -46.14mA   -129.9mA
-1.05V    -52.83mA   -31.83mA   -86.44mA
-1.023V   -45.55mA   -27.75mA   -73.68mA
-940.9mV  -28.44mA   -18.28mA   -42.92mA
-859.1mV  -16.79mA   -11.75mA   -22.47mA
-804.5mV  -11.72mA   -8.559mA   -15.69mA
-722.7mV  -7.324mA   -5.161mA   -10.76mA
-395.5mV  -159.1uA   -161.1uA   -232.4uA
1.35V     1.028nA    146.6nA    745.7pA
[Ramp]
dV/dt_f   0.50697/70.584114p 0.42483095/0.10292151n  0.5959495/50.571092p
dV/dt_r 0.49402193/63.713842p 0.43772631/83.896526p 0.58715654/47.849826p
R_load = 50
[Rising Waveform]
R_fixture = 50
V_fixture = 1.35
V_fixture_min = 1.215
V_fixture_max = 1.485
0s        518.3mV    518.2mV    504mV
85.89ps   518.3mV    518.2mV    535.4mV
145.6ps   525.1mV    518.2mV    1.258V
206ps     525mV      518.2mV    1.434V
239.8ps   646.6mV    518.2mV    1.453V
313.2ps   1.18V      518.2mV    1.467V
372ps     1.303V     518.2mV    1.474V
463.5ps   1.331V     561.9mV    1.481V
666.5ps   1.341V     1.175V     1.484V
1.25ns    1.347V     1.211V     1.485V
[Rising Waveform]
R_fixture = 50
V_fixture = 0
V_fixture_min = 0
V_fixture_max = 0
98.02ps   0V         0V         0V
164.6ps   0V         0V         735.5mV
231.6ps   -12.78mV   0V         914.7mV
271.5ps   32.85mV    0V         933.6mV
347.4ps   626mV      0V         946.7mV
413.1ps   756.4mV    0V         952mV
566.3ps   789.9mV    -3.002mV   957.3mV
671.3ps   793.1mV    519.2mV    958.4mV
742.8ps   794.5mV    655.9mV    959.5mV
1.348ns   799.7mV    697.8mV    961.4mV
[Falling Waveform]
R_fixture = 50
V_fixture = 1.35
V_fixture_min = 1.215
V_fixture_max = 1.485
129.9ps   1.35V      1.215V     1.484V
152.1ps   1.35V      1.215V     1.388V
205.3ps   1.35V      1.215V     731.1mV
267.4ps   1.35V      1.215V     553.6mV
364.6ps   727mV      1.215V     520.6mV
435.3ps   566mV      1.215V     513.3mV
604.4ps   529.6mV    1.199V     506.5mV
727.6ps   526.3mV    705.4mV    505mV
797.6ps   525.2mV    573.9mV    504.2mV
1.25ns    520.9mV    523.4mV    503.1mV
[Falling Waveform]
R_fixture = 50
V_fixture = 0
V_fixture_min = 0
V_fixture_max = 0
120.4ps   802.9mV    701.5mV    962.3mV
140.8ps   802.9mV    701.5mV    883.3mV
186.1ps   802.9mV    701.5mV    211mV
245.2ps   802.9mV    701.5mV    47.1mV
273.9ps   712.8mV    701.5mV    31.73mV
330.6ps   178.3mV    701.5mV    16.99mV
387.5ps   44.02mV    701.5mV    10.68mV
559.5ps   11.13mV    669mV      2.704mV
722.4ps   6.612mV    38.95mV    0V
1.348ns   2.381mV    3.253mV    0V
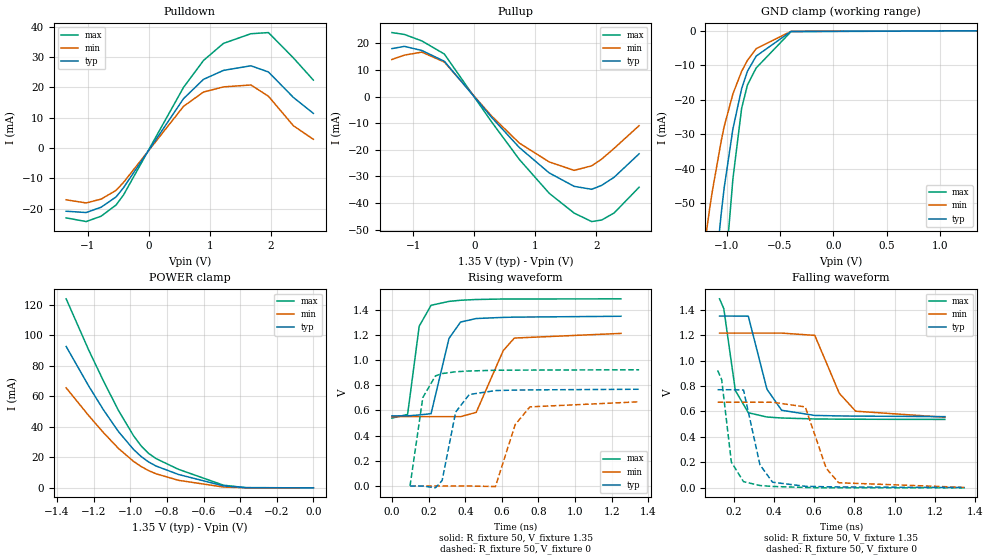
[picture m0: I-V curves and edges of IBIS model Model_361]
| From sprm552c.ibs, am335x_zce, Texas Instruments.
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| Model based on original model for BCSHTLTCSCDVPBFZ_SSDHV
|   Sub model SR00_10MA_10PER_1P35
[model]   Model_361
|[Description]  [1.35V-3-STATE-NOTERM-SR00:10MA, IND, 10%]
|   Fastest slew rate (SR[1:0] = "00"), 0.80 * RExt = 1.250 * Iout
|   (I[2:0] = "101"), 10mA nominal with Rext = 50R,ODT off (ODT[1:0]
|   = "00") CMOS mode,Industrial temperature range (-40C to 125C,
|   25C nominal),10% power supply tolerance
|[Input Load]   NOTERM
|[Output Drive] SR00:10MA
|Voltage   1.35V
|Mode   3-STATE
Model_type   3-state
Polarity   Non-Inverting
Enable   Active-Low
Cref =  15pF
Rref =  100.0000M
Vref =  0V
Vmeas =  0.675
C_comp   1.865048p   1.676829p   1.989968p
[Temperature Range]   25   125   -40
[Voltage Range]   1.35   1.215   1.485
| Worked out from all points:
|   slope of the pulldown table from 0 to 0.203 V, typ, clamps not added: 32.4 ohm
|   slope of the pullup table from 0 to 0.203 V, typ, clamps not added: 36 ohm
|   GND clamp passes 1 mA (typ) near -0.49 V on its own axis
|   POWER clamp passes 1 mA (typ) near -0.47 V on its own axis
|   rising waveform, R_fixture 50, V_fixture 1.35: 20-80 % time 70.2ps typ, 117ps min, 48.2ps max; typ from 0.557 V to 1.35 V
|   rising waveform, R_fixture 50, V_fixture 0: 20-80 % time 66.1ps typ, 85.3ps min, 51.3ps max; typ from 0 V to 0.768 V
|   falling waveform, R_fixture 50, V_fixture 1.35: 20-80 % time 74.6ps typ, 106ps min, 54.1ps max; typ from 1.35 V to 0.56 V
|   falling waveform, R_fixture 50, V_fixture 0: 20-80 % time 54.8ps typ, 78.6ps min, 42.4ps max; typ from 0.771 V to 0.003 V
[POWER_clamp]
-1.35V    92.75mA    65.6mA     124mA
-1.227V   66.81mA    47.39mA    90.41mA
-1.145V   50.92mA    36.05mA    69.79mA
-1.064V   36.83mA    25.81mA    50.69mA
-981.8mV  25.17mA    17.34mA    34.13mA
-940.9mV  20.58mA    14.01mA    27.55mA
-900mV    17mA       11.33mA    22.63mA
-859.1mV  14.3mA     9.219mA    19.19mA
-736.4mV  8.769mA    4.944mA    12.14mA
-490.9mV  1.299mA    528.4uA    1.73mA
-368.2mV  117.2uA    50.88uA    117.5uA
0V        1.028nA    11.64nA    1.384nA
[Pulldown]
-1.35V    -20.78mA   -17.02mA   -22.97mA
-1.023V   -21.21mA   -18.06mA   -24.18mA
-777.3mV  -19.46mA   -16.8mA    -22.41mA
-531.8mV  -16.06mA   -13.9mA    -18.72mA
-409.1mV  -12.99mA   -11.27mA   -15.38mA
572.7mV   16.26mA    13.73mA    19.97mA
900mV     22.62mA    18.44mA    28.83mA
1.227V    25.56mA    20.13mA    34.45mA
1.677V    27.07mA    20.76mA    37.62mA
1.964V    25.04mA    17.05mA    38mA
2.373V    16.65mA    7.344mA    29.66mA
2.7V      11.43mA    2.879mA    22.36mA
[Pullup]
-1.35V    18mA       13.92mA    24.03mA
-1.145V   18.85mA    15.57mA    23.33mA
-859.1mV  17.3mA     16.68mA    20.89mA
-490.9mV  13.25mA    12.96mA    15.97mA
286.4mV   -7.885mA   -7.399mA   -9.614mA
736.4mV   -19.13mA   -17.46mA   -23.59mA
1.227V    -28.7mA    -24.56mA   -36.34mA
1.636V    -33.74mA   -27.73mA   -43.79mA
1.923V    -34.85mA   -26.03mA   -46.97mA
2.086V    -33.37mA   -23.53mA   -46.41mA
2.291V    -30.33mA   -19.45mA   -43.74mA
2.7V      -21.52mA   -10.93mA   -34.08mA
[GND_clamp]
-1.35V    -159.1mA   -94.77mA   -266.2mA
-1.295V   -137.7mA   -81.77mA   -230.9mA
-1.159V   -87.19mA   -51.56mA   -145.9mA
-1.132V   -77.89mA   -46.14mA   -129.9mA
-1.05V    -52.83mA   -31.83mA   -86.44mA
-1.023V   -45.55mA   -27.75mA   -73.68mA
-940.9mV  -28.44mA   -18.28mA   -42.92mA
-859.1mV  -16.79mA   -11.75mA   -22.47mA
-804.5mV  -11.72mA   -8.559mA   -15.69mA
-722.7mV  -7.324mA   -5.161mA   -10.76mA
-395.5mV  -159.1uA   -161.1uA   -232.4uA
1.35V     1.028nA    146.6nA    745.7pA
[Ramp]
dV/dt_f 0.48367422/76.001837p 0.40615494/0.10875868n  0.5747018/54.335216p
dV/dt_r 0.47381458/67.477383p 0.41853071/88.520182p 0.56281945/51.583183p
R_load = 50
[Rising Waveform]
R_fixture = 50
V_fixture = 1.35
V_fixture_min = 1.215
V_fixture_max = 1.485
0s        556.7mV    550.3mV    538.6mV
85.68ps   556.7mV    550.3mV    568.3mV
148.9ps   563.7mV    550.3mV    1.268V
213.7ps   574.1mV    550.3mV    1.434V
311.5ps   1.171V     550.3mV    1.465V
374.6ps   1.301V     550.3mV    1.474V
460.1ps   1.329V     584.5mV    1.48V
607.3ps   1.338V     1.074V     1.484V
668.1ps   1.34V      1.174V     1.484V
1.25ns    1.347V     1.211V     1.485V
[Rising Waveform]
R_fixture = 50
V_fixture = 0
V_fixture_min = 0
V_fixture_max = 0
98.97ps   0V         0V         0V
168.5ps   0V         0V         701.4mV
237.4ps   -14.56mV   0V         873.5mV
274ps     43.4mV     0V         892.1mV
348ps     587.1mV    0V         906.5mV
421.9ps   725.9mV    0V         912.8mV
565.1ps   757.5mV    -4.172mV   918.4mV
672.9ps   761.1mV    487.6mV    919.6mV
753ps     762.7mV    628mV      920mV
1.349ns   767.8mV    668.2mV    922.4mV
[Falling Waveform]
R_fixture = 50
V_fixture = 1.35
V_fixture_min = 1.215
V_fixture_max = 1.485
129.9ps   1.35V      1.216V     1.485V
150.9ps   1.35V      1.216V     1.409V
208.4ps   1.35V      1.216V     765.2mV
272.8ps   1.349V     1.216V     590.4mV
365.6ps   774.7mV    1.216V     556.5mV
438.6ps   609.5mV    1.216V     548.9mV
603.2ps   569mV      1.198V     541.3mV
725.3ps   565.1mV    742.6mV    539.9mV
806.5ps   563.8mV    602.3mV    539.1mV
1.25ns    559.6mV    554.7mV    537.7mV
[Falling Waveform]
R_fixture = 50
V_fixture = 0
V_fixture_min = 0
V_fixture_max = 0
120.4ps   771mV      672.7mV    922.9mV
140.7ps   771mV      672.7mV    848.2mV
188.6ps   771mV      672.7mV    202.5mV
249ps     768.8mV    672.7mV    48.61mV
330.7ps   181.3mV    672.7mV    18.28mV
393.2ps   44.42mV    672.7mV    10.97mV
556ps     12.02mV    636mV      2.986mV
660.2ps   8.38mV     153.3mV    0V
721.9ps   7.008mV    40.04mV    0V
1.349ns   2.553mV    3.404mV    0V
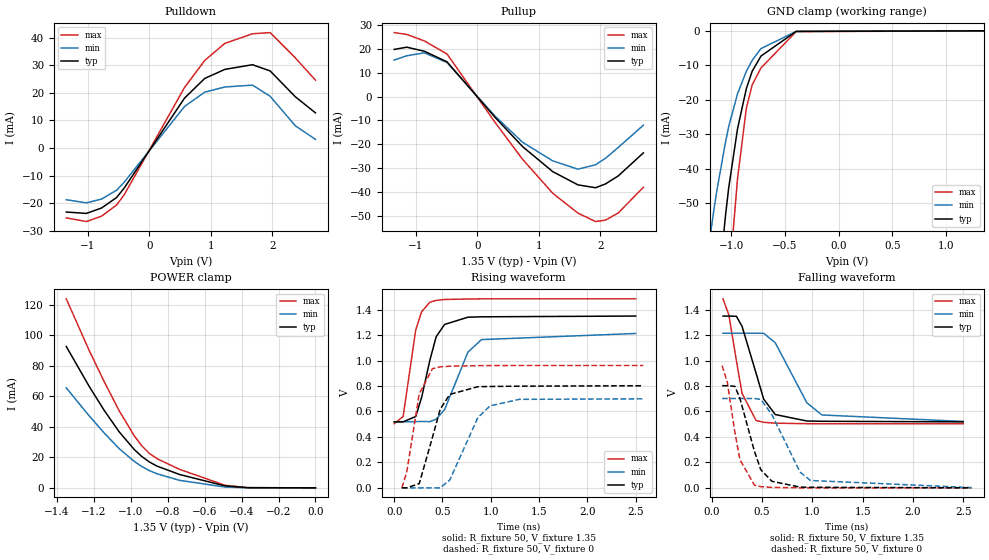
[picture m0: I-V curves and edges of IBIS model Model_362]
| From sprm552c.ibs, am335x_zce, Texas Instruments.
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| Model based on original model for BCSHTLTCSCDVPBFZ_SSDHV
|   Sub model SR10_11MA_10PER_1P35
[model]   Model_362
|[Description]  [1.35V-3-STATE-NOTERM-SR10:11MA, IND, 10%]
|   Fast slew rate (SR[1:0] = "10"), 0.73 * RExt = 1.325 * Iout
|   (I[2:0] = "110"), 11mA nominal with Rext = 50R,ODT off (ODT[1:0]
|   = "00") CMOS mode,Industrial temperature range (-40C to 125C,
|   25C nominal),10% power supply tolerance
|[Input Load]   NOTERM
|[Output Drive] SR10:11MA
|Voltage   1.35V
|Mode   3-STATE
Model_type   3-state
Polarity   Non-Inverting
Enable   Active-Low
Cref =  15pF
Rref =  100.0000M
Vref =  0V
Vmeas =  0.675
C_comp   1.865048p   1.676829p   1.989968p
[Temperature Range]   25   125   -40
[Voltage Range]   1.35   1.215   1.485
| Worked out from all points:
|   slope of the pulldown table from 0 to 0.203 V, typ, clamps not added: 29.1 ohm
|   slope of the pullup table from 0 to 0.203 V, typ, clamps not added: 32.8 ohm
|   GND clamp passes 1 mA (typ) near -0.49 V on its own axis
|   POWER clamp passes 1 mA (typ) near -0.47 V on its own axis
|   rising waveform, R_fixture 50, V_fixture 1.35: 20-80 % time 158ps typ, 224ps min, 114ps max; typ from 0.518 V to 1.35 V
|   rising waveform, R_fixture 50, V_fixture 0: 20-80 % time 171ps typ, 239ps min, 124ps max; typ from 0 V to 0.802 V
|   falling waveform, R_fixture 50, V_fixture 1.35: 20-80 % time 184ps typ, 268ps min, 130ps max; typ from 1.35 V to 0.518 V
|   falling waveform, R_fixture 50, V_fixture 0: 20-80 % time 171ps typ, 258ps min, 123ps max; typ from 0.802 V to 0 V
[POWER_clamp]
-1.35V    92.75mA    65.6mA     124mA
-1.227V   66.81mA    47.39mA    90.41mA
-1.145V   50.92mA    36.05mA    69.79mA
-1.064V   36.83mA    25.81mA    50.69mA
-981.8mV  25.17mA    17.34mA    34.13mA
-940.9mV  20.58mA    14.01mA    27.55mA
-900mV    17mA       11.33mA    22.63mA
-859.1mV  14.3mA     9.219mA    19.19mA
-736.4mV  8.769mA    4.944mA    12.14mA
-490.9mV  1.299mA    528.4uA    1.73mA
-368.2mV  117.2uA    50.88uA    117.5uA
0V        1.028nA    11.64nA    1.384nA
[Pulldown]
-1.35V    -23.15mA   -18.68mA   -25.27mA
-1.023V   -23.64mA   -19.83mA   -26.59mA
-777.3mV  -21.69mA   -18.45mA   -24.65mA
-531.8mV  -17.89mA   -15.26mA   -20.59mA
-409.1mV  -14.47mA   -12.37mA   -16.91mA
572.7mV   18.11mA    15.07mA    21.96mA
900mV     25.2mA     20.25mA    31.71mA
1.227V    28.48mA    22.1mA     37.89mA
1.677V    30.17mA    22.79mA    41.37mA
1.964V    27.91mA    18.73mA    41.8mA
2.373V    18.56mA    8.065mA    32.63mA
2.7V      12.74mA    3.161mA    24.59mA
[Pullup]
-1.35V    19.75mA    15.29mA    26.8mA
-1.145V   20.68mA    17.1mA     26.02mA
-859.1mV  18.97mA    18.32mA    23.3mA
-490.9mV  14.53mA    14.23mA    17.81mA
286.4mV   -8.646mA   -8.123mA   -10.72mA
736.4mV   -20.97mA   -19.17mA   -26.3mA
1.227V    -31.47mA   -26.96mA   -40.52mA
1.636V    -37.01mA   -30.45mA   -48.83mA
1.923V    -38.22mA   -28.59mA   -52.39mA
2.086V    -36.6mA    -25.84mA   -51.77mA
2.291V    -33.27mA   -21.36mA   -48.8mA
2.7V      -23.61mA   -12.01mA   -38.03mA
[GND_clamp]
-1.35V    -159.1mA   -94.77mA   -266.2mA
-1.295V   -137.7mA   -81.77mA   -230.9mA
-1.159V   -87.19mA   -51.56mA   -145.9mA
-1.132V   -77.89mA   -46.14mA   -129.9mA
-1.05V    -52.83mA   -31.83mA   -86.44mA
-1.023V   -45.55mA   -27.75mA   -73.68mA
-940.9mV  -28.44mA   -18.28mA   -42.92mA
-859.1mV  -16.79mA   -11.75mA   -22.47mA
-804.5mV  -11.72mA   -8.559mA   -15.69mA
-722.7mV  -7.324mA   -5.161mA   -10.76mA
-395.5mV  -159.1uA   -161.1uA   -232.4uA
1.35V     1.028nA    146.6nA    745.7pA
[Ramp]
dV/dt_f 0.50123788/0.18531605n 0.41981105/0.27192569n 0.59051361/0.13032598n
dV/dt_r 0.48439357/0.17222875n 0.42483331/0.24190256n 0.57901467/0.12464471n
R_load = 50
[Rising Waveform]
R_fixture = 50
V_fixture = 1.35
V_fixture_min = 1.215
V_fixture_max = 1.485
0s        518.3mV    519.6mV    504.1mV
92.53ps   518.8mV    519.6mV    560.4mV
223ps     560.6mV    520.4mV    1.241V
284.2ps   711.6mV    521.2mV    1.384V
369.5ps   1.003V     520.4mV    1.459V
434.3ps   1.187V     539.5mV    1.473V
521.6ps   1.284V     614.2mV    1.48V
763.1ps   1.341V     1.066V     1.484V
903.5ps   1.344V     1.165V     1.485V
2.5ns     1.35V      1.213V     1.485V
[Rising Waveform]
R_fixture = 50
V_fixture = 0
V_fixture_min = 0
V_fixture_max = 0
79.6ps    0V         0V         0V
130.5ps   0V         0V         125.5mV
259.1ps   33.16mV    0V         739.4mV
396.4ps   397.5mV    0V         936.8mV
476.9ps   619.2mV    0V         950.7mV
576.2ps   734.4mV    62.63mV    955.9mV
865.9ps   794.7mV    551.6mV    960mV
991.7ps   796.5mV    644mV      961mV
1.297ns   798.9mV    695.4mV    961.4mV
2.58ns    802.3mV    699.5mV    961.4mV
[Falling Waveform]
R_fixture = 50
V_fixture = 1.35
V_fixture_min = 1.215
V_fixture_max = 1.485
111.6ps   1.349V     1.214V     1.484V
170.4ps   1.349V     1.214V     1.358V
245.2ps   1.347V     1.214V     997.1mV
301.4ps   1.268V     1.214V     741.6mV
440.5ps   900.7mV    1.214V     528.7mV
516ps     696.9mV    1.214V     514.6mV
631.6ps   575.7mV    1.139V     507.8mV
945.8ps   524.8mV    667.7mV    503.8mV
1.095ns   522.8mV    572.2mV    503.3mV
2.5ns     518.1mV    521.5mV    503.1mV
[Falling Waveform]
R_fixture = 50
V_fixture = 0
V_fixture_min = 0
V_fixture_max = 0
103.1ps   802.1mV    701.7mV    960.8mV
155.3ps   802.1mV    701.7mV    827.7mV
229.2ps   797.4mV    701.7mV    440.8mV
279.7ps   703.5mV    701.7mV    222mV
424ps     287.7mV    701.7mV    21.26mV
487.5ps   142.5mV    694.1mV    9.39mV
597.5ps   51.44mV    576.1mV    3.532mV
876.8ps   5.72mV     124.7mV    0V
981.4ps   4.431mV    57.79mV    0V
2.58ns    0V         2.044mV    0V
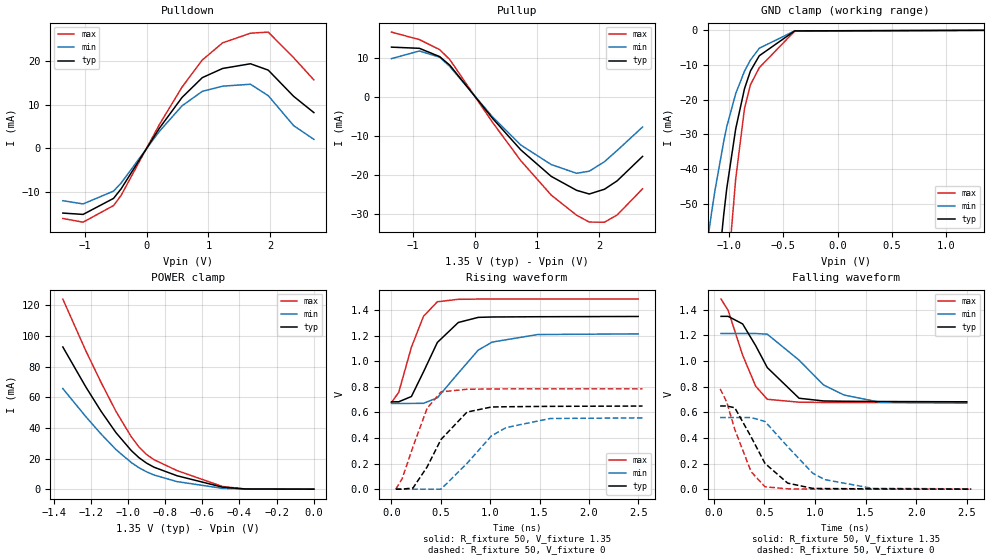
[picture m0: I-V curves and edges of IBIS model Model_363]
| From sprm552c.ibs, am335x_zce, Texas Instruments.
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| Model based on original model for BCSHTLTCSCDVPBFZ_SSDHV
|   Sub model SR11_7MA_10PER_1P35
[model]   Model_363
|[Description]  [1.35V-3-STATE-NOTERM-SR11:7MA, IND, 10%]
|   Slowest slew rate (SR[1:0] = "11"), 1.14 * RExt = 0.875 * Iout
|   (I[2:0] = "010"), 7mA nominal with Rext = 50R,ODT off (ODT[1:0]
|   = "00") CMOS mode,Industrial temperature range (-40C to 125C,
|   25C nominal),10% power supply tolerance
|[Input Load]   NOTERM
|[Output Drive] SR11:7MA
|Voltage   1.35V
|Mode   3-STATE
Model_type   3-state
Polarity   Non-Inverting
Enable   Active-Low
Cref =  15pF
Rref =  100.0000M
Vref =  0V
Vmeas =  0.675
C_comp   1.865048p   1.676829p   1.989968p
[Temperature Range]   25   125   -40
[Voltage Range]   1.35   1.215   1.485
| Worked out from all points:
|   slope of the pulldown table from 0 to 0.203 V, typ, clamps not added: 45.3 ohm
|   slope of the pullup table from 0 to 0.203 V, typ, clamps not added: 50.7 ohm
|   GND clamp passes 1 mA (typ) near -0.49 V on its own axis
|   POWER clamp passes 1 mA (typ) near -0.47 V on its own axis
|   rising waveform, R_fixture 50, V_fixture 1.35: 20-80 % time 268ps typ, 362ps min, 199ps max; typ from 0.682 V to 1.35 V
|   rising waveform, R_fixture 50, V_fixture 0: 20-80 % time 304ps typ, 405ps min, 214ps max; typ from 0 V to 0.649 V
|   falling waveform, R_fixture 50, V_fixture 1.35: 20-80 % time 311ps typ, 439ps min, 215ps max; typ from 1.35 V to 0.682 V
|   falling waveform, R_fixture 50, V_fixture 0: 20-80 % time 290ps typ, 387ps min, 209ps max; typ from 0.649 V to 0 V
[POWER_clamp]
-1.35V    92.75mA    65.6mA     124mA
-1.227V   66.81mA    47.39mA    90.41mA
-1.145V   50.92mA    36.05mA    69.79mA
-1.064V   36.83mA    25.81mA    50.69mA
-981.8mV  25.17mA    17.34mA    34.13mA
-940.9mV  20.58mA    14.01mA    27.55mA
-900mV    17mA       11.33mA    22.63mA
-859.1mV  14.3mA     9.219mA    19.19mA
-736.4mV  8.769mA    4.944mA    12.14mA
-490.9mV  1.299mA    528.4uA    1.73mA
-368.2mV  117.2uA    50.88uA    117.5uA
0V        1.028nA    11.64nA    1.384nA
[Pulldown]
-1.35V    -14.84mA   -12.01mA   -16.08mA
-1.023V   -15.15mA   -12.75mA   -16.93mA
-531.8mV  -11.48mA   -9.816mA   -13.12mA
-409.1mV  -9.285mA   -7.958mA   -10.78mA
204.5mV   4.516mA    3.818mA    5.34mA
572.7mV   11.62mA    9.698mA    13.99mA
900mV     16.16mA    13.02mA    20.2mA
1.227V    18.26mA    14.21mA    24.12mA
1.677V    19.34mA    14.65mA    26.33mA
1.964V    17.88mA    12.03mA    26.59mA
2.373V    11.89mA    5.181mA    20.74mA
2.7V      8.16mA     2.032mA    15.64mA
[Pullup]
-1.35V    12.77mA    9.823mA    16.63mA
-900mV    12.47mA    11.79mA    14.7mA
-572.7mV  10.34mA    10.18mA    12.13mA
-409.1mV  8.134mA    7.802mA    9.577mA
286.4mV   -5.6mA     -5.227mA   -6.662mA
736.4mV   -13.58mA   -12.33mA   -16.35mA
1.227V    -20.37mA   -17.34mA   -25.17mA
1.636V    -23.95mA   -19.58mA   -30.33mA
1.841V    -24.89mA   -19.04mA   -32.09mA
2.086V    -23.67mA   -16.6mA    -32.12mA
2.291V    -21.51mA   -13.72mA   -30.27mA
2.7V      -15.26mA   -7.714mA   -23.57mA
[GND_clamp]
-1.35V    -159.1mA   -94.77mA   -266.2mA
-1.295V   -137.7mA   -81.77mA   -230.9mA
-1.159V   -87.19mA   -51.56mA   -145.9mA
-1.132V   -77.89mA   -46.14mA   -129.9mA
-1.05V    -52.83mA   -31.83mA   -86.44mA
-1.023V   -45.55mA   -27.75mA   -73.68mA
-940.9mV  -28.44mA   -18.28mA   -42.92mA
-859.1mV  -16.79mA   -11.75mA   -22.47mA
-804.5mV  -11.72mA   -8.559mA   -15.69mA
-722.7mV  -7.324mA   -5.161mA   -10.76mA
-395.5mV  -159.1uA   -161.1uA   -232.4uA
1.35V     1.028nA    146.6nA    745.7pA
[Ramp]
dV/dt_f  0.4025068/0.31288295n 0.32932957/0.44699257n 0.48612485/0.21561169n
dV/dt_r  0.3916614/0.30568628n 0.33825479/0.41187875n 0.47140055/0.21433726n
R_load = 50
[Rising Waveform]
R_fixture = 50
V_fixture = 1.35
V_fixture_min = 1.215
V_fixture_max = 1.485
0s        682mV      669.5mV    677.3mV
73.45ps   682.7mV    669.5mV    756.4mV
201.8ps   723.7mV    670mV      1.109V
324.1ps   916.2mV    670.5mV    1.35V
464.6ps   1.146V     713.2mV    1.464V
677.1ps   1.302V     906.6mV    1.483V
878.6ps   1.342V     1.086V     1.485V
1.02ns    1.345V     1.149V     1.485V
1.482ns   1.347V     1.208V     1.485V
2.5ns     1.349V     1.213V     1.485V
[Rising Waveform]
R_fixture = 50
V_fixture = 0
V_fixture_min = 0
V_fixture_max = 0
43.89ps   0V         0V         0V
108.5ps   0V         0V         82.48mV
218.1ps   9.52mV     0V         331.7mV
360.9ps   173.7mV    0V         631.9mV
501.6ps   388.1mV    0V         760.1mV
764.9ps   602.1mV    201.4mV    780.4mV
1.012ns   641.8mV    415.7mV    782.8mV
1.162ns   643.9mV    481.2mV    783.3mV
1.609ns   646.9mV    552.1mV    783.5mV
2.544ns   649.3mV    556.7mV    783.5mV
[Falling Waveform]
R_fixture = 50
V_fixture = 1.35
V_fixture_min = 1.215
V_fixture_max = 1.485
71.71ps   1.349V     1.215V     1.484V
142.2ps   1.349V     1.215V     1.395V
284.9ps   1.29V      1.215V     1.046V
414ps     1.12V      1.215V     803.7mV
528.7ps   949mV      1.21V      701.7mV
843.1ps   709.7mV    1.007V     678.9mV
1.084ns   688.6mV    813.6mV    676.9mV
1.289ns   686.3mV    734.4mV    676.7mV
1.65ns    684.2mV    677.3mV    676.8mV
2.5ns     682mV      671.9mV    676.3mV
[Falling Waveform]
R_fixture = 50
V_fixture = 0
V_fixture_min = 0
V_fixture_max = 0
62.95ps   649.3mV    559.2mV    782.5mV
127.8ps   649.3mV    559.2mV    680.2mV
207.5ps   635.5mV    559.2mV    465.7mV
368.5ps   408.5mV    559.2mV    136.7mV
506ps     201.1mV    528.3mV    18.64mV
730.5ps   47mV       331.7mV    2.453mV
977.4ps   6.063mV    124.7mV    0V
1.097ns   4.713mV    74.61mV    0V
1.57ns    2.564mV    6.044mV    0V
2.544ns   0V         2.476mV    0V
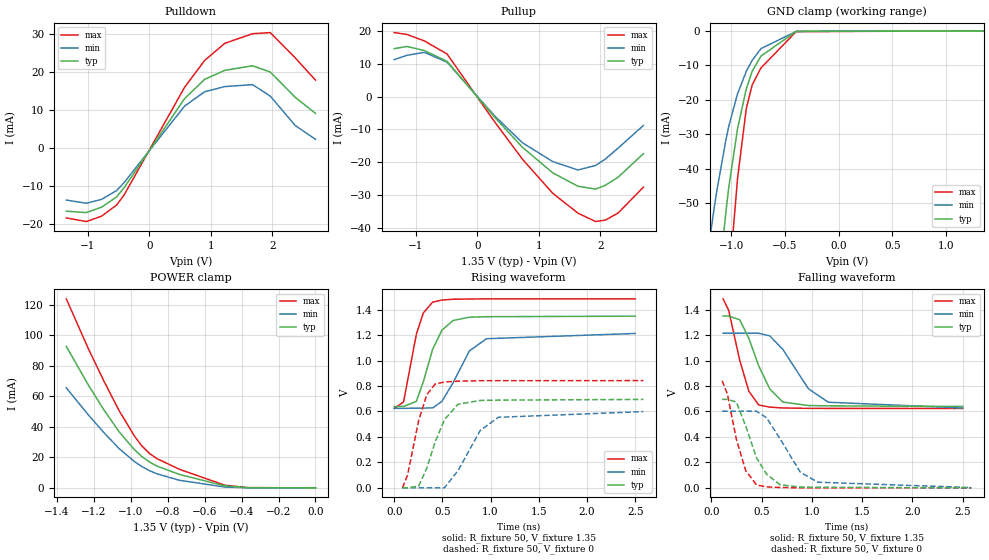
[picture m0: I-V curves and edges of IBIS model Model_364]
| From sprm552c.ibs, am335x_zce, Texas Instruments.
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| Model based on original model for BCSHTLTCSCDVPBFZ_SSDHV
|   Sub model SR10_8MA_10PER_1P35
[model]   Model_364
|[Description]  [1.35V-3-STATE-NOTERM-SR10:8MA, IND, 10%]
|   Fast slew rate (SR[1:0] = "10"), 1.00 * RExt = 1.000 * Iout
|   (I[2:0] = "011"), 8mA nominal with Rext = 50R,ODT off (ODT[1:0]
|   = "00") CMOS mode,Industrial temperature range (-40C to 125C,
|   25C nominal),10% power supply tolerance
|[Input Load]   NOTERM
|[Output Drive] SR10:8MA
|Voltage   1.35V
|Mode   3-STATE
Model_type   3-state
Polarity   Non-Inverting
Enable   Active-Low
Cref =  15pF
Rref =  100.0000M
Vref =  0V
Vmeas =  0.675
C_comp   1.865048p   1.676829p   1.989968p
[Temperature Range]   25   125   -40
[Voltage Range]   1.35   1.215   1.485
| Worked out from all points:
|   slope of the pulldown table from 0 to 0.203 V, typ, clamps not added: 40.4 ohm
|   slope of the pullup table from 0 to 0.203 V, typ, clamps not added: 44.6 ohm
|   GND clamp passes 1 mA (typ) near -0.49 V on its own axis
|   POWER clamp passes 1 mA (typ) near -0.47 V on its own axis
|   rising waveform, R_fixture 50, V_fixture 1.35: 20-80 % time 188ps typ, 252ps min, 138ps max; typ from 0.639 V to 1.35 V
|   rising waveform, R_fixture 50, V_fixture 0: 20-80 % time 207ps typ, 273ps min, 148ps max; typ from 0 V to 0.695 V
|   falling waveform, R_fixture 50, V_fixture 1.35: 20-80 % time 223ps typ, 307ps min, 156ps max; typ from 1.35 V to 0.639 V
|   falling waveform, R_fixture 50, V_fixture 0: 20-80 % time 205ps typ, 274ps min, 150ps max; typ from 0.695 V to 0 V
[POWER_clamp]
-1.35V    92.75mA    65.6mA     124mA
-1.227V   66.81mA    47.39mA    90.41mA
-1.145V   50.92mA    36.05mA    69.79mA
-1.064V   36.83mA    25.81mA    50.69mA
-981.8mV  25.17mA    17.34mA    34.13mA
-940.9mV  20.58mA    14.01mA    27.55mA
-900mV    17mA       11.33mA    22.63mA
-859.1mV  14.3mA     9.219mA    19.19mA
-736.4mV  8.769mA    4.944mA    12.14mA
-490.9mV  1.299mA    528.4uA    1.73mA
-368.2mV  117.2uA    50.88uA    117.5uA
0V        1.028nA    11.64nA    1.384nA
[Pulldown]
-1.35V    -16.62mA   -13.68mA   -18.38mA
-1.023V   -16.97mA   -14.52mA   -19.34mA
-777.3mV  -15.57mA   -13.51mA   -17.93mA
-531.8mV  -12.85mA   -11.18mA   -14.99mA
-409.1mV  -10.4mA    -9.061mA   -12.31mA
572.7mV   13.01mA    11.04mA    15.99mA
900mV     18.1mA     14.83mA    23.08mA
1.227V    20.45mA    16.18mA    27.57mA
1.677V    21.66mA    16.69mA    30.09mA
1.964V    20.03mA    13.7mA     30.39mA
2.373V    13.32mA    5.902mA    23.71mA
2.7V      9.141mA    2.314mA    17.88mA
[Pullup]
-1.35V    14.52mA    11.19mA    19.41mA
-1.145V   15.2mA     12.51mA    18.85mA
-859.1mV  13.95mA    13.41mA    16.88mA
-490.9mV  10.69mA    10.42mA    12.91mA
286.4mV   -6.362mA   -5.951mA   -7.77mA
736.4mV   -15.43mA   -14.05mA   -19.06mA
1.227V    -23.15mA   -19.74mA   -29.36mA
1.636V    -27.22mA   -22.29mA   -35.38mA
1.923V    -28.1mA    -20.92mA   -37.94mA
2.086V    -26.9mA    -18.91mA   -37.48mA
2.291V    -24.45mA   -15.63mA   -35.32mA
2.7V      -17.35mA   -8.787mA   -27.51mA
[GND_clamp]
-1.35V    -159.1mA   -94.77mA   -266.2mA
-1.295V   -137.7mA   -81.77mA   -230.9mA
-1.159V   -87.19mA   -51.56mA   -145.9mA
-1.132V   -77.89mA   -46.14mA   -129.9mA
-1.05V    -52.83mA   -31.83mA   -86.44mA
-1.023V   -45.55mA   -27.75mA   -73.68mA
-940.9mV  -28.44mA   -18.28mA   -42.92mA
-859.1mV  -16.79mA   -11.75mA   -22.47mA
-804.5mV  -11.72mA   -8.559mA   -15.69mA
-722.7mV  -7.324mA   -5.161mA   -10.76mA
-395.5mV  -159.1uA   -161.1uA   -232.4uA
1.35V     1.028nA    146.6nA    745.7pA
[Ramp]
dV/dt_f 0.42838243/0.22394065n 0.35629928/0.31221225n  0.5181709/0.15638747n
dV/dt_r 0.41927947/0.20838106n 0.36396698/0.27771294n 0.50726721/0.14884777n
R_load = 50
[Rising Waveform]
R_fixture = 50
V_fixture = 1.35
V_fixture_min = 1.215
V_fixture_max = 1.485
0s        639mV      624.8mV    624mV
97.05ps   639.6mV    624.8mV    674.7mV
229.4ps   679.2mV    625.7mV    1.205V
302.6ps   834.8mV    627.1mV    1.375V
398.5ps   1.088V     627.9mV    1.459V
494.9ps   1.239V     678.9mV    1.476V
610.7ps   1.315V     826mV      1.482V
780ps     1.341V     1.076V     1.484V
957.8ps   1.345V     1.172V     1.485V
2.5ns     1.349V     1.213V     1.485V
[Rising Waveform]
R_fixture = 50
V_fixture = 0
V_fixture_min = 0
V_fixture_max = 0
84.79ps   0V         0V         0V
137.5ps   0V         0V         96.86mV
253.8ps   13.48mV    0V         528.4mV
338.1ps   154.3mV    0V         731.9mV
425.5ps   361.9mV    0V         816mV
520.5ps   534.6mV    0V         831.8mV
660.4ps   656.4mV    133.2mV    838.3mV
891.4ps   686.7mV    450.2mV    841.7mV
1.08ns    689.3mV    554.4mV    842mV
2.585ns   694.9mV    599.1mV    842.8mV
[Falling Waveform]
R_fixture = 50
V_fixture = 1.35
V_fixture_min = 1.215
V_fixture_max = 1.485
115.8ps   1.349V     1.214V     1.484V
171.7ps   1.349V     1.214V     1.395V
281.4ps   1.32V      1.214V     1.003V
372.1ps   1.175V     1.214V     758.8mV
470.5ps   957.8mV    1.214V     650.8mV
580.9ps   776.6mV    1.193V     633.7mV
709.8ps   673.7mV    1.088V     627.4mV
965ps     646.4mV    777.9mV    624.2mV
1.163ns   644mV      672.5mV    623.8mV
2.5ns     638.9mV    627mV      623mV
[Falling Waveform]
R_fixture = 50
V_fixture = 0
V_fixture_min = 0
V_fixture_max = 0
106.5ps   694.9mV    601.5mV    842mV
159ps     694.9mV    601.5mV    736.9mV
248.4ps   673.6mV    601.5mV    381mV
340.3ps   487.3mV    601.5mV    136.7mV
448.5ps   236.4mV    601.5mV    22.8mV
548.7ps   107.3mV    550.3mV    7.513mV
683.1ps   24.11mV    384.8mV    2.759mV
883.5ps   6.252mV    123.5mV    0V
1.058ns   4.558mV    44.19mV    0V
2.585ns   0V         2.369mV    0V
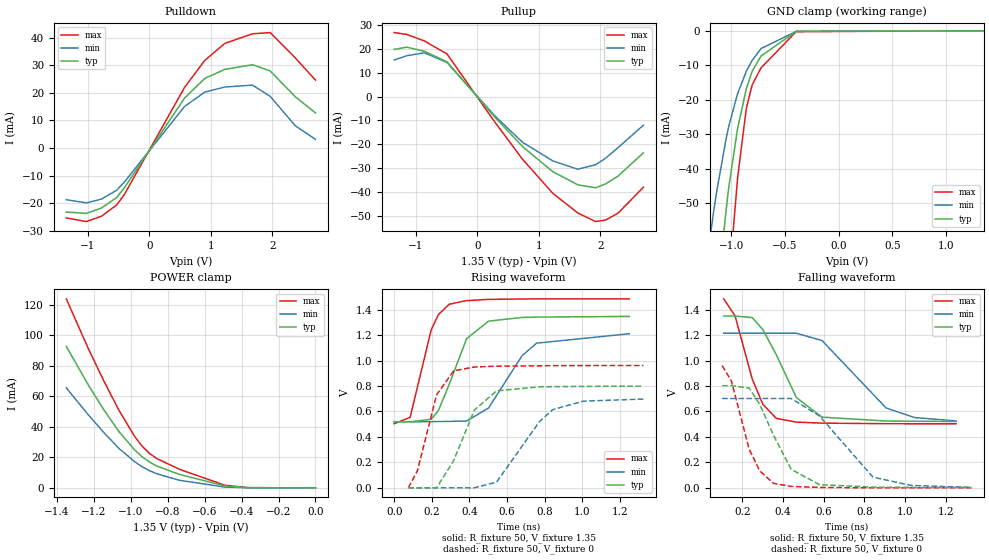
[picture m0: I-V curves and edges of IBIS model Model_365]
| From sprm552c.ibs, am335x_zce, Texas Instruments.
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| Model based on original model for BCSHTLTCSCDVPBFZ_SSDHV
|   Sub model SR01_11MA_10PER_1P35
[model]   Model_365
|[Description]  [1.35V-3-STATE-NOTERM-SR01:11MA, IND, 10%]
|   Slow slew rate (SR[1:0] = "01"), 0.73 * RExt = 1.325 * Iout
|   (I[2:0] = "110"), 11mA nominal with Rext = 50R,ODT off (ODT[1:0]
|   = "00") CMOS mode,Industrial temperature range (-40C to 125C,
|   25C nominal),10% power supply tolerance
|[Input Load]   NOTERM
|[Output Drive] SR01:11MA
|Voltage   1.35V
|Mode   3-STATE
Model_type   3-state
Polarity   Non-Inverting
Enable   Active-Low
Cref =  15pF
Rref =  100.0000M
Vref =  0V
Vmeas =  0.675
C_comp   1.865048p   1.676829p   1.989968p
[Temperature Range]   25   125   -40
[Voltage Range]   1.35   1.215   1.485
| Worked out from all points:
|   slope of the pulldown table from 0 to 0.203 V, typ, clamps not added: 29.1 ohm
|   slope of the pullup table from 0 to 0.203 V, typ, clamps not added: 32.8 ohm
|   GND clamp passes 1 mA (typ) near -0.49 V on its own axis
|   POWER clamp passes 1 mA (typ) near -0.47 V on its own axis
|   rising waveform, R_fixture 50, V_fixture 1.35: 20-80 % time 129ps typ, 181ps min, 94.3ps max; typ from 0.518 V to 1.35 V
|   rising waveform, R_fixture 50, V_fixture 0: 20-80 % time 139ps typ, 192ps min, 102ps max; typ from 0 V to 0.799 V
|   falling waveform, R_fixture 50, V_fixture 1.35: 20-80 % time 153ps typ, 223ps min, 109ps max; typ from 1.35 V to 0.521 V
|   falling waveform, R_fixture 50, V_fixture 0: 20-80 % time 141ps typ, 211ps min, 104ps max; typ from 0.802 V to 0.003 V
[POWER_clamp]
-1.35V    92.75mA    65.6mA     124mA
-1.227V   66.81mA    47.39mA    90.41mA
-1.145V   50.92mA    36.05mA    69.79mA
-1.064V   36.83mA    25.81mA    50.69mA
-981.8mV  25.17mA    17.34mA    34.13mA
-940.9mV  20.58mA    14.01mA    27.55mA
-900mV    17mA       11.33mA    22.63mA
-859.1mV  14.3mA     9.219mA    19.19mA
-736.4mV  8.769mA    4.944mA    12.14mA
-490.9mV  1.299mA    528.4uA    1.73mA
-368.2mV  117.2uA    50.88uA    117.5uA
0V        1.028nA    11.64nA    1.384nA
[Pulldown]
-1.35V    -23.15mA   -18.68mA   -25.27mA
-1.023V   -23.64mA   -19.83mA   -26.59mA
-777.3mV  -21.69mA   -18.45mA   -24.65mA
-531.8mV  -17.89mA   -15.26mA   -20.59mA
-409.1mV  -14.47mA   -12.37mA   -16.91mA
572.7mV   18.11mA    15.07mA    21.96mA
900mV     25.2mA     20.25mA    31.71mA
1.227V    28.48mA    22.1mA     37.89mA
1.677V    30.17mA    22.79mA    41.37mA
1.964V    27.91mA    18.73mA    41.8mA
2.373V    18.56mA    8.065mA    32.63mA
2.7V      12.74mA    3.161mA    24.59mA
[Pullup]
-1.35V    19.75mA    15.29mA    26.8mA
-1.145V   20.68mA    17.1mA     26.02mA
-859.1mV  18.97mA    18.32mA    23.3mA
-490.9mV  14.53mA    14.23mA    17.81mA
286.4mV   -8.646mA   -8.123mA   -10.72mA
736.4mV   -20.97mA   -19.17mA   -26.3mA
1.227V    -31.47mA   -26.96mA   -40.52mA
1.636V    -37.01mA   -30.45mA   -48.83mA
1.923V    -38.22mA   -28.59mA   -52.39mA
2.086V    -36.6mA    -25.84mA   -51.77mA
2.291V    -33.27mA   -21.36mA   -48.8mA
2.7V      -23.61mA   -12.01mA   -38.03mA
[GND_clamp]
-1.35V    -159.1mA   -94.77mA   -266.2mA
-1.295V   -137.7mA   -81.77mA   -230.9mA
-1.159V   -87.19mA   -51.56mA   -145.9mA
-1.132V   -77.89mA   -46.14mA   -129.9mA
-1.05V    -52.83mA   -31.83mA   -86.44mA
-1.023V   -45.55mA   -27.75mA   -73.68mA
-940.9mV  -28.44mA   -18.28mA   -42.92mA
-859.1mV  -16.79mA   -11.75mA   -22.47mA
-804.5mV  -11.72mA   -8.559mA   -15.69mA
-722.7mV  -7.324mA   -5.161mA   -10.76mA
-395.5mV  -159.1uA   -161.1uA   -232.4uA
1.35V     1.028nA    146.6nA    745.7pA
[Ramp]
dV/dt_f 0.50134311/0.15506632n 0.41977319/0.2278294n 0.59060189/0.10915061n
dV/dt_r 0.48465427/0.14086655n 0.42485688/0.19571161n 0.57922421/0.10213339n
R_load = 50
[Rising Waveform]
R_fixture = 50
V_fixture = 1.35
V_fixture_min = 1.215
V_fixture_max = 1.485
0s        518.3mV    519.6mV    504.1mV
84.9ps    518.9mV    519.6mV    554.4mV
196.4ps   538.9mV    520mV      1.24V
234.9ps   606.6mV    521.1mV    1.361V
292.4ps   812.7mV    522.5mV    1.443V
384.9ps   1.172V     524.5mV    1.471V
501.8ps   1.31V      627.6mV    1.481V
679.5ps   1.339V     1.038V     1.484V
757.3ps   1.342V     1.137V     1.485V
1.25ns    1.347V     1.211V     1.485V
[Rising Waveform]
R_fixture = 50
V_fixture = 0
V_fixture_min = 0
V_fixture_max = 0
75.21ps   0V         0V         0V
123.5ps   0V         0V         134.8mV
225.4ps   0V         0V         730.7mV
316.6ps   215.1mV    0V         919.9mV
425.7ps   610.1mV    0V         949.3mV
544.4ps   762.1mV    45.18mV    955.9mV
772.2ps   793.8mV    520.1mV    959.1mV
842.7ps   795.1mV    614.4mV    960.1mV
1.007ns   797mV      681.6mV    961.1mV
1.325ns   799.1mV    697.5mV    961.4mV
[Falling Waveform]
R_fixture = 50
V_fixture = 1.35
V_fixture_min = 1.215
V_fixture_max = 1.485
108.2ps   1.349V     1.214V     1.484V
163.9ps   1.349V     1.214V     1.35V
248.4ps   1.337V     1.214V     854.2mV
300.6ps   1.242V     1.214V     656.2mV
366.5ps   1.046V     1.214V     545.5mV
465.1ps   709.5mV    1.214V     516.4mV
591.1ps   555.1mV    1.157V     508.2mV
906ps     524.8mV    627.7mV    503.8mV
1.045ns   522.9mV    552.1mV    503.3mV
1.25ns    521.4mV    525.4mV    503.2mV
[Falling Waveform]
R_fixture = 50
V_fixture = 0
V_fixture_min = 0
V_fixture_max = 0
100.3ps   802.1mV    701.5mV    960.5mV
145.7ps   802.1mV    701.5mV    840mV
233ps     784.1mV    701.5mV    305.4mV
284.9ps   656.2mV    701.5mV    133.7mV
353.2ps   411.7mV    701.5mV    35.08mV
439.9ps   145.1mV    701.5mV    11.02mV
579.1ps   24.86mV    564.3mV    3.348mV
841.7ps   5.646mV    83.99mV    0V
1.029ns   3.841mV    18.95mV    0V
1.325ns   2.801mV    3.871mV    0V
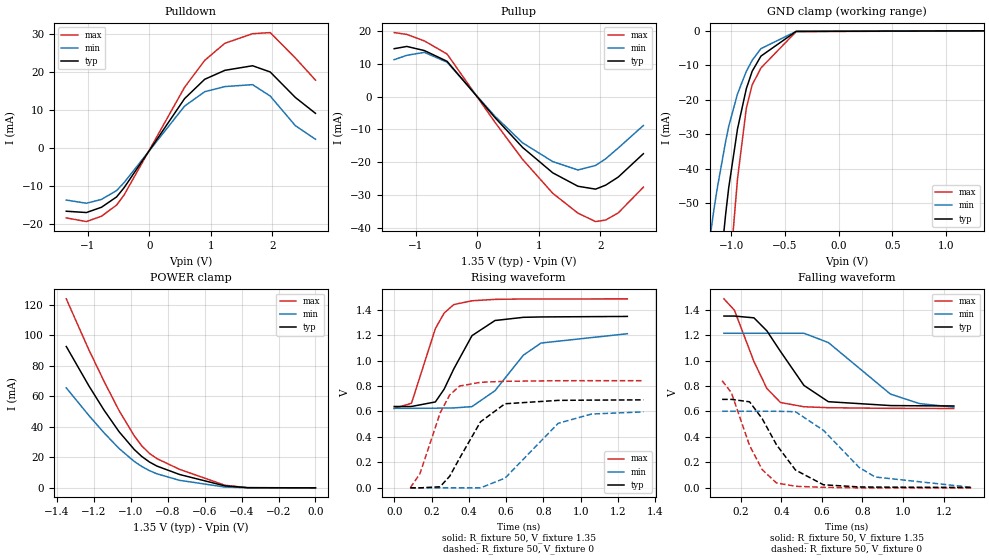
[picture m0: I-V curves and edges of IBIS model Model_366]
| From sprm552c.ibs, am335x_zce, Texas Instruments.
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| Model based on original model for BCSHTLTCSCDVPBFZ_SSDHV
|   Sub model SR01_8MA_10PER_1P35
[model]   Model_366
|[Description]  [1.35V-3-STATE-NOTERM-SR01:8MA, IND, 10%]
|   Slow slew rate (SR[1:0] = "01"), 1.00 * RExt = 1.000 * Iout
|   (I[2:0] = "011"), 8mA nominal with Rext = 50R,ODT off (ODT[1:0]
|   = "00") CMOS mode,Industrial temperature range (-40C to 125C,
|   25C nominal),10% power supply tolerance
|[Input Load]   NOTERM
|[Output Drive] SR01:8MA
|Voltage   1.35V
|Mode   3-STATE
Model_type   3-state
Polarity   Non-Inverting
Enable   Active-Low
Cref =  15pF
Rref =  100.0000M
Vref =  0V
Vmeas =  0.675
C_comp   1.865048p   1.676829p   1.989968p
[Temperature Range]   25   125   -40
[Voltage Range]   1.35   1.215   1.485
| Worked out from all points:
|   slope of the pulldown table from 0 to 0.203 V, typ, clamps not added: 40.4 ohm
|   slope of the pullup table from 0 to 0.203 V, typ, clamps not added: 44.6 ohm
|   GND clamp passes 1 mA (typ) near -0.49 V on its own axis
|   POWER clamp passes 1 mA (typ) near -0.47 V on its own axis
|   rising waveform, R_fixture 50, V_fixture 1.35: 20-80 % time 153ps typ, 206ps min, 114ps max; typ from 0.639 V to 1.35 V
|   rising waveform, R_fixture 50, V_fixture 0: 20-80 % time 166ps typ, 220ps min, 122ps max; typ from 0 V to 0.691 V
|   falling waveform, R_fixture 50, V_fixture 1.35: 20-80 % time 183ps typ, 250ps min, 131ps max; typ from 1.35 V to 0.643 V
|   falling waveform, R_fixture 50, V_fixture 0: 20-80 % time 168ps typ, 225ps min, 124ps max; typ from 0.695 V to 0.003 V
[POWER_clamp]
-1.35V    92.75mA    65.6mA     124mA
-1.227V   66.81mA    47.39mA    90.41mA
-1.145V   50.92mA    36.05mA    69.79mA
-1.064V   36.83mA    25.81mA    50.69mA
-981.8mV  25.17mA    17.34mA    34.13mA
-940.9mV  20.58mA    14.01mA    27.55mA
-900mV    17mA       11.33mA    22.63mA
-859.1mV  14.3mA     9.219mA    19.19mA
-736.4mV  8.769mA    4.944mA    12.14mA
-490.9mV  1.299mA    528.4uA    1.73mA
-368.2mV  117.2uA    50.88uA    117.5uA
0V        1.028nA    11.64nA    1.384nA
[Pulldown]
-1.35V    -16.62mA   -13.68mA   -18.38mA
-1.023V   -16.97mA   -14.52mA   -19.34mA
-777.3mV  -15.57mA   -13.51mA   -17.93mA
-531.8mV  -12.85mA   -11.18mA   -14.99mA
-409.1mV  -10.4mA    -9.061mA   -12.31mA
572.7mV   13.01mA    11.04mA    15.99mA
900mV     18.1mA     14.83mA    23.08mA
1.227V    20.45mA    16.18mA    27.57mA
1.677V    21.66mA    16.69mA    30.09mA
1.964V    20.03mA    13.7mA     30.39mA
2.373V    13.32mA    5.902mA    23.71mA
2.7V      9.141mA    2.314mA    17.88mA
[Pullup]
-1.35V    14.52mA    11.19mA    19.41mA
-1.145V   15.2mA     12.51mA    18.85mA
-859.1mV  13.95mA    13.41mA    16.88mA
-490.9mV  10.69mA    10.42mA    12.91mA
286.4mV   -6.362mA   -5.951mA   -7.77mA
736.4mV   -15.43mA   -14.05mA   -19.06mA
1.227V    -23.15mA   -19.74mA   -29.36mA
1.636V    -27.22mA   -22.29mA   -35.38mA
1.923V    -28.1mA    -20.92mA   -37.94mA
2.086V    -26.9mA    -18.91mA   -37.48mA
2.291V    -24.45mA   -15.63mA   -35.32mA
2.7V      -17.35mA   -8.787mA   -27.51mA
[GND_clamp]
-1.35V    -159.1mA   -94.77mA   -266.2mA
-1.295V   -137.7mA   -81.77mA   -230.9mA
-1.159V   -87.19mA   -51.56mA   -145.9mA
-1.132V   -77.89mA   -46.14mA   -129.9mA
-1.05V    -52.83mA   -31.83mA   -86.44mA
-1.023V   -45.55mA   -27.75mA   -73.68mA
-940.9mV  -28.44mA   -18.28mA   -42.92mA
-859.1mV  -16.79mA   -11.75mA   -22.47mA
-804.5mV  -11.72mA   -8.559mA   -15.69mA
-722.7mV  -7.324mA   -5.161mA   -10.76mA
-395.5mV  -159.1uA   -161.1uA   -232.4uA
1.35V     1.028nA    146.6nA    745.7pA
[Ramp]
dV/dt_f 0.42847763/0.18588896n  0.3562517/0.25920848n  0.5182265/0.13103945n
dV/dt_r 0.41946508/0.16847767n 0.36387351/0.22473564n 0.50742155/0.12206032n
R_load = 50
[Rising Waveform]
R_fixture = 50
V_fixture = 1.35
V_fixture_min = 1.215
V_fixture_max = 1.485
0s        639mV      624.8mV    624mV
92.77ps   639.6mV    624.8mV    664.8mV
220.7ps   675mV      625.8mV    1.251V
267.5ps   774.8mV    627.3mV    1.373V
319ps     933.3mV    627.8mV    1.44V
417.1ps   1.196V     638.5mV    1.47V
540.6ps   1.315V     763.5mV    1.481V
692.9ps   1.34V      1.043V     1.484V
787.5ps   1.343V     1.138V     1.484V
1.25ns    1.347V     1.211V     1.485V
[Rising Waveform]
R_fixture = 50
V_fixture = 0
V_fixture_min = 0
V_fixture_max = 0
85.95ps   0V         0V         0V
137.9ps   0V         0V         110.7mV
245.9ps   8.472mV    0V         587.1mV
297.7ps   91.46mV    0V         730.4mV
350.9ps   233.7mV    0V         800mV
462.9ps   518.9mV    0V         829.5mV
593.9ps   660.7mV    76.05mV    837.2mV
879.3ps   687.3mV    507.3mV    841.8mV
1.059ns   689.5mV    580.2mV    842mV
1.336ns   691.2mV    596.8mV    842.1mV
[Falling Waveform]
R_fixture = 50
V_fixture = 1.35
V_fixture_min = 1.215
V_fixture_max = 1.485
118.1ps   1.349V     1.214V     1.484V
169.7ps   1.349V     1.214V     1.395V
265.8ps   1.335V     1.214V     992.1mV
329.4ps   1.233V     1.214V     780.5mV
396.6ps   1.071V     1.214V     670.1mV
511.9ps   804.4mV    1.214V     636.8mV
632.2ps   676.5mV    1.141V     629.3mV
937.6ps   646.2mV    736.6mV    624.2mV
1.08ns    644.4mV    661.9mV    623.9mV
1.25ns    643.2mV    633.7mV    623.4mV
[Falling Waveform]
R_fixture = 50
V_fixture = 0
V_fixture_min = 0
V_fixture_max = 0
109.1ps   694.7mV    601.4mV    841.9mV
154.6ps   694.7mV    601.4mV    747.9mV
244.3ps   675.6mV    601.4mV    332.2mV
306.3ps   543.5mV    601.4mV    143.3mV
376.4ps   339.5mV    601.4mV    38.63mV
470.3ps   140mV      597.8mV    12.34mV
608.1ps   24.04mV    451.5mV    3.908mV
783.8ps   7.234mV    160.3mV    0V
862.4ps   5.941mV    85.21mV    0V
1.336ns   3.095mV    4.222mV    0V
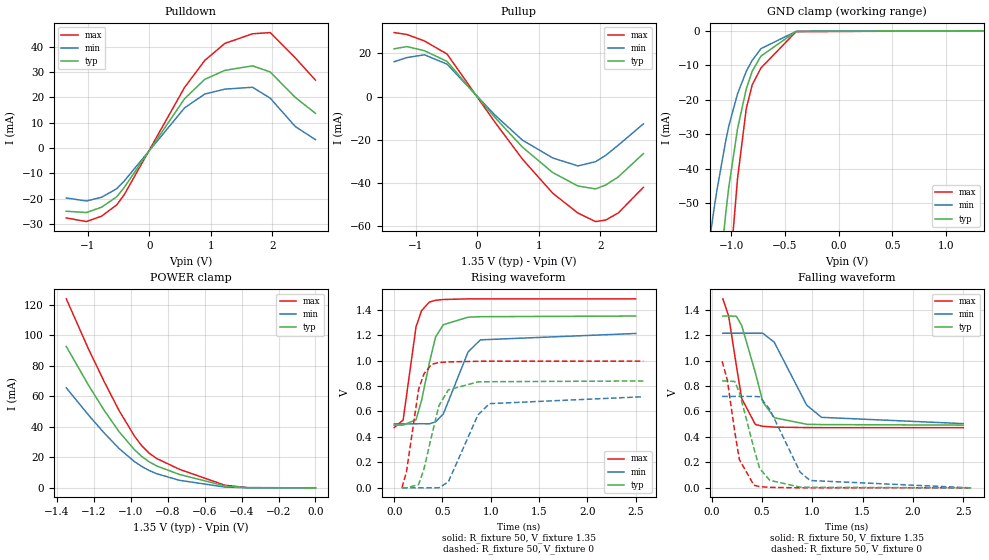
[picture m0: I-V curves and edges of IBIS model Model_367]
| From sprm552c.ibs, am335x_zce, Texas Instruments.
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| Model based on original model for BCSHTLTCSCDVPBFZ_SSDHV
|   Sub model SR10_12MA_10PER_1P35
[model]   Model_367
|[Description]  [1.35V-3-STATE-NOTERM-SR10:12MA, IND, 10%]
|   Fast slew rate (SR[1:0] = "10"), 0.67 * RExt = 1.500 * Iout
|   (I[2:0] = "111"), 12mA nominal with Rext = 50R,ODT off (ODT[1:0]
|   = "00") CMOS mode,Industrial temperature range (-40C to 125C,
|   25C nominal),10% power supply tolerance
|[Input Load]   NOTERM
|[Output Drive] SR10:12MA
|Voltage   1.35V
|Mode   3-STATE
Model_type   3-state
Polarity   Non-Inverting
Enable   Active-Low
Cref =  15pF
Rref =  100.0000M
Vref =  0V
Vmeas =  0.675
C_comp   1.865048p   1.676829p   1.989968p
[Temperature Range]   25   125   -40
[Voltage Range]   1.35   1.215   1.485
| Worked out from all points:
|   slope of the pulldown table from 0 to 0.203 V, typ, clamps not added: 27 ohm
|   slope of the pullup table from 0 to 0.203 V, typ, clamps not added: 29.4 ohm
|   GND clamp passes 1 mA (typ) near -0.49 V on its own axis
|   POWER clamp passes 1 mA (typ) near -0.47 V on its own axis
|   rising waveform, R_fixture 50, V_fixture 1.35: 20-80 % time 149ps typ, 221ps min, 109ps max; typ from 0.493 V to 1.35 V
|   rising waveform, R_fixture 50, V_fixture 0: 20-80 % time 161ps typ, 236ps min, 119ps max; typ from 0 V to 0.84 V
|   falling waveform, R_fixture 50, V_fixture 1.35: 20-80 % time 173ps typ, 264ps min, 125ps max; typ from 1.35 V to 0.492 V
|   falling waveform, R_fixture 50, V_fixture 0: 20-80 % time 162ps typ, 259ps min, 118ps max; typ from 0.84 V to 0 V
[POWER_clamp]
-1.35V    92.75mA    65.6mA     124mA
-1.227V   66.81mA    47.39mA    90.41mA
-1.145V   50.92mA    36.05mA    69.79mA
-1.064V   36.83mA    25.81mA    50.69mA
-981.8mV  25.17mA    17.34mA    34.13mA
-940.9mV  20.58mA    14.01mA    27.55mA
-900mV    17mA       11.33mA    22.63mA
-859.1mV  14.3mA     9.219mA    19.19mA
-736.4mV  8.769mA    4.944mA    12.14mA
-490.9mV  1.299mA    528.4uA    1.73mA
-368.2mV  117.2uA    50.88uA    117.5uA
0V        1.028nA    11.64nA    1.384nA
[Pulldown]
-1.35V    -24.93mA   -19.69mA   -27.57mA
-1.023V   -25.45mA   -20.89mA   -29.01mA
-777.3mV  -23.35mA   -19.43mA   -26.89mA
-531.8mV  -19.26mA   -16.07mA   -22.46mA
-409.1mV  -15.58mA   -13.03mA   -18.44mA
572.7mV   19.5mA     15.88mA    23.95mA
900mV     27.13mA    21.33mA    34.58mA
1.227V    30.67mA    23.28mA    41.33mA
1.677V    32.49mA    24.02mA    45.13mA
1.964V    30.06mA    19.73mA    45.61mA
2.373V    19.99mA    8.498mA    35.6mA
2.7V      13.72mA    3.331mA    26.83mA
[Pullup]
-1.35V    22.07mA    16.11mA    29.58mA
-1.145V   23.11mA    18.01mA    28.71mA
-859.1mV  21.2mA     19.3mA     25.71mA
-490.9mV  16.24mA    14.99mA    19.65mA
286.4mV   -9.66mA    -8.557mA   -11.82mA
736.4mV   -23.44mA   -20.2mA    -29.01mA
1.227V    -35.16mA   -28.4mA    -44.7mA
1.636V    -41.36mA   -32.08mA   -53.88mA
1.923V    -42.72mA   -30.12mA   -57.81mA
2.086V    -40.91mA   -27.22mA   -57.13mA
2.291V    -37.19mA   -22.51mA   -53.86mA
2.7V      -26.4mA    -12.65mA   -41.97mA
[GND_clamp]
-1.35V    -159.1mA   -94.77mA   -266.2mA
-1.295V   -137.7mA   -81.77mA   -230.9mA
-1.159V   -87.19mA   -51.56mA   -145.9mA
-1.132V   -77.89mA   -46.14mA   -129.9mA
-1.05V    -52.83mA   -31.83mA   -86.44mA
-1.023V   -45.55mA   -27.75mA   -73.68mA
-940.9mV  -28.44mA   -18.28mA   -42.92mA
-859.1mV  -16.79mA   -11.75mA   -22.47mA
-804.5mV  -11.72mA   -8.559mA   -15.69mA
-722.7mV  -7.324mA   -5.161mA   -10.76mA
-395.5mV  -159.1uA   -161.1uA   -232.4uA
1.35V     1.028nA    146.6nA    745.7pA
[Ramp]
dV/dt_f 0.51666267/0.17394358n  0.4301454/0.26762096n 0.60896707/0.12490966n
dV/dt_r 0.50687321/0.16204099n 0.43479638/0.23917456n 0.59967549/0.1188559n
R_load = 50
[Rising Waveform]
R_fixture = 50
V_fixture = 1.35
V_fixture_min = 1.215
V_fixture_max = 1.485
0s        492.8mV    502.6mV    473.6mV
92.75ps   493.1mV    502.6mV    533.2mV
225.9ps   535.1mV    503.5mV    1.265V
283ps     686.4mV    504.1mV    1.392V
364.2ps   982.3mV    503.3mV    1.46V
428.4ps   1.186V     518.2mV    1.474V
508.9ps   1.282V     580.9mV    1.48V
764.9ps   1.341V     1.068V     1.485V
892.7ps   1.345V     1.163V     1.485V
2.5ns     1.35V      1.213V     1.485V
[Rising Waveform]
R_fixture = 50
V_fixture = 0
V_fixture_min = 0
V_fixture_max = 0
79.76ps   0V         0V         0V
126.8ps   0V         0V         125.2mV
252.5ps   25.65mV    0V         772.8mV
307.7ps   146.2mV    0V         895.2mV
388.2ps   411.1mV    0V         970.9mV
463ps     645.9mV    0V         984.7mV
560.6ps   770mV      47.17mV    989.8mV
867.4ps   832.5mV    573.1mV    994.6mV
985.9ps   834.1mV    661.6mV    995.2mV
2.58ns    839.8mV    715.9mV    995.5mV
[Falling Waveform]
R_fixture = 50
V_fixture = 1.35
V_fixture_min = 1.215
V_fixture_max = 1.485
112ps     1.349V     1.214V     1.484V
169.5ps   1.349V     1.214V     1.349V
245.5ps   1.348V     1.214V     961mV
299ps     1.275V     1.214V     701.5mV
434.7ps   904mV      1.214V     497.6mV
508.9ps   675.3mV    1.214V     483.3mV
622ps     551.2mV    1.144V     477.1mV
944.6ps   499mV      649.7mV    473.1mV
1.092ns   496.9mV    553.7mV    472.8mV
2.5ns     492.5mV    504.4mV    472.6mV
[Falling Waveform]
R_fixture = 50
V_fixture = 0
V_fixture_min = 0
V_fixture_max = 0
104.4ps   839.6mV    718.1mV    994.5mV
156.2ps   839.6mV    718.1mV    846.9mV
229.7ps   834.9mV    718.1mV    441.1mV
276.7ps   747.9mV    718.1mV    220.3mV
420.4ps   309.1mV    718.1mV    20.47mV
477.4ps   153mV      715.1mV    9.465mV
576.7ps   59.57mV    618.1mV    3.789mV
878.9ps   5.523mV    124.2mV    0V
977.3ps   4.336mV    57.74mV    0V
2.58ns    0V         0V         0V
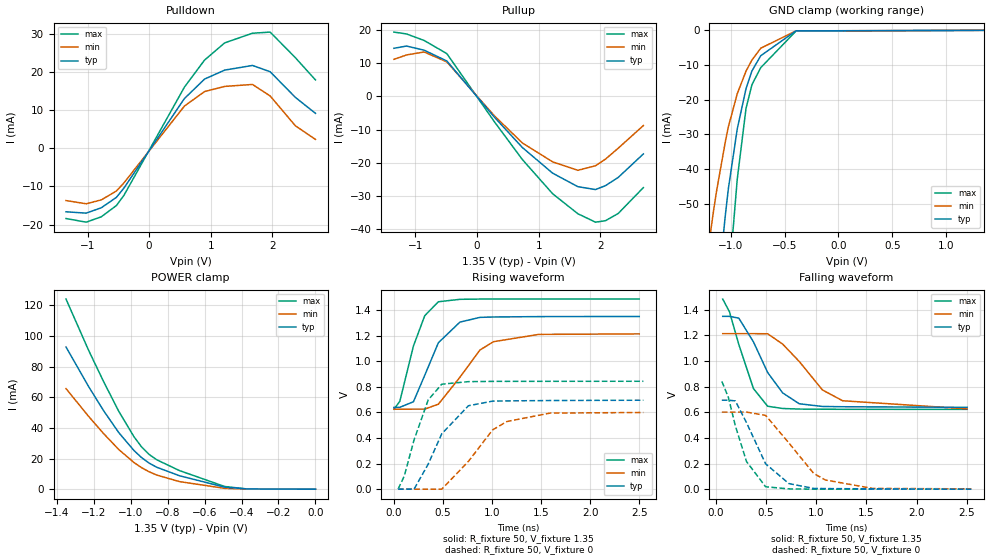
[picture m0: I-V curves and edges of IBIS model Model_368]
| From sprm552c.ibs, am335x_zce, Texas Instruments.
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| Model based on original model for BCSHTLTCSCDVPBFZ_SSDHV
|   Sub model SR11_8MA_10PER_1P35
[model]   Model_368
|[Description]  [1.35V-3-STATE-NOTERM-SR11:8MA, IND, 10%]
|   Slowest slew rate (SR[1:0] = "11"), 1.00 * RExt = 1.000 * Iout
|   (I[2:0] = "011"), 8mA nominal with Rext = 50R,ODT off (ODT[1:0]
|   = "00") CMOS mode,Industrial temperature range (-40C to 125C,
|   25C nominal),10% power supply tolerance
|[Input Load]   NOTERM
|[Output Drive] SR11:8MA
|Voltage   1.35V
|Mode   3-STATE
Model_type   3-state
Polarity   Non-Inverting
Enable   Active-Low
Cref =  15pF
Rref =  100.0000M
Vref =  0V
Vmeas =  0.675
C_comp   1.865048p   1.676829p   1.989968p
[Temperature Range]   25   125   -40
[Voltage Range]   1.35   1.215   1.485
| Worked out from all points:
|   slope of the pulldown table from 0 to 0.203 V, typ, clamps not added: 40.4 ohm
|   slope of the pullup table from 0 to 0.203 V, typ, clamps not added: 44.6 ohm
|   GND clamp passes 1 mA (typ) near -0.49 V on its own axis
|   POWER clamp passes 1 mA (typ) near -0.47 V on its own axis
|   rising waveform, R_fixture 50, V_fixture 1.35: 20-80 % time 250ps typ, 338ps min, 187ps max; typ from 0.639 V to 1.35 V
|   rising waveform, R_fixture 50, V_fixture 0: 20-80 % time 285ps typ, 368ps min, 206ps max; typ from 0 V to 0.695 V
|   falling waveform, R_fixture 50, V_fixture 1.35: 20-80 % time 300ps typ, 401ps min, 206ps max; typ from 1.35 V to 0.639 V
|   falling waveform, R_fixture 50, V_fixture 0: 20-80 % time 269ps typ, 365ps min, 200ps max; typ from 0.695 V to 0 V
[POWER_clamp]
-1.35V    92.75mA    65.6mA     124mA
-1.227V   66.81mA    47.39mA    90.41mA
-1.145V   50.92mA    36.05mA    69.79mA
-1.064V   36.83mA    25.81mA    50.69mA
-981.8mV  25.17mA    17.34mA    34.13mA
-940.9mV  20.58mA    14.01mA    27.55mA
-900mV    17mA       11.33mA    22.63mA
-859.1mV  14.3mA     9.219mA    19.19mA
-736.4mV  8.769mA    4.944mA    12.14mA
-490.9mV  1.299mA    528.4uA    1.73mA
-368.2mV  117.2uA    50.88uA    117.5uA
0V        1.028nA    11.64nA    1.384nA
[Pulldown]
-1.35V    -16.62mA   -13.68mA   -18.38mA
-1.023V   -16.97mA   -14.52mA   -19.34mA
-777.3mV  -15.57mA   -13.51mA   -17.93mA
-531.8mV  -12.85mA   -11.18mA   -14.99mA
-409.1mV  -10.4mA    -9.061mA   -12.31mA
572.7mV   13.01mA    11.04mA    15.99mA
900mV     18.1mA     14.83mA    23.08mA
1.227V    20.45mA    16.18mA    27.57mA
1.677V    21.66mA    16.69mA    30.09mA
1.964V    20.03mA    13.7mA     30.39mA
2.373V    13.32mA    5.902mA    23.71mA
2.7V      9.141mA    2.314mA    17.88mA
[Pullup]
-1.35V    14.52mA    11.19mA    19.41mA
-1.145V   15.2mA     12.51mA    18.85mA
-859.1mV  13.95mA    13.41mA    16.88mA
-490.9mV  10.69mA    10.42mA    12.91mA
286.4mV   -6.362mA   -5.951mA   -7.77mA
736.4mV   -15.43mA   -14.05mA   -19.06mA
1.227V    -23.15mA   -19.74mA   -29.36mA
1.636V    -27.22mA   -22.29mA   -35.38mA
1.923V    -28.1mA    -20.92mA   -37.94mA
2.086V    -26.9mA    -18.91mA   -37.48mA
2.291V    -24.45mA   -15.63mA   -35.32mA
2.7V      -17.35mA   -8.787mA   -27.51mA
[GND_clamp]
-1.35V    -159.1mA   -94.77mA   -266.2mA
-1.295V   -137.7mA   -81.77mA   -230.9mA
-1.159V   -87.19mA   -51.56mA   -145.9mA
-1.132V   -77.89mA   -46.14mA   -129.9mA
-1.05V    -52.83mA   -31.83mA   -86.44mA
-1.023V   -45.55mA   -27.75mA   -73.68mA
-940.9mV  -28.44mA   -18.28mA   -42.92mA
-859.1mV  -16.79mA   -11.75mA   -22.47mA
-804.5mV  -11.72mA   -8.559mA   -15.69mA
-722.7mV  -7.324mA   -5.161mA   -10.76mA
-395.5mV  -159.1uA   -161.1uA   -232.4uA
1.35V     1.028nA    146.6nA    745.7pA
[Ramp]
dV/dt_f 0.42850775/0.30110075n 0.35627447/0.40745837n 0.51835478/0.20673551n
dV/dt_r 0.41925758/0.28662621n 0.36381346/0.37423087n 0.50726335/0.20650001n
R_load = 50
[Rising Waveform]
R_fixture = 50
V_fixture = 1.35
V_fixture_min = 1.215
V_fixture_max = 1.485
0s        639mV      624.8mV    624mV
60.04ps   639.5mV    624.8mV    686.1mV
198.8ps   682.8mV    625.2mV    1.118V
314.1ps   889.3mV    625.5mV    1.355V
453.1ps   1.144V     663.8mV    1.464V
672.7ps   1.305V     874.3mV    1.483V
876.7ps   1.342V     1.087V     1.485V
1.015ns   1.345V     1.152V     1.485V
1.476ns   1.348V     1.209V     1.485V
2.5ns     1.349V     1.213V     1.485V
[Rising Waveform]
R_fixture = 50
V_fixture = 0
V_fixture_min = 0
V_fixture_max = 0
42.36ps   0V         0V         0V
105ps     0V         0V         101.3mV
205.1ps   0V         0V         384.2mV
349.1ps   195mV      0V         696.7mV
487.6ps   432.8mV    0V         820.1mV
759.5ps   651.7mV    217.2mV    840mV
1.006ns   687.6mV    463.1mV    842mV
1.15ns    689.5mV    528mV      841.9mV
1.591ns   692.4mV    594.4mV    842.5mV
2.542ns   694.8mV    599mV      842.8mV
[Falling Waveform]
R_fixture = 50
V_fixture = 1.35
V_fixture_min = 1.215
V_fixture_max = 1.485
71.02ps   1.349V     1.214V     1.484V
137.7ps   1.349V     1.214V     1.385V
230.9ps   1.335V     1.214V     1.129V
376.3ps   1.15V      1.214V     785.5mV
517.5ps   911mV      1.213V     647.3mV
666.2ps   751.9mV    1.133V     629.9mV
831.6ps   666.6mV    996.9mV    625.2mV
1.062ns   645.7mV    774.7mV    624.1mV
1.263ns   643.5mV    690.2mV    623.5mV
2.5ns     638.9mV    627mV      623mV
[Falling Waveform]
R_fixture = 50
V_fixture = 0
V_fixture_min = 0
V_fixture_max = 0
62.1ps    694.7mV    601.4mV    841.9mV
127.4ps   694.7mV    601.4mV    715.6mV
196.7ps   688.9mV    601.4mV    494.3mV
307.6ps   518.6mV    601.4mV    215.4mV
497.5ps   198mV      575.9mV    18.78mV
728.3ps   43.7mV     360.9mV    2.176mV
975.6ps   5.724mV    122.5mV    0V
1.091ns   4.55mV     71.77mV    0V
1.561ns   2.484mV    5.85mV     0V
2.542ns   0V         2.37mV     0V
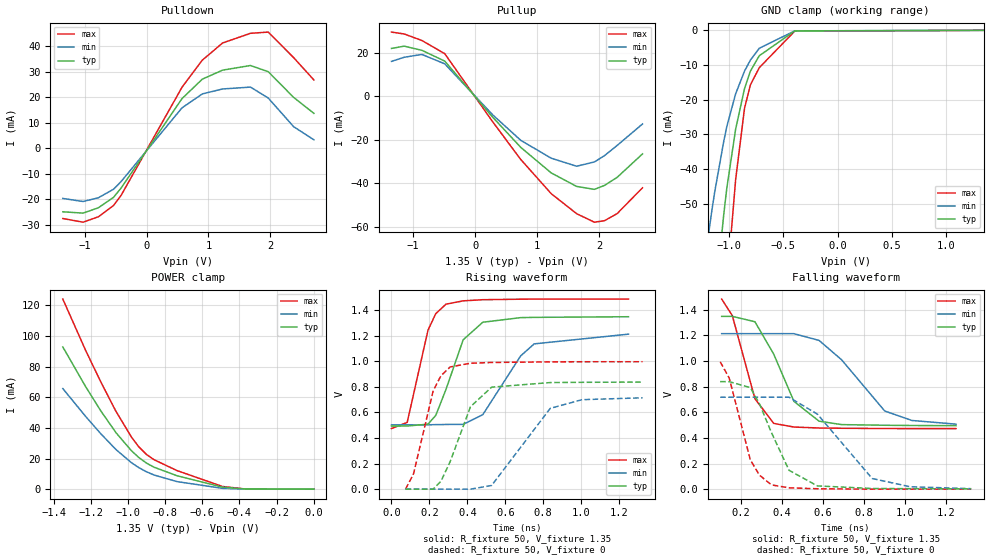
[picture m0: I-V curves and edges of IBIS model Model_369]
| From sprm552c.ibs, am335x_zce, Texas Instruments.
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| Model based on original model for BCSHTLTCSCDVPBFZ_SSDHV
|   Sub model SR01_12MA_10PER_1P35
[model]   Model_369
|[Description]  [1.35V-3-STATE-NOTERM-SR01:12MA, IND, 10%]
|   Slow slew rate (SR[1:0] = "01"), 0.67 * RExt = 1.500 * Iout
|   (I[2:0] = "111"), 12mA nominal with Rext = 50R,ODT off (ODT[1:0]
|   = "00") CMOS mode,Industrial temperature range (-40C to 125C,
|   25C nominal),10% power supply tolerance
|[Input Load]   NOTERM
|[Output Drive] SR01:12MA
|Voltage   1.35V
|Mode   3-STATE
Model_type   3-state
Polarity   Non-Inverting
Enable   Active-Low
Cref =  15pF
Rref =  100.0000M
Vref =  0V
Vmeas =  0.675
C_comp   1.865048p   1.676829p   1.989968p
[Temperature Range]   25   125   -40
[Voltage Range]   1.35   1.215   1.485
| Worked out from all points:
|   slope of the pulldown table from 0 to 0.203 V, typ, clamps not added: 27 ohm
|   slope of the pullup table from 0 to 0.203 V, typ, clamps not added: 29.4 ohm
|   GND clamp passes 1 mA (typ) near -0.49 V on its own axis
|   POWER clamp passes 1 mA (typ) near -0.47 V on its own axis
|   rising waveform, R_fixture 50, V_fixture 1.35: 20-80 % time 122ps typ, 178ps min, 90.1ps max; typ from 0.493 V to 1.35 V
|   rising waveform, R_fixture 50, V_fixture 0: 20-80 % time 130ps typ, 189ps min, 97.2ps max; typ from 0 V to 0.836 V
|   falling waveform, R_fixture 50, V_fixture 1.35: 20-80 % time 144ps typ, 220ps min, 105ps max; typ from 1.35 V to 0.496 V
|   falling waveform, R_fixture 50, V_fixture 0: 20-80 % time 135ps typ, 211ps min, 99.3ps max; typ from 0.839 V to 0.003 V
[POWER_clamp]
-1.35V    92.75mA    65.6mA     124mA
-1.227V   66.81mA    47.39mA    90.41mA
-1.145V   50.92mA    36.05mA    69.79mA
-1.064V   36.83mA    25.81mA    50.69mA
-981.8mV  25.17mA    17.34mA    34.13mA
-940.9mV  20.58mA    14.01mA    27.55mA
-900mV    17mA       11.33mA    22.63mA
-859.1mV  14.3mA     9.219mA    19.19mA
-736.4mV  8.769mA    4.944mA    12.14mA
-490.9mV  1.299mA    528.4uA    1.73mA
-368.2mV  117.2uA    50.88uA    117.5uA
0V        1.028nA    11.64nA    1.384nA
[Pulldown]
-1.35V    -24.93mA   -19.69mA   -27.57mA
-1.023V   -25.45mA   -20.89mA   -29.01mA
-777.3mV  -23.35mA   -19.43mA   -26.89mA
-531.8mV  -19.26mA   -16.07mA   -22.46mA
-409.1mV  -15.58mA   -13.03mA   -18.44mA
572.7mV   19.5mA     15.88mA    23.95mA
900mV     27.13mA    21.33mA    34.58mA
1.227V    30.67mA    23.28mA    41.33mA
1.677V    32.49mA    24.02mA    45.13mA
1.964V    30.06mA    19.73mA    45.61mA
2.373V    19.99mA    8.498mA    35.6mA
2.7V      13.72mA    3.331mA    26.83mA
[Pullup]
-1.35V    22.07mA    16.11mA    29.58mA
-1.145V   23.11mA    18.01mA    28.71mA
-859.1mV  21.2mA     19.3mA     25.71mA
-490.9mV  16.24mA    14.99mA    19.65mA
286.4mV   -9.66mA    -8.557mA   -11.82mA
736.4mV   -23.44mA   -20.2mA    -29.01mA
1.227V    -35.16mA   -28.4mA    -44.7mA
1.636V    -41.36mA   -32.08mA   -53.88mA
1.923V    -42.72mA   -30.12mA   -57.81mA
2.086V    -40.91mA   -27.22mA   -57.13mA
2.291V    -37.19mA   -22.51mA   -53.86mA
2.7V      -26.4mA    -12.65mA   -41.97mA
[GND_clamp]
-1.35V    -159.1mA   -94.77mA   -266.2mA
-1.295V   -137.7mA   -81.77mA   -230.9mA
-1.159V   -87.19mA   -51.56mA   -145.9mA
-1.132V   -77.89mA   -46.14mA   -129.9mA
-1.05V    -52.83mA   -31.83mA   -86.44mA
-1.023V   -45.55mA   -27.75mA   -73.68mA
-940.9mV  -28.44mA   -18.28mA   -42.92mA
-859.1mV  -16.79mA   -11.75mA   -22.47mA
-804.5mV  -11.72mA   -8.559mA   -15.69mA
-722.7mV  -7.324mA   -5.161mA   -10.76mA
-395.5mV  -159.1uA   -161.1uA   -232.4uA
1.35V     1.028nA    146.6nA    745.7pA
[Ramp]
dV/dt_f 0.51678851/0.14631639n 0.43008254/0.22396945n 0.60906779/0.10511664n
dV/dt_r 0.50716724/0.13216145n 0.43480861/0.19286565n 0.59993845/97.520494p
R_load = 50
[Rising Waveform]
R_fixture = 50
V_fixture = 1.35
V_fixture_min = 1.215
V_fixture_max = 1.485
0s        492.8mV    502.5mV    473.6mV
82.78ps   493.2mV    502.5mV    521.4mV
192.5ps   507.9mV    502.8mV    1.242V
233.5ps   576.1mV    504.1mV    1.371V
287.4ps   779.3mV    505.3mV    1.445V
378ps     1.167V     506.1mV    1.471V
481.6ps   1.304V     582.1mV    1.48V
681.2ps   1.34V      1.041V     1.484V
752.7ps   1.342V     1.135V     1.485V
1.25ns    1.347V     1.211V     1.485V
[Rising Waveform]
R_fixture = 50
V_fixture = 0
V_fixture_min = 0
V_fixture_max = 0
74.18ps   0V         0V         0V
116.5ps   0V         0V         120.7mV
219.5ps   0V         0V         766.1mV
260.6ps   60.65mV    0V         885.9mV
309.3ps   214.5mV    0V         954.6mV
416.6ps   644.1mV    0V         983.7mV
528.1ps   796.8mV    28.94mV    989.7mV
837.3ps   832.8mV    631mV      994.6mV
1.005ns   834.7mV    699mV      995.3mV
1.324ns   836.5mV    713.7mV    995.4mV
[Falling Waveform]
R_fixture = 50
V_fixture = 1.35
V_fixture_min = 1.215
V_fixture_max = 1.485
107.5ps   1.349V     1.214V     1.484V
159.3ps   1.349V     1.214V     1.355V
269.7ps   1.307V     1.214V     705.5mV
361.6ps   1.053V     1.214V     513.2mV
459.8ps   685.4mV    1.214V     485mV
582.4ps   530.7mV    1.161V     477.4mV
692.2ps   503.9mV    1.01V      475.5mV
902.5ps   498.9mV    610.1mV    473.2mV
1.035ns   497mV      536.2mV    472.8mV
1.25ns    495.5mV    507.5mV    472.7mV
[Falling Waveform]
R_fixture = 50
V_fixture = 0
V_fixture_min = 0
V_fixture_max = 0
100.1ps   839.4mV    717.7mV    994.5mV
144.3ps   839.4mV    717.7mV    867.4mV
247.1ps   793mV      717.7mV    229.3mV
291.3ps   668.1mV    717.7mV    110mV
350.3ps   441.1mV    717.7mV    33.39mV
435.9ps   147.2mV    717.7mV    10.38mV
574.2ps   25.35mV    585.8mV    3.164mV
841.1ps   5.493mV    83.22mV    0V
1.026ns   3.746mV    18.98mV    0V
1.324ns   2.545mV    3.701mV    0V
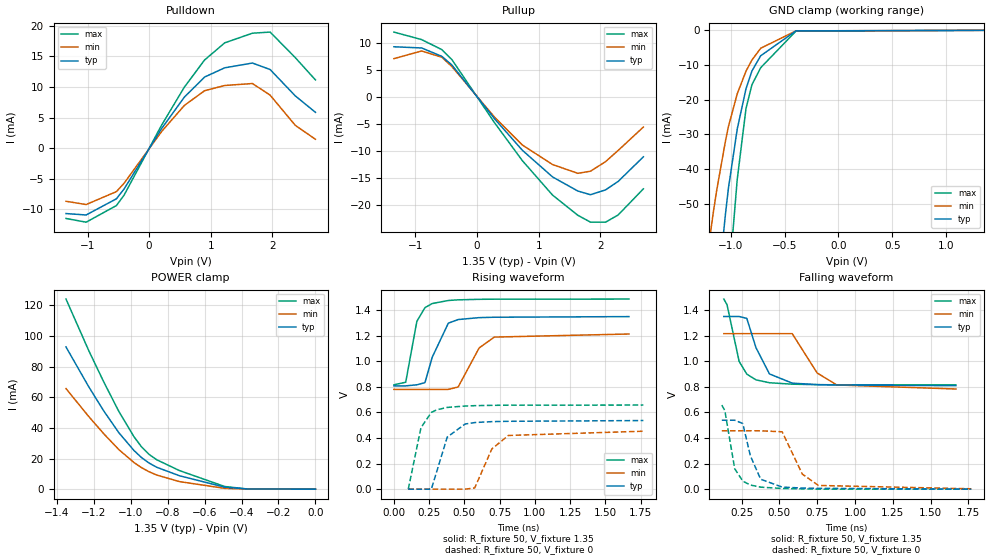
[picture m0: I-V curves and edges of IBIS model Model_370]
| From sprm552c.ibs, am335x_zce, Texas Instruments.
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| Model based on original model for BCSHTLTCSCDVPBFZ_SSDHV
|   Sub model SR00_5MA_10PER_1P35
[model]   Model_370
|[Description]  [1.35V-3-STATE-NOTERM-SR00:5MA, IND, 10%]
|   Fastest slew rate (SR[1:0] = "00"), 1.60 * RExt = 0.625 * Iout
|   (I[2:0] = "000"), 5mA nominal with Rext = 50R,ODT off (ODT[1:0]
|   = "00") CMOS mode,Industrial temperature range (-40C to 125C,
|   25C nominal),10% power supply tolerance
|[Input Load]   NOTERM
|[Output Drive] SR00:5MA
|Voltage   1.35V
|Mode   3-STATE
Model_type   3-state
Polarity   Non-Inverting
Enable   Active-Low
Cref =  15pF
Rref =  100.0000M
Vref =  0V
Vmeas =  0.675
C_comp   1.865048p   1.676829p   1.989968p
[Temperature Range]   25   125   -40
[Voltage Range]   1.35   1.215   1.485
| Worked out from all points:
|   slope of the pulldown table from 0 to 0.203 V, typ, clamps not added: 62.9 ohm
|   slope of the pullup table from 0 to 0.203 V, typ, clamps not added: 69.7 ohm
|   GND clamp passes 1 mA (typ) near -0.49 V on its own axis
|   POWER clamp passes 1 mA (typ) near -0.47 V on its own axis
|   rising waveform, R_fixture 50, V_fixture 1.35: 20-80 % time 90.9ps typ, 130ps min, 70.7ps max; typ from 0.807 V to 1.35 V
|   rising waveform, R_fixture 50, V_fixture 0: 20-80 % time 94.1ps typ, 119ps min, 77.9ps max; typ from 0 V to 0.536 V
|   falling waveform, R_fixture 50, V_fixture 1.35: 20-80 % time 110ps typ, 146ps min, 85.3ps max; typ from 1.35 V to 0.808 V
|   falling waveform, R_fixture 50, V_fixture 0: 20-80 % time 77.8ps typ, 104ps min, 63.8ps max; typ from 0.539 V to 0 V
[POWER_clamp]
-1.35V    92.75mA    65.6mA     124mA
-1.227V   66.81mA    47.39mA    90.41mA
-1.145V   50.92mA    36.05mA    69.79mA
-1.064V   36.83mA    25.81mA    50.69mA
-981.8mV  25.17mA    17.34mA    34.13mA
-940.9mV  20.58mA    14.01mA    27.55mA
-900mV    17mA       11.33mA    22.63mA
-859.1mV  14.3mA     9.219mA    19.19mA
-736.4mV  8.769mA    4.944mA    12.14mA
-490.9mV  1.299mA    528.4uA    1.73mA
-368.2mV  117.2uA    50.88uA    117.5uA
0V        1.028nA    11.64nA    1.384nA
[Pulldown]
-1.35V    -10.68mA   -8.671mA   -11.48mA
-1.023V   -10.91mA   -9.206mA   -12.09mA
-531.8mV  -8.266mA   -7.092mA   -9.372mA
-409.1mV  -6.689mA   -5.75mA    -7.702mA
204.5mV   3.253mA    2.759mA    3.817mA
572.7mV   8.37mA     7.007mA    10mA
900mV     11.64mA    9.405mA    14.43mA
1.227V    13.15mA    10.26mA    17.23mA
1.677V    13.93mA    10.58mA    18.81mA
1.964V    12.87mA    8.684mA    18.99mA
2.373V    8.556mA    3.74mA     14.81mA
2.7V      5.873mA    1.467mA    11.17mA
[Pullup]
-1.35V    9.289mA    7.093mA    12.01mA
-900mV    9.073mA    8.512mA    10.62mA
-572.7mV  7.523mA    7.357mA    8.764mA
-409.1mV  5.918mA    5.637mA    6.921mA
286.4mV   -4.075mA   -3.777mA   -4.815mA
736.4mV   -9.883mA   -8.912mA   -11.81mA
1.227V    -14.82mA   -12.52mA   -18.19mA
1.636V    -17.42mA   -14.14mA   -21.91mA
1.841V    -18.1mA    -13.75mA   -23.18mA
2.086V    -17.21mA   -11.98mA   -23.19mA
2.291V    -15.64mA   -9.903mA   -21.85mA
2.7V      -11.09mA   -5.569mA   -17.02mA
[GND_clamp]
-1.35V    -159.1mA   -94.77mA   -266.2mA
-1.295V   -137.7mA   -81.77mA   -230.9mA
-1.159V   -87.19mA   -51.56mA   -145.9mA
-1.132V   -77.89mA   -46.14mA   -129.9mA
-1.05V    -52.83mA   -31.83mA   -86.44mA
-1.023V   -45.55mA   -27.75mA   -73.68mA
-940.9mV  -28.44mA   -18.28mA   -42.92mA
-859.1mV  -16.79mA   -11.75mA   -22.47mA
-804.5mV  -11.72mA   -8.559mA   -15.69mA
-722.7mV  -7.324mA   -5.161mA   -10.76mA
-395.5mV  -159.1uA   -161.1uA   -232.4uA
1.35V     1.028nA    146.6nA    745.7pA
[Ramp]
dV/dt_f 0.33085225/0.11144718n 0.26716704/0.15014527n 0.40608219/85.447771p
dV/dt_r 0.32886999/95.551288p 0.28180218/0.12282595n 0.39931848/78.012059p
R_load = 50
[Rising Waveform]
R_fixture = 50
V_fixture = 1.35
V_fixture_min = 1.215
V_fixture_max = 1.485
0s        806.9mV    779.4mV    815.2mV
83.75ps   806.9mV    779.4mV    835.4mV
162.7ps   815.1mV    779.4mV    1.311V
220.1ps   832.1mV    779.4mV    1.418V
271.8ps   1.031V     779.4mV    1.45V
386ps     1.297V     779.4mV    1.474V
455.6ps   1.325V     798.3mV    1.479V
604.3ps   1.34V      1.103V     1.483V
711.9ps   1.343V     1.188V     1.484V
1.667ns   1.348V     1.212V     1.485V
[Rising Waveform]
R_fixture = 50
V_fixture = 0
V_fixture_min = 0
V_fixture_max = 0
101.9ps   0V         0V         0V
191.8ps   0V         0V         480.6mV
265.4ps   0V         0V         599.1mV
301.5ps   129.8mV    0V         619.3mV
378ps     406.5mV    0V         638.5mV
504.4ps   508.7mV    0V         649.5mV
572.9ps   520.4mV    9.339mV    652.2mV
694.6ps   527.5mV    314.5mV    654.8mV
811.8ps   530.1mV    419.5mV    656mV
1.769ns   536.1mV    452.7mV    657mV
[Falling Waveform]
R_fixture = 50
V_fixture = 1.35
V_fixture_min = 1.215
V_fixture_max = 1.485
132.1ps   1.349V     1.215V     1.485V
153.3ps   1.349V     1.215V     1.441V
233.2ps   1.349V     1.215V     998.5mV
284.1ps   1.334V     1.215V     898.6mV
344.8ps   1.105V     1.215V     853.8mV
434ps     900.1mV    1.215V     831.3mV
584.4ps   828.4mV    1.215V     820.1mV
749.3ps   816.5mV    907.7mV    816.4mV
879.3ps   813.7mV    814mV      815.3mV
1.667ns   808.4mV    782.5mV    814.2mV
[Falling Waveform]
R_fixture = 50
V_fixture = 0
V_fixture_min = 0
V_fixture_max = 0
118.9ps   538.6mV    456mV      656.8mV
138.9ps   538.6mV    456mV      613.2mV
204ps     538.6mV    456mV      159.9mV
257.6ps   512.6mV    456mV      62.76mV
307.9ps   259.2mV    456mV      32.14mV
376.2ps   77.17mV    456mV      15.78mV
517.9ps   16.55mV    448.2mV    5.351mV
651.7ps   8.536mV    117.2mV    2.388mV
758ps     6.529mV    28.98mV    0V
1.769ns   0V         2.985mV    0V
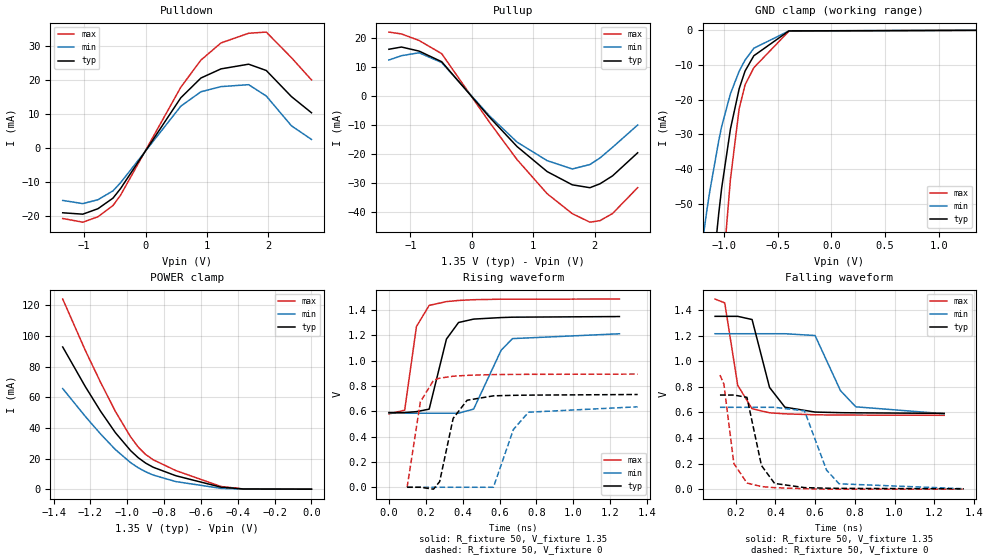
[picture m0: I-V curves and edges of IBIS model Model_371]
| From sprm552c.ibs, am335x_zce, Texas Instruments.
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| Model based on original model for BCSHTLTCSCDVPBFZ_SSDHV
|   Sub model SR00_9MA_10PER_1P35
[model]   Model_371
|[Description]  [1.35V-3-STATE-NOTERM-SR00:9MA, IND, 10%]
|   Fastest slew rate (SR[1:0] = "00"), 0.88 * RExt = 1.125 * Iout
|   (I[2:0] = "100"), 9mA nominal with Rext = 50R,ODT off (ODT[1:0]
|   = "00") CMOS mode,Industrial temperature range (-40C to 125C,
|   25C nominal),10% power supply tolerance
|[Input Load]   NOTERM
|[Output Drive] SR00:9MA
|Voltage   1.35V
|Mode   3-STATE
Model_type   3-state
Polarity   Non-Inverting
Enable   Active-Low
Cref =  15pF
Rref =  100.0000M
Vref =  0V
Vmeas =  0.675
C_comp   1.865048p   1.676829p   1.989968p
[Temperature Range]   25   125   -40
[Voltage Range]   1.35   1.215   1.485
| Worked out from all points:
|   slope of the pulldown table from 0 to 0.203 V, typ, clamps not added: 35.4 ohm
|   slope of the pullup table from 0 to 0.203 V, typ, clamps not added: 39.9 ohm
|   GND clamp passes 1 mA (typ) near -0.49 V on its own axis
|   POWER clamp passes 1 mA (typ) near -0.47 V on its own axis
|   rising waveform, R_fixture 50, V_fixture 1.35: 20-80 % time 73.3ps typ, 119ps min, 50.6ps max; typ from 0.589 V to 1.35 V
|   rising waveform, R_fixture 50, V_fixture 0: 20-80 % time 70.1ps typ, 90.4ps min, 54.2ps max; typ from 0 V to 0.732 V
|   falling waveform, R_fixture 50, V_fixture 1.35: 20-80 % time 79.1ps typ, 112ps min, 58.4ps max; typ from 1.35 V to 0.593 V
|   falling waveform, R_fixture 50, V_fixture 0: 20-80 % time 57.6ps typ, 82.6ps min, 45.4ps max; typ from 0.736 V to 0.003 V
[POWER_clamp]
-1.35V    92.75mA    65.6mA     124mA
-1.227V   66.81mA    47.39mA    90.41mA
-1.145V   50.92mA    36.05mA    69.79mA
-1.064V   36.83mA    25.81mA    50.69mA
-981.8mV  25.17mA    17.34mA    34.13mA
-940.9mV  20.58mA    14.01mA    27.55mA
-900mV    17mA       11.33mA    22.63mA
-859.1mV  14.3mA     9.219mA    19.19mA
-736.4mV  8.769mA    4.944mA    12.14mA
-490.9mV  1.299mA    528.4uA    1.73mA
-368.2mV  117.2uA    50.88uA    117.5uA
0V        1.028nA    11.64nA    1.384nA
[Pulldown]
-1.35V    -18.99mA   -15.35mA   -20.67mA
-1.023V   -19.4mA    -16.29mA   -21.76mA
-777.3mV  -17.8mA    -15.15mA   -20.17mA
-531.8mV  -14.68mA   -12.54mA   -16.86mA
-409.1mV  -11.88mA   -10.16mA   -13.84mA
572.7mV   14.87mA    12.39mA    17.98mA
900mV     20.68mA    16.63mA    25.96mA
1.227V    23.37mA    18.15mA    31.01mA
1.677V    24.75mA    18.72mA    33.86mA
1.964V    22.89mA    15.38mA    34.2mA
2.373V    15.22mA    6.623mA    26.68mA
2.7V      10.45mA    2.596mA    20.12mA
[Pullup]
-1.35V    16.26mA    12.55mA    22.18mA
-1.145V   17.03mA    14.04mA    21.54mA
-859.1mV  15.63mA    15.05mA    19.29mA
-490.9mV  11.97mA    11.69mA    14.75mA
286.4mV   -7.124mA   -6.675mA   -8.876mA
736.4mV   -17.28mA   -15.75mA   -21.78mA
1.227V    -25.92mA   -22.15mA   -33.55mA
1.636V    -30.48mA   -25.01mA   -40.42mA
1.923V    -31.47mA   -23.48mA   -43.36mA
2.086V    -30.13mA   -21.22mA   -42.83mA
2.291V    -27.39mA   -17.54mA   -40.37mA
2.7V      -19.43mA   -9.86mA    -31.45mA
[GND_clamp]
-1.35V    -159.1mA   -94.77mA   -266.2mA
-1.295V   -137.7mA   -81.77mA   -230.9mA
-1.159V   -87.19mA   -51.56mA   -145.9mA
-1.132V   -77.89mA   -46.14mA   -129.9mA
-1.05V    -52.83mA   -31.83mA   -86.44mA
-1.023V   -45.55mA   -27.75mA   -73.68mA
-940.9mV  -28.44mA   -18.28mA   -42.92mA
-859.1mV  -16.79mA   -11.75mA   -22.47mA
-804.5mV  -11.72mA   -8.559mA   -15.69mA
-722.7mV  -7.324mA   -5.161mA   -10.76mA
-395.5mV  -159.1uA   -161.1uA   -232.4uA
1.35V     1.028nA    146.6nA    745.7pA
[Ramp]
dV/dt_f  0.4636862/80.633075p 0.38512705/0.11540852n 0.55055026/58.638071p
dV/dt_r 0.45149221/71.646448p 0.39723095/93.652913p  0.5444422/54.433875p
R_load = 50
[Rising Waveform]
R_fixture = 50
V_fixture = 1.35
V_fixture_min = 1.215
V_fixture_max = 1.485
0s        589.3mV    584.6mV    578.3mV
85.63ps   589.3mV    584.6mV    608.5mV
149.4ps   596.7mV    584.6mV    1.268V
218.4ps   616.4mV    584.6mV    1.435V
312ps     1.169V     584.6mV    1.465V
377.6ps   1.3V       584.6mV    1.474V
459.5ps   1.327V     616.8mV    1.48V
608.6ps   1.339V     1.081V     1.484V
670.3ps   1.342V     1.173V     1.484V
1.25ns    1.347V     1.211V     1.485V
[Rising Waveform]
R_fixture = 50
V_fixture = 0
V_fixture_min = 0
V_fixture_max = 0
98.96ps   0V         0V         0V
170.6ps   0V         0V         673.3mV
241.9ps   -15.05mV   0V         843.3mV
275.2ps   44.36mV    0V         860.8mV
348.4ps   543.3mV    0V         876.2mV
424.1ps   686.6mV    0V         883.1mV
566.9ps   721.4mV    0V         889mV
675.3ps   725.4mV    456.4mV    890.6mV
757.2ps   727mV      592.2mV    891mV
1.349ns   731.9mV    634.9mV    893mV
[Falling Waveform]
R_fixture = 50
V_fixture = 1.35
V_fixture_min = 1.215
V_fixture_max = 1.485
96.02ps   1.351V     1.215V     1.486V
144.7ps   1.351V     1.215V     1.456V
210ps     1.351V     1.215V     812.3mV
282.4ps   1.326V     1.215V     628.9mV
370.4ps   795.1mV    1.215V     597mV
447.8ps   640.7mV    1.215V     588.9mV
599.6ps   602.7mV    1.201V     581.3mV
727.4ps   598mV      770.8mV    579.4mV
804.7ps   596.7mV    643.7mV    579mV
1.25ns    592.6mV    589.7mV    577.4mV
[Falling Waveform]
R_fixture = 50
V_fixture = 0
V_fixture_min = 0
V_fixture_max = 0
120.6ps   735.8mV    639.9mV    892.2mV
140.6ps   735.8mV    639.9mV    820.9mV
190.7ps   735.8mV    639.9mV    200.5mV
256.6ps   717.8mV    639.9mV    48.04mV
329.6ps   185mV      639.9mV    20.2mV
395.7ps   44.79mV    639.9mV    11.71mV
546.6ps   12.2mV     611.6mV    3.491mV
657.4ps   7.598mV    149.1mV    0V
720.9ps   6.352mV    41.81mV    0V
1.349ns   2.72mV     3.518mV    0V
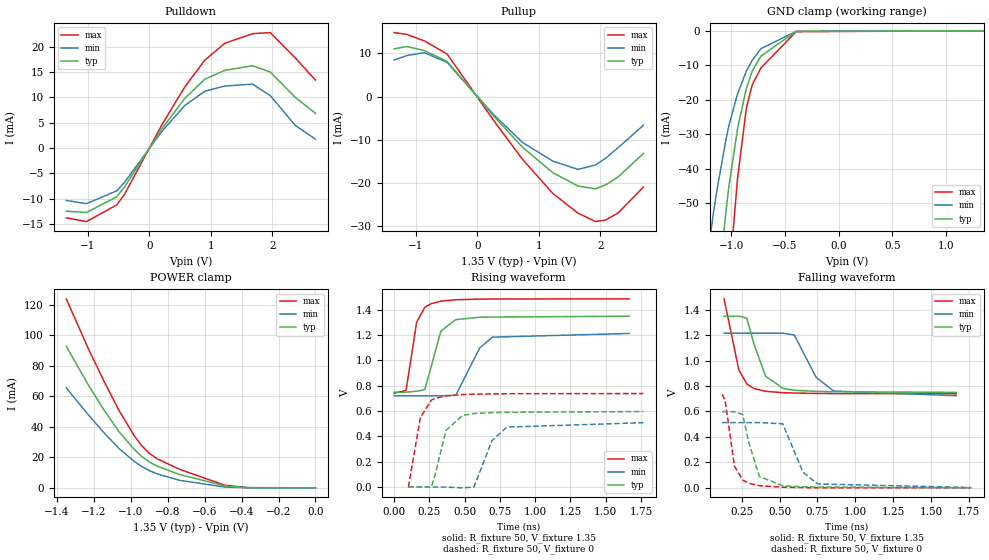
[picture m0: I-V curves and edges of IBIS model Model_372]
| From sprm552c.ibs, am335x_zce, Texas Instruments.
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| Model based on original model for BCSHTLTCSCDVPBFZ_SSDHV
|   Sub model SR00_6MA_10PER_1P35
[model]   Model_372
|[Description]  [1.35V-3-STATE-NOTERM-SR00:6MA, IND, 10%]
|   Fastest slew rate (SR[1:0] = "00"), 1.33 * RExt = 0.750 * Iout
|   (I[2:0] = "001"), 6mA nominal with Rext = 50R,ODT off (ODT[1:0]
|   = "00") CMOS mode,Industrial temperature range (-40C to 125C,
|   25C nominal),10% power supply tolerance
|[Input Load]   NOTERM
|[Output Drive] SR00:6MA
|Voltage   1.35V
|Mode   3-STATE
Model_type   3-state
Polarity   Non-Inverting
Enable   Active-Low
Cref =  15pF
Rref =  100.0000M
Vref =  0V
Vmeas =  0.675
C_comp   1.865048p   1.676829p   1.989968p
[Temperature Range]   25   125   -40
[Voltage Range]   1.35   1.215   1.485
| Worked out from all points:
|   slope of the pulldown table from 0 to 0.203 V, typ, clamps not added: 53.9 ohm
|   slope of the pullup table from 0 to 0.203 V, typ, clamps not added: 58.7 ohm
|   GND clamp passes 1 mA (typ) near -0.49 V on its own axis
|   POWER clamp passes 1 mA (typ) near -0.47 V on its own axis
|   rising waveform, R_fixture 50, V_fixture 1.35: 20-80 % time 85.6ps typ, 127ps min, 63.7ps max; typ from 0.748 V to 1.35 V
|   rising waveform, R_fixture 50, V_fixture 0: 20-80 % time 86.9ps typ, 111ps min, 69.7ps max; typ from 0 V to 0.596 V
|   falling waveform, R_fixture 50, V_fixture 1.35: 20-80 % time 102ps typ, 137ps min, 76.7ps max; typ from 1.35 V to 0.75 V
|   falling waveform, R_fixture 50, V_fixture 0: 20-80 % time 72.4ps typ, 98.1ps min, 57.8ps max; typ from 0.599 V to 0 V
[POWER_clamp]
-1.35V    92.75mA    65.6mA     124mA
-1.227V   66.81mA    47.39mA    90.41mA
-1.145V   50.92mA    36.05mA    69.79mA
-1.064V   36.83mA    25.81mA    50.69mA
-981.8mV  25.17mA    17.34mA    34.13mA
-940.9mV  20.58mA    14.01mA    27.55mA
-900mV    17mA       11.33mA    22.63mA
-859.1mV  14.3mA     9.219mA    19.19mA
-736.4mV  8.769mA    4.944mA    12.14mA
-490.9mV  1.299mA    528.4uA    1.73mA
-368.2mV  117.2uA    50.88uA    117.5uA
0V        1.028nA    11.64nA    1.384nA
[Pulldown]
-1.35V    -12.46mA   -10.34mA   -13.78mA
-1.023V   -12.73mA   -10.98mA   -14.51mA
-531.8mV  -9.642mA   -8.454mA   -11.24mA
-409.1mV  -7.802mA   -6.854mA   -9.239mA
204.5mV   3.794mA    3.288mA    4.579mA
572.7mV   9.763mA    8.353mA    12mA
900mV     13.58mA    11.21mA    17.32mA
1.227V    15.34mA    12.24mA    20.68mA
1.677V    16.25mA    12.62mA    22.57mA
1.964V    15.02mA    10.36mA    22.79mA
2.373V    9.983mA    4.461mA    17.78mA
2.7V      6.853mA    1.749mA    13.41mA
[Pullup]
-1.35V    11.03mA    8.458mA    14.78mA
-1.145V   11.56mA    9.461mA    14.36mA
-859.1mV  10.61mA    10.14mA    12.86mA
-490.9mV  8.13mA     7.885mA    9.838mA
286.4mV   -4.838mA   -4.502mA   -5.924mA
736.4mV   -11.73mA   -10.62mA   -14.53mA
1.227V    -17.6mA    -14.93mA   -22.38mA
1.636V    -20.69mA   -16.86mA   -26.96mA
1.923V    -21.35mA   -15.82mA   -28.91mA
2.086V    -20.44mA   -14.29mA   -28.55mA
2.291V    -18.58mA   -11.81mA   -26.9mA
2.7V      -13.18mA   -6.641mA   -20.95mA
[GND_clamp]
-1.35V    -159.1mA   -94.77mA   -266.2mA
-1.295V   -137.7mA   -81.77mA   -230.9mA
-1.159V   -87.19mA   -51.56mA   -145.9mA
-1.132V   -77.89mA   -46.14mA   -129.9mA
-1.05V    -52.83mA   -31.83mA   -86.44mA
-1.023V   -45.55mA   -27.75mA   -73.68mA
-940.9mV  -28.44mA   -18.28mA   -42.92mA
-859.1mV  -16.79mA   -11.75mA   -22.47mA
-804.5mV  -11.72mA   -8.559mA   -15.69mA
-722.7mV  -7.324mA   -5.161mA   -10.76mA
-395.5mV  -159.1uA   -161.1uA   -232.4uA
1.35V     1.028nA    146.6nA    745.7pA
[Ramp]
dV/dt_f 0.36654132/0.10332414n 0.30301099/0.14034291n 0.45194561/76.880382p
dV/dt_r 0.36566823/88.21809p  0.31640038/0.11413631n 0.44864091/69.799479p
R_load = 50
[Rising Waveform]
R_fixture = 50
V_fixture = 1.35
V_fixture_min = 1.215
V_fixture_max = 1.485
0s        748.5mV    720.1mV    740.2mV
84.03ps   748.5mV    720.1mV    762.3mV
159.3ps   756.6mV    720.1mV    1.301V
216.2ps   768.4mV    720.1mV    1.418V
259.3ps   937.8mV    720.1mV    1.446V
330.9ps   1.23V      720.1mV    1.467V
436.2ps   1.321V     724.1mV    1.478V
606.7ps   1.34V      1.098V     1.483V
697.2ps   1.342V     1.183V     1.484V
1.667ns   1.348V     1.212V     1.485V
[Rising Waveform]
R_fixture = 50
V_fixture = 0
V_fixture_min = 0
V_fixture_max = 0
100.6ps   0V         0V         0V
185.8ps   0V         0V         549.9mV
263.9ps   0V         0V         685.6mV
290.2ps   97.1mV     0V         700mV
367ps     446.4mV    0V         719.3mV
484.2ps   565.7mV    -6.155mV   729.7mV
565.6ps   580.7mV    0V         732.9mV
692.4ps   587.6mV    365mV      735.5mV
798.7ps   589.8mV    473.1mV    736.5mV
1.767ns   596mV      507.8mV    737.7mV
[Falling Waveform]
R_fixture = 50
V_fixture = 1.35
V_fixture_min = 1.215
V_fixture_max = 1.485
132.3ps   1.349V     1.215V     1.485V
229.7ps   1.349V     1.215V     927.4mV
282.4ps   1.334V     1.215V     816.7mV
330.4ps   1.128V     1.215V     780.2mV
407ps     877.3mV    1.215V     758.6mV
524.8ps   780.1mV    1.215V     747.6mV
596.6ps   766.7mV    1.201V     744.8mV
740.4ps   758.1mV    868.9mV    742mV
856.5ps   755.6mV    761.2mV    740.7mV
1.667ns   749.9mV    723.8mV    739.2mV
[Falling Waveform]
R_fixture = 50
V_fixture = 0
V_fixture_min = 0
V_fixture_max = 0
119.3ps   598.7mV    512.9mV    736.9mV
139.2ps   598.7mV    512.9mV    686.1mV
200.8ps   598.7mV    512.9mV    171.2mV
255.5ps   576.3mV    512.9mV    61.47mV
296.2ps   353.6mV    512.9mV    35.44mV
365.8ps   90.13mV    512.9mV    16.8mV
520.4ps   15.86mV    502.9mV    4.974mV
654.4ps   8.393mV    122.1mV    2.204mV
751.1ps   6.598mV    30.4mV     0V
1.767ns   0V         2.918mV    0V
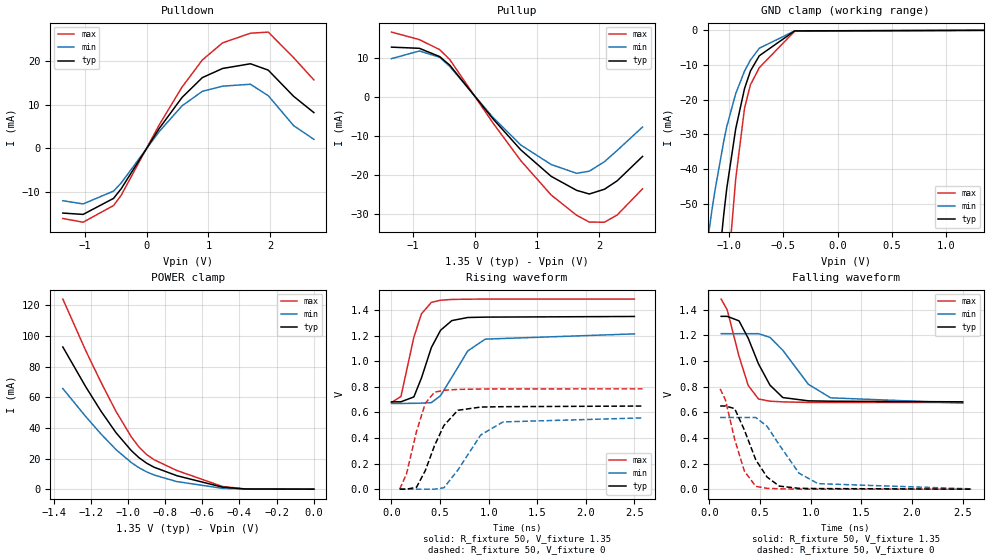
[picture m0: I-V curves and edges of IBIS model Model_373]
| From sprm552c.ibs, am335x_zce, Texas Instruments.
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| Model based on original model for BCSHTLTCSCDVPBFZ_SSDHV
|   Sub model SR10_7MA_10PER_1P35
[model]   Model_373
|[Description]  [1.35V-3-STATE-NOTERM-SR10:7MA, IND, 10%]
|   Fast slew rate (SR[1:0] = "10"), 1.14 * RExt = 0.875 * Iout
|   (I[2:0] = "010"), 7mA nominal with Rext = 50R,ODT off (ODT[1:0]
|   = "00") CMOS mode,Industrial temperature range (-40C to 125C,
|   25C nominal),10% power supply tolerance
|[Input Load]   NOTERM
|[Output Drive] SR10:7MA
|Voltage   1.35V
|Mode   3-STATE
Model_type   3-state
Polarity   Non-Inverting
Enable   Active-Low
Cref =  15pF
Rref =  100.0000M
Vref =  0V
Vmeas =  0.675
C_comp   1.865048p   1.676829p   1.989968p
[Temperature Range]   25   125   -40
[Voltage Range]   1.35   1.215   1.485
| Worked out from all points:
|   slope of the pulldown table from 0 to 0.203 V, typ, clamps not added: 45.3 ohm
|   slope of the pullup table from 0 to 0.203 V, typ, clamps not added: 50.7 ohm
|   GND clamp passes 1 mA (typ) near -0.49 V on its own axis
|   POWER clamp passes 1 mA (typ) near -0.47 V on its own axis
|   rising waveform, R_fixture 50, V_fixture 1.35: 20-80 % time 199ps typ, 270ps min, 147ps max; typ from 0.682 V to 1.35 V
|   rising waveform, R_fixture 50, V_fixture 0: 20-80 % time 217ps typ, 296ps min, 156ps max; typ from 0 V to 0.649 V
|   falling waveform, R_fixture 50, V_fixture 1.35: 20-80 % time 233ps typ, 334ps min, 164ps max; typ from 1.35 V to 0.682 V
|   falling waveform, R_fixture 50, V_fixture 0: 20-80 % time 218ps typ, 292ps min, 156ps max; typ from 0.649 V to 0 V
[POWER_clamp]
-1.35V    92.75mA    65.6mA     124mA
-1.227V   66.81mA    47.39mA    90.41mA
-1.145V   50.92mA    36.05mA    69.79mA
-1.064V   36.83mA    25.81mA    50.69mA
-981.8mV  25.17mA    17.34mA    34.13mA
-940.9mV  20.58mA    14.01mA    27.55mA
-900mV    17mA       11.33mA    22.63mA
-859.1mV  14.3mA     9.219mA    19.19mA
-736.4mV  8.769mA    4.944mA    12.14mA
-490.9mV  1.299mA    528.4uA    1.73mA
-368.2mV  117.2uA    50.88uA    117.5uA
0V        1.028nA    11.64nA    1.384nA
[Pulldown]
-1.35V    -14.84mA   -12.01mA   -16.08mA
-1.023V   -15.15mA   -12.75mA   -16.93mA
-531.8mV  -11.48mA   -9.816mA   -13.12mA
-409.1mV  -9.285mA   -7.958mA   -10.78mA
204.5mV   4.516mA    3.818mA    5.34mA
572.7mV   11.62mA    9.698mA    13.99mA
900mV     16.16mA    13.02mA    20.2mA
1.227V    18.26mA    14.21mA    24.12mA
1.677V    19.34mA    14.65mA    26.33mA
1.964V    17.88mA    12.03mA    26.59mA
2.373V    11.89mA    5.181mA    20.74mA
2.7V      8.16mA     2.032mA    15.64mA
[Pullup]
-1.35V    12.77mA    9.823mA    16.63mA
-900mV    12.47mA    11.79mA    14.7mA
-572.7mV  10.34mA    10.18mA    12.13mA
-409.1mV  8.134mA    7.802mA    9.577mA
286.4mV   -5.6mA     -5.227mA   -6.662mA
736.4mV   -13.58mA   -12.33mA   -16.35mA
1.227V    -20.37mA   -17.34mA   -25.17mA
1.636V    -23.95mA   -19.58mA   -30.33mA
1.841V    -24.89mA   -19.04mA   -32.09mA
2.086V    -23.67mA   -16.6mA    -32.12mA
2.291V    -21.51mA   -13.72mA   -30.27mA
2.7V      -15.26mA   -7.714mA   -23.57mA
[GND_clamp]
-1.35V    -159.1mA   -94.77mA   -266.2mA
-1.295V   -137.7mA   -81.77mA   -230.9mA
-1.159V   -87.19mA   -51.56mA   -145.9mA
-1.132V   -77.89mA   -46.14mA   -129.9mA
-1.05V    -52.83mA   -31.83mA   -86.44mA
-1.023V   -45.55mA   -27.75mA   -73.68mA
-940.9mV  -28.44mA   -18.28mA   -42.92mA
-859.1mV  -16.79mA   -11.75mA   -22.47mA
-804.5mV  -11.72mA   -8.559mA   -15.69mA
-722.7mV  -7.324mA   -5.161mA   -10.76mA
-395.5mV  -159.1uA   -161.1uA   -232.4uA
1.35V     1.028nA    146.6nA    745.7pA
[Ramp]
dV/dt_f 0.40239559/0.23428306n 0.32935897/0.33968759n 0.48597465/0.16408856n
dV/dt_r 0.39167878/0.21849135n 0.33840244/0.30037618n   0.471405/0.15667619n
R_load = 50
[Rising Waveform]
R_fixture = 50
V_fixture = 1.35
V_fixture_min = 1.215
V_fixture_max = 1.485
0s        682mV      669.5mV    677.3mV
97.19ps   682.5mV    669.5mV    723.8mV
230.4ps   720.7mV    670.6mV    1.188V
308.7ps   869.2mV    672.2mV    1.37V
410.3ps   1.106V     675.8mV    1.459V
504.7ps   1.241V     730mV      1.476V
621.5ps   1.317V     874.4mV    1.482V
785.1ps   1.341V     1.08V      1.484V
965.8ps   1.344V     1.172V     1.485V
2.5ns     1.349V     1.213V     1.485V
[Rising Waveform]
R_fixture = 50
V_fixture = 0
V_fixture_min = 0
V_fixture_max = 0
84.42ps   0V         0V         0V
154.7ps   0V         0V         119.1mV
257ps     14.43mV    0V         449.5mV
348ps     144.9mV    0V         671.1mV
441.6ps   337.9mV    0V         757mV
539.1ps   497.1mV    10.84mV    772.5mV
683.1ps   616.3mV    149.1mV    779.2mV
918.6ps   641.4mV    423.7mV    782.4mV
1.148ns   644.3mV    525.3mV    783.3mV
2.584ns   649.4mV    556.8mV    783.5mV
[Falling Waveform]
R_fixture = 50
V_fixture = 1.35
V_fixture_min = 1.215
V_fixture_max = 1.485
115.3ps   1.349V     1.214V     1.484V
175.5ps   1.349V     1.214V     1.399V
291.6ps   1.314V     1.214V     1.038V
382.7ps   1.178V     1.214V     809.6mV
484ps     978mV      1.214V     704mV
597.4ps   812.2mV    1.185V     686.8mV
724.2ps   715.1mV    1.084V     681.4mV
977ps     689.5mV    818.3mV    677.2mV
1.196ns   686.7mV    713.1mV    676.7mV
2.5ns     681.9mV    671.8mV    676.3mV
[Falling Waveform]
R_fixture = 50
V_fixture = 0
V_fixture_min = 0
V_fixture_max = 0
105.6ps   649.3mV    559.4mV    782.7mV
158.1ps   649.3mV    559.4mV    696.3mV
248.8ps   628.9mV    559.4mV    389.4mV
344.3ps   462.6mV    559.4mV    141.5mV
457.2ps   229.1mV    559.4mV    21.68mV
568.7ps   94.47mV    490.5mV    6.686mV
689.4ps   23.78mV    345.8mV    2.912mV
883.6ps   6.545mV    125mV      0V
1.072ns   4.63mV     43mV       0V
2.584ns   0V         2.376mV    0V
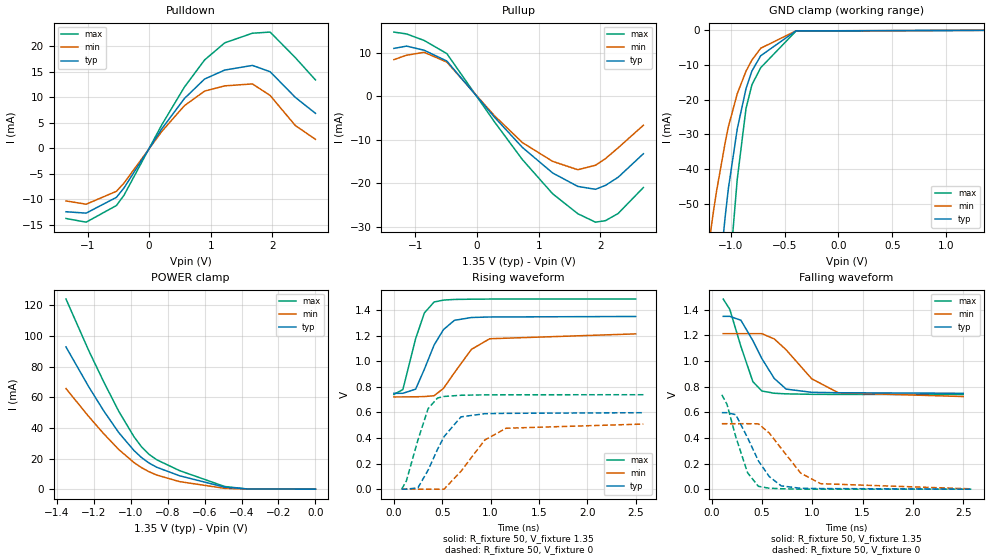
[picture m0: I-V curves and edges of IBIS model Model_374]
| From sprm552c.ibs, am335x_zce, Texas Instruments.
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| Model based on original model for BCSHTLTCSCDVPBFZ_SSDHV
|   Sub model SR10_6MA_10PER_1P35
[model]   Model_374
|[Description]  [1.35V-3-STATE-NOTERM-SR10:6MA, IND, 10%]
|   Fast slew rate (SR[1:0] = "10"), 1.33 * RExt = 0.750 * Iout
|   (I[2:0] = "001"), 6mA nominal with Rext = 50R,ODT off (ODT[1:0]
|   = "00") CMOS mode,Industrial temperature range (-40C to 125C,
|   25C nominal),10% power supply tolerance
|[Input Load]   NOTERM
|[Output Drive] SR10:6MA
|Voltage   1.35V
|Mode   3-STATE
Model_type   3-state
Polarity   Non-Inverting
Enable   Active-Low
Cref =  15pF
Rref =  100.0000M
Vref =  0V
Vmeas =  0.675
C_comp   1.865048p   1.676829p   1.989968p
[Temperature Range]   25   125   -40
[Voltage Range]   1.35   1.215   1.485
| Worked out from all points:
|   slope of the pulldown table from 0 to 0.203 V, typ, clamps not added: 53.9 ohm
|   slope of the pullup table from 0 to 0.203 V, typ, clamps not added: 58.7 ohm
|   GND clamp passes 1 mA (typ) near -0.49 V on its own axis
|   POWER clamp passes 1 mA (typ) near -0.47 V on its own axis
|   rising waveform, R_fixture 50, V_fixture 1.35: 20-80 % time 215ps typ, 292ps min, 156ps max; typ from 0.749 V to 1.35 V
|   rising waveform, R_fixture 50, V_fixture 0: 20-80 % time 240ps typ, 323ps min, 171ps max; typ from 0 V to 0.597 V
|   falling waveform, R_fixture 50, V_fixture 1.35: 20-80 % time 253ps typ, 361ps min, 171ps max; typ from 1.35 V to 0.748 V
|   falling waveform, R_fixture 50, V_fixture 0: 20-80 % time 239ps typ, 317ps min, 169ps max; typ from 0.597 V to 0 V
[POWER_clamp]
-1.35V    92.75mA    65.6mA     124mA
-1.227V   66.81mA    47.39mA    90.41mA
-1.145V   50.92mA    36.05mA    69.79mA
-1.064V   36.83mA    25.81mA    50.69mA
-981.8mV  25.17mA    17.34mA    34.13mA
-940.9mV  20.58mA    14.01mA    27.55mA
-900mV    17mA       11.33mA    22.63mA
-859.1mV  14.3mA     9.219mA    19.19mA
-736.4mV  8.769mA    4.944mA    12.14mA
-490.9mV  1.299mA    528.4uA    1.73mA
-368.2mV  117.2uA    50.88uA    117.5uA
0V        1.028nA    11.64nA    1.384nA
[Pulldown]
-1.35V    -12.46mA   -10.34mA   -13.78mA
-1.023V   -12.73mA   -10.98mA   -14.51mA
-531.8mV  -9.642mA   -8.454mA   -11.24mA
-409.1mV  -7.802mA   -6.854mA   -9.239mA
204.5mV   3.794mA    3.288mA    4.579mA
572.7mV   9.763mA    8.353mA    12mA
900mV     13.58mA    11.21mA    17.32mA
1.227V    15.34mA    12.24mA    20.68mA
1.677V    16.25mA    12.62mA    22.57mA
1.964V    15.02mA    10.36mA    22.79mA
2.373V    9.983mA    4.461mA    17.78mA
2.7V      6.853mA    1.749mA    13.41mA
[Pullup]
-1.35V    11.03mA    8.458mA    14.78mA
-1.145V   11.56mA    9.461mA    14.36mA
-859.1mV  10.61mA    10.14mA    12.86mA
-490.9mV  8.13mA     7.885mA    9.838mA
286.4mV   -4.838mA   -4.502mA   -5.924mA
736.4mV   -11.73mA   -10.62mA   -14.53mA
1.227V    -17.6mA    -14.93mA   -22.38mA
1.636V    -20.69mA   -16.86mA   -26.96mA
1.923V    -21.35mA   -15.82mA   -28.91mA
2.086V    -20.44mA   -14.29mA   -28.55mA
2.291V    -18.58mA   -11.81mA   -26.9mA
2.7V      -13.18mA   -6.641mA   -20.95mA
[GND_clamp]
-1.35V    -159.1mA   -94.77mA   -266.2mA
-1.295V   -137.7mA   -81.77mA   -230.9mA
-1.159V   -87.19mA   -51.56mA   -145.9mA
-1.132V   -77.89mA   -46.14mA   -129.9mA
-1.05V    -52.83mA   -31.83mA   -86.44mA
-1.023V   -45.55mA   -27.75mA   -73.68mA
-940.9mV  -28.44mA   -18.28mA   -42.92mA
-859.1mV  -16.79mA   -11.75mA   -22.47mA
-804.5mV  -11.72mA   -8.559mA   -15.69mA
-722.7mV  -7.324mA   -5.161mA   -10.76mA
-395.5mV  -159.1uA   -161.1uA   -232.4uA
1.35V     1.028nA    146.6nA    745.7pA
[Ramp]
dV/dt_f 0.36248382/0.25427793n 0.29858367/0.36738014n 0.44820716/0.1716457n
dV/dt_r 0.36035291/0.2412168n 0.30925899/0.32909531n 0.44374514/0.17130146n
R_load = 50
[Rising Waveform]
R_fixture = 50
V_fixture = 1.35
V_fixture_min = 1.215
V_fixture_max = 1.485
0s        748.5mV    720.6mV    740.2mV
92.61ps   749mV      720.6mV    778.1mV
224.8ps   781.2mV    721.7mV    1.176V
314.6ps   936.2mV    723.3mV    1.376V
415.2ps   1.125V     729.7mV    1.462V
512.1ps   1.246V     786.9mV    1.477V
625.8ps   1.319V     909.9mV    1.482V
801.6ps   1.341V     1.092V     1.484V
990.5ps   1.345V     1.175V     1.485V
2.5ns     1.349V     1.213V     1.485V
[Rising Waveform]
R_fixture = 50
V_fixture = 0
V_fixture_min = 0
V_fixture_max = 0
80.41ps   0V         0V         0V
128.4ps   0V         0V         64.02mV
248.2ps   10.23mV    0V         383.3mV
354ps     149.4mV    0V         629.7mV
450.9ps   310.8mV    0V         712mV
518.8ps   410.5mV    0V         724.1mV
693.6ps   564.9mV    139.8mV    733.6mV
939.4ps   589.6mV    383.9mV    736.8mV
1.161ns   592.3mV    476.1mV    737.4mV
2.58ns    597.4mV    508.6mV    737.7mV
[Falling Waveform]
R_fixture = 50
V_fixture = 1.35
V_fixture_min = 1.215
V_fixture_max = 1.485
115.2ps   1.349V     1.214V     1.484V
180.2ps   1.349V     1.214V     1.404V
290.5ps   1.319V     1.214V     1.115V
409.5ps   1.16V      1.214V     839.6mV
498.4ps   1.02V      1.214V     766.6mV
622.1ps   864.6mV    1.173V     748.8mV
740.1ps   781.2mV    1.088V     744mV
994.4ps   756.1mV    861.6mV    740.5mV
1.259ns   752.7mV    752.6mV    739.4mV
2.5ns     748.4mV    723mV      739.2mV
[Falling Waveform]
R_fixture = 50
V_fixture = 0
V_fixture_min = 0
V_fixture_max = 0
101.3ps   597.3mV    511mV      736.8mV
152.7ps   597.3mV    511mV      661.7mV
240.2ps   581.2mV    511mV      408mV
356.9ps   401.5mV    511mV      128.3mV
464.9ps   220.8mV    509.8mV    22.01mV
573.1ps   97.83mV    438.4mV    7.313mV
691.5ps   25.6mV     317.9mV    3.227mV
884.7ps   7.013mV    125.6mV    0V
1.083ns   4.804mV    42.72mV    0V
2.58ns    0V         2.458mV    0V
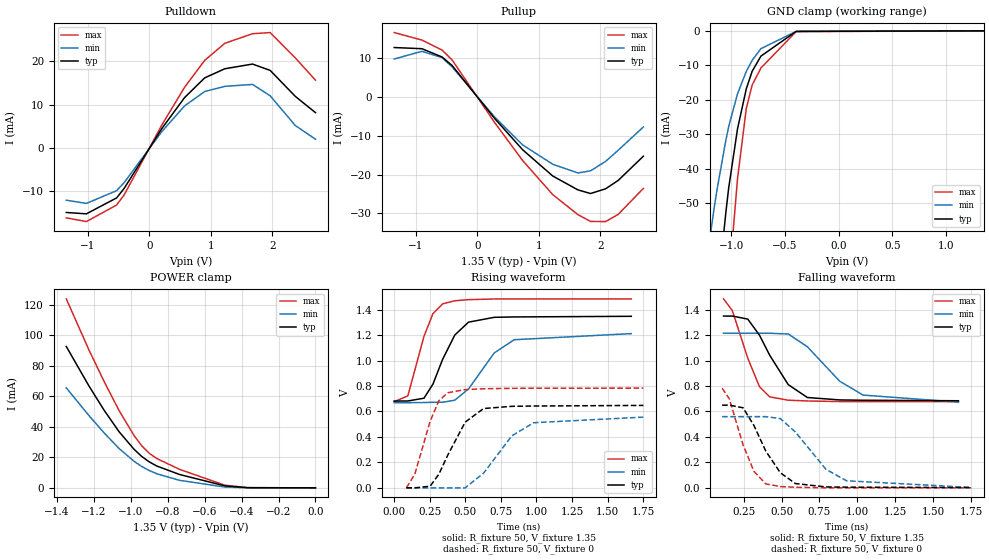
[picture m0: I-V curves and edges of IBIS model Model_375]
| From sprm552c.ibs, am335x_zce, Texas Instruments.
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| Model based on original model for BCSHTLTCSCDVPBFZ_SSDHV
|   Sub model SR01_7MA_10PER_1P35
[model]   Model_375
|[Description]  [1.35V-3-STATE-NOTERM-SR01:7MA, IND, 10%]
|   Slow slew rate (SR[1:0] = "01"), 1.14 * RExt = 0.875 * Iout
|   (I[2:0] = "010"), 7mA nominal with Rext = 50R,ODT off (ODT[1:0]
|   = "00") CMOS mode,Industrial temperature range (-40C to 125C,
|   25C nominal),10% power supply tolerance
|[Input Load]   NOTERM
|[Output Drive] SR01:7MA
|Voltage   1.35V
|Mode   3-STATE
Model_type   3-state
Polarity   Non-Inverting
Enable   Active-Low
Cref =  15pF
Rref =  100.0000M
Vref =  0V
Vmeas =  0.675
C_comp   1.865048p   1.676829p   1.989968p
[Temperature Range]   25   125   -40
[Voltage Range]   1.35   1.215   1.485
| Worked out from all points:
|   slope of the pulldown table from 0 to 0.203 V, typ, clamps not added: 45.3 ohm
|   slope of the pullup table from 0 to 0.203 V, typ, clamps not added: 50.7 ohm
|   GND clamp passes 1 mA (typ) near -0.49 V on its own axis
|   POWER clamp passes 1 mA (typ) near -0.47 V on its own axis
|   rising waveform, R_fixture 50, V_fixture 1.35: 20-80 % time 163ps typ, 222ps min, 122ps max; typ from 0.682 V to 1.35 V
|   rising waveform, R_fixture 50, V_fixture 0: 20-80 % time 176ps typ, 239ps min, 128ps max; typ from 0 V to 0.648 V
|   falling waveform, R_fixture 50, V_fixture 1.35: 20-80 % time 193ps typ, 274ps min, 138ps max; typ from 1.35 V to 0.684 V
|   falling waveform, R_fixture 50, V_fixture 0: 20-80 % time 177ps typ, 241ps min, 130ps max; typ from 0.649 V to 0.002 V
[POWER_clamp]
-1.35V    92.75mA    65.6mA     124mA
-1.227V   66.81mA    47.39mA    90.41mA
-1.145V   50.92mA    36.05mA    69.79mA
-1.064V   36.83mA    25.81mA    50.69mA
-981.8mV  25.17mA    17.34mA    34.13mA
-940.9mV  20.58mA    14.01mA    27.55mA
-900mV    17mA       11.33mA    22.63mA
-859.1mV  14.3mA     9.219mA    19.19mA
-736.4mV  8.769mA    4.944mA    12.14mA
-490.9mV  1.299mA    528.4uA    1.73mA
-368.2mV  117.2uA    50.88uA    117.5uA
0V        1.028nA    11.64nA    1.384nA
[Pulldown]
-1.35V    -14.84mA   -12.01mA   -16.08mA
-1.023V   -15.15mA   -12.75mA   -16.93mA
-531.8mV  -11.48mA   -9.816mA   -13.12mA
-409.1mV  -9.285mA   -7.958mA   -10.78mA
204.5mV   4.516mA    3.818mA    5.34mA
572.7mV   11.62mA    9.698mA    13.99mA
900mV     16.16mA    13.02mA    20.2mA
1.227V    18.26mA    14.21mA    24.12mA
1.677V    19.34mA    14.65mA    26.33mA
1.964V    17.88mA    12.03mA    26.59mA
2.373V    11.89mA    5.181mA    20.74mA
2.7V      8.16mA     2.032mA    15.64mA
[Pullup]
-1.35V    12.77mA    9.823mA    16.63mA
-900mV    12.47mA    11.79mA    14.7mA
-572.7mV  10.34mA    10.18mA    12.13mA
-409.1mV  8.134mA    7.802mA    9.577mA
286.4mV   -5.6mA     -5.227mA   -6.662mA
736.4mV   -13.58mA   -12.33mA   -16.35mA
1.227V    -20.37mA   -17.34mA   -25.17mA
1.636V    -23.95mA   -19.58mA   -30.33mA
1.841V    -24.89mA   -19.04mA   -32.09mA
2.086V    -23.67mA   -16.6mA    -32.12mA
2.291V    -21.51mA   -13.72mA   -30.27mA
2.7V      -15.26mA   -7.714mA   -23.57mA
[GND_clamp]
-1.35V    -159.1mA   -94.77mA   -266.2mA
-1.295V   -137.7mA   -81.77mA   -230.9mA
-1.159V   -87.19mA   -51.56mA   -145.9mA
-1.132V   -77.89mA   -46.14mA   -129.9mA
-1.05V    -52.83mA   -31.83mA   -86.44mA
-1.023V   -45.55mA   -27.75mA   -73.68mA
-940.9mV  -28.44mA   -18.28mA   -42.92mA
-859.1mV  -16.79mA   -11.75mA   -22.47mA
-804.5mV  -11.72mA   -8.559mA   -15.69mA
-722.7mV  -7.324mA   -5.161mA   -10.76mA
-395.5mV  -159.1uA   -161.1uA   -232.4uA
1.35V     1.028nA    146.6nA    745.7pA
[Ramp]
dV/dt_f   0.402471/0.19493865n 0.32947021/0.27993818n 0.48601491/0.13829646n
dV/dt_r 0.39183358/0.17753552n 0.33847358/0.24417883n 0.47152411/0.12847423n
R_load = 50
[Rising Waveform]
R_fixture = 50
V_fixture = 1.35
V_fixture_min = 1.215
V_fixture_max = 1.485
0s        682mV      669.5mV    677.3mV
96.04ps   682.6mV    669.5mV    722.8mV
209.5ps   704.5mV    670.2mV    1.191V
272.5ps   815.2mV    672.5mV    1.369V
340.9ps   1.011V     672.5mV    1.446V
426.2ps   1.201V     688.9mV    1.47V
522.6ps   1.302V     777mV      1.479V
703.2ps   1.34V      1.06V      1.484V
843.5ps   1.343V     1.164V     1.485V
1.667ns   1.348V     1.212V     1.485V
[Rising Waveform]
R_fixture = 50
V_fixture = 0
V_fixture_min = 0
V_fixture_max = 0
85.57ps   0V         0V         0V
144.8ps   0V         0V         106.7mV
252.6ps   12.83mV    0V         522.6mV
313.8ps   106.7mV    0V         684.2mV
377ps     258.2mV    0V         747.8mV
499.3ps   516.8mV    0V         772mV
628.5ps   623.3mV    115.6mV    778.6mV
826.7ps   640.6mV    408.2mV    781.9mV
981.2ps   643mV      511.8mV    782.9mV
1.752ns   647.8mV    555.8mV    783.5mV
[Falling Waveform]
R_fixture = 50
V_fixture = 1.35
V_fixture_min = 1.215
V_fixture_max = 1.485
117.3ps   1.349V     1.214V     1.484V
175.2ps   1.349V     1.214V     1.393V
277.4ps   1.325V     1.214V     1.018V
354.6ps   1.199V     1.214V     794.6mV
422.2ps   1.041V     1.214V     714.5mV
544.4ps   810.5mV    1.208V     688.4mV
670.5ps   709.4mV    1.108V     682.2mV
884.1ps   690.4mV    836.9mV    677.7mV
1.038ns   687.9mV    728.4mV    676.9mV
1.667ns   683.9mV    673.1mV    676.7mV
[Falling Waveform]
R_fixture = 50
V_fixture = 0
V_fixture_min = 0
V_fixture_max = 0
108.1ps   649.3mV    559.2mV    782.6mV
155.3ps   649.3mV    559.2mV    700.2mV
246.3ps   628.8mV    559.2mV    337.5mV
318ps     489.6mV    559.2mV    129.4mV
396.5ps   288.1mV    559.2mV    30.86mV
492.4ps   118.2mV    543.7mV    10.04mV
591.6ps   33.61mV    438.5mV    4.645mV
793.4ps   7.324mV    145.1mV    0V
929ps     5.438mV    55.42mV    0V
1.752ns   2.148mV    3.014mV    0V
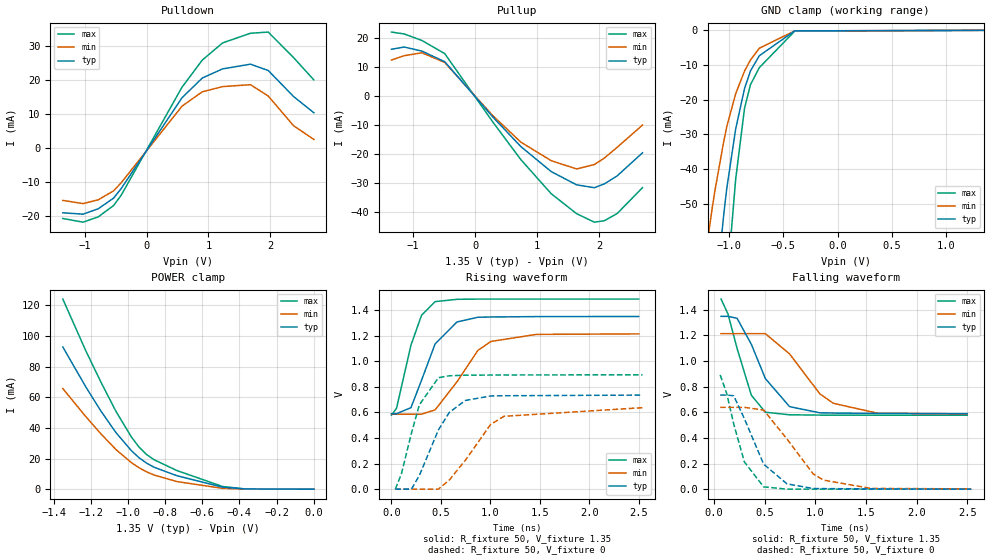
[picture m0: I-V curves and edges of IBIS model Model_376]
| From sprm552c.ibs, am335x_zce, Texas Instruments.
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| Model based on original model for BCSHTLTCSCDVPBFZ_SSDHV
|   Sub model SR11_9MA_10PER_1P35
[model]   Model_376
|[Description]  [1.35V-3-STATE-NOTERM-SR11:9MA, IND, 10%]
|   Slowest slew rate (SR[1:0] = "11"), 0.88 * RExt = 1.125 * Iout
|   (I[2:0] = "100"), 9mA nominal with Rext = 50R,ODT off (ODT[1:0]
|   = "00") CMOS mode,Industrial temperature range (-40C to 125C,
|   25C nominal),10% power supply tolerance
|[Input Load]   NOTERM
|[Output Drive] SR11:9MA
|Voltage   1.35V
|Mode   3-STATE
Model_type   3-state
Polarity   Non-Inverting
Enable   Active-Low
Cref =  15pF
Rref =  100.0000M
Vref =  0V
Vmeas =  0.675
C_comp   1.865048p   1.676829p   1.989968p
[Temperature Range]   25   125   -40
[Voltage Range]   1.35   1.215   1.485
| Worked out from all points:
|   slope of the pulldown table from 0 to 0.203 V, typ, clamps not added: 35.4 ohm
|   slope of the pullup table from 0 to 0.203 V, typ, clamps not added: 39.9 ohm
|   GND clamp passes 1 mA (typ) near -0.49 V on its own axis
|   POWER clamp passes 1 mA (typ) near -0.47 V on its own axis
|   rising waveform, R_fixture 50, V_fixture 1.35: 20-80 % time 235ps typ, 328ps min, 173ps max; typ from 0.589 V to 1.35 V
|   rising waveform, R_fixture 50, V_fixture 0: 20-80 % time 268ps typ, 350ps min, 195ps max; typ from 0 V to 0.735 V
|   falling waveform, R_fixture 50, V_fixture 1.35: 20-80 % time 276ps typ, 378ps min, 195ps max; typ from 1.35 V to 0.589 V
|   falling waveform, R_fixture 50, V_fixture 0: 20-80 % time 253ps typ, 357ps min, 185ps max; typ from 0.735 V to 0 V
[POWER_clamp]
-1.35V    92.75mA    65.6mA     124mA
-1.227V   66.81mA    47.39mA    90.41mA
-1.145V   50.92mA    36.05mA    69.79mA
-1.064V   36.83mA    25.81mA    50.69mA
-981.8mV  25.17mA    17.34mA    34.13mA
-940.9mV  20.58mA    14.01mA    27.55mA
-900mV    17mA       11.33mA    22.63mA
-859.1mV  14.3mA     9.219mA    19.19mA
-736.4mV  8.769mA    4.944mA    12.14mA
-490.9mV  1.299mA    528.4uA    1.73mA
-368.2mV  117.2uA    50.88uA    117.5uA
0V        1.028nA    11.64nA    1.384nA
[Pulldown]
-1.35V    -18.99mA   -15.35mA   -20.67mA
-1.023V   -19.4mA    -16.29mA   -21.76mA
-777.3mV  -17.8mA    -15.15mA   -20.17mA
-531.8mV  -14.68mA   -12.54mA   -16.86mA
-409.1mV  -11.88mA   -10.16mA   -13.84mA
572.7mV   14.87mA    12.39mA    17.98mA
900mV     20.68mA    16.63mA    25.96mA
1.227V    23.37mA    18.15mA    31.01mA
1.677V    24.75mA    18.72mA    33.86mA
1.964V    22.89mA    15.38mA    34.2mA
2.373V    15.22mA    6.623mA    26.68mA
2.7V      10.45mA    2.596mA    20.12mA
[Pullup]
-1.35V    16.26mA    12.55mA    22.18mA
-1.145V   17.03mA    14.04mA    21.54mA
-859.1mV  15.63mA    15.05mA    19.29mA
-490.9mV  11.97mA    11.69mA    14.75mA
286.4mV   -7.124mA   -6.675mA   -8.876mA
736.4mV   -17.28mA   -15.75mA   -21.78mA
1.227V    -25.92mA   -22.15mA   -33.55mA
1.636V    -30.48mA   -25.01mA   -40.42mA
1.923V    -31.47mA   -23.48mA   -43.36mA
2.086V    -30.13mA   -21.22mA   -42.83mA
2.291V    -27.39mA   -17.54mA   -40.37mA
2.7V      -19.43mA   -9.86mA    -31.45mA
[GND_clamp]
-1.35V    -159.1mA   -94.77mA   -266.2mA
-1.295V   -137.7mA   -81.77mA   -230.9mA
-1.159V   -87.19mA   -51.56mA   -145.9mA
-1.132V   -77.89mA   -46.14mA   -129.9mA
-1.05V    -52.83mA   -31.83mA   -86.44mA
-1.023V   -45.55mA   -27.75mA   -73.68mA
-940.9mV  -28.44mA   -18.28mA   -42.92mA
-859.1mV  -16.79mA   -11.75mA   -22.47mA
-804.5mV  -11.72mA   -8.559mA   -15.69mA
-722.7mV  -7.324mA   -5.161mA   -10.76mA
-395.5mV  -159.1uA   -161.1uA   -232.4uA
1.35V     1.028nA    146.6nA    745.7pA
[Ramp]
dV/dt_f 0.45857196/0.27686325n 0.37998388/0.38311359n 0.54603368/0.19591146n
dV/dt_r 0.44359605/0.26972825n 0.38637826/0.35426835n 0.53769905/0.19489056n
R_load = 50
[Rising Waveform]
R_fixture = 50
V_fixture = 1.35
V_fixture_min = 1.215
V_fixture_max = 1.485
0s        589.3mV    585.4mV    578.3mV
51.07ps   589.5mV    585.4mV    632.3mV
196.9ps   636.6mV    585.8mV    1.125V
304.3ps   851.7mV    586mV      1.359V
441.4ps   1.135V     619.7mV    1.465V
662.2ps   1.306V     838.4mV    1.483V
873.9ps   1.343V     1.084V     1.485V
1.006ns   1.345V     1.154V     1.485V
1.465ns   1.348V     1.209V     1.485V
2.5ns     1.349V     1.213V     1.485V
[Rising Waveform]
R_fixture = 50
V_fixture = 0
V_fixture_min = 0
V_fixture_max = 0
38.59ps   0V         0V         0V
99.97ps   0V         0V         118.5mV
201.4ps   0V         0V         436.5mV
281.7ps   106.5mV    0V         658.6mV
474.7ps   463mV      0V         871.1mV
584.3ps   598.9mV    70.98mV    885.7mV
746.9ps   693mV      225.8mV    890.4mV
1.003ns   728.1mV    506mV      891.4mV
1.138ns   729.8mV    569.3mV    892.2mV
2.539ns   734.9mV    636.5mV    893mV
[Falling Waveform]
R_fixture = 50
V_fixture = 1.35
V_fixture_min = 1.215
V_fixture_max = 1.485
67.95ps   1.349V     1.214V     1.484V
135.8ps   1.349V     1.214V     1.369V
226ps     1.334V     1.214V     1.1V
367.1ps   1.131V     1.214V     733.2mV
505.5ps   863.5mV    1.214V     600.9mV
744.4ps   644.4mV    1.056V     580.5mV
1.044ns   595.8mV    744.1mV    578.2mV
1.177ns   594.3mV    670.4mV    577.6mV
1.615ns   591.1mV    592.6mV    577.3mV
2.5ns     589.1mV    587.6mV    577.3mV
[Falling Waveform]
R_fixture = 50
V_fixture = 0
V_fixture_min = 0
V_fixture_max = 0
59.14ps   734.8mV    638.8mV    892.1mV
123.1ps   734.8mV    638.8mV    749.6mV
193.3ps   729mV      638.8mV    507.7mV
298.5ps   550.5mV    638.8mV    212.6mV
488.5ps   195.3mV    617.5mV    18.08mV
719.5ps   41.22mV    391.3mV    0V
977.8ps   5.188mV    119.4mV    0V
1.08ns    4.282mV    70.58mV    0V
1.548ns   2.344mV    5.833mV    0V
2.539ns   0V         2.279mV    0V
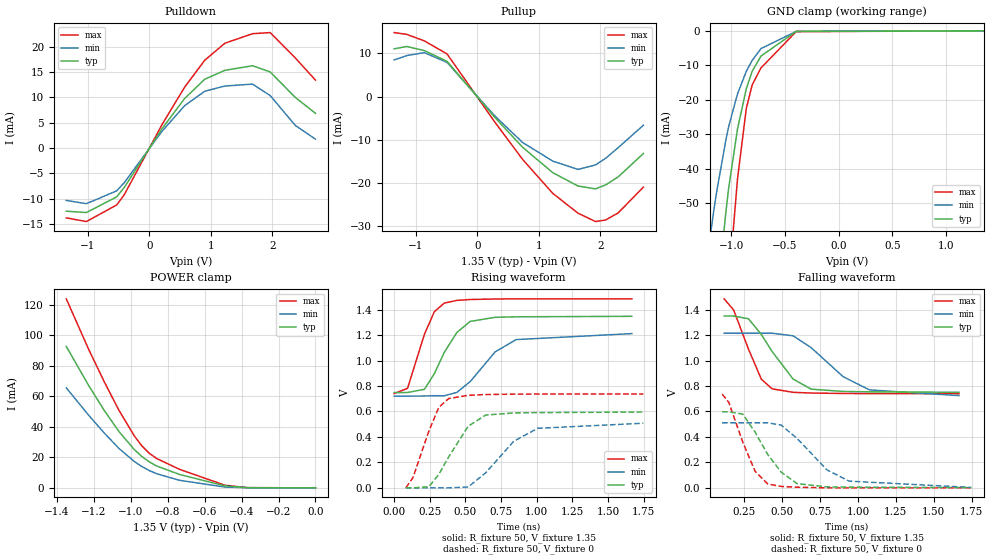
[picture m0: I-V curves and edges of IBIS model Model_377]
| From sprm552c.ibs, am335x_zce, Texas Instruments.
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| Model based on original model for BCSHTLTCSCDVPBFZ_SSDHV
|   Sub model SR01_6MA_10PER_1P35
[model]   Model_377
|[Description]  [1.35V-3-STATE-NOTERM-SR01:6MA, IND, 10%]
|   Slow slew rate (SR[1:0] = "01"), 1.33 * RExt = 0.750 * Iout
|   (I[2:0] = "001"), 6mA nominal with Rext = 50R,ODT off (ODT[1:0]
|   = "00") CMOS mode,Industrial temperature range (-40C to 125C,
|   25C nominal),10% power supply tolerance
|[Input Load]   NOTERM
|[Output Drive] SR01:6MA
|Voltage   1.35V
|Mode   3-STATE
Model_type   3-state
Polarity   Non-Inverting
Enable   Active-Low
Cref =  15pF
Rref =  100.0000M
Vref =  0V
Vmeas =  0.675
C_comp   1.865048p   1.676829p   1.989968p
[Temperature Range]   25   125   -40
[Voltage Range]   1.35   1.215   1.485
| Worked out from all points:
|   slope of the pulldown table from 0 to 0.203 V, typ, clamps not added: 53.9 ohm
|   slope of the pullup table from 0 to 0.203 V, typ, clamps not added: 58.7 ohm
|   GND clamp passes 1 mA (typ) near -0.49 V on its own axis
|   POWER clamp passes 1 mA (typ) near -0.47 V on its own axis
|   rising waveform, R_fixture 50, V_fixture 1.35: 20-80 % time 176ps typ, 240ps min, 129ps max; typ from 0.749 V to 1.35 V
|   rising waveform, R_fixture 50, V_fixture 0: 20-80 % time 193ps typ, 261ps min, 139ps max; typ from 0 V to 0.596 V
|   falling waveform, R_fixture 50, V_fixture 1.35: 20-80 % time 210ps typ, 295ps min, 144ps max; typ from 1.35 V to 0.75 V
|   falling waveform, R_fixture 50, V_fixture 0: 20-80 % time 194ps typ, 260ps min, 140ps max; typ from 0.597 V to 0.002 V
[POWER_clamp]
-1.35V    92.75mA    65.6mA     124mA
-1.227V   66.81mA    47.39mA    90.41mA
-1.145V   50.92mA    36.05mA    69.79mA
-1.064V   36.83mA    25.81mA    50.69mA
-981.8mV  25.17mA    17.34mA    34.13mA
-940.9mV  20.58mA    14.01mA    27.55mA
-900mV    17mA       11.33mA    22.63mA
-859.1mV  14.3mA     9.219mA    19.19mA
-736.4mV  8.769mA    4.944mA    12.14mA
-490.9mV  1.299mA    528.4uA    1.73mA
-368.2mV  117.2uA    50.88uA    117.5uA
0V        1.028nA    11.64nA    1.384nA
[Pulldown]
-1.35V    -12.46mA   -10.34mA   -13.78mA
-1.023V   -12.73mA   -10.98mA   -14.51mA
-531.8mV  -9.642mA   -8.454mA   -11.24mA
-409.1mV  -7.802mA   -6.854mA   -9.239mA
204.5mV   3.794mA    3.288mA    4.579mA
572.7mV   9.763mA    8.353mA    12mA
900mV     13.58mA    11.21mA    17.32mA
1.227V    15.34mA    12.24mA    20.68mA
1.677V    16.25mA    12.62mA    22.57mA
1.964V    15.02mA    10.36mA    22.79mA
2.373V    9.983mA    4.461mA    17.78mA
2.7V      6.853mA    1.749mA    13.41mA
[Pullup]
-1.35V    11.03mA    8.458mA    14.78mA
-1.145V   11.56mA    9.461mA    14.36mA
-859.1mV  10.61mA    10.14mA    12.86mA
-490.9mV  8.13mA     7.885mA    9.838mA
286.4mV   -4.838mA   -4.502mA   -5.924mA
736.4mV   -11.73mA   -10.62mA   -14.53mA
1.227V    -17.6mA    -14.93mA   -22.38mA
1.636V    -20.69mA   -16.86mA   -26.96mA
1.923V    -21.35mA   -15.82mA   -28.91mA
2.086V    -20.44mA   -14.29mA   -28.55mA
2.291V    -18.58mA   -11.81mA   -26.9mA
2.7V      -13.18mA   -6.641mA   -20.95mA
[GND_clamp]
-1.35V    -159.1mA   -94.77mA   -266.2mA
-1.295V   -137.7mA   -81.77mA   -230.9mA
-1.159V   -87.19mA   -51.56mA   -145.9mA
-1.132V   -77.89mA   -46.14mA   -129.9mA
-1.05V    -52.83mA   -31.83mA   -86.44mA
-1.023V   -45.55mA   -27.75mA   -73.68mA
-940.9mV  -28.44mA   -18.28mA   -42.92mA
-859.1mV  -16.79mA   -11.75mA   -22.47mA
-804.5mV  -11.72mA   -8.559mA   -15.69mA
-722.7mV  -7.324mA   -5.161mA   -10.76mA
-395.5mV  -159.1uA   -161.1uA   -232.4uA
1.35V     1.028nA    146.6nA    745.7pA
[Ramp]
dV/dt_f 0.36256436/0.21192431n 0.29865049/0.3012538n 0.44826499/0.14436782n
dV/dt_r 0.36047172/0.19466351n  0.3092745/0.26634956n 0.44384159/0.13962128n
R_load = 50
[Rising Waveform]
R_fixture = 50
V_fixture = 1.35
V_fixture_min = 1.215
V_fixture_max = 1.485
0s        748.5mV    720.7mV    740.2mV
93.79ps   749.2mV    720.7mV    782.5mV
212.1ps   774.4mV    721.7mV    1.207V
281.5ps   897mV      724mV      1.384V
351.5ps   1.065V     723.3mV    1.452V
439.6ps   1.221V     750.2mV    1.473V
533.4ps   1.308V     835.2mV    1.48V
707.8ps   1.34V      1.068V     1.484V
855.4ps   1.344V     1.165V     1.485V
1.667ns   1.348V     1.212V     1.485V
[Rising Waveform]
R_fixture = 50
V_fixture = 0
V_fixture_min = 0
V_fixture_max = 0
81.31ps   0V         0V         0V
131.2ps   0V         0V         79.42mV
243.2ps   8.52mV     0V         446.5mV
313.4ps   106.5mV    0V         633.6mV
382.9ps   244.5mV    0V         702.2mV
519ps     484.5mV    6.741mV    727.2mV
642.2ps   572mV      118.6mV    733.1mV
839.1ps   588.6mV    366.8mV    736.3mV
1.007ns   591.3mV    467.9mV    737.2mV
1.748ns   595.6mV    507.6mV    737.7mV
[Falling Waveform]
R_fixture = 50
V_fixture = 1.35
V_fixture_min = 1.215
V_fixture_max = 1.485
117.2ps   1.349V     1.214V     1.484V
179.8ps   1.349V     1.214V     1.397V
277.2ps   1.328V     1.214V     1.091V
362.3ps   1.205V     1.214V     853.5mV
433.9ps   1.07V      1.214V     777.4mV
572.1ps   854.3mV    1.194V     750.1mV
691.3ps   775mV      1.101V     744.5mV
902.4ps   757mV      872.8mV    741.1mV
1.076ns   754.1mV    769.2mV    739.9mV
1.667ns   750.2mV    724.2mV    739.2mV
[Falling Waveform]
R_fixture = 50
V_fixture = 0
V_fixture_min = 0
V_fixture_max = 0
103.7ps   597.3mV    511mV      736.8mV
147.7ps   597.3mV    511mV      671.5mV
239.6ps   579.1mV    511mV      360.1mV
321.7ps   437.2mV    511mV      129.1mV
404.2ps   262.7mV    511mV      30.54mV
493.2ps   123.5mV    492.4mV    11.14mV
598.3ps   33.16mV    388.4mV    4.946mV
794.8ps   7.808mV    141.6mV    0V
941.7ps   5.606mV    52.58mV    0V
1.748ns   2.191mV    3.117mV    0V
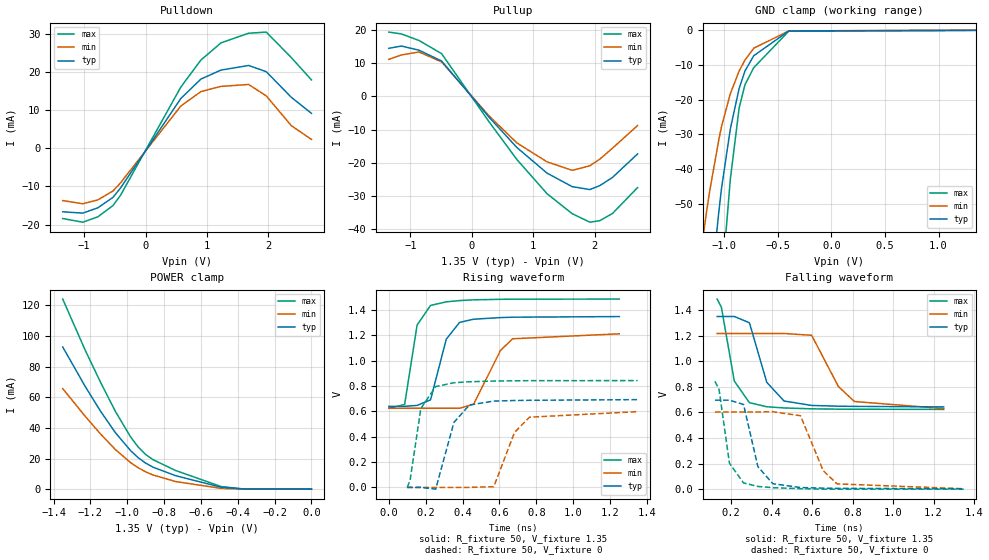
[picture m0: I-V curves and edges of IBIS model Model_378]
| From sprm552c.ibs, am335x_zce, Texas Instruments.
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| Model based on original model for BCSHTLTCSCDVPBFZ_SSDHV
|   Sub model SR00_8MA_10PER_1P35
[model]   Model_378
|[Description]  [1.35V-3-STATE-NOTERM-SR00:8MA, IND, 10%]
|   Fastest slew rate (SR[1:0] = "00"), 1.00 * RExt = 1.000 * Iout
|   (I[2:0] = "011"), 8mA nominal with Rext = 50R,ODT off (ODT[1:0]
|   = "00") CMOS mode,Industrial temperature range (-40C to 125C,
|   25C nominal),10% power supply tolerance
|[Input Load]   NOTERM
|[Output Drive] SR00:8MA
|Voltage   1.35V
|Mode   3-STATE
Model_type   3-state
Polarity   Non-Inverting
Enable   Active-Low
Cref =  15pF
Rref =  100.0000M
Vref =  0V
Vmeas =  0.675
C_comp   1.865048p   1.676829p   1.989968p
[Temperature Range]   25   125   -40
[Voltage Range]   1.35   1.215   1.485
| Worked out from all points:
|   slope of the pulldown table from 0 to 0.203 V, typ, clamps not added: 40.4 ohm
|   slope of the pullup table from 0 to 0.203 V, typ, clamps not added: 44.6 ohm
|   GND clamp passes 1 mA (typ) near -0.49 V on its own axis
|   POWER clamp passes 1 mA (typ) near -0.47 V on its own axis
|   rising waveform, R_fixture 50, V_fixture 1.35: 20-80 % time 76.9ps typ, 121ps min, 54.7ps max; typ from 0.639 V to 1.35 V
|   rising waveform, R_fixture 50, V_fixture 0: 20-80 % time 74.9ps typ, 96.1ps min, 59ps max; typ from 0 V to 0.692 V
|   falling waveform, R_fixture 50, V_fixture 1.35: 20-80 % time 85.8ps typ, 119ps min, 63.5ps max; typ from 1.35 V to 0.643 V
|   falling waveform, R_fixture 50, V_fixture 0: 20-80 % time 61.8ps typ, 87.1ps min, 48.9ps max; typ from 0.695 V to 0.003 V
[POWER_clamp]
-1.35V    92.75mA    65.6mA     124mA
-1.227V   66.81mA    47.39mA    90.41mA
-1.145V   50.92mA    36.05mA    69.79mA
-1.064V   36.83mA    25.81mA    50.69mA
-981.8mV  25.17mA    17.34mA    34.13mA
-940.9mV  20.58mA    14.01mA    27.55mA
-900mV    17mA       11.33mA    22.63mA
-859.1mV  14.3mA     9.219mA    19.19mA
-736.4mV  8.769mA    4.944mA    12.14mA
-490.9mV  1.299mA    528.4uA    1.73mA
-368.2mV  117.2uA    50.88uA    117.5uA
0V        1.028nA    11.64nA    1.384nA
[Pulldown]
-1.35V    -16.62mA   -13.68mA   -18.38mA
-1.023V   -16.97mA   -14.52mA   -19.34mA
-777.3mV  -15.57mA   -13.51mA   -17.93mA
-531.8mV  -12.85mA   -11.18mA   -14.99mA
-409.1mV  -10.4mA    -9.061mA   -12.31mA
572.7mV   13.01mA    11.04mA    15.99mA
900mV     18.1mA     14.83mA    23.08mA
1.227V    20.45mA    16.18mA    27.57mA
1.677V    21.66mA    16.69mA    30.09mA
1.964V    20.03mA    13.7mA     30.39mA
2.373V    13.32mA    5.902mA    23.71mA
2.7V      9.141mA    2.314mA    17.88mA
[Pullup]
-1.35V    14.52mA    11.19mA    19.41mA
-1.145V   15.2mA     12.51mA    18.85mA
-859.1mV  13.95mA    13.41mA    16.88mA
-490.9mV  10.69mA    10.42mA    12.91mA
286.4mV   -6.362mA   -5.951mA   -7.77mA
736.4mV   -15.43mA   -14.05mA   -19.06mA
1.227V    -23.15mA   -19.74mA   -29.36mA
1.636V    -27.22mA   -22.29mA   -35.38mA
1.923V    -28.1mA    -20.92mA   -37.94mA
2.086V    -26.9mA    -18.91mA   -37.48mA
2.291V    -24.45mA   -15.63mA   -35.32mA
2.7V      -17.35mA   -8.787mA   -27.51mA
[GND_clamp]
-1.35V    -159.1mA   -94.77mA   -266.2mA
-1.295V   -137.7mA   -81.77mA   -230.9mA
-1.159V   -87.19mA   -51.56mA   -145.9mA
-1.132V   -77.89mA   -46.14mA   -129.9mA
-1.05V    -52.83mA   -31.83mA   -86.44mA
-1.023V   -45.55mA   -27.75mA   -73.68mA
-940.9mV  -28.44mA   -18.28mA   -42.92mA
-859.1mV  -16.79mA   -11.75mA   -22.47mA
-804.5mV  -11.72mA   -8.559mA   -15.69mA
-722.7mV  -7.324mA   -5.161mA   -10.76mA
-395.5mV  -159.1uA   -161.1uA   -232.4uA
1.35V     1.028nA    146.6nA    745.7pA
[Ramp]
dV/dt_f 0.43332389/87.674662p 0.36122138/0.12270968n 0.52260016/63.732766p
dV/dt_r 0.42635413/76.439114p 0.37335736/99.562782p 0.51351322/59.348137p
R_load = 50
[Rising Waveform]
R_fixture = 50
V_fixture = 1.35
V_fixture_min = 1.215
V_fixture_max = 1.485
0s        639mV      624.1mV    624mV
85.65ps   639mV      624.1mV    653.4mV
153.3ps   646.6mV    624.1mV    1.28V
226.3ps   690.3mV    624.1mV    1.435V
311.3ps   1.168V     624.1mV    1.463V
383.4ps   1.301V     624.1mV    1.473V
459.3ps   1.326V     655mV      1.479V
605.2ps   1.339V     1.079V     1.483V
671.2ps   1.342V     1.172V     1.484V
1.25ns    1.347V     1.211V     1.485V
[Rising Waveform]
R_fixture = 50
V_fixture = 0
V_fixture_min = 0
V_fixture_max = 0
99.37ps   0V         0V         0V
114.8ps   0V         0V         53.22mV
173.7ps   0V         0V         622.5mV
253.8ps   -13.85mV   0V         794.9mV
353.2ps   512.6mV    0V         825.2mV
437.2ps   650mV      0V         833mV
569.1ps   680.6mV    5.461mV    838.4mV
681.7ps   685.2mV    433.8mV    840.7mV
763.3ps   686.9mV    553.6mV    841.5mV
1.349ns   692mV      597.4mV    842.3mV
[Falling Waveform]
R_fixture = 50
V_fixture = 1.35
V_fixture_min = 1.215
V_fixture_max = 1.485
130.6ps   1.349V     1.216V     1.485V
151.4ps   1.349V     1.216V     1.422V
215.4ps   1.349V     1.216V     844.6mV
290.1ps   1.3V       1.216V     675.6mV
375.9ps   834.5mV    1.216V     643.7mV
461.1ps   688.7mV    1.216V     634.5mV
597.6ps   654mV      1.202V     627.6mV
729.7ps   648.2mV    802.2mV    625mV
808.6ps   646.6mV    684.8mV    624.4mV
1.25ns    642.6mV    629.5mV    623.2mV
[Falling Waveform]
R_fixture = 50
V_fixture = 0
V_fixture_min = 0
V_fixture_max = 0
119.8ps   695.2mV    603.4mV    842.7mV
140.2ps   695.2mV    603.4mV    777.4mV
191.2ps   695.2mV    603.4mV    203.6mV
261.1ps   661.6mV    603.4mV    48.7mV
331.8ps   176.7mV    603.4mV    21.2mV
405.5ps   42.71mV    604.9mV    11.52mV
542.6ps   12.87mV    573.4mV    3.857mV
654.8ps   7.905mV    144.1mV    0V
723.2ps   6.577mV    41.22mV    0V
1.349ns   2.783mV    3.413mV    0V
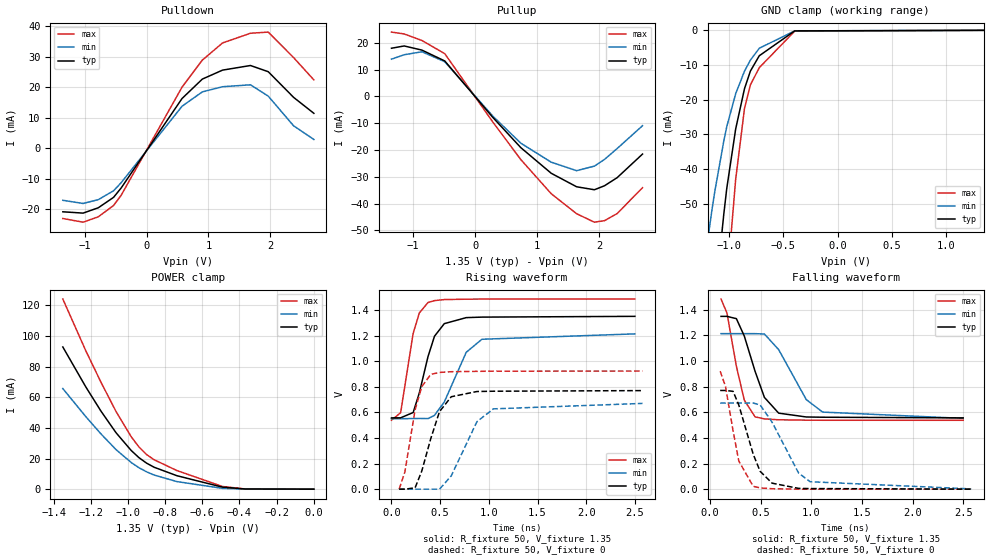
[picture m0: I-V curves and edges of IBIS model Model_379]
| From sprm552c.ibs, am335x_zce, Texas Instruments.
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| Model based on original model for BCSHTLTCSCDVPBFZ_SSDHV
|   Sub model SR10_10MA_10PER_1P35
[model]   Model_379
|[Description]  [1.35V-3-STATE-NOTERM-SR10:10MA, IND, 10%]
|   Fast slew rate (SR[1:0] = "10"), 0.80 * RExt = 1.250 * Iout
|   (I[2:0] = "101"), 10mA nominal with Rext = 50R,ODT off (ODT[1:0]
|   = "00") CMOS mode,Industrial temperature range (-40C to 125C,
|   25C nominal),10% power supply tolerance
|[Input Load]   NOTERM
|[Output Drive] SR10:10MA
|Voltage   1.35V
|Mode   3-STATE
Model_type   3-state
Polarity   Non-Inverting
Enable   Active-Low
Cref =  15pF
Rref =  100.0000M
Vref =  0V
Vmeas =  0.675
C_comp   1.865048p   1.676829p   1.989968p
[Temperature Range]   25   125   -40
[Voltage Range]   1.35   1.215   1.485
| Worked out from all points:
|   slope of the pulldown table from 0 to 0.203 V, typ, clamps not added: 32.4 ohm
|   slope of the pullup table from 0 to 0.203 V, typ, clamps not added: 36 ohm
|   GND clamp passes 1 mA (typ) near -0.49 V on its own axis
|   POWER clamp passes 1 mA (typ) near -0.47 V on its own axis
|   rising waveform, R_fixture 50, V_fixture 1.35: 20-80 % time 167ps typ, 233ps min, 121ps max; typ from 0.557 V to 1.35 V
|   rising waveform, R_fixture 50, V_fixture 0: 20-80 % time 184ps typ, 250ps min, 131ps max; typ from 0 V to 0.77 V
|   falling waveform, R_fixture 50, V_fixture 1.35: 20-80 % time 197ps typ, 280ps min, 136ps max; typ from 1.35 V to 0.556 V
|   falling waveform, R_fixture 50, V_fixture 0: 20-80 % time 183ps typ, 264ps min, 131ps max; typ from 0.771 V to 0 V
[POWER_clamp]
-1.35V    92.75mA    65.6mA     124mA
-1.227V   66.81mA    47.39mA    90.41mA
-1.145V   50.92mA    36.05mA    69.79mA
-1.064V   36.83mA    25.81mA    50.69mA
-981.8mV  25.17mA    17.34mA    34.13mA
-940.9mV  20.58mA    14.01mA    27.55mA
-900mV    17mA       11.33mA    22.63mA
-859.1mV  14.3mA     9.219mA    19.19mA
-736.4mV  8.769mA    4.944mA    12.14mA
-490.9mV  1.299mA    528.4uA    1.73mA
-368.2mV  117.2uA    50.88uA    117.5uA
0V        1.028nA    11.64nA    1.384nA
[Pulldown]
-1.35V    -20.78mA   -17.02mA   -22.97mA
-1.023V   -21.21mA   -18.06mA   -24.18mA
-777.3mV  -19.46mA   -16.8mA    -22.41mA
-531.8mV  -16.06mA   -13.9mA    -18.72mA
-409.1mV  -12.99mA   -11.27mA   -15.38mA
572.7mV   16.26mA    13.73mA    19.97mA
900mV     22.62mA    18.44mA    28.83mA
1.227V    25.56mA    20.13mA    34.45mA
1.677V    27.07mA    20.76mA    37.62mA
1.964V    25.04mA    17.05mA    38mA
2.373V    16.65mA    7.344mA    29.66mA
2.7V      11.43mA    2.879mA    22.36mA
[Pullup]
-1.35V    18mA       13.92mA    24.03mA
-1.145V   18.85mA    15.57mA    23.33mA
-859.1mV  17.3mA     16.68mA    20.89mA
-490.9mV  13.25mA    12.96mA    15.97mA
286.4mV   -7.885mA   -7.399mA   -9.614mA
736.4mV   -19.13mA   -17.46mA   -23.59mA
1.227V    -28.7mA    -24.56mA   -36.34mA
1.636V    -33.74mA   -27.73mA   -43.79mA
1.923V    -34.85mA   -26.03mA   -46.97mA
2.086V    -33.37mA   -23.53mA   -46.41mA
2.291V    -30.33mA   -19.45mA   -43.74mA
2.7V      -21.52mA   -10.93mA   -34.08mA
[GND_clamp]
-1.35V    -159.1mA   -94.77mA   -266.2mA
-1.295V   -137.7mA   -81.77mA   -230.9mA
-1.159V   -87.19mA   -51.56mA   -145.9mA
-1.132V   -77.89mA   -46.14mA   -129.9mA
-1.05V    -52.83mA   -31.83mA   -86.44mA
-1.023V   -45.55mA   -27.75mA   -73.68mA
-940.9mV  -28.44mA   -18.28mA   -42.92mA
-859.1mV  -16.79mA   -11.75mA   -22.47mA
-804.5mV  -11.72mA   -8.559mA   -15.69mA
-722.7mV  -7.324mA   -5.161mA   -10.76mA
-395.5mV  -159.1uA   -161.1uA   -232.4uA
1.35V     1.028nA    146.6nA    745.7pA
[Ramp]
dV/dt_f 0.47822858/0.1983225n 0.40114943/0.28362109n 0.56956102/0.13626473n
dV/dt_r 0.46525718/0.18534703n 0.40688053/0.25365494n 0.55528598/0.13173397n
R_load = 50
[Rising Waveform]
R_fixture = 50
V_fixture = 1.35
V_fixture_min = 1.215
V_fixture_max = 1.485
0s        556.7mV    550.6mV    538.7mV
93.92ps   557.3mV    550.6mV    597.3mV
222.6ps   598.7mV    551.5mV    1.217V
285.8ps   751.2mV    552.4mV    1.376V
374.9ps   1.035V     551.4mV    1.458V
441.9ps   1.195V     577mV      1.473V
542.6ps   1.293V     681.3mV    1.481V
767.5ps   1.34V      1.069V     1.484V
928.9ps   1.344V     1.171V     1.485V
2.5ns     1.35V      1.213V     1.485V
[Rising Waveform]
R_fixture = 50
V_fixture = 0
V_fixture_min = 0
V_fixture_max = 0
78.95ps   0V         0V         0V
137.1ps   0V         0V         133.7mV
242.5ps   10.51mV    0V         618.4mV
310.6ps   140.5mV    0V         800mV
403.2ps   394.1mV    0V         896.5mV
493.2ps   605.7mV    0V         911.7mV
613.9ps   722.1mV    103.9mV    917.6mV
877.7ps   762.8mV    527.4mV    920.3mV
1.047ns   765.1mV    627.3mV    921.8mV
2.579ns   769.9mV    669.8mV    922.4mV
[Falling Waveform]
R_fixture = 50
V_fixture = 1.35
V_fixture_min = 1.215
V_fixture_max = 1.485
110.7ps   1.349V     1.214V     1.484V
169ps     1.349V     1.214V     1.375V
262ps     1.331V     1.214V     959.2mV
340.2ps   1.195V     1.214V     694.4mV
446.5ps   920mV      1.214V     564.4mV
538.8ps   716mV      1.211V     548.6mV
679.4ps   593.4mV    1.089V     541.6mV
952ps     563.5mV    698.8mV    538.7mV
1.113ns   561.6mV    601.7mV    537.9mV
2.5ns     556.5mV    552.6mV    537.7mV
[Falling Waveform]
R_fixture = 50
V_fixture = 0
V_fixture_min = 0
V_fixture_max = 0
101.9ps   770.5mV    672.1mV    921.6mV
155.1ps   770.5mV    672.1mV    800.3mV
229.4ps   763.8mV    672.1mV    454.7mV
286.1ps   656.3mV    672.1mV    219.4mV
428ps     272.7mV    672.1mV    22.24mV
496.1ps   139.7mV    658mV      9.575mV
614.3ps   46.85mV    522.8mV    3.456mV
875.1ps   6.135mV    126.7mV    0V
989.2ps   4.653mV    58.06mV    0V
2.579ns   0V         2.115mV    0V
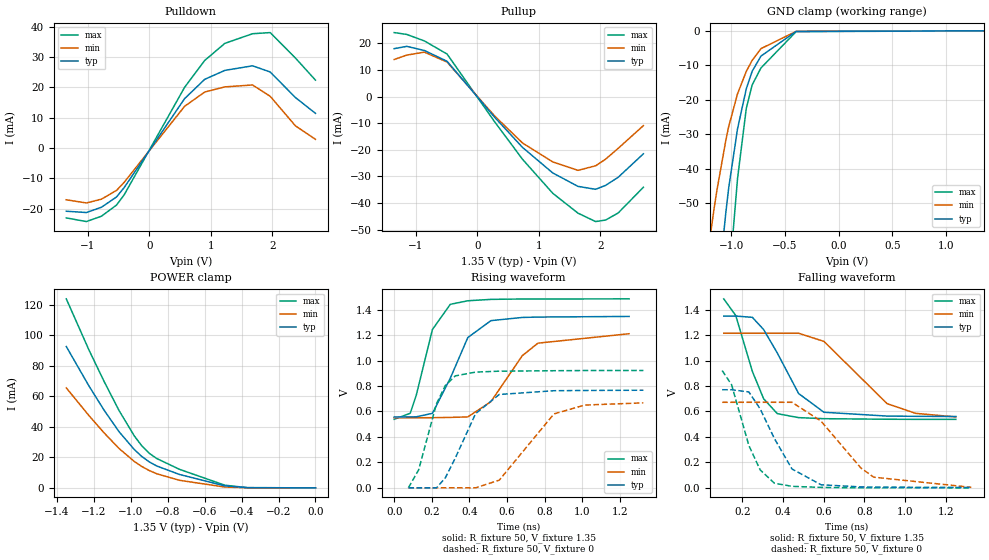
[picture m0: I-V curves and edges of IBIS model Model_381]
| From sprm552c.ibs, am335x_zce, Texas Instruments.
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| Model based on original model for BCSHTLTCSCDVPBFZ_SSDHV
|   Sub model SR01_10MA_10PER_1P35
[model]   Model_381
|[Description]  [1.35V-3-STATE-NOTERM-SR01:10MA, IND, 10%]
|   Slow slew rate (SR[1:0] = "01"), 0.80 * RExt = 1.250 * Iout
|   (I[2:0] = "101"), 10mA nominal with Rext = 50R,ODT off (ODT[1:0]
|   = "00") CMOS mode,Industrial temperature range (-40C to 125C,
|   25C nominal),10% power supply tolerance
|[Input Load]   NOTERM
|[Output Drive] SR01:10MA
|Voltage   1.35V
|Mode   3-STATE
Model_type   3-state
Polarity   Non-Inverting
Enable   Active-Low
Cref =  15pF
Rref =  100.0000M
Vref =  0V
Vmeas =  0.675
C_comp   1.865048p   1.676829p   1.989968p
[Temperature Range]   25   125   -40
[Voltage Range]   1.35   1.215   1.485
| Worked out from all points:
|   slope of the pulldown table from 0 to 0.203 V, typ, clamps not added: 32.4 ohm
|   slope of the pullup table from 0 to 0.203 V, typ, clamps not added: 36 ohm
|   GND clamp passes 1 mA (typ) near -0.49 V on its own axis
|   POWER clamp passes 1 mA (typ) near -0.47 V on its own axis
|   rising waveform, R_fixture 50, V_fixture 1.35: 20-80 % time 137ps typ, 190ps min, 100ps max; typ from 0.557 V to 1.35 V
|   rising waveform, R_fixture 50, V_fixture 0: 20-80 % time 149ps typ, 201ps min, 108ps max; typ from 0 V to 0.767 V
|   falling waveform, R_fixture 50, V_fixture 1.35: 20-80 % time 162ps typ, 231ps min, 114ps max; typ from 1.35 V to 0.56 V
|   falling waveform, R_fixture 50, V_fixture 0: 20-80 % time 150ps typ, 216ps min, 109ps max; typ from 0.77 V to 0.003 V
[POWER_clamp]
-1.35V    92.75mA    65.6mA     124mA
-1.227V   66.81mA    47.39mA    90.41mA
-1.145V   50.92mA    36.05mA    69.79mA
-1.064V   36.83mA    25.81mA    50.69mA
-981.8mV  25.17mA    17.34mA    34.13mA
-940.9mV  20.58mA    14.01mA    27.55mA
-900mV    17mA       11.33mA    22.63mA
-859.1mV  14.3mA     9.219mA    19.19mA
-736.4mV  8.769mA    4.944mA    12.14mA
-490.9mV  1.299mA    528.4uA    1.73mA
-368.2mV  117.2uA    50.88uA    117.5uA
0V        1.028nA    11.64nA    1.384nA
[Pulldown]
-1.35V    -20.78mA   -17.02mA   -22.97mA
-1.023V   -21.21mA   -18.06mA   -24.18mA
-777.3mV  -19.46mA   -16.8mA    -22.41mA
-531.8mV  -16.06mA   -13.9mA    -18.72mA
-409.1mV  -12.99mA   -11.27mA   -15.38mA
572.7mV   16.26mA    13.73mA    19.97mA
900mV     22.62mA    18.44mA    28.83mA
1.227V    25.56mA    20.13mA    34.45mA
1.677V    27.07mA    20.76mA    37.62mA
1.964V    25.04mA    17.05mA    38mA
2.373V    16.65mA    7.344mA    29.66mA
2.7V      11.43mA    2.879mA    22.36mA
[Pullup]
-1.35V    18mA       13.92mA    24.03mA
-1.145V   18.85mA    15.57mA    23.33mA
-859.1mV  17.3mA     16.68mA    20.89mA
-490.9mV  13.25mA    12.96mA    15.97mA
286.4mV   -7.885mA   -7.399mA   -9.614mA
736.4mV   -19.13mA   -17.46mA   -23.59mA
1.227V    -28.7mA    -24.56mA   -36.34mA
1.636V    -33.74mA   -27.73mA   -43.79mA
1.923V    -34.85mA   -26.03mA   -46.97mA
2.086V    -33.37mA   -23.53mA   -46.41mA
2.291V    -30.33mA   -19.45mA   -43.74mA
2.7V      -21.52mA   -10.93mA   -34.08mA
[GND_clamp]
-1.35V    -159.1mA   -94.77mA   -266.2mA
-1.295V   -137.7mA   -81.77mA   -230.9mA
-1.159V   -87.19mA   -51.56mA   -145.9mA
-1.132V   -77.89mA   -46.14mA   -129.9mA
-1.05V    -52.83mA   -31.83mA   -86.44mA
-1.023V   -45.55mA   -27.75mA   -73.68mA
-940.9mV  -28.44mA   -18.28mA   -42.92mA
-859.1mV  -16.79mA   -11.75mA   -22.47mA
-804.5mV  -11.72mA   -8.559mA   -15.69mA
-722.7mV  -7.324mA   -5.161mA   -10.76mA
-395.5mV  -159.1uA   -161.1uA   -232.4uA
1.35V     1.028nA    146.6nA    745.7pA
[Ramp]
dV/dt_f 0.47833478/0.16445791n 0.40108997/0.23708121n 0.56963123/0.11418787n
dV/dt_r 0.46548232/0.15156516n  0.4068429/0.20535845n 0.55548757/0.10786121n
R_load = 50
[Rising Waveform]
R_fixture = 50
V_fixture = 1.35
V_fixture_min = 1.215
V_fixture_max = 1.485
0s        556.7mV    550.6mV    538.7mV
85.29ps   557.3mV    550.6mV    586.1mV
117.7ps   558.3mV    550.6mV    729.4mV
203.3ps   585.5mV    551.4mV    1.244V
298.4ps   861mV      553.5mV    1.442V
391.7ps   1.181V     557.4mV    1.47V
514.7ps   1.314V     677.1mV    1.481V
681.3ps   1.339V     1.038V     1.484V
764.8ps   1.342V     1.137V     1.484V
1.25ns    1.347V     1.211V     1.485V
[Rising Waveform]
R_fixture = 50
V_fixture = 0
V_fixture_min = 0
V_fixture_max = 0
75.52ps   0V         0V         0V
130ps     0V         0V         140.9mV
225.1ps   0V         0V         660.8mV
272.1ps   78.78mV    0V         804.1mV
324.8ps   233.5mV    0V         879.8mV
433.2ps   583.6mV    0V         909.5mV
559.1ps   733.7mV    60.5mV     916.8mV
850.2ps   763.2mV    581.1mV    920.4mV
1.015ns   765.2mV    650.6mV    921.8mV
1.326ns   767.1mV    667.8mV    922.4mV
[Falling Waveform]
R_fixture = 50
V_fixture = 1.35
V_fixture_min = 1.215
V_fixture_max = 1.485
108.3ps   1.349V     1.214V     1.484V
167.3ps   1.349V     1.214V     1.353V
249ps     1.339V     1.214V     914.5mV
304.4ps   1.243V     1.214V     699.8mV
372ps     1.058V     1.214V     582.4mV
476.5ps   740.7mV    1.214V     551.5mV
601.2ps   593.6mV    1.15V      543.1mV
911.9ps   563.5mV    661.2mV    538.7mV
1.052ns   561.8mV    585mV      538mV
1.25ns    560.2mV    556.8mV    537.8mV
[Falling Waveform]
R_fixture = 50
V_fixture = 0
V_fixture_min = 0
V_fixture_max = 0
100.2ps   770.4mV    671.9mV    921.4mV
146.7ps   770.4mV    671.9mV    809.9mV
231.8ps   753mV      671.9mV    332.5mV
287.2ps   620.6mV    671.9mV    141.4mV
357.7ps   386.3mV    671.9mV    36.16mV
443.9ps   148.1mV    671.9mV    11.83mV
587.1ps   24.16mV    523.4mV    3.496mV
782.5ps   7.246mV    156.3mV    0V
846.3ps   5.943mV    83.75mV    0V
1.326ns   2.843mV    3.926mV    0V
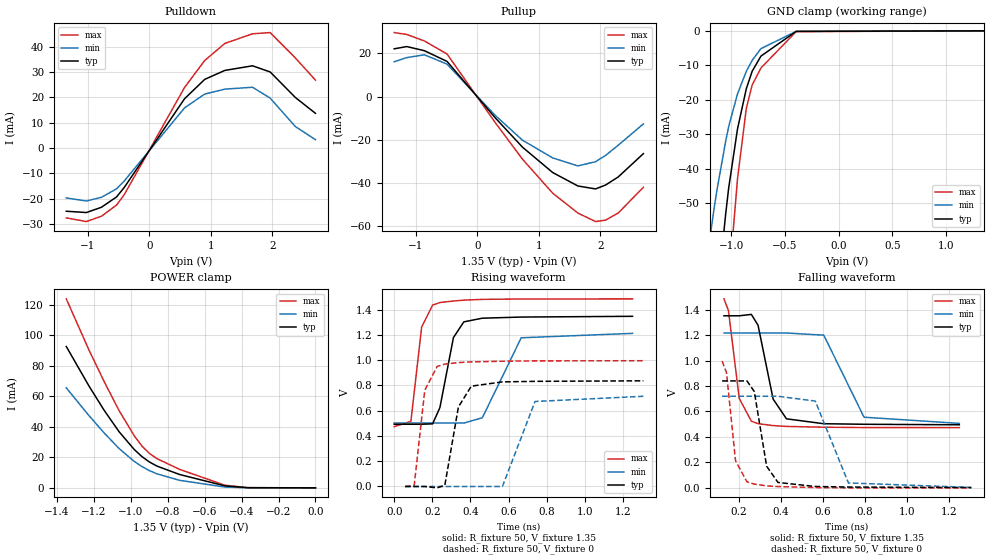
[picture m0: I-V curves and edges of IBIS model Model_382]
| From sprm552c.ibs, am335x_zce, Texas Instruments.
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| Model based on original model for BCSHTLTCSCDVPBFZ_SSDHV
|   Sub model SR00_12MA_10PER_1P35
[model]   Model_382
|[Description]  [1.35V-3-STATE-NOTERM-SR00:12MA, IND, 10%]
|   Fastest slew rate (SR[1:0] = "00"), 0.67 * RExt = 1.500 * Iout
|   (I[2:0] = "111"), 12mA nominal with Rext = 50R,ODT off (ODT[1:0]
|   = "00") CMOS mode,Industrial temperature range (-40C to 125C,
|   25C nominal),10% power supply tolerance
|[Input Load]   NOTERM
|[Output Drive] SR00:12MA
|Voltage   1.35V
|Mode   3-STATE
Model_type   3-state
Polarity   Non-Inverting
Enable   Active-Low
Cref =  15pF
Rref =  100.0000M
Vref =  0V
Vmeas =  0.675
C_comp   1.865048p   1.676829p   1.989968p
[Temperature Range]   25   125   -40
[Voltage Range]   1.35   1.215   1.485
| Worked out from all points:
|   slope of the pulldown table from 0 to 0.203 V, typ, clamps not added: 27 ohm
|   slope of the pullup table from 0 to 0.203 V, typ, clamps not added: 29.4 ohm
|   GND clamp passes 1 mA (typ) near -0.49 V on its own axis
|   POWER clamp passes 1 mA (typ) near -0.47 V on its own axis
|   rising waveform, R_fixture 50, V_fixture 1.35: 20-80 % time 64.6ps typ, 115ps min, 42.4ps max; typ from 0.493 V to 1.35 V
|   rising waveform, R_fixture 50, V_fixture 0: 20-80 % time 58ps typ, 78.3ps min, 44.3ps max; typ from 0 V to 0.836 V
|   falling waveform, R_fixture 50, V_fixture 1.35: 20-80 % time 65.9ps typ, 97.4ps min, 47ps max; typ from 1.35 V to 0.495 V
|   falling waveform, R_fixture 50, V_fixture 0: 20-80 % time 49.3ps typ, 73.1ps min, 37.5ps max; typ from 0.84 V to 0.002 V
[POWER_clamp]
-1.35V    92.75mA    65.6mA     124mA
-1.227V   66.81mA    47.39mA    90.41mA
-1.145V   50.92mA    36.05mA    69.79mA
-1.064V   36.83mA    25.81mA    50.69mA
-981.8mV  25.17mA    17.34mA    34.13mA
-940.9mV  20.58mA    14.01mA    27.55mA
-900mV    17mA       11.33mA    22.63mA
-859.1mV  14.3mA     9.219mA    19.19mA
-736.4mV  8.769mA    4.944mA    12.14mA
-490.9mV  1.299mA    528.4uA    1.73mA
-368.2mV  117.2uA    50.88uA    117.5uA
0V        1.028nA    11.64nA    1.384nA
[Pulldown]
-1.35V    -24.93mA   -19.69mA   -27.57mA
-1.023V   -25.45mA   -20.89mA   -29.01mA
-777.3mV  -23.35mA   -19.43mA   -26.89mA
-531.8mV  -19.26mA   -16.07mA   -22.46mA
-409.1mV  -15.58mA   -13.03mA   -18.44mA
572.7mV   19.5mA     15.88mA    23.95mA
900mV     27.13mA    21.33mA    34.58mA
1.227V    30.67mA    23.28mA    41.33mA
1.677V    32.49mA    24.02mA    45.13mA
1.964V    30.06mA    19.73mA    45.61mA
2.373V    19.99mA    8.498mA    35.6mA
2.7V      13.72mA    3.331mA    26.83mA
[Pullup]
-1.35V    22.07mA    16.11mA    29.58mA
-1.145V   23.11mA    18.01mA    28.71mA
-859.1mV  21.2mA     19.3mA     25.71mA
-490.9mV  16.24mA    14.99mA    19.65mA
286.4mV   -9.66mA    -8.557mA   -11.82mA
736.4mV   -23.44mA   -20.2mA    -29.01mA
1.227V    -35.16mA   -28.4mA    -44.7mA
1.636V    -41.36mA   -32.08mA   -53.88mA
1.923V    -42.72mA   -30.12mA   -57.81mA
2.086V    -40.91mA   -27.22mA   -57.13mA
2.291V    -37.19mA   -22.51mA   -53.86mA
2.7V      -26.4mA    -12.65mA   -41.97mA
[GND_clamp]
-1.35V    -159.1mA   -94.77mA   -266.2mA
-1.295V   -137.7mA   -81.77mA   -230.9mA
-1.159V   -87.19mA   -51.56mA   -145.9mA
-1.132V   -77.89mA   -46.14mA   -129.9mA
-1.05V    -52.83mA   -31.83mA   -86.44mA
-1.023V   -45.55mA   -27.75mA   -73.68mA
-940.9mV  -28.44mA   -18.28mA   -42.92mA
-859.1mV  -16.79mA   -11.75mA   -22.47mA
-804.5mV  -11.72mA   -8.559mA   -15.69mA
-722.7mV  -7.324mA   -5.161mA   -10.76mA
-395.5mV  -159.1uA   -161.1uA   -232.4uA
1.35V     1.028nA    146.6nA    745.7pA
[Ramp]
dV/dt_f 0.52274161/66.993952p 0.43505737/99.613608p 0.61459134/47.309133p
dV/dt_r 0.51739462/59.403586p 0.44824274/81.422369p 0.60839857/44.655116p
R_load = 50
[Rising Waveform]
R_fixture = 50
V_fixture = 1.35
V_fixture_min = 1.215
V_fixture_max = 1.485
0s        492.7mV    501.9mV    473.6mV
87.51ps   492.7mV    501.9mV    515.1mV
144ps     492.7mV    501.9mV    1.262V
201.6ps   496mV      501.9mV    1.436V
239.7ps   624.3mV    501.9mV    1.456V
310.8ps   1.179V     501.9mV    1.468V
365.2ps   1.303V     501.9mV    1.475V
462.3ps   1.332V     544mV      1.481V
666.3ps   1.341V     1.177V     1.484V
1.25ns    1.347V     1.212V     1.485V
[Rising Waveform]
R_fixture = 50
V_fixture = 0
V_fixture_min = 0
V_fixture_max = 0
57.29ps   0V         0V         0V
104.9ps   0V         0V         8.777mV
160.4ps   0V         0V         761.8mV
225.5ps   -10.67mV   0V         950.3mV
265.7ps   10.47mV    0V         968.8mV
336.8ps   629.5mV    0V         980.8mV
404.5ps   794.2mV    0V         986.3mV
567.7ps   827.9mV    0V         991.3mV
738.6ps   832.2mV    672.8mV    994.1mV
1.307ns   836.4mV    714.1mV    995.4mV
[Falling Waveform]
R_fixture = 50
V_fixture = 1.35
V_fixture_min = 1.215
V_fixture_max = 1.485
129.3ps   1.351V     1.216V     1.484V
150.6ps   1.351V     1.216V     1.392V
202ps     1.351V     1.216V     702.6mV
259.8ps   1.362V     1.216V     523.2mV
291.6ps   1.277V     1.216V     504mV
363.4ps   697.2mV    1.216V     488.9mV
426.9ps   542.1mV    1.216V     482.4mV
604.6ps   503.5mV    1.199V     476mV
796.3ps   499.3mV    554.6mV    473.5mV
1.25ns    495.2mV    506.2mV    472.7mV
[Falling Waveform]
R_fixture = 50
V_fixture = 0
V_fixture_min = 0
V_fixture_max = 0
120.5ps   839.6mV    719.2mV    996.1mV
141.5ps   839.6mV    719.2mV    903.6mV
184.3ps   839.6mV    719.2mV    213.3mV
238.8ps   839.6mV    719.2mV    47.48mV
273.6ps   756.7mV    719.2mV    29.36mV
332.6ps   169.4mV    719.2mV    15.46mV
386.6ps   42.4mV     719.2mV    9.994mV
564ps     10.61mV    681.3mV    2.428mV
721.9ps   6.457mV    38.53mV    0V
1.307ns   2.474mV    3.289mV    0V
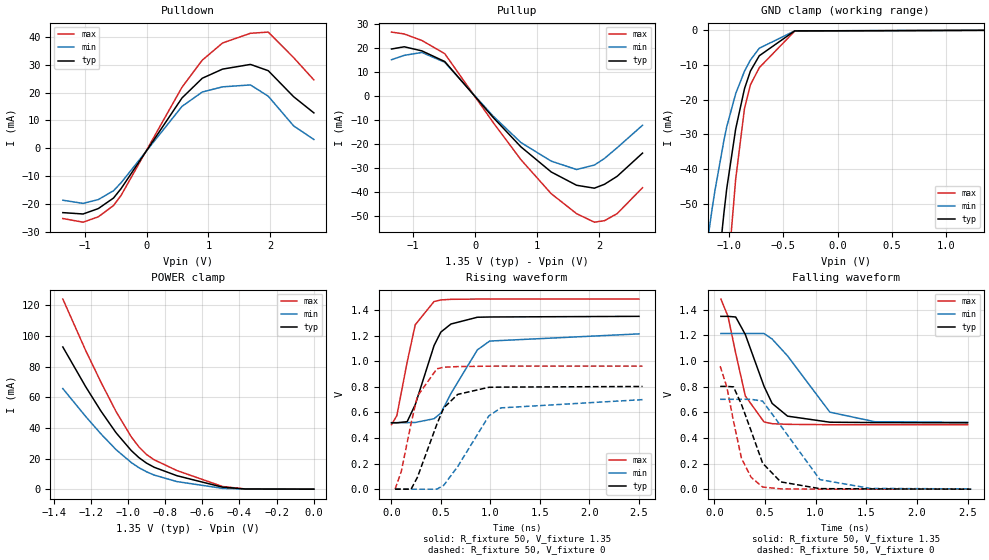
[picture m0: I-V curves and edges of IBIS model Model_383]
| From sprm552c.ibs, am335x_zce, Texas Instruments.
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| Model based on original model for BCSHTLTCSCDVPBFZ_SSDHV
|   Sub model SR11_11MA_10PER_1P35
[model]   Model_383
|[Description]  [1.35V-3-STATE-NOTERM-SR11:11MA, IND, 10%]
|   Slowest slew rate (SR[1:0] = "11"), 0.73 * RExt = 1.325 * Iout
|   (I[2:0] = "110"), 11mA nominal with Rext = 50R,ODT off (ODT[1:0]
|   = "00") CMOS mode,Industrial temperature range (-40C to 125C,
|   25C nominal),10% power supply tolerance
|[Input Load]   NOTERM
|[Output Drive] SR11:11MA
|Voltage   1.35V
|Mode   3-STATE
Model_type   3-state
Polarity   Non-Inverting
Enable   Active-Low
Cref =  15pF
Rref =  100.0000M
Vref =  0V
Vmeas =  0.675
C_comp   1.865048p   1.676829p   1.989968p
[Temperature Range]   25   125   -40
[Voltage Range]   1.35   1.215   1.485
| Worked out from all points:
|   slope of the pulldown table from 0 to 0.203 V, typ, clamps not added: 29.1 ohm
|   slope of the pullup table from 0 to 0.203 V, typ, clamps not added: 32.8 ohm
|   GND clamp passes 1 mA (typ) near -0.49 V on its own axis
|   POWER clamp passes 1 mA (typ) near -0.47 V on its own axis
|   rising waveform, R_fixture 50, V_fixture 1.35: 20-80 % time 214ps typ, 311ps min, 152ps max; typ from 0.518 V to 1.35 V
|   rising waveform, R_fixture 50, V_fixture 0: 20-80 % time 233ps typ, 331ps min, 169ps max; typ from 0 V to 0.802 V
|   falling waveform, R_fixture 50, V_fixture 1.35: 20-80 % time 240ps typ, 350ps min, 169ps max; typ from 1.35 V to 0.518 V
|   falling waveform, R_fixture 50, V_fixture 0: 20-80 % time 225ps typ, 350ps min, 161ps max; typ from 0.802 V to 0 V
[POWER_clamp]
-1.35V    92.75mA    65.6mA     124mA
-1.227V   66.81mA    47.39mA    90.41mA
-1.145V   50.92mA    36.05mA    69.79mA
-1.064V   36.83mA    25.81mA    50.69mA
-981.8mV  25.17mA    17.34mA    34.13mA
-940.9mV  20.58mA    14.01mA    27.55mA
-900mV    17mA       11.33mA    22.63mA
-859.1mV  14.3mA     9.219mA    19.19mA
-736.4mV  8.769mA    4.944mA    12.14mA
-490.9mV  1.299mA    528.4uA    1.73mA
-368.2mV  117.2uA    50.88uA    117.5uA
0V        1.028nA    11.64nA    1.384nA
[Pulldown]
-1.35V    -23.15mA   -18.68mA   -25.27mA
-1.023V   -23.64mA   -19.83mA   -26.59mA
-777.3mV  -21.69mA   -18.45mA   -24.65mA
-531.8mV  -17.89mA   -15.26mA   -20.59mA
-409.1mV  -14.47mA   -12.37mA   -16.91mA
572.7mV   18.11mA    15.07mA    21.96mA
900mV     25.2mA     20.25mA    31.71mA
1.227V    28.48mA    22.1mA     37.89mA
1.677V    30.17mA    22.79mA    41.37mA
1.964V    27.91mA    18.73mA    41.8mA
2.373V    18.56mA    8.065mA    32.63mA
2.7V      12.74mA    3.161mA    24.59mA
[Pullup]
-1.35V    19.75mA    15.29mA    26.8mA
-1.145V   20.68mA    17.1mA     26.02mA
-859.1mV  18.97mA    18.32mA    23.3mA
-490.9mV  14.53mA    14.23mA    17.81mA
286.4mV   -8.646mA   -8.123mA   -10.72mA
736.4mV   -20.97mA   -19.17mA   -26.3mA
1.227V    -31.47mA   -26.96mA   -40.52mA
1.636V    -37.01mA   -30.45mA   -48.83mA
1.923V    -38.22mA   -28.59mA   -52.39mA
2.086V    -36.6mA    -25.84mA   -51.77mA
2.291V    -33.27mA   -21.36mA   -48.8mA
2.7V      -23.61mA   -12.01mA   -38.03mA
[GND_clamp]
-1.35V    -159.1mA   -94.77mA   -266.2mA
-1.295V   -137.7mA   -81.77mA   -230.9mA
-1.159V   -87.19mA   -51.56mA   -145.9mA
-1.132V   -77.89mA   -46.14mA   -129.9mA
-1.05V    -52.83mA   -31.83mA   -86.44mA
-1.023V   -45.55mA   -27.75mA   -73.68mA
-940.9mV  -28.44mA   -18.28mA   -42.92mA
-859.1mV  -16.79mA   -11.75mA   -22.47mA
-804.5mV  -11.72mA   -8.559mA   -15.69mA
-722.7mV  -7.324mA   -5.161mA   -10.76mA
-395.5mV  -159.1uA   -161.1uA   -232.4uA
1.35V     1.028nA    146.6nA    745.7pA
[Ramp]
dV/dt_f 0.50139147/0.2411626n 0.41980799/0.35389781n 0.59075216/0.16933262n
dV/dt_r 0.48436539/0.23460998n 0.42459361/0.33570501n 0.57900072/0.16974882n
R_load = 50
[Rising Waveform]
R_fixture = 50
V_fixture = 1.35
V_fixture_min = 1.215
V_fixture_max = 1.485
0s        518.3mV    519.6mV    504.1mV
54.17ps   518.3mV    519.6mV    574.5mV
158.2ps   527.3mV    519.6mV    992.4mV
240.3ps   660.7mV    521.2mV    1.285V
430.2ps   1.122V     550.5mV    1.466V
498.4ps   1.227V     594.1mV    1.478V
600.3ps   1.29V      747mV      1.483V
867.3ps   1.343V     1.088V     1.485V
992ps     1.345V     1.157V     1.485V
2.5ns     1.35V      1.213V     1.485V
[Rising Waveform]
R_fixture = 50
V_fixture = 0
V_fixture_min = 0
V_fixture_max = 0
36.32ps   0V         0V         0V
99.14ps   0V         0V         138.7mV
198ps     0V         0V         514.2mV
261.7ps   92.37mV    0V         726.1mV
458.4ps   507.3mV    0V         940.3mV
528.2ps   635.4mV    30.27mV    952.6mV
669.2ps   740.4mV    177.2mV    957.6mV
983.3ps   795.7mV    572.1mV    960.9mV
1.106ns   797.2mV    635.1mV    961.2mV
2.536ns   802.2mV    699.4mV    961.4mV
[Falling Waveform]
R_fixture = 50
V_fixture = 1.35
V_fixture_min = 1.215
V_fixture_max = 1.485
65.41ps   1.349V     1.215V     1.484V
135.3ps   1.349V     1.215V     1.349V
211.6ps   1.344V     1.215V     1.061V
306.4ps   1.207V     1.215V     727.8mV
490.7ps   803.8mV    1.215V     525mV
571ps     669.4mV    1.172V     511.1mV
723.7ps   569.9mV    1.04V      506.1mV
1.141ns   522.7mV    601mV      503.2mV
1.585ns   519.9mV    526.4mV    503.1mV
2.5ns     518.1mV    521.5mV    503.1mV
[Falling Waveform]
R_fixture = 50
V_fixture = 0
V_fixture_min = 0
V_fixture_max = 0
57.99ps   802.1mV    701.5mV    960.5mV
123.8ps   802.1mV    701.5mV    797.9mV
189.5ps   798.7mV    701.5mV    531.4mV
268.5ps   661.3mV    701.5mV    240.7mV
363.3ps   456.1mV    701.5mV    93.01mV
477.1ps   202.8mV    687.1mV    16.72mV
655.4ps   56.86mV    495.7mV    2.37mV
1.043ns   4.121mV    74.3mV     0V
1.543ns   2.113mV    5.628mV    0V
2.536ns   0V         2.111mV    0V
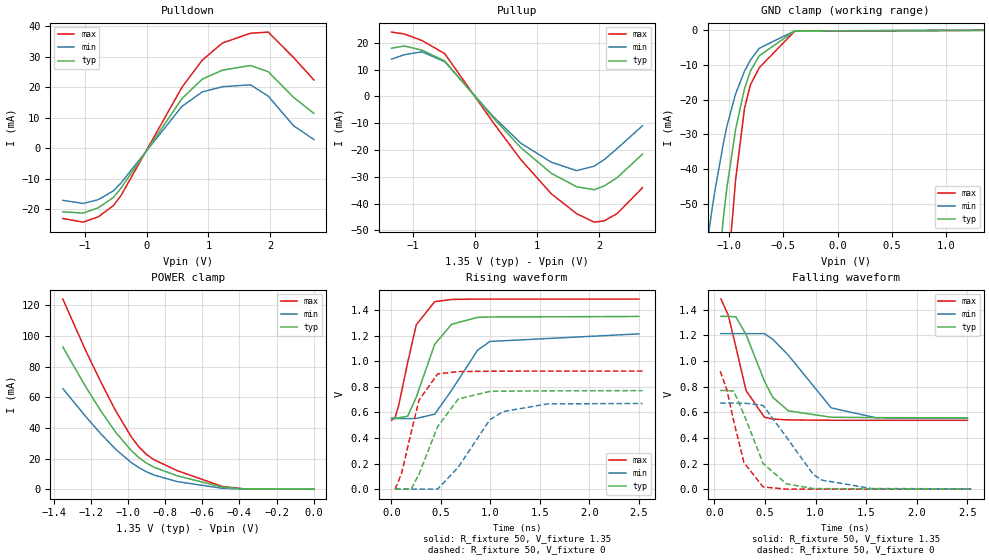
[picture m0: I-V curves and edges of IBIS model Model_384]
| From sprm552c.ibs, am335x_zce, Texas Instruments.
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| Model based on original model for BCSHTLTCSCDVPBFZ_SSDHV
|   Sub model SR11_10MA_10PER_1P35
[model]   Model_384
|[Description]  [1.35V-3-STATE-NOTERM-SR11:10MA, IND, 10%]
|   Slowest slew rate (SR[1:0] = "11"), 0.80 * RExt = 1.250 * Iout
|   (I[2:0] = "101"), 10mA nominal with Rext = 50R,ODT off (ODT[1:0]
|   = "00") CMOS mode,Industrial temperature range (-40C to 125C,
|   25C nominal),10% power supply tolerance
|[Input Load]   NOTERM
|[Output Drive] SR11:10MA
|Voltage   1.35V
|Mode   3-STATE
Model_type   3-state
Polarity   Non-Inverting
Enable   Active-Low
Cref =  15pF
Rref =  100.0000M
Vref =  0V
Vmeas =  0.675
C_comp   1.865048p   1.676829p   1.989968p
[Temperature Range]   25   125   -40
[Voltage Range]   1.35   1.215   1.485
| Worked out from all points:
|   slope of the pulldown table from 0 to 0.203 V, typ, clamps not added: 32.4 ohm
|   slope of the pullup table from 0 to 0.203 V, typ, clamps not added: 36 ohm
|   GND clamp passes 1 mA (typ) near -0.49 V on its own axis
|   POWER clamp passes 1 mA (typ) near -0.47 V on its own axis
|   rising waveform, R_fixture 50, V_fixture 1.35: 20-80 % time 226ps typ, 321ps min, 161ps max; typ from 0.557 V to 1.35 V
|   rising waveform, R_fixture 50, V_fixture 0: 20-80 % time 253ps typ, 343ps min, 180ps max; typ from 0 V to 0.77 V
|   falling waveform, R_fixture 50, V_fixture 1.35: 20-80 % time 257ps typ, 365ps min, 181ps max; typ from 1.35 V to 0.557 V
|   falling waveform, R_fixture 50, V_fixture 0: 20-80 % time 242ps typ, 358ps min, 170ps max; typ from 0.77 V to 0 V
[POWER_clamp]
-1.35V    92.75mA    65.6mA     124mA
-1.227V   66.81mA    47.39mA    90.41mA
-1.145V   50.92mA    36.05mA    69.79mA
-1.064V   36.83mA    25.81mA    50.69mA
-981.8mV  25.17mA    17.34mA    34.13mA
-940.9mV  20.58mA    14.01mA    27.55mA
-900mV    17mA       11.33mA    22.63mA
-859.1mV  14.3mA     9.219mA    19.19mA
-736.4mV  8.769mA    4.944mA    12.14mA
-490.9mV  1.299mA    528.4uA    1.73mA
-368.2mV  117.2uA    50.88uA    117.5uA
0V        1.028nA    11.64nA    1.384nA
[Pulldown]
-1.35V    -20.78mA   -17.02mA   -22.97mA
-1.023V   -21.21mA   -18.06mA   -24.18mA
-777.3mV  -19.46mA   -16.8mA    -22.41mA
-531.8mV  -16.06mA   -13.9mA    -18.72mA
-409.1mV  -12.99mA   -11.27mA   -15.38mA
572.7mV   16.26mA    13.73mA    19.97mA
900mV     22.62mA    18.44mA    28.83mA
1.227V    25.56mA    20.13mA    34.45mA
1.677V    27.07mA    20.76mA    37.62mA
1.964V    25.04mA    17.05mA    38mA
2.373V    16.65mA    7.344mA    29.66mA
2.7V      11.43mA    2.879mA    22.36mA
[Pullup]
-1.35V    18mA       13.92mA    24.03mA
-1.145V   18.85mA    15.57mA    23.33mA
-859.1mV  17.3mA     16.68mA    20.89mA
-490.9mV  13.25mA    12.96mA    15.97mA
286.4mV   -7.885mA   -7.399mA   -9.614mA
736.4mV   -19.13mA   -17.46mA   -23.59mA
1.227V    -28.7mA    -24.56mA   -36.34mA
1.636V    -33.74mA   -27.73mA   -43.79mA
1.923V    -34.85mA   -26.03mA   -46.97mA
2.086V    -33.37mA   -23.53mA   -46.41mA
2.291V    -30.33mA   -19.45mA   -43.74mA
2.7V      -21.52mA   -10.93mA   -34.08mA
[GND_clamp]
-1.35V    -159.1mA   -94.77mA   -266.2mA
-1.295V   -137.7mA   -81.77mA   -230.9mA
-1.159V   -87.19mA   -51.56mA   -145.9mA
-1.132V   -77.89mA   -46.14mA   -129.9mA
-1.05V    -52.83mA   -31.83mA   -86.44mA
-1.023V   -45.55mA   -27.75mA   -73.68mA
-940.9mV  -28.44mA   -18.28mA   -42.92mA
-859.1mV  -16.79mA   -11.75mA   -22.47mA
-804.5mV  -11.72mA   -8.559mA   -15.69mA
-722.7mV  -7.324mA   -5.161mA   -10.76mA
-395.5mV  -159.1uA   -161.1uA   -232.4uA
1.35V     1.028nA    146.6nA    745.7pA
[Ramp]
dV/dt_f  0.4783578/0.25860167n 0.40113998/0.3701656n 0.56977191/0.18121281n
dV/dt_r 0.46524053/0.25457445n 0.40668279/0.34809956n 0.55527559/0.18078683n
R_load = 50
[Rising Waveform]
R_fixture = 50
V_fixture = 1.35
V_fixture_min = 1.215
V_fixture_max = 1.485
0s        556.7mV    550.6mV    538.7mV
34.89ps   556.7mV    550.6mV    556.5mV
72.56ps   557.5mV    550.6mV    654mV
163.5ps   569.9mV    550.6mV    989.1mV
250.6ps   719.5mV    552.3mV    1.284V
436.7ps   1.132V     585.8mV    1.465V
607.8ps   1.288V     772.5mV    1.482V
869.5ps   1.342V     1.085V     1.485V
995ps     1.345V     1.154V     1.485V
2.5ns     1.349V     1.213V     1.485V
[Rising Waveform]
R_fixture = 50
V_fixture = 0
V_fixture_min = 0
V_fixture_max = 0
37.41ps   0V         0V         0V
101.8ps   0V         0V         123mV
198.5ps   0V         0V         442.6mV
278.2ps   117.1mV    0V         694.6mV
466.1ps   488.1mV    0V         900.2mV
675.5ps   705.1mV    171.8mV    918.7mV
994.3ps   763.8mV    542.6mV    921.2mV
1.127ns   765.4mV    605.7mV    922mV
1.575ns   768.2mV    665.8mV    922.4mV
2.537ns   769.9mV    669.7mV    922.4mV
[Falling Waveform]
R_fixture = 50
V_fixture = 1.35
V_fixture_min = 1.215
V_fixture_max = 1.485
66.09ps   1.349V     1.214V     1.484V
138.5ps   1.349V     1.214V     1.358V
213ps     1.345V     1.214V     1.112V
313.9ps   1.207V     1.214V     770.1mV
495.4ps   844.1mV    1.214V     561.3mV
577.4ps   717.1mV    1.17V      546.9mV
731.5ps   611.5mV    1.046V     540.8mV
1.155ns   561.5mV    634.5mV    537.9mV
1.596ns   558.4mV    557.7mV    537.7mV
2.5ns     556.5mV    552.7mV    537.7mV
[Falling Waveform]
R_fixture = 50
V_fixture = 0
V_fixture_min = 0
V_fixture_max = 0
58.3ps    770.3mV    671.9mV    921.5mV
123.8ps   770.3mV    671.9mV    778.7mV
192ps     764.8mV    671.9mV    531.8mV
293.8ps   582mV      671.9mV    207.1mV
482.4ps   200.6mV    653.5mV    17.43mV
713.3ps   41.02mV    405.4mV    0V
977.1ps   5.112mV    115.4mV    0V
1.066ns   4.241mV    70.23mV    0V
1.552ns   2.24mV     5.105mV    0V
2.537ns   0V         2.205mV    0V
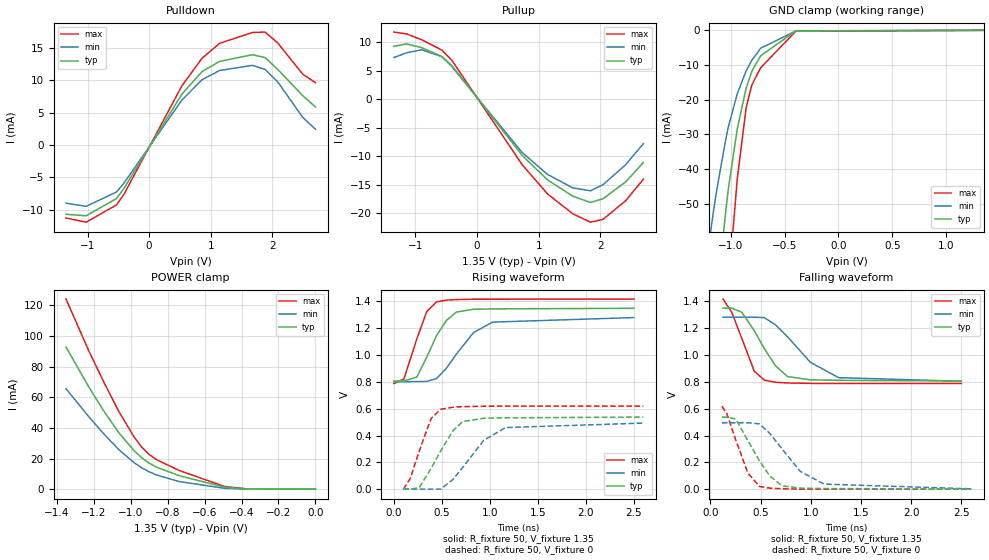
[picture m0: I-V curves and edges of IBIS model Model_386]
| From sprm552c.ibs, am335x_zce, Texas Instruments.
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| Model based on original model for BCSHTLTCSCDVPBFZ_SSDHV
|   Sub model SR10_5MA_5PER_1P35
[model]   Model_386
|[Description]  [1.35V-3-STATE-NOTERM-SR10:5MA, IND, 5%]
|   Fast slew rate (SR[1:0] = "10"), 1.60 * RExt = 0.625 * Iout
|   (I[2:0] = "000"), 5mA nominal with Rext = 50R,ODT off (ODT[1:0]
|   = "00") CMOS mode,Industrial temperature range (-40C to 125C,
|   25C nominal),5% power supply tolerance
|[Input Load]   NOTERM
|[Output Drive] SR10:5MA
|Voltage   1.35V
|Mode   3-STATE
Model_type   3-state
Polarity   Non-Inverting
Enable   Active-Low
Cref =  15pF
Rref =  100.0000M
Vref =  0V
Vmeas =  0.675
C_comp   1.865048p   1.679967p   1.989968p
[Temperature Range]   25   125   -40
[Voltage Range]   1.35   1.2825   1.4175
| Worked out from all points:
|   slope of the pulldown table from 0 to 0.203 V, typ, clamps not added: 62.9 ohm
|   slope of the pullup table from 0 to 0.203 V, typ, clamps not added: 69.7 ohm
|   GND clamp passes 1 mA (typ) near -0.49 V on its own axis
|   POWER clamp passes 1 mA (typ) near -0.47 V on its own axis
|   rising waveform, R_fixture 50, V_fixture 1.35: 20-80 % time 227ps typ, 316ps min, 166ps max; typ from 0.807 V to 1.35 V
|   rising waveform, R_fixture 50, V_fixture 0: 20-80 % time 258ps typ, 346ps min, 173ps max; typ from 0 V to 0.537 V
|   falling waveform, R_fixture 50, V_fixture 1.35: 20-80 % time 264ps typ, 373ps min, 187ps max; typ from 1.35 V to 0.807 V
|   falling waveform, R_fixture 50, V_fixture 0: 20-80 % time 255ps typ, 340ps min, 174ps max; typ from 0.537 V to 0 V
[POWER_clamp]
-1.35V    92.75mA    65.58mA    124.1mA
-1.227V   66.81mA    47.37mA    90.43mA
-1.145V   50.92mA    36.04mA    69.8mA
-1.064V   36.83mA    25.8mA     50.7mA
-981.8mV  25.17mA    17.34mA    34.14mA
-940.9mV  20.58mA    14.01mA    27.56mA
-900mV    17mA       11.33mA    22.64mA
-859.1mV  14.3mA     9.214mA    19.2mA
-736.4mV  8.769mA    4.942mA    12.14mA
-490.9mV  1.299mA    528.4uA    1.73mA
-368.2mV  117.2uA    50.88uA    117.5uA
0V        1.028nA    11.95nA    1.029nA
[Pulldown]
-1.35V    -10.68mA   -8.968mA   -11.25mA
-1.023V   -10.91mA   -9.455mA   -11.9mA
-531.8mV  -8.266mA   -7.25mA    -9.251mA
-409.1mV  -6.689mA   -5.878mA   -7.605mA
531.8mV   7.861mA    6.942mA    9.13mA
859.1mV   11.33mA    10.08mA    13.39mA
1.145V    12.9mA     11.5mA     15.69mA
1.677V    13.93mA    12.29mA    17.36mA
1.882V    13.49mA    11.66mA    17.42mA
2.086V    11.68mA    9.761mA    15.77mA
2.495V    7.606mA    4.25mA     10.91mA
2.7V      5.873mA    2.439mA    9.633mA
[Pullup]
-1.35V    9.289mA    7.338mA    11.8mA
-1.145V   9.731mA    8.157mA    11.48mA
-900mV    9.073mA    8.704mA    10.46mA
-572.7mV  7.523mA    7.496mA    8.655mA
-409.1mV  5.918mA    5.744mA    6.841mA
736.4mV   -9.883mA   -9.376mA   -11.53mA
1.145V    -14.14mA   -13.18mA   -16.61mA
1.555V    -17mA      -15.54mA   -20.09mA
1.841V    -18.1mA    -16.05mA   -21.56mA
2.045V    -17.45mA   -14.99mA   -21.07mA
2.414V    -14.47mA   -11.46mA   -17.78mA
2.7V      -11.09mA   -7.777mA   -14.02mA
[GND_clamp]
-1.35V    -159.1mA   -94.77mA   -266.2mA
-1.295V   -137.7mA   -81.77mA   -230.9mA
-1.159V   -87.19mA   -51.56mA   -145.9mA
-1.132V   -77.89mA   -46.14mA   -129.9mA
-1.05V    -52.83mA   -31.84mA   -86.44mA
-1.023V   -45.55mA   -27.75mA   -73.68mA
-940.9mV  -28.44mA   -18.28mA   -42.92mA
-859.1mV  -16.79mA   -11.75mA   -22.47mA
-804.5mV  -11.72mA   -8.559mA   -15.69mA
-722.7mV  -7.324mA   -5.162mA   -10.76mA
-395.5mV  -159.1uA   -161.1uA   -232.3uA
1.35V     1.028nA    30.09nA    754.3pA
[Ramp]
dV/dt_f 0.32717815/0.26579024n 0.28993702/0.37941451n 0.37859079/0.18779996n
dV/dt_r 0.32408895/0.25921938n 0.29929254/0.35228155n 0.37280837/0.17374824n
R_load = 50
[Rising Waveform]
R_fixture = 50
V_fixture = 1.35
V_fixture_min = 1.2825
V_fixture_max = 1.4175
0s        806.9mV    802mV      788.4mV
104.1ps   807.3mV    802mV      821.6mV
238.7ps   836.5mV    802.5mV    1.121V
342.1ps   985.5mV    803.6mV    1.325V
443.9ps   1.145V     825.2mV    1.397V
544.9ps   1.257V     900.5mV    1.41V
651.4ps   1.321V     1.008V     1.414V
830.4ps   1.342V     1.169V     1.417V
1.029ns   1.345V     1.246V     1.417V
2.5ns     1.349V     1.28V      1.418V
[Rising Waveform]
R_fixture = 50
V_fixture = 0
V_fixture_min = 0
V_fixture_max = 0
98.98ps   0V         0V         0V
169.6ps   0V         0V         79.08mV
265.1ps   11.93mV    0V         287.1mV
387.6ps   156.2mV    0V         527.7mV
487.6ps   284.4mV    0V         595.6mV
617.2ps   437.8mV    73.79mV    611.5mV
716.8ps   504.4mV    162mV      615.5mV
936.6ps   529.1mV    364.6mV    618.6mV
1.163ns   532.3mV    459.5mV    619.4mV
2.599ns   537.5mV    492.8mV    619.7mV
[Falling Waveform]
R_fixture = 50
V_fixture = 1.35
V_fixture_min = 1.2825
V_fixture_max = 1.4175
126ps     1.349V     1.282V     1.417V
213.4ps   1.349V     1.282V     1.318V
312.7ps   1.319V     1.282V     1.125V
437.2ps   1.182V     1.282V     880mV
536.7ps   1.049V     1.279V     812.8mV
648.5ps   919.6mV    1.225V     797mV
769.1ps   838.9mV    1.136V     791.6mV
995.6ps   815.1mV    946mV      788.5mV
1.277ns   811.1mV    831.2mV    787.7mV
2.5ns     806.8mV    804.3mV    787.4mV
[Falling Waveform]
R_fixture = 50
V_fixture = 0
V_fixture_min = 0
V_fixture_max = 0
114.3ps   537.4mV    495.2mV    618.8mV
165ps     537.4mV    495.2mV    561.3mV
252.9ps   522.6mV    495.2mV    367.3mV
373.8ps   362.2mV    495.2mV    119.7mV
490.4ps   209mV      485.9mV    20.33mV
592ps     99mV       415.1mV    7.514mV
713.1ps   25.05mV    300.6mV    3.269mV
896.2ps   7.34mV     132mV      0V
1.133ns   4.636mV    37.71mV    0V
2.599ns   0V         2.576mV    0V
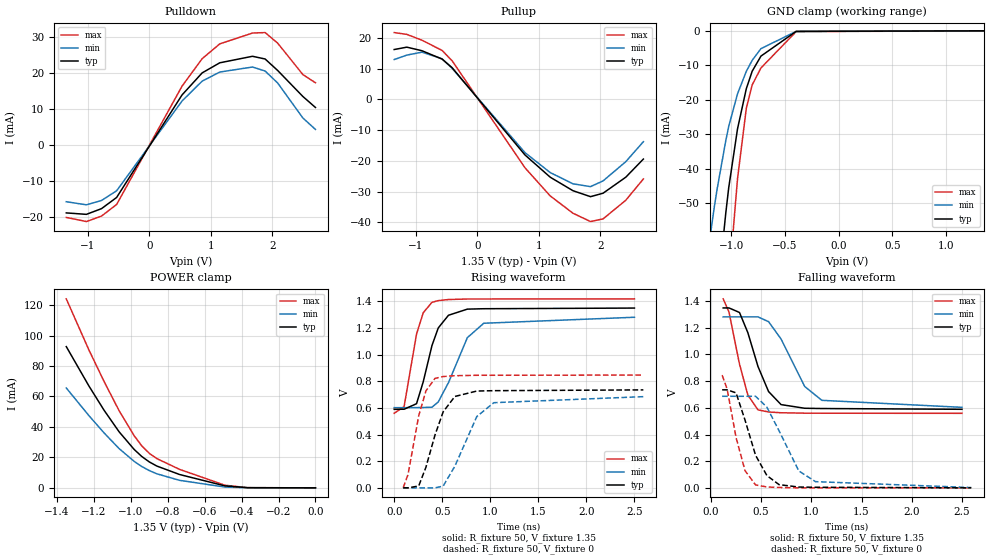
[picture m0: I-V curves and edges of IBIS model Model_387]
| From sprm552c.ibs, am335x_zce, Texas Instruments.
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| Model based on original model for BCSHTLTCSCDVPBFZ_SSDHV
|   Sub model SR10_9MA_5PER_1P35
[model]   Model_387
|[Description]  [1.35V-3-STATE-NOTERM-SR10:9MA, IND, 5%]
|   Fast slew rate (SR[1:0] = "10"), 0.88 * RExt = 1.125 * Iout
|   (I[2:0] = "100"), 9mA nominal with Rext = 50R,ODT off (ODT[1:0]
|   = "00") CMOS mode,Industrial temperature range (-40C to 125C,
|   25C nominal),5% power supply tolerance
|[Input Load]   NOTERM
|[Output Drive] SR10:9MA
|Voltage   1.35V
|Mode   3-STATE
Model_type   3-state
Polarity   Non-Inverting
Enable   Active-Low
Cref =  15pF
Rref =  100.0000M
Vref =  0V
Vmeas =  0.675
C_comp   1.865048p   1.679967p   1.989968p
[Temperature Range]   25   125   -40
[Voltage Range]   1.35   1.2825   1.4175
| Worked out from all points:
|   slope of the pulldown table from 0 to 0.203 V, typ, clamps not added: 35.4 ohm
|   slope of the pullup table from 0 to 0.203 V, typ, clamps not added: 39.9 ohm
|   GND clamp passes 1 mA (typ) near -0.49 V on its own axis
|   POWER clamp passes 1 mA (typ) near -0.47 V on its own axis
|   rising waveform, R_fixture 50, V_fixture 1.35: 20-80 % time 175ps typ, 244ps min, 128ps max; typ from 0.589 V to 1.35 V
|   rising waveform, R_fixture 50, V_fixture 0: 20-80 % time 196ps typ, 255ps min, 141ps max; typ from 0 V to 0.735 V
|   falling waveform, R_fixture 50, V_fixture 1.35: 20-80 % time 208ps typ, 280ps min, 147ps max; typ from 1.35 V to 0.589 V
|   falling waveform, R_fixture 50, V_fixture 0: 20-80 % time 191ps typ, 264ps min, 141ps max; typ from 0.735 V to 0 V
[POWER_clamp]
-1.35V    92.75mA    65.58mA    124.1mA
-1.227V   66.81mA    47.37mA    90.43mA
-1.145V   50.92mA    36.04mA    69.8mA
-1.064V   36.83mA    25.8mA     50.7mA
-981.8mV  25.17mA    17.34mA    34.14mA
-940.9mV  20.58mA    14.01mA    27.56mA
-900mV    17mA       11.33mA    22.64mA
-859.1mV  14.3mA     9.214mA    19.2mA
-736.4mV  8.769mA    4.942mA    12.14mA
-490.9mV  1.299mA    528.4uA    1.73mA
-368.2mV  117.2uA    50.88uA    117.5uA
0V        1.028nA    11.95nA    1.029nA
[Pulldown]
-1.35V    -18.99mA   -15.87mA   -20.25mA
-1.023V   -19.4mA    -16.73mA   -21.41mA
-777.3mV  -17.8mA    -15.52mA   -19.88mA
-531.8mV  -14.68mA   -12.82mA   -16.64mA
531.8mV   13.96mA    12.27mA    16.41mA
859.1mV   20.12mA    17.82mA    24.09mA
1.145V    22.93mA    20.35mA    28.22mA
1.677V    24.75mA    21.75mA    31.24mA
1.882V    23.99mA    20.63mA    31.37mA
2.086V    20.78mA    17.28mA    28.42mA
2.495V    13.53mA    7.525mA    19.65mA
2.7V      10.45mA    4.317mA    17.35mA
[Pullup]
-1.35V    16.26mA    12.99mA    21.78mA
-1.145V   17.03mA    14.44mA    21.19mA
-900mV    15.87mA    15.4mA     19.31mA
-572.7mV  13.16mA    13.25mA    15.97mA
-409.1mV  10.35mA    10.15mA    12.61mA
777.3mV   -18.12mA   -17.36mA   -22.31mA
1.186V    -25.34mA   -23.83mA   -31.43mA
1.555V    -29.73mA   -27.49mA   -37.07mA
1.841V    -31.68mA   -28.41mA   -39.79mA
2.045V    -30.55mA   -26.54mA   -38.92mA
2.414V    -25.34mA   -20.29mA   -32.85mA
2.7V      -19.43mA   -13.77mA   -25.91mA
[GND_clamp]
-1.35V    -159.1mA   -94.77mA   -266.2mA
-1.295V   -137.7mA   -81.77mA   -230.9mA
-1.159V   -87.19mA   -51.56mA   -145.9mA
-1.132V   -77.89mA   -46.14mA   -129.9mA
-1.05V    -52.83mA   -31.84mA   -86.44mA
-1.023V   -45.55mA   -27.75mA   -73.68mA
-940.9mV  -28.44mA   -18.28mA   -42.92mA
-859.1mV  -16.79mA   -11.75mA   -22.47mA
-804.5mV  -11.72mA   -8.559mA   -15.69mA
-722.7mV  -7.324mA   -5.162mA   -10.76mA
-395.5mV  -159.1uA   -161.1uA   -232.3uA
1.35V     1.028nA    30.09nA    754.3pA
[Ramp]
dV/dt_f 0.45843512/0.20911261n 0.41084477/0.28401977n 0.51650422/0.14754663n
dV/dt_r 0.44362094/0.19720543n 0.41520896/0.25873023n 0.50970889/0.14147792n
R_load = 50
[Rising Waveform]
R_fixture = 50
V_fixture = 1.35
V_fixture_min = 1.2825
V_fixture_max = 1.4175
0s        589.3mV    601.6mV    559.7mV
103.1ps   589.9mV    601.6mV    609.9mV
232.4ps   631.3mV    602.2mV    1.154V
302.1ps   795.6mV    602.9mV    1.314V
393.1ps   1.068V     605.1mV    1.392V
458.6ps   1.2V       644.8mV    1.405V
564.7ps   1.295V     789.4mV    1.413V
761.2ps   1.341V     1.127V     1.417V
932ps     1.344V     1.235V     1.417V
2.5ns     1.349V     1.28V      1.418V
[Rising Waveform]
R_fixture = 50
V_fixture = 0
V_fixture_min = 0
V_fixture_max = 0
93.32ps   0V         0V         0V
143.9ps   0V         0V         99.67mV
255ps     13.99mV    0V         540mV
329.9ps   154mV      0V         727.4mV
424.4ps   396mV      0V         821.1mV
509.5ps   570.1mV    13.31mV    835.3mV
631ps     685.7mV    162mV      841.3mV
859.6ps   726.4mV    535.3mV    844.7mV
1.037ns   729.1mV    639mV      844.8mV
2.593ns   735mV      684.3mV    846.3mV
[Falling Waveform]
R_fixture = 50
V_fixture = 1.35
V_fixture_min = 1.2825
V_fixture_max = 1.4175
122.8ps   1.349V     1.282V     1.417V
180.7ps   1.349V     1.282V     1.318V
285.1ps   1.315V     1.282V     928.6mV
368.7ps   1.163V     1.282V     694.8mV
469.6ps   909.4mV    1.282V     584.6mV
574.6ps   722.1mV    1.246V     568.9mV
699.1ps   624.2mV    1.116V     563mV
934ps     596.8mV    760.3mV    560mV
1.105ns   594.7mV    656.2mV    559.6mV
2.5ns     589.1mV    603.7mV    558.7mV
[Falling Waveform]
R_fixture = 50
V_fixture = 0
V_fixture_min = 0
V_fixture_max = 0
112.2ps   735mV      686.5mV    845.4mV
162.3ps   735mV      686.5mV    740.8mV
250.9ps   712.3mV    686.5mV    377.7mV
340.2ps   508.2mV    686.5mV    129.2mV
445.2ps   244.2mV    686.5mV    21.89mV
558.1ps   91.98mV    604.8mV    6.581mV
679.5ps   23.95mV    427.1mV    2.598mV
875.8ps   5.972mV    126.8mV    0V
1.042ns   4.39mV     46.39mV    0V
2.593ns   0V         2.349mV    0V
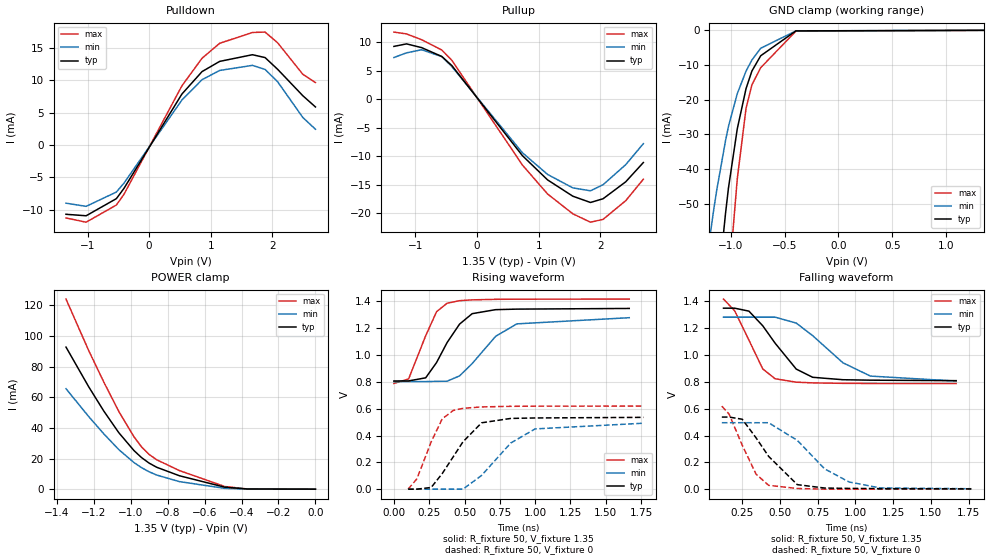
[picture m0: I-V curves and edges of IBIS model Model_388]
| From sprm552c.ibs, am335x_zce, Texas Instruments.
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| Model based on original model for BCSHTLTCSCDVPBFZ_SSDHV
|   Sub model SR01_5MA_5PER_1P35
[model]   Model_388
|[Description]  [1.35V-3-STATE-NOTERM-SR01:5MA, IND, 5%]
|   Slow slew rate (SR[1:0] = "01"), 1.60 * RExt = 0.625 * Iout
|   (I[2:0] = "000"), 5mA nominal with Rext = 50R,ODT off (ODT[1:0]
|   = "00") CMOS mode,Industrial temperature range (-40C to 125C,
|   25C nominal),5% power supply tolerance
|[Input Load]   NOTERM
|[Output Drive] SR01:5MA
|Voltage   1.35V
|Mode   3-STATE
Model_type   3-state
Polarity   Non-Inverting
Enable   Active-Low
Cref =  15pF
Rref =  100.0000M
Vref =  0V
Vmeas =  0.675
C_comp   1.865048p   1.679967p   1.989968p
[Temperature Range]   25   125   -40
[Voltage Range]   1.35   1.2825   1.4175
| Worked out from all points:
|   slope of the pulldown table from 0 to 0.203 V, typ, clamps not added: 62.9 ohm
|   slope of the pullup table from 0 to 0.203 V, typ, clamps not added: 69.7 ohm
|   GND clamp passes 1 mA (typ) near -0.49 V on its own axis
|   POWER clamp passes 1 mA (typ) near -0.47 V on its own axis
|   rising waveform, R_fixture 50, V_fixture 1.35: 20-80 % time 186ps typ, 257ps min, 138ps max; typ from 0.807 V to 1.35 V
|   rising waveform, R_fixture 50, V_fixture 0: 20-80 % time 207ps typ, 275ps min, 142ps max; typ from 0 V to 0.536 V
|   falling waveform, R_fixture 50, V_fixture 1.35: 20-80 % time 218ps typ, 303ps min, 156ps max; typ from 1.35 V to 0.809 V
|   falling waveform, R_fixture 50, V_fixture 0: 20-80 % time 208ps typ, 276ps min, 145ps max; typ from 0.537 V to 0.002 V
[POWER_clamp]
-1.35V    92.75mA    65.58mA    124.1mA
-1.227V   66.81mA    47.37mA    90.43mA
-1.145V   50.92mA    36.04mA    69.8mA
-1.064V   36.83mA    25.8mA     50.7mA
-981.8mV  25.17mA    17.34mA    34.14mA
-940.9mV  20.58mA    14.01mA    27.56mA
-900mV    17mA       11.33mA    22.64mA
-859.1mV  14.3mA     9.214mA    19.2mA
-736.4mV  8.769mA    4.942mA    12.14mA
-490.9mV  1.299mA    528.4uA    1.73mA
-368.2mV  117.2uA    50.88uA    117.5uA
0V        1.028nA    11.95nA    1.029nA
[Pulldown]
-1.35V    -10.68mA   -8.968mA   -11.25mA
-1.023V   -10.91mA   -9.455mA   -11.9mA
-531.8mV  -8.266mA   -7.25mA    -9.251mA
-409.1mV  -6.689mA   -5.878mA   -7.605mA
531.8mV   7.861mA    6.942mA    9.13mA
859.1mV   11.33mA    10.08mA    13.39mA
1.145V    12.9mA     11.5mA     15.69mA
1.677V    13.93mA    12.29mA    17.36mA
1.882V    13.49mA    11.66mA    17.42mA
2.086V    11.68mA    9.761mA    15.77mA
2.495V    7.606mA    4.25mA     10.91mA
2.7V      5.873mA    2.439mA    9.633mA
[Pullup]
-1.35V    9.289mA    7.338mA    11.8mA
-1.145V   9.731mA    8.157mA    11.48mA
-900mV    9.073mA    8.704mA    10.46mA
-572.7mV  7.523mA    7.496mA    8.655mA
-409.1mV  5.918mA    5.744mA    6.841mA
736.4mV   -9.883mA   -9.376mA   -11.53mA
1.145V    -14.14mA   -13.18mA   -16.61mA
1.555V    -17mA      -15.54mA   -20.09mA
1.841V    -18.1mA    -16.05mA   -21.56mA
2.045V    -17.45mA   -14.99mA   -21.07mA
2.414V    -14.47mA   -11.46mA   -17.78mA
2.7V      -11.09mA   -7.777mA   -14.02mA
[GND_clamp]
-1.35V    -159.1mA   -94.77mA   -266.2mA
-1.295V   -137.7mA   -81.77mA   -230.9mA
-1.159V   -87.19mA   -51.56mA   -145.9mA
-1.132V   -77.89mA   -46.14mA   -129.9mA
-1.05V    -52.83mA   -31.84mA   -86.44mA
-1.023V   -45.55mA   -27.75mA   -73.68mA
-940.9mV  -28.44mA   -18.28mA   -42.92mA
-859.1mV  -16.79mA   -11.75mA   -22.47mA
-804.5mV  -11.72mA   -8.559mA   -15.69mA
-722.7mV  -7.324mA   -5.162mA   -10.76mA
-395.5mV  -159.1uA   -161.1uA   -232.3uA
1.35V     1.028nA    30.09nA    754.3pA
[Ramp]
dV/dt_f 0.32725822/0.22057485n 0.28999945/0.30934335n 0.37862753/0.15693853n
dV/dt_r 0.32418375/0.20889434n  0.2993168/0.28031885n 0.37288502/0.14238759n
R_load = 50
[Rising Waveform]
R_fixture = 50
V_fixture = 1.35
V_fixture_min = 1.2825
V_fixture_max = 1.4175
0s        806.9mV    802mV      788.4mV
104.2ps   807.4mV    802mV      822.1mV
225.2ps   830.6mV    802.5mV    1.145V
302.3ps   945mV      804.3mV    1.324V
377ps     1.094V     805.5mV    1.387V
464.9ps   1.231V     844.9mV    1.406V
554.2ps   1.309V     936.6mV    1.412V
720.3ps   1.339V     1.14V      1.416V
870.9ps   1.343V     1.233V     1.417V
1.667ns   1.348V     1.279V     1.418V
[Rising Waveform]
R_fixture = 50
V_fixture = 0
V_fixture_min = 0
V_fixture_max = 0
100.6ps   0V         0V         0V
163.1ps   0V         0V         77.57mV
264ps     12.81mV    0V         353.1mV
342.1ps   116mV      0V         524.5mV
420.5ps   242.2mV    0V         587.2mV
489.1ps   353.1mV    0V         603.1mV
621ps     495mV      102.5mV    613.4mV
827.2ps   527.6mV    344mV      618mV
999.8ps   531.1mV    449.3mV    619.1mV
1.767ns   535.6mV    492mV      619.7mV
[Falling Waveform]
R_fixture = 50
V_fixture = 1.35
V_fixture_min = 1.2825
V_fixture_max = 1.4175
128.1ps   1.349V     1.282V     1.417V
202.5ps   1.349V     1.282V     1.329V
296.3ps   1.327V     1.282V     1.111V
387.7ps   1.218V     1.282V     896.3mV
469.6ps   1.088V     1.282V     823.1mV
609.3ps   895.1mV    1.238V     797.5mV
718.2ps   833.9mV    1.144V     792.2mV
917.6ps   815.8mV    942.4mV    788.8mV
1.1ns     812.4mV    842.9mV    787.9mV
1.667ns   808.8mV    805.6mV    787.5mV
[Falling Waveform]
R_fixture = 50
V_fixture = 0
V_fixture_min = 0
V_fixture_max = 0
117.2ps   537.4mV    495.3mV    618.7mV
165ps     537.4mV    495.3mV    559.7mV
252.2ps   521.2mV    495.3mV    327.4mV
344.1ps   381.8mV    495.3mV    111.2mV
426.8ps   244.4mV    495.3mV    28.59mV
616.4ps   33.6mV     363.7mV    5.079mV
796.4ps   8.467mV    151.6mV    0V
958.1ps   5.666mV    53.9mV     0V
1.165ns   4.214mV    8.924mV    0V
1.767ns   2.16mV     3.246mV    0V
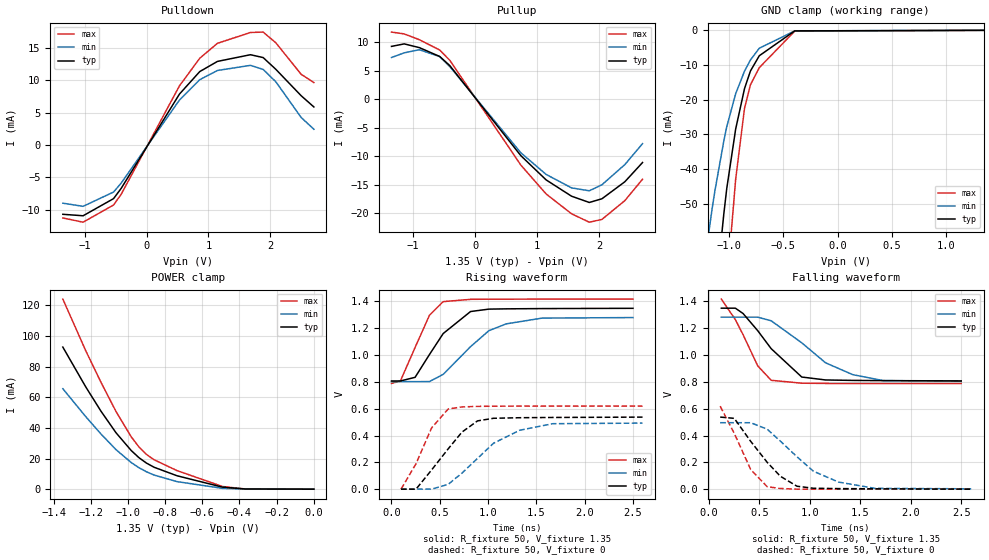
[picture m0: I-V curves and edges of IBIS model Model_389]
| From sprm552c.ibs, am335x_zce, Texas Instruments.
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| Model based on original model for BCSHTLTCSCDVPBFZ_SSDHV
|   Sub model SR11_5MA_5PER_1P35
[model]   Model_389
|[Description]  [1.35V-3-STATE-NOTERM-SR11:5MA, IND, 5%]
|   Slowest slew rate (SR[1:0] = "11"), 1.60 * RExt = 0.625 * Iout
|   (I[2:0] = "000"), 5mA nominal with Rext = 50R,ODT off (ODT[1:0]
|   = "00") CMOS mode,Industrial temperature range (-40C to 125C,
|   25C nominal),5% power supply tolerance
|[Input Load]   NOTERM
|[Output Drive] SR11:5MA
|Voltage   1.35V
|Mode   3-STATE
Model_type   3-state
Polarity   Non-Inverting
Enable   Active-Low
Cref =  15pF
Rref =  100.0000M
Vref =  0V
Vmeas =  0.675
C_comp   1.865048p   1.679967p   1.989968p
[Temperature Range]   25   125   -40
[Voltage Range]   1.35   1.2825   1.4175
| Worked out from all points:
|   slope of the pulldown table from 0 to 0.203 V, typ, clamps not added: 62.9 ohm
|   slope of the pullup table from 0 to 0.203 V, typ, clamps not added: 69.7 ohm
|   GND clamp passes 1 mA (typ) near -0.49 V on its own axis
|   POWER clamp passes 1 mA (typ) near -0.47 V on its own axis
|   rising waveform, R_fixture 50, V_fixture 1.35: 20-80 % time 312ps typ, 426ps min, 224ps max; typ from 0.807 V to 1.35 V
|   rising waveform, R_fixture 50, V_fixture 0: 20-80 % time 358ps typ, 475ps min, 236ps max; typ from 0 V to 0.537 V
|   falling waveform, R_fixture 50, V_fixture 1.35: 20-80 % time 348ps typ, 511ps min, 244ps max; typ from 1.35 V to 0.807 V
|   falling waveform, R_fixture 50, V_fixture 0: 20-80 % time 343ps typ, 452ps min, 230ps max; typ from 0.537 V to 0 V
[POWER_clamp]
-1.35V    92.75mA    65.58mA    124.1mA
-1.227V   66.81mA    47.37mA    90.43mA
-1.145V   50.92mA    36.04mA    69.8mA
-1.064V   36.83mA    25.8mA     50.7mA
-981.8mV  25.17mA    17.34mA    34.14mA
-940.9mV  20.58mA    14.01mA    27.56mA
-900mV    17mA       11.33mA    22.64mA
-859.1mV  14.3mA     9.214mA    19.2mA
-736.4mV  8.769mA    4.942mA    12.14mA
-490.9mV  1.299mA    528.4uA    1.73mA
-368.2mV  117.2uA    50.88uA    117.5uA
0V        1.028nA    11.95nA    1.029nA
[Pulldown]
-1.35V    -10.68mA   -8.968mA   -11.25mA
-1.023V   -10.91mA   -9.455mA   -11.9mA
-531.8mV  -8.266mA   -7.25mA    -9.251mA
-409.1mV  -6.689mA   -5.878mA   -7.605mA
531.8mV   7.861mA    6.942mA    9.13mA
859.1mV   11.33mA    10.08mA    13.39mA
1.145V    12.9mA     11.5mA     15.69mA
1.677V    13.93mA    12.29mA    17.36mA
1.882V    13.49mA    11.66mA    17.42mA
2.086V    11.68mA    9.761mA    15.77mA
2.495V    7.606mA    4.25mA     10.91mA
2.7V      5.873mA    2.439mA    9.633mA
[Pullup]
-1.35V    9.289mA    7.338mA    11.8mA
-1.145V   9.731mA    8.157mA    11.48mA
-900mV    9.073mA    8.704mA    10.46mA
-572.7mV  7.523mA    7.496mA    8.655mA
-409.1mV  5.918mA    5.744mA    6.841mA
736.4mV   -9.883mA   -9.376mA   -11.53mA
1.145V    -14.14mA   -13.18mA   -16.61mA
1.555V    -17mA      -15.54mA   -20.09mA
1.841V    -18.1mA    -16.05mA   -21.56mA
2.045V    -17.45mA   -14.99mA   -21.07mA
2.414V    -14.47mA   -11.46mA   -17.78mA
2.7V      -11.09mA   -7.777mA   -14.02mA
[GND_clamp]
-1.35V    -159.1mA   -94.77mA   -266.2mA
-1.295V   -137.7mA   -81.77mA   -230.9mA
-1.159V   -87.19mA   -51.56mA   -145.9mA
-1.132V   -77.89mA   -46.14mA   -129.9mA
-1.05V    -52.83mA   -31.84mA   -86.44mA
-1.023V   -45.55mA   -27.75mA   -73.68mA
-940.9mV  -28.44mA   -18.28mA   -42.92mA
-859.1mV  -16.79mA   -11.75mA   -22.47mA
-804.5mV  -11.72mA   -8.559mA   -15.69mA
-722.7mV  -7.324mA   -5.162mA   -10.76mA
-395.5mV  -159.1uA   -161.1uA   -232.3uA
1.35V     1.028nA    30.09nA    754.3pA
[Ramp]
dV/dt_f 0.32723899/0.3508457n 0.28998074/0.51906628n  0.3786613/0.2452128n
dV/dt_r 0.32408642/0.3597175n 0.29926289/0.48430992n 0.37282925/0.23669494n
R_load = 50
[Rising Waveform]
R_fixture = 50
V_fixture = 1.35
V_fixture_min = 1.2825
V_fixture_max = 1.4175
0s        806.9mV    802mV      788.4mV
92.56ps   806.9mV    802mV      807.7mV
244.3ps   834.3mV    802mV      1.057V
392.9ps   1.004V     802.6mV    1.297V
535.5ps   1.161V     856.4mV    1.399V
818.4ps   1.325V     1.063V     1.416V
1.008ns   1.343V     1.182V     1.417V
1.188ns   1.345V     1.233V     1.417V
1.559ns   1.347V     1.276V     1.418V
2.5ns     1.349V     1.28V      1.418V
[Rising Waveform]
R_fixture = 50
V_fixture = 0
V_fixture_min = 0
V_fixture_max = 0
98.55ps   0V         0V         0V
253.8ps   0V         0V         189.7mV
414.8ps   142.9mV    0V         456.5mV
587ps     300.8mV    36.07mV    598.2mV
729.6ps   425.7mV    119.8mV    613.4mV
891.3ps   509.5mV    230.2mV    617.5mV
1.057ns   528.8mV    342.9mV    618.9mV
1.327ns   532.9mV    439.5mV    619.5mV
1.671ns   534.9mV    488.3mV    619.7mV
2.599ns   537.4mV    492.7mV    619.7mV
[Falling Waveform]
R_fixture = 50
V_fixture = 1.35
V_fixture_min = 1.2825
V_fixture_max = 1.4175
122.8ps   1.349V     1.282V     1.417V
262.1ps   1.349V     1.282V     1.263V
338.4ps   1.309V     1.282V     1.151V
483.6ps   1.181V     1.282V     918.4mV
617ps     1.047V     1.255V     811.5mV
919.6ps   835.9mV    1.091V     789.9mV
1.155ns   814mV      942.2mV    788.1mV
1.425ns   810.7mV    853.5mV    787.6mV
1.725ns   809mV      809.5mV    787.5mV
2.5ns     807mV      804.5mV    787.4mV
[Falling Waveform]
R_fixture = 50
V_fixture = 0
V_fixture_min = 0
V_fixture_max = 0
111ps     537.4mV    495.3mV    618.8mV
251ps     527.8mV    495.3mV    415.8mV
413.7ps   356.4mV    495.3mV    146.3mV
576.8ps   200.5mV    447.1mV    18.31mV
707.7ps   96.02mV    358.2mV    5.091mV
872.6ps   21.89mV    241.3mV    0V
1.035ns   6.881mV    133.8mV    0V
1.285ns   4.205mV    52.71mV    0V
1.644ns   2.704mV    6.143mV    0V
2.599ns   0V         2.645mV    0V
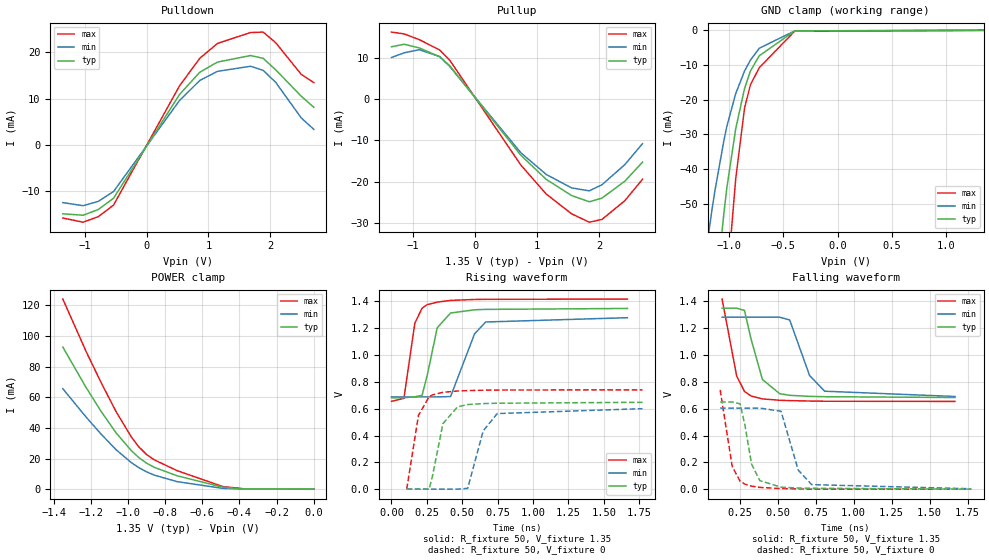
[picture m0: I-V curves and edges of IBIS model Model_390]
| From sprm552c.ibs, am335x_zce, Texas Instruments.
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| Model based on original model for BCSHTLTCSCDVPBFZ_SSDHV
|   Sub model SR00_7MA_5PER_1P35
[model]   Model_390
|[Description]  [1.35V-3-STATE-NOTERM-SR00:7MA, IND, 5%]
|   Fastest slew rate (SR[1:0] = "00"), 1.14 * RExt = 0.875 * Iout
|   (I[2:0] = "010"), 7mA nominal with Rext = 50R,ODT off (ODT[1:0]
|   = "00") CMOS mode,Industrial temperature range (-40C to 125C,
|   25C nominal),5% power supply tolerance
|[Input Load]   NOTERM
|[Output Drive] SR00:7MA
|Voltage   1.35V
|Mode   3-STATE
Model_type   3-state
Polarity   Non-Inverting
Enable   Active-Low
Cref =  15pF
Rref =  100.0000M
Vref =  0V
Vmeas =  0.675
C_comp   1.865048p   1.679967p   1.989968p
[Temperature Range]   25   125   -40
[Voltage Range]   1.35   1.2825   1.4175
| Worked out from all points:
|   slope of the pulldown table from 0 to 0.203 V, typ, clamps not added: 45.3 ohm
|   slope of the pullup table from 0 to 0.203 V, typ, clamps not added: 50.7 ohm
|   GND clamp passes 1 mA (typ) near -0.49 V on its own axis
|   POWER clamp passes 1 mA (typ) near -0.47 V on its own axis
|   rising waveform, R_fixture 50, V_fixture 1.35: 20-80 % time 81.3ps typ, 113ps min, 61.8ps max; typ from 0.682 V to 1.35 V
|   rising waveform, R_fixture 50, V_fixture 0: 20-80 % time 80.7ps typ, 95.3ps min, 67.2ps max; typ from 0 V to 0.648 V
|   falling waveform, R_fixture 50, V_fixture 1.35: 20-80 % time 92.5ps typ, 116ps min, 72.6ps max; typ from 1.35 V to 0.684 V
|   falling waveform, R_fixture 50, V_fixture 0: 20-80 % time 66.2ps typ, 86.1ps min, 53.9ps max; typ from 0.651 V to 0 V
[POWER_clamp]
-1.35V    92.75mA    65.58mA    124.1mA
-1.227V   66.81mA    47.37mA    90.43mA
-1.145V   50.92mA    36.04mA    69.8mA
-1.064V   36.83mA    25.8mA     50.7mA
-981.8mV  25.17mA    17.34mA    34.14mA
-940.9mV  20.58mA    14.01mA    27.56mA
-900mV    17mA       11.33mA    22.64mA
-859.1mV  14.3mA     9.214mA    19.2mA
-736.4mV  8.769mA    4.942mA    12.14mA
-490.9mV  1.299mA    528.4uA    1.73mA
-368.2mV  117.2uA    50.88uA    117.5uA
0V        1.028nA    11.95nA    1.029nA
[Pulldown]
-1.35V    -14.84mA   -12.42mA   -15.75mA
-1.023V   -15.15mA   -13.09mA   -16.65mA
-777.3mV  -13.91mA   -12.15mA   -15.46mA
-531.8mV  -11.48mA   -10.03mA   -12.95mA
531.8mV   10.91mA    9.608mA    12.77mA
859.1mV   15.73mA    13.95mA    18.74mA
1.145V    17.92mA    15.92mA    21.95mA
1.677V    19.34mA    17.02mA    24.3mA
1.882V    18.74mA    16.14mA    24.4mA
2.086V    16.23mA    13.52mA    22.09mA
2.495V    10.57mA    5.887mA    15.28mA
2.7V      8.16mA     3.378mA    13.49mA
[Pullup]
-1.35V    12.77mA    10.16mA    16.33mA
-1.145V   13.38mA    11.3mA     15.89mA
-900mV    12.47mA    12.05mA    14.48mA
-572.7mV  10.34mA    10.38mA    11.98mA
-409.1mV  8.134mA    7.949mA    9.466mA
736.4mV   -13.58mA   -12.98mA   -15.96mA
1.145V    -19.43mA   -18.24mA   -22.99mA
1.555V    -23.37mA   -21.52mA   -27.81mA
1.841V    -24.89mA   -22.23mA   -29.85mA
2.045V    -24mA      -20.76mA   -29.18mA
2.414V    -19.9mA    -15.87mA   -24.63mA
2.7V      -15.26mA   -10.77mA   -19.42mA
[GND_clamp]
-1.35V    -159.1mA   -94.77mA   -266.2mA
-1.295V   -137.7mA   -81.77mA   -230.9mA
-1.159V   -87.19mA   -51.56mA   -145.9mA
-1.132V   -77.89mA   -46.14mA   -129.9mA
-1.05V    -52.83mA   -31.84mA   -86.44mA
-1.023V   -45.55mA   -27.75mA   -73.68mA
-940.9mV  -28.44mA   -18.28mA   -42.92mA
-859.1mV  -16.79mA   -11.75mA   -22.47mA
-804.5mV  -11.72mA   -8.559mA   -15.69mA
-722.7mV  -7.324mA   -5.162mA   -10.76mA
-395.5mV  -159.1uA   -161.1uA   -232.3uA
1.35V     1.028nA    30.09nA    754.3pA
[Ramp]
dV/dt_f 0.40696454/93.85412p  0.36370729/0.11854667n 0.46270098/72.842717p
dV/dt_r 0.39811499/81.909243p 0.37360132/98.159434p 0.45189908/67.35263p
R_load = 50
[Rising Waveform]
R_fixture = 50
V_fixture = 1.35
V_fixture_min = 1.2825
V_fixture_max = 1.4175
0s        682mV      688.2mV    655.4mV
87.77ps   682mV      688.2mV    677.1mV
164.9ps   688.7mV    688.2mV    1.238V
216.1ps   700.4mV    688.2mV    1.35V
253.2ps   851.9mV    688.2mV    1.377V
323.2ps   1.204V     688.2mV    1.395V
417.5ps   1.314V     690.8mV    1.408V
586.8ps   1.338V     1.158V     1.415V
665.6ps   1.341V     1.247V     1.416V
1.667ns   1.348V     1.279V     1.418V
[Rising Waveform]
R_fixture = 50
V_fixture = 0
V_fixture_min = 0
V_fixture_max = 0
107.5ps   0V         0V         0V
190.6ps   0V         0V         550.3mV
265.8ps   0V         0V         689.4mV
288.1ps   90.1mV     0V         702.4mV
363.2ps   488.2mV    0V         722.5mV
466.6ps   614.1mV    0V         732.1mV
538.4ps   630.9mV    5.974mV    735.4mV
647.7ps   638.4mV    433.9mV    738.1mV
746.9ps   641mV      563.8mV    739.4mV
1.774ns   648mV      600.6mV    741mV
[Falling Waveform]
R_fixture = 50
V_fixture = 1.35
V_fixture_min = 1.2825
V_fixture_max = 1.4175
135.5ps   1.35V      1.283V     1.418V
231.2ps   1.35V      1.283V     844.5mV
282.3ps   1.334V     1.283V     729.5mV
326.3ps   1.118V     1.283V     694.7mV
400.7ps   818.3mV    1.283V     673.4mV
513.1ps   712.9mV    1.283V     663.1mV
580.2ps   700mV      1.262V     660.5mV
711ps     692.1mV    847.5mV    657.4mV
810ps     689.7mV    730.7mV    655.9mV
1.667ns   683.7mV    691.3mV    654.4mV
[Falling Waveform]
R_fixture = 50
V_fixture = 0
V_fixture_min = 0
V_fixture_max = 0
122.7ps   650.5mV    604.6mV    740.9mV
202ps     650.5mV    604.6mV    169.1mV
254.4ps   636.1mV    604.6mV    58.22mV
287ps     468mV      604.6mV    36.61mV
329.4ps   187.5mV    604.6mV    22.49mV
383.6ps   63.87mV    604.6mV    13.19mV
523.2ps   14.74mV    581.4mV    4.439mV
636.7ps   8.506mV    141.5mV    2.199mV
724.4ps   6.684mV    34.03mV    0V
1.774ns   0V         3.029mV    0V
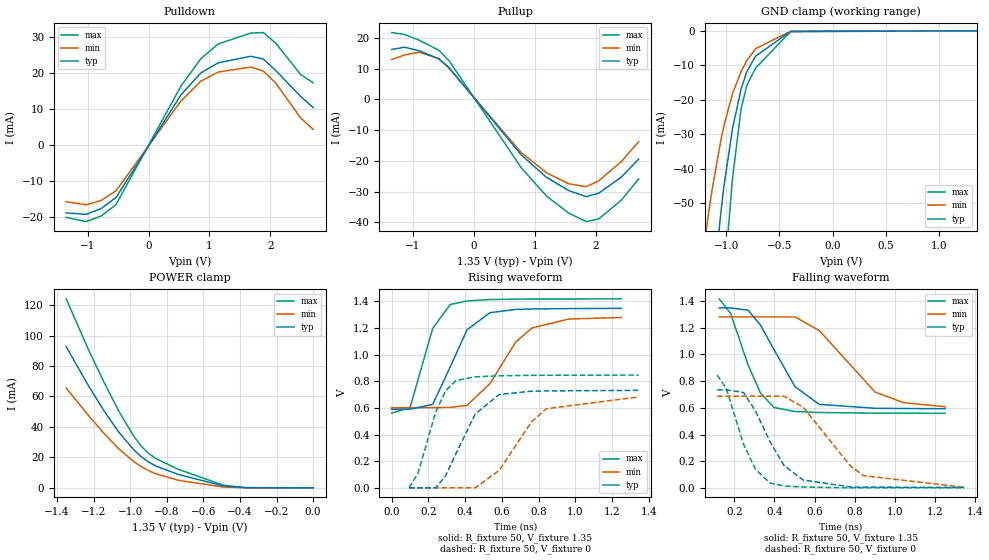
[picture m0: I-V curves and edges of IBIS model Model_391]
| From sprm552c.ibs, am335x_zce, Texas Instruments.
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| Model based on original model for BCSHTLTCSCDVPBFZ_SSDHV
|   Sub model SR01_9MA_5PER_1P35
[model]   Model_391
|[Description]  [1.35V-3-STATE-NOTERM-SR01:9MA, IND, 5%]
|   Slow slew rate (SR[1:0] = "01"), 0.88 * RExt = 1.125 * Iout
|   (I[2:0] = "100"), 9mA nominal with Rext = 50R,ODT off (ODT[1:0]
|   = "00") CMOS mode,Industrial temperature range (-40C to 125C,
|   25C nominal),5% power supply tolerance
|[Input Load]   NOTERM
|[Output Drive] SR01:9MA
|Voltage   1.35V
|Mode   3-STATE
Model_type   3-state
Polarity   Non-Inverting
Enable   Active-Low
Cref =  15pF
Rref =  100.0000M
Vref =  0V
Vmeas =  0.675
C_comp   1.865048p   1.679967p   1.989968p
[Temperature Range]   25   125   -40
[Voltage Range]   1.35   1.2825   1.4175
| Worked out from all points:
|   slope of the pulldown table from 0 to 0.203 V, typ, clamps not added: 35.4 ohm
|   slope of the pullup table from 0 to 0.203 V, typ, clamps not added: 39.9 ohm
|   GND clamp passes 1 mA (typ) near -0.49 V on its own axis
|   POWER clamp passes 1 mA (typ) near -0.47 V on its own axis
|   rising waveform, R_fixture 50, V_fixture 1.35: 20-80 % time 144ps typ, 197ps min, 106ps max; typ from 0.589 V to 1.35 V
|   rising waveform, R_fixture 50, V_fixture 0: 20-80 % time 158ps typ, 206ps min, 115ps max; typ from 0 V to 0.732 V
|   falling waveform, R_fixture 50, V_fixture 1.35: 20-80 % time 171ps typ, 230ps min, 124ps max; typ from 1.35 V to 0.593 V
|   falling waveform, R_fixture 50, V_fixture 0: 20-80 % time 157ps typ, 216ps min, 117ps max; typ from 0.735 V to 0.003 V
[POWER_clamp]
-1.35V    92.75mA    65.58mA    124.1mA
-1.227V   66.81mA    47.37mA    90.43mA
-1.145V   50.92mA    36.04mA    69.8mA
-1.064V   36.83mA    25.8mA     50.7mA
-981.8mV  25.17mA    17.34mA    34.14mA
-940.9mV  20.58mA    14.01mA    27.56mA
-900mV    17mA       11.33mA    22.64mA
-859.1mV  14.3mA     9.214mA    19.2mA
-736.4mV  8.769mA    4.942mA    12.14mA
-490.9mV  1.299mA    528.4uA    1.73mA
-368.2mV  117.2uA    50.88uA    117.5uA
0V        1.028nA    11.95nA    1.029nA
[Pulldown]
-1.35V    -18.99mA   -15.87mA   -20.25mA
-1.023V   -19.4mA    -16.73mA   -21.41mA
-777.3mV  -17.8mA    -15.52mA   -19.88mA
-531.8mV  -14.68mA   -12.82mA   -16.64mA
531.8mV   13.96mA    12.27mA    16.41mA
859.1mV   20.12mA    17.82mA    24.09mA
1.145V    22.93mA    20.35mA    28.22mA
1.677V    24.75mA    21.75mA    31.24mA
1.882V    23.99mA    20.63mA    31.37mA
2.086V    20.78mA    17.28mA    28.42mA
2.495V    13.53mA    7.525mA    19.65mA
2.7V      10.45mA    4.317mA    17.35mA
[Pullup]
-1.35V    16.26mA    12.99mA    21.78mA
-1.145V   17.03mA    14.44mA    21.19mA
-900mV    15.87mA    15.4mA     19.31mA
-572.7mV  13.16mA    13.25mA    15.97mA
-409.1mV  10.35mA    10.15mA    12.61mA
777.3mV   -18.12mA   -17.36mA   -22.31mA
1.186V    -25.34mA   -23.83mA   -31.43mA
1.555V    -29.73mA   -27.49mA   -37.07mA
1.841V    -31.68mA   -28.41mA   -39.79mA
2.045V    -30.55mA   -26.54mA   -38.92mA
2.414V    -25.34mA   -20.29mA   -32.85mA
2.7V      -19.43mA   -13.77mA   -25.91mA
[GND_clamp]
-1.35V    -159.1mA   -94.77mA   -266.2mA
-1.295V   -137.7mA   -81.77mA   -230.9mA
-1.159V   -87.19mA   -51.56mA   -145.9mA
-1.132V   -77.89mA   -46.14mA   -129.9mA
-1.05V    -52.83mA   -31.84mA   -86.44mA
-1.023V   -45.55mA   -27.75mA   -73.68mA
-940.9mV  -28.44mA   -18.28mA   -42.92mA
-859.1mV  -16.79mA   -11.75mA   -22.47mA
-804.5mV  -11.72mA   -8.559mA   -15.69mA
-722.7mV  -7.324mA   -5.162mA   -10.76mA
-395.5mV  -159.1uA   -161.1uA   -232.3uA
1.35V     1.028nA    30.09nA    754.3pA
[Ramp]
dV/dt_f 0.45854824/0.17319553n  0.4107911/0.23587821n 0.51660277/0.12415375n
dV/dt_r 0.44384442/0.16059583n 0.41522033/0.20964597n 0.50989303/0.11584035n
R_load = 50
[Rising Waveform]
R_fixture = 50
V_fixture = 1.35
V_fixture_min = 1.2825
V_fixture_max = 1.4175
0s        589.3mV    601.6mV    559.7mV
100.3ps   590mV      601.6mV    603.6mV
223.5ps   626.4mV    602.3mV    1.197V
319.4ps   908.8mV    603.5mV    1.376V
410.2ps   1.186V     618.6mV    1.402V
534.8ps   1.314V     781.6mV    1.413V
676.1ps   1.339V     1.095V     1.416V
764.7ps   1.342V     1.2V       1.417V
965.7ps   1.345V     1.267V     1.417V
1.25ns    1.347V     1.278V     1.418V
[Rising Waveform]
R_fixture = 50
V_fixture = 0
V_fixture_min = 0
V_fixture_max = 0
94.52ps   0V         0V         0V
142.7ps   0V         0V         107.2mV
239.5ps   0V         0V         567.1mV
293.4ps   89.58mV    0V         727.3mV
349.9ps   255.8mV    0V         805mV
454.8ps   553.4mV    0V         833.1mV
585.5ps   700.6mV    130.7mV    840.7mV
760.6ps   725.2mV    493.6mV    844.3mV
841.5ps   727mV      593.2mV    844.7mV
1.345ns   731.5mV    682.2mV    846.1mV
[Falling Waveform]
R_fixture = 50
V_fixture = 1.35
V_fixture_min = 1.2825
V_fixture_max = 1.4175
124.8ps   1.349V     1.282V     1.417V
181.6ps   1.349V     1.282V     1.308V
269ps     1.332V     1.282V     920.9mV
330.3ps   1.221V     1.282V     711mV
397.6ps   1.037V     1.282V     602.6mV
502.6ps   758.6mV    1.282V     572.3mV
623.3ps   625.8mV    1.179V     564.9mV
901.7ps   596.7mV    717.6mV    560mV
1.044ns   594.9mV    638.7mV    559.7mV
1.25ns    593mV      608mV      558.9mV
[Falling Waveform]
R_fixture = 50
V_fixture = 0
V_fixture_min = 0
V_fixture_max = 0
114.8ps   734.8mV    686.6mV    845.3mV
159.4ps   734.8mV    686.6mV    748.6mV
246.1ps   715.7mV    686.6mV    327mV
306.1ps   574.2mV    686.6mV    137.8mV
378.2ps   346.1mV    686.6mV    35.52mV
448.1ps   167.1mV    686.6mV    14.16mV
542.7ps   58.68mV    605.6mV    6.206mV
779.1ps   6.936mV    162.8mV    0V
844.3ps   5.837mV    91.17mV    0V
1.345ns   3.052mV    4.091mV    0V
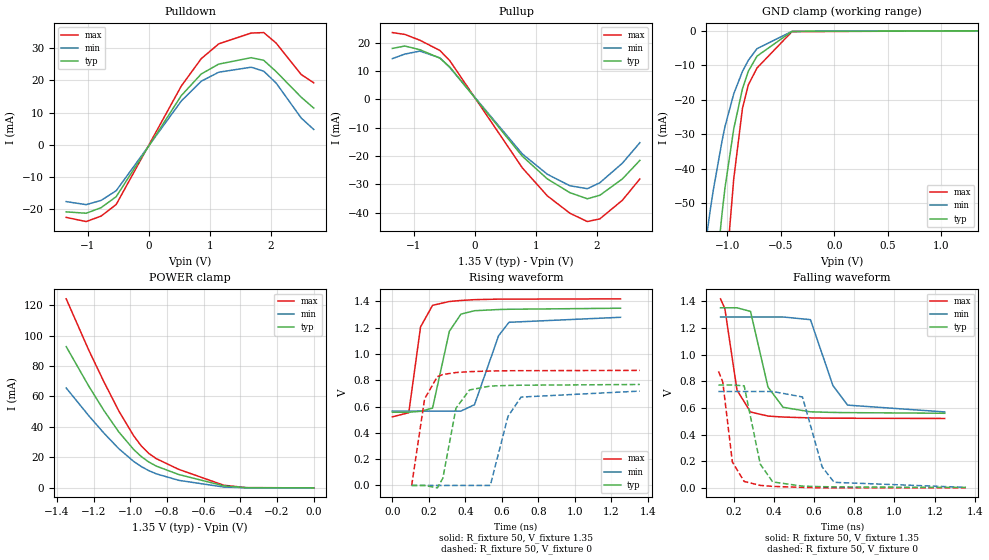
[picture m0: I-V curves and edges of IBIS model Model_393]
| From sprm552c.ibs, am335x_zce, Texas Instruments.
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| Model based on original model for BCSHTLTCSCDVPBFZ_SSDHV
|   Sub model SR00_10MA_5PER_1P35
[model]   Model_393
|[Description]  [1.35V-3-STATE-NOTERM-SR00:10MA, IND, 5%]
|   Fastest slew rate (SR[1:0] = "00"), 0.80 * RExt = 1.250 * Iout
|   (I[2:0] = "101"), 10mA nominal with Rext = 50R,ODT off (ODT[1:0]
|   = "00") CMOS mode,Industrial temperature range (-40C to 125C,
|   25C nominal),5% power supply tolerance
|[Input Load]   NOTERM
|[Output Drive] SR00:10MA
|Voltage   1.35V
|Mode   3-STATE
Model_type   3-state
Polarity   Non-Inverting
Enable   Active-Low
Cref =  15pF
Rref =  100.0000M
Vref =  0V
Vmeas =  0.675
C_comp   1.865048p   1.679967p   1.989968p
[Temperature Range]   25   125   -40
[Voltage Range]   1.35   1.2825   1.4175
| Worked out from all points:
|   slope of the pulldown table from 0 to 0.203 V, typ, clamps not added: 32.4 ohm
|   slope of the pullup table from 0 to 0.203 V, typ, clamps not added: 36 ohm
|   GND clamp passes 1 mA (typ) near -0.49 V on its own axis
|   POWER clamp passes 1 mA (typ) near -0.47 V on its own axis
|   rising waveform, R_fixture 50, V_fixture 1.35: 20-80 % time 70.2ps typ, 105ps min, 50.3ps max; typ from 0.557 V to 1.35 V
|   rising waveform, R_fixture 50, V_fixture 0: 20-80 % time 66ps typ, 78.3ps min, 53.1ps max; typ from 0 V to 0.768 V
|   falling waveform, R_fixture 50, V_fixture 1.35: 20-80 % time 74.6ps typ, 95.4ps min, 56.6ps max; typ from 1.35 V to 0.56 V
|   falling waveform, R_fixture 50, V_fixture 0: 20-80 % time 54.8ps typ, 73ps min, 43.4ps max; typ from 0.771 V to 0.003 V
[POWER_clamp]
-1.35V    92.75mA    65.58mA    124.1mA
-1.227V   66.81mA    47.37mA    90.43mA
-1.145V   50.92mA    36.04mA    69.8mA
-1.064V   36.83mA    25.8mA     50.7mA
-981.8mV  25.17mA    17.34mA    34.14mA
-940.9mV  20.58mA    14.01mA    27.56mA
-900mV    17mA       11.33mA    22.64mA
-859.1mV  14.3mA     9.214mA    19.2mA
-736.4mV  8.769mA    4.942mA    12.14mA
-490.9mV  1.299mA    528.4uA    1.73mA
-368.2mV  117.2uA    50.88uA    117.5uA
0V        1.028nA    11.95nA    1.029nA
[Pulldown]
-1.35V    -20.78mA   -17.6mA    -22.5mA
-1.023V   -21.21mA   -18.54mA   -23.79mA
-777.3mV  -19.46mA   -17.21mA   -22.08mA
-531.8mV  -16.06mA   -14.21mA   -18.48mA
531.8mV   15.27mA    13.6mA     18.23mA
859.1mV   22.01mA    19.76mA    26.76mA
1.145V    25.08mA    22.56mA    31.35mA
1.677V    27.07mA    24.11mA    34.71mA
1.882V    26.25mA    22.88mA    34.86mA
2.086V    22.73mA    19.17mA    31.58mA
2.495V    14.8mA     8.345mA    21.83mA
2.7V      11.43mA    4.787mA    19.28mA
[Pullup]
-1.35V    18mA       14.4mA     23.6mA
-1.145V   18.85mA    16.01mA    22.95mA
-900mV    17.57mA    17.07mA    20.91mA
-572.7mV  14.57mA    14.69mA    17.3mA
-409.1mV  11.45mA    11.25mA    13.66mA
777.3mV   -20.05mA   -19.24mA   -24.16mA
1.186V    -28.05mA   -26.41mA   -34.04mA
1.555V    -32.91mA   -30.47mA   -40.16mA
1.841V    -35.07mA   -31.5mA    -43.11mA
2.045V    -33.83mA   -29.42mA   -42.16mA
2.414V    -28.06mA   -22.5mA    -35.59mA
2.7V      -21.52mA   -15.27mA   -28.07mA
[GND_clamp]
-1.35V    -159.1mA   -94.77mA   -266.2mA
-1.295V   -137.7mA   -81.77mA   -230.9mA
-1.159V   -87.19mA   -51.56mA   -145.9mA
-1.132V   -77.89mA   -46.14mA   -129.9mA
-1.05V    -52.83mA   -31.84mA   -86.44mA
-1.023V   -45.55mA   -27.75mA   -73.68mA
-940.9mV  -28.44mA   -18.28mA   -42.92mA
-859.1mV  -16.79mA   -11.75mA   -22.47mA
-804.5mV  -11.72mA   -8.559mA   -15.69mA
-722.7mV  -7.324mA   -5.162mA   -10.76mA
-395.5mV  -159.1uA   -161.1uA   -232.3uA
1.35V     1.028nA    30.09nA    754.3pA
[Ramp]
dV/dt_f 0.48367133/75.999996p 0.43805471/97.833762p 0.54454417/56.874285p
dV/dt_r 0.47381441/67.474675p 0.44820109/81.059062p 0.53461029/53.417086p
R_load = 50
[Rising Waveform]
R_fixture = 50
V_fixture = 1.35
V_fixture_min = 1.2825
V_fixture_max = 1.4175
0s        556.7mV    565.2mV    521.4mV
90.18ps   556.7mV    565.2mV    553.2mV
154.7ps   563.3mV    565.2mV    1.205V
220.5ps   588.4mV    565.2mV    1.369V
312.3ps   1.171V     565.2mV    1.398V
375.8ps   1.302V     565.2mV    1.406V
450.2ps   1.328V     614.1mV    1.412V
582.1ps   1.337V     1.138V     1.416V
639.2ps   1.339V     1.24V      1.416V
1.25ns    1.347V     1.278V     1.418V
[Rising Waveform]
R_fixture = 50
V_fixture = 0
V_fixture_min = 0
V_fixture_max = 0
105.9ps   0V         0V         0V
176.9ps   0V         0V         658.9mV
246.9ps   -18.06mV   0V         827.4mV
276.7ps   54.71mV    0V         843.2mV
348.7ps   586.9mV    0V         858.2mV
422.5ps   725.8mV    0V         864.8mV
536.6ps   755.7mV    0V         869.8mV
633.8ps   760.1mV    525.7mV    871.8mV
705.3ps   761.8mV    671.8mV    872.2mV
1.356ns   767.5mV    717.2mV    874.5mV
[Falling Waveform]
R_fixture = 50
V_fixture = 1.35
V_fixture_min = 1.2825
V_fixture_max = 1.4175
134.3ps   1.351V     1.282V     1.418V
155.9ps   1.351V     1.282V     1.345V
216.2ps   1.351V     1.282V     734mV
283.6ps   1.324V     1.282V     569mV
370.6ps   755.8mV    1.282V     538.6mV
445.7ps   604.5mV    1.282V     531.3mV
581.8ps   570.4mV    1.262V     524.6mV
693.7ps   565.8mV    767.6mV    522.6mV
766.7ps   564.4mV    620.7mV    522.3mV
1.25ns    559.6mV    569.7mV    520.5mV
[Falling Waveform]
R_fixture = 50
V_fixture = 0
V_fixture_min = 0
V_fixture_max = 0
124ps     771.1mV    722.9mV    874.3mV
145.4ps   771.1mV    722.9mV    795.3mV
193.3ps   771.1mV    722.9mV    194.5mV
251.9ps   765.9mV    722.9mV    47.98mV
332.1ps   178.2mV    722.9mV    18.36mV
394ps     44.39mV    722.9mV    10.98mV
542.1ps   12.92mV    681.9mV    3.387mV
639.9ps   8.869mV    157.6mV    0V
699.9ps   7.504mV    41.32mV    0V
1.356ns   2.652mV    3.459mV    0V
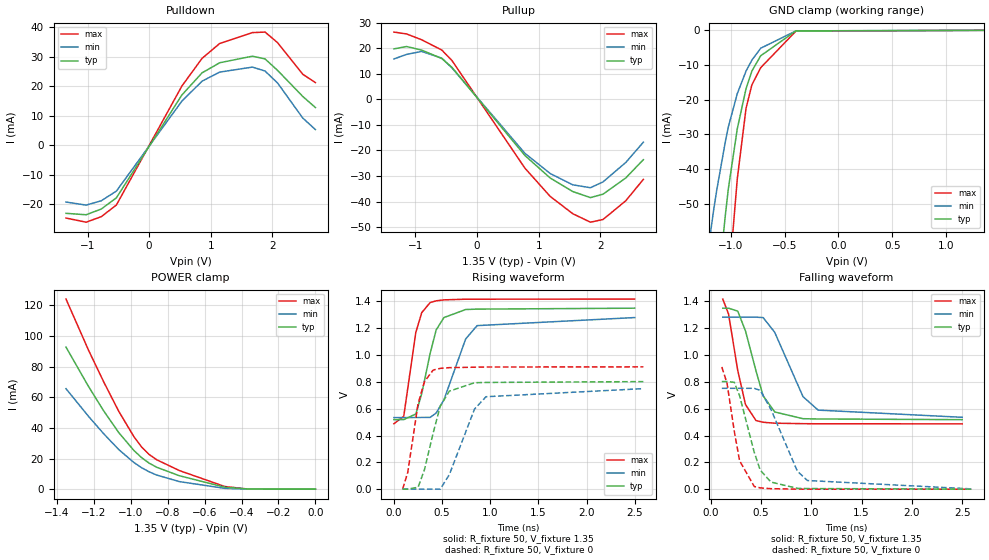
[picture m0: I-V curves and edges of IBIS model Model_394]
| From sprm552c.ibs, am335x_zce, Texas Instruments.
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| Model based on original model for BCSHTLTCSCDVPBFZ_SSDHV
|   Sub model SR10_11MA_5PER_1P35
[model]   Model_394
|[Description]  [1.35V-3-STATE-NOTERM-SR10:11MA, IND, 5%]
|   Fast slew rate (SR[1:0] = "10"), 0.73 * RExt = 1.325 * Iout
|   (I[2:0] = "110"), 11mA nominal with Rext = 50R,ODT off (ODT[1:0]
|   = "00") CMOS mode,Industrial temperature range (-40C to 125C,
|   25C nominal),5% power supply tolerance
|[Input Load]   NOTERM
|[Output Drive] SR10:11MA
|Voltage   1.35V
|Mode   3-STATE
Model_type   3-state
Polarity   Non-Inverting
Enable   Active-Low
Cref =  15pF
Rref =  100.0000M
Vref =  0V
Vmeas =  0.675
C_comp   1.865048p   1.679967p   1.989968p
[Temperature Range]   25   125   -40
[Voltage Range]   1.35   1.2825   1.4175
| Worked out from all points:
|   slope of the pulldown table from 0 to 0.203 V, typ, clamps not added: 29.1 ohm
|   slope of the pullup table from 0 to 0.203 V, typ, clamps not added: 32.8 ohm
|   GND clamp passes 1 mA (typ) near -0.49 V on its own axis
|   POWER clamp passes 1 mA (typ) near -0.47 V on its own axis
|   rising waveform, R_fixture 50, V_fixture 1.35: 20-80 % time 158ps typ, 226ps min, 113ps max; typ from 0.518 V to 1.35 V
|   rising waveform, R_fixture 50, V_fixture 0: 20-80 % time 171ps typ, 237ps min, 124ps max; typ from 0 V to 0.802 V
|   falling waveform, R_fixture 50, V_fixture 1.35: 20-80 % time 184ps typ, 261ps min, 131ps max; typ from 1.35 V to 0.518 V
|   falling waveform, R_fixture 50, V_fixture 0: 20-80 % time 171ps typ, 256ps min, 123ps max; typ from 0.802 V to 0 V
[POWER_clamp]
-1.35V    92.75mA    65.58mA    124.1mA
-1.227V   66.81mA    47.37mA    90.43mA
-1.145V   50.92mA    36.04mA    69.8mA
-1.064V   36.83mA    25.8mA     50.7mA
-981.8mV  25.17mA    17.34mA    34.14mA
-940.9mV  20.58mA    14.01mA    27.56mA
-900mV    17mA       11.33mA    22.64mA
-859.1mV  14.3mA     9.214mA    19.2mA
-736.4mV  8.769mA    4.942mA    12.14mA
-490.9mV  1.299mA    528.4uA    1.73mA
-368.2mV  117.2uA    50.88uA    117.5uA
0V        1.028nA    11.95nA    1.029nA
[Pulldown]
-1.35V    -23.15mA   -19.32mA   -24.75mA
-1.023V   -23.64mA   -20.36mA   -26.16mA
-777.3mV  -21.69mA   -18.89mA   -24.29mA
-531.8mV  -17.89mA   -15.6mA    -20.33mA
531.8mV   17.01mA    14.93mA    20.05mA
859.1mV   24.52mA    21.69mA    29.43mA
1.145V    27.94mA    24.77mA    34.48mA
1.677V    30.17mA    26.47mA    38.18mA
1.882V    29.25mA    25.13mA    38.35mA
2.086V    25.33mA    21.05mA    34.75mA
2.495V    16.49mA    9.165mA    24.02mA
2.7V      12.74mA    5.257mA    21.21mA
[Pullup]
-1.35V    19.75mA    15.81mA    26.32mA
-1.145V   20.68mA    17.58mA    25.6mA
-900mV    19.27mA    18.75mA    23.32mA
-572.7mV  15.97mA    16.13mA    19.29mA
-409.1mV  12.56mA    12.35mA    15.23mA
777.3mV   -21.99mA   -21.12mA   -26.94mA
1.186V    -30.76mA   -29mA      -37.96mA
1.555V    -36.1mA    -33.46mA   -44.78mA
1.841V    -38.46mA   -34.59mA   -48.08mA
2.045V    -37.11mA   -32.31mA   -47.03mA
2.414V    -30.78mA   -24.72mA   -39.71mA
2.7V      -23.61mA   -16.77mA   -31.32mA
[GND_clamp]
-1.35V    -159.1mA   -94.77mA   -266.2mA
-1.295V   -137.7mA   -81.77mA   -230.9mA
-1.159V   -87.19mA   -51.56mA   -145.9mA
-1.132V   -77.89mA   -46.14mA   -129.9mA
-1.05V    -52.83mA   -31.84mA   -86.44mA
-1.023V   -45.55mA   -27.75mA   -73.68mA
-940.9mV  -28.44mA   -18.28mA   -42.92mA
-859.1mV  -16.79mA   -11.75mA   -22.47mA
-804.5mV  -11.72mA   -8.559mA   -15.69mA
-722.7mV  -7.324mA   -5.162mA   -10.76mA
-395.5mV  -159.1uA   -161.1uA   -232.3uA
1.35V     1.028nA    30.09nA    754.3pA
[Ramp]
dV/dt_f 0.50123795/0.18534041n 0.45183522/0.26376585n 0.55970346/0.13109601n
dV/dt_r 0.48439204/0.17225302n 0.45496845/0.23987275n 0.54950541/0.12449979n
R_load = 50
[Rising Waveform]
R_fixture = 50
V_fixture = 1.35
V_fixture_min = 1.2825
V_fixture_max = 1.4175
0s        518.3mV    533.8mV    487.9mV
102.2ps   519mV      533.8mV    543.6mV
227.3ps   560.7mV    534.4mV    1.169V
289.2ps   713.4mV    534.9mV    1.317V
376.2ps   1.013V     535.1mV    1.392V
438.8ps   1.188V     568mV      1.405V
519.3ps   1.28V      666.5mV    1.412V
744.8ps   1.34V      1.12V      1.417V
863.8ps   1.343V     1.22V      1.417V
2.5ns     1.35V      1.28V      1.418V
[Rising Waveform]
R_fixture = 50
V_fixture = 0
V_fixture_min = 0
V_fixture_max = 0
90.34ps   0V         0V         0V
143.5ps   0V         0V         124.5mV
251.2ps   14.62mV    0V         638.1mV
316.7ps   144.3mV    0V         801.6mV
407.5ps   418.8mV    0V         888.3mV
481.2ps   619.2mV    0V         901.2mV
575.4ps   731mV      108.3mV    906.4mV
837ps     794mV      597.6mV    909.8mV
956.2ps   796mV      689.5mV    911.2mV
2.59ns    802.3mV    749.9mV    912.2mV
[Falling Waveform]
R_fixture = 50
V_fixture = 1.35
V_fixture_min = 1.2825
V_fixture_max = 1.4175
120.1ps   1.349V     1.282V     1.417V
177.5ps   1.349V     1.282V     1.305V
268.4ps   1.327V     1.282V     885.6mV
345.5ps   1.18V      1.282V     631.2mV
450.3ps   881.3mV    1.282V     511.4mV
521ps     695.8mV    1.279V     498.6mV
636.1ps   575.5mV    1.169V     491.8mV
917.4ps   525.3mV    689.5mV    488.2mV
1.068ns   523.2mV    589.2mV    487.3mV
2.5ns     518.1mV    535.7mV    486.9mV
[Falling Waveform]
R_fixture = 50
V_fixture = 0
V_fixture_min = 0
V_fixture_max = 0
110.5ps   802.2mV    751.8mV    911.2mV
162.5ps   802.2mV    751.8mV    788mV
235ps     796.2mV    751.8mV    428.5mV
287ps     696.8mV    751.8mV    211.6mV
432.7ps   274.3mV    751.8mV    19.92mV
492.5ps   141.5mV    736.2mV    9.555mV
598.8ps   52.98mV    594.2mV    3.709mV
861.4ps   6.087mV    133.9mV    0V
960.6ps   4.666mV    64.58mV    0V
2.59ns    0V         2.09mV     0V
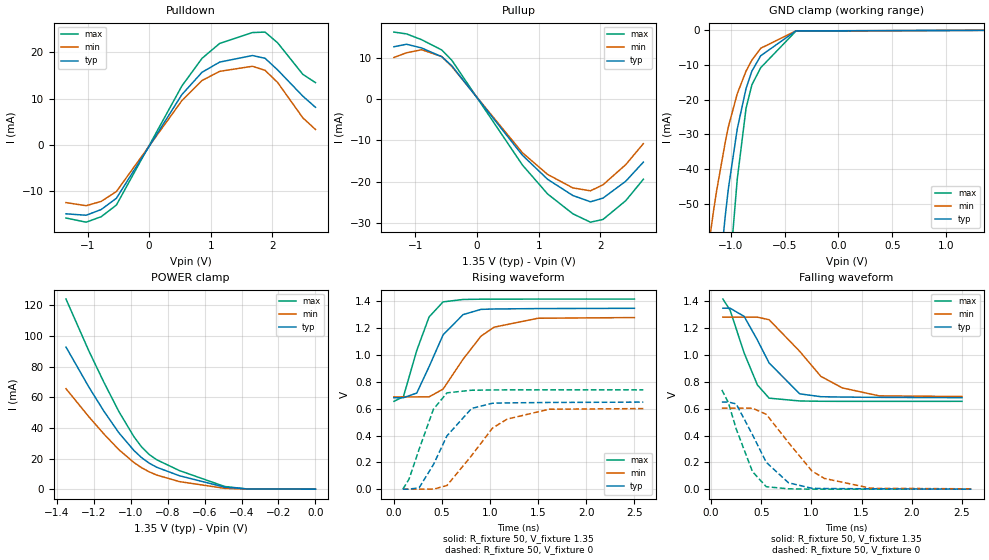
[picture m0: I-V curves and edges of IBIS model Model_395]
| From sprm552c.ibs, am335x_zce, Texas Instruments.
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| Model based on original model for BCSHTLTCSCDVPBFZ_SSDHV
|   Sub model SR11_7MA_5PER_1P35
[model]   Model_395
|[Description]  [1.35V-3-STATE-NOTERM-SR11:7MA, IND, 5%]
|   Slowest slew rate (SR[1:0] = "11"), 1.14 * RExt = 0.875 * Iout
|   (I[2:0] = "010"), 7mA nominal with Rext = 50R,ODT off (ODT[1:0]
|   = "00") CMOS mode,Industrial temperature range (-40C to 125C,
|   25C nominal),5% power supply tolerance
|[Input Load]   NOTERM
|[Output Drive] SR11:7MA
|Voltage   1.35V
|Mode   3-STATE
Model_type   3-state
Polarity   Non-Inverting
Enable   Active-Low
Cref =  15pF
Rref =  100.0000M
Vref =  0V
Vmeas =  0.675
C_comp   1.865048p   1.679967p   1.989968p
[Temperature Range]   25   125   -40
[Voltage Range]   1.35   1.2825   1.4175
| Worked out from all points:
|   slope of the pulldown table from 0 to 0.203 V, typ, clamps not added: 45.3 ohm
|   slope of the pullup table from 0 to 0.203 V, typ, clamps not added: 50.7 ohm
|   GND clamp passes 1 mA (typ) near -0.49 V on its own axis
|   POWER clamp passes 1 mA (typ) near -0.47 V on its own axis
|   rising waveform, R_fixture 50, V_fixture 1.35: 20-80 % time 268ps typ, 367ps min, 198ps max; typ from 0.682 V to 1.35 V
|   rising waveform, R_fixture 50, V_fixture 0: 20-80 % time 304ps typ, 399ps min, 213ps max; typ from 0 V to 0.649 V
|   falling waveform, R_fixture 50, V_fixture 1.35: 20-80 % time 311ps typ, 426ps min, 216ps max; typ from 1.35 V to 0.682 V
|   falling waveform, R_fixture 50, V_fixture 0: 20-80 % time 290ps typ, 387ps min, 208ps max; typ from 0.649 V to 0 V
[POWER_clamp]
-1.35V    92.75mA    65.58mA    124.1mA
-1.227V   66.81mA    47.37mA    90.43mA
-1.145V   50.92mA    36.04mA    69.8mA
-1.064V   36.83mA    25.8mA     50.7mA
-981.8mV  25.17mA    17.34mA    34.14mA
-940.9mV  20.58mA    14.01mA    27.56mA
-900mV    17mA       11.33mA    22.64mA
-859.1mV  14.3mA     9.214mA    19.2mA
-736.4mV  8.769mA    4.942mA    12.14mA
-490.9mV  1.299mA    528.4uA    1.73mA
-368.2mV  117.2uA    50.88uA    117.5uA
0V        1.028nA    11.95nA    1.029nA
[Pulldown]
-1.35V    -14.84mA   -12.42mA   -15.75mA
-1.023V   -15.15mA   -13.09mA   -16.65mA
-777.3mV  -13.91mA   -12.15mA   -15.46mA
-531.8mV  -11.48mA   -10.03mA   -12.95mA
531.8mV   10.91mA    9.608mA    12.77mA
859.1mV   15.73mA    13.95mA    18.74mA
1.145V    17.92mA    15.92mA    21.95mA
1.677V    19.34mA    17.02mA    24.3mA
1.882V    18.74mA    16.14mA    24.4mA
2.086V    16.23mA    13.52mA    22.09mA
2.495V    10.57mA    5.887mA    15.28mA
2.7V      8.16mA     3.378mA    13.49mA
[Pullup]
-1.35V    12.77mA    10.16mA    16.33mA
-1.145V   13.38mA    11.3mA     15.89mA
-900mV    12.47mA    12.05mA    14.48mA
-572.7mV  10.34mA    10.38mA    11.98mA
-409.1mV  8.134mA    7.949mA    9.466mA
736.4mV   -13.58mA   -12.98mA   -15.96mA
1.145V    -19.43mA   -18.24mA   -22.99mA
1.555V    -23.37mA   -21.52mA   -27.81mA
1.841V    -24.89mA   -22.23mA   -29.85mA
2.045V    -24mA      -20.76mA   -29.18mA
2.414V    -19.9mA    -15.87mA   -24.63mA
2.7V      -15.26mA   -10.77mA   -19.42mA
[GND_clamp]
-1.35V    -159.1mA   -94.77mA   -266.2mA
-1.295V   -137.7mA   -81.77mA   -230.9mA
-1.159V   -87.19mA   -51.56mA   -145.9mA
-1.132V   -77.89mA   -46.14mA   -129.9mA
-1.05V    -52.83mA   -31.84mA   -86.44mA
-1.023V   -45.55mA   -27.75mA   -73.68mA
-940.9mV  -28.44mA   -18.28mA   -42.92mA
-859.1mV  -16.79mA   -11.75mA   -22.47mA
-804.5mV  -11.72mA   -8.559mA   -15.69mA
-722.7mV  -7.324mA   -5.162mA   -10.76mA
-395.5mV  -159.1uA   -161.1uA   -232.3uA
1.35V     1.028nA    30.09nA    754.3pA
[Ramp]
dV/dt_f  0.4025069/0.31293864n 0.35870568/0.43219917n 0.45875085/0.21679257n
dV/dt_r 0.39166152/0.30573417n 0.36499418/0.40593304n 0.44595062/0.21405753n
R_load = 50
[Rising Waveform]
R_fixture = 50
V_fixture = 1.35
V_fixture_min = 1.2825
V_fixture_max = 1.4175
0s        682mV      688.2mV    655.4mV
98.73ps   682.2mV    688.2mV    689.4mV
237.1ps   716.6mV    688.2mV    1.034V
365.8ps   914mV      688.6mV    1.285V
511.2ps   1.151V     746.5mV    1.397V
718.9ps   1.302V     969.4mV    1.415V
904.8ps   1.341V     1.141V     1.417V
1.04ns    1.344V     1.208V     1.417V
1.498ns   1.347V     1.275V     1.418V
2.5ns     1.349V     1.28V      1.418V
[Rising Waveform]
R_fixture = 50
V_fixture = 0
V_fixture_min = 0
V_fixture_max = 0
92.96ps   0V         0V         0V
156.8ps   0V         0V         74.55mV
262ps     10.45mV    0V         297.2mV
410.7ps   183.1mV    0V         596.4mV
551ps     397.3mV    26.99mV    718.3mV
807ps     601.8mV    250mV      737.9mV
1.025ns   641.1mV    455.7mV    740.1mV
1.177ns   643.6mV    522.7mV    740.6mV
1.614ns   646.7mV    596.2mV    741mV
2.593ns   649.3mV    601.1mV    741mV
[Falling Waveform]
R_fixture = 50
V_fixture = 1.35
V_fixture_min = 1.2825
V_fixture_max = 1.4175
118.2ps   1.349V     1.282V     1.417V
189.2ps   1.349V     1.282V     1.335V
329.8ps   1.288V     1.282V     1.015V
461.5ps   1.112V     1.282V     777.2mV
578.7ps   940.1mV    1.263V     678.3mV
883.8ps   710.5mV    1.027V     657.4mV
1.094ns   689.2mV    841mV      655.1mV
1.308ns   686.5mV    754.7mV    654.6mV
1.675ns   684.2mV    695.5mV    654.4mV
2.5ns     682mV      690.6mV    654.8mV
[Falling Waveform]
R_fixture = 50
V_fixture = 0
V_fixture_min = 0
V_fixture_max = 0
107.4ps   649.3mV    603.6mV    740.1mV
173.3ps   649.3mV    603.6mV    644.2mV
250.2ps   635.6mV    603.6mV    449.7mV
412.6ps   406.2mV    603.6mV    131.1mV
550.1ps   199.8mV    558mV      18.29mV
771.7ps   47.58mV    347.3mV    2.436mV
1.006ns   6.335mV    134.6mV    0V
1.129ns   4.802mV    80.07mV    0V
1.593ns   2.627mV    6.749mV    0V
2.593ns   0V         2.537mV    0V
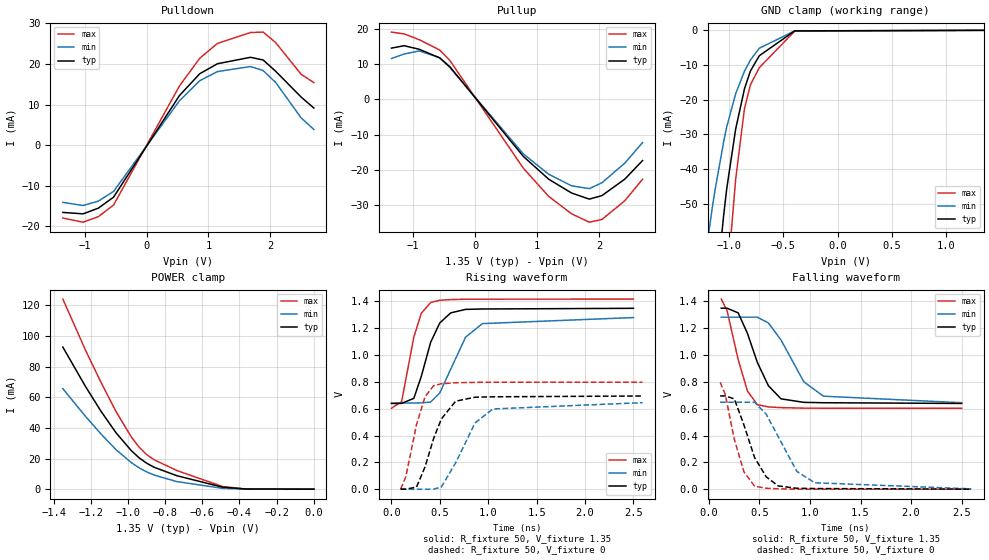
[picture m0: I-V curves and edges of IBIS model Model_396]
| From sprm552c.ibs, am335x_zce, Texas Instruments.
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| Model based on original model for BCSHTLTCSCDVPBFZ_SSDHV
|   Sub model SR10_8MA_5PER_1P35
[model]   Model_396
|[Description]  [1.35V-3-STATE-NOTERM-SR10:8MA, IND, 5%]
|   Fast slew rate (SR[1:0] = "10"), 1.00 * RExt = 1.000 * Iout
|   (I[2:0] = "011"), 8mA nominal with Rext = 50R,ODT off (ODT[1:0]
|   = "00") CMOS mode,Industrial temperature range (-40C to 125C,
|   25C nominal),5% power supply tolerance
|[Input Load]   NOTERM
|[Output Drive] SR10:8MA
|Voltage   1.35V
|Mode   3-STATE
Model_type   3-state
Polarity   Non-Inverting
Enable   Active-Low
Cref =  15pF
Rref =  100.0000M
Vref =  0V
Vmeas =  0.675
C_comp   1.865048p   1.679967p   1.989968p
[Temperature Range]   25   125   -40
[Voltage Range]   1.35   1.2825   1.4175
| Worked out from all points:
|   slope of the pulldown table from 0 to 0.203 V, typ, clamps not added: 40.4 ohm
|   slope of the pullup table from 0 to 0.203 V, typ, clamps not added: 44.6 ohm
|   GND clamp passes 1 mA (typ) near -0.49 V on its own axis
|   POWER clamp passes 1 mA (typ) near -0.47 V on its own axis
|   rising waveform, R_fixture 50, V_fixture 1.35: 20-80 % time 188ps typ, 254ps min, 137ps max; typ from 0.639 V to 1.35 V
|   rising waveform, R_fixture 50, V_fixture 0: 20-80 % time 207ps typ, 270ps min, 149ps max; typ from 0 V to 0.695 V
|   falling waveform, R_fixture 50, V_fixture 1.35: 20-80 % time 223ps typ, 297ps min, 157ps max; typ from 1.35 V to 0.639 V
|   falling waveform, R_fixture 50, V_fixture 0: 20-80 % time 205ps typ, 273ps min, 149ps max; typ from 0.695 V to 0 V
[POWER_clamp]
-1.35V    92.75mA    65.58mA    124.1mA
-1.227V   66.81mA    47.37mA    90.43mA
-1.145V   50.92mA    36.04mA    69.8mA
-1.064V   36.83mA    25.8mA     50.7mA
-981.8mV  25.17mA    17.34mA    34.14mA
-940.9mV  20.58mA    14.01mA    27.56mA
-900mV    17mA       11.33mA    22.64mA
-859.1mV  14.3mA     9.214mA    19.2mA
-736.4mV  8.769mA    4.942mA    12.14mA
-490.9mV  1.299mA    528.4uA    1.73mA
-368.2mV  117.2uA    50.88uA    117.5uA
0V        1.028nA    11.95nA    1.029nA
[Pulldown]
-1.35V    -16.62mA   -14.14mA   -18mA
-1.023V   -16.97mA   -14.91mA   -19.03mA
-777.3mV  -15.57mA   -13.84mA   -17.67mA
-531.8mV  -12.85mA   -11.43mA   -14.79mA
531.8mV   12.22mA    10.94mA    14.59mA
859.1mV   17.61mA    15.89mA    21.42mA
1.145V    20.07mA    18.14mA    25.09mA
1.677V    21.66mA    19.38mA    27.77mA
1.882V    20.99mA    18.39mA    27.88mA
2.086V    18.18mA    15.4mA     25.25mA
2.495V    11.84mA    6.706mA    17.46mA
2.7V      9.141mA    3.847mA    15.42mA
[Pullup]
-1.35V    14.52mA    11.57mA    19.06mA
-1.145V   15.2mA     12.87mA    18.54mA
-900mV    14.17mA    13.73mA    16.89mA
-572.7mV  11.75mA    11.81mA    13.97mA
-409.1mV  9.241mA    9.051mA    11.04mA
777.3mV   -16.18mA   -15.47mA   -19.53mA
1.186V    -22.63mA   -21.24mA   -27.5mA
1.555V    -26.55mA   -24.5mA    -32.44mA
1.841V    -28.28mA   -25.32mA   -34.82mA
2.045V    -27.28mA   -23.65mA   -34.05mA
2.414V    -22.62mA   -18.08mA   -28.74mA
2.7V      -17.35mA   -12.27mA   -22.66mA
[GND_clamp]
-1.35V    -159.1mA   -94.77mA   -266.2mA
-1.295V   -137.7mA   -81.77mA   -230.9mA
-1.159V   -87.19mA   -51.56mA   -145.9mA
-1.132V   -77.89mA   -46.14mA   -129.9mA
-1.05V    -52.83mA   -31.84mA   -86.44mA
-1.023V   -45.55mA   -27.75mA   -73.68mA
-940.9mV  -28.44mA   -18.28mA   -42.92mA
-859.1mV  -16.79mA   -11.75mA   -22.47mA
-804.5mV  -11.72mA   -8.559mA   -15.69mA
-722.7mV  -7.324mA   -5.162mA   -10.76mA
-395.5mV  -159.1uA   -161.1uA   -232.3uA
1.35V     1.028nA    30.09nA    754.3pA
[Ramp]
dV/dt_f 0.42838242/0.22397364n 0.38642073/0.30117956n 0.48974888/0.15756169n
dV/dt_r 0.41928036/0.20840953n 0.39170777/0.27423858n 0.48042824/0.14903649n
R_load = 50
[Rising Waveform]
R_fixture = 50
V_fixture = 1.35
V_fixture_min = 1.2825
V_fixture_max = 1.4175
0s        639mV      642.1mV    603.9mV
104.6ps   639.8mV    642.1mV    652.6mV
230.9ps   677.6mV    642.7mV    1.135V
308.2ps   841.9mV    643.8mV    1.312V
404.3ps   1.095V     649.5mV    1.392V
498.9ps   1.24V      718.1mV    1.409V
612.1ps   1.315V     895.1mV    1.414V
765.6ps   1.341V     1.134V     1.417V
939.9ps   1.344V     1.235V     1.417V
2.5ns     1.349V     1.28V      1.418V
[Rising Waveform]
R_fixture = 50
V_fixture = 0
V_fixture_min = 0
V_fixture_max = 0
94.35ps   0V         0V         0V
148.2ps   0V         0V         92.81mV
258.7ps   15.67mV    0V         482mV
346.9ps   166.8mV    0V         690.4mV
436.3ps   380.4mV    0V         772.4mV
515ps     523.6mV    16.48mV    786mV
662.8ps   656.1mV    196.2mV    793.5mV
863.2ps   686mV      494mV      796.6mV
1.048ns   688.9mV    598.3mV    797.5mV
2.594ns   694.9mV    645.4mV    798mV
[Falling Waveform]
R_fixture = 50
V_fixture = 1.35
V_fixture_min = 1.2825
V_fixture_max = 1.4175
123ps     1.349V     1.282V     1.417V
180ps     1.349V     1.282V     1.331V
289.8ps   1.314V     1.282V     966.4mV
381.2ps   1.162V     1.282V     732.1mV
479.5ps   944.9mV    1.282V     629.6mV
588.2ps   771.4mV    1.239V     613.1mV
713.5ps   673.3mV    1.112V     607.7mV
939.8ps   647mV      799.6mV    604mV
1.133ns   644.3mV    693mV      603.6mV
2.5ns     638.9mV    644.4mV    602.9mV
[Falling Waveform]
R_fixture = 50
V_fixture = 0
V_fixture_min = 0
V_fixture_max = 0
111.8ps   694.9mV    647.8mV    797.2mV
163.1ps   694.9mV    647.8mV    704.5mV
251.7ps   673mV      647.8mV    371.3mV
345.6ps   482mV      647.8mV    130.7mV
451.9ps   235.7mV    647.8mV    22.71mV
567.6ps   91.79mV    557.9mV    6.701mV
685.9ps   24.21mV    390.9mV    2.76mV
870.8ps   6.515mV    131.9mV    0V
1.047ns   4.655mV    47.58mV    0V
2.594ns   0V         2.444mV    0V
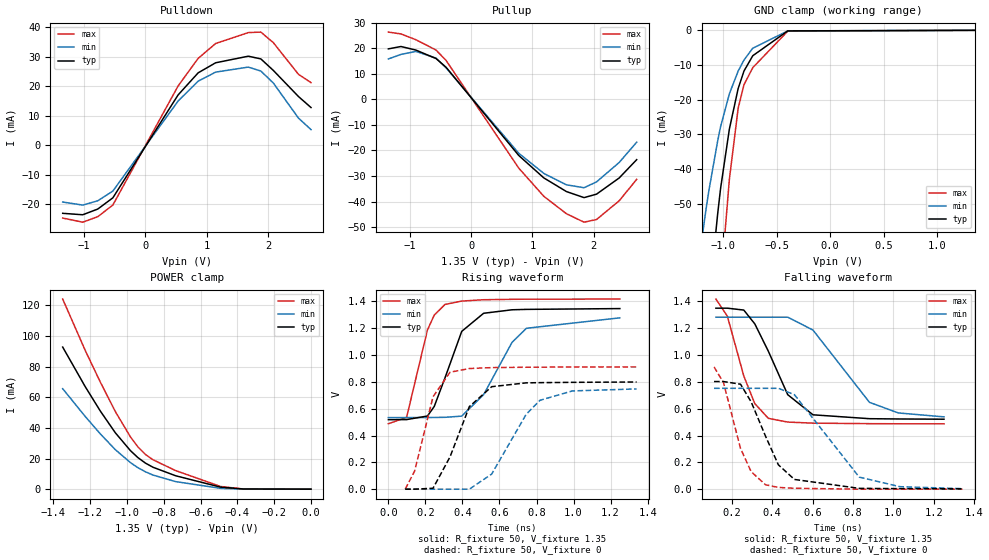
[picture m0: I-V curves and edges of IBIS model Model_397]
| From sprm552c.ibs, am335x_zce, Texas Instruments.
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| Model based on original model for BCSHTLTCSCDVPBFZ_SSDHV
|   Sub model SR01_11MA_5PER_1P35
[model]   Model_397
|[Description]  [1.35V-3-STATE-NOTERM-SR01:11MA, IND, 5%]
|   Slow slew rate (SR[1:0] = "01"), 0.73 * RExt = 1.325 * Iout
|   (I[2:0] = "110"), 11mA nominal with Rext = 50R,ODT off (ODT[1:0]
|   = "00") CMOS mode,Industrial temperature range (-40C to 125C,
|   25C nominal),5% power supply tolerance
|[Input Load]   NOTERM
|[Output Drive] SR01:11MA
|Voltage   1.35V
|Mode   3-STATE
Model_type   3-state
Polarity   Non-Inverting
Enable   Active-Low
Cref =  15pF
Rref =  100.0000M
Vref =  0V
Vmeas =  0.675
C_comp   1.865048p   1.679967p   1.989968p
[Temperature Range]   25   125   -40
[Voltage Range]   1.35   1.2825   1.4175
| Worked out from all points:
|   slope of the pulldown table from 0 to 0.203 V, typ, clamps not added: 29.1 ohm
|   slope of the pullup table from 0 to 0.203 V, typ, clamps not added: 32.8 ohm
|   GND clamp passes 1 mA (typ) near -0.49 V on its own axis
|   POWER clamp passes 1 mA (typ) near -0.47 V on its own axis
|   rising waveform, R_fixture 50, V_fixture 1.35: 20-80 % time 129ps typ, 181ps min, 94.1ps max; typ from 0.518 V to 1.35 V
|   rising waveform, R_fixture 50, V_fixture 0: 20-80 % time 139ps typ, 190ps min, 102ps max; typ from 0 V to 0.799 V
|   falling waveform, R_fixture 50, V_fixture 1.35: 20-80 % time 153ps typ, 215ps min, 110ps max; typ from 1.35 V to 0.521 V
|   falling waveform, R_fixture 50, V_fixture 0: 20-80 % time 141ps typ, 208ps min, 103ps max; typ from 0.802 V to 0.003 V
[POWER_clamp]
-1.35V    92.75mA    65.58mA    124.1mA
-1.227V   66.81mA    47.37mA    90.43mA
-1.145V   50.92mA    36.04mA    69.8mA
-1.064V   36.83mA    25.8mA     50.7mA
-981.8mV  25.17mA    17.34mA    34.14mA
-940.9mV  20.58mA    14.01mA    27.56mA
-900mV    17mA       11.33mA    22.64mA
-859.1mV  14.3mA     9.214mA    19.2mA
-736.4mV  8.769mA    4.942mA    12.14mA
-490.9mV  1.299mA    528.4uA    1.73mA
-368.2mV  117.2uA    50.88uA    117.5uA
0V        1.028nA    11.95nA    1.029nA
[Pulldown]
-1.35V    -23.15mA   -19.32mA   -24.75mA
-1.023V   -23.64mA   -20.36mA   -26.16mA
-777.3mV  -21.69mA   -18.89mA   -24.29mA
-531.8mV  -17.89mA   -15.6mA    -20.33mA
531.8mV   17.01mA    14.93mA    20.05mA
859.1mV   24.52mA    21.69mA    29.43mA
1.145V    27.94mA    24.77mA    34.48mA
1.677V    30.17mA    26.47mA    38.18mA
1.882V    29.25mA    25.13mA    38.35mA
2.086V    25.33mA    21.05mA    34.75mA
2.495V    16.49mA    9.165mA    24.02mA
2.7V      12.74mA    5.257mA    21.21mA
[Pullup]
-1.35V    19.75mA    15.81mA    26.32mA
-1.145V   20.68mA    17.58mA    25.6mA
-900mV    19.27mA    18.75mA    23.32mA
-572.7mV  15.97mA    16.13mA    19.29mA
-409.1mV  12.56mA    12.35mA    15.23mA
777.3mV   -21.99mA   -21.12mA   -26.94mA
1.186V    -30.76mA   -29mA      -37.96mA
1.555V    -36.1mA    -33.46mA   -44.78mA
1.841V    -38.46mA   -34.59mA   -48.08mA
2.045V    -37.11mA   -32.31mA   -47.03mA
2.414V    -30.78mA   -24.72mA   -39.71mA
2.7V      -23.61mA   -16.77mA   -31.32mA
[GND_clamp]
-1.35V    -159.1mA   -94.77mA   -266.2mA
-1.295V   -137.7mA   -81.77mA   -230.9mA
-1.159V   -87.19mA   -51.56mA   -145.9mA
-1.132V   -77.89mA   -46.14mA   -129.9mA
-1.05V    -52.83mA   -31.84mA   -86.44mA
-1.023V   -45.55mA   -27.75mA   -73.68mA
-940.9mV  -28.44mA   -18.28mA   -42.92mA
-859.1mV  -16.79mA   -11.75mA   -22.47mA
-804.5mV  -11.72mA   -8.559mA   -15.69mA
-722.7mV  -7.324mA   -5.162mA   -10.76mA
-395.5mV  -159.1uA   -161.1uA   -232.3uA
1.35V     1.028nA    30.09nA    754.3pA
[Ramp]
dV/dt_f 0.50134307/0.15508573n 0.45178705/0.2192785n 0.55983265/0.11018957n
dV/dt_r 0.48465486/0.14088291n 0.45508958/0.19299722n 0.54974184/0.10245678n
R_load = 50
[Rising Waveform]
R_fixture = 50
V_fixture = 1.35
V_fixture_min = 1.2825
V_fixture_max = 1.4175
0s        518.3mV    533.8mV    487.9mV
98.66ps   519mV      533.8mV    536.3mV
211.1ps   545.8mV    534.2mV    1.188V
247.7ps   616.8mV    535mV      1.298V
306.1ps   831.4mV    535.9mV    1.378V
396.2ps   1.177V     544.9mV    1.403V
514.3ps   1.312V     704.9mV    1.413V
667.8ps   1.338V     1.095V     1.416V
745.4ps   1.341V     1.2V       1.417V
1.25ns    1.347V     1.278V     1.418V
[Rising Waveform]
R_fixture = 50
V_fixture = 0
V_fixture_min = 0
V_fixture_max = 0
90.88ps   0V         0V         0V
141.4ps   0V         0V         134mV
241.2ps   6.801mV    0V         689.4mV
332.8ps   240.4mV    0V         872.1mV
437.3ps   615.8mV    0V         899.9mV
558ps     764.5mV    112.6mV    906.7mV
744.1ps   792.9mV    558.1mV    909.5mV
818.6ps   794.5mV    662.8mV    909.9mV
993.6ps   796.8mV    732.8mV    911.6mV
1.341ns   799.3mV    747.7mV    912.1mV
[Falling Waveform]
R_fixture = 50
V_fixture = 1.35
V_fixture_min = 1.2825
V_fixture_max = 1.4175
121.4ps   1.349V     1.282V     1.417V
178.2ps   1.349V     1.282V     1.289V
259.4ps   1.335V     1.282V     843.3mV
313.9ps   1.232V     1.282V     637.7mV
381ps     1.028V     1.282V     527.8mV
476.8ps   704.1mV    1.282V     500.1mV
601.7ps   554.3mV    1.186V     492.1mV
881.3ps   525.3mV    647.2mV    488.3mV
1.024ns   523.2mV    568.2mV    487.4mV
1.25ns    521.5mV    538.9mV    487mV
[Falling Waveform]
R_fixture = 50
V_fixture = 0
V_fixture_min = 0
V_fixture_max = 0
112.2ps   802.1mV    751.8mV    911.2mV
159.2ps   802.1mV    751.8mV    793.5mV
243.3ps   782.4mV    751.8mV    303mV
295.9ps   650.5mV    751.8mV    130.3mV
366.8ps   395.6mV    751.8mV    32.95mV
430.5ps   181.7mV    751.8mV    13.03mV
510.1ps   72.41mV    704mV      6.601mV
830.6ps   5.997mV    89.8mV     0V
1.032ns   3.881mV    18.49mV    0V
1.341ns   2.691mV    3.977mV    0V
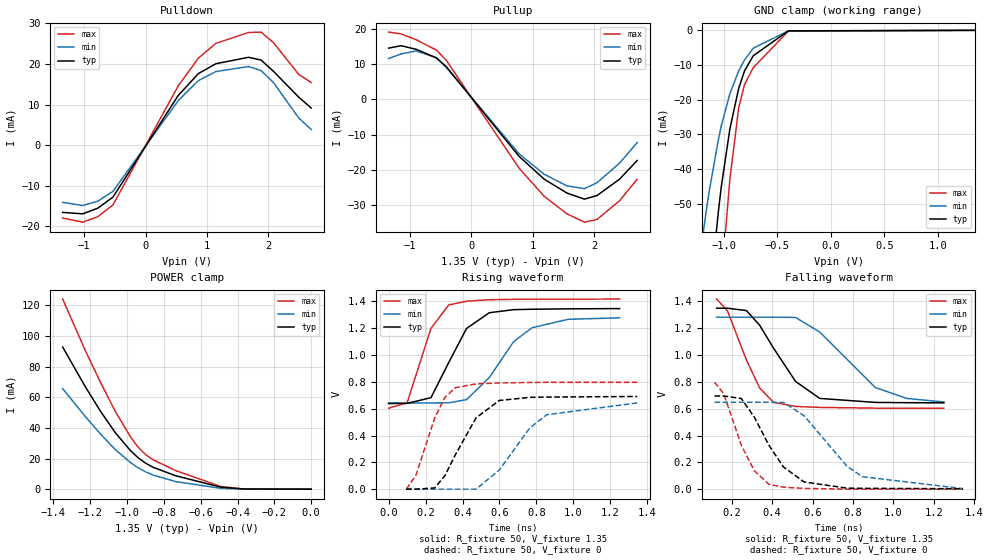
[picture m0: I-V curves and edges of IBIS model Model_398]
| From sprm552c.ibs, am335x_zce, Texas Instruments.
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| Model based on original model for BCSHTLTCSCDVPBFZ_SSDHV
|   Sub model SR01_8MA_5PER_1P35
[model]   Model_398
|[Description]  [1.35V-3-STATE-NOTERM-SR01:8MA, IND, 5%]
|   Slow slew rate (SR[1:0] = "01"), 1.00 * RExt = 1.000 * Iout
|   (I[2:0] = "011"), 8mA nominal with Rext = 50R,ODT off (ODT[1:0]
|   = "00") CMOS mode,Industrial temperature range (-40C to 125C,
|   25C nominal),5% power supply tolerance
|[Input Load]   NOTERM
|[Output Drive] SR01:8MA
|Voltage   1.35V
|Mode   3-STATE
Model_type   3-state
Polarity   Non-Inverting
Enable   Active-Low
Cref =  15pF
Rref =  100.0000M
Vref =  0V
Vmeas =  0.675
C_comp   1.865048p   1.679967p   1.989968p
[Temperature Range]   25   125   -40
[Voltage Range]   1.35   1.2825   1.4175
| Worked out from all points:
|   slope of the pulldown table from 0 to 0.203 V, typ, clamps not added: 40.4 ohm
|   slope of the pullup table from 0 to 0.203 V, typ, clamps not added: 44.6 ohm
|   GND clamp passes 1 mA (typ) near -0.49 V on its own axis
|   POWER clamp passes 1 mA (typ) near -0.47 V on its own axis
|   rising waveform, R_fixture 50, V_fixture 1.35: 20-80 % time 153ps typ, 205ps min, 114ps max; typ from 0.639 V to 1.35 V
|   rising waveform, R_fixture 50, V_fixture 0: 20-80 % time 166ps typ, 217ps min, 122ps max; typ from 0 V to 0.691 V
|   falling waveform, R_fixture 50, V_fixture 1.35: 20-80 % time 183ps typ, 242ps min, 132ps max; typ from 1.35 V to 0.643 V
|   falling waveform, R_fixture 50, V_fixture 0: 20-80 % time 168ps typ, 223ps min, 124ps max; typ from 0.695 V to 0.003 V
[POWER_clamp]
-1.35V    92.75mA    65.58mA    124.1mA
-1.227V   66.81mA    47.37mA    90.43mA
-1.145V   50.92mA    36.04mA    69.8mA
-1.064V   36.83mA    25.8mA     50.7mA
-981.8mV  25.17mA    17.34mA    34.14mA
-940.9mV  20.58mA    14.01mA    27.56mA
-900mV    17mA       11.33mA    22.64mA
-859.1mV  14.3mA     9.214mA    19.2mA
-736.4mV  8.769mA    4.942mA    12.14mA
-490.9mV  1.299mA    528.4uA    1.73mA
-368.2mV  117.2uA    50.88uA    117.5uA
0V        1.028nA    11.95nA    1.029nA
[Pulldown]
-1.35V    -16.62mA   -14.14mA   -18mA
-1.023V   -16.97mA   -14.91mA   -19.03mA
-777.3mV  -15.57mA   -13.84mA   -17.67mA
-531.8mV  -12.85mA   -11.43mA   -14.79mA
531.8mV   12.22mA    10.94mA    14.59mA
859.1mV   17.61mA    15.89mA    21.42mA
1.145V    20.07mA    18.14mA    25.09mA
1.677V    21.66mA    19.38mA    27.77mA
1.882V    20.99mA    18.39mA    27.88mA
2.086V    18.18mA    15.4mA     25.25mA
2.495V    11.84mA    6.706mA    17.46mA
2.7V      9.141mA    3.847mA    15.42mA
[Pullup]
-1.35V    14.52mA    11.57mA    19.06mA
-1.145V   15.2mA     12.87mA    18.54mA
-900mV    14.17mA    13.73mA    16.89mA
-572.7mV  11.75mA    11.81mA    13.97mA
-409.1mV  9.241mA    9.051mA    11.04mA
777.3mV   -16.18mA   -15.47mA   -19.53mA
1.186V    -22.63mA   -21.24mA   -27.5mA
1.555V    -26.55mA   -24.5mA    -32.44mA
1.841V    -28.28mA   -25.32mA   -34.82mA
2.045V    -27.28mA   -23.65mA   -34.05mA
2.414V    -22.62mA   -18.08mA   -28.74mA
2.7V      -17.35mA   -12.27mA   -22.66mA
[GND_clamp]
-1.35V    -159.1mA   -94.77mA   -266.2mA
-1.295V   -137.7mA   -81.77mA   -230.9mA
-1.159V   -87.19mA   -51.56mA   -145.9mA
-1.132V   -77.89mA   -46.14mA   -129.9mA
-1.05V    -52.83mA   -31.84mA   -86.44mA
-1.023V   -45.55mA   -27.75mA   -73.68mA
-940.9mV  -28.44mA   -18.28mA   -42.92mA
-859.1mV  -16.79mA   -11.75mA   -22.47mA
-804.5mV  -11.72mA   -8.559mA   -15.69mA
-722.7mV  -7.324mA   -5.162mA   -10.76mA
-395.5mV  -159.1uA   -161.1uA   -232.3uA
1.35V     1.028nA    30.09nA    754.3pA
[Ramp]
dV/dt_f 0.42847759/0.18591287n 0.38636729/0.24972072n 0.48983921/0.13245681n
dV/dt_r  0.4194645/0.16849956n 0.39167057/0.22148284n 0.48060123/0.12249969n
R_load = 50
[Rising Waveform]
R_fixture = 50
V_fixture = 1.35
V_fixture_min = 1.2825
V_fixture_max = 1.4175
0s        639mV      642.1mV    603.9mV
100.3ps   639.8mV    642.1mV    644.5mV
229.3ps   682.6mV    643mV      1.2V
325.3ps   944.5mV    644.1mV    1.374V
421.5ps   1.198V     667.6mV    1.402V
544.5ps   1.316V     832.2mV    1.413V
677ps     1.339V     1.101V     1.416V
776ps     1.342V     1.204V     1.417V
971.7ps   1.345V     1.267V     1.417V
1.25ns    1.347V     1.278V     1.418V
[Rising Waveform]
R_fixture = 50
V_fixture = 0
V_fixture_min = 0
V_fixture_max = 0
95.33ps   0V         0V         0V
148.1ps   0V         0V         104.6mV
249.4ps   9.023mV    0V         531.1mV
304.7ps   100.8mV    0V         684.3mV
361.7ps   257.6mV    0V         757mV
473.1ps   531.7mV    0V         785.1mV
598.7ps   661.6mV    142.7mV    792.4mV
763.5ps   684.7mV    455.5mV    795.8mV
854.7ps   686.9mV    555.1mV    796.8mV
1.345ns   691.4mV    643.3mV    797mV
[Falling Waveform]
R_fixture = 50
V_fixture = 1.35
V_fixture_min = 1.2825
V_fixture_max = 1.4175
124.8ps   1.349V     1.282V     1.417V
178.7ps   1.349V     1.282V     1.328V
272.5ps   1.331V     1.282V     962.3mV
337.9ps   1.222V     1.282V     754.2mV
406.7ps   1.051V     1.282V     647.5mV
515.3ps   803.5mV    1.28V      616.6mV
635.6ps   676.3mV    1.171V     609.5mV
910.6ps   646.7mV    757.5mV    604mV
1.066ns   644.6mV    676.7mV    603.6mV
1.25ns    643.4mV    649.7mV    603.6mV
[Falling Waveform]
R_fixture = 50
V_fixture = 0
V_fixture_min = 0
V_fixture_max = 0
114.3ps   694.7mV    647.7mV    797.1mV
159.9ps   694.7mV    647.7mV    711mV
247.2ps   675.6mV    647.7mV    327.4mV
311.5ps   536.7mV    647.7mV    137.4mV
383.8ps   327.1mV    647.7mV    36.21mV
456.1ps   165mV      646.2mV    14.66mV
557.8ps   53.8mV     547.1mV    5.974mV
770.2ps   7.629mV    171.1mV    0V
846.5ps   6.186mV    92.88mV    0V
1.345ns   3.154mV    4.138mV    0V
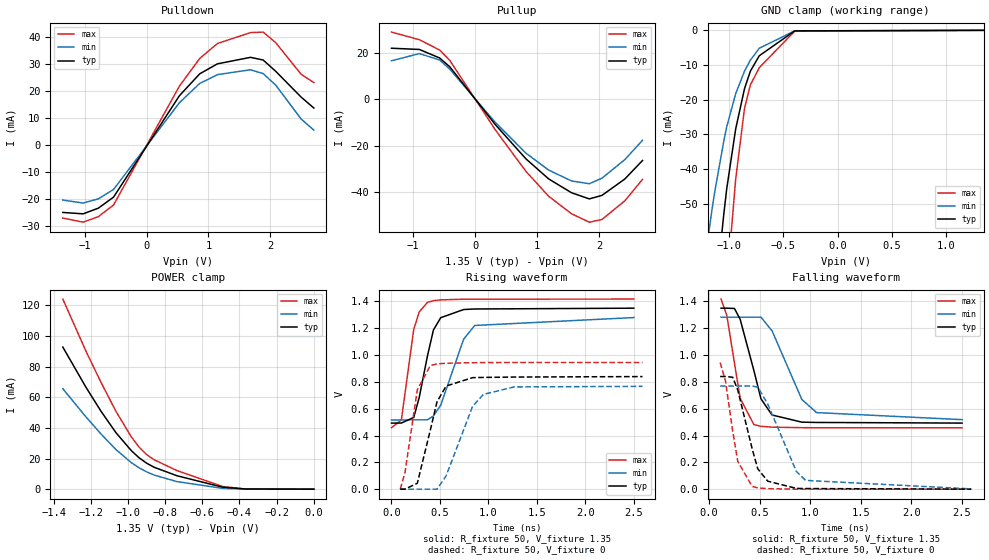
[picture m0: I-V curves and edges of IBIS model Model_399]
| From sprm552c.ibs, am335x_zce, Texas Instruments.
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| Model based on original model for BCSHTLTCSCDVPBFZ_SSDHV
|   Sub model SR10_12MA_5PER_1P35
[model]   Model_399
|[Description]  [1.35V-3-STATE-NOTERM-SR10:12MA, IND, 5%]
|   Fast slew rate (SR[1:0] = "10"), 0.67 * RExt = 1.500 * Iout
|   (I[2:0] = "111"), 12mA nominal with Rext = 50R,ODT off (ODT[1:0]
|   = "00") CMOS mode,Industrial temperature range (-40C to 125C,
|   25C nominal),5% power supply tolerance
|[Input Load]   NOTERM
|[Output Drive] SR10:12MA
|Voltage   1.35V
|Mode   3-STATE
Model_type   3-state
Polarity   Non-Inverting
Enable   Active-Low
Cref =  15pF
Rref =  100.0000M
Vref =  0V
Vmeas =  0.675
C_comp   1.865048p   1.679967p   1.989968p
[Temperature Range]   25   125   -40
[Voltage Range]   1.35   1.2825   1.4175
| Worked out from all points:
|   slope of the pulldown table from 0 to 0.203 V, typ, clamps not added: 27 ohm
|   slope of the pullup table from 0 to 0.203 V, typ, clamps not added: 29.4 ohm
|   GND clamp passes 1 mA (typ) near -0.49 V on its own axis
|   POWER clamp passes 1 mA (typ) near -0.47 V on its own axis
|   rising waveform, R_fixture 50, V_fixture 1.35: 20-80 % time 149ps typ, 223ps min, 108ps max; typ from 0.493 V to 1.35 V
|   rising waveform, R_fixture 50, V_fixture 0: 20-80 % time 161ps typ, 235ps min, 118ps max; typ from 0 V to 0.84 V
|   falling waveform, R_fixture 50, V_fixture 1.35: 20-80 % time 173ps typ, 257ps min, 126ps max; typ from 1.35 V to 0.492 V
|   falling waveform, R_fixture 50, V_fixture 0: 20-80 % time 162ps typ, 257ps min, 118ps max; typ from 0.84 V to 0 V
[POWER_clamp]
-1.35V    92.75mA    65.58mA    124.1mA
-1.227V   66.81mA    47.37mA    90.43mA
-1.145V   50.92mA    36.04mA    69.8mA
-1.064V   36.83mA    25.8mA     50.7mA
-981.8mV  25.17mA    17.34mA    34.14mA
-940.9mV  20.58mA    14.01mA    27.56mA
-900mV    17mA       11.33mA    22.64mA
-859.1mV  14.3mA     9.214mA    19.2mA
-736.4mV  8.769mA    4.942mA    12.14mA
-490.9mV  1.299mA    528.4uA    1.73mA
-368.2mV  117.2uA    50.88uA    117.5uA
0V        1.028nA    11.95nA    1.029nA
[Pulldown]
-1.35V    -24.93mA   -20.36mA   -27mA
-1.023V   -25.45mA   -21.45mA   -28.54mA
-777.3mV  -23.35mA   -19.91mA   -26.49mA
-531.8mV  -19.26mA   -16.43mA   -22.17mA
531.8mV   18.31mA    15.73mA    21.86mA
859.1mV   26.4mA     22.85mA    32.1mA
1.145V    30.09mA    26.09mA    37.62mA
1.677V    32.49mA    27.89mA    41.65mA
1.882V    31.5mA     26.47mA    41.84mA
2.086V    27.29mA    22.18mA    37.91mA
2.495V    17.76mA    9.657mA    26.21mA
2.7V      13.72mA    5.539mA    23.14mA
[Pullup]
-1.35V    22.07mA    16.66mA    29.04mA
-900mV    21.54mA    19.75mA    25.74mA
-572.7mV  17.85mA    16.99mA    21.28mA
-409.1mV  14.03mA    13.01mA    16.8mA
327.3mV   -10.99mA   -10.03mA   -13.25mA
818.2mV   -25.68mA   -23.23mA   -31.08mA
1.186V    -34.37mA   -30.55mA   -41.87mA
1.555V    -40.34mA   -35.25mA   -49.41mA
1.841V    -42.99mA   -36.44mA   -53.05mA
2.045V    -41.48mA   -34.05mA   -51.9mA
2.414V    -34.41mA   -26.04mA   -43.82mA
2.7V      -26.4mA    -17.67mA   -34.58mA
[GND_clamp]
-1.35V    -159.1mA   -94.77mA   -266.2mA
-1.295V   -137.7mA   -81.77mA   -230.9mA
-1.159V   -87.19mA   -51.56mA   -145.9mA
-1.132V   -77.89mA   -46.14mA   -129.9mA
-1.05V    -52.83mA   -31.84mA   -86.44mA
-1.023V   -45.55mA   -27.75mA   -73.68mA
-940.9mV  -28.44mA   -18.28mA   -42.92mA
-859.1mV  -16.79mA   -11.75mA   -22.47mA
-804.5mV  -11.72mA   -8.559mA   -15.69mA
-722.7mV  -7.324mA   -5.162mA   -10.76mA
-395.5mV  -159.1uA   -161.1uA   -232.3uA
1.35V     1.028nA    30.09nA    754.3pA
[Ramp]
dV/dt_f 0.51666264/0.17396726n 0.46247316/0.2600882n 0.57755751/0.12600548n
dV/dt_r 0.50687348/0.16206391n 0.46531144/0.23781831n 0.56942985/0.11871861n
R_load = 50
[Rising Waveform]
R_fixture = 50
V_fixture = 1.35
V_fixture_min = 1.2825
V_fixture_max = 1.4175
0s        492.8mV    516.3mV    458.5mV
102ps     493.3mV    516.3mV    516.9mV
229.6ps   534.9mV    517mV      1.192V
286.2ps   684.5mV    517.3mV    1.322V
370.3ps   991.2mV    517.1mV    1.393V
432.5ps   1.187V     545.6mV    1.406V
507.8ps   1.279V     626.3mV    1.412V
744.5ps   1.34V      1.119V     1.417V
858.7ps   1.344V     1.221V     1.417V
2.5ns     1.35V      1.28V      1.418V
[Rising Waveform]
R_fixture = 50
V_fixture = 0
V_fixture_min = 0
V_fixture_max = 0
90.18ps   0V         0V         0V
138.5ps   0V         0V         121.1mV
266.4ps   43.83mV    0V         741mV
400.1ps   439.3mV    0V         921.7mV
469.6ps   651.4mV    0V         934.2mV
563.3ps   769.2mV    98.63mV    939.4mV
837.2ps   831.9mV    618.7mV    943.3mV
949.1ps   833.6mV    707.3mV    944.4mV
1.267ns   836.3mV    762.7mV    944.9mV
2.59ns    839.8mV    766.9mV    944.9mV
[Falling Waveform]
R_fixture = 50
V_fixture = 1.35
V_fixture_min = 1.2825
V_fixture_max = 1.4175
119.9ps   1.349V     1.282V     1.417V
176.7ps   1.349V     1.282V     1.295V
251.7ps   1.347V     1.282V     941.1mV
308.4ps   1.266V     1.282V     677.6mV
443.7ps   884.6mV    1.282V     481.3mV
513.8ps   673.5mV    1.282V     468.5mV
623.4ps   552.8mV    1.18V      462.1mV
917.4ps   499.5mV    668.8mV    458.3mV
1.063ns   497.3mV    570.8mV    457.7mV
2.5ns     492.5mV    518.2mV    457.5mV
[Falling Waveform]
R_fixture = 50
V_fixture = 0
V_fixture_min = 0
V_fixture_max = 0
110.8ps   839.6mV    768.6mV    944mV
162.6ps   839.6mV    768.6mV    809.2mV
234.3ps   834.4mV    768.6mV    433.2mV
284.7ps   738.8mV    768.6mV    207.3mV
427.8ps   298mV      768.6mV    19.51mV
482.1ps   151.8mV    760.7mV    9.575mV
580.8ps   59.46mV    634.7mV    3.91mV
863.3ps   5.87mV     132.3mV    0V
954.7ps   4.586mV    65.28mV    0V
2.59ns    0V         2.069mV    0V
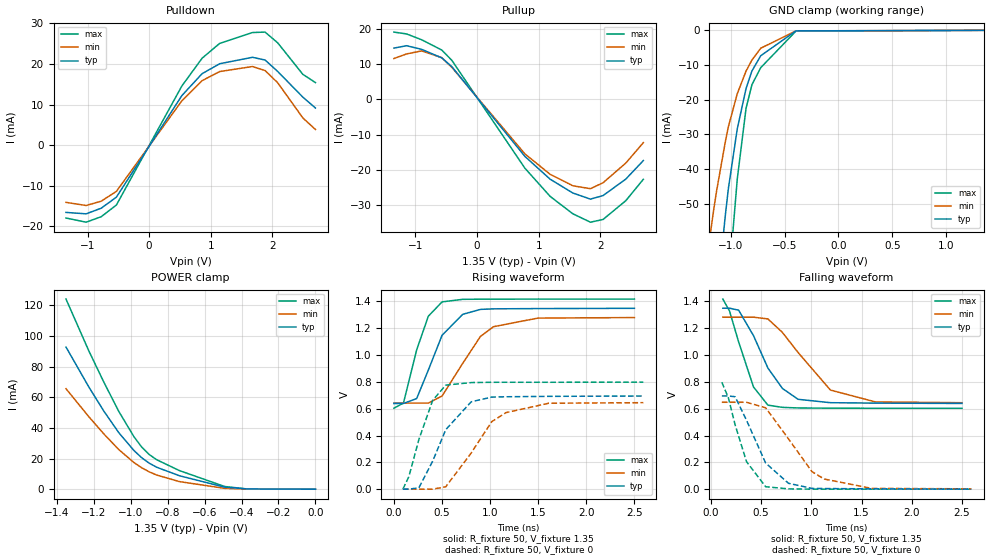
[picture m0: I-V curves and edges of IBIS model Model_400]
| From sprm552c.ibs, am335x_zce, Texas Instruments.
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| Model based on original model for BCSHTLTCSCDVPBFZ_SSDHV
|   Sub model SR11_8MA_5PER_1P35
[model]   Model_400
|[Description]  [1.35V-3-STATE-NOTERM-SR11:8MA, IND, 5%]
|   Slowest slew rate (SR[1:0] = "11"), 1.00 * RExt = 1.000 * Iout
|   (I[2:0] = "011"), 8mA nominal with Rext = 50R,ODT off (ODT[1:0]
|   = "00") CMOS mode,Industrial temperature range (-40C to 125C,
|   25C nominal),5% power supply tolerance
|[Input Load]   NOTERM
|[Output Drive] SR11:8MA
|Voltage   1.35V
|Mode   3-STATE
Model_type   3-state
Polarity   Non-Inverting
Enable   Active-Low
Cref =  15pF
Rref =  100.0000M
Vref =  0V
Vmeas =  0.675
C_comp   1.865048p   1.679967p   1.989968p
[Temperature Range]   25   125   -40
[Voltage Range]   1.35   1.2825   1.4175
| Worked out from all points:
|   slope of the pulldown table from 0 to 0.203 V, typ, clamps not added: 40.4 ohm
|   slope of the pullup table from 0 to 0.203 V, typ, clamps not added: 44.6 ohm
|   GND clamp passes 1 mA (typ) near -0.49 V on its own axis
|   POWER clamp passes 1 mA (typ) near -0.47 V on its own axis
|   rising waveform, R_fixture 50, V_fixture 1.35: 20-80 % time 250ps typ, 344ps min, 186ps max; typ from 0.639 V to 1.35 V
|   rising waveform, R_fixture 50, V_fixture 0: 20-80 % time 285ps typ, 364ps min, 206ps max; typ from 0 V to 0.695 V
|   falling waveform, R_fixture 50, V_fixture 1.35: 20-80 % time 300ps typ, 391ps min, 207ps max; typ from 1.35 V to 0.639 V
|   falling waveform, R_fixture 50, V_fixture 0: 20-80 % time 269ps typ, 365ps min, 199ps max; typ from 0.695 V to 0 V
[POWER_clamp]
-1.35V    92.75mA    65.58mA    124.1mA
-1.227V   66.81mA    47.37mA    90.43mA
-1.145V   50.92mA    36.04mA    69.8mA
-1.064V   36.83mA    25.8mA     50.7mA
-981.8mV  25.17mA    17.34mA    34.14mA
-940.9mV  20.58mA    14.01mA    27.56mA
-900mV    17mA       11.33mA    22.64mA
-859.1mV  14.3mA     9.214mA    19.2mA
-736.4mV  8.769mA    4.942mA    12.14mA
-490.9mV  1.299mA    528.4uA    1.73mA
-368.2mV  117.2uA    50.88uA    117.5uA
0V        1.028nA    11.95nA    1.029nA
[Pulldown]
-1.35V    -16.62mA   -14.14mA   -18mA
-1.023V   -16.97mA   -14.91mA   -19.03mA
-777.3mV  -15.57mA   -13.84mA   -17.67mA
-531.8mV  -12.85mA   -11.43mA   -14.79mA
531.8mV   12.22mA    10.94mA    14.59mA
859.1mV   17.61mA    15.89mA    21.42mA
1.145V    20.07mA    18.14mA    25.09mA
1.677V    21.66mA    19.38mA    27.77mA
1.882V    20.99mA    18.39mA    27.88mA
2.086V    18.18mA    15.4mA     25.25mA
2.495V    11.84mA    6.706mA    17.46mA
2.7V      9.141mA    3.847mA    15.42mA
[Pullup]
-1.35V    14.52mA    11.57mA    19.06mA
-1.145V   15.2mA     12.87mA    18.54mA
-900mV    14.17mA    13.73mA    16.89mA
-572.7mV  11.75mA    11.81mA    13.97mA
-409.1mV  9.241mA    9.051mA    11.04mA
777.3mV   -16.18mA   -15.47mA   -19.53mA
1.186V    -22.63mA   -21.24mA   -27.5mA
1.555V    -26.55mA   -24.5mA    -32.44mA
1.841V    -28.28mA   -25.32mA   -34.82mA
2.045V    -27.28mA   -23.65mA   -34.05mA
2.414V    -22.62mA   -18.08mA   -28.74mA
2.7V      -17.35mA   -12.27mA   -22.66mA
[GND_clamp]
-1.35V    -159.1mA   -94.77mA   -266.2mA
-1.295V   -137.7mA   -81.77mA   -230.9mA
-1.159V   -87.19mA   -51.56mA   -145.9mA
-1.132V   -77.89mA   -46.14mA   -129.9mA
-1.05V    -52.83mA   -31.84mA   -86.44mA
-1.023V   -45.55mA   -27.75mA   -73.68mA
-940.9mV  -28.44mA   -18.28mA   -42.92mA
-859.1mV  -16.79mA   -11.75mA   -22.47mA
-804.5mV  -11.72mA   -8.559mA   -15.69mA
-722.7mV  -7.324mA   -5.162mA   -10.76mA
-395.5mV  -159.1uA   -161.1uA   -232.3uA
1.35V     1.028nA    30.09nA    754.3pA
[Ramp]
dV/dt_f 0.42850788/0.30115304n 0.38649733/0.39661501n 0.48988549/0.2073105n
dV/dt_r 0.41925744/0.2866673n 0.39164702/0.36961926n 0.48043037/0.20620041n
R_load = 50
[Rising Waveform]
R_fixture = 50
V_fixture = 1.35
V_fixture_min = 1.2825
V_fixture_max = 1.4175
0s        639mV      642.1mV    603.9mV
99.34ps   639.3mV    642.1mV    642.5mV
236.5ps   675.9mV    642.1mV    1.039V
357.6ps   887.9mV    642.2mV    1.29V
500.6ps   1.148V     694.8mV    1.397V
714.8ps   1.304V     938.2mV    1.416V
899.5ps   1.341V     1.139V     1.417V
1.036ns   1.345V     1.212V     1.417V
1.496ns   1.347V     1.276V     1.418V
2.5ns     1.349V     1.28V      1.418V
[Rising Waveform]
R_fixture = 50
V_fixture = 0
V_fixture_min = 0
V_fixture_max = 0
93.04ps   0V         0V         0V
155ps     0V         0V         92.41mV
259.6ps   10.11mV    0V         370.4mV
403ps     209.1mV    0V         662.7mV
539ps     444.1mV    17.76mV    776.1mV
803.5ps   651.6mV    270.2mV    795.1mV
1.017ns   686.9mV    503.6mV    797.2mV
1.165ns   689.2mV    570.9mV    797.5mV
1.61ns    692.3mV    641mV      797.4mV
2.593ns   694.8mV    645.2mV    798mV
[Falling Waveform]
R_fixture = 50
V_fixture = 1.35
V_fixture_min = 1.2825
V_fixture_max = 1.4175
118.6ps   1.349V     1.282V     1.417V
185ps     1.349V     1.282V     1.328V
275.9ps   1.334V     1.282V     1.097V
424ps     1.144V     1.282V     761.7mV
567.2ps   903.1mV    1.269V     626.2mV
711ps     751.4mV    1.169V     609.9mV
867.5ps   669.9mV    1.019V     605.3mV
1.19ns    644.6mV    738.7mV    603.5mV
1.638ns   641.4mV    650.4mV    603mV
2.5ns     639mV      644.4mV    602.9mV
[Falling Waveform]
R_fixture = 50
V_fixture = 0
V_fixture_min = 0
V_fixture_max = 0
108.4ps   694.7mV    647.7mV    797mV
173.9ps   694.7mV    647.7mV    680.4mV
240.5ps   689.2mV    647.7mV    480.5mV
353.6ps   514.8mV    647.7mV    206mV
544.7ps   194.7mV    606.6mV    18.22mV
772.5ps   43.72mV    374.6mV    2.154mV
1.006ns   5.95mV     130.6mV    0V
1.128ns   4.602mV    75.46mV    0V
1.601ns   2.497mV    5.739mV    0V
2.593ns   0V         2.484mV    0V
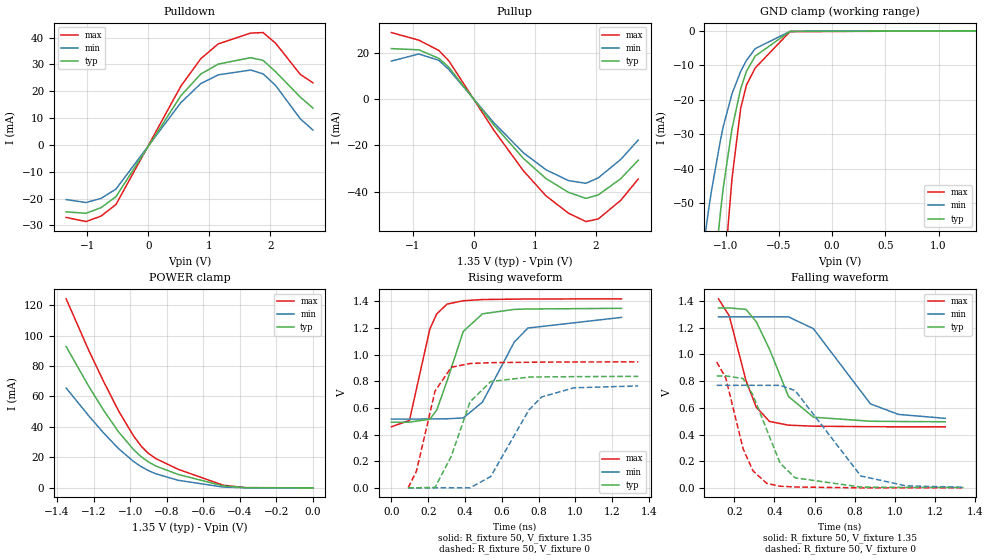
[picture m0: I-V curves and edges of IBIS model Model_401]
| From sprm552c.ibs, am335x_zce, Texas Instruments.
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| Model based on original model for BCSHTLTCSCDVPBFZ_SSDHV
|   Sub model SR01_12MA_5PER_1P35
[model]   Model_401
|[Description]  [1.35V-3-STATE-NOTERM-SR01:12MA, IND, 5%]
|   Slow slew rate (SR[1:0] = "01"), 0.67 * RExt = 1.500 * Iout
|   (I[2:0] = "111"), 12mA nominal with Rext = 50R,ODT off (ODT[1:0]
|   = "00") CMOS mode,Industrial temperature range (-40C to 125C,
|   25C nominal),5% power supply tolerance
|[Input Load]   NOTERM
|[Output Drive] SR01:12MA
|Voltage   1.35V
|Mode   3-STATE
Model_type   3-state
Polarity   Non-Inverting
Enable   Active-Low
Cref =  15pF
Rref =  100.0000M
Vref =  0V
Vmeas =  0.675
C_comp   1.865048p   1.679967p   1.989968p
[Temperature Range]   25   125   -40
[Voltage Range]   1.35   1.2825   1.4175
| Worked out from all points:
|   slope of the pulldown table from 0 to 0.203 V, typ, clamps not added: 27 ohm
|   slope of the pullup table from 0 to 0.203 V, typ, clamps not added: 29.4 ohm
|   GND clamp passes 1 mA (typ) near -0.49 V on its own axis
|   POWER clamp passes 1 mA (typ) near -0.47 V on its own axis
|   rising waveform, R_fixture 50, V_fixture 1.35: 20-80 % time 122ps typ, 178ps min, 89.9ps max; typ from 0.493 V to 1.35 V
|   rising waveform, R_fixture 50, V_fixture 0: 20-80 % time 130ps typ, 187ps min, 97.4ps max; typ from 0 V to 0.837 V
|   falling waveform, R_fixture 50, V_fixture 1.35: 20-80 % time 144ps typ, 212ps min, 106ps max; typ from 1.35 V to 0.495 V
|   falling waveform, R_fixture 50, V_fixture 0: 20-80 % time 135ps typ, 208ps min, 99.2ps max; typ from 0.839 V to 0.003 V
[POWER_clamp]
-1.35V    92.75mA    65.58mA    124.1mA
-1.227V   66.81mA    47.37mA    90.43mA
-1.145V   50.92mA    36.04mA    69.8mA
-1.064V   36.83mA    25.8mA     50.7mA
-981.8mV  25.17mA    17.34mA    34.14mA
-940.9mV  20.58mA    14.01mA    27.56mA
-900mV    17mA       11.33mA    22.64mA
-859.1mV  14.3mA     9.214mA    19.2mA
-736.4mV  8.769mA    4.942mA    12.14mA
-490.9mV  1.299mA    528.4uA    1.73mA
-368.2mV  117.2uA    50.88uA    117.5uA
0V        1.028nA    11.95nA    1.029nA
[Pulldown]
-1.35V    -24.93mA   -20.36mA   -27mA
-1.023V   -25.45mA   -21.45mA   -28.54mA
-777.3mV  -23.35mA   -19.91mA   -26.49mA
-531.8mV  -19.26mA   -16.43mA   -22.17mA
531.8mV   18.31mA    15.73mA    21.86mA
859.1mV   26.4mA     22.85mA    32.1mA
1.145V    30.09mA    26.09mA    37.62mA
1.677V    32.49mA    27.89mA    41.65mA
1.882V    31.5mA     26.47mA    41.84mA
2.086V    27.29mA    22.18mA    37.91mA
2.495V    17.76mA    9.657mA    26.21mA
2.7V      13.72mA    5.539mA    23.14mA
[Pullup]
-1.35V    22.07mA    16.66mA    29.04mA
-900mV    21.54mA    19.75mA    25.74mA
-572.7mV  17.85mA    16.99mA    21.28mA
-409.1mV  14.03mA    13.01mA    16.8mA
327.3mV   -10.99mA   -10.03mA   -13.25mA
818.2mV   -25.68mA   -23.23mA   -31.08mA
1.186V    -34.37mA   -30.55mA   -41.87mA
1.555V    -40.34mA   -35.25mA   -49.41mA
1.841V    -42.99mA   -36.44mA   -53.05mA
2.045V    -41.48mA   -34.05mA   -51.9mA
2.414V    -34.41mA   -26.04mA   -43.82mA
2.7V      -26.4mA    -17.67mA   -34.58mA
[GND_clamp]
-1.35V    -159.1mA   -94.77mA   -266.2mA
-1.295V   -137.7mA   -81.77mA   -230.9mA
-1.159V   -87.19mA   -51.56mA   -145.9mA
-1.132V   -77.89mA   -46.14mA   -129.9mA
-1.05V    -52.83mA   -31.84mA   -86.44mA
-1.023V   -45.55mA   -27.75mA   -73.68mA
-940.9mV  -28.44mA   -18.28mA   -42.92mA
-859.1mV  -16.79mA   -11.75mA   -22.47mA
-804.5mV  -11.72mA   -8.559mA   -15.69mA
-722.7mV  -7.324mA   -5.162mA   -10.76mA
-395.5mV  -159.1uA   -161.1uA   -232.3uA
1.35V     1.028nA    30.09nA    754.3pA
[Ramp]
dV/dt_f 0.51678848/0.14633493n 0.46241333/0.21592992n 0.57770147/0.10614797n
dV/dt_r 0.50716729/0.13218086n 0.46543632/0.19038488n 0.56972081/97.738973p
R_load = 50
[Rising Waveform]
R_fixture = 50
V_fixture = 1.35
V_fixture_min = 1.2825
V_fixture_max = 1.4175
0s        492.8mV    516.3mV    458.5mV
97.62ps   493.3mV    516.3mV    505.4mV
208.9ps   514.9mV    516.6mV    1.193V
246ps     583.4mV    517.5mV    1.305V
302.5ps   802.8mV    518.2mV    1.379V
390.3ps   1.174V     524.5mV    1.404V
495.1ps   1.306V     644.3mV    1.413V
667.5ps   1.339V     1.094V     1.416V
741.7ps   1.342V     1.199V     1.417V
1.25ns    1.347V     1.279V     1.418V
[Rising Waveform]
R_fixture = 50
V_fixture = 0
V_fixture_min = 0
V_fixture_max = 0
90.89ps   0V         0V         0V
135.7ps   0V         0V         123.8mV
237.1ps   3.592mV    0V         727mV
325.7ps   239mV      0V         905.2mV
427.3ps   645.7mV    0V         933mV
539.5ps   797.6mV    85.07mV    939.4mV
746.8ps   830.9mV    583.9mV    942.3mV
816.3ps   832.3mV    682.2mV    943.4mV
992.5ps   834.4mV    750.8mV    944.6mV
1.341ns   836.5mV    764.7mV    944.9mV
[Falling Waveform]
R_fixture = 50
V_fixture = 1.35
V_fixture_min = 1.2825
V_fixture_max = 1.4175
121.7ps   1.349V     1.282V     1.417V
175.1ps   1.349V     1.282V     1.29V
258.5ps   1.338V     1.282V     804.1mV
309.4ps   1.246V     1.282V     605.5mV
375.3ps   1.04V      1.282V     497.7mV
470.1ps   684.9mV    1.282V     470mV
594.1ps   529.7mV    1.193V     462.3mV
877.9ps   499.5mV    629.4mV    458.5mV
1.017ns   497.4mV    550.8mV    457.8mV
1.25ns    495.5mV    521.1mV    457.5mV
[Falling Waveform]
R_fixture = 50
V_fixture = 0
V_fixture_min = 0
V_fixture_max = 0
112.8ps   839.4mV    768.7mV    944mV
157.8ps   839.4mV    768.7mV    824mV
243.7ps   819.7mV    768.7mV    294.6mV
293.2ps   696.3mV    768.7mV    127.3mV
362.3ps   432.7mV    768.7mV    33.07mV
428.6ps   184.4mV    768.7mV    12.08mV
503.2ps   74.92mV    729.3mV    6.448mV
830.2ps   5.845mV    88.95mV    0V
1.054ns   3.642mV    15mV       0V
1.341ns   2.545mV    4.296mV    0V
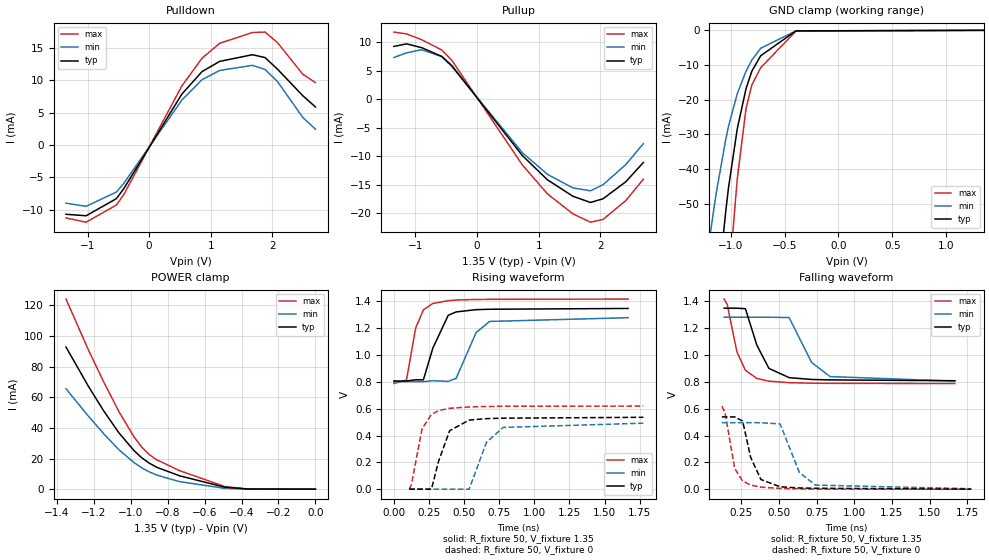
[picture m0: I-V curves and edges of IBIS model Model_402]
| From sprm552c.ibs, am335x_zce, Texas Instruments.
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| Model based on original model for BCSHTLTCSCDVPBFZ_SSDHV
|   Sub model SR00_5MA_5PER_1P35
[model]   Model_402
|[Description]  [1.35V-3-STATE-NOTERM-SR00:5MA, IND, 5%]
|   Fastest slew rate (SR[1:0] = "00"), 1.60 * RExt = 0.625 * Iout
|   (I[2:0] = "000"), 5mA nominal with Rext = 50R,ODT off (ODT[1:0]
|   = "00") CMOS mode,Industrial temperature range (-40C to 125C,
|   25C nominal),5% power supply tolerance
|[Input Load]   NOTERM
|[Output Drive] SR00:5MA
|Voltage   1.35V
|Mode   3-STATE
Model_type   3-state
Polarity   Non-Inverting
Enable   Active-Low
Cref =  15pF
Rref =  100.0000M
Vref =  0V
Vmeas =  0.675
C_comp   1.865048p   1.679967p   1.989968p
[Temperature Range]   25   125   -40
[Voltage Range]   1.35   1.2825   1.4175
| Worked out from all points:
|   slope of the pulldown table from 0 to 0.203 V, typ, clamps not added: 62.9 ohm
|   slope of the pullup table from 0 to 0.203 V, typ, clamps not added: 69.7 ohm
|   GND clamp passes 1 mA (typ) near -0.49 V on its own axis
|   POWER clamp passes 1 mA (typ) near -0.47 V on its own axis
|   rising waveform, R_fixture 50, V_fixture 1.35: 20-80 % time 90.9ps typ, 121ps min, 72.6ps max; typ from 0.807 V to 1.35 V
|   rising waveform, R_fixture 50, V_fixture 0: 20-80 % time 94.1ps typ, 111ps min, 80.2ps max; typ from 0 V to 0.536 V
|   falling waveform, R_fixture 50, V_fixture 1.35: 20-80 % time 110ps typ, 133ps min, 88.8ps max; typ from 1.35 V to 0.808 V
|   falling waveform, R_fixture 50, V_fixture 0: 20-80 % time 77.9ps typ, 98.3ps min, 64.8ps max; typ from 0.539 V to 0 V
[POWER_clamp]
-1.35V    92.75mA    65.58mA    124.1mA
-1.227V   66.81mA    47.37mA    90.43mA
-1.145V   50.92mA    36.04mA    69.8mA
-1.064V   36.83mA    25.8mA     50.7mA
-981.8mV  25.17mA    17.34mA    34.14mA
-940.9mV  20.58mA    14.01mA    27.56mA
-900mV    17mA       11.33mA    22.64mA
-859.1mV  14.3mA     9.214mA    19.2mA
-736.4mV  8.769mA    4.942mA    12.14mA
-490.9mV  1.299mA    528.4uA    1.73mA
-368.2mV  117.2uA    50.88uA    117.5uA
0V        1.028nA    11.95nA    1.029nA
[Pulldown]
-1.35V    -10.68mA   -8.968mA   -11.25mA
-1.023V   -10.91mA   -9.455mA   -11.9mA
-531.8mV  -8.266mA   -7.25mA    -9.251mA
-409.1mV  -6.689mA   -5.878mA   -7.605mA
531.8mV   7.861mA    6.942mA    9.13mA
859.1mV   11.33mA    10.08mA    13.39mA
1.145V    12.9mA     11.5mA     15.69mA
1.677V    13.93mA    12.29mA    17.36mA
1.882V    13.49mA    11.66mA    17.42mA
2.086V    11.68mA    9.761mA    15.77mA
2.495V    7.606mA    4.25mA     10.91mA
2.7V      5.873mA    2.439mA    9.633mA
[Pullup]
-1.35V    9.289mA    7.338mA    11.8mA
-1.145V   9.731mA    8.157mA    11.48mA
-900mV    9.073mA    8.704mA    10.46mA
-572.7mV  7.523mA    7.496mA    8.655mA
-409.1mV  5.918mA    5.744mA    6.841mA
736.4mV   -9.883mA   -9.376mA   -11.53mA
1.145V    -14.14mA   -13.18mA   -16.61mA
1.555V    -17mA      -15.54mA   -20.09mA
1.841V    -18.1mA    -16.05mA   -21.56mA
2.045V    -17.45mA   -14.99mA   -21.07mA
2.414V    -14.47mA   -11.46mA   -17.78mA
2.7V      -11.09mA   -7.777mA   -14.02mA
[GND_clamp]
-1.35V    -159.1mA   -94.77mA   -266.2mA
-1.295V   -137.7mA   -81.77mA   -230.9mA
-1.159V   -87.19mA   -51.56mA   -145.9mA
-1.132V   -77.89mA   -46.14mA   -129.9mA
-1.05V    -52.83mA   -31.84mA   -86.44mA
-1.023V   -45.55mA   -27.75mA   -73.68mA
-940.9mV  -28.44mA   -18.28mA   -42.92mA
-859.1mV  -16.79mA   -11.75mA   -22.47mA
-804.5mV  -11.72mA   -8.559mA   -15.69mA
-722.7mV  -7.324mA   -5.162mA   -10.76mA
-395.5mV  -159.1uA   -161.1uA   -232.3uA
1.35V     1.028nA    30.09nA    754.3pA
[Ramp]
dV/dt_f 0.33085237/0.11145097n 0.29428562/0.13729663n 0.38167456/88.996912p
dV/dt_r 0.32887012/95.552548p 0.30566587/0.11409103n   0.377138/80.312558p
R_load = 50
[Rising Waveform]
R_fixture = 50
V_fixture = 1.35
V_fixture_min = 1.2825
V_fixture_max = 1.4175
0s        806.9mV    801.9mV    788.4mV
89.31ps   806.9mV    801.9mV    813mV
154.8ps   815.9mV    801.9mV    1.202V
209.9ps   815.6mV    801.9mV    1.337V
277.1ps   1.052V     809.1mV    1.385V
386.8ps   1.297V     804.2mV    1.406V
442.9ps   1.322V     826.2mV    1.411V
584.5ps   1.339V     1.167V     1.415V
680.7ps   1.342V     1.251V     1.416V
1.667ns   1.348V     1.279V     1.418V
[Rising Waveform]
R_fixture = 50
V_fixture = 0
V_fixture_min = 0
V_fixture_max = 0
109ps     0V         0V         0V
124.3ps   0V         0V         32.71mV
200.7ps   0V         0V         451.2mV
267.2ps   0V         0V         558mV
317.9ps   207.8mV    0V         585.8mV
396.6ps   436.2mV    0V         603.1mV
535.6ps   515.2mV    0V         613.4mV
659.2ps   526.2mV    349.6mV    616.8mV
778.1ps   529.5mV    460.6mV    618.3mV
1.776ns   536.1mV    492.1mV    619.7mV
[Falling Waveform]
R_fixture = 50
V_fixture = 1.35
V_fixture_min = 1.2825
V_fixture_max = 1.4175
137.4ps   1.349V     1.282V     1.417V
157.8ps   1.349V     1.282V     1.377V
222.3ps   1.349V     1.282V     1.023V
278.5ps   1.345V     1.282V     885.7mV
354.5ps   1.073V     1.282V     825.2mV
434.6ps   900.2mV    1.282V     805.1mV
568.5ps   831.2mV    1.279V     794mV
717.5ps   817.7mV    944.7mV    790mV
839.8ps   814.3mV    839.2mV    788.7mV
1.667ns   808.4mV    805.3mV    787.5mV
[Falling Waveform]
R_fixture = 50
V_fixture = 0
V_fixture_min = 0
V_fixture_max = 0
122.2ps   538.6mV    495.5mV    618.7mV
143.2ps   538.6mV    495.5mV    571.8mV
207.7ps   538.6mV    495.5mV    153.1mV
260.2ps   507.6mV    495.5mV    61.18mV
313ps     238.4mV    495.5mV    30.36mV
381.4ps   72.04mV    495.5mV    15mV
508.5ps   17.86mV    486.2mV    5.637mV
636.4ps   9.019mV    124.1mV    2.57mV
742.5ps   6.751mV    30.31mV    0V
1.776ns   0V         3.158mV    0V
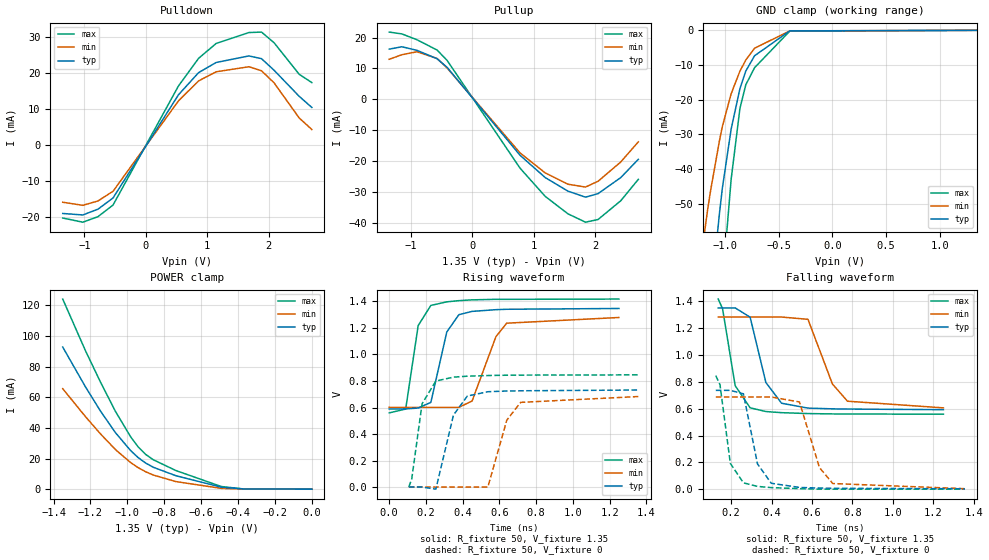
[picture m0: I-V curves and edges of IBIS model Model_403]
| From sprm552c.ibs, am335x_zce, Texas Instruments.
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| Model based on original model for BCSHTLTCSCDVPBFZ_SSDHV
|   Sub model SR00_9MA_5PER_1P35
[model]   Model_403
|[Description]  [1.35V-3-STATE-NOTERM-SR00:9MA, IND, 5%]
|   Fastest slew rate (SR[1:0] = "00"), 0.88 * RExt = 1.125 * Iout
|   (I[2:0] = "100"), 9mA nominal with Rext = 50R,ODT off (ODT[1:0]
|   = "00") CMOS mode,Industrial temperature range (-40C to 125C,
|   25C nominal),5% power supply tolerance
|[Input Load]   NOTERM
|[Output Drive] SR00:9MA
|Voltage   1.35V
|Mode   3-STATE
Model_type   3-state
Polarity   Non-Inverting
Enable   Active-Low
Cref =  15pF
Rref =  100.0000M
Vref =  0V
Vmeas =  0.675
C_comp   1.865048p   1.679967p   1.989968p
[Temperature Range]   25   125   -40
[Voltage Range]   1.35   1.2825   1.4175
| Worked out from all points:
|   slope of the pulldown table from 0 to 0.203 V, typ, clamps not added: 35.4 ohm
|   slope of the pullup table from 0 to 0.203 V, typ, clamps not added: 39.9 ohm
|   GND clamp passes 1 mA (typ) near -0.49 V on its own axis
|   POWER clamp passes 1 mA (typ) near -0.47 V on its own axis
|   rising waveform, R_fixture 50, V_fixture 1.35: 20-80 % time 73.3ps typ, 107ps min, 52.7ps max; typ from 0.589 V to 1.35 V
|   rising waveform, R_fixture 50, V_fixture 0: 20-80 % time 70.1ps typ, 83.1ps min, 56ps max; typ from 0 V to 0.732 V
|   falling waveform, R_fixture 50, V_fixture 1.35: 20-80 % time 79.1ps typ, 101ps min, 61ps max; typ from 1.35 V to 0.593 V
|   falling waveform, R_fixture 50, V_fixture 0: 20-80 % time 57.6ps typ, 76.7ps min, 46.5ps max; typ from 0.736 V to 0.003 V
[POWER_clamp]
-1.35V    92.75mA    65.58mA    124.1mA
-1.227V   66.81mA    47.37mA    90.43mA
-1.145V   50.92mA    36.04mA    69.8mA
-1.064V   36.83mA    25.8mA     50.7mA
-981.8mV  25.17mA    17.34mA    34.14mA
-940.9mV  20.58mA    14.01mA    27.56mA
-900mV    17mA       11.33mA    22.64mA
-859.1mV  14.3mA     9.214mA    19.2mA
-736.4mV  8.769mA    4.942mA    12.14mA
-490.9mV  1.299mA    528.4uA    1.73mA
-368.2mV  117.2uA    50.88uA    117.5uA
0V        1.028nA    11.95nA    1.029nA
[Pulldown]
-1.35V    -18.99mA   -15.87mA   -20.25mA
-1.023V   -19.4mA    -16.73mA   -21.41mA
-777.3mV  -17.8mA    -15.52mA   -19.88mA
-531.8mV  -14.68mA   -12.82mA   -16.64mA
531.8mV   13.96mA    12.27mA    16.41mA
859.1mV   20.12mA    17.82mA    24.09mA
1.145V    22.93mA    20.35mA    28.22mA
1.677V    24.75mA    21.75mA    31.24mA
1.882V    23.99mA    20.63mA    31.37mA
2.086V    20.78mA    17.28mA    28.42mA
2.495V    13.53mA    7.525mA    19.65mA
2.7V      10.45mA    4.317mA    17.35mA
[Pullup]
-1.35V    16.26mA    12.99mA    21.78mA
-1.145V   17.03mA    14.44mA    21.19mA
-900mV    15.87mA    15.4mA     19.31mA
-572.7mV  13.16mA    13.25mA    15.97mA
-409.1mV  10.35mA    10.15mA    12.61mA
777.3mV   -18.12mA   -17.36mA   -22.31mA
1.186V    -25.34mA   -23.83mA   -31.43mA
1.555V    -29.73mA   -27.49mA   -37.07mA
1.841V    -31.68mA   -28.41mA   -39.79mA
2.045V    -30.55mA   -26.54mA   -38.92mA
2.414V    -25.34mA   -20.29mA   -32.85mA
2.7V      -19.43mA   -13.77mA   -25.91mA
[GND_clamp]
-1.35V    -159.1mA   -94.77mA   -266.2mA
-1.295V   -137.7mA   -81.77mA   -230.9mA
-1.159V   -87.19mA   -51.56mA   -145.9mA
-1.132V   -77.89mA   -46.14mA   -129.9mA
-1.05V    -52.83mA   -31.84mA   -86.44mA
-1.023V   -45.55mA   -27.75mA   -73.68mA
-940.9mV  -28.44mA   -18.28mA   -42.92mA
-859.1mV  -16.79mA   -11.75mA   -22.47mA
-804.5mV  -11.72mA   -8.559mA   -15.69mA
-722.7mV  -7.324mA   -5.162mA   -10.76mA
-395.5mV  -159.1uA   -161.1uA   -232.3uA
1.35V     1.028nA    30.09nA    754.3pA
[Ramp]
dV/dt_f 0.46368713/80.629573p 0.41632999/0.10389517n 0.52118684/61.361391p
dV/dt_r 0.45148348/71.64099p  0.42609345/85.940657p 0.51686241/56.327772p
R_load = 50
[Rising Waveform]
R_fixture = 50
V_fixture = 1.35
V_fixture_min = 1.2825
V_fixture_max = 1.4175
0s        589.3mV    601.2mV    559.6mV
89.53ps   589.3mV    601.2mV    588.4mV
157.5ps   596mV      601.2mV    1.218V
226.5ps   638.7mV    601.2mV    1.37V
313.1ps   1.169V     601.2mV    1.397V
378.8ps   1.3V       601.2mV    1.406V
451ps     1.325V     649.1mV    1.412V
580.6ps   1.338V     1.134V     1.416V
639ps     1.341V     1.236V     1.416V
1.25ns    1.347V     1.279V     1.418V
[Rising Waveform]
R_fixture = 50
V_fixture = 0
V_fixture_min = 0
V_fixture_max = 0
106.4ps   0V         0V         0V
122.5ps   0V         0V         61.18mV
178.6ps   0V         0V         628.1mV
253.7ps   -15.96mV   0V         799.7mV
349.6ps   543.3mV    0V         829.1mV
425.2ps   686.6mV    0V         836.2mV
536.8ps   719mV      0V         841.2mV
640ps     724.4mV    504.9mV    843.6mV
715.6ps   726.2mV    638.7mV    844.4mV
1.356ns   731.9mV    682.8mV    846.2mV
[Falling Waveform]
R_fixture = 50
V_fixture = 1.35
V_fixture_min = 1.2825
V_fixture_max = 1.4175
135.7ps   1.351V     1.283V     1.417V
157.1ps   1.351V     1.283V     1.346V
219.7ps   1.351V     1.283V     771.3mV
293.6ps   1.282V     1.283V     606.5mV
371.6ps   794.9mV    1.283V     578.6mV
449.1ps   640.6mV    1.283V     570.2mV
579.8ps   604.2mV    1.266V     563.5mV
700.8ps   598.7mV    784mV      560.9mV
775.3ps   597.1mV    655.6mV    560.3mV
1.25ns    592.6mV    606mV      558.8mV
[Falling Waveform]
R_fixture = 50
V_fixture = 0
V_fixture_min = 0
V_fixture_max = 0
123.6ps   736.5mV    687.1mV    846.3mV
144.5ps   736.5mV    687.1mV    778.7mV
195.7ps   736.5mV    687.1mV    192.1mV
260.4ps   710.7mV    687.1mV    47.09mV
330.1ps   188.2mV    687.1mV    20.52mV
398.1ps   43.99mV    687.1mV    11.64mV
537.8ps   12.89mV    649.8mV    3.834mV
636.7ps   8.188mV    160.6mV    0V
702.4ps   6.677mV    41.96mV    0V
1.356ns   2.867mV    3.58mV     0V
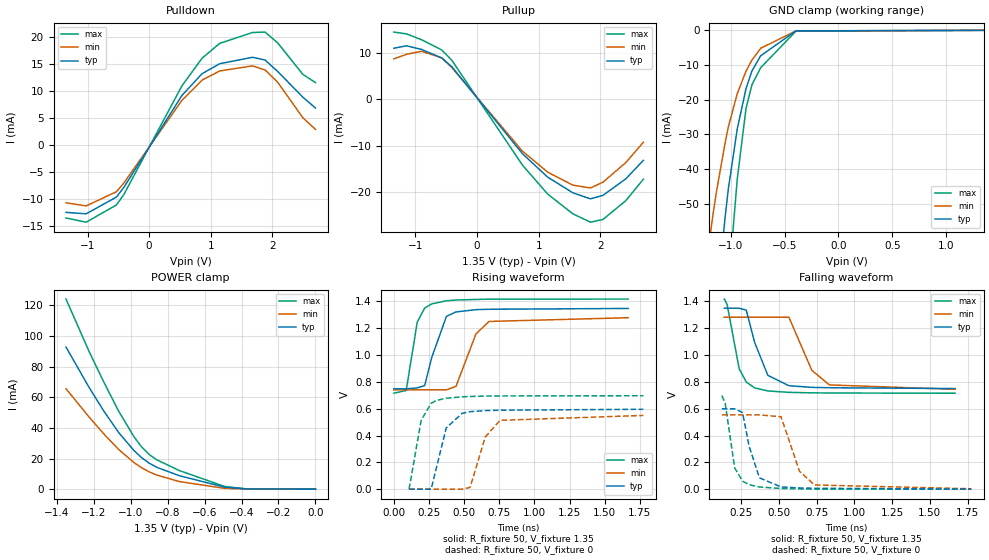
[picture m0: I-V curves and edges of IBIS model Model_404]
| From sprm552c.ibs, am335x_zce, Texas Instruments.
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| Model based on original model for BCSHTLTCSCDVPBFZ_SSDHV
|   Sub model SR00_6MA_5PER_1P35
[model]   Model_404
|[Description]  [1.35V-3-STATE-NOTERM-SR00:6MA, IND, 5%]
|   Fastest slew rate (SR[1:0] = "00"), 1.33 * RExt = 0.750 * Iout
|   (I[2:0] = "001"), 6mA nominal with Rext = 50R,ODT off (ODT[1:0]
|   = "00") CMOS mode,Industrial temperature range (-40C to 125C,
|   25C nominal),5% power supply tolerance
|[Input Load]   NOTERM
|[Output Drive] SR00:6MA
|Voltage   1.35V
|Mode   3-STATE
Model_type   3-state
Polarity   Non-Inverting
Enable   Active-Low
Cref =  15pF
Rref =  100.0000M
Vref =  0V
Vmeas =  0.675
C_comp   1.865048p   1.679967p   1.989968p
[Temperature Range]   25   125   -40
[Voltage Range]   1.35   1.2825   1.4175
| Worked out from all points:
|   slope of the pulldown table from 0 to 0.203 V, typ, clamps not added: 53.9 ohm
|   slope of the pullup table from 0 to 0.203 V, typ, clamps not added: 58.7 ohm
|   GND clamp passes 1 mA (typ) near -0.49 V on its own axis
|   POWER clamp passes 1 mA (typ) near -0.47 V on its own axis
|   rising waveform, R_fixture 50, V_fixture 1.35: 20-80 % time 85.6ps typ, 117ps min, 65.7ps max; typ from 0.748 V to 1.35 V
|   rising waveform, R_fixture 50, V_fixture 0: 20-80 % time 86.9ps typ, 103ps min, 71.9ps max; typ from 0 V to 0.596 V
|   falling waveform, R_fixture 50, V_fixture 1.35: 20-80 % time 102ps typ, 124ps min, 80ps max; typ from 1.35 V to 0.75 V
|   falling waveform, R_fixture 50, V_fixture 0: 20-80 % time 72.4ps typ, 91.8ps min, 58.8ps max; typ from 0.599 V to 0 V
[POWER_clamp]
-1.35V    92.75mA    65.58mA    124.1mA
-1.227V   66.81mA    47.37mA    90.43mA
-1.145V   50.92mA    36.04mA    69.8mA
-1.064V   36.83mA    25.8mA     50.7mA
-981.8mV  25.17mA    17.34mA    34.14mA
-940.9mV  20.58mA    14.01mA    27.56mA
-900mV    17mA       11.33mA    22.64mA
-859.1mV  14.3mA     9.214mA    19.2mA
-736.4mV  8.769mA    4.942mA    12.14mA
-490.9mV  1.299mA    528.4uA    1.73mA
-368.2mV  117.2uA    50.88uA    117.5uA
0V        1.028nA    11.95nA    1.029nA
[Pulldown]
-1.35V    -12.46mA   -10.69mA   -13.5mA
-1.023V   -12.73mA   -11.27mA   -14.28mA
-531.8mV  -9.642mA   -8.642mA   -11.1mA
-409.1mV  -7.802mA   -7.007mA   -9.123mA
531.8mV   9.169mA    8.275mA    10.95mA
859.1mV   13.21mA    12.02mA    16.07mA
1.145V    15.05mA    13.71mA    18.82mA
1.677V    16.25mA    14.66mA    20.83mA
1.882V    15.74mA    13.9mA     20.91mA
2.086V    13.63mA    11.64mA    18.93mA
2.495V    8.875mA    5.068mA    13.09mA
2.7V      6.853mA    2.908mA    11.56mA
[Pullup]
-1.35V    11.03mA    8.75mA     14.52mA
-1.145V   11.56mA    9.727mA    14.13mA
-900mV    10.77mA    10.38mA    12.87mA
-572.7mV  8.933mA    8.936mA    10.65mA
-409.1mV  7.026mA    6.847mA    8.416mA
736.4mV   -11.73mA   -11.18mA   -14.19mA
1.145V    -16.79mA   -15.71mA   -20.44mA
1.555V    -20.18mA   -18.53mA   -24.72mA
1.841V    -21.49mA   -19.14mA   -26.53mA
2.045V    -20.73mA   -17.88mA   -25.93mA
2.414V    -17.18mA   -13.67mA   -21.89mA
2.7V      -13.18mA   -9.274mA   -17.26mA
[GND_clamp]
-1.35V    -159.1mA   -94.77mA   -266.2mA
-1.295V   -137.7mA   -81.77mA   -230.9mA
-1.159V   -87.19mA   -51.56mA   -145.9mA
-1.132V   -77.89mA   -46.14mA   -129.9mA
-1.05V    -52.83mA   -31.84mA   -86.44mA
-1.023V   -45.55mA   -27.75mA   -73.68mA
-940.9mV  -28.44mA   -18.28mA   -42.92mA
-859.1mV  -16.79mA   -11.75mA   -22.47mA
-804.5mV  -11.72mA   -8.559mA   -15.69mA
-722.7mV  -7.324mA   -5.162mA   -10.76mA
-395.5mV  -159.1uA   -161.1uA   -232.3uA
1.35V     1.028nA    30.09nA    754.3pA
[Ramp]
dV/dt_f 0.36654123/0.10332135n 0.33147604/0.12743856n 0.42591407/80.212p
dV/dt_r 0.36566786/88.223296p  0.3418671/0.10556472n  0.4245304/72.055315p
R_load = 50
[Rising Waveform]
R_fixture = 50
V_fixture = 1.35
V_fixture_min = 1.2825
V_fixture_max = 1.4175
0s        748.5mV    741mV      716.1mV
87.22ps   748.5mV    741mV      736.1mV
166.3ps   755.7mV    741mV      1.247V
219ps     772.5mV    741mV      1.351V
268.8ps   981.3mV    741mV      1.382V
373.7ps   1.289V     741mV      1.405V
441.6ps   1.322V     766.6mV    1.411V
583.7ps   1.339V     1.158V     1.415V
676.7ps   1.342V     1.251V     1.417V
1.667ns   1.348V     1.279V     1.418V
[Rising Waveform]
R_fixture = 50
V_fixture = 0
V_fixture_min = 0
V_fixture_max = 0
107.9ps   0V         0V         0V
193.7ps   0V         0V         513.2mV
264.8ps   0V         0V         640.4mV
301.2ps   154.4mV    0V         661.2mV
372.1ps   456.4mV    0V         678.7mV
485.2ps   565.7mV    0V         688.9mV
542ps     577.9mV    13.3mV     691.3mV
650.5ps   586.1mV    389.9mV    694.1mV
755.5ps   589mV      513.4mV    695.5mV
1.775ns   596mV      550.1mV    697mV
[Falling Waveform]
R_fixture = 50
V_fixture = 1.35
V_fixture_min = 1.2825
V_fixture_max = 1.4175
137.3ps   1.349V     1.282V     1.417V
156.2ps   1.349V     1.282V     1.377V
236.1ps   1.349V     1.282V     898mV
283.3ps   1.334V     1.282V     798.7mV
338.6ps   1.094V     1.282V     754.9mV
426.3ps   848.2mV    1.282V     732.2mV
565.6ps   771.2mV    1.282V     721.6mV
717.8ps   758.9mV    885.9mV    718mV
834.1ps   756mV      777mV      716.8mV
1.667ns   749.9mV    744.2mV    715.1mV
[Falling Waveform]
R_fixture = 50
V_fixture = 0
V_fixture_min = 0
V_fixture_max = 0
121.2ps   598.7mV    553.6mV    697.4mV
143.4ps   598.7mV    553.6mV    642mV
206.4ps   598.7mV    553.6mV    158.3mV
258.4ps   570.9mV    553.6mV    60.07mV
302ps     320.6mV    553.6mV    33.23mV
370.4ps   84.57mV    553.6mV    16.01mV
513.8ps   16.73mV    539.8mV    5.148mV
635.8ps   8.953mV    133.8mV    2.428mV
735.4ps   6.827mV    31.29mV    0V
1.775ns   0V         3.053mV    0V
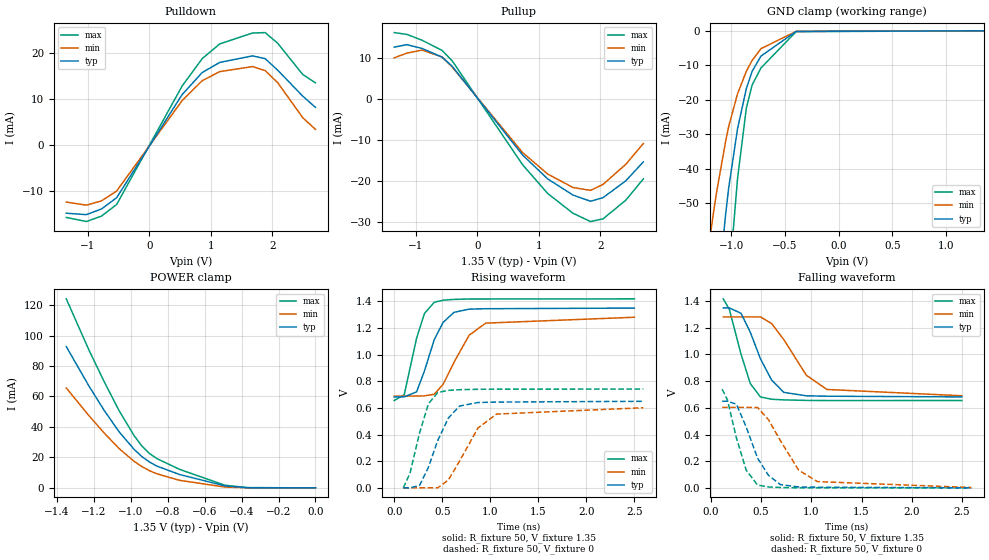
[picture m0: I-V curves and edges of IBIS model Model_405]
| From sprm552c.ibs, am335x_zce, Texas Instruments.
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| Model based on original model for BCSHTLTCSCDVPBFZ_SSDHV
|   Sub model SR10_7MA_5PER_1P35
[model]   Model_405
|[Description]  [1.35V-3-STATE-NOTERM-SR10:7MA, IND, 5%]
|   Fast slew rate (SR[1:0] = "10"), 1.14 * RExt = 0.875 * Iout
|   (I[2:0] = "010"), 7mA nominal with Rext = 50R,ODT off (ODT[1:0]
|   = "00") CMOS mode,Industrial temperature range (-40C to 125C,
|   25C nominal),5% power supply tolerance
|[Input Load]   NOTERM
|[Output Drive] SR10:7MA
|Voltage   1.35V
|Mode   3-STATE
Model_type   3-state
Polarity   Non-Inverting
Enable   Active-Low
Cref =  15pF
Rref =  100.0000M
Vref =  0V
Vmeas =  0.675
C_comp   1.865048p   1.679967p   1.989968p
[Temperature Range]   25   125   -40
[Voltage Range]   1.35   1.2825   1.4175
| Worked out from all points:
|   slope of the pulldown table from 0 to 0.203 V, typ, clamps not added: 45.3 ohm
|   slope of the pullup table from 0 to 0.203 V, typ, clamps not added: 50.7 ohm
|   GND clamp passes 1 mA (typ) near -0.49 V on its own axis
|   POWER clamp passes 1 mA (typ) near -0.47 V on its own axis
|   rising waveform, R_fixture 50, V_fixture 1.35: 20-80 % time 199ps typ, 271ps min, 146ps max; typ from 0.682 V to 1.35 V
|   rising waveform, R_fixture 50, V_fixture 0: 20-80 % time 217ps typ, 293ps min, 157ps max; typ from 0 V to 0.649 V
|   falling waveform, R_fixture 50, V_fixture 1.35: 20-80 % time 233ps typ, 324ps min, 165ps max; typ from 1.35 V to 0.682 V
|   falling waveform, R_fixture 50, V_fixture 0: 20-80 % time 218ps typ, 291ps min, 156ps max; typ from 0.649 V to 0 V
[POWER_clamp]
-1.35V    92.75mA    65.58mA    124.1mA
-1.227V   66.81mA    47.37mA    90.43mA
-1.145V   50.92mA    36.04mA    69.8mA
-1.064V   36.83mA    25.8mA     50.7mA
-981.8mV  25.17mA    17.34mA    34.14mA
-940.9mV  20.58mA    14.01mA    27.56mA
-900mV    17mA       11.33mA    22.64mA
-859.1mV  14.3mA     9.214mA    19.2mA
-736.4mV  8.769mA    4.942mA    12.14mA
-490.9mV  1.299mA    528.4uA    1.73mA
-368.2mV  117.2uA    50.88uA    117.5uA
0V        1.028nA    11.95nA    1.029nA
[Pulldown]
-1.35V    -14.84mA   -12.42mA   -15.75mA
-1.023V   -15.15mA   -13.09mA   -16.65mA
-777.3mV  -13.91mA   -12.15mA   -15.46mA
-531.8mV  -11.48mA   -10.03mA   -12.95mA
531.8mV   10.91mA    9.608mA    12.77mA
859.1mV   15.73mA    13.95mA    18.74mA
1.145V    17.92mA    15.92mA    21.95mA
1.677V    19.34mA    17.02mA    24.3mA
1.882V    18.74mA    16.14mA    24.4mA
2.086V    16.23mA    13.52mA    22.09mA
2.495V    10.57mA    5.887mA    15.28mA
2.7V      8.16mA     3.378mA    13.49mA
[Pullup]
-1.35V    12.77mA    10.16mA    16.33mA
-1.145V   13.38mA    11.3mA     15.89mA
-900mV    12.47mA    12.05mA    14.48mA
-572.7mV  10.34mA    10.38mA    11.98mA
-409.1mV  8.134mA    7.949mA    9.466mA
736.4mV   -13.58mA   -12.98mA   -15.96mA
1.145V    -19.43mA   -18.24mA   -22.99mA
1.555V    -23.37mA   -21.52mA   -27.81mA
1.841V    -24.89mA   -22.23mA   -29.85mA
2.045V    -24mA      -20.76mA   -29.18mA
2.414V    -19.9mA    -15.87mA   -24.63mA
2.7V      -15.26mA   -10.77mA   -19.42mA
[GND_clamp]
-1.35V    -159.1mA   -94.77mA   -266.2mA
-1.295V   -137.7mA   -81.77mA   -230.9mA
-1.159V   -87.19mA   -51.56mA   -145.9mA
-1.132V   -77.89mA   -46.14mA   -129.9mA
-1.05V    -52.83mA   -31.84mA   -86.44mA
-1.023V   -45.55mA   -27.75mA   -73.68mA
-940.9mV  -28.44mA   -18.28mA   -42.92mA
-859.1mV  -16.79mA   -11.75mA   -22.47mA
-804.5mV  -11.72mA   -8.559mA   -15.69mA
-722.7mV  -7.324mA   -5.162mA   -10.76mA
-395.5mV  -159.1uA   -161.1uA   -232.3uA
1.35V     1.028nA    30.09nA    754.3pA
[Ramp]
dV/dt_f 0.40239561/0.23431649n 0.35863473/0.32879546n  0.4586357/0.16547522n
dV/dt_r 0.39167895/0.2185233n 0.36504969/0.29748008n 0.44594211/0.15712017n
R_load = 50
[Rising Waveform]
R_fixture = 50
V_fixture = 1.35
V_fixture_min = 1.2825
V_fixture_max = 1.4175
0s        681.9mV    688.2mV    655.4mV
104.5ps   682.7mV    688.2mV    699.2mV
233.1ps   720.2mV    689mV      1.123V
314.9ps   876.9mV    690.1mV    1.308V
416.4ps   1.111V     702.2mV    1.392V
508.7ps   1.241V     776.1mV    1.408V
623.1ps   1.317V     943.2mV    1.414V
779.8ps   1.341V     1.145V     1.417V
952.9ps   1.344V     1.236V     1.417V
2.5ns     1.349V     1.28V      1.418V
[Rising Waveform]
R_fixture = 50
V_fixture = 0
V_fixture_min = 0
V_fixture_max = 0
94.22ps   0V         0V         0V
164ps     0V         0V         108.5mV
263.5ps   17.54mV    0V         410.7mV
355.9ps   153.6mV    0V         629.7mV
452.7ps   354.4mV    0V         715.6mV
564.1ps   524.2mV    59.23mV    731.4mV
680.4ps   613.7mV    200.4mV    736.5mV
872.2ps   640.3mV    448.8mV    739.5mV
1.066ns   643.5mV    553.4mV    740.5mV
2.594ns   649.4mV    601.2mV    741mV
[Falling Waveform]
R_fixture = 50
V_fixture = 1.35
V_fixture_min = 1.2825
V_fixture_max = 1.4175
122.5ps   1.349V     1.282V     1.417V
183.5ps   1.349V     1.282V     1.337V
299.1ps   1.309V     1.282V     1.003V
391.7ps   1.167V     1.282V     782.1mV
493.5ps   966.6mV    1.282V     681.2mV
603.8ps   808.9mV    1.232V     664.5mV
725.5ps   715.9mV    1.112V     659.6mV
950.1ps   690.1mV    844.2mV    655.7mV
1.155ns   687.1mV    737.7mV    654.7mV
2.5ns     681.9mV    690.5mV    654.8mV
[Falling Waveform]
R_fixture = 50
V_fixture = 0
V_fixture_min = 0
V_fixture_max = 0
110.9ps   649.3mV    603.8mV    740.2mV
164.3ps   649.3mV    603.8mV    659.2mV
253.4ps   627.3mV    603.8mV    374.5mV
350.6ps   456.6mV    603.8mV    133.6mV
464.4ps   222.6mV    602mV      20.57mV
573.4ps   93.16mV    510.6mV    6.558mV
692.5ps   23.87mV    353.2mV    2.874mV
873.3ps   6.794mV    133.1mV    0V
1.06ns    4.732mV    46.81mV    0V
2.594ns   0V         2.512mV    0V
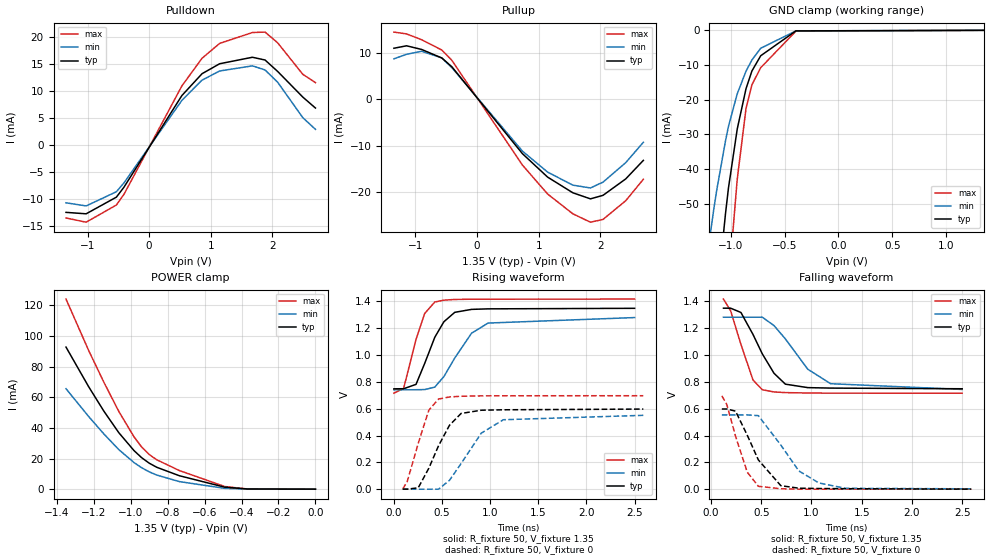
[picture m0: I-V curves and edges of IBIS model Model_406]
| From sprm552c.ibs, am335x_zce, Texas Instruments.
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| Model based on original model for BCSHTLTCSCDVPBFZ_SSDHV
|   Sub model SR10_6MA_5PER_1P35
[model]   Model_406
|[Description]  [1.35V-3-STATE-NOTERM-SR10:6MA, IND, 5%]
|   Fast slew rate (SR[1:0] = "10"), 1.33 * RExt = 0.750 * Iout
|   (I[2:0] = "001"), 6mA nominal with Rext = 50R,ODT off (ODT[1:0]
|   = "00") CMOS mode,Industrial temperature range (-40C to 125C,
|   25C nominal),5% power supply tolerance
|[Input Load]   NOTERM
|[Output Drive] SR10:6MA
|Voltage   1.35V
|Mode   3-STATE
Model_type   3-state
Polarity   Non-Inverting
Enable   Active-Low
Cref =  15pF
Rref =  100.0000M
Vref =  0V
Vmeas =  0.675
C_comp   1.865048p   1.679967p   1.989968p
[Temperature Range]   25   125   -40
[Voltage Range]   1.35   1.2825   1.4175
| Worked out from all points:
|   slope of the pulldown table from 0 to 0.203 V, typ, clamps not added: 53.9 ohm
|   slope of the pullup table from 0 to 0.203 V, typ, clamps not added: 58.7 ohm
|   GND clamp passes 1 mA (typ) near -0.49 V on its own axis
|   POWER clamp passes 1 mA (typ) near -0.47 V on its own axis
|   rising waveform, R_fixture 50, V_fixture 1.35: 20-80 % time 215ps typ, 293ps min, 155ps max; typ from 0.749 V to 1.35 V
|   rising waveform, R_fixture 50, V_fixture 0: 20-80 % time 240ps typ, 319ps min, 171ps max; typ from 0 V to 0.597 V
|   falling waveform, R_fixture 50, V_fixture 1.35: 20-80 % time 253ps typ, 352ps min, 173ps max; typ from 1.35 V to 0.748 V
|   falling waveform, R_fixture 50, V_fixture 0: 20-80 % time 239ps typ, 318ps min, 168ps max; typ from 0.598 V to 0 V
[POWER_clamp]
-1.35V    92.75mA    65.58mA    124.1mA
-1.227V   66.81mA    47.37mA    90.43mA
-1.145V   50.92mA    36.04mA    69.8mA
-1.064V   36.83mA    25.8mA     50.7mA
-981.8mV  25.17mA    17.34mA    34.14mA
-940.9mV  20.58mA    14.01mA    27.56mA
-900mV    17mA       11.33mA    22.64mA
-859.1mV  14.3mA     9.214mA    19.2mA
-736.4mV  8.769mA    4.942mA    12.14mA
-490.9mV  1.299mA    528.4uA    1.73mA
-368.2mV  117.2uA    50.88uA    117.5uA
0V        1.028nA    11.95nA    1.029nA
[Pulldown]
-1.35V    -12.46mA   -10.69mA   -13.5mA
-1.023V   -12.73mA   -11.27mA   -14.28mA
-531.8mV  -9.642mA   -8.642mA   -11.1mA
-409.1mV  -7.802mA   -7.007mA   -9.123mA
531.8mV   9.169mA    8.275mA    10.95mA
859.1mV   13.21mA    12.02mA    16.07mA
1.145V    15.05mA    13.71mA    18.82mA
1.677V    16.25mA    14.66mA    20.83mA
1.882V    15.74mA    13.9mA     20.91mA
2.086V    13.63mA    11.64mA    18.93mA
2.495V    8.875mA    5.068mA    13.09mA
2.7V      6.853mA    2.908mA    11.56mA
[Pullup]
-1.35V    11.03mA    8.75mA     14.52mA
-1.145V   11.56mA    9.727mA    14.13mA
-900mV    10.77mA    10.38mA    12.87mA
-572.7mV  8.933mA    8.936mA    10.65mA
-409.1mV  7.026mA    6.847mA    8.416mA
736.4mV   -11.73mA   -11.18mA   -14.19mA
1.145V    -16.79mA   -15.71mA   -20.44mA
1.555V    -20.18mA   -18.53mA   -24.72mA
1.841V    -21.49mA   -19.14mA   -26.53mA
2.045V    -20.73mA   -17.88mA   -25.93mA
2.414V    -17.18mA   -13.67mA   -21.89mA
2.7V      -13.18mA   -9.274mA   -17.26mA
[GND_clamp]
-1.35V    -159.1mA   -94.77mA   -266.2mA
-1.295V   -137.7mA   -81.77mA   -230.9mA
-1.159V   -87.19mA   -51.56mA   -145.9mA
-1.132V   -77.89mA   -46.14mA   -129.9mA
-1.05V    -52.83mA   -31.84mA   -86.44mA
-1.023V   -45.55mA   -27.75mA   -73.68mA
-940.9mV  -28.44mA   -18.28mA   -42.92mA
-859.1mV  -16.79mA   -11.75mA   -22.47mA
-804.5mV  -11.72mA   -8.559mA   -15.69mA
-722.7mV  -7.324mA   -5.162mA   -10.76mA
-395.5mV  -159.1uA   -161.1uA   -232.3uA
1.35V     1.028nA    30.09nA    754.3pA
[Ramp]
dV/dt_f 0.36248383/0.25431711n  0.3268385/0.35794185n 0.42217958/0.17349575n
dV/dt_r  0.3603536/0.24124927n 0.33460504/0.3247215n 0.41937673/0.17155983n
R_load = 50
[Rising Waveform]
R_fixture = 50
V_fixture = 1.35
V_fixture_min = 1.2825
V_fixture_max = 1.4175
0s        748.5mV    741mV      716.1mV
101.2ps   749.1mV    741mV      752.2mV
229.7ps   781.8mV    741.8mV    1.118V
320.3ps   939.2mV    742.9mV    1.311V
424.5ps   1.133V     761.3mV    1.396V
519.2ps   1.249V     840mV      1.41V
631.9ps   1.319V     978.3mV    1.415V
806ps     1.341V     1.163V     1.417V
978.2ps   1.345V     1.239V     1.417V
2.5ns     1.349V     1.28V      1.418V
[Rising Waveform]
R_fixture = 50
V_fixture = 0
V_fixture_min = 0
V_fixture_max = 0
91.24ps   0V         0V         0V
138.9ps   0V         0V         58.4mV
252.6ps   10.3mV     0V         341.8mV
362.4ps   156mV      0V         588.9mV
463.9ps   324.4mV    0V         672.5mV
576.9ps   476.3mV    65.72mV    687.8mV
697.5ps   564.7mV    190.6mV    692.9mV
908.1ps   588.9mV    418.3mV    695.9mV
1.137ns   592.1mV    518mV      696.7mV
2.591ns   597.4mV    550.8mV    697mV
[Falling Waveform]
R_fixture = 50
V_fixture = 1.35
V_fixture_min = 1.2825
V_fixture_max = 1.4175
123.7ps   1.349V     1.282V     1.417V
195.2ps   1.349V     1.282V     1.33V
297.8ps   1.317V     1.282V     1.079V
418.1ps   1.153V     1.282V     813.4mV
510.3ps   1.009V     1.282V     741.4mV
627.5ps   863.5mV    1.219V     724.6mV
740.4ps   782.7mV    1.12V      719.8mV
963.2ps   756.9mV    894.1mV    716.7mV
1.191ns   753.4mV    786mV      715.7mV
2.5ns     748.4mV    743.3mV    715.1mV
[Falling Waveform]
R_fixture = 50
V_fixture = 0
V_fixture_min = 0
V_fixture_max = 0
107.7ps   597.5mV    553.5mV    696.1mV
157.6ps   597.5mV    553.5mV    630.2mV
244ps     581.7mV    553.5mV    395.2mV
361.3ps   401.5mV    553.5mV    125.7mV
471.4ps   217.8mV    547.9mV    21.24mV
695.2ps   25.83mV    328.6mV    3.182mV
874.1ps   7.331mV    136.1mV    0V
1.074ns   4.899mV    46.36mV    0V
1.342ns   3.463mV    6.15mV     0V
2.591ns   0V         2.577mV    0V
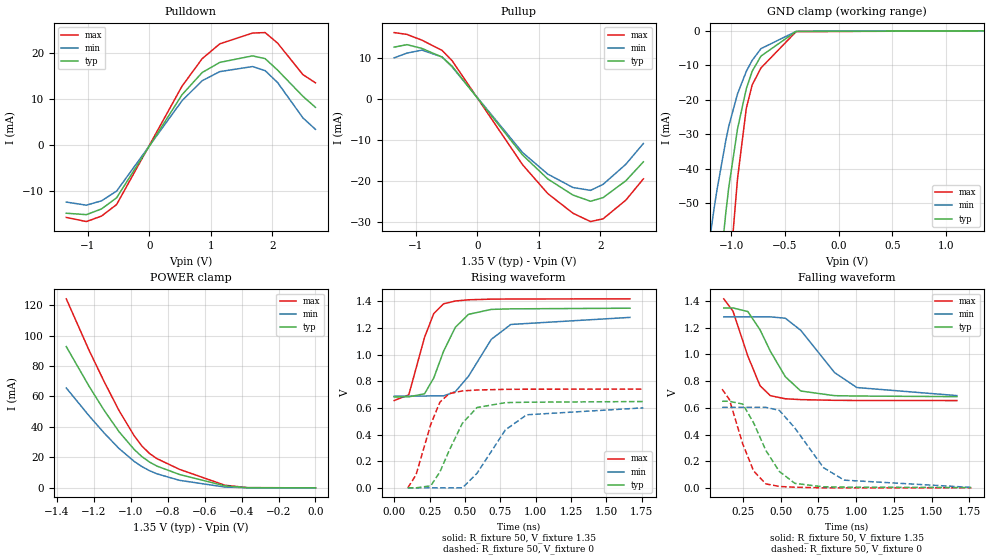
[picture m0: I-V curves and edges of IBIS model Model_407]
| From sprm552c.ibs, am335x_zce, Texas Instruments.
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| Model based on original model for BCSHTLTCSCDVPBFZ_SSDHV
|   Sub model SR01_7MA_5PER_1P35
[model]   Model_407
|[Description]  [1.35V-3-STATE-NOTERM-SR01:7MA, IND, 5%]
|   Slow slew rate (SR[1:0] = "01"), 1.14 * RExt = 0.875 * Iout
|   (I[2:0] = "010"), 7mA nominal with Rext = 50R,ODT off (ODT[1:0]
|   = "00") CMOS mode,Industrial temperature range (-40C to 125C,
|   25C nominal),5% power supply tolerance
|[Input Load]   NOTERM
|[Output Drive] SR01:7MA
|Voltage   1.35V
|Mode   3-STATE
Model_type   3-state
Polarity   Non-Inverting
Enable   Active-Low
Cref =  15pF
Rref =  100.0000M
Vref =  0V
Vmeas =  0.675
C_comp   1.865048p   1.679967p   1.989968p
[Temperature Range]   25   125   -40
[Voltage Range]   1.35   1.2825   1.4175
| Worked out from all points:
|   slope of the pulldown table from 0 to 0.203 V, typ, clamps not added: 45.3 ohm
|   slope of the pullup table from 0 to 0.203 V, typ, clamps not added: 50.7 ohm
|   GND clamp passes 1 mA (typ) near -0.49 V on its own axis
|   POWER clamp passes 1 mA (typ) near -0.47 V on its own axis
|   rising waveform, R_fixture 50, V_fixture 1.35: 20-80 % time 163ps typ, 221ps min, 122ps max; typ from 0.682 V to 1.35 V
|   rising waveform, R_fixture 50, V_fixture 0: 20-80 % time 176ps typ, 236ps min, 129ps max; typ from 0 V to 0.648 V
|   falling waveform, R_fixture 50, V_fixture 1.35: 20-80 % time 193ps typ, 265ps min, 140ps max; typ from 1.35 V to 0.684 V
|   falling waveform, R_fixture 50, V_fixture 0: 20-80 % time 177ps typ, 239ps min, 129ps max; typ from 0.649 V to 0.002 V
[POWER_clamp]
-1.35V    92.75mA    65.58mA    124.1mA
-1.227V   66.81mA    47.37mA    90.43mA
-1.145V   50.92mA    36.04mA    69.8mA
-1.064V   36.83mA    25.8mA     50.7mA
-981.8mV  25.17mA    17.34mA    34.14mA
-940.9mV  20.58mA    14.01mA    27.56mA
-900mV    17mA       11.33mA    22.64mA
-859.1mV  14.3mA     9.214mA    19.2mA
-736.4mV  8.769mA    4.942mA    12.14mA
-490.9mV  1.299mA    528.4uA    1.73mA
-368.2mV  117.2uA    50.88uA    117.5uA
0V        1.028nA    11.95nA    1.029nA
[Pulldown]
-1.35V    -14.84mA   -12.42mA   -15.75mA
-1.023V   -15.15mA   -13.09mA   -16.65mA
-777.3mV  -13.91mA   -12.15mA   -15.46mA
-531.8mV  -11.48mA   -10.03mA   -12.95mA
531.8mV   10.91mA    9.608mA    12.77mA
859.1mV   15.73mA    13.95mA    18.74mA
1.145V    17.92mA    15.92mA    21.95mA
1.677V    19.34mA    17.02mA    24.3mA
1.882V    18.74mA    16.14mA    24.4mA
2.086V    16.23mA    13.52mA    22.09mA
2.495V    10.57mA    5.887mA    15.28mA
2.7V      8.16mA     3.378mA    13.49mA
[Pullup]
-1.35V    12.77mA    10.16mA    16.33mA
-1.145V   13.38mA    11.3mA     15.89mA
-900mV    12.47mA    12.05mA    14.48mA
-572.7mV  10.34mA    10.38mA    11.98mA
-409.1mV  8.134mA    7.949mA    9.466mA
736.4mV   -13.58mA   -12.98mA   -15.96mA
1.145V    -19.43mA   -18.24mA   -22.99mA
1.555V    -23.37mA   -21.52mA   -27.81mA
1.841V    -24.89mA   -22.23mA   -29.85mA
2.045V    -24mA      -20.76mA   -29.18mA
2.414V    -19.9mA    -15.87mA   -24.63mA
2.7V      -15.26mA   -10.77mA   -19.42mA
[GND_clamp]
-1.35V    -159.1mA   -94.77mA   -266.2mA
-1.295V   -137.7mA   -81.77mA   -230.9mA
-1.159V   -87.19mA   -51.56mA   -145.9mA
-1.132V   -77.89mA   -46.14mA   -129.9mA
-1.05V    -52.83mA   -31.84mA   -86.44mA
-1.023V   -45.55mA   -27.75mA   -73.68mA
-940.9mV  -28.44mA   -18.28mA   -42.92mA
-859.1mV  -16.79mA   -11.75mA   -22.47mA
-804.5mV  -11.72mA   -8.559mA   -15.69mA
-722.7mV  -7.324mA   -5.162mA   -10.76mA
-395.5mV  -159.1uA   -161.1uA   -232.3uA
1.35V     1.028nA    30.09nA    754.3pA
[Ramp]
dV/dt_f 0.40247092/0.19496347n 0.35872917/0.27012042n 0.45870625/0.13994881n
dV/dt_r 0.39183346/0.17756107n  0.3651668/0.24010427n 0.44607591/0.1289125n
R_load = 50
[Rising Waveform]
R_fixture = 50
V_fixture = 1.35
V_fixture_min = 1.2825
V_fixture_max = 1.4175
0s        682mV      688.2mV    655.4mV
103.2ps   682.7mV    688.2mV    698.1mV
214.7ps   706.3mV    688.7mV    1.13V
279.9ps   824.9mV    690.6mV    1.308V
349.1ps   1.025V     690.2mV    1.381V
432.5ps   1.205V     721.8mV    1.402V
525.7ps   1.302V     837.8mV    1.411V
686.4ps   1.339V     1.114V     1.416V
824.6ps   1.343V     1.226V     1.417V
1.667ns   1.348V     1.279V     1.418V
[Rising Waveform]
R_fixture = 50
V_fixture = 0
V_fixture_min = 0
V_fixture_max = 0
95.78ps   0V         0V         0V
154.1ps   0V         0V         96.73mV
258.7ps   15.37mV    0V         477mV
323.3ps   119.7mV    0V         643.4mV
388.1ps   278.5mV    0V         706.4mV
482.1ps   484.7mV    0V         727.3mV
585.6ps   602.6mV    109.4mV    734.3mV
786.3ps   639.4mV    434.7mV    739mV
936.6ps   642.4mV    548.1mV    740.1mV
1.762ns   647.7mV    600.3mV    741mV
[Falling Waveform]
R_fixture = 50
V_fixture = 1.35
V_fixture_min = 1.2825
V_fixture_max = 1.4175
124.8ps   1.349V     1.282V     1.417V
185.1ps   1.349V     1.282V     1.326V
283.5ps   1.322V     1.282V     989.6mV
364.3ps   1.186V     1.282V     766.7mV
432.6ps   1.025V     1.282V     691.1mV
531.9ps   833.1mV    1.272V     668mV
634.1ps   726.1mV    1.181V     661.5mV
857.2ps   691.2mV    864.8mV    656.4mV
1.005ns   688.4mV    752.1mV    655.1mV
1.667ns   684mV      691.8mV    654.4mV
[Falling Waveform]
R_fixture = 50
V_fixture = 0
V_fixture_min = 0
V_fixture_max = 0
113.8ps   649.3mV    603.6mV    740.1mV
161.8ps   649.3mV    603.6mV    662.5mV
250.4ps   627.9mV    603.6mV    328.2mV
322.8ps   486.1mV    603.6mV    125.7mV
402.6ps   281.4mV    603.6mV    29.87mV
492.2ps   123mV      581.2mV    10.37mV
595.4ps   33.38mV    448mV      4.584mV
784.6ps   7.611mV    151.1mV    0V
921.5ps   5.54mV     57.73mV    0V
1.762ns   2.141mV    3.173mV    0V
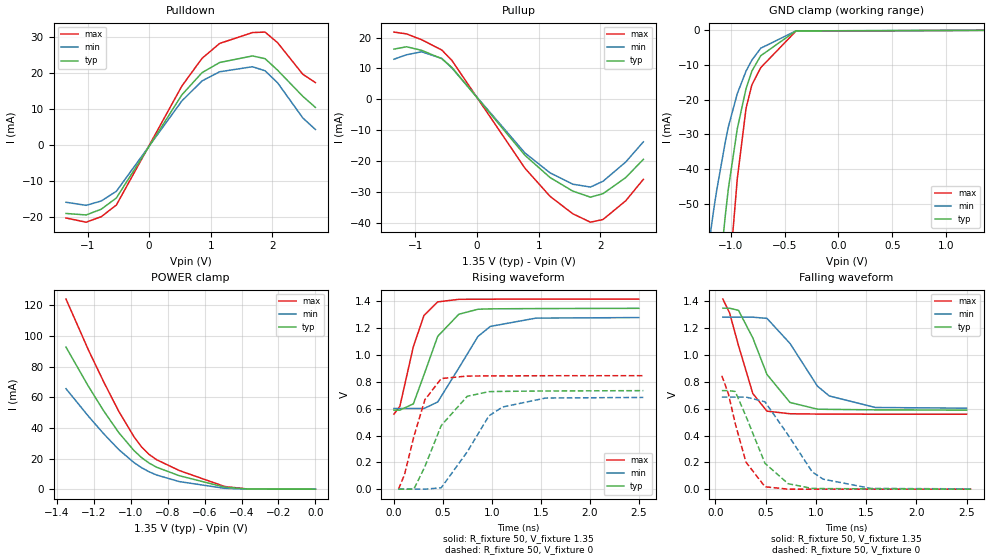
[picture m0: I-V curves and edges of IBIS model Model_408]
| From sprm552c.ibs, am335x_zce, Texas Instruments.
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| Model based on original model for BCSHTLTCSCDVPBFZ_SSDHV
|   Sub model SR11_9MA_5PER_1P35
[model]   Model_408
|[Description]  [1.35V-3-STATE-NOTERM-SR11:9MA, IND, 5%]
|   Slowest slew rate (SR[1:0] = "11"), 0.88 * RExt = 1.125 * Iout
|   (I[2:0] = "100"), 9mA nominal with Rext = 50R,ODT off (ODT[1:0]
|   = "00") CMOS mode,Industrial temperature range (-40C to 125C,
|   25C nominal),5% power supply tolerance
|[Input Load]   NOTERM
|[Output Drive] SR11:9MA
|Voltage   1.35V
|Mode   3-STATE
Model_type   3-state
Polarity   Non-Inverting
Enable   Active-Low
Cref =  15pF
Rref =  100.0000M
Vref =  0V
Vmeas =  0.675
C_comp   1.865048p   1.679967p   1.989968p
[Temperature Range]   25   125   -40
[Voltage Range]   1.35   1.2825   1.4175
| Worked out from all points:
|   slope of the pulldown table from 0 to 0.203 V, typ, clamps not added: 35.4 ohm
|   slope of the pullup table from 0 to 0.203 V, typ, clamps not added: 39.9 ohm
|   GND clamp passes 1 mA (typ) near -0.49 V on its own axis
|   POWER clamp passes 1 mA (typ) near -0.47 V on its own axis
|   rising waveform, R_fixture 50, V_fixture 1.35: 20-80 % time 235ps typ, 334ps min, 172ps max; typ from 0.589 V to 1.35 V
|   rising waveform, R_fixture 50, V_fixture 0: 20-80 % time 268ps typ, 348ps min, 194ps max; typ from 0 V to 0.735 V
|   falling waveform, R_fixture 50, V_fixture 1.35: 20-80 % time 276ps typ, 370ps min, 195ps max; typ from 1.35 V to 0.589 V
|   falling waveform, R_fixture 50, V_fixture 0: 20-80 % time 253ps typ, 356ps min, 185ps max; typ from 0.735 V to 0 V
[POWER_clamp]
-1.35V    92.75mA    65.58mA    124.1mA
-1.227V   66.81mA    47.37mA    90.43mA
-1.145V   50.92mA    36.04mA    69.8mA
-1.064V   36.83mA    25.8mA     50.7mA
-981.8mV  25.17mA    17.34mA    34.14mA
-940.9mV  20.58mA    14.01mA    27.56mA
-900mV    17mA       11.33mA    22.64mA
-859.1mV  14.3mA     9.214mA    19.2mA
-736.4mV  8.769mA    4.942mA    12.14mA
-490.9mV  1.299mA    528.4uA    1.73mA
-368.2mV  117.2uA    50.88uA    117.5uA
0V        1.028nA    11.95nA    1.029nA
[Pulldown]
-1.35V    -18.99mA   -15.87mA   -20.25mA
-1.023V   -19.4mA    -16.73mA   -21.41mA
-777.3mV  -17.8mA    -15.52mA   -19.88mA
-531.8mV  -14.68mA   -12.82mA   -16.64mA
531.8mV   13.96mA    12.27mA    16.41mA
859.1mV   20.12mA    17.82mA    24.09mA
1.145V    22.93mA    20.35mA    28.22mA
1.677V    24.75mA    21.75mA    31.24mA
1.882V    23.99mA    20.63mA    31.37mA
2.086V    20.78mA    17.28mA    28.42mA
2.495V    13.53mA    7.525mA    19.65mA
2.7V      10.45mA    4.317mA    17.35mA
[Pullup]
-1.35V    16.26mA    12.99mA    21.78mA
-1.145V   17.03mA    14.44mA    21.19mA
-900mV    15.87mA    15.4mA     19.31mA
-572.7mV  13.16mA    13.25mA    15.97mA
-409.1mV  10.35mA    10.15mA    12.61mA
777.3mV   -18.12mA   -17.36mA   -22.31mA
1.186V    -25.34mA   -23.83mA   -31.43mA
1.555V    -29.73mA   -27.49mA   -37.07mA
1.841V    -31.68mA   -28.41mA   -39.79mA
2.045V    -30.55mA   -26.54mA   -38.92mA
2.414V    -25.34mA   -20.29mA   -32.85mA
2.7V      -19.43mA   -13.77mA   -25.91mA
[GND_clamp]
-1.35V    -159.1mA   -94.77mA   -266.2mA
-1.295V   -137.7mA   -81.77mA   -230.9mA
-1.159V   -87.19mA   -51.56mA   -145.9mA
-1.132V   -77.89mA   -46.14mA   -129.9mA
-1.05V    -52.83mA   -31.84mA   -86.44mA
-1.023V   -45.55mA   -27.75mA   -73.68mA
-940.9mV  -28.44mA   -18.28mA   -42.92mA
-859.1mV  -16.79mA   -11.75mA   -22.47mA
-804.5mV  -11.72mA   -8.559mA   -15.69mA
-722.7mV  -7.324mA   -5.162mA   -10.76mA
-395.5mV  -159.1uA   -161.1uA   -232.3uA
1.35V     1.028nA    30.09nA    754.3pA
[Ramp]
dV/dt_f 0.45857213/0.27690541n  0.4109274/0.37399465n 0.51663809/0.19606068n
dV/dt_r 0.44359607/0.26976923n 0.41514269/0.35204555n 0.50972774/0.19446606n
R_load = 50
[Rising Waveform]
R_fixture = 50
V_fixture = 1.35
V_fixture_min = 1.2825
V_fixture_max = 1.4175
0s        589.3mV    601.6mV    559.7mV
60.65ps   589.8mV    601.6mV    617.9mV
198.6ps   636.2mV    601.6mV    1.064V
307.4ps   853.9mV    601.6mV    1.296V
447ps     1.14V      650.2mV    1.397V
663.2ps   1.305V     904.2mV    1.416V
857.9ps   1.342V     1.139V     1.417V
984.8ps   1.345V     1.214V     1.417V
1.451ns   1.347V     1.276V     1.418V
2.5ns     1.349V     1.28V      1.418V
[Rising Waveform]
R_fixture = 50
V_fixture = 0
V_fixture_min = 0
V_fixture_max = 0
47.07ps   0V         0V         0V
107.9ps   0V         0V         108.2mV
203.5ps   0V         0V         391.8mV
316ps     167.5mV    0V         666.6mV
482.9ps   474.6mV    10.03mV    824.9mV
749.1ps   693mV      279.1mV    843.7mV
970.2ps   727.4mV    546.9mV    844.8mV
1.108ns   729.4mV    612.6mV    845mV
1.549ns   732.4mV    679.8mV    846.2mV
2.547ns   734.9mV    684.2mV    846.3mV
[Falling Waveform]
R_fixture = 50
V_fixture = 1.35
V_fixture_min = 1.2825
V_fixture_max = 1.4175
73.62ps   1.349V     1.282V     1.417V
140.3ps   1.349V     1.282V     1.314V
228.9ps   1.333V     1.282V     1.071V
371.8ps   1.127V     1.282V     712.4mV
512.6ps   854.8mV    1.273V     581.4mV
742.3ps   646.2mV    1.086V     562.1mV
1.015ns   596.3mV    768.1mV    559.9mV
1.134ns   594.8mV    694.4mV    559.5mV
1.592ns   591.2mV    608.8mV    558.7mV
2.5ns     589.1mV    603.7mV    558.7mV
[Falling Waveform]
R_fixture = 50
V_fixture = 0
V_fixture_min = 0
V_fixture_max = 0
63.16ps   734.8mV    686.5mV    845.5mV
127.8ps   734.8mV    686.5mV    712.7mV
196.8ps   728mV      686.5mV    488.6mV
303.5ps   543.3mV    686.5mV    201.5mV
492.9ps   192.4mV    651.3mV    17.79mV
723.6ps   40.61mV    403mV      0V
963.9ps   5.4mV      127.9mV    0V
1.072ns   4.348mV    74.54mV    0V
1.55ns    2.344mV    5.466mV    0V
2.547ns   0V         2.374mV    0V
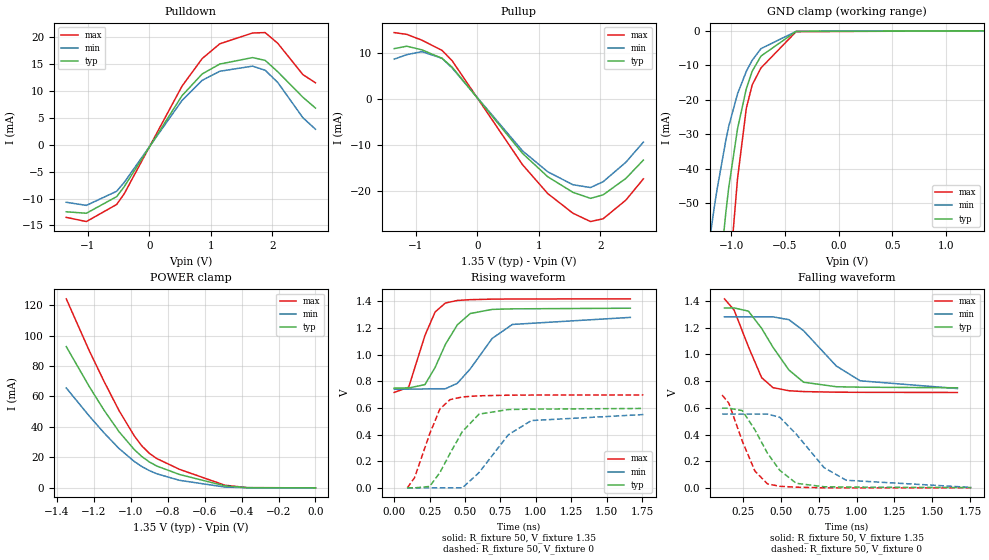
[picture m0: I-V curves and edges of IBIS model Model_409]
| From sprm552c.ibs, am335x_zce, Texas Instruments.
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| Model based on original model for BCSHTLTCSCDVPBFZ_SSDHV
|   Sub model SR01_6MA_5PER_1P35
[model]   Model_409
|[Description]  [1.35V-3-STATE-NOTERM-SR01:6MA, IND, 5%]
|   Slow slew rate (SR[1:0] = "01"), 1.33 * RExt = 0.750 * Iout
|   (I[2:0] = "001"), 6mA nominal with Rext = 50R,ODT off (ODT[1:0]
|   = "00") CMOS mode,Industrial temperature range (-40C to 125C,
|   25C nominal),5% power supply tolerance
|[Input Load]   NOTERM
|[Output Drive] SR01:6MA
|Voltage   1.35V
|Mode   3-STATE
Model_type   3-state
Polarity   Non-Inverting
Enable   Active-Low
Cref =  15pF
Rref =  100.0000M
Vref =  0V
Vmeas =  0.675
C_comp   1.865048p   1.679967p   1.989968p
[Temperature Range]   25   125   -40
[Voltage Range]   1.35   1.2825   1.4175
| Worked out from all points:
|   slope of the pulldown table from 0 to 0.203 V, typ, clamps not added: 53.9 ohm
|   slope of the pullup table from 0 to 0.203 V, typ, clamps not added: 58.7 ohm
|   GND clamp passes 1 mA (typ) near -0.49 V on its own axis
|   POWER clamp passes 1 mA (typ) near -0.47 V on its own axis
|   rising waveform, R_fixture 50, V_fixture 1.35: 20-80 % time 176ps typ, 239ps min, 129ps max; typ from 0.749 V to 1.35 V
|   rising waveform, R_fixture 50, V_fixture 0: 20-80 % time 193ps typ, 258ps min, 140ps max; typ from 0 V to 0.596 V
|   falling waveform, R_fixture 50, V_fixture 1.35: 20-80 % time 210ps typ, 285ps min, 145ps max; typ from 1.35 V to 0.75 V
|   falling waveform, R_fixture 50, V_fixture 0: 20-80 % time 194ps typ, 259ps min, 140ps max; typ from 0.597 V to 0.002 V
[POWER_clamp]
-1.35V    92.75mA    65.58mA    124.1mA
-1.227V   66.81mA    47.37mA    90.43mA
-1.145V   50.92mA    36.04mA    69.8mA
-1.064V   36.83mA    25.8mA     50.7mA
-981.8mV  25.17mA    17.34mA    34.14mA
-940.9mV  20.58mA    14.01mA    27.56mA
-900mV    17mA       11.33mA    22.64mA
-859.1mV  14.3mA     9.214mA    19.2mA
-736.4mV  8.769mA    4.942mA    12.14mA
-490.9mV  1.299mA    528.4uA    1.73mA
-368.2mV  117.2uA    50.88uA    117.5uA
0V        1.028nA    11.95nA    1.029nA
[Pulldown]
-1.35V    -12.46mA   -10.69mA   -13.5mA
-1.023V   -12.73mA   -11.27mA   -14.28mA
-531.8mV  -9.642mA   -8.642mA   -11.1mA
-409.1mV  -7.802mA   -7.007mA   -9.123mA
531.8mV   9.169mA    8.275mA    10.95mA
859.1mV   13.21mA    12.02mA    16.07mA
1.145V    15.05mA    13.71mA    18.82mA
1.677V    16.25mA    14.66mA    20.83mA
1.882V    15.74mA    13.9mA     20.91mA
2.086V    13.63mA    11.64mA    18.93mA
2.495V    8.875mA    5.068mA    13.09mA
2.7V      6.853mA    2.908mA    11.56mA
[Pullup]
-1.35V    11.03mA    8.75mA     14.52mA
-1.145V   11.56mA    9.727mA    14.13mA
-900mV    10.77mA    10.38mA    12.87mA
-572.7mV  8.933mA    8.936mA    10.65mA
-409.1mV  7.026mA    6.847mA    8.416mA
736.4mV   -11.73mA   -11.18mA   -14.19mA
1.145V    -16.79mA   -15.71mA   -20.44mA
1.555V    -20.18mA   -18.53mA   -24.72mA
1.841V    -21.49mA   -19.14mA   -26.53mA
2.045V    -20.73mA   -17.88mA   -25.93mA
2.414V    -17.18mA   -13.67mA   -21.89mA
2.7V      -13.18mA   -9.274mA   -17.26mA
[GND_clamp]
-1.35V    -159.1mA   -94.77mA   -266.2mA
-1.295V   -137.7mA   -81.77mA   -230.9mA
-1.159V   -87.19mA   -51.56mA   -145.9mA
-1.132V   -77.89mA   -46.14mA   -129.9mA
-1.05V    -52.83mA   -31.84mA   -86.44mA
-1.023V   -45.55mA   -27.75mA   -73.68mA
-940.9mV  -28.44mA   -18.28mA   -42.92mA
-859.1mV  -16.79mA   -11.75mA   -22.47mA
-804.5mV  -11.72mA   -8.559mA   -15.69mA
-722.7mV  -7.324mA   -5.162mA   -10.76mA
-395.5mV  -159.1uA   -161.1uA   -232.3uA
1.35V     1.028nA    30.09nA    754.3pA
[Ramp]
dV/dt_f 0.36256433/0.21195017n 0.32690463/0.29109627n 0.42226091/0.1458871n
dV/dt_r 0.36047159/0.1946891n 0.33466255/0.26285345n  0.4194838/0.14006571n
R_load = 50
[Rising Waveform]
R_fixture = 50
V_fixture = 1.35
V_fixture_min = 1.2825
V_fixture_max = 1.4175
0s        748.5mV    741mV      716.1mV
102.3ps   749.3mV    741mV      755.5mV
217.2ps   774.8mV    741.8mV    1.144V
289ps     903.8mV    743.6mV    1.32V
361.7ps   1.077V     743.6mV    1.387V
445.7ps   1.223V     784.5mV    1.406V
536.6ps   1.308V     892mV      1.412V
691.5ps   1.339V     1.121V     1.416V
833.9ps   1.343V     1.226V     1.417V
1.667ns   1.348V     1.279V     1.418V
[Rising Waveform]
R_fixture = 50
V_fixture = 0
V_fixture_min = 0
V_fixture_max = 0
92.65ps   0V         0V         0V
143.9ps   0V         0V         76.67mV
250.1ps   10.38mV    0V         404mV
322.8ps   115mV      0V         592.2mV
394.7ps   259.3mV    0V         662.3mV
481ps     422.3mV    0V         682.3mV
599.1ps   553.3mV    114.8mV    690.6mV
805.7ps   587.6mV    398.3mV    695.2mV
968.4ps   590.8mV    505mV      696.3mV
1.759ns   595.7mV    549.9mV    697mV
[Falling Waveform]
R_fixture = 50
V_fixture = 1.35
V_fixture_min = 1.2825
V_fixture_max = 1.4175
126ps     1.349V     1.282V     1.417V
189.6ps   1.349V     1.282V     1.334V
284.6ps   1.325V     1.282V     1.058V
372ps     1.196V     1.282V     826.5mV
447.3ps   1.054V     1.282V     751.3mV
552.1ps   884.1mV    1.261V     728.2mV
649.7ps   792mV      1.178V     721.8mV
865.9ps   758.2mV    913.7mV    717.3mV
1.024ns   754.8mV    802.6mV    716.2mV
1.667ns   750.3mV    744.6mV    715.1mV
[Falling Waveform]
R_fixture = 50
V_fixture = 0
V_fixture_min = 0
V_fixture_max = 0
110.6ps   597.3mV    553.3mV    696.1mV
155ps     597.3mV    553.3mV    635mV
244.4ps   579mV      553.3mV    349.6mV
327.8ps   434.4mV    553.3mV    125.1mV
410.8ps   259.2mV    553.3mV    29.65mV
491.8ps   131.6mV    529.4mV    11.65mV
601.1ps   34.1mV     402.5mV    4.93mV
784.8ps   8.209mV    152mV      0V
931.1ps   5.756mV    57.04mV    0V
1.759ns   2.092mV    3.228mV    0V
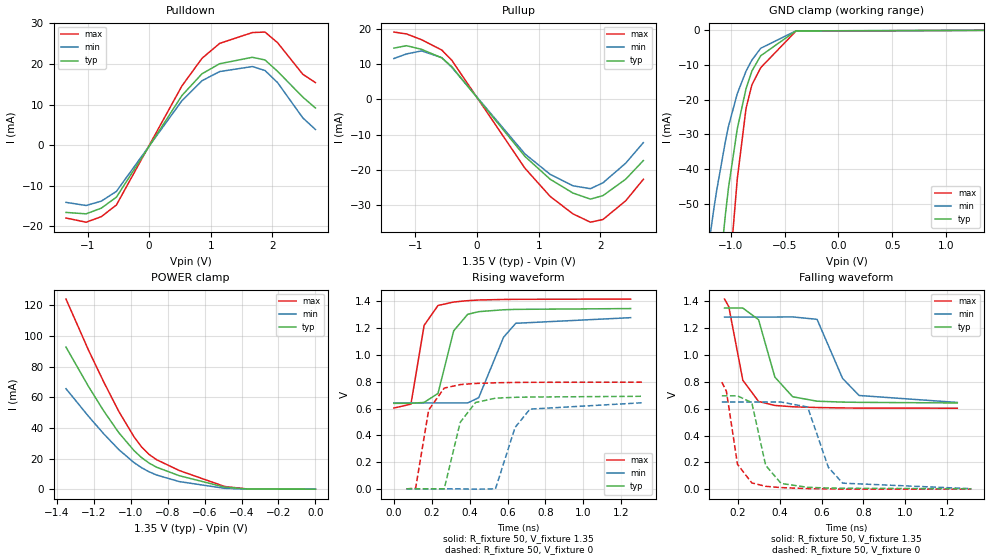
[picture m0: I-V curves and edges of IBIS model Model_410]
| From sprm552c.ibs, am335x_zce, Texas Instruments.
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| Model based on original model for BCSHTLTCSCDVPBFZ_SSDHV
|   Sub model SR00_8MA_5PER_1P35
[model]   Model_410
|[Description]  [1.35V-3-STATE-NOTERM-SR00:8MA, IND, 5%]
|   Fastest slew rate (SR[1:0] = "00"), 1.00 * RExt = 1.000 * Iout
|   (I[2:0] = "011"), 8mA nominal with Rext = 50R,ODT off (ODT[1:0]
|   = "00") CMOS mode,Industrial temperature range (-40C to 125C,
|   25C nominal),5% power supply tolerance
|[Input Load]   NOTERM
|[Output Drive] SR00:8MA
|Voltage   1.35V
|Mode   3-STATE
Model_type   3-state
Polarity   Non-Inverting
Enable   Active-Low
Cref =  15pF
Rref =  100.0000M
Vref =  0V
Vmeas =  0.675
C_comp   1.865048p   1.679967p   1.989968p
[Temperature Range]   25   125   -40
[Voltage Range]   1.35   1.2825   1.4175
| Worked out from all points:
|   slope of the pulldown table from 0 to 0.203 V, typ, clamps not added: 40.4 ohm
|   slope of the pullup table from 0 to 0.203 V, typ, clamps not added: 44.6 ohm
|   GND clamp passes 1 mA (typ) near -0.49 V on its own axis
|   POWER clamp passes 1 mA (typ) near -0.47 V on its own axis
|   rising waveform, R_fixture 50, V_fixture 1.35: 20-80 % time 76.8ps typ, 110ps min, 56.8ps max; typ from 0.639 V to 1.35 V
|   rising waveform, R_fixture 50, V_fixture 0: 20-80 % time 74.8ps typ, 88.7ps min, 60.9ps max; typ from 0 V to 0.692 V
|   falling waveform, R_fixture 50, V_fixture 1.35: 20-80 % time 85.9ps typ, 108ps min, 66.3ps max; typ from 1.35 V to 0.643 V
|   falling waveform, R_fixture 50, V_fixture 0: 20-80 % time 61.8ps typ, 81.1ps min, 50ps max; typ from 0.696 V to 0.003 V
[POWER_clamp]
-1.35V    92.75mA    65.58mA    124.1mA
-1.227V   66.81mA    47.37mA    90.43mA
-1.145V   50.92mA    36.04mA    69.8mA
-1.064V   36.83mA    25.8mA     50.7mA
-981.8mV  25.17mA    17.34mA    34.14mA
-940.9mV  20.58mA    14.01mA    27.56mA
-900mV    17mA       11.33mA    22.64mA
-859.1mV  14.3mA     9.214mA    19.2mA
-736.4mV  8.769mA    4.942mA    12.14mA
-490.9mV  1.299mA    528.4uA    1.73mA
-368.2mV  117.2uA    50.88uA    117.5uA
0V        1.028nA    11.95nA    1.029nA
[Pulldown]
-1.35V    -16.62mA   -14.14mA   -18mA
-1.023V   -16.97mA   -14.91mA   -19.03mA
-777.3mV  -15.57mA   -13.84mA   -17.67mA
-531.8mV  -12.85mA   -11.43mA   -14.79mA
531.8mV   12.22mA    10.94mA    14.59mA
859.1mV   17.61mA    15.89mA    21.42mA
1.145V    20.07mA    18.14mA    25.09mA
1.677V    21.66mA    19.38mA    27.77mA
1.882V    20.99mA    18.39mA    27.88mA
2.086V    18.18mA    15.4mA     25.25mA
2.495V    11.84mA    6.706mA    17.46mA
2.7V      9.141mA    3.847mA    15.42mA
[Pullup]
-1.35V    14.52mA    11.57mA    19.06mA
-1.145V   15.2mA     12.87mA    18.54mA
-900mV    14.17mA    13.73mA    16.89mA
-572.7mV  11.75mA    11.81mA    13.97mA
-409.1mV  9.241mA    9.051mA    11.04mA
777.3mV   -16.18mA   -15.47mA   -19.53mA
1.186V    -22.63mA   -21.24mA   -27.5mA
1.555V    -26.55mA   -24.5mA    -32.44mA
1.841V    -28.28mA   -25.32mA   -34.82mA
2.045V    -27.28mA   -23.65mA   -34.05mA
2.414V    -22.62mA   -18.08mA   -28.74mA
2.7V      -17.35mA   -12.27mA   -22.66mA
[GND_clamp]
-1.35V    -159.1mA   -94.77mA   -266.2mA
-1.295V   -137.7mA   -81.77mA   -230.9mA
-1.159V   -87.19mA   -51.56mA   -145.9mA
-1.132V   -77.89mA   -46.14mA   -129.9mA
-1.05V    -52.83mA   -31.84mA   -86.44mA
-1.023V   -45.55mA   -27.75mA   -73.68mA
-940.9mV  -28.44mA   -18.28mA   -42.92mA
-859.1mV  -16.79mA   -11.75mA   -22.47mA
-804.5mV  -11.72mA   -8.559mA   -15.69mA
-722.7mV  -7.324mA   -5.162mA   -10.76mA
-395.5mV  -159.1uA   -161.1uA   -232.3uA
1.35V     1.028nA    30.09nA    754.3pA
[Ramp]
dV/dt_f 0.43332272/87.669084p 0.39166698/0.11068745n  0.4941745/66.632364p
dV/dt_r 0.42634655/76.438622p 0.40130324/91.581369p 0.48702068/61.346071p
R_load = 50
[Rising Waveform]
R_fixture = 50
V_fixture = 1.35
V_fixture_min = 1.2825
V_fixture_max = 1.4175
0s        639mV      642.1mV    603.8mV
89.78ps   639mV      642.1mV    633mV
159.7ps   646mV      642.1mV    1.222V
232.8ps   713.2mV    642.1mV    1.37V
315.6ps   1.181V     642.1mV    1.396V
389.5ps   1.304V     642.1mV    1.406V
447.7ps   1.324V     681.2mV    1.411V
578.9ps   1.338V     1.133V     1.415V
643.4ps   1.341V     1.237V     1.416V
1.25ns    1.347V     1.279V     1.418V
[Rising Waveform]
R_fixture = 50
V_fixture = 0
V_fixture_min = 0
V_fixture_max = 0
66.61ps   0V         0V         0V
114.5ps   0V         0V         4.92mV
183.4ps   0V         0V         589.3mV
265.6ps   0V         0V         753mV
350ps     497.3mV    0V         779.2mV
430.9ps   645.2mV    -2.258mV   787.5mV
536.3ps   677.6mV    0V         792.6mV
639.5ps   684mV      458.5mV    795mV
718.3ps   686mV      595.9mV    796.1mV
1.317ns   691.7mV    643.7mV    797.1mV
[Falling Waveform]
R_fixture = 50
V_fixture = 1.35
V_fixture_min = 1.2825
V_fixture_max = 1.4175
135.6ps   1.35V      1.283V     1.417V
156ps     1.35V      1.283V     1.361V
223.3ps   1.35V      1.283V     812.4mV
298.7ps   1.263V     1.283V     653.7mV
376.8ps   834.9mV    1.283V     623.9mV
461.9ps   688.9mV    1.284V     614.2mV
578.6ps   655.7mV    1.266V     608.6mV
700.7ps   649mV      825.9mV    605.4mV
779.9ps   647.1mV    698.2mV    604.4mV
1.25ns    642.6mV    646.5mV    603.4mV
[Falling Waveform]
R_fixture = 50
V_fixture = 0
V_fixture_min = 0
V_fixture_max = 0
122.8ps   695.5mV    649.6mV    798.2mV
144.8ps   695.5mV    649.6mV    728.8mV
197.7ps   695.5mV    649.6mV    185.5mV
266.3ps   645mV      649.6mV    46.7mV
332.7ps   177.3mV    649.6mV    21.32mV
406.6ps   42.7mV     649.6mV    11.65mV
533.5ps   13.66mV    612.2mV    4.227mV
632.8ps   8.541mV    162.7mV    2.171mV
701.3ps   6.951mV    44.62mV    0V
1.317ns   2.954mV    3.657mV    0V
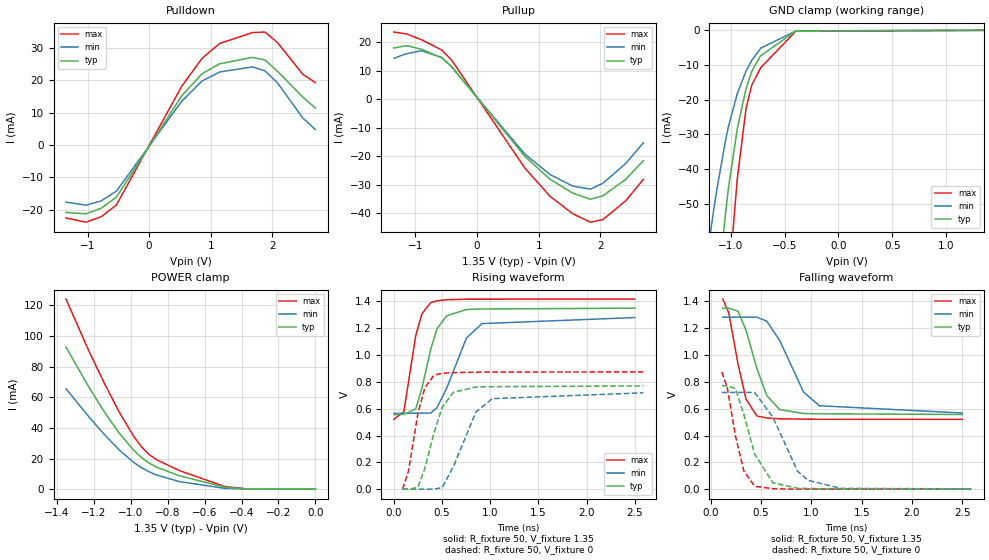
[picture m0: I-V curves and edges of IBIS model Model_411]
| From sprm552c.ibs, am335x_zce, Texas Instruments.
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| Model based on original model for BCSHTLTCSCDVPBFZ_SSDHV
|   Sub model SR10_10MA_5PER_1P35
[model]   Model_411
|[Description]  [1.35V-3-STATE-NOTERM-SR10:10MA, IND, 5%]
|   Fast slew rate (SR[1:0] = "10"), 0.80 * RExt = 1.250 * Iout
|   (I[2:0] = "101"), 10mA nominal with Rext = 50R,ODT off (ODT[1:0]
|   = "00") CMOS mode,Industrial temperature range (-40C to 125C,
|   25C nominal),5% power supply tolerance
|[Input Load]   NOTERM
|[Output Drive] SR10:10MA
|Voltage   1.35V
|Mode   3-STATE
Model_type   3-state
Polarity   Non-Inverting
Enable   Active-Low
Cref =  15pF
Rref =  100.0000M
Vref =  0V
Vmeas =  0.675
C_comp   1.865048p   1.679967p   1.989968p
[Temperature Range]   25   125   -40
[Voltage Range]   1.35   1.2825   1.4175
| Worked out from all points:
|   slope of the pulldown table from 0 to 0.203 V, typ, clamps not added: 32.4 ohm
|   slope of the pullup table from 0 to 0.203 V, typ, clamps not added: 36 ohm
|   GND clamp passes 1 mA (typ) near -0.49 V on its own axis
|   POWER clamp passes 1 mA (typ) near -0.47 V on its own axis
|   rising waveform, R_fixture 50, V_fixture 1.35: 20-80 % time 167ps typ, 236ps min, 120ps max; typ from 0.557 V to 1.35 V
|   rising waveform, R_fixture 50, V_fixture 0: 20-80 % time 184ps typ, 247ps min, 131ps max; typ from 0 V to 0.77 V
|   falling waveform, R_fixture 50, V_fixture 1.35: 20-80 % time 197ps typ, 272ps min, 136ps max; typ from 1.35 V to 0.557 V
|   falling waveform, R_fixture 50, V_fixture 0: 20-80 % time 183ps typ, 263ps min, 131ps max; typ from 0.77 V to 0 V
[POWER_clamp]
-1.35V    92.75mA    65.58mA    124.1mA
-1.227V   66.81mA    47.37mA    90.43mA
-1.145V   50.92mA    36.04mA    69.8mA
-1.064V   36.83mA    25.8mA     50.7mA
-981.8mV  25.17mA    17.34mA    34.14mA
-940.9mV  20.58mA    14.01mA    27.56mA
-900mV    17mA       11.33mA    22.64mA
-859.1mV  14.3mA     9.214mA    19.2mA
-736.4mV  8.769mA    4.942mA    12.14mA
-490.9mV  1.299mA    528.4uA    1.73mA
-368.2mV  117.2uA    50.88uA    117.5uA
0V        1.028nA    11.95nA    1.029nA
[Pulldown]
-1.35V    -20.78mA   -17.6mA    -22.5mA
-1.023V   -21.21mA   -18.54mA   -23.79mA
-777.3mV  -19.46mA   -17.21mA   -22.08mA
-531.8mV  -16.06mA   -14.21mA   -18.48mA
531.8mV   15.27mA    13.6mA     18.23mA
859.1mV   22.01mA    19.76mA    26.76mA
1.145V    25.08mA    22.56mA    31.35mA
1.677V    27.07mA    24.11mA    34.71mA
1.882V    26.25mA    22.88mA    34.86mA
2.086V    22.73mA    19.17mA    31.58mA
2.495V    14.8mA     8.345mA    21.83mA
2.7V      11.43mA    4.787mA    19.28mA
[Pullup]
-1.35V    18mA       14.4mA     23.6mA
-1.145V   18.85mA    16.01mA    22.95mA
-900mV    17.57mA    17.07mA    20.91mA
-572.7mV  14.57mA    14.69mA    17.3mA
-409.1mV  11.45mA    11.25mA    13.66mA
777.3mV   -20.05mA   -19.24mA   -24.16mA
1.186V    -28.05mA   -26.41mA   -34.04mA
1.555V    -32.91mA   -30.47mA   -40.16mA
1.841V    -35.07mA   -31.5mA    -43.11mA
2.045V    -33.83mA   -29.42mA   -42.16mA
2.414V    -28.06mA   -22.5mA    -35.59mA
2.7V      -21.52mA   -15.27mA   -28.07mA
[GND_clamp]
-1.35V    -159.1mA   -94.77mA   -266.2mA
-1.295V   -137.7mA   -81.77mA   -230.9mA
-1.159V   -87.19mA   -51.56mA   -145.9mA
-1.132V   -77.89mA   -46.14mA   -129.9mA
-1.05V    -52.83mA   -31.84mA   -86.44mA
-1.023V   -45.55mA   -27.75mA   -73.68mA
-940.9mV  -28.44mA   -18.28mA   -42.92mA
-859.1mV  -16.79mA   -11.75mA   -22.47mA
-804.5mV  -11.72mA   -8.559mA   -15.69mA
-722.7mV  -7.324mA   -5.162mA   -10.76mA
-395.5mV  -159.1uA   -161.1uA   -232.3uA
1.35V     1.028nA    30.09nA    754.3pA
[Ramp]
dV/dt_f 0.47822859/0.19835088n 0.43262625/0.27501669n 0.53943329/0.13692521n
dV/dt_r 0.46525666/0.1853721n 0.43633863/0.25074405n 0.52663677/0.13176349n
R_load = 50
[Rising Waveform]
R_fixture = 50
V_fixture = 1.35
V_fixture_min = 1.2825
V_fixture_max = 1.4175
0s        556.7mV    565.7mV    521.4mV
103.2ps   557.4mV    565.7mV    577.9mV
226.8ps   598.6mV    566.3mV    1.146V
291.4ps   754.7mV    567mV      1.309V
382.3ps   1.044V     567.9mV    1.391V
447.4ps   1.197V     607.7mV    1.405V
547.4ps   1.293V     752.3mV    1.413V
753.1ps   1.34V      1.128V     1.417V
915.4ps   1.344V     1.235V     1.417V
2.5ns     1.35V      1.28V      1.418V
[Rising Waveform]
R_fixture = 50
V_fixture = 0
V_fixture_min = 0
V_fixture_max = 0
89.68ps   0V         0V         0V
150.6ps   0V         0V         132.7mV
248.5ps   12.63mV    0V         563.6mV
320ps     153.2mV    0V         754.5mV
416.4ps   419.3mV    0V         850.3mV
501.6ps   612mV      11.67mV    864mV
619.2ps   722.6mV    171.6mV    869.6mV
851.1ps   762.2mV    575.7mV    872.5mV
1.021ns   764.7mV    674.9mV    873.3mV
2.59ns    769.9mV    718.9mV    874.6mV
[Falling Waveform]
R_fixture = 50
V_fixture = 1.35
V_fixture_min = 1.2825
V_fixture_max = 1.4175
118.9ps   1.349V     1.282V     1.417V
177.4ps   1.349V     1.282V     1.316V
269.7ps   1.327V     1.282V     933.8mV
349.8ps   1.184V     1.282V     671.3mV
457.7ps   898.8mV    1.282V     545.5mV
557ps     697mV      1.252V     530.5mV
684ps     593.3mV    1.109V     524.4mV
921.9ps   564mV      723.9mV    522mV
1.08ns    562mV      621.8mV    520.9mV
2.5ns     556.5mV    567.7mV    520.4mV
[Falling Waveform]
R_fixture = 50
V_fixture = 0
V_fixture_min = 0
V_fixture_max = 0
109ps     770.4mV    721.1mV    873.6mV
162.2ps   770.4mV    721.1mV    761.1mV
245.2ps   749.7mV    721.1mV    394mV
328.4ps   554.6mV    721.1mV    134.3mV
436.1ps   261.8mV    721.1mV    21.04mV
617.1ps   47.61mV    535.6mV    3.562mV
862.1ps   6.487mV    134.3mV    0V
967.7ps   4.9mV      65.64mV    0V
1.292ns   3.037mV    6.006mV    0V
2.59ns    0V         2.174mV    0V
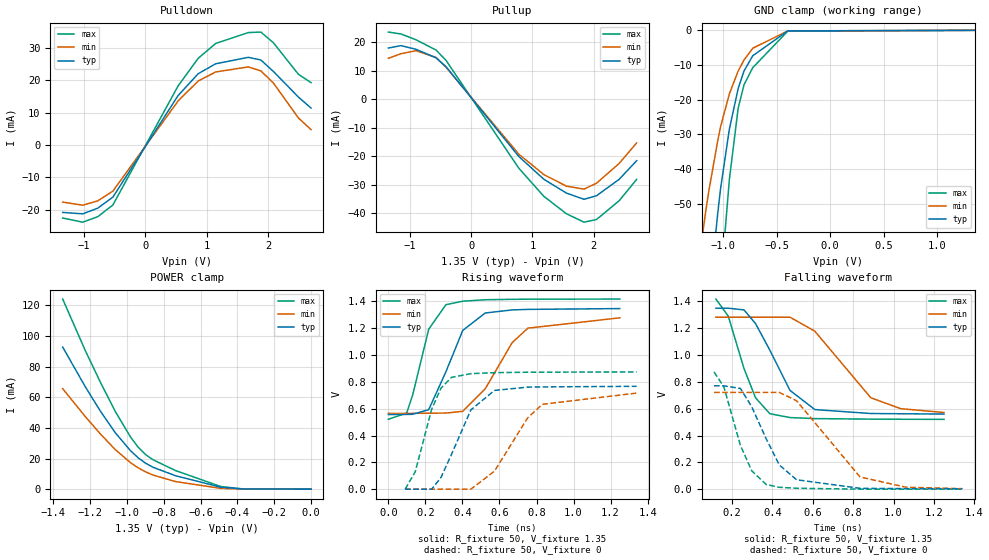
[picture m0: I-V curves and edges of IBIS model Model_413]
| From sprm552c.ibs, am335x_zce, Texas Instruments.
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| Model based on original model for BCSHTLTCSCDVPBFZ_SSDHV
|   Sub model SR01_10MA_5PER_1P35
[model]   Model_413
|[Description]  [1.35V-3-STATE-NOTERM-SR01:10MA, IND, 5%]
|   Slow slew rate (SR[1:0] = "01"), 0.80 * RExt = 1.250 * Iout
|   (I[2:0] = "101"), 10mA nominal with Rext = 50R,ODT off (ODT[1:0]
|   = "00") CMOS mode,Industrial temperature range (-40C to 125C,
|   25C nominal),5% power supply tolerance
|[Input Load]   NOTERM
|[Output Drive] SR01:10MA
|Voltage   1.35V
|Mode   3-STATE
Model_type   3-state
Polarity   Non-Inverting
Enable   Active-Low
Cref =  15pF
Rref =  100.0000M
Vref =  0V
Vmeas =  0.675
C_comp   1.865048p   1.679967p   1.989968p
[Temperature Range]   25   125   -40
[Voltage Range]   1.35   1.2825   1.4175
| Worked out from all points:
|   slope of the pulldown table from 0 to 0.203 V, typ, clamps not added: 32.4 ohm
|   slope of the pullup table from 0 to 0.203 V, typ, clamps not added: 36 ohm
|   GND clamp passes 1 mA (typ) near -0.49 V on its own axis
|   POWER clamp passes 1 mA (typ) near -0.47 V on its own axis
|   rising waveform, R_fixture 50, V_fixture 1.35: 20-80 % time 137ps typ, 190ps min, 99.9ps max; typ from 0.557 V to 1.35 V
|   rising waveform, R_fixture 50, V_fixture 0: 20-80 % time 149ps typ, 199ps min, 108ps max; typ from 0 V to 0.767 V
|   falling waveform, R_fixture 50, V_fixture 1.35: 20-80 % time 162ps typ, 224ps min, 115ps max; typ from 1.35 V to 0.56 V
|   falling waveform, R_fixture 50, V_fixture 0: 20-80 % time 150ps typ, 213ps min, 109ps max; typ from 0.77 V to 0.003 V
[POWER_clamp]
-1.35V    92.75mA    65.58mA    124.1mA
-1.227V   66.81mA    47.37mA    90.43mA
-1.145V   50.92mA    36.04mA    69.8mA
-1.064V   36.83mA    25.8mA     50.7mA
-981.8mV  25.17mA    17.34mA    34.14mA
-940.9mV  20.58mA    14.01mA    27.56mA
-900mV    17mA       11.33mA    22.64mA
-859.1mV  14.3mA     9.214mA    19.2mA
-736.4mV  8.769mA    4.942mA    12.14mA
-490.9mV  1.299mA    528.4uA    1.73mA
-368.2mV  117.2uA    50.88uA    117.5uA
0V        1.028nA    11.95nA    1.029nA
[Pulldown]
-1.35V    -20.78mA   -17.6mA    -22.5mA
-1.023V   -21.21mA   -18.54mA   -23.79mA
-777.3mV  -19.46mA   -17.21mA   -22.08mA
-531.8mV  -16.06mA   -14.21mA   -18.48mA
531.8mV   15.27mA    13.6mA     18.23mA
859.1mV   22.01mA    19.76mA    26.76mA
1.145V    25.08mA    22.56mA    31.35mA
1.677V    27.07mA    24.11mA    34.71mA
1.882V    26.25mA    22.88mA    34.86mA
2.086V    22.73mA    19.17mA    31.58mA
2.495V    14.8mA     8.345mA    21.83mA
2.7V      11.43mA    4.787mA    19.28mA
[Pullup]
-1.35V    18mA       14.4mA     23.6mA
-1.145V   18.85mA    16.01mA    22.95mA
-900mV    17.57mA    17.07mA    20.91mA
-572.7mV  14.57mA    14.69mA    17.3mA
-409.1mV  11.45mA    11.25mA    13.66mA
777.3mV   -20.05mA   -19.24mA   -24.16mA
1.186V    -28.05mA   -26.41mA   -34.04mA
1.555V    -32.91mA   -30.47mA   -40.16mA
1.841V    -35.07mA   -31.5mA    -43.11mA
2.045V    -33.83mA   -29.42mA   -42.16mA
2.414V    -28.06mA   -22.5mA    -35.59mA
2.7V      -21.52mA   -15.27mA   -28.07mA
[GND_clamp]
-1.35V    -159.1mA   -94.77mA   -266.2mA
-1.295V   -137.7mA   -81.77mA   -230.9mA
-1.159V   -87.19mA   -51.56mA   -145.9mA
-1.132V   -77.89mA   -46.14mA   -129.9mA
-1.05V    -52.83mA   -31.84mA   -86.44mA
-1.023V   -45.55mA   -27.75mA   -73.68mA
-940.9mV  -28.44mA   -18.28mA   -42.92mA
-859.1mV  -16.79mA   -11.75mA   -22.47mA
-804.5mV  -11.72mA   -8.559mA   -15.69mA
-722.7mV  -7.324mA   -5.162mA   -10.76mA
-395.5mV  -159.1uA   -161.1uA   -232.3uA
1.35V     1.028nA    30.09nA    754.3pA
[Ramp]
dV/dt_f 0.47833475/0.16447852n   0.432567/0.22822597n 0.53954165/0.11533564n
dV/dt_r  0.4654836/0.15158511n 0.43639294/0.20264224n 0.52685755/0.10826329n
R_load = 50
[Rising Waveform]
R_fixture = 50
V_fixture = 1.35
V_fixture_min = 1.2825
V_fixture_max = 1.4175
0s        556.7mV    565.7mV    521.4mV
98.58ps   557.4mV    565.7mV    567.7mV
130.9ps   558.4mV    565.7mV    700.2mV
217.8ps   593.2mV    566.5mV    1.193V
310.8ps   875.7mV    567.7mV    1.376V
401.6ps   1.184V     580.7mV    1.402V
523ps     1.314V     748.2mV    1.413V
668.5ps   1.337V     1.093V     1.416V
753.4ps   1.341V     1.201V     1.417V
1.25ns    1.347V     1.278V     1.418V
[Rising Waveform]
R_fixture = 50
V_fixture = 0
V_fixture_min = 0
V_fixture_max = 0
90.6ps    0V         0V         0V
145.1ps   0V         0V         129.8mV
233.9ps   0V         0V         596.5mV
284ps     86.91mV    0V         753.2mV
341ps     260.2mV    0V         833.9mV
445.5ps   591.2mV    0V         861.7mV
573ps     736.5mV    134.2mV    869mV
751.7ps   761mV      531.1mV    872.2mV
831.1ps   762.7mV    632.8mV    872.5mV
1.341ns   767.3mV    716.7mV    874.5mV
[Falling Waveform]
R_fixture = 50
V_fixture = 1.35
V_fixture_min = 1.2825
V_fixture_max = 1.4175
120.6ps   1.349V     1.282V     1.417V
181.9ps   1.349V     1.282V     1.289V
259.8ps   1.336V     1.282V     898.2mV
316.9ps   1.234V     1.282V     680.8mV
387.2ps   1.037V     1.282V     562.7mV
487.3ps   736.3mV    1.282V     533.8mV
610.7ps   593.1mV    1.177V     526mV
887.3ps   563.9mV    681.5mV    522mV
1.035ns   562.1mV    600.2mV    521mV
1.25ns    559.9mV    571.2mV    520.5mV
[Falling Waveform]
R_fixture = 50
V_fixture = 0
V_fixture_min = 0
V_fixture_max = 0
111.3ps   770.4mV    721.1mV    873.6mV
159.8ps   770.4mV    721.1mV    763.3mV
241.8ps   750.9mV    721.1mV    326.6mV
297.9ps   614.2mV    721.1mV    137mV
369.4ps   375.7mV    721.1mV    34.85mV
434.6ps   180.4mV    721.1mV    13.92mV
519.9ps   70.15mV    659.2mV    6.665mV
834.4ps   6.312mV    90.71mV    0V
1.062ns   3.953mV    14.34mV    0V
1.341ns   2.841mV    3.973mV    0V
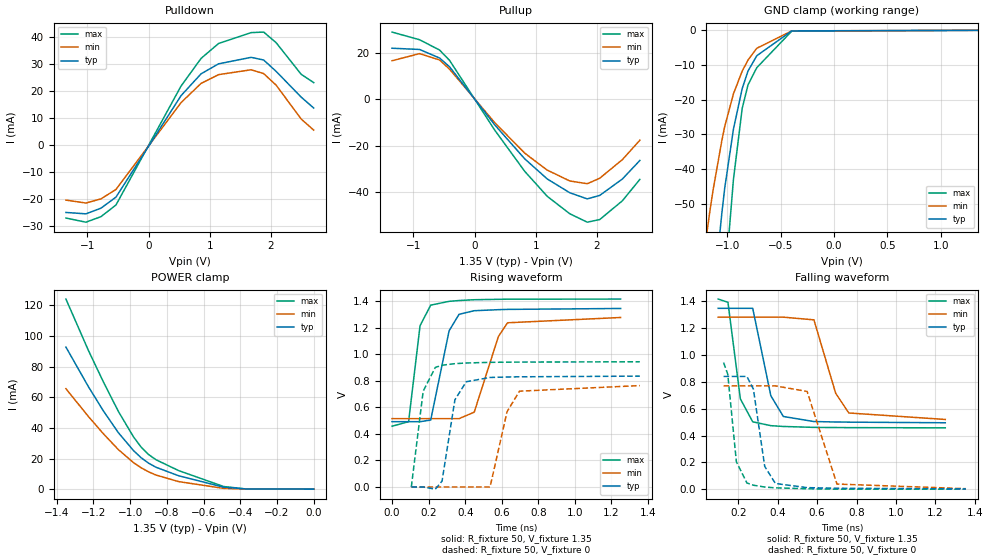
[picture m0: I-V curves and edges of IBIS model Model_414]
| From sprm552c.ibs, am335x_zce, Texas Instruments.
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| Model based on original model for BCSHTLTCSCDVPBFZ_SSDHV
|   Sub model SR00_12MA_5PER_1P35
[model]   Model_414
|[Description]  [1.35V-3-STATE-NOTERM-SR00:12MA, IND, 5%]
|   Fastest slew rate (SR[1:0] = "00"), 0.67 * RExt = 1.500 * Iout
|   (I[2:0] = "111"), 12mA nominal with Rext = 50R,ODT off (ODT[1:0]
|   = "00") CMOS mode,Industrial temperature range (-40C to 125C,
|   25C nominal),5% power supply tolerance
|[Input Load]   NOTERM
|[Output Drive] SR00:12MA
|Voltage   1.35V
|Mode   3-STATE
Model_type   3-state
Polarity   Non-Inverting
Enable   Active-Low
Cref =  15pF
Rref =  100.0000M
Vref =  0V
Vmeas =  0.675
C_comp   1.865048p   1.679967p   1.989968p
[Temperature Range]   25   125   -40
[Voltage Range]   1.35   1.2825   1.4175
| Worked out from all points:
|   slope of the pulldown table from 0 to 0.203 V, typ, clamps not added: 27 ohm
|   slope of the pullup table from 0 to 0.203 V, typ, clamps not added: 29.4 ohm
|   GND clamp passes 1 mA (typ) near -0.49 V on its own axis
|   POWER clamp passes 1 mA (typ) near -0.47 V on its own axis
|   rising waveform, R_fixture 50, V_fixture 1.35: 20-80 % time 64.5ps typ, 102ps min, 44.6ps max; typ from 0.493 V to 1.35 V
|   rising waveform, R_fixture 50, V_fixture 0: 20-80 % time 58ps typ, 71.7ps min, 45.9ps max; typ from 0 V to 0.836 V
|   falling waveform, R_fixture 50, V_fixture 1.35: 20-80 % time 65.8ps typ, 87.4ps min, 49.3ps max; typ from 1.35 V to 0.495 V
|   falling waveform, R_fixture 50, V_fixture 0: 20-80 % time 49.4ps typ, 67.7ps min, 38.5ps max; typ from 0.841 V to 0.002 V
[POWER_clamp]
-1.35V    92.75mA    65.58mA    124.1mA
-1.227V   66.81mA    47.37mA    90.43mA
-1.145V   50.92mA    36.04mA    69.8mA
-1.064V   36.83mA    25.8mA     50.7mA
-981.8mV  25.17mA    17.34mA    34.14mA
-940.9mV  20.58mA    14.01mA    27.56mA
-900mV    17mA       11.33mA    22.64mA
-859.1mV  14.3mA     9.214mA    19.2mA
-736.4mV  8.769mA    4.942mA    12.14mA
-490.9mV  1.299mA    528.4uA    1.73mA
-368.2mV  117.2uA    50.88uA    117.5uA
0V        1.028nA    11.95nA    1.029nA
[Pulldown]
-1.35V    -24.93mA   -20.36mA   -27mA
-1.023V   -25.45mA   -21.45mA   -28.54mA
-777.3mV  -23.35mA   -19.91mA   -26.49mA
-531.8mV  -19.26mA   -16.43mA   -22.17mA
531.8mV   18.31mA    15.73mA    21.86mA
859.1mV   26.4mA     22.85mA    32.1mA
1.145V    30.09mA    26.09mA    37.62mA
1.677V    32.49mA    27.89mA    41.65mA
1.882V    31.5mA     26.47mA    41.84mA
2.086V    27.29mA    22.18mA    37.91mA
2.495V    17.76mA    9.657mA    26.21mA
2.7V      13.72mA    5.539mA    23.14mA
[Pullup]
-1.35V    22.07mA    16.66mA    29.04mA
-900mV    21.54mA    19.75mA    25.74mA
-572.7mV  17.85mA    16.99mA    21.28mA
-409.1mV  14.03mA    13.01mA    16.8mA
327.3mV   -10.99mA   -10.03mA   -13.25mA
818.2mV   -25.68mA   -23.23mA   -31.08mA
1.186V    -34.37mA   -30.55mA   -41.87mA
1.555V    -40.34mA   -35.25mA   -49.41mA
1.841V    -42.99mA   -36.44mA   -53.05mA
2.045V    -41.48mA   -34.05mA   -51.9mA
2.414V    -34.41mA   -26.04mA   -43.82mA
2.7V      -26.4mA    -17.67mA   -34.58mA
[GND_clamp]
-1.35V    -159.1mA   -94.77mA   -266.2mA
-1.295V   -137.7mA   -81.77mA   -230.9mA
-1.159V   -87.19mA   -51.56mA   -145.9mA
-1.132V   -77.89mA   -46.14mA   -129.9mA
-1.05V    -52.83mA   -31.84mA   -86.44mA
-1.023V   -45.55mA   -27.75mA   -73.68mA
-940.9mV  -28.44mA   -18.28mA   -42.92mA
-859.1mV  -16.79mA   -11.75mA   -22.47mA
-804.5mV  -11.72mA   -8.559mA   -15.69mA
-722.7mV  -7.324mA   -5.162mA   -10.76mA
-395.5mV  -159.1uA   -161.1uA   -232.3uA
1.35V     1.028nA    30.09nA    754.3pA
[Ramp]
dV/dt_f 0.52273755/66.990223p 0.46787054/89.425064p 0.58312826/49.583634p
dV/dt_r 0.51739509/59.402725p 0.47904895/74.405646p 0.57872344/46.320602p
R_load = 50
[Rising Waveform]
R_fixture = 50
V_fixture = 1.35
V_fixture_min = 1.2825
V_fixture_max = 1.4175
0s        492.7mV    515.8mV    458.4mV
90.53ps   492.7mV    515.8mV    492.7mV
153.2ps   492.7mV    515.8mV    1.217V
211.4ps   504.7mV    515.8mV    1.372V
312.1ps   1.179V     515.8mV    1.401V
366.5ps   1.303V     515.8mV    1.407V
449.4ps   1.33V      564.3mV    1.413V
581.5ps   1.338V     1.135V     1.416V
631.5ps   1.34V      1.239V     1.417V
1.25ns    1.347V     1.279V     1.418V
[Rising Waveform]
R_fixture = 50
V_fixture = 0
V_fixture_min = 0
V_fixture_max = 0
105.4ps   0V         0V         0V
170.3ps   0V         0V         723mV
236.8ps   -16.54mV   0V         902.3mV
273.4ps   43.94mV    0V         918.7mV
343.8ps   658.1mV    0V         930.5mV
405.8ps   794.1mV    0V         935.5mV
536.1ps   826.4mV    0V         940.5mV
628.9ps   829.8mV    568mV      941.7mV
697ps     831.4mV    722.9mV    942.4mV
1.355ns   836.5mV    765.1mV    944.9mV
[Falling Waveform]
R_fixture = 50
V_fixture = 1.35
V_fixture_min = 1.2825
V_fixture_max = 1.4175
97.52ps   1.349V     1.283V     1.418V
147.2ps   1.349V     1.283V     1.394V
210.3ps   1.349V     1.283V     673.5mV
272.9ps   1.349V     1.283V     502.4mV
364.8ps   697.1mV    1.283V     473.7mV
428.3ps   542.1mV    1.283V     467.7mV
583.5ps   504.5mV    1.263V     460.9mV
693.8ps   501.1mV    715.6mV    459.7mV
760.4ps   499.9mV    568.3mV    459mV
1.25ns    495.3mV    520mV      457.5mV
[Falling Waveform]
R_fixture = 50
V_fixture = 0
V_fixture_min = 0
V_fixture_max = 0
125ps     841mV      770.3mV    944.8mV
146.2ps   841mV      770.3mV    857.3mV
190ps     841mV      770.3mV    203.9mV
243.3ps   841mV      770.3mV    46.29mV
276.1ps   747.8mV    770.3mV    29.51mV
333.9ps   169.7mV    770.3mV    15.68mV
388ps     42.39mV    770.3mV    9.978mV
548.9ps   11.47mV    729mV      2.79mV
700.4ps   6.905mV    38.07mV    0V
1.355ns   2.296mV    3.684mV    0V
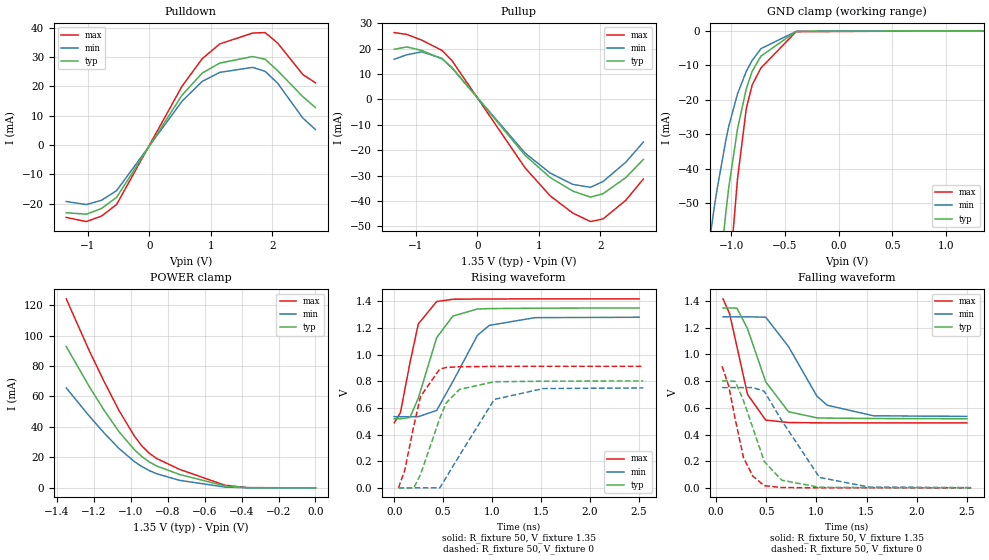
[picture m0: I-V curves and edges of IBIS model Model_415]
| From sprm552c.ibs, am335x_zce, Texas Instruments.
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| Model based on original model for BCSHTLTCSCDVPBFZ_SSDHV
|   Sub model SR11_11MA_5PER_1P35
[model]   Model_415
|[Description]  [1.35V-3-STATE-NOTERM-SR11:11MA, IND, 5%]
|   Slowest slew rate (SR[1:0] = "11"), 0.73 * RExt = 1.325 * Iout
|   (I[2:0] = "110"), 11mA nominal with Rext = 50R,ODT off (ODT[1:0]
|   = "00") CMOS mode,Industrial temperature range (-40C to 125C,
|   25C nominal),5% power supply tolerance
|[Input Load]   NOTERM
|[Output Drive] SR11:11MA
|Voltage   1.35V
|Mode   3-STATE
Model_type   3-state
Polarity   Non-Inverting
Enable   Active-Low
Cref =  15pF
Rref =  100.0000M
Vref =  0V
Vmeas =  0.675
C_comp   1.865048p   1.679967p   1.989968p
[Temperature Range]   25   125   -40
[Voltage Range]   1.35   1.2825   1.4175
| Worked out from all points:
|   slope of the pulldown table from 0 to 0.203 V, typ, clamps not added: 29.1 ohm
|   slope of the pullup table from 0 to 0.203 V, typ, clamps not added: 32.8 ohm
|   GND clamp passes 1 mA (typ) near -0.49 V on its own axis
|   POWER clamp passes 1 mA (typ) near -0.47 V on its own axis
|   rising waveform, R_fixture 50, V_fixture 1.35: 20-80 % time 215ps typ, 317ps min, 151ps max; typ from 0.518 V to 1.35 V
|   rising waveform, R_fixture 50, V_fixture 0: 20-80 % time 233ps typ, 332ps min, 169ps max; typ from 0 V to 0.802 V
|   falling waveform, R_fixture 50, V_fixture 1.35: 20-80 % time 240ps typ, 343ps min, 171ps max; typ from 1.35 V to 0.518 V
|   falling waveform, R_fixture 50, V_fixture 0: 20-80 % time 225ps typ, 351ps min, 160ps max; typ from 0.802 V to 0 V
[POWER_clamp]
-1.35V    92.75mA    65.58mA    124.1mA
-1.227V   66.81mA    47.37mA    90.43mA
-1.145V   50.92mA    36.04mA    69.8mA
-1.064V   36.83mA    25.8mA     50.7mA
-981.8mV  25.17mA    17.34mA    34.14mA
-940.9mV  20.58mA    14.01mA    27.56mA
-900mV    17mA       11.33mA    22.64mA
-859.1mV  14.3mA     9.214mA    19.2mA
-736.4mV  8.769mA    4.942mA    12.14mA
-490.9mV  1.299mA    528.4uA    1.73mA
-368.2mV  117.2uA    50.88uA    117.5uA
0V        1.028nA    11.95nA    1.029nA
[Pulldown]
-1.35V    -23.15mA   -19.32mA   -24.75mA
-1.023V   -23.64mA   -20.36mA   -26.16mA
-777.3mV  -21.69mA   -18.89mA   -24.29mA
-531.8mV  -17.89mA   -15.6mA    -20.33mA
531.8mV   17.01mA    14.93mA    20.05mA
859.1mV   24.52mA    21.69mA    29.43mA
1.145V    27.94mA    24.77mA    34.48mA
1.677V    30.17mA    26.47mA    38.18mA
1.882V    29.25mA    25.13mA    38.35mA
2.086V    25.33mA    21.05mA    34.75mA
2.495V    16.49mA    9.165mA    24.02mA
2.7V      12.74mA    5.257mA    21.21mA
[Pullup]
-1.35V    19.75mA    15.81mA    26.32mA
-1.145V   20.68mA    17.58mA    25.6mA
-900mV    19.27mA    18.75mA    23.32mA
-572.7mV  15.97mA    16.13mA    19.29mA
-409.1mV  12.56mA    12.35mA    15.23mA
777.3mV   -21.99mA   -21.12mA   -26.94mA
1.186V    -30.76mA   -29mA      -37.96mA
1.555V    -36.1mA    -33.46mA   -44.78mA
1.841V    -38.46mA   -34.59mA   -48.08mA
2.045V    -37.11mA   -32.31mA   -47.03mA
2.414V    -30.78mA   -24.72mA   -39.71mA
2.7V      -23.61mA   -16.77mA   -31.32mA
[GND_clamp]
-1.35V    -159.1mA   -94.77mA   -266.2mA
-1.295V   -137.7mA   -81.77mA   -230.9mA
-1.159V   -87.19mA   -51.56mA   -145.9mA
-1.132V   -77.89mA   -46.14mA   -129.9mA
-1.05V    -52.83mA   -31.84mA   -86.44mA
-1.023V   -45.55mA   -27.75mA   -73.68mA
-940.9mV  -28.44mA   -18.28mA   -42.92mA
-859.1mV  -16.79mA   -11.75mA   -22.47mA
-804.5mV  -11.72mA   -8.559mA   -15.69mA
-722.7mV  -7.324mA   -5.162mA   -10.76mA
-395.5mV  -159.1uA   -161.1uA   -232.3uA
1.35V     1.028nA    30.09nA    754.3pA
[Ramp]
dV/dt_f 0.50139165/0.24120336n 0.45193504/0.34611242n 0.55987093/0.17086132n
dV/dt_r 0.48436532/0.23464493n 0.45487221/0.33685404n 0.54951214/0.16962444n
R_load = 50
[Rising Waveform]
R_fixture = 50
V_fixture = 1.35
V_fixture_min = 1.2825
V_fixture_max = 1.4175
0s        518.3mV    533.8mV    487.9mV
63.38ps   518.3mV    533.8mV    563.6mV
160.3ps   528.2mV    533.8mV    935.9mV
246.2ps   673mV      533.8mV    1.23V
433.6ps   1.127V     580.7mV    1.398V
599.2ps   1.289V     798.1mV    1.415V
849.3ps   1.342V     1.144V     1.417V
970.3ps   1.345V     1.219V     1.417V
1.437ns   1.348V     1.277V     1.418V
2.5ns     1.35V      1.28V      1.418V
[Rising Waveform]
R_fixture = 50
V_fixture = 0
V_fixture_min = 0
V_fixture_max = 0
43.73ps   0V         0V         0V
106.1ps   0V         0V         127.4mV
200.3ps   0V         0V         466.5mV
269.2ps   100.9mV    0V         686.4mV
465.3ps   521.6mV    0V         891.5mV
531.3ps   637.6mV    79.4mV     903.2mV
666.2ps   738.6mV    243mV      908.5mV
1.022ns   796.3mV    663.6mV    911.5mV
1.522ns   799.9mV    745mV      912.1mV
2.544ns   802.2mV    749.7mV    912.2mV
[Falling Waveform]
R_fixture = 50
V_fixture = 1.35
V_fixture_min = 1.2825
V_fixture_max = 1.4175
69.9ps    1.349V     1.282V     1.417V
136.1ps   1.349V     1.282V     1.304V
208.8ps   1.347V     1.282V     1.058V
313.5ps   1.194V     1.282V     701.1mV
495.3ps   794.6mV    1.28V      508.2mV
722.4ps   571mV      1.059V     489.8mV
1.006ns   524.6mV    686.8mV    487.6mV
1.109ns   523.1mV    619.3mV    487.2mV
1.571ns   520mV      540.2mV    486.9mV
2.5ns     518.1mV    535.8mV    486.9mV
[Falling Waveform]
R_fixture = 50
V_fixture = 0
V_fixture_min = 0
V_fixture_max = 0
60.79ps   802.1mV    751.8mV    911.4mV
125.5ps   802.1mV    751.8mV    766.1mV
191.8ps   797.8mV    751.8mV    514.2mV
274.2ps   653.1mV    751.8mV    225mV
368.1ps   447.4mV    751.8mV    87.31mV
480.6ps   197.6mV    724.3mV    16.38mV
655.7ps   57.11mV    504mV      2.389mV
1.031ns   4.218mV    78.29mV    0V
1.528ns   2.155mV    5.357mV    0V
2.544ns   0V         2.168mV    0V
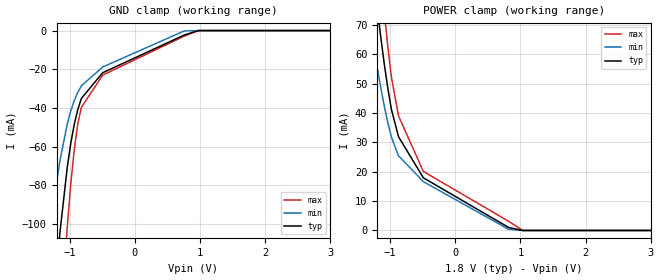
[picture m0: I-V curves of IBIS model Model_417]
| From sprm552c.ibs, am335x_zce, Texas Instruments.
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| Model based on original model for BCSHTLTCSCDVPBFZ_SSDHV
|   Sub model VREF_HALFTERM_12MA_10PER_1P8
[model]   Model_417
|[Description]  [1.8V-INPUT-HALFTERM:12MA-X, IND, 10%]
|   Half Thevenin termination (Rth = 100R whith RExt = 50R)
|   (ODT[1:0] = "11") VRef mode, 0.67 * RExt = 1.500 * Iout (I[2:0]
|   = "111"), 12mA nominal with Rext = 50R,Industrial temperature
|   range (-40C to 125C, 25C nominal),10% power supply tolerance
|[Input Load]   HALFTERM:12MA
|[Output Drive]
|Voltage   1.8V
|Mode   INPUT
Model_type   Input
Polarity   Non-Inverting
Vinl =  0.775
Vinh =  1.025
C_comp   1.851324p   1.663768p   1.973575p
[Model Spec]
Vinl   0.775   0.685   0.865
Vinh   1.025   0.935   1.115
[Temperature Range]   25   125   -40
[Voltage Range]   1.8   1.62   1.98
[POWER_clamp]
-1.8V     203.3mA    142.7mA    273.5mA
-1.309V   97.33mA    70.13mA    128.4mA
-1.2V     75.96mA    55.59mA    100.2mA
-1.145V   66.01mA    48.78mA    86.92mA
-1.091V   56.78mA    42.43mA    74.34mA
-1.036V   48.47mA    36.73mA    62.68mA
-981.8mV  41.35mA    31.91mA    52.39mA
-872.7mV  31.98mA    25.45mA    39.1mA
-490.9mV  17.95mA    16.65mA    20.12mA
818.2mV   1.033mA    404.3uA    3.15mA
1.036V    0A         0A         0A
3.6V      0A         0A         0A
[GND_clamp]
-1.8V     -361.2mA   -221.1mA   -584.1mA
-1.309V   -162.9mA   -101.6mA   -259.4mA
-1.145V   -103.7mA   -66.83mA   -159.1mA
-1.036V   -70.97mA   -48.45mA   -102mA
-981.8mV  -58.4mA    -41.57mA   -79.55mA
-927.3mV  -48.47mA   -36.19mA   -61.48mA
-872.7mV  -40.8mA    -31.96mA   -47.99mA
-818.2mV  -35.09mA   -28.55mA   -39.76mA
-490.9mV  -21.81mA   -18.84mA   -23.05mA
763.6mV   -2.272mA   -164.2uA   -2.837mA
981.8mV   0A         0A         0A
3.6V      0A         0A         0A
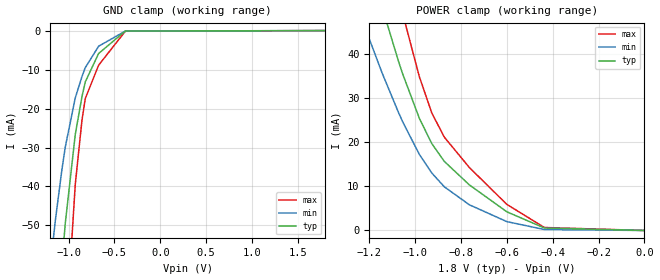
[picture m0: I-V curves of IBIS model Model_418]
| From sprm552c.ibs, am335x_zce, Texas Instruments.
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| Model based on original model for BCSHTLTCSCDVPBFZ_SSDHV
|   Sub model VREF_NOTERM_PUPD_OFF_10PER_1P8
[model]   Model_418
|[Description]  [1.8V-INPUT-PI-X, IND, 10%]
|   Weak pull up/down disabled,Industrial temperature range (-40C to
|   125C, 25C nominal),10% power supply tolerance
|[Input Load]   PI
|[Output Drive]
|Voltage   1.8V
|Mode   INPUT
Model_type   Input
Polarity   Non-Inverting
Vinl =  0.775
Vinh =  1.025
C_comp   1.851324p   1.663768p   1.973575p
[Model Spec]
Vinl   0.775   0.685   0.865
Vinh   1.025   0.935   1.115
[Temperature Range]   25   125   -40
[Voltage Range]   1.8   1.62   1.98
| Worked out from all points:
|   GND clamp passes 1 mA (typ) near -0.49 V on its own axis
|   POWER clamp passes 1 mA (typ) near -0.47 V on its own axis
[POWER_clamp]
-1.8V     194.9mA    137.1mA    262.8mA
-1.255V   72.22mA    51.13mA    97.57mA
-1.145V   50.88mA    35.89mA    70.02mA
-1.073V   38.49mA    26.84mA    53.31mA
-1.055V   35.64mA    24.75mA    49.37mA
-981.8mV  25.48mA    17.29mA    34.95mA
-927.3mV  19.73mA    13.05mA    26.68mA
-872.7mV  15.69mA    9.919mA    21.2mA
-763.6mV  10.36mA    5.84mA     14.31mA
-600mV    4.245mA    2.011mA    5.927mA
-436.4mV  557.5uA    218uA      677.6uA
0V        2.476nA    17.15nA    16.77nA
[GND_clamp]
-1.8V     -346.1mA   -209.3mA   -568.4mA
-1.327V   -149.9mA   -89.07mA   -251.1mA
-1.291V   -135.8mA   -80.51mA   -227.8mA
-1.145V   -82.57mA   -48.75mA   -137.9mA
-1.073V   -59.7mA    -35.66mA   -98.29mA
-1.036V   -49.37mA   -29.83mA   -80.25mA
-927.3mV  -26.62mA   -17.26mA   -39.45mA
-854.5mV  -16.98mA   -11.8mA    -23.03mA
-818.2mV  -13.16mA   -9.508mA   -17.43mA
-672.7mV  -5.874mA   -4.017mA   -8.881mA
-381.8mV  -123.9uA   -132.8uA   -172.2uA
1.8V      2.476nA    525nA      6.597nA
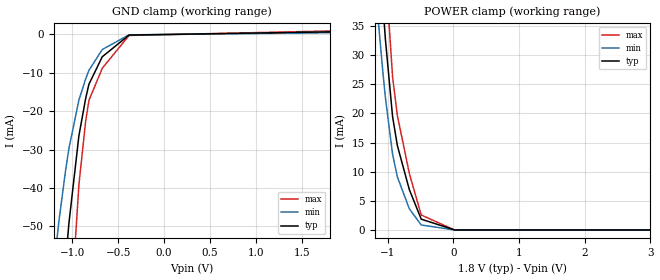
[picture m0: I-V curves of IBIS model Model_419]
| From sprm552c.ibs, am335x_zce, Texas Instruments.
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| Model based on original model for BCSHTLTCSCDVPBFZ_SSDHV
|   Sub model LVCMOS_PD_ON_10PER_1P8
[model]   Model_419
|[Description]  [1.8V-INPUT-PD-X, IND, 10%]
|   Weak internal pull-down,Industrial temperature range (-40C to
|   125C, 25C nominal),10% power supply tolerance
|[Input Load]   PD
|[Output Drive]
|Voltage   1.8V
|Mode   INPUT
Model_type   Input
Polarity   Non-Inverting
Vinl =  0.63
Vinh =  1.17
C_comp   1.851324p   1.663768p   1.973575p
[Model Spec]
Vinl   0.63   0.567   0.693
Vinh   1.17   1.053   1.287
[Temperature Range]   25   125   -40
[Voltage Range]   1.8   1.62   1.98
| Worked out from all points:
|   GND clamp passes 1 mA (typ) near -0.47 V on its own axis
|   POWER clamp passes 1 mA (typ) near -0.42 V on its own axis
[POWER_clamp]
-1.8V     194.9mA    137.1mA    262.8mA
-1.255V   72.21mA    51.14mA    97.49mA
-1.218V   64.88mA    45.94mA    88.07mA
-1.145V   50.84mA    35.9mA     69.81mA
-1.073V   38.39mA    26.84mA    52.96mA
-1.036V   32.65mA    22.65mA    45.01mA
-927.3mV  19.46mA    13.01mA    26.26mA
-854.5mV  14.5mA     9.12mA     19.67mA
-672.7mV  6.948mA    3.645mA    9.732mA
-490.9mV  1.858mA    859.1uA    2.564mA
18.18mV   0A         0A         0A
3.6V      0A         0A         0A
[GND_clamp]
-1.8V     -346.1mA   -209.3mA   -568.3mA
-1.327V   -149.8mA   -89.05mA   -251mA
-1.291V   -135.7mA   -80.49mA   -227.6mA
-1.145V   -82.42mA   -48.7mA    -137.8mA
-1.073V   -59.53mA   -35.59mA   -98.08mA
-1.036V   -49.2mA    -29.76mA   -80.02mA
-927.3mV  -26.44mA   -17.17mA   -39.18mA
-854.5mV  -16.84mA   -11.72mA   -22.8mA
-818.2mV  -13.04mA   -9.436mA   -17.24mA
-672.7mV  -5.895mA   -4.017mA   -8.878mA
-381.8mV  -267.3uA   -213.5uA   -370uA
1.8V      561.9uA    332.7uA    797.1uA
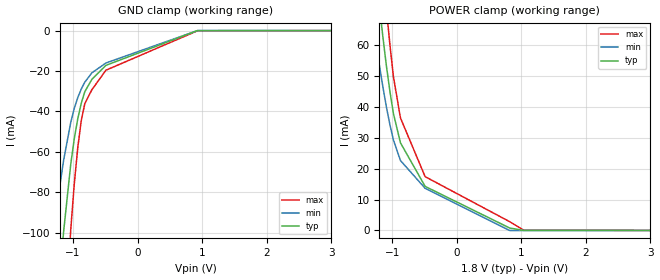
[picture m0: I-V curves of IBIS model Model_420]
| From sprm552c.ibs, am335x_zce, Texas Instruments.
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| Model based on original model for BCSHTLTCSCDVPBFZ_SSDHV
|   Sub model VREF_FULLTERM_5MA_10PER_1P8
[model]   Model_420
|[Description]  [1.8V-INPUT-FULLTERM:5MA-X, IND, 10%]
|   FULLTERM, 1.60 * RExt = 0.625 * Iout (I[2:0] = "000"), 5mA
|   nominal with Rext = 50R,Industrial temperature range (-40C to
|   125C, 25C nominal),10% power supply tolerance
|[Input Load]   FULLTERM:5MA
|[Output Drive]
|Voltage   1.8V
|Mode   INPUT
Model_type   Input
Polarity   Non-Inverting
Vinl =  0.775
Vinh =  1.025
C_comp   1.851324p   1.663768p   1.973575p
[Model Spec]
Vinl   0.775   0.685   0.865
Vinh   1.025   0.935   1.115
[Temperature Range]   25   125   -40
[Voltage Range]   1.8   1.62   1.98
[POWER_clamp]
-1.8V     201.5mA    141.8mA    271.8mA
-1.309V   94.29mA    68.2mA     125.9mA
-1.255V   83.28mA    60.68mA    111.5mA
-1.145V   62.64mA    46.47mA    84.37mA
-1.091V   53.34mA    40.01mA    71.76mA
-1.036V   44.98mA    34.2mA     60.08mA
-981.8mV  37.82mA    29.27mA    49.76mA
-872.7mV  28.36mA    22.63mA    36.42mA
-490.9mV  14.27mA    13.65mA    17.42mA
818.2mV   804uA      0A         2.858mA
1.036V    0A         0A         111.8uA
3.6V      0A         0A         0A
[GND_clamp]
-1.8V     -357.8mA   -219.2mA   -581.6mA
-1.309V   -158.4mA   -98.86mA   -256.2mA
-1.145V   -99mA      -63.9mA    -155.7mA
-1.036V   -66.17mA   -45.44mA   -98.5mA
-981.8mV  -53.57mA   -38.54mA   -76.04mA
-927.3mV  -43.62mA   -33.15mA   -57.95mA
-872.7mV  -35.93mA   -28.91mA   -44.44mA
-818.2mV  -30.22mA   -25.51mA   -36.17mA
-709.1mV  -24.14mA   -20.92mA   -29.29mA
-490.9mV  -17.2mA    -16.03mA   -19.6mA
927.3mV   0A         0A         -97.06uA
3.6V      0A         0A         0A
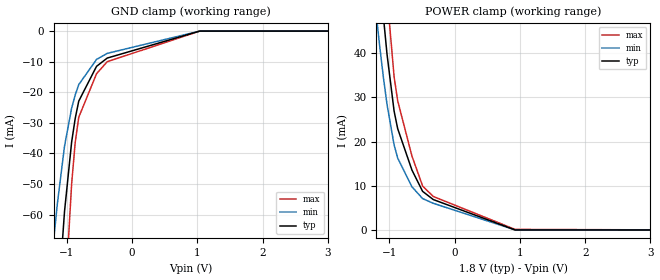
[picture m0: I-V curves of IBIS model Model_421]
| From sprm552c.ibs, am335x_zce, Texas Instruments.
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| Model based on original model for BCSHTLTCSCDVPBFZ_SSDHV
|   Sub model VREF_HALFTERM_5MA_10PER_1P8
[model]   Model_421
|[Description]  [1.8V-INPUT-HALFTERM:5MA-X, IND, 10%]
|   Half Thevenin termination (Rth = 100R whith RExt = 50R)
|   (ODT[1:0] = "11") VRef mode, 1.60 * RExt = 0.625 * Iout (I[2:0]
|   = "000"), 5mA nominal with Rext = 50R,Industrial temperature
|   range (-40C to 125C, 25C nominal),10% power supply tolerance
|[Input Load]   HALFTERM:5MA
|[Output Drive]
|Voltage   1.8V
|Mode   INPUT
Model_type   Input
Polarity   Non-Inverting
Vinl =  0.775
Vinh =  1.025
C_comp   1.851324p   1.663768p   1.973575p
[Model Spec]
Vinl   0.775   0.685   0.865
Vinh   1.025   0.935   1.115
[Temperature Range]   25   125   -40
[Voltage Range]   1.8   1.62   1.98
[POWER_clamp]
-1.8V     198.7mA    139.4mA    267.7mA
-1.255V   78.54mA    55.9mA     105mA
-1.145V   57.6mA     41.18mA    77.68mA
-1.091V   48.2mA     34.47mA    64.98mA
-1.036V   39.76mA    28.42mA    53.21mA
-927.3mV  26.88mA    19.24mA    34.63mA
-872.7mV  22.93mA    16.27mA    29.24mA
-654.5mV  13.57mA    9.776mA    16.75mA
-490.9mV  8.74mA     7.104mA    9.946mA
-327.3mV  6.88mA     6.034mA    7.576mA
927.3mV   0A         0A         126.4uA
3.6V      0A         0A         0A
[GND_clamp]
-1.8V     -352.8mA   -214.2mA   -575.9mA
-1.309V   -151.7mA   -91.79mA   -249mA
-1.255V   -131mA     -79.35mA   -214.4mA
-1.145V   -91.96mA   -56.32mA   -148.1mA
-1.036V   -58.97mA   -37.64mA   -90.68mA
-927.3mV  -36.33mA   -25.21mA   -50.04mA
-872.7mV  -28.63mA   -20.93mA   -36.5mA
-818.2mV  -22.91mA   -17.51mA   -28.19mA
-545.5mV  -11.53mA   -9.27mA    -13.95mA
-381.8mV  -8.825mA   -7.289mA   -10.01mA
1.036V    0A         0A         0A
3.6V      0A         0A         0A
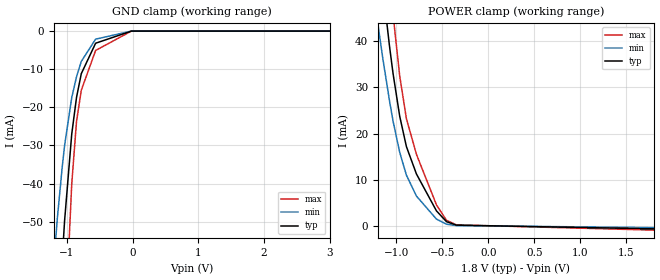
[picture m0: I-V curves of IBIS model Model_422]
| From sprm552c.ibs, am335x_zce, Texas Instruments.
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| Model based on original model for BCSHTLTCSCDVPBFZ_SSDHV
|   Sub model VREF_NOTERM_PU_ON_10PER_1P8
[model]   Model_422
|[Description]  [1.8V-INPUT-PU-X, IND, 10%]
|   Weak internal pull-up,Industrial temperature range (-40C to
|   125C, 25C nominal),10% power supply tolerance
|[Input Load]   PU
|[Output Drive]
|Voltage   1.8V
|Mode   INPUT
Model_type   Input
Polarity   Non-Inverting
Vinl =  0.775
Vinh =  1.025
C_comp   1.851324p   1.663768p   1.973575p
[Model Spec]
Vinl   0.775   0.685   0.865
Vinh   1.025   0.935   1.115
[Temperature Range]   25   125   -40
[Voltage Range]   1.8   1.62   1.98
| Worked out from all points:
|   GND clamp passes 1 mA (typ) near -0.42 V on its own axis
|   POWER clamp passes 1 mA (typ) near -0.46 V on its own axis
[POWER_clamp]
-1.8V     194.9mA    137.1mA    262.8mA
-1.255V   72.27mA    51.15mA    97.68mA
-1.145V   50.96mA    35.92mA    70.24mA
-1.073V   38.63mA    26.87mA    53.58mA
-1.036V   32.96mA    22.69mA    45.7mA
-963.6mV  23.74mA    15.93mA    32.44mA
-890.9mV  17.19mA    11.02mA    23.22mA
-781.8mV  11.27mA    6.49mA     15.52mA
-563.6mV  3.282mA    1.51mA     4.566mA
-454.5mV  956.3uA    409.3uA    1.248mA
-345.5mV  206.7uA    108.1uA    262.2uA
1.8V      -592.4uA   -333.8uA   -868.9uA
[GND_clamp]
-1.8V     -346.2mA   -209.3mA   -568.5mA
-1.327V   -150.1mA   -89.15mA   -251.4mA
-1.291V   -136mA     -80.6mA    -228.1mA
-1.145V   -82.87mA   -48.88mA   -138.4mA
-1.073V   -60.04mA   -35.81mA   -98.86mA
-1.036V   -49.74mA   -30mA      -80.87mA
-927.3mV  -27.04mA   -17.45mA   -40.14mA
-854.5mV  -17.42mA   -12mA      -23.74mA
-781.8mV  -11.18mA   -7.956mA   -15.52mA
-563.6mV  -3.189mA   -2.117mA   -5.082mA
-18.18mV  0A         0A         0A
3.6V      0A         0A         0A
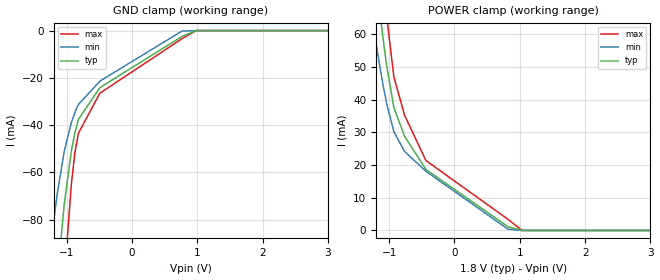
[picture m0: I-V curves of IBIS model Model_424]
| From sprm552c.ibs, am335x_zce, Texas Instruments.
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| Model based on original model for BCSHTLTCSCDVPBFZ_SSDHV
|   Sub model VREF_FULLTERM_7MA_10PER_1P8
[model]   Model_424
|[Description]  [1.8V-INPUT-FULLTERM:7MA-X, IND, 10%]
|   FULLTERM, 1.14 * RExt = 0.875 * Iout (I[2:0] = "010"), 7mA
|   nominal with Rext = 50R,Industrial temperature range (-40C to
|   125C, 25C nominal),10% power supply tolerance
|[Input Load]   FULLTERM:7MA
|[Output Drive]
|Voltage   1.8V
|Mode   INPUT
Model_type   Input
Polarity   Non-Inverting
Vinl =  0.775
Vinh =  1.025
C_comp   1.851324p   1.663768p   1.973575p
[Model Spec]
Vinl   0.775   0.685   0.865
Vinh   1.025   0.935   1.115
[Temperature Range]   25   125   -40
[Voltage Range]   1.8   1.62   1.98
[POWER_clamp]
-1.8V     204.3mA    143.5mA    275.1mA
-1.309V   98.85mA    71.64mA    130.8mA
-1.2V     77.59mA    57.27mA    102.7mA
-1.145V   67.69mA    50.54mA    89.47mA
-1.091V   58.49mA    44.28mA    76.92mA
-1.036V   50.21mA    38.65mA    65.27mA
-927.3mV  37.61mA    30.23mA    47mA
-763.6mV  28.8mA     24.16mA    35.24mA
-436.4mV  18.66mA    18.1mA     21.37mA
818.2mV   1.148mA    397.8uA    3.441mA
1.036V    0A         0A         0A
3.6V      0A         0A         0A
[GND_clamp]
-1.8V     -362.8mA   -222.8mA   -586.6mA
-1.364V   -186.1mA   -116.5mA   -297.5mA
-1.309V   -165.1mA   -104mA     -262.6mA
-1.145V   -106mA     -69.36mA   -162.4mA
-1.036V   -73.37mA   -51.05mA   -105.5mA
-927.3mV  -50.9mA    -38.84mA   -65.01mA
-872.7mV  -43.23mA   -34.62mA   -51.55mA
-818.2mV  -37.53mA   -31.22mA   -43.34mA
-490.9mV  -24.12mA   -21.38mA   -26.49mA
763.6mV   -2.524mA   -249uA     -3.47mA
981.8mV   0A         0A         0A
3.6V      0A         0A         0A
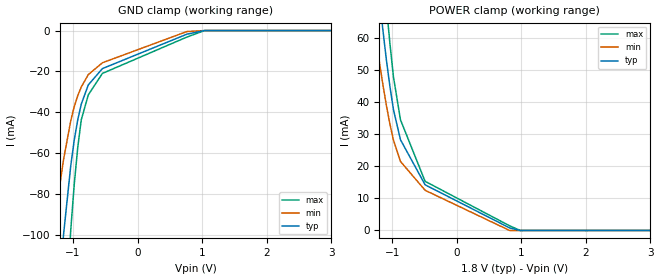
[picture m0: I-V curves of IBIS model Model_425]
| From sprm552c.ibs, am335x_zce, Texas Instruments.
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| Model based on original model for BCSHTLTCSCDVPBFZ_SSDHV
|   Sub model VREF_HALFTERM_9MA_10PER_1P8
[model]   Model_425
|[Description]  [1.8V-INPUT-HALFTERM:9MA-X, IND, 10%]
|   Half Thevenin termination (Rth = 100R whith RExt = 50R)
|   (ODT[1:0] = "11") VRef mode, 0.88 * RExt = 1.125 * Iout (I[2:0]
|   = "100"), 9mA nominal with Rext = 50R,Industrial temperature
|   range (-40C to 125C, 25C nominal),10% power supply tolerance
|[Input Load]   HALFTERM:9MA
|[Output Drive]
|Voltage   1.8V
|Mode   INPUT
Model_type   Input
Polarity   Non-Inverting
Vinl =  0.775
Vinh =  1.025
C_comp   1.851324p   1.663768p   1.973575p
[Model Spec]
Vinl   0.775   0.685   0.865
Vinh   1.025   0.935   1.115
[Temperature Range]   25   125   -40
[Voltage Range]   1.8   1.62   1.98
[POWER_clamp]
-1.8V     201.5mA    141.4mA    271mA
-1.309V   94.29mA    67.45mA    124.5mA
-1.255V   83.28mA    59.88mA    110mA
-1.145V   62.64mA    45.59mA    82.78mA
-1.091V   53.34mA    39.09mA    70.14mA
-1.036V   44.98mA    33.23mA    58.41mA
-981.8mV  37.82mA    28.27mA    48.05mA
-872.7mV  28.36mA    21.57mA    34.61mA
-490.9mV  14.27mA    12.56mA    15.36mA
818.2mV   804uA      0A         1.463mA
981.8mV   0A         0A         0A
3.6V      0A         0A         0A
[GND_clamp]
-1.8V     -357.8mA   -218.3mA   -580.9mA
-1.309V   -158.4mA   -97.68mA   -255.4mA
-1.145V   -99mA      -62.64mA   -154.8mA
-1.036V   -66.17mA   -44.14mA   -97.63mA
-981.8mV  -53.57mA   -37.23mA   -75.18mA
-927.3mV  -43.62mA   -31.83mA   -57.11mA
-872.7mV  -35.93mA   -27.58mA   -43.61mA
-763.6mV  -26.55mA   -21.52mA   -31.42mA
-545.5mV  -18.59mA   -15.74mA   -20.94mA
763.6mV   -1.768mA   -466.9uA   -3.17mA
1.036V    0A         0A         0A
3.6V      0A         0A         0A
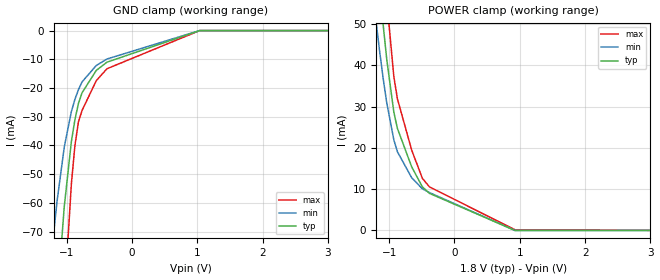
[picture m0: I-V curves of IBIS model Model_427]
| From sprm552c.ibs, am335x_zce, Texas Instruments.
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| Model based on original model for BCSHTLTCSCDVPBFZ_SSDHV
|   Sub model VREF_HALFTERM_7MA_10PER_1P8
[model]   Model_427
|[Description]  [1.8V-INPUT-HALFTERM:7MA-X, IND, 10%]
|   Half Thevenin termination (Rth = 100R whith RExt = 50R)
|   (ODT[1:0] = "11") VRef mode, 1.14 * RExt = 0.875 * Iout (I[2:0]
|   = "010"), 7mA nominal with Rext = 50R,Industrial temperature
|   range (-40C to 125C, 25C nominal),10% power supply tolerance
|[Input Load]   HALFTERM:7MA
|[Output Drive]
|Voltage   1.8V
|Mode   INPUT
Model_type   Input
Polarity   Non-Inverting
Vinl =  0.775
Vinh =  1.025
C_comp   1.851324p   1.663768p   1.973575p
[Model Spec]
Vinl   0.775   0.685   0.865
Vinh   1.025   0.935   1.115
[Temperature Range]   25   125   -40
[Voltage Range]   1.8   1.62   1.98
[POWER_clamp]
-1.8V     199.6mA    140.4mA    269.4mA
-1.255V   80.12mA    57.96mA    107.5mA
-1.145V   59.28mA    43.48mA    80.23mA
-1.091V   49.91mA    36.89mA    67.56mA
-1.036V   41.5mA     30.95mA    55.81mA
-927.3mV  28.67mA    21.97mA    37.28mA
-872.7mV  24.74mA    19.09mA    31.92mA
-654.5mV  15.43mA    12.79mA    19.49mA
-490.9mV  10.58mA    10.1mA     12.65mA
-381.8mV  8.996mA    9.18mA     10.56mA
927.3mV   0A         0A         168.4uA
3.6V      0A         0A         0A
[GND_clamp]
-1.8V     -354.5mA   -216.2mA   -578.4mA
-1.309V   -153.9mA   -94.54mA   -252.2mA
-1.145V   -94.3mA    -59.25mA   -151.4mA
-1.036V   -61.37mA   -40.64mA   -94.15mA
-927.3mV  -38.76mA   -28.25mA   -53.57mA
-872.7mV  -31.06mA   -23.97mA   -40.06mA
-818.2mV  -25.34mA   -20.55mA   -31.77mA
-763.6mV  -21.68mA   -17.88mA   -27.83mA
-545.5mV  -13.88mA   -12.16mA   -17.45mA
-381.8mV  -11mA      -9.902mA   -13.29mA
1.036V    0A         0A         0A
3.6V      0A         0A         0A
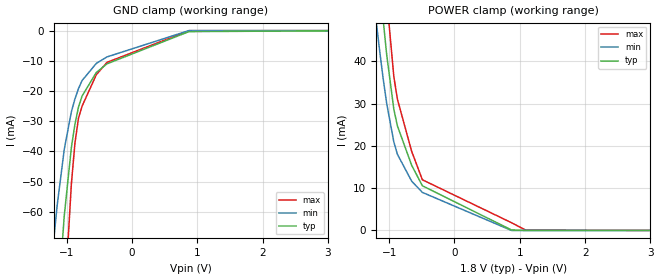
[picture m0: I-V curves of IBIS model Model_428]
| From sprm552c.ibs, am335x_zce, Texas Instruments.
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| Model based on original model for BCSHTLTCSCDVPBFZ_SSDHV
|   Sub model VREF_HALFTERM_6MA_10PER_1P8
[model]   Model_428
|[Description]  [1.8V-INPUT-HALFTERM:6MA-X, IND, 10%]
|   Half Thevenin termination (Rth = 100R whith RExt = 50R)
|   (ODT[1:0] = "11") VRef mode, 1.33 * RExt = 0.750 * Iout (I[2:0]
|   = "001"), 6mA nominal with Rext = 50R,Industrial temperature
|   range (-40C to 125C, 25C nominal),10% power supply tolerance
|[Input Load]   HALFTERM:6MA
|[Output Drive]
|Voltage   1.8V
|Mode   INPUT
Model_type   Input
Polarity   Non-Inverting
Vinl =  0.775
Vinh =  1.025
C_comp   1.851324p   1.663768p   1.973575p
[Model Spec]
Vinl   0.775   0.685   0.865
Vinh   1.025   0.935   1.115
[Temperature Range]   25   125   -40
[Voltage Range]   1.8   1.62   1.98
[POWER_clamp]
-1.8V     199.6mA    140mA      268.5mA
-1.255V   80.12mA    57.16mA    106.5mA
-1.145V   59.28mA    42.6mA     79.26mA
-1.091V   49.91mA    35.96mA    66.61mA
-1.036V   41.5mA     29.99mA    54.88mA
-927.3mV  28.67mA    20.94mA    36.39mA
-872.7mV  24.74mA    18.03mA    31.06mA
-654.5mV  15.43mA    11.67mA    18.72mA
-490.9mV  10.58mA    9.011mA    12mA
872.7mV   118.9uA    6.57uA     1.844mA
1.091V    0A         0A         91.78uA
3.6V      0A         0A         0A
[GND_clamp]
-1.8V     -354.5mA   -215.4mA   -576.6mA
-1.309V   -153.9mA   -93.36mA   -249.8mA
-1.145V   -94.3mA    -57.99mA   -148.9mA
-1.036V   -61.37mA   -39.34mA   -91.55mA
-927.3mV  -38.76mA   -26.92mA   -50.88mA
-872.7mV  -31.06mA   -22.64mA   -37.32mA
-818.2mV  -25.34mA   -19.22mA   -29mA
-763.6mV  -21.68mA   -16.55mA   -25.03mA
-545.5mV  -13.88mA   -10.87mA   -14.62mA
-381.8mV  -11mA      -8.71mA    -10.52mA
872.7mV   -339.4uA   0A         -41.58uA
3.6V      0A         0A         0A
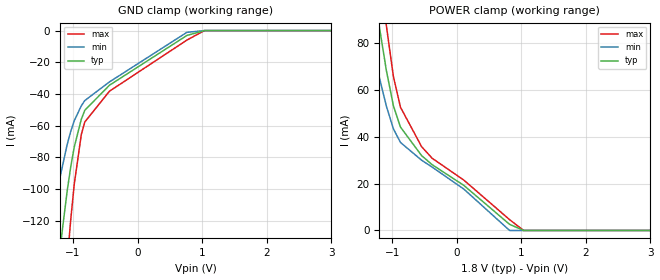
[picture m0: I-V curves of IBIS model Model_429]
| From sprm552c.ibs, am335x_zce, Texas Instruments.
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| Model based on original model for BCSHTLTCSCDVPBFZ_SSDHV
|   Sub model VREF_FULLTERM_11MA_10PER_1P8
[model]   Model_429
|[Description]  [1.8V-INPUT-FULLTERM:11MA-X, IND, 10%]
|   FULLTERM, 0.73 * RExt = 1.325 * Iout (I[2:0] = "110"), 11mA
|   nominal with Rext = 50R,Industrial temperature range (-40C to
|   125C, 25C nominal),10% power supply tolerance
|[Input Load]   FULLTERM:11MA
|[Output Drive]
|Voltage   1.8V
|Mode   INPUT
Model_type   Input
Polarity   Non-Inverting
Vinl =  0.775
Vinh =  1.025
C_comp   1.851324p   1.663768p   1.973575p
[Model Spec]
Vinl   0.775   0.685   0.865
Vinh   1.025   0.935   1.115
[Temperature Range]   25   125   -40
[Voltage Range]   1.8   1.62   1.98
[POWER_clamp]
-1.8V     209.3mA    147.3mA    281.7mA
-1.364V   118mA      85.82mA    155.2mA
-1.2V     86.76mA    65.18mA    112.8mA
-1.091V   68.13mA    52.95mA    87.22mA
-981.8mV  53.07mA    43.27mA    65.49mA
-872.7mV  44.04mA    37.49mA    52.51mA
-545.5mV  31.9mA     29.93mA    35.71mA
-381.8mV  28.01mA    26.99mA    30.75mA
109.1mV   19.2mA     17.63mA    21.45mA
818.2mV   2.605mA    0A         4.607mA
1.036V    0A         0A         0A
3.6V      0A         0A         0A
[GND_clamp]
-1.8V     -371.7mA   -230.7mA   -596.6mA
-1.364V   -197.7mA   -127.5mA   -310.1mA
-1.2V     -137.2mA   -92.23mA   -208.1mA
-1.091V   -101.2mA   -71.95mA   -145.9mA
-1.036V   -86.04mA   -63.66mA   -119.4mA
-981.8mV  -73.57mA   -56.96mA   -97.09mA
-872.7mV  -56.03mA   -47.54mA   -65.78mA
-818.2mV  -50.33mA   -44.18mA   -57.69mA
-436.4mV  -34.52mA   -32.42mA   -38.3mA
763.6mV   -3.075mA   -1.102mA   -5.998mA
1.036V    0A         0A         0A
3.6V      0A         0A         0A
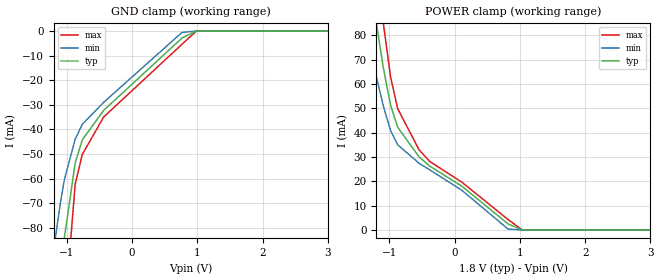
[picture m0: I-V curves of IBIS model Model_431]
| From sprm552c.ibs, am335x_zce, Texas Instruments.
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| Model based on original model for BCSHTLTCSCDVPBFZ_SSDHV
|   Sub model VREF_FULLTERM_10MA_10PER_1P8
[model]   Model_431
|[Description]  [1.8V-INPUT-FULLTERM:10MA-X, IND, 10%]
|   FULLTERM, 0.80 * RExt = 1.250 * Iout (I[2:0] = "101"), 10mA
|   nominal with Rext = 50R,Industrial temperature range (-40C to
|   125C, 25C nominal),10% power supply tolerance
|[Input Load]   FULLTERM:10MA
|[Output Drive]
|Voltage   1.8V
|Mode   INPUT
Model_type   Input
Polarity   Non-Inverting
Vinl =  0.775
Vinh =  1.025
C_comp   1.851324p   1.663768p   1.973575p
[Model Spec]
Vinl   0.775   0.685   0.865
Vinh   1.025   0.935   1.115
[Temperature Range]   25   125   -40
[Voltage Range]   1.8   1.62   1.98
[POWER_clamp]
-1.8V     208.4mA    146.2mA    280.1mA
-1.364V   116.6mA    84.08mA    152.9mA
-1.2V     85.12mA    63.16mA    110.3mA
-1.091V   66.42mA    50.75mA    84.65mA
-981.8mV  51.31mA    40.91mA    62.87mA
-872.7mV  42.23mA    35mA       49.83mA
-545.5mV  30.04mA    27.42mA    32.98mA
-381.8mV  26.25mA    24.7mA     28.16mA
109.1mV   18.01mA    16.34mA    19.68mA
818.2mV   2.49mA     375uA      4.315mA
1.036V    0A         0A         0A
3.6V      0A         0A         0A
[GND_clamp]
-1.8V     -370.1mA   -228.5mA   -594.1mA
-1.364V   -195.5mA   -124.5mA   -306.9mA
-1.2V     -134.9mA   -88.92mA   -204.8mA
-1.145V   -116.1mA   -78.2mA    -172.6mA
-1.091V   -98.8mA    -68.5mA    -142.5mA
-1.036V   -83.64mA   -60.16mA   -115.9mA
-872.7mV  -53.6mA    -43.93mA   -62.22mA
-763.6mV  -44.2mA    -37.89mA   -50.17mA
-436.4mV  -32.27mA   -28.98mA   -34.94mA
763.6mV   -2.823mA   -545.5uA   -5.367mA
981.8mV   0A         0A         -13.5uA
3.6V      0A         0A         0A
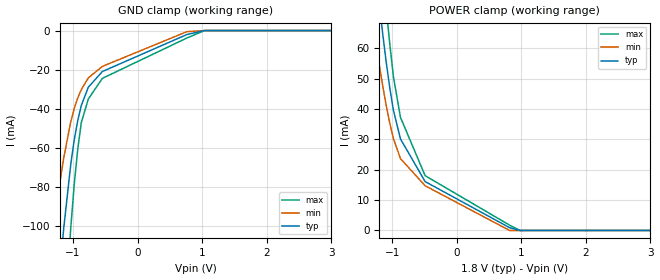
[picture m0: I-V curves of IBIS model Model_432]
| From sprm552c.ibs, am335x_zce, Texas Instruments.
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| Model based on original model for BCSHTLTCSCDVPBFZ_SSDHV
|   Sub model VREF_HALFTERM_11MA_10PER_1P8
[model]   Model_432
|[Description]  [1.8V-INPUT-HALFTERM:11MA-X, IND, 10%]
|   Half Thevenin termination (Rth = 100R whith RExt = 50R)
|   (ODT[1:0] = "11") VRef mode, 0.73 * RExt = 1.325 * Iout (I[2:0]
|   = "110"), 11mA nominal with Rext = 50R,Industrial temperature
|   range (-40C to 125C, 25C nominal),10% power supply tolerance
|[Input Load]   HALFTERM:11MA
|[Output Drive]
|Voltage   1.8V
|Mode   INPUT
Model_type   Input
Polarity   Non-Inverting
Vinl =  0.775
Vinh =  1.025
C_comp   1.851324p   1.663768p   1.973575p
[Model Spec]
Vinl   0.775   0.685   0.865
Vinh   1.025   0.935   1.115
[Temperature Range]   25   125   -40
[Voltage Range]   1.8   1.62   1.98
[POWER_clamp]
-1.8V     202.4mA    142.2mA    272.7mA
-1.309V   95.81mA    68.95mA    127mA
-1.255V   84.87mA    61.47mA    112.5mA
-1.145V   64.32mA    47.36mA    85.34mA
-1.091V   55.06mA    40.93mA    72.71mA
-1.036V   46.72mA    35.16mA    61.01mA
-981.8mV  39.59mA    30.27mA    50.67mA
-872.7mV  30.17mA    23.69mA    37.29mA
-490.9mV  16.11mA    14.74mA    18.06mA
818.2mV   918.7uA    0A         1.755mA
981.8mV   0A         0A         0A
3.6V      0A         0A         0A
[GND_clamp]
-1.8V     -359.5mA   -220mA     -583.4mA
-1.309V   -160.7mA   -100mA     -258.6mA
-1.145V   -101.3mA   -65.16mA   -158.2mA
-1.036V   -68.57mA   -46.74mA   -101.1mA
-981.8mV  -55.98mA   -39.86mA   -78.69mA
-927.3mV  -46.04mA   -34.48mA   -60.64mA
-872.7mV  -38.36mA   -30.24mA   -47.17mA
-763.6mV  -28.99mA   -24.19mA   -35.01mA
-545.5mV  -20.94mA   -18.32mA   -24.44mA
763.6mV   -2.02mA    -551.7uA   -3.803mA
1.036V    0A         0A         0A
3.6V      0A         0A         0A
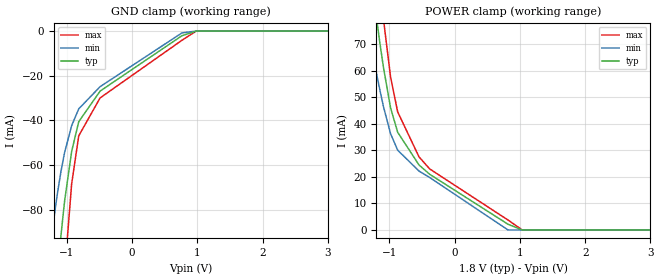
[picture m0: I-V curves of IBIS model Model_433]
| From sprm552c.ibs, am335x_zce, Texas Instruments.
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| Model based on original model for BCSHTLTCSCDVPBFZ_SSDHV
|   Sub model VREF_FULLTERM_8MA_10PER_1P8
[model]   Model_433
|[Description]  [1.8V-INPUT-FULLTERM:8MA-X, IND, 10%]
|   FULLTERM, 1.00 * RExt = 1.000 * Iout (I[2:0] = "011"), 8mA
|   nominal with Rext = 50R,Industrial temperature range (-40C to
|   125C, 25C nominal),10% power supply tolerance
|[Input Load]   FULLTERM:8MA
|[Output Drive]
|Voltage   1.8V
|Mode   INPUT
Model_type   Input
Polarity   Non-Inverting
Vinl =  0.775
Vinh =  1.025
C_comp   1.851324p   1.663768p   1.973575p
[Model Spec]
Vinl   0.775   0.685   0.865
Vinh   1.025   0.935   1.115
[Temperature Range]   25   125   -40
[Voltage Range]   1.8   1.62   1.98
[POWER_clamp]
-1.8V     205.6mA    144.5mA    276.8mA
-1.309V   101.2mA    73.47mA    133.3mA
-1.2V     80.2mA     59.29mA    105.2mA
-1.145V   70.39mA    52.66mA    92.03mA
-1.091V   61.27mA    46.48mA    79.49mA
-981.8mV  46.01mA    36.27mA    57.63mA
-872.7mV  36.8mA     30.06mA    44.46mA
-545.5mV  24.46mA    22.18mA    27.52mA
-381.8mV  20.97mA    19.75mA    22.98mA
818.2mV   2.147mA    0A         3.733mA
1.036V    0A         0A         0A
3.6V      0A         0A         0A
[GND_clamp]
-1.8V     -365mA     -224.9mA   -589.1mA
-1.364V   -189mA     -119.5mA   -300.6mA
-1.309V   -168.1mA   -107.1mA   -265.8mA
-1.145V   -109.1mA   -72.74mA   -165.8mA
-1.091V   -91.67mA   -62.96mA   -135.6mA
-1.036V   -76.44mA   -54.55mA   -108.9mA
-927.3mV  -53.98mA   -42.42mA   -68.54mA
-818.2mV  -40.58mA   -34.84mA   -46.93mA
-490.9mV  -26.89mA   -24.9mA    -29.94mA
763.6mV   -2.067mA   -805.8uA   -4.102mA
981.8mV   0A         0A         0A
3.6V      0A         0A         0A
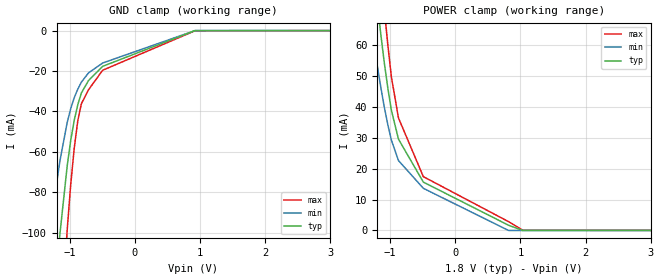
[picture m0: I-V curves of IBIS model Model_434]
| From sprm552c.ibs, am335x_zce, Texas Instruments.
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| Model based on original model for BCSHTLTCSCDVPBFZ_SSDHV
|   Sub model VREF_HALFTERM_10MA_10PER_1P8
[model]   Model_434
|[Description]  [1.8V-INPUT-HALFTERM:10MA-X, IND, 10%]
|   Half Thevenin termination (Rth = 100R whith RExt = 50R)
|   (ODT[1:0] = "11") VRef mode, 0.80 * RExt = 1.250 * Iout (I[2:0]
|   = "101"), 10mA nominal with Rext = 50R,Industrial temperature
|   range (-40C to 125C, 25C nominal),10% power supply tolerance
|[Input Load]   HALFTERM:10MA
|[Output Drive]
|Voltage   1.8V
|Mode   INPUT
Model_type   Input
Polarity   Non-Inverting
Vinl =  0.775
Vinh =  1.025
C_comp   1.851324p   1.663768p   1.973575p
[Model Spec]
Vinl   0.775   0.685   0.865
Vinh   1.025   0.935   1.115
[Temperature Range]   25   125   -40
[Voltage Range]   1.8   1.62   1.98
[POWER_clamp]
-1.8V     201.9mA    141.8mA    271.8mA
-1.309V   95.16mA    68.2mA     125.9mA
-1.255V   84.2mA     60.68mA    111.5mA
-1.145V   63.66mA    46.47mA    84.37mA
-1.091V   54.4mA     40.01mA    71.76mA
-1.036V   46.08mA    34.2mA     60.08mA
-981.8mV  38.95mA    29.27mA    49.76mA
-872.7mV  29.56mA    22.63mA    36.42mA
-490.9mV  15.65mA    13.65mA    17.42mA
818.2mV   1.689mA    0A         2.858mA
1.036V    0A         0A         111.8uA
3.6V      0A         0A         0A
[GND_clamp]
-1.8V     -358.4mA   -219.2mA   -581.6mA
-1.309V   -159.1mA   -98.86mA   -256.2mA
-1.145V   -99.68mA   -63.9mA    -155.7mA
-1.036V   -66.84mA   -45.44mA   -98.5mA
-981.8mV  -54.23mA   -38.54mA   -76.04mA
-927.3mV  -44.27mA   -33.15mA   -57.95mA
-872.7mV  -36.57mA   -28.91mA   -44.44mA
-818.2mV  -30.84mA   -25.51mA   -36.17mA
-709.1mV  -24.73mA   -20.92mA   -29.29mA
-490.9mV  -17.67mA   -16.03mA   -19.6mA
927.3mV   0A         0A         -97.06uA
3.6V      0A         0A         0A
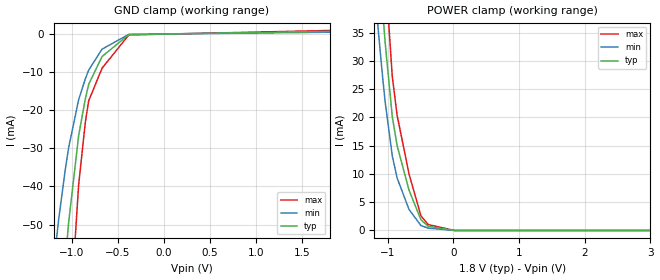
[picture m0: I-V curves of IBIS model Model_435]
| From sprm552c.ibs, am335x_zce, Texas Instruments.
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| Model based on original model for BCSHTLTCSCDVPBFZ_SSDHV
|   Sub model VREF_NOTERM_PD_ON_10PER_1P8
[model]   Model_435
|[Description]  [1.8V-INPUT-PD-X, IND, 10%]
|   Weak internal pull-down,Industrial temperature range (-40C to
|   125C, 25C nominal),10% power supply tolerance
|[Input Load]   PD
|[Output Drive]
|Voltage   1.8V
|Mode   INPUT
Model_type   Input
Polarity   Non-Inverting
Vinl =  0.775
Vinh =  1.025
C_comp   1.851324p   1.663768p   1.973575p
[Model Spec]
Vinl   0.775   0.685   0.865
Vinh   1.025   0.935   1.115
[Temperature Range]   25   125   -40
[Voltage Range]   1.8   1.62   1.98
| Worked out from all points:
|   GND clamp passes 1 mA (typ) near -0.47 V on its own axis
|   POWER clamp passes 1 mA (typ) near -0.42 V on its own axis
[POWER_clamp]
-1.8V     194.9mA    137.1mA    262.8mA
-1.255V   72.34mA    51.18mA    97.89mA
-1.145V   51.13mA    35.97mA    70.61mA
-1.073V   38.89mA    26.95mA    54mA
-1.036V   33.25mA    22.78mA    46.12mA
-927.3mV  20.13mA    13.2mA     27.22mA
-854.5mV  15.04mA    9.307mA    20.43mA
-672.7mV  7.134mA    3.718mA    9.984mA
-490.9mV  1.87mA     863uA      2.576mA
-381.8mV  755.1uA    412.2uA    1.051mA
18.18mV   0A         0A         0A
3.6V      0A         0A         0A
[GND_clamp]
-1.8V     -346.1mA   -209.3mA   -568.4mA
-1.327V   -149.9mA   -89.1mA    -251.2mA
-1.291V   -135.9mA   -80.55mA   -227.9mA
-1.145V   -82.67mA   -48.8mA    -138.1mA
-1.073V   -59.81mA   -35.71mA   -98.43mA
-1.036V   -49.49mA   -29.89mA   -80.41mA
-927.3mV  -26.75mA   -17.33mA   -39.65mA
-854.5mV  -17.12mA   -11.87mA   -23.23mA
-818.2mV  -13.3mA    -9.579mA   -17.63mA
-672.7mV  -6.019mA   -4.095mA   -9.076mA
-381.8mV  -268.8uA   -215.3uA   -372uA
1.8V      561.9uA    332.7uA    797.1uA
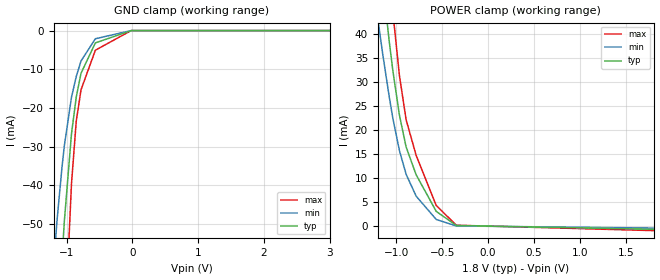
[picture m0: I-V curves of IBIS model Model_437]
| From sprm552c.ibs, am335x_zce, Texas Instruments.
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| Model based on original model for BCSHTLTCSCDVPBFZ_SSDHV
|   Sub model LVCMOS_PU_ON_10PER_1P8
[model]   Model_437
|[Description]  [1.8V-INPUT-PU-X, IND, 10%]
|   Weak internal pull-up,Industrial temperature range (-40C to
|   125C, 25C nominal),10% power supply tolerance
|[Input Load]   PU
|[Output Drive]
|Voltage   1.8V
|Mode   INPUT
Model_type   Input
Polarity   Non-Inverting
Vinl =  0.63
Vinh =  1.17
C_comp   1.851324p   1.663768p   1.973575p
[Model Spec]
Vinl   0.63   0.567   0.693
Vinh   1.17   1.053   1.287
[Temperature Range]   25   125   -40
[Voltage Range]   1.8   1.62   1.98
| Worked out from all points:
|   GND clamp passes 1 mA (typ) near -0.42 V on its own axis
|   POWER clamp passes 1 mA (typ) near -0.46 V on its own axis
[POWER_clamp]
-1.8V     194.9mA    137.1mA    262.8mA
-1.255V   72.18mA    51.12mA    97.43mA
-1.218V   64.85mA    45.92mA    88mA
-1.145V   50.79mA    35.87mA    69.71mA
-1.073V   38.32mA    26.81mA    52.79mA
-1.036V   32.56mA    22.61mA    44.79mA
-963.6mV  23.17mA    15.8mA     31.4mA
-890.9mV  16.54mA    10.85mA    22.22mA
-781.8mV  10.75mA    6.309mA    14.78mA
-563.6mV  3.137mA    1.451mA    4.363mA
-345.5mV  202.2uA    106.2uA    257.5uA
1.8V      -592.4uA   -333.8uA   -868.9uA
[GND_clamp]
-1.8V     -346.1mA   -209.3mA   -568.4mA
-1.327V   -149.9mA   -89.08mA   -251.1mA
-1.291V   -135.8mA   -80.52mA   -227.8mA
-1.145V   -82.58mA   -48.76mA   -138mA
-1.073V   -59.73mA   -35.66mA   -98.4mA
-1.036V   -49.42mA   -29.84mA   -80.39mA
-927.3mV  -26.77mA   -17.29mA   -39.76mA
-854.5mV  -17.22mA   -11.88mA   -23.45mA
-781.8mV  -11.05mA   -7.868mA   -15.32mA
-563.6mV  -3.181mA   -2.109mA   -5.072mA
-18.18mV  0A         0A         0A
3.6V      0A         0A         0A
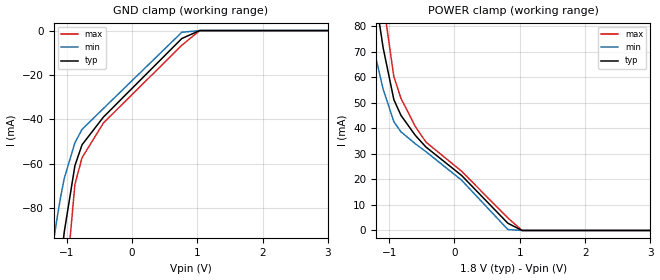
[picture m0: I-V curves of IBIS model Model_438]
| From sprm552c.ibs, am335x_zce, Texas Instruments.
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| Model based on original model for BCSHTLTCSCDVPBFZ_SSDHV
|   Sub model VREF_FULLTERM_12MA_10PER_1P8
[model]   Model_438
|[Description]  [1.8V-INPUT-FULLTERM:12MA-X, IND, 10%]
|   FULLTERM, 0.67 * RExt = 1.500 * Iout (I[2:0] = "111"), 12mA
|   nominal with Rext = 50R,Industrial temperature range (-40C to
|   125C, 25C nominal),10% power supply tolerance
|[Input Load]   FULLTERM:12MA
|[Output Drive]
|Voltage   1.8V
|Mode   INPUT
Model_type   Input
Polarity   Non-Inverting
Vinl =  0.775
Vinh =  1.025
C_comp   1.851324p   1.663768p   1.973575p
[Model Spec]
Vinl   0.775   0.685   0.865
Vinh   1.025   0.935   1.115
[Temperature Range]   25   125   -40
[Voltage Range]   1.8   1.62   1.98
[POWER_clamp]
-1.8V     211.2mA    148.2mA    283.4mA
-1.364V   120.9mA    87.63mA    157.6mA
-1.2V     90.04mA    67.37mA    115.3mA
-1.091V   71.57mA    55.38mA    89.8mA
-927.3mV  51.29mA    42.63mA    60.26mA
-818.2mV  45.1mA     38.65mA    51.77mA
-600mV    37.32mA    34.01mA    40.82mA
-436.4mV  32.71mA    30.89mA    34.65mA
109.1mV   21.58mA    19.72mA    23.22mA
818.2mV   2.833mA    358.8uA    4.898mA
1.036V    0A         0A         0A
3.6V      0A         0A         0A
[GND_clamp]
-1.8V     -375.1mA   -232.7mA   -599.1mA
-1.364V   -202.1mA   -130.2mA   -313.2mA
-1.2V     -141.8mA   -95.11mA   -211.4mA
-1.145V   -123.2mA   -84.53mA   -179.3mA
-1.091V   -105.9mA   -74.92mA   -149.4mA
-1.036V   -90.85mA   -66.67mA   -122.9mA
-872.7mV  -60.9mA    -50.59mA   -69.34mA
-763.6mV  -51.51mA   -44.56mA   -57.35mA
-436.4mV  -39mA      -35.13mA   -41.67mA
763.6mV   -3.578mA   -757.1uA   -6.63mA
1.036V    0A         0A         0A
3.6V      0A         0A         0A
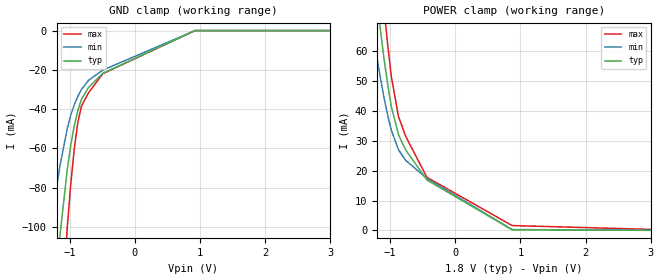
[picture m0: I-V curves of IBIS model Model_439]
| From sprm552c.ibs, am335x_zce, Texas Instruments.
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| Model based on original model for BCSHTLTCSCDVPBFZ_SSDHV
|   Sub model VREF_HALFTERM_12MA_5PER_1P8
[model]   Model_439
|[Description]  [1.8V-INPUT-HALFTERM:12MA-X, IND, 5%]
|   Half Thevenin termination (Rth = 100R whith RExt = 50R)
|   (ODT[1:0] = "11") VRef mode, 0.67 * RExt = 1.500 * Iout (I[2:0]
|   = "111"), 12mA nominal with Rext = 50R,Industrial temperature
|   range (-40C to 125C, 25C nominal),5% power supply tolerance
|[Input Load]   HALFTERM:12MA
|[Output Drive]
|Voltage   1.8V
|Mode   INPUT
Model_type   Input
Polarity   Non-Inverting
Vinl =  0.775
Vinh =  1.025
C_comp   1.851324p   1.667199p   1.973575p
[Model Spec]
Vinl   0.775   0.73   0.82
Vinh   1.025   0.98   1.07
[Temperature Range]   25   125   -40
[Voltage Range]   1.8   1.71   1.89
[POWER_clamp]
-1.8V     203.3mA    143.7mA    272.9mA
-1.309V   97.33mA    71.63mA    127.4mA
-1.255V   86.45mA    64.24mA    113mA
-1.145V   66.01mA    50.27mA    85.86mA
-1.091V   56.78mA    43.93mA    73.26mA
-1.036V   48.47mA    38.23mA    61.59mA
-981.8mV  41.35mA    33.41mA    51.3mA
-872.7mV  31.98mA    26.93mA    38.06mA
-763.6mV  26.95mA    23.42mA    31.51mA
-436.4mV  16.85mA    17.36mA    17.74mA
872.7mV   214uA      306.2uA    1.643mA
3.6V      0A         0A         0A
[GND_clamp]
-1.8V     -361.2mA   -223mA     -582.7mA
-1.309V   -162.9mA   -103.3mA   -258.1mA
-1.145V   -103.7mA   -68.47mA   -157.8mA
-1.036V   -70.97mA   -50.04mA   -100.7mA
-981.8mV  -58.4mA    -43.14mA   -78.32mA
-927.3mV  -48.47mA   -37.74mA   -60.26mA
-872.7mV  -40.8mA    -33.48mA   -46.78mA
-818.2mV  -35.09mA   -30.04mA   -38.55mA
-709.1mV  -28.99mA   -25.36mA   -31.71mA
-490.9mV  -21.81mA   -20.14mA   -21.98mA
927.3mV   0A         0A         0A
3.6V      0A         0A         0A
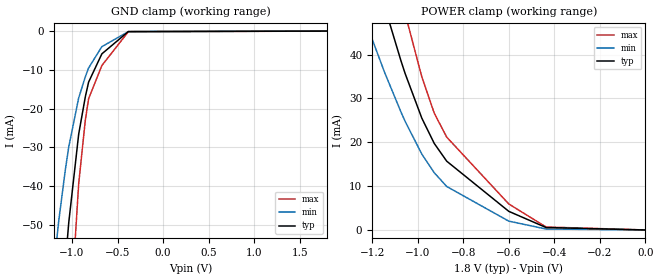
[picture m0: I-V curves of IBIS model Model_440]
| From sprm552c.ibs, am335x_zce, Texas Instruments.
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| Model based on original model for BCSHTLTCSCDVPBFZ_SSDHV
|   Sub model VREF_NOTERM_PUPD_OFF_5PER_1P8
[model]   Model_440
|[Description]  [1.8V-INPUT-PI-X, IND, 5%]
|   Weak pull up/down disabled,Industrial temperature range (-40C to
|   125C, 25C nominal),5% power supply tolerance
|[Input Load]   PI
|[Output Drive]
|Voltage   1.8V
|Mode   INPUT
Model_type   Input
Polarity   Non-Inverting
Vinl =  0.775
Vinh =  1.025
C_comp   1.851324p   1.667199p   1.973575p
[Model Spec]
Vinl   0.775   0.73   0.82
Vinh   1.025   0.98   1.07
[Temperature Range]   25   125   -40
[Voltage Range]   1.8   1.71   1.89
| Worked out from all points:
|   GND clamp passes 1 mA (typ) near -0.49 V on its own axis
|   POWER clamp passes 1 mA (typ) near -0.47 V on its own axis
[POWER_clamp]
-1.8V     194.9mA    137mA      262.9mA
-1.255V   72.22mA    51.11mA    97.57mA
-1.236V   68.56mA    48.51mA    92.87mA
-1.145V   50.88mA    35.88mA    69.99mA
-1.073V   38.49mA    26.84mA    53.26mA
-1.055V   35.64mA    24.74mA    49.31mA
-981.8mV  25.48mA    17.29mA    34.89mA
-927.3mV  19.73mA    13.05mA    26.63mA
-872.7mV  15.69mA    9.917mA    21.18mA
-600mV    4.245mA    2.011mA    5.927mA
-436.4mV  557.5uA    218.3uA    676.9uA
0V        2.476nA    17.84nA    10.59nA
[GND_clamp]
-1.8V     -346.1mA   -209.3mA   -568.4mA
-1.327V   -149.9mA   -89.07mA   -251.1mA
-1.291V   -135.8mA   -80.52mA   -227.8mA
-1.145V   -82.57mA   -48.75mA   -137.9mA
-1.073V   -59.7mA    -35.66mA   -98.29mA
-1.036V   -49.37mA   -29.84mA   -80.24mA
-927.3mV  -26.62mA   -17.26mA   -39.45mA
-854.5mV  -16.98mA   -11.8mA    -23.03mA
-818.2mV  -13.16mA   -9.508mA   -17.43mA
-672.7mV  -5.874mA   -4.018mA   -8.88mA
-381.8mV  -123.9uA   -132.8uA   -172uA
1.8V      2.476nA    59.98nA    6.606nA
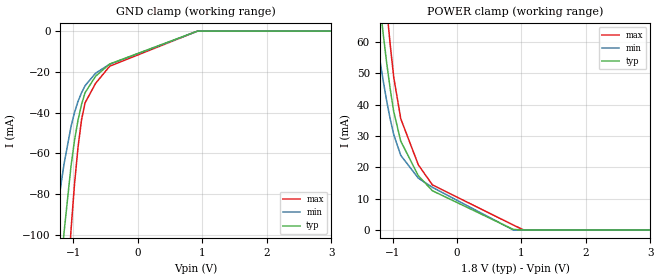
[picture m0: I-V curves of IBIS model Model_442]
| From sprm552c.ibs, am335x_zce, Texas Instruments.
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| Model based on original model for BCSHTLTCSCDVPBFZ_SSDHV
|   Sub model VREF_FULLTERM_5MA_5PER_1P8
[model]   Model_442
|[Description]  [1.8V-INPUT-FULLTERM:5MA-X, IND, 5%]
|   FULLTERM, 1.60 * RExt = 0.625 * Iout (I[2:0] = "000"), 5mA
|   nominal with Rext = 50R,Industrial temperature range (-40C to
|   125C, 25C nominal),5% power supply tolerance
|[Input Load]   FULLTERM:5MA
|[Output Drive]
|Voltage   1.8V
|Mode   INPUT
Model_type   Input
Polarity   Non-Inverting
Vinl =  0.775
Vinh =  1.025
C_comp   1.851324p   1.667199p   1.973575p
[Model Spec]
Vinl   0.775   0.73   0.82
Vinh   1.025   0.98   1.07
[Temperature Range]   25   125   -40
[Voltage Range]   1.8   1.71   1.89
[POWER_clamp]
-1.8V     201.5mA    142.5mA    271.3mA
-1.255V   83.28mA    61.88mA    110.6mA
-1.145V   62.64mA    47.68mA    83.45mA
-1.091V   53.34mA    41.21mA    70.83mA
-1.036V   44.98mA    35.4mA     59.14mA
-981.8mV  37.82mA    30.48mA    48.83mA
-872.7mV  28.36mA    23.82mA    35.52mA
-600mV    17.31mA    16.53mA    20.79mA
-381.8mV  12.52mA    13.61mA    14.39mA
872.7mV   166.5uA    0A         1.574mA
1.036V    0A         0A         0A
3.6V      0A         0A         0A
[GND_clamp]
-1.8V     -357.8mA   -220.8mA   -580.4mA
-1.309V   -158.4mA   -100.3mA   -255.1mA
-1.145V   -99mA      -65.3mA    -154.6mA
-1.036V   -66.17mA   -46.8mA    -97.47mA
-981.8mV  -53.57mA   -39.89mA   -75.01mA
-927.3mV  -43.62mA   -34.47mA   -56.93mA
-872.7mV  -35.93mA   -30.21mA   -43.43mA
-818.2mV  -30.22mA   -26.79mA   -35.17mA
-654.5mV  -22.11mA   -20.63mA   -25.61mA
-436.4mV  -16.14mA   -16.24mA   -17.22mA
927.3mV   0A         0A         0A
3.6V      0A         0A         0A
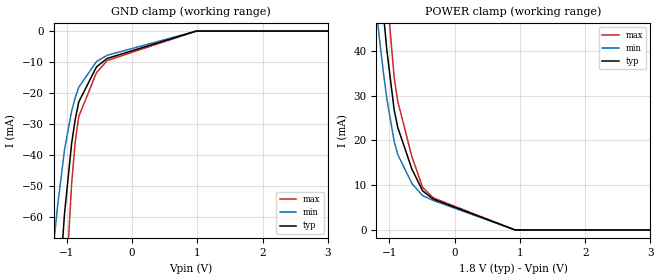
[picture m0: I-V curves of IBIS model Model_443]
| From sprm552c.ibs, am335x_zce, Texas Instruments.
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| Model based on original model for BCSHTLTCSCDVPBFZ_SSDHV
|   Sub model VREF_HALFTERM_5MA_5PER_1P8
[model]   Model_443
|[Description]  [1.8V-INPUT-HALFTERM:5MA-X, IND, 5%]
|   Half Thevenin termination (Rth = 100R whith RExt = 50R)
|   (ODT[1:0] = "11") VRef mode, 1.60 * RExt = 0.625 * Iout (I[2:0]
|   = "000"), 5mA nominal with Rext = 50R,Industrial temperature
|   range (-40C to 125C, 25C nominal),5% power supply tolerance
|[Input Load]   HALFTERM:5MA
|[Output Drive]
|Voltage   1.8V
|Mode   INPUT
Model_type   Input
Polarity   Non-Inverting
Vinl =  0.775
Vinh =  1.025
C_comp   1.851324p   1.667199p   1.973575p
[Model Spec]
Vinl   0.775   0.73   0.82
Vinh   1.025   0.98   1.07
[Temperature Range]   25   125   -40
[Voltage Range]   1.8   1.71   1.89
[POWER_clamp]
-1.8V     198.7mA    139.8mA    267.5mA
-1.255V   78.54mA    56.49mA    104.6mA
-1.145V   57.6mA     41.78mA    77.2mA
-1.091V   48.2mA     35.07mA    64.49mA
-1.036V   39.76mA    29.02mA    52.71mA
-927.3mV  26.88mA    19.84mA    34.14mA
-872.7mV  22.93mA    16.87mA    28.78mA
-654.5mV  13.57mA    10.36mA    16.32mA
-490.9mV  8.74mA     7.669mA    9.524mA
-327.3mV  6.88mA     6.575mA    7.164mA
927.3mV   0A         0A         0A
3.6V      0A         0A         0A
[GND_clamp]
-1.8V     -352.8mA   -215mA     -575.2mA
-1.309V   -151.7mA   -92.51mA   -248.3mA
-1.255V   -131mA     -80.07mA   -213.8mA
-1.145V   -91.96mA   -57.02mA   -147.4mA
-1.036V   -58.97mA   -38.32mA   -90.06mA
-927.3mV  -36.33mA   -25.87mA   -49.43mA
-872.7mV  -28.63mA   -21.58mA   -35.9mA
-818.2mV  -22.91mA   -18.15mA   -27.59mA
-545.5mV  -11.53mA   -9.838mA   -13.4mA
-381.8mV  -8.825mA   -7.811mA   -9.502mA
981.8mV   0A         0A         -34.71uA
3.6V      0A         0A         0A
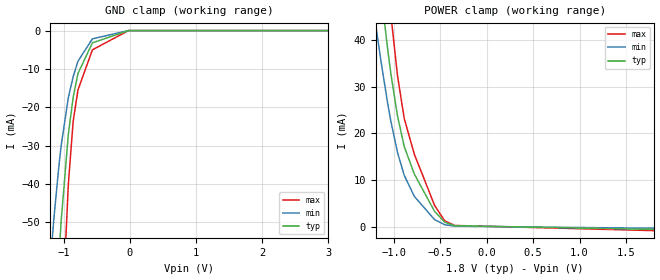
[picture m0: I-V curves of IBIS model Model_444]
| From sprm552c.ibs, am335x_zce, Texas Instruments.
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| Model based on original model for BCSHTLTCSCDVPBFZ_SSDHV
|   Sub model VREF_NOTERM_PU_ON_5PER_1P8
[model]   Model_444
|[Description]  [1.8V-INPUT-PU-X, IND, 5%]
|   Weak internal pull-up,Industrial temperature range (-40C to
|   125C, 25C nominal),5% power supply tolerance
|[Input Load]   PU
|[Output Drive]
|Voltage   1.8V
|Mode   INPUT
Model_type   Input
Polarity   Non-Inverting
Vinl =  0.775
Vinh =  1.025
C_comp   1.851324p   1.667199p   1.973575p
[Model Spec]
Vinl   0.775   0.73   0.82
Vinh   1.025   0.98   1.07
[Temperature Range]   25   125   -40
[Voltage Range]   1.8   1.71   1.89
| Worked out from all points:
|   GND clamp passes 1 mA (typ) near -0.42 V on its own axis
|   POWER clamp passes 1 mA (typ) near -0.46 V on its own axis
[POWER_clamp]
-1.8V     194.9mA    137mA      262.9mA
-1.255V   72.27mA    51.13mA    97.67mA
-1.145V   50.96mA    35.91mA    70.19mA
-1.073V   38.63mA    26.88mA    53.52mA
-1.036V   32.96mA    22.7mA     45.64mA
-963.6mV  23.74mA    15.93mA    32.4mA
-890.9mV  17.19mA    11.01mA    23.21mA
-781.8mV  11.27mA    6.489mA    15.52mA
-563.6mV  3.282mA    1.511mA    4.565mA
-454.5mV  956.3uA    410.3uA    1.246mA
-345.5mV  206.7uA    108.8uA    260.8uA
1.8V      -592.4uA   -346.2uA   -847.7uA
[GND_clamp]
-1.8V     -346.2mA   -209.3mA   -568.5mA
-1.327V   -150.1mA   -89.16mA   -251.4mA
-1.291V   -136mA     -80.61mA   -228.1mA
-1.145V   -82.87mA   -48.9mA    -138.3mA
-1.073V   -60.04mA   -35.83mA   -98.8mA
-1.036V   -49.74mA   -30.02mA   -80.82mA
-927.3mV  -27.04mA   -17.47mA   -40.09mA
-854.5mV  -17.42mA   -12.03mA   -23.69mA
-781.8mV  -11.18mA   -7.98mA    -15.46mA
-563.6mV  -3.189mA   -2.148mA   -5.015mA
-18.18mV  0A         0A         0A
3.6V      0A         0A         0A
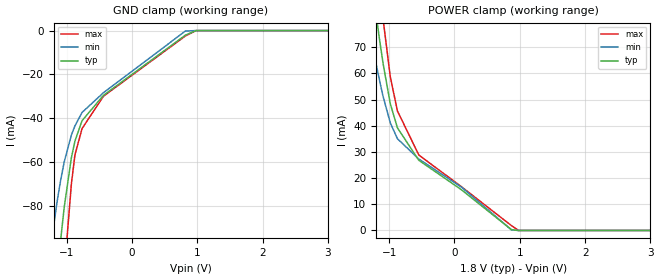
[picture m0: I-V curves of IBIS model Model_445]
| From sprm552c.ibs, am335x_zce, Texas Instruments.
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| Model based on original model for BCSHTLTCSCDVPBFZ_SSDHV
|   Sub model VREF_FULLTERM_9MA_5PER_1P8
[model]   Model_445
|[Description]  [1.8V-INPUT-FULLTERM:9MA-X, IND, 5%]
|   FULLTERM, 0.88 * RExt = 1.125 * Iout (I[2:0] = "100"), 9mA
|   nominal with Rext = 50R,Industrial temperature range (-40C to
|   125C, 25C nominal),5% power supply tolerance
|[Input Load]   FULLTERM:9MA
|[Output Drive]
|Voltage   1.8V
|Mode   INPUT
Model_type   Input
Polarity   Non-Inverting
Vinl =  0.775
Vinh =  1.025
C_comp   1.851324p   1.667199p   1.973575p
[Model Spec]
Vinl   0.775   0.73   0.82
Vinh   1.025   0.98   1.07
[Temperature Range]   25   125   -40
[Voltage Range]   1.8   1.71   1.89
[POWER_clamp]
-1.8V     207.1mA    146.9mA    277.5mA
-1.309V   103.4mA    77.62mA    134.2mA
-1.2V     82.51mA    63.69mA    106.3mA
-1.145V   72.74mA    57.17mA    93.07mA
-1.091V   63.64mA    51.1mA     80.55mA
-981.8mV  48.41mA    41.11mA    58.73mA
-872.7mV  39.22mA    35.05mA    45.66mA
-545.5mV  26.81mA    27.29mA    28.84mA
109.1mV   15.52mA    16.53mA    16.68mA
872.7mV   308.8uA    219.9uA    1.849mA
981.8mV   0A         0A         0A
3.6V      0A         0A         0A
[GND_clamp]
-1.8V     -367.8mA   -229.7mA   -589.5mA
-1.309V   -171.9mA   -112.4mA   -267.1mA
-1.145V   -113.1mA   -78.13mA   -167.3mA
-1.091V   -95.74mA   -68.35mA   -137.2mA
-1.036V   -80.57mA   -59.94mA   -110.6mA
-927.3mV  -58.19mA   -47.78mA   -70.25mA
-872.7mV  -50.53mA   -43.55mA   -56.85mA
-763.6mV  -41.17mA   -37.41mA   -44.8mA
-436.4mV  -29.61mA   -28.4mA    -30mA
818.2mV   -2.078mA   -212.3uA   -2.474mA
981.8mV   0A         0A         0A
3.6V      0A         0A         0A
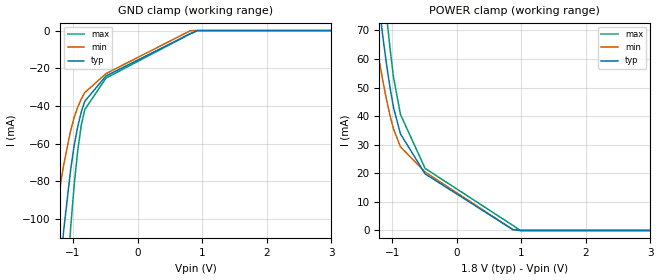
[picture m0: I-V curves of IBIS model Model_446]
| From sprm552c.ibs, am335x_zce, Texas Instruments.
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| Model based on original model for BCSHTLTCSCDVPBFZ_SSDHV
|   Sub model VREF_FULLTERM_7MA_5PER_1P8
[model]   Model_446
|[Description]  [1.8V-INPUT-FULLTERM:7MA-X, IND, 5%]
|   FULLTERM, 1.14 * RExt = 0.875 * Iout (I[2:0] = "010"), 7mA
|   nominal with Rext = 50R,Industrial temperature range (-40C to
|   125C, 25C nominal),5% power supply tolerance
|[Input Load]   FULLTERM:7MA
|[Output Drive]
|Voltage   1.8V
|Mode   INPUT
Model_type   Input
Polarity   Non-Inverting
Vinl =  0.775
Vinh =  1.025
C_comp   1.851324p   1.667199p   1.973575p
[Model Spec]
Vinl   0.775   0.73   0.82
Vinh   1.025   0.98   1.07
[Temperature Range]   25   125   -40
[Voltage Range]   1.8   1.71   1.89
[POWER_clamp]
-1.8V     204.3mA    144.6mA    274.4mA
-1.309V   98.85mA    73.34mA    129.6mA
-1.255V   88.03mA    66.03mA    115.3mA
-1.145V   67.69mA    52.24mA    88.26mA
-1.091V   58.49mA    45.98mA    75.69mA
-1.036V   50.21mA    40.35mA    64.04mA
-981.8mV  43.12mA    35.61mA    53.78mA
-872.7mV  33.79mA    29.25mA    40.59mA
-490.9mV  19.79mA    20.43mA    21.71mA
872.7mV   237.7uA    281.5uA    1.711mA
981.8mV   0A         0A         0A
3.6V      0A         0A         0A
[GND_clamp]
-1.8V     -362.8mA   -224.9mA   -584.9mA
-1.309V   -165.1mA   -105.9mA   -261.1mA
-1.145V   -106mA     -71.23mA   -161mA
-1.036V   -73.37mA   -52.87mA   -104mA
-981.8mV  -60.82mA   -46mA      -81.62mA
-927.3mV  -50.9mA    -40.61mA   -63.59mA
-872.7mV  -43.23mA   -36.35mA   -50.14mA
-818.2mV  -37.53mA   -32.92mA   -41.94mA
-490.9mV  -24.12mA   -22.85mA   -25.24mA
818.2mV   -1.599mA   -50.33uA   -1.699mA
927.3mV   0A         0A         0A
3.6V      0A         0A         0A
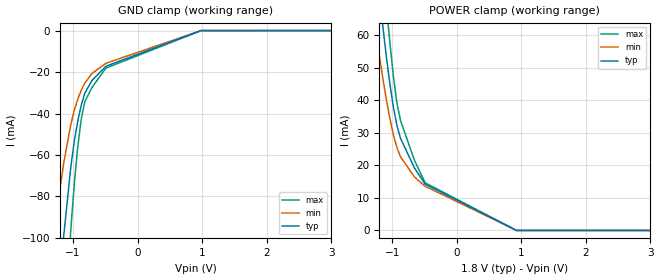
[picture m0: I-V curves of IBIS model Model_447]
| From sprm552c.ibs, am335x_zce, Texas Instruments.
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| Model based on original model for BCSHTLTCSCDVPBFZ_SSDHV
|   Sub model VREF_HALFTERM_9MA_5PER_1P8
[model]   Model_447
|[Description]  [1.8V-INPUT-HALFTERM:9MA-X, IND, 5%]
|   Half Thevenin termination (Rth = 100R whith RExt = 50R)
|   (ODT[1:0] = "11") VRef mode, 0.88 * RExt = 1.125 * Iout (I[2:0]
|   = "100"), 9mA nominal with Rext = 50R,Industrial temperature
|   range (-40C to 125C, 25C nominal),5% power supply tolerance
|[Input Load]   HALFTERM:9MA
|[Output Drive]
|Voltage   1.8V
|Mode   INPUT
Model_type   Input
Polarity   Non-Inverting
Vinl =  0.775
Vinh =  1.025
C_comp   1.851324p   1.667199p   1.973575p
[Model Spec]
Vinl   0.775   0.73   0.82
Vinh   1.025   0.98   1.07
[Temperature Range]   25   125   -40
[Voltage Range]   1.8   1.71   1.89
[POWER_clamp]
-1.8V     201.5mA    142.1mA    270.6mA
-1.255V   83.28mA    60.98mA    109.3mA
-1.145V   62.64mA    46.69mA    82.01mA
-1.091V   53.34mA    40.19mA    69.35mA
-1.036V   44.98mA    34.34mA    57.61mA
-981.8mV  37.82mA    29.38mA    47.26mA
-927.3mV  32.24mA    25.49mA    39.15mA
-872.7mV  28.36mA    22.66mA    33.85mA
-654.5mV  19.16mA    16.41mA    21.51mA
-490.9mV  14.27mA    13.59mA    14.66mA
927.3mV   0A         0A         0A
3.6V      0A         0A         0A
[GND_clamp]
-1.8V     -357.8mA   -219.8mA   -579.7mA
-1.309V   -158.4mA   -99.01mA   -254.3mA
-1.145V   -99mA      -63.92mA   -153.8mA
-1.036V   -66.17mA   -45.39mA   -96.61mA
-981.8mV  -53.57mA   -38.46mA   -74.16mA
-927.3mV  -43.62mA   -33.04mA   -56.09mA
-872.7mV  -35.93mA   -28.77mA   -42.61mA
-818.2mV  -30.22mA   -25.35mA   -34.36mA
-709.1mV  -24.14mA   -20.71mA   -27.56mA
-490.9mV  -17.2mA    -15.77mA   -18.09mA
981.8mV   0A         0A         -57.83uA
3.6V      0A         0A         0A
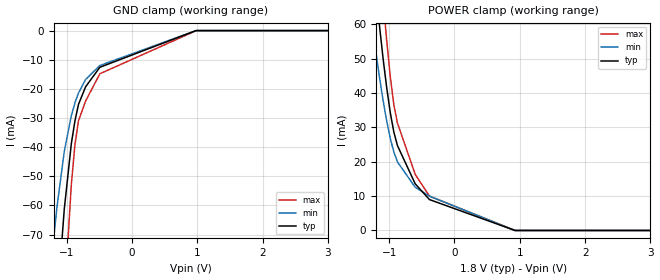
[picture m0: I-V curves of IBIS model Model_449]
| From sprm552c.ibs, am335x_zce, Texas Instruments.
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| Model based on original model for BCSHTLTCSCDVPBFZ_SSDHV
|   Sub model VREF_HALFTERM_7MA_5PER_1P8
[model]   Model_449
|[Description]  [1.8V-INPUT-HALFTERM:7MA-X, IND, 5%]
|   Half Thevenin termination (Rth = 100R whith RExt = 50R)
|   (ODT[1:0] = "11") VRef mode, 1.14 * RExt = 0.875 * Iout (I[2:0]
|   = "010"), 7mA nominal with Rext = 50R,Industrial temperature
|   range (-40C to 125C, 25C nominal),5% power supply tolerance
|[Input Load]   HALFTERM:7MA
|[Output Drive]
|Voltage   1.8V
|Mode   INPUT
Model_type   Input
Polarity   Non-Inverting
Vinl =  0.775
Vinh =  1.025
C_comp   1.851324p   1.667199p   1.973575p
[Model Spec]
Vinl   0.775   0.73   0.82
Vinh   1.025   0.98   1.07
[Temperature Range]   25   125   -40
[Voltage Range]   1.8   1.71   1.89
[POWER_clamp]
-1.8V     199.6mA    140.9mA    269.1mA
-1.255V   80.12mA    58.85mA    106.9mA
-1.145V   59.28mA    44.37mA    79.61mA
-1.091V   49.91mA    37.78mA    66.92mA
-1.036V   41.5mA     31.85mA    55.16mA
-981.8mV  34.29mA    26.81mA    44.78mA
-927.3mV  28.67mA    22.86mA    36.64mA
-872.7mV  24.74mA    19.98mA    31.31mA
-600mV    13.57mA    12.58mA    16.32mA
-381.8mV  8.996mA    10mA       10mA
927.3mV   0A         0A         0A
3.6V      0A         0A         0A
[GND_clamp]
-1.8V     -354.5mA   -217.3mA   -577.4mA
-1.309V   -153.9mA   -95.51mA   -251.3mA
-1.255V   -133.3mA   -83.13mA   -216.8mA
-1.145V   -94.3mA    -60.19mA   -150.6mA
-1.036V   -61.37mA   -41.55mA   -93.33mA
-927.3mV  -38.76mA   -29.13mA   -52.76mA
-872.7mV  -31.06mA   -24.84mA   -39.25mA
-818.2mV  -25.34mA   -21.41mA   -30.97mA
-709.1mV  -19.29mA   -16.77mA   -24.18mA
-490.9mV  -12.59mA   -11.98mA   -14.82mA
981.8mV   0A         0A         -46.27uA
3.6V      0A         0A         0A
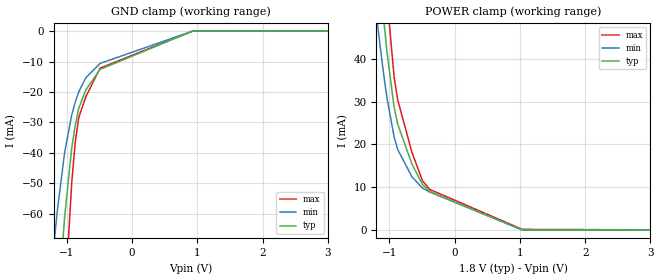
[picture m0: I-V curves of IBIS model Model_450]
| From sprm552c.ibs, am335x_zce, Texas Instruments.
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| Model based on original model for BCSHTLTCSCDVPBFZ_SSDHV
|   Sub model VREF_HALFTERM_6MA_5PER_1P8
[model]   Model_450
|[Description]  [1.8V-INPUT-HALFTERM:6MA-X, IND, 5%]
|   Half Thevenin termination (Rth = 100R whith RExt = 50R)
|   (ODT[1:0] = "11") VRef mode, 1.33 * RExt = 0.750 * Iout (I[2:0]
|   = "001"), 6mA nominal with Rext = 50R,Industrial temperature
|   range (-40C to 125C, 25C nominal),5% power supply tolerance
|[Input Load]   HALFTERM:6MA
|[Output Drive]
|Voltage   1.8V
|Mode   INPUT
Model_type   Input
Polarity   Non-Inverting
Vinl =  0.775
Vinh =  1.025
C_comp   1.851324p   1.667199p   1.973575p
[Model Spec]
Vinl   0.775   0.73   0.82
Vinh   1.025   0.98   1.07
[Temperature Range]   25   125   -40
[Voltage Range]   1.8   1.71   1.89
[POWER_clamp]
-1.8V     199.6mA    140.4mA    268.2mA
-1.255V   80.12mA    57.95mA    105.9mA
-1.145V   59.28mA    43.39mA    78.64mA
-1.091V   49.91mA    36.76mA    65.98mA
-1.036V   41.5mA     30.79mA    54.24mA
-927.3mV  28.67mA    21.73mA    35.77mA
-872.7mV  24.74mA    18.82mA    30.45mA
-654.5mV  15.43mA    12.44mA    18.16mA
-490.9mV  10.58mA    9.761mA    11.45mA
-381.8mV  8.996mA    8.875mA    9.481mA
1.036V    0A         0A         136.9uA
3.6V      0A         0A         0A
[GND_clamp]
-1.8V     -354.5mA   -216.3mA   -575.9mA
-1.309V   -153.9mA   -94.22mA   -249.2mA
-1.255V   -133.3mA   -81.8mA    -214.6mA
-1.145V   -94.3mA    -58.81mA   -148.3mA
-1.036V   -61.37mA   -40.14mA   -90.92mA
-927.3mV  -38.76mA   -27.7mA    -50.27mA
-872.7mV  -31.06mA   -23.41mA   -36.72mA
-818.2mV  -25.34mA   -19.97mA   -28.39mA
-709.1mV  -19.29mA   -15.33mA   -21.55mA
-490.9mV  -12.59mA   -10.62mA   -12.17mA
927.3mV   0A         0A         0A
3.6V      0A         0A         0A
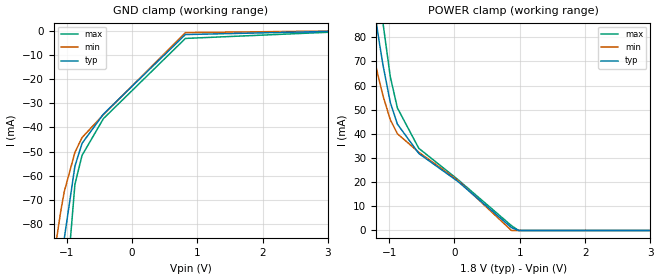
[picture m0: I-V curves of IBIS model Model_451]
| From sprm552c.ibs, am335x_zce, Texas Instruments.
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| Model based on original model for BCSHTLTCSCDVPBFZ_SSDHV
|   Sub model VREF_FULLTERM_11MA_5PER_1P8
[model]   Model_451
|[Description]  [1.8V-INPUT-FULLTERM:11MA-X, IND, 5%]
|   FULLTERM, 0.73 * RExt = 1.325 * Iout (I[2:0] = "110"), 11mA
|   nominal with Rext = 50R,Industrial temperature range (-40C to
|   125C, 25C nominal),5% power supply tolerance
|[Input Load]   FULLTERM:11MA
|[Output Drive]
|Voltage   1.8V
|Mode   INPUT
Model_type   Input
Polarity   Non-Inverting
Vinl =  0.775
Vinh =  1.025
C_comp   1.851324p   1.667199p   1.973575p
[Model Spec]
Vinl   0.775   0.73   0.82
Vinh   1.025   0.98   1.07
[Temperature Range]   25   125   -40
[Voltage Range]   1.8   1.71   1.89
[POWER_clamp]
-1.8V     209.3mA    149mA      280.6mA
-1.309V   107.3mA    81.37mA    138.8mA
-1.2V     86.76mA    67.81mA    111mA
-1.145V   77.12mA    61.46mA    97.89mA
-1.091V   68.13mA    55.57mA    85.41mA
-981.8mV  53.07mA    45.88mA    63.68mA
-872.7mV  44.04mA    40.06mA    50.73mA
-545.5mV  31.9mA     32.4mA     34.02mA
54.55mV   20.27mA    20.7mA     21.05mA
872.7mV   1.198mA    0A         1.986mA
981.8mV   0A         0A         0A
3.6V      0A         0A         0A
[GND_clamp]
-1.8V     -371.7mA   -234.2mA   -594mA
-1.364V   -197.7mA   -130.7mA   -307.7mA
-1.309V   -177mA     -118.5mA   -273.1mA
-1.2V     -137.2mA   -95.3mA    -205.8mA
-1.145V   -118.5mA   -84.62mA   -173.7mA
-1.091V   -101.2mA   -74.93mA   -143.7mA
-1.036V   -86.04mA   -66.61mA   -117.1mA
-872.7mV  -56.03mA   -50.35mA   -63.56mA
-763.6mV  -46.64mA   -44.23mA   -51.59mA
-436.4mV  -34.52mA   -34.74mA   -36.39mA
818.2mV   -1.643mA   -841.9uA   -3.247mA
3.6V      0A         0A         0A
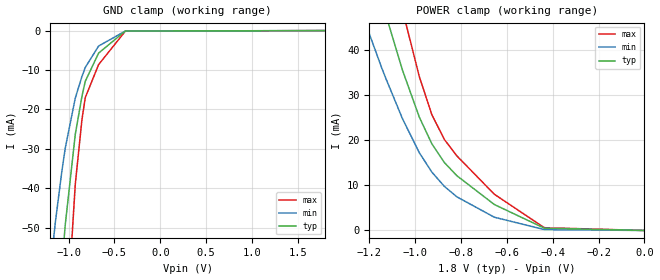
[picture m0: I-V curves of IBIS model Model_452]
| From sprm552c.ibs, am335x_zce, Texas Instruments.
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| Model based on original model for BCSHTLTCSCDVPBFZ_SSDHV
|   Sub model LVCMOS_PUPD_OFF_5PER_1P8
[model]   Model_452
|[Description]  [1.8V-INPUT-PI-X, IND, 5%]
|   Weak pull up/down disabled,Industrial temperature range (-40C to
|   125C, 25C nominal),5% power supply tolerance
|[Input Load]   PI
|[Output Drive]
|Voltage   1.8V
|Mode   INPUT
Model_type   Input
Polarity   Non-Inverting
Vinl =  0.63
Vinh =  1.17
C_comp   1.851324p   1.667199p   1.973575p
[Model Spec]
Vinl   0.63   0.5985   0.6615
Vinh   1.17   1.1115   1.2285
[Temperature Range]   25   125   -40
[Voltage Range]   1.8   1.71   1.89
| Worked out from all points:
|   GND clamp passes 1 mA (typ) near -0.49 V on its own axis
|   POWER clamp passes 1 mA (typ) near -0.47 V on its own axis
[POWER_clamp]
-1.8V     194.9mA    137mA      262.9mA
-1.236V   68.49mA    48.49mA    92.7mA
-1.145V   50.76mA    35.84mA    69.67mA
-1.127V   47.56mA    33.52mA    65.35mA
-1.055V   35.4mA     24.68mA    48.7mA
-981.8mV  25.06mA    17.19mA    34.02mA
-927.3mV  19.17mA    12.92mA    25.62mA
-872.7mV  15.03mA    9.76mA     20.13mA
-818.2mV  12.12mA    7.445mA    16.51mA
-654.5mV  5.738mA    2.929mA    8.007mA
-436.4mV  508.2uA    199.4uA    613uA
0V        2.273nA    16.6nA     10.58nA
[GND_clamp]
-1.8V     -346.1mA   -209.3mA   -568.3mA
-1.327V   -149.7mA   -89.03mA   -250.9mA
-1.291V   -135.6mA   -80.47mA   -227.5mA
-1.145V   -82.35mA   -48.67mA   -137.7mA
-1.073V   -59.44mA   -35.55mA   -97.96mA
-1.036V   -49.1mA    -29.72mA   -79.9mA
-927.3mV  -26.31mA   -17.11mA   -38.99mA
-854.5mV  -16.67mA   -11.64mA   -22.56mA
-818.2mV  -12.86mA   -9.351mA   -16.98mA
-672.7mV  -5.705mA   -3.913mA   -8.623mA
-381.8mV  -120.4uA   -129uA     -167.2uA
1.8V      2.273nA    51.44nA    6.654nA
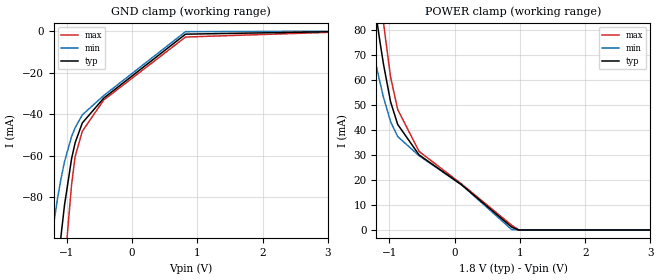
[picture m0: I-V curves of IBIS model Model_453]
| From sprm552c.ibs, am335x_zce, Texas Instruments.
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| Model based on original model for BCSHTLTCSCDVPBFZ_SSDHV
|   Sub model VREF_FULLTERM_10MA_5PER_1P8
[model]   Model_453
|[Description]  [1.8V-INPUT-FULLTERM:10MA-X, IND, 5%]
|   FULLTERM, 0.80 * RExt = 1.250 * Iout (I[2:0] = "101"), 10mA
|   nominal with Rext = 50R,Industrial temperature range (-40C to
|   125C, 25C nominal),5% power supply tolerance
|[Input Load]   FULLTERM:10MA
|[Output Drive]
|Voltage   1.8V
|Mode   INPUT
Model_type   Input
Polarity   Non-Inverting
Vinl =  0.775
Vinh =  1.025
C_comp   1.851324p   1.667199p   1.973575p
[Model Spec]
Vinl   0.775   0.73   0.82
Vinh   1.025   0.98   1.07
[Temperature Range]   25   125   -40
[Voltage Range]   1.8   1.71   1.89
[POWER_clamp]
-1.8V     208.4mA    147.8mA    279.1mA
-1.309V   105.8mA    79.33mA    136.5mA
-1.2V     85.12mA    65.57mA    108.6mA
-1.145V   75.44mA    59.14mA    95.48mA
-1.091V   66.42mA    53.16mA    82.98mA
-981.8mV  51.31mA    43.31mA    61.2mA
-872.7mV  42.23mA    37.37mA    48.2mA
-545.5mV  30.04mA    29.7mA     31.43mA
109.1mV   18.01mA    18.02mA    18.33mA
872.7mV   1.174mA    195.3uA    1.918mA
981.8mV   0A         0A         0A
3.6V      0A         0A         0A
[GND_clamp]
-1.8V     -370.1mA   -231.6mA   -591.7mA
-1.364V   -195.5mA   -127.3mA   -304.7mA
-1.309V   -174.8mA   -115mA     -270.1mA
-1.145V   -116.1mA   -80.89mA   -170.5mA
-1.091V   -98.8mA    -71.14mA   -140.4mA
-1.036V   -83.64mA   -62.77mA   -113.8mA
-927.3mV  -61.27mA   -50.65mA   -73.58mA
-872.7mV  -53.6mA    -46.43mA   -60.21mA
-763.6mV  -44.2mA    -40.29mA   -48.2mA
-436.4mV  -32.27mA   -31.04mA   -33.19mA
818.2mV   -1.483mA   -277uA     -2.861mA
3.6V      0A         0A         0A
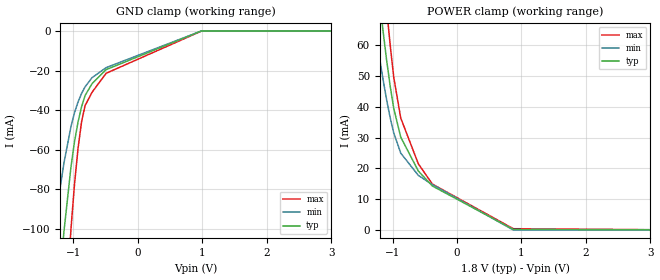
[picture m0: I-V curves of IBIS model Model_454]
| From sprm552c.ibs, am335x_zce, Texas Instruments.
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| Model based on original model for BCSHTLTCSCDVPBFZ_SSDHV
|   Sub model VREF_HALFTERM_11MA_5PER_1P8
[model]   Model_454
|[Description]  [1.8V-INPUT-HALFTERM:11MA-X, IND, 5%]
|   Half Thevenin termination (Rth = 100R whith RExt = 50R)
|   (ODT[1:0] = "11") VRef mode, 0.73 * RExt = 1.325 * Iout (I[2:0]
|   = "110"), 11mA nominal with Rext = 50R,Industrial temperature
|   range (-40C to 125C, 25C nominal),5% power supply tolerance
|[Input Load]   HALFTERM:11MA
|[Output Drive]
|Voltage   1.8V
|Mode   INPUT
Model_type   Input
Polarity   Non-Inverting
Vinl =  0.775
Vinh =  1.025
C_comp   1.851324p   1.667199p   1.973575p
[Model Spec]
Vinl   0.775   0.73   0.82
Vinh   1.025   0.98   1.07
[Temperature Range]   25   125   -40
[Voltage Range]   1.8   1.71   1.89
[POWER_clamp]
-1.8V     202.4mA    143mA      272.2mA
-1.309V   95.81mA    70.26mA    126.1mA
-1.255V   84.87mA    62.78mA    111.6mA
-1.145V   64.32mA    48.66mA    84.41mA
-1.091V   55.06mA    42.24mA    71.77mA
-1.036V   46.72mA    36.46mA    60.06mA
-981.8mV  39.59mA    31.58mA    49.73mA
-872.7mV  30.17mA    24.98mA    36.38mA
-600mV    19.17mA    17.74mA    21.51mA
-381.8mV  14.29mA    14.73mA    14.91mA
872.7mV   190.2uA    0A         415.1uA
3.6V      0A         0A         0A
[GND_clamp]
-1.8V     -359.5mA   -221.7mA   -582mA
-1.309V   -160.7mA   -101.6mA   -257.3mA
-1.145V   -101.3mA   -66.68mA   -157mA
-1.036V   -68.57mA   -48.22mA   -99.88mA
-981.8mV  -55.98mA   -41.31mA   -77.47mA
-927.3mV  -46.04mA   -35.91mA   -59.42mA
-872.7mV  -38.36mA   -31.65mA   -45.96mA
-818.2mV  -32.65mA   -28.22mA   -37.75mA
-709.1mV  -26.57mA   -23.57mA   -30.95mA
-490.9mV  -19.51mA   -18.49mA   -21.36mA
981.8mV   0A         0A         -69.38uA
3.6V      0A         0A         0A
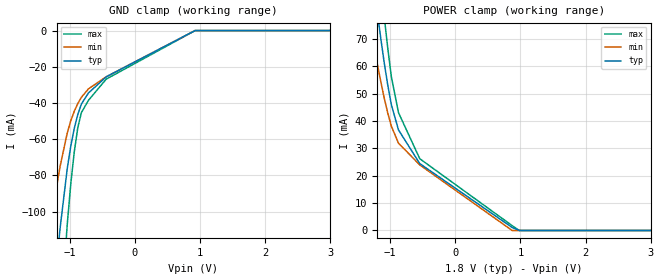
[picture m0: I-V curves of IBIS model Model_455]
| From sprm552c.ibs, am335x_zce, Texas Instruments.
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| Model based on original model for BCSHTLTCSCDVPBFZ_SSDHV
|   Sub model VREF_FULLTERM_8MA_5PER_1P8
[model]   Model_455
|[Description]  [1.8V-INPUT-FULLTERM:8MA-X, IND, 5%]
|   FULLTERM, 1.00 * RExt = 1.000 * Iout (I[2:0] = "011"), 8mA
|   nominal with Rext = 50R,Industrial temperature range (-40C to
|   125C, 25C nominal),5% power supply tolerance
|[Input Load]   FULLTERM:8MA
|[Output Drive]
|Voltage   1.8V
|Mode   INPUT
Model_type   Input
Polarity   Non-Inverting
Vinl =  0.775
Vinh =  1.025
C_comp   1.851324p   1.667199p   1.973575p
[Model Spec]
Vinl   0.775   0.73   0.82
Vinh   1.025   0.98   1.07
[Temperature Range]   25   125   -40
[Voltage Range]   1.8   1.71   1.89
[POWER_clamp]
-1.8V     205.6mA    145.8mA    276mA
-1.309V   101.2mA    75.39mA    131.9mA
-1.2V     80.2mA     61.2mA     103.9mA
-1.145V   70.39mA    54.57mA    90.67mA
-1.091V   61.27mA    48.39mA    78.12mA
-1.036V   53.04mA    42.85mA    66.49mA
-981.8mV  46.01mA    38.17mA    56.25mA
-872.7mV  36.8mA     31.94mA    43.13mA
-545.5mV  24.46mA    23.99mA    26.25mA
872.7mV   1.104mA    0A         1.78mA
981.8mV   0A         0A         0A
3.6V      0A         0A         0A
[GND_clamp]
-1.8V     -365mA     -227.5mA   -587.2mA
-1.309V   -168.1mA   -109.4mA   -264.1mA
-1.145V   -109.1mA   -74.95mA   -164.2mA
-1.036V   -76.44mA   -56.7mA    -107.3mA
-981.8mV  -63.9mA    -49.87mA   -84.93mA
-927.3mV  -53.98mA   -44.52mA   -66.92mA
-872.7mV  -46.3mA    -40.28mA   -53.49mA
-818.2mV  -40.58mA   -36.86mA   -45.33mA
-709.1mV  -34.43mA   -32.17mA   -38.48mA
-436.4mV  -25.55mA   -25.5mA    -26.81mA
927.3mV   0A         0A         0A
3.6V      0A         0A         0A
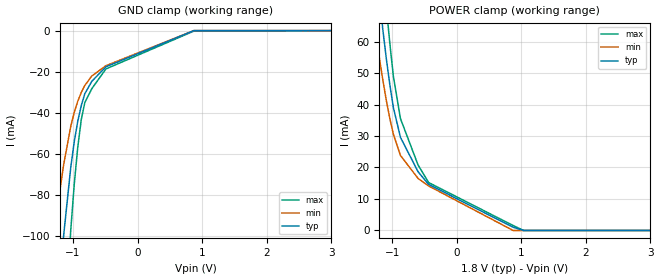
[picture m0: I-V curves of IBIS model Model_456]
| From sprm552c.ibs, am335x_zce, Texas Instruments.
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| Model based on original model for BCSHTLTCSCDVPBFZ_SSDHV
|   Sub model VREF_HALFTERM_10MA_5PER_1P8
[model]   Model_456
|[Description]  [1.8V-INPUT-HALFTERM:10MA-X, IND, 5%]
|   Half Thevenin termination (Rth = 100R whith RExt = 50R)
|   (ODT[1:0] = "11") VRef mode, 0.80 * RExt = 1.250 * Iout (I[2:0]
|   = "101"), 10mA nominal with Rext = 50R,Industrial temperature
|   range (-40C to 125C, 25C nominal),5% power supply tolerance
|[Input Load]   HALFTERM:10MA
|[Output Drive]
|Voltage   1.8V
|Mode   INPUT
Model_type   Input
Polarity   Non-Inverting
Vinl =  0.775
Vinh =  1.025
C_comp   1.851324p   1.667199p   1.973575p
[Model Spec]
Vinl   0.775   0.73   0.82
Vinh   1.025   0.98   1.07
[Temperature Range]   25   125   -40
[Voltage Range]   1.8   1.71   1.89
[POWER_clamp]
-1.8V     201.9mA    142.5mA    271.3mA
-1.255V   84.2mA     61.88mA    110.6mA
-1.145V   63.66mA    47.68mA    83.45mA
-1.091V   54.4mA     41.21mA    70.83mA
-1.036V   46.08mA    35.4mA     59.14mA
-981.8mV  38.95mA    30.48mA    48.83mA
-872.7mV  29.56mA    23.82mA    35.52mA
-600mV    18.66mA    16.53mA    20.79mA
-436.4mV  14.63mA    14.14mA    15.22mA
872.7mV   1.009mA    0A         1.574mA
1.036V    0A         0A         0A
3.6V      0A         0A         0A
[GND_clamp]
-1.8V     -358.4mA   -220.8mA   -580.4mA
-1.309V   -159.1mA   -100.3mA   -255.1mA
-1.145V   -99.68mA   -65.3mA    -154.6mA
-1.036V   -66.84mA   -46.8mA    -97.47mA
-981.8mV  -54.23mA   -39.89mA   -75.01mA
-927.3mV  -44.27mA   -34.47mA   -56.93mA
-872.7mV  -36.57mA   -30.21mA   -43.43mA
-818.2mV  -30.84mA   -26.79mA   -35.17mA
-709.1mV  -24.73mA   -22.14mA   -28.32mA
-490.9mV  -17.67mA   -17.13mA   -18.71mA
872.7mV   0A         0A         -234uA
3.6V      0A         0A         0A
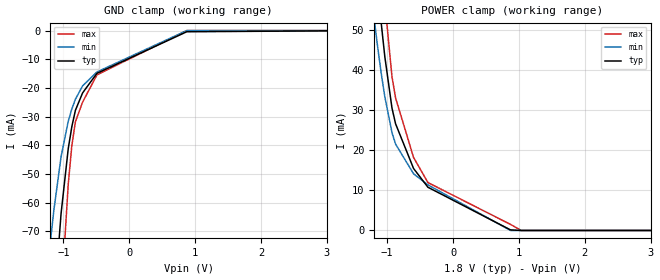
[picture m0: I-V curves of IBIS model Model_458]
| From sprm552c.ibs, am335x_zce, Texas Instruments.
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| Model based on original model for BCSHTLTCSCDVPBFZ_SSDHV
|   Sub model VREF_HALFTERM_8MA_5PER_1P8
[model]   Model_458
|[Description]  [1.8V-INPUT-HALFTERM:8MA-X, IND, 5%]
|   Half Thevenin termination (Rth = 100R whith RExt = 50R)
|   (ODT[1:0] = "11") VRef mode, 1.00 * RExt = 1.000 * Iout (I[2:0]
|   = "011"), 8mA nominal with Rext = 50R,Industrial temperature
|   range (-40C to 125C, 25C nominal),5% power supply tolerance
|[Input Load]   HALFTERM:8MA
|[Output Drive]
|Voltage   1.8V
|Mode   INPUT
Model_type   Input
Polarity   Non-Inverting
Vinl =  0.775
Vinh =  1.025
C_comp   1.851324p   1.667199p   1.973575p
[Model Spec]
Vinl   0.775   0.73   0.82
Vinh   1.025   0.98   1.07
[Temperature Range]   25   125   -40
[Voltage Range]   1.8   1.71   1.89
[POWER_clamp]
-1.8V     200.5mA    141.6mA    269.8mA
-1.255V   81.7mA     60.08mA    108.3mA
-1.145V   60.96mA    45.71mA    81.05mA
-1.091V   51.63mA    39.16mA    68.41mA
-1.036V   43.24mA    33.27mA    56.69mA
-927.3mV  30.46mA    24.36mA    38.27mA
-872.7mV  26.55mA    21.5mA     32.99mA
-600mV    15.44mA    14.11mA    18.19mA
-381.8mV  10.76mA    11.35mA    11.93mA
872.7mV   142.7uA    0A         1.505mA
1.036V    0A         0A         0A
3.6V      0A         0A         0A
[GND_clamp]
-1.8V     -356.1mA   -218.9mA   -578.1mA
-1.309V   -156.2mA   -97.71mA   -252.2mA
-1.255V   -135.6mA   -85.38mA   -217.7mA
-1.145V   -96.65mA   -62.54mA   -151.5mA
-1.036V   -63.77mA   -43.97mA   -94.2mA
-927.3mV  -41.19mA   -31.6mA    -53.6mA
-872.7mV  -33.5mA    -27.33mA   -40.07mA
-818.2mV  -27.78mA   -23.91mA   -31.78mA
-709.1mV  -21.72mA   -19.27mA   -24.94mA
-490.9mV  -14.89mA   -14.41mA   -15.44mA
872.7mV   -407.3uA   0A         0A
3.6V      0A         0A         0A
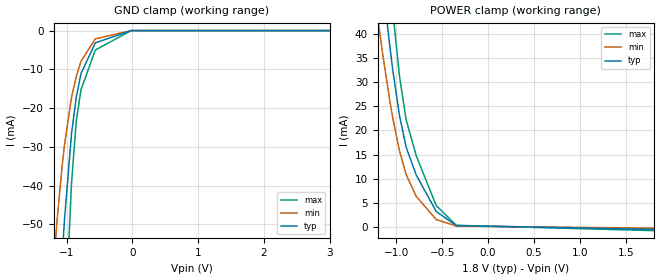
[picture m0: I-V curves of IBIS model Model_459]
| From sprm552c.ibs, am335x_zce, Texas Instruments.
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| Model based on original model for BCSHTLTCSCDVPBFZ_SSDHV
|   Sub model LVCMOS_PU_ON_5PER_1P8
[model]   Model_459
|[Description]  [1.8V-INPUT-PU-X, IND, 5%]
|   Weak internal pull-up,Industrial temperature range (-40C to
|   125C, 25C nominal),5% power supply tolerance
|[Input Load]   PU
|[Output Drive]
|Voltage   1.8V
|Mode   INPUT
Model_type   Input
Polarity   Non-Inverting
Vinl =  0.63
Vinh =  1.17
C_comp   1.851324p   1.667199p   1.973575p
[Model Spec]
Vinl   0.63   0.5985   0.6615
Vinh   1.17   1.1115   1.2285
[Temperature Range]   25   125   -40
[Voltage Range]   1.8   1.71   1.89
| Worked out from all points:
|   GND clamp passes 1 mA (typ) near -0.42 V on its own axis
|   POWER clamp passes 1 mA (typ) near -0.46 V on its own axis
[POWER_clamp]
-1.8V     194.9mA    137mA      262.9mA
-1.255V   72.18mA    51.1mA     97.46mA
-1.218V   64.85mA    45.9mA     88.02mA
-1.145V   50.79mA    35.85mA    69.73mA
-1.073V   38.32mA    26.79mA    52.81mA
-1.036V   32.56mA    22.6mA     44.8mA
-963.6mV  23.17mA    15.79mA    31.41mA
-890.9mV  16.54mA    10.85mA    22.23mA
-781.8mV  10.75mA    6.306mA    14.79mA
-563.6mV  3.137mA    1.452mA    4.363mA
-345.5mV  202.2uA    106.9uA    256.3uA
1.8V      -592.4uA   -346.2uA   -847.7uA
[GND_clamp]
-1.8V     -346.1mA   -209.3mA   -568.4mA
-1.327V   -149.9mA   -89.09mA   -251.1mA
-1.291V   -135.8mA   -80.53mA   -227.8mA
-1.145V   -82.58mA   -48.77mA   -138mA
-1.073V   -59.73mA   -35.68mA   -98.35mA
-1.036V   -49.42mA   -29.86mA   -80.34mA
-927.3mV  -26.77mA   -17.32mA   -39.69mA
-854.5mV  -17.22mA   -11.91mA   -23.38mA
-781.8mV  -11.05mA   -7.899mA   -15.25mA
-563.6mV  -3.181mA   -2.141mA   -5.002mA
-18.18mV  0A         0A         0A
3.6V      0A         0A         0A
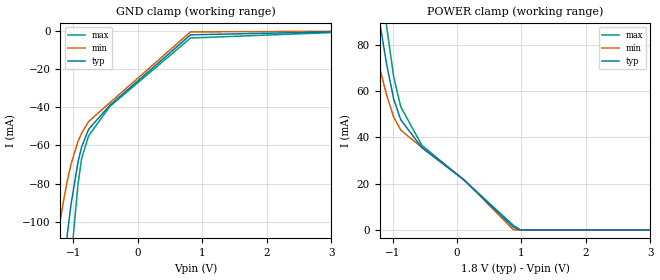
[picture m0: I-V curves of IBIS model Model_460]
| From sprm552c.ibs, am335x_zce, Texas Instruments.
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| Model based on original model for BCSHTLTCSCDVPBFZ_SSDHV
|   Sub model VREF_FULLTERM_12MA_5PER_1P8
[model]   Model_460
|[Description]  [1.8V-INPUT-FULLTERM:12MA-X, IND, 5%]
|   FULLTERM, 0.67 * RExt = 1.500 * Iout (I[2:0] = "111"), 12mA
|   nominal with Rext = 50R,Industrial temperature range (-40C to
|   125C, 25C nominal),5% power supply tolerance
|[Input Load]   FULLTERM:12MA
|[Output Drive]
|Voltage   1.8V
|Mode   INPUT
Model_type   Input
Polarity   Non-Inverting
Vinl =  0.775
Vinh =  1.025
C_comp   1.851324p   1.667199p   1.973575p
[Model Spec]
Vinl   0.775   0.73   0.82
Vinh   1.025   0.98   1.07
[Temperature Range]   25   125   -40
[Voltage Range]   1.8   1.71   1.89
[POWER_clamp]
-1.8V     211.2mA    150.1mA    282.2mA
-1.364V   120.9mA    90.57mA    155.7mA
-1.309V   110.4mA    83.61mA    141.1mA
-1.2V     90.04mA    70.29mA    113.4mA
-1.091V   71.57mA    58.29mA    87.84mA
-981.8mV  56.6mA     48.82mA    66.15mA
-872.7mV  47.66mA    43.18mA    53.27mA
-545.5mV  35.62mA    35.7mA     36.61mA
109.1mV   21.58mA    21.75mA    21.62mA
872.7mV   1.245mA    133.8uA    2.055mA
981.8mV   0A         0A         0A
3.6V      0A         0A         0A
[GND_clamp]
-1.8V     -375.1mA   -236.4mA   -596.3mA
-1.364V   -202.1mA   -133.7mA   -310.6mA
-1.2V     -141.8mA   -98.42mA   -208.9mA
-1.145V   -123.2mA   -87.79mA   -176.8mA
-1.091V   -105.9mA   -78.14mA   -146.9mA
-1.036V   -90.85mA   -69.85mA   -120.4mA
-927.3mV  -68.55mA   -57.83mA   -80.24mA
-872.7mV  -60.9mA    -53.62mA   -66.92mA
-763.6mV  -51.51mA   -47.48mA   -54.99mA
-436.4mV  -39mA      -37.64mA   -39.58mA
818.2mV   -1.962mA   -438.8uA   -3.634mA
3.6V      0A         0A         0A
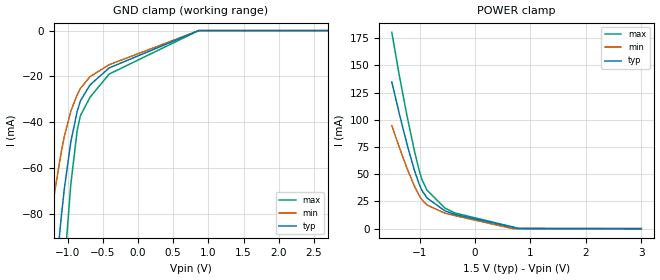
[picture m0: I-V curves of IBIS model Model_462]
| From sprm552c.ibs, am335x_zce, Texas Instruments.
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| Model based on original model for BCSHTLTCSCDVPBFZ_SSDHV
|   Sub model VREF_FULLTERM_6MA_10PER_1P5
[model]   Model_462
|[Description]  [1.5V-INPUT-FULLTERM:6MA-X, IND, 10%]
|   FULLTERM, 1.33 * RExt = 0.750 * Iout (I[2:0] = "001"), 6mA
|   nominal with Rext = 50R,Industrial temperature range (-40C to
|   125C, 25C nominal),10% power supply tolerance
|[Input Load]   FULLTERM:6MA
|[Output Drive]
|Voltage   1.5V
|Mode   INPUT
Model_type   Input
Polarity   Non-Inverting
Vinl =  0.65
Vinh =  0.85
C_comp   1.865048p   1.676829p   1.989968p
[Model Spec]
Vinl   0.65   0.575   0.725
Vinh   0.85   0.775   0.925
[Temperature Range]   25   125   -40
[Voltage Range]   1.5   1.35   1.65
[POWER_clamp]
-1.5V     134.8mA    94.74mA    180.4mA
-1.364V   105.5mA    74.59mA    140.6mA
-1.227V   77.79mA    55.64mA    104mA
-1.091V   53.36mA    38.91mA    71.2mA
-1V       40.12mA    29.93mA    52.39mA
-954.5mV  34.93mA    26.45mA    44.79mA
-863.6mV  28.12mA    21.7mA     35.27mA
-545.5mV  16.49mA    14.28mA    19.01mA
-363.6mV  13.08mA    12mA       14.43mA
681.8mV   1.368mA    0A         1.581mA
772.7mV   70.25uA    0A         225.6uA
3V        0A         0A         0A
[GND_clamp]
-1.5V     -232.9mA   -142.2mA   -379.5mA
-1.364V   -179mA     -109.9mA   -290.9mA
-1.182V   -111.5mA   -70.13mA   -177.4mA
-1.091V   -81.68mA   -53.22mA   -125.9mA
-1.045V   -68.81mA   -46.12mA   -103.3mA
-954.5mV  -48.67mA   -35.25mA   -67.21mA
-863.6mV  -35.33mA   -28.03mA   -43.6mA
-818.2mV  -30.76mA   -25.33mA   -37.2mA
-681.8mV  -23.77mA   -20.16mA   -29.17mA
-409.1mV  -16.31mA   -14.92mA   -19.01mA
863.6mV   0A         0A         0A
3V        0A         0A         0A
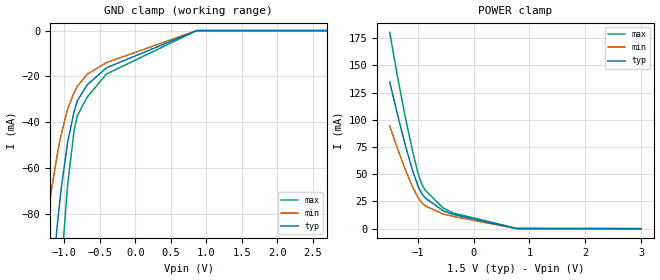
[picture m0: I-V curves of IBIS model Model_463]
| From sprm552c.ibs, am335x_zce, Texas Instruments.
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| Model based on original model for BCSHTLTCSCDVPBFZ_SSDHV
|   Sub model VREF_HALFTERM_12MA_10PER_1P5
[model]   Model_463
|[Description]  [1.5V-INPUT-HALFTERM:12MA-X, IND, 10%]
|   Half Thevenin termination (Rth = 100R whith RExt = 50R)
|   (ODT[1:0] = "11") VRef mode, 0.67 * RExt = 1.500 * Iout (I[2:0]
|   = "111"), 12mA nominal with Rext = 50R,Industrial temperature
|   range (-40C to 125C, 25C nominal),10% power supply tolerance
|[Input Load]   HALFTERM:12MA
|[Output Drive]
|Voltage   1.5V
|Mode   INPUT
Model_type   Input
Polarity   Non-Inverting
Vinl =  0.65
Vinh =  0.85
C_comp   1.865048p   1.676829p   1.989968p
[Model Spec]
Vinl   0.65   0.575   0.725
Vinh   0.85   0.775   0.925
[Temperature Range]   25   125   -40
[Voltage Range]   1.5   1.35   1.65
[POWER_clamp]
-1.5V     134.8mA    94.37mA    180.4mA
-1.364V   105.5mA    74.15mA    140.6mA
-1.227V   77.79mA    55.12mA    104mA
-1.091V   53.36mA    38.28mA    71.2mA
-1V       40.12mA    29.25mA    52.39mA
-954.5mV  34.93mA    25.73mA    44.79mA
-909.1mV  30.96mA    22.99mA    39.09mA
-863.6mV  28.12mA    20.93mA    35.27mA
-545.5mV  16.49mA    13.45mA    19.01mA
-363.6mV  13.08mA    11.25mA    14.43mA
772.7mV   70.25uA    0A         225.6uA
3V        0A         0A         0A
[GND_clamp]
-1.5V     -232.9mA   -141.6mA   -379.5mA
-1.364V   -179mA     -109.1mA   -290.9mA
-1.182V   -111.5mA   -69.26mA   -177.4mA
-1.091V   -81.68mA   -52.31mA   -125.9mA
-1.045V   -68.81mA   -45.19mA   -103.3mA
-954.5mV  -48.67mA   -34.28mA   -67.21mA
-863.6mV  -35.33mA   -27.05mA   -43.6mA
-818.2mV  -30.76mA   -24.34mA   -37.2mA
-681.8mV  -23.77mA   -19.17mA   -29.17mA
-409.1mV  -16.31mA   -14.01mA   -19.01mA
863.6mV   0A         0A         0A
3V        0A         0A         0A
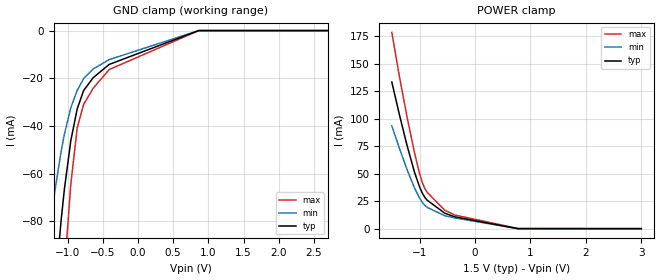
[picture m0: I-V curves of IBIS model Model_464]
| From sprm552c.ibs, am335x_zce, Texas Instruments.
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| Model based on original model for BCSHTLTCSCDVPBFZ_SSDHV
|   Sub model VREF_FULLTERM_5MA_10PER_1P5
[model]   Model_464
|[Description]  [1.5V-INPUT-FULLTERM:5MA-X, IND, 10%]
|   FULLTERM, 1.60 * RExt = 0.625 * Iout (I[2:0] = "000"), 5mA
|   nominal with Rext = 50R,Industrial temperature range (-40C to
|   125C, 25C nominal),10% power supply tolerance
|[Input Load]   FULLTERM:5MA
|[Output Drive]
|Voltage   1.5V
|Mode   INPUT
Model_type   Input
Polarity   Non-Inverting
Vinl =  0.65
Vinh =  0.85
C_comp   1.865048p   1.676829p   1.989968p
[Model Spec]
Vinl   0.65   0.575   0.725
Vinh   0.85   0.775   0.925
[Temperature Range]   25   125   -40
[Voltage Range]   1.5   1.35   1.65
[POWER_clamp]
-1.5V     133.5mA    93.62mA    178.7mA
-1.364V   104mA      73.27mA    138.8mA
-1.227V   76.08mA    54.07mA    102.1mA
-1.091V   51.44mA    37.04mA    69.18mA
-1V       38.11mA    27.87mA    50.34mA
-954.5mV  32.86mA    24.3mA     42.71mA
-909.1mV  28.84mA    21.5mA     36.99mA
-863.6mV  25.96mA    19.4mA     33.14mA
-545.5mV  14.1mA     11.81mA    16.82mA
-363.6mV  10.76mA    9.759mA    12.39mA
772.7mV   0A         0A         193.4uA
3V        0A         0A         0A
[GND_clamp]
-1.5V     -230.9mA   -140.2mA   -377.4mA
-1.364V   -176.8mA   -107.6mA   -288.6mA
-1.182V   -109.1mA   -67.51mA   -174.9mA
-1.091V   -79.24mA   -50.47mA   -123.2mA
-1.045V   -66.34mA   -43.32mA   -100.6mA
-954.5mV  -46.19mA   -32.36mA   -64.46mA
-863.6mV  -32.85mA   -25.08mA   -40.81mA
-772.7mV  -25.16mA   -20.16mA   -31.01mA
-636.4mV  -19.75mA   -16.09mA   -24.17mA
-409.1mV  -14.19mA   -12.17mA   -16.34mA
863.6mV   0A         0A         0A
3V        0A         0A         0A
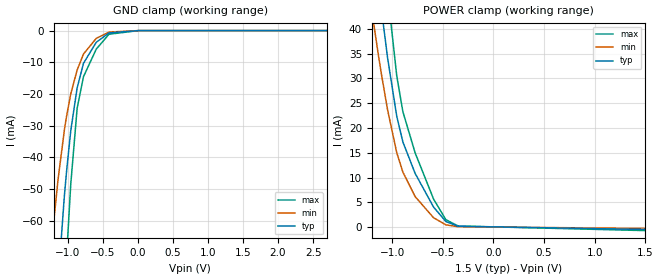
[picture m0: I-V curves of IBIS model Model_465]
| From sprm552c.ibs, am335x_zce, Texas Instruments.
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| Model based on original model for BCSHTLTCSCDVPBFZ_SSDHV
|   Sub model VREF_NOTERM_PU_ON_10PER_1P5
[model]   Model_465
|[Description]  [1.5V-INPUT-PU-X, IND, 10%]
|   Weak internal pull-up,Industrial temperature range (-40C to
|   125C, 25C nominal),10% power supply tolerance
|[Input Load]   PU
|[Output Drive]
|Voltage   1.5V
|Mode   INPUT
Model_type   Input
Polarity   Non-Inverting
Vinl =  0.65
Vinh =  0.85
C_comp   1.865048p   1.676829p   1.989968p
[Model Spec]
Vinl   0.65   0.575   0.725
Vinh   0.85   0.775   0.925
[Temperature Range]   25   125   -40
[Voltage Range]   1.5   1.35   1.65
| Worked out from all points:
|   GND clamp passes 1 mA (typ) near -0.44 V on its own axis
|   POWER clamp passes 1 mA (typ) near -0.46 V on its own axis
[POWER_clamp]
-1.5V     126mA      88.8mA     168.8mA
-1.227V   66.74mA    47.26mA    90.54mA
-1.136V   49.27mA    34.75mA    67.9mA
-1.106V   44mA       30.9mA     60.84mA
-1.045V   34.16mA    23.68mA    47.36mA
-954.5mV  22.38mA    15.04mA    30.52mA
-893.9mV  17.2mA     11.11mA    23.29mA
-772.7mV  10.84mA    6.169mA    14.98mA
-590.9mV  4.062mA    1.916mA    5.677mA
-469.7mV  1.154mA    489.1uA    1.525mA
-348.5mV  202uA      105.4uA    255.5uA
1.5V      -448.2uA   -239.5uA   -673.6uA
[GND_clamp]
-1.5V     -219.5mA   -131.6mA   -364.7mA
-1.288V   -134.7mA   -79.84mA   -226mA
-1.136V   -79.69mA   -47.05mA   -133mA
-1.045V   -52mA      -31.27mA   -84.86mA
-1.015V   -44.56mA   -27.12mA   -71.72mA
-954.5mV  -31.59mA   -19.96mA   -48.47mA
-863.6mV  -18.1mA    -12.45mA   -24.55mA
-772.7mV  -10.31mA   -7.385mA   -14.52mA
-590.9mV  -3.692mA   -2.456mA   -5.848mA
-409.1mV  -736uA     -473.5uA   -1.149mA
15.15mV   0A         0A         0A
3V        0A         0A         0A
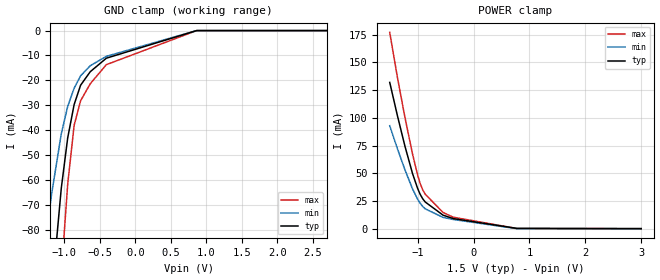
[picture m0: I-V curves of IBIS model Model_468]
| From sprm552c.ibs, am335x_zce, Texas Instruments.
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| Model based on original model for BCSHTLTCSCDVPBFZ_SSDHV
|   Sub model VREF_HALFTERM_8MA_10PER_1P5
[model]   Model_468
|[Description]  [1.5V-INPUT-HALFTERM:8MA-X, IND, 10%]
|   Half Thevenin termination (Rth = 100R whith RExt = 50R)
|   (ODT[1:0] = "11") VRef mode, 1.00 * RExt = 1.000 * Iout (I[2:0]
|   = "011"), 8mA nominal with Rext = 50R,Industrial temperature
|   range (-40C to 125C, 25C nominal),10% power supply tolerance
|[Input Load]   HALFTERM:8MA
|[Output Drive]
|Voltage   1.5V
|Mode   INPUT
Model_type   Input
Polarity   Non-Inverting
Vinl =  0.65
Vinh =  0.85
C_comp   1.865048p   1.676829p   1.989968p
[Model Spec]
Vinl   0.65   0.575   0.725
Vinh   0.85   0.775   0.925
[Temperature Range]   25   125   -40
[Voltage Range]   1.5   1.35   1.65
[POWER_clamp]
-1.5V     132mA      92.88mA    177.1mA
-1.364V   102.3mA    72.38mA    137mA
-1.227V   74.28mA    53.02mA    100.2mA
-1.091V   49.55mA    35.79mA    67.17mA
-1V       36.19mA    26.5mA     48.29mA
-954.5mV  30.93mA    22.87mA    40.63mA
-909.1mV  26.9mA     20.02mA    34.88mA
-863.6mV  24.01mA    17.87mA    31.01mA
-545.5mV  12.19mA    10.17mA    14.62mA
-363.6mV  9.088mA    8.266mA    10.34mA
772.7mV   253.7uA    0A         161.2uA
3V        0A         0A         0A
[GND_clamp]
-1.5V     -228.6mA   -138.9mA   -375.2mA
-1.364V   -174.3mA   -106.1mA   -286.3mA
-1.318V   -156.7mA   -95.54mA   -257.1mA
-1.182V   -106.3mA   -65.76mA   -172.3mA
-1.045V   -63.33mA   -41.45mA   -97.9mA
-954.5mV  -43.09mA   -30.43mA   -61.71mA
-863.6mV  -29.69mA   -23.12mA   -38.01mA
-772.7mV  -21.94mA   -18.17mA   -28.17mA
-636.4mV  -16.5mA    -14.1mA    -21.34mA
-409.1mV  -11.08mA   -10.33mA   -13.68mA
863.6mV   0A         0A         0A
3V        0A         0A         0A
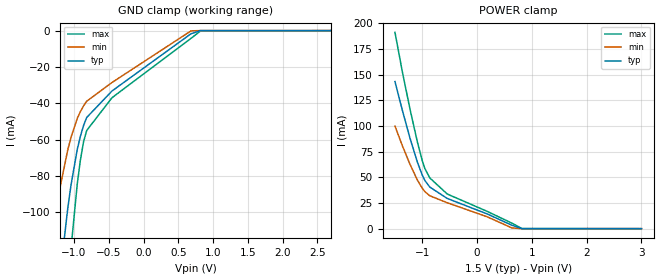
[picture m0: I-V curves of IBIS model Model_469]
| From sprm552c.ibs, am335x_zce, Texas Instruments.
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| Model based on original model for BCSHTLTCSCDVPBFZ_SSDHV
|   Sub model VREF_FULLTERM_12MA_10PER_1P5
[model]   Model_469
|[Description]  [1.5V-INPUT-FULLTERM:12MA-X, IND, 10%]
|   FULLTERM, 0.67 * RExt = 1.500 * Iout (I[2:0] = "111"), 12mA
|   nominal with Rext = 50R,Industrial temperature range (-40C to
|   125C, 25C nominal),10% power supply tolerance
|[Input Load]   FULLTERM:12MA
|[Output Drive]
|Voltage   1.5V
|Mode   INPUT
Model_type   Input
Polarity   Non-Inverting
Vinl =  0.65
Vinh =  0.85
C_comp   1.865048p   1.676829p   1.989968p
[Model Spec]
Vinl   0.65   0.575   0.725
Vinh   0.85   0.775   0.925
[Temperature Range]   25   125   -40
[Voltage Range]   1.5   1.35   1.65
[POWER_clamp]
-1.5V     143.2mA    99.85mA    191.1mA
-1.364V   115mA      80.63mA    152.4mA
-1.227V   88.35mA    62.78mA    116.7mA
-1.091V   64.8mA     47.34mA    84.41mA
-1V       51.94mA    39.21mA    65.91mA
-954.5mV  46.92mA    36.12mA    58.49mA
-863.6mV  40.47mA    32.01mA    49.36mA
-545.5mV  29.4mA     25.22mA    33.72mA
181.8mV   14.38mA    11.59mA    16.89mA
636.4mV   3.293mA    665.9uA    5.314mA
818.2mV   0A         0A         123.3uA
3V        0A         0A         0A
[GND_clamp]
-1.5V     -245.8mA   -151.2mA   -393.2mA
-1.227V   -143.1mA   -91.03mA   -220.9mA
-1.091V   -97.87mA   -65.69mA   -142.6mA
-1.045V   -85.23mA   -58.84mA   -120.3mA
-954.5mV  -65.42mA   -48.37mA   -84.53mA
-909.1mV  -58.13mA   -44.56mA   -71.23mA
-863.6mV  -52.27mA   -41.43mA   -61.19mA
-818.2mV  -47.78mA   -38.83mA   -54.94mA
-454.5mV  -33.22mA   -28.55mA   -36.93mA
681.8mV   -1.76mA    -171.2uA   -4.277mA
818.2mV   0A         0A         -273.2uA
3V        0A         0A         0A
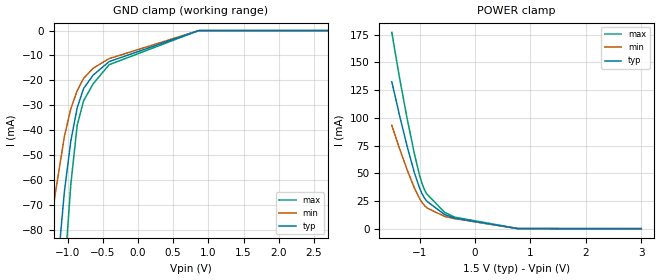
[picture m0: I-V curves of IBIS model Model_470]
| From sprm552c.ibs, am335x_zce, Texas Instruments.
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| Model based on original model for BCSHTLTCSCDVPBFZ_SSDHV
|   Sub model VREF_HALFTERM_9MA_10PER_1P5
[model]   Model_470
|[Description]  [1.5V-INPUT-HALFTERM:9MA-X, IND, 10%]
|   Half Thevenin termination (Rth = 100R whith RExt = 50R)
|   (ODT[1:0] = "11") VRef mode, 0.88 * RExt = 1.125 * Iout (I[2:0]
|   = "100"), 9mA nominal with Rext = 50R,Industrial temperature
|   range (-40C to 125C, 25C nominal),10% power supply tolerance
|[Input Load]   HALFTERM:9MA
|[Output Drive]
|Voltage   1.5V
|Mode   INPUT
Model_type   Input
Polarity   Non-Inverting
Vinl =  0.65
Vinh =  0.85
C_comp   1.865048p   1.676829p   1.989968p
[Model Spec]
Vinl   0.65   0.575   0.725
Vinh   0.85   0.775   0.925
[Temperature Range]   25   125   -40
[Voltage Range]   1.5   1.35   1.65
[POWER_clamp]
-1.5V     132.5mA    93.25mA    177.1mA
-1.364V   102.9mA    72.82mA    137mA
-1.227V   74.91mA    53.54mA    100.2mA
-1.091V   50.18mA    36.42mA    67.17mA
-1V       36.8mA     27.19mA    48.29mA
-954.5mV  31.53mA    23.58mA    40.63mA
-909.1mV  27.49mA    20.76mA    34.88mA
-863.6mV  24.58mA    18.63mA    31.01mA
-545.5mV  12.66mA    10.99mA    14.62mA
-363.6mV  9.428mA    9.013mA    10.34mA
772.7mV   0A         0A         161.2uA
3V        0A         0A         0A
[GND_clamp]
-1.5V     -229.4mA   -139.6mA   -375.2mA
-1.364V   -175.2mA   -106.9mA   -286.3mA
-1.318V   -157.7mA   -96.33mA   -257.1mA
-1.182V   -107.4mA   -66.64mA   -172.3mA
-1.045V   -64.52mA   -42.38mA   -97.9mA
-954.5mV  -44.33mA   -31.39mA   -61.71mA
-863.6mV  -30.97mA   -24.1mA    -38.01mA
-772.7mV  -23.26mA   -19.16mA   -28.17mA
-636.4mV  -17.86mA   -15.1mA    -21.34mA
-409.1mV  -12.44mA   -11.25mA   -13.68mA
863.6mV   0A         0A         0A
3V        0A         0A         0A
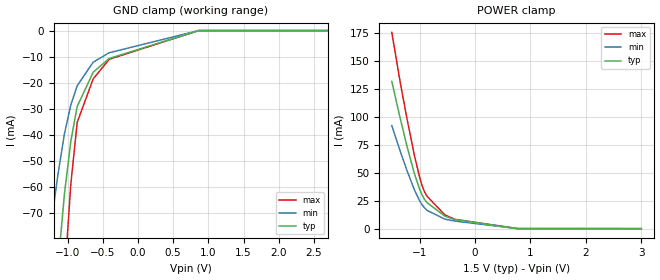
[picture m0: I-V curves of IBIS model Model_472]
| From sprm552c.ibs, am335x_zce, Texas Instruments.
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| Model based on original model for BCSHTLTCSCDVPBFZ_SSDHV
|   Sub model VREF_HALFTERM_7MA_10PER_1P5
[model]   Model_472
|[Description]  [1.5V-INPUT-HALFTERM:7MA-X, IND, 10%]
|   Half Thevenin termination (Rth = 100R whith RExt = 50R)
|   (ODT[1:0] = "11") VRef mode, 1.14 * RExt = 0.875 * Iout (I[2:0]
|   = "010"), 7mA nominal with Rext = 50R,Industrial temperature
|   range (-40C to 125C, 25C nominal),10% power supply tolerance
|[Input Load]   HALFTERM:7MA
|[Output Drive]
|Voltage   1.5V
|Mode   INPUT
Model_type   Input
Polarity   Non-Inverting
Vinl =  0.65
Vinh =  0.85
C_comp   1.865048p   1.676829p   1.989968p
[Model Spec]
Vinl   0.65   0.575   0.725
Vinh   0.85   0.775   0.925
[Temperature Range]   25   125   -40
[Voltage Range]   1.5   1.35   1.65
[POWER_clamp]
-1.5V     131.6mA    92.14mA    175.4mA
-1.364V   101.9mA    71.5mA     135.1mA
-1.227V   73.73mA    51.97mA    98.22mA
-1.091V   48.91mA    34.55mA    65.15mA
-1V       35.48mA    25.13mA    46.23mA
-954.5mV  30.2mA     21.43mA    38.56mA
-909.1mV  26.14mA    18.53mA    32.78mA
-863.6mV  23.21mA    16.33mA    28.88mA
-545.5mV  11.23mA    8.534mA    12.42mA
-363.6mV  8.097mA    6.773mA    8.297mA
772.7mV   0A         0A         129uA
3V        0A         0A         0A
[GND_clamp]
-1.5V     -228mA     -137.6mA   -373.1mA
-1.364V   -173.6mA   -104.6mA   -284mA
-1.318V   -156mA     -93.96mA   -254.7mA
-1.182V   -105.7mA   -64.02mA   -169.8mA
-1.136V   -90.11mA   -55.02mA   -143.1mA
-1.045V   -62.7mA    -39.58mA   -95.21mA
-954.5mV  -42.47mA   -28.5mA    -58.96mA
-863.6mV  -29.09mA   -21.15mA   -35.21mA
-636.4mV  -15.97mA   -12.11mA   -18.51mA
-409.1mV  -10.7mA    -8.496mA   -11.01mA
863.6mV   0A         0A         0A
3V        0A         0A         0A
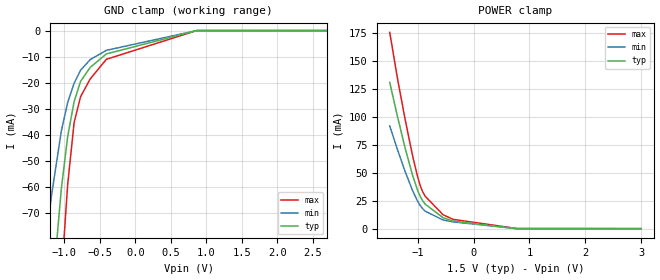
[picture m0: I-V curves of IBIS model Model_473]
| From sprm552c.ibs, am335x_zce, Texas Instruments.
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| Model based on original model for BCSHTLTCSCDVPBFZ_SSDHV
|   Sub model VREF_HALFTERM_6MA_10PER_1P5
[model]   Model_473
|[Description]  [1.5V-INPUT-HALFTERM:6MA-X, IND, 10%]
|   Half Thevenin termination (Rth = 100R whith RExt = 50R)
|   (ODT[1:0] = "11") VRef mode, 1.33 * RExt = 0.750 * Iout (I[2:0]
|   = "001"), 6mA nominal with Rext = 50R,Industrial temperature
|   range (-40C to 125C, 25C nominal),10% power supply tolerance
|[Input Load]   HALFTERM:6MA
|[Output Drive]
|Voltage   1.5V
|Mode   INPUT
Model_type   Input
Polarity   Non-Inverting
Vinl =  0.65
Vinh =  0.85
C_comp   1.865048p   1.676829p   1.989968p
[Model Spec]
Vinl   0.65   0.575   0.725
Vinh   0.85   0.775   0.925
[Temperature Range]   25   125   -40
[Voltage Range]   1.5   1.35   1.65
[POWER_clamp]
-1.5V     130.7mA    91.76mA    175.4mA
-1.364V   100.8mA    71.06mA    135.1mA
-1.227V   72.56mA    51.44mA    98.22mA
-1.091V   47.64mA    33.93mA    65.15mA
-1V       34.17mA    24.44mA    46.23mA
-954.5mV  28.86mA    20.72mA    38.56mA
-909.1mV  24.79mA    17.79mA    32.78mA
-863.6mV  21.84mA    15.57mA    28.88mA
-545.5mV  9.796mA    7.714mA    12.42mA
-363.6mV  6.767mA    6.026mA    8.297mA
772.7mV   0A         0A         129uA
3V        0A         0A         0A
[GND_clamp]
-1.5V     -226.6mA   -136.9mA   -373.1mA
-1.364V   -172.1mA   -103.8mA   -284mA
-1.318V   -154.4mA   -93.17mA   -254.7mA
-1.182V   -103.9mA   -63.15mA   -169.8mA
-1.045V   -60.87mA   -38.64mA   -95.21mA
-954.5mV  -40.6mA    -27.54mA   -58.96mA
-863.6mV  -27.2mA    -20.17mA   -35.21mA
-772.7mV  -19.46mA   -15.19mA   -25.34mA
-636.4mV  -14.09mA   -11.12mA   -18.51mA
-409.1mV  -8.955mA   -7.577mA   -11.01mA
863.6mV   0A         0A         0A
3V        0A         0A         0A
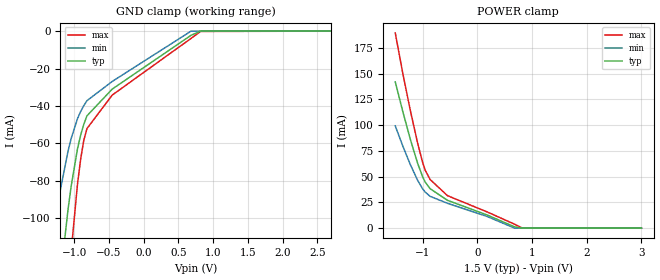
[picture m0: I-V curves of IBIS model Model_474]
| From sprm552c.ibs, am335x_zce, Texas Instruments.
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| Model based on original model for BCSHTLTCSCDVPBFZ_SSDHV
|   Sub model VREF_FULLTERM_11MA_10PER_1P5
[model]   Model_474
|[Description]  [1.5V-INPUT-FULLTERM:11MA-X, IND, 10%]
|   FULLTERM, 0.73 * RExt = 1.325 * Iout (I[2:0] = "110"), 11mA
|   nominal with Rext = 50R,Industrial temperature range (-40C to
|   125C, 25C nominal),10% power supply tolerance
|[Input Load]   FULLTERM:11MA
|[Output Drive]
|Voltage   1.5V
|Mode   INPUT
Model_type   Input
Polarity   Non-Inverting
Vinl =  0.65
Vinh =  0.85
C_comp   1.865048p   1.676829p   1.989968p
[Model Spec]
Vinl   0.65   0.575   0.725
Vinh   0.85   0.775   0.925
[Temperature Range]   25   125   -40
[Voltage Range]   1.5   1.35   1.65
[POWER_clamp]
-1.5V     141.9mA    99.21mA    189.4mA
-1.364V   113.5mA    79.9mA     150.6mA
-1.227V   86.63mA    61.95mA    114.8mA
-1.091V   62.88mA    46.38mA    82.39mA
-1V       49.92mA    38.19mA    63.85mA
-954.5mV  44.85mA    35.06mA    56.41mA
-863.6mV  38.3mA     30.91mA    47.23mA
-545.5mV  27mA       24.11mA    31.52mA
181.8mV   12.72mA    11.29mA    15.7mA
681.8mV   1.292mA    0A         3.811mA
818.2mV   0A         0A         188.9uA
3V        0A         0A         0A
[GND_clamp]
-1.5V     -243.8mA   -150.2mA   -391mA
-1.227V   -140.7mA   -89.7mA    -218.3mA
-1.091V   -95.43mA   -64.23mA   -140mA
-1.045V   -82.76mA   -57.34mA   -117.6mA
-954.5mV  -62.93mA   -46.81mA   -81.78mA
-909.1mV  -55.64mA   -42.98mA   -68.46mA
-863.6mV  -49.79mA   -39.83mA   -58.39mA
-818.2mV  -45.29mA   -37.2mA    -52.11mA
-454.5mV  -31.01mA   -26.92mA   -34.21mA
681.8mV   -2.217mA   0A         -3.885mA
818.2mV   0A         0A         -178.2uA
3V        0A         0A         0A
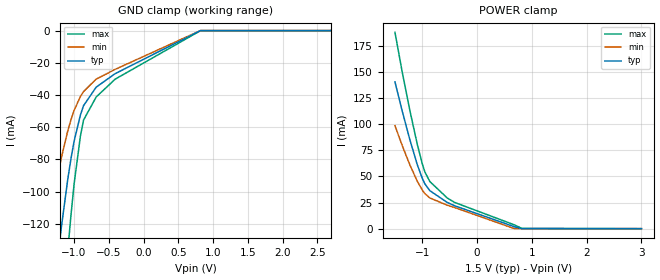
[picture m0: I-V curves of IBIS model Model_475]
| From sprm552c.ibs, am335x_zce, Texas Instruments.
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| Model based on original model for BCSHTLTCSCDVPBFZ_SSDHV
|   Sub model VREF_FULLTERM_10MA_10PER_1P5
[model]   Model_475
|[Description]  [1.5V-INPUT-FULLTERM:10MA-X, IND, 10%]
|   FULLTERM, 0.80 * RExt = 1.250 * Iout (I[2:0] = "101"), 10mA
|   nominal with Rext = 50R,Industrial temperature range (-40C to
|   125C, 25C nominal),10% power supply tolerance
|[Input Load]   FULLTERM:10MA
|[Output Drive]
|Voltage   1.5V
|Mode   INPUT
Model_type   Input
Polarity   Non-Inverting
Vinl =  0.65
Vinh =  0.85
C_comp   1.865048p   1.676829p   1.989968p
[Model Spec]
Vinl   0.65   0.575   0.725
Vinh   0.85   0.775   0.925
[Temperature Range]   25   125   -40
[Voltage Range]   1.5   1.35   1.65
[POWER_clamp]
-1.5V     140.4mA    98.46mA    187.8mA
-1.364V   111.8mA    79.01mA    148.8mA
-1.227V   84.83mA    60.89mA    112.8mA
-1.091V   60.98mA    45.14mA    80.37mA
-1V       48mA       36.81mA    61.8mA
-954.5mV  42.92mA    33.62mA    54.33mA
-863.6mV  36.35mA    29.37mA    45.09mA
-545.5mV  25.1mA     22.47mA    29.33mA
-409.1mV  21.86mA    20.18mA    25.06mA
681.8mV   1.822mA    0A         3.586mA
818.2mV   0A         0A         254.6uA
3V        0A         0A         0A
[GND_clamp]
-1.5V     -241.5mA   -148.9mA   -388.9mA
-1.409V   -206mA     -127.8mA   -330.1mA
-1.182V   -122mA     -78.87mA   -188.5mA
-1.091V   -92.47mA   -62.4mA    -137.3mA
-1.045V   -79.75mA   -55.47mA   -114.9mA
-1V       -68.87mA   -49.64mA   -95.49mA
-909.1mV  -52.51mA   -41.03mA   -65.69mA
-863.6mV  -46.63mA   -37.86mA   -55.59mA
-681.8mV  -35.14mA   -30.14mA   -41.25mA
-409.1mV  -26.76mA   -24.1mA    -30.18mA
818.2mV   0A         0A         -83.11uA
3V        0A         0A         0A
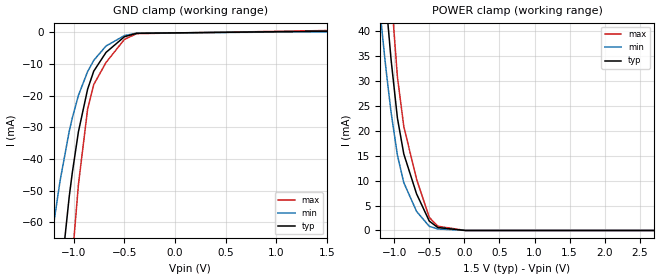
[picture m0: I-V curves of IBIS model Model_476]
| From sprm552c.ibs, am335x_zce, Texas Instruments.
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| Model based on original model for BCSHTLTCSCDVPBFZ_SSDHV
|   Sub model VREF_NOTERM_PD_ON_10PER_1P5
[model]   Model_476
|[Description]  [1.5V-INPUT-PD-X, IND, 10%]
|   Weak internal pull-down,Industrial temperature range (-40C to
|   125C, 25C nominal),10% power supply tolerance
|[Input Load]   PD
|[Output Drive]
|Voltage   1.5V
|Mode   INPUT
Model_type   Input
Polarity   Non-Inverting
Vinl =  0.65
Vinh =  0.85
C_comp   1.865048p   1.676829p   1.989968p
[Model Spec]
Vinl   0.65   0.575   0.725
Vinh   0.85   0.775   0.925
[Temperature Range]   25   125   -40
[Voltage Range]   1.5   1.35   1.65
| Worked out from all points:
|   GND clamp passes 1 mA (typ) near -0.47 V on its own axis
|   POWER clamp passes 1 mA (typ) near -0.44 V on its own axis
[POWER_clamp]
-1.5V     126mA      88.8mA     168.8mA
-1.227V   66.76mA    47.27mA    90.61mA
-1.136V   49.31mA    34.76mA    68.05mA
-1.106V   44.06mA    30.92mA    61.02mA
-1.045V   34.25mA    23.7mA     47.59mA
-954.5mV  22.53mA    15.08mA    30.79mA
-863.6mV  15.33mA    9.582mA    20.85mA
-681.8mV  7.347mA    3.829mA    10.29mA
-500mV    1.883mA    831.2uA    2.619mA
-378.8mV  592uA      304uA      848.2uA
15.15mV   0A         0A         0A
3V        0A         0A         0A
[GND_clamp]
-1.5V     -219.5mA   -131.6mA   -364.6mA
-1.288V   -134.7mA   -79.82mA   -225.9mA
-1.136V   -79.59mA   -47.01mA   -132.8mA
-1.045V   -51.87mA   -31.23mA   -84.59mA
-1.015V   -44.41mA   -27.07mA   -71.43mA
-954.5mV  -31.43mA   -19.9mA    -48.16mA
-863.6mV  -17.93mA   -12.38mA   -24.22mA
-803mV    -12.23mA   -8.818mA   -16.47mA
-681.8mV  -6.3mA     -4.277mA   -9.483mA
-500mV    -1.342mA   -990.9uA   -2.191mA
-378.8mV  -267.9uA   -213.7uA   -377.9uA
1.5V      407.4uA    229.1uA    614.3uA
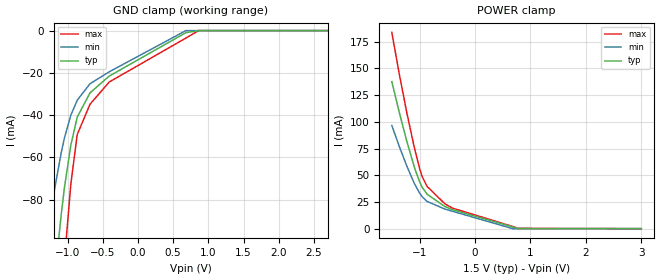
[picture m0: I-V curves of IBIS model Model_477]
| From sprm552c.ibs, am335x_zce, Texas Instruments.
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| Model based on original model for BCSHTLTCSCDVPBFZ_SSDHV
|   Sub model VREF_FULLTERM_8MA_10PER_1P5
[model]   Model_477
|[Description]  [1.5V-INPUT-FULLTERM:8MA-X, IND, 10%]
|   FULLTERM, 1.00 * RExt = 1.000 * Iout (I[2:0] = "011"), 8mA
|   nominal with Rext = 50R,Industrial temperature range (-40C to
|   125C, 25C nominal),10% power supply tolerance
|[Input Load]   FULLTERM:8MA
|[Output Drive]
|Voltage   1.5V
|Mode   INPUT
Model_type   Input
Polarity   Non-Inverting
Vinl =  0.65
Vinh =  0.85
C_comp   1.865048p   1.676829p   1.989968p
[Model Spec]
Vinl   0.65   0.575   0.725
Vinh   0.85   0.775   0.925
[Temperature Range]   25   125   -40
[Voltage Range]   1.5   1.35   1.65
[POWER_clamp]
-1.5V     137.6mA    96.6mA     183.7mA
-1.364V   108.6mA    76.8mA     144.3mA
-1.227V   81.31mA    58.27mA    107.9mA
-1.091V   57.17mA    42.02mA    75.23mA
-1V       44.06mA    33.37mA    56.5mA
-954.5mV  38.92mA    30.04mA    48.95mA
-863.6mV  32.24mA    25.53mA    39.53mA
-545.5mV  20.8mA     18.38mA    23.41mA
-409.1mV  17.75mA    16.33mA    19.3mA
681.8mV   1.595mA    0A         2.031mA
772.7mV   0A         0A         289.9uA
3V        0A         0A         0A
[GND_clamp]
-1.5V     -237.2mA   -145.5mA   -383.8mA
-1.364V   -183.8mA   -113.7mA   -295.6mA
-1.182V   -116.7mA   -74.5mA    -182.5mA
-1.091V   -87.07mA   -57.81mA   -131.2mA
-1.045V   -74.28mA   -50.8mA    -108.7mA
-954.5mV  -54.25mA   -40.06mA   -72.71mA
-863.6mV  -40.98mA   -32.95mA   -49.2mA
-681.8mV  -29.46mA   -25.15mA   -34.85mA
-409.1mV  -21.54mA   -19.51mA   -24.33mA
681.8mV   -978.9uA   0A         -3.534mA
863.6mV   0A         0A         0A
3V        0A         0A         0A
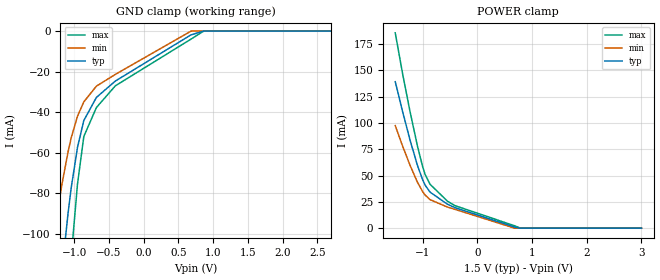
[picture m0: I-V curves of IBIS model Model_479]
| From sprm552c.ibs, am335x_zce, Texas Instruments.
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| Model based on original model for BCSHTLTCSCDVPBFZ_SSDHV
|   Sub model VREF_FULLTERM_9MA_10PER_1P5
[model]   Model_479
|[Description]  [1.5V-INPUT-FULLTERM:9MA-X, IND, 10%]
|   FULLTERM, 0.88 * RExt = 1.125 * Iout (I[2:0] = "100"), 9mA
|   nominal with Rext = 50R,Industrial temperature range (-40C to
|   125C, 25C nominal),10% power supply tolerance
|[Input Load]   FULLTERM:9MA
|[Output Drive]
|Voltage   1.5V
|Mode   INPUT
Model_type   Input
Polarity   Non-Inverting
Vinl =  0.65
Vinh =  0.85
C_comp   1.865048p   1.676829p   1.989968p
[Model Spec]
Vinl   0.65   0.575   0.725
Vinh   0.85   0.775   0.925
[Temperature Range]   25   125   -40
[Voltage Range]   1.5   1.35   1.65
[POWER_clamp]
-1.5V     139.1mA    97.35mA    185.4mA
-1.364V   110.3mA    77.69mA    146.1mA
-1.227V   83.11mA    59.32mA    109.9mA
-1.091V   59.07mA    43.27mA    77.25mA
-1V       45.98mA    34.75mA    58.56mA
-954.5mV  40.86mA    31.47mA    51.03mA
-863.6mV  34.19mA    27.07mA    41.66mA
-545.5mV  22.7mA     20.01mA    25.6mA
-409.1mV  19.5mA     17.87mA    21.4mA
681.8mV   1.064mA    0A         2.256mA
772.7mV   0A         0A         322.1uA
3V        0A         0A         0A
[GND_clamp]
-1.5V     -239.5mA   -146.9mA   -386mA
-1.364V   -186.4mA   -115.2mA   -297.9mA
-1.182V   -119.6mA   -76.24mA   -185.1mA
-1.091V   -90.03mA   -59.64mA   -133.8mA
-1.045V   -77.29mA   -52.67mA   -111.4mA
-954.5mV  -57.35mA   -41.99mA   -75.46mA
-863.6mV  -44.14mA   -34.91mA   -52mA
-681.8mV  -32.7mA    -27.15mA   -37.69mA
-409.1mV  -24.64mA   -21.35mA   -26.99mA
681.8mV   -1.827mA   0A         -3.925mA
863.6mV   0A         0A         0A
3V        0A         0A         0A
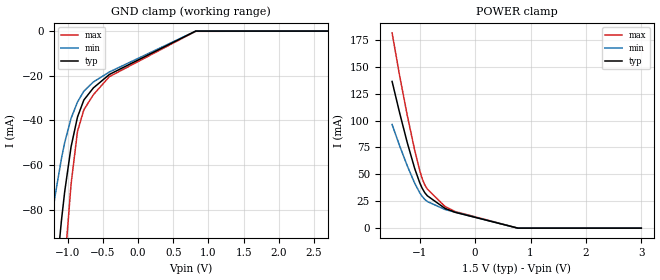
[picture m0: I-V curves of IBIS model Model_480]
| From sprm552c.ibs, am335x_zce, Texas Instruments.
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| Model based on original model for BCSHTLTCSCDVPBFZ_SSDHV
|   Sub model VREF_FULLTERM_7MA_5PER_1P5
[model]   Model_480
|[Description]  [1.5V-INPUT-FULLTERM:7MA-X, IND, 5%]
|   FULLTERM, 1.14 * RExt = 0.875 * Iout (I[2:0] = "010"), 7mA
|   nominal with Rext = 50R,Industrial temperature range (-40C to
|   125C, 25C nominal),5% power supply tolerance
|[Input Load]   FULLTERM:7MA
|[Output Drive]
|Voltage   1.5V
|Mode   INPUT
Model_type   Input
Polarity   Non-Inverting
Vinl =  0.65
Vinh =  0.85
C_comp   1.865048p   1.679967p   1.989968p
[Model Spec]
Vinl   0.65   0.6125   0.6875
Vinh   0.85   0.8125   0.8875
[Temperature Range]   25   125   -40
[Voltage Range]   1.5   1.425   1.575
[POWER_clamp]
-1.5V     136.3mA    96.32mA    181.4mA
-1.364V   107.1mA    76.52mA    141.6mA
-1.227V   79.59mA    58.02mA    105mA
-1.091V   55.26mA    41.63mA    72.12mA
-1V       42.05mA    32.8mA     53.33mA
-954.5mV  36.86mA    29.38mA    45.75mA
-909.1mV  32.9mA     26.72mA    40.08mA
-863.6mV  30.07mA    24.74mA    36.28mA
-545.5mV  18.4mA     17.34mA    20.19mA
-363.6mV  14.75mA    14.88mA    15.49mA
772.7mV   0A         0A         0A
3V        0A         0A         0A
[GND_clamp]
-1.5V     -235.2mA   -145.4mA   -380.1mA
-1.364V   -181.6mA   -113.4mA   -291.7mA
-1.182V   -114.4mA   -73.79mA   -178.5mA
-1.091V   -84.63mA   -56.94mA   -127mA
-1.045V   -71.81mA   -49.86mA   -104.5mA
-954.5mV  -51.77mA   -39.01mA   -68.48mA
-863.6mV  -38.5mA    -31.79mA   -44.93mA
-772.7mV  -30.85mA   -26.88mA   -35.24mA
-636.4mV  -25.41mA   -22.75mA   -28.44mA
-409.1mV  -19.41mA   -18.3mA    -20.38mA
818.2mV   0A         0A         -101.1uA
3V        0A         0A         0A
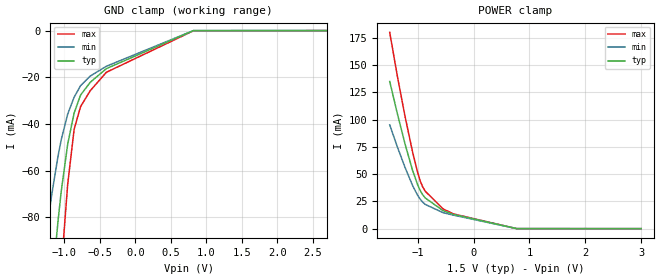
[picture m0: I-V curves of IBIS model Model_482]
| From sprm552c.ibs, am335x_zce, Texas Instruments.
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| Model based on original model for BCSHTLTCSCDVPBFZ_SSDHV
|   Sub model VREF_HALFTERM_12MA_5PER_1P5
[model]   Model_482
|[Description]  [1.5V-INPUT-HALFTERM:12MA-X, IND, 5%]
|   Half Thevenin termination (Rth = 100R whith RExt = 50R)
|   (ODT[1:0] = "11") VRef mode, 0.67 * RExt = 1.500 * Iout (I[2:0]
|   = "111"), 12mA nominal with Rext = 50R,Industrial temperature
|   range (-40C to 125C, 25C nominal),5% power supply tolerance
|[Input Load]   HALFTERM:12MA
|[Output Drive]
|Voltage   1.5V
|Mode   INPUT
Model_type   Input
Polarity   Non-Inverting
Vinl =  0.65
Vinh =  0.85
C_comp   1.865048p   1.679967p   1.989968p
[Model Spec]
Vinl   0.65   0.6125   0.6875
Vinh   0.85   0.8125   0.8875
[Temperature Range]   25   125   -40
[Voltage Range]   1.5   1.425   1.575
[POWER_clamp]
-1.5V     134.8mA    95.06mA    179.8mA
-1.364V   105.5mA    75.01mA    139.9mA
-1.227V   77.79mA    56.22mA    103.1mA
-1.091V   53.36mA    39.52mA    70.23mA
-1V       40.12mA    30.49mA    51.41mA
-954.5mV  34.93mA    26.98mA    43.8mA
-909.1mV  30.96mA    24.24mA    38.11mA
-863.6mV  28.12mA    22.19mA    34.29mA
-545.5mV  16.49mA    14.65mA    18.12mA
-363.6mV  13.08mA    12.41mA    13.57mA
772.7mV   70.25uA    0A         0A
3V        0A         0A         0A
[GND_clamp]
-1.5V     -232.9mA   -143.1mA   -378.2mA
-1.364V   -179mA     -110.8mA   -289.6mA
-1.182V   -111.5mA   -70.85mA   -176.1mA
-1.091V   -81.68mA   -53.88mA   -124.6mA
-1.045V   -68.81mA   -46.74mA   -102mA
-954.5mV  -48.67mA   -35.81mA   -65.92mA
-863.6mV  -35.33mA   -28.55mA   -42.32mA
-772.7mV  -27.63mA   -23.61mA   -32.58mA
-636.4mV  -22.17mA   -19.49mA   -25.78mA
-409.1mV  -16.31mA   -15.29mA   -17.88mA
818.2mV   0A         0A         -88.47uA
3V        0A         0A         0A
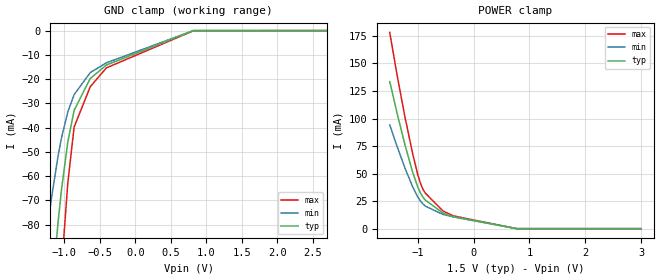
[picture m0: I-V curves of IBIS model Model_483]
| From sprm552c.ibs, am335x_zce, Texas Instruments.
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| Model based on original model for BCSHTLTCSCDVPBFZ_SSDHV
|   Sub model VREF_FULLTERM_5MA_5PER_1P5
[model]   Model_483
|[Description]  [1.5V-INPUT-FULLTERM:5MA-X, IND, 5%]
|   FULLTERM, 1.60 * RExt = 0.625 * Iout (I[2:0] = "000"), 5mA
|   nominal with Rext = 50R,Industrial temperature range (-40C to
|   125C, 25C nominal),5% power supply tolerance
|[Input Load]   FULLTERM:5MA
|[Output Drive]
|Voltage   1.5V
|Mode   INPUT
Model_type   Input
Polarity   Non-Inverting
Vinl =  0.65
Vinh =  0.85
C_comp   1.865048p   1.679967p   1.989968p
[Model Spec]
Vinl   0.65   0.6125   0.6875
Vinh   0.85   0.8125   0.8875
[Temperature Range]   25   125   -40
[Voltage Range]   1.5   1.425   1.575
[POWER_clamp]
-1.5V     133.5mA    94.22mA    178.2mA
-1.364V   104mA      74.01mA    138.2mA
-1.227V   76.08mA    55.02mA    101.3mA
-1.091V   51.44mA    38.11mA    68.35mA
-1V       38.11mA    28.95mA    49.49mA
-954.5mV  32.86mA    25.38mA    41.86mA
-909.1mV  28.84mA    22.59mA    36.13mA
-863.6mV  25.96mA    20.49mA    32.29mA
-545.5mV  14.1mA     12.85mA    16.05mA
-363.6mV  10.76mA    10.76mA    11.65mA
772.7mV   0A         0A         0A
3V        0A         0A         0A
[GND_clamp]
-1.5V     -230.9mA   -141.6mA   -376.2mA
-1.364V   -176.8mA   -109mA     -287.5mA
-1.318V   -159.3mA   -98.53mA   -258.4mA
-1.182V   -109.1mA   -68.89mA   -173.8mA
-1.091V   -79.24mA   -51.83mA   -122.1mA
-1.045V   -66.34mA   -44.67mA   -99.49mA
-954.5mV  -46.19mA   -33.68mA   -63.35mA
-863.6mV  -32.85mA   -26.38mA   -39.7mA
-636.4mV  -19.75mA   -17.31mA   -23.12mA
-409.1mV  -14.19mA   -13.28mA   -15.37mA
818.2mV   0A         0A         -75.85uA
3V        0A         0A         0A
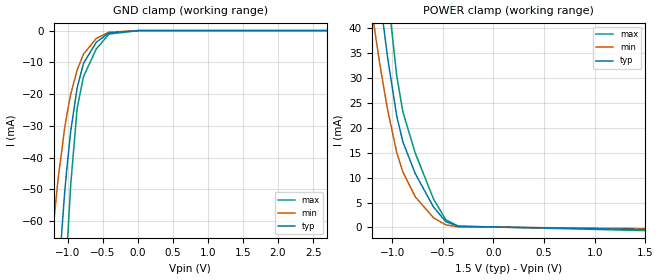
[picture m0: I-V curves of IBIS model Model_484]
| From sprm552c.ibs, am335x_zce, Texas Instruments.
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| Model based on original model for BCSHTLTCSCDVPBFZ_SSDHV
|   Sub model VREF_NOTERM_PU_ON_5PER_1P5
[model]   Model_484
|[Description]  [1.5V-INPUT-PU-X, IND, 5%]
|   Weak internal pull-up,Industrial temperature range (-40C to
|   125C, 25C nominal),5% power supply tolerance
|[Input Load]   PU
|[Output Drive]
|Voltage   1.5V
|Mode   INPUT
Model_type   Input
Polarity   Non-Inverting
Vinl =  0.65
Vinh =  0.85
C_comp   1.865048p   1.679967p   1.989968p
[Model Spec]
Vinl   0.65   0.6125   0.6875
Vinh   0.85   0.8125   0.8875
[Temperature Range]   25   125   -40
[Voltage Range]   1.5   1.425   1.575
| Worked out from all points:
|   GND clamp passes 1 mA (typ) near -0.44 V on its own axis
|   POWER clamp passes 1 mA (typ) near -0.46 V on its own axis
[POWER_clamp]
-1.5V     126mA      88.77mA    168.8mA
-1.227V   66.74mA    47.25mA    90.53mA
-1.136V   49.27mA    34.74mA    67.87mA
-1.106V   44mA       30.89mA    60.8mA
-1.045V   34.16mA    23.68mA    47.3mA
-954.5mV  22.38mA    15.05mA    30.46mA
-893.9mV  17.2mA     11.13mA    23.23mA
-772.7mV  10.84mA    6.17mA     14.97mA
-590.9mV  4.062mA    1.918mA    5.676mA
-469.7mV  1.154mA    490.5uA    1.522mA
-348.5mV  202uA      106.4uA    253.7uA
1.5V      -448.2uA   -257uA     -648.5uA
[GND_clamp]
-1.5V     -219.5mA   -131.6mA   -364.6mA
-1.288V   -134.7mA   -79.85mA   -226mA
-1.136V   -79.69mA   -47.06mA   -132.9mA
-1.045V   -52mA      -31.29mA   -84.81mA
-1.015V   -44.56mA   -27.14mA   -71.67mA
-954.5mV  -31.59mA   -19.98mA   -48.42mA
-863.6mV  -18.1mA    -12.47mA   -24.5mA
-772.7mV  -10.31mA   -7.406mA   -14.47mA
-590.9mV  -3.692mA   -2.482mA   -5.793mA
-409.1mV  -736uA     -503.1uA   -1.088mA
15.15mV   0A         0A         0A
3V        0A         0A         0A
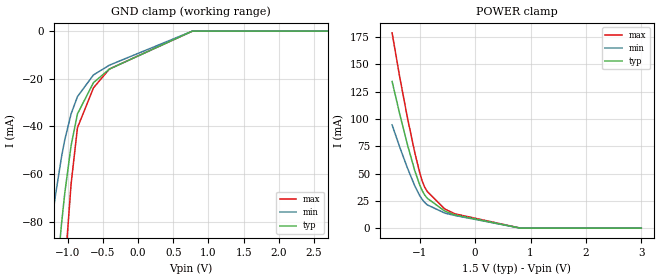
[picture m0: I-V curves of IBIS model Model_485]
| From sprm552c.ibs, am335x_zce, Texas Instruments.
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| Model based on original model for BCSHTLTCSCDVPBFZ_SSDHV
|   Sub model VREF_HALFTERM_11MA_5PER_1P5
[model]   Model_485
|[Description]  [1.5V-INPUT-HALFTERM:11MA-X, IND, 5%]
|   Half Thevenin termination (Rth = 100R whith RExt = 50R)
|   (ODT[1:0] = "11") VRef mode, 0.73 * RExt = 1.325 * Iout (I[2:0]
|   = "110"), 11mA nominal with Rext = 50R,Industrial temperature
|   range (-40C to 125C, 25C nominal),5% power supply tolerance
|[Input Load]   HALFTERM:11MA
|[Output Drive]
|Voltage   1.5V
|Mode   INPUT
Model_type   Input
Polarity   Non-Inverting
Vinl =  0.65
Vinh =  0.85
C_comp   1.865048p   1.679967p   1.989968p
[Model Spec]
Vinl   0.65   0.6125   0.6875
Vinh   0.85   0.8125   0.8875
[Temperature Range]   25   125   -40
[Voltage Range]   1.5   1.425   1.575
[POWER_clamp]
-1.5V     134.4mA    94.64mA    178.9mA
-1.364V   105mA      74.51mA    139mA
-1.227V   77.25mA    55.62mA    102.2mA
-1.091V   52.71mA    38.81mA    69.34mA
-1V       39.42mA    29.72mA    50.55mA
-954.5mV  34.19mA    26.18mA    42.95mA
-909.1mV  30.2mA     23.42mA    37.27mA
-863.6mV  27.33mA    21.34mA    33.47mA
-545.5mV  15.53mA    13.75mA    17.46mA
-363.6mV  12.09mA    11.58mA    13.09mA
818.2mV   0A         0A         29.63uA
3V        0A         0A         0A
[GND_clamp]
-1.5V     -232.3mA   -142.3mA   -377mA
-1.364V   -178.4mA   -109.9mA   -288.3mA
-1.318V   -160.9mA   -99.43mA   -259.2mA
-1.182V   -110.9mA   -69.87mA   -174.6mA
-1.091V   -81.03mA   -52.85mA   -122.9mA
-1.045V   -68.17mA   -45.7mA    -100.3mA
-954.5mV  -48.05mA   -34.75mA   -64.16mA
-863.6mV  -34.73mA   -27.47mA   -40.49mA
-636.4mV  -21.64mA   -18.4mA    -23.82mA
-409.1mV  -15.93mA   -14.29mA   -15.9mA
772.7mV   0A         0A         0A
3V        0A         0A         0A
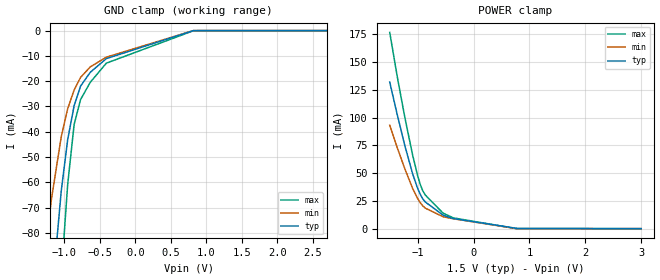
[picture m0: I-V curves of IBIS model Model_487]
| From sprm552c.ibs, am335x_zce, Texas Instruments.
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| Model based on original model for BCSHTLTCSCDVPBFZ_SSDHV
|   Sub model VREF_HALFTERM_8MA_5PER_1P5
[model]   Model_487
|[Description]  [1.5V-INPUT-HALFTERM:8MA-X, IND, 5%]
|   Half Thevenin termination (Rth = 100R whith RExt = 50R)
|   (ODT[1:0] = "11") VRef mode, 1.00 * RExt = 1.000 * Iout (I[2:0]
|   = "011"), 8mA nominal with Rext = 50R,Industrial temperature
|   range (-40C to 125C, 25C nominal),5% power supply tolerance
|[Input Load]   HALFTERM:8MA
|[Output Drive]
|Voltage   1.5V
|Mode   INPUT
Model_type   Input
Polarity   Non-Inverting
Vinl =  0.65
Vinh =  0.85
C_comp   1.865048p   1.679967p   1.989968p
[Model Spec]
Vinl   0.65   0.6125   0.6875
Vinh   0.85   0.8125   0.8875
[Temperature Range]   25   125   -40
[Voltage Range]   1.5   1.425   1.575
[POWER_clamp]
-1.5V     132mA      93.1mA     176.7mA
-1.364V   102.3mA    72.71mA    136.5mA
-1.227V   74.28mA    53.51mA    99.51mA
-1.091V   49.55mA    36.36mA    66.47mA
-1V       36.19mA    27.07mA    47.57mA
-954.5mV  30.93mA    23.44mA    39.91mA
-909.1mV  26.9mA     20.59mA    34.16mA
-863.6mV  24.01mA    18.45mA    30.29mA
-545.5mV  12.19mA    10.76mA    13.98mA
-363.6mV  9.088mA    8.911mA    9.724mA
772.7mV   253.7uA    0A         0A
3V        0A         0A         0A
[GND_clamp]
-1.5V     -228.6mA   -139.6mA   -374.2mA
-1.364V   -174.3mA   -106.8mA   -285.3mA
-1.318V   -156.7mA   -96.21mA   -256.2mA
-1.182V   -106.3mA   -66.34mA   -171.4mA
-1.045V   -63.33mA   -41.93mA   -96.98mA
-954.5mV  -43.09mA   -30.86mA   -60.79mA
-863.6mV  -29.69mA   -23.5mA    -37.09mA
-772.7mV  -21.94mA   -18.5mA    -27.27mA
-636.4mV  -16.5mA    -14.36mA   -20.46mA
-409.1mV  -11.08mA   -10.51mA   -12.87mA
818.2mV   0A         0A         -63.22uA
3V        0A         0A         0A
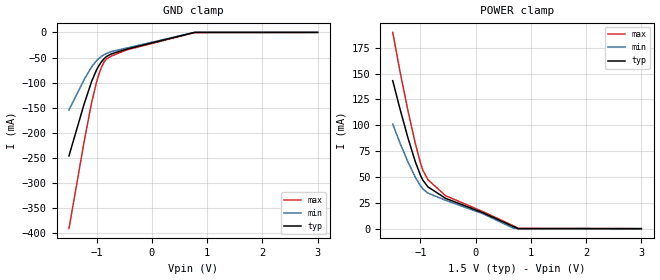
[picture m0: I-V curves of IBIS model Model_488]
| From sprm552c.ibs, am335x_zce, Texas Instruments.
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| Model based on original model for BCSHTLTCSCDVPBFZ_SSDHV
|   Sub model VREF_FULLTERM_12MA_5PER_1P5
[model]   Model_488
|[Description]  [1.5V-INPUT-FULLTERM:12MA-X, IND, 5%]
|   FULLTERM, 0.67 * RExt = 1.500 * Iout (I[2:0] = "111"), 12mA
|   nominal with Rext = 50R,Industrial temperature range (-40C to
|   125C, 25C nominal),5% power supply tolerance
|[Input Load]   FULLTERM:12MA
|[Output Drive]
|Voltage   1.5V
|Mode   INPUT
Model_type   Input
Polarity   Non-Inverting
Vinl =  0.65
Vinh =  0.85
C_comp   1.865048p   1.679967p   1.989968p
[Model Spec]
Vinl   0.65   0.6125   0.6875
Vinh   0.85   0.8125   0.8875
[Temperature Range]   25   125   -40
[Voltage Range]   1.5   1.425   1.575
[POWER_clamp]
-1.5V     143.2mA    101.2mA    189.9mA
-1.364V   115mA      82.34mA    151mA
-1.227V   88.35mA    64.95mA    114.9mA
-1.091V   64.8mA     49.74mA    82.51mA
-1V       51.94mA    41.63mA    64mA
-954.5mV  46.92mA    38.54mA    56.58mA
-863.6mV  40.47mA    34.43mA    47.46mA
-545.5mV  29.4mA     27.52mA    31.95mA
136.4mV   15.33mA    14.35mA    16.38mA
681.8mV   2.049mA    521.9uA    2.872mA
772.7mV   0A         0A         326.3uA
3V        0A         0A         0A
[GND_clamp]
-1.5V     -245.8mA   -154.3mA   -390.6mA
-1.227V   -143.1mA   -94.24mA   -218.4mA
-1.091V   -97.87mA   -68.82mA   -140.2mA
-1V       -74.4mA    -56.15mA   -98.54mA
-954.5mV  -65.42mA   -51.42mA   -82.12mA
-909.1mV  -58.13mA   -47.58mA   -68.83mA
-863.6mV  -52.27mA   -44.42mA   -58.79mA
-818.2mV  -47.78mA   -41.78mA   -52.55mA
-727.3mV  -42.6mA    -37.96mA   -46.88mA
-454.5mV  -33.22mA   -31.17mA   -34.79mA
772.7mV   0A         0A         -510.7uA
3V        0A         0A         0A
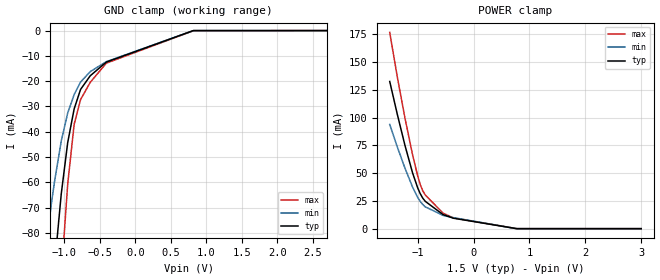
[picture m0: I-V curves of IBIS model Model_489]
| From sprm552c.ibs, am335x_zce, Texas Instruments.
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| Model based on original model for BCSHTLTCSCDVPBFZ_SSDHV
|   Sub model VREF_HALFTERM_9MA_5PER_1P5
[model]   Model_489
|[Description]  [1.5V-INPUT-HALFTERM:9MA-X, IND, 5%]
|   Half Thevenin termination (Rth = 100R whith RExt = 50R)
|   (ODT[1:0] = "11") VRef mode, 0.88 * RExt = 1.125 * Iout (I[2:0]
|   = "100"), 9mA nominal with Rext = 50R,Industrial temperature
|   range (-40C to 125C, 25C nominal),5% power supply tolerance
|[Input Load]   HALFTERM:9MA
|[Output Drive]
|Voltage   1.5V
|Mode   INPUT
Model_type   Input
Polarity   Non-Inverting
Vinl =  0.65
Vinh =  0.85
C_comp   1.865048p   1.679967p   1.989968p
[Model Spec]
Vinl   0.65   0.6125   0.6875
Vinh   0.85   0.8125   0.8875
[Temperature Range]   25   125   -40
[Voltage Range]   1.5   1.425   1.575
[POWER_clamp]
-1.5V     132.5mA    93.8mA     176.7mA
-1.364V   102.9mA    73.51mA    136.5mA
-1.227V   74.91mA    54.42mA    99.51mA
-1.091V   50.18mA    37.4mA     66.47mA
-1V       36.8mA     28.18mA    47.57mA
-954.5mV  31.53mA    24.59mA    39.91mA
-909.1mV  27.49mA    21.76mA    34.16mA
-863.6mV  24.58mA    19.64mA    30.29mA
-545.5mV  12.66mA    11.95mA    13.98mA
-363.6mV  9.428mA    9.938mA    9.724mA
772.7mV   0A         0A         0A
3V        0A         0A         0A
[GND_clamp]
-1.5V     -229.4mA   -140.8mA   -374.2mA
-1.318V   -157.7mA   -97.63mA   -256.2mA
-1.182V   -107.4mA   -67.91mA   -171.4mA
-1.136V   -91.88mA   -58.98mA   -144.7mA
-1.045V   -64.52mA   -43.63mA   -96.98mA
-954.5mV  -44.33mA   -32.62mA   -60.79mA
-863.6mV  -30.97mA   -25.3mA    -37.09mA
-772.7mV  -23.26mA   -20.33mA   -27.27mA
-636.4mV  -17.86mA   -16.22mA   -20.46mA
-409.1mV  -12.44mA   -12.28mA   -12.87mA
818.2mV   0A         0A         -63.22uA
3V        0A         0A         0A
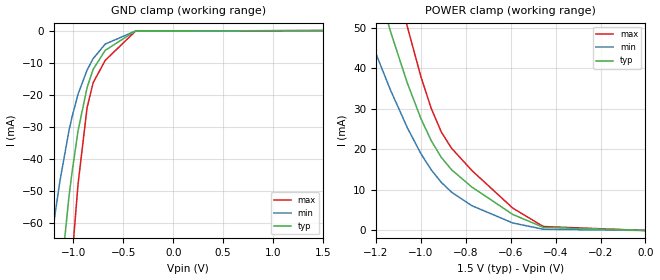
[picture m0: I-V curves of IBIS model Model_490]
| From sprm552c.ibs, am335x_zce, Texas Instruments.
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| Model based on original model for BCSHTLTCSCDVPBFZ_SSDHV
|   Sub model VREF_NOTERM_PUPD_OFF_5PER_1P5
[model]   Model_490
|[Description]  [1.5V-INPUT-PI-X, IND, 5%]
|   Weak pull up/down disabled,Industrial temperature range (-40C to
|   125C, 25C nominal),5% power supply tolerance
|[Input Load]   PI
|[Output Drive]
|Voltage   1.5V
|Mode   INPUT
Model_type   Input
Polarity   Non-Inverting
Vinl =  0.65
Vinh =  0.85
C_comp   1.865048p   1.679967p   1.989968p
[Model Spec]
Vinl   0.65   0.6125   0.6875
Vinh   0.85   0.8125   0.8875
[Temperature Range]   25   125   -40
[Voltage Range]   1.5   1.425   1.575
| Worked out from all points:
|   GND clamp passes 1 mA (typ) near -0.49 V on its own axis
|   POWER clamp passes 1 mA (typ) near -0.47 V on its own axis
[POWER_clamp]
-1.5V     126mA      88.76mA    168.8mA
-1.242V   69.83mA    49.43mA    94.45mA
-1.136V   49.22mA    34.72mA    67.72mA
-1.061V   36.46mA    25.41mA    50.4mA
-1V       27.61mA    18.95mA    37.96mA
-954.5mV  22.21mA    15mA       30.19mA
-909.1mV  18.03mA    11.86mA    24.3mA
-863.6mV  14.99mA    9.461mA    20.3mA
-772.7mV  10.7mA     6.113mA    14.79mA
-590.9mV  3.954mA    1.851mA    5.518mA
-454.5mV  772.9uA    303.2uA    974.6uA
0V        1.601nA    15.84nA    2.115nA
[GND_clamp]
-1.5V     -219.4mA   -131.6mA   -364.5mA
-1.288V   -134.6mA   -79.79mA   -225.8mA
-1.258V   -123.1mA   -72.83mA   -206.6mA
-1.136V   -79.49mA   -46.97mA   -132.6mA
-1.045V   -51.76mA   -31.17mA   -84.43mA
-1.015V   -44.3mA    -27.02mA   -71.26mA
-954.5mV  -31.3mA    -19.84mA   -47.97mA
-863.6mV  -17.79mA   -12.31mA   -24.02mA
-803mV    -12.1mA    -8.75mA    -16.27mA
-681.8mV  -6.163mA   -4.204mA   -9.293mA
-378.8mV  -129.8uA   -135.7uA   -184.8uA
1.5V      1.601nA    41.79nA    1.45nA
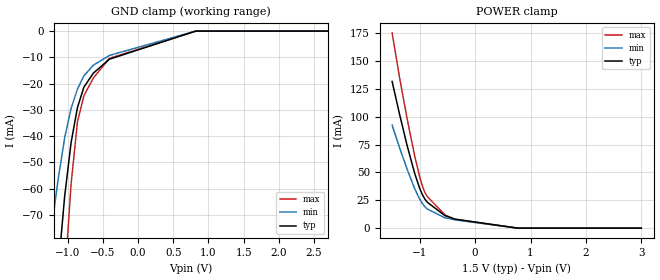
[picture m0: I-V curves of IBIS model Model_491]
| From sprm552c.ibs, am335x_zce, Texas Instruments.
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| Model based on original model for BCSHTLTCSCDVPBFZ_SSDHV
|   Sub model VREF_HALFTERM_7MA_5PER_1P5
[model]   Model_491
|[Description]  [1.5V-INPUT-HALFTERM:7MA-X, IND, 5%]
|   Half Thevenin termination (Rth = 100R whith RExt = 50R)
|   (ODT[1:0] = "11") VRef mode, 1.14 * RExt = 0.875 * Iout (I[2:0]
|   = "010"), 7mA nominal with Rext = 50R,Industrial temperature
|   range (-40C to 125C, 25C nominal),5% power supply tolerance
|[Input Load]   HALFTERM:7MA
|[Output Drive]
|Voltage   1.5V
|Mode   INPUT
Model_type   Input
Polarity   Non-Inverting
Vinl =  0.65
Vinh =  0.85
C_comp   1.865048p   1.679967p   1.989968p
[Model Spec]
Vinl   0.65   0.6125   0.6875
Vinh   0.85   0.8125   0.8875
[Temperature Range]   25   125   -40
[Voltage Range]   1.5   1.425   1.575
[POWER_clamp]
-1.5V     131.6mA    92.54mA    175.1mA
-1.364V   101.9mA    72.01mA    134.7mA
-1.227V   73.73mA    52.63mA    97.7mA
-1.091V   48.91mA    35.29mA    64.59mA
-1V       35.48mA    25.87mA    45.64mA
-954.5mV  30.2mA     22.19mA    37.97mA
-909.1mV  26.14mA    19.29mA    32.19mA
-863.6mV  23.21mA    17.1mA     28.29mA
-545.5mV  11.23mA    9.249mA    11.91mA
-363.6mV  8.097mA    7.467mA    7.802mA
772.7mV   0A         0A         0A
3V        0A         0A         0A
[GND_clamp]
-1.5V     -228mA     -138.5mA   -372.3mA
-1.318V   -156mA     -94.94mA   -254mA
-1.182V   -105.7mA   -64.98mA   -169mA
-1.136V   -90.11mA   -55.97mA   -142.3mA
-1.045V   -62.7mA    -40.51mA   -94.47mA
-954.5mV  -42.47mA   -29.42mA   -58.22mA
-863.6mV  -29.09mA   -22.05mA   -34.48mA
-772.7mV  -21.36mA   -17.06mA   -24.61mA
-636.4mV  -15.97mA   -12.95mA   -17.81mA
-409.1mV  -10.7mA    -9.268mA   -10.37mA
818.2mV   0A         0A         -50.58uA
3V        0A         0A         0A
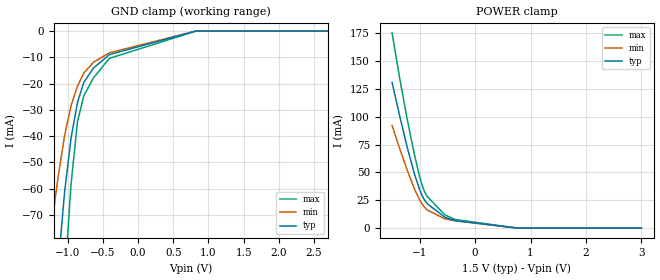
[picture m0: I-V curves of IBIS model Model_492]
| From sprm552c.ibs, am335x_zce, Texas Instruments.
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| Model based on original model for BCSHTLTCSCDVPBFZ_SSDHV
|   Sub model VREF_HALFTERM_6MA_5PER_1P5
[model]   Model_492
|[Description]  [1.5V-INPUT-HALFTERM:6MA-X, IND, 5%]
|   Half Thevenin termination (Rth = 100R whith RExt = 50R)
|   (ODT[1:0] = "11") VRef mode, 1.33 * RExt = 0.750 * Iout (I[2:0]
|   = "001"), 6mA nominal with Rext = 50R,Industrial temperature
|   range (-40C to 125C, 25C nominal),5% power supply tolerance
|[Input Load]   HALFTERM:6MA
|[Output Drive]
|Voltage   1.5V
|Mode   INPUT
Model_type   Input
Polarity   Non-Inverting
Vinl =  0.65
Vinh =  0.85
C_comp   1.865048p   1.679967p   1.989968p
[Model Spec]
Vinl   0.65   0.6125   0.6875
Vinh   0.85   0.8125   0.8875
[Temperature Range]   25   125   -40
[Voltage Range]   1.5   1.425   1.575
[POWER_clamp]
-1.5V     130.7mA    92.12mA    175.1mA
-1.364V   100.8mA    71.51mA    134.7mA
-1.227V   72.56mA    52.03mA    97.7mA
-1.091V   47.64mA    34.58mA    64.59mA
-1V       34.17mA    25.1mA     45.64mA
-954.5mV  28.86mA    21.39mA    37.97mA
-909.1mV  24.79mA    18.46mA    32.19mA
-863.6mV  21.84mA    16.25mA    28.29mA
-545.5mV  9.796mA    8.349mA    11.91mA
-363.6mV  6.767mA    6.643mA    7.802mA
772.7mV   0A         0A         0A
3V        0A         0A         0A
[GND_clamp]
-1.5V     -226.6mA   -137.7mA   -372.3mA
-1.318V   -154.4mA   -94.04mA   -254mA
-1.182V   -103.9mA   -64mA      -169mA
-1.136V   -88.34mA   -54.97mA   -142.3mA
-1.045V   -60.87mA   -39.47mA   -94.47mA
-954.5mV  -40.6mA    -28.36mA   -58.22mA
-863.6mV  -27.2mA    -20.97mA   -34.48mA
-772.7mV  -19.46mA   -15.97mA   -24.61mA
-636.4mV  -14.09mA   -11.87mA   -17.81mA
-409.1mV  -8.955mA   -8.264mA   -10.37mA
818.2mV   0A         0A         -50.58uA
3V        0A         0A         0A
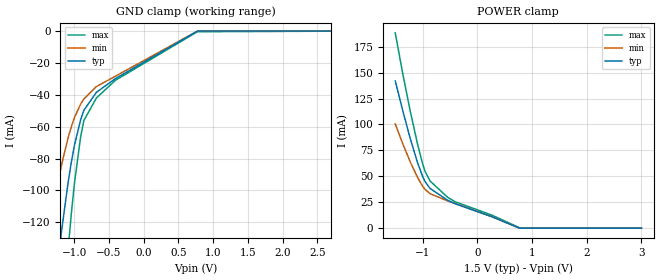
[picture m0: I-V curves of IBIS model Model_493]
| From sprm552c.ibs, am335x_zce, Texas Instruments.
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| Model based on original model for BCSHTLTCSCDVPBFZ_SSDHV
|   Sub model VREF_FULLTERM_11MA_5PER_1P5
[model]   Model_493
|[Description]  [1.5V-INPUT-FULLTERM:11MA-X, IND, 5%]
|   FULLTERM, 0.73 * RExt = 1.325 * Iout (I[2:0] = "110"), 11mA
|   nominal with Rext = 50R,Industrial temperature range (-40C to
|   125C, 25C nominal),5% power supply tolerance
|[Input Load]   FULLTERM:11MA
|[Output Drive]
|Voltage   1.5V
|Mode   INPUT
Model_type   Input
Polarity   Non-Inverting
Vinl =  0.65
Vinh =  0.85
C_comp   1.865048p   1.679967p   1.989968p
[Model Spec]
Vinl   0.65   0.6125   0.6875
Vinh   0.85   0.8125   0.8875
[Temperature Range]   25   125   -40
[Voltage Range]   1.5   1.425   1.575
[POWER_clamp]
-1.5V     141.9mA    100.5mA    188.3mA
-1.364V   113.5mA    81.54mA    149.3mA
-1.227V   86.63mA    64.03mA    113.1mA
-1.091V   62.88mA    48.69mA    80.63mA
-1V       49.92mA    40.52mA    62.08mA
-954.5mV  44.85mA    37.39mA    54.63mA
-863.6mV  38.3mA     33.23mA    45.46mA
-545.5mV  27mA       26.34mA    29.88mA
-409.1mV  23.6mA     23.89mA    25.55mA
272.7mV   10.87mA    10.99mA    12.43mA
772.7mV   0A         0A         372.4uA
3V        0A         0A         0A
[GND_clamp]
-1.5V     -243.8mA   -153.1mA   -388.7mA
-1.364V   -191.1mA   -122mA     -301.1mA
-1.182V   -124.8mA   -83.59mA   -188.8mA
-1.091V   -95.43mA   -67.16mA   -137.7mA
-1.045V   -82.76mA   -60.25mA   -115.4mA
-1V       -71.92mA   -54.42mA   -95.99mA
-909.1mV  -55.64mA   -45.8mA    -66.24mA
-863.6mV  -49.79mA   -42.62mA   -56.18mA
-681.8mV  -38.39mA   -34.79mA   -41.96mA
-409.1mV  -29.86mA   -28.33mA   -30.9mA
772.7mV   0A         0A         -402.6uA
3V        0A         0A         0A
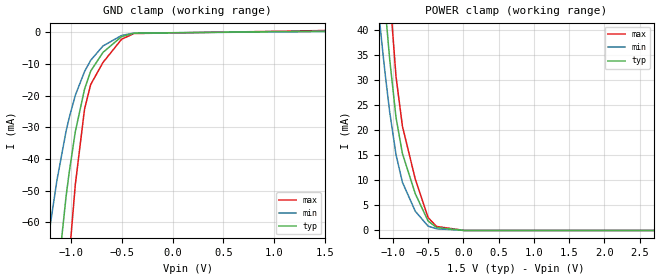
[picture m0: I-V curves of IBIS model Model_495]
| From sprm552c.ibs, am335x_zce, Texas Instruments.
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| Model based on original model for BCSHTLTCSCDVPBFZ_SSDHV
|   Sub model VREF_NOTERM_PD_ON_5PER_1P5
[model]   Model_495
|[Description]  [1.5V-INPUT-PD-X, IND, 5%]
|   Weak internal pull-down,Industrial temperature range (-40C to
|   125C, 25C nominal),5% power supply tolerance
|[Input Load]   PD
|[Output Drive]
|Voltage   1.5V
|Mode   INPUT
Model_type   Input
Polarity   Non-Inverting
Vinl =  0.65
Vinh =  0.85
C_comp   1.865048p   1.679967p   1.989968p
[Model Spec]
Vinl   0.65   0.6125   0.6875
Vinh   0.85   0.8125   0.8875
[Temperature Range]   25   125   -40
[Voltage Range]   1.5   1.425   1.575
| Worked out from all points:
|   GND clamp passes 1 mA (typ) near -0.47 V on its own axis
|   POWER clamp passes 1 mA (typ) near -0.44 V on its own axis
[POWER_clamp]
-1.5V     126mA      88.78mA    168.8mA
-1.227V   66.76mA    47.26mA    90.58mA
-1.136V   49.31mA    34.76mA    67.97mA
-1.106V   44.06mA    30.92mA    60.92mA
-1.045V   34.25mA    23.71mA    47.48mA
-954.5mV  22.53mA    15.11mA    30.68mA
-863.6mV  15.33mA    9.605mA    20.79mA
-681.8mV  7.347mA    3.849mA    10.26mA
-500mV    1.883mA    860.7uA    2.573mA
-378.8mV  592uA      335uA      797.4uA
15.15mV   0A         0A         0A
3V        0A         0A         0A
[GND_clamp]
-1.5V     -219.5mA   -131.6mA   -364.6mA
-1.288V   -134.7mA   -79.82mA   -225.9mA
-1.136V   -79.59mA   -47.01mA   -132.8mA
-1.045V   -51.87mA   -31.23mA   -84.58mA
-1.015V   -44.41mA   -27.07mA   -71.43mA
-954.5mV  -31.43mA   -19.9mA    -48.16mA
-863.6mV  -17.93mA   -12.38mA   -24.22mA
-803mV    -12.23mA   -8.82mA    -16.46mA
-681.8mV  -6.3mA     -4.279mA   -9.481mA
-500mV    -1.342mA   -992.4uA   -2.189mA
-378.8mV  -267.9uA   -215uA     -376.1uA
1.5V      407.4uA    253.8uA    580.6uA
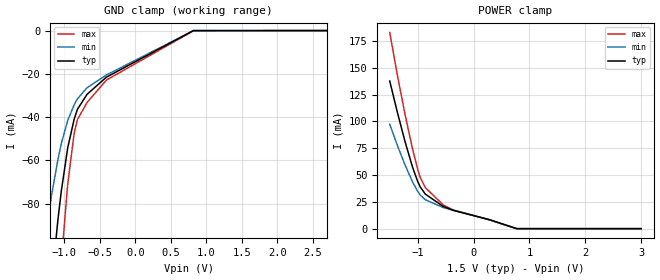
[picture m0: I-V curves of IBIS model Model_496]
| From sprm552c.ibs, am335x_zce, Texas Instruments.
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| Model based on original model for BCSHTLTCSCDVPBFZ_SSDHV
|   Sub model VREF_FULLTERM_8MA_5PER_1P5
[model]   Model_496
|[Description]  [1.5V-INPUT-FULLTERM:8MA-X, IND, 5%]
|   FULLTERM, 1.00 * RExt = 1.000 * Iout (I[2:0] = "011"), 8mA
|   nominal with Rext = 50R,Industrial temperature range (-40C to
|   125C, 25C nominal),5% power supply tolerance
|[Input Load]   FULLTERM:8MA
|[Output Drive]
|Voltage   1.5V
|Mode   INPUT
Model_type   Input
Polarity   Non-Inverting
Vinl =  0.65
Vinh =  0.85
C_comp   1.865048p   1.679967p   1.989968p
[Model Spec]
Vinl   0.65   0.6125   0.6875
Vinh   0.85   0.8125   0.8875
[Temperature Range]   25   125   -40
[Voltage Range]   1.5   1.425   1.575
[POWER_clamp]
-1.5V     137.6mA    97.31mA    182.9mA
-1.364V   108.6mA    77.73mA    143.3mA
-1.227V   81.31mA    59.51mA    106.8mA
-1.091V   57.17mA    43.41mA    74mA
-1V       44.06mA    34.77mA    55.25mA
-954.5mV  38.92mA    31.44mA    47.69mA
-863.6mV  32.24mA    26.94mA    38.28mA
-545.5mV  20.8mA     19.75mA    22.26mA
-363.6mV  17.07mA    17.14mA    17.41mA
272.7mV   8.572mA    8.399mA    8.361mA
772.7mV   0A         0A         0A
3V        0A         0A         0A
[GND_clamp]
-1.5V     -237.2mA   -147.3mA   -382.1mA
-1.364V   -183.8mA   -115.5mA   -293.9mA
-1.182V   -116.7mA   -76.13mA   -180.9mA
-1.091V   -87.07mA   -59.37mA   -129.5mA
-1.045V   -74.28mA   -52.32mA   -107mA
-954.5mV  -54.25mA   -41.52mA   -71.05mA
-863.6mV  -40.98mA   -34.33mA   -47.55mA
-818.2mV  -36.43mA   -31.62mA   -41.2mA
-681.8mV  -29.46mA   -26.39mA   -33.25mA
-409.1mV  -21.54mA   -20.54mA   -22.88mA
818.2mV   0A         0A         -113.7uA
3V        0A         0A         0A
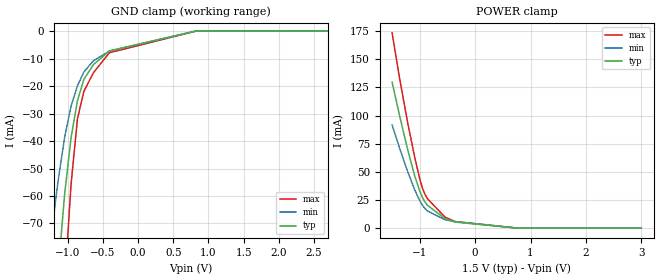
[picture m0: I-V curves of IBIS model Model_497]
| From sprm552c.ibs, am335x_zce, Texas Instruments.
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| Model based on original model for BCSHTLTCSCDVPBFZ_SSDHV
|   Sub model VREF_HALFTERM_5MA_5PER_1P5
[model]   Model_497
|[Description]  [1.5V-INPUT-HALFTERM:5MA-X, IND, 5%]
|   Half Thevenin termination (Rth = 100R whith RExt = 50R)
|   (ODT[1:0] = "11") VRef mode, 1.60 * RExt = 0.625 * Iout (I[2:0]
|   = "000"), 5mA nominal with Rext = 50R,Industrial temperature
|   range (-40C to 125C, 25C nominal),5% power supply tolerance
|[Input Load]   HALFTERM:5MA
|[Output Drive]
|Voltage   1.5V
|Mode   INPUT
Model_type   Input
Polarity   Non-Inverting
Vinl =  0.65
Vinh =  0.85
C_comp   1.865048p   1.679967p   1.989968p
[Model Spec]
Vinl   0.65   0.6125   0.6875
Vinh   0.85   0.8125   0.8875
[Temperature Range]   25   125   -40
[Voltage Range]   1.5   1.425   1.575
[POWER_clamp]
-1.5V     129.7mA    91.7mA     173.5mA
-1.364V   99.77mA    71.01mA    133mA
-1.227V   71.39mA    51.43mA    95.89mA
-1.091V   46.37mA    33.88mA    62.71mA
-1V       32.86mA    24.33mA    43.72mA
-954.5mV  27.53mA    20.59mA    36.02mA
-909.1mV  23.43mA    17.64mA    30.22mA
-863.6mV  20.47mA    15.4mA     26.29mA
-545.5mV  8.362mA    7.45mA     9.844mA
-363.6mV  5.436mA    5.819mA    5.88mA
772.7mV   0A         0A         0A
3V        0A         0A         0A
[GND_clamp]
-1.5V     -225.1mA   -137mA     -370.3mA
-1.318V   -152.8mA   -93.15mA   -251.8mA
-1.182V   -102.2mA   -63.02mA   -166.7mA
-1.136V   -86.57mA   -53.97mA   -139.9mA
-1.045V   -59.05mA   -38.44mA   -91.96mA
-954.5mV  -38.74mA   -27.29mA   -55.66mA
-863.6mV  -25.32mA   -19.89mA   -31.86mA
-772.7mV  -17.57mA   -14.88mA   -21.95mA
-636.4mV  -12.2mA    -10.78mA   -15.15mA
-409.1mV  -7.21mA    -7.259mA   -7.862mA
818.2mV   0A         0A         -37.95uA
3V        0A         0A         0A
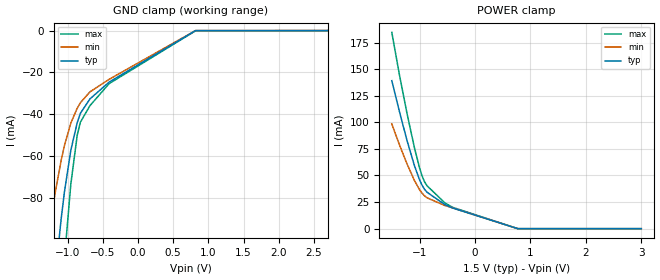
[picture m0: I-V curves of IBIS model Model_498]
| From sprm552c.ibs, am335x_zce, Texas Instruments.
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| Model based on original model for BCSHTLTCSCDVPBFZ_SSDHV
|   Sub model VREF_FULLTERM_9MA_5PER_1P5
[model]   Model_498
|[Description]  [1.5V-INPUT-FULLTERM:9MA-X, IND, 5%]
|   FULLTERM, 0.88 * RExt = 1.125 * Iout (I[2:0] = "100"), 9mA
|   nominal with Rext = 50R,Industrial temperature range (-40C to
|   125C, 25C nominal),5% power supply tolerance
|[Input Load]   FULLTERM:9MA
|[Output Drive]
|Voltage   1.5V
|Mode   INPUT
Model_type   Input
Polarity   Non-Inverting
Vinl =  0.65
Vinh =  0.85
C_comp   1.865048p   1.679967p   1.989968p
[Model Spec]
Vinl   0.65   0.6125   0.6875
Vinh   0.85   0.8125   0.8875
[Temperature Range]   25   125   -40
[Voltage Range]   1.5   1.425   1.575
[POWER_clamp]
-1.5V     139.1mA    98.42mA    184.5mA
-1.364V   110.3mA    79.03mA    145mA
-1.227V   83.11mA    61.03mA    108.6mA
-1.091V   59.07mA    45.16mA    75.88mA
-1V       45.98mA    36.66mA    57.18mA
-954.5mV  40.86mA    33.39mA    49.64mA
-909.1mV  36.96mA    30.86mA    44.03mA
-863.6mV  34.19mA    28.98mA    40.28mA
-545.5mV  22.7mA     21.84mA    24.33mA
-409.1mV  19.5mA     19.65mA    20.16mA
772.7mV   0A         0A         0A
3V        0A         0A         0A
[GND_clamp]
-1.5V     -239.5mA   -149.2mA   -384mA
-1.364V   -186.4mA   -117.7mA   -296mA
-1.182V   -119.6mA   -78.69mA   -183.2mA
-1.091V   -90.03mA   -62.05mA   -132mA
-1.045V   -77.29mA   -55.05mA   -109.5mA
-954.5mV  -57.35mA   -44.34mA   -73.62mA
-863.6mV  -44.14mA   -37.21mA   -50.16mA
-818.2mV  -39.62mA   -34.52mA   -43.85mA
-681.8mV  -32.7mA    -29.33mA   -35.92mA
-409.1mV  -24.64mA   -23.32mA   -25.38mA
818.2mV   0A         0A         -126.3uA
3V        0A         0A         0A
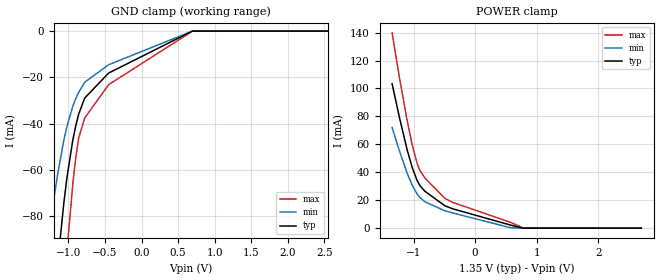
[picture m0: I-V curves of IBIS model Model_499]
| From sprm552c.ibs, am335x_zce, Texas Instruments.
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| Model based on original model for BCSHTLTCSCDVPBFZ_SSDHV
|   Sub model VREF_FULLTERM_7MA_10PER_1P35
[model]   Model_499
|[Description]  [1.35V-INPUT-FULLTERM:7MA-X, IND, 10%]
|   FULLTERM, 1.14 * RExt = 0.875 * Iout (I[2:0] = "010"), 7mA
|   nominal with Rext = 50R,Industrial temperature range (-40C to
|   125C, 25C nominal),10% power supply tolerance
|[Input Load]   FULLTERM:7MA
|[Output Drive]
|Voltage   1.35V
|Mode   INPUT
Model_type   Input
Polarity   Non-Inverting
Vinl =  0.585
Vinh =  0.765
C_comp   1.865048p   1.676829p   1.989968p
[Model Spec]
Vinl   0.585   0.5175   0.6525
Vinh   0.765   0.6975   0.8325
[Temperature Range]   25   125   -40
[Voltage Range]   1.35   1.215   1.485
[POWER_clamp]
-1.35V    103.4mA    72.02mA    139.8mA
-1.227V   78.5mA     54.82mA    106.9mA
-1.105V   56.03mA    39.32mA    77.07mA
-1.023V   43.42mA    30.7mA     59.63mA
-940.9mV  33.88mA    24.28mA    45.96mA
-900mV    30.63mA    22.01mA    41.43mA
-818.2mV  26.45mA    18.94mA    35.97mA
-490.9mV  16.01mA    12.42mA    21.28mA
-368.2mV  13.89mA    10.94mA    18.5mA
572.7mV   2.242mA    319.3uA    4.197mA
777.3mV   0A         0A         197.7uA
2.7V      0A         0A         0A
[GND_clamp]
-1.35V    -174.5mA   -105.5mA   -285.3mA
-1.227V   -128.5mA   -78.05mA   -208.1mA
-1.145V   -99.9mA    -61.48mA   -159.3mA
-1.064V   -74.59mA   -47.32mA   -115.2mA
-1.023V   -63.94mA   -41.5mA    -96.41mA
-940.9mV  -47.21mA   -32.56mA   -66.14mA
-900mV    -40.94mA   -29.22mA   -54.8mA
-859.1mV  -35.81mA   -26.42mA   -46.14mA
-777.3mV  -28.95mA   -22.1mA    -37.55mA
-450mV    -18.14mA   -14.55mA   -23.16mA
695.5mV   0A         0A         -49.61uA
2.7V      0A         0A         0A
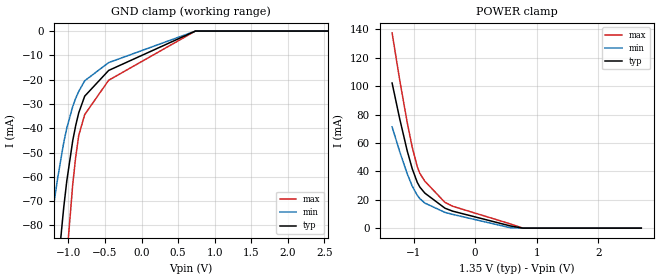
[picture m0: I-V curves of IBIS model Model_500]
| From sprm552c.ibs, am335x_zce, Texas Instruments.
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| Model based on original model for BCSHTLTCSCDVPBFZ_SSDHV
|   Sub model VREF_FULLTERM_6MA_10PER_1P35
[model]   Model_500
|[Description]  [1.35V-INPUT-FULLTERM:6MA-X, IND, 10%]
|   FULLTERM, 1.33 * RExt = 0.750 * Iout (I[2:0] = "001"), 6mA
|   nominal with Rext = 50R,Industrial temperature range (-40C to
|   125C, 25C nominal),10% power supply tolerance
|[Input Load]   FULLTERM:6MA
|[Output Drive]
|Voltage   1.35V
|Mode   INPUT
Model_type   Input
Polarity   Non-Inverting
Vinl =  0.585
Vinh =  0.765
C_comp   1.865048p   1.676829p   1.989968p
[Model Spec]
Vinl   0.585   0.5175   0.6525
Vinh   0.765   0.6975   0.8325
[Temperature Range]   25   125   -40
[Voltage Range]   1.35   1.215   1.485
[POWER_clamp]
-1.35V    102.2mA    71.31mA    137.5mA
-1.227V   77.12mA    53.99mA    104.5mA
-1.105V   54.54mA    38.37mA    74.56mA
-1.023V   41.88mA    29.65mA    57.03mA
-940.9mV  32.26mA    23.14mA    43.25mA
-900mV    28.97mA    20.83mA    38.66mA
-818.2mV  24.7mA     17.68mA    33.09mA
-490.9mV  14.06mA    11.11mA    18.14mA
-368.2mV  12mA       9.728mA    15.47mA
572.7mV   1.557mA    283.9uA    2.976mA
777.3mV   0A         0A         0A
2.7V      0A         0A         0A
[GND_clamp]
-1.35V    -172.6mA   -104.3mA   -282.6mA
-1.227V   -126.5mA   -76.72mA   -205.3mA
-1.145V   -97.82mA   -60.07mA   -156.3mA
-1.064V   -72.47mA   -45.84mA   -112.1mA
-1.023V   -61.79mA   -39.98mA   -93.3mA
-940.9mV  -45.05mA   -30.99mA   -62.99mA
-900mV    -38.77mA   -27.63mA   -51.64mA
-859.1mV  -33.64mA   -24.81mA   -42.96mA
-777.3mV  -26.78mA   -20.46mA   -34.35mA
-450mV    -16.21mA   -12.98mA   -20.25mA
736.4mV   0A         0A         0A
2.7V      0A         0A         0A
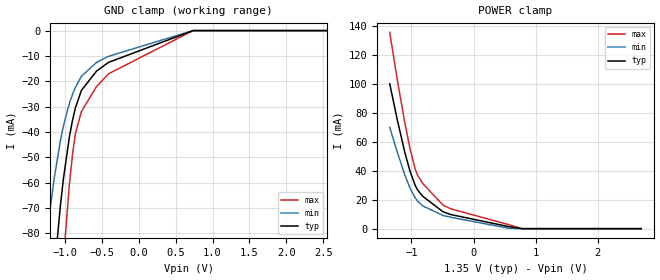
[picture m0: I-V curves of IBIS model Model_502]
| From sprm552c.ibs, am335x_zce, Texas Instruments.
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| Model based on original model for BCSHTLTCSCDVPBFZ_SSDHV
|   Sub model VREF_FULLTERM_5MA_10PER_1P35
[model]   Model_502
|[Description]  [1.35V-INPUT-FULLTERM:5MA-X, IND, 10%]
|   FULLTERM, 1.60 * RExt = 0.625 * Iout (I[2:0] = "000"), 5mA
|   nominal with Rext = 50R,Industrial temperature range (-40C to
|   125C, 25C nominal),10% power supply tolerance
|[Input Load]   FULLTERM:5MA
|[Output Drive]
|Voltage   1.35V
|Mode   INPUT
Model_type   Input
Polarity   Non-Inverting
Vinl =  0.585
Vinh =  0.765
C_comp   1.865048p   1.676829p   1.989968p
[Model Spec]
Vinl   0.585   0.5175   0.6525
Vinh   0.765   0.6975   0.8325
[Temperature Range]   25   125   -40
[Voltage Range]   1.35   1.215   1.485
[POWER_clamp]
-1.35V    100.3mA    70.24mA    135.9mA
-1.227V   75.14mA    52.75mA    102.8mA
-1.105V   52.45mA    36.94mA    72.86mA
-1.023V   39.74mA    28.09mA    55.3mA
-940.9mV  30.07mA    21.43mA    41.48mA
-900mV    26.74mA    19.05mA    36.87mA
-818.2mV  22.4mA     15.79mA    31.25mA
-490.9mV  11.68mA    9.131mA    16.26mA
-368.2mV  9.785mA    7.916mA    13.72mA
572.7mV   1.364mA    230.7uA    2.726mA
777.3mV   0A         0A         0A
2.7V      0A         0A         0A
[GND_clamp]
-1.35V    -170.1mA   -102.5mA   -280.6mA
-1.145V   -94.9mA    -57.96mA   -154.1mA
-1.064V   -69.44mA   -43.61mA   -109.9mA
-1.023V   -58.72mA   -37.71mA   -90.99mA
-940.9mV  -41.9mA    -28.63mA   -60.64mA
-900mV    -35.6mA    -25.24mA   -49.26mA
-859.1mV  -30.45mA   -22.39mA   -40.56mA
-777.3mV  -23.55mA   -18mA      -31.9mA
-572.7mV  -15.98mA   -12.57mA   -22.06mA
-409.1mV  -12.52mA   -10.14mA   -17.02mA
736.4mV   0A         0A         0A
2.7V      0A         0A         0A
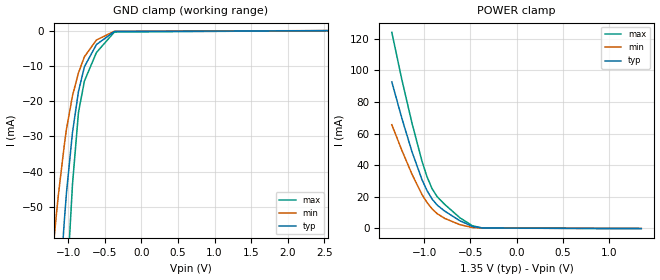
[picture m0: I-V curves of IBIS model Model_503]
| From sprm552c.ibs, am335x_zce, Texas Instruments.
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| Model based on original model for BCSHTLTCSCDVPBFZ_SSDHV
|   Sub model VREF_NOTERM_PU_ON_10PER_1P35
[model]   Model_503
|[Description]  [1.35V-INPUT-PU-X, IND, 10%]
|   Weak internal pull-up,Industrial temperature range (-40C to
|   125C, 25C nominal),10% power supply tolerance
|[Input Load]   PU
|[Output Drive]
|Voltage   1.35V
|Mode   INPUT
Model_type   Input
Polarity   Non-Inverting
Vinl =  0.585
Vinh =  0.765
C_comp   1.865048p   1.676829p   1.989968p
[Model Spec]
Vinl   0.585   0.5175   0.6525
Vinh   0.765   0.6975   0.8325
[Temperature Range]   25   125   -40
[Voltage Range]   1.35   1.215   1.485
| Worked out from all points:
|   GND clamp passes 1 mA (typ) near -0.48 V on its own axis
|   POWER clamp passes 1 mA (typ) near -0.46 V on its own axis
[POWER_clamp]
-1.35V    92.76mA    65.6mA     124.1mA
-1.241V   69.64mA    49.37mA    94.1mA
-1.132V   48.53mA    34.29mA    66.7mA
-1.023V   30.75mA    21.32mA    42.4mA
-968.2mV  23.82mA    16.26mA    32.53mA
-913.6mV  18.49mA    12.27mA    25.02mA
-859.1mV  14.72mA    9.283mA    20.03mA
-777.3mV  10.9mA     6.273mA    15.13mA
-613.6mV  4.778mA    2.313mA    6.68mA
-477.3mV  1.214mA    495.9uA    1.607mA
-368.2mV  166.4uA    76.08uA    187.2uA
1.35V     -148.7uA   -80.15uA   -221.3uA
[GND_clamp]
-1.35V    -159.2mA   -94.82mA   -266.4mA
-1.295V   -137.9mA   -81.83mA   -231.2mA
-1.159V   -87.47mA   -51.65mA   -146.3mA
-1.132V   -78.19mA   -46.24mA   -130.3mA
-1.05V    -53.18mA   -31.98mA   -86.92mA
-1.023V   -45.92mA   -27.9mA    -74.19mA
-940.9mV  -28.86mA   -18.47mA   -43.56mA
-859.1mV  -17.24mA   -11.97mA   -23.18mA
-777.3mV  -10.21mA   -7.395mA   -14.25mA
-613.6mV  -3.954mA   -2.671mA   -6.211mA
-368.2mV  -265.9uA   -181.7uA   -404uA
2.7V      0A         0A         0A
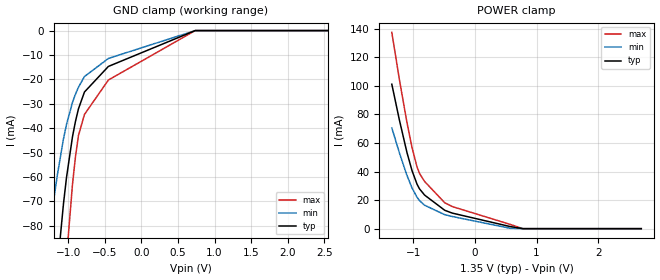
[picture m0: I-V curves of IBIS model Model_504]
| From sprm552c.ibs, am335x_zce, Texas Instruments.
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| Model based on original model for BCSHTLTCSCDVPBFZ_SSDHV
|   Sub model VREF_HALFTERM_11MA_10PER_1P35
[model]   Model_504
|[Description]  [1.35V-INPUT-HALFTERM:11MA-X, IND, 10%]
|   Half Thevenin termination (Rth = 100R whith RExt = 50R)
|   (ODT[1:0] = "11") VRef mode, 0.73 * RExt = 1.325 * Iout (I[2:0]
|   = "110"), 11mA nominal with Rext = 50R,Industrial temperature
|   range (-40C to 125C, 25C nominal),10% power supply tolerance
|[Input Load]   HALFTERM:11MA
|[Output Drive]
|Voltage   1.35V
|Mode   INPUT
Model_type   Input
Polarity   Non-Inverting
Vinl =  0.585
Vinh =  0.765
C_comp   1.865048p   1.676829p   1.989968p
[Model Spec]
Vinl   0.585   0.5175   0.6525
Vinh   0.765   0.6975   0.8325
[Temperature Range]   25   125   -40
[Voltage Range]   1.35   1.215   1.485
[POWER_clamp]
-1.35V    101.2mA    70.59mA    137.5mA
-1.227V   76.13mA    53.17mA    104.5mA
-1.105V   53.5mA     37.42mA    74.56mA
-1.023V   40.81mA    28.61mA    57.03mA
-940.9mV  31.17mA    22mA       43.25mA
-900mV    27.85mA    19.65mA    38.66mA
-818.2mV  23.55mA    16.42mA    33.09mA
-490.9mV  12.87mA    9.79mA     18.14mA
-368.2mV  10.89mA    8.52mA     15.47mA
572.7mV   1.46mA     248.4uA    2.976mA
777.3mV   0A         0A         0A
2.7V      0A         0A         0A
[GND_clamp]
-1.35V    -171.4mA   -103.1mA   -282.6mA
-1.227V   -125.1mA   -75.4mA    -205.3mA
-1.145V   -96.36mA   -58.66mA   -156.3mA
-1.064V   -70.95mA   -44.35mA   -112.1mA
-1.023V   -60.25mA   -38.47mA   -93.3mA
-940.9mV  -43.48mA   -29.42mA   -62.99mA
-900mV    -37.18mA   -26.03mA   -51.64mA
-859.1mV  -32.04mA   -23.19mA   -42.96mA
-777.3mV  -25.16mA   -18.82mA   -34.35mA
-450mV    -14.68mA   -11.41mA   -20.25mA
736.4mV   0A         0A         0A
2.7V      0A         0A         0A
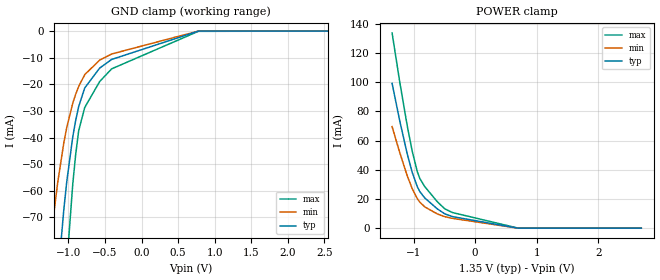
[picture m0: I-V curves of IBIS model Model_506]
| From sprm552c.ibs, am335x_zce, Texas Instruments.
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| Model based on original model for BCSHTLTCSCDVPBFZ_SSDHV
|   Sub model VREF_HALFTERM_8MA_10PER_1P35
[model]   Model_506
|[Description]  [1.35V-INPUT-HALFTERM:8MA-X, IND, 10%]
|   Half Thevenin termination (Rth = 100R whith RExt = 50R)
|   (ODT[1:0] = "11") VRef mode, 1.00 * RExt = 1.000 * Iout (I[2:0]
|   = "011"), 8mA nominal with Rext = 50R,Industrial temperature
|   range (-40C to 125C, 25C nominal),10% power supply tolerance
|[Input Load]   HALFTERM:8MA
|[Output Drive]
|Voltage   1.35V
|Mode   INPUT
Model_type   Input
Polarity   Non-Inverting
Vinl =  0.585
Vinh =  0.765
C_comp   1.865048p   1.676829p   1.989968p
[Model Spec]
Vinl   0.585   0.5175   0.6525
Vinh   0.765   0.6975   0.8325
[Temperature Range]   25   125   -40
[Voltage Range]   1.35   1.215   1.485
[POWER_clamp]
-1.35V    99.11mA    69.52mA    133.7mA
-1.227V   73.76mA    51.93mA    100.4mA
-1.105V   50.97mA    35.99mA    70.36mA
-1.023V   38.2mA     27.04mA    52.7mA
-940.9mV  28.45mA    20.29mA    38.77mA
-900mV    25.08mA    17.87mA    34.09mA
-818.2mV  20.65mA    14.53mA    28.37mA
-613.6mV  13.16mA    9.709mA    18.01mA
-490.9mV  9.727mA    7.814mA    13.13mA
-368.2mV  7.901mA    6.707mA    10.68mA
695.5mV   0A         0A         56.84uA
2.7V      0A         0A         0A
[GND_clamp]
-1.35V    -168.2mA   -101.4mA   -277.9mA
-1.145V   -92.83mA   -56.55mA   -151.1mA
-1.064V   -67.32mA   -42.13mA   -106.8mA
-1.023V   -56.57mA   -36.19mA   -87.87mA
-940.9mV  -39.74mA   -27.06mA   -57.49mA
-900mV    -33.43mA   -23.64mA   -46.1mA
-859.1mV  -28.28mA   -20.78mA   -37.38mA
-777.3mV  -21.38mA   -16.36mA   -28.71mA
-572.7mV  -13.9mA    -10.92mA   -18.96mA
-409.1mV  -10.66mA   -8.608mA   -14.19mA
777.3mV   0A         0A         -90.6uA
2.7V      0A         0A         0A
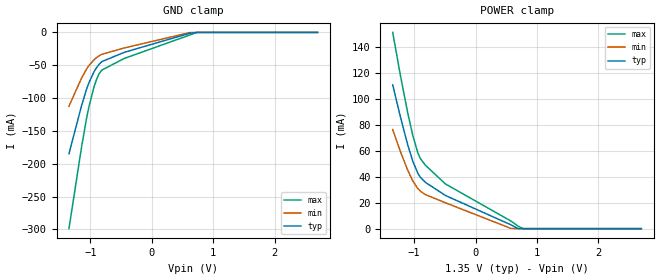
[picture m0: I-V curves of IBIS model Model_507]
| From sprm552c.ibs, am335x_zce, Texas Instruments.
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| Model based on original model for BCSHTLTCSCDVPBFZ_SSDHV
|   Sub model VREF_FULLTERM_12MA_10PER_1P35
[model]   Model_507
|[Description]  [1.35V-INPUT-FULLTERM:12MA-X, IND, 10%]
|   FULLTERM, 0.67 * RExt = 1.500 * Iout (I[2:0] = "111"), 12mA
|   nominal with Rext = 50R,Industrial temperature range (-40C to
|   125C, 25C nominal),10% power supply tolerance
|[Input Load]   FULLTERM:12MA
|[Output Drive]
|Voltage   1.35V
|Mode   INPUT
Model_type   Input
Polarity   Non-Inverting
Vinl =  0.585
Vinh =  0.765
C_comp   1.865048p   1.676829p   1.989968p
[Model Spec]
Vinl   0.585   0.5175   0.6525
Vinh   0.765   0.6975   0.8325
[Temperature Range]   25   125   -40
[Voltage Range]   1.35   1.215   1.485
[POWER_clamp]
-1.35V    110.7mA    76.22mA    151mA
-1.227V   86.44mA    59.66mA    118.5mA
-1.105V   64.39mA    44.87mA    88.94mA
-1.023V   51.96mA    36.76mA    71.73mA
-940.9mV  42.67mA    30.87mA    58.36mA
-900mV    39.56mA    28.86mA    54mA
-818.2mV  35.64mA    26.2mA     48.83mA
-490.9mV  25.51mA    19.91mA    34.4mA
572.7mV   3.013mA    237.6uA    5.943mA
695.5mV   0A         0A         1.892mA
777.3mV   0A         0A         0A
2.7V      0A         0A         0A
[GND_clamp]
-1.35V    -184.8mA   -112.4mA   -298.8mA
-1.145V   -111.6mA   -69.58mA   -174.6mA
-1.064V   -86.72mA   -55.87mA   -131.2mA
-1.023V   -76.24mA   -50.25mA   -112.6mA
-940.9mV  -59.79mA   -41.65mA   -82.65mA
-900mV    -53.62mA   -38.44mA   -71.47mA
-859.1mV  -48.58mA   -35.76mA   -62.98mA
-818.2mV  -44.64mA   -33.49mA   -57.62mA
-450mV    -30.38mA   -23.72mA   -39.68mA
613.6mV   -1.398mA   -415.2uA   -4.141mA
736.4mV   0A         0A         0A
2.7V      0A         0A         0A
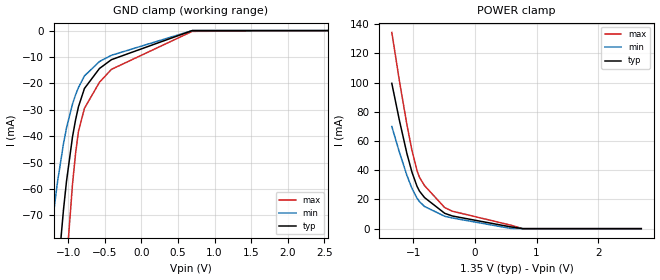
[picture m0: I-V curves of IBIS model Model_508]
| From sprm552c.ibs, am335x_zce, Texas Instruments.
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| Model based on original model for BCSHTLTCSCDVPBFZ_SSDHV
|   Sub model VREF_HALFTERM_9MA_10PER_1P35
[model]   Model_508
|[Description]  [1.35V-INPUT-HALFTERM:9MA-X, IND, 10%]
|   Half Thevenin termination (Rth = 100R whith RExt = 50R)
|   (ODT[1:0] = "11") VRef mode, 0.88 * RExt = 1.125 * Iout (I[2:0]
|   = "100"), 9mA nominal with Rext = 50R,Industrial temperature
|   range (-40C to 125C, 25C nominal),10% power supply tolerance
|[Input Load]   HALFTERM:9MA
|[Output Drive]
|Voltage   1.35V
|Mode   INPUT
Model_type   Input
Polarity   Non-Inverting
Vinl =  0.585
Vinh =  0.765
C_comp   1.865048p   1.676829p   1.989968p
[Model Spec]
Vinl   0.585   0.5175   0.6525
Vinh   0.765   0.6975   0.8325
[Temperature Range]   25   125   -40
[Voltage Range]   1.35   1.215   1.485
[POWER_clamp]
-1.35V    99.43mA    69.88mA    134.3mA
-1.227V   74.15mA    52.34mA    101.2mA
-1.105V   51.41mA    36.47mA    71.17mA
-1.023V   38.67mA    27.57mA    53.57mA
-940.9mV  28.97mA    20.86mA    39.71mA
-900mV    25.62mA    18.46mA    35.07mA
-818.2mV  21.25mA    15.16mA    29.42mA
-490.9mV  10.49mA    8.473mA    14.39mA
-368.2mV  8.676mA    7.311mA    11.96mA
572.7mV   1.267mA    213uA      2.476mA
777.3mV   0A         0A         0A
2.7V      0A         0A         0A
[GND_clamp]
-1.35V    -168.8mA   -102mA     -278.7mA
-1.145V   -93.44mA   -57.25mA   -151.9mA
-1.064V   -67.93mA   -42.87mA   -107.6mA
-1.023V   -57.18mA   -36.95mA   -88.68mA
-940.9mV  -40.33mA   -27.85mA   -58.28mA
-900mV    -34.02mA   -24.44mA   -46.88mA
-859.1mV  -28.85mA   -21.58mA   -38.15mA
-777.3mV  -21.93mA   -17.18mA   -29.46mA
-572.7mV  -14.38mA   -11.74mA   -19.61mA
-409.1mV  -11.03mA   -9.372mA   -14.7mA
695.5mV   0A         0A         -295.5uA
2.7V      0A         0A         0A
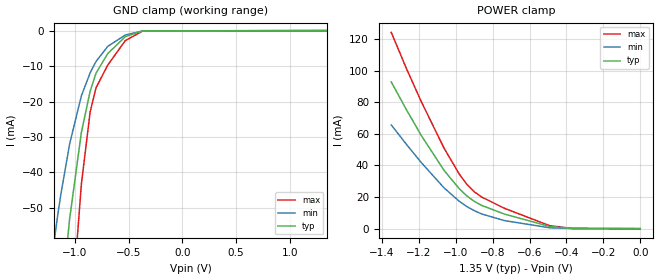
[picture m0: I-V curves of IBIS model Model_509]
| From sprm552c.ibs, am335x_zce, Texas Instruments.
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| Model based on original model for BCSHTLTCSCDVPBFZ_SSDHV
|   Sub model VREF_NOTERM_PUPD_OFF_10PER_1P35
[model]   Model_509
|[Description]  [1.35V-INPUT-PI-X, IND, 10%]
|   Weak pull up/down disabled,Industrial temperature range (-40C to
|   125C, 25C nominal),10% power supply tolerance
|[Input Load]   PI
|[Output Drive]
|Voltage   1.35V
|Mode   INPUT
Model_type   Input
Polarity   Non-Inverting
Vinl =  0.585
Vinh =  0.765
C_comp   1.865048p   1.676829p   1.989968p
[Model Spec]
Vinl   0.585   0.5175   0.6525
Vinh   0.765   0.6975   0.8325
[Temperature Range]   25   125   -40
[Voltage Range]   1.35   1.215   1.485
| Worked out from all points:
|   GND clamp passes 1 mA (typ) near -0.49 V on its own axis
|   POWER clamp passes 1 mA (typ) near -0.47 V on its own axis
[POWER_clamp]
-1.35V    92.76mA    65.6mA     124.1mA
-1.268V   75.25mA    53.33mA    101.3mA
-1.186V   58.7mA     41.62mA    80.03mA
-1.064V   36.89mA    25.82mA    50.95mA
-981.8mV  25.29mA    17.36mA    34.61mA
-940.9mV  20.77mA    14.04mA    28.16mA
-900mV    17.27mA    11.37mA    23.33mA
-859.1mV  14.66mA    9.269mA    19.95mA
-736.4mV  9.228mA    5.093mA    12.87mA
-490.9mV  1.4mA      568.3uA    1.869mA
-368.2mV  129.3uA    55.65uA    131.3uA
0V        1.192nA    12.62nA    1.338nA
[GND_clamp]
-1.35V    -159.2mA   -94.8mA    -266.4mA
-1.295V   -137.8mA   -81.81mA   -231.1mA
-1.159V   -87.4mA    -51.62mA   -146.2mA
-1.132V   -78.11mA   -46.21mA   -130.2mA
-1.05V    -53.09mA   -31.94mA   -86.76mA
-940.9mV  -28.74mA   -18.42mA   -43.35mA
-859.1mV  -17.11mA   -11.91mA   -22.96mA
-804.5mV  -12.02mA   -8.716mA   -16.14mA
-695.5mV  -6.497mA   -4.463mA   -9.741mA
-531.8mV  -1.706mA   -1.244mA   -2.822mA
-368.2mV  -80.01uA   -91.15uA   -104.9uA
1.35V     1.192nA    166.4nA    707pA
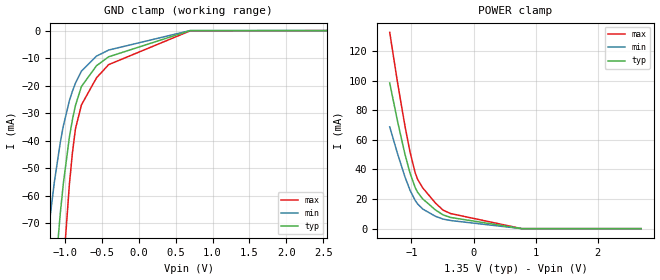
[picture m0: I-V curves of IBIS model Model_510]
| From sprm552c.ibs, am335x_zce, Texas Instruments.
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| Model based on original model for BCSHTLTCSCDVPBFZ_SSDHV
|   Sub model VREF_HALFTERM_7MA_10PER_1P35
[model]   Model_510
|[Description]  [1.35V-INPUT-HALFTERM:7MA-X, IND, 10%]
|   Half Thevenin termination (Rth = 100R whith RExt = 50R)
|   (ODT[1:0] = "11") VRef mode, 1.14 * RExt = 0.875 * Iout (I[2:0]
|   = "010"), 7mA nominal with Rext = 50R,Industrial temperature
|   range (-40C to 125C, 25C nominal),10% power supply tolerance
|[Input Load]   HALFTERM:7MA
|[Output Drive]
|Voltage   1.35V
|Mode   INPUT
Model_type   Input
Polarity   Non-Inverting
Vinl =  0.585
Vinh =  0.765
C_comp   1.865048p   1.676829p   1.989968p
[Model Spec]
Vinl   0.585   0.5175   0.6525
Vinh   0.765   0.6975   0.8325
[Temperature Range]   25   125   -40
[Voltage Range]   1.35   1.215   1.485
[POWER_clamp]
-1.35V    98.52mA    68.81mA    132.7mA
-1.227V   73.16mA    51.1mA     99.51mA
-1.105V   50.36mA    35.04mA    69.47mA
-1.023V   37.6mA     26mA       51.84mA
-940.9mV  27.87mA    19.15mA    37.94mA
-900mV    24.51mA    16.69mA    33.28mA
-818.2mV  20.1mA     13.27mA    27.58mA
-613.6mV  12.67mA    8.361mA    17.31mA
-490.9mV  9.299mA    6.497mA    12.51mA
-368.2mV  7.566mA    5.498mA    10.2mA
777.3mV   0A         0A         21.19uA
2.7V      0A         0A         0A
[GND_clamp]
-1.35V    -167.5mA   -100.2mA   -276.8mA
-1.145V   -91.98mA   -55.14mA   -149.7mA
-1.064V   -66.41mA   -40.65mA   -105.3mA
-1.023V   -55.64mA   -34.68mA   -86.37mA
-940.9mV  -38.76mA   -25.49mA   -55.92mA
-900mV    -32.43mA   -22.05mA   -44.5mA
-859.1mV  -27.26mA   -19.16mA   -35.75mA
-777.3mV  -20.32mA   -14.72mA   -27.01mA
-572.7mV  -12.77mA   -9.273mA   -17.17mA
-409.1mV  -9.54mA    -7.081mA   -12.39mA
695.5mV   0A         0A         -115.1uA
2.7V      0A         0A         0A
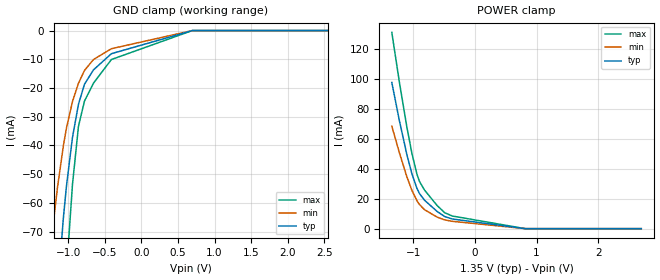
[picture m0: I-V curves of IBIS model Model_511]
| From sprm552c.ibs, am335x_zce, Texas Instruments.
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| Model based on original model for BCSHTLTCSCDVPBFZ_SSDHV
|   Sub model VREF_HALFTERM_6MA_10PER_1P35
[model]   Model_511
|[Description]  [1.35V-INPUT-HALFTERM:6MA-X, IND, 10%]
|   Half Thevenin termination (Rth = 100R whith RExt = 50R)
|   (ODT[1:0] = "11") VRef mode, 1.33 * RExt = 0.750 * Iout (I[2:0]
|   = "001"), 6mA nominal with Rext = 50R,Industrial temperature
|   range (-40C to 125C, 25C nominal),10% power supply tolerance
|[Input Load]   HALFTERM:6MA
|[Output Drive]
|Voltage   1.35V
|Mode   INPUT
Model_type   Input
Polarity   Non-Inverting
Vinl =  0.585
Vinh =  0.765
C_comp   1.865048p   1.676829p   1.989968p
[Model Spec]
Vinl   0.585   0.5175   0.6525
Vinh   0.765   0.6975   0.8325
[Temperature Range]   25   125   -40
[Voltage Range]   1.35   1.215   1.485
[POWER_clamp]
-1.35V    97.62mA    68.45mA    131.1mA
-1.227V   72.17mA    50.69mA    97.85mA
-1.105V   49.32mA    34.56mA    67.78mA
-1.023V   36.54mA    25.48mA    50.12mA
-940.9mV  26.78mA    18.58mA    36.17mA
-900mV    23.39mA    16.1mA     31.48mA
-818.2mV  18.96mA    12.64mA    25.74mA
-613.6mV  11.47mA    7.687mA    15.41mA
-490.9mV  8.11mA     5.839mA    10.64mA
-368.2mV  6.456mA    4.894mA    8.444mA
818.2mV   0A         0A         0A
2.7V      0A         0A         0A
[GND_clamp]
-1.35V    -166.2mA   -99.57mA   -274.8mA
-1.309V   -150.3mA   -89.94mA   -248.5mA
-1.145V   -90.52mA   -54.44mA   -147.5mA
-1.064V   -64.9mA    -39.9mA    -103mA
-1.023V   -54.11mA   -33.92mA   -84.06mA
-940.9mV  -37.19mA   -24.71mA   -53.56mA
-859.1mV  -25.66mA   -18.36mA   -33.34mA
-777.3mV  -18.71mA   -13.9mA    -24.56mA
-654.5mV  -13.7mA    -10.09mA   -18.33mA
-409.1mV  -8.047mA   -6.317mA   -10.08mA
695.5mV   0A         0A         0A
2.7V      0A         0A         0A
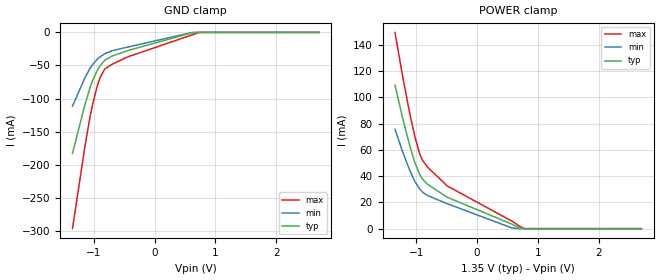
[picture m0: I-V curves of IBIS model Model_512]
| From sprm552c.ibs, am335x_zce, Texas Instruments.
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| Model based on original model for BCSHTLTCSCDVPBFZ_SSDHV
|   Sub model VREF_FULLTERM_11MA_10PER_1P35
[model]   Model_512
|[Description]  [1.35V-INPUT-FULLTERM:11MA-X, IND, 10%]
|   FULLTERM, 0.73 * RExt = 1.325 * Iout (I[2:0] = "110"), 11mA
|   nominal with Rext = 50R,Industrial temperature range (-40C to
|   125C, 25C nominal),10% power supply tolerance
|[Input Load]   FULLTERM:11MA
|[Output Drive]
|Voltage   1.35V
|Mode   INPUT
Model_type   Input
Polarity   Non-Inverting
Vinl =  0.585
Vinh =  0.765
C_comp   1.865048p   1.676829p   1.989968p
[Model Spec]
Vinl   0.585   0.5175   0.6525
Vinh   0.765   0.6975   0.8325
[Temperature Range]   25   125   -40
[Voltage Range]   1.35   1.215   1.485
[POWER_clamp]
-1.35V    109.2mA    75.59mA    149.4mA
-1.227V   84.84mA    58.95mA    116.8mA
-1.105V   62.74mA    44.08mA    87.24mA
-1.023V   50.3mA     35.92mA    70mA
-940.9mV  40.99mA    29.98mA    56.59mA
-900mV    37.88mA    27.94mA    52.2mA
-818.2mV  33.94mA    25.25mA    46.99mA
-490.9mV  23.9mA     19mA       32.52mA
572.7mV   3.409mA    496.3uA    5.694mA
695.5mV   383.7uA    0A         1.883mA
777.3mV   0A         0A         0A
2.7V      0A         0A         0A
[GND_clamp]
-1.35V    -182.9mA   -111.5mA   -296.9mA
-1.145V   -109.3mA   -68.53mA   -172.4mA
-1.064V   -84.3mA    -54.74mA   -128.9mA
-1.023V   -73.77mA   -49.09mA   -110.3mA
-940.9mV  -57.24mA   -40.42mA   -80.29mA
-900mV    -51.04mA   -37.19mA   -69.09mA
-818.2mV  -41.99mA   -32.2mA    -55.19mA
-695.5mV  -35.65mA   -27.66mA   -48.03mA
-450mV    -27.72mA   -22.39mA   -37.32mA
613.6mV   -655.8uA   -122.3uA   -3.794mA
736.4mV   0A         0A         0A
2.7V      0A         0A         0A
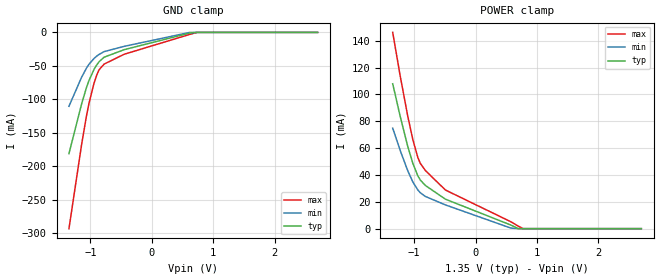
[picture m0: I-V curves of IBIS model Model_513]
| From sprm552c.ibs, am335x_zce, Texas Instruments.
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| Model based on original model for BCSHTLTCSCDVPBFZ_SSDHV
|   Sub model VREF_FULLTERM_10MA_10PER_1P35
[model]   Model_513
|[Description]  [1.35V-INPUT-FULLTERM:10MA-X, IND, 10%]
|   FULLTERM, 0.80 * RExt = 1.250 * Iout (I[2:0] = "101"), 10mA
|   nominal with Rext = 50R,Industrial temperature range (-40C to
|   125C, 25C nominal),10% power supply tolerance
|[Input Load]   FULLTERM:10MA
|[Output Drive]
|Voltage   1.35V
|Mode   INPUT
Model_type   Input
Polarity   Non-Inverting
Vinl =  0.585
Vinh =  0.765
C_comp   1.865048p   1.676829p   1.989968p
[Model Spec]
Vinl   0.585   0.5175   0.6525
Vinh   0.765   0.6975   0.8325
[Temperature Range]   25   125   -40
[Voltage Range]   1.35   1.215   1.485
[POWER_clamp]
-1.35V    107.9mA    74.88mA    146.2mA
-1.227V   83.46mA    58.13mA    113.5mA
-1.105V   61.25mA    43.13mA    83.85mA
-1.023V   48.76mA    34.87mA    66.54mA
-940.9mV  39.37mA    28.84mA    53.04mA
-900mV    36.21mA    26.75mA    48.61mA
-818.2mV  32.19mA    23.99mA    43.32mA
-490.9mV  21.95mA    17.69mA    28.77mA
572.7mV   2.724mA    461uA      5.195mA
695.5mV   0A         0A         1.865mA
777.3mV   0A         0A         0A
2.7V      0A         0A         0A
[GND_clamp]
-1.35V    -181mA     -110.3mA   -293mA
-1.145V   -107.2mA   -67.12mA   -168mA
-1.064V   -82.17mA   -53.26mA   -124.3mA
-1.023V   -71.63mA   -47.57mA   -105.7mA
-940.9mV  -55.08mA   -38.85mA   -75.57mA
-900mV    -48.86mA   -35.6mA    -64.32mA
-859.1mV  -43.79mA   -32.87mA   -55.76mA
-777.3mV  -37.02mA   -28.67mA   -47.34mA
-450mV    -25.79mA   -20.82mA   -32.6mA
613.6mV   -1.022mA   -113.6uA   -3.101mA
736.4mV   0A         0A         0A
2.7V      0A         0A         0A
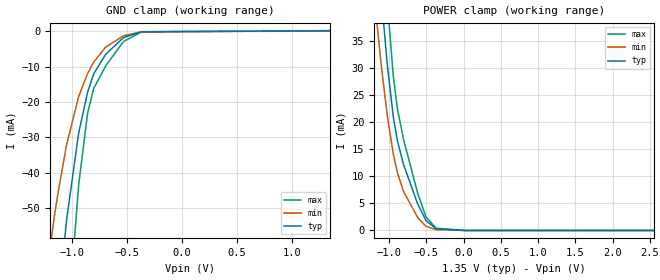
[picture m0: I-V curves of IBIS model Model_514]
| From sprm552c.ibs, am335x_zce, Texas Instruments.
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| Model based on original model for BCSHTLTCSCDVPBFZ_SSDHV
|   Sub model VREF_NOTERM_PD_ON_10PER_1P35
[model]   Model_514
|[Description]  [1.35V-INPUT-PD-X, IND, 10%]
|   Weak internal pull-down,Industrial temperature range (-40C to
|   125C, 25C nominal),10% power supply tolerance
|[Input Load]   PD
|[Output Drive]
|Voltage   1.35V
|Mode   INPUT
Model_type   Input
Polarity   Non-Inverting
Vinl =  0.585
Vinh =  0.765
C_comp   1.865048p   1.676829p   1.989968p
[Model Spec]
Vinl   0.585   0.5175   0.6525
Vinh   0.765   0.6975   0.8325
[Temperature Range]   25   125   -40
[Voltage Range]   1.35   1.215   1.485
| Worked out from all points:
|   GND clamp passes 1 mA (typ) near -0.49 V on its own axis
|   POWER clamp passes 1 mA (typ) near -0.46 V on its own axis
[POWER_clamp]
-1.35V    92.77mA    65.61mA    124.1mA
-1.241V   69.66mA    49.38mA    94.14mA
-1.105V   43.7mA     30.78mA    60.34mA
-1.023V   30.81mA    21.33mA    42.59mA
-940.9mV  20.93mA    14.07mA    28.46mA
-886.4mV  16.59mA    10.71mA    22.51mA
-804.5mV  12.22mA    7.229mA    16.87mA
-613.6mV  4.868mA    2.358mA    6.826mA
-504.5mV  1.851mA    789.7uA    2.541mA
-368.2mV  308.5uA    146.6uA    418.8uA
13.64mV   0A         0A         0A
2.7V      0A         0A         0A
[GND_clamp]
-1.35V    -159.2mA   -94.81mA   -266.4mA
-1.295V   -137.9mA   -81.81mA   -231.1mA
-1.159V   -87.42mA   -51.63mA   -146.2mA
-1.132V   -78.13mA   -46.22mA   -130.3mA
-1.05V    -53.12mA   -31.95mA   -86.8mA
-940.9mV  -28.77mA   -18.44mA   -43.4mA
-859.1mV  -17.15mA   -11.93mA   -23.02mA
-804.5mV  -12.06mA   -8.733mA   -16.2mA
-695.5mV  -6.535mA   -4.481mA   -9.797mA
-531.8mV  -1.749mA   -1.265mA   -2.882mA
-368.2mV  -120.9uA   -112.6uA   -165.3uA
1.35V     149.5uA    80.98uA    220.8uA
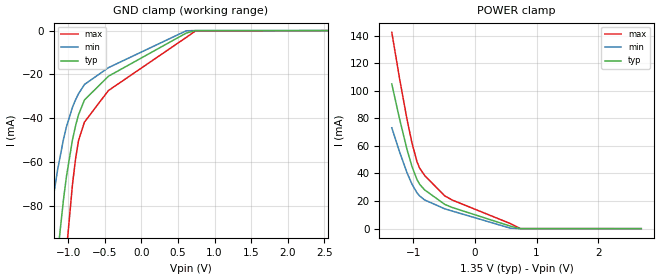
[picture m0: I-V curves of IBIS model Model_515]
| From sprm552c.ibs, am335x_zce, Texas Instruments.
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| Model based on original model for BCSHTLTCSCDVPBFZ_SSDHV
|   Sub model VREF_FULLTERM_8MA_10PER_1P35
[model]   Model_515
|[Description]  [1.35V-INPUT-FULLTERM:8MA-X, IND, 10%]
|   FULLTERM, 1.00 * RExt = 1.000 * Iout (I[2:0] = "011"), 8mA
|   nominal with Rext = 50R,Industrial temperature range (-40C to
|   125C, 25C nominal),10% power supply tolerance
|[Input Load]   FULLTERM:8MA
|[Output Drive]
|Voltage   1.35V
|Mode   INPUT
Model_type   Input
Polarity   Non-Inverting
Vinl =  0.585
Vinh =  0.765
C_comp   1.865048p   1.676829p   1.989968p
[Model Spec]
Vinl   0.585   0.5175   0.6525
Vinh   0.765   0.6975   0.8325
[Temperature Range]   25   125   -40
[Voltage Range]   1.35   1.215   1.485
[POWER_clamp]
-1.35V    104.9mA    73.09mA    142.3mA
-1.227V   80.1mA     56.06mA    109.5mA
-1.105V   57.68mA    40.75mA    79.65mA
-1.023V   45.08mA    32.26mA    62.21mA
-940.9mV  35.56mA    25.99mA    48.56mA
-900mV    32.32mA    23.79mA    44.04mA
-818.2mV  28.14mA    20.83mA    38.6mA
-490.9mV  17.62mA    14.4mA     23.76mA
-368.2mV  15.33mA    12.75mA    20.74mA
572.7mV   1.847mA    372.5uA    3.726mA
736.4mV   0A         0A         36.5uA
2.7V      0A         0A         0A
[GND_clamp]
-1.35V    -176.5mA   -107.3mA   -288.4mA
-1.145V   -102.2mA   -63.59mA   -162.8mA
-1.064V   -77.01mA   -49.55mA   -119mA
-1.023V   -66.4mA    -43.78mA   -100.2mA
-940.9mV  -49.76mA   -34.92mA   -70.07mA
-900mV    -43.52mA   -31.61mA   -58.78mA
-859.1mV  -38.43mA   -28.84mA   -50.18mA
-777.3mV  -31.62mA   -24.56mA   -41.69mA
-450mV    -20.8mA    -16.9mA    -27.33mA
613.6mV   -1.138mA   -91.78uA   -3.115mA
736.4mV   0A         0A         -246.9uA
2.7V      0A         0A         0A
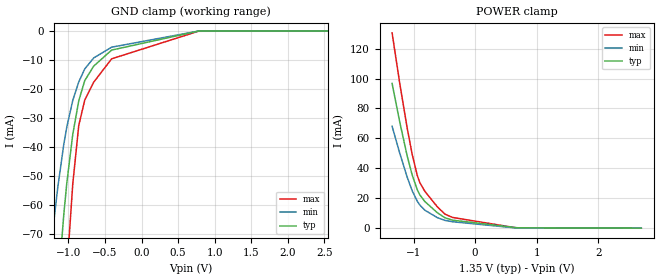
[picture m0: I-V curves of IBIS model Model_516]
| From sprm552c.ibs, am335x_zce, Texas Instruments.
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| Model based on original model for BCSHTLTCSCDVPBFZ_SSDHV
|   Sub model VREF_HALFTERM_5MA_10PER_1P35
[model]   Model_516
|[Description]  [1.35V-INPUT-HALFTERM:5MA-X, IND, 10%]
|   Half Thevenin termination (Rth = 100R whith RExt = 50R)
|   (ODT[1:0] = "11") VRef mode, 1.60 * RExt = 0.625 * Iout (I[2:0]
|   = "000"), 5mA nominal with Rext = 50R,Industrial temperature
|   range (-40C to 125C, 25C nominal),10% power supply tolerance
|[Input Load]   HALFTERM:5MA
|[Output Drive]
|Voltage   1.35V
|Mode   INPUT
Model_type   Input
Polarity   Non-Inverting
Vinl =  0.585
Vinh =  0.765
C_comp   1.865048p   1.676829p   1.989968p
[Model Spec]
Vinl   0.585   0.5175   0.6525
Vinh   0.765   0.6975   0.8325
[Temperature Range]   25   125   -40
[Voltage Range]   1.35   1.215   1.485
[POWER_clamp]
-1.35V    96.71mA    68.09mA    130.5mA
-1.227V   71.18mA    50.28mA    97.11mA
-1.105V   48.27mA    34.09mA    66.97mA
-1.023V   35.47mA    24.96mA    49.24mA
-940.9mV  25.68mA    18.02mA    35.23mA
-900mV    22.28mA    15.5mA     30.51mA
-818.2mV  17.81mA    12.01mA    24.7mA
-613.6mV  10.27mA    7.013mA    14.22mA
-490.9mV  6.92mA     5.18mA     9.375mA
-368.2mV  5.346mA    4.289mA    7.168mA
695.5mV   243uA      0A         37.91uA
2.7V      0A         0A         0A
[GND_clamp]
-1.35V    -164.9mA   -98.97mA   -274.1mA
-1.309V   -149mA     -89.32mA   -247.8mA
-1.145V   -89.06mA   -53.74mA   -146.7mA
-1.064V   -63.38mA   -39.16mA   -102.2mA
-1.023V   -52.57mA   -33.16mA   -83.25mA
-940.9mV  -35.62mA   -23.92mA   -52.77mA
-859.1mV  -24.07mA   -17.55mA   -32.57mA
-777.3mV  -17.09mA   -13.08mA   -23.82mA
-654.5mV  -12.08mA   -9.264mA   -17.63mA
-409.1mV  -6.554mA   -5.553mA   -9.566mA
777.3mV   0A         0A         -60.43uA
2.7V      0A         0A         0A
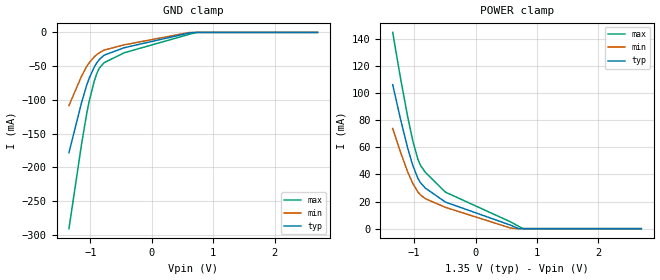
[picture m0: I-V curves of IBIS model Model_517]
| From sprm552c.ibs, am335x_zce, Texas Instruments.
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| Model based on original model for BCSHTLTCSCDVPBFZ_SSDHV
|   Sub model VREF_FULLTERM_9MA_10PER_1P35
[model]   Model_517
|[Description]  [1.35V-INPUT-FULLTERM:9MA-X, IND, 10%]
|   FULLTERM, 0.88 * RExt = 1.125 * Iout (I[2:0] = "100"), 9mA
|   nominal with Rext = 50R,Industrial temperature range (-40C to
|   125C, 25C nominal),10% power supply tolerance
|[Input Load]   FULLTERM:9MA
|[Output Drive]
|Voltage   1.35V
|Mode   INPUT
Model_type   Input
Polarity   Non-Inverting
Vinl =  0.585
Vinh =  0.765
C_comp   1.865048p   1.676829p   1.989968p
[Model Spec]
Vinl   0.585   0.5175   0.6525
Vinh   0.765   0.6975   0.8325
[Temperature Range]   25   125   -40
[Voltage Range]   1.35   1.215   1.485
[POWER_clamp]
-1.35V    106.1mA    73.81mA    144.6mA
-1.227V   81.48mA    56.89mA    111.9mA
-1.105V   59.16mA    41.7mA     82.15mA
-1.023V   46.62mA    33.31mA    64.81mA
-940.9mV  37.18mA    27.13mA    51.27mA
-900mV    33.98mA    24.98mA    46.82mA
-818.2mV  29.89mA    22.09mA    41.48mA
-490.9mV  19.57mA    15.71mA    26.9mA
572.7mV   2.532mA    407.9uA    4.946mA
695.5mV   72.46uA    0A         1.856mA
777.3mV   0A         0A         0A
2.7V      0A         0A         0A
[GND_clamp]
-1.35V    -178.4mA   -108.5mA   -291.1mA
-1.145V   -104.3mA   -65mA      -165.8mA
-1.064V   -79.14mA   -51.03mA   -122mA
-1.023V   -68.55mA   -45.29mA   -103.3mA
-940.9mV  -51.93mA   -36.49mA   -73.22mA
-900mV    -45.69mA   -33.21mA   -61.94mA
-859.1mV  -40.6mA    -30.45mA   -53.35mA
-777.3mV  -33.79mA   -26.2mA    -44.89mA
-450mV    -22.73mA   -18.47mA   -30.24mA
613.6mV   -771.8uA   -100.5uA   -2.755mA
736.4mV   0A         0A         0A
2.7V      0A         0A         0A
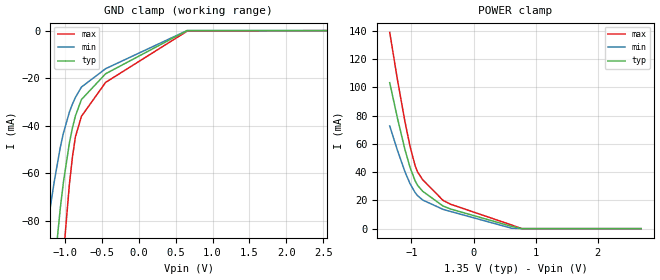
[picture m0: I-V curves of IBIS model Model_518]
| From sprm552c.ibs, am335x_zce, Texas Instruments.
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| Model based on original model for BCSHTLTCSCDVPBFZ_SSDHV
|   Sub model VREF_FULLTERM_7MA_5PER_1P35
[model]   Model_518
|[Description]  [1.35V-INPUT-FULLTERM:7MA-X, IND, 5%]
|   FULLTERM, 1.14 * RExt = 0.875 * Iout (I[2:0] = "010"), 7mA
|   nominal with Rext = 50R,Industrial temperature range (-40C to
|   125C, 25C nominal),5% power supply tolerance
|[Input Load]   FULLTERM:7MA
|[Output Drive]
|Voltage   1.35V
|Mode   INPUT
Model_type   Input
Polarity   Non-Inverting
Vinl =  0.585
Vinh =  0.765
C_comp   1.865048p   1.679967p   1.989968p
[Model Spec]
Vinl   0.585   0.551   0.618
Vinh   0.765   0.731   0.798
[Temperature Range]   25   125   -40
[Voltage Range]   1.35   1.2825   1.4175
[POWER_clamp]
-1.35V    103.4mA    72.71mA    139mA
-1.227V   78.5mA     55.65mA    105.9mA
-1.105V   56.03mA    40.34mA    75.85mA
-1.023V   43.42mA    31.87mA    58.29mA
-940.9mV  33.88mA    25.55mA    44.59mA
-900mV    30.63mA    23.31mA    40.05mA
-818.2mV  26.45mA    20.25mA    34.6mA
-490.9mV  16.01mA    13.66mA    20.02mA
-368.2mV  13.89mA    12.15mA    17.27mA
613.6mV   1.6mA      294uA      2.596mA
777.3mV   0A         0A         0A
2.7V      0A         0A         0A
[GND_clamp]
-1.35V    -174.5mA   -107mA     -283.7mA
-1.227V   -128.5mA   -79.69mA   -206.6mA
-1.145V   -99.9mA    -63.18mA   -157.7mA
-1.064V   -74.59mA   -49.03mA   -113.6mA
-1.023V   -63.94mA   -43.2mA    -94.85mA
-940.9mV  -47.21mA   -34.24mA   -64.58mA
-900mV    -40.94mA   -30.88mA   -53.24mA
-859.1mV  -35.81mA   -28.07mA   -44.58mA
-777.3mV  -28.95mA   -23.72mA   -36.01mA
-450mV    -18.14mA   -16.01mA   -21.76mA
654.5mV   0A         0A         -254.3uA
2.7V      0A         0A         0A
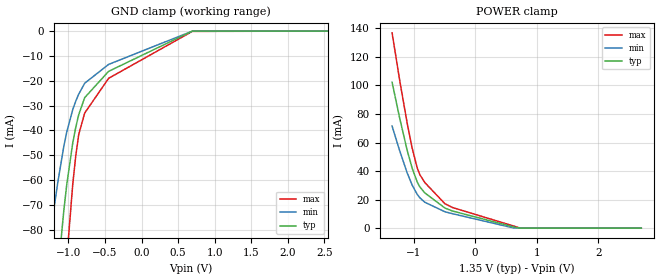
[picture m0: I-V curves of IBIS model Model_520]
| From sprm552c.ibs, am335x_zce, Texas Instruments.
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| Model based on original model for BCSHTLTCSCDVPBFZ_SSDHV
|   Sub model VREF_HALFTERM_12MA_5PER_1P35
[model]   Model_520
|[Description]  [1.35V-INPUT-HALFTERM:12MA-X, IND, 5%]
|   Half Thevenin termination (Rth = 100R whith RExt = 50R)
|   (ODT[1:0] = "11") VRef mode, 0.67 * RExt = 1.500 * Iout (I[2:0]
|   = "111"), 12mA nominal with Rext = 50R,Industrial temperature
|   range (-40C to 125C, 25C nominal),5% power supply tolerance
|[Input Load]   HALFTERM:12MA
|[Output Drive]
|Voltage   1.35V
|Mode   INPUT
Model_type   Input
Polarity   Non-Inverting
Vinl =  0.585
Vinh =  0.765
C_comp   1.865048p   1.679967p   1.989968p
[Model Spec]
Vinl   0.585   0.551   0.618
Vinh   0.765   0.731   0.798
[Temperature Range]   25   125   -40
[Voltage Range]   1.35   1.2825   1.4175
[POWER_clamp]
-1.35V    102.2mA    71.52mA    136.8mA
-1.227V   77.12mA    54.27mA    103.7mA
-1.105V   54.54mA    38.74mA    73.55mA
-1.023V   41.88mA    30.11mA    55.92mA
-940.9mV  32.26mA    23.63mA    42.11mA
-900mV    28.97mA    21.32mA    37.51mA
-818.2mV  24.7mA     18.15mA    31.95mA
-490.9mV  14.06mA    11.48mA    17.1mA
-368.2mV  12mA       10.13mA    14.46mA
613.6mV   990.8uA    245uA      1.646mA
736.4mV   0A         0A         0A
2.7V      0A         0A         0A
[GND_clamp]
-1.35V    -172.6mA   -104.9mA   -281.1mA
-1.227V   -126.5mA   -77.43mA   -203.9mA
-1.145V   -97.82mA   -60.79mA   -154.9mA
-1.064V   -72.47mA   -46.52mA   -110.7mA
-1.023V   -61.79mA   -40.64mA   -91.92mA
-940.9mV  -45.05mA   -31.6mA    -61.62mA
-900mV    -38.77mA   -28.22mA   -50.27mA
-859.1mV  -33.64mA   -25.37mA   -41.59mA
-777.3mV  -26.78mA   -20.99mA   -32.99mA
-450mV    -16.21mA   -13.41mA   -19.01mA
695.5mV   0A         0A         -113.2uA
2.7V      0A         0A         0A
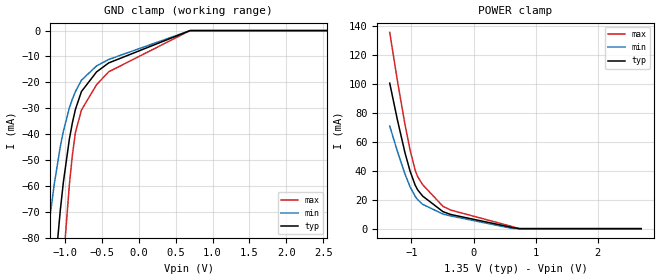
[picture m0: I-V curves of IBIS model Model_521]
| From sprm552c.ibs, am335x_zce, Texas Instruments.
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| Model based on original model for BCSHTLTCSCDVPBFZ_SSDHV
|   Sub model VREF_FULLTERM_5MA_5PER_1P35
[model]   Model_521
|[Description]  [1.35V-INPUT-FULLTERM:5MA-X, IND, 5%]
|   FULLTERM, 1.60 * RExt = 0.625 * Iout (I[2:0] = "000"), 5mA
|   nominal with Rext = 50R,Industrial temperature range (-40C to
|   125C, 25C nominal),5% power supply tolerance
|[Input Load]   FULLTERM:5MA
|[Output Drive]
|Voltage   1.35V
|Mode   INPUT
Model_type   Input
Polarity   Non-Inverting
Vinl =  0.585
Vinh =  0.765
C_comp   1.865048p   1.679967p   1.989968p
[Model Spec]
Vinl   0.585   0.551   0.618
Vinh   0.765   0.731   0.798
[Temperature Range]   25   125   -40
[Voltage Range]   1.35   1.2825   1.4175
[POWER_clamp]
-1.35V    100.3mA    70.73mA    135.3mA
-1.227V   75.14mA    53.35mA    102.1mA
-1.105V   52.45mA    37.68mA    71.97mA
-1.023V   39.74mA    28.94mA    54.31mA
-940.9mV  30.07mA    22.35mA    40.46mA
-900mV    26.74mA    19.99mA    35.84mA
-818.2mV  22.4mA     16.74mA    30.23mA
-490.9mV  11.68mA    10.03mA    15.34mA
-368.2mV  9.785mA    8.791mA    12.82mA
613.6mV   906.3uA    212.4uA    1.547mA
736.4mV   0A         0A         0A
2.7V      0A         0A         0A
[GND_clamp]
-1.35V    -170.1mA   -103.6mA   -279.4mA
-1.145V   -94.9mA    -59.19mA   -152.9mA
-1.064V   -69.44mA   -44.85mA   -108.6mA
-1.023V   -58.72mA   -38.94mA   -89.78mA
-940.9mV  -41.9mA    -29.85mA   -59.43mA
-900mV    -35.6mA    -26.44mA   -48.06mA
-859.1mV  -30.45mA   -23.58mA   -39.35mA
-777.3mV  -23.55mA   -19.17mA   -30.71mA
-572.7mV  -15.98mA   -13.66mA   -20.93mA
-409.1mV  -12.52mA   -11.17mA   -15.95mA
695.5mV   0A         0A         -3.745uA
2.7V      0A         0A         0A
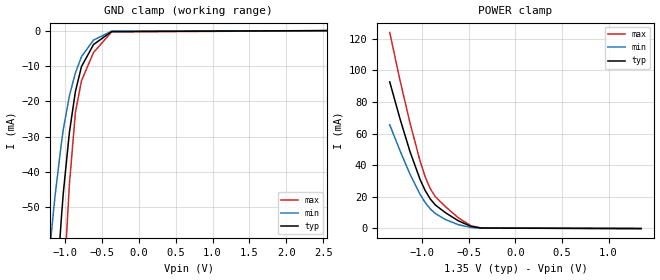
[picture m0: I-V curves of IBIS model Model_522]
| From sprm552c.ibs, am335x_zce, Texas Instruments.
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| Model based on original model for BCSHTLTCSCDVPBFZ_SSDHV
|   Sub model VREF_NOTERM_PU_ON_5PER_1P35
[model]   Model_522
|[Description]  [1.35V-INPUT-PU-X, IND, 5%]
|   Weak internal pull-up,Industrial temperature range (-40C to
|   125C, 25C nominal),5% power supply tolerance
|[Input Load]   PU
|[Output Drive]
|Voltage   1.35V
|Mode   INPUT
Model_type   Input
Polarity   Non-Inverting
Vinl =  0.585
Vinh =  0.765
C_comp   1.865048p   1.679967p   1.989968p
[Model Spec]
Vinl   0.585   0.551   0.618
Vinh   0.765   0.731   0.798
[Temperature Range]   25   125   -40
[Voltage Range]   1.35   1.2825   1.4175
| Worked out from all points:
|   GND clamp passes 1 mA (typ) near -0.48 V on its own axis
|   POWER clamp passes 1 mA (typ) near -0.46 V on its own axis
[POWER_clamp]
-1.35V    92.76mA    65.58mA    124.1mA
-1.241V   69.64mA    49.36mA    94.1mA
-1.132V   48.53mA    34.28mA    66.69mA
-1.023V   30.75mA    21.32mA    42.36mA
-968.2mV  23.82mA    16.26mA    32.48mA
-913.6mV  18.49mA    12.27mA    24.96mA
-859.1mV  14.72mA    9.299mA    19.97mA
-750mV    9.818mA    5.52mA     13.63mA
-613.6mV  4.778mA    2.313mA    6.679mA
-477.3mV  1.214mA    496.3uA    1.606mA
-368.2mV  166.4uA    76.26uA    186.9uA
1.35V     -148.7uA   -80.7uA    -220.1uA
[GND_clamp]
-1.35V    -159.2mA   -94.82mA   -266.4mA
-1.295V   -137.9mA   -81.83mA   -231.2mA
-1.159V   -87.47mA   -51.66mA   -146.3mA
-1.132V   -78.19mA   -46.25mA   -130.3mA
-1.05V    -53.18mA   -31.98mA   -86.9mA
-1.023V   -45.92mA   -27.91mA   -74.18mA
-940.9mV  -28.86mA   -18.48mA   -43.55mA
-859.1mV  -17.24mA   -11.97mA   -23.17mA
-777.3mV  -10.21mA   -7.399mA   -14.24mA
-613.6mV  -3.954mA   -2.675mA   -6.201mA
-368.2mV  -265.9uA   -186.6uA   -391.2uA
2.7V      0A         0A         0A
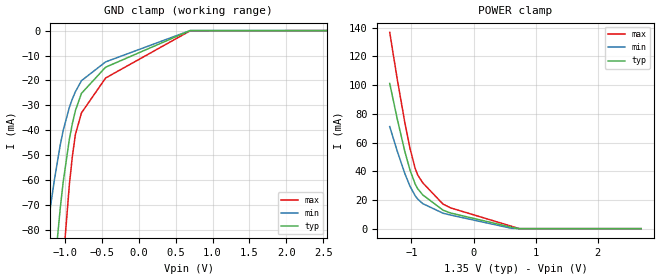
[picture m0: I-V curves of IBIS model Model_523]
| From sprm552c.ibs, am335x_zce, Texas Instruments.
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| Model based on original model for BCSHTLTCSCDVPBFZ_SSDHV
|   Sub model VREF_HALFTERM_11MA_5PER_1P35
[model]   Model_523
|[Description]  [1.35V-INPUT-HALFTERM:11MA-X, IND, 5%]
|   Half Thevenin termination (Rth = 100R whith RExt = 50R)
|   (ODT[1:0] = "11") VRef mode, 0.73 * RExt = 1.325 * Iout (I[2:0]
|   = "110"), 11mA nominal with Rext = 50R,Industrial temperature
|   range (-40C to 125C, 25C nominal),5% power supply tolerance
|[Input Load]   HALFTERM:11MA
|[Output Drive]
|Voltage   1.35V
|Mode   INPUT
Model_type   Input
Polarity   Non-Inverting
Vinl =  0.585
Vinh =  0.765
C_comp   1.865048p   1.679967p   1.989968p
[Model Spec]
Vinl   0.585   0.551   0.618
Vinh   0.765   0.731   0.798
[Temperature Range]   25   125   -40
[Voltage Range]   1.35   1.2825   1.4175
[POWER_clamp]
-1.35V    101.2mA    71.12mA    136.8mA
-1.227V   76.13mA    53.81mA    103.7mA
-1.105V   53.5mA     38.21mA    73.55mA
-1.023V   40.81mA    29.52mA    55.92mA
-940.9mV  31.17mA    22.99mA    42.11mA
-900mV    27.85mA    20.65mA    37.51mA
-818.2mV  23.55mA    17.45mA    31.95mA
-490.9mV  12.87mA    10.75mA    17.1mA
-368.2mV  10.89mA    9.462mA    14.46mA
613.6mV   948.6uA    228.7uA    1.646mA
736.4mV   0A         0A         0A
2.7V      0A         0A         0A
[GND_clamp]
-1.35V    -171.4mA   -104.3mA   -281.1mA
-1.227V   -125.1mA   -76.68mA   -203.9mA
-1.145V   -96.36mA   -59.99mA   -154.9mA
-1.064V   -70.95mA   -45.68mA   -110.7mA
-1.023V   -60.25mA   -39.79mA   -91.92mA
-940.9mV  -43.48mA   -30.73mA   -61.62mA
-900mV    -37.18mA   -27.33mA   -50.27mA
-859.1mV  -32.04mA   -24.48mA   -41.59mA
-777.3mV  -25.16mA   -20.08mA   -32.99mA
-450mV    -14.68mA   -12.55mA   -19.01mA
695.5mV   0A         0A         -113.2uA
2.7V      0A         0A         0A
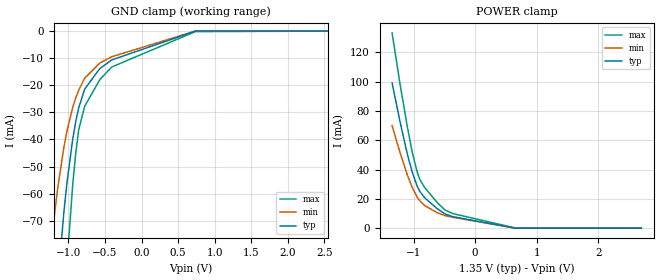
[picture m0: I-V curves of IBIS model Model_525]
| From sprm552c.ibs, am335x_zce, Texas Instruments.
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| Model based on original model for BCSHTLTCSCDVPBFZ_SSDHV
|   Sub model VREF_HALFTERM_8MA_5PER_1P35
[model]   Model_525
|[Description]  [1.35V-INPUT-HALFTERM:8MA-X, IND, 5%]
|   Half Thevenin termination (Rth = 100R whith RExt = 50R)
|   (ODT[1:0] = "11") VRef mode, 1.00 * RExt = 1.000 * Iout (I[2:0]
|   = "011"), 8mA nominal with Rext = 50R,Industrial temperature
|   range (-40C to 125C, 25C nominal),5% power supply tolerance
|[Input Load]   HALFTERM:8MA
|[Output Drive]
|Voltage   1.35V
|Mode   INPUT
Model_type   Input
Polarity   Non-Inverting
Vinl =  0.585
Vinh =  0.765
C_comp   1.865048p   1.679967p   1.989968p
[Model Spec]
Vinl   0.585   0.551   0.618
Vinh   0.765   0.731   0.798
[Temperature Range]   25   125   -40
[Voltage Range]   1.35   1.2825   1.4175
[POWER_clamp]
-1.35V    99.11mA    69.93mA    133.2mA
-1.227V   73.76mA    52.43mA    99.89mA
-1.105V   50.97mA    36.61mA    69.67mA
-1.023V   38.2mA     27.76mA    51.94mA
-940.9mV  28.45mA    21.07mA    37.98mA
-900mV    25.08mA    18.66mA    33.3mA
-818.2mV  20.65mA    15.34mA    27.58mA
-613.6mV  13.16mA    10.48mA    17.3mA
-490.9mV  9.727mA    8.571mA    12.43mA
-368.2mV  7.901mA    7.448mA    10mA
654.5mV   0A         0A         127.6uA
2.7V      0A         0A         0A
[GND_clamp]
-1.35V    -168.2mA   -102.2mA   -276.9mA
-1.145V   -92.83mA   -57.59mA   -150.1mA
-1.064V   -67.32mA   -43.17mA   -105.7mA
-1.023V   -56.57mA   -37.23mA   -86.84mA
-940.9mV  -39.74mA   -28.09mA   -56.46mA
-900mV    -33.43mA   -24.66mA   -45.08mA
-859.1mV  -28.28mA   -21.78mA   -36.36mA
-777.3mV  -21.38mA   -17.35mA   -27.7mA
-572.7mV  -13.9mA    -11.85mA   -18mA
-409.1mV  -10.66mA   -9.486mA   -13.28mA
736.4mV   0A         0A         -179.9uA
2.7V      0A         0A         0A
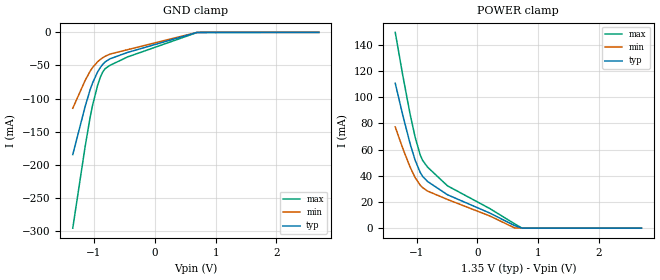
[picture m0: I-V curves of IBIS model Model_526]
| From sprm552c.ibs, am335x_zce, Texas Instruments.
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| Model based on original model for BCSHTLTCSCDVPBFZ_SSDHV
|   Sub model VREF_FULLTERM_12MA_5PER_1P35
[model]   Model_526
|[Description]  [1.35V-INPUT-FULLTERM:12MA-X, IND, 5%]
|   FULLTERM, 0.67 * RExt = 1.500 * Iout (I[2:0] = "111"), 12mA
|   nominal with Rext = 50R,Industrial temperature range (-40C to
|   125C, 25C nominal),5% power supply tolerance
|[Input Load]   FULLTERM:12MA
|[Output Drive]
|Voltage   1.35V
|Mode   INPUT
Model_type   Input
Polarity   Non-Inverting
Vinl =  0.585
Vinh =  0.765
C_comp   1.865048p   1.679967p   1.989968p
[Model Spec]
Vinl   0.585   0.551   0.618
Vinh   0.765   0.731   0.798
[Temperature Range]   25   125   -40
[Voltage Range]   1.35   1.2825   1.4175
[POWER_clamp]
-1.35V    110.7mA    77.35mA    149.6mA
-1.227V   86.44mA    61.02mA    116.9mA
-1.105V   64.39mA    46.54mA    86.93mA
-1.023V   51.96mA    38.67mA    69.54mA
-940.9mV  42.67mA    32.93mA    56.13mA
-900mV    39.56mA    30.95mA    51.76mA
-818.2mV  35.64mA    28.31mA    46.61mA
-490.9mV  25.51mA    21.91mA    32.33mA
204.5mV   11.54mA    9.327mA    14.98mA
613.6mV   1.937mA    166.6uA    3.287mA
736.4mV   0A         0A         0A
2.7V      0A         0A         0A
[GND_clamp]
-1.35V    -184.8mA   -114.7mA   -296mA
-1.145V   -111.6mA   -72.41mA   -171.8mA
-1.064V   -86.72mA   -58.71mA   -128.4mA
-1.023V   -76.24mA   -53.08mA   -109.8mA
-940.9mV  -59.79mA   -44.43mA   -79.9mA
-900mV    -53.62mA   -41.21mA   -68.72mA
-859.1mV  -48.58mA   -38.49mA   -60.23mA
-818.2mV  -44.64mA   -36.2mA    -54.88mA
-736.4mV  -39.95mA   -32.81mA   -49.82mA
-450mV    -30.38mA   -26.14mA   -37.2mA
695.5mV   0A         0A         -226uA
2.7V      0A         0A         0A
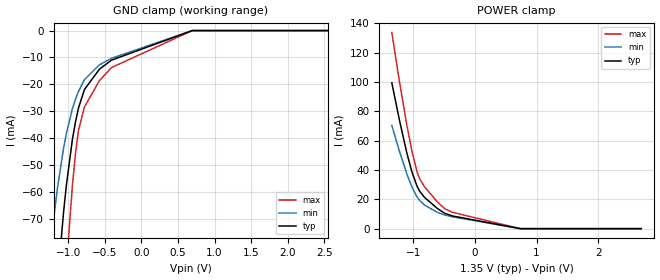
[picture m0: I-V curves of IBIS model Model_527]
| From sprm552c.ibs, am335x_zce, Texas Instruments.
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| Model based on original model for BCSHTLTCSCDVPBFZ_SSDHV
|   Sub model VREF_HALFTERM_9MA_5PER_1P35
[model]   Model_527
|[Description]  [1.35V-INPUT-HALFTERM:9MA-X, IND, 5%]
|   Half Thevenin termination (Rth = 100R whith RExt = 50R)
|   (ODT[1:0] = "11") VRef mode, 0.88 * RExt = 1.125 * Iout (I[2:0]
|   = "100"), 9mA nominal with Rext = 50R,Industrial temperature
|   range (-40C to 125C, 25C nominal),5% power supply tolerance
|[Input Load]   HALFTERM:9MA
|[Output Drive]
|Voltage   1.35V
|Mode   INPUT
Model_type   Input
Polarity   Non-Inverting
Vinl =  0.585
Vinh =  0.765
C_comp   1.865048p   1.679967p   1.989968p
[Model Spec]
Vinl   0.585   0.551   0.618
Vinh   0.765   0.731   0.798
[Temperature Range]   25   125   -40
[Voltage Range]   1.35   1.2825   1.4175
[POWER_clamp]
-1.35V    99.43mA    70.33mA    133.8mA
-1.227V   74.15mA    52.89mA    100.5mA
-1.105V   51.41mA    37.15mA    70.38mA
-1.023V   38.67mA    28.35mA    52.7mA
-940.9mV  28.97mA    21.71mA    38.81mA
-900mV    25.62mA    19.33mA    34.17mA
-818.2mV  21.25mA    16.04mA    28.52mA
-613.6mV  13.87mA    11.22mA    18.39mA
-490.9mV  10.49mA    9.298mA    13.58mA
-368.2mV  8.676mA    8.119mA    11.17mA
736.4mV   0A         0A         0A
2.7V      0A         0A         0A
[GND_clamp]
-1.35V    -168.8mA   -102.9mA   -277.6mA
-1.145V   -93.44mA   -58.39mA   -150.9mA
-1.064V   -67.93mA   -44.01mA   -106.5mA
-1.023V   -57.18mA   -38.09mA   -87.64mA
-940.9mV  -40.33mA   -28.97mA   -57.24mA
-900mV    -34.02mA   -25.55mA   -45.85mA
-859.1mV  -28.85mA   -22.68mA   -37.12mA
-777.3mV  -21.93mA   -18.26mA   -28.43mA
-572.7mV  -14.38mA   -12.76mA   -18.64mA
-409.1mV  -11.03mA   -10.33mA   -13.79mA
695.5mV   0A         0A         0A
2.7V      0A         0A         0A
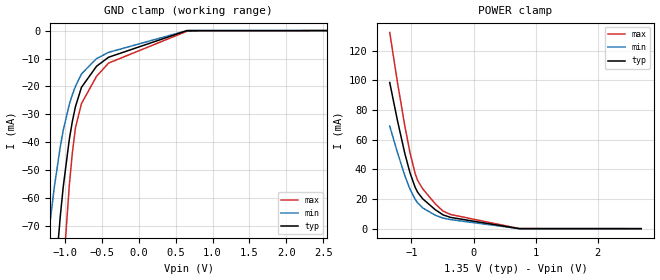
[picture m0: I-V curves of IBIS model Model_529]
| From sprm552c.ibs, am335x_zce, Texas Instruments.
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| Model based on original model for BCSHTLTCSCDVPBFZ_SSDHV
|   Sub model VREF_HALFTERM_7MA_5PER_1P35
[model]   Model_529
|[Description]  [1.35V-INPUT-HALFTERM:7MA-X, IND, 5%]
|   Half Thevenin termination (Rth = 100R whith RExt = 50R)
|   (ODT[1:0] = "11") VRef mode, 1.14 * RExt = 0.875 * Iout (I[2:0]
|   = "010"), 7mA nominal with Rext = 50R,Industrial temperature
|   range (-40C to 125C, 25C nominal),5% power supply tolerance
|[Input Load]   HALFTERM:7MA
|[Output Drive]
|Voltage   1.35V
|Mode   INPUT
Model_type   Input
Polarity   Non-Inverting
Vinl =  0.585
Vinh =  0.765
C_comp   1.865048p   1.679967p   1.989968p
[Model Spec]
Vinl   0.585   0.551   0.618
Vinh   0.765   0.731   0.798
[Temperature Range]   25   125   -40
[Voltage Range]   1.35   1.2825   1.4175
[POWER_clamp]
-1.35V    98.52mA    69.14mA    132.3mA
-1.227V   73.16mA    51.51mA    98.98mA
-1.105V   50.36mA    35.55mA    68.8mA
-1.023V   37.6mA     26.59mA    51.1mA
-940.9mV  27.87mA    19.79mA    37.17mA
-900mV    24.51mA    17.34mA    32.5mA
-818.2mV  20.1mA     13.94mA    26.81mA
-613.6mV  12.67mA    8.992mA    16.61mA
-490.9mV  9.299mA    7.117mA    11.82mA
-368.2mV  7.566mA    6.104mA    9.527mA
736.4mV   0A         0A         62.66uA
2.7V      0A         0A         0A
[GND_clamp]
-1.35V    -167.5mA   -100.9mA   -275.9mA
-1.145V   -91.98mA   -56mA      -148.8mA
-1.064V   -66.41mA   -41.5mA    -104.4mA
-1.023V   -55.64mA   -35.53mA   -85.5mA
-940.9mV  -38.76mA   -26.33mA   -55.05mA
-900mV    -32.43mA   -22.88mA   -43.64mA
-859.1mV  -27.26mA   -19.99mA   -34.88mA
-777.3mV  -20.32mA   -15.53mA   -26.15mA
-572.7mV  -12.77mA   -10.03mA   -16.36mA
-409.1mV  -9.54mA    -7.799mA   -11.63mA
654.5mV   0A         0A         -222.1uA
2.7V      0A         0A         0A
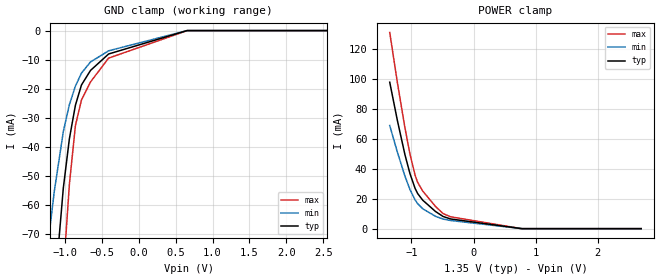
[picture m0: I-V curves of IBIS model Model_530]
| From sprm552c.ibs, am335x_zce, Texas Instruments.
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| Model based on original model for BCSHTLTCSCDVPBFZ_SSDHV
|   Sub model VREF_HALFTERM_6MA_5PER_1P35
[model]   Model_530
|[Description]  [1.35V-INPUT-HALFTERM:6MA-X, IND, 5%]
|   Half Thevenin termination (Rth = 100R whith RExt = 50R)
|   (ODT[1:0] = "11") VRef mode, 1.33 * RExt = 0.750 * Iout (I[2:0]
|   = "001"), 6mA nominal with Rext = 50R,Industrial temperature
|   range (-40C to 125C, 25C nominal),5% power supply tolerance
|[Input Load]   HALFTERM:6MA
|[Output Drive]
|Voltage   1.35V
|Mode   INPUT
Model_type   Input
Polarity   Non-Inverting
Vinl =  0.585
Vinh =  0.765
C_comp   1.865048p   1.679967p   1.989968p
[Model Spec]
Vinl   0.585   0.551   0.618
Vinh   0.765   0.731   0.798
[Temperature Range]   25   125   -40
[Voltage Range]   1.35   1.2825   1.4175
[POWER_clamp]
-1.35V    97.62mA    68.74mA    130.8mA
-1.227V   72.17mA    51.05mA    97.42mA
-1.105V   49.32mA    35.01mA    67.22mA
-1.023V   36.54mA    26mA       49.49mA
-940.9mV  26.78mA    19.15mA    35.52mA
-900mV    23.39mA    16.67mA    30.83mA
-818.2mV  18.96mA    13.24mA    25.09mA
-613.6mV  11.47mA    8.248mA    14.83mA
-490.9mV  8.11mA     6.389mA    10.06mA
-368.2mV  6.456mA    5.433mA    7.883mA
777.3mV   0A         0A         0A
2.7V      0A         0A         0A
[GND_clamp]
-1.35V    -166.2mA   -100.2mA   -274.1mA
-1.309V   -150.3mA   -90.61mA   -247.8mA
-1.268V   -134.7mA   -81.24mA   -221.8mA
-1.145V   -90.52mA   -55.2mA    -146.8mA
-1.023V   -54.11mA   -34.68mA   -83.36mA
-940.9mV  -37.19mA   -25.45mA   -52.87mA
-859.1mV  -25.66mA   -19.09mA   -32.65mA
-777.3mV  -18.71mA   -14.62mA   -23.88mA
-654.5mV  -13.7mA    -10.79mA   -17.66mA
-409.1mV  -8.047mA   -6.956mA   -9.465mA
654.5mV   0A         0A         -32.45uA
2.7V      0A         0A         0A
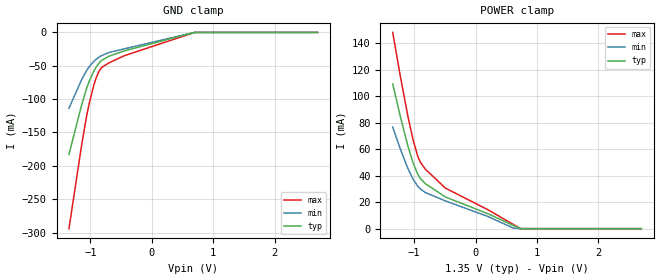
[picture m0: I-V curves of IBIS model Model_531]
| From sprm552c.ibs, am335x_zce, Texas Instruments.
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| Model based on original model for BCSHTLTCSCDVPBFZ_SSDHV
|   Sub model VREF_FULLTERM_11MA_5PER_1P35
[model]   Model_531
|[Description]  [1.35V-INPUT-FULLTERM:11MA-X, IND, 5%]
|   FULLTERM, 0.73 * RExt = 1.325 * Iout (I[2:0] = "110"), 11mA
|   nominal with Rext = 50R,Industrial temperature range (-40C to
|   125C, 25C nominal),5% power supply tolerance
|[Input Load]   FULLTERM:11MA
|[Output Drive]
|Voltage   1.35V
|Mode   INPUT
Model_type   Input
Polarity   Non-Inverting
Vinl =  0.585
Vinh =  0.765
C_comp   1.865048p   1.679967p   1.989968p
[Model Spec]
Vinl   0.585   0.551   0.618
Vinh   0.765   0.731   0.798
[Temperature Range]   25   125   -40
[Voltage Range]   1.35   1.2825   1.4175
[POWER_clamp]
-1.35V    109.2mA    76.67mA    148.1mA
-1.227V   84.84mA    60.25mA    115.3mA
-1.105V   62.74mA    45.68mA    85.35mA
-1.023V   50.3mA     37.75mA    67.93mA
-940.9mV  40.99mA    31.96mA    54.48mA
-900mV    37.88mA    29.95mA    50.09mA
-818.2mV  33.94mA    27.27mA    44.89mA
-490.9mV  23.9mA     20.93mA    30.57mA
204.5mV   11.2mA     9.111mA    14.18mA
613.6mV   2.419mA    456.9uA    3.188mA
736.4mV   0A         0A         0A
2.7V      0A         0A         0A
[GND_clamp]
-1.35V    -182.9mA   -113.7mA   -294.2mA
-1.145V   -109.3mA   -71.18mA   -169.8mA
-1.064V   -84.3mA    -57.4mA    -126.3mA
-1.023V   -73.77mA   -51.73mA   -107.7mA
-940.9mV  -57.24mA   -43.03mA   -77.71mA
-900mV    -51.04mA   -39.78mA   -66.51mA
-859.1mV  -45.96mA   -37.05mA   -58mA
-818.2mV  -41.99mA   -34.73mA   -52.62mA
-695.5mV  -35.65mA   -30.12mA   -45.53mA
-450mV    -27.72mA   -24.66mA   -35mA
695.5mV   0A         0A         -116.7uA
2.7V      0A         0A         0A
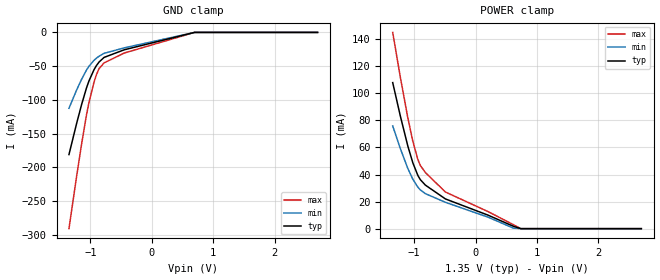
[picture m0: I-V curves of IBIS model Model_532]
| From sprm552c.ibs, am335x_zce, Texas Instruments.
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| Model based on original model for BCSHTLTCSCDVPBFZ_SSDHV
|   Sub model VREF_FULLTERM_10MA_5PER_1P35
[model]   Model_532
|[Description]  [1.35V-INPUT-FULLTERM:10MA-X, IND, 5%]
|   FULLTERM, 0.80 * RExt = 1.250 * Iout (I[2:0] = "101"), 10mA
|   nominal with Rext = 50R,Industrial temperature range (-40C to
|   125C, 25C nominal),5% power supply tolerance
|[Input Load]   FULLTERM:10MA
|[Output Drive]
|Voltage   1.35V
|Mode   INPUT
Model_type   Input
Polarity   Non-Inverting
Vinl =  0.585
Vinh =  0.765
C_comp   1.865048p   1.679967p   1.989968p
[Model Spec]
Vinl   0.585   0.551   0.618
Vinh   0.765   0.731   0.798
[Temperature Range]   25   125   -40
[Voltage Range]   1.35   1.2825   1.4175
[POWER_clamp]
-1.35V    107.9mA    75.88mA    145mA
-1.227V   83.46mA    59.33mA    112.2mA
-1.105V   61.25mA    44.61mA    82.18mA
-1.023V   48.76mA    36.58mA    64.72mA
-940.9mV  39.37mA    30.67mA    51.18mA
-900mV    36.21mA    28.62mA    46.74mA
-818.2mV  32.19mA    25.87mA    41.46mA
-490.9mV  21.95mA    19.47mA    27.05mA
204.5mV   9.951mA    8.461mA    12.58mA
613.6mV   1.811mA    424.3uA    2.991mA
736.4mV   0A         0A         0A
2.7V      0A         0A         0A
[GND_clamp]
-1.35V    -181mA     -112.4mA   -290.7mA
-1.227V   -135.5mA   -85.72mA   -214.2mA
-1.145V   -107.2mA   -69.58mA   -165.8mA
-1.064V   -82.17mA   -55.73mA   -122.1mA
-1.023V   -71.63mA   -50.03mA   -103.4mA
-940.9mV  -55.08mA   -41.27mA   -73.33mA
-900mV    -48.86mA   -38mA      -62.09mA
-859.1mV  -43.79mA   -35.25mA   -53.52mA
-777.3mV  -37.02mA   -31mA      -45.12mA
-450mV    -25.79mA   -22.93mA   -30.59mA
695.5mV   0A         0A         0A
2.7V      0A         0A         0A
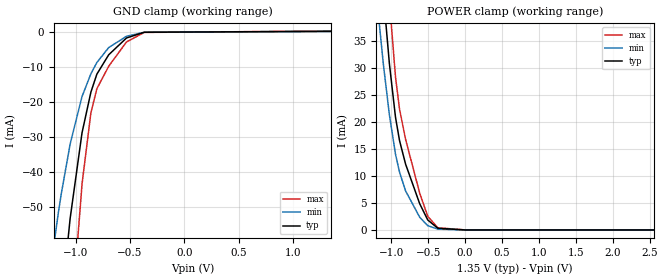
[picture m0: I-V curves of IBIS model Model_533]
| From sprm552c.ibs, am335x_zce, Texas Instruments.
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| Model based on original model for BCSHTLTCSCDVPBFZ_SSDHV
|   Sub model VREF_NOTERM_PD_ON_5PER_1P35
[model]   Model_533
|[Description]  [1.35V-INPUT-PD-X, IND, 5%]
|   Weak internal pull-down,Industrial temperature range (-40C to
|   125C, 25C nominal),5% power supply tolerance
|[Input Load]   PD
|[Output Drive]
|Voltage   1.35V
|Mode   INPUT
Model_type   Input
Polarity   Non-Inverting
Vinl =  0.585
Vinh =  0.765
C_comp   1.865048p   1.679967p   1.989968p
[Model Spec]
Vinl   0.585   0.551   0.618
Vinh   0.765   0.731   0.798
[Temperature Range]   25   125   -40
[Voltage Range]   1.35   1.2825   1.4175
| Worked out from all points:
|   GND clamp passes 1 mA (typ) near -0.49 V on its own axis
|   POWER clamp passes 1 mA (typ) near -0.46 V on its own axis
[POWER_clamp]
-1.35V    92.77mA    65.59mA    124.1mA
-1.241V   69.66mA    49.37mA    94.15mA
-1.105V   43.7mA     30.77mA    60.31mA
-1.023V   30.81mA    21.33mA    42.53mA
-940.9mV  20.93mA    14.07mA    28.39mA
-886.4mV  16.59mA    10.73mA    22.44mA
-804.5mV  12.22mA    7.255mA    16.82mA
-613.6mV  4.868mA    2.361mA    6.817mA
-504.5mV  1.851mA    794.3uA    2.53mA
-368.2mV  308.5uA    151.6uA    406.1uA
13.64mV   0A         0A         0A
2.7V      0A         0A         0A
[GND_clamp]
-1.35V    -159.2mA   -94.81mA   -266.4mA
-1.295V   -137.9mA   -81.82mA   -231.1mA
-1.159V   -87.42mA   -51.63mA   -146.2mA
-1.132V   -78.13mA   -46.22mA   -130.2mA
-1.05V    -53.12mA   -31.95mA   -86.79mA
-940.9mV  -28.77mA   -18.44mA   -43.4mA
-859.1mV  -17.15mA   -11.93mA   -23.01mA
-804.5mV  -12.06mA   -8.734mA   -16.2mA
-695.5mV  -6.535mA   -4.481mA   -9.796mA
-531.8mV  -1.749mA   -1.265mA   -2.882mA
-368.2mV  -120.9uA   -112.7uA   -165uA
1.35V     149.5uA    81.79uA    219.2uA
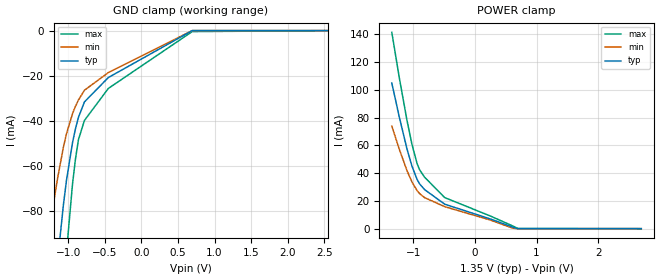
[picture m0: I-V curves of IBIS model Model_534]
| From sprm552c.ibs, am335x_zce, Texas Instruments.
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| Model based on original model for BCSHTLTCSCDVPBFZ_SSDHV
|   Sub model VREF_FULLTERM_8MA_5PER_1P35
[model]   Model_534
|[Description]  [1.35V-INPUT-FULLTERM:8MA-X, IND, 5%]
|   FULLTERM, 1.00 * RExt = 1.000 * Iout (I[2:0] = "011"), 8mA
|   nominal with Rext = 50R,Industrial temperature range (-40C to
|   125C, 25C nominal),5% power supply tolerance
|[Input Load]   FULLTERM:8MA
|[Output Drive]
|Voltage   1.35V
|Mode   INPUT
Model_type   Input
Polarity   Non-Inverting
Vinl =  0.585
Vinh =  0.765
C_comp   1.865048p   1.679967p   1.989968p
[Model Spec]
Vinl   0.585   0.551   0.618
Vinh   0.765   0.731   0.798
[Temperature Range]   25   125   -40
[Voltage Range]   1.35   1.2825   1.4175
[POWER_clamp]
-1.35V    104.9mA    73.9mA     141.4mA
-1.227V   80.1mA     57.03mA    108.4mA
-1.105V   57.68mA    41.95mA    78.3mA
-1.023V   45.08mA    33.64mA    60.74mA
-940.9mV  35.56mA    27.47mA    47.05mA
-900mV    32.32mA    25.3mA     42.53mA
-818.2mV  28.14mA    22.36mA    37.09mA
-490.9mV  17.62mA    15.84mA    22.38mA
245.5mV   7.061mA    6.263mA    9.192mA
613.6mV   1.118mA    342.9uA    1.943mA
695.5mV   0A         0A         150.5uA
2.7V      0A         0A         0A
[GND_clamp]
-1.35V    -176.5mA   -109mA     -286.4mA
-1.227V   -130.7mA   -81.95mA   -209.6mA
-1.145V   -102.2mA   -65.58mA   -160.9mA
-1.064V   -77.01mA   -51.54mA   -117.1mA
-1.023V   -66.4mA    -45.76mA   -98.34mA
-940.9mV  -49.76mA   -36.88mA   -68.18mA
-900mV    -43.52mA   -33.55mA   -56.9mA
-859.1mV  -38.43mA   -30.76mA   -48.3mA
-777.3mV  -31.62mA   -26.45mA   -39.83mA
-450mV    -20.8mA    -18.6mA    -25.63mA
695.5mV   0A         0A         -441.2uA
2.7V      0A         0A         0A
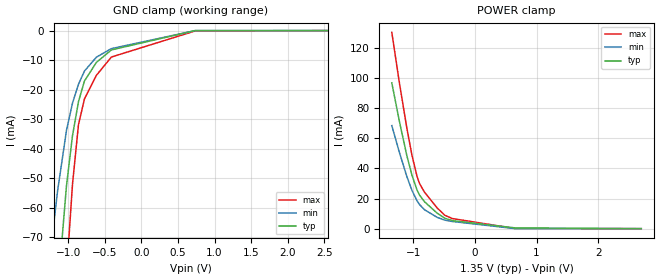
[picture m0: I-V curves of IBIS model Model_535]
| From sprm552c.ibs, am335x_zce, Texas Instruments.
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| Model based on original model for BCSHTLTCSCDVPBFZ_SSDHV
|   Sub model VREF_HALFTERM_5MA_5PER_1P35
[model]   Model_535
|[Description]  [1.35V-INPUT-HALFTERM:5MA-X, IND, 5%]
|   Half Thevenin termination (Rth = 100R whith RExt = 50R)
|   (ODT[1:0] = "11") VRef mode, 1.60 * RExt = 0.625 * Iout (I[2:0]
|   = "000"), 5mA nominal with Rext = 50R,Industrial temperature
|   range (-40C to 125C, 25C nominal),5% power supply tolerance
|[Input Load]   HALFTERM:5MA
|[Output Drive]
|Voltage   1.35V
|Mode   INPUT
Model_type   Input
Polarity   Non-Inverting
Vinl =  0.585
Vinh =  0.765
C_comp   1.865048p   1.679967p   1.989968p
[Model Spec]
Vinl   0.585   0.551   0.618
Vinh   0.765   0.731   0.798
[Temperature Range]   25   125   -40
[Voltage Range]   1.35   1.2825   1.4175
[POWER_clamp]
-1.35V    96.71mA    68.35mA    130.2mA
-1.227V   71.18mA    50.59mA    96.75mA
-1.105V   48.27mA    34.48mA    66.51mA
-1.023V   35.47mA    25.41mA    48.72mA
-940.9mV  25.68mA    18.51mA    34.69mA
-900mV    22.28mA    16.01mA    29.96mA
-818.2mV  17.81mA    12.54mA    24.16mA
-613.6mV  10.27mA    7.504mA    13.74mA
-490.9mV  6.92mA     5.662mA    8.911mA
-368.2mV  5.346mA    4.761mA    6.714mA
654.5mV   492.1uA    0A         85.11uA
2.7V      0A         0A         0A
[GND_clamp]
-1.35V    -164.9mA   -99.53mA   -273.4mA
-1.309V   -149mA     -89.91mA   -247.1mA
-1.268V   -133.4mA   -80.52mA   -221mA
-1.145V   -89.06mA   -54.4mA    -146mA
-1.023V   -52.57mA   -33.82mA   -82.56mA
-940.9mV  -35.62mA   -24.57mA   -52.09mA
-859.1mV  -24.07mA   -18.19mA   -31.89mA
-777.3mV  -17.09mA   -13.71mA   -23.14mA
-613.6mV  -10.76mA   -8.998mA   -15.14mA
-409.1mV  -6.554mA   -6.112mA   -8.958mA
736.4mV   0A         0A         -120uA
2.7V      0A         0A         0A
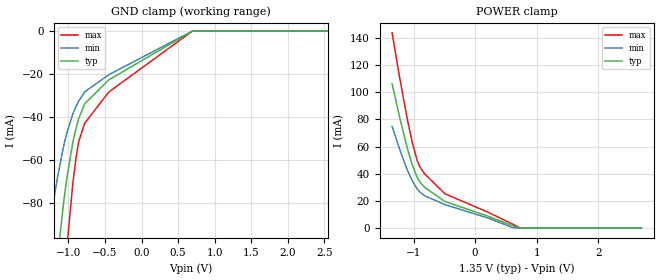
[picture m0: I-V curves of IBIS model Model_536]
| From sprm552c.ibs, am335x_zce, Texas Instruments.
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| Model based on original model for BCSHTLTCSCDVPBFZ_SSDHV
|   Sub model VREF_FULLTERM_9MA_5PER_1P35
[model]   Model_536
|[Description]  [1.35V-INPUT-FULLTERM:9MA-X, IND, 5%]
|   FULLTERM, 0.88 * RExt = 1.125 * Iout (I[2:0] = "100"), 9mA
|   nominal with Rext = 50R,Industrial temperature range (-40C to
|   125C, 25C nominal),5% power supply tolerance
|[Input Load]   FULLTERM:9MA
|[Output Drive]
|Voltage   1.35V
|Mode   INPUT
Model_type   Input
Polarity   Non-Inverting
Vinl =  0.585
Vinh =  0.765
C_comp   1.865048p   1.679967p   1.989968p
[Model Spec]
Vinl   0.585   0.551   0.618
Vinh   0.765   0.731   0.798
[Temperature Range]   25   125   -40
[Voltage Range]   1.35   1.2825   1.4175
[POWER_clamp]
-1.35V    106.1mA    74.69mA    143.5mA
-1.227V   81.48mA    57.95mA    110.6mA
-1.105V   59.16mA    43.01mA    80.6mA
-1.023V   46.62mA    34.81mA    63.11mA
-940.9mV  37.18mA    28.75mA    49.53mA
-900mV    33.98mA    26.63mA    45.07mA
-818.2mV  29.89mA    23.76mA    39.75mA
-490.9mV  19.57mA    17.29mA    25.29mA
204.5mV   8.888mA    7.487mA    11.78mA
613.6mV   1.726mA    375.5uA    2.892mA
736.4mV   0A         0A         0A
2.7V      0A         0A         0A
[GND_clamp]
-1.35V    -178.4mA   -110.3mA   -288.9mA
-1.227V   -132.7mA   -83.46mA   -212.3mA
-1.145V   -104.3mA   -67.18mA   -163.7mA
-1.064V   -79.14mA   -53.21mA   -120mA
-1.023V   -68.55mA   -47.47mA   -101.3mA
-940.9mV  -51.93mA   -38.64mA   -71.14mA
-900mV    -45.69mA   -35.33mA   -59.88mA
-859.1mV  -40.6mA    -32.56mA   -51.29mA
-777.3mV  -33.79mA   -28.27mA   -42.84mA
-450mV    -22.73mA   -20.33mA   -28.38mA
695.5mV   0A         0A         0A
2.7V      0A         0A         0A
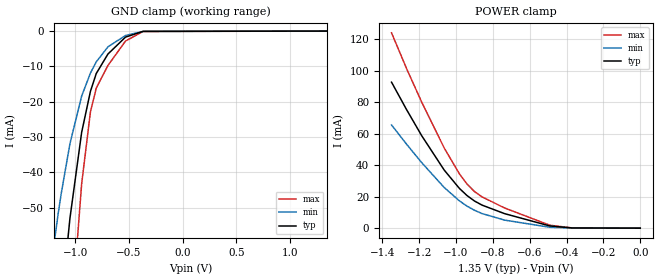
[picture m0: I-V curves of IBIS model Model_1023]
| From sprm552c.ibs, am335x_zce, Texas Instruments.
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| Model based on original model for BCSHTLTCSCDDVPBFZ_SSDHV
|   Sub model DIFF_VREF_NOTERM_PUPD_OFF_5PER_1P35
[model]   Model_1023
|[Description]  [1.35V-INPUT-PI-X, IND, 5%]
|   Weak pull up/down disabled,Industrial temperature range (-40C to
|   125C, 25C nominal),5% power supply tolerance
|[Input Load]   PI
|[Output Drive]
|Voltage   1.35V
|Mode   INPUT
Model_type   Input
Polarity   Non-Inverting
Vinl =  0.585
Vinh =  0.765
C_comp   1.865048p   1.679967p   1.989968p
[Model Spec]
Vinl   0.585   0.551   0.618
Vinh   0.765   0.731   0.798
[Temperature Range]   25   125   -40
[Voltage Range]   1.35   1.2825   1.4175
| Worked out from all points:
|   GND clamp passes 1 mA (typ) near -0.49 V on its own axis
|   POWER clamp passes 1 mA (typ) near -0.47 V on its own axis
[POWER_clamp]
-1.35V    92.76mA    65.58mA    124.1mA
-1.268V   75.25mA    53.31mA    101.3mA
-1.186V   58.7mA     41.6mA     80.03mA
-1.064V   36.89mA    25.81mA    50.92mA
-981.8mV  25.29mA    17.36mA    34.56mA
-940.9mV  20.77mA    14.04mA    28.1mA
-900mV    17.27mA    11.37mA    23.28mA
-859.1mV  14.66mA    9.282mA    19.9mA
-736.4mV  9.228mA    5.113mA    12.83mA
-490.9mV  1.4mA      568.7uA    1.868mA
-368.2mV  129.3uA    55.73uA    131.1uA
0V        1.193nA    12.97nA    998.7pA
[GND_clamp]
-1.35V    -159.2mA   -94.8mA    -266.4mA
-1.295V   -137.8mA   -81.81mA   -231.1mA
-1.159V   -87.4mA    -51.62mA   -146.2mA
-1.132V   -78.11mA   -46.21mA   -130.2mA
-1.05V    -53.09mA   -31.94mA   -86.76mA
-940.9mV  -28.74mA   -18.43mA   -43.34mA
-859.1mV  -17.11mA   -11.91mA   -22.96mA
-804.5mV  -12.02mA   -8.717mA   -16.14mA
-695.5mV  -6.497mA   -4.463mA   -9.74mA
-531.8mV  -1.706mA   -1.244mA   -2.822mA
-368.2mV  -80.01uA   -91.15uA   -104.9uA
1.35V     1.193nA    34.16nA    722.6pA
